                            <description>Compare Window A Internal Reference Voltage Comparison Condition Select</description>
                            <lsb>1</lsb>
                            <msb>1</msb>
                            <access>read-write</access>
                            <enumeratedValues>
                                <enumeratedValue>
                                    <name>0</name>
                                    <description>When window function is disabled (ADCMPCR.WCMPE = 0) : ADCMPDR0 value &gt; A/D-converted value When window function is enabled (ADCMPCR.WCMPE = 1): A/D-converted value &lt; ADCMPDR0 value, or A/D-converted value &gt; ADCMPDR1 value </description>
                                    <value>#0</value>
                                </enumeratedValue>
                                <enumeratedValue>
                                    <name>1</name>
                                    <description>When window function is disabled (ADCMPCR.WCMPE = 0): ADCMPDR0 value &lt; A/D-converted value When window function is enabled (ADCMPCR.WCMPE = 1): ADCMPDR0 value &lt; A/D-converted value &lt; ADCMPDR1 value </description>
                                    <value>#1</value>
                                </enumeratedValue>
                            </enumeratedValues>
                        </field>
                    </fields>
                </register>
                <register>
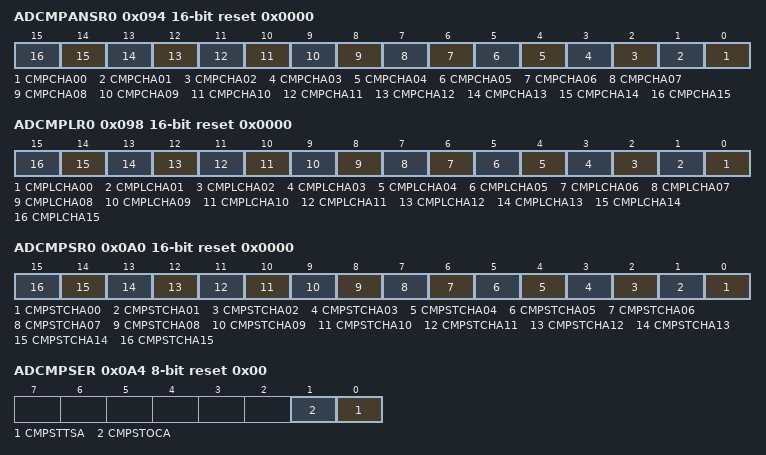
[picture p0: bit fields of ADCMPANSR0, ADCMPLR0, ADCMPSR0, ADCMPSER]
                    <name>ADCMPANSR0</name>
                    <description>A/D Compare Function Window A Channel Select Register 0</description>
                    <addressOffset>0x094</addressOffset>
                    <size>16</size>
                    <access>read-write</access>
                    <resetValue>0x0000</resetValue>
                    <resetMask>0xffff</resetMask>
                    <fields>
                        <field>
                            <name>CMPCHA00</name>
                            <description>Compare Window A Channel Select</description>
                            <lsb>0</lsb>
                            <msb>0</msb>
                            <access>read-write</access>
                            <enumeratedValues>
                                <enumeratedValue>
                                    <name>0</name>
                                    <description>Disable compare function for associated input channel</description>
                                    <value>#0</value>
                                </enumeratedValue>
                                <enumeratedValue>
                                    <name>1</name>
                                    <description>Enable compare function for associated input channel</description>
                                    <value>#1</value>
                                </enumeratedValue>
                            </enumeratedValues>
                        </field>
                        <field>
                            <name>CMPCHA01</name>
                            <description>Compare Window A Channel Select</description>
                            <lsb>1</lsb>
                            <msb>1</msb>
                            <access>read-write</access>
                            <enumeratedValues>
                                <enumeratedValue>
                                    <name>0</name>
                                    <description>Disable compare function for associated input channel</description>
                                    <value>#0</value>
                                </enumeratedValue>
                                <enumeratedValue>
                                    <name>1</name>
                                    <description>Enable compare function for associated input channel</description>
                                    <value>#1</value>
                                </enumeratedValue>
                            </enumeratedValues>
                        </field>
                        <field>
                            <name>CMPCHA02</name>
                            <description>Compare Window A Channel Select</description>
                            <lsb>2</lsb>
                            <msb>2</msb>
                            <access>read-write</access>
                            <enumeratedValues>
                                <enumeratedValue>
                                    <name>0</name>
                                    <description>Disable compare function for associated input channel</description>
                                    <value>#0</value>
                                </enumeratedValue>
                                <enumeratedValue>
                                    <name>1</name>
                                    <description>Enable compare function for associated input channel</description>
                                    <value>#1</value>
                                </enumeratedValue>
                            </enumeratedValues>
                        </field>
                        <field>
                            <name>CMPCHA03</name>
                            <description>Compare Window A Channel Select</description>
                            <lsb>3</lsb>
                            <msb>3</msb>
                            <access>read-write</access>
                            <enumeratedValues>
                                <enumeratedValue>
                                    <name>0</name>
                                    <description>Disable compare function for associated input channel</description>
                                    <value>#0</value>
                                </enumeratedValue>
                                <enumeratedValue>
                                    <name>1</name>
                                    <description>Enable compare function for associated input channel</description>
                                    <value>#1</value>
                                </enumeratedValue>
                            </enumeratedValues>
                        </field>
                        <field>
                            <name>CMPCHA04</name>
                            <description>Compare Window A Channel Select</description>
                            <lsb>4</lsb>
                            <msb>4</msb>
                            <access>read-write</access>
                            <enumeratedValues>
                                <enumeratedValue>
                                    <name>0</name>
                                    <description>Disable compare function for associated input channel</description>
                                    <value>#0</value>
                                </enumeratedValue>
                                <enumeratedValue>
                                    <name>1</name>
                                    <description>Enable compare function for associated input channel</description>
                                    <value>#1</value>
                                </enumeratedValue>
                            </enumeratedValues>
                        </field>
                        <field>
                            <name>CMPCHA05</name>
                            <description>Compare Window A Channel Select</description>
                            <lsb>5</lsb>
                            <msb>5</msb>
                            <access>read-write</access>
                            <enumeratedValues>
                                <enumeratedValue>
                                    <name>0</name>
                                    <description>Disable compare function for associated input channel</description>
                                    <value>#0</value>
                                </enumeratedValue>
                                <enumeratedValue>
                                    <name>1</name>
                                    <description>Enable compare function for associated input channel</description>
                                    <value>#1</value>
                                </enumeratedValue>
                            </enumeratedValues>
                        </field>
                        <field>
                            <name>CMPCHA06</name>
                            <description>Compare Window A Channel Select</description>
                            <lsb>6</lsb>
                            <msb>6</msb>
                            <access>read-write</access>
                            <enumeratedValues>
                                <enumeratedValue>
                                    <name>0</name>
                                    <description>Disable compare function for associated input channel</description>
                                    <value>#0</value>
                                </enumeratedValue>
                                <enumeratedValue>
                                    <name>1</name>
                                    <description>Enable compare function for associated input channel</description>
                                    <value>#1</value>
                                </enumeratedValue>
                            </enumeratedValues>
                        </field>
                        <field>
                            <name>CMPCHA07</name>
                            <description>Compare Window A Channel Select</description>
                            <lsb>7</lsb>
                            <msb>7</msb>
                            <access>read-write</access>
                            <enumeratedValues>
                                <enumeratedValue>
                                    <name>0</name>
                                    <description>Disable compare function for associated input channel</description>
                                    <value>#0</value>
                                </enumeratedValue>
                                <enumeratedValue>
                                    <name>1</name>
                                    <description>Enable compare function for associated input channel</description>
                                    <value>#1</value>
                                </enumeratedValue>
                            </enumeratedValues>
                        </field>
                        <field>
                            <name>CMPCHA08</name>
                            <description>Compare Window A Channel Select</description>
                            <lsb>8</lsb>
                            <msb>8</msb>
                            <access>read-write</access>
                            <enumeratedValues>
                                <enumeratedValue>
                                    <name>0</name>
                                    <description>Disable compare function for associated input channel</description>
                                    <value>#0</value>
                                </enumeratedValue>
                                <enumeratedValue>
                                    <name>1</name>
                                    <description>Enable compare function for associated input channel</description>
                                    <value>#1</value>
                                </enumeratedValue>
                            </enumeratedValues>
                        </field>
                        <field>
                            <name>CMPCHA09</name>
                            <description>Compare Window A Channel Select</description>
                            <lsb>9</lsb>
                            <msb>9</msb>
                            <access>read-write</access>
                            <enumeratedValues>
                                <enumeratedValue>
                                    <name>0</name>
                                    <description>Disable compare function for associated input channel</description>
                                    <value>#0</value>
                                </enumeratedValue>
                                <enumeratedValue>
                                    <name>1</name>
                                    <description>Enable compare function for associated input channel</description>
                                    <value>#1</value>
                                </enumeratedValue>
                            </enumeratedValues>
                        </field>
                        <field>
                            <name>CMPCHA10</name>
                            <description>Compare Window A Channel Select</description>
                            <lsb>10</lsb>
                            <msb>10</msb>
                            <access>read-write</access>
                            <enumeratedValues>
                                <enumeratedValue>
                                    <name>0</name>
                                    <description>Disable compare function for associated input channel</description>
                                    <value>#0</value>
                                </enumeratedValue>
                                <enumeratedValue>
                                    <name>1</name>
                                    <description>Enable compare function for associated input channel</description>
                                    <value>#1</value>
                                </enumeratedValue>
                            </enumeratedValues>
                        </field>
                        <field>
                            <name>CMPCHA11</name>
                            <description>Compare Window A Channel Select</description>
                            <lsb>11</lsb>
                            <msb>11</msb>
                            <access>read-write</access>
                            <enumeratedValues>
                                <enumeratedValue>
                                    <name>0</name>
                                    <description>Disable compare function for associated input channel</description>
                                    <value>#0</value>
                                </enumeratedValue>
                                <enumeratedValue>
                                    <name>1</name>
                                    <description>Enable compare function for associated input channel</description>
                                    <value>#1</value>
                                </enumeratedValue>
                            </enumeratedValues>
                        </field>
                        <field>
                            <name>CMPCHA12</name>
                            <description>Compare Window A Channel Select</description>
                            <lsb>12</lsb>
                            <msb>12</msb>
                            <access>read-write</access>
                            <enumeratedValues>
                                <enumeratedValue>
                                    <name>0</name>
                                    <description>Disable compare function for associated input channel</description>
                                    <value>#0</value>
                                </enumeratedValue>
                                <enumeratedValue>
                                    <name>1</name>
                                    <description>Enable compare function for associated input channel</description>
                                    <value>#1</value>
                                </enumeratedValue>
                            </enumeratedValues>
                        </field>
                        <field>
                            <name>CMPCHA13</name>
                            <description>Compare Window A Channel Select</description>
                            <lsb>13</lsb>
                            <msb>13</msb>
                            <access>read-write</access>
                            <enumeratedValues>
                                <enumeratedValue>
                                    <name>0</name>
                                    <description>Disable compare function for associated input channel</description>
                                    <value>#0</value>
                                </enumeratedValue>
                                <enumeratedValue>
                                    <name>1</name>
                                    <description>Enable compare function for associated input channel</description>
                                    <value>#1</value>
                                </enumeratedValue>
                            </enumeratedValues>
                        </field>
                        <field>
                            <name>CMPCHA14</name>
                            <description>Compare Window A Channel Select</description>
                            <lsb>14</lsb>
                            <msb>14</msb>
                            <access>read-write</access>
                            <enumeratedValues>
                                <enumeratedValue>
                                    <name>0</name>
                                    <description>Disable compare function for associated input channel</description>
                                    <value>#0</value>
                                </enumeratedValue>
                                <enumeratedValue>
                                    <name>1</name>
                                    <description>Enable compare function for associated input channel</description>
                                    <value>#1</value>
                                </enumeratedValue>
                            </enumeratedValues>
                        </field>
                        <field>
                            <name>CMPCHA15</name>
                            <description>Compare Window A Channel Select</description>
                            <lsb>15</lsb>
                            <msb>15</msb>
                            <access>read-write</access>
                            <enumeratedValues>
                                <enumeratedValue>
                                    <name>0</name>
                                    <description>Disable compare function for associated input channel</description>
                                    <value>#0</value>
                                </enumeratedValue>
                                <enumeratedValue>
                                    <name>1</name>
                                    <description>Enable compare function for associated input channel</description>
                                    <value>#1</value>
                                </enumeratedValue>
                            </enumeratedValues>
                        </field>
                    </fields>
                </register>
                <register>
                    <name>ADCMPLR0</name>
                    <description>A/D Compare Function Window A Comparison Condition Setting Register 0</description>
                    <addressOffset>0x098</addressOffset>
                    <size>16</size>
                    <access>read-write</access>
                    <resetValue>0x0000</resetValue>
                    <resetMask>0xffff</resetMask>
                    <fields>
                        <field>
                            <name>CMPLCHA00</name>
                            <description>Compare Window A Comparison Condition Select</description>
                            <lsb>0</lsb>
                            <msb>0</msb>
                            <access>read-write</access>
                            <enumeratedValues>
                                <enumeratedValue>
                                    <name>0</name>
                                    <description>When window function is disabled (ADCMPCR.WCMPE = 0): ADCMPDR0 value &gt; A/D-converted value When window function is enabled (ADCMPCR.WCMPE = 1): A/D-converted value &lt; ADCMPDR0 value, or ADCMPDR1 value &lt; A/D-converted value </description>
                                    <value>#0</value>
                                </enumeratedValue>
                                <enumeratedValue>
                                    <name>1</name>
                                    <description>When window function is disabled (ADCMPCR.WCMPE = 0): ADCMPDR0 value &lt; A/D-converted value When window function is enabled (ADCMPCR.WCMPE = 1): ADCMPDR0 value &lt; A/D-converted value &lt; ADCMPDR1 value </description>
                                    <value>#1</value>
                                </enumeratedValue>
                            </enumeratedValues>
                        </field>
                        <field>
                            <name>CMPLCHA01</name>
                            <description>Compare Window A Comparison Condition Select</description>
                            <lsb>1</lsb>
                            <msb>1</msb>
                            <access>read-write</access>
                            <enumeratedValues>
                                <enumeratedValue>
                                    <name>0</name>
                                    <description>When window function is disabled (ADCMPCR.WCMPE = 0): ADCMPDR0 value &gt; A/D-converted value When window function is enabled (ADCMPCR.WCMPE = 1): A/D-converted value &lt; ADCMPDR0 value, or ADCMPDR1 value &lt; A/D-converted value </description>
                                    <value>#0</value>
                                </enumeratedValue>
                                <enumeratedValue>
                                    <name>1</name>
                                    <description>When window function is disabled (ADCMPCR.WCMPE = 0): ADCMPDR0 value &lt; A/D-converted value When window function is enabled (ADCMPCR.WCMPE = 1): ADCMPDR0 value &lt; A/D-converted value &lt; ADCMPDR1 value </description>
                                    <value>#1</value>
                                </enumeratedValue>
                            </enumeratedValues>
                        </field>
                        <field>
                            <name>CMPLCHA02</name>
                            <description>Compare Window A Comparison Condition Select</description>
                            <lsb>2</lsb>
                            <msb>2</msb>
                            <access>read-write</access>
                            <enumeratedValues>
                                <enumeratedValue>
                                    <name>0</name>
                                    <description>When window function is disabled (ADCMPCR.WCMPE = 0): ADCMPDR0 value &gt; A/D-converted value When window function is enabled (ADCMPCR.WCMPE = 1): A/D-converted value &lt; ADCMPDR0 value, or ADCMPDR1 value &lt; A/D-converted value </description>
                                    <value>#0</value>
                                </enumeratedValue>
                                <enumeratedValue>
                                    <name>1</name>
                                    <description>When window function is disabled (ADCMPCR.WCMPE = 0): ADCMPDR0 value &lt; A/D-converted value When window function is enabled (ADCMPCR.WCMPE = 1): ADCMPDR0 value &lt; A/D-converted value &lt; ADCMPDR1 value </description>
                                    <value>#1</value>
                                </enumeratedValue>
                            </enumeratedValues>
                        </field>
                        <field>
                            <name>CMPLCHA03</name>
                            <description>Compare Window A Comparison Condition Select</description>
                            <lsb>3</lsb>
                            <msb>3</msb>
                            <access>read-write</access>
                            <enumeratedValues>
                                <enumeratedValue>
                                    <name>0</name>
                                    <description>When window function is disabled (ADCMPCR.WCMPE = 0): ADCMPDR0 value &gt; A/D-converted value When window function is enabled (ADCMPCR.WCMPE = 1): A/D-converted value &lt; ADCMPDR0 value, or ADCMPDR1 value &lt; A/D-converted value </description>
                                    <value>#0</value>
                                </enumeratedValue>
                                <enumeratedValue>
                                    <name>1</name>
                                    <description>When window function is disabled (ADCMPCR.WCMPE = 0): ADCMPDR0 value &lt; A/D-converted value When window function is enabled (ADCMPCR.WCMPE = 1): ADCMPDR0 value &lt; A/D-converted value &lt; ADCMPDR1 value </description>
                                    <value>#1</value>
                                </enumeratedValue>
                            </enumeratedValues>
                        </field>
                        <field>
                            <name>CMPLCHA04</name>
                            <description>Compare Window A Comparison Condition Select</description>
                            <lsb>4</lsb>
                            <msb>4</msb>
                            <access>read-write</access>
                            <enumeratedValues>
                                <enumeratedValue>
                                    <name>0</name>
                                    <description>When window function is disabled (ADCMPCR.WCMPE = 0): ADCMPDR0 value &gt; A/D-converted value When window function is enabled (ADCMPCR.WCMPE = 1): A/D-converted value &lt; ADCMPDR0 value, or ADCMPDR1 value &lt; A/D-converted value </description>
                                    <value>#0</value>
                                </enumeratedValue>
                                <enumeratedValue>
                                    <name>1</name>
                                    <description>When window function is disabled (ADCMPCR.WCMPE = 0): ADCMPDR0 value &lt; A/D-converted value When window function is enabled (ADCMPCR.WCMPE = 1): ADCMPDR0 value &lt; A/D-converted value &lt; ADCMPDR1 value </description>
                                    <value>#1</value>
                                </enumeratedValue>
                            </enumeratedValues>
                        </field>
                        <field>
                            <name>CMPLCHA05</name>
                            <description>Compare Window A Comparison Condition Select</description>
                            <lsb>5</lsb>
                            <msb>5</msb>
                            <access>read-write</access>
                            <enumeratedValues>
                                <enumeratedValue>
                                    <name>0</name>
                                    <description>When window function is disabled (ADCMPCR.WCMPE = 0): ADCMPDR0 value &gt; A/D-converted value When window function is enabled (ADCMPCR.WCMPE = 1): A/D-converted value &lt; ADCMPDR0 value, or ADCMPDR1 value &lt; A/D-converted value </description>
                                    <value>#0</value>
                                </enumeratedValue>
                                <enumeratedValue>
                                    <name>1</name>
                                    <description>When window function is disabled (ADCMPCR.WCMPE = 0): ADCMPDR0 value &lt; A/D-converted value When window function is enabled (ADCMPCR.WCMPE = 1): ADCMPDR0 value &lt; A/D-converted value &lt; ADCMPDR1 value </description>
                                    <value>#1</value>
                                </enumeratedValue>
                            </enumeratedValues>
                        </field>
                        <field>
                            <name>CMPLCHA06</name>
                            <description>Compare Window A Comparison Condition Select</description>
                            <lsb>6</lsb>
                            <msb>6</msb>
                            <access>read-write</access>
                            <enumeratedValues>
                                <enumeratedValue>
                                    <name>0</name>
                                    <description>When window function is disabled (ADCMPCR.WCMPE = 0): ADCMPDR0 value &gt; A/D-converted value When window function is enabled (ADCMPCR.WCMPE = 1): A/D-converted value &lt; ADCMPDR0 value, or ADCMPDR1 value &lt; A/D-converted value </description>
                                    <value>#0</value>
                                </enumeratedValue>
                                <enumeratedValue>
                                    <name>1</name>
                                    <description>When window function is disabled (ADCMPCR.WCMPE = 0): ADCMPDR0 value &lt; A/D-converted value When window function is enabled (ADCMPCR.WCMPE = 1): ADCMPDR0 value &lt; A/D-converted value &lt; ADCMPDR1 value </description>
                                    <value>#1</value>
                                </enumeratedValue>
                            </enumeratedValues>
                        </field>
                        <field>
                            <name>CMPLCHA07</name>
                            <description>Compare Window A Comparison Condition Select</description>
                            <lsb>7</lsb>
                            <msb>7</msb>
                            <access>read-write</access>
                            <enumeratedValues>
                                <enumeratedValue>
                                    <name>0</name>
                                    <description>When window function is disabled (ADCMPCR.WCMPE = 0): ADCMPDR0 value &gt; A/D-converted value When window function is enabled (ADCMPCR.WCMPE = 1): A/D-converted value &lt; ADCMPDR0 value, or ADCMPDR1 value &lt; A/D-converted value </description>
                                    <value>#0</value>
                                </enumeratedValue>
                                <enumeratedValue>
                                    <name>1</name>
                                    <description>When window function is disabled (ADCMPCR.WCMPE = 0): ADCMPDR0 value &lt; A/D-converted value When window function is enabled (ADCMPCR.WCMPE = 1): ADCMPDR0 value &lt; A/D-converted value &lt; ADCMPDR1 value </description>
                                    <value>#1</value>
                                </enumeratedValue>
                            </enumeratedValues>
                        </field>
                        <field>
                            <name>CMPLCHA08</name>
                            <description>Compare Window A Comparison Condition Select</description>
                            <lsb>8</lsb>
                            <msb>8</msb>
                            <access>read-write</access>
                            <enumeratedValues>
                                <enumeratedValue>
                                    <name>0</name>
                                    <description>When window function is disabled (ADCMPCR.WCMPE = 0): ADCMPDR0 value &gt; A/D-converted value When window function is enabled (ADCMPCR.WCMPE = 1): A/D-converted value &lt; ADCMPDR0 value, or ADCMPDR1 value &lt; A/D-converted value </description>
                                    <value>#0</value>
                                </enumeratedValue>
                                <enumeratedValue>
                                    <name>1</name>
                                    <description>When window function is disabled (ADCMPCR.WCMPE = 0): ADCMPDR0 value &lt; A/D-converted value When window function is enabled (ADCMPCR.WCMPE = 1): ADCMPDR0 value &lt; A/D-converted value &lt; ADCMPDR1 value </description>
                                    <value>#1</value>
                                </enumeratedValue>
                            </enumeratedValues>
                        </field>
                        <field>
                            <name>CMPLCHA09</name>
                            <description>Compare Window A Comparison Condition Select</description>
                            <lsb>9</lsb>
                            <msb>9</msb>
                            <access>read-write</access>
                            <enumeratedValues>
                                <enumeratedValue>
                                    <name>0</name>
                                    <description>When window function is disabled (ADCMPCR.WCMPE = 0): ADCMPDR0 value &gt; A/D-converted value When window function is enabled (ADCMPCR.WCMPE = 1): A/D-converted value &lt; ADCMPDR0 value, or ADCMPDR1 value &lt; A/D-converted value </description>
                                    <value>#0</value>
                                </enumeratedValue>
                                <enumeratedValue>
                                    <name>1</name>
                                    <description>When window function is disabled (ADCMPCR.WCMPE = 0): ADCMPDR0 value &lt; A/D-converted value When window function is enabled (ADCMPCR.WCMPE = 1): ADCMPDR0 value &lt; A/D-converted value &lt; ADCMPDR1 value </description>
                                    <value>#1</value>
                                </enumeratedValue>
                            </enumeratedValues>
                        </field>
                        <field>
                            <name>CMPLCHA10</name>
                            <description>Compare Window A Comparison Condition Select</description>
                            <lsb>10</lsb>
                            <msb>10</msb>
                            <access>read-write</access>
                            <enumeratedValues>
                                <enumeratedValue>
                                    <name>0</name>
                                    <description>When window function is disabled (ADCMPCR.WCMPE = 0): ADCMPDR0 value &gt; A/D-converted value When window function is enabled (ADCMPCR.WCMPE = 1): A/D-converted value &lt; ADCMPDR0 value, or ADCMPDR1 value &lt; A/D-converted value </description>
                                    <value>#0</value>
                                </enumeratedValue>
                                <enumeratedValue>
                                    <name>1</name>
                                    <description>When window function is disabled (ADCMPCR.WCMPE = 0): ADCMPDR0 value &lt; A/D-converted value When window function is enabled (ADCMPCR.WCMPE = 1): ADCMPDR0 value &lt; A/D-converted value &lt; ADCMPDR1 value </description>
                                    <value>#1</value>
                                </enumeratedValue>
                            </enumeratedValues>
                        </field>
                        <field>
                            <name>CMPLCHA11</name>
                            <description>Compare Window A Comparison Condition Select</description>
                            <lsb>11</lsb>
                            <msb>11</msb>
                            <access>read-write</access>
                            <enumeratedValues>
                                <enumeratedValue>
                                    <name>0</name>
                                    <description>When window function is disabled (ADCMPCR.WCMPE = 0): ADCMPDR0 value &gt; A/D-converted value When window function is enabled (ADCMPCR.WCMPE = 1): A/D-converted value &lt; ADCMPDR0 value, or ADCMPDR1 value &lt; A/D-converted value </description>
                                    <value>#0</value>
                                </enumeratedValue>
                                <enumeratedValue>
                                    <name>1</name>
                                    <description>When window function is disabled (ADCMPCR.WCMPE = 0): ADCMPDR0 value &lt; A/D-converted value When window function is enabled (ADCMPCR.WCMPE = 1): ADCMPDR0 value &lt; A/D-converted value &lt; ADCMPDR1 value </description>
                                    <value>#1</value>
                                </enumeratedValue>
                            </enumeratedValues>
                        </field>
                        <field>
                            <name>CMPLCHA12</name>
                            <description>Compare Window A Comparison Condition Select</description>
                            <lsb>12</lsb>
                            <msb>12</msb>
                            <access>read-write</access>
                            <enumeratedValues>
                                <enumeratedValue>
                                    <name>0</name>
                                    <description>When window function is disabled (ADCMPCR.WCMPE = 0): ADCMPDR0 value &gt; A/D-converted value When window function is enabled (ADCMPCR.WCMPE = 1): A/D-converted value &lt; ADCMPDR0 value, or ADCMPDR1 value &lt; A/D-converted value </description>
                                    <value>#0</value>
                                </enumeratedValue>
                                <enumeratedValue>
                                    <name>1</name>
                                    <description>When window function is disabled (ADCMPCR.WCMPE = 0): ADCMPDR0 value &lt; A/D-converted value When window function is enabled (ADCMPCR.WCMPE = 1): ADCMPDR0 value &lt; A/D-converted value &lt; ADCMPDR1 value </description>
                                    <value>#1</value>
                                </enumeratedValue>
                            </enumeratedValues>
                        </field>
                        <field>
                            <name>CMPLCHA13</name>
                            <description>Compare Window A Comparison Condition Select</description>
                            <lsb>13</lsb>
                            <msb>13</msb>
                            <access>read-write</access>
                            <enumeratedValues>
                                <enumeratedValue>
                                    <name>0</name>
                                    <description>When window function is disabled (ADCMPCR.WCMPE = 0): ADCMPDR0 value &gt; A/D-converted value When window function is enabled (ADCMPCR.WCMPE = 1): A/D-converted value &lt; ADCMPDR0 value, or ADCMPDR1 value &lt; A/D-converted value </description>
                                    <value>#0</value>
                                </enumeratedValue>
                                <enumeratedValue>
                                    <name>1</name>
                                    <description>When window function is disabled (ADCMPCR.WCMPE = 0): ADCMPDR0 value &lt; A/D-converted value When window function is enabled (ADCMPCR.WCMPE = 1): ADCMPDR0 value &lt; A/D-converted value &lt; ADCMPDR1 value </description>
                                    <value>#1</value>
                                </enumeratedValue>
                            </enumeratedValues>
                        </field>
                        <field>
                            <name>CMPLCHA14</name>
                            <description>Compare Window A Comparison Condition Select</description>
                            <lsb>14</lsb>
                            <msb>14</msb>
                            <access>read-write</access>
                            <enumeratedValues>
                                <enumeratedValue>
                                    <name>0</name>
                                    <description>When window function is disabled (ADCMPCR.WCMPE = 0): ADCMPDR0 value &gt; A/D-converted value When window function is enabled (ADCMPCR.WCMPE = 1): A/D-converted value &lt; ADCMPDR0 value, or ADCMPDR1 value &lt; A/D-converted value </description>
                                    <value>#0</value>
                                </enumeratedValue>
                                <enumeratedValue>
                                    <name>1</name>
                                    <description>When window function is disabled (ADCMPCR.WCMPE = 0): ADCMPDR0 value &lt; A/D-converted value When window function is enabled (ADCMPCR.WCMPE = 1): ADCMPDR0 value &lt; A/D-converted value &lt; ADCMPDR1 value </description>
                                    <value>#1</value>
                                </enumeratedValue>
                            </enumeratedValues>
                        </field>
                        <field>
                            <name>CMPLCHA15</name>
                            <description>Compare Window A Comparison Condition Select</description>
                            <lsb>15</lsb>
                            <msb>15</msb>
                            <access>read-write</access>
                            <enumeratedValues>
                                <enumeratedValue>
                                    <name>0</name>
                                    <description>When window function is disabled (ADCMPCR.WCMPE = 0): ADCMPDR0 value &gt; A/D-converted value When window function is enabled (ADCMPCR.WCMPE = 1): A/D-converted value &lt; ADCMPDR0 value, or ADCMPDR1 value &lt; A/D-converted value </description>
                                    <value>#0</value>
                                </enumeratedValue>
                                <enumeratedValue>
                                    <name>1</name>
                                    <description>When window function is disabled (ADCMPCR.WCMPE = 0): ADCMPDR0 value &lt; A/D-converted value When window function is enabled (ADCMPCR.WCMPE = 1): ADCMPDR0 value &lt; A/D-converted value &lt; ADCMPDR1 value </description>
                                    <value>#1</value>
                                </enumeratedValue>
                            </enumeratedValues>
                        </field>
                    </fields>
                </register>
                <register>
                    <dim>2</dim>
                    <dimIncrement>0x2</dimIncrement>
                    <dimIndex>0-1</dimIndex>
                    <name>ADCMPDR%s</name>
                    <description>A/D Compare Function Window A Lower-Side/Upper-Side Level Setting Register</description>
                    <addressOffset>0x09C</addressOffset>
                    <size>16</size>
                    <access>read-write</access>
                    <resetValue>0x0000</resetValue>
                    <resetMask>0xffff</resetMask>
                </register>
                <register>
                    <name>ADCMPSR0</name>
                    <description>A/D Compare Function Window A Channel Status Register 0</description>
                    <addressOffset>0x0A0</addressOffset>
                    <size>16</size>
                    <access>read-write</access>
                    <resetValue>0x0000</resetValue>
                    <resetMask>0xffff</resetMask>
                    <fields>
                        <field>
                            <name>CMPSTCHA00</name>
                            <description>Compare Window A Flag</description>
                            <lsb>0</lsb>
                            <msb>0</msb>
                            <access>read-write</access>
                            <enumeratedValues>
                                <enumeratedValue>
                                    <name>0</name>
                                    <description>Comparison conditions are not met.</description>
                                    <value>#0</value>
                                </enumeratedValue>
                                <enumeratedValue>
                                    <name>1</name>
                                    <description>Comparison conditions are met.</description>
                                    <value>#1</value>
                                </enumeratedValue>
                            </enumeratedValues>
                        </field>
                        <field>
                            <name>CMPSTCHA01</name>
                            <description>Compare Window A Flag</description>
                            <lsb>1</lsb>
                            <msb>1</msb>
                            <access>read-write</access>
                            <enumeratedValues>
                                <enumeratedValue>
                                    <name>0</name>
                                    <description>Comparison conditions are not met.</description>
                                    <value>#0</value>
                                </enumeratedValue>
                                <enumeratedValue>
                                    <name>1</name>
                                    <description>Comparison conditions are met.</description>
                                    <value>#1</value>
                                </enumeratedValue>
                            </enumeratedValues>
                        </field>
                        <field>
                            <name>CMPSTCHA02</name>
                            <description>Compare Window A Flag</description>
                            <lsb>2</lsb>
                            <msb>2</msb>
                            <access>read-write</access>
                            <enumeratedValues>
                                <enumeratedValue>
                                    <name>0</name>
                                    <description>Comparison conditions are not met.</description>
                                    <value>#0</value>
                                </enumeratedValue>
                                <enumeratedValue>
                                    <name>1</name>
                                    <description>Comparison conditions are met.</description>
                                    <value>#1</value>
                                </enumeratedValue>
                            </enumeratedValues>
                        </field>
                        <field>
                            <name>CMPSTCHA03</name>
                            <description>Compare Window A Flag</description>
                            <lsb>3</lsb>
                            <msb>3</msb>
                            <access>read-write</access>
                            <enumeratedValues>
                                <enumeratedValue>
                                    <name>0</name>
                                    <description>Comparison conditions are not met.</description>
                                    <value>#0</value>
                                </enumeratedValue>
                                <enumeratedValue>
                                    <name>1</name>
                                    <description>Comparison conditions are met.</description>
                                    <value>#1</value>
                                </enumeratedValue>
                            </enumeratedValues>
                        </field>
                        <field>
                            <name>CMPSTCHA04</name>
                            <description>Compare Window A Flag</description>
                            <lsb>4</lsb>
                            <msb>4</msb>
                            <access>read-write</access>
                            <enumeratedValues>
                                <enumeratedValue>
                                    <name>0</name>
                                    <description>Comparison conditions are not met.</description>
                                    <value>#0</value>
                                </enumeratedValue>
                                <enumeratedValue>
                                    <name>1</name>
                                    <description>Comparison conditions are met.</description>
                                    <value>#1</value>
                                </enumeratedValue>
                            </enumeratedValues>
                        </field>
                        <field>
                            <name>CMPSTCHA05</name>
                            <description>Compare Window A Flag</description>
                            <lsb>5</lsb>
                            <msb>5</msb>
                            <access>read-write</access>
                            <enumeratedValues>
                                <enumeratedValue>
                                    <name>0</name>
                                    <description>Comparison conditions are not met.</description>
                                    <value>#0</value>
                                </enumeratedValue>
                                <enumeratedValue>
                                    <name>1</name>
                                    <description>Comparison conditions are met.</description>
                                    <value>#1</value>
                                </enumeratedValue>
                            </enumeratedValues>
                        </field>
                        <field>
                            <name>CMPSTCHA06</name>
                            <description>Compare Window A Flag</description>
                            <lsb>6</lsb>
                            <msb>6</msb>
                            <access>read-write</access>
                            <enumeratedValues>
                                <enumeratedValue>
                                    <name>0</name>
                                    <description>Comparison conditions are not met.</description>
                                    <value>#0</value>
                                </enumeratedValue>
                                <enumeratedValue>
                                    <name>1</name>
                                    <description>Comparison conditions are met.</description>
                                    <value>#1</value>
                                </enumeratedValue>
                            </enumeratedValues>
                        </field>
                        <field>
                            <name>CMPSTCHA07</name>
                            <description>Compare Window A Flag</description>
                            <lsb>7</lsb>
                            <msb>7</msb>
                            <access>read-write</access>
                            <enumeratedValues>
                                <enumeratedValue>
                                    <name>0</name>
                                    <description>Comparison conditions are not met.</description>
                                    <value>#0</value>
                                </enumeratedValue>
                                <enumeratedValue>
                                    <name>1</name>
                                    <description>Comparison conditions are met.</description>
                                    <value>#1</value>
                                </enumeratedValue>
                            </enumeratedValues>
                        </field>
                        <field>
                            <name>CMPSTCHA08</name>
                            <description>Compare Window A Flag</description>
                            <lsb>8</lsb>
                            <msb>8</msb>
                            <access>read-write</access>
                            <enumeratedValues>
                                <enumeratedValue>
                                    <name>0</name>
                                    <description>Comparison conditions are not met.</description>
                                    <value>#0</value>
                                </enumeratedValue>
                                <enumeratedValue>
                                    <name>1</name>
                                    <description>Comparison conditions are met.</description>
                                    <value>#1</value>
                                </enumeratedValue>
                            </enumeratedValues>
                        </field>
                        <field>
                            <name>CMPSTCHA09</name>
                            <description>Compare Window A Flag</description>
                            <lsb>9</lsb>
                            <msb>9</msb>
                            <access>read-write</access>
                            <enumeratedValues>
                                <enumeratedValue>
                                    <name>0</name>
                                    <description>Comparison conditions are not met.</description>
                                    <value>#0</value>
                                </enumeratedValue>
                                <enumeratedValue>
                                    <name>1</name>
                                    <description>Comparison conditions are met.</description>
                                    <value>#1</value>
                                </enumeratedValue>
                            </enumeratedValues>
                        </field>
                        <field>
                            <name>CMPSTCHA10</name>
                            <description>Compare Window A Flag</description>
                            <lsb>10</lsb>
                            <msb>10</msb>
                            <access>read-write</access>
                            <enumeratedValues>
                                <enumeratedValue>
                                    <name>0</name>
                                    <description>Comparison conditions are not met.</description>
                                    <value>#0</value>
                                </enumeratedValue>
                                <enumeratedValue>
                                    <name>1</name>
                                    <description>Comparison conditions are met.</description>
                                    <value>#1</value>
                                </enumeratedValue>
                            </enumeratedValues>
                        </field>
                        <field>
                            <name>CMPSTCHA11</name>
                            <description>Compare Window A Flag</description>
                            <lsb>11</lsb>
                            <msb>11</msb>
                            <access>read-write</access>
                            <enumeratedValues>
                                <enumeratedValue>
                                    <name>0</name>
                                    <description>Comparison conditions are not met.</description>
                                    <value>#0</value>
                                </enumeratedValue>
                                <enumeratedValue>
                                    <name>1</name>
                                    <description>Comparison conditions are met.</description>
                                    <value>#1</value>
                                </enumeratedValue>
                            </enumeratedValues>
                        </field>
                        <field>
                            <name>CMPSTCHA12</name>
                            <description>Compare Window A Flag</description>
                            <lsb>12</lsb>
                            <msb>12</msb>
                            <access>read-write</access>
                            <enumeratedValues>
                                <enumeratedValue>
                                    <name>0</name>
                                    <description>Comparison conditions are not met.</description>
                                    <value>#0</value>
                                </enumeratedValue>
                                <enumeratedValue>
                                    <name>1</name>
                                    <description>Comparison conditions are met.</description>
                                    <value>#1</value>
                                </enumeratedValue>
                            </enumeratedValues>
                        </field>
                        <field>
                            <name>CMPSTCHA13</name>
                            <description>Compare Window A Flag</description>
                            <lsb>13</lsb>
                            <msb>13</msb>
                            <access>read-write</access>
                            <enumeratedValues>
                                <enumeratedValue>
                                    <name>0</name>
                                    <description>Comparison conditions are not met.</description>
                                    <value>#0</value>
                                </enumeratedValue>
                                <enumeratedValue>
                                    <name>1</name>
                                    <description>Comparison conditions are met.</description>
                                    <value>#1</value>
                                </enumeratedValue>
                            </enumeratedValues>
                        </field>
                        <field>
                            <name>CMPSTCHA14</name>
                            <description>Compare Window A Flag</description>
                            <lsb>14</lsb>
                            <msb>14</msb>
                            <access>read-write</access>
                            <enumeratedValues>
                                <enumeratedValue>
                                    <name>0</name>
                                    <description>Comparison conditions are not met.</description>
                                    <value>#0</value>
                                </enumeratedValue>
                                <enumeratedValue>
                                    <name>1</name>
                                    <description>Comparison conditions are met.</description>
                                    <value>#1</value>
                                </enumeratedValue>
                            </enumeratedValues>
                        </field>
                        <field>
                            <name>CMPSTCHA15</name>
                            <description>Compare Window A Flag</description>
                            <lsb>15</lsb>
                            <msb>15</msb>
                            <access>read-write</access>
                            <enumeratedValues>
                                <enumeratedValue>
                                    <name>0</name>
                                    <description>Comparison conditions are not met.</description>
                                    <value>#0</value>
                                </enumeratedValue>
                                <enumeratedValue>
                                    <name>1</name>
                                    <description>Comparison conditions are met.</description>
                                    <value>#1</value>
                                </enumeratedValue>
                            </enumeratedValues>
                        </field>
                    </fields>
                </register>
                <register>
                    <name>ADCMPSER</name>
                    <description>A/D Compare Function Window A Extended Input Channel Status Register</description>
                    <addressOffset>0x0A4</addressOffset>
                    <size>8</size>
                    <access>read-write</access>
                    <resetValue>0x00</resetValue>
                    <resetMask>0xff</resetMask>
                    <fields>
                        <field>
                            <name>CMPSTTSA</name>
                            <description>Compare Window A Temperature Sensor Output Compare Flag</description>
                            <lsb>0</lsb>
                            <msb>0</msb>
                            <access>read-write</access>
                            <enumeratedValues>
                                <enumeratedValue>
                                    <name>0</name>
                                    <description>Comparison conditions are not met.</description>
                                    <value>#0</value>
                                </enumeratedValue>
                                <enumeratedValue>
                                    <name>1</name>
                                    <description>Comparison conditions are met.</description>
                                    <value>#1</value>
                                </enumeratedValue>
                            </enumeratedValues>
                        </field>
                        <field>
                            <name>CMPSTOCA</name>
                            <description>Compare Window A Internal Reference Voltage Compare Flag</description>
                            <lsb>1</lsb>
                            <msb>1</msb>
                            <access>read-write</access>
                            <enumeratedValues>
                                <enumeratedValue>
                                    <name>0</name>
                                    <description>Comparison conditions are not met.</description>
                                    <value>#0</value>
                                </enumeratedValue>
                                <enumeratedValue>
                                    <name>1</name>
                                    <description>Comparison conditions are met.</description>
                                    <value>#1</value>
                                </enumeratedValue>
                            </enumeratedValues>
                        </field>
                    </fields>
                </register>
                <register>
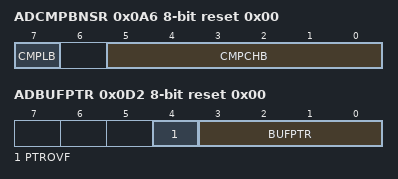
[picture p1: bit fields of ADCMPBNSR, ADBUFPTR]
                    <name>ADCMPBNSR</name>
                    <description>A/D Compare Function Window B Channel Select Register</description>
                    <addressOffset>0x0A6</addressOffset>
                    <size>8</size>
                    <access>read-write</access>
                    <resetValue>0x00</resetValue>
                    <resetMask>0xff</resetMask>
                    <fields>
                        <field>
                            <name>CMPCHB</name>
                            <description>Compare Window B Channel Select</description>
                            <lsb>0</lsb>
                            <msb>5</msb>
                            <access>read-write</access>
                        </field>
                        <field>
                            <name>CMPLB</name>
                            <description>Compare Window B Comparison Condition Setting</description>
                            <lsb>7</lsb>
                            <msb>7</msb>
                            <access>read-write</access>
                            <enumeratedValues>
                                <enumeratedValue>
                                    <name>0</name>
                                    <description>When window function is disabled (ADCMPCR.WCMPE = 0): ADWINLLB value &gt; A/D-converted value When window function is enabled (ADCMPCR.WCMPE = 1): A/D-converted value &lt; ADWINLLB value, or ADWINULB value &lt; A/D-converted value </description>
                                    <value>#0</value>
                                </enumeratedValue>
                                <enumeratedValue>
                                    <name>1</name>
                                    <description>When window function is disabled (ADCMPCR.WCMPE = 0): ADWINLLB value &lt; A/D-converted value When window function is enabled (ADCMPCR.WCMPE = 1): ADWINLLB value &lt; A/D-converted value &lt; ADWINULB value </description>
                                    <value>#1</value>
                                </enumeratedValue>
                            </enumeratedValues>
                        </field>
                    </fields>
                </register>
                <register>
                    <name>ADWINLLB</name>
                    <description>A/D Compare Function Window B Lower-Side/Upper-Side Level Setting Register</description>
                    <addressOffset>0x0A8</addressOffset>
                    <size>16</size>
                    <access>read-write</access>
                    <resetValue>0x0000</resetValue>
                    <resetMask>0xffff</resetMask>
                </register>
                <register>
                    <name>ADWINULB</name>
                    <description>A/D Compare Function Window B Lower-Side/Upper-Side Level Setting Register</description>
                    <addressOffset>0x0AA</addressOffset>
                    <size>16</size>
                    <access>read-write</access>
                    <resetValue>0x0000</resetValue>
                    <resetMask>0xffff</resetMask>
                </register>
                <register>
                    <name>ADCMPBSR</name>
                    <description>A/D Compare Function Window B Status Register</description>
                    <addressOffset>0x0AC</addressOffset>
                    <size>8</size>
                    <access>read-write</access>
                    <resetValue>0x00</resetValue>
                    <resetMask>0xff</resetMask>
                    <fields>
                        <field>
                            <name>CMPSTB</name>
                            <description>Compare Window B Flag</description>
                            <lsb>0</lsb>
                            <msb>0</msb>
                            <access>read-write</access>
                            <enumeratedValues>
                                <enumeratedValue>
                                    <name>0</name>
                                    <description>Comparison conditions are not met.</description>
                                    <value>#0</value>
                                </enumeratedValue>
                                <enumeratedValue>
                                    <name>1</name>
                                    <description>Comparison conditions are met.</description>
                                    <value>#1</value>
                                </enumeratedValue>
                            </enumeratedValues>
                        </field>
                    </fields>
                </register>
                <register>
                    <dim>16</dim>
                    <dimIncrement>0x2</dimIncrement>
                    <dimIndex>0-15</dimIndex>
                    <name>ADBUF%s</name>
                    <description>A/D Data Buffer Registers %s</description>
                    <addressOffset>0x0B0</addressOffset>
                    <size>16</size>
                    <access>read-only</access>
                    <resetValue>0x0000</resetValue>
                    <resetMask>0xffff</resetMask>
                    <fields>
                        <field>
                            <name>ADBUF</name>
                            <description>Converted Value 15 to 0</description>
                            <lsb>0</lsb>
                            <msb>15</msb>
                            <access>read-only</access>
                        </field>
                    </fields>
                </register>
                <register>
                    <name>ADBUFEN</name>
                    <description>A/D Data Buffer Enable Register</description>
                    <addressOffset>0x0D0</addressOffset>
                    <size>8</size>
                    <access>read-write</access>
                    <resetValue>0x00</resetValue>
                    <resetMask>0xff</resetMask>
                    <fields>
                        <field>
                            <name>BUFEN</name>
                            <description>Data Buffer Enable</description>
                            <lsb>0</lsb>
                            <msb>0</msb>
                            <access>read-write</access>
                            <enumeratedValues>
                                <enumeratedValue>
                                    <name>0</name>
                                    <description>The data buffer is not used.</description>
                                    <value>#0</value>
                                </enumeratedValue>
                                <enumeratedValue>
                                    <name>1</name>
                                    <description>The data buffer is used.</description>
                                    <value>#1</value>
                                </enumeratedValue>
                            </enumeratedValues>
                        </field>
                    </fields>
                </register>
                <register>
                    <name>ADBUFPTR</name>
                    <description>A/D Data Buffer Pointer Register</description>
                    <addressOffset>0x0D2</addressOffset>
                    <size>8</size>
                    <access>read-write</access>
                    <resetValue>0x00</resetValue>
                    <resetMask>0xff</resetMask>
                    <fields>
                        <field>
                            <name>BUFPTR</name>
                            <description>Data Buffer Pointer</description>
                            <lsb>0</lsb>
                            <msb>3</msb>
                            <access>read-write</access>
                        </field>
                        <field>
                            <name>PTROVF</name>
                            <description>Pointer Overflow Flag</description>
                            <lsb>4</lsb>
                            <msb>4</msb>
                            <access>read-write</access>
                            <enumeratedValues>
                                <enumeratedValue>
                                    <name>0</name>
                                    <description>The data buffer pointer has not overflowed.</description>
                                    <value>#0</value>
                                </enumeratedValue>
                                <enumeratedValue>
                                    <name>1</name>
                                    <description>The data buffer pointer has overflowed.</description>
                                    <value>#1</value>
                                </enumeratedValue>
                            </enumeratedValues>
                        </field>
                    </fields>
                </register>
                <register>
                    <name>ADSSTRL</name>
                    <description>A/D Sampling State Register</description>
                    <addressOffset>0x0DD</addressOffset>
                    <size>8</size>
                    <access>read-write</access>
                    <resetValue>0x0b</resetValue>
                    <resetMask>0xff</resetMask>
                    <fields>
                        <field>
                            <name>SST</name>
                            <description>Sampling Time Setting</description>
                            <lsb>0</lsb>
                            <msb>7</msb>
                            <access>read-write</access>
                        </field>
                    </fields>
                </register>
                <register>
                    <name>ADSSTRT</name>
                    <description>A/D Sampling State Register</description>
                    <addressOffset>0x0DE</addressOffset>
                    <size>8</size>
                    <access>read-write</access>
                    <resetValue>0x0b</resetValue>
                    <resetMask>0xff</resetMask>
                    <fields>
                        <field>
                            <name>SST</name>
                            <description>Sampling Time Setting</description>
                            <lsb>0</lsb>
                            <msb>7</msb>
                            <access>read-write</access>
                        </field>
                    </fields>
                </register>
                <register>
                    <name>ADSSTRO</name>
                    <description>A/D Sampling State Register</description>
                    <addressOffset>0x0DF</addressOffset>
                    <size>8</size>
                    <access>read-write</access>
                    <resetValue>0x0b</resetValue>
                    <resetMask>0xff</resetMask>
                    <fields>
                        <field>
                            <name>SST</name>
                            <description>Sampling Time Setting</description>
                            <lsb>0</lsb>
                            <msb>7</msb>
                            <access>read-write</access>
                        </field>
                    </fields>
                </register>
                <register>
                    <dim>9</dim>
                    <dimIncrement>0x1</dimIncrement>
                    <dimIndex>0-8</dimIndex>
                    <name>ADSSTR%s</name>
                    <description>A/D Sampling State Register</description>
                    <addressOffset>0x0E0</addressOffset>
                    <size>8</size>
                    <access>read-write</access>
                    <resetValue>0x0b</resetValue>
                    <resetMask>0xff</resetMask>
                    <fields>
                        <field>
                            <name>SST</name>
                            <description>Sampling Time Setting</description>
                            <lsb>0</lsb>
                            <msb>7</msb>
                            <access>read-write</access>
                        </field>
                    </fields>
                </register>
                <register>
                    <name>ADSSTRV</name>
                    <description>A/D Sampling State Register</description>
                    <addressOffset>0x0E3</addressOffset>
                    <size>8</size>
                    <access>read-write</access>
                    <resetValue>0x0b</resetValue>
                    <resetMask>0xff</resetMask>
                    <fields>
                        <field>
                            <name>SST</name>
                            <description>Sampling Time Setting</description>
                            <lsb>0</lsb>
                            <msb>7</msb>
                            <access>read-write</access>
                        </field>
                    </fields>
                </register>
                <register>
                    <dim>4</dim>
                    <dimIncrement>0x1</dimIncrement>
                    <dimIndex>16-19</dimIndex>
                    <name>ADSSTR%s</name>
                    <description>A/D Sampling State Register</description>
                    <addressOffset>0x0EC</addressOffset>
                    <size>8</size>
                    <access>read-write</access>
                    <resetValue>0x0b</resetValue>
                    <resetMask>0xff</resetMask>
                    <fields>
                        <field>
                            <name>SST</name>
                            <description>Sampling Time Setting</description>
                            <lsb>0</lsb>
                            <msb>7</msb>
                            <access>read-write</access>
                        </field>
                    </fields>
                </register>
            </registers>
        </peripheral>
        <peripheral>
            <name>ADC121</name>
            <description>12-bit A/D Converter 1</description>
            <baseAddress>0x40332200</baseAddress>
            <addressBlock>
                <offset>0x00</offset>
                <size>2</size>
                <usage>registers</usage>
            </addressBlock>
            <addressBlock>
                <offset>0x04</offset>
                <size>9</size>
                <usage>registers</usage>
            </addressBlock>
            <addressBlock>
                <offset>0x0E</offset>
                <size>32</size>
                <usage>registers</usage>
            </addressBlock>
            <addressBlock>
                <offset>0x66</offset>
                <size>2</size>
                <usage>registers</usage>
            </addressBlock>
            <addressBlock>
                <offset>0x7A</offset>
                <size>1</size>
                <usage>registers</usage>
            </addressBlock>
            <addressBlock>
                <offset>0x7C</offset>
                <size>1</size>
                <usage>registers</usage>
            </addressBlock>
            <addressBlock>
                <offset>0x80</offset>
                <size>2</size>
                <usage>registers</usage>
            </addressBlock>
            <addressBlock>
                <offset>0x84</offset>
                <size>4</size>
                <usage>registers</usage>
            </addressBlock>
            <addressBlock>
                <offset>0x8C</offset>
                <size>1</size>
                <usage>registers</usage>
            </addressBlock>
            <addressBlock>
                <offset>0x90</offset>
                <size>6</size>
                <usage>registers</usage>
            </addressBlock>
            <addressBlock>
                <offset>0x98</offset>
                <size>2</size>
                <usage>registers</usage>
            </addressBlock>
            <addressBlock>
                <offset>0x9C</offset>
                <size>6</size>
                <usage>registers</usage>
            </addressBlock>
            <addressBlock>
                <offset>0xA4</offset>
                <size>1</size>
                <usage>registers</usage>
            </addressBlock>
            <addressBlock>
                <offset>0xA6</offset>
                <size>1</size>
                <usage>registers</usage>
            </addressBlock>
            <addressBlock>
                <offset>0xA8</offset>
                <size>5</size>
                <usage>registers</usage>
            </addressBlock>
            <addressBlock>
                <offset>0xB0</offset>
                <size>33</size>
                <usage>registers</usage>
            </addressBlock>
            <addressBlock>
                <offset>0xD2</offset>
                <size>1</size>
                <usage>registers</usage>
            </addressBlock>
            <addressBlock>
                <offset>0xDD</offset>
                <size>10</size>
                <usage>registers</usage>
            </addressBlock>
            <registers>
                <register>
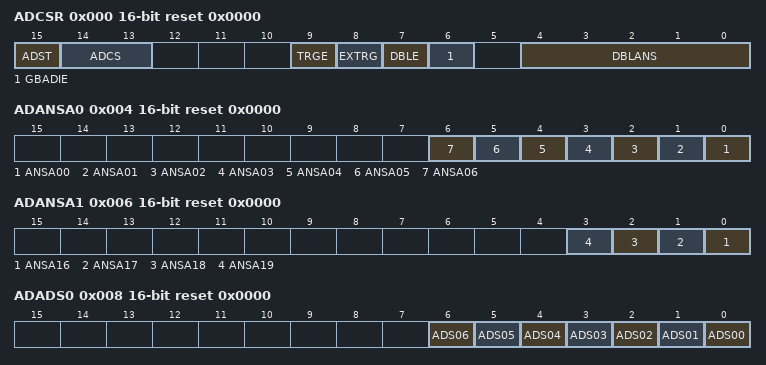
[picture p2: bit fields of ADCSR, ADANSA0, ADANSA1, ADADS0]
                    <name>ADCSR</name>
                    <description>A/D Control Register</description>
                    <addressOffset>0x000</addressOffset>
                    <size>16</size>
                    <access>read-write</access>
                    <resetValue>0x0000</resetValue>
                    <resetMask>0xffff</resetMask>
                    <fields>
                        <field>
                            <name>DBLANS</name>
                            <description>Double Trigger Channel Select</description>
                            <lsb>0</lsb>
                            <msb>4</msb>
                            <access>read-write</access>
                        </field>
                        <field>
                            <name>GBADIE</name>
                            <description>Group B Scan End Interrupt and ELC Event Enable</description>
                            <lsb>6</lsb>
                            <msb>6</msb>
                            <access>read-write</access>
                            <enumeratedValues>
                                <enumeratedValue>
                                    <name>0</name>
                                    <description>Disable ADC12i_GBADI (i = 0, 1) interrupt generation on group B scan completion.</description>
                                    <value>#0</value>
                                </enumeratedValue>
                                <enumeratedValue>
                                    <name>1</name>
                                    <description>Enable ADC12i_GBADI (i = 0, 1) interrupt generation on group B scan completion.</description>
                                    <value>#1</value>
                                </enumeratedValue>
                            </enumeratedValues>
                        </field>
                        <field>
                            <name>DBLE</name>
                            <description>Double Trigger Mode Select</description>
                            <lsb>7</lsb>
                            <msb>7</msb>
                            <access>read-write</access>
                            <enumeratedValues>
                                <enumeratedValue>
                                    <name>0</name>
                                    <description>Deselect double-trigger mode.</description>
                                    <value>#0</value>
                                </enumeratedValue>
                                <enumeratedValue>
                                    <name>1</name>
                                    <description>Select double-trigger mode.</description>
                                    <value>#1</value>
                                </enumeratedValue>
                            </enumeratedValues>
                        </field>
                        <field>
                            <name>EXTRG</name>
                            <description>Trigger Select</description>
                            <lsb>8</lsb>
                            <msb>8</msb>
                            <access>read-write</access>
                            <enumeratedValues>
                                <enumeratedValue>
                                    <name>0</name>
                                    <description>Start A/D conversion by the synchronous trigger (GPT, ELC).</description>
                                    <value>#0</value>
                                </enumeratedValue>
                                <enumeratedValue>
                                    <name>1</name>
                                    <description>Start A/D conversion by the asynchronous trigger (ADTRGn).</description>
                                    <value>#1</value>
                                </enumeratedValue>
                            </enumeratedValues>
                        </field>
                        <field>
                            <name>TRGE</name>
                            <description>Trigger Start Enable</description>
                            <lsb>9</lsb>
                            <msb>9</msb>
                            <access>read-write</access>
                            <enumeratedValues>
                                <enumeratedValue>
                                    <name>0</name>
                                    <description>Disable A/D conversion to be started by the synchronous or asynchronous trigger</description>
                                    <value>#0</value>
                                </enumeratedValue>
                                <enumeratedValue>
                                    <name>1</name>
                                    <description>Enable A/D conversion to be started by the synchronous or asynchronous trigger</description>
                                    <value>#1</value>
                                </enumeratedValue>
                            </enumeratedValues>
                        </field>
                        <field>
                            <name>ADCS</name>
                            <description>Scan Mode Select</description>
                            <lsb>13</lsb>
                            <msb>14</msb>
                            <access>read-write</access>
                            <enumeratedValues>
                                <enumeratedValue>
                                    <name>00</name>
                                    <description>Single scan mode</description>
                                    <value>#00</value>
                                </enumeratedValue>
                                <enumeratedValue>
                                    <name>01</name>
                                    <description>Group scan mode</description>
                                    <value>#01</value>
                                </enumeratedValue>
                                <enumeratedValue>
                                    <name>10</name>
                                    <description>Continuous scan mode</description>
                                    <value>#10</value>
                                </enumeratedValue>
                                <enumeratedValue>
                                    <name>11</name>
                                    <description>Setting prohibited</description>
                                    <value>#11</value>
                                </enumeratedValue>
                            </enumeratedValues>
                        </field>
                        <field>
                            <name>ADST</name>
                            <description>A/D Conversion Start</description>
                            <lsb>15</lsb>
                            <msb>15</msb>
                            <access>read-write</access>
                            <enumeratedValues>
                                <enumeratedValue>
                                    <name>0</name>
                                    <description>Stop A/D conversion process.</description>
                                    <value>#0</value>
                                </enumeratedValue>
                                <enumeratedValue>
                                    <name>1</name>
                                    <description>Start A/D conversion process.</description>
                                    <value>#1</value>
                                </enumeratedValue>
                            </enumeratedValues>
                        </field>
                    </fields>
                </register>
                <register>
                    <name>ADANSA0</name>
                    <description>A/D Channel Select Register A0</description>
                    <addressOffset>0x004</addressOffset>
                    <size>16</size>
                    <access>read-write</access>
                    <resetValue>0x0000</resetValue>
                    <resetMask>0xffff</resetMask>
                    <fields>
                        <field>
                            <name>ANSA00</name>
                            <description>A/D Conversion Channels Select</description>
                            <lsb>0</lsb>
                            <msb>0</msb>
                            <access>read-write</access>
                            <enumeratedValues>
                                <enumeratedValue>
                                    <name>0</name>
                                    <description>Do not select associated input channel.</description>
                                    <value>#0</value>
                                </enumeratedValue>
                                <enumeratedValue>
                                    <name>1</name>
                                    <description>Select associated input channel. </description>
                                    <value>#1</value>
                                </enumeratedValue>
                            </enumeratedValues>
                        </field>
                        <field>
                            <name>ANSA01</name>
                            <description>A/D Conversion Channels Select</description>
                            <lsb>1</lsb>
                            <msb>1</msb>
                            <access>read-write</access>
                            <enumeratedValues>
                                <enumeratedValue>
                                    <name>0</name>
                                    <description>Do not select associated input channel.</description>
                                    <value>#0</value>
                                </enumeratedValue>
                                <enumeratedValue>
                                    <name>1</name>
                                    <description>Select associated input channel. </description>
                                    <value>#1</value>
                                </enumeratedValue>
                            </enumeratedValues>
                        </field>
                        <field>
                            <name>ANSA02</name>
                            <description>A/D Conversion Channels Select</description>
                            <lsb>2</lsb>
                            <msb>2</msb>
                            <access>read-write</access>
                            <enumeratedValues>
                                <enumeratedValue>
                                    <name>0</name>
                                    <description>Do not select associated input channel.</description>
                                    <value>#0</value>
                                </enumeratedValue>
                                <enumeratedValue>
                                    <name>1</name>
                                    <description>Select associated input channel. </description>
                                    <value>#1</value>
                                </enumeratedValue>
                            </enumeratedValues>
                        </field>
                        <field>
                            <name>ANSA03</name>
                            <description>A/D Conversion Channels Select</description>
                            <lsb>3</lsb>
                            <msb>3</msb>
                            <access>read-write</access>
                            <enumeratedValues>
                                <enumeratedValue>
                                    <name>0</name>
                                    <description>Do not select associated input channel.</description>
                                    <value>#0</value>
                                </enumeratedValue>
                                <enumeratedValue>
                                    <name>1</name>
                                    <description>Select associated input channel. </description>
                                    <value>#1</value>
                                </enumeratedValue>
                            </enumeratedValues>
                        </field>
                        <field>
                            <name>ANSA04</name>
                            <description>A/D Conversion Channels Select</description>
                            <lsb>4</lsb>
                            <msb>4</msb>
                            <access>read-write</access>
                            <enumeratedValues>
                                <enumeratedValue>
                                    <name>0</name>
                                    <description>Do not select associated input channel.</description>
                                    <value>#0</value>
                                </enumeratedValue>
                                <enumeratedValue>
                                    <name>1</name>
                                    <description>Select associated input channel. </description>
                                    <value>#1</value>
                                </enumeratedValue>
                            </enumeratedValues>
                        </field>
                        <field>
                            <name>ANSA05</name>
                            <description>A/D Conversion Channels Select</description>
                            <lsb>5</lsb>
                            <msb>5</msb>
                            <access>read-write</access>
                            <enumeratedValues>
                                <enumeratedValue>
                                    <name>0</name>
                                    <description>Do not select associated input channel.</description>
                                    <value>#0</value>
                                </enumeratedValue>
                                <enumeratedValue>
                                    <name>1</name>
                                    <description>Select associated input channel. </description>
                                    <value>#1</value>
                                </enumeratedValue>
                            </enumeratedValues>
                        </field>
                        <field>
                            <name>ANSA06</name>
                            <description>A/D Conversion Channels Select</description>
                            <lsb>6</lsb>
                            <msb>6</msb>
                            <access>read-write</access>
                            <enumeratedValues>
                                <enumeratedValue>
                                    <name>0</name>
                                    <description>Do not select associated input channel.</description>
                                    <value>#0</value>
                                </enumeratedValue>
                                <enumeratedValue>
                                    <name>1</name>
                                    <description>Select associated input channel. </description>
                                    <value>#1</value>
                                </enumeratedValue>
                            </enumeratedValues>
                        </field>
                    </fields>
                </register>
                <register>
                    <name>ADANSA1</name>
                    <description>A/D Channel Select Register A1</description>
                    <addressOffset>0x006</addressOffset>
                    <size>16</size>
                    <access>read-write</access>
                    <resetValue>0x0000</resetValue>
                    <resetMask>0xffff</resetMask>
                    <fields>
                        <field>
                            <name>ANSA16</name>
                            <description>A/D Conversion Channels Select</description>
                            <lsb>0</lsb>
                            <msb>0</msb>
                            <access>read-write</access>
                            <enumeratedValues>
                                <enumeratedValue>
                                    <name>0</name>
                                    <description>Do not select associated input channel.</description>
                                    <value>#0</value>
                                </enumeratedValue>
                                <enumeratedValue>
                                    <name>1</name>
                                    <description>Select associated input channel. </description>
                                    <value>#1</value>
                                </enumeratedValue>
                            </enumeratedValues>
                        </field>
                        <field>
                            <name>ANSA17</name>
                            <description>A/D Conversion Channels Select</description>
                            <lsb>1</lsb>
                            <msb>1</msb>
                            <access>read-write</access>
                            <enumeratedValues>
                                <enumeratedValue>
                                    <name>0</name>
                                    <description>Do not select associated input channel.</description>
                                    <value>#0</value>
                                </enumeratedValue>
                                <enumeratedValue>
                                    <name>1</name>
                                    <description>Select associated input channel. </description>
                                    <value>#1</value>
                                </enumeratedValue>
                            </enumeratedValues>
                        </field>
                        <field>
                            <name>ANSA18</name>
                            <description>A/D Conversion Channels Select</description>
                            <lsb>2</lsb>
                            <msb>2</msb>
                            <access>read-write</access>
                            <enumeratedValues>
                                <enumeratedValue>
                                    <name>0</name>
                                    <description>Do not select associated input channel.</description>
                                    <value>#0</value>
                                </enumeratedValue>
                                <enumeratedValue>
                                    <name>1</name>
                                    <description>Select associated input channel. </description>
                                    <value>#1</value>
                                </enumeratedValue>
                            </enumeratedValues>
                        </field>
                        <field>
                            <name>ANSA19</name>
                            <description>A/D Conversion Channels Select</description>
                            <lsb>3</lsb>
                            <msb>3</msb>
                            <access>read-write</access>
                            <enumeratedValues>
                                <enumeratedValue>
                                    <name>0</name>
                                    <description>Do not select associated input channel.</description>
                                    <value>#0</value>
                                </enumeratedValue>
                                <enumeratedValue>
                                    <name>1</name>
                                    <description>Select associated input channel. </description>
                                    <value>#1</value>
                                </enumeratedValue>
                            </enumeratedValues>
                        </field>
                    </fields>
                </register>
                <register>
                    <name>ADADS0</name>
                    <description>A/D-Converted Value Addition/Average Channel Select Register 0</description>
                    <addressOffset>0x008</addressOffset>
                    <size>16</size>
                    <access>read-write</access>
                    <resetValue>0x0000</resetValue>
                    <resetMask>0xffff</resetMask>
                    <fields>
                        <field>
                            <name>ADS00</name>
                            <description>A/D-Converted Value Addition/Average Channel Select</description>
                            <lsb>0</lsb>
                            <msb>0</msb>
                            <access>read-write</access>
                            <enumeratedValues>
                                <enumeratedValue>
                                    <name>0</name>
                                    <description>Do not select associated input channel.</description>
                                    <value>#0</value>
                                </enumeratedValue>
                                <enumeratedValue>
                                    <name>1</name>
                                    <description>Select associated input channel. </description>
                                    <value>#1</value>
                                </enumeratedValue>
                            </enumeratedValues>
                        </field>
                        <field>
                            <name>ADS01</name>
                            <description>A/D-Converted Value Addition/Average Channel Select</description>
                            <lsb>1</lsb>
                            <msb>1</msb>
                            <access>read-write</access>
                            <enumeratedValues>
                                <enumeratedValue>
                                    <name>0</name>
                                    <description>Do not select associated input channel.</description>
                                    <value>#0</value>
                                </enumeratedValue>
                                <enumeratedValue>
                                    <name>1</name>
                                    <description>Select associated input channel. </description>
                                    <value>#1</value>
                                </enumeratedValue>
                            </enumeratedValues>
                        </field>
                        <field>
                            <name>ADS02</name>
                            <description>A/D-Converted Value Addition/Average Channel Select</description>
                            <lsb>2</lsb>
                            <msb>2</msb>
                            <access>read-write</access>
                            <enumeratedValues>
                                <enumeratedValue>
                                    <name>0</name>
                                    <description>Do not select associated input channel.</description>
                                    <value>#0</value>
                                </enumeratedValue>
                                <enumeratedValue>
                                    <name>1</name>
                                    <description>Select associated input channel. </description>
                                    <value>#1</value>
                                </enumeratedValue>
                            </enumeratedValues>
                        </field>
                        <field>
                            <name>ADS03</name>
                            <description>A/D-Converted Value Addition/Average Channel Select</description>
                            <lsb>3</lsb>
                            <msb>3</msb>
                            <access>read-write</access>
                            <enumeratedValues>
                                <enumeratedValue>
                                    <name>0</name>
                                    <description>Do not select associated input channel.</description>
                                    <value>#0</value>
                                </enumeratedValue>
                                <enumeratedValue>
                                    <name>1</name>
                                    <description>Select associated input channel. </description>
                                    <value>#1</value>
                                </enumeratedValue>
                            </enumeratedValues>
                        </field>
                        <field>
                            <name>ADS04</name>
                            <description>A/D-Converted Value Addition/Average Channel Select</description>
                            <lsb>4</lsb>
                            <msb>4</msb>
                            <access>read-write</access>
                            <enumeratedValues>
                                <enumeratedValue>
                                    <name>0</name>
                                    <description>Do not select associated input channel.</description>
                                    <value>#0</value>
                                </enumeratedValue>
                                <enumeratedValue>
                                    <name>1</name>
                                    <description>Select associated input channel. </description>
                                    <value>#1</value>
                                </enumeratedValue>
                            </enumeratedValues>
                        </field>
                        <field>
                            <name>ADS05</name>
                            <description>A/D-Converted Value Addition/Average Channel Select</description>
                            <lsb>5</lsb>
                            <msb>5</msb>
                            <access>read-write</access>
                            <enumeratedValues>
                                <enumeratedValue>
                                    <name>0</name>
                                    <description>Do not select associated input channel.</description>
                                    <value>#0</value>
                                </enumeratedValue>
                                <enumeratedValue>
                                    <name>1</name>
                                    <description>Select associated input channel. </description>
                                    <value>#1</value>
                                </enumeratedValue>
                            </enumeratedValues>
                        </field>
                        <field>
                            <name>ADS06</name>
                            <description>A/D-Converted Value Addition/Average Channel Select</description>
                            <lsb>6</lsb>
                            <msb>6</msb>
                            <access>read-write</access>
                            <enumeratedValues>
                                <enumeratedValue>
                                    <name>0</name>
                                    <description>Do not select associated input channel.</description>
                                    <value>#0</value>
                                </enumeratedValue>
                                <enumeratedValue>
                                    <name>1</name>
                                    <description>Select associated input channel. </description>
                                    <value>#1</value>
                                </enumeratedValue>
                            </enumeratedValues>
                        </field>
                    </fields>
                </register>
                <register>
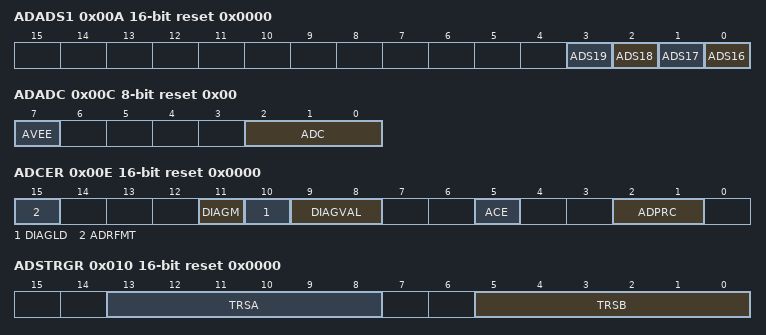
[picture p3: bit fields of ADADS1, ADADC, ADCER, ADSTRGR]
                    <name>ADADS1</name>
                    <description>A/D-Converted Value Addition/Average Channel Select Register 1</description>
                    <addressOffset>0x00A</addressOffset>
                    <size>16</size>
                    <access>read-write</access>
                    <resetValue>0x0000</resetValue>
                    <resetMask>0xffff</resetMask>
                    <fields>
                        <field>
                            <name>ADS16</name>
                            <description>A/D Conversion Channels Select/Average Channel Select</description>
                            <lsb>0</lsb>
                            <msb>0</msb>
                            <access>read-write</access>
                            <enumeratedValues>
                                <enumeratedValue>
                                    <name>0</name>
                                    <description>Do not select associated input channel.</description>
                                    <value>#0</value>
                                </enumeratedValue>
                                <enumeratedValue>
                                    <name>1</name>
                                    <description>Select associated input channel. </description>
                                    <value>#1</value>
                                </enumeratedValue>
                            </enumeratedValues>
                        </field>
                        <field>
                            <name>ADS17</name>
                            <description>A/D Conversion Channels Select/Average Channel Select</description>
                            <lsb>1</lsb>
                            <msb>1</msb>
                            <access>read-write</access>
                            <enumeratedValues>
                                <enumeratedValue>
                                    <name>0</name>
                                    <description>Do not select associated input channel.</description>
                                    <value>#0</value>
                                </enumeratedValue>
                                <enumeratedValue>
                                    <name>1</name>
                                    <description>Select associated input channel. </description>
                                    <value>#1</value>
                                </enumeratedValue>
                            </enumeratedValues>
                        </field>
                        <field>
                            <name>ADS18</name>
                            <description>A/D Conversion Channels Select/Average Channel Select</description>
                            <lsb>2</lsb>
                            <msb>2</msb>
                            <access>read-write</access>
                            <enumeratedValues>
                                <enumeratedValue>
                                    <name>0</name>
                                    <description>Do not select associated input channel.</description>
                                    <value>#0</value>
                                </enumeratedValue>
                                <enumeratedValue>
                                    <name>1</name>
                                    <description>Select associated input channel. </description>
                                    <value>#1</value>
                                </enumeratedValue>
                            </enumeratedValues>
                        </field>
                        <field>
                            <name>ADS19</name>
                            <description>A/D Conversion Channels Select/Average Channel Select</description>
                            <lsb>3</lsb>
                            <msb>3</msb>
                            <access>read-write</access>
                            <enumeratedValues>
                                <enumeratedValue>
                                    <name>0</name>
                                    <description>Do not select associated input channel.</description>
                                    <value>#0</value>
                                </enumeratedValue>
                                <enumeratedValue>
                                    <name>1</name>
                                    <description>Select associated input channel. </description>
                                    <value>#1</value>
                                </enumeratedValue>
                            </enumeratedValues>
                        </field>
                    </fields>
                </register>
                <register>
                    <name>ADADC</name>
                    <description>A/D-Converted Value Addition/Average Count Select Register</description>
                    <addressOffset>0x00C</addressOffset>
                    <size>8</size>
                    <access>read-write</access>
                    <resetValue>0x00</resetValue>
                    <resetMask>0xff</resetMask>
                    <fields>
                        <field>
                            <name>ADC</name>
                            <description>Addition/Average Count Select</description>
                            <lsb>0</lsb>
                            <msb>2</msb>
                            <access>read-write</access>
                            <enumeratedValues>
                                <enumeratedValue>
                                    <name>000</name>
                                    <description>1-time conversion (no addition, same as normal conversion)</description>
                                    <value>#000</value>
                                </enumeratedValue>
                                <enumeratedValue>
                                    <name>001</name>
                                    <description>2-time conversion (1 addition)</description>
                                    <value>#001</value>
                                </enumeratedValue>
                                <enumeratedValue>
                                    <name>010</name>
                                    <description>3-time conversion (2 additions)</description>
                                    <value>#010</value>
                                </enumeratedValue>
                                <enumeratedValue>
                                    <name>011</name>
                                    <description>4-time conversion (3 additions)</description>
                                    <value>#011</value>
                                </enumeratedValue>
                                <enumeratedValue>
                                    <name>101</name>
                                    <description>16-time conversion (15 additions)</description>
                                    <value>#101</value>
                                </enumeratedValue>
                                <enumeratedValue>
                                    <name>Others</name>
                                    <description>Setting prohibited</description>
                                    <isDefault>true</isDefault>
                                </enumeratedValue>
                            </enumeratedValues>
                        </field>
                        <field>
                            <name>AVEE</name>
                            <description>Average Mode Select</description>
                            <lsb>7</lsb>
                            <msb>7</msb>
                            <access>read-write</access>
                            <enumeratedValues>
                                <enumeratedValue>
                                    <name>0</name>
                                    <description>Enable addition mode</description>
                                    <value>#0</value>
                                </enumeratedValue>
                                <enumeratedValue>
                                    <name>1</name>
                                    <description>Enable average mode</description>
                                    <value>#1</value>
                                </enumeratedValue>
                            </enumeratedValues>
                        </field>
                    </fields>
                </register>
                <register>
                    <name>ADCER</name>
                    <description>A/D Control Extended Register</description>
                    <addressOffset>0x00E</addressOffset>
                    <size>16</size>
                    <access>read-write</access>
                    <resetValue>0x0000</resetValue>
                    <resetMask>0xffff</resetMask>
                    <fields>
                        <field>
                            <name>ADPRC</name>
                            <lsb>1</lsb>
                            <msb>2</msb>
                            <access>read-write</access>
                            <enumeratedValues>
                                <enumeratedValue>
                                    <name>00</name>
                                    <description>12-bit accuracy</description>
                                    <value>#00</value>
                                </enumeratedValue>
                                <enumeratedValue>
                                    <name>01</name>
                                    <description>10-bit accuracy</description>
                                    <value>#01</value>
                                </enumeratedValue>
                                <enumeratedValue>
                                    <name>10</name>
                                    <description>8-bit accuracy</description>
                                    <value>#10</value>
                                </enumeratedValue>
                                <enumeratedValue>
                                    <name>11</name>
                                    <description>Setting prohibited</description>
                                    <value>#11</value>
                                </enumeratedValue>
                            </enumeratedValues>
                        </field>
                        <field>
                            <name>ACE</name>
                            <description>A/D Data Register Automatic Clearing Enable</description>
                            <lsb>5</lsb>
                            <msb>5</msb>
                            <access>read-write</access>
                            <enumeratedValues>
                                <enumeratedValue>
                                    <name>0</name>
                                    <description>Disable automatic clearing</description>
                                    <value>#0</value>
                                </enumeratedValue>
                                <enumeratedValue>
                                    <name>1</name>
                                    <description>Enable automatic clearing</description>
                                    <value>#1</value>
                                </enumeratedValue>
                            </enumeratedValues>
                        </field>
                        <field>
                            <name>DIAGVAL</name>
                            <description>Self-Diagnosis Conversion Voltage Select</description>
                            <lsb>8</lsb>
                            <msb>9</msb>
                            <access>read-write</access>
                            <enumeratedValues>
                                <enumeratedValue>
                                    <name>00</name>
                                    <description>Setting prohibited when self-diagnosis is enabled</description>
                                    <value>#00</value>
                                </enumeratedValue>
                                <enumeratedValue>
                                    <name>01</name>
                                    <description>0 volts</description>
                                    <value>#01</value>
                                </enumeratedValue>
                                <enumeratedValue>
                                    <name>10</name>
                                    <description>Reference voltage × 1/2</description>
                                    <value>#10</value>
                                </enumeratedValue>
                                <enumeratedValue>
                                    <name>11</name>
                                    <description>Reference voltage</description>
                                    <value>#11</value>
                                </enumeratedValue>
                            </enumeratedValues>
                        </field>
                        <field>
                            <name>DIAGLD</name>
                            <description>Self-Diagnosis Mode Select</description>
                            <lsb>10</lsb>
                            <msb>10</msb>
                            <access>read-write</access>
                            <enumeratedValues>
                                <enumeratedValue>
                                    <name>0</name>
                                    <description>Select rotation mode for self-diagnosis voltage</description>
                                    <value>#0</value>
                                </enumeratedValue>
                                <enumeratedValue>
                                    <name>1</name>
                                    <description>Select mixed mode for self-diagnosis voltage</description>
                                    <value>#1</value>
                                </enumeratedValue>
                            </enumeratedValues>
                        </field>
                        <field>
                            <name>DIAGM</name>
                            <description>Self-Diagnosis Enable</description>
                            <lsb>11</lsb>
                            <msb>11</msb>
                            <access>read-write</access>
                            <enumeratedValues>
                                <enumeratedValue>
                                    <name>0</name>
                                    <description>Disable ADC12 self-diagnosis</description>
                                    <value>#0</value>
                                </enumeratedValue>
                                <enumeratedValue>
                                    <name>1</name>
                                    <description>Enable ADC12 self-diagnosis</description>
                                    <value>#1</value>
                                </enumeratedValue>
                            </enumeratedValues>
                        </field>
                        <field>
                            <name>ADRFMT</name>
                            <description>A/D Data Register Format Select</description>
                            <lsb>15</lsb>
                            <msb>15</msb>
                            <access>read-write</access>
                            <enumeratedValues>
                                <enumeratedValue>
                                    <name>0</name>
                                    <description>Select right-justified for the A/D data register format</description>
                                    <value>#0</value>
                                </enumeratedValue>
                                <enumeratedValue>
                                    <name>1</name>
                                    <description>Select left-justified for the A/D data register format</description>
                                    <value>#1</value>
                                </enumeratedValue>
                            </enumeratedValues>
                        </field>
                    </fields>
                </register>
                <register>
                    <name>ADSTRGR</name>
                    <description>A/D Conversion Start Trigger Select Register</description>
                    <addressOffset>0x010</addressOffset>
                    <size>16</size>
                    <access>read-write</access>
                    <resetValue>0x0000</resetValue>
                    <resetMask>0xffff</resetMask>
                    <fields>
                        <field>
                            <name>TRSB</name>
                            <description>A/D Conversion Start Trigger Select for Group B</description>
                            <lsb>0</lsb>
                            <msb>5</msb>
                            <access>read-write</access>
                        </field>
                        <field>
                            <name>TRSA</name>
                            <description>A/D Conversion Start Trigger Select</description>
                            <lsb>8</lsb>
                            <msb>13</msb>
                            <access>read-write</access>
                        </field>
                    </fields>
                </register>
                <register>
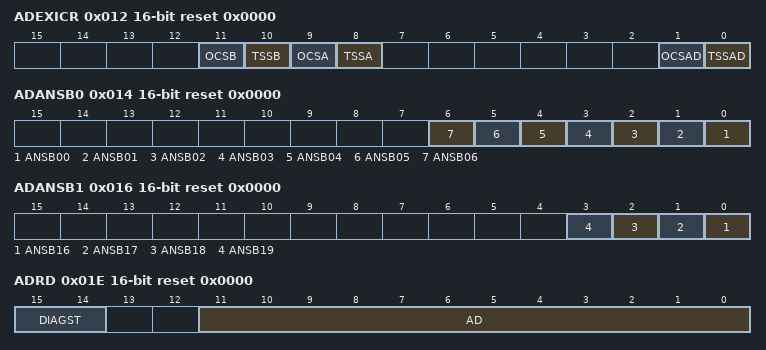
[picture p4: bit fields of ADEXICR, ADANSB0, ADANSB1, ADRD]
                    <name>ADEXICR</name>
                    <description>A/D Conversion Extended Input Control Registers</description>
                    <addressOffset>0x012</addressOffset>
                    <size>16</size>
                    <access>read-write</access>
                    <resetValue>0x0000</resetValue>
                    <resetMask>0xffff</resetMask>
                    <fields>
                        <field>
                            <name>TSSAD</name>
                            <description>Temperature Sensor Output A/D-Converted Value Addition/Average Mode Select</description>
                            <lsb>0</lsb>
                            <msb>0</msb>
                            <access>read-write</access>
                            <enumeratedValues>
                                <enumeratedValue>
                                    <name>0</name>
                                    <description>Do not select addition/average mode for temperature sensor output.</description>
                                    <value>#0</value>
                                </enumeratedValue>
                                <enumeratedValue>
                                    <name>1</name>
                                    <description>Select addition/average mode for temperature sensor output.</description>
                                    <value>#1</value>
                                </enumeratedValue>
                            </enumeratedValues>
                        </field>
                        <field>
                            <name>OCSAD</name>
                            <description>Internal Reference Voltage A/D-Converted Value Addition/Average Mode Select</description>
                            <lsb>1</lsb>
                            <msb>1</msb>
                            <access>read-write</access>
                            <enumeratedValues>
                                <enumeratedValue>
                                    <name>0</name>
                                    <description>Do not select addition/average mode for internal reference voltage.</description>
                                    <value>#0</value>
                                </enumeratedValue>
                                <enumeratedValue>
                                    <name>1</name>
                                    <description>Select addition/average mode for internal reference voltage.</description>
                                    <value>#1</value>
                                </enumeratedValue>
                            </enumeratedValues>
                        </field>
                        <field>
                            <name>TSSA</name>
                            <description>Temperature Sensor Output A/D Conversion Select</description>
                            <lsb>8</lsb>
                            <msb>8</msb>
                            <access>read-write</access>
                            <enumeratedValues>
                                <enumeratedValue>
                                    <name>0</name>
                                    <description>Disable A/D conversion of temperature sensor output</description>
                                    <value>#0</value>
                                </enumeratedValue>
                                <enumeratedValue>
                                    <name>1</name>
                                    <description>Enable A/D conversion of temperature sensor output</description>
                                    <value>#1</value>
                                </enumeratedValue>
                            </enumeratedValues>
                        </field>
                        <field>
                            <name>OCSA</name>
                            <description>Internal Reference Voltage A/D Conversion Select</description>
                            <lsb>9</lsb>
                            <msb>9</msb>
                            <access>read-write</access>
                            <enumeratedValues>
                                <enumeratedValue>
                                    <name>0</name>
                                    <description>Disable A/D conversion of internal reference voltage</description>
                                    <value>#0</value>
                                </enumeratedValue>
                                <enumeratedValue>
                                    <name>1</name>
                                    <description>Enable A/D conversion of internal reference voltage</description>
                                    <value>#1</value>
                                </enumeratedValue>
                            </enumeratedValues>
                        </field>
                        <field>
                            <name>TSSB</name>
                            <description>Temperature Sensor Output A/D Conversion Select for Group B</description>
                            <lsb>10</lsb>
                            <msb>10</msb>
                            <access>read-write</access>
                            <enumeratedValues>
                                <enumeratedValue>
                                    <name>0</name>
                                    <description>Disable A/D conversion of temperature sensor output</description>
                                    <value>#0</value>
                                </enumeratedValue>
                                <enumeratedValue>
                                    <name>1</name>
                                    <description>Enable A/D conversion of temperature sensor output</description>
                                    <value>#1</value>
                                </enumeratedValue>
                            </enumeratedValues>
                        </field>
                        <field>
                            <name>OCSB</name>
                            <description>Internal Reference Voltage A/D Conversion Select for Group B</description>
                            <lsb>11</lsb>
                            <msb>11</msb>
                            <access>read-write</access>
                            <enumeratedValues>
                                <enumeratedValue>
                                    <name>0</name>
                                    <description>Disable A/D conversion of internal reference voltage</description>
                                    <value>#0</value>
                                </enumeratedValue>
                                <enumeratedValue>
                                    <name>1</name>
                                    <description>Enable A/D conversion of internal reference voltage</description>
                                    <value>#1</value>
                                </enumeratedValue>
                            </enumeratedValues>
                        </field>
                    </fields>
                </register>
                <register>
                    <name>ADANSB0</name>
                    <description>A/D Channel Select Register B0</description>
                    <addressOffset>0x014</addressOffset>
                    <size>16</size>
                    <access>read-write</access>
                    <resetValue>0x0000</resetValue>
                    <resetMask>0xffff</resetMask>
                    <fields>
                        <field>
                            <name>ANSB00</name>
                            <description>A/D Conversion Channels Select</description>
                            <lsb>0</lsb>
                            <msb>0</msb>
                            <access>read-write</access>
                            <enumeratedValues>
                                <enumeratedValue>
                                    <name>0</name>
                                    <description>Do not select associated input channel.</description>
                                    <value>#0</value>
                                </enumeratedValue>
                                <enumeratedValue>
                                    <name>1</name>
                                    <description>Select associated input channel. </description>
                                    <value>#1</value>
                                </enumeratedValue>
                            </enumeratedValues>
                        </field>
                        <field>
                            <name>ANSB01</name>
                            <description>A/D Conversion Channels Select</description>
                            <lsb>1</lsb>
                            <msb>1</msb>
                            <access>read-write</access>
                            <enumeratedValues>
                                <enumeratedValue>
                                    <name>0</name>
                                    <description>Do not select associated input channel.</description>
                                    <value>#0</value>
                                </enumeratedValue>
                                <enumeratedValue>
                                    <name>1</name>
                                    <description>Select associated input channel. </description>
                                    <value>#1</value>
                                </enumeratedValue>
                            </enumeratedValues>
                        </field>
                        <field>
                            <name>ANSB02</name>
                            <description>A/D Conversion Channels Select</description>
                            <lsb>2</lsb>
                            <msb>2</msb>
                            <access>read-write</access>
                            <enumeratedValues>
                                <enumeratedValue>
                                    <name>0</name>
                                    <description>Do not select associated input channel.</description>
                                    <value>#0</value>
                                </enumeratedValue>
                                <enumeratedValue>
                                    <name>1</name>
                                    <description>Select associated input channel. </description>
                                    <value>#1</value>
                                </enumeratedValue>
                            </enumeratedValues>
                        </field>
                        <field>
                            <name>ANSB03</name>
                            <description>A/D Conversion Channels Select</description>
                            <lsb>3</lsb>
                            <msb>3</msb>
                            <access>read-write</access>
                            <enumeratedValues>
                                <enumeratedValue>
                                    <name>0</name>
                                    <description>Do not select associated input channel.</description>
                                    <value>#0</value>
                                </enumeratedValue>
                                <enumeratedValue>
                                    <name>1</name>
                                    <description>Select associated input channel. </description>
                                    <value>#1</value>
                                </enumeratedValue>
                            </enumeratedValues>
                        </field>
                        <field>
                            <name>ANSB04</name>
                            <description>A/D Conversion Channels Select</description>
                            <lsb>4</lsb>
                            <msb>4</msb>
                            <access>read-write</access>
                            <enumeratedValues>
                                <enumeratedValue>
                                    <name>0</name>
                                    <description>Do not select associated input channel.</description>
                                    <value>#0</value>
                                </enumeratedValue>
                                <enumeratedValue>
                                    <name>1</name>
                                    <description>Select associated input channel. </description>
                                    <value>#1</value>
                                </enumeratedValue>
                            </enumeratedValues>
                        </field>
                        <field>
                            <name>ANSB05</name>
                            <description>A/D Conversion Channels Select</description>
                            <lsb>5</lsb>
                            <msb>5</msb>
                            <access>read-write</access>
                            <enumeratedValues>
                                <enumeratedValue>
                                    <name>0</name>
                                    <description>Do not select associated input channel.</description>
                                    <value>#0</value>
                                </enumeratedValue>
                                <enumeratedValue>
                                    <name>1</name>
                                    <description>Select associated input channel. </description>
                                    <value>#1</value>
                                </enumeratedValue>
                            </enumeratedValues>
                        </field>
                        <field>
                            <name>ANSB06</name>
                            <description>A/D Conversion Channels Select</description>
                            <lsb>6</lsb>
                            <msb>6</msb>
                            <access>read-write</access>
                            <enumeratedValues>
                                <enumeratedValue>
                                    <name>0</name>
                                    <description>Do not select associated input channel.</description>
                                    <value>#0</value>
                                </enumeratedValue>
                                <enumeratedValue>
                                    <name>1</name>
                                    <description>Select associated input channel. </description>
                                    <value>#1</value>
                                </enumeratedValue>
                            </enumeratedValues>
                        </field>
                    </fields>
                </register>
                <register>
                    <name>ADANSB1</name>
                    <description>A/D Channel Select Register B1</description>
                    <addressOffset>0x016</addressOffset>
                    <size>16</size>
                    <access>read-write</access>
                    <resetValue>0x0000</resetValue>
                    <resetMask>0xffff</resetMask>
                    <fields>
                        <field>
                            <name>ANSB16</name>
                            <description>A/D Conversion Channels Select</description>
                            <lsb>0</lsb>
                            <msb>0</msb>
                            <access>read-write</access>
                            <enumeratedValues>
                                <enumeratedValue>
                                    <name>0</name>
                                    <description>Do not select associated input channel.</description>
                                    <value>#0</value>
                                </enumeratedValue>
                                <enumeratedValue>
                                    <name>1</name>
                                    <description>Select associated input channel. </description>
                                    <value>#1</value>
                                </enumeratedValue>
                            </enumeratedValues>
                        </field>
                        <field>
                            <name>ANSB17</name>
                            <description>A/D Conversion Channels Select</description>
                            <lsb>1</lsb>
                            <msb>1</msb>
                            <access>read-write</access>
                            <enumeratedValues>
                                <enumeratedValue>
                                    <name>0</name>
                                    <description>Do not select associated input channel.</description>
                                    <value>#0</value>
                                </enumeratedValue>
                                <enumeratedValue>
                                    <name>1</name>
                                    <description>Select associated input channel. </description>
                                    <value>#1</value>
                                </enumeratedValue>
                            </enumeratedValues>
                        </field>
                        <field>
                            <name>ANSB18</name>
                            <description>A/D Conversion Channels Select</description>
                            <lsb>2</lsb>
                            <msb>2</msb>
                            <access>read-write</access>
                            <enumeratedValues>
                                <enumeratedValue>
                                    <name>0</name>
                                    <description>Do not select associated input channel.</description>
                                    <value>#0</value>
                                </enumeratedValue>
                                <enumeratedValue>
                                    <name>1</name>
                                    <description>Select associated input channel. </description>
                                    <value>#1</value>
                                </enumeratedValue>
                            </enumeratedValues>
                        </field>
                        <field>
                            <name>ANSB19</name>
                            <description>A/D Conversion Channels Select</description>
                            <lsb>3</lsb>
                            <msb>3</msb>
                            <access>read-write</access>
                            <enumeratedValues>
                                <enumeratedValue>
                                    <name>0</name>
                                    <description>Do not select associated input channel.</description>
                                    <value>#0</value>
                                </enumeratedValue>
                                <enumeratedValue>
                                    <name>1</name>
                                    <description>Select associated input channel. </description>
                                    <value>#1</value>
                                </enumeratedValue>
                            </enumeratedValues>
                        </field>
                    </fields>
                </register>
                <register>
                    <name>ADDBLDR</name>
                    <description>A/D Data Duplexing Register</description>
                    <addressOffset>0x018</addressOffset>
                    <size>16</size>
                    <access>read-only</access>
                    <resetValue>0x0000</resetValue>
                    <resetMask>0xffff</resetMask>
                    <fields>
                        <field>
                            <name>ADDBLDR</name>
                            <description>Converted Value 15 to 0</description>
                            <lsb>0</lsb>
                            <msb>15</msb>
                            <access>read-only</access>
                        </field>
                    </fields>
                </register>
                <register>
                    <name>ADTSDR</name>
                    <description>A/D Temperature Sensor Data Register</description>
                    <addressOffset>0x01A</addressOffset>
                    <size>16</size>
                    <access>read-only</access>
                    <resetValue>0x0000</resetValue>
                    <resetMask>0xffff</resetMask>
                    <fields>
                        <field>
                            <name>ADTSDR</name>
                            <description>Converted Value 15 to 0</description>
                            <lsb>0</lsb>
                            <msb>15</msb>
                            <access>read-only</access>
                        </field>
                    </fields>
                </register>
                <register>
                    <name>ADOCDR</name>
                    <description>A/D Internal Reference Voltage Data Register</description>
                    <addressOffset>0x01C</addressOffset>
                    <size>16</size>
                    <access>read-only</access>
                    <resetValue>0x0000</resetValue>
                    <resetMask>0xffff</resetMask>
                    <fields>
                        <field>
                            <name>ADOCDR</name>
                            <description>Converted Value 15 to 0</description>
                            <lsb>0</lsb>
                            <msb>15</msb>
                            <access>read-only</access>
                        </field>
                    </fields>
                </register>
                <register>
                    <name>ADRD</name>
                    <description>A/D Self-Diagnosis Data Register</description>
                    <addressOffset>0x01E</addressOffset>
                    <size>16</size>
                    <access>read-only</access>
                    <resetValue>0x0000</resetValue>
                    <resetMask>0xffff</resetMask>
                    <fields>
                        <field>
                            <name>AD</name>
                            <description>Converted Value 11 to 0</description>
                            <lsb>0</lsb>
                            <msb>11</msb>
                            <access>read-only</access>
                        </field>
                        <field>
                            <name>DIAGST</name>
                            <description>Self-Diagnosis Status</description>
                            <lsb>14</lsb>
                            <msb>15</msb>
                            <access>read-only</access>
                            <enumeratedValues>
                                <enumeratedValue>
                                    <name>00</name>
                                    <description>Self-diagnosis not executed after power-on.</description>
                                    <value>#00</value>
                                </enumeratedValue>
                                <enumeratedValue>
                                    <name>01</name>
                                    <description>Self-diagnosis was executed using the 0 V voltage.</description>
                                    <value>#01</value>
                                </enumeratedValue>
                                <enumeratedValue>
                                    <name>10</name>
                                    <description>Self-diagnosis was executed using the reference voltage × 1/2.</description>
                                    <value>#10</value>
                                </enumeratedValue>
                                <enumeratedValue>
                                    <name>11</name>
                                    <description>Self-diagnosis was executed using the reference voltage .</description>
                                    <value>#11</value>
                                </enumeratedValue>
                            </enumeratedValues>
                        </field>
                    </fields>
                </register>
                <register>
                    <dim>7</dim>
                    <dimIncrement>0x2</dimIncrement>
                    <dimIndex>0-6</dimIndex>
                    <name>ADDR%s</name>
                    <description>A/D Data Registers %s</description>
                    <addressOffset>0x020</addressOffset>
                    <size>16</size>
                    <access>read-only</access>
                    <resetValue>0x0000</resetValue>
                    <resetMask>0xffff</resetMask>
                    <fields>
                        <field>
                            <name>ADDR</name>
                            <description>Converted Value 15 to 0</description>
                            <lsb>0</lsb>
                            <msb>15</msb>
                            <access>read-only</access>
                        </field>
                    </fields>
                </register>
                <register>
                    <dim>7</dim>
                    <dimIncrement>0x2</dimIncrement>
                    <dimIndex>16-22</dimIndex>
                    <name>ADDR%s</name>
                    <description>A/D Data Registers %s</description>
                    <addressOffset>0x020</addressOffset>
                    <size>16</size>
                    <access>read-only</access>
                    <resetValue>0x0000</resetValue>
                    <resetMask>0xffff</resetMask>
                    <fields>
                        <field>
                            <name>ADDR</name>
                            <description>Converted Value 15 to 0</description>
                            <lsb>0</lsb>
                            <msb>15</msb>
                            <access>read-only</access>
                        </field>
                    </fields>
                </register>
                <register>
                    <name>ADVMDR</name>
                    <description>A/D VBATT Monitor Data Register</description>
                    <addressOffset>0x026</addressOffset>
                    <size>16</size>
                    <access>read-only</access>
                    <resetValue>0x0000</resetValue>
                    <resetMask>0xffff</resetMask>
                    <fields>
                        <field>
                            <name>ADDR</name>
                            <description>Converted Value 15 to 0</description>
                            <lsb>0</lsb>
                            <msb>15</msb>
                            <access>read-only</access>
                        </field>
                    </fields>
                </register>
                <register>
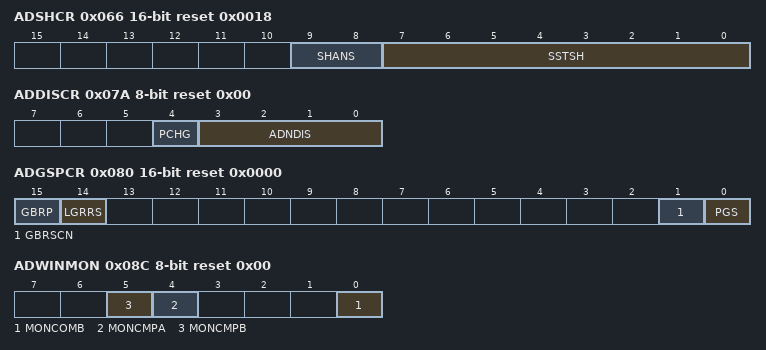
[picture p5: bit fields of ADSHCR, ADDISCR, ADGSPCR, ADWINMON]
                    <name>ADSHCR</name>
                    <description>A/D Sample and Hold Circuit Control Register</description>
                    <addressOffset>0x066</addressOffset>
                    <size>16</size>
                    <access>read-write</access>
                    <resetValue>0x0018</resetValue>
                    <resetMask>0xffff</resetMask>
                    <fields>
                        <field>
                            <name>SSTSH</name>
                            <description>Channel-Dedicated Sample-and-Hold Circuit Sampling Time Setting</description>
                            <lsb>0</lsb>
                            <msb>7</msb>
                            <access>read-write</access>
                        </field>
                        <field>
                            <name>SHANS</name>
                            <description>Channel-Dedicated Sample-and-Hold Circuit Bypass Select</description>
                            <lsb>8</lsb>
                            <msb>9</msb>
                            <access>read-write</access>
                            <enumeratedValues>
                                <enumeratedValue>
                                    <name>0</name>
                                    <description>Bypass the circuits</description>
                                    <value>#0</value>
                                </enumeratedValue>
                                <enumeratedValue>
                                    <name>1</name>
                                    <description>Use the circuits</description>
                                    <value>#1</value>
                                </enumeratedValue>
                            </enumeratedValues>
                        </field>
                    </fields>
                </register>
                <register>
                    <name>ADDISCR</name>
                    <description>A/D Disconnection Detection Control Register</description>
                    <addressOffset>0x07A</addressOffset>
                    <size>8</size>
                    <access>read-write</access>
                    <resetValue>0x00</resetValue>
                    <resetMask>0xff</resetMask>
                    <fields>
                        <field>
                            <name>ADNDIS</name>
                            <description>Disconnection Detection Assist Setting</description>
                            <lsb>0</lsb>
                            <msb>3</msb>
                            <access>read-write</access>
                            <enumeratedValues>
                                <enumeratedValue>
                                    <name>0x0</name>
                                    <description>The disconnection detection assist function is disabled</description>
                                    <value>0x0</value>
                                </enumeratedValue>
                                <enumeratedValue>
                                    <name>0x1</name>
                                    <description>Setting prohibited</description>
                                    <value>0x1</value>
                                </enumeratedValue>
                                <enumeratedValue>
                                    <name>Others</name>
                                    <description>The number of states for the discharge or precharge period.</description>
                                    <isDefault>true</isDefault>
                                </enumeratedValue>
                            </enumeratedValues>
                        </field>
                        <field>
                            <name>PCHG</name>
                            <description>Precharge/discharge select</description>
                            <lsb>4</lsb>
                            <msb>4</msb>
                            <access>read-write</access>
                            <enumeratedValues>
                                <enumeratedValue>
                                    <name>0</name>
                                    <description>Discharge</description>
                                    <value>#0</value>
                                </enumeratedValue>
                                <enumeratedValue>
                                    <name>1</name>
                                    <description>Precharge</description>
                                    <value>#1</value>
                                </enumeratedValue>
                            </enumeratedValues>
                        </field>
                    </fields>
                </register>
                <register>
                    <name>ADSHMSR</name>
                    <description>A/D Sample and Hold Operation Mode Selection Register</description>
                    <addressOffset>0x07C</addressOffset>
                    <size>8</size>
                    <access>read-write</access>
                    <resetValue>0x00</resetValue>
                    <resetMask>0xff</resetMask>
                    <fields>
                        <field>
                            <name>SHMD</name>
                            <description>Sampling Operation Selection</description>
                            <lsb>0</lsb>
                            <msb>0</msb>
                            <access>read-write</access>
                            <enumeratedValues>
                                <enumeratedValue>
                                    <name>0</name>
                                    <description>Sampling Operation Selection</description>
                                    <value>#0</value>
                                </enumeratedValue>
                                <enumeratedValue>
                                    <name>1</name>
                                    <description>Enable continuous sampling function</description>
                                    <value>#1</value>
                                </enumeratedValue>
                            </enumeratedValues>
                        </field>
                    </fields>
                </register>
                <register>
                    <name>ADGSPCR</name>
                    <description>A/D Group Scan Priority Control Register</description>
                    <addressOffset>0x080</addressOffset>
                    <size>16</size>
                    <access>read-write</access>
                    <resetValue>0x0000</resetValue>
                    <resetMask>0xffff</resetMask>
                    <fields>
                        <field>
                            <name>PGS</name>
                            <description>Group Priority Operation Setting</description>
                            <lsb>0</lsb>
                            <msb>0</msb>
                            <access>read-write</access>
                            <enumeratedValues>
                                <enumeratedValue>
                                    <name>0</name>
                                    <description>Operate without group priority control.</description>
                                    <value>#0</value>
                                </enumeratedValue>
                                <enumeratedValue>
                                    <name>1</name>
                                    <description>Operate with group priority control.</description>
                                    <value>#1</value>
                                </enumeratedValue>
                            </enumeratedValues>
                        </field>
                        <field>
                            <name>GBRSCN</name>
                            <description>Lower-Priority Group Restart Setting</description>
                            <lsb>1</lsb>
                            <msb>1</msb>
                            <access>read-write</access>
                            <enumeratedValues>
                                <enumeratedValue>
                                    <name>0</name>
                                    <description>Disable rescanning of the group that was stopped in group priority operation</description>
                                    <value>#0</value>
                                </enumeratedValue>
                                <enumeratedValue>
                                    <name>1</name>
                                    <description>Enable rescanning of the group that was stopped in group priority operation.</description>
                                    <value>#1</value>
                                </enumeratedValue>
                            </enumeratedValues>
                        </field>
                        <field>
                            <name>LGRRS</name>
                            <description>Enabled only when PGS = 1 and GBRSCN = 1.</description>
                            <lsb>14</lsb>
                            <msb>14</msb>
                            <access>read-write</access>
                            <enumeratedValues>
                                <enumeratedValue>
                                    <name>0</name>
                                    <description>Start rescanning from the first channel for scanning</description>
                                    <value>#0</value>
                                </enumeratedValue>
                                <enumeratedValue>
                                    <name>1</name>
                                    <description>Start rescanning from the channel for which A/D conversion is not completed.</description>
                                    <value>#1</value>
                                </enumeratedValue>
                            </enumeratedValues>
                        </field>
                        <field>
                            <name>GBRP</name>
                            <description>Single Scan Continuous Start</description>
                            <lsb>15</lsb>
                            <msb>15</msb>
                            <access>read-write</access>
                            <enumeratedValues>
                                <enumeratedValue>
                                    <name>0</name>
                                    <description>Single scan is not continuously activated.</description>
                                    <value>#0</value>
                                </enumeratedValue>
                                <enumeratedValue>
                                    <name>1</name>
                                    <description>Single scan for the group with the lower-priority is continuously activated.</description>
                                    <value>#1</value>
                                </enumeratedValue>
                            </enumeratedValues>
                        </field>
                    </fields>
                </register>
                <register>
                    <name>ADDBLDRA</name>
                    <description>A/D Data Duplexing Register A</description>
                    <addressOffset>0x084</addressOffset>
                    <size>16</size>
                    <access>read-only</access>
                    <resetValue>0x0000</resetValue>
                    <resetMask>0xffff</resetMask>
                    <fields>
                        <field>
                            <name>ADDBLDR</name>
                            <description>Converted Value 15 to 0</description>
                            <lsb>0</lsb>
                            <msb>15</msb>
                            <access>read-only</access>
                        </field>
                    </fields>
                </register>
                <register>
                    <name>ADDBLDRB</name>
                    <description>A/D Data Duplexing Register B</description>
                    <addressOffset>0x086</addressOffset>
                    <size>16</size>
                    <access>read-only</access>
                    <resetValue>0x0000</resetValue>
                    <resetMask>0xffff</resetMask>
                    <fields>
                        <field>
                            <name>ADDBLDR</name>
                            <description>Converted Value 15 to 0</description>
                            <lsb>0</lsb>
                            <msb>15</msb>
                            <access>read-only</access>
                        </field>
                    </fields>
                </register>
                <register>
                    <name>ADWINMON</name>
                    <description>A/D Compare Function Window A/B Status Monitor Register</description>
                    <addressOffset>0x08C</addressOffset>
                    <size>8</size>
                    <access>read-only</access>
                    <resetValue>0x00</resetValue>
                    <resetMask>0xff</resetMask>
                    <fields>
                        <field>
                            <name>MONCOMB</name>
                            <description>Combination Result Monitor</description>
                            <lsb>0</lsb>
                            <msb>0</msb>
                            <access>read-only</access>
                            <enumeratedValues>
                                <enumeratedValue>
                                    <name>0</name>
                                    <description>Window A/B composite conditions are not met.</description>
                                    <value>#0</value>
                                </enumeratedValue>
                                <enumeratedValue>
                                    <name>1</name>
                                    <description>Window A/B composite conditions are met.</description>
                                    <value>#1</value>
                                </enumeratedValue>
                            </enumeratedValues>
                        </field>
                        <field>
                            <name>MONCMPA</name>
                            <description>Comparison Result Monitor A</description>
                            <lsb>4</lsb>
                            <msb>4</msb>
                            <access>read-only</access>
                            <enumeratedValues>
                                <enumeratedValue>
                                    <name>0</name>
                                    <description>Window A comparison conditions are not met.</description>
                                    <value>#0</value>
                                </enumeratedValue>
                                <enumeratedValue>
                                    <name>1</name>
                                    <description>Window A comparison conditions are met.</description>
                                    <value>#1</value>
                                </enumeratedValue>
                            </enumeratedValues>
                        </field>
                        <field>
                            <name>MONCMPB</name>
                            <description>Comparison Result Monitor B</description>
                            <lsb>5</lsb>
                            <msb>5</msb>
                            <access>read-only</access>
                            <enumeratedValues>
                                <enumeratedValue>
                                    <name>0</name>
                                    <description>Window B comparison conditions are not met.</description>
                                    <value>#0</value>
                                </enumeratedValue>
                                <enumeratedValue>
                                    <name>1</name>
                                    <description>Window B comparison conditions are met.</description>
                                    <value>#1</value>
                                </enumeratedValue>
                            </enumeratedValues>
                        </field>
                    </fields>
                </register>
                <register>
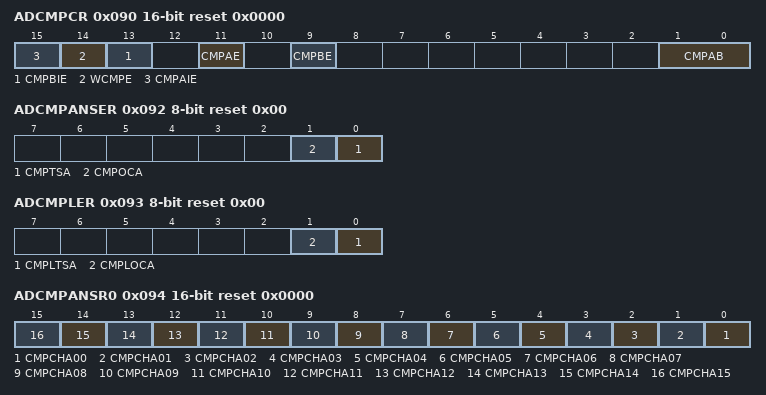
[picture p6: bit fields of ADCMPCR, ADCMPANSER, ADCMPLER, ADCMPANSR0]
                    <name>ADCMPCR</name>
                    <description>A/D Compare Function Control Register</description>
                    <addressOffset>0x090</addressOffset>
                    <size>16</size>
                    <access>read-write</access>
                    <resetValue>0x0000</resetValue>
                    <resetMask>0xffff</resetMask>
                    <fields>
                        <field>
                            <name>CMPAB</name>
                            <description>Window A/B Composite Conditions Setting</description>
                            <lsb>0</lsb>
                            <msb>1</msb>
                            <access>read-write</access>
                            <enumeratedValues>
                                <enumeratedValue>
                                    <name>00</name>
                                    <description>Output ADC12i_WCMPM (i = 0, 1) when window A OR window B comparison conditions are met. Otherwise, output ADC12i_WCMPUM (i = 0, 1).</description>
                                    <value>#00</value>
                                </enumeratedValue>
                                <enumeratedValue>
                                    <name>01</name>
                                    <description>Output ADC12i_WCMPM (i = 0, 1) when window A EXOR window B comparison conditions are met. Otherwise, output ADC12i_WCMPUM (i = 0, 1).</description>
                                    <value>#01</value>
                                </enumeratedValue>
                                <enumeratedValue>
                                    <name>10</name>
                                    <description>Output ADC12i_WCMPM (i = 0, 1) when window A AND window B comparison conditions are met. Otherwise, output ADC12i_WCMPUM (i = 0, 1).</description>
                                    <value>#10</value>
                                </enumeratedValue>
                                <enumeratedValue>
                                    <name>11</name>
                                    <description>Setting prohibited.</description>
                                    <value>#11</value>
                                </enumeratedValue>
                            </enumeratedValues>
                        </field>
                        <field>
                            <name>CMPBE</name>
                            <description>Compare Window B Operation Enable</description>
                            <lsb>9</lsb>
                            <msb>9</msb>
                            <access>read-write</access>
                            <enumeratedValues>
                                <enumeratedValue>
                                    <name>0</name>
                                    <description>Disable compare window B operation. Disable ADC12i_WCMPM (i = 0, 1) and ADC12i_WCMPUM (i = 0, 1) outputs. </description>
                                    <value>#0</value>
                                </enumeratedValue>
                                <enumeratedValue>
                                    <name>1</name>
                                    <description>Enable compare window B operation.</description>
                                    <value>#1</value>
                                </enumeratedValue>
                            </enumeratedValues>
                        </field>
                        <field>
                            <name>CMPAE</name>
                            <description>Compare Window A Operation Enable</description>
                            <lsb>11</lsb>
                            <msb>11</msb>
                            <access>read-write</access>
                            <enumeratedValues>
                                <enumeratedValue>
                                    <name>0</name>
                                    <description>Disable compare window A operation. Disable ADC12i_WCMPM (i = 0, 1) and ADC12i_WCMPUM (i = 0, 1) outputs. </description>
                                    <value>#0</value>
                                </enumeratedValue>
                                <enumeratedValue>
                                    <name>1</name>
                                    <description>Enable compare window A operation.</description>
                                    <value>#1</value>
                                </enumeratedValue>
                            </enumeratedValues>
                        </field>
                        <field>
                            <name>CMPBIE</name>
                            <description>Compare B Interrupt Enable</description>
                            <lsb>13</lsb>
                            <msb>13</msb>
                            <access>read-write</access>
                            <enumeratedValues>
                                <enumeratedValue>
                                    <name>0</name>
                                    <description>Disable ADC12i_CMPBI (i = 0, 1) interrupt when comparison conditions (window B) are met.</description>
                                    <value>#0</value>
                                </enumeratedValue>
                                <enumeratedValue>
                                    <name>1</name>
                                    <description>Enable ADC12i_CMPBI (i = 0, 1) interrupt when comparison conditions (window B) are met.</description>
                                    <value>#1</value>
                                </enumeratedValue>
                            </enumeratedValues>
                        </field>
                        <field>
                            <name>WCMPE</name>
                            <description>Window Function Setting</description>
                            <lsb>14</lsb>
                            <msb>14</msb>
                            <access>read-write</access>
                            <enumeratedValues>
                                <enumeratedValue>
                                    <name>0</name>
                                    <description>Disable window function Window A and window B operate as a comparator to compare the single value on the lower side with the A/D conversion result. </description>
                                    <value>#0</value>
                                </enumeratedValue>
                                <enumeratedValue>
                                    <name>1</name>
                                    <description>Enable window function Window A and window B operate as a comparator to compare the two values on the upper and lower sides with the A/D conversion result. </description>
                                    <value>#1</value>
                                </enumeratedValue>
                            </enumeratedValues>
                        </field>
                        <field>
                            <name>CMPAIE</name>
                            <description>Compare A Interrupt Enable</description>
                            <lsb>15</lsb>
                            <msb>15</msb>
                            <access>read-write</access>
                            <enumeratedValues>
                                <enumeratedValue>
                                    <name>0</name>
                                    <description>Disable ADC12i_CMPAI (i = 0, 1) interrupt when comparison conditions (window A) are met.</description>
                                    <value>#0</value>
                                </enumeratedValue>
                                <enumeratedValue>
                                    <name>1</name>
                                    <description>Enable ADC12i_CMPAI (i = 0, 1) interrupt when comparison conditions (window A) are met.</description>
                                    <value>#1</value>
                                </enumeratedValue>
                            </enumeratedValues>
                        </field>
                    </fields>
                </register>
                <register>
                    <name>ADCMPANSER</name>
                    <description>A/D Compare Function Window A Extended Input Select Register</description>
                    <addressOffset>0x092</addressOffset>
                    <size>8</size>
                    <access>read-write</access>
                    <resetValue>0x00</resetValue>
                    <resetMask>0xff</resetMask>
                    <fields>
                        <field>
                            <name>CMPTSA</name>
                            <description>Temperature Sensor Output Compare Select</description>
                            <lsb>0</lsb>
                            <msb>0</msb>
                            <access>read-write</access>
                            <enumeratedValues>
                                <enumeratedValue>
                                    <name>0</name>
                                    <description>Exclude the temperature sensor output from the compare Window A target range.</description>
                                    <value>#0</value>
                                </enumeratedValue>
                                <enumeratedValue>
                                    <name>1</name>
                                    <description>Include the temperature sensor output in the compare Window A target range.</description>
                                    <value>#1</value>
                                </enumeratedValue>
                            </enumeratedValues>
                        </field>
                        <field>
                            <name>CMPOCA</name>
                            <description>Internal Reference Voltage Compare Select</description>
                            <lsb>1</lsb>
                            <msb>1</msb>
                            <access>read-write</access>
                            <enumeratedValues>
                                <enumeratedValue>
                                    <name>0</name>
                                    <description>Exclude the internal reference voltage from the compare Window A target range.</description>
                                    <value>#0</value>
                                </enumeratedValue>
                                <enumeratedValue>
                                    <name>1</name>
                                    <description>Include the internal reference voltage in the compare Window A target range. </description>
                                    <value>#1</value>
                                </enumeratedValue>
                            </enumeratedValues>
                        </field>
                    </fields>
                </register>
                <register>
                    <name>ADCMPLER</name>
                    <description>A/D Compare Function Window A Extended Input Comparison Condition Setting Register</description>
                    <addressOffset>0x093</addressOffset>
                    <size>8</size>
                    <access>read-write</access>
                    <resetValue>0x00</resetValue>
                    <resetMask>0xff</resetMask>
                    <fields>
                        <field>
                            <name>CMPLTSA</name>
                            <description>Compare Window A Temperature Sensor Output Comparison Condition Select</description>
                            <lsb>0</lsb>
                            <msb>0</msb>
                            <access>read-write</access>
                            <enumeratedValues>
                                <enumeratedValue>
                                    <name>0</name>
                                    <description>When window function is disabled (ADCMPCR.WCMPE = 0) : ADCMPDR0 value &gt; A/D-converted valueCompare Window A Temperature Sensor Output Comparison Condition Select When window function is enabled (ADCMPCR.WCMPE = 1) : Compare Window A Temperature Sensor Output Comparison ConditionA/D-converted value &lt; ADCMPDR0 value, or A/D-converted value &gt; ADCMPDR1 value </description>
                                    <value>#0</value>
                                </enumeratedValue>
                                <enumeratedValue>
                                    <name>1</name>
                                    <description>When window function is disabled (ADCMPCR.WCMPE = 0) : ADCMPDR0 value &lt; A/D-converted value When window function is enabled (ADCMPCR.WCMPE = 1) : ADCMPDR0 value &lt; A/D-converted value &lt; ADCMPDR1 value </description>
                                    <value>#1</value>
                                </enumeratedValue>
                            </enumeratedValues>
                        </field>
                        <field>
                            <name>CMPLOCA</name>
                            <description>Compare Window A Internal Reference Voltage Comparison Condition Select</description>
                            <lsb>1</lsb>
                            <msb>1</msb>
                            <access>read-write</access>
                            <enumeratedValues>
                                <enumeratedValue>
                                    <name>0</name>
                                    <description>When window function is disabled (ADCMPCR.WCMPE = 0) : ADCMPDR0 value &gt; A/D-converted value When window function is enabled (ADCMPCR.WCMPE = 1): A/D-converted value &lt; ADCMPDR0 value, or A/D-converted value &gt; ADCMPDR1 value </description>
                                    <value>#0</value>
                                </enumeratedValue>
                                <enumeratedValue>
                                    <name>1</name>
                                    <description>When window function is disabled (ADCMPCR.WCMPE = 0): ADCMPDR0 value &lt; A/D-converted value When window function is enabled (ADCMPCR.WCMPE = 1): ADCMPDR0 value &lt; A/D-converted value &lt; ADCMPDR1 value </description>
                                    <value>#1</value>
                                </enumeratedValue>
                            </enumeratedValues>
                        </field>
                    </fields>
                </register>
                <register>
                    <name>ADCMPANSR0</name>
                    <description>A/D Compare Function Window A Channel Select Register 0</description>
                    <addressOffset>0x094</addressOffset>
                    <size>16</size>
                    <access>read-write</access>
                    <resetValue>0x0000</resetValue>
                    <resetMask>0xffff</resetMask>
                    <fields>
                        <field>
                            <name>CMPCHA00</name>
                            <description>Compare Window A Channel Select</description>
                            <lsb>0</lsb>
                            <msb>0</msb>
                            <access>read-write</access>
                            <enumeratedValues>
                                <enumeratedValue>
                                    <name>0</name>
                                    <description>Disable compare function for associated input channel</description>
                                    <value>#0</value>
                                </enumeratedValue>
                                <enumeratedValue>
                                    <name>1</name>
                                    <description>Enable compare function for associated input channel</description>
                                    <value>#1</value>
                                </enumeratedValue>
                            </enumeratedValues>
                        </field>
                        <field>
                            <name>CMPCHA01</name>
                            <description>Compare Window A Channel Select</description>
                            <lsb>1</lsb>
                            <msb>1</msb>
                            <access>read-write</access>
                            <enumeratedValues>
                                <enumeratedValue>
                                    <name>0</name>
                                    <description>Disable compare function for associated input channel</description>
                                    <value>#0</value>
                                </enumeratedValue>
                                <enumeratedValue>
                                    <name>1</name>
                                    <description>Enable compare function for associated input channel</description>
                                    <value>#1</value>
                                </enumeratedValue>
                            </enumeratedValues>
                        </field>
                        <field>
                            <name>CMPCHA02</name>
                            <description>Compare Window A Channel Select</description>
                            <lsb>2</lsb>
                            <msb>2</msb>
                            <access>read-write</access>
                            <enumeratedValues>
                                <enumeratedValue>
                                    <name>0</name>
                                    <description>Disable compare function for associated input channel</description>
                                    <value>#0</value>
                                </enumeratedValue>
                                <enumeratedValue>
                                    <name>1</name>
                                    <description>Enable compare function for associated input channel</description>
                                    <value>#1</value>
                                </enumeratedValue>
                            </enumeratedValues>
                        </field>
                        <field>
                            <name>CMPCHA03</name>
                            <description>Compare Window A Channel Select</description>
                            <lsb>3</lsb>
                            <msb>3</msb>
                            <access>read-write</access>
                            <enumeratedValues>
                                <enumeratedValue>
                                    <name>0</name>
                                    <description>Disable compare function for associated input channel</description>
                                    <value>#0</value>
                                </enumeratedValue>
                                <enumeratedValue>
                                    <name>1</name>
                                    <description>Enable compare function for associated input channel</description>
                                    <value>#1</value>
                                </enumeratedValue>
                            </enumeratedValues>
                        </field>
                        <field>
                            <name>CMPCHA04</name>
                            <description>Compare Window A Channel Select</description>
                            <lsb>4</lsb>
                            <msb>4</msb>
                            <access>read-write</access>
                            <enumeratedValues>
                                <enumeratedValue>
                                    <name>0</name>
                                    <description>Disable compare function for associated input channel</description>
                                    <value>#0</value>
                                </enumeratedValue>
                                <enumeratedValue>
                                    <name>1</name>
                                    <description>Enable compare function for associated input channel</description>
                                    <value>#1</value>
                                </enumeratedValue>
                            </enumeratedValues>
                        </field>
                        <field>
                            <name>CMPCHA05</name>
                            <description>Compare Window A Channel Select</description>
                            <lsb>5</lsb>
                            <msb>5</msb>
                            <access>read-write</access>
                            <enumeratedValues>
                                <enumeratedValue>
                                    <name>0</name>
                                    <description>Disable compare function for associated input channel</description>
                                    <value>#0</value>
                                </enumeratedValue>
                                <enumeratedValue>
                                    <name>1</name>
                                    <description>Enable compare function for associated input channel</description>
                                    <value>#1</value>
                                </enumeratedValue>
                            </enumeratedValues>
                        </field>
                        <field>
                            <name>CMPCHA06</name>
                            <description>Compare Window A Channel Select</description>
                            <lsb>6</lsb>
                            <msb>6</msb>
                            <access>read-write</access>
                            <enumeratedValues>
                                <enumeratedValue>
                                    <name>0</name>
                                    <description>Disable compare function for associated input channel</description>
                                    <value>#0</value>
                                </enumeratedValue>
                                <enumeratedValue>
                                    <name>1</name>
                                    <description>Enable compare function for associated input channel</description>
                                    <value>#1</value>
                                </enumeratedValue>
                            </enumeratedValues>
                        </field>
                        <field>
                            <name>CMPCHA07</name>
                            <description>Compare Window A Channel Select</description>
                            <lsb>7</lsb>
                            <msb>7</msb>
                            <access>read-write</access>
                            <enumeratedValues>
                                <enumeratedValue>
                                    <name>0</name>
                                    <description>Disable compare function for associated input channel</description>
                                    <value>#0</value>
                                </enumeratedValue>
                                <enumeratedValue>
                                    <name>1</name>
                                    <description>Enable compare function for associated input channel</description>
                                    <value>#1</value>
                                </enumeratedValue>
                            </enumeratedValues>
                        </field>
                        <field>
                            <name>CMPCHA08</name>
                            <description>Compare Window A Channel Select</description>
                            <lsb>8</lsb>
                            <msb>8</msb>
                            <access>read-write</access>
                            <enumeratedValues>
                                <enumeratedValue>
                                    <name>0</name>
                                    <description>Disable compare function for associated input channel</description>
                                    <value>#0</value>
                                </enumeratedValue>
                                <enumeratedValue>
                                    <name>1</name>
                                    <description>Enable compare function for associated input channel</description>
                                    <value>#1</value>
                                </enumeratedValue>
                            </enumeratedValues>
                        </field>
                        <field>
                            <name>CMPCHA09</name>
                            <description>Compare Window A Channel Select</description>
                            <lsb>9</lsb>
                            <msb>9</msb>
                            <access>read-write</access>
                            <enumeratedValues>
                                <enumeratedValue>
                                    <name>0</name>
                                    <description>Disable compare function for associated input channel</description>
                                    <value>#0</value>
                                </enumeratedValue>
                                <enumeratedValue>
                                    <name>1</name>
                                    <description>Enable compare function for associated input channel</description>
                                    <value>#1</value>
                                </enumeratedValue>
                            </enumeratedValues>
                        </field>
                        <field>
                            <name>CMPCHA10</name>
                            <description>Compare Window A Channel Select</description>
                            <lsb>10</lsb>
                            <msb>10</msb>
                            <access>read-write</access>
                            <enumeratedValues>
                                <enumeratedValue>
                                    <name>0</name>
                                    <description>Disable compare function for associated input channel</description>
                                    <value>#0</value>
                                </enumeratedValue>
                                <enumeratedValue>
                                    <name>1</name>
                                    <description>Enable compare function for associated input channel</description>
                                    <value>#1</value>
                                </enumeratedValue>
                            </enumeratedValues>
                        </field>
                        <field>
                            <name>CMPCHA11</name>
                            <description>Compare Window A Channel Select</description>
                            <lsb>11</lsb>
                            <msb>11</msb>
                            <access>read-write</access>
                            <enumeratedValues>
                                <enumeratedValue>
                                    <name>0</name>
                                    <description>Disable compare function for associated input channel</description>
                                    <value>#0</value>
                                </enumeratedValue>
                                <enumeratedValue>
                                    <name>1</name>
                                    <description>Enable compare function for associated input channel</description>
                                    <value>#1</value>
                                </enumeratedValue>
                            </enumeratedValues>
                        </field>
                        <field>
                            <name>CMPCHA12</name>
                            <description>Compare Window A Channel Select</description>
                            <lsb>12</lsb>
                            <msb>12</msb>
                            <access>read-write</access>
                            <enumeratedValues>
                                <enumeratedValue>
                                    <name>0</name>
                                    <description>Disable compare function for associated input channel</description>
                                    <value>#0</value>
                                </enumeratedValue>
                                <enumeratedValue>
                                    <name>1</name>
                                    <description>Enable compare function for associated input channel</description>
                                    <value>#1</value>
                                </enumeratedValue>
                            </enumeratedValues>
                        </field>
                        <field>
                            <name>CMPCHA13</name>
                            <description>Compare Window A Channel Select</description>
                            <lsb>13</lsb>
                            <msb>13</msb>
                            <access>read-write</access>
                            <enumeratedValues>
                                <enumeratedValue>
                                    <name>0</name>
                                    <description>Disable compare function for associated input channel</description>
                                    <value>#0</value>
                                </enumeratedValue>
                                <enumeratedValue>
                                    <name>1</name>
                                    <description>Enable compare function for associated input channel</description>
                                    <value>#1</value>
                                </enumeratedValue>
                            </enumeratedValues>
                        </field>
                        <field>
                            <name>CMPCHA14</name>
                            <description>Compare Window A Channel Select</description>
                            <lsb>14</lsb>
                            <msb>14</msb>
                            <access>read-write</access>
                            <enumeratedValues>
                                <enumeratedValue>
                                    <name>0</name>
                                    <description>Disable compare function for associated input channel</description>
                                    <value>#0</value>
                                </enumeratedValue>
                                <enumeratedValue>
                                    <name>1</name>
                                    <description>Enable compare function for associated input channel</description>
                                    <value>#1</value>
                                </enumeratedValue>
                            </enumeratedValues>
                        </field>
                        <field>
                            <name>CMPCHA15</name>
                            <description>Compare Window A Channel Select</description>
                            <lsb>15</lsb>
                            <msb>15</msb>
                            <access>read-write</access>
                            <enumeratedValues>
                                <enumeratedValue>
                                    <name>0</name>
                                    <description>Disable compare function for associated input channel</description>
                                    <value>#0</value>
                                </enumeratedValue>
                                <enumeratedValue>
                                    <name>1</name>
                                    <description>Enable compare function for associated input channel</description>
                                    <value>#1</value>
                                </enumeratedValue>
                            </enumeratedValues>
                        </field>
                    </fields>
                </register>
                <register>
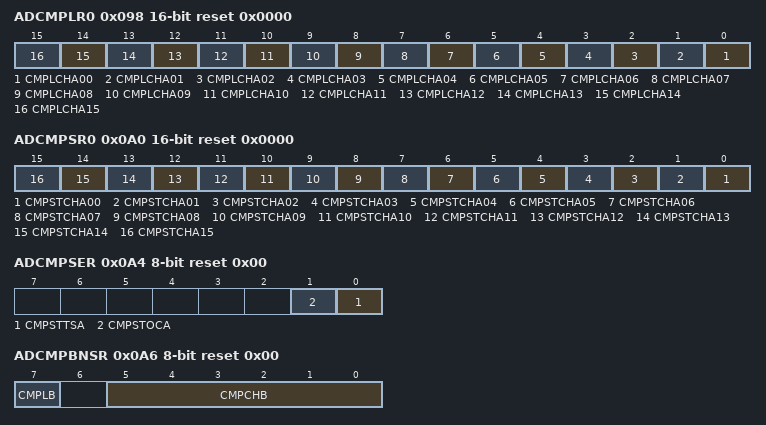
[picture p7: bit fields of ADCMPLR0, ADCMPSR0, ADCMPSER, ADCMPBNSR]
                    <name>ADCMPLR0</name>
                    <description>A/D Compare Function Window A Comparison Condition Setting Register 0</description>
                    <addressOffset>0x098</addressOffset>
                    <size>16</size>
                    <access>read-write</access>
                    <resetValue>0x0000</resetValue>
                    <resetMask>0xffff</resetMask>
                    <fields>
                        <field>
                            <name>CMPLCHA00</name>
                            <description>Compare Window A Comparison Condition Select</description>
                            <lsb>0</lsb>
                            <msb>0</msb>
                            <access>read-write</access>
                            <enumeratedValues>
                                <enumeratedValue>
                                    <name>0</name>
                                    <description>When window function is disabled (ADCMPCR.WCMPE = 0): ADCMPDR0 value &gt; A/D-converted value When window function is enabled (ADCMPCR.WCMPE = 1): A/D-converted value &lt; ADCMPDR0 value, or ADCMPDR1 value &lt; A/D-converted value </description>
                                    <value>#0</value>
                                </enumeratedValue>
                                <enumeratedValue>
                                    <name>1</name>
                                    <description>When window function is disabled (ADCMPCR.WCMPE = 0): ADCMPDR0 value &lt; A/D-converted value When window function is enabled (ADCMPCR.WCMPE = 1): ADCMPDR0 value &lt; A/D-converted value &lt; ADCMPDR1 value </description>
                                    <value>#1</value>
                                </enumeratedValue>
                            </enumeratedValues>
                        </field>
                        <field>
                            <name>CMPLCHA01</name>
                            <description>Compare Window A Comparison Condition Select</description>
                            <lsb>1</lsb>
                            <msb>1</msb>
                            <access>read-write</access>
                            <enumeratedValues>
                                <enumeratedValue>
                                    <name>0</name>
                                    <description>When window function is disabled (ADCMPCR.WCMPE = 0): ADCMPDR0 value &gt; A/D-converted value When window function is enabled (ADCMPCR.WCMPE = 1): A/D-converted value &lt; ADCMPDR0 value, or ADCMPDR1 value &lt; A/D-converted value </description>
                                    <value>#0</value>
                                </enumeratedValue>
                                <enumeratedValue>
                                    <name>1</name>
                                    <description>When window function is disabled (ADCMPCR.WCMPE = 0): ADCMPDR0 value &lt; A/D-converted value When window function is enabled (ADCMPCR.WCMPE = 1): ADCMPDR0 value &lt; A/D-converted value &lt; ADCMPDR1 value </description>
                                    <value>#1</value>
                                </enumeratedValue>
                            </enumeratedValues>
                        </field>
                        <field>
                            <name>CMPLCHA02</name>
                            <description>Compare Window A Comparison Condition Select</description>
                            <lsb>2</lsb>
                            <msb>2</msb>
                            <access>read-write</access>
                            <enumeratedValues>
                                <enumeratedValue>
                                    <name>0</name>
                                    <description>When window function is disabled (ADCMPCR.WCMPE = 0): ADCMPDR0 value &gt; A/D-converted value When window function is enabled (ADCMPCR.WCMPE = 1): A/D-converted value &lt; ADCMPDR0 value, or ADCMPDR1 value &lt; A/D-converted value </description>
                                    <value>#0</value>
                                </enumeratedValue>
                                <enumeratedValue>
                                    <name>1</name>
                                    <description>When window function is disabled (ADCMPCR.WCMPE = 0): ADCMPDR0 value &lt; A/D-converted value When window function is enabled (ADCMPCR.WCMPE = 1): ADCMPDR0 value &lt; A/D-converted value &lt; ADCMPDR1 value </description>
                                    <value>#1</value>
                                </enumeratedValue>
                            </enumeratedValues>
                        </field>
                        <field>
                            <name>CMPLCHA03</name>
                            <description>Compare Window A Comparison Condition Select</description>
                            <lsb>3</lsb>
                            <msb>3</msb>
                            <access>read-write</access>
                            <enumeratedValues>
                                <enumeratedValue>
                                    <name>0</name>
                                    <description>When window function is disabled (ADCMPCR.WCMPE = 0): ADCMPDR0 value &gt; A/D-converted value When window function is enabled (ADCMPCR.WCMPE = 1): A/D-converted value &lt; ADCMPDR0 value, or ADCMPDR1 value &lt; A/D-converted value </description>
                                    <value>#0</value>
                                </enumeratedValue>
                                <enumeratedValue>
                                    <name>1</name>
                                    <description>When window function is disabled (ADCMPCR.WCMPE = 0): ADCMPDR0 value &lt; A/D-converted value When window function is enabled (ADCMPCR.WCMPE = 1): ADCMPDR0 value &lt; A/D-converted value &lt; ADCMPDR1 value </description>
                                    <value>#1</value>
                                </enumeratedValue>
                            </enumeratedValues>
                        </field>
                        <field>
                            <name>CMPLCHA04</name>
                            <description>Compare Window A Comparison Condition Select</description>
                            <lsb>4</lsb>
                            <msb>4</msb>
                            <access>read-write</access>
                            <enumeratedValues>
                                <enumeratedValue>
                                    <name>0</name>
                                    <description>When window function is disabled (ADCMPCR.WCMPE = 0): ADCMPDR0 value &gt; A/D-converted value When window function is enabled (ADCMPCR.WCMPE = 1): A/D-converted value &lt; ADCMPDR0 value, or ADCMPDR1 value &lt; A/D-converted value </description>
                                    <value>#0</value>
                                </enumeratedValue>
                                <enumeratedValue>
                                    <name>1</name>
                                    <description>When window function is disabled (ADCMPCR.WCMPE = 0): ADCMPDR0 value &lt; A/D-converted value When window function is enabled (ADCMPCR.WCMPE = 1): ADCMPDR0 value &lt; A/D-converted value &lt; ADCMPDR1 value </description>
                                    <value>#1</value>
                                </enumeratedValue>
                            </enumeratedValues>
                        </field>
                        <field>
                            <name>CMPLCHA05</name>
                            <description>Compare Window A Comparison Condition Select</description>
                            <lsb>5</lsb>
                            <msb>5</msb>
                            <access>read-write</access>
                            <enumeratedValues>
                                <enumeratedValue>
                                    <name>0</name>
                                    <description>When window function is disabled (ADCMPCR.WCMPE = 0): ADCMPDR0 value &gt; A/D-converted value When window function is enabled (ADCMPCR.WCMPE = 1): A/D-converted value &lt; ADCMPDR0 value, or ADCMPDR1 value &lt; A/D-converted value </description>
                                    <value>#0</value>
                                </enumeratedValue>
                                <enumeratedValue>
                                    <name>1</name>
                                    <description>When window function is disabled (ADCMPCR.WCMPE = 0): ADCMPDR0 value &lt; A/D-converted value When window function is enabled (ADCMPCR.WCMPE = 1): ADCMPDR0 value &lt; A/D-converted value &lt; ADCMPDR1 value </description>
                                    <value>#1</value>
                                </enumeratedValue>
                            </enumeratedValues>
                        </field>
                        <field>
                            <name>CMPLCHA06</name>
                            <description>Compare Window A Comparison Condition Select</description>
                            <lsb>6</lsb>
                            <msb>6</msb>
                            <access>read-write</access>
                            <enumeratedValues>
                                <enumeratedValue>
                                    <name>0</name>
                                    <description>When window function is disabled (ADCMPCR.WCMPE = 0): ADCMPDR0 value &gt; A/D-converted value When window function is enabled (ADCMPCR.WCMPE = 1): A/D-converted value &lt; ADCMPDR0 value, or ADCMPDR1 value &lt; A/D-converted value </description>
                                    <value>#0</value>
                                </enumeratedValue>
                                <enumeratedValue>
                                    <name>1</name>
                                    <description>When window function is disabled (ADCMPCR.WCMPE = 0): ADCMPDR0 value &lt; A/D-converted value When window function is enabled (ADCMPCR.WCMPE = 1): ADCMPDR0 value &lt; A/D-converted value &lt; ADCMPDR1 value </description>
                                    <value>#1</value>
                                </enumeratedValue>
                            </enumeratedValues>
                        </field>
                        <field>
                            <name>CMPLCHA07</name>
                            <description>Compare Window A Comparison Condition Select</description>
                            <lsb>7</lsb>
                            <msb>7</msb>
                            <access>read-write</access>
                            <enumeratedValues>
                                <enumeratedValue>
                                    <name>0</name>
                                    <description>When window function is disabled (ADCMPCR.WCMPE = 0): ADCMPDR0 value &gt; A/D-converted value When window function is enabled (ADCMPCR.WCMPE = 1): A/D-converted value &lt; ADCMPDR0 value, or ADCMPDR1 value &lt; A/D-converted value </description>
                                    <value>#0</value>
                                </enumeratedValue>
                                <enumeratedValue>
                                    <name>1</name>
                                    <description>When window function is disabled (ADCMPCR.WCMPE = 0): ADCMPDR0 value &lt; A/D-converted value When window function is enabled (ADCMPCR.WCMPE = 1): ADCMPDR0 value &lt; A/D-converted value &lt; ADCMPDR1 value </description>
                                    <value>#1</value>
                                </enumeratedValue>
                            </enumeratedValues>
                        </field>
                        <field>
                            <name>CMPLCHA08</name>
                            <description>Compare Window A Comparison Condition Select</description>
                            <lsb>8</lsb>
                            <msb>8</msb>
                            <access>read-write</access>
                            <enumeratedValues>
                                <enumeratedValue>
                                    <name>0</name>
                                    <description>When window function is disabled (ADCMPCR.WCMPE = 0): ADCMPDR0 value &gt; A/D-converted value When window function is enabled (ADCMPCR.WCMPE = 1): A/D-converted value &lt; ADCMPDR0 value, or ADCMPDR1 value &lt; A/D-converted value </description>
                                    <value>#0</value>
                                </enumeratedValue>
                                <enumeratedValue>
                                    <name>1</name>
                                    <description>When window function is disabled (ADCMPCR.WCMPE = 0): ADCMPDR0 value &lt; A/D-converted value When window function is enabled (ADCMPCR.WCMPE = 1): ADCMPDR0 value &lt; A/D-converted value &lt; ADCMPDR1 value </description>
                                    <value>#1</value>
                                </enumeratedValue>
                            </enumeratedValues>
                        </field>
                        <field>
                            <name>CMPLCHA09</name>
                            <description>Compare Window A Comparison Condition Select</description>
                            <lsb>9</lsb>
                            <msb>9</msb>
                            <access>read-write</access>
                            <enumeratedValues>
                                <enumeratedValue>
                                    <name>0</name>
                                    <description>When window function is disabled (ADCMPCR.WCMPE = 0): ADCMPDR0 value &gt; A/D-converted value When window function is enabled (ADCMPCR.WCMPE = 1): A/D-converted value &lt; ADCMPDR0 value, or ADCMPDR1 value &lt; A/D-converted value </description>
                                    <value>#0</value>
                                </enumeratedValue>
                                <enumeratedValue>
                                    <name>1</name>
                                    <description>When window function is disabled (ADCMPCR.WCMPE = 0): ADCMPDR0 value &lt; A/D-converted value When window function is enabled (ADCMPCR.WCMPE = 1): ADCMPDR0 value &lt; A/D-converted value &lt; ADCMPDR1 value </description>
                                    <value>#1</value>
                                </enumeratedValue>
                            </enumeratedValues>
                        </field>
                        <field>
                            <name>CMPLCHA10</name>
                            <description>Compare Window A Comparison Condition Select</description>
                            <lsb>10</lsb>
                            <msb>10</msb>
                            <access>read-write</access>
                            <enumeratedValues>
                                <enumeratedValue>
                                    <name>0</name>
                                    <description>When window function is disabled (ADCMPCR.WCMPE = 0): ADCMPDR0 value &gt; A/D-converted value When window function is enabled (ADCMPCR.WCMPE = 1): A/D-converted value &lt; ADCMPDR0 value, or ADCMPDR1 value &lt; A/D-converted value </description>
                                    <value>#0</value>
                                </enumeratedValue>
                                <enumeratedValue>
                                    <name>1</name>
                                    <description>When window function is disabled (ADCMPCR.WCMPE = 0): ADCMPDR0 value &lt; A/D-converted value When window function is enabled (ADCMPCR.WCMPE = 1): ADCMPDR0 value &lt; A/D-converted value &lt; ADCMPDR1 value </description>
                                    <value>#1</value>
                                </enumeratedValue>
                            </enumeratedValues>
                        </field>
                        <field>
                            <name>CMPLCHA11</name>
                            <description>Compare Window A Comparison Condition Select</description>
                            <lsb>11</lsb>
                            <msb>11</msb>
                            <access>read-write</access>
                            <enumeratedValues>
                                <enumeratedValue>
                                    <name>0</name>
                                    <description>When window function is disabled (ADCMPCR.WCMPE = 0): ADCMPDR0 value &gt; A/D-converted value When window function is enabled (ADCMPCR.WCMPE = 1): A/D-converted value &lt; ADCMPDR0 value, or ADCMPDR1 value &lt; A/D-converted value </description>
                                    <value>#0</value>
                                </enumeratedValue>
                                <enumeratedValue>
                                    <name>1</name>
                                    <description>When window function is disabled (ADCMPCR.WCMPE = 0): ADCMPDR0 value &lt; A/D-converted value When window function is enabled (ADCMPCR.WCMPE = 1): ADCMPDR0 value &lt; A/D-converted value &lt; ADCMPDR1 value </description>
                                    <value>#1</value>
                                </enumeratedValue>
                            </enumeratedValues>
                        </field>
                        <field>
                            <name>CMPLCHA12</name>
                            <description>Compare Window A Comparison Condition Select</description>
                            <lsb>12</lsb>
                            <msb>12</msb>
                            <access>read-write</access>
                            <enumeratedValues>
                                <enumeratedValue>
                                    <name>0</name>
                                    <description>When window function is disabled (ADCMPCR.WCMPE = 0): ADCMPDR0 value &gt; A/D-converted value When window function is enabled (ADCMPCR.WCMPE = 1): A/D-converted value &lt; ADCMPDR0 value, or ADCMPDR1 value &lt; A/D-converted value </description>
                                    <value>#0</value>
                                </enumeratedValue>
                                <enumeratedValue>
                                    <name>1</name>
                                    <description>When window function is disabled (ADCMPCR.WCMPE = 0): ADCMPDR0 value &lt; A/D-converted value When window function is enabled (ADCMPCR.WCMPE = 1): ADCMPDR0 value &lt; A/D-converted value &lt; ADCMPDR1 value </description>
                                    <value>#1</value>
                                </enumeratedValue>
                            </enumeratedValues>
                        </field>
                        <field>
                            <name>CMPLCHA13</name>
                            <description>Compare Window A Comparison Condition Select</description>
                            <lsb>13</lsb>
                            <msb>13</msb>
                            <access>read-write</access>
                            <enumeratedValues>
                                <enumeratedValue>
                                    <name>0</name>
                                    <description>When window function is disabled (ADCMPCR.WCMPE = 0): ADCMPDR0 value &gt; A/D-converted value When window function is enabled (ADCMPCR.WCMPE = 1): A/D-converted value &lt; ADCMPDR0 value, or ADCMPDR1 value &lt; A/D-converted value </description>
                                    <value>#0</value>
                                </enumeratedValue>
                                <enumeratedValue>
                                    <name>1</name>
                                    <description>When window function is disabled (ADCMPCR.WCMPE = 0): ADCMPDR0 value &lt; A/D-converted value When window function is enabled (ADCMPCR.WCMPE = 1): ADCMPDR0 value &lt; A/D-converted value &lt; ADCMPDR1 value </description>
                                    <value>#1</value>
                                </enumeratedValue>
                            </enumeratedValues>
                        </field>
                        <field>
                            <name>CMPLCHA14</name>
                            <description>Compare Window A Comparison Condition Select</description>
                            <lsb>14</lsb>
                            <msb>14</msb>
                            <access>read-write</access>
                            <enumeratedValues>
                                <enumeratedValue>
                                    <name>0</name>
                                    <description>When window function is disabled (ADCMPCR.WCMPE = 0): ADCMPDR0 value &gt; A/D-converted value When window function is enabled (ADCMPCR.WCMPE = 1): A/D-converted value &lt; ADCMPDR0 value, or ADCMPDR1 value &lt; A/D-converted value </description>
                                    <value>#0</value>
                                </enumeratedValue>
                                <enumeratedValue>
                                    <name>1</name>
                                    <description>When window function is disabled (ADCMPCR.WCMPE = 0): ADCMPDR0 value &lt; A/D-converted value When window function is enabled (ADCMPCR.WCMPE = 1): ADCMPDR0 value &lt; A/D-converted value &lt; ADCMPDR1 value </description>
                                    <value>#1</value>
                                </enumeratedValue>
                            </enumeratedValues>
                        </field>
                        <field>
                            <name>CMPLCHA15</name>
                            <description>Compare Window A Comparison Condition Select</description>
                            <lsb>15</lsb>
                            <msb>15</msb>
                            <access>read-write</access>
                            <enumeratedValues>
                                <enumeratedValue>
                                    <name>0</name>
                                    <description>When window function is disabled (ADCMPCR.WCMPE = 0): ADCMPDR0 value &gt; A/D-converted value When window function is enabled (ADCMPCR.WCMPE = 1): A/D-converted value &lt; ADCMPDR0 value, or ADCMPDR1 value &lt; A/D-converted value </description>
                                    <value>#0</value>
                                </enumeratedValue>
                                <enumeratedValue>
                                    <name>1</name>
                                    <description>When window function is disabled (ADCMPCR.WCMPE = 0): ADCMPDR0 value &lt; A/D-converted value When window function is enabled (ADCMPCR.WCMPE = 1): ADCMPDR0 value &lt; A/D-converted value &lt; ADCMPDR1 value </description>
                                    <value>#1</value>
                                </enumeratedValue>
                            </enumeratedValues>
                        </field>
                    </fields>
                </register>
                <register>
                    <dim>2</dim>
                    <dimIncrement>0x2</dimIncrement>
                    <dimIndex>0-1</dimIndex>
                    <name>ADCMPDR%s</name>
                    <description>A/D Compare Function Window A Lower-Side/Upper-Side Level Setting Register</description>
                    <addressOffset>0x09C</addressOffset>
                    <size>16</size>
                    <access>read-write</access>
                    <resetValue>0x0000</resetValue>
                    <resetMask>0xffff</resetMask>
                </register>
                <register>
                    <name>ADCMPSR0</name>
                    <description>A/D Compare Function Window A Channel Status Register 0</description>
                    <addressOffset>0x0A0</addressOffset>
                    <size>16</size>
                    <access>read-write</access>
                    <resetValue>0x0000</resetValue>
                    <resetMask>0xffff</resetMask>
                    <fields>
                        <field>
                            <name>CMPSTCHA00</name>
                            <description>Compare Window A Flag</description>
                            <lsb>0</lsb>
                            <msb>0</msb>
                            <access>read-write</access>
                            <enumeratedValues>
                                <enumeratedValue>
                                    <name>0</name>
                                    <description>Comparison conditions are not met.</description>
                                    <value>#0</value>
                                </enumeratedValue>
                                <enumeratedValue>
                                    <name>1</name>
                                    <description>Comparison conditions are met.</description>
                                    <value>#1</value>
                                </enumeratedValue>
                            </enumeratedValues>
                        </field>
                        <field>
                            <name>CMPSTCHA01</name>
                            <description>Compare Window A Flag</description>
                            <lsb>1</lsb>
                            <msb>1</msb>
                            <access>read-write</access>
                            <enumeratedValues>
                                <enumeratedValue>
                                    <name>0</name>
                                    <description>Comparison conditions are not met.</description>
                                    <value>#0</value>
                                </enumeratedValue>
                                <enumeratedValue>
                                    <name>1</name>
                                    <description>Comparison conditions are met.</description>
                                    <value>#1</value>
                                </enumeratedValue>
                            </enumeratedValues>
                        </field>
                        <field>
                            <name>CMPSTCHA02</name>
                            <description>Compare Window A Flag</description>
                            <lsb>2</lsb>
                            <msb>2</msb>
                            <access>read-write</access>
                            <enumeratedValues>
                                <enumeratedValue>
                                    <name>0</name>
                                    <description>Comparison conditions are not met.</description>
                                    <value>#0</value>
                                </enumeratedValue>
                                <enumeratedValue>
                                    <name>1</name>
                                    <description>Comparison conditions are met.</description>
                                    <value>#1</value>
                                </enumeratedValue>
                            </enumeratedValues>
                        </field>
                        <field>
                            <name>CMPSTCHA03</name>
                            <description>Compare Window A Flag</description>
                            <lsb>3</lsb>
                            <msb>3</msb>
                            <access>read-write</access>
                            <enumeratedValues>
                                <enumeratedValue>
                                    <name>0</name>
                                    <description>Comparison conditions are not met.</description>
                                    <value>#0</value>
                                </enumeratedValue>
                                <enumeratedValue>
                                    <name>1</name>
                                    <description>Comparison conditions are met.</description>
                                    <value>#1</value>
                                </enumeratedValue>
                            </enumeratedValues>
                        </field>
                        <field>
                            <name>CMPSTCHA04</name>
                            <description>Compare Window A Flag</description>
                            <lsb>4</lsb>
                            <msb>4</msb>
                            <access>read-write</access>
                            <enumeratedValues>
                                <enumeratedValue>
                                    <name>0</name>
                                    <description>Comparison conditions are not met.</description>
                                    <value>#0</value>
                                </enumeratedValue>
                                <enumeratedValue>
                                    <name>1</name>
                                    <description>Comparison conditions are met.</description>
                                    <value>#1</value>
                                </enumeratedValue>
                            </enumeratedValues>
                        </field>
                        <field>
                            <name>CMPSTCHA05</name>
                            <description>Compare Window A Flag</description>
                            <lsb>5</lsb>
                            <msb>5</msb>
                            <access>read-write</access>
                            <enumeratedValues>
                                <enumeratedValue>
                                    <name>0</name>
                                    <description>Comparison conditions are not met.</description>
                                    <value>#0</value>
                                </enumeratedValue>
                                <enumeratedValue>
                                    <name>1</name>
                                    <description>Comparison conditions are met.</description>
                                    <value>#1</value>
                                </enumeratedValue>
                            </enumeratedValues>
                        </field>
                        <field>
                            <name>CMPSTCHA06</name>
                            <description>Compare Window A Flag</description>
                            <lsb>6</lsb>
                            <msb>6</msb>
                            <access>read-write</access>
                            <enumeratedValues>
                                <enumeratedValue>
                                    <name>0</name>
                                    <description>Comparison conditions are not met.</description>
                                    <value>#0</value>
                                </enumeratedValue>
                                <enumeratedValue>
                                    <name>1</name>
                                    <description>Comparison conditions are met.</description>
                                    <value>#1</value>
                                </enumeratedValue>
                            </enumeratedValues>
                        </field>
                        <field>
                            <name>CMPSTCHA07</name>
                            <description>Compare Window A Flag</description>
                            <lsb>7</lsb>
                            <msb>7</msb>
                            <access>read-write</access>
                            <enumeratedValues>
                                <enumeratedValue>
                                    <name>0</name>
                                    <description>Comparison conditions are not met.</description>
                                    <value>#0</value>
                                </enumeratedValue>
                                <enumeratedValue>
                                    <name>1</name>
                                    <description>Comparison conditions are met.</description>
                                    <value>#1</value>
                                </enumeratedValue>
                            </enumeratedValues>
                        </field>
                        <field>
                            <name>CMPSTCHA08</name>
                            <description>Compare Window A Flag</description>
                            <lsb>8</lsb>
                            <msb>8</msb>
                            <access>read-write</access>
                            <enumeratedValues>
                                <enumeratedValue>
                                    <name>0</name>
                                    <description>Comparison conditions are not met.</description>
                                    <value>#0</value>
                                </enumeratedValue>
                                <enumeratedValue>
                                    <name>1</name>
                                    <description>Comparison conditions are met.</description>
                                    <value>#1</value>
                                </enumeratedValue>
                            </enumeratedValues>
                        </field>
                        <field>
                            <name>CMPSTCHA09</name>
                            <description>Compare Window A Flag</description>
                            <lsb>9</lsb>
                            <msb>9</msb>
                            <access>read-write</access>
                            <enumeratedValues>
                                <enumeratedValue>
                                    <name>0</name>
                                    <description>Comparison conditions are not met.</description>
                                    <value>#0</value>
                                </enumeratedValue>
                                <enumeratedValue>
                                    <name>1</name>
                                    <description>Comparison conditions are met.</description>
                                    <value>#1</value>
                                </enumeratedValue>
                            </enumeratedValues>
                        </field>
                        <field>
                            <name>CMPSTCHA10</name>
                            <description>Compare Window A Flag</description>
                            <lsb>10</lsb>
                            <msb>10</msb>
                            <access>read-write</access>
                            <enumeratedValues>
                                <enumeratedValue>
                                    <name>0</name>
                                    <description>Comparison conditions are not met.</description>
                                    <value>#0</value>
                                </enumeratedValue>
                                <enumeratedValue>
                                    <name>1</name>
                                    <description>Comparison conditions are met.</description>
                                    <value>#1</value>
                                </enumeratedValue>
                            </enumeratedValues>
                        </field>
                        <field>
                            <name>CMPSTCHA11</name>
                            <description>Compare Window A Flag</description>
                            <lsb>11</lsb>
                            <msb>11</msb>
                            <access>read-write</access>
                            <enumeratedValues>
                                <enumeratedValue>
                                    <name>0</name>
                                    <description>Comparison conditions are not met.</description>
                                    <value>#0</value>
                                </enumeratedValue>
                                <enumeratedValue>
                                    <name>1</name>
                                    <description>Comparison conditions are met.</description>
                                    <value>#1</value>
                                </enumeratedValue>
                            </enumeratedValues>
                        </field>
                        <field>
                            <name>CMPSTCHA12</name>
                            <description>Compare Window A Flag</description>
                            <lsb>12</lsb>
                            <msb>12</msb>
                            <access>read-write</access>
                            <enumeratedValues>
                                <enumeratedValue>
                                    <name>0</name>
                                    <description>Comparison conditions are not met.</description>
                                    <value>#0</value>
                                </enumeratedValue>
                                <enumeratedValue>
                                    <name>1</name>
                                    <description>Comparison conditions are met.</description>
                                    <value>#1</value>
                                </enumeratedValue>
                            </enumeratedValues>
                        </field>
                        <field>
                            <name>CMPSTCHA13</name>
                            <description>Compare Window A Flag</description>
                            <lsb>13</lsb>
                            <msb>13</msb>
                            <access>read-write</access>
                            <enumeratedValues>
                                <enumeratedValue>
                                    <name>0</name>
                                    <description>Comparison conditions are not met.</description>
                                    <value>#0</value>
                                </enumeratedValue>
                                <enumeratedValue>
                                    <name>1</name>
                                    <description>Comparison conditions are met.</description>
                                    <value>#1</value>
                                </enumeratedValue>
                            </enumeratedValues>
                        </field>
                        <field>
                            <name>CMPSTCHA14</name>
                            <description>Compare Window A Flag</description>
                            <lsb>14</lsb>
                            <msb>14</msb>
                            <access>read-write</access>
                            <enumeratedValues>
                                <enumeratedValue>
                                    <name>0</name>
                                    <description>Comparison conditions are not met.</description>
                                    <value>#0</value>
                                </enumeratedValue>
                                <enumeratedValue>
                                    <name>1</name>
                                    <description>Comparison conditions are met.</description>
                                    <value>#1</value>
                                </enumeratedValue>
                            </enumeratedValues>
                        </field>
                        <field>
                            <name>CMPSTCHA15</name>
                            <description>Compare Window A Flag</description>
                            <lsb>15</lsb>
                            <msb>15</msb>
                            <access>read-write</access>
                            <enumeratedValues>
                                <enumeratedValue>
                                    <name>0</name>
                                    <description>Comparison conditions are not met.</description>
                                    <value>#0</value>
                                </enumeratedValue>
                                <enumeratedValue>
                                    <name>1</name>
                                    <description>Comparison conditions are met.</description>
                                    <value>#1</value>
                                </enumeratedValue>
                            </enumeratedValues>
                        </field>
                    </fields>
                </register>
                <register>
                    <name>ADCMPSER</name>
                    <description>A/D Compare Function Window A Extended Input Channel Status Register</description>
                    <addressOffset>0x0A4</addressOffset>
                    <size>8</size>
                    <access>read-write</access>
                    <resetValue>0x00</resetValue>
                    <resetMask>0xff</resetMask>
                    <fields>
                        <field>
                            <name>CMPSTTSA</name>
                            <description>Compare Window A Temperature Sensor Output Compare Flag</description>
                            <lsb>0</lsb>
                            <msb>0</msb>
                            <access>read-write</access>
                            <enumeratedValues>
                                <enumeratedValue>
                                    <name>0</name>
                                    <description>Comparison conditions are not met.</description>
                                    <value>#0</value>
                                </enumeratedValue>
                                <enumeratedValue>
                                    <name>1</name>
                                    <description>Comparison conditions are met.</description>
                                    <value>#1</value>
                                </enumeratedValue>
                            </enumeratedValues>
                        </field>
                        <field>
                            <name>CMPSTOCA</name>
                            <description>Compare Window A Internal Reference Voltage Compare Flag</description>
                            <lsb>1</lsb>
                            <msb>1</msb>
                            <access>read-write</access>
                            <enumeratedValues>
                                <enumeratedValue>
                                    <name>0</name>
                                    <description>Comparison conditions are not met.</description>
                                    <value>#0</value>
                                </enumeratedValue>
                                <enumeratedValue>
                                    <name>1</name>
                                    <description>Comparison conditions are met.</description>
                                    <value>#1</value>
                                </enumeratedValue>
                            </enumeratedValues>
                        </field>
                    </fields>
                </register>
                <register>
                    <name>ADCMPBNSR</name>
                    <description>A/D Compare Function Window B Channel Select Register</description>
                    <addressOffset>0x0A6</addressOffset>
                    <size>8</size>
                    <access>read-write</access>
                    <resetValue>0x00</resetValue>
                    <resetMask>0xff</resetMask>
                    <fields>
                        <field>
                            <name>CMPCHB</name>
                            <description>Compare Window B Channel Select</description>
                            <lsb>0</lsb>
                            <msb>5</msb>
                            <access>read-write</access>
                        </field>
                        <field>
                            <name>CMPLB</name>
                            <description>Compare Window B Comparison Condition Setting</description>
                            <lsb>7</lsb>
                            <msb>7</msb>
                            <access>read-write</access>
                            <enumeratedValues>
                                <enumeratedValue>
                                    <name>0</name>
                                    <description>When window function is disabled (ADCMPCR.WCMPE = 0): ADWINLLB value &gt; A/D-converted value When window function is enabled (ADCMPCR.WCMPE = 1): A/D-converted value &lt; ADWINLLB value, or ADWINULB value &lt; A/D-converted value </description>
                                    <value>#0</value>
                                </enumeratedValue>
                                <enumeratedValue>
                                    <name>1</name>
                                    <description>When window function is disabled (ADCMPCR.WCMPE = 0): ADWINLLB value &lt; A/D-converted value When window function is enabled (ADCMPCR.WCMPE = 1): ADWINLLB value &lt; A/D-converted value &lt; ADWINULB value </description>
                                    <value>#1</value>
                                </enumeratedValue>
                            </enumeratedValues>
                        </field>
                    </fields>
                </register>
                <register>
                    <name>ADWINLLB</name>
                    <description>A/D Compare Function Window B Lower-Side/Upper-Side Level Setting Register</description>
                    <addressOffset>0x0A8</addressOffset>
                    <size>16</size>
                    <access>read-write</access>
                    <resetValue>0x0000</resetValue>
                    <resetMask>0xffff</resetMask>
                </register>
                <register>
                    <name>ADWINULB</name>
                    <description>A/D Compare Function Window B Lower-Side/Upper-Side Level Setting Register</description>
                    <addressOffset>0x0AA</addressOffset>
                    <size>16</size>
                    <access>read-write</access>
                    <resetValue>0x0000</resetValue>
                    <resetMask>0xffff</resetMask>
                </register>
                <register>
                    <name>ADCMPBSR</name>
                    <description>A/D Compare Function Window B Status Register</description>
                    <addressOffset>0x0AC</addressOffset>
                    <size>8</size>
                    <access>read-write</access>
                    <resetValue>0x00</resetValue>
                    <resetMask>0xff</resetMask>
                    <fields>
                        <field>
                            <name>CMPSTB</name>
                            <description>Compare Window B Flag</description>
                            <lsb>0</lsb>
                            <msb>0</msb>
                            <access>read-write</access>
                            <enumeratedValues>
                                <enumeratedValue>
                                    <name>0</name>
                                    <description>Comparison conditions are not met.</description>
                                    <value>#0</value>
                                </enumeratedValue>
                                <enumeratedValue>
                                    <name>1</name>
                                    <description>Comparison conditions are met.</description>
                                    <value>#1</value>
                                </enumeratedValue>
                            </enumeratedValues>
                        </field>
                    </fields>
                </register>
                <register>
                    <dim>16</dim>
                    <dimIncrement>0x2</dimIncrement>
                    <dimIndex>0-15</dimIndex>
                    <name>ADBUF%s</name>
                    <description>A/D Data Buffer Registers %s</description>
                    <addressOffset>0x0B0</addressOffset>
                    <size>16</size>
                    <access>read-only</access>
                    <resetValue>0x0000</resetValue>
                    <resetMask>0xffff</resetMask>
                    <fields>
                        <field>
                            <name>ADBUF</name>
                            <description>Converted Value 15 to 0</description>
                            <lsb>0</lsb>
                            <msb>15</msb>
                            <access>read-only</access>
                        </field>
                    </fields>
                </register>
                <register>
                    <name>ADBUFEN</name>
                    <description>A/D Data Buffer Enable Register</description>
                    <addressOffset>0x0D0</addressOffset>
                    <size>8</size>
                    <access>read-write</access>
                    <resetValue>0x00</resetValue>
                    <resetMask>0xff</resetMask>
                    <fields>
                        <field>
                            <name>BUFEN</name>
                            <description>Data Buffer Enable</description>
                            <lsb>0</lsb>
                            <msb>0</msb>
                            <access>read-write</access>
                            <enumeratedValues>
                                <enumeratedValue>
                                    <name>0</name>
                                    <description>The data buffer is not used.</description>
                                    <value>#0</value>
                                </enumeratedValue>
                                <enumeratedValue>
                                    <name>1</name>
                                    <description>The data buffer is used.</description>
                                    <value>#1</value>
                                </enumeratedValue>
                            </enumeratedValues>
                        </field>
                    </fields>
                </register>
                <register>
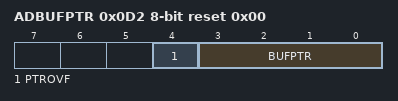
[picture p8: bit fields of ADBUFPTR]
                    <name>ADBUFPTR</name>
                    <description>A/D Data Buffer Pointer Register</description>
                    <addressOffset>0x0D2</addressOffset>
                    <size>8</size>
                    <access>read-write</access>
                    <resetValue>0x00</resetValue>
                    <resetMask>0xff</resetMask>
                    <fields>
                        <field>
                            <name>BUFPTR</name>
                            <description>Data Buffer Pointer</description>
                            <lsb>0</lsb>
                            <msb>3</msb>
                            <access>read-write</access>
                        </field>
                        <field>
                            <name>PTROVF</name>
                            <description>Pointer Overflow Flag</description>
                            <lsb>4</lsb>
                            <msb>4</msb>
                            <access>read-write</access>
                            <enumeratedValues>
                                <enumeratedValue>
                                    <name>0</name>
                                    <description>The data buffer pointer has not overflowed.</description>
                                    <value>#0</value>
                                </enumeratedValue>
                                <enumeratedValue>
                                    <name>1</name>
                                    <description>The data buffer pointer has overflowed.</description>
                                    <value>#1</value>
                                </enumeratedValue>
                            </enumeratedValues>
                        </field>
                    </fields>
                </register>
                <register>
                    <name>ADSSTRL</name>
                    <description>A/D Sampling State Register</description>
                    <addressOffset>0x0DD</addressOffset>
                    <size>8</size>
                    <access>read-write</access>
                    <resetValue>0x0b</resetValue>
                    <resetMask>0xff</resetMask>
                    <fields>
                        <field>
                            <name>SST</name>
                            <description>Sampling Time Setting</description>
                            <lsb>0</lsb>
                            <msb>7</msb>
                            <access>read-write</access>
                        </field>
                    </fields>
                </register>
                <register>
                    <name>ADSSTRT</name>
                    <description>A/D Sampling State Register</description>
                    <addressOffset>0x0DE</addressOffset>
                    <size>8</size>
                    <access>read-write</access>
                    <resetValue>0x0b</resetValue>
                    <resetMask>0xff</resetMask>
                    <fields>
                        <field>
                            <name>SST</name>
                            <description>Sampling Time Setting</description>
                            <lsb>0</lsb>
                            <msb>7</msb>
                            <access>read-write</access>
                        </field>
                    </fields>
                </register>
                <register>
                    <name>ADSSTRO</name>
                    <description>A/D Sampling State Register</description>
                    <addressOffset>0x0DF</addressOffset>
                    <size>8</size>
                    <access>read-write</access>
                    <resetValue>0x0b</resetValue>
                    <resetMask>0xff</resetMask>
                    <fields>
                        <field>
                            <name>SST</name>
                            <description>Sampling Time Setting</description>
                            <lsb>0</lsb>
                            <msb>7</msb>
                            <access>read-write</access>
                        </field>
                    </fields>
                </register>
                <register>
                    <dim>7</dim>
                    <dimIncrement>0x1</dimIncrement>
                    <dimIndex>0-6</dimIndex>
                    <name>ADSSTR%s</name>
                    <description>A/D Sampling State Register</description>
                    <addressOffset>0x0E0</addressOffset>
                    <size>8</size>
                    <access>read-write</access>
                    <resetValue>0x0b</resetValue>
                    <resetMask>0xff</resetMask>
                    <fields>
                        <field>
                            <name>SST</name>
                            <description>Sampling Time Setting</description>
                            <lsb>0</lsb>
                            <msb>7</msb>
                            <access>read-write</access>
                        </field>
                    </fields>
                </register>
                <register>
                    <name>ADSSTRV</name>
                    <description>A/D Sampling State Register</description>
                    <addressOffset>0x0E3</addressOffset>
                    <size>8</size>
                    <access>read-write</access>
                    <resetValue>0x0b</resetValue>
                    <resetMask>0xff</resetMask>
                    <fields>
                        <field>
                            <name>SST</name>
                            <description>Sampling Time Setting</description>
                            <lsb>0</lsb>
                            <msb>7</msb>
                            <access>read-write</access>
                        </field>
                    </fields>
                </register>
            </registers>
        </peripheral>
        <peripheral>
            <name>DAC12</name>
            <description>12-bit D/A converter</description>
            <baseAddress>0x40333000</baseAddress>
            <addressBlock>
                <offset>0x00</offset>
                <size>2</size>
                <usage>registers</usage>
            </addressBlock>
            <addressBlock>
                <offset>0x04</offset>
                <size>3</size>
                <usage>registers</usage>
            </addressBlock>
            <addressBlock>
                <offset>0x08</offset>
                <size>1</size>
                <usage>registers</usage>
            </addressBlock>
            <addressBlock>
                <offset>0x1C</offset>
                <size>1</size>
                <usage>registers</usage>
            </addressBlock>
            <addressBlock>
                <offset>0x10C0</offset>
                <size>1</size>
                <usage>registers</usage>
            </addressBlock>
            <registers>
                <register>
                    <dim>1</dim>
                    <dimIncrement>0x02</dimIncrement>
                    <dimIndex>0</dimIndex>
                    <name>DADR%s</name>
                    <description>D/A Data Register %s</description>
                    <addressOffset>0x00</addressOffset>
                    <size>16</size>
                    <access>read-write</access>
                    <resetValue>0x0000</resetValue>
                    <resetMask>0xffff</resetMask>
                </register>
                <register>
                    <name>DACR</name>
                    <description>D/A Control Register</description>
                    <addressOffset>0x04</addressOffset>
                    <size>8</size>
                    <access>read-write</access>
                    <resetValue>0x1f</resetValue>
                    <resetMask>0xff</resetMask>
                    <fields>
                        <field>
                            <name>DAOE0</name>
                            <description>D/A Output Enable 0</description>
                            <lsb>6</lsb>
                            <msb>6</msb>
                            <access>read-write</access>
                            <enumeratedValues>
                                <enumeratedValue>
                                    <name>0</name>
                                    <description>Disable analog output of channel 0 (DA0)</description>
                                    <value>#0</value>
                                </enumeratedValue>
                                <enumeratedValue>
                                    <name>1</name>
                                    <description>Enable D/A conversion of channel 0 (DA0)</description>
                                    <value>#1</value>
                                </enumeratedValue>
                            </enumeratedValues>
                        </field>
                    </fields>
                </register>
                <register>
                    <name>DADPR</name>
                    <description>DADRn Format Select Register</description>
                    <addressOffset>0x05</addressOffset>
                    <size>8</size>
                    <access>read-write</access>
                    <resetValue>0x00</resetValue>
                    <resetMask>0xff</resetMask>
                    <fields>
                        <field>
                            <name>DPSEL</name>
                            <description>DADRn Format Select</description>
                            <lsb>7</lsb>
                            <msb>7</msb>
                            <access>read-write</access>
                            <enumeratedValues>
                                <enumeratedValue>
                                    <name>0</name>
                                    <description>Right-justified format</description>
                                    <value>#0</value>
                                </enumeratedValue>
                                <enumeratedValue>
                                    <name>1</name>
                                    <description>Left-justified format</description>
                                    <value>#1</value>
                                </enumeratedValue>
                            </enumeratedValues>
                        </field>
                    </fields>
                </register>
                <register>
                    <name>DAADSCR</name>
                    <description>D/A A/D Synchronous Start Control Register</description>
                    <addressOffset>0x06</addressOffset>
                    <size>8</size>
                    <access>read-write</access>
                    <resetValue>0x00</resetValue>
                    <resetMask>0xff</resetMask>
                    <fields>
                        <field>
                            <name>DAADST</name>
                            <description>D/A A/D Synchronous Conversion</description>
                            <lsb>7</lsb>
                            <msb>7</msb>
                            <access>read-write</access>
                            <enumeratedValues>
                                <enumeratedValue>
                                    <name>0</name>
                                    <description>Do not synchronize DAC12 with ADC12 (unit 1) operation (disable interference reduction between D/A and A/D conversion).</description>
                                    <value>#0</value>
                                </enumeratedValue>
                                <enumeratedValue>
                                    <name>1</name>
                                    <description>Synchronize DAC12 with ADC12 (unit 1) operation (enable interference reduction between D/A and A/D conversion).</description>
                                    <value>#1</value>
                                </enumeratedValue>
                            </enumeratedValues>
                        </field>
                    </fields>
                </register>
                <register>
                    <name>DAAMPCR</name>
                    <description>D/A Output Amplifier Control Register</description>
                    <addressOffset>0x08</addressOffset>
                    <size>8</size>
                    <access>read-write</access>
                    <resetValue>0x00</resetValue>
                    <resetMask>0xff</resetMask>
                    <fields>
                        <field>
                            <name>DAAMP0</name>
                            <description>Amplifier Control 0</description>
                            <lsb>6</lsb>
                            <msb>6</msb>
                            <access>read-write</access>
                            <enumeratedValues>
                                <enumeratedValue>
                                    <name>0</name>
                                    <description>Do not use channel 0 output amplifier</description>
                                    <value>#0</value>
                                </enumeratedValue>
                                <enumeratedValue>
                                    <name>1</name>
                                    <description>Use channel 0 output amplifier</description>
                                    <value>#1</value>
                                </enumeratedValue>
                            </enumeratedValues>
                        </field>
                    </fields>
                </register>
                <register>
                    <name>DAASWCR</name>
                    <description>D/A Amplifier Stabilization Wait Control Register</description>
                    <addressOffset>0x1C</addressOffset>
                    <size>8</size>
                    <access>read-write</access>
                    <resetValue>0x00</resetValue>
                    <resetMask>0xff</resetMask>
                    <fields>
                        <field>
                            <name>DAASW0</name>
                            <description>D/A Amplifier Stabilization Wait 0 and D/A internal output control</description>
                            <lsb>6</lsb>
                            <msb>6</msb>
                            <access>read-write</access>
                            <enumeratedValues>
                                <enumeratedValue>
                                    <name>0</name>
                                    <description>For output to external pin: Amplifier stabilization wait off (output) for channel 0 For output to internal module: Disable output for channel 0 </description>
                                    <value>#0</value>
                                </enumeratedValue>
                                <enumeratedValue>
                                    <name>1</name>
                                    <description>For output to external pin: Amplifier stabilization wait on (high-Z) for channel 0 For output to internal module: Enable output for channel 0 </description>
                                    <value>#1</value>
                                </enumeratedValue>
                            </enumeratedValues>
                        </field>
                    </fields>
                </register>
                <register>
                    <name>DAADUSR</name>
                    <description>D/A A/D Synchronous Unit Select Register</description>
                    <addressOffset>0x10C0</addressOffset>
                    <size>8</size>
                    <access>read-write</access>
                    <resetValue>0x00</resetValue>
                    <resetMask>0xff</resetMask>
                    <fields>
                        <field>
                            <name>AMADSEL1</name>
                            <description>A/D Unit 1 Select</description>
                            <lsb>1</lsb>
                            <msb>1</msb>
                            <access>read-write</access>
                            <enumeratedValues>
                                <enumeratedValue>
                                    <name>0</name>
                                    <description>Do not select unit 1</description>
                                    <value>#0</value>
                                </enumeratedValue>
                                <enumeratedValue>
                                    <name>1</name>
                                    <description>Select unit 1</description>
                                    <value>#1</value>
                                </enumeratedValue>
                            </enumeratedValues>
                        </field>
                    </fields>
                </register>
            </registers>
        </peripheral>
        <peripheral>
            <name>GLCDC</name>
            <description>Graphics LCD Controller</description>
            <baseAddress>0x40342000</baseAddress>
            <addressBlock>
                <offset>0x00</offset>
                <size>4124</size>
                <usage>registers</usage>
            </addressBlock>
            <addressBlock>
                <offset>0x1100</offset>
                <size>636</size>
                <usage>registers</usage>
            </addressBlock>
            <addressBlock>
                <offset>0x1380</offset>
                <size>4</size>
                <usage>registers</usage>
            </addressBlock>
            <addressBlock>
                <offset>0x1388</offset>
                <size>52</size>
                <usage>registers</usage>
            </addressBlock>
            <addressBlock>
                <offset>0x13C0</offset>
                <size>24</size>
                <usage>registers</usage>
            </addressBlock>
            <addressBlock>
                <offset>0x13E4</offset>
                <size>4</size>
                <usage>registers</usage>
            </addressBlock>
            <addressBlock>
                <offset>0x1404</offset>
                <size>40</size>
                <usage>registers</usage>
            </addressBlock>
            <addressBlock>
                <offset>0x1440</offset>
                <size>20</size>
                <usage>registers</usage>
            </addressBlock>
            <registers>
                <register>
                    <dim>256</dim>
                    <dimIncrement>0x4</dimIncrement>
                    <dimIndex>0-255</dimIndex>
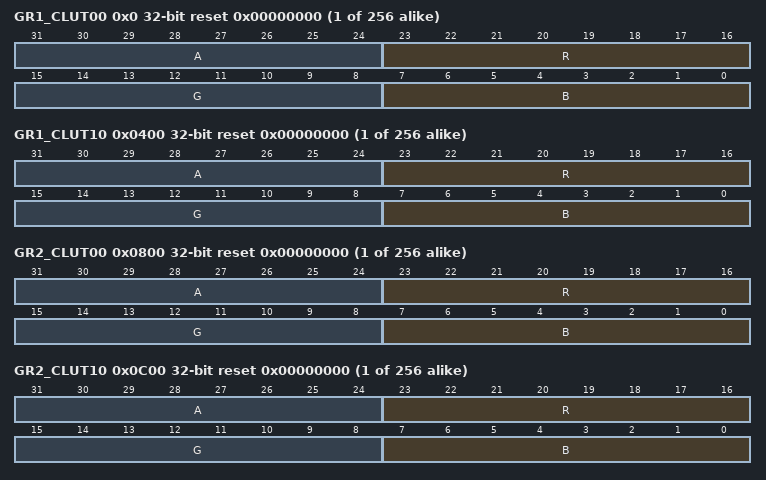
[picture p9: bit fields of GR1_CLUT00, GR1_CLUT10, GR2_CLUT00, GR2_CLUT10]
                    <name>GR1_CLUT0%s</name>
                    <description>Color Palette</description>
                    <addressOffset>0x0</addressOffset>
                    <size>32</size>
                    <access>read-write</access>
                    <resetValue>0x00000000</resetValue>
                    <resetMask>0xffffffff</resetMask>
                    <fields>
                        <field>
                            <name>B</name>
                            <description>B value of color palette n plane for graphics m plane. Unsigned 8-bit integer.</description>
                            <lsb>0</lsb>
                            <msb>7</msb>
                            <access>read-write</access>
                        </field>
                        <field>
                            <name>G</name>
                            <description>G value of color palette n plane for graphics m plane. Unsigned 8-bit integer.</description>
                            <lsb>8</lsb>
                            <msb>15</msb>
                            <access>read-write</access>
                        </field>
                        <field>
                            <name>R</name>
                            <description>R value of color palette n plane for graphics m plane. Unsigned 8-bit integer.</description>
                            <lsb>16</lsb>
                            <msb>23</msb>
                            <access>read-write</access>
                        </field>
                        <field>
                            <name>A</name>
                            <description>Alpha blending value of color palette n plane for graphics m plane. Unsigned 8-bit integer.</description>
                            <lsb>24</lsb>
                            <msb>31</msb>
                            <access>read-write</access>
                        </field>
                    </fields>
                </register>
                <register>
                    <dim>256</dim>
                    <dimIncrement>0x4</dimIncrement>
                    <dimIndex>0-255</dimIndex>
                    <name>GR1_CLUT1%s</name>
                    <description>Color Palette</description>
                    <addressOffset>0x0400</addressOffset>
                    <size>32</size>
                    <access>read-write</access>
                    <resetValue>0x00000000</resetValue>
                    <resetMask>0xffffffff</resetMask>
                    <fields>
                        <field>
                            <name>B</name>
                            <description>B value of color palette n plane for graphics m plane. Unsigned 8-bit integer.</description>
                            <lsb>0</lsb>
                            <msb>7</msb>
                            <access>read-write</access>
                        </field>
                        <field>
                            <name>G</name>
                            <description>G value of color palette n plane for graphics m plane. Unsigned 8-bit integer.</description>
                            <lsb>8</lsb>
                            <msb>15</msb>
                            <access>read-write</access>
                        </field>
                        <field>
                            <name>R</name>
                            <description>R value of color palette n plane for graphics m plane. Unsigned 8-bit integer.</description>
                            <lsb>16</lsb>
                            <msb>23</msb>
                            <access>read-write</access>
                        </field>
                        <field>
                            <name>A</name>
                            <description>Alpha blending value of color palette n plane for graphics m plane. Unsigned 8-bit integer.</description>
                            <lsb>24</lsb>
                            <msb>31</msb>
                            <access>read-write</access>
                        </field>
                    </fields>
                </register>
                <register>
                    <dim>256</dim>
                    <dimIncrement>0x4</dimIncrement>
                    <dimIndex>0-255</dimIndex>
                    <name>GR2_CLUT0%s</name>
                    <description>Color Palette</description>
                    <addressOffset>0x0800</addressOffset>
                    <size>32</size>
                    <access>read-write</access>
                    <resetValue>0x00000000</resetValue>
                    <resetMask>0xffffffff</resetMask>
                    <fields>
                        <field>
                            <name>B</name>
                            <description>B value of color palette n plane for graphics m plane. Unsigned 8-bit integer.</description>
                            <lsb>0</lsb>
                            <msb>7</msb>
                            <access>read-write</access>
                        </field>
                        <field>
                            <name>G</name>
                            <description>G value of color palette n plane for graphics m plane. Unsigned 8-bit integer.</description>
                            <lsb>8</lsb>
                            <msb>15</msb>
                            <access>read-write</access>
                        </field>
                        <field>
                            <name>R</name>
                            <description>R value of color palette n plane for graphics m plane. Unsigned 8-bit integer.</description>
                            <lsb>16</lsb>
                            <msb>23</msb>
                            <access>read-write</access>
                        </field>
                        <field>
                            <name>A</name>
                            <description>Alpha blending value of color palette n plane for graphics m plane. Unsigned 8-bit integer.</description>
                            <lsb>24</lsb>
                            <msb>31</msb>
                            <access>read-write</access>
                        </field>
                    </fields>
                </register>
                <register>
                    <dim>256</dim>
                    <dimIncrement>0x4</dimIncrement>
                    <dimIndex>0-255</dimIndex>
                    <name>GR2_CLUT1%s</name>
                    <description>Color Palette</description>
                    <addressOffset>0x0C00</addressOffset>
                    <size>32</size>
                    <access>read-write</access>
                    <resetValue>0x00000000</resetValue>
                    <resetMask>0xffffffff</resetMask>
                    <fields>
                        <field>
                            <name>B</name>
                            <description>B value of color palette n plane for graphics m plane. Unsigned 8-bit integer.</description>
                            <lsb>0</lsb>
                            <msb>7</msb>
                            <access>read-write</access>
                        </field>
                        <field>
                            <name>G</name>
                            <description>G value of color palette n plane for graphics m plane. Unsigned 8-bit integer.</description>
                            <lsb>8</lsb>
                            <msb>15</msb>
                            <access>read-write</access>
                        </field>
                        <field>
                            <name>R</name>
                            <description>R value of color palette n plane for graphics m plane. Unsigned 8-bit integer.</description>
                            <lsb>16</lsb>
                            <msb>23</msb>
                            <access>read-write</access>
                        </field>
                        <field>
                            <name>A</name>
                            <description>Alpha blending value of color palette n plane for graphics m plane. Unsigned 8-bit integer.</description>
                            <lsb>24</lsb>
                            <msb>31</msb>
                            <access>read-write</access>
                        </field>
                    </fields>
                </register>
                <register>
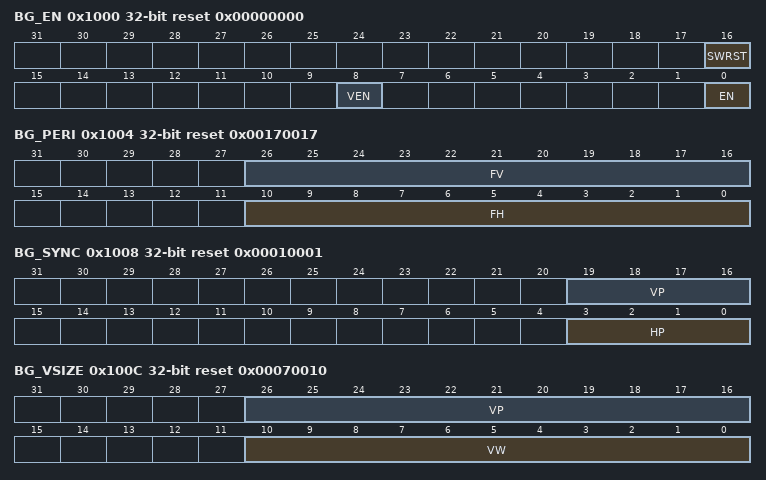
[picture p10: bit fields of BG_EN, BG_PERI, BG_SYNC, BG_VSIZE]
                    <name>BG_EN</name>
                    <description>Background Plane Setting Operation Control Register</description>
                    <addressOffset>0x1000</addressOffset>
                    <size>32</size>
                    <access>read-write</access>
                    <resetValue>0x00000000</resetValue>
                    <resetMask>0xffffffff</resetMask>
                    <fields>
                        <field>
                            <name>EN</name>
                            <description>Background Plane Operation Enable</description>
                            <lsb>0</lsb>
                            <msb>0</msb>
                            <access>read-write</access>
                            <enumeratedValues>
                                <enumeratedValue>
                                    <name>0</name>
                                    <description>Disable background plane operation</description>
                                    <value>#0</value>
                                </enumeratedValue>
                                <enumeratedValue>
                                    <name>1</name>
                                    <description>Enable background plane operation</description>
                                    <value>#1</value>
                                </enumeratedValue>
                            </enumeratedValues>
                        </field>
                        <field>
                            <name>VEN</name>
                            <description>Control of GLCDC Internal Register Value Reflection to Internal Operations</description>
                            <lsb>8</lsb>
                            <msb>8</msb>
                            <access>read-write</access>
                            <enumeratedValues>
                                <enumeratedValue>
                                    <name>0</name>
                                    <description>Disable GLCDC register values from being reflected in internal operations at start of screen generation</description>
                                    <value>#0</value>
                                </enumeratedValue>
                                <enumeratedValue>
                                    <name>1</name>
                                    <description>Enable GLCDC register values to be reflected in internal operations at start of screen generation</description>
                                    <value>#1</value>
                                </enumeratedValue>
                            </enumeratedValues>
                        </field>
                        <field>
                            <name>SWRST</name>
                            <description>Software Reset Control</description>
                            <lsb>16</lsb>
                            <msb>16</msb>
                            <access>read-write</access>
                            <enumeratedValues>
                                <enumeratedValue>
                                    <name>0</name>
                                    <description>Place entire module in software reset state</description>
                                    <value>#0</value>
                                </enumeratedValue>
                                <enumeratedValue>
                                    <name>1</name>
                                    <description>Release entire module from software reset state</description>
                                    <value>#1</value>
                                </enumeratedValue>
                            </enumeratedValues>
                        </field>
                    </fields>
                </register>
                <register>
                    <name>BG_PERI</name>
                    <description>Background Plane Setting Free-Running Period Register</description>
                    <addressOffset>0x1004</addressOffset>
                    <size>32</size>
                    <access>read-write</access>
                    <resetValue>0x00170017</resetValue>
                    <resetMask>0xffffffff</resetMask>
                    <fields>
                        <field>
                            <name>FH</name>
                            <description>Background Plane Horizontal Synchronization Signal Period</description>
                            <lsb>0</lsb>
                            <msb>10</msb>
                            <access>read-write</access>
                            <enumeratedValues>
                                <enumeratedValue>
                                    <name>0x017</name>
                                    <description>24 cycles (pixels)</description>
                                    <value>0x017</value>
                                </enumeratedValue>
                                <enumeratedValue>
                                    <name>0x3FF</name>
                                    <description>1024 cycles (pixels)</description>
                                    <value>0x3ff</value>
                                </enumeratedValue>
                            </enumeratedValues>
                        </field>
                        <field>
                            <name>FV</name>
                            <description>Background Plane Vertical Synchronization Signal Period</description>
                            <lsb>16</lsb>
                            <msb>26</msb>
                            <access>read-write</access>
                            <enumeratedValues>
                                <enumeratedValue>
                                    <name>0x013</name>
                                    <description>20 lines</description>
                                    <value>0x013</value>
                                </enumeratedValue>
                                <enumeratedValue>
                                    <name>0x3FF</name>
                                    <description>1024 lines</description>
                                    <value>0x3ff</value>
                                </enumeratedValue>
                            </enumeratedValues>
                        </field>
                    </fields>
                </register>
                <register>
                    <name>BG_SYNC</name>
                    <description>Background Plane Setting Synchronization Position Register</description>
                    <addressOffset>0x1008</addressOffset>
                    <size>32</size>
                    <access>read-write</access>
                    <resetValue>0x00010001</resetValue>
                    <resetMask>0xffffffff</resetMask>
                    <fields>
                        <field>
                            <name>HP</name>
                            <description>Background Plane Horizontal Synchronization Signal Assertion Position</description>
                            <lsb>0</lsb>
                            <msb>3</msb>
                            <access>read-write</access>
                            <enumeratedValues>
                                <enumeratedValue>
                                    <name>0x0</name>
                                    <description>Setting prohibited</description>
                                    <value>0x0</value>
                                </enumeratedValue>
                                <enumeratedValue>
                                    <name>Others</name>
                                    <description>HPth cycle (pixel)</description>
                                    <isDefault>true</isDefault>
                                </enumeratedValue>
                            </enumeratedValues>
                        </field>
                        <field>
                            <name>VP</name>
                            <description>Background Plane Vertical Synchronization Assertion Position</description>
                            <lsb>16</lsb>
                            <msb>19</msb>
                            <access>read-write</access>
                            <enumeratedValues>
                                <enumeratedValue>
                                    <name>0x0</name>
                                    <description>Setting prohibited</description>
                                    <value>0x0</value>
                                </enumeratedValue>
                                <enumeratedValue>
                                    <name>Others</name>
                                    <description>VPth line</description>
                                    <isDefault>true</isDefault>
                                </enumeratedValue>
                            </enumeratedValues>
                        </field>
                    </fields>
                </register>
                <register>
                    <name>BG_VSIZE</name>
                    <description>Background Plane Setting Full Image Vertical Size Register</description>
                    <addressOffset>0x100C</addressOffset>
                    <size>32</size>
                    <access>read-write</access>
                    <resetValue>0x00070010</resetValue>
                    <resetMask>0xffffffff</resetMask>
                    <fields>
                        <field>
                            <name>VW</name>
                            <description>Background Plane Vertical Valid Pixel Width</description>
                            <lsb>0</lsb>
                            <msb>10</msb>
                            <access>read-write</access>
                        </field>
                        <field>
                            <name>VP</name>
                            <description>Background Plane Vertical Valid Pixel Start Position</description>
                            <lsb>16</lsb>
                            <msb>26</msb>
                            <access>read-write</access>
                        </field>
                    </fields>
                </register>
                <register>
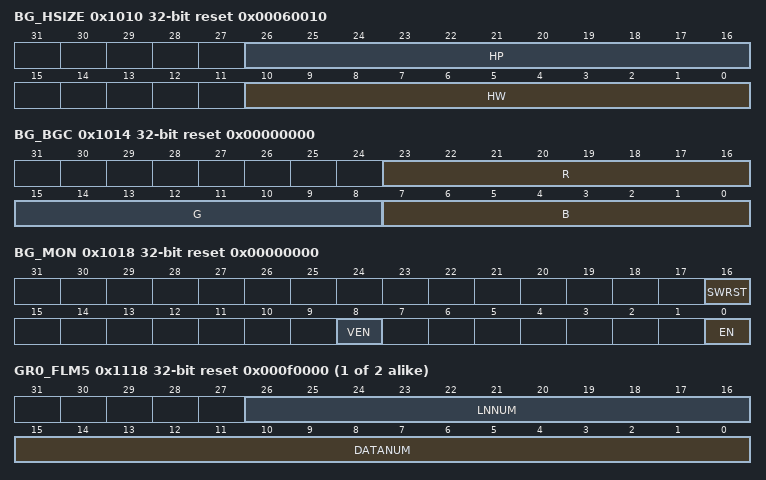
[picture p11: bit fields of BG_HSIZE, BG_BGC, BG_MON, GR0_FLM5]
                    <name>BG_HSIZE</name>
                    <description>Background Plane Setting Full Image Horizontal Size Register</description>
                    <addressOffset>0x1010</addressOffset>
                    <size>32</size>
                    <access>read-write</access>
                    <resetValue>0x00060010</resetValue>
                    <resetMask>0xffffffff</resetMask>
                    <fields>
                        <field>
                            <name>HW</name>
                            <description>Background Plane Horizontal Valid Pixel Width</description>
                            <lsb>0</lsb>
                            <msb>10</msb>
                            <access>read-write</access>
                        </field>
                        <field>
                            <name>HP</name>
                            <description>Background Plane Horizontal Valid Pixel Start Position</description>
                            <lsb>16</lsb>
                            <msb>26</msb>
                            <access>read-write</access>
                        </field>
                    </fields>
                </register>
                <register>
                    <name>BG_BGC</name>
                    <description>Background Plane Setting Background Color Register</description>
                    <addressOffset>0x1014</addressOffset>
                    <size>32</size>
                    <access>read-write</access>
                    <resetValue>0x00000000</resetValue>
                    <resetMask>0xffffffff</resetMask>
                    <fields>
                        <field>
                            <name>B</name>
                            <description>Background Plane Valid Pixel Area B Value</description>
                            <lsb>0</lsb>
                            <msb>7</msb>
                            <access>read-write</access>
                        </field>
                        <field>
                            <name>G</name>
                            <description>Background Plane Valid Pixel Area G Value</description>
                            <lsb>8</lsb>
                            <msb>15</msb>
                            <access>read-write</access>
                        </field>
                        <field>
                            <name>R</name>
                            <description>Background Plane Valid Pixel Area R Value</description>
                            <lsb>16</lsb>
                            <msb>23</msb>
                            <access>read-write</access>
                        </field>
                    </fields>
                </register>
                <register>
                    <name>BG_MON</name>
                    <description>Background Plane Setting Status Monitor Register</description>
                    <addressOffset>0x1018</addressOffset>
                    <size>32</size>
                    <access>read-only</access>
                    <resetValue>0x00000000</resetValue>
                    <resetMask>0xffffffff</resetMask>
                    <fields>
                        <field>
                            <name>EN</name>
                            <description>Background Plane Operation Monitor</description>
                            <lsb>0</lsb>
                            <msb>0</msb>
                            <access>read-only</access>
                            <enumeratedValues>
                                <enumeratedValue>
                                    <name>0</name>
                                    <description>Operation is stopped</description>
                                    <value>#0</value>
                                </enumeratedValue>
                                <enumeratedValue>
                                    <name>1</name>
                                    <description>Operation is in progress</description>
                                    <value>#1</value>
                                </enumeratedValue>
                            </enumeratedValues>
                        </field>
                        <field>
                            <name>VEN</name>
                            <description>Entire Module Internal Operation Reflection Control Signal Monitor</description>
                            <lsb>8</lsb>
                            <msb>8</msb>
                            <access>read-only</access>
                            <enumeratedValues>
                                <enumeratedValue>
                                    <name>0</name>
                                    <description>Signal for controlling reflection of the register values to internal operations on assertion of vertical synchronization signal is negated</description>
                                    <value>#0</value>
                                </enumeratedValue>
                                <enumeratedValue>
                                    <name>1</name>
                                    <description>Signal for controlling reflection of the register values to internal operations on assertion of vertical synchronization signal is asserted</description>
                                    <value>#1</value>
                                </enumeratedValue>
                            </enumeratedValues>
                        </field>
                        <field>
                            <name>SWRST</name>
                            <description>Entire Module SW Reset State Monitor</description>
                            <lsb>16</lsb>
                            <msb>16</msb>
                            <access>read-only</access>
                            <enumeratedValues>
                                <enumeratedValue>
                                    <name>0</name>
                                    <description>Entire module is in software reset state</description>
                                    <value>#0</value>
                                </enumeratedValue>
                                <enumeratedValue>
                                    <name>1</name>
                                    <description>Entire module is released from software reset state</description>
                                    <value>#1</value>
                                </enumeratedValue>
                            </enumeratedValues>
                        </field>
                    </fields>
                </register>
                <register>
                    <dim>2</dim>
                    <dimIncrement>0x100</dimIncrement>
                    <dimIndex>1-2</dimIndex>
                    <name>GR%s_VEN</name>
                    <description>Graphics %s Register Update Control Register</description>
                    <addressOffset>0x1100</addressOffset>
                    <size>32</size>
                    <access>read-write</access>
                    <resetValue>0x00000000</resetValue>
                    <resetMask>0xffffffff</resetMask>
                    <fields>
                        <field>
                            <name>PVEN</name>
                            <description>This bit is cleared to 0 by an internal source.</description>
                            <lsb>0</lsb>
                            <msb>0</msb>
                            <access>read-write</access>
                            <enumeratedValues>
                                <enumeratedValue>
                                    <name>0</name>
                                    <description>Disable reflection of register values to internal operations on assertion of vertical synchronization signal (VS)</description>
                                    <value>#0</value>
                                </enumeratedValue>
                                <enumeratedValue>
                                    <name>1</name>
                                    <description>Enable reflection of register values to internal operations on assertion of the vertical synchronization signal (VS)</description>
                                    <value>#1</value>
                                </enumeratedValue>
                            </enumeratedValues>
                        </field>
                    </fields>
                </register>
                <register>
                    <dim>2</dim>
                    <dimIncrement>0x100</dimIncrement>
                    <dimIndex>1-2</dimIndex>
                    <name>GR%s_FLMRD</name>
                    <description>Graphics %s Frame Buffer Read Control Register</description>
                    <addressOffset>0x1104</addressOffset>
                    <size>32</size>
                    <access>read-write</access>
                    <resetValue>0x00000000</resetValue>
                    <resetMask>0xffffffff</resetMask>
                    <fields>
                        <field>
                            <name>RENB</name>
                            <description>Graphics Data Read Enable</description>
                            <lsb>0</lsb>
                            <msb>0</msb>
                            <access>read-write</access>
                            <enumeratedValues>
                                <enumeratedValue>
                                    <name>0</name>
                                    <description>Disable reading</description>
                                    <value>#0</value>
                                </enumeratedValue>
                                <enumeratedValue>
                                    <name>1</name>
                                    <description>Enable reading</description>
                                    <value>#1</value>
                                </enumeratedValue>
                            </enumeratedValues>
                        </field>
                    </fields>
                </register>
                <register>
                    <dim>2</dim>
                    <dimIncrement>0x100</dimIncrement>
                    <dimIndex>1-2</dimIndex>
                    <name>GR%s_FLM1</name>
                    <description>Graphics %s Frame Buffer Control Register 1</description>
                    <addressOffset>0x1108</addressOffset>
                    <size>32</size>
                    <access>read-write</access>
                    <resetValue>0x00000003</resetValue>
                    <resetMask>0xffffffff</resetMask>
                    <fields>
                        <field>
                            <name>BSTMD</name>
                            <description>Burst Transfer Control for Graphics Data Access</description>
                            <lsb>0</lsb>
                            <msb>1</msb>
                            <access>read-write</access>
                            <enumeratedValues>
                                <enumeratedValue>
                                    <name>11</name>
                                    <description>16-beat increment burst transfer (64-byte boundary)</description>
                                    <value>#11</value>
                                </enumeratedValue>
                                <enumeratedValue>
                                    <name>Others</name>
                                    <description>Setting prohibited</description>
                                    <isDefault>true</isDefault>
                                </enumeratedValue>
                            </enumeratedValues>
                        </field>
                    </fields>
                </register>
                <register>
                    <dim>2</dim>
                    <dimIncrement>0x100</dimIncrement>
                    <dimIndex>1-2</dimIndex>
                    <name>GR%s_FLM2</name>
                    <description>Graphics %s Frame Buffer Control Register 2</description>
                    <addressOffset>0x110C</addressOffset>
                    <size>32</size>
                    <access>read-write</access>
                    <resetValue>0x00000000</resetValue>
                    <resetMask>0xffffffff</resetMask>
                    <fields>
                        <field>
                            <name>BASE</name>
                            <description>Base Address for Accessing Graphics Data</description>
                            <lsb>0</lsb>
                            <msb>31</msb>
                            <access>read-write</access>
                        </field>
                    </fields>
                </register>
                <register>
                    <dim>2</dim>
                    <dimIncrement>0x100</dimIncrement>
                    <dimIndex>1-2</dimIndex>
                    <name>GR%s_FLM3</name>
                    <description>Graphics %s Frame Buffer Control Register 3</description>
                    <addressOffset>0x1110</addressOffset>
                    <size>32</size>
                    <access>read-write</access>
                    <resetValue>0x00000000</resetValue>
                    <resetMask>0xffffffff</resetMask>
                    <fields>
                        <field>
                            <name>LNOFF</name>
                            <description>Macro Line Offset Address for Accessing Graphics Data</description>
                            <lsb>16</lsb>
                            <msb>31</msb>
                            <access>read-write</access>
                        </field>
                    </fields>
                </register>
                <register>
                    <dim>2</dim>
                    <dimIncrement>0x100</dimIncrement>
                    <dimIndex>1-2</dimIndex>
                    <name>GR%s_FLM5</name>
                    <description>Graphics %s Frame Buffer Control Register 5</description>
                    <addressOffset>0x1118</addressOffset>
                    <size>32</size>
                    <access>read-write</access>
                    <resetValue>0x000f0000</resetValue>
                    <resetMask>0xffffffff</resetMask>
                    <fields>
                        <field>
                            <name>DATANUM</name>
                            <description>Number of Data Transfer Times Per Line for Accessing Graphics Data</description>
                            <lsb>0</lsb>
                            <msb>15</msb>
                            <access>read-write</access>
                        </field>
                        <field>
                            <name>LNNUM</name>
                            <description>Number of Lines Per Frame for Accessing Graphics Data</description>
                            <lsb>16</lsb>
                            <msb>26</msb>
                            <access>read-write</access>
                        </field>
                    </fields>
                </register>
                <register>
                    <dim>2</dim>
                    <dimIncrement>0x100</dimIncrement>
                    <dimIndex>1-2</dimIndex>
                    <name>GR%s_FLM6</name>
                    <description>Graphics %s Frame Buffer Control Register 6</description>
                    <addressOffset>0x111C</addressOffset>
                    <size>32</size>
                    <access>read-write</access>
                    <resetValue>0x00000000</resetValue>
                    <resetMask>0xffffffff</resetMask>
                    <fields>
                        <field>
                            <name>FORMAT</name>
                            <description>Data Format for Accessing Graphics Data</description>
                            <lsb>28</lsb>
                            <msb>30</msb>
                            <access>read-write</access>
                            <enumeratedValues>
                                <enumeratedValue>
                                    <name>000</name>
                                    <description>RGB565 (16 bits/pixel)</description>
                                    <value>#000</value>
                                </enumeratedValue>
                                <enumeratedValue>
                                    <name>001</name>
                                    <description>RGB888 (32 bits/pixel, 8 bits on the MSB side are invalid)</description>
                                    <value>#001</value>
                                </enumeratedValue>
                                <enumeratedValue>
                                    <name>010</name>
                                    <description>ARGB1555 (16 bits/pixel, 1 bit of A is LUT data)</description>
                                    <value>#010</value>
                                </enumeratedValue>
                                <enumeratedValue>
                                    <name>011</name>
                                    <description>ARGB4444 (16 bits/pixel)</description>
                                    <value>#011</value>
                                </enumeratedValue>
                                <enumeratedValue>
                                    <name>100</name>
                                    <description>ARGB8888 (32 bits/pixel)</description>
                                    <value>#100</value>
                                </enumeratedValue>
                                <enumeratedValue>
                                    <name>101</name>
                                    <description>CLUT8 (8 bits/pixel)</description>
                                    <value>#101</value>
                                </enumeratedValue>
                                <enumeratedValue>
                                    <name>110</name>
                                    <description>CLUT4 (4 bits/pixel)</description>
                                    <value>#110</value>
                                </enumeratedValue>
                                <enumeratedValue>
                                    <name>111</name>
                                    <description>CLUT1 (1 bit/pixel)</description>
                                    <value>#111</value>
                                </enumeratedValue>
                            </enumeratedValues>
                        </field>
                    </fields>
                </register>
                <register>
                    <dim>2</dim>
                    <dimIncrement>0x100</dimIncrement>
                    <dimIndex>1-2</dimIndex>
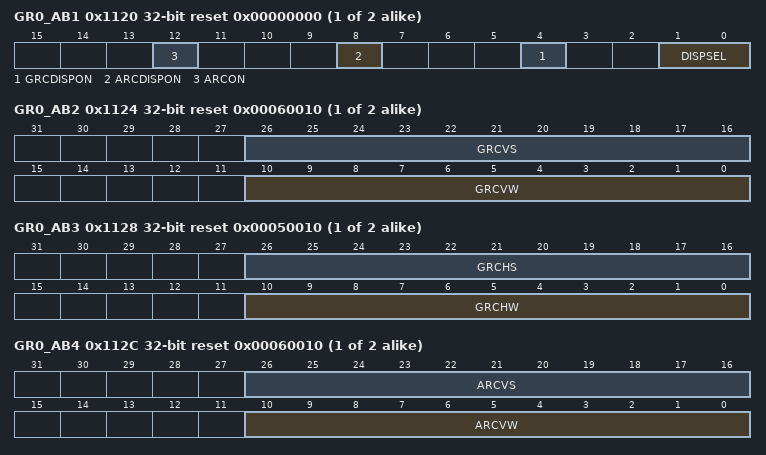
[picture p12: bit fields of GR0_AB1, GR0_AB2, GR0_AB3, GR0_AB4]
                    <name>GR%s_AB1</name>
                    <description>Graphics %s Alpha Blending Control Register 1</description>
                    <addressOffset>0x1120</addressOffset>
                    <size>32</size>
                    <access>read-write</access>
                    <resetValue>0x00000000</resetValue>
                    <resetMask>0xffffffff</resetMask>
                    <fields>
                        <field>
                            <name>DISPSEL</name>
                            <description>Graphics Display Plane Control</description>
                            <lsb>0</lsb>
                            <msb>1</msb>
                            <access>read-write</access>
                            <enumeratedValues>
                                <enumeratedValue>
                                    <name>00</name>
                                    <description>Background color display (value set in the GRn_BASE register)</description>
                                    <value>#00</value>
                                </enumeratedValue>
                                <enumeratedValue>
                                    <name>01</name>
                                    <description>Lower-layer graphics display</description>
                                    <value>#01</value>
                                </enumeratedValue>
                                <enumeratedValue>
                                    <name>10</name>
                                    <description>Current graphics display</description>
                                    <value>#10</value>
                                </enumeratedValue>
                                <enumeratedValue>
                                    <name>11</name>
                                    <description>Blended display of lower-layer graphics (input image from the previous stage) and current graphics (data read from the GLCDC0 and GLCDC1 bus)</description>
                                    <value>#11</value>
                                </enumeratedValue>
                            </enumeratedValues>
                        </field>
                        <field>
                            <name>GRCDISPON</name>
                            <description>Graphics Image Area Border Display Control</description>
                            <lsb>4</lsb>
                            <msb>4</msb>
                            <access>read-write</access>
                            <enumeratedValues>
                                <enumeratedValue>
                                    <name>0</name>
                                    <description>Turn display off</description>
                                    <value>#0</value>
                                </enumeratedValue>
                                <enumeratedValue>
                                    <name>1</name>
                                    <description>Turn display on</description>
                                    <value>#1</value>
                                </enumeratedValue>
                            </enumeratedValues>
                        </field>
                        <field>
                            <name>ARCDISPON</name>
                            <description>Image Area Border Display Control for Rectangular Area Alpha Blending</description>
                            <lsb>8</lsb>
                            <msb>8</msb>
                            <access>read-write</access>
                            <enumeratedValues>
                                <enumeratedValue>
                                    <name>0</name>
                                    <description>Turn display off</description>
                                    <value>#0</value>
                                </enumeratedValue>
                                <enumeratedValue>
                                    <name>1</name>
                                    <description>Turn display on</description>
                                    <value>#1</value>
                                </enumeratedValue>
                            </enumeratedValues>
                        </field>
                        <field>
                            <name>ARCON</name>
                            <description>Rectangular Area Alpha Blending Control</description>
                            <lsb>12</lsb>
                            <msb>12</msb>
                            <access>read-write</access>
                            <enumeratedValues>
                                <enumeratedValue>
                                    <name>0</name>
                                    <description>Turn blending off</description>
                                    <value>#0</value>
                                </enumeratedValue>
                                <enumeratedValue>
                                    <name>1</name>
                                    <description>Turn blending on</description>
                                    <value>#1</value>
                                </enumeratedValue>
                            </enumeratedValues>
                        </field>
                    </fields>
                </register>
                <register>
                    <dim>2</dim>
                    <dimIncrement>0x100</dimIncrement>
                    <dimIndex>1-2</dimIndex>
                    <name>GR%s_AB2</name>
                    <description>Graphics %s Alpha Blending Control Register 2</description>
                    <addressOffset>0x1124</addressOffset>
                    <size>32</size>
                    <access>read-write</access>
                    <resetValue>0x00060010</resetValue>
                    <resetMask>0xffffffff</resetMask>
                    <fields>
                        <field>
                            <name>GRCVW</name>
                            <description>Vertical Width of Graphics Image Area</description>
                            <lsb>0</lsb>
                            <msb>10</msb>
                            <access>read-write</access>
                        </field>
                        <field>
                            <name>GRCVS</name>
                            <description>Vertical Start Position of Graphics Image Area</description>
                            <lsb>16</lsb>
                            <msb>26</msb>
                            <access>read-write</access>
                        </field>
                    </fields>
                </register>
                <register>
                    <dim>2</dim>
                    <dimIncrement>0x100</dimIncrement>
                    <dimIndex>1-2</dimIndex>
                    <name>GR%s_AB3</name>
                    <description>Graphics %s Alpha Blending Control Register 3</description>
                    <addressOffset>0x1128</addressOffset>
                    <size>32</size>
                    <access>read-write</access>
                    <resetValue>0x00050010</resetValue>
                    <resetMask>0xffffffff</resetMask>
                    <fields>
                        <field>
                            <name>GRCHW</name>
                            <description>Horizontal Width of Graphics Image Area</description>
                            <lsb>0</lsb>
                            <msb>10</msb>
                            <access>read-write</access>
                        </field>
                        <field>
                            <name>GRCHS</name>
                            <description>Horizontal Start Position of Graphics Image Area</description>
                            <lsb>16</lsb>
                            <msb>26</msb>
                            <access>read-write</access>
                        </field>
                    </fields>
                </register>
                <register>
                    <dim>2</dim>
                    <dimIncrement>0x100</dimIncrement>
                    <dimIndex>1-2</dimIndex>
                    <name>GR%s_AB4</name>
                    <description>Graphics %s Alpha Blending Control Register 4</description>
                    <addressOffset>0x112C</addressOffset>
                    <size>32</size>
                    <access>read-write</access>
                    <resetValue>0x00060010</resetValue>
                    <resetMask>0xffffffff</resetMask>
                    <fields>
                        <field>
                            <name>ARCVW</name>
                            <description>Vertical Width of Rectangular Area Alpha Blending Image Area</description>
                            <lsb>0</lsb>
                            <msb>10</msb>
                            <access>read-write</access>
                        </field>
                        <field>
                            <name>ARCVS</name>
                            <description>Vertical Start Position of Rectangular Area Alpha Blending Image Area</description>
                            <lsb>16</lsb>
                            <msb>26</msb>
                            <access>read-write</access>
                        </field>
                    </fields>
                </register>
                <register>
                    <dim>2</dim>
                    <dimIncrement>0x100</dimIncrement>
                    <dimIndex>1-2</dimIndex>
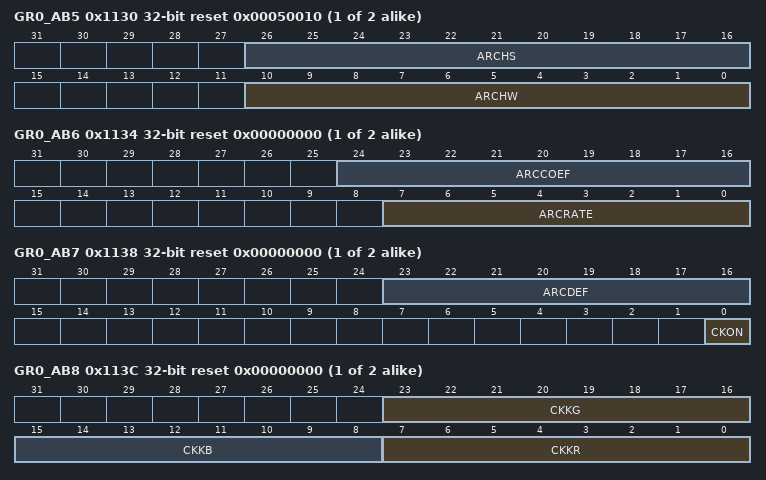
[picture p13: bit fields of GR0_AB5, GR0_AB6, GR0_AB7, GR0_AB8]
                    <name>GR%s_AB5</name>
                    <description>Graphics %s Alpha Blending Control Register 5</description>
                    <addressOffset>0x1130</addressOffset>
                    <size>32</size>
                    <access>read-write</access>
                    <resetValue>0x00050010</resetValue>
                    <resetMask>0xffffffff</resetMask>
                    <fields>
                        <field>
                            <name>ARCHW</name>
                            <description>Horizontal Width of Rectangular Area Alpha Blending Image Area</description>
                            <lsb>0</lsb>
                            <msb>10</msb>
                            <access>read-write</access>
                        </field>
                        <field>
                            <name>ARCHS</name>
                            <description>Horizontal Start Position of Rectangular Area Alpha Blending Image Area</description>
                            <lsb>16</lsb>
                            <msb>26</msb>
                            <access>read-write</access>
                        </field>
                    </fields>
                </register>
                <register>
                    <dim>2</dim>
                    <dimIncrement>0x100</dimIncrement>
                    <dimIndex>1-2</dimIndex>
                    <name>GR%s_AB6</name>
                    <description>Graphics %s Alpha Blending Control Register 6</description>
                    <addressOffset>0x1134</addressOffset>
                    <size>32</size>
                    <access>read-write</access>
                    <resetValue>0x00000000</resetValue>
                    <resetMask>0xffffffff</resetMask>
                    <fields>
                        <field>
                            <name>ARCRATE</name>
                            <description>Frame Rate for Alpha Blending in Rectangular Area</description>
                            <lsb>0</lsb>
                            <msb>7</msb>
                            <access>read-write</access>
                        </field>
                        <field>
                            <name>ARCCOEF</name>
                            <description>Alpha Coefficient for Alpha Blending in Rectangular Area</description>
                            <lsb>16</lsb>
                            <msb>24</msb>
                            <access>read-write</access>
                        </field>
                    </fields>
                </register>
                <register>
                    <dim>2</dim>
                    <dimIncrement>0x100</dimIncrement>
                    <dimIndex>1-2</dimIndex>
                    <name>GR%s_AB7</name>
                    <description>Graphics %s Alpha Blending Control Register 7</description>
                    <addressOffset>0x1138</addressOffset>
                    <size>32</size>
                    <access>read-write</access>
                    <resetValue>0x00000000</resetValue>
                    <resetMask>0xffffffff</resetMask>
                    <fields>
                        <field>
                            <name>CKON</name>
                            <description>RGB-Index Chroma-Key Processing Control</description>
                            <lsb>0</lsb>
                            <msb>0</msb>
                            <access>read-write</access>
                            <enumeratedValues>
                                <enumeratedValue>
                                    <name>0</name>
                                    <description>Disable chroma-key processing</description>
                                    <value>#0</value>
                                </enumeratedValue>
                                <enumeratedValue>
                                    <name>1</name>
                                    <description>Enable chroma-key processing</description>
                                    <value>#1</value>
                                </enumeratedValue>
                            </enumeratedValues>
                        </field>
                        <field>
                            <name>ARCDEF</name>
                            <description>Initial Alpha Value for Alpha Blending in Rectangular Area</description>
                            <lsb>16</lsb>
                            <msb>23</msb>
                            <access>read-write</access>
                        </field>
                    </fields>
                </register>
                <register>
                    <dim>2</dim>
                    <dimIncrement>0x100</dimIncrement>
                    <dimIndex>1-2</dimIndex>
                    <name>GR%s_AB8</name>
                    <description>Graphics %s Alpha Blending Control Register 8</description>
                    <addressOffset>0x113C</addressOffset>
                    <size>32</size>
                    <access>read-write</access>
                    <resetValue>0x00000000</resetValue>
                    <resetMask>0xffffffff</resetMask>
                    <fields>
                        <field>
                            <name>CKKR</name>
                            <description>R Signal for RGB-Index Chroma-Key Processing</description>
                            <lsb>0</lsb>
                            <msb>7</msb>
                            <access>read-write</access>
                        </field>
                        <field>
                            <name>CKKB</name>
                            <description>B Signal for RGB-Index Chroma-Key Processing</description>
                            <lsb>8</lsb>
                            <msb>15</msb>
                            <access>read-write</access>
                        </field>
                        <field>
                            <name>CKKG</name>
                            <description>G Signal for RGB-Index Chroma-Key Processing</description>
                            <lsb>16</lsb>
                            <msb>23</msb>
                            <access>read-write</access>
                        </field>
                    </fields>
                </register>
                <register>
                    <dim>2</dim>
                    <dimIncrement>0x100</dimIncrement>
                    <dimIndex>1-2</dimIndex>
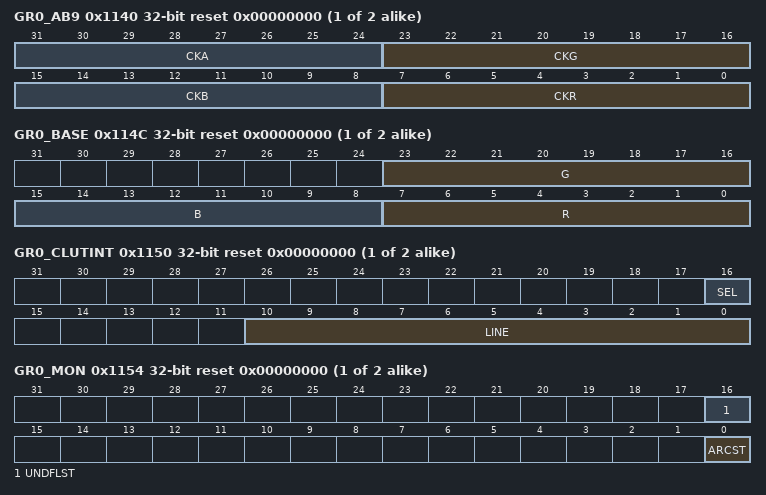
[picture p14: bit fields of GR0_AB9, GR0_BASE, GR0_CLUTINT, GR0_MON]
                    <name>GR%s_AB9</name>
                    <description>Graphics %s Alpha Blending Control Register 9</description>
                    <addressOffset>0x1140</addressOffset>
                    <size>32</size>
                    <access>read-write</access>
                    <resetValue>0x00000000</resetValue>
                    <resetMask>0xffffffff</resetMask>
                    <fields>
                        <field>
                            <name>CKR</name>
                            <description>R Value after RGB-Index Chroma-Key Processing Replacement</description>
                            <lsb>0</lsb>
                            <msb>7</msb>
                            <access>read-write</access>
                        </field>
                        <field>
                            <name>CKB</name>
                            <description>B Value after RGB-Index Chroma-Key Processing Replacement</description>
                            <lsb>8</lsb>
                            <msb>15</msb>
                            <access>read-write</access>
                        </field>
                        <field>
                            <name>CKG</name>
                            <description>G Value after RGB-Index Chroma-Key Processing Replacement</description>
                            <lsb>16</lsb>
                            <msb>23</msb>
                            <access>read-write</access>
                        </field>
                        <field>
                            <name>CKA</name>
                            <description>A Value after RGB-Index Chroma-Key Processing Replacement</description>
                            <lsb>24</lsb>
                            <msb>31</msb>
                            <access>read-write</access>
                        </field>
                    </fields>
                </register>
                <register>
                    <dim>2</dim>
                    <dimIncrement>0x100</dimIncrement>
                    <dimIndex>1-2</dimIndex>
                    <name>GR%s_BASE</name>
                    <description>Graphics %s Background Color Control Register</description>
                    <addressOffset>0x114C</addressOffset>
                    <size>32</size>
                    <access>read-write</access>
                    <resetValue>0x00000000</resetValue>
                    <resetMask>0xffffffff</resetMask>
                    <fields>
                        <field>
                            <name>R</name>
                            <description>Background Color R Value</description>
                            <lsb>0</lsb>
                            <msb>7</msb>
                            <access>read-write</access>
                        </field>
                        <field>
                            <name>B</name>
                            <description>Background Color B Value</description>
                            <lsb>8</lsb>
                            <msb>15</msb>
                            <access>read-write</access>
                        </field>
                        <field>
                            <name>G</name>
                            <description>Background Color G Value</description>
                            <lsb>16</lsb>
                            <msb>23</msb>
                            <access>read-write</access>
                        </field>
                    </fields>
                </register>
                <register>
                    <dim>2</dim>
                    <dimIncrement>0x100</dimIncrement>
                    <dimIndex>1-2</dimIndex>
                    <name>GR%s_CLUTINT</name>
                    <description>Graphics %s CLUT Table Interrupt Control Register</description>
                    <addressOffset>0x1150</addressOffset>
                    <size>32</size>
                    <access>read-write</access>
                    <resetValue>0x00000000</resetValue>
                    <resetMask>0xffffffff</resetMask>
                    <fields>
                        <field>
                            <name>LINE</name>
                            <description>Number of Detection Lines</description>
                            <lsb>0</lsb>
                            <msb>10</msb>
                            <access>read-write</access>
                        </field>
                        <field>
                            <name>SEL</name>
                            <description>CLUT Table Control</description>
                            <lsb>16</lsb>
                            <msb>16</msb>
                            <access>read-write</access>
                            <enumeratedValues>
                                <enumeratedValue>
                                    <name>0</name>
                                    <description>Select CLUT table 0</description>
                                    <value>#0</value>
                                </enumeratedValue>
                                <enumeratedValue>
                                    <name>1</name>
                                    <description>Select CLUT table 1</description>
                                    <value>#1</value>
                                </enumeratedValue>
                            </enumeratedValues>
                        </field>
                    </fields>
                </register>
                <register>
                    <dim>2</dim>
                    <dimIncrement>0x100</dimIncrement>
                    <dimIndex>1-2</dimIndex>
                    <name>GR%s_MON</name>
                    <description>Graphics %s Status Monitor Register</description>
                    <addressOffset>0x1154</addressOffset>
                    <size>32</size>
                    <access>read-only</access>
                    <resetValue>0x00000000</resetValue>
                    <resetMask>0xffffffff</resetMask>
                    <fields>
                        <field>
                            <name>ARCST</name>
                            <description>Status Monitor for Alpha Blending in Rectangular Area</description>
                            <lsb>0</lsb>
                            <msb>0</msb>
                            <access>read-only</access>
                            <enumeratedValues>
                                <enumeratedValue>
                                    <name>0</name>
                                    <description>Fade-in/fade-out not in progress</description>
                                    <value>#0</value>
                                </enumeratedValue>
                                <enumeratedValue>
                                    <name>1</name>
                                    <description>Fade-in/fade-out in progress</description>
                                    <value>#1</value>
                                </enumeratedValue>
                            </enumeratedValues>
                        </field>
                        <field>
                            <name>UNDFLST</name>
                            <description>Underflow Status Monitor</description>
                            <lsb>16</lsb>
                            <msb>16</msb>
                            <access>read-only</access>
                            <enumeratedValues>
                                <enumeratedValue>
                                    <name>0</name>
                                    <description>No underflow occurred in internal operations</description>
                                    <value>#0</value>
                                </enumeratedValue>
                                <enumeratedValue>
                                    <name>1</name>
                                    <description>Underflow occurred in internal operations</description>
                                    <value>#1</value>
                                </enumeratedValue>
                            </enumeratedValues>
                        </field>
                    </fields>
                </register>
                <register>
                    <name>GAMG_LATCH</name>
                    <description>Gamma G Register Update Control Register</description>
                    <addressOffset>0x1300</addressOffset>
                    <size>32</size>
                    <access>read-write</access>
                    <resetValue>0x00000000</resetValue>
                    <resetMask>0xffffffff</resetMask>
                    <fields>
                        <field>
                            <name>VEN</name>
                            <description>Control of Gamma Correction × Module Register Value Reflection to Internal Operations</description>
                            <lsb>0</lsb>
                            <msb>0</msb>
                            <access>read-write</access>
                            <enumeratedValues>
                                <enumeratedValue>
                                    <name>0</name>
                                    <description>Disable reflection of register values to internal operations on assertion of vertical synchronization signal (VS)</description>
                                    <value>#0</value>
                                </enumeratedValue>
                                <enumeratedValue>
                                    <name>1</name>
                                    <description>Enable reflection of register values to internal operations on assertion of the vertical synchronization signal (VS)</description>
                                    <value>#1</value>
                                </enumeratedValue>
                            </enumeratedValues>
                        </field>
                    </fields>
                </register>
                <register>
                    <name>GAM_SW</name>
                    <description>Gamma Correction Block Function Switch Register</description>
                    <addressOffset>0x1304</addressOffset>
                    <size>32</size>
                    <access>read-write</access>
                    <resetValue>0x00000000</resetValue>
                    <resetMask>0xffffffff</resetMask>
                    <fields>
                        <field>
                            <name>GAMON</name>
                            <description>Gamma Correction On/Off Control</description>
                            <lsb>0</lsb>
                            <msb>0</msb>
                            <access>read-write</access>
                            <enumeratedValues>
                                <enumeratedValue>
                                    <name>0</name>
                                    <description>Turn off gamma correction</description>
                                    <value>#0</value>
                                </enumeratedValue>
                                <enumeratedValue>
                                    <name>1</name>
                                    <description>Turn on gamma correction</description>
                                    <value>#1</value>
                                </enumeratedValue>
                            </enumeratedValues>
                        </field>
                    </fields>
                </register>
                <register>
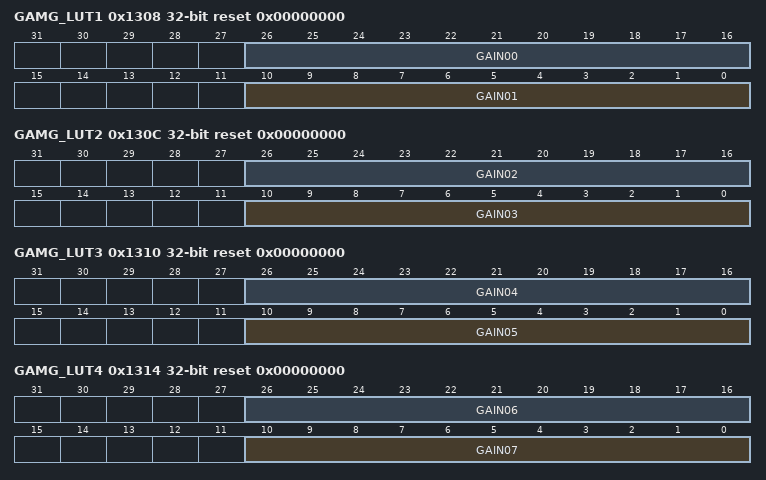
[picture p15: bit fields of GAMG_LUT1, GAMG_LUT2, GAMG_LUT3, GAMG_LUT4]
                    <name>GAMG_LUT1</name>
                    <description>Gamma G Correction Block Table Setting Register 1</description>
                    <addressOffset>0x1308</addressOffset>
                    <size>32</size>
                    <access>read-write</access>
                    <resetValue>0x00000000</resetValue>
                    <resetMask>0xffffffff</resetMask>
                    <fields>
                        <field>
                            <name>GAIN01</name>
                            <description>Gain Value of Area 1</description>
                            <lsb>0</lsb>
                            <msb>10</msb>
                            <access>read-write</access>
                        </field>
                        <field>
                            <name>GAIN00</name>
                            <description>Gain Value of Area 0</description>
                            <lsb>16</lsb>
                            <msb>26</msb>
                            <access>read-write</access>
                        </field>
                    </fields>
                </register>
                <register>
                    <name>GAMG_LUT2</name>
                    <description>Gamma G Correction Block Table Setting Register 2</description>
                    <addressOffset>0x130C</addressOffset>
                    <size>32</size>
                    <access>read-write</access>
                    <resetValue>0x00000000</resetValue>
                    <resetMask>0xffffffff</resetMask>
                    <fields>
                        <field>
                            <name>GAIN03</name>
                            <description>Gain Value of Area 3</description>
                            <lsb>0</lsb>
                            <msb>10</msb>
                            <access>read-write</access>
                        </field>
                        <field>
                            <name>GAIN02</name>
                            <description>Gain Value of Area 2</description>
                            <lsb>16</lsb>
                            <msb>26</msb>
                            <access>read-write</access>
                        </field>
                    </fields>
                </register>
                <register>
                    <name>GAMG_LUT3</name>
                    <description>Gamma G Correction Block Table Setting Register 3</description>
                    <addressOffset>0x1310</addressOffset>
                    <size>32</size>
                    <access>read-write</access>
                    <resetValue>0x00000000</resetValue>
                    <resetMask>0xffffffff</resetMask>
                    <fields>
                        <field>
                            <name>GAIN05</name>
                            <description>Gain Value of Area 5</description>
                            <lsb>0</lsb>
                            <msb>10</msb>
                            <access>read-write</access>
                        </field>
                        <field>
                            <name>GAIN04</name>
                            <description>Gain Value of Area 4</description>
                            <lsb>16</lsb>
                            <msb>26</msb>
                            <access>read-write</access>
                        </field>
                    </fields>
                </register>
                <register>
                    <name>GAMG_LUT4</name>
                    <description>Gamma G Correction Block Table Setting Register 4</description>
                    <addressOffset>0x1314</addressOffset>
                    <size>32</size>
                    <access>read-write</access>
                    <resetValue>0x00000000</resetValue>
                    <resetMask>0xffffffff</resetMask>
                    <fields>
                        <field>
                            <name>GAIN07</name>
                            <description>Gain Value of Area 7</description>
                            <lsb>0</lsb>
                            <msb>10</msb>
                            <access>read-write</access>
                        </field>
                        <field>
                            <name>GAIN06</name>
                            <description>Gain Value of Area 6</description>
                            <lsb>16</lsb>
                            <msb>26</msb>
                            <access>read-write</access>
                        </field>
                    </fields>
                </register>
                <register>
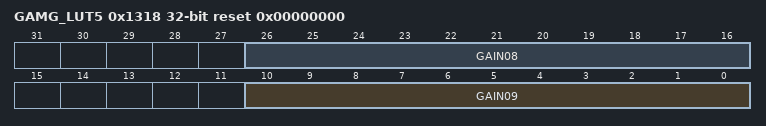
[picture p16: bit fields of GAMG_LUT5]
                    <name>GAMG_LUT5</name>
                    <description>Gamma G Correction Block Table Setting Register 5</description>
                    <addressOffset>0x1318</addressOffset>
                    <size>32</size>
                    <access>read-write</access>
                    <resetValue>0x00000000</resetValue>
                    <resetMask>0xffffffff</resetMask>
                    <fields>
                        <field>
                            <name>GAIN09</name>
                            <description>Gain Value of Area 9</description>
                            <lsb>0</lsb>
                            <msb>10</msb>
                            <access>read-write</access>
                        </field>
                        <field>
                            <name>GAIN08</name>
                            <description>Gain Value of Area 8</description>
                            <lsb>16</lsb>
                            <msb>26</msb>
                            <access>read-write</access>
                        </field>
                    </fields>
                </register>
                <register>
                    <name>GAMG_LUT6</name>
                    <description>Gamma G Correction Block Table Setting Register 6</description>
                    <addressOffset>0x131C</addressOffset>
                    <size>32</size>
                    <access>read-write</access>
                    <resetValue>0x00000000</resetValue>
                    <resetMask>0xffffffff</resetMask>
                    <fields>
                        <field>
                            <name>GAIN11</name>
                            <description>Gain Value of Area 11</description>
                            <lsb>0</lsb>
                            <msb>10</msb>
                            <access>read-write</access>
                        </field>
                        <field>
                            <name>GAIN10</name>
                            <description>Gain Value of Area 10</description>
                            <lsb>16</lsb>
                            <msb>26</msb>
                            <access>read-write</access>
                        </field>
                    </fields>
                </register>
                <register>
                    <name>GAMG_LUT7</name>
                    <description>Gamma G Correction Block Table Setting Register 7</description>
                    <addressOffset>0x1320</addressOffset>
                    <size>32</size>
                    <access>read-write</access>
                    <resetValue>0x00000000</resetValue>
                    <resetMask>0xffffffff</resetMask>
                    <fields>
                        <field>
                            <name>GAIN13</name>
                            <description>Gain Value of Area 13</description>
                            <lsb>0</lsb>
                            <msb>10</msb>
                            <access>read-write</access>
                        </field>
                        <field>
                            <name>GAIN12</name>
                            <description>Gain Value of Area 12</description>
                            <lsb>16</lsb>
                            <msb>26</msb>
                            <access>read-write</access>
                        </field>
                    </fields>
                </register>
                <register>
                    <name>GAMG_LUT8</name>
                    <description>Gamma G Correction Block Table Setting Register 8</description>
                    <addressOffset>0x1324</addressOffset>
                    <size>32</size>
                    <access>read-write</access>
                    <resetValue>0x00000000</resetValue>
                    <resetMask>0xffffffff</resetMask>
                    <fields>
                        <field>
                            <name>GAIN15</name>
                            <description>Gain Value of Area 15</description>
                            <lsb>0</lsb>
                            <msb>10</msb>
                            <access>read-write</access>
                        </field>
                        <field>
                            <name>GAIN14</name>
                            <description>Gain Value of Area 14</description>
                            <lsb>16</lsb>
                            <msb>26</msb>
                            <access>read-write</access>
                        </field>
                    </fields>
                </register>
                <register>
                    <name>GAMG_AREA1</name>
                    <description>Gamma G Correction Block Area Setting Register 1</description>
                    <addressOffset>0x1328</addressOffset>
                    <size>32</size>
                    <access>read-write</access>
                    <resetValue>0x00000000</resetValue>
                    <resetMask>0xffffffff</resetMask>
                    <fields>
                        <field>
                            <name>TH03</name>
                            <description>Start Threshold of Area 3</description>
                            <lsb>0</lsb>
                            <msb>9</msb>
                            <access>read-write</access>
                        </field>
                        <field>
                            <name>TH02</name>
                            <description>Start Threshold of Area 2</description>
                            <lsb>10</lsb>
                            <msb>19</msb>
                            <access>read-write</access>
                        </field>
                        <field>
                            <name>TH01</name>
                            <description>Start Threshold of Area 1</description>
                            <lsb>20</lsb>
                            <msb>29</msb>
                            <access>read-write</access>
                        </field>
                    </fields>
                </register>
                <register>
                    <name>GAMG_AREA2</name>
                    <description>Gamma G Correction Block Area Setting Register 2</description>
                    <addressOffset>0x132C</addressOffset>
                    <size>32</size>
                    <access>read-write</access>
                    <resetValue>0x00000000</resetValue>
                    <resetMask>0xffffffff</resetMask>
                    <fields>
                        <field>
                            <name>TH06</name>
                            <description>Start Threshold of Area 6</description>
                            <lsb>0</lsb>
                            <msb>9</msb>
                            <access>read-write</access>
                        </field>
                        <field>
                            <name>TH05</name>
                            <description>Start Threshold of Area 5</description>
                            <lsb>10</lsb>
                            <msb>19</msb>
                            <access>read-write</access>
                        </field>
                        <field>
                            <name>TH04</name>
                            <description>Start Threshold of Area 4</description>
                            <lsb>20</lsb>
                            <msb>29</msb>
                            <access>read-write</access>
                        </field>
                    </fields>
                </register>
                <register>
                    <name>GAMG_AREA3</name>
                    <description>Gamma G Correction Block Area Setting Register 3</description>
                    <addressOffset>0x1330</addressOffset>
                    <size>32</size>
                    <access>read-write</access>
                    <resetValue>0x00000000</resetValue>
                    <resetMask>0xffffffff</resetMask>
                    <fields>
                        <field>
                            <name>TH09</name>
                            <description>Start Threshold of Area 9</description>
                            <lsb>0</lsb>
                            <msb>9</msb>
                            <access>read-write</access>
                        </field>
                        <field>
                            <name>TH08</name>
                            <description>Start Threshold of Area 8</description>
                            <lsb>10</lsb>
                            <msb>19</msb>
                            <access>read-write</access>
                        </field>
                        <field>
                            <name>TH07</name>
                            <description>Start Threshold of Area 7</description>
                            <lsb>20</lsb>
                            <msb>29</msb>
                            <access>read-write</access>
                        </field>
                    </fields>
                </register>
                <register>
                    <name>GAMG_AREA4</name>
                    <description>Gamma G Correction Block Area Setting Register 4</description>
                    <addressOffset>0x1334</addressOffset>
                    <size>32</size>
                    <access>read-write</access>
                    <resetValue>0x00000000</resetValue>
                    <resetMask>0xffffffff</resetMask>
                    <fields>
                        <field>
                            <name>TH12</name>
                            <description>Start Threshold of Area 12</description>
                            <lsb>0</lsb>
                            <msb>9</msb>
                            <access>read-write</access>
                        </field>
                        <field>
                            <name>TH11</name>
                            <description>Start Threshold of Area 11</description>
                            <lsb>10</lsb>
                            <msb>19</msb>
                            <access>read-write</access>
                        </field>
                        <field>
                            <name>TH10</name>
                            <description>Start Threshold of Area 10</description>
                            <lsb>20</lsb>
                            <msb>29</msb>
                            <access>read-write</access>
                        </field>
                    </fields>
                </register>
                <register>
                    <name>GAMG_AREA5</name>
                    <description>Gamma G Correction Block Area Setting Register 5</description>
                    <addressOffset>0x1338</addressOffset>
                    <size>32</size>
                    <access>read-write</access>
                    <resetValue>0x00000000</resetValue>
                    <resetMask>0xffffffff</resetMask>
                    <fields>
                        <field>
                            <name>TH15</name>
                            <description>Start Threshold of Area 15</description>
                            <lsb>0</lsb>
                            <msb>9</msb>
                            <access>read-write</access>
                        </field>
                        <field>
                            <name>TH14</name>
                            <description>Start Threshold of Area 14</description>
                            <lsb>10</lsb>
                            <msb>19</msb>
                            <access>read-write</access>
                        </field>
                        <field>
                            <name>TH13</name>
                            <description>Start Threshold of Area 13</description>
                            <lsb>20</lsb>
                            <msb>29</msb>
                            <access>read-write</access>
                        </field>
                    </fields>
                </register>
                <register>
                    <name>GAMB_LATCH</name>
                    <description>Gamma B Register Update Control Register</description>
                    <addressOffset>0x1340</addressOffset>
                    <size>32</size>
                    <access>read-write</access>
                    <resetValue>0x00000000</resetValue>
                    <resetMask>0xffffffff</resetMask>
                    <fields>
                        <field>
                            <name>VEN</name>
                            <description>Control of Gamma Correction × Module Register Value Reflection to Internal Operations</description>
                            <lsb>0</lsb>
                            <msb>0</msb>
                            <access>read-write</access>
                            <enumeratedValues>
                                <enumeratedValue>
                                    <name>0</name>
                                    <description>Disable reflection of register values to internal operations on assertion of vertical synchronization signal (VS)</description>
                                    <value>#0</value>
                                </enumeratedValue>
                                <enumeratedValue>
                                    <name>1</name>
                                    <description>Enable reflection of register values to internal operations on assertion of the vertical synchronization signal (VS)</description>
                                    <value>#1</value>
                                </enumeratedValue>
                            </enumeratedValues>
                        </field>
                    </fields>
                </register>
                <register>
                    <name>GAMB_LUT1</name>
                    <description>Gamma B Correction Block Table Setting Register 1</description>
                    <addressOffset>0x1348</addressOffset>
                    <size>32</size>
                    <access>read-write</access>
                    <resetValue>0x00000000</resetValue>
                    <resetMask>0xffffffff</resetMask>
                    <fields>
                        <field>
                            <name>GAIN01</name>
                            <description>Gain Value of Area 1</description>
                            <lsb>0</lsb>
                            <msb>10</msb>
                            <access>read-write</access>
                        </field>
                        <field>
                            <name>GAIN00</name>
                            <description>Gain Value of Area 0</description>
                            <lsb>16</lsb>
                            <msb>26</msb>
                            <access>read-write</access>
                        </field>
                    </fields>
                </register>
                <register>
                    <name>GAMB_LUT2</name>
                    <description>Gamma B Correction Block Table Setting Register 2</description>
                    <addressOffset>0x134C</addressOffset>
                    <size>32</size>
                    <access>read-write</access>
                    <resetValue>0x00000000</resetValue>
                    <resetMask>0xffffffff</resetMask>
                    <fields>
                        <field>
                            <name>GAIN03</name>
                            <description>Gain Value of Area 3</description>
                            <lsb>0</lsb>
                            <msb>10</msb>
                            <access>read-write</access>
                        </field>
                        <field>
                            <name>GAIN02</name>
                            <description>Gain Value of Area 2</description>
                            <lsb>16</lsb>
                            <msb>26</msb>
                            <access>read-write</access>
                        </field>
                    </fields>
                </register>
                <register>
                    <name>GAMB_LUT3</name>
                    <description>Gamma B Correction Block Table Setting Register 3</description>
                    <addressOffset>0x1350</addressOffset>
                    <size>32</size>
                    <access>read-write</access>
                    <resetValue>0x00000000</resetValue>
                    <resetMask>0xffffffff</resetMask>
                    <fields>
                        <field>
                            <name>GAIN05</name>
                            <description>Gain Value of Area 5</description>
                            <lsb>0</lsb>
                            <msb>10</msb>
                            <access>read-write</access>
                        </field>
                        <field>
                            <name>GAIN04</name>
                            <description>Gain Value of Area 4</description>
                            <lsb>16</lsb>
                            <msb>26</msb>
                            <access>read-write</access>
                        </field>
                    </fields>
                </register>
                <register>
                    <name>GAMB_LUT4</name>
                    <description>Gamma B Correction Block Table Setting Register 4</description>
                    <addressOffset>0x1354</addressOffset>
                    <size>32</size>
                    <access>read-write</access>
                    <resetValue>0x00000000</resetValue>
                    <resetMask>0xffffffff</resetMask>
                    <fields>
                        <field>
                            <name>GAIN07</name>
                            <description>Gain Value of Area 7</description>
                            <lsb>0</lsb>
                            <msb>10</msb>
                            <access>read-write</access>
                        </field>
                        <field>
                            <name>GAIN06</name>
                            <description>Gain Value of Area 6</description>
                            <lsb>16</lsb>
                            <msb>26</msb>
                            <access>read-write</access>
                        </field>
                    </fields>
                </register>
                <register>
                    <name>GAMB_LUT5</name>
                    <description>Gamma B Correction Block Table Setting Register 5</description>
                    <addressOffset>0x1358</addressOffset>
                    <size>32</size>
                    <access>read-write</access>
                    <resetValue>0x00000000</resetValue>
                    <resetMask>0xffffffff</resetMask>
                    <fields>
                        <field>
                            <name>GAIN09</name>
                            <description>Gain Value of Area 9</description>
                            <lsb>0</lsb>
                            <msb>10</msb>
                            <access>read-write</access>
                        </field>
                        <field>
                            <name>GAIN08</name>
                            <description>Gain Value of Area 8</description>
                            <lsb>16</lsb>
                            <msb>26</msb>
                            <access>read-write</access>
                        </field>
                    </fields>
                </register>
                <register>
                    <name>GAMB_LUT6</name>
                    <description>Gamma B Correction Block Table Setting Register 6</description>
                    <addressOffset>0x135C</addressOffset>
                    <size>32</size>
                    <access>read-write</access>
                    <resetValue>0x00000000</resetValue>
                    <resetMask>0xffffffff</resetMask>
                    <fields>
                        <field>
                            <name>GAIN11</name>
                            <description>Gain Value of Area 11</description>
                            <lsb>0</lsb>
                            <msb>10</msb>
                            <access>read-write</access>
                        </field>
                        <field>
                            <name>GAIN10</name>
                            <description>Gain Value of Area 10</description>
                            <lsb>16</lsb>
                            <msb>26</msb>
                            <access>read-write</access>
                        </field>
                    </fields>
                </register>
                <register>
                    <name>GAMB_LUT7</name>
                    <description>Gamma B Correction Block Table Setting Register 7</description>
                    <addressOffset>0x1360</addressOffset>
                    <size>32</size>
                    <access>read-write</access>
                    <resetValue>0x00000000</resetValue>
                    <resetMask>0xffffffff</resetMask>
                    <fields>
                        <field>
                            <name>GAIN13</name>
                            <description>Gain Value of Area 13</description>
                            <lsb>0</lsb>
                            <msb>10</msb>
                            <access>read-write</access>
                        </field>
                        <field>
                            <name>GAIN12</name>
                            <description>Gain Value of Area 12</description>
                            <lsb>16</lsb>
                            <msb>26</msb>
                            <access>read-write</access>
                        </field>
                    </fields>
                </register>
                <register>
                    <name>GAMB_LUT8</name>
                    <description>Gamma B Correction Block Table Setting Register 8</description>
                    <addressOffset>0x1364</addressOffset>
                    <size>32</size>
                    <access>read-write</access>
                    <resetValue>0x00000000</resetValue>
                    <resetMask>0xffffffff</resetMask>
                    <fields>
                        <field>
                            <name>GAIN15</name>
                            <description>Gain Value of Area 15</description>
                            <lsb>0</lsb>
                            <msb>10</msb>
                            <access>read-write</access>
                        </field>
                        <field>
                            <name>GAIN14</name>
                            <description>Gain Value of Area 14</description>
                            <lsb>16</lsb>
                            <msb>26</msb>
                            <access>read-write</access>
                        </field>
                    </fields>
                </register>
                <register>
                    <name>GAMB_AREA1</name>
                    <description>Gamma B Correction Block Area Setting Register 1</description>
                    <addressOffset>0x1368</addressOffset>
                    <size>32</size>
                    <access>read-write</access>
                    <resetValue>0x00000000</resetValue>
                    <resetMask>0xffffffff</resetMask>
                    <fields>
                        <field>
                            <name>TH03</name>
                            <description>Start Threshold of Area 3</description>
                            <lsb>0</lsb>
                            <msb>9</msb>
                            <access>read-write</access>
                        </field>
                        <field>
                            <name>TH02</name>
                            <description>Start Threshold of Area 2</description>
                            <lsb>10</lsb>
                            <msb>19</msb>
                            <access>read-write</access>
                        </field>
                        <field>
                            <name>TH01</name>
                            <description>Start Threshold of Area 1</description>
                            <lsb>20</lsb>
                            <msb>29</msb>
                            <access>read-write</access>
                        </field>
                    </fields>
                </register>
                <register>
                    <name>GAMB_AREA2</name>
                    <description>Gamma B Correction Block Area Setting Register 2</description>
                    <addressOffset>0x136C</addressOffset>
                    <size>32</size>
                    <access>read-write</access>
                    <resetValue>0x00000000</resetValue>
                    <resetMask>0xffffffff</resetMask>
                    <fields>
                        <field>
                            <name>TH06</name>
                            <description>Start Threshold of Area 6</description>
                            <lsb>0</lsb>
                            <msb>9</msb>
                            <access>read-write</access>
                        </field>
                        <field>
                            <name>TH05</name>
                            <description>Start Threshold of Area 5</description>
                            <lsb>10</lsb>
                            <msb>19</msb>
                            <access>read-write</access>
                        </field>
                        <field>
                            <name>TH04</name>
                            <description>Start Threshold of Area 4</description>
                            <lsb>20</lsb>
                            <msb>29</msb>
                            <access>read-write</access>
                        </field>
                    </fields>
                </register>
                <register>
                    <name>GAMB_AREA3</name>
                    <description>Gamma B Correction Block Area Setting Register 3</description>
                    <addressOffset>0x1370</addressOffset>
                    <size>32</size>
                    <access>read-write</access>
                    <resetValue>0x00000000</resetValue>
                    <resetMask>0xffffffff</resetMask>
                    <fields>
                        <field>
                            <name>TH09</name>
                            <description>Start Threshold of Area 9</description>
                            <lsb>0</lsb>
                            <msb>9</msb>
                            <access>read-write</access>
                        </field>
                        <field>
                            <name>TH08</name>
                            <description>Start Threshold of Area 8</description>
                            <lsb>10</lsb>
                            <msb>19</msb>
                            <access>read-write</access>
                        </field>
                        <field>
                            <name>TH07</name>
                            <description>Start Threshold of Area 7</description>
                            <lsb>20</lsb>
                            <msb>29</msb>
                            <access>read-write</access>
                        </field>
                    </fields>
                </register>
                <register>
                    <name>GAMB_AREA4</name>
                    <description>Gamma B Correction Block Area Setting Register 4</description>
                    <addressOffset>0x1374</addressOffset>
                    <size>32</size>
                    <access>read-write</access>
                    <resetValue>0x00000000</resetValue>
                    <resetMask>0xffffffff</resetMask>
                    <fields>
                        <field>
                            <name>TH12</name>
                            <description>Start Threshold of Area 12</description>
                            <lsb>0</lsb>
                            <msb>9</msb>
                            <access>read-write</access>
                        </field>
                        <field>
                            <name>TH11</name>
                            <description>Start Threshold of Area 11</description>
                            <lsb>10</lsb>
                            <msb>19</msb>
                            <access>read-write</access>
                        </field>
                        <field>
                            <name>TH10</name>
                            <description>Start Threshold of Area 10</description>
                            <lsb>20</lsb>
                            <msb>29</msb>
                            <access>read-write</access>
                        </field>
                    </fields>
                </register>
                <register>
                    <name>GAMB_AREA5</name>
                    <description>Gamma B Correction Block Area Setting Register 5</description>
                    <addressOffset>0x1378</addressOffset>
                    <size>32</size>
                    <access>read-write</access>
                    <resetValue>0x00000000</resetValue>
                    <resetMask>0xffffffff</resetMask>
                    <fields>
                        <field>
                            <name>TH15</name>
                            <description>Start Threshold of Area 15</description>
                            <lsb>0</lsb>
                            <msb>9</msb>
                            <access>read-write</access>
                        </field>
                        <field>
                            <name>TH14</name>
                            <description>Start Threshold of Area 14</description>
                            <lsb>10</lsb>
                            <msb>19</msb>
                            <access>read-write</access>
                        </field>
                        <field>
                            <name>TH13</name>
                            <description>Start Threshold of Area 13</description>
                            <lsb>20</lsb>
                            <msb>29</msb>
                            <access>read-write</access>
                        </field>
                    </fields>
                </register>
                <register>
                    <name>GAMR_LATCH</name>
                    <description>Gamma R Register Update Control Register</description>
                    <addressOffset>0x1380</addressOffset>
                    <size>32</size>
                    <access>read-write</access>
                    <resetValue>0x00000000</resetValue>
                    <resetMask>0xffffffff</resetMask>
                    <fields>
                        <field>
                            <name>VEN</name>
                            <description>Control of Gamma Correction × Module Register Value Reflection to Internal Operations</description>
                            <lsb>0</lsb>
                            <msb>0</msb>
                            <access>read-write</access>
                            <enumeratedValues>
                                <enumeratedValue>
                                    <name>0</name>
                                    <description>Disable reflection of register values to internal operations on assertion of vertical synchronization signal (VS)</description>
                                    <value>#0</value>
                                </enumeratedValue>
                                <enumeratedValue>
                                    <name>1</name>
                                    <description>Enable reflection of register values to internal operations on assertion of the vertical synchronization signal (VS)</description>
                                    <value>#1</value>
                                </enumeratedValue>
                            </enumeratedValues>
                        </field>
                    </fields>
                </register>
                <register>
                    <name>GAMR_LUT1</name>
                    <description>Gamma R Correction Block Table Setting Register 1</description>
                    <addressOffset>0x1388</addressOffset>
                    <size>32</size>
                    <access>read-write</access>
                    <resetValue>0x00000000</resetValue>
                    <resetMask>0xffffffff</resetMask>
                    <fields>
                        <field>
                            <name>GAIN01</name>
                            <description>Gain Value of Area 1</description>
                            <lsb>0</lsb>
                            <msb>10</msb>
                            <access>read-write</access>
                        </field>
                        <field>
                            <name>GAIN00</name>
                            <description>Gain Value of Area 0</description>
                            <lsb>16</lsb>
                            <msb>26</msb>
                            <access>read-write</access>
                        </field>
                    </fields>
                </register>
                <register>
                    <name>GAMR_LUT2</name>
                    <description>Gamma R Correction Block Table Setting Register 2</description>
                    <addressOffset>0x138C</addressOffset>
                    <size>32</size>
                    <access>read-write</access>
                    <resetValue>0x00000000</resetValue>
                    <resetMask>0xffffffff</resetMask>
                    <fields>
                        <field>
                            <name>GAIN03</name>
                            <description>Gain Value of Area 3</description>
                            <lsb>0</lsb>
                            <msb>10</msb>
                            <access>read-write</access>
                        </field>
                        <field>
                            <name>GAIN02</name>
                            <description>Gain Value of Area 2</description>
                            <lsb>16</lsb>
                            <msb>26</msb>
                            <access>read-write</access>
                        </field>
                    </fields>
                </register>
                <register>
                    <name>GAMR_LUT3</name>
                    <description>Gamma R Correction Block Table Setting Register 3</description>
                    <addressOffset>0x1390</addressOffset>
                    <size>32</size>
                    <access>read-write</access>
                    <resetValue>0x00000000</resetValue>
                    <resetMask>0xffffffff</resetMask>
                    <fields>
                        <field>
                            <name>GAIN05</name>
                            <description>Gain Value of Area 5</description>
                            <lsb>0</lsb>
                            <msb>10</msb>
                            <access>read-write</access>
                        </field>
                        <field>
                            <name>GAIN04</name>
                            <description>Gain Value of Area 4</description>
                            <lsb>16</lsb>
                            <msb>26</msb>
                            <access>read-write</access>
                        </field>
                    </fields>
                </register>
                <register>
                    <name>GAMR_LUT4</name>
                    <description>Gamma R Correction Block Table Setting Register 4</description>
                    <addressOffset>0x1394</addressOffset>
                    <size>32</size>
                    <access>read-write</access>
                    <resetValue>0x00000000</resetValue>
                    <resetMask>0xffffffff</resetMask>
                    <fields>
                        <field>
                            <name>GAIN07</name>
                            <description>Gain Value of Area 7</description>
                            <lsb>0</lsb>
                            <msb>10</msb>
                            <access>read-write</access>
                        </field>
                        <field>
                            <name>GAIN06</name>
                            <description>Gain Value of Area 6</description>
                            <lsb>16</lsb>
                            <msb>26</msb>
                            <access>read-write</access>
                        </field>
                    </fields>
                </register>
                <register>
                    <name>GAMR_LUT5</name>
                    <description>Gamma R Correction Block Table Setting Register 5</description>
                    <addressOffset>0x1398</addressOffset>
                    <size>32</size>
                    <access>read-write</access>
                    <resetValue>0x00000000</resetValue>
                    <resetMask>0xffffffff</resetMask>
                    <fields>
                        <field>
                            <name>GAIN09</name>
                            <description>Gain Value of Area 9</description>
                            <lsb>0</lsb>
                            <msb>10</msb>
                            <access>read-write</access>
                        </field>
                        <field>
                            <name>GAIN08</name>
                            <description>Gain Value of Area 8</description>
                            <lsb>16</lsb>
                            <msb>26</msb>
                            <access>read-write</access>
                        </field>
                    </fields>
                </register>
                <register>
                    <name>GAMR_LUT6</name>
                    <description>Gamma R Correction Block Table Setting Register 6</description>
                    <addressOffset>0x139C</addressOffset>
                    <size>32</size>
                    <access>read-write</access>
                    <resetValue>0x00000000</resetValue>
                    <resetMask>0xffffffff</resetMask>
                    <fields>
                        <field>
                            <name>GAIN11</name>
                            <description>Gain Value of Area 11</description>
                            <lsb>0</lsb>
                            <msb>10</msb>
                            <access>read-write</access>
                        </field>
                        <field>
                            <name>GAIN10</name>
                            <description>Gain Value of Area 10</description>
                            <lsb>16</lsb>
                            <msb>26</msb>
                            <access>read-write</access>
                        </field>
                    </fields>
                </register>
                <register>
                    <name>GAMR_LUT7</name>
                    <description>Gamma R Correction Block Table Setting Register 7</description>
                    <addressOffset>0x13A0</addressOffset>
                    <size>32</size>
                    <access>read-write</access>
                    <resetValue>0x00000000</resetValue>
                    <resetMask>0xffffffff</resetMask>
                    <fields>
                        <field>
                            <name>GAIN13</name>
                            <description>Gain Value of Area 13</description>
                            <lsb>0</lsb>
                            <msb>10</msb>
                            <access>read-write</access>
                        </field>
                        <field>
                            <name>GAIN12</name>
                            <description>Gain Value of Area 12</description>
                            <lsb>16</lsb>
                            <msb>26</msb>
                            <access>read-write</access>
                        </field>
                    </fields>
                </register>
                <register>
                    <name>GAMR_LUT8</name>
                    <description>Gamma R Correction Block Table Setting Register 8</description>
                    <addressOffset>0x13A4</addressOffset>
                    <size>32</size>
                    <access>read-write</access>
                    <resetValue>0x00000000</resetValue>
                    <resetMask>0xffffffff</resetMask>
                    <fields>
                        <field>
                            <name>GAIN15</name>
                            <description>Gain Value of Area 15</description>
                            <lsb>0</lsb>
                            <msb>10</msb>
                            <access>read-write</access>
                        </field>
                        <field>
                            <name>GAIN14</name>
                            <description>Gain Value of Area 14</description>
                            <lsb>16</lsb>
                            <msb>26</msb>
                            <access>read-write</access>
                        </field>
                    </fields>
                </register>
                <register>
                    <name>GAMR_AREA1</name>
                    <description>Gamma R Correction Block Area Setting Register 1</description>
                    <addressOffset>0x13A8</addressOffset>
                    <size>32</size>
                    <access>read-write</access>
                    <resetValue>0x00000000</resetValue>
                    <resetMask>0xffffffff</resetMask>
                    <fields>
                        <field>
                            <name>TH03</name>
                            <description>Start Threshold of Area 3</description>
                            <lsb>0</lsb>
                            <msb>9</msb>
                            <access>read-write</access>
                        </field>
                        <field>
                            <name>TH02</name>
                            <description>Start Threshold of Area 2</description>
                            <lsb>10</lsb>
                            <msb>19</msb>
                            <access>read-write</access>
                        </field>
                        <field>
                            <name>TH01</name>
                            <description>Start Threshold of Area 1</description>
                            <lsb>20</lsb>
                            <msb>29</msb>
                            <access>read-write</access>
                        </field>
                    </fields>
                </register>
                <register>
                    <name>GAMR_AREA2</name>
                    <description>Gamma R Correction Block Area Setting Register 2</description>
                    <addressOffset>0x13AC</addressOffset>
                    <size>32</size>
                    <access>read-write</access>
                    <resetValue>0x00000000</resetValue>
                    <resetMask>0xffffffff</resetMask>
                    <fields>
                        <field>
                            <name>TH06</name>
                            <description>Start Threshold of Area 6</description>
                            <lsb>0</lsb>
                            <msb>9</msb>
                            <access>read-write</access>
                        </field>
                        <field>
                            <name>TH05</name>
                            <description>Start Threshold of Area 5</description>
                            <lsb>10</lsb>
                            <msb>19</msb>
                            <access>read-write</access>
                        </field>
                        <field>
                            <name>TH04</name>
                            <description>Start Threshold of Area 4</description>
                            <lsb>20</lsb>
                            <msb>29</msb>
                            <access>read-write</access>
                        </field>
                    </fields>
                </register>
                <register>
                    <name>GAMR_AREA3</name>
                    <description>Gamma R Correction Block Area Setting Register 3</description>
                    <addressOffset>0x13B0</addressOffset>
                    <size>32</size>
                    <access>read-write</access>
                    <resetValue>0x00000000</resetValue>
                    <resetMask>0xffffffff</resetMask>
                    <fields>
                        <field>
                            <name>TH09</name>
                            <description>Start Threshold of Area 9</description>
                            <lsb>0</lsb>
                            <msb>9</msb>
                            <access>read-write</access>
                        </field>
                        <field>
                            <name>TH08</name>
                            <description>Start Threshold of Area 8</description>
                            <lsb>10</lsb>
                            <msb>19</msb>
                            <access>read-write</access>
                        </field>
                        <field>
                            <name>TH07</name>
                            <description>Start Threshold of Area 7</description>
                            <lsb>20</lsb>
                            <msb>29</msb>
                            <access>read-write</access>
                        </field>
                    </fields>
                </register>
                <register>
                    <name>GAMR_AREA4</name>
                    <description>Gamma R Correction Block Area Setting Register 4</description>
                    <addressOffset>0x13B4</addressOffset>
                    <size>32</size>
                    <access>read-write</access>
                    <resetValue>0x00000000</resetValue>
                    <resetMask>0xffffffff</resetMask>
                    <fields>
                        <field>
                            <name>TH12</name>
                            <description>Start Threshold of Area 12</description>
                            <lsb>0</lsb>
                            <msb>9</msb>
                            <access>read-write</access>
                        </field>
                        <field>
                            <name>TH11</name>
                            <description>Start Threshold of Area 11</description>
                            <lsb>10</lsb>
                            <msb>19</msb>
                            <access>read-write</access>
                        </field>
                        <field>
                            <name>TH10</name>
                            <description>Start Threshold of Area 10</description>
                            <lsb>20</lsb>
                            <msb>29</msb>
                            <access>read-write</access>
                        </field>
                    </fields>
                </register>
                <register>
                    <name>GAMR_AREA5</name>
                    <description>Gamma R Correction Block Area Setting Register 5</description>
                    <addressOffset>0x13B8</addressOffset>
                    <size>32</size>
                    <access>read-write</access>
                    <resetValue>0x00000000</resetValue>
                    <resetMask>0xffffffff</resetMask>
                    <fields>
                        <field>
                            <name>TH15</name>
                            <description>Start Threshold of Area 15</description>
                            <lsb>0</lsb>
                            <msb>9</msb>
                            <access>read-write</access>
                        </field>
                        <field>
                            <name>TH14</name>
                            <description>Start Threshold of Area 14</description>
                            <lsb>10</lsb>
                            <msb>19</msb>
                            <access>read-write</access>
                        </field>
                        <field>
                            <name>TH13</name>
                            <description>Start Threshold of Area 13</description>
                            <lsb>20</lsb>
                            <msb>29</msb>
                            <access>read-write</access>
                        </field>
                    </fields>
                </register>
                <register>
                    <name>OUT_VLATCH</name>
                    <description>Output Control Block Register Update Control Register</description>
                    <addressOffset>0x13C0</addressOffset>
                    <size>32</size>
                    <access>read-write</access>
                    <resetValue>0x00000000</resetValue>
                    <resetMask>0xffffffff</resetMask>
                    <fields>
                        <field>
                            <name>VEN</name>
                            <description>Control of Output Control Module Register Value Reflection to Internal Operations</description>
                            <lsb>0</lsb>
                            <msb>0</msb>
                            <access>read-write</access>
                            <enumeratedValues>
                                <enumeratedValue>
                                    <name>0</name>
                                    <description>Disable reflection of register values to internal operations on assertion of vertical synchronization signal (VS)</description>
                                    <value>#0</value>
                                </enumeratedValue>
                                <enumeratedValue>
                                    <name>1</name>
                                    <description>Enable reflection of register values to internal operations on assertion of vertical synchronization signal (VS).</description>
                                    <value>#1</value>
                                </enumeratedValue>
                            </enumeratedValues>
                        </field>
                    </fields>
                </register>
                <register>
                    <name>OUT_SET</name>
                    <description>Output Control Block Output Interface Register</description>
                    <addressOffset>0x13C4</addressOffset>
                    <size>32</size>
                    <access>read-write</access>
                    <resetValue>0x00000000</resetValue>
                    <resetMask>0xffffffff</resetMask>
                    <fields>
                        <field>
                            <name>PHASE</name>
                            <description>Data Output Delay Control in Serial RGB Format</description>
                            <lsb>0</lsb>
                            <msb>1</msb>
                            <access>read-write</access>
                            <enumeratedValues>
                                <enumeratedValue>
                                    <name>00</name>
                                    <description>0 cycle</description>
                                    <value>#00</value>
                                </enumeratedValue>
                                <enumeratedValue>
                                    <name>01</name>
                                    <description>1 cycle</description>
                                    <value>#01</value>
                                </enumeratedValue>
                                <enumeratedValue>
                                    <name>10</name>
                                    <description>2 cycles</description>
                                    <value>#10</value>
                                </enumeratedValue>
                                <enumeratedValue>
                                    <name>11</name>
                                    <description>3 cycles</description>
                                    <value>#11</value>
                                </enumeratedValue>
                            </enumeratedValues>
                        </field>
                        <field>
                            <name>DIRSEL</name>
                            <description>Scan Direction Select of Serial RGB Format</description>
                            <lsb>4</lsb>
                            <msb>4</msb>
                            <access>read-write</access>
                            <enumeratedValues>
                                <enumeratedValue>
                                    <name>0</name>
                                    <description>Forward scan</description>
                                    <value>#0</value>
                                </enumeratedValue>
                                <enumeratedValue>
                                    <name>1</name>
                                    <description>Reverse scan</description>
                                    <value>#1</value>
                                </enumeratedValue>
                            </enumeratedValues>
                        </field>
                        <field>
                            <name>FRQSEL</name>
                            <description>Clock Frequency Division Control</description>
                            <lsb>8</lsb>
                            <msb>9</msb>
                            <access>read-write</access>
                            <enumeratedValues>
                                <enumeratedValue>
                                    <name>00</name>
                                    <description>No frequency division, parallel RGB</description>
                                    <value>#00</value>
                                </enumeratedValue>
                                <enumeratedValue>
                                    <name>01</name>
                                    <description>Setting prohibited</description>
                                    <value>#01</value>
                                </enumeratedValue>
                                <enumeratedValue>
                                    <name>10</name>
                                    <description>Quarter frequency (serial RGB)</description>
                                    <value>#10</value>
                                </enumeratedValue>
                                <enumeratedValue>
                                    <name>11</name>
                                    <description>Setting prohibited</description>
                                    <value>#11</value>
                                </enumeratedValue>
                            </enumeratedValues>
                        </field>
                        <field>
                            <name>FORMAT</name>
                            <description>Output Format Select</description>
                            <lsb>12</lsb>
                            <msb>13</msb>
                            <access>read-write</access>
                            <enumeratedValues>
                                <enumeratedValue>
                                    <name>00</name>
                                    <description>RGB888 — select RGB888 as dither output format</description>
                                    <value>#00</value>
                                </enumeratedValue>
                                <enumeratedValue>
                                    <name>01</name>
                                    <description>RGB666 — select RGB666 as dither output format</description>
                                    <value>#01</value>
                                </enumeratedValue>
                                <enumeratedValue>
                                    <name>10</name>
                                    <description>RGB565 — select RGB565 as dither output format</description>
                                    <value>#10</value>
                                </enumeratedValue>
                                <enumeratedValue>
                                    <name>11</name>
                                    <description>Serial RGB — select RGB888 as dither output format. Select dither output format in OUT_PDTHA.FORM[1:0] </description>
                                    <value>#11</value>
                                </enumeratedValue>
                            </enumeratedValues>
                        </field>
                        <field>
                            <name>SWAPON</name>
                            <description>Pixel Order Control</description>
                            <lsb>24</lsb>
                            <msb>24</msb>
                            <access>read-write</access>
                            <enumeratedValues>
                                <enumeratedValue>
                                    <name>0</name>
                                    <description>RGB order</description>
                                    <value>#0</value>
                                </enumeratedValue>
                                <enumeratedValue>
                                    <name>1</name>
                                    <description>BGR order</description>
                                    <value>#1</value>
                                </enumeratedValue>
                            </enumeratedValues>
                        </field>
                        <field>
                            <name>ENDIANON</name>
                            <description>Bit Endian Control</description>
                            <lsb>28</lsb>
                            <msb>28</msb>
                            <access>read-write</access>
                            <enumeratedValues>
                                <enumeratedValue>
                                    <name>0</name>
                                    <description>Descending order (little endian)</description>
                                    <value>#0</value>
                                </enumeratedValue>
                                <enumeratedValue>
                                    <name>1</name>
                                    <description>Ascending order (big endian)</description>
                                    <value>#1</value>
                                </enumeratedValue>
                            </enumeratedValues>
                        </field>
                    </fields>
                </register>
                <register>
                    <name>OUT_BRIGHT1</name>
                    <description>Output Control Block Brightness Correction Register 1</description>
                    <addressOffset>0x13C8</addressOffset>
                    <size>32</size>
                    <access>read-write</access>
                    <resetValue>0x00000000</resetValue>
                    <resetMask>0xffffffff</resetMask>
                    <fields>
                        <field>
                            <name>BRTG</name>
                            <description>Brightness Adjustment of G Signal</description>
                            <lsb>0</lsb>
                            <msb>9</msb>
                            <access>read-write</access>
                        </field>
                    </fields>
                </register>
                <register>
                    <name>OUT_BRIGHT2</name>
                    <description>Output Control Block Brightness Correction Register 2</description>
                    <addressOffset>0x13CC</addressOffset>
                    <size>32</size>
                    <access>read-write</access>
                    <resetValue>0x00000000</resetValue>
                    <resetMask>0xffffffff</resetMask>
                    <fields>
                        <field>
                            <name>BRTR</name>
                            <description>Brightness Adjustment of R Signal</description>
                            <lsb>0</lsb>
                            <msb>9</msb>
                            <access>read-write</access>
                        </field>
                        <field>
                            <name>BRTB</name>
                            <description>Brightness Adjustment of B Signal</description>
                            <lsb>16</lsb>
                            <msb>25</msb>
                            <access>read-write</access>
                        </field>
                    </fields>
                </register>
                <register>
                    <name>OUT_CONTRAST</name>
                    <description>Output Control Block Contrast Correction Register</description>
                    <addressOffset>0x13D0</addressOffset>
                    <size>32</size>
                    <access>read-write</access>
                    <resetValue>0x00000000</resetValue>
                    <resetMask>0xffffffff</resetMask>
                    <fields>
                        <field>
                            <name>CONTR</name>
                            <description>Contrast Adjustment of R Signal</description>
                            <lsb>0</lsb>
                            <msb>7</msb>
                            <access>read-write</access>
                        </field>
                        <field>
                            <name>CONTB</name>
                            <description>Contrast Adjustment of B Signal</description>
                            <lsb>8</lsb>
                            <msb>15</msb>
                            <access>read-write</access>
                        </field>
                        <field>
                            <name>CONTG</name>
                            <description>Contrast Adjustment of G Signal</description>
                            <lsb>16</lsb>
                            <msb>23</msb>
                            <access>read-write</access>
                        </field>
                    </fields>
                </register>
                <register>
                    <name>OUT_PDTHA</name>
                    <description>Output Control Block Panel Dither Correction Register</description>
                    <addressOffset>0x13D4</addressOffset>
                    <size>32</size>
                    <access>read-write</access>
                    <resetValue>0x00000000</resetValue>
                    <resetMask>0xffffffff</resetMask>
                    <fields>
                        <field>
                            <name>PD</name>
                            <description>Pattern Value (D) of 2×2 Pattern Dither</description>
                            <lsb>0</lsb>
                            <msb>1</msb>
                            <access>read-write</access>
                        </field>
                        <field>
                            <name>PC</name>
                            <description>Pattern Value (C) of 2×2 Pattern Dither</description>
                            <lsb>4</lsb>
                            <msb>5</msb>
                            <access>read-write</access>
                        </field>
                        <field>
                            <name>PB</name>
                            <description>Pattern Value (B) of 2×2 Pattern Dither</description>
                            <lsb>8</lsb>
                            <msb>9</msb>
                            <access>read-write</access>
                        </field>
                        <field>
                            <name>PA</name>
                            <description>Pattern Value (A) of 2×2 Pattern Dither</description>
                            <lsb>12</lsb>
                            <msb>13</msb>
                            <access>read-write</access>
                        </field>
                        <field>
                            <name>FORM</name>
                            <description>Output Format Select</description>
                            <lsb>16</lsb>
                            <msb>17</msb>
                            <access>read-write</access>
                            <enumeratedValues>
                                <enumeratedValue>
                                    <name>00</name>
                                    <description>RGB888; select RGB888 or serial RGB as output interface format</description>
                                    <value>#00</value>
                                </enumeratedValue>
                                <enumeratedValue>
                                    <name>01</name>
                                    <description>RGB666; select RGB666 as output interface format</description>
                                    <value>#01</value>
                                </enumeratedValue>
                                <enumeratedValue>
                                    <name>10</name>
                                    <description>RGB565; select RGB565 as output interface format</description>
                                    <value>#10</value>
                                </enumeratedValue>
                                <enumeratedValue>
                                    <name>11</name>
                                    <description>Setting prohibited Select output interface format in OUT_SET.FORMAT[1:0]. </description>
                                    <value>#11</value>
                                </enumeratedValue>
                            </enumeratedValues>
                        </field>
                        <field>
                            <name>SEL</name>
                            <description>Operation Mode</description>
                            <lsb>20</lsb>
                            <msb>21</msb>
                            <access>read-write</access>
                            <enumeratedValues>
                                <enumeratedValue>
                                    <name>00</name>
                                    <description>Truncate</description>
                                    <value>#00</value>
                                </enumeratedValue>
                                <enumeratedValue>
                                    <name>01</name>
                                    <description>Round-off</description>
                                    <value>#01</value>
                                </enumeratedValue>
                                <enumeratedValue>
                                    <name>10</name>
                                    <description>2×2 pattern dither</description>
                                    <value>#10</value>
                                </enumeratedValue>
                                <enumeratedValue>
                                    <name>11</name>
                                    <description>Setting prohibited </description>
                                    <value>#11</value>
                                </enumeratedValue>
                            </enumeratedValues>
                        </field>
                    </fields>
                </register>
                <register>
                    <name>OUT_CLKPHASE</name>
                    <description>Output Control Block Output Phase Control Register</description>
                    <addressOffset>0x13E4</addressOffset>
                    <size>32</size>
                    <access>read-write</access>
                    <resetValue>0x00000000</resetValue>
                    <resetMask>0xffffffff</resetMask>
                    <fields>
                        <field>
                            <name>TCON3EDGE</name>
                            <description>LCD_TCON3 Output Phase Control</description>
                            <lsb>3</lsb>
                            <msb>3</msb>
                            <access>read-write</access>
                            <enumeratedValues>
                                <enumeratedValue>
                                    <name>0</name>
                                    <description>Synchronize output with rising edge of LCD_CLK</description>
                                    <value>#0</value>
                                </enumeratedValue>
                                <enumeratedValue>
                                    <name>1</name>
                                    <description>Synchronize output with falling edge of LCD_CLK</description>
                                    <value>#1</value>
                                </enumeratedValue>
                            </enumeratedValues>
                        </field>
                        <field>
                            <name>TCON2EDGE</name>
                            <description>LCD_TCON2 Output Phase Control</description>
                            <lsb>4</lsb>
                            <msb>4</msb>
                            <access>read-write</access>
                            <enumeratedValues>
                                <enumeratedValue>
                                    <name>0</name>
                                    <description>Synchronize output with rising edge of LCD_CLK</description>
                                    <value>#0</value>
                                </enumeratedValue>
                                <enumeratedValue>
                                    <name>1</name>
                                    <description>Synchronize output with falling edge of LCD_CLK</description>
                                    <value>#1</value>
                                </enumeratedValue>
                            </enumeratedValues>
                        </field>
                        <field>
                            <name>TCON1EDGE</name>
                            <description>LCD_TCON1 Output Phase Control</description>
                            <lsb>5</lsb>
                            <msb>5</msb>
                            <access>read-write</access>
                            <enumeratedValues>
                                <enumeratedValue>
                                    <name>0</name>
                                    <description>Synchronize output with rising edge of LCD_CLK</description>
                                    <value>#0</value>
                                </enumeratedValue>
                                <enumeratedValue>
                                    <name>1</name>
                                    <description>Synchronize output with falling edge of LCD_CLK</description>
                                    <value>#1</value>
                                </enumeratedValue>
                            </enumeratedValues>
                        </field>
                        <field>
                            <name>TCON0EDGE</name>
                            <description>LCD_TCON0 Output Phase Control</description>
                            <lsb>6</lsb>
                            <msb>6</msb>
                            <access>read-write</access>
                            <enumeratedValues>
                                <enumeratedValue>
                                    <name>0</name>
                                    <description>Synchronize output with rising edge of LCD_CLK</description>
                                    <value>#0</value>
                                </enumeratedValue>
                                <enumeratedValue>
                                    <name>1</name>
                                    <description>Synchronize output with falling edge of LCD_CLK</description>
                                    <value>#1</value>
                                </enumeratedValue>
                            </enumeratedValues>
                        </field>
                        <field>
                            <name>LCDEDGE</name>
                            <description>LCD_DATA Output Phase Control</description>
                            <lsb>8</lsb>
                            <msb>8</msb>
                            <access>read-write</access>
                            <enumeratedValues>
                                <enumeratedValue>
                                    <name>0</name>
                                    <description>Synchronize output with rising edge of LCD_CLK</description>
                                    <value>#0</value>
                                </enumeratedValue>
                                <enumeratedValue>
                                    <name>1</name>
                                    <description>Synchronize output with falling edge of LCD_CLK</description>
                                    <value>#1</value>
                                </enumeratedValue>
                            </enumeratedValues>
                        </field>
                        <field>
                            <name>FRONTGAM</name>
                            <description>Correction Control</description>
                            <lsb>12</lsb>
                            <msb>12</msb>
                            <access>read-write</access>
                            <enumeratedValues>
                                <enumeratedValue>
                                    <name>0</name>
                                    <description>Process brightness/contrast correction followed by gamma correction</description>
                                    <value>#0</value>
                                </enumeratedValue>
                                <enumeratedValue>
                                    <name>1</name>
                                    <description>Process gamma correction followed by brightness/contrast correction</description>
                                    <value>#1</value>
                                </enumeratedValue>
                            </enumeratedValues>
                        </field>
                    </fields>
                </register>
                <register>
                    <name>TCON_TIM</name>
                    <description>TCON Reference Timing Setting Register</description>
                    <addressOffset>0x1404</addressOffset>
                    <size>32</size>
                    <access>read-write</access>
                    <resetValue>0x00000000</resetValue>
                    <resetMask>0xffffffff</resetMask>
                    <fields>
                        <field>
                            <name>OFFSET</name>
                            <description>Horizontal Synchronization Signal Generation Reference Timing</description>
                            <lsb>0</lsb>
                            <msb>10</msb>
                            <access>read-write</access>
                        </field>
                        <field>
                            <name>HALF</name>
                            <description>Vertical Synchronization Signal Generation Change Timing</description>
                            <lsb>16</lsb>
                            <msb>26</msb>
                            <access>read-write</access>
                        </field>
                    </fields>
                </register>
                <register>
                    <name>TCON_STVA1</name>
                    <description>TCON Vertical Timing Setting Register x1</description>
                    <addressOffset>0x1408</addressOffset>
                    <size>32</size>
                    <access>read-write</access>
                    <resetValue>0x00000000</resetValue>
                    <resetMask>0xffffffff</resetMask>
                    <fields>
                        <field>
                            <name>VW</name>
                            <description>Vertical Synchronization Signal STVx1 Second Change Timing</description>
                            <lsb>0</lsb>
                            <msb>10</msb>
                            <access>read-write</access>
                        </field>
                        <field>
                            <name>VS</name>
                            <description>Vertical Synchronization Signal STVx1 First Change Timing</description>
                            <lsb>16</lsb>
                            <msb>26</msb>
                            <access>read-write</access>
                        </field>
                    </fields>
                </register>
                <register>
                    <name>TCON_STVA2</name>
                    <description>TCON Vertical Timing Setting Register x2</description>
                    <addressOffset>0x140C</addressOffset>
                    <size>32</size>
                    <access>read-write</access>
                    <resetValue>0x00000000</resetValue>
                    <resetMask>0xffffffff</resetMask>
                    <fields>
                        <field>
                            <name>SEL</name>
                            <description>Output Signal Select Control for LCD_TCON0/LCD_TCON1 Pin</description>
                            <lsb>0</lsb>
                            <msb>2</msb>
                            <access>read-write</access>
                            <enumeratedValues>
                                <enumeratedValue>
                                    <name>000</name>
                                    <description>STVA</description>
                                    <value>#000</value>
                                </enumeratedValue>
                                <enumeratedValue>
                                    <name>001</name>
                                    <description>STVB</description>
                                    <value>#001</value>
                                </enumeratedValue>
                                <enumeratedValue>
                                    <name>010</name>
                                    <description>STHA</description>
                                    <value>#010</value>
                                </enumeratedValue>
                                <enumeratedValue>
                                    <name>011</name>
                                    <description>STHB</description>
                                    <value>#011</value>
                                </enumeratedValue>
                                <enumeratedValue>
                                    <name>100</name>
                                    <description>Setting prohibited</description>
                                    <value>#100</value>
                                </enumeratedValue>
                                <enumeratedValue>
                                    <name>101</name>
                                    <description>Setting prohibited</description>
                                    <value>#101</value>
                                </enumeratedValue>
                                <enumeratedValue>
                                    <name>110</name>
                                    <description>Setting prohibited</description>
                                    <value>#110</value>
                                </enumeratedValue>
                                <enumeratedValue>
                                    <name>111</name>
                                    <description>DE</description>
                                    <value>#111</value>
                                </enumeratedValue>
                            </enumeratedValues>
                        </field>
                        <field>
                            <name>INV</name>
                            <description>Vertical Synchronization Signal STVx Polarity Inversion Control</description>
                            <lsb>4</lsb>
                            <msb>4</msb>
                            <access>read-write</access>
                            <enumeratedValues>
                                <enumeratedValue>
                                    <name>0</name>
                                    <description>Do not invert</description>
                                    <value>#0</value>
                                </enumeratedValue>
                                <enumeratedValue>
                                    <name>1</name>
                                    <description>Invert</description>
                                    <value>#1</value>
                                </enumeratedValue>
                            </enumeratedValues>
                        </field>
                    </fields>
                </register>
                <register>
                    <name>TCON_STVB1</name>
                    <description>TCON Vertical Timing Setting Register x1</description>
                    <addressOffset>0x1410</addressOffset>
                    <size>32</size>
                    <access>read-write</access>
                    <resetValue>0x00000000</resetValue>
                    <resetMask>0xffffffff</resetMask>
                    <fields>
                        <field>
                            <name>VW</name>
                            <description>Vertical Synchronization Signal STVx1 Second Change Timing</description>
                            <lsb>0</lsb>
                            <msb>10</msb>
                            <access>read-write</access>
                        </field>
                        <field>
                            <name>VS</name>
                            <description>Vertical Synchronization Signal STVx1 First Change Timing</description>
                            <lsb>16</lsb>
                            <msb>26</msb>
                            <access>read-write</access>
                        </field>
                    </fields>
                </register>
                <register>
                    <name>TCON_STVB2</name>
                    <description>TCON Vertical Timing Setting Register x2</description>
                    <addressOffset>0x1414</addressOffset>
                    <size>32</size>
                    <access>read-write</access>
                    <resetValue>0x00000000</resetValue>
                    <resetMask>0xffffffff</resetMask>
                    <fields>
                        <field>
                            <name>SEL</name>
                            <description>Output Signal Select Control for LCD_TCON0/LCD_TCON1 Pin</description>
                            <lsb>0</lsb>
                            <msb>2</msb>
                            <access>read-write</access>
                            <enumeratedValues>
                                <enumeratedValue>
                                    <name>000</name>
                                    <description>STVA</description>
                                    <value>#000</value>
                                </enumeratedValue>
                                <enumeratedValue>
                                    <name>001</name>
                                    <description>STVB</description>
                                    <value>#001</value>
                                </enumeratedValue>
                                <enumeratedValue>
                                    <name>010</name>
                                    <description>STHA</description>
                                    <value>#010</value>
                                </enumeratedValue>
                                <enumeratedValue>
                                    <name>011</name>
                                    <description>STHB</description>
                                    <value>#011</value>
                                </enumeratedValue>
                                <enumeratedValue>
                                    <name>100</name>
                                    <description>Setting prohibited</description>
                                    <value>#100</value>
                                </enumeratedValue>
                                <enumeratedValue>
                                    <name>101</name>
                                    <description>Setting prohibited</description>
                                    <value>#101</value>
                                </enumeratedValue>
                                <enumeratedValue>
                                    <name>110</name>
                                    <description>Setting prohibited</description>
                                    <value>#110</value>
                                </enumeratedValue>
                                <enumeratedValue>
                                    <name>111</name>
                                    <description>DE</description>
                                    <value>#111</value>
                                </enumeratedValue>
                            </enumeratedValues>
                        </field>
                        <field>
                            <name>INV</name>
                            <description>Vertical Synchronization Signal STVx Polarity Inversion Control</description>
                            <lsb>4</lsb>
                            <msb>4</msb>
                            <access>read-write</access>
                            <enumeratedValues>
                                <enumeratedValue>
                                    <name>0</name>
                                    <description>Do not invert</description>
                                    <value>#0</value>
                                </enumeratedValue>
                                <enumeratedValue>
                                    <name>1</name>
                                    <description>Invert</description>
                                    <value>#1</value>
                                </enumeratedValue>
                            </enumeratedValues>
                        </field>
                    </fields>
                </register>
                <register>
                    <name>TCON_STHA1</name>
                    <description>TCON Horizontal Timing Setting Register x1</description>
                    <addressOffset>0x1418</addressOffset>
                    <size>32</size>
                    <access>read-write</access>
                    <resetValue>0x00000000</resetValue>
                    <resetMask>0xffffffff</resetMask>
                    <fields>
                        <field>
                            <name>HW</name>
                            <description>Horizontal Synchronization Signal STHx1 Second Change Timing</description>
                            <lsb>0</lsb>
                            <msb>10</msb>
                            <access>read-write</access>
                        </field>
                        <field>
                            <name>HS</name>
                            <description>Horizontal Synchronization Signal STHx1 First Change Timing</description>
                            <lsb>16</lsb>
                            <msb>26</msb>
                            <access>read-write</access>
                        </field>
                    </fields>
                </register>
                <register>
                    <name>TCON_STHA2</name>
                    <description>TCON Horizontal Timing Setting Register x2</description>
                    <addressOffset>0x141C</addressOffset>
                    <size>32</size>
                    <access>read-write</access>
                    <resetValue>0x00000000</resetValue>
                    <resetMask>0xffffffff</resetMask>
                    <fields>
                        <field>
                            <name>SEL</name>
                            <description>Output Signal Select Control for LCD_TCON2/LCD_TCON3 Pin</description>
                            <lsb>0</lsb>
                            <msb>2</msb>
                            <access>read-write</access>
                            <enumeratedValues>
                                <enumeratedValue>
                                    <name>000</name>
                                    <description>STVA</description>
                                    <value>#000</value>
                                </enumeratedValue>
                                <enumeratedValue>
                                    <name>001</name>
                                    <description>STVB</description>
                                    <value>#001</value>
                                </enumeratedValue>
                                <enumeratedValue>
                                    <name>010</name>
                                    <description>STHA</description>
                                    <value>#010</value>
                                </enumeratedValue>
                                <enumeratedValue>
                                    <name>011</name>
                                    <description>STHB</description>
                                    <value>#011</value>
                                </enumeratedValue>
                                <enumeratedValue>
                                    <name>100</name>
                                    <description>Setting prohibited</description>
                                    <value>#100</value>
                                </enumeratedValue>
                                <enumeratedValue>
                                    <name>101</name>
                                    <description>Setting prohibited</description>
                                    <value>#101</value>
                                </enumeratedValue>
                                <enumeratedValue>
                                    <name>110</name>
                                    <description>Setting prohibited</description>
                                    <value>#110</value>
                                </enumeratedValue>
                                <enumeratedValue>
                                    <name>111</name>
                                    <description>DE</description>
                                    <value>#111</value>
                                </enumeratedValue>
                            </enumeratedValues>
                        </field>
                        <field>
                            <name>INV</name>
                            <description>Horizontal Synchronization Signal STHx Polarity Inversion Control</description>
                            <lsb>4</lsb>
                            <msb>4</msb>
                            <access>read-write</access>
                            <enumeratedValues>
                                <enumeratedValue>
                                    <name>0</name>
                                    <description>Do not invert</description>
                                    <value>#0</value>
                                </enumeratedValue>
                                <enumeratedValue>
                                    <name>1</name>
                                    <description>Invert</description>
                                    <value>#1</value>
                                </enumeratedValue>
                            </enumeratedValues>
                        </field>
                        <field>
                            <name>HSSEL</name>
                            <description>Horizontal Synchronization Signal STHx Reference Timing Control</description>
                            <lsb>8</lsb>
                            <msb>8</msb>
                            <access>read-write</access>
                            <enumeratedValues>
                                <enumeratedValue>
                                    <name>0</name>
                                    <description>Select input horizontal synchronization signal (HSIN) as reference for signal generation</description>
                                    <value>#0</value>
                                </enumeratedValue>
                                <enumeratedValue>
                                    <name>1</name>
                                    <description>Select offset specified in TCON_TIM.OFFSET[10:0] (horizontal synchronization generation reference timing) as reference for signal generation</description>
                                    <value>#1</value>
                                </enumeratedValue>
                            </enumeratedValues>
                        </field>
                    </fields>
                </register>
                <register>
                    <name>TCON_STHB1</name>
                    <description>TCON Horizontal Timing Setting Register x1</description>
                    <addressOffset>0x1420</addressOffset>
                    <size>32</size>
                    <access>read-write</access>
                    <resetValue>0x00000000</resetValue>
                    <resetMask>0xffffffff</resetMask>
                    <fields>
                        <field>
                            <name>HW</name>
                            <description>Horizontal Synchronization Signal STHx1 Second Change Timing</description>
                            <lsb>0</lsb>
                            <msb>10</msb>
                            <access>read-write</access>
                        </field>
                        <field>
                            <name>HS</name>
                            <description>Horizontal Synchronization Signal STHx1 First Change Timing</description>
                            <lsb>16</lsb>
                            <msb>26</msb>
                            <access>read-write</access>
                        </field>
                    </fields>
                </register>
                <register>
                    <name>TCON_STHB2</name>
                    <description>TCON Horizontal Timing Setting Register x2</description>
                    <addressOffset>0x1424</addressOffset>
                    <size>32</size>
                    <access>read-write</access>
                    <resetValue>0x00000000</resetValue>
                    <resetMask>0xffffffff</resetMask>
                    <fields>
                        <field>
                            <name>SEL</name>
                            <description>Output Signal Select Control for LCD_TCON2/LCD_TCON3 Pin</description>
                            <lsb>0</lsb>
                            <msb>2</msb>
                            <access>read-write</access>
                            <enumeratedValues>
                                <enumeratedValue>
                                    <name>000</name>
                                    <description>STVA</description>
                                    <value>#000</value>
                                </enumeratedValue>
                                <enumeratedValue>
                                    <name>001</name>
                                    <description>STVB</description>
                                    <value>#001</value>
                                </enumeratedValue>
                                <enumeratedValue>
                                    <name>010</name>
                                    <description>STHA</description>
                                    <value>#010</value>
                                </enumeratedValue>
                                <enumeratedValue>
                                    <name>011</name>
                                    <description>STHB</description>
                                    <value>#011</value>
                                </enumeratedValue>
                                <enumeratedValue>
                                    <name>100</name>
                                    <description>Setting prohibited</description>
                                    <value>#100</value>
                                </enumeratedValue>
                                <enumeratedValue>
                                    <name>101</name>
                                    <description>Setting prohibited</description>
                                    <value>#101</value>
                                </enumeratedValue>
                                <enumeratedValue>
                                    <name>110</name>
                                    <description>Setting prohibited</description>
                                    <value>#110</value>
                                </enumeratedValue>
                                <enumeratedValue>
                                    <name>111</name>
                                    <description>DE</description>
                                    <value>#111</value>
                                </enumeratedValue>
                            </enumeratedValues>
                        </field>
                        <field>
                            <name>INV</name>
                            <description>Horizontal Synchronization Signal STHx Polarity Inversion Control</description>
                            <lsb>4</lsb>
                            <msb>4</msb>
                            <access>read-write</access>
                            <enumeratedValues>
                                <enumeratedValue>
                                    <name>0</name>
                                    <description>Do not invert</description>
                                    <value>#0</value>
                                </enumeratedValue>
                                <enumeratedValue>
                                    <name>1</name>
                                    <description>Invert</description>
                                    <value>#1</value>
                                </enumeratedValue>
                            </enumeratedValues>
                        </field>
                        <field>
                            <name>HSSEL</name>
                            <description>Horizontal Synchronization Signal STHx Reference Timing Control</description>
                            <lsb>8</lsb>
                            <msb>8</msb>
                            <access>read-write</access>
                            <enumeratedValues>
                                <enumeratedValue>
                                    <name>0</name>
                                    <description>Select input horizontal synchronization signal (HSIN) as reference for signal generation</description>
                                    <value>#0</value>
                                </enumeratedValue>
                                <enumeratedValue>
                                    <name>1</name>
                                    <description>Select offset specified in TCON_TIM.OFFSET[10:0] (horizontal synchronization generation reference timing) as reference for signal generation</description>
                                    <value>#1</value>
                                </enumeratedValue>
                            </enumeratedValues>
                        </field>
                    </fields>
                </register>
                <register>
                    <name>TCON_DE</name>
                    <description>TCON Data Enable Polarity Setting Register</description>
                    <addressOffset>0x1428</addressOffset>
                    <size>32</size>
                    <access>read-write</access>
                    <resetValue>0x00000000</resetValue>
                    <resetMask>0xffffffff</resetMask>
                    <fields>
                        <field>
                            <name>INV</name>
                            <description>Data Enable Signal DE Polarity Inversion Control</description>
                            <lsb>0</lsb>
                            <msb>0</msb>
                            <access>read-write</access>
                            <enumeratedValues>
                                <enumeratedValue>
                                    <name>0</name>
                                    <description>Do not invert</description>
                                    <value>#0</value>
                                </enumeratedValue>
                                <enumeratedValue>
                                    <name>1</name>
                                    <description>Invert</description>
                                    <value>#1</value>
                                </enumeratedValue>
                            </enumeratedValues>
                        </field>
                    </fields>
                </register>
                <register>
                    <name>SYSCNT_DTCTEN</name>
                    <description>System Control Block State Detection Control Register</description>
                    <addressOffset>0x1440</addressOffset>
                    <size>32</size>
                    <access>read-write</access>
                    <resetValue>0x00000000</resetValue>
                    <resetMask>0xffffffff</resetMask>
                    <fields>
                        <field>
                            <name>VPOSDTC</name>
                            <description>Specified Line Detection Control</description>
                            <lsb>0</lsb>
                            <msb>0</msb>
                            <access>read-write</access>
                            <enumeratedValues>
                                <enumeratedValue>
                                    <name>0</name>
                                    <description>Disable detection of specified line</description>
                                    <value>#0</value>
                                </enumeratedValue>
                                <enumeratedValue>
                                    <name>1</name>
                                    <description>Enable detection of specified line</description>
                                    <value>#1</value>
                                </enumeratedValue>
                            </enumeratedValues>
                        </field>
                        <field>
                            <name>L1UNDFDTC</name>
                            <description>Graphics 1 Underflow Detection Control</description>
                            <lsb>1</lsb>
                            <msb>1</msb>
                            <access>read-write</access>
                            <enumeratedValues>
                                <enumeratedValue>
                                    <name>0</name>
                                    <description>Disable detection of graphics 1 underflow</description>
                                    <value>#0</value>
                                </enumeratedValue>
                                <enumeratedValue>
                                    <name>1</name>
                                    <description>Enable detection of graphics 1 underflow</description>
                                    <value>#1</value>
                                </enumeratedValue>
                            </enumeratedValues>
                        </field>
                        <field>
                            <name>L2UNDFDTC</name>
                            <description>Graphics 2 Underflow Detection Control</description>
                            <lsb>2</lsb>
                            <msb>2</msb>
                            <access>read-write</access>
                            <enumeratedValues>
                                <enumeratedValue>
                                    <name>0</name>
                                    <description>Disable detection of graphics 2 underflow</description>
                                    <value>#0</value>
                                </enumeratedValue>
                                <enumeratedValue>
                                    <name>1</name>
                                    <description>Enable detection of graphics 2 underflow</description>
                                    <value>#1</value>
                                </enumeratedValue>
                            </enumeratedValues>
                        </field>
                    </fields>
                </register>
                <register>
                    <name>SYSCNT_INTEN</name>
                    <description>System Control Block Interrupt Request Enable Control Register</description>
                    <addressOffset>0x1444</addressOffset>
                    <size>32</size>
                    <access>read-write</access>
                    <resetValue>0x00000000</resetValue>
                    <resetMask>0xffffffff</resetMask>
                    <fields>
                        <field>
                            <name>VPOSINTEN</name>
                            <description>Interrupt Request Signal GLCDC_VPOS Enable Control</description>
                            <lsb>0</lsb>
                            <msb>0</msb>
                            <access>read-write</access>
                            <enumeratedValues>
                                <enumeratedValue>
                                    <name>0</name>
                                    <description>Disable GLCDC_VPOS output</description>
                                    <value>#0</value>
                                </enumeratedValue>
                                <enumeratedValue>
                                    <name>1</name>
                                    <description>Enable GLCDC_VPOS output</description>
                                    <value>#1</value>
                                </enumeratedValue>
                            </enumeratedValues>
                        </field>
                        <field>
                            <name>L1UNDFINTEN</name>
                            <description>Interrupt Request Signal GLCDC_L1UNDF Enable Control</description>
                            <lsb>1</lsb>
                            <msb>1</msb>
                            <access>read-write</access>
                            <enumeratedValues>
                                <enumeratedValue>
                                    <name>0</name>
                                    <description>Disable GLCDC_L1UNDF output</description>
                                    <value>#0</value>
                                </enumeratedValue>
                                <enumeratedValue>
                                    <name>1</name>
                                    <description>Enable GLCDC_L1UNDF output</description>
                                    <value>#1</value>
                                </enumeratedValue>
                            </enumeratedValues>
                        </field>
                        <field>
                            <name>L2UNDFINTEN</name>
                            <description>Interrupt Request Signal GLCDC_L2UNDF Enable Control</description>
                            <lsb>2</lsb>
                            <msb>2</msb>
                            <access>read-write</access>
                            <enumeratedValues>
                                <enumeratedValue>
                                    <name>0</name>
                                    <description>Disable GLCDC_L2UNDF output</description>
                                    <value>#0</value>
                                </enumeratedValue>
                                <enumeratedValue>
                                    <name>1</name>
                                    <description>Enable GLCDC_L2UNDF output</description>
                                    <value>#1</value>
                                </enumeratedValue>
                            </enumeratedValues>
                        </field>
                    </fields>
                </register>
                <register>
                    <name>SYSCNT_STCLR</name>
                    <description>System Control Block Status Clear Register</description>
                    <addressOffset>0x1448</addressOffset>
                    <size>32</size>
                    <access>read-write</access>
                    <resetValue>0x00000000</resetValue>
                    <resetMask>0xffffffff</resetMask>
                    <fields>
                        <field>
                            <name>VPOSCLR</name>
                            <description>Graphics 2 Specified Line Detection Flag Clear</description>
                            <lsb>0</lsb>
                            <msb>0</msb>
                            <access>read-write</access>
                            <enumeratedValues>
                                <enumeratedValue>
                                    <name>0</name>
                                    <description>No operation</description>
                                    <value>#0</value>
                                </enumeratedValue>
                                <enumeratedValue>
                                    <name>1</name>
                                    <description>Clear the graphics 2 specified line detection flag</description>
                                    <value>#1</value>
                                </enumeratedValue>
                            </enumeratedValues>
                        </field>
                        <field>
                            <name>L1UNDFCLR</name>
                            <description>Graphics 1 Underflow Detection Flag Clear</description>
                            <lsb>1</lsb>
                            <msb>1</msb>
                            <access>read-write</access>
                            <enumeratedValues>
                                <enumeratedValue>
                                    <name>0</name>
                                    <description>No operation</description>
                                    <value>#0</value>
                                </enumeratedValue>
                                <enumeratedValue>
                                    <name>1</name>
                                    <description>Clear the graphics 1 underflow detection flag</description>
                                    <value>#1</value>
                                </enumeratedValue>
                            </enumeratedValues>
                        </field>
                        <field>
                            <name>L2UNDFCLR</name>
                            <description>Graphics 2 Underflow Detection Flag Clear</description>
                            <lsb>2</lsb>
                            <msb>2</msb>
                            <access>read-write</access>
                            <enumeratedValues>
                                <enumeratedValue>
                                    <name>0</name>
                                    <description>No operation</description>
                                    <value>#0</value>
                                </enumeratedValue>
                                <enumeratedValue>
                                    <name>1</name>
                                    <description>Clears the graphics 2 underflow detection flag</description>
                                    <value>#1</value>
                                </enumeratedValue>
                            </enumeratedValues>
                        </field>
                    </fields>
                </register>
                <register>
                    <name>SYSCNT_STMON</name>
                    <description>System Control Block Status Monitor Register</description>
                    <addressOffset>0x144C</addressOffset>
                    <size>32</size>
                    <access>read-only</access>
                    <resetValue>0x00000000</resetValue>
                    <resetMask>0xffffffff</resetMask>
                    <fields>
                        <field>
                            <name>VPOS</name>
                            <description>Graphics 2 Specified Line Detection Flag</description>
                            <lsb>0</lsb>
                            <msb>0</msb>
                            <access>read-only</access>
                            <enumeratedValues>
                                <enumeratedValue>
                                    <name>0</name>
                                    <description>Specified line notification not detected in graphics 2</description>
                                    <value>#0</value>
                                </enumeratedValue>
                                <enumeratedValue>
                                    <name>1</name>
                                    <description>Specified line notification detected in graphics 2</description>
                                    <value>#1</value>
                                </enumeratedValue>
                            </enumeratedValues>
                        </field>
                        <field>
                            <name>L1UNDF</name>
                            <description>Graphics 1 Underflow Detection Flag</description>
                            <lsb>1</lsb>
                            <msb>1</msb>
                            <access>read-only</access>
                            <enumeratedValues>
                                <enumeratedValue>
                                    <name>0</name>
                                    <description>No underflow detected in graphics 1</description>
                                    <value>#0</value>
                                </enumeratedValue>
                                <enumeratedValue>
                                    <name>1</name>
                                    <description>Underflow detected in graphics 1</description>
                                    <value>#1</value>
                                </enumeratedValue>
                            </enumeratedValues>
                        </field>
                        <field>
                            <name>L2UNDF</name>
                            <description>Graphics 2 Underflow Detection Flag</description>
                            <lsb>2</lsb>
                            <msb>2</msb>
                            <access>read-only</access>
                            <enumeratedValues>
                                <enumeratedValue>
                                    <name>0</name>
                                    <description>No underflow detected in graphics 2</description>
                                    <value>#0</value>
                                </enumeratedValue>
                                <enumeratedValue>
                                    <name>1</name>
                                    <description>Underflow detected in graphics 2</description>
                                    <value>#1</value>
                                </enumeratedValue>
                            </enumeratedValues>
                        </field>
                    </fields>
                </register>
                <register>
                    <name>SYSCNT_PANEL_CLK</name>
                    <description>System Control Block Version and Panel Clock Control Register</description>
                    <addressOffset>0x1450</addressOffset>
                    <size>32</size>
                    <access>read-write</access>
                    <resetValue>0x01100000</resetValue>
                    <resetMask>0xffffffff</resetMask>
                    <fields>
                        <field>
                            <name>DCDR</name>
                            <description>Clock Division Ratio Setting Control</description>
                            <lsb>0</lsb>
                            <msb>5</msb>
                            <access>read-write</access>
                        </field>
                        <field>
                            <name>CLKEN</name>
                            <description>Panel Clock Output Enable Control</description>
                            <lsb>6</lsb>
                            <msb>6</msb>
                            <access>read-write</access>
                            <enumeratedValues>
                                <enumeratedValue>
                                    <name>0</name>
                                    <description>Disable panel clock output</description>
                                    <value>#0</value>
                                </enumeratedValue>
                                <enumeratedValue>
                                    <name>1</name>
                                    <description>Enable panel clock output Before changing the PIXSEL, CLKSEL, or DCDR bit, this bit must be set to 0. </description>
                                    <value>#1</value>
                                </enumeratedValue>
                            </enumeratedValues>
                        </field>
                        <field>
                            <name>CLKSEL</name>
                            <description>Panel Clock Supply Source Control</description>
                            <lsb>8</lsb>
                            <msb>8</msb>
                            <access>read-write</access>
                            <enumeratedValues>
                                <enumeratedValue>
                                    <name>0</name>
                                    <description>Select external clock (LCD_EXTCLK)</description>
                                    <value>#0</value>
                                </enumeratedValue>
                                <enumeratedValue>
                                    <name>1</name>
                                    <description>Select LCDCLK</description>
                                    <value>#1</value>
                                </enumeratedValue>
                            </enumeratedValues>
                        </field>
                        <field>
                            <name>PIXSEL</name>
                            <description>Pixel Clock Select Control</description>
                            <lsb>12</lsb>
                            <msb>12</msb>
                            <access>read-write</access>
                            <enumeratedValues>
                                <enumeratedValue>
                                    <name>0</name>
                                    <description>Select no frequency division, parallel RGB</description>
                                    <value>#0</value>
                                </enumeratedValue>
                                <enumeratedValue>
                                    <name>1</name>
                                    <description>Select quarter frequency, serial RGB This setting must have the same value as OUT_SET.FRQSEL[1]. </description>
                                    <value>#1</value>
                                </enumeratedValue>
                            </enumeratedValues>
                        </field>
                        <field>
                            <name>VER</name>
                            <description>Version Information</description>
                            <lsb>16</lsb>
                            <msb>31</msb>
                            <access>read-only</access>
                        </field>
                    </fields>
                </register>
            </registers>
        </peripheral>
        <peripheral>
            <name>DRW</name>
            <description>2D Drawing Engine</description>
            <baseAddress>0x40344000</baseAddress>
            <addressBlock>
                <offset>0x00</offset>
                <size>8</size>
                <usage>registers</usage>
            </addressBlock>
            <addressBlock>
                <offset>0x10</offset>
                <size>80</size>
                <usage>registers</usage>
            </addressBlock>
            <addressBlock>
                <offset>0x64</offset>
                <size>8</size>
                <usage>registers</usage>
            </addressBlock>
            <addressBlock>
                <offset>0x74</offset>
                <size>16</size>
                <usage>registers</usage>
            </addressBlock>
            <addressBlock>
                <offset>0x90</offset>
                <size>32</size>
                <usage>registers</usage>
            </addressBlock>
            <addressBlock>
                <offset>0xB4</offset>
                <size>28</size>
                <usage>registers</usage>
            </addressBlock>
            <addressBlock>
                <offset>0xD4</offset>
                <size>4</size>
                <usage>registers</usage>
            </addressBlock>
            <addressBlock>
                <offset>0xDC</offset>
                <size>16</size>
                <usage>registers</usage>
            </addressBlock>
            <registers>
                <register>
                    <name>CONTROL</name>
                    <description>Geometry Control Register</description>
                    <addressOffset>0x00</addressOffset>
                    <size>32</size>
                    <access>write-only</access>
                    <resetValue>0x00000000</resetValue>
                    <resetMask>0xffffffff</resetMask>
                    <fields>
                        <field>
                            <name>LIM1ENABLE</name>
                            <description>Enable Limiter 1</description>
                            <lsb>0</lsb>
                            <msb>0</msb>
                            <access>write-only</access>
                            <enumeratedValues>
                                <enumeratedValue>
                                    <name>0</name>
                                    <description>Disable</description>
                                    <value>#0</value>
                                </enumeratedValue>
                                <enumeratedValue>
                                    <name>1</name>
                                    <description>Enable</description>
                                    <value>#1</value>
                                </enumeratedValue>
                            </enumeratedValues>
                        </field>
                        <field>
                            <name>LIM2ENABLE</name>
                            <description>Enable Limiter 2</description>
                            <lsb>1</lsb>
                            <msb>1</msb>
                            <access>write-only</access>
                            <enumeratedValues>
                                <enumeratedValue>
                                    <name>0</name>
                                    <description>Disable</description>
                                    <value>#0</value>
                                </enumeratedValue>
                                <enumeratedValue>
                                    <name>1</name>
                                    <description>Enable</description>
                                    <value>#1</value>
                                </enumeratedValue>
                            </enumeratedValues>
                        </field>
                        <field>
                            <name>LIM3ENABLE</name>
                            <description>Enable Limiter 3</description>
                            <lsb>2</lsb>
                            <msb>2</msb>
                            <access>write-only</access>
                            <enumeratedValues>
                                <enumeratedValue>
                                    <name>0</name>
                                    <description>Disable</description>
                                    <value>#0</value>
                                </enumeratedValue>
                                <enumeratedValue>
                                    <name>1</name>
                                    <description>Enable</description>
                                    <value>#1</value>
                                </enumeratedValue>
                            </enumeratedValues>
                        </field>
                        <field>
                            <name>LIM4ENABLE</name>
                            <description>Enable Limiter 4</description>
                            <lsb>3</lsb>
                            <msb>3</msb>
                            <access>write-only</access>
                            <enumeratedValues>
                                <enumeratedValue>
                                    <name>0</name>
                                    <description>Disable</description>
                                    <value>#0</value>
                                </enumeratedValue>
                                <enumeratedValue>
                                    <name>1</name>
                                    <description>Enable</description>
                                    <value>#1</value>
                                </enumeratedValue>
                            </enumeratedValues>
                        </field>
                        <field>
                            <name>LIM5ENABLE</name>
                            <description>Enable Limiter 5</description>
                            <lsb>4</lsb>
                            <msb>4</msb>
                            <access>write-only</access>
                            <enumeratedValues>
                                <enumeratedValue>
                                    <name>0</name>
                                    <description>Disable</description>
                                    <value>#0</value>
                                </enumeratedValue>
                                <enumeratedValue>
                                    <name>1</name>
                                    <description>Enable</description>
                                    <value>#1</value>
                                </enumeratedValue>
                            </enumeratedValues>
                        </field>
                        <field>
                            <name>LIM6ENABLE</name>
                            <description>Enable Limiter 6</description>
                            <lsb>5</lsb>
                            <msb>5</msb>
                            <access>write-only</access>
                            <enumeratedValues>
                                <enumeratedValue>
                                    <name>0</name>
                                    <description>Disable</description>
                                    <value>#0</value>
                                </enumeratedValue>
                                <enumeratedValue>
                                    <name>1</name>
                                    <description>Enable</description>
                                    <value>#1</value>
                                </enumeratedValue>
                            </enumeratedValues>
                        </field>
                        <field>
                            <name>QUAD1ENABLE</name>
                            <description>Enable Quadratic Coupling of Limiters 1 and 2</description>
                            <lsb>6</lsb>
                            <msb>6</msb>
                            <access>write-only</access>
                            <enumeratedValues>
                                <enumeratedValue>
                                    <name>0</name>
                                    <description>Disable</description>
                                    <value>#0</value>
                                </enumeratedValue>
                                <enumeratedValue>
                                    <name>1</name>
                                    <description>Enable</description>
                                    <value>#1</value>
                                </enumeratedValue>
                            </enumeratedValues>
                        </field>
                        <field>
                            <name>QUAD2ENABLE</name>
                            <description>Enable Quadratic Coupling of Limiters 3 and 4</description>
                            <lsb>7</lsb>
                            <msb>7</msb>
                            <access>write-only</access>
                            <enumeratedValues>
                                <enumeratedValue>
                                    <name>0</name>
                                    <description>Disable</description>
                                    <value>#0</value>
                                </enumeratedValue>
                                <enumeratedValue>
                                    <name>1</name>
                                    <description>Enable</description>
                                    <value>#1</value>
                                </enumeratedValue>
                            </enumeratedValues>
                        </field>
                        <field>
                            <name>QUAD3ENABLE</name>
                            <description>Enable Quadratic Coupling of Limiters 5 and 6</description>
                            <lsb>8</lsb>
                            <msb>8</msb>
                            <access>write-only</access>
                            <enumeratedValues>
                                <enumeratedValue>
                                    <name>0</name>
                                    <description>Disable</description>
                                    <value>#0</value>
                                </enumeratedValue>
                                <enumeratedValue>
                                    <name>1</name>
                                    <description>Enable</description>
                                    <value>#1</value>
                                </enumeratedValue>
                            </enumeratedValues>
                        </field>
                        <field>
                            <name>LIM1THRESHOLD</name>
                            <description>Enable Limiter 1 Threshold Mode</description>
                            <lsb>9</lsb>
                            <msb>9</msb>
                            <access>write-only</access>
                            <enumeratedValues>
                                <enumeratedValue>
                                    <name>0</name>
                                    <description>Disable</description>
                                    <value>#0</value>
                                </enumeratedValue>
                                <enumeratedValue>
                                    <name>1</name>
                                    <description>Enable</description>
                                    <value>#1</value>
                                </enumeratedValue>
                            </enumeratedValues>
                        </field>
                        <field>
                            <name>LIM2THRESHOLD</name>
                            <description>Enable Limiter 2 Threshold Mode</description>
                            <lsb>10</lsb>
                            <msb>10</msb>
                            <access>write-only</access>
                            <enumeratedValues>
                                <enumeratedValue>
                                    <name>0</name>
                                    <description>Disable</description>
                                    <value>#0</value>
                                </enumeratedValue>
                                <enumeratedValue>
                                    <name>1</name>
                                    <description>Enable</description>
                                    <value>#1</value>
                                </enumeratedValue>
                            </enumeratedValues>
                        </field>
                        <field>
                            <name>LIM3THRESHOLD</name>
                            <description>Enable Limiter 3 Threshold Mode</description>
                            <lsb>11</lsb>
                            <msb>11</msb>
                            <access>write-only</access>
                            <enumeratedValues>
                                <enumeratedValue>
                                    <name>0</name>
                                    <description>Disable</description>
                                    <value>#0</value>
                                </enumeratedValue>
                                <enumeratedValue>
                                    <name>1</name>
                                    <description>Enable</description>
                                    <value>#1</value>
                                </enumeratedValue>
                            </enumeratedValues>
                        </field>
                        <field>
                            <name>LIM4THRESHOLD</name>
                            <description>Enable Limiter 4 Threshold Mode</description>
                            <lsb>12</lsb>
                            <msb>12</msb>
                            <access>write-only</access>
                            <enumeratedValues>
                                <enumeratedValue>
                                    <name>0</name>
                                    <description>Disable</description>
                                    <value>#0</value>
                                </enumeratedValue>
                                <enumeratedValue>
                                    <name>1</name>
                                    <description>Enable</description>
                                    <value>#1</value>
                                </enumeratedValue>
                            </enumeratedValues>
                        </field>
                        <field>
                            <name>LIM5THRESHOLD</name>
                            <description>Enable Limiter 5 Threshold Mode</description>
                            <lsb>13</lsb>
                            <msb>13</msb>
                            <access>write-only</access>
                            <enumeratedValues>
                                <enumeratedValue>
                                    <name>0</name>
                                    <description>Disable</description>
                                    <value>#0</value>
                                </enumeratedValue>
                                <enumeratedValue>
                                    <name>1</name>
                                    <description>Enable</description>
                                    <value>#1</value>
                                </enumeratedValue>
                            </enumeratedValues>
                        </field>
                        <field>
                            <name>LIM6THRESHOLD</name>
                            <description>Enable Limiter 6 Threshold Mode</description>
                            <lsb>14</lsb>
                            <msb>14</msb>
                            <access>write-only</access>
                            <enumeratedValues>
                                <enumeratedValue>
                                    <name>0</name>
                                    <description>Disable</description>
                                    <value>#0</value>
                                </enumeratedValue>
                                <enumeratedValue>
                                    <name>1</name>
                                    <description>Enable</description>
                                    <value>#1</value>
                                </enumeratedValue>
                            </enumeratedValues>
                        </field>
                        <field>
                            <name>BAND1ENABLE</name>
                            <description>Enable Band Post Process for Limiter 1</description>
                            <lsb>15</lsb>
                            <msb>15</msb>
                            <access>write-only</access>
                            <enumeratedValues>
                                <enumeratedValue>
                                    <name>0</name>
                                    <description>Disable</description>
                                    <value>#0</value>
                                </enumeratedValue>
                                <enumeratedValue>
                                    <name>1</name>
                                    <description>Enable.</description>
                                    <value>#1</value>
                                </enumeratedValue>
                            </enumeratedValues>
                        </field>
                        <field>
                            <name>BAND2ENABLE</name>
                            <description>Enable Band Post Process for Limiter 2</description>
                            <lsb>16</lsb>
                            <msb>16</msb>
                            <access>write-only</access>
                            <enumeratedValues>
                                <enumeratedValue>
                                    <name>0</name>
                                    <description>Disable</description>
                                    <value>#0</value>
                                </enumeratedValue>
                                <enumeratedValue>
                                    <name>1</name>
                                    <description>Enable.</description>
                                    <value>#1</value>
                                </enumeratedValue>
                            </enumeratedValues>
                        </field>
                        <field>
                            <name>UNION12</name>
                            <description>Combine Limiters 1 and 2 as Union</description>
                            <lsb>17</lsb>
                            <msb>17</msb>
                            <access>write-only</access>
                            <enumeratedValues>
                                <enumeratedValue>
                                    <name>0</name>
                                    <description>Select minimum/intersect between limiters 1 and 2</description>
                                    <value>#0</value>
                                </enumeratedValue>
                                <enumeratedValue>
                                    <name>1</name>
                                    <description>Select maximum/union between limiters 1 and 2. The output is called A.</description>
                                    <value>#1</value>
                                </enumeratedValue>
                            </enumeratedValues>
                        </field>
                        <field>
                            <name>UNION34</name>
                            <description>Combine Limiters 3 and 4 as Union</description>
                            <lsb>18</lsb>
                            <msb>18</msb>
                            <access>write-only</access>
                            <enumeratedValues>
                                <enumeratedValue>
                                    <name>0</name>
                                    <description>Select minimum/intersect between limiters 3 and 4</description>
                                    <value>#0</value>
                                </enumeratedValue>
                                <enumeratedValue>
                                    <name>1</name>
                                    <description>Select maximum/union between limiters 3 and 4. The output is called B.</description>
                                    <value>#1</value>
                                </enumeratedValue>
                            </enumeratedValues>
                        </field>
                        <field>
                            <name>UNION56</name>
                            <description>Combine Limiters 5 and 6 as Union</description>
                            <lsb>19</lsb>
                            <msb>19</msb>
                            <access>write-only</access>
                            <enumeratedValues>
                                <enumeratedValue>
                                    <name>0</name>
                                    <description>Select minimum/intersect between limiters 5 and 6</description>
                                    <value>#0</value>
                                </enumeratedValue>
                                <enumeratedValue>
                                    <name>1</name>
                                    <description>Select maximum/union between limiters 5 and 6. The output is called D.</description>
                                    <value>#1</value>
                                </enumeratedValue>
                            </enumeratedValues>
                        </field>
                        <field>
                            <name>UNIONAB</name>
                            <description>Combine Outputs A and B as Union</description>
                            <lsb>20</lsb>
                            <msb>20</msb>
                            <access>write-only</access>
                            <enumeratedValues>
                                <enumeratedValue>
                                    <name>0</name>
                                    <description>Select minimum/intersect between limiters A and B.</description>
                                    <value>#0</value>
                                </enumeratedValue>
                                <enumeratedValue>
                                    <name>1</name>
                                    <description>Select maximum/union between limiters A and B. The output is called C.</description>
                                    <value>#1</value>
                                </enumeratedValue>
                            </enumeratedValues>
                        </field>
                        <field>
                            <name>UNIONCD</name>
                            <description>Combine Outputs C and D as Union</description>
                            <lsb>21</lsb>
                            <msb>21</msb>
                            <access>write-only</access>
                            <enumeratedValues>
                                <enumeratedValue>
                                    <name>0</name>
                                    <description>Select minimum/intersect between limiters C and D</description>
                                    <value>#0</value>
                                </enumeratedValue>
                                <enumeratedValue>
                                    <name>1</name>
                                    <description>Select maximum/union between limiters C and D. The output is final.</description>
                                    <value>#1</value>
                                </enumeratedValue>
                            </enumeratedValues>
                        </field>
                        <field>
                            <name>SPANABORT</name>
                            <description>Spanabort</description>
                            <lsb>22</lsb>
                            <msb>22</msb>
                            <access>write-only</access>
                            <enumeratedValues>
                                <enumeratedValue>
                                    <name>0</name>
                                    <description>Disable</description>
                                    <value>#0</value>
                                </enumeratedValue>
                                <enumeratedValue>
                                    <name>1</name>
                                    <description>Enable.</description>
                                    <value>#1</value>
                                </enumeratedValue>
                            </enumeratedValues>
                        </field>
                        <field>
                            <name>SPANSTORE</name>
                            <description>Spanstore</description>
                            <lsb>23</lsb>
                            <msb>23</msb>
                            <access>write-only</access>
                            <enumeratedValues>
                                <enumeratedValue>
                                    <name>0</name>
                                    <description>Disable</description>
                                    <value>#0</value>
                                </enumeratedValue>
                                <enumeratedValue>
                                    <name>1</name>
                                    <description>Enable. Next line span start is always equal to or left of the current line span start. See .</description>
                                    <value>#1</value>
                                </enumeratedValue>
                            </enumeratedValues>
                        </field>
                    </fields>
                </register>
                <register>
                    <name>STATUS</name>
                    <description>Status Control Register</description>
                    <alternateRegister>CONTROL</alternateRegister>
                    <addressOffset>0x00</addressOffset>
                    <size>32</size>
                    <access>read-only</access>
                    <resetValue>0x00000000</resetValue>
                    <resetMask>0xffffffff</resetMask>
                    <fields>
                        <field>
                            <name>BUSYENUM</name>
                            <description>Enumeration Unit Status</description>
                            <lsb>0</lsb>
                            <msb>0</msb>
                            <access>read-only</access>
                            <enumeratedValues>
                                <enumeratedValue>
                                    <name>0</name>
                                    <description>Enumeration unit idle</description>
                                    <value>#0</value>
                                </enumeratedValue>
                                <enumeratedValue>
                                    <name>1</name>
                                    <description>Enumeration unit is busy, new primitive cannot be started.</description>
                                    <value>#1</value>
                                </enumeratedValue>
                            </enumeratedValues>
                        </field>
                        <field>
                            <name>BUSYWRITE</name>
                            <description>Framebuffer Writeback Status</description>
                            <lsb>1</lsb>
                            <msb>1</msb>
                            <access>read-only</access>
                            <enumeratedValues>
                                <enumeratedValue>
                                    <name>0</name>
                                    <description>Framebuffer writeback finished</description>
                                    <value>#0</value>
                                </enumeratedValue>
                                <enumeratedValue>
                                    <name>1</name>
                                    <description>Framebuffer writeback busy, framebuffer type cannot be changed.</description>
                                    <value>#1</value>
                                </enumeratedValue>
                            </enumeratedValues>
                        </field>
                        <field>
                            <name>CACHEDIRTY</name>
                            <description>Framebuffer Cache Status</description>
                            <lsb>2</lsb>
                            <msb>2</msb>
                            <access>read-only</access>
                            <enumeratedValues>
                                <enumeratedValue>
                                    <name>0</name>
                                    <description>Framebuffer cache is not dirty</description>
                                    <value>#0</value>
                                </enumeratedValue>
                                <enumeratedValue>
                                    <name>1</name>
                                    <description>Framebuffer cache is dirty, and frame should not be flipped.</description>
                                    <value>#1</value>
                                </enumeratedValue>
                            </enumeratedValues>
                        </field>
                        <field>
                            <name>DLISTACTIVE</name>
                            <description>Display List Reader Status</description>
                            <lsb>3</lsb>
                            <msb>3</msb>
                            <access>read-only</access>
                            <enumeratedValues>
                                <enumeratedValue>
                                    <name>0</name>
                                    <description>Display list reader is idle</description>
                                    <value>#0</value>
                                </enumeratedValue>
                                <enumeratedValue>
                                    <name>1</name>
                                    <description>Display list reader is busy, and no direct write access to registers allowed.</description>
                                    <value>#1</value>
                                </enumeratedValue>
                            </enumeratedValues>
                        </field>
                        <field>
                            <name>ENUMIRQ</name>
                            <description>Enumeration Interrupt Triggered</description>
                            <lsb>4</lsb>
                            <msb>4</msb>
                            <access>read-only</access>
                            <enumeratedValues>
                                <enumeratedValue>
                                    <name>0</name>
                                    <description>Enumeration not finished or interrupt disabled</description>
                                    <value>#0</value>
                                </enumeratedValue>
                                <enumeratedValue>
                                    <name>1</name>
                                    <description>Enumeration finished interrupt triggered.</description>
                                    <value>#1</value>
                                </enumeratedValue>
                            </enumeratedValues>
                        </field>
                        <field>
                            <name>DLISTIRQ</name>
                            <description>Display List Interrupt Triggered</description>
                            <lsb>5</lsb>
                            <msb>5</msb>
                            <access>read-only</access>
                            <enumeratedValues>
                                <enumeratedValue>
                                    <name>0</name>
                                    <description>Display list not finished or interrupt disabled</description>
                                    <value>#0</value>
                                </enumeratedValue>
                                <enumeratedValue>
                                    <name>1</name>
                                    <description>Display list finished interrupt triggered.</description>
                                    <value>#1</value>
                                </enumeratedValue>
                            </enumeratedValues>
                        </field>
                        <field>
                            <name>BUSIRQ</name>
                            <description>Bus Error Interrupt Triggered</description>
                            <lsb>6</lsb>
                            <msb>6</msb>
                            <access>read-only</access>
                            <enumeratedValues>
                                <enumeratedValue>
                                    <name>0</name>
                                    <description>No bus error occurred or interrupt disabled</description>
                                    <value>#0</value>
                                </enumeratedValue>
                                <enumeratedValue>
                                    <name>1</name>
                                    <description>Bus error interrupt triggered.</description>
                                    <value>#1</value>
                                </enumeratedValue>
                            </enumeratedValues>
                        </field>
                        <field>
                            <name>BUSERRMFB</name>
                            <description>Framebuffer Bus Error Interrupt Triggered</description>
                            <lsb>8</lsb>
                            <msb>8</msb>
                            <access>read-only</access>
                            <enumeratedValues>
                                <enumeratedValue>
                                    <name>0</name>
                                    <description>No framebuffer bus error occurred or interrupt disabled</description>
                                    <value>#0</value>
                                </enumeratedValue>
                                <enumeratedValue>
                                    <name>1</name>
                                    <description>Framebuffer bus error interrupt triggered.</description>
                                    <value>#1</value>
                                </enumeratedValue>
                            </enumeratedValues>
                        </field>
                        <field>
                            <name>BUSERRMTXMRL</name>
                            <description>Texture Bus Error Interrupt Triggered</description>
                            <lsb>9</lsb>
                            <msb>9</msb>
                            <access>read-only</access>
                            <enumeratedValues>
                                <enumeratedValue>
                                    <name>0</name>
                                    <description>No texture bus error occurred or interrupt disabled</description>
                                    <value>#0</value>
                                </enumeratedValue>
                                <enumeratedValue>
                                    <name>1</name>
                                    <description>Texture bus error interrupt triggered.</description>
                                    <value>#1</value>
                                </enumeratedValue>
                            </enumeratedValues>
                        </field>
                        <field>
                            <name>BUSERRMDL</name>
                            <description>Display List Bus Error Interrupt Triggered</description>
                            <lsb>10</lsb>
                            <msb>10</msb>
                            <access>read-only</access>
                            <enumeratedValues>
                                <enumeratedValue>
                                    <name>0</name>
                                    <description>No display list bus error occurred or interrupt disabled</description>
                                    <value>#0</value>
                                </enumeratedValue>
                                <enumeratedValue>
                                    <name>1</name>
                                    <description>Display list bus error interrupt triggered.</description>
                                    <value>#1</value>
                                </enumeratedValue>
                            </enumeratedValues>
                        </field>
                    </fields>
                </register>
                <register>
                    <name>CONTROL2</name>
                    <description>Surface Control Register</description>
                    <addressOffset>0x04</addressOffset>
                    <size>32</size>
                    <access>write-only</access>
                    <resetValue>0x00000000</resetValue>
                    <resetMask>0xffffffff</resetMask>
                    <fields>
                        <field>
                            <name>PATTERNENABLE</name>
                            <description>Pattern Color Enable for Pixel Source</description>
                            <lsb>0</lsb>
                            <msb>0</msb>
                            <access>write-only</access>
                            <enumeratedValues>
                                <enumeratedValue>
                                    <name>0</name>
                                    <description>Disable pattern</description>
                                    <value>#0</value>
                                </enumeratedValue>
                                <enumeratedValue>
                                    <name>1</name>
                                    <description>Enable pattern.</description>
                                    <value>#1</value>
                                </enumeratedValue>
                            </enumeratedValues>
                        </field>
                        <field>
                            <name>TEXTUREENABLE</name>
                            <description>Texture Enable for Pixel Source</description>
                            <lsb>1</lsb>
                            <msb>1</msb>
                            <access>write-only</access>
                            <enumeratedValues>
                                <enumeratedValue>
                                    <name>0</name>
                                    <description>Disable texture</description>
                                    <value>#0</value>
                                </enumeratedValue>
                                <enumeratedValue>
                                    <name>1</name>
                                    <description>Enable texture.</description>
                                    <value>#1</value>
                                </enumeratedValue>
                            </enumeratedValues>
                        </field>
                        <field>
                            <name>PATTERNSOURCEL5</name>
                            <description>Limiter 5 Enable for Pattern Index</description>
                            <lsb>2</lsb>
                            <msb>2</msb>
                            <access>write-only</access>
                        </field>
                        <field>
                            <name>USEACB</name>
                            <description>Alpha Blend Mode</description>
                            <lsb>3</lsb>
                            <msb>3</msb>
                            <access>write-only</access>
                            <enumeratedValues>
                                <enumeratedValue>
                                    <name>0</name>
                                    <description>Use WRITEALPHA[1:0] mode</description>
                                    <value>#0</value>
                                </enumeratedValue>
                                <enumeratedValue>
                                    <name>1</name>
                                    <description>Use full alpha channel blending mode.</description>
                                    <value>#1</value>
                                </enumeratedValue>
                            </enumeratedValues>
                        </field>
                        <field>
                            <name>READFORMAT_H</name>
                            <description>Texture Format Descriptor</description>
                            <lsb>4</lsb>
                            <msb>5</msb>
                            <access>write-only</access>
                        </field>
                        <field>
                            <name>BSFA</name>
                            <description>Blend Source Factor for Alpha Channel</description>
                            <lsb>6</lsb>
                            <msb>6</msb>
                            <access>write-only</access>
                            <enumeratedValues>
                                <enumeratedValue>
                                    <name>0</name>
                                    <description>Use 1.0 as blend source factor for alpha channel</description>
                                    <value>#0</value>
                                </enumeratedValue>
                                <enumeratedValue>
                                    <name>1</name>
                                    <description>Use alpha as blend source factor for alpha channel.</description>
                                    <value>#1</value>
                                </enumeratedValue>
                            </enumeratedValues>
                        </field>
                        <field>
                            <name>BDFA</name>
                            <description>Blend Destination Factor for Alpha Channel</description>
                            <lsb>7</lsb>
                            <msb>7</msb>
                            <access>write-only</access>
                            <enumeratedValues>
                                <enumeratedValue>
                                    <name>0</name>
                                    <description>Use 1.0 as blend destination factor for alpha channel</description>
                                    <value>#0</value>
                                </enumeratedValue>
                                <enumeratedValue>
                                    <name>1</name>
                                    <description>Use alpha as blend destination factor for alpha channel.</description>
                                    <value>#1</value>
                                </enumeratedValue>
                            </enumeratedValues>
                        </field>
                        <field>
                            <name>WRITEFORMAT2</name>
                            <description>Writeback Framebuffer Format</description>
                            <lsb>8</lsb>
                            <msb>8</msb>
                            <access>write-only</access>
                        </field>
                        <field>
                            <name>BSF</name>
                            <description>Blend Source Factor</description>
                            <lsb>9</lsb>
                            <msb>9</msb>
                            <access>write-only</access>
                            <enumeratedValues>
                                <enumeratedValue>
                                    <name>0</name>
                                    <description>Use 1.0 as blend source factor</description>
                                    <value>#0</value>
                                </enumeratedValue>
                                <enumeratedValue>
                                    <name>1</name>
                                    <description>Use alpha as blend source factor.</description>
                                    <value>#1</value>
                                </enumeratedValue>
                            </enumeratedValues>
                        </field>
                        <field>
                            <name>BDF</name>
                            <description>Blend Destination Factor</description>
                            <lsb>10</lsb>
                            <msb>10</msb>
                            <access>write-only</access>
                            <enumeratedValues>
                                <enumeratedValue>
                                    <name>0</name>
                                    <description>Use 1.0 as blend destination factor</description>
                                    <value>#0</value>
                                </enumeratedValue>
                                <enumeratedValue>
                                    <name>1</name>
                                    <description>Use alpha as blend destination factor.</description>
                                    <value>#1</value>
                                </enumeratedValue>
                            </enumeratedValues>
                        </field>
                        <field>
                            <name>BSI</name>
                            <description>Blend Source Factor Inverted</description>
                            <lsb>11</lsb>
                            <msb>11</msb>
                            <access>write-only</access>
                            <enumeratedValues>
                                <enumeratedValue>
                                    <name>0</name>
                                    <description>Use blend factor as specified through BSF</description>
                                    <value>#0</value>
                                </enumeratedValue>
                                <enumeratedValue>
                                    <name>1</name>
                                    <description>Invert blend source factor (1-x).</description>
                                    <value>#1</value>
                                </enumeratedValue>
                            </enumeratedValues>
                        </field>
                        <field>
                            <name>BDI</name>
                            <description>Blend Destination Factor Inverted</description>
                            <lsb>12</lsb>
                            <msb>12</msb>
                            <access>write-only</access>
                            <enumeratedValues>
                                <enumeratedValue>
                                    <name>0</name>
                                    <description>Use blend factor as specified through BDF</description>
                                    <value>#0</value>
                                </enumeratedValue>
                                <enumeratedValue>
                                    <name>1</name>
                                    <description>Invert blend destination factor (1-x).</description>
                                    <value>#1</value>
                                </enumeratedValue>
                            </enumeratedValues>
                        </field>
                        <field>
                            <name>BC2</name>
                            <description>Blend color 2</description>
                            <lsb>13</lsb>
                            <msb>13</msb>
                            <access>write-only</access>
                            <enumeratedValues>
                                <enumeratedValue>
                                    <name>0</name>
                                    <description>Use pixel from framebuffer as destination (DST)</description>
                                    <value>#0</value>
                                </enumeratedValue>
                                <enumeratedValue>
                                    <name>1</name>
                                    <description>Use color 2 as destination (DST).</description>
                                    <value>#1</value>
                                </enumeratedValue>
                            </enumeratedValues>
                        </field>
                        <field>
                            <name>TEXTURECLAMPX</name>
                            <description>Calculating U Limiter Outside Used Texture</description>
                            <lsb>14</lsb>
                            <msb>14</msb>
                            <access>write-only</access>
                            <enumeratedValues>
                                <enumeratedValue>
                                    <name>0</name>
                                    <description>Texture wrap mode: Integer part of the calculated value from the U limiter is AND gated with TEXUMASK, resulting in a repetition of texture in the x/u direction</description>
                                    <value>#0</value>
                                </enumeratedValue>
                                <enumeratedValue>
                                    <name>1</name>
                                    <description>Texture clamp mode: Texture color at the border of the texture is taken, resulting in a repetition of texture border color in the x/u direction.</description>
                                    <value>#1</value>
                                </enumeratedValue>
                            </enumeratedValues>
                        </field>
                        <field>
                            <name>TEXTURECLAMPY</name>
                            <description>Calculating V Limiter Outside Used Texture</description>
                            <lsb>15</lsb>
                            <msb>15</msb>
                            <access>write-only</access>
                            <enumeratedValues>
                                <enumeratedValue>
                                    <name>0</name>
                                    <description>Texture wrap mode: Integer part of the calculated value from the V limiter is AND gated with TEXVMASK, resulting in a repetition of texture in the y/v direction.</description>
                                    <value>#0</value>
                                </enumeratedValue>
                                <enumeratedValue>
                                    <name>1</name>
                                    <description>Texture clamp mode: Texture color at the border of the texture is taken, resulting in a repetition of texture border color in the y/v direction.</description>
                                    <value>#1</value>
                                </enumeratedValue>
                            </enumeratedValues>
                        </field>
                        <field>
                            <name>TEXTUREFILTERX</name>
                            <description>Linear Filtering on Texture U Axis</description>
                            <lsb>16</lsb>
                            <msb>16</msb>
                            <access>write-only</access>
                            <enumeratedValues>
                                <enumeratedValue>
                                    <name>0</name>
                                    <description>No filtering on texture U axis</description>
                                    <value>#0</value>
                                </enumeratedValue>
                                <enumeratedValue>
                                    <name>1</name>
                                    <description>Linear filtering on texture U axis.</description>
                                    <value>#1</value>
                                </enumeratedValue>
                            </enumeratedValues>
                        </field>
                        <field>
                            <name>TEXTUREFILTERY</name>
                            <description>Linear Filtering on Texture V Axis</description>
                            <lsb>17</lsb>
                            <msb>17</msb>
                            <access>write-only</access>
                            <enumeratedValues>
                                <enumeratedValue>
                                    <name>0</name>
                                    <description>No filtering on texture V axis</description>
                                    <value>#0</value>
                                </enumeratedValue>
                                <enumeratedValue>
                                    <name>1</name>
                                    <description>Linear filtering on texture V axis.</description>
                                    <value>#1</value>
                                </enumeratedValue>
                            </enumeratedValues>
                        </field>
                        <field>
                            <name>READFORMAT_L</name>
                            <description>Texture Format Descriptor</description>
                            <lsb>18</lsb>
                            <msb>19</msb>
                            <access>write-only</access>
                        </field>
                        <field>
                            <name>WRITEFORMAT</name>
                            <description>Writeback Framebuffer Format</description>
                            <lsb>20</lsb>
                            <msb>21</msb>
                            <access>write-only</access>
                        </field>
                        <field>
                            <name>WRITEALPHA</name>
                            <description>Writeback Alpha Source for Framebuffer</description>
                            <lsb>22</lsb>
                            <msb>23</msb>
                            <access>write-only</access>
                            <enumeratedValues>
                                <enumeratedValue>
                                    <name>00</name>
                                    <description>(USEACB = 0) Use alpha from color 2 (USEACB = 0) (USEACB = 1) BC2A = 1: Use alpha in color 2 as destination (DST_A) </description>
                                    <value>#00</value>
                                </enumeratedValue>
                                <enumeratedValue>
                                    <name>01</name>
                                    <description>(USEACB = 0) Use source alpha (pixel coverage) (USEACB = 1) BC2A = 0: Use alpha from framebuffer as destination (DST_A) </description>
                                    <value>#01</value>
                                </enumeratedValue>
                                <enumeratedValue>
                                    <name>10</name>
                                    <description>(USEACB = 0) Use 0.0 as alpha (USEACB = 1) BC2A = 0: Use alpha from framebuffer as destination (DST_A) </description>
                                    <value>#10</value>
                                </enumeratedValue>
                                <enumeratedValue>
                                    <name>10</name>
                                    <description>(USEACB = 0) Use alpha from framebuffer (USEACB = 1) BC2A = 0: Use alpha from framebuffer as destination (DST_A) </description>
                                    <value>#10</value>
                                </enumeratedValue>
                            </enumeratedValues>
                        </field>
                        <field>
                            <name>RLEENABLE</name>
                            <description>RLE Enable</description>
                            <lsb>24</lsb>
                            <msb>24</msb>
                            <access>write-only</access>
                            <enumeratedValues>
                                <enumeratedValue>
                                    <name>0</name>
                                    <description>Disable RLE</description>
                                    <value>#0</value>
                                </enumeratedValue>
                                <enumeratedValue>
                                    <name>1</name>
                                    <description>Enable RLE.</description>
                                    <value>#1</value>
                                </enumeratedValue>
                            </enumeratedValues>
                        </field>
                        <field>
                            <name>CLUTENABLE</name>
                            <description>CLUT Enable</description>
                            <lsb>25</lsb>
                            <msb>25</msb>
                            <access>write-only</access>
                            <enumeratedValues>
                                <enumeratedValue>
                                    <name>0</name>
                                    <description>Disable CLUT</description>
                                    <value>#0</value>
                                </enumeratedValue>
                                <enumeratedValue>
                                    <name>1</name>
                                    <description>Enable CLUT</description>
                                    <value>#1</value>
                                </enumeratedValue>
                            </enumeratedValues>
                        </field>
                        <field>
                            <name>COLKEYENABLE</name>
                            <description>Color Keying Enable</description>
                            <lsb>26</lsb>
                            <msb>26</msb>
                            <access>write-only</access>
                            <enumeratedValues>
                                <enumeratedValue>
                                    <name>0</name>
                                    <description>Disable color keying</description>
                                    <value>#0</value>
                                </enumeratedValue>
                                <enumeratedValue>
                                    <name>1</name>
                                    <description>Enable color keying.</description>
                                    <value>#1</value>
                                </enumeratedValue>
                            </enumeratedValues>
                        </field>
                        <field>
                            <name>CLUTFORMAT</name>
                            <description>CLUT Format</description>
                            <lsb>27</lsb>
                            <msb>27</msb>
                            <access>write-only</access>
                            <enumeratedValues>
                                <enumeratedValue>
                                    <name>0</name>
                                    <description>Format CLUT as ARGB (8888)</description>
                                    <value>#0</value>
                                </enumeratedValue>
                                <enumeratedValue>
                                    <name>1</name>
                                    <description>Format CLUT as RGB (565).</description>
                                    <value>#1</value>
                                </enumeratedValue>
                            </enumeratedValues>
                        </field>
                        <field>
                            <name>BSIA</name>
                            <description>Blend Source Factor Inverted in Alpha Channel</description>
                            <lsb>28</lsb>
                            <msb>28</msb>
                            <access>write-only</access>
                            <enumeratedValues>
                                <enumeratedValue>
                                    <name>0</name>
                                    <description>Use blend factor as specified through BSFA</description>
                                    <value>#0</value>
                                </enumeratedValue>
                                <enumeratedValue>
                                    <name>1</name>
                                    <description>Invert blend source factor (1-x).</description>
                                    <value>#1</value>
                                </enumeratedValue>
                            </enumeratedValues>
                        </field>
                        <field>
                            <name>BDIA</name>
                            <description>Blend Destination Factor Inverted in Alpha Channel</description>
                            <lsb>29</lsb>
                            <msb>29</msb>
                            <access>write-only</access>
                            <enumeratedValues>
                                <enumeratedValue>
                                    <name>0</name>
                                    <description>Use blend factor as specified through BDFA</description>
                                    <value>#0</value>
                                </enumeratedValue>
                                <enumeratedValue>
                                    <name>1</name>
                                    <description>Invert destination blend factor (1-x).</description>
                                    <value>#1</value>
                                </enumeratedValue>
                            </enumeratedValues>
                        </field>
                        <field>
                            <name>RLEPIXELWIDTH</name>
                            <description>Texel Width for RLE Unit</description>
                            <lsb>30</lsb>
                            <msb>31</msb>
                            <access>write-only</access>
                            <enumeratedValues>
                                <enumeratedValue>
                                    <name>00</name>
                                    <description>1 byte per texel</description>
                                    <value>#00</value>
                                </enumeratedValue>
                                <enumeratedValue>
                                    <name>01</name>
                                    <description>2 bytes per texel</description>
                                    <value>#01</value>
                                </enumeratedValue>
                                <enumeratedValue>
                                    <name>10</name>
                                    <description>3 bytes per texel</description>
                                    <value>#10</value>
                                </enumeratedValue>
                                <enumeratedValue>
                                    <name>11</name>
                                    <description>4 bytes per texel</description>
                                    <value>#11</value>
                                </enumeratedValue>
                            </enumeratedValues>
                        </field>
                    </fields>
                </register>
                <register>
                    <name>HWREVISION</name>
                    <description>Hardware Version and Feature Set ID Register</description>
                    <alternateRegister>CONTROL2</alternateRegister>
                    <addressOffset>0x04</addressOffset>
                    <size>32</size>
                    <access>read-only</access>
                    <resetValue>0x0fbe0107</resetValue>
                    <resetMask>0xffffffff</resetMask>
                    <fields>
                        <field>
                            <name>REV</name>
                            <description>Revision Number of DRW is stored.</description>
                            <lsb>0</lsb>
                            <msb>11</msb>
                            <access>read-only</access>
                        </field>
                        <field>
                            <name>DLR</name>
                            <description>Display List Reader Available</description>
                            <lsb>17</lsb>
                            <msb>17</msb>
                            <access>read-only</access>
                            <enumeratedValues>
                                <enumeratedValue>
                                    <name>0</name>
                                    <description>No display list reader</description>
                                    <value>#0</value>
                                </enumeratedValue>
                                <enumeratedValue>
                                    <name>1</name>
                                    <description>Display list reader is available</description>
                                    <value>#1</value>
                                </enumeratedValue>
                            </enumeratedValues>
                        </field>
                        <field>
                            <name>FBCACHE</name>
                            <description>Framebuffer Cache Available</description>
                            <lsb>18</lsb>
                            <msb>18</msb>
                            <access>read-only</access>
                            <enumeratedValues>
                                <enumeratedValue>
                                    <name>0</name>
                                    <description>No framebuffer cache</description>
                                    <value>#0</value>
                                </enumeratedValue>
                                <enumeratedValue>
                                    <name>1</name>
                                    <description>Framebuffer cache is available</description>
                                    <value>#1</value>
                                </enumeratedValue>
                            </enumeratedValues>
                        </field>
                        <field>
                            <name>TXCACHE</name>
                            <description>Texture Cache Available</description>
                            <lsb>19</lsb>
                            <msb>19</msb>
                            <access>read-only</access>
                            <enumeratedValues>
                                <enumeratedValue>
                                    <name>0</name>
                                    <description>No texture cache</description>
                                    <value>#0</value>
                                </enumeratedValue>
                                <enumeratedValue>
                                    <name>1</name>
                                    <description>Texture cache is available</description>
                                    <value>#1</value>
                                </enumeratedValue>
                            </enumeratedValues>
                        </field>
                        <field>
                            <name>PERFCOUNT</name>
                            <description>Two Performance Counter Available</description>
                            <lsb>20</lsb>
                            <msb>20</msb>
                            <access>read-only</access>
                            <enumeratedValues>
                                <enumeratedValue>
                                    <name>0</name>
                                    <description>No performance counter</description>
                                    <value>#0</value>
                                </enumeratedValue>
                                <enumeratedValue>
                                    <name>1</name>
                                    <description>Tow performance counters available</description>
                                    <value>#1</value>
                                </enumeratedValue>
                            </enumeratedValues>
                        </field>
                        <field>
                            <name>TEXCLUT</name>
                            <description>Texture CLUT Available</description>
                            <lsb>21</lsb>
                            <msb>21</msb>
                            <access>read-only</access>
                            <enumeratedValues>
                                <enumeratedValue>
                                    <name>0</name>
                                    <description>No texture CLUT</description>
                                    <value>#0</value>
                                </enumeratedValue>
                                <enumeratedValue>
                                    <name>1</name>
                                    <description>Texture CLUT is available</description>
                                    <value>#1</value>
                                </enumeratedValue>
                            </enumeratedValues>
                        </field>
                        <field>
                            <name>RLEUNIT</name>
                            <description>RLE Unit Available</description>
                            <lsb>23</lsb>
                            <msb>23</msb>
                            <access>read-only</access>
                            <enumeratedValues>
                                <enumeratedValue>
                                    <name>0</name>
                                    <description>No RLE unit</description>
                                    <value>#0</value>
                                </enumeratedValue>
                                <enumeratedValue>
                                    <name>1</name>
                                    <description>RLE unit is available</description>
                                    <value>#1</value>
                                </enumeratedValue>
                            </enumeratedValues>
                        </field>
                        <field>
                            <name>TEXCLUT256</name>
                            <description>Texture CLUT size</description>
                            <lsb>24</lsb>
                            <msb>24</msb>
                            <access>read-only</access>
                            <enumeratedValues>
                                <enumeratedValue>
                                    <name>0</name>
                                    <description>Texture CLUT size is 16 entries</description>
                                    <value>#0</value>
                                </enumeratedValue>
                                <enumeratedValue>
                                    <name>1</name>
                                    <description>Texture CLUT size is 256 entries</description>
                                    <value>#1</value>
                                </enumeratedValue>
                            </enumeratedValues>
                        </field>
                        <field>
                            <name>COLORKEY</name>
                            <description>Color Key Available</description>
                            <lsb>25</lsb>
                            <msb>25</msb>
                            <access>read-only</access>
                            <enumeratedValues>
                                <enumeratedValue>
                                    <name>0</name>
                                    <description>No color key</description>
                                    <value>#0</value>
                                </enumeratedValue>
                                <enumeratedValue>
                                    <name>1</name>
                                    <description>Color key is available</description>
                                    <value>#1</value>
                                </enumeratedValue>
                            </enumeratedValues>
                        </field>
                        <field>
                            <name>ACBLEND</name>
                            <description>Alpha Channel Blending Available</description>
                            <lsb>27</lsb>
                            <msb>27</msb>
                            <access>read-only</access>
                            <enumeratedValues>
                                <enumeratedValue>
                                    <name>0</name>
                                    <description>Full alpha channel blending is not available</description>
                                    <value>#0</value>
                                </enumeratedValue>
                                <enumeratedValue>
                                    <name>1</name>
                                    <description>Full alpha channel blending is available</description>
                                    <value>#1</value>
                                </enumeratedValue>
                            </enumeratedValues>
                        </field>
                    </fields>
                </register>
                <register>
                    <dim>6</dim>
                    <dimIncrement>0x4</dimIncrement>
                    <dimIndex>1-6</dimIndex>
                    <name>L%sSTART</name>
                    <description>Limiter %s Start Value Register (n = 1 to 6)</description>
                    <addressOffset>0x10</addressOffset>
                    <size>32</size>
                    <access>write-only</access>
                    <resetValue>0x00000000</resetValue>
                    <resetMask>0xffffffff</resetMask>
                    <fields>
                        <field>
                            <name>LSTART</name>
                            <description>Start Value of the nth Limiter</description>
                            <lsb>0</lsb>
                            <msb>31</msb>
                            <access>write-only</access>
                        </field>
                    </fields>
                </register>
                <register>
                    <dim>6</dim>
                    <dimIncrement>0x4</dimIncrement>
                    <dimIndex>1-6</dimIndex>
                    <name>L%sXADD</name>
                    <description>Limiter %s X-Axis Increment Register(n = 1 to 6)</description>
                    <addressOffset>0x28</addressOffset>
                    <size>32</size>
                    <access>write-only</access>
                    <resetValue>0x00000000</resetValue>
                    <resetMask>0xffffffff</resetMask>
                    <fields>
                        <field>
                            <name>LXADD</name>
                            <description>X-Axis Increment</description>
                            <lsb>0</lsb>
                            <msb>31</msb>
                            <access>write-only</access>
                        </field>
                    </fields>
                </register>
                <register>
                    <dim>6</dim>
                    <dimIncrement>0x4</dimIncrement>
                    <dimIndex>1-6</dimIndex>
                    <name>L%sYADD</name>
                    <description>Limiter %s Y-Axis Increment Register(n = 1 to 6)</description>
                    <addressOffset>0x40</addressOffset>
                    <size>32</size>
                    <access>write-only</access>
                    <resetValue>0x00000000</resetValue>
                    <resetMask>0xffffffff</resetMask>
                    <fields>
                        <field>
                            <name>LYADD</name>
                            <description>Y-Axis Increment</description>
                            <lsb>0</lsb>
                            <msb>31</msb>
                            <access>write-only</access>
                        </field>
                    </fields>
                </register>
                <register>
                    <dim>2</dim>
                    <dimIncrement>0x4</dimIncrement>
                    <dimIndex>1-2</dimIndex>
                    <name>L%sBAND</name>
                    <description>Limiter m Band Width Parameter Register(n = 1, 2)</description>
                    <addressOffset>0x58</addressOffset>
                    <size>32</size>
                    <access>write-only</access>
                    <resetValue>0x00000000</resetValue>
                    <resetMask>0xffffffff</resetMask>
                    <fields>
                        <field>
                            <name>LBAND</name>
                            <description>Limiter m Band Width Parameter</description>
                            <lsb>0</lsb>
                            <msb>31</msb>
                            <access>write-only</access>
                        </field>
                    </fields>
                </register>
                <register>
                    <name>COLOR1</name>
                    <description>Base Color Register</description>
                    <addressOffset>0x64</addressOffset>
                    <size>32</size>
                    <access>write-only</access>
                    <resetValue>0x00000000</resetValue>
                    <resetMask>0xffffffff</resetMask>
                    <fields>
                        <field>
                            <name>COLOR1B</name>
                            <description>Blue Channel of Color 1</description>
                            <lsb>0</lsb>
                            <msb>7</msb>
                            <access>write-only</access>
                        </field>
                        <field>
                            <name>COLOR1G</name>
                            <description>Green Channel of Color 1</description>
                            <lsb>8</lsb>
                            <msb>15</msb>
                            <access>write-only</access>
                        </field>
                        <field>
                            <name>COLOR1R</name>
                            <description>Red Channel of Color 1</description>
                            <lsb>16</lsb>
                            <msb>23</msb>
                            <access>write-only</access>
                        </field>
                        <field>
                            <name>COLOR1A</name>
                            <description>Alpha Channel of Color 1</description>
                            <lsb>24</lsb>
                            <msb>31</msb>
                            <access>write-only</access>
                        </field>
                    </fields>
                </register>
                <register>
                    <name>COLOR2</name>
                    <description>Secondary Color Register</description>
                    <addressOffset>0x68</addressOffset>
                    <size>32</size>
                    <access>write-only</access>
                    <resetValue>0x00000000</resetValue>
                    <resetMask>0xffffffff</resetMask>
                    <fields>
                        <field>
                            <name>COLOR2B</name>
                            <description>Blue Channel of Color 2</description>
                            <lsb>0</lsb>
                            <msb>7</msb>
                            <access>write-only</access>
                        </field>
                        <field>
                            <name>COLOR2G</name>
                            <description>Green Channel of Color 2</description>
                            <lsb>8</lsb>
                            <msb>15</msb>
                            <access>write-only</access>
                        </field>
                        <field>
                            <name>COLOR2R</name>
                            <description>Red Channel of Color 2</description>
                            <lsb>16</lsb>
                            <msb>23</msb>
                            <access>write-only</access>
                        </field>
                        <field>
                            <name>COLOR2A</name>
                            <description>Alpha Channel of Color 2</description>
                            <lsb>24</lsb>
                            <msb>31</msb>
                            <access>write-only</access>
                        </field>
                    </fields>
                </register>
                <register>
                    <name>PATTERN</name>
                    <description>Pattern Register</description>
                    <addressOffset>0x74</addressOffset>
                    <size>32</size>
                    <access>write-only</access>
                    <resetValue>0x00000000</resetValue>
                    <resetMask>0xffffffff</resetMask>
                    <fields>
                        <field>
                            <name>PATTERN</name>
                            <description>Bitmap of the Pattern</description>
                            <lsb>0</lsb>
                            <msb>7</msb>
                            <access>write-only</access>
                        </field>
                    </fields>
                </register>
                <register>
                    <name>SIZE</name>
                    <description>Bounding Box Dimension Register</description>
                    <addressOffset>0x78</addressOffset>
                    <size>32</size>
                    <access>write-only</access>
                    <resetValue>0x00000000</resetValue>
                    <resetMask>0xffffffff</resetMask>
                    <fields>
                        <field>
                            <name>SIZEX</name>
                            <description>Bounding Box Width</description>
                            <lsb>0</lsb>
                            <msb>15</msb>
                            <access>write-only</access>
                        </field>
                        <field>
                            <name>SIZEY</name>
                            <description>Bounding Box Height</description>
                            <lsb>16</lsb>
                            <msb>31</msb>
                            <access>write-only</access>
                        </field>
                    </fields>
                </register>
                <register>
                    <name>PITCH</name>
                    <description>Framebuffer Pitch And Spanstore Delay Register</description>
                    <addressOffset>0x7C</addressOffset>
                    <size>32</size>
                    <access>write-only</access>
                    <resetValue>0x00000000</resetValue>
                    <resetMask>0xffffffff</resetMask>
                    <fields>
                        <field>
                            <name>PITCH</name>
                            <description>Pitch of the Framebuffer</description>
                            <lsb>0</lsb>
                            <msb>15</msb>
                            <access>write-only</access>
                        </field>
                        <field>
                            <name>SSD</name>
                            <description>Spanstore Delay</description>
                            <lsb>16</lsb>
                            <msb>31</msb>
                            <access>write-only</access>
                        </field>
                    </fields>
                </register>
                <register>
                    <name>ORIGIN</name>
                    <description>Framebuffer Base Address Register</description>
                    <addressOffset>0x80</addressOffset>
                    <size>32</size>
                    <access>write-only</access>
                    <resetValue>0x00000000</resetValue>
                    <resetMask>0xffffffff</resetMask>
                    <fields>
                        <field>
                            <name>ORIGIN</name>
                            <description>Address of the First Pixel in Framebuffer</description>
                            <lsb>0</lsb>
                            <msb>31</msb>
                            <access>write-only</access>
                        </field>
                    </fields>
                </register>
                <register>
                    <name>LUSTART</name>
                    <description>U Limiter Start Value Register</description>
                    <addressOffset>0x90</addressOffset>
                    <size>32</size>
                    <access>write-only</access>
                    <resetValue>0x00000000</resetValue>
                    <resetMask>0xffffffff</resetMask>
                    <fields>
                        <field>
                            <name>LUSTART</name>
                            <description>U Limiter Start Value</description>
                            <lsb>0</lsb>
                            <msb>31</msb>
                            <access>write-only</access>
                        </field>
                    </fields>
                </register>
                <register>
                    <name>LUXADD</name>
                    <description>U Limiter X-Axis Increment Register</description>
                    <addressOffset>0x94</addressOffset>
                    <size>32</size>
                    <access>write-only</access>
                    <resetValue>0x00000000</resetValue>
                    <resetMask>0xffffffff</resetMask>
                    <fields>
                        <field>
                            <name>LUXADD</name>
                            <description>U Limiter X-Axis Increment</description>
                            <lsb>0</lsb>
                            <msb>31</msb>
                            <access>write-only</access>
                        </field>
                    </fields>
                </register>
                <register>
                    <name>LUYADD</name>
                    <description>U Limiter Y-Axis Increment Register</description>
                    <addressOffset>0x98</addressOffset>
                    <size>32</size>
                    <access>write-only</access>
                    <resetValue>0x00000000</resetValue>
                    <resetMask>0xffffffff</resetMask>
                    <fields>
                        <field>
                            <name>LUYADD</name>
                            <description>U Limiter Y-Axis Increment</description>
                            <lsb>0</lsb>
                            <msb>31</msb>
                            <access>write-only</access>
                        </field>
                    </fields>
                </register>
                <register>
                    <name>LVSTARTI</name>
                    <description>V Limiter Start Value Integer Part Register</description>
                    <addressOffset>0x9C</addressOffset>
                    <size>32</size>
                    <access>write-only</access>
                    <resetValue>0x00000000</resetValue>
                    <resetMask>0xffffffff</resetMask>
                    <fields>
                        <field>
                            <name>LVSTARTI</name>
                            <description>V Limiter Start Value Integer Part</description>
                            <lsb>0</lsb>
                            <msb>0</msb>
                            <access>write-only</access>
                        </field>
                    </fields>
                </register>
                <register>
                    <name>LVSTARTF</name>
                    <description>V Limiter Start Value Fractional Part Register</description>
                    <addressOffset>0xA0</addressOffset>
                    <size>32</size>
                    <access>write-only</access>
                    <resetValue>0x00000000</resetValue>
                    <resetMask>0xffffffff</resetMask>
                    <fields>
                        <field>
                            <name>LVSTARTF</name>
                            <description>V Limiter Start Value Fractional Part</description>
                            <lsb>0</lsb>
                            <msb>15</msb>
                            <access>write-only</access>
                        </field>
                    </fields>
                </register>
                <register>
                    <name>LVXADDI</name>
                    <description>V Limiter X-Axis Increment Integer Part Register</description>
                    <addressOffset>0xA4</addressOffset>
                    <size>32</size>
                    <access>write-only</access>
                    <resetValue>0x00000000</resetValue>
                    <resetMask>0xffffffff</resetMask>
                    <fields>
                        <field>
                            <name>LVXADDI</name>
                            <description>V Limiter X-Axis Increment Integer Part</description>
                            <lsb>0</lsb>
                            <msb>31</msb>
                            <access>write-only</access>
                        </field>
                    </fields>
                </register>
                <register>
                    <name>LVYADDI</name>
                    <description>V Limiter Y-Axis Increment Integer Part Register</description>
                    <addressOffset>0xA8</addressOffset>
                    <size>32</size>
                    <access>write-only</access>
                    <resetValue>0x00000000</resetValue>
                    <resetMask>0xffffffff</resetMask>
                    <fields>
                        <field>
                            <name>LVYADDI</name>
                            <description>V Limiter Y-Axis Increment Integer Part</description>
                            <lsb>0</lsb>
                            <msb>31</msb>
                            <access>write-only</access>
                        </field>
                    </fields>
                </register>
                <register>
                    <name>LVYXADDF</name>
                    <description>V Limiter Increment Fractional Parts Register</description>
                    <addressOffset>0xAC</addressOffset>
                    <size>32</size>
                    <access>write-only</access>
                    <resetValue>0x00000000</resetValue>
                    <resetMask>0xffffffff</resetMask>
                    <fields>
                        <field>
                            <name>LVXADDF</name>
                            <description>V Limiter X-Axis Increment Fractional Part</description>
                            <lsb>0</lsb>
                            <msb>15</msb>
                            <access>write-only</access>
                        </field>
                        <field>
                            <name>LVYADDF</name>
                            <description>V Limiter Y-Axis Increment Fractional Part</description>
                            <lsb>16</lsb>
                            <msb>31</msb>
                            <access>write-only</access>
                        </field>
                    </fields>
                </register>
                <register>
                    <name>TEXPITCH</name>
                    <description>Texels Per Texture Line Register</description>
                    <addressOffset>0xB4</addressOffset>
                    <size>32</size>
                    <access>write-only</access>
                    <resetValue>0x00000000</resetValue>
                    <resetMask>0xffffffff</resetMask>
                    <fields>
                        <field>
                            <name>TEXPITCH</name>
                            <description>Texels Per Texture Line</description>
                            <lsb>0</lsb>
                            <msb>31</msb>
                            <access>write-only</access>
                        </field>
                    </fields>
                </register>
                <register>
                    <name>TEXMASK</name>
                    <description>Texture Size or Texture Address Mask Register</description>
                    <addressOffset>0xB8</addressOffset>
                    <size>32</size>
                    <access>write-only</access>
                    <resetValue>0x00000000</resetValue>
                    <resetMask>0xffffffff</resetMask>
                    <fields>
                        <field>
                            <name>TEXUMASK</name>
                            <description>U Mask in Texture Mode</description>
                            <lsb>0</lsb>
                            <msb>10</msb>
                            <access>write-only</access>
                        </field>
                        <field>
                            <name>TEXVMASK</name>
                            <description>V Mask in Texture Mode</description>
                            <lsb>11</lsb>
                            <msb>31</msb>
                            <access>write-only</access>
                        </field>
                    </fields>
                </register>
                <register>
                    <name>TEXORIGIN</name>
                    <description>Texture Base Address Register</description>
                    <addressOffset>0xBC</addressOffset>
                    <size>32</size>
                    <access>write-only</access>
                    <resetValue>0x00000000</resetValue>
                    <resetMask>0xffffffff</resetMask>
                    <fields>
                        <field>
                            <name>TEXORIGIN</name>
                            <description>Texture Base Address</description>
                            <lsb>0</lsb>
                            <msb>31</msb>
                            <access>write-only</access>
                        </field>
                    </fields>
                </register>
                <register>
                    <name>IRQCTL</name>
                    <description>Interrupt Control Register</description>
                    <addressOffset>0xC0</addressOffset>
                    <size>32</size>
                    <access>write-only</access>
                    <resetValue>0x00000000</resetValue>
                    <resetMask>0xffffffff</resetMask>
                    <fields>
                        <field>
                            <name>ENUMIRQEN</name>
                            <description>ENUMIRQ Interrupt Mask Enable</description>
                            <lsb>0</lsb>
                            <msb>0</msb>
                            <access>write-only</access>
                            <enumeratedValues>
                                <enumeratedValue>
                                    <name>0</name>
                                    <description>Disable (mask) ENUMIRQ enumeration interrupt</description>
                                    <value>#0</value>
                                </enumeratedValue>
                                <enumeratedValue>
                                    <name>1</name>
                                    <description>Enable (unmask) ENUMIRQ enumeration interrupt.</description>
                                    <value>#1</value>
                                </enumeratedValue>
                            </enumeratedValues>
                        </field>
                        <field>
                            <name>DLISTIRQEN</name>
                            <description>DLISTIRQ Interrupt Mask Enable</description>
                            <lsb>1</lsb>
                            <msb>1</msb>
                            <access>write-only</access>
                            <enumeratedValues>
                                <enumeratedValue>
                                    <name>0</name>
                                    <description>Disable (mask) DLISTIRQ display list interrupt</description>
                                    <value>#0</value>
                                </enumeratedValue>
                                <enumeratedValue>
                                    <name>1</name>
                                    <description>Enable (unmask) DLISTIRQ display list interrupt.</description>
                                    <value>#1</value>
                                </enumeratedValue>
                            </enumeratedValues>
                        </field>
                        <field>
                            <name>ENUMIRQCLR</name>
                            <description>Clear ENUMIRQ</description>
                            <lsb>2</lsb>
                            <msb>2</msb>
                            <access>write-only</access>
                            <enumeratedValues>
                                <enumeratedValue>
                                    <name>0</name>
                                    <description>Do not clear ENUMIRQ enumeration interrupt</description>
                                    <value>#0</value>
                                </enumeratedValue>
                                <enumeratedValue>
                                    <name>1</name>
                                    <description>Clear ENUMIRQ enumeration interrupt.</description>
                                    <value>#1</value>
                                </enumeratedValue>
                            </enumeratedValues>
                        </field>
                        <field>
                            <name>DLISTIRQCLR</name>
                            <description>Clear DLISTIRQ</description>
                            <lsb>3</lsb>
                            <msb>3</msb>
                            <access>write-only</access>
                            <enumeratedValues>
                                <enumeratedValue>
                                    <name>0</name>
                                    <description>Do not clear DLISTIRQ display list interrupt</description>
                                    <value>#0</value>
                                </enumeratedValue>
                                <enumeratedValue>
                                    <name>1</name>
                                    <description>Clear DLISTIRQ display list interrupt.</description>
                                    <value>#1</value>
                                </enumeratedValue>
                            </enumeratedValues>
                        </field>
                        <field>
                            <name>BUSIRQEN</name>
                            <description>BUSIRQ Interrupt Mask Enable</description>
                            <lsb>4</lsb>
                            <msb>4</msb>
                            <access>write-only</access>
                            <enumeratedValues>
                                <enumeratedValue>
                                    <name>0</name>
                                    <description>Disable (mask) BUSIRQ bus error interrupt</description>
                                    <value>#0</value>
                                </enumeratedValue>
                                <enumeratedValue>
                                    <name>1</name>
                                    <description>Enable (unmask) BUSIRQ bus error interrupt.</description>
                                    <value>#1</value>
                                </enumeratedValue>
                            </enumeratedValues>
                        </field>
                        <field>
                            <name>BUSIRQCLR</name>
                            <description>Clear BUSIRQ</description>
                            <lsb>5</lsb>
                            <msb>5</msb>
                            <access>write-only</access>
                            <enumeratedValues>
                                <enumeratedValue>
                                    <name>0</name>
                                    <description>Do not clear BUSIRQ bus error interrupt</description>
                                    <value>#0</value>
                                </enumeratedValue>
                                <enumeratedValue>
                                    <name>1</name>
                                    <description>Clear BUSIRQ bus error interrupt.</description>
                                    <value>#1</value>
                                </enumeratedValue>
                            </enumeratedValues>
                        </field>
                    </fields>
                </register>
                <register>
                    <name>CACHECTL</name>
                    <description>Cache Control Register</description>
                    <addressOffset>0xC4</addressOffset>
                    <size>32</size>
                    <access>write-only</access>
                    <resetValue>0x00000000</resetValue>
                    <resetMask>0xffffffff</resetMask>
                    <fields>
                        <field>
                            <name>CENABLEFX</name>
                            <description>Framebuffer Cache Enable</description>
                            <lsb>0</lsb>
                            <msb>0</msb>
                            <access>write-only</access>
                            <enumeratedValues>
                                <enumeratedValue>
                                    <name>0</name>
                                    <description>Disable the framebuffer cache</description>
                                    <value>#0</value>
                                </enumeratedValue>
                                <enumeratedValue>
                                    <name>1</name>
                                    <description>Enable the framebuffer cache.</description>
                                    <value>#1</value>
                                </enumeratedValue>
                            </enumeratedValues>
                        </field>
                        <field>
                            <name>CFLUSHFX</name>
                            <description>Flush Framebuffer Cache</description>
                            <lsb>1</lsb>
                            <msb>1</msb>
                            <access>write-only</access>
                            <enumeratedValues>
                                <enumeratedValue>
                                    <name>0</name>
                                    <description>Do not flush the framebuffer cache</description>
                                    <value>#0</value>
                                </enumeratedValue>
                                <enumeratedValue>
                                    <name>1</name>
                                    <description>Flush the framebuffer cache.</description>
                                    <value>#1</value>
                                </enumeratedValue>
                            </enumeratedValues>
                        </field>
                        <field>
                            <name>CENABLETX</name>
                            <description>Texture Cache Enable</description>
                            <lsb>2</lsb>
                            <msb>2</msb>
                            <access>write-only</access>
                            <enumeratedValues>
                                <enumeratedValue>
                                    <name>0</name>
                                    <description>Disable the texture cache</description>
                                    <value>#0</value>
                                </enumeratedValue>
                                <enumeratedValue>
                                    <name>1</name>
                                    <description>Enable the texture cache.</description>
                                    <value>#1</value>
                                </enumeratedValue>
                            </enumeratedValues>
                        </field>
                        <field>
                            <name>CFLUSHTX</name>
                            <description>Flush Texture Cache</description>
                            <lsb>3</lsb>
                            <msb>3</msb>
                            <access>write-only</access>
                            <enumeratedValues>
                                <enumeratedValue>
                                    <name>0</name>
                                    <description>Do not flush the texture cache</description>
                                    <value>#0</value>
                                </enumeratedValue>
                                <enumeratedValue>
                                    <name>1</name>
                                    <description>Flush the texture cache.</description>
                                    <value>#1</value>
                                </enumeratedValue>
                            </enumeratedValues>
                        </field>
                    </fields>
                </register>
                <register>
                    <name>DLISTSTART</name>
                    <description>Display List Start Address Register</description>
                    <addressOffset>0xC8</addressOffset>
                    <size>32</size>
                    <access>write-only</access>
                    <resetValue>0x00000000</resetValue>
                    <resetMask>0xffffffff</resetMask>
                    <fields>
                        <field>
                            <name>DLISTSTART</name>
                            <description>Display List Start Address</description>
                            <lsb>0</lsb>
                            <msb>31</msb>
                            <access>write-only</access>
                        </field>
                    </fields>
                </register>
                <register>
                    <name>PERFCOUNT1</name>
                    <description>Performance Counter 1</description>
                    <addressOffset>0xCC</addressOffset>
                    <size>32</size>
                    <access>read-write</access>
                    <resetValue>0x00000000</resetValue>
                    <resetMask>0xffffffff</resetMask>
                    <fields>
                        <field>
                            <name>PERFCOUNT</name>
                            <description>Performance Counter k Value</description>
                            <lsb>0</lsb>
                            <msb>31</msb>
                            <access>read-write</access>
                        </field>
                    </fields>
                </register>
                <register>
                    <name>PERFCOUNT2</name>
                    <description>Performance Counter 2</description>
                    <alternateRegister>PERFCOUNT1</alternateRegister>
                    <addressOffset>0xCC</addressOffset>
                    <size>32</size>
                    <access>read-write</access>
                    <resetValue>0x00000000</resetValue>
                    <resetMask>0xffffffff</resetMask>
                    <fields>
                        <field>
                            <name>PERFCOUNT</name>
                            <description>Performance Counter k Value</description>
                            <lsb>0</lsb>
                            <msb>31</msb>
                            <access>read-write</access>
                        </field>
                    </fields>
                </register>
                <register>
                    <name>PERFTRIGGER</name>
                    <description>Performance Counters Control Register</description>
                    <addressOffset>0xD4</addressOffset>
                    <size>32</size>
                    <access>write-only</access>
                    <resetValue>0x00000000</resetValue>
                    <resetMask>0xffffffff</resetMask>
                    <fields>
                        <field>
                            <name>PERFTRIGGER1</name>
                            <description>Trigger of Performance Counter 1</description>
                            <lsb>0</lsb>
                            <msb>15</msb>
                            <access>write-only</access>
                        </field>
                        <field>
                            <name>PERFTRIGGER2</name>
                            <description>Trigger of Performance Counter 2</description>
                            <lsb>16</lsb>
                            <msb>31</msb>
                            <access>write-only</access>
                        </field>
                    </fields>
                </register>
                <register>
                    <name>TEXCLADDR</name>
                    <description>CLUT Start Address Register</description>
                    <addressOffset>0xDC</addressOffset>
                    <size>32</size>
                    <access>write-only</access>
                    <resetValue>0x00000000</resetValue>
                    <resetMask>0xffffffff</resetMask>
                    <fields>
                        <field>
                            <name>CLADDR</name>
                            <description>Texture CLUT Start Address</description>
                            <lsb>0</lsb>
                            <msb>7</msb>
                            <access>write-only</access>
                        </field>
                    </fields>
                </register>
                <register>
                    <name>TEXCLDATA</name>
                    <description>CLUT Data Register</description>
                    <addressOffset>0xE0</addressOffset>
                    <size>32</size>
                    <access>write-only</access>
                    <resetValue>0x00000000</resetValue>
                    <resetMask>0xffffffff</resetMask>
                    <fields>
                        <field>
                            <name>CLDATA</name>
                            <description>Texture CLUT Data</description>
                            <lsb>0</lsb>
                            <msb>31</msb>
                            <access>write-only</access>
                        </field>
                    </fields>
                </register>
                <register>
                    <name>TEXCLOFFSET</name>
                    <description>CLUT Offset Register</description>
                    <addressOffset>0xE4</addressOffset>
                    <size>32</size>
                    <access>write-only</access>
                    <resetValue>0x00000000</resetValue>
                    <resetMask>0xffffffff</resetMask>
                    <fields>
                        <field>
                            <name>CLOFFSET</name>
                            <description>Texture CLUT Offset</description>
                            <lsb>0</lsb>
                            <msb>7</msb>
                            <access>write-only</access>
                        </field>
                    </fields>
                </register>
                <register>
                    <name>COLKEY</name>
                    <description>Color Key Register</description>
                    <addressOffset>0xE8</addressOffset>
                    <size>32</size>
                    <access>write-only</access>
                    <resetValue>0x00000000</resetValue>
                    <resetMask>0xffffffff</resetMask>
                    <fields>
                        <field>
                            <name>COLKEYB</name>
                            <description>Blue Channel of Color Key</description>
                            <lsb>0</lsb>
                            <msb>7</msb>
                            <access>write-only</access>
                        </field>
                        <field>
                            <name>COLKEYG</name>
                            <description>Green Channel of Color Key</description>
                            <lsb>8</lsb>
                            <msb>15</msb>
                            <access>write-only</access>
                        </field>
                        <field>
                            <name>COLKEYR</name>
                            <description>Red Channel of Color Key</description>
                            <lsb>16</lsb>
                            <msb>23</msb>
                            <access>write-only</access>
                        </field>
                    </fields>
                </register>
            </registers>
        </peripheral>
        <peripheral>
            <name>SCI0_B</name>
            <description>Serial Communication Interface 0</description>
            <baseAddress>0x40358000</baseAddress>
            <addressBlock>
                <offset>0x00</offset>
                <size>4</size>
                <usage>registers</usage>
            </addressBlock>
            <addressBlock>
                <offset>0x04</offset>
                <size>4</size>
                <usage>registers</usage>
            </addressBlock>
            <addressBlock>
                <offset>0x08</offset>
                <size>21</size>
                <usage>registers</usage>
            </addressBlock>
            <addressBlock>
                <offset>0x20</offset>
                <size>8</size>
                <usage>registers</usage>
            </addressBlock>
            <addressBlock>
                <offset>0x2C</offset>
                <size>20</size>
                <usage>registers</usage>
            </addressBlock>
            <addressBlock>
                <offset>0x48</offset>
                <size>28</size>
                <usage>registers</usage>
            </addressBlock>
            <addressBlock>
                <offset>0x68</offset>
                <size>20</size>
                <usage>registers</usage>
            </addressBlock>
            <registers>
                <register>
                    <name>RDR</name>
                    <description>Receive Data Register</description>
                    <addressOffset>0x00</addressOffset>
                    <size>32</size>
                    <access>read-only</access>
                    <resetValue>0x00000000</resetValue>
                    <resetMask>0xffffffff</resetMask>
                    <fields>
                        <field>
                            <name>RDAT</name>
                            <description>Serial receive data</description>
                            <lsb>0</lsb>
                            <msb>8</msb>
                            <access>read-only</access>
                        </field>
                        <field>
                            <name>MPB</name>
                            <description>Multi-processor flag</description>
                            <lsb>9</lsb>
                            <msb>9</msb>
                            <access>read-only</access>
                            <enumeratedValues>
                                <enumeratedValue>
                                    <name>0</name>
                                    <description>Data transmission cycles</description>
                                    <value>#0</value>
                                </enumeratedValue>
                                <enumeratedValue>
                                    <name>1</name>
                                    <description>ID transmission cycles</description>
                                    <value>#1</value>
                                </enumeratedValue>
                            </enumeratedValues>
                        </field>
                        <field>
                            <name>DR</name>
                            <description>Receive data ready flag</description>
                            <lsb>10</lsb>
                            <msb>10</msb>
                            <access>read-only</access>
                        </field>
                        <field>
                            <name>FPER</name>
                            <description>FIFO parity error flag</description>
                            <lsb>11</lsb>
                            <msb>11</msb>
                            <access>read-only</access>
                            <enumeratedValues>
                                <enumeratedValue>
                                    <name>0</name>
                                    <description>There is no parity error in the data read from the receive-FIFO</description>
                                    <value>#0</value>
                                </enumeratedValue>
                                <enumeratedValue>
                                    <name>1</name>
                                    <description>There is parity error in the data read from the receive-FIFO</description>
                                    <value>#1</value>
                                </enumeratedValue>
                            </enumeratedValues>
                        </field>
                        <field>
                            <name>FFER</name>
                            <description>FIFO framing error flag</description>
                            <lsb>12</lsb>
                            <msb>12</msb>
                            <access>read-only</access>
                            <enumeratedValues>
                                <enumeratedValue>
                                    <name>0</name>
                                    <description>There is no framing error in the data read from the receive-FIFO</description>
                                    <value>#0</value>
                                </enumeratedValue>
                                <enumeratedValue>
                                    <name>1</name>
                                    <description>There is framing error in the data read from the receive-FIFO</description>
                                    <value>#1</value>
                                </enumeratedValue>
                            </enumeratedValues>
                        </field>
                        <field>
                            <name>ORER</name>
                            <description>Overrun Error flag</description>
                            <lsb>24</lsb>
                            <msb>24</msb>
                            <access>read-only</access>
                        </field>
                        <field>
                            <name>PER</name>
                            <description>Parity error flag</description>
                            <lsb>27</lsb>
                            <msb>27</msb>
                            <access>read-only</access>
                        </field>
                        <field>
                            <name>FER</name>
                            <description>Framing error flag</description>
                            <lsb>28</lsb>
                            <msb>28</msb>
                            <access>read-only</access>
                        </field>
                    </fields>
                </register>
                <register>
                    <name>RDR_BY</name>
                    <description>Receive Data Register</description>
                    <alternateRegister>RDR</alternateRegister>
                    <addressOffset>0x00</addressOffset>
                    <size>8</size>
                    <access>read-only</access>
                    <resetValue>0x00</resetValue>
                    <resetMask>0xff</resetMask>
                    <fields>
                        <field>
                            <name>ORER</name>
                            <description>Overrun Error flag</description>
                            <lsb>0</lsb>
                            <msb>0</msb>
                            <access>read-only</access>
                        </field>
                        <field>
                            <name>PER</name>
                            <description>Parity error flag</description>
                            <lsb>3</lsb>
                            <msb>3</msb>
                            <access>read-only</access>
                        </field>
                        <field>
                            <name>FER</name>
                            <description>Framing error flag</description>
                            <lsb>4</lsb>
                            <msb>4</msb>
                            <access>read-only</access>
                        </field>
                    </fields>
                </register>
                <register>
                    <name>TDR</name>
                    <description>Transmit Data Register</description>
                    <addressOffset>0x04</addressOffset>
                    <size>32</size>
                    <access>read-write</access>
                    <resetValue>0xffffffff</resetValue>
                    <resetMask>0xffffffff</resetMask>
                    <fields>
                        <field>
                            <name>TDAT</name>
                            <description>Serial transmit data</description>
                            <lsb>0</lsb>
                            <msb>8</msb>
                            <access>read-write</access>
                        </field>
                        <field>
                            <name>MPBT</name>
                            <description>Multi-processor transfer bit flag</description>
                            <lsb>9</lsb>
                            <msb>9</msb>
                            <access>read-write</access>
                            <enumeratedValues>
                                <enumeratedValue>
                                    <name>0</name>
                                    <description>Data transmission cycles</description>
                                    <value>#0</value>
                                </enumeratedValue>
                                <enumeratedValue>
                                    <name>1</name>
                                    <description>ID transmission cycles</description>
                                    <value>#1</value>
                                </enumeratedValue>
                            </enumeratedValues>
                        </field>
                        <field>
                            <name>TSYNC</name>
                            <description>Transmit SYNC data</description>
                            <lsb>12</lsb>
                            <msb>12</msb>
                            <access>read-write</access>
                            <enumeratedValues>
                                <enumeratedValue>
                                    <name>0</name>
                                    <description>The Start Bit is transmitted as DATA SYNC.</description>
                                    <value>#0</value>
                                </enumeratedValue>
                                <enumeratedValue>
                                    <name>1</name>
                                    <description>The Start Bit is transmitted as COMMAND SYNC.</description>
                                    <value>#1</value>
                                </enumeratedValue>
                            </enumeratedValues>
                        </field>
                    </fields>
                </register>
                <register>
                    <name>TDRLL</name>
                    <description>Transmit Data Register</description>
                    <alternateRegister>TDR</alternateRegister>
                    <addressOffset>0x04</addressOffset>
                    <size>16</size>
                    <access>read-write</access>
                    <resetValue>0xffff</resetValue>
                    <resetMask>0xffff</resetMask>
                </register>
                <register>
                    <name>TDRLH</name>
                    <description>Transmit Data Register</description>
                    <alternateRegister>TDR</alternateRegister>
                    <addressOffset>0x05</addressOffset>
                    <size>16</size>
                    <access>read-write</access>
                    <resetValue>0xffff</resetValue>
                    <resetMask>0xffff</resetMask>
                    <fields>
                        <field>
                            <name>TDAT</name>
                            <description>Serial transmit data</description>
                            <lsb>0</lsb>
                            <msb>0</msb>
                            <access>read-write</access>
                        </field>
                        <field>
                            <name>MPBT</name>
                            <description>Multi-processor transfer bit flag</description>
                            <lsb>1</lsb>
                            <msb>1</msb>
                            <access>read-write</access>
                            <enumeratedValues>
                                <enumeratedValue>
                                    <name>0</name>
                                    <description>Data transmission cycles</description>
                                    <value>#0</value>
                                </enumeratedValue>
                                <enumeratedValue>
                                    <name>1</name>
                                    <description>ID transmission cycles</description>
                                    <value>#1</value>
                                </enumeratedValue>
                            </enumeratedValues>
                        </field>
                        <field>
                            <name>TSYNC</name>
                            <description>Transmit SYNC data</description>
                            <lsb>4</lsb>
                            <msb>4</msb>
                            <access>read-write</access>
                            <enumeratedValues>
                                <enumeratedValue>
                                    <name>0</name>
                                    <description>The Start Bit is transmitted as DATA SYNC.</description>
                                    <value>#0</value>
                                </enumeratedValue>
                                <enumeratedValue>
                                    <name>1</name>
                                    <description>The Start Bit is transmitted as COMMAND SYNC.</description>
                                    <value>#1</value>
                                </enumeratedValue>
                            </enumeratedValues>
                        </field>
                    </fields>
                </register>
                <register>
                    <name>CCR0</name>
                    <description>Common Control Register 0</description>
                    <addressOffset>0x08</addressOffset>
                    <size>32</size>
                    <access>read-write</access>
                    <resetValue>0x00000000</resetValue>
                    <resetMask>0xffffffff</resetMask>
                    <fields>
                        <field>
                            <name>RE</name>
                            <description>Receive Enable</description>
                            <lsb>0</lsb>
                            <msb>0</msb>
                            <access>read-write</access>
                            <enumeratedValues>
                                <enumeratedValue>
                                    <name>0</name>
                                    <description>Serial reception is disabled</description>
                                    <value>#0</value>
                                </enumeratedValue>
                                <enumeratedValue>
                                    <name>1</name>
                                    <description>Serial reception is enabled</description>
                                    <value>#1</value>
                                </enumeratedValue>
                            </enumeratedValues>
                        </field>
                        <field>
                            <name>TE</name>
                            <description>Transmit Enable</description>
                            <lsb>4</lsb>
                            <msb>4</msb>
                            <access>read-write</access>
                            <enumeratedValues>
                                <enumeratedValue>
                                    <name>0</name>
                                    <description>Serial transmission is disabled</description>
                                    <value>#0</value>
                                </enumeratedValue>
                                <enumeratedValue>
                                    <name>1</name>
                                    <description>Serial transmission is enabled</description>
                                    <value>#1</value>
                                </enumeratedValue>
                            </enumeratedValues>
                        </field>
                        <field>
                            <name>MPIE</name>
                            <description>Multi-Processor Interrupt Enable</description>
                            <lsb>8</lsb>
                            <msb>8</msb>
                            <access>read-write</access>
                            <enumeratedValues>
                                <enumeratedValue>
                                    <name>0</name>
                                    <description>Non-multi-processor reception</description>
                                    <value>#0</value>
                                </enumeratedValue>
                                <enumeratedValue>
                                    <name>1</name>
                                    <description>Multi-processor reception When the data with the multi-processor bit set to 0 is received, the data is not read, and setting the status flags to 1 is disabled. When the data with the multi-processor bit set to 1 is received, the MPIE bit is automatically cleared to 0, and non-multi-processor reception is resumed. If you want to continue receiving operation using the multiprocessor function, set this bit to 1 sufficiently earlier than receiving the STOP bit of the next received frame (consider the synchronization delay time). </description>
                                    <value>#1</value>
                                </enumeratedValue>
                            </enumeratedValues>
                        </field>
                        <field>
                            <name>DCME</name>
                            <description>Data Compare Match Enable</description>
                            <lsb>9</lsb>
                            <msb>9</msb>
                            <access>read-write</access>
                            <enumeratedValues>
                                <enumeratedValue>
                                    <name>0</name>
                                    <description>Address match function is disabled</description>
                                    <value>#0</value>
                                </enumeratedValue>
                                <enumeratedValue>
                                    <name>1</name>
                                    <description>Address match function is enabled</description>
                                    <value>#1</value>
                                </enumeratedValue>
                            </enumeratedValues>
                        </field>
                        <field>
                            <name>IDSEL</name>
                            <description>ID Frame Select</description>
                            <lsb>10</lsb>
                            <msb>10</msb>
                            <access>read-write</access>
                            <enumeratedValues>
                                <enumeratedValue>
                                    <name>0</name>
                                    <description>Compare data irrespective of the value of the MPB bit</description>
                                    <value>#0</value>
                                </enumeratedValue>
                                <enumeratedValue>
                                    <name>1</name>
                                    <description>Compare data only when the MPB bit is 1 (ID frame)</description>
                                    <value>#1</value>
                                </enumeratedValue>
                            </enumeratedValues>
                        </field>
                        <field>
                            <name>RIE</name>
                            <description>Receive Interrupt Enable</description>
                            <lsb>16</lsb>
                            <msb>16</msb>
                            <access>read-write</access>
                            <enumeratedValues>
                                <enumeratedValue>
                                    <name>0</name>
                                    <description>SCIn_RXI and SCIn_ERI interrupt requests are disabled</description>
                                    <value>#0</value>
                                </enumeratedValue>
                                <enumeratedValue>
                                    <name>1</name>
                                    <description>SCIn_RXI and SCIn_ERI interrupt requests are enabled</description>
                                    <value>#1</value>
                                </enumeratedValue>
                            </enumeratedValues>
                        </field>
                        <field>
                            <name>TIE</name>
                            <description>Transmit Interrupt Enable</description>
                            <lsb>20</lsb>
                            <msb>20</msb>
                            <access>read-write</access>
                            <enumeratedValues>
                                <enumeratedValue>
                                    <name>0</name>
                                    <description>SCIn_TXI interrupt request is disabled</description>
                                    <value>#0</value>
                                </enumeratedValue>
                                <enumeratedValue>
                                    <name>1</name>
                                    <description>SCIn_TXI interrupt request is enabled</description>
                                    <value>#1</value>
                                </enumeratedValue>
                            </enumeratedValues>
                        </field>
                        <field>
                            <name>TEIE</name>
                            <description>Transmit End Interrupt Enable</description>
                            <lsb>21</lsb>
                            <msb>21</msb>
                            <access>read-write</access>
                            <enumeratedValues>
                                <enumeratedValue>
                                    <name>0</name>
                                    <description>SCIn_TEI interrupt request is disabled</description>
                                    <value>#0</value>
                                </enumeratedValue>
                                <enumeratedValue>
                                    <name>1</name>
                                    <description>SCIn_TEI interrupt request is enabled</description>
                                    <value>#1</value>
                                </enumeratedValue>
                            </enumeratedValues>
                        </field>
                        <field>
                            <name>SSE</name>
                            <description>SSn Pin Function Enable</description>
                            <lsb>24</lsb>
                            <msb>24</msb>
                            <access>read-write</access>
                            <enumeratedValues>
                                <enumeratedValue>
                                    <name>0</name>
                                    <description>SSn pin function is disabled</description>
                                    <value>#0</value>
                                </enumeratedValue>
                                <enumeratedValue>
                                    <name>1</name>
                                    <description>SSn pin function is enabled</description>
                                    <value>#1</value>
                                </enumeratedValue>
                            </enumeratedValues>
                        </field>
                    </fields>
                </register>
                <register>
                    <name>CCR1</name>
                    <description>Common Control Register 1</description>
                    <addressOffset>0x0C</addressOffset>
                    <size>32</size>
                    <access>read-write</access>
                    <resetValue>0x00000010</resetValue>
                    <resetMask>0xffffffff</resetMask>
                    <fields>
                        <field>
                            <name>CTSE</name>
                            <description>CTS Enable</description>
                            <lsb>0</lsb>
                            <msb>0</msb>
                            <access>read-write</access>
                            <enumeratedValues>
                                <enumeratedValue>
                                    <name>0</name>
                                    <description>CTS function is disabled (RTS output function is enabled)</description>
                                    <value>#0</value>
                                </enumeratedValue>
                                <enumeratedValue>
                                    <name>1</name>
                                    <description>CTS function is enabled</description>
                                    <value>#1</value>
                                </enumeratedValue>
                            </enumeratedValues>
                        </field>
                        <field>
                            <name>CTSPEN</name>
                            <description>CTS External Pin Enable</description>
                            <lsb>1</lsb>
                            <msb>1</msb>
                            <access>read-write</access>
                            <enumeratedValues>
                                <enumeratedValue>
                                    <name>0</name>
                                    <description>Alternate setting to use CTS and RTS functions as either 1 pin</description>
                                    <value>#0</value>
                                </enumeratedValue>
                                <enumeratedValue>
                                    <name>1</name>
                                    <description>Dedicated setting for separately using CTS and RTS functions with 2 pins</description>
                                    <value>#1</value>
                                </enumeratedValue>
                            </enumeratedValues>
                        </field>
                        <field>
                            <name>SPB2DT</name>
                            <description>Serial Port Break Data Select</description>
                            <lsb>4</lsb>
                            <msb>4</msb>
                            <access>read-write</access>
                            <enumeratedValues>
                                <enumeratedValue>
                                    <name>0</name>
                                    <description>When TINV is 0, low level is output in TXDn pin. When TINV is 1, high level is output in TXDn pin. </description>
                                    <value>#0</value>
                                </enumeratedValue>
                                <enumeratedValue>
                                    <name>1</name>
                                    <description>When TINV is 0, high level is output in TXDn pin. When TINV is 1, low level is output in TXDn pin. </description>
                                    <value>#1</value>
                                </enumeratedValue>
                            </enumeratedValues>
                        </field>
                        <field>
                            <name>SPB2IO</name>
                            <description>Serial Port Break I/O</description>
                            <lsb>5</lsb>
                            <msb>5</msb>
                            <access>read-write</access>
                            <enumeratedValues>
                                <enumeratedValue>
                                    <name>0</name>
                                    <description>The value of SPB2DT bit is not output in TXDn pin</description>
                                    <value>#0</value>
                                </enumeratedValue>
                                <enumeratedValue>
                                    <name>1</name>
                                    <description>The value of SPB2DT bit is output in TXDn pin</description>
                                    <value>#1</value>
                                </enumeratedValue>
                            </enumeratedValues>
                        </field>
                        <field>
                            <name>PE</name>
                            <description>Parity Enable</description>
                            <lsb>8</lsb>
                            <msb>8</msb>
                            <access>read-write</access>
                            <enumeratedValues>
                                <enumeratedValue>
                                    <name>0</name>
                                    <description>When transmitting: Do not add parity bit When receiving: Do not check parity bit </description>
                                    <value>#0</value>
                                </enumeratedValue>
                                <enumeratedValue>
                                    <name>1</name>
                                    <description>When transmitting: Add parity bit When receiving: Check parity bit </description>
                                    <value>#1</value>
                                </enumeratedValue>
                            </enumeratedValues>
                        </field>
                        <field>
                            <name>PM</name>
                            <description>Parity Mode</description>
                            <lsb>9</lsb>
                            <msb>9</msb>
                            <access>read-write</access>
                            <enumeratedValues>
                                <enumeratedValue>
                                    <name>0</name>
                                    <description>Selects even parity</description>
                                    <value>#0</value>
                                </enumeratedValue>
                                <enumeratedValue>
                                    <name>1</name>
                                    <description>Selects odd parity</description>
                                    <value>#1</value>
                                </enumeratedValue>
                            </enumeratedValues>
                        </field>
                        <field>
                            <name>TINV</name>
                            <description>TXD Invert</description>
                            <lsb>12</lsb>
                            <msb>12</msb>
                            <access>read-write</access>
                            <enumeratedValues>
                                <enumeratedValue>
                                    <name>0</name>
                                    <description>Transmit data is not inverted and output to TXDn</description>
                                    <value>#0</value>
                                </enumeratedValue>
                                <enumeratedValue>
                                    <name>1</name>
                                    <description>Transmit data is inverted and output to TXDn</description>
                                    <value>#1</value>
                                </enumeratedValue>
                            </enumeratedValues>
                        </field>
                        <field>
                            <name>RINV</name>
                            <description>RXD Invert</description>
                            <lsb>13</lsb>
                            <msb>13</msb>
                            <access>read-write</access>
                            <enumeratedValues>
                                <enumeratedValue>
                                    <name>0</name>
                                    <description>Received data from RXDn is not inverted and input</description>
                                    <value>#0</value>
                                </enumeratedValue>
                                <enumeratedValue>
                                    <name>1</name>
                                    <description>Received data from RXDn is inverted and input</description>
                                    <value>#1</value>
                                </enumeratedValue>
                            </enumeratedValues>
                        </field>
                        <field>
                            <name>SPLP</name>
                            <description>Loopback Control</description>
                            <lsb>16</lsb>
                            <msb>16</msb>
                            <access>read-write</access>
                            <enumeratedValues>
                                <enumeratedValue>
                                    <name>0</name>
                                    <description>Normal mode</description>
                                    <value>#0</value>
                                </enumeratedValue>
                                <enumeratedValue>
                                    <name>1</name>
                                    <description>Loopback mode</description>
                                    <value>#1</value>
                                </enumeratedValue>
                            </enumeratedValues>
                        </field>
                        <field>
                            <name>SHARPS</name>
                            <description>Half-Duplex Communication Select</description>
                            <lsb>20</lsb>
                            <msb>20</msb>
                            <access>read-write</access>
                            <enumeratedValues>
                                <enumeratedValue>
                                    <name>0</name>
                                    <description>TXDn pin, RXDn pin independent</description>
                                    <value>#0</value>
                                </enumeratedValue>
                                <enumeratedValue>
                                    <name>1</name>
                                    <description>TXDn/RXDn pin combination use (half-duplex communication using TXDn pin) </description>
                                    <value>#1</value>
                                </enumeratedValue>
                            </enumeratedValues>
                        </field>
                        <field>
                            <name>NFCS</name>
                            <description>Noise Filter Clock Select</description>
                            <lsb>24</lsb>
                            <msb>26</msb>
                            <access>read-write</access>
                            <enumeratedValues>
                                <enumeratedValue>
                                    <name>000</name>
                                    <description>The base clock signal divided by 1</description>
                                    <value>#000</value>
                                </enumeratedValue>
                                <enumeratedValue>
                                    <name>001</name>
                                    <description>The on-chip baud rate generator source clock divided by 1</description>
                                    <value>#001</value>
                                </enumeratedValue>
                                <enumeratedValue>
                                    <name>010</name>
                                    <description>The on-chip baud rate generator source clock divided by 2</description>
                                    <value>#010</value>
                                </enumeratedValue>
                                <enumeratedValue>
                                    <name>011</name>
                                    <description>The on-chip baud rate generator source clock divided by 4</description>
                                    <value>#011</value>
                                </enumeratedValue>
                                <enumeratedValue>
                                    <name>100</name>
                                    <description>The on-chip baud rate generator source clock divided by 8</description>
                                    <value>#100</value>
                                </enumeratedValue>
                                <enumeratedValue>
                                    <name>others</name>
                                    <description>Setting prohibited</description>
                                    <isDefault>true</isDefault>
                                </enumeratedValue>
                            </enumeratedValues>
                        </field>
                        <field>
                            <name>NFEN</name>
                            <description>Digital Noise Filter Function Enable</description>
                            <lsb>28</lsb>
                            <msb>28</msb>
                            <access>read-write</access>
                            <enumeratedValues>
                                <enumeratedValue>
                                    <name>0</name>
                                    <description>In Asynchronous, Manchester, Simple LIN modes: Disable noise cancellation function for RXDn input signal In Simple IIC mode: Disable noise cancellation function for SCLn and SDAn input signals </description>
                                    <value>#0</value>
                                </enumeratedValue>
                                <enumeratedValue>
                                    <name>1</name>
                                    <description>In Asynchronous, Manchester, Simple LIN modes: Enable noise cancellation function for RXDn input signal In Simple IIC mode: Enable noise cancellation function for SCLn and SDAn input signals </description>
                                    <value>#1</value>
                                </enumeratedValue>
                            </enumeratedValues>
                        </field>
                        <field>
                            <name>NFM</name>
                            <description>Noise Filter Mode</description>
                            <lsb>29</lsb>
                            <msb>29</msb>
                            <access>read-write</access>
                            <enumeratedValues>
                                <enumeratedValue>
                                    <name>0</name>
                                    <description>3-point matching mode</description>
                                    <value>#0</value>
                                </enumeratedValue>
                                <enumeratedValue>
                                    <name>1</name>
                                    <description>Majority vote mode</description>
                                    <value>#1</value>
                                </enumeratedValue>
                            </enumeratedValues>
                        </field>
                    </fields>
                </register>
                <register>
                    <name>CCR2</name>
                    <description>Common Control Register 2</description>
                    <addressOffset>0x10</addressOffset>
                    <size>32</size>
                    <access>read-write</access>
                    <resetValue>0xff00ff04</resetValue>
                    <resetMask>0xffffffff</resetMask>
                    <fields>
                        <field>
                            <name>BCP</name>
                            <description>Base Clock Pulse</description>
                            <lsb>0</lsb>
                            <msb>2</msb>
                            <access>read-write</access>
                            <enumeratedValues>
                                <enumeratedValue>
                                    <name>000</name>
                                    <description>93 clock cycles (S = 93)</description>
                                    <value>#000</value>
                                </enumeratedValue>
                                <enumeratedValue>
                                    <name>001</name>
                                    <description>128 clock cycles (S = 128)</description>
                                    <value>#001</value>
                                </enumeratedValue>
                                <enumeratedValue>
                                    <name>010</name>
                                    <description>186 clock cycles (S = 186)</description>
                                    <value>#010</value>
                                </enumeratedValue>
                                <enumeratedValue>
                                    <name>011</name>
                                    <description>512 clock cycles (S = 512)</description>
                                    <value>#011</value>
                                </enumeratedValue>
                                <enumeratedValue>
                                    <name>100</name>
                                    <description>32 clock cycles (S = 32) (Initial value)</description>
                                    <value>#100</value>
                                </enumeratedValue>
                                <enumeratedValue>
                                    <name>101</name>
                                    <description>64 clock cycles (S = 64)</description>
                                    <value>#101</value>
                                </enumeratedValue>
                                <enumeratedValue>
                                    <name>110</name>
                                    <description>372 clock cycles (S = 372)</description>
                                    <value>#110</value>
                                </enumeratedValue>
                                <enumeratedValue>
                                    <name>111</name>
                                    <description>256 clock cycles (S = 256)</description>
                                    <value>#111</value>
                                </enumeratedValue>
                            </enumeratedValues>
                        </field>
                        <field>
                            <name>BGDM</name>
                            <description>Baud Rate Generator Double-Speed Mode Select</description>
                            <lsb>4</lsb>
                            <msb>4</msb>
                            <access>read-write</access>
                            <enumeratedValues>
                                <enumeratedValue>
                                    <name>0</name>
                                    <description>Baud rate generator outputs the clock with single frequency</description>
                                    <value>#0</value>
                                </enumeratedValue>
                                <enumeratedValue>
                                    <name>1</name>
                                    <description>Baud rate generator outputs the clock with doubled frequency</description>
                                    <value>#1</value>
                                </enumeratedValue>
                            </enumeratedValues>
                        </field>
                        <field>
                            <name>ABCS</name>
                            <description>Asynchronous Mode Base Clock Select</description>
                            <lsb>5</lsb>
                            <msb>5</msb>
                            <access>read-write</access>
                            <enumeratedValues>
                                <enumeratedValue>
                                    <name>0</name>
                                    <description>Selects 16 base clock cycles for 1-bit period</description>
                                    <value>#0</value>
                                </enumeratedValue>
                                <enumeratedValue>
                                    <name>1</name>
                                    <description>Selects 8 base clock cycles for 1-bit period</description>
                                    <value>#1</value>
                                </enumeratedValue>
                            </enumeratedValues>
                        </field>
                        <field>
                            <name>ABCSE</name>
                            <description>Asynchronous Mode Extended Base Clock Select</description>
                            <lsb>6</lsb>
                            <msb>6</msb>
                            <access>read-write</access>
                            <enumeratedValues>
                                <enumeratedValue>
                                    <name>0</name>
                                    <description>Clock cycles for 1-bit period is determined by combination between CCR2.BGDM and CCR2.ABCS.</description>
                                    <value>#0</value>
                                </enumeratedValue>
                                <enumeratedValue>
                                    <name>1</name>
                                    <description>Baud rate is 6 base clock cycles for 1-bit period and the clock of a double frequency is output from the baud rate generator.</description>
                                    <value>#1</value>
                                </enumeratedValue>
                            </enumeratedValues>
                        </field>
                        <field>
                            <name>ABCSE2</name>
                            <description>Asynchronous Mode Extended Base Clock Select 2</description>
                            <lsb>7</lsb>
                            <msb>7</msb>
                            <access>read-write</access>
                            <enumeratedValues>
                                <enumeratedValue>
                                    <name>0</name>
                                    <description>Clock cycles for 1-bit period is decided with combination between CCR2.BGDM and CCR2.ABCS.</description>
                                    <value>#0</value>
                                </enumeratedValue>
                                <enumeratedValue>
                                    <name>1</name>
                                    <description>Baud rate is 4 base clock cycles for 1-bit period and the clock of a double frequency is output from the baud rate generator.</description>
                                    <value>#1</value>
                                </enumeratedValue>
                            </enumeratedValues>
                        </field>
                        <field>
                            <name>BRR</name>
                            <description>Bit Rate Setting</description>
                            <lsb>8</lsb>
                            <msb>15</msb>
                            <access>read-write</access>
                        </field>
                        <field>
                            <name>BRME</name>
                            <description>Bit Rate Modulation Enable</description>
                            <lsb>16</lsb>
                            <msb>16</msb>
                            <access>read-write</access>
                            <enumeratedValues>
                                <enumeratedValue>
                                    <name>0</name>
                                    <description>Bit rate modulation function is disabled</description>
                                    <value>#0</value>
                                </enumeratedValue>
                                <enumeratedValue>
                                    <name>1</name>
                                    <description>Bit rate modulation function is enabled</description>
                                    <value>#1</value>
                                </enumeratedValue>
                            </enumeratedValues>
                        </field>
                        <field>
                            <name>CKS</name>
                            <description>Clock Select</description>
                            <lsb>20</lsb>
                            <msb>21</msb>
                            <access>read-write</access>
                            <enumeratedValues>
                                <enumeratedValue>
                                    <name>00</name>
                                    <description>TCLK clock (n = 0)</description>
                                    <value>#00</value>
                                </enumeratedValue>
                                <enumeratedValue>
                                    <name>01</name>
                                    <description>TCLK/4 clock (n = 1)</description>
                                    <value>#01</value>
                                </enumeratedValue>
                                <enumeratedValue>
                                    <name>10</name>
                                    <description>TCLK/16 clock (n = 2)</description>
                                    <value>#10</value>
                                </enumeratedValue>
                                <enumeratedValue>
                                    <name>11</name>
                                    <description>TCLK/64 clock (n = 3)</description>
                                    <value>#11</value>
                                </enumeratedValue>
                            </enumeratedValues>
                        </field>
                        <field>
                            <name>MDDR</name>
                            <description>Modulation Duty Setting</description>
                            <lsb>24</lsb>
                            <msb>31</msb>
                            <access>read-write</access>
                        </field>
                    </fields>
                </register>
                <register>
                    <name>CCR3</name>
                    <description>Common Control Register 3</description>
                    <addressOffset>0x14</addressOffset>
                    <size>32</size>
                    <access>read-write</access>
                    <resetValue>0x00001203</resetValue>
                    <resetMask>0xffffffff</resetMask>
                    <fields>
                        <field>
                            <name>CPHA</name>
                            <description>Clock Phase Select</description>
                            <lsb>0</lsb>
                            <msb>0</msb>
                            <access>read-write</access>
                            <enumeratedValues>
                                <enumeratedValue>
                                    <name>0</name>
                                    <description>Data is sampled at an odd edge and changes at an even edge (clock is delayed)</description>
                                    <value>#0</value>
                                </enumeratedValue>
                                <enumeratedValue>
                                    <name>1</name>
                                    <description>Data changes at an odd edge and is sampled at an even edge (clock is not delayed)</description>
                                    <value>#1</value>
                                </enumeratedValue>
                            </enumeratedValues>
                        </field>
                        <field>
                            <name>CPOL</name>
                            <description>Clock Polarity Select</description>
                            <lsb>1</lsb>
                            <msb>1</msb>
                            <access>read-write</access>
                            <enumeratedValues>
                                <enumeratedValue>
                                    <name>0</name>
                                    <description>SCKn in idle state is 0</description>
                                    <value>#0</value>
                                </enumeratedValue>
                                <enumeratedValue>
                                    <name>1</name>
                                    <description>SCKn in idle state is 1</description>
                                    <value>#1</value>
                                </enumeratedValue>
                            </enumeratedValues>
                        </field>
                        <field>
                            <name>BPEN</name>
                            <description>Synchronizer Bypass Enable</description>
                            <lsb>7</lsb>
                            <msb>7</msb>
                            <access>read-write</access>
                            <enumeratedValues>
                                <enumeratedValue>
                                    <name>0</name>
                                    <description>Synchronizer circuit is not bypassed</description>
                                    <value>#0</value>
                                </enumeratedValue>
                                <enumeratedValue>
                                    <name>1</name>
                                    <description>Synchronizer circuit is bypassed</description>
                                    <value>#1</value>
                                </enumeratedValue>
                            </enumeratedValues>
                        </field>
                        <field>
                            <name>CHR</name>
                            <description>Character Length</description>
                            <lsb>8</lsb>
                            <msb>9</msb>
                            <access>read-write</access>
                            <enumeratedValues>
                                <enumeratedValue>
                                    <name>00</name>
                                    <description>Transmit/receive in 9-bit data length</description>
                                    <value>#00</value>
                                </enumeratedValue>
                                <enumeratedValue>
                                    <name>01</name>
                                    <description>Transmit/receive in 9-bit data length</description>
                                    <value>#01</value>
                                </enumeratedValue>
                                <enumeratedValue>
                                    <name>10</name>
                                    <description>Transmit/receive in 8-bit data length (initial value)</description>
                                    <value>#10</value>
                                </enumeratedValue>
                                <enumeratedValue>
                                    <name>11</name>
                                    <description>Transmit/receive in 7-bit data length</description>
                                    <value>#11</value>
                                </enumeratedValue>
                            </enumeratedValues>
                        </field>
                        <field>
                            <name>LSBF</name>
                            <description>LSB First select</description>
                            <lsb>12</lsb>
                            <msb>12</msb>
                            <access>read-write</access>
                            <enumeratedValues>
                                <enumeratedValue>
                                    <name>0</name>
                                    <description>MSB-first</description>
                                    <value>#0</value>
                                </enumeratedValue>
                                <enumeratedValue>
                                    <name>1</name>
                                    <description>LSB-first</description>
                                    <value>#1</value>
                                </enumeratedValue>
                            </enumeratedValues>
                        </field>
                        <field>
                            <name>SINV</name>
                            <description>Transmitted/Received Data Invert</description>
                            <lsb>13</lsb>
                            <msb>13</msb>
                            <access>read-write</access>
                            <enumeratedValues>
                                <enumeratedValue>
                                    <name>0</name>
                                    <description>TDR contents are transmitted to TSR as is. RSR contents are stored to RDR as is. </description>
                                    <value>#0</value>
                                </enumeratedValue>
                                <enumeratedValue>
                                    <name>1</name>
                                    <description>TDR contents are inverted before being transmitted to TSR. RSR contents are inverted and stored to RDR. </description>
                                    <value>#1</value>
                                </enumeratedValue>
                            </enumeratedValues>
                        </field>
                        <field>
                            <name>STP</name>
                            <description>Stop Bit Length</description>
                            <lsb>14</lsb>
                            <msb>14</msb>
                            <access>read-write</access>
                            <enumeratedValues>
                                <enumeratedValue>
                                    <name>0</name>
                                    <description>1 stop bit/break delimiter length is 1-bit</description>
                                    <value>#0</value>
                                </enumeratedValue>
                                <enumeratedValue>
                                    <name>1</name>
                                    <description>2 stop bits/break delimiter length is 2-bit</description>
                                    <value>#1</value>
                                </enumeratedValue>
                            </enumeratedValues>
                        </field>
                        <field>
                            <name>RXDESEL</name>
                            <description>Asynchronous Start Bit Edge Detection Select</description>
                            <lsb>15</lsb>
                            <msb>15</msb>
                            <access>read-write</access>
                            <enumeratedValues>
                                <enumeratedValue>
                                    <name>0</name>
                                    <description>The low level on the RXDn pin is detected as the start bit</description>
                                    <value>#0</value>
                                </enumeratedValue>
                                <enumeratedValue>
                                    <name>1</name>
                                    <description>A falling edge on the RXDn pin is detected as the start bit</description>
                                    <value>#1</value>
                                </enumeratedValue>
                            </enumeratedValues>
                        </field>
                        <field>
                            <name>MOD</name>
                            <description>Communication Mode Select</description>
                            <lsb>16</lsb>
                            <msb>18</msb>
                            <access>read-write</access>
                            <enumeratedValues>
                                <enumeratedValue>
                                    <name>000</name>
                                    <description>Asynchronous mode (multi-processor mode)</description>
                                    <value>#000</value>
                                </enumeratedValue>
                                <enumeratedValue>
                                    <name>001</name>
                                    <description>Smart card interface mode</description>
                                    <value>#001</value>
                                </enumeratedValue>
                                <enumeratedValue>
                                    <name>010</name>
                                    <description>Clock synchronous mode</description>
                                    <value>#010</value>
                                </enumeratedValue>
                                <enumeratedValue>
                                    <name>011</name>
                                    <description>Simple SPI mode</description>
                                    <value>#011</value>
                                </enumeratedValue>
                                <enumeratedValue>
                                    <name>100</name>
                                    <description>Simple IIC mode</description>
                                    <value>#100</value>
                                </enumeratedValue>
                                <enumeratedValue>
                                    <name>101</name>
                                    <description>Manchester mode</description>
                                    <value>#101</value>
                                </enumeratedValue>
                                <enumeratedValue>
                                    <name>110</name>
                                    <description>Simple LIN mode</description>
                                    <value>#110</value>
                                </enumeratedValue>
                                <enumeratedValue>
                                    <name>111</name>
                                    <description>Setting prohibited</description>
                                    <value>#111</value>
                                </enumeratedValue>
                            </enumeratedValues>
                        </field>
                        <field>
                            <name>MP</name>
                            <description>Multi-Processor Mode</description>
                            <lsb>19</lsb>
                            <msb>19</msb>
                            <access>read-write</access>
                            <enumeratedValues>
                                <enumeratedValue>
                                    <name>0</name>
                                    <description>Multi-processor communications function is disabled</description>
                                    <value>#0</value>
                                </enumeratedValue>
                                <enumeratedValue>
                                    <name>1</name>
                                    <description>Multi-processor communications function is enabled</description>
                                    <value>#1</value>
                                </enumeratedValue>
                            </enumeratedValues>
                        </field>
                        <field>
                            <name>FM</name>
                            <description>FIFO Mode Select</description>
                            <lsb>20</lsb>
                            <msb>20</msb>
                            <access>read-write</access>
                            <enumeratedValues>
                                <enumeratedValue>
                                    <name>0</name>
                                    <description>TDR register and RDR register are non-FIFO buffer configuration</description>
                                    <value>#0</value>
                                </enumeratedValue>
                                <enumeratedValue>
                                    <name>1</name>
                                    <description>TDR register and RDR register are FIFO buffer configuration</description>
                                    <value>#1</value>
                                </enumeratedValue>
                            </enumeratedValues>
                        </field>
                        <field>
                            <name>DEN</name>
                            <description>Driver Enable</description>
                            <lsb>21</lsb>
                            <msb>21</msb>
                            <access>read-write</access>
                            <enumeratedValues>
                                <enumeratedValue>
                                    <name>0</name>
                                    <description>RS-485 driver control function disabled</description>
                                    <value>#0</value>
                                </enumeratedValue>
                                <enumeratedValue>
                                    <name>1</name>
                                    <description>RS-485 driver control function enabled</description>
                                    <value>#1</value>
                                </enumeratedValue>
                            </enumeratedValues>
                        </field>
                        <field>
                            <name>CKE</name>
                            <description>Clock Enable</description>
                            <lsb>24</lsb>
                            <msb>25</msb>
                            <access>read-write</access>
                        </field>
                        <field>
                            <name>ACS0</name>
                            <description>Asynchronous Mode Clock Source Select</description>
                            <lsb>26</lsb>
                            <msb>26</msb>
                            <access>read-write</access>
                            <enumeratedValues>
                                <enumeratedValue>
                                    <name>0</name>
                                    <description>External clock input</description>
                                    <value>#0</value>
                                </enumeratedValue>
                                <enumeratedValue>
                                    <name>1</name>
                                    <description>Logical AND of compare matches output from the internal GPT</description>
                                    <value>#1</value>
                                </enumeratedValue>
                            </enumeratedValues>
                        </field>
                        <field>
                            <name>GM</name>
                            <description>GSM Mode</description>
                            <lsb>28</lsb>
                            <msb>28</msb>
                            <access>read-write</access>
                            <enumeratedValues>
                                <enumeratedValue>
                                    <name>0</name>
                                    <description>Non-GSM mode operation</description>
                                    <value>#0</value>
                                </enumeratedValue>
                                <enumeratedValue>
                                    <name>1</name>
                                    <description>GSM mode operation</description>
                                    <value>#1</value>
                                </enumeratedValue>
                            </enumeratedValues>
                        </field>
                        <field>
                            <name>BLK</name>
                            <description>Block Transfer Mode</description>
                            <lsb>29</lsb>
                            <msb>29</msb>
                            <access>read-write</access>
                            <enumeratedValues>
                                <enumeratedValue>
                                    <name>0</name>
                                    <description>Non-block transfer mode operation</description>
                                    <value>#0</value>
                                </enumeratedValue>
                                <enumeratedValue>
                                    <name>1</name>
                                    <description>Block transfer mode operation</description>
                                    <value>#1</value>
                                </enumeratedValue>
                            </enumeratedValues>
                        </field>
                    </fields>
                </register>
                <register>
                    <name>CCR4</name>
                    <description>Common Control Register 4</description>
                    <addressOffset>0x18</addressOffset>
                    <size>32</size>
                    <access>read-write</access>
                    <resetValue>0x00000000</resetValue>
                    <resetMask>0xffffffff</resetMask>
                    <fields>
                        <field>
                            <name>CMPD</name>
                            <description>Compare Match Data</description>
                            <lsb>0</lsb>
                            <msb>8</msb>
                            <access>read-write</access>
                        </field>
                        <field>
                            <name>ASEN</name>
                            <description>Adjust Receive Sampling Timing Enable</description>
                            <lsb>16</lsb>
                            <msb>16</msb>
                            <access>read-write</access>
                            <enumeratedValues>
                                <enumeratedValue>
                                    <name>0</name>
                                    <description>Adjust sampling timing disabled</description>
                                    <value>#0</value>
                                </enumeratedValue>
                                <enumeratedValue>
                                    <name>1</name>
                                    <description>Adjust sampling timing enabled</description>
                                    <value>#1</value>
                                </enumeratedValue>
                            </enumeratedValues>
                        </field>
                        <field>
                            <name>ATEN</name>
                            <description>Adjust Transmit Timing Enable</description>
                            <lsb>17</lsb>
                            <msb>17</msb>
                            <access>read-write</access>
                            <enumeratedValues>
                                <enumeratedValue>
                                    <name>0</name>
                                    <description>Adjust transmit timing disabled</description>
                                    <value>#0</value>
                                </enumeratedValue>
                                <enumeratedValue>
                                    <name>1</name>
                                    <description>Adjust transmit timing enabled</description>
                                    <value>#1</value>
                                </enumeratedValue>
                            </enumeratedValues>
                        </field>
                        <field>
                            <name>SCKSEL</name>
                            <description>Master receive clock selection</description>
                            <lsb>19</lsb>
                            <msb>19</msb>
                            <access>read-write</access>
                            <enumeratedValues>
                                <enumeratedValue>
                                    <name>0</name>
                                    <description>Master receive clock is disabled</description>
                                    <value>#0</value>
                                </enumeratedValue>
                                <enumeratedValue>
                                    <name>1</name>
                                    <description>Master receive clock is enabled</description>
                                    <value>#1</value>
                                </enumeratedValue>
                            </enumeratedValues>
                        </field>
                        <field>
                            <name>AST</name>
                            <description>Adjustment Value for Receive Sampling Timing</description>
                            <lsb>24</lsb>
                            <msb>26</msb>
                            <access>read-write</access>
                            <enumeratedValues>
                                <enumeratedValue>
                                    <name>000</name>
                                    <description>1-TCLK delay</description>
                                    <value>#000</value>
                                </enumeratedValue>
                                <enumeratedValue>
                                    <name>001</name>
                                    <description>2-TCLK delay</description>
                                    <value>#001</value>
                                </enumeratedValue>
                                <enumeratedValue>
                                    <name>010</name>
                                    <description>3-TCLK delay</description>
                                    <value>#010</value>
                                </enumeratedValue>
                                <enumeratedValue>
                                    <name>011</name>
                                    <description>4-TCLK delay</description>
                                    <value>#011</value>
                                </enumeratedValue>
                                <enumeratedValue>
                                    <name>Others</name>
                                    <description>Setting prohibited</description>
                                    <isDefault>true</isDefault>
                                </enumeratedValue>
                            </enumeratedValues>
                        </field>
                        <field>
                            <name>AJD</name>
                            <description>Adjustment Direction for Receive Sampling Timing</description>
                            <lsb>27</lsb>
                            <msb>27</msb>
                            <access>read-write</access>
                            <enumeratedValues>
                                <enumeratedValue>
                                    <name>0</name>
                                    <description>The sampling timing is adjusted backward to the middle of bit.</description>
                                    <value>#0</value>
                                </enumeratedValue>
                                <enumeratedValue>
                                    <name>1</name>
                                    <description>The sampling timing is adjusted forward to the middle of bit.</description>
                                    <value>#1</value>
                                </enumeratedValue>
                            </enumeratedValues>
                        </field>
                        <field>
                            <name>ATT</name>
                            <description>Adjustment Value for Transmit Timing</description>
                            <lsb>28</lsb>
                            <msb>30</msb>
                            <access>read-write</access>
                        </field>
                        <field>
                            <name>AET</name>
                            <description>Adjustment Edge for Transmit Timing</description>
                            <lsb>31</lsb>
                            <msb>31</msb>
                            <access>read-write</access>
                            <enumeratedValues>
                                <enumeratedValue>
                                    <name>0</name>
                                    <description>When CCR1.TINV is 0, adjust the rising edge timing. When CCR1.TINV is 1, adjust the falling edge timing. </description>
                                    <value>#0</value>
                                </enumeratedValue>
                                <enumeratedValue>
                                    <name>1</name>
                                    <description>When CCR1.TINV is 0, adjust the falling edge timing. When CCR1.TINV is 1, adjust the rising edge timing. </description>
                                    <value>#1</value>
                                </enumeratedValue>
                            </enumeratedValues>
                        </field>
                    </fields>
                </register>
                <register>
                    <name>CESR</name>
                    <description>Communication Enable Status Register</description>
                    <addressOffset>0x1C</addressOffset>
                    <size>8</size>
                    <access>read-only</access>
                    <resetValue>0x00</resetValue>
                    <resetMask>0xff</resetMask>
                    <fields>
                        <field>
                            <name>RIST</name>
                            <description>RE Internal Status</description>
                            <lsb>0</lsb>
                            <msb>0</msb>
                            <access>read-only</access>
                            <enumeratedValues>
                                <enumeratedValue>
                                    <name>0</name>
                                    <description>RE signal internal state value 0</description>
                                    <value>#0</value>
                                </enumeratedValue>
                                <enumeratedValue>
                                    <name>1</name>
                                    <description>RE signal internal state value 1</description>
                                    <value>#1</value>
                                </enumeratedValue>
                            </enumeratedValues>
                        </field>
                        <field>
                            <name>TIST</name>
                            <description>TE Internal Status</description>
                            <lsb>4</lsb>
                            <msb>4</msb>
                            <access>read-only</access>
                            <enumeratedValues>
                                <enumeratedValue>
                                    <name>0</name>
                                    <description>TE signal internal state value 0</description>
                                    <value>#0</value>
                                </enumeratedValue>
                                <enumeratedValue>
                                    <name>1</name>
                                    <description>TE signal internal state value 1</description>
                                    <value>#1</value>
                                </enumeratedValue>
                            </enumeratedValues>
                        </field>
                    </fields>
                </register>
                <register>
                    <name>ICR</name>
                    <description>Simple IIC Control Register</description>
                    <addressOffset>0x20</addressOffset>
                    <size>32</size>
                    <access>read-write</access>
                    <resetValue>0x00000000</resetValue>
                    <resetMask>0xffffffff</resetMask>
                    <fields>
                        <field>
                            <name>IICDL</name>
                            <description>SDA Delay Output Select</description>
                            <lsb>0</lsb>
                            <msb>4</msb>
                            <access>read-write</access>
                        </field>
                        <field>
                            <name>IICINTM</name>
                            <description>IIC Interrupt Mode Select</description>
                            <lsb>8</lsb>
                            <msb>8</msb>
                            <access>read-write</access>
                            <enumeratedValues>
                                <enumeratedValue>
                                    <name>0</name>
                                    <description>Use ACK/NACK interrupts</description>
                                    <value>#0</value>
                                </enumeratedValue>
                                <enumeratedValue>
                                    <name>1</name>
                                    <description>Use reception and transmission interrupts</description>
                                    <value>#1</value>
                                </enumeratedValue>
                            </enumeratedValues>
                        </field>
                        <field>
                            <name>IICCSC</name>
                            <description>Clock Synchronization</description>
                            <lsb>9</lsb>
                            <msb>9</msb>
                            <access>read-write</access>
                            <enumeratedValues>
                                <enumeratedValue>
                                    <name>0</name>
                                    <description>No synchronization with the clock signal</description>
                                    <value>#0</value>
                                </enumeratedValue>
                                <enumeratedValue>
                                    <name>1</name>
                                    <description>Synchronization with the clock signal</description>
                                    <value>#1</value>
                                </enumeratedValue>
                            </enumeratedValues>
                        </field>
                        <field>
                            <name>IICACKT</name>
                            <description>ACK Transmission Data</description>
                            <lsb>13</lsb>
                            <msb>13</msb>
                            <access>read-write</access>
                            <enumeratedValues>
                                <enumeratedValue>
                                    <name>0</name>
                                    <description>ACK transmission</description>
                                    <value>#0</value>
                                </enumeratedValue>
                                <enumeratedValue>
                                    <name>1</name>
                                    <description>NACK transmission and reception of ACK/NACK</description>
                                    <value>#1</value>
                                </enumeratedValue>
                            </enumeratedValues>
                        </field>
                        <field>
                            <name>IICSTAREQ</name>
                            <description>Start Condition Generation</description>
                            <lsb>16</lsb>
                            <msb>16</msb>
                            <access>read-write</access>
                            <enumeratedValues>
                                <enumeratedValue>
                                    <name>0</name>
                                    <description>A start condition is not generated</description>
                                    <value>#0</value>
                                </enumeratedValue>
                                <enumeratedValue>
                                    <name>1</name>
                                    <description>A start condition is generated </description>
                                    <value>#1</value>
                                </enumeratedValue>
                            </enumeratedValues>
                        </field>
                        <field>
                            <name>IICRSTAREQ</name>
                            <description>Restart Condition Generation</description>
                            <lsb>17</lsb>
                            <msb>17</msb>
                            <access>read-write</access>
                            <enumeratedValues>
                                <enumeratedValue>
                                    <name>0</name>
                                    <description>A restart condition is not generated</description>
                                    <value>#0</value>
                                </enumeratedValue>
                                <enumeratedValue>
                                    <name>1</name>
                                    <description>A restart condition is generated </description>
                                    <value>#1</value>
                                </enumeratedValue>
                            </enumeratedValues>
                        </field>
                        <field>
                            <name>IICSTPREQ</name>
                            <description>Stop Condition Generation</description>
                            <lsb>18</lsb>
                            <msb>18</msb>
                            <access>read-write</access>
                            <enumeratedValues>
                                <enumeratedValue>
                                    <name>0</name>
                                    <description>A stop condition is not generated.</description>
                                    <value>#0</value>
                                </enumeratedValue>
                                <enumeratedValue>
                                    <name>1</name>
                                    <description>A stop condition is generated </description>
                                    <value>#1</value>
                                </enumeratedValue>
                            </enumeratedValues>
                        </field>
                        <field>
                            <name>IICSDAS</name>
                            <description>SDA Output Select</description>
                            <lsb>20</lsb>
                            <msb>21</msb>
                            <access>read-write</access>
                            <enumeratedValues>
                                <enumeratedValue>
                                    <name>00</name>
                                    <description>Serial data output</description>
                                    <value>#00</value>
                                </enumeratedValue>
                                <enumeratedValue>
                                    <name>01</name>
                                    <description>Generate a start, restart, or stop condition</description>
                                    <value>#01</value>
                                </enumeratedValue>
                                <enumeratedValue>
                                    <name>10</name>
                                    <description>Output the low level on the SDAn pin</description>
                                    <value>#10</value>
                                </enumeratedValue>
                                <enumeratedValue>
                                    <name>11</name>
                                    <description>Place the SDAn pin in the high-impedance state</description>
                                    <value>#11</value>
                                </enumeratedValue>
                            </enumeratedValues>
                        </field>
                        <field>
                            <name>IICSCLS</name>
                            <description>SCL Output Select</description>
                            <lsb>22</lsb>
                            <msb>23</msb>
                            <access>read-write</access>
                            <enumeratedValues>
                                <enumeratedValue>
                                    <name>00</name>
                                    <description>Serial clock output</description>
                                    <value>#00</value>
                                </enumeratedValue>
                                <enumeratedValue>
                                    <name>01</name>
                                    <description>Generate a start, restart, or stop condition</description>
                                    <value>#01</value>
                                </enumeratedValue>
                                <enumeratedValue>
                                    <name>10</name>
                                    <description>Output the low level on the SCLn pin</description>
                                    <value>#10</value>
                                </enumeratedValue>
                                <enumeratedValue>
                                    <name>11</name>
                                    <description>Place the SCLn pin in the high-impedance state</description>
                                    <value>#11</value>
                                </enumeratedValue>
                            </enumeratedValues>
                        </field>
                    </fields>
                </register>
                <register>
                    <name>FCR</name>
                    <description>FIFO Control Register</description>
                    <addressOffset>0x24</addressOffset>
                    <size>32</size>
                    <access>read-write</access>
                    <resetValue>0x1f1f0000</resetValue>
                    <resetMask>0xffffffff</resetMask>
                    <fields>
                        <field>
                            <name>DRES</name>
                            <description>Receive Data Ready Error Select Bit</description>
                            <lsb>0</lsb>
                            <msb>0</msb>
                            <access>read-write</access>
                            <enumeratedValues>
                                <enumeratedValue>
                                    <name>0</name>
                                    <description>Reception data full interrupt (SCIn_RXI)</description>
                                    <value>#0</value>
                                </enumeratedValue>
                                <enumeratedValue>
                                    <name>1</name>
                                    <description>Receive error interrupt (SCIn_ERI)</description>
                                    <value>#1</value>
                                </enumeratedValue>
                            </enumeratedValues>
                        </field>
                        <field>
                            <name>TTRG</name>
                            <description>Transmit FIFO Data Trigger Number</description>
                            <lsb>8</lsb>
                            <msb>12</msb>
                            <access>read-write</access>
                        </field>
                        <field>
                            <name>TFRST</name>
                            <description>Transmit FIFO Data Register Reset</description>
                            <lsb>15</lsb>
                            <msb>15</msb>
                            <access>write-only</access>
                            <enumeratedValues>
                                <enumeratedValue>
                                    <name>0</name>
                                    <description>When set, this bit is invalid and does not affect operation</description>
                                    <value>#0</value>
                                </enumeratedValue>
                                <enumeratedValue>
                                    <name>1</name>
                                    <description>The number of data stored in Transmit-FIFO (TDR register) is 0</description>
                                    <value>#1</value>
                                </enumeratedValue>
                            </enumeratedValues>
                        </field>
                        <field>
                            <name>RTRG</name>
                            <description>Receive FIFO Data Trigger Number</description>
                            <lsb>16</lsb>
                            <msb>20</msb>
                            <access>read-write</access>
                        </field>
                        <field>
                            <name>RFRST</name>
                            <description>Receive FIFO Data Register Reset</description>
                            <lsb>23</lsb>
                            <msb>23</msb>
                            <access>write-only</access>
                            <enumeratedValues>
                                <enumeratedValue>
                                    <name>0</name>
                                    <description>When set, this bit is invalid and does not affect operation</description>
                                    <value>#0</value>
                                </enumeratedValue>
                                <enumeratedValue>
                                    <name>1</name>
                                    <description>The number of data stored in Receive-FIFO(RDR register) is 0</description>
                                    <value>#1</value>
                                </enumeratedValue>
                            </enumeratedValues>
                        </field>
                        <field>
                            <name>RSTRG</name>
                            <description>RTS Output Active Trigger Number Select</description>
                            <lsb>24</lsb>
                            <msb>28</msb>
                            <access>read-write</access>
                        </field>
                    </fields>
                </register>
                <register>
                    <name>MCR</name>
                    <description>Manchester Control Register</description>
                    <addressOffset>0x2C</addressOffset>
                    <size>32</size>
                    <access>read-write</access>
                    <resetValue>0x00000000</resetValue>
                    <resetMask>0xffffffff</resetMask>
                    <fields>
                        <field>
                            <name>RMPOL</name>
                            <description>Polarity of Received Manchester Code</description>
                            <lsb>0</lsb>
                            <msb>0</msb>
                            <access>read-write</access>
                            <enumeratedValues>
                                <enumeratedValue>
                                    <name>0</name>
                                    <description>Logic 0 is coded as a zero-to-one transition in Manchester code Logic 1 is coded as a one-to-zero transition in Manchester code </description>
                                    <value>#0</value>
                                </enumeratedValue>
                                <enumeratedValue>
                                    <name>1</name>
                                    <description>Logic 0 is coded as a one-to-zero transition in Manchester code Logic 1 is coded as a zero-to-one transition in Manchester code </description>
                                    <value>#1</value>
                                </enumeratedValue>
                            </enumeratedValues>
                        </field>
                        <field>
                            <name>TMPOL</name>
                            <description>Polarity of Transmit Manchester Code</description>
                            <lsb>1</lsb>
                            <msb>1</msb>
                            <access>read-write</access>
                            <enumeratedValues>
                                <enumeratedValue>
                                    <name>0</name>
                                    <description>Logic 0 is coded as a zero-to-one transition in Manchester code Logic 1 is coded as a one-to-zero transition in Manchester code </description>
                                    <value>#0</value>
                                </enumeratedValue>
                                <enumeratedValue>
                                    <name>1</name>
                                    <description>Logic 0 is coded as a one-to-zero transition in Manchester code Logic 1 is coded as a zero-to-one transition in Manchester code </description>
                                    <value>#1</value>
                                </enumeratedValue>
                            </enumeratedValues>
                        </field>
                        <field>
                            <name>ERTEN</name>
                            <description>Manchester Edge Retiming Enable</description>
                            <lsb>2</lsb>
                            <msb>2</msb>
                            <access>read-write</access>
                            <enumeratedValues>
                                <enumeratedValue>
                                    <name>0</name>
                                    <description>Disables the receive retiming function</description>
                                    <value>#0</value>
                                </enumeratedValue>
                                <enumeratedValue>
                                    <name>1</name>
                                    <description>Enables the receive retiming function</description>
                                    <value>#1</value>
                                </enumeratedValue>
                            </enumeratedValues>
                        </field>
                        <field>
                            <name>SYNVAL</name>
                            <description>SYNC value Setting</description>
                            <lsb>4</lsb>
                            <msb>4</msb>
                            <access>read-write</access>
                        </field>
                        <field>
                            <name>SYNSEL</name>
                            <description>SYNC Select</description>
                            <lsb>5</lsb>
                            <msb>5</msb>
                            <access>read-write</access>
                            <enumeratedValues>
                                <enumeratedValue>
                                    <name>0</name>
                                    <description>The start bit pattern is set with the SYNVAL bit</description>
                                    <value>#0</value>
                                </enumeratedValue>
                                <enumeratedValue>
                                    <name>1</name>
                                    <description>The start bit pattern is set with the TSYNC bit</description>
                                    <value>#1</value>
                                </enumeratedValue>
                            </enumeratedValues>
                        </field>
                        <field>
                            <name>SBSEL</name>
                            <description>Start Bit Select</description>
                            <lsb>6</lsb>
                            <msb>6</msb>
                            <access>read-write</access>
                            <enumeratedValues>
                                <enumeratedValue>
                                    <name>0</name>
                                    <description>The start bit area consists of one bit</description>
                                    <value>#0</value>
                                </enumeratedValue>
                                <enumeratedValue>
                                    <name>1</name>
                                    <description>The start bit area consists of three bits (COMMAND SYNC or DATA SYNC) </description>
                                    <value>#1</value>
                                </enumeratedValue>
                            </enumeratedValues>
                        </field>
                        <field>
                            <name>TPLEN</name>
                            <description>Transmit Preface Length</description>
                            <lsb>8</lsb>
                            <msb>11</msb>
                            <access>read-write</access>
                            <enumeratedValues>
                                <enumeratedValue>
                                    <name>0x0</name>
                                    <description>Disables the transmit preface generation</description>
                                    <value>0x0</value>
                                </enumeratedValue>
                                <enumeratedValue>
                                    <name>Others</name>
                                    <description>Transmit preface length (bit length)</description>
                                    <isDefault>true</isDefault>
                                </enumeratedValue>
                            </enumeratedValues>
                        </field>
                        <field>
                            <name>TPPAT</name>
                            <description>Transmit Preface Pattern</description>
                            <lsb>12</lsb>
                            <msb>13</msb>
                            <access>read-write</access>
                            <enumeratedValues>
                                <enumeratedValue>
                                    <name>00</name>
                                    <description>ALL ZERO</description>
                                    <value>#00</value>
                                </enumeratedValue>
                                <enumeratedValue>
                                    <name>01</name>
                                    <description>ZERO ONE</description>
                                    <value>#01</value>
                                </enumeratedValue>
                                <enumeratedValue>
                                    <name>10</name>
                                    <description>ONE ZERO</description>
                                    <value>#10</value>
                                </enumeratedValue>
                                <enumeratedValue>
                                    <name>11</name>
                                    <description>ALL ONE</description>
                                    <value>#11</value>
                                </enumeratedValue>
                            </enumeratedValues>
                        </field>
                        <field>
                            <name>RPLEN</name>
                            <description>Receive Preface Length</description>
                            <lsb>16</lsb>
                            <msb>19</msb>
                            <access>read-write</access>
                            <enumeratedValues>
                                <enumeratedValue>
                                    <name>0x0</name>
                                    <description>Disables the receive preface generation</description>
                                    <value>0x0</value>
                                </enumeratedValue>
                                <enumeratedValue>
                                    <name>Others</name>
                                    <description>Receive preface length (bit length)</description>
                                    <isDefault>true</isDefault>
                                </enumeratedValue>
                            </enumeratedValues>
                        </field>
                        <field>
                            <name>RPPAT</name>
                            <description>Receive Preface Pattern</description>
                            <lsb>20</lsb>
                            <msb>21</msb>
                            <access>read-write</access>
                            <enumeratedValues>
                                <enumeratedValue>
                                    <name>00</name>
                                    <description>ALL ZERO</description>
                                    <value>#00</value>
                                </enumeratedValue>
                                <enumeratedValue>
                                    <name>01</name>
                                    <description>ZERO ONE</description>
                                    <value>#01</value>
                                </enumeratedValue>
                                <enumeratedValue>
                                    <name>10</name>
                                    <description>ONE ZERO</description>
                                    <value>#10</value>
                                </enumeratedValue>
                                <enumeratedValue>
                                    <name>11</name>
                                    <description>ALL ONE</description>
                                    <value>#11</value>
                                </enumeratedValue>
                            </enumeratedValues>
                        </field>
                        <field>
                            <name>PFEREN</name>
                            <description>Preface Error Enable</description>
                            <lsb>24</lsb>
                            <msb>24</msb>
                            <access>read-write</access>
                            <enumeratedValues>
                                <enumeratedValue>
                                    <name>0</name>
                                    <description>Does not handle a preface error as an interrupt source</description>
                                    <value>#0</value>
                                </enumeratedValue>
                                <enumeratedValue>
                                    <name>1</name>
                                    <description>Handles a preface error as an interrupt source</description>
                                    <value>#1</value>
                                </enumeratedValue>
                            </enumeratedValues>
                        </field>
                        <field>
                            <name>SYEREN</name>
                            <description>Receive SYNC Error Enable</description>
                            <lsb>25</lsb>
                            <msb>25</msb>
                            <access>read-write</access>
                            <enumeratedValues>
                                <enumeratedValue>
                                    <name>0</name>
                                    <description>Does not handle a receive SYNC error as an interrupt source</description>
                                    <value>#0</value>
                                </enumeratedValue>
                                <enumeratedValue>
                                    <name>1</name>
                                    <description>Handles a receive SYNC error as an interrupt source</description>
                                    <value>#1</value>
                                </enumeratedValue>
                            </enumeratedValues>
                        </field>
                        <field>
                            <name>SBEREN</name>
                            <description>Start Bit Error Enable</description>
                            <lsb>26</lsb>
                            <msb>26</msb>
                            <access>read-write</access>
                            <enumeratedValues>
                                <enumeratedValue>
                                    <name>0</name>
                                    <description>Does not handle a start bit error as an interrupt source</description>
                                    <value>#0</value>
                                </enumeratedValue>
                                <enumeratedValue>
                                    <name>1</name>
                                    <description>Handles a start bit error as an interrupt source</description>
                                    <value>#1</value>
                                </enumeratedValue>
                            </enumeratedValues>
                        </field>
                    </fields>
                </register>
                <register>
                    <name>DCR</name>
                    <description>Driver Control Register</description>
                    <addressOffset>0x30</addressOffset>
                    <size>32</size>
                    <access>read-write</access>
                    <resetValue>0x00000000</resetValue>
                    <resetMask>0xffffffff</resetMask>
                    <fields>
                        <field>
                            <name>DEPOL</name>
                            <description>Driver Effective Polarity Select</description>
                            <lsb>0</lsb>
                            <msb>0</msb>
                            <access>read-write</access>
                            <enumeratedValues>
                                <enumeratedValue>
                                    <name>0</name>
                                    <description>The DEn signal is active-high</description>
                                    <value>#0</value>
                                </enumeratedValue>
                                <enumeratedValue>
                                    <name>1</name>
                                    <description>The DEn signal is active-low</description>
                                    <value>#1</value>
                                </enumeratedValue>
                            </enumeratedValues>
                        </field>
                        <field>
                            <name>DEAST</name>
                            <description>Driver Assertion Time</description>
                            <lsb>8</lsb>
                            <msb>12</msb>
                            <access>read-write</access>
                        </field>
                        <field>
                            <name>DENGT</name>
                            <description>Driver Negate Time</description>
                            <lsb>16</lsb>
                            <msb>20</msb>
                            <access>read-write</access>
                        </field>
                    </fields>
                </register>
                <register>
                    <name>XCR0</name>
                    <description>Simple LIN Control Register 0</description>
                    <addressOffset>0x34</addressOffset>
                    <size>32</size>
                    <access>read-write</access>
                    <resetValue>0x00000000</resetValue>
                    <resetMask>0xffffffff</resetMask>
                    <fields>
                        <field>
                            <name>TCSS</name>
                            <description>Timer Count Clock Source Selection</description>
                            <lsb>0</lsb>
                            <msb>1</msb>
                            <access>read-write</access>
                            <enumeratedValues>
                                <enumeratedValue>
                                    <name>01</name>
                                    <description>TCLK/4</description>
                                    <value>#01</value>
                                </enumeratedValue>
                                <enumeratedValue>
                                    <name>10</name>
                                    <description>TCLK/16</description>
                                    <value>#10</value>
                                </enumeratedValue>
                                <enumeratedValue>
                                    <name>11</name>
                                    <description>TCLK/64</description>
                                    <value>#11</value>
                                </enumeratedValue>
                            </enumeratedValues>
                        </field>
                        <field>
                            <name>BFE</name>
                            <description>Break Field Enable</description>
                            <lsb>8</lsb>
                            <msb>8</msb>
                            <access>read-write</access>
                            <enumeratedValues>
                                <enumeratedValue>
                                    <name>0</name>
                                    <description>No Break Field</description>
                                    <value>#0</value>
                                </enumeratedValue>
                                <enumeratedValue>
                                    <name>1</name>
                                    <description>With Break Field</description>
                                    <value>#1</value>
                                </enumeratedValue>
                            </enumeratedValues>
                        </field>
                        <field>
                            <name>CF0RE</name>
                            <description>Control Field 0 Enable</description>
                            <lsb>9</lsb>
                            <msb>9</msb>
                            <access>read-write</access>
                            <enumeratedValues>
                                <enumeratedValue>
                                    <name>0</name>
                                    <description>No Control Field 0</description>
                                    <value>#0</value>
                                </enumeratedValue>
                                <enumeratedValue>
                                    <name>1</name>
                                    <description>With Control Field 0</description>
                                    <value>#1</value>
                                </enumeratedValue>
                            </enumeratedValues>
                        </field>
                        <field>
                            <name>CF1DS</name>
                            <description>Control Field1 Compare Data Select</description>
                            <lsb>10</lsb>
                            <msb>11</msb>
                            <access>read-write</access>
                            <enumeratedValues>
                                <enumeratedValue>
                                    <name>00</name>
                                    <description>Select XCR1.PCF1D[7:0] as the compare data</description>
                                    <value>#00</value>
                                </enumeratedValue>
                                <enumeratedValue>
                                    <name>01</name>
                                    <description>Select XCR1.SCF1D[7:0] as the compare data</description>
                                    <value>#01</value>
                                </enumeratedValue>
                                <enumeratedValue>
                                    <name>10</name>
                                    <description>Select both XCR1.PCF1D[7:0] and XCR1.SCF1D[7:0] as the compare data</description>
                                    <value>#10</value>
                                </enumeratedValue>
                                <enumeratedValue>
                                    <name>11</name>
                                    <description>Setting prohibited</description>
                                    <value>#11</value>
                                </enumeratedValue>
                            </enumeratedValues>
                        </field>
                        <field>
                            <name>PIBE</name>
                            <description>Priority Interrupt Bit Enable</description>
                            <lsb>12</lsb>
                            <msb>12</msb>
                            <access>read-write</access>
                            <enumeratedValues>
                                <enumeratedValue>
                                    <name>0</name>
                                    <description>Priority interrupt bit disabled</description>
                                    <value>#0</value>
                                </enumeratedValue>
                                <enumeratedValue>
                                    <name>1</name>
                                    <description>Priority interrupt bit enabled</description>
                                    <value>#1</value>
                                </enumeratedValue>
                            </enumeratedValues>
                        </field>
                        <field>
                            <name>PIBS</name>
                            <description>Priority Interrupt Bit Select</description>
                            <lsb>13</lsb>
                            <msb>15</msb>
                            <access>read-write</access>
                            <enumeratedValues>
                                <enumeratedValue>
                                    <name>000</name>
                                    <description>Bit 0 of Control Field 1</description>
                                    <value>#000</value>
                                </enumeratedValue>
                                <enumeratedValue>
                                    <name>001</name>
                                    <description>Bit 1 of Control Field 1</description>
                                    <value>#001</value>
                                </enumeratedValue>
                                <enumeratedValue>
                                    <name>010</name>
                                    <description>Bit 2 of Control Field 1</description>
                                    <value>#010</value>
                                </enumeratedValue>
                                <enumeratedValue>
                                    <name>011</name>
                                    <description>Bit 3 of Control Field 1</description>
                                    <value>#011</value>
                                </enumeratedValue>
                                <enumeratedValue>
                                    <name>100</name>
                                    <description>Bit 4 of Control Field 1</description>
                                    <value>#100</value>
                                </enumeratedValue>
                                <enumeratedValue>
                                    <name>101</name>
                                    <description>Bit 5 of Control Field 1</description>
                                    <value>#101</value>
                                </enumeratedValue>
                                <enumeratedValue>
                                    <name>110</name>
                                    <description>Bit 6 of Control Field 1</description>
                                    <value>#110</value>
                                </enumeratedValue>
                                <enumeratedValue>
                                    <name>111</name>
                                    <description>Bit 7 of Control Field 1</description>
                                    <value>#111</value>
                                </enumeratedValue>
                            </enumeratedValues>
                        </field>
                        <field>
                            <name>BFOIE</name>
                            <description>Break Field Output Completion Interrupt Enable</description>
                            <lsb>16</lsb>
                            <msb>16</msb>
                            <access>read-write</access>
                            <enumeratedValues>
                                <enumeratedValue>
                                    <name>0</name>
                                    <description>Break Field output completion is not included in SCIn_TXI interrupt factor</description>
                                    <value>#0</value>
                                </enumeratedValue>
                                <enumeratedValue>
                                    <name>1</name>
                                    <description>Break Field output completion is included in SCIn_TXI interrupt factor</description>
                                    <value>#1</value>
                                </enumeratedValue>
                            </enumeratedValues>
                        </field>
                        <field>
                            <name>BCDIE</name>
                            <description>Bus Conflict Detection Interrupt Enable</description>
                            <lsb>17</lsb>
                            <msb>17</msb>
                            <access>read-write</access>
                            <enumeratedValues>
                                <enumeratedValue>
                                    <name>0</name>
                                    <description>Bus conflict detection is not included in SCIn_ERI interrupt factor</description>
                                    <value>#0</value>
                                </enumeratedValue>
                                <enumeratedValue>
                                    <name>1</name>
                                    <description>Bus conflict detection is included in SCIn_ERI interrupt factor</description>
                                    <value>#1</value>
                                </enumeratedValue>
                            </enumeratedValues>
                        </field>
                        <field>
                            <name>BFDIE</name>
                            <description>Break Field Detection Interrupt Enable</description>
                            <lsb>20</lsb>
                            <msb>20</msb>
                            <access>read-write</access>
                            <enumeratedValues>
                                <enumeratedValue>
                                    <name>0</name>
                                    <description>Break Field detection interrupt disabled</description>
                                    <value>#0</value>
                                </enumeratedValue>
                                <enumeratedValue>
                                    <name>1</name>
                                    <description>Break Field detection interrupt enabled</description>
                                    <value>#1</value>
                                </enumeratedValue>
                            </enumeratedValues>
                        </field>
                        <field>
                            <name>COFIE</name>
                            <description>Counter Overflow Interrupt Enable</description>
                            <lsb>21</lsb>
                            <msb>21</msb>
                            <access>read-write</access>
                            <enumeratedValues>
                                <enumeratedValue>
                                    <name>0</name>
                                    <description>Counter overflow is not included in SCIn_ERI interrupt factor</description>
                                    <value>#0</value>
                                </enumeratedValue>
                                <enumeratedValue>
                                    <name>1</name>
                                    <description>Counter overflow is included in SCIn_ERI interrupt factor</description>
                                    <value>#1</value>
                                </enumeratedValue>
                            </enumeratedValues>
                        </field>
                        <field>
                            <name>AEDIE</name>
                            <description>Active Edge Detection Interrupt Enable</description>
                            <lsb>22</lsb>
                            <msb>22</msb>
                            <access>read-write</access>
                            <enumeratedValues>
                                <enumeratedValue>
                                    <name>0</name>
                                    <description>Active edge detection interrupt disabled</description>
                                    <value>#0</value>
                                </enumeratedValue>
                                <enumeratedValue>
                                    <name>1</name>
                                    <description>Active edge detection interrupt enabled</description>
                                    <value>#1</value>
                                </enumeratedValue>
                            </enumeratedValues>
                        </field>
                        <field>
                            <name>BCCS</name>
                            <description>Bus Conflict Detection Clock Selection</description>
                            <lsb>24</lsb>
                            <msb>25</msb>
                            <access>read-write</access>
                            <enumeratedValues>
                                <enumeratedValue>
                                    <name>00</name>
                                    <description>Base clock</description>
                                    <value>#00</value>
                                </enumeratedValue>
                                <enumeratedValue>
                                    <name>01</name>
                                    <description>Base clock/2</description>
                                    <value>#01</value>
                                </enumeratedValue>
                                <enumeratedValue>
                                    <name>10</name>
                                    <description>Base clock/4</description>
                                    <value>#10</value>
                                </enumeratedValue>
                                <enumeratedValue>
                                    <name>11</name>
                                    <description>Setting prohibited</description>
                                    <value>#11</value>
                                </enumeratedValue>
                            </enumeratedValues>
                        </field>
                    </fields>
                </register>
                <register>
                    <name>XCR1</name>
                    <description>Simple LIN Control Register 1</description>
                    <addressOffset>0x38</addressOffset>
                    <size>32</size>
                    <access>read-write</access>
                    <resetValue>0x00000000</resetValue>
                    <resetMask>0xffffffff</resetMask>
                    <fields>
                        <field>
                            <name>TCST</name>
                            <description>Break Field Output Timer Count Start Trigger</description>
                            <lsb>0</lsb>
                            <msb>0</msb>
                            <access>read-write</access>
                            <enumeratedValues>
                                <enumeratedValue>
                                    <name>0</name>
                                    <description>Break Field output timer count stopped</description>
                                    <value>#0</value>
                                </enumeratedValue>
                                <enumeratedValue>
                                    <name>1</name>
                                    <description>Break Field output timer count start</description>
                                    <value>#1</value>
                                </enumeratedValue>
                            </enumeratedValues>
                        </field>
                        <field>
                            <name>SDST</name>
                            <description>Start Frame Detection Enable</description>
                            <lsb>4</lsb>
                            <msb>4</msb>
                            <access>read-write</access>
                            <enumeratedValues>
                                <enumeratedValue>
                                    <name>0</name>
                                    <description>Start Frame/Break Field detection disabled</description>
                                    <value>#0</value>
                                </enumeratedValue>
                                <enumeratedValue>
                                    <name>1</name>
                                    <description>Start Frame/Break Field detection enabled</description>
                                    <value>#1</value>
                                </enumeratedValue>
                            </enumeratedValues>
                        </field>
                        <field>
                            <name>BMEN</name>
                            <description>Bit Rate Measurement Enable</description>
                            <lsb>5</lsb>
                            <msb>5</msb>
                            <access>read-write</access>
                            <enumeratedValues>
                                <enumeratedValue>
                                    <name>0</name>
                                    <description>Bit rate measurement disabled</description>
                                    <value>#0</value>
                                </enumeratedValue>
                                <enumeratedValue>
                                    <name>1</name>
                                    <description>Bit rate measurement enabled</description>
                                    <value>#1</value>
                                </enumeratedValue>
                            </enumeratedValues>
                        </field>
                        <field>
                            <name>PCF1D</name>
                            <description>Priority Compare Data for Control Field 1</description>
                            <lsb>8</lsb>
                            <msb>15</msb>
                            <access>read-write</access>
                        </field>
                        <field>
                            <name>SCF1D</name>
                            <description>Secondary Compare Data for Control Field 1</description>
                            <lsb>16</lsb>
                            <msb>23</msb>
                            <access>read-write</access>
                        </field>
                        <field>
                            <name>CF1CE</name>
                            <description>Control Field 1 Compare Bit Enable</description>
                            <lsb>24</lsb>
                            <msb>31</msb>
                            <access>read-write</access>
                            <enumeratedValues>
                                <enumeratedValue>
                                    <name>0</name>
                                    <description>Control Field 1 bit N compare disabled</description>
                                    <value>#0</value>
                                </enumeratedValue>
                                <enumeratedValue>
                                    <name>1</name>
                                    <description>Control Field 1 bit N compare enabled</description>
                                    <value>#1</value>
                                </enumeratedValue>
                            </enumeratedValues>
                        </field>
                    </fields>
                </register>
                <register>
                    <name>XCR2</name>
                    <description>Simple LIN Control Register 2</description>
                    <addressOffset>0x3C</addressOffset>
                    <size>32</size>
                    <access>read-write</access>
                    <resetValue>0xfffe0000</resetValue>
                    <resetMask>0xffffffff</resetMask>
                    <fields>
                        <field>
                            <name>CF0D</name>
                            <description>Control Field 0 Compare Data</description>
                            <lsb>0</lsb>
                            <msb>7</msb>
                            <access>read-write</access>
                        </field>
                        <field>
                            <name>CF0CE</name>
                            <description>Control Field 0 Compare Bit Enable</description>
                            <lsb>8</lsb>
                            <msb>15</msb>
                            <access>read-write</access>
                            <enumeratedValues>
                                <enumeratedValue>
                                    <name>0</name>
                                    <description>Control Field 0 bit N compare disabled</description>
                                    <value>#0</value>
                                </enumeratedValue>
                                <enumeratedValue>
                                    <name>1</name>
                                    <description>Control Field 0 bit N compare enabled</description>
                                    <value>#1</value>
                                </enumeratedValue>
                            </enumeratedValues>
                        </field>
                        <field>
                            <name>BFLW</name>
                            <description>Break Field Length Setting</description>
                            <lsb>16</lsb>
                            <msb>31</msb>
                            <access>read-write</access>
                        </field>
                    </fields>
                </register>
                <register>
                    <name>CSR</name>
                    <description>Common Status Register</description>
                    <addressOffset>0x48</addressOffset>
                    <size>32</size>
                    <access>read-only</access>
                    <resetValue>0x60008000</resetValue>
                    <resetMask>0xffffffff</resetMask>
                    <fields>
                        <field>
                            <name>ERS</name>
                            <description>Error Signal Status Flag</description>
                            <lsb>4</lsb>
                            <msb>4</msb>
                            <access>read-only</access>
                            <enumeratedValues>
                                <enumeratedValue>
                                    <name>0</name>
                                    <description>Error signal low not responded</description>
                                    <value>#0</value>
                                </enumeratedValue>
                                <enumeratedValue>
                                    <name>1</name>
                                    <description>Error signal low responded</description>
                                    <value>#1</value>
                                </enumeratedValue>
                            </enumeratedValues>
                        </field>
                        <field>
                            <name>RXDMON</name>
                            <description>Serial Input Data Monitor Bit</description>
                            <lsb>15</lsb>
                            <msb>15</msb>
                            <access>read-only</access>
                            <enumeratedValues>
                                <enumeratedValue>
                                    <name>0</name>
                                    <description>When RINV is 0, RXDn pin is the low level. When RINV is 1, RXDn pin is the high level. </description>
                                    <value>#0</value>
                                </enumeratedValue>
                                <enumeratedValue>
                                    <name>1</name>
                                    <description>When RINV is 0, RXDn pin is the high level. When RINV is 1, RXDn pin is the low level. </description>
                                    <value>#1</value>
                                </enumeratedValue>
                            </enumeratedValues>
                        </field>
                        <field>
                            <name>DCMF</name>
                            <description>Data Compare Match Flag</description>
                            <lsb>16</lsb>
                            <msb>16</msb>
                            <access>read-only</access>
                            <enumeratedValues>
                                <enumeratedValue>
                                    <name>0</name>
                                    <description>No matched</description>
                                    <value>#0</value>
                                </enumeratedValue>
                                <enumeratedValue>
                                    <name>1</name>
                                    <description>Matched</description>
                                    <value>#1</value>
                                </enumeratedValue>
                            </enumeratedValues>
                        </field>
                        <field>
                            <name>DPER</name>
                            <description>Data Compare Match Parity Error Flag</description>
                            <lsb>17</lsb>
                            <msb>17</msb>
                            <access>read-only</access>
                            <enumeratedValues>
                                <enumeratedValue>
                                    <name>0</name>
                                    <description>No parity error occurred at address match detection</description>
                                    <value>#0</value>
                                </enumeratedValue>
                                <enumeratedValue>
                                    <name>1</name>
                                    <description>A parity error has occurred at address match detection</description>
                                    <value>#1</value>
                                </enumeratedValue>
                            </enumeratedValues>
                        </field>
                        <field>
                            <name>DFER</name>
                            <description>Data Compare Match Framing Error Flag</description>
                            <lsb>18</lsb>
                            <msb>18</msb>
                            <access>read-only</access>
                            <enumeratedValues>
                                <enumeratedValue>
                                    <name>0</name>
                                    <description>No framing error occurred at address match detection</description>
                                    <value>#0</value>
                                </enumeratedValue>
                                <enumeratedValue>
                                    <name>1</name>
                                    <description>A framing error has occurred at address match detection</description>
                                    <value>#1</value>
                                </enumeratedValue>
                            </enumeratedValues>
                        </field>
                        <field>
                            <name>ORER</name>
                            <description>Overrun Error Flag</description>
                            <lsb>24</lsb>
                            <msb>24</msb>
                            <access>read-only</access>
                            <enumeratedValues>
                                <enumeratedValue>
                                    <name>0</name>
                                    <description>No overrun error occurred</description>
                                    <value>#0</value>
                                </enumeratedValue>
                                <enumeratedValue>
                                    <name>1</name>
                                    <description>An overrun error has occurred</description>
                                    <value>#1</value>
                                </enumeratedValue>
                            </enumeratedValues>
                        </field>
                        <field>
                            <name>MFF</name>
                            <description>Mode Fault Error Flag</description>
                            <lsb>26</lsb>
                            <msb>26</msb>
                            <access>read-only</access>
                            <enumeratedValues>
                                <enumeratedValue>
                                    <name>0</name>
                                    <description>No mode fault error</description>
                                    <value>#0</value>
                                </enumeratedValue>
                                <enumeratedValue>
                                    <name>1</name>
                                    <description>Mode fault error</description>
                                    <value>#1</value>
                                </enumeratedValue>
                            </enumeratedValues>
                        </field>
                        <field>
                            <name>PER</name>
                            <description>Parity Error Flag</description>
                            <lsb>27</lsb>
                            <msb>27</msb>
                            <access>read-only</access>
                            <enumeratedValues>
                                <enumeratedValue>
                                    <name>0</name>
                                    <description>Non-FIFO selected (CCR3.FM = 0): No parity error occurred FIFO selected (CCR3.FM = 1): No parity error in all received data in receive-FIFO </description>
                                    <value>#0</value>
                                </enumeratedValue>
                                <enumeratedValue>
                                    <name>1</name>
                                    <description>Non-FIFO selected (CCR3.FM = 0): A parity error has occurred FIFO selected (CCR3.FM = 1): One or more parity errors occurred in received data in receive-FIFO </description>
                                    <value>#1</value>
                                </enumeratedValue>
                            </enumeratedValues>
                        </field>
                        <field>
                            <name>FER</name>
                            <description>Framing Error Flag</description>
                            <lsb>28</lsb>
                            <msb>28</msb>
                            <access>read-only</access>
                            <enumeratedValues>
                                <enumeratedValue>
                                    <name>0</name>
                                    <description>Non-FIFO selected (CCR3.FM = 0): No framing error occurred FIFO selected (CCR3.FM = 1): No framing error in all received data in receive-FIFO </description>
                                    <value>#0</value>
                                </enumeratedValue>
                                <enumeratedValue>
                                    <name>1</name>
                                    <description>Non-FIFO selected (CCR3.FM = 0): A framing error has occurred FIFO selected (CCR3.FM = 1): One or more framing errors occurred in received data in receive-FIFO </description>
                                    <value>#1</value>
                                </enumeratedValue>
                            </enumeratedValues>
                        </field>
                        <field>
                            <name>TDRE</name>
                            <description>Transmit Data Empty Flag</description>
                            <lsb>29</lsb>
                            <msb>29</msb>
                            <access>read-only</access>
                            <enumeratedValues>
                                <enumeratedValue>
                                    <name>0</name>
                                    <description>Non-FIFO selected (CCR3.FM = 0): Transmit data is in TDR register FIFO selected (CCR3.FM = 1): The quantity of transmit data written in transmit-FIFO exceeds the specified transmit triggering number. </description>
                                    <value>#0</value>
                                </enumeratedValue>
                                <enumeratedValue>
                                    <name>1</name>
                                    <description>Non-FIFO selected (CCR3.FM = 0): No transmit data is in TDR register FIFO selected (CCR3.FM = 1): The quantity of transmit data written in transmit-FIFO is equal to or less than the specified transmit triggering number. </description>
                                    <value>#1</value>
                                </enumeratedValue>
                            </enumeratedValues>
                        </field>
                        <field>
                            <name>TEND</name>
                            <description>Transmit End Flag</description>
                            <lsb>30</lsb>
                            <msb>30</msb>
                            <access>read-only</access>
                            <enumeratedValues>
                                <enumeratedValue>
                                    <name>0</name>
                                    <description>A character is being transmitted or standing by for transmission.</description>
                                    <value>#0</value>
                                </enumeratedValue>
                                <enumeratedValue>
                                    <name>1</name>
                                    <description>Character transfer has been completed, or sending Break Field.</description>
                                    <value>#1</value>
                                </enumeratedValue>
                            </enumeratedValues>
                        </field>
                        <field>
                            <name>RDRF</name>
                            <description>Receive Data Full Flag</description>
                            <lsb>31</lsb>
                            <msb>31</msb>
                            <access>read-only</access>
                            <enumeratedValues>
                                <enumeratedValue>
                                    <name>0</name>
                                    <description>Non-FIFO selected (CCR3.FM = 0): No received data is in RDR register FIFO selected (CCR3.FM = 1): The quantity of receive data written in receive-FIFO falls below the specified receive triggering number. </description>
                                    <value>#0</value>
                                </enumeratedValue>
                                <enumeratedValue>
                                    <name>1</name>
                                    <description>Non-FIFO selected (CCR3.FM = 0): Received data is in RDR register FIFO selected (CCR3.FM = 1): The quantity of receive data written in receive-FIFO is equal to or greater than the specified receive triggering number. </description>
                                    <value>#1</value>
                                </enumeratedValue>
                            </enumeratedValues>
                        </field>
                    </fields>
                </register>
                <register>
                    <name>ISR</name>
                    <description>Simple IIC Status Register</description>
                    <addressOffset>0x4C</addressOffset>
                    <size>32</size>
                    <access>read-only</access>
                    <resetValue>0x00000000</resetValue>
                    <resetMask>0xffffffff</resetMask>
                    <fields>
                        <field>
                            <name>IICACKR</name>
                            <description>ACK Reception Data Flag</description>
                            <lsb>0</lsb>
                            <msb>0</msb>
                            <access>read-only</access>
                            <enumeratedValues>
                                <enumeratedValue>
                                    <name>0</name>
                                    <description>ACK received</description>
                                    <value>#0</value>
                                </enumeratedValue>
                                <enumeratedValue>
                                    <name>1</name>
                                    <description>NACK received</description>
                                    <value>#1</value>
                                </enumeratedValue>
                            </enumeratedValues>
                        </field>
                        <field>
                            <name>IICSTIF</name>
                            <description>Issuing of Start, Restart, or Stop Condition Completed Flag</description>
                            <lsb>3</lsb>
                            <msb>3</msb>
                            <access>read-only</access>
                            <enumeratedValues>
                                <enumeratedValue>
                                    <name>0</name>
                                    <description>There are no requests for generating conditions or a condition is being generated.</description>
                                    <value>#0</value>
                                </enumeratedValue>
                                <enumeratedValue>
                                    <name>1</name>
                                    <description>A start, restart, or stop condition is completely generated.</description>
                                    <value>#1</value>
                                </enumeratedValue>
                            </enumeratedValues>
                        </field>
                    </fields>
                </register>
                <register>
                    <name>FRSR</name>
                    <description>FIFO Receive Status Register</description>
                    <addressOffset>0x50</addressOffset>
                    <size>32</size>
                    <access>read-only</access>
                    <resetValue>0x00000000</resetValue>
                    <resetMask>0xfffffffd</resetMask>
                    <fields>
                        <field>
                            <name>DR</name>
                            <description>Receive Data Ready Flag</description>
                            <lsb>0</lsb>
                            <msb>0</msb>
                            <access>read-only</access>
                            <enumeratedValues>
                                <enumeratedValue>
                                    <name>0</name>
                                    <description>Receiving is in progress, or no received data remains in the receive-FIFO after a successful reception (receive-FIFO is empty)</description>
                                    <value>#0</value>
                                </enumeratedValue>
                                <enumeratedValue>
                                    <name>1</name>
                                    <description>The following receive data is not received for a fixed period after storing data under the threshold in the receive-FIFO</description>
                                    <value>#1</value>
                                </enumeratedValue>
                            </enumeratedValues>
                        </field>
                        <field>
                            <name>R</name>
                            <description>Receive-FIFO Data Count</description>
                            <lsb>8</lsb>
                            <msb>13</msb>
                            <access>read-only</access>
                        </field>
                        <field>
                            <name>PNUM</name>
                            <description>Parity Error Count</description>
                            <lsb>16</lsb>
                            <msb>21</msb>
                            <access>read-only</access>
                        </field>
                        <field>
                            <name>FNUM</name>
                            <description>Framing Error Count</description>
                            <lsb>24</lsb>
                            <msb>29</msb>
                            <access>read-only</access>
                        </field>
                    </fields>
                </register>
                <register>
                    <name>FTSR</name>
                    <description>FIFO Transmit Status Register</description>
                    <addressOffset>0x54</addressOffset>
                    <size>32</size>
                    <access>read-only</access>
                    <resetValue>0x00000000</resetValue>
                    <resetMask>0xffffffff</resetMask>
                    <fields>
                        <field>
                            <name>T</name>
                            <description>Transmit-FIFO Data Count</description>
                            <lsb>0</lsb>
                            <msb>5</msb>
                            <access>read-only</access>
                        </field>
                    </fields>
                </register>
                <register>
                    <name>MSR</name>
                    <description>Manchester Status Register</description>
                    <addressOffset>0x58</addressOffset>
                    <size>32</size>
                    <access>read-only</access>
                    <resetValue>0x00000000</resetValue>
                    <resetMask>0xffffffff</resetMask>
                    <fields>
                        <field>
                            <name>PFER</name>
                            <description>Preface Error Flag</description>
                            <lsb>0</lsb>
                            <msb>0</msb>
                            <access>read-only</access>
                            <enumeratedValues>
                                <enumeratedValue>
                                    <name>0</name>
                                    <description>No preface error detected</description>
                                    <value>#0</value>
                                </enumeratedValue>
                                <enumeratedValue>
                                    <name>1</name>
                                    <description>Preface error detected</description>
                                    <value>#1</value>
                                </enumeratedValue>
                            </enumeratedValues>
                        </field>
                        <field>
                            <name>SYER</name>
                            <description>SYNC Error Flag</description>
                            <lsb>1</lsb>
                            <msb>1</msb>
                            <access>read-only</access>
                            <enumeratedValues>
                                <enumeratedValue>
                                    <name>0</name>
                                    <description>No receive SYNC error detected</description>
                                    <value>#0</value>
                                </enumeratedValue>
                                <enumeratedValue>
                                    <name>1</name>
                                    <description>Receive SYNC error detected</description>
                                    <value>#1</value>
                                </enumeratedValue>
                            </enumeratedValues>
                        </field>
                        <field>
                            <name>SBER</name>
                            <description>Start Bit Error Flag</description>
                            <lsb>2</lsb>
                            <msb>2</msb>
                            <access>read-only</access>
                            <enumeratedValues>
                                <enumeratedValue>
                                    <name>0</name>
                                    <description>No start bit error detected</description>
                                    <value>#0</value>
                                </enumeratedValue>
                                <enumeratedValue>
                                    <name>1</name>
                                    <description>Start bit error detected</description>
                                    <value>#1</value>
                                </enumeratedValue>
                            </enumeratedValues>
                        </field>
                        <field>
                            <name>MER</name>
                            <description>Manchester Error Flag</description>
                            <lsb>4</lsb>
                            <msb>4</msb>
                            <access>read-only</access>
                            <enumeratedValues>
                                <enumeratedValue>
                                    <name>0</name>
                                    <description>No Manchester error occurred</description>
                                    <value>#0</value>
                                </enumeratedValue>
                                <enumeratedValue>
                                    <name>1</name>
                                    <description>Manchester error has occurred</description>
                                    <value>#1</value>
                                </enumeratedValue>
                            </enumeratedValues>
                        </field>
                        <field>
                            <name>RSYNC</name>
                            <description>Receive SYNC Data Bit</description>
                            <lsb>6</lsb>
                            <msb>6</msb>
                            <access>read-only</access>
                            <enumeratedValues>
                                <enumeratedValue>
                                    <name>0</name>
                                    <description>The received start bit is DATA SYNC</description>
                                    <value>#0</value>
                                </enumeratedValue>
                                <enumeratedValue>
                                    <name>1</name>
                                    <description>The received start bit is COMMAND SYNC</description>
                                    <value>#1</value>
                                </enumeratedValue>
                            </enumeratedValues>
                        </field>
                    </fields>
                </register>
                <register>
                    <name>XSR0</name>
                    <description>Simple LIN Status Register 0</description>
                    <addressOffset>0x5C</addressOffset>
                    <size>32</size>
                    <access>read-only</access>
                    <resetValue>0x00000000</resetValue>
                    <resetMask>0xffffffff</resetMask>
                    <fields>
                        <field>
                            <name>SFSF</name>
                            <description>Start Frame Status Flag</description>
                            <lsb>0</lsb>
                            <msb>0</msb>
                            <access>read-only</access>
                            <enumeratedValues>
                                <enumeratedValue>
                                    <name>0</name>
                                    <description>Start Frame detection disabled or Start Frame detection complete</description>
                                    <value>#0</value>
                                </enumeratedValue>
                                <enumeratedValue>
                                    <name>1</name>
                                    <description>Before Start Frame detection or during detection</description>
                                    <value>#1</value>
                                </enumeratedValue>
                            </enumeratedValues>
                        </field>
                        <field>
                            <name>RXDSF</name>
                            <description>RXDn Input Status Flag</description>
                            <lsb>1</lsb>
                            <msb>1</msb>
                            <access>read-only</access>
                            <enumeratedValues>
                                <enumeratedValue>
                                    <name>0</name>
                                    <description>RXDn input to SCI is enabled</description>
                                    <value>#0</value>
                                </enumeratedValue>
                                <enumeratedValue>
                                    <name>1</name>
                                    <description>RXDn input to SCI is disabled</description>
                                    <value>#1</value>
                                </enumeratedValue>
                            </enumeratedValues>
                        </field>
                        <field>
                            <name>BFOF</name>
                            <description>Break Field Output Completion Flag</description>
                            <lsb>8</lsb>
                            <msb>8</msb>
                            <access>read-only</access>
                            <enumeratedValues>
                                <enumeratedValue>
                                    <name>0</name>
                                    <description>Break Field is being output or is not being output</description>
                                    <value>#0</value>
                                </enumeratedValue>
                                <enumeratedValue>
                                    <name>1</name>
                                    <description>Completed BF output</description>
                                    <value>#1</value>
                                </enumeratedValue>
                            </enumeratedValues>
                        </field>
                        <field>
                            <name>BCDF</name>
                            <description>Bus Conflict Detection Flag</description>
                            <lsb>9</lsb>
                            <msb>9</msb>
                            <access>read-only</access>
                            <enumeratedValues>
                                <enumeratedValue>
                                    <name>0</name>
                                    <description>No bus collision detected</description>
                                    <value>#0</value>
                                </enumeratedValue>
                                <enumeratedValue>
                                    <name>1</name>
                                    <description>Detected a bus collision</description>
                                    <value>#1</value>
                                </enumeratedValue>
                            </enumeratedValues>
                        </field>
                        <field>
                            <name>BFDF</name>
                            <description>Break Field Detection Flag</description>
                            <lsb>10</lsb>
                            <msb>10</msb>
                            <access>read-only</access>
                            <enumeratedValues>
                                <enumeratedValue>
                                    <name>0</name>
                                    <description>Break Field is not detected</description>
                                    <value>#0</value>
                                </enumeratedValue>
                                <enumeratedValue>
                                    <name>1</name>
                                    <description>Break Field is detected</description>
                                    <value>#1</value>
                                </enumeratedValue>
                            </enumeratedValues>
                        </field>
                        <field>
                            <name>CF0MF</name>
                            <description>Control Field 0 Compare Match Flag</description>
                            <lsb>11</lsb>
                            <msb>11</msb>
                            <access>read-only</access>
                            <enumeratedValues>
                                <enumeratedValue>
                                    <name>0</name>
                                    <description>Control Field 0 received data does not match the setting data</description>
                                    <value>#0</value>
                                </enumeratedValue>
                                <enumeratedValue>
                                    <name>1</name>
                                    <description>Control Field 0 received data matches the setting data</description>
                                    <value>#1</value>
                                </enumeratedValue>
                            </enumeratedValues>
                        </field>
                        <field>
                            <name>CF1MF</name>
                            <description>Control Field 1 Compare Match Flag</description>
                            <lsb>12</lsb>
                            <msb>12</msb>
                            <access>read-only</access>
                            <enumeratedValues>
                                <enumeratedValue>
                                    <name>0</name>
                                    <description>Control Field 1 received data does not match the setting data</description>
                                    <value>#0</value>
                                </enumeratedValue>
                                <enumeratedValue>
                                    <name>1</name>
                                    <description>Control Field 1 received data matches the setting data</description>
                                    <value>#1</value>
                                </enumeratedValue>
                            </enumeratedValues>
                        </field>
                        <field>
                            <name>PIBDF</name>
                            <description>Priority Interrupt Bit Detection Flag</description>
                            <lsb>13</lsb>
                            <msb>13</msb>
                            <access>read-only</access>
                            <enumeratedValues>
                                <enumeratedValue>
                                    <name>0</name>
                                    <description>Priority interrupt bit is not detected</description>
                                    <value>#0</value>
                                </enumeratedValue>
                                <enumeratedValue>
                                    <name>1</name>
                                    <description>Priority interrupt bit is detected</description>
                                    <value>#1</value>
                                </enumeratedValue>
                            </enumeratedValues>
                        </field>
                        <field>
                            <name>COF</name>
                            <description>Counter Overflow Flag</description>
                            <lsb>14</lsb>
                            <msb>14</msb>
                            <access>read-only</access>
                            <enumeratedValues>
                                <enumeratedValue>
                                    <name>0</name>
                                    <description>Break Field detection counter has not overflowed</description>
                                    <value>#0</value>
                                </enumeratedValue>
                                <enumeratedValue>
                                    <name>1</name>
                                    <description>Break Field detection counter overflowed</description>
                                    <value>#1</value>
                                </enumeratedValue>
                            </enumeratedValues>
                        </field>
                        <field>
                            <name>AEDF</name>
                            <description>Active Edge Detection Flag</description>
                            <lsb>15</lsb>
                            <msb>15</msb>
                            <access>read-only</access>
                            <enumeratedValues>
                                <enumeratedValue>
                                    <name>0</name>
                                    <description>No valid edge detected</description>
                                    <value>#0</value>
                                </enumeratedValue>
                                <enumeratedValue>
                                    <name>1</name>
                                    <description>Detected a valid edge</description>
                                    <value>#1</value>
                                </enumeratedValue>
                            </enumeratedValues>
                        </field>
                        <field>
                            <name>CF0RD</name>
                            <description>Control Field 0 received data</description>
                            <lsb>16</lsb>
                            <msb>23</msb>
                            <access>read-only</access>
                        </field>
                        <field>
                            <name>CF1RD</name>
                            <description>Control Field 1 received data</description>
                            <lsb>24</lsb>
                            <msb>31</msb>
                            <access>read-only</access>
                        </field>
                    </fields>
                </register>
                <register>
                    <name>XSR1</name>
                    <description>Simple LIN Status Register 1</description>
                    <addressOffset>0x60</addressOffset>
                    <size>32</size>
                    <access>read-only</access>
                    <resetValue>0x00000000</resetValue>
                    <resetMask>0xffffffff</resetMask>
                    <fields>
                        <field>
                            <name>TCNT</name>
                            <description>Timer Count Capture Value</description>
                            <lsb>0</lsb>
                            <msb>15</msb>
                            <access>read-only</access>
                        </field>
                    </fields>
                </register>
                <register>
                    <name>CFCLR</name>
                    <description>Common Flag Clear Register</description>
                    <addressOffset>0x68</addressOffset>
                    <size>32</size>
                    <access>write-only</access>
                    <resetValue>0x00000000</resetValue>
                    <resetMask>0xffffffff</resetMask>
                    <fields>
                        <field>
                            <name>ERSC</name>
                            <description>ERS Clear Bit</description>
                            <lsb>4</lsb>
                            <msb>4</msb>
                            <access>write-only</access>
                        </field>
                        <field>
                            <name>DCMFC</name>
                            <description>DCMF Clear Bit</description>
                            <lsb>16</lsb>
                            <msb>16</msb>
                            <access>write-only</access>
                        </field>
                        <field>
                            <name>DPERC</name>
                            <description>DPER Clear Bit</description>
                            <lsb>17</lsb>
                            <msb>17</msb>
                            <access>write-only</access>
                        </field>
                        <field>
                            <name>DFERC</name>
                            <description>DFER Clear Bit</description>
                            <lsb>18</lsb>
                            <msb>18</msb>
                            <access>write-only</access>
                        </field>
                        <field>
                            <name>ORERC</name>
                            <description>ORER Clear Bit</description>
                            <lsb>24</lsb>
                            <msb>24</msb>
                            <access>write-only</access>
                        </field>
                        <field>
                            <name>MFFC</name>
                            <description>MFF Clear Bit</description>
                            <lsb>26</lsb>
                            <msb>26</msb>
                            <access>write-only</access>
                        </field>
                        <field>
                            <name>PERC</name>
                            <description>PER Clear Bit</description>
                            <lsb>27</lsb>
                            <msb>27</msb>
                            <access>write-only</access>
                        </field>
                        <field>
                            <name>FERC</name>
                            <description>FER Clear Bit</description>
                            <lsb>28</lsb>
                            <msb>28</msb>
                            <access>write-only</access>
                        </field>
                        <field>
                            <name>TDREC</name>
                            <description>TDRE Clear Bit</description>
                            <lsb>29</lsb>
                            <msb>29</msb>
                            <access>write-only</access>
                        </field>
                        <field>
                            <name>RDRFC</name>
                            <description>RDRF Clear Bit</description>
                            <lsb>31</lsb>
                            <msb>31</msb>
                            <access>write-only</access>
                        </field>
                    </fields>
                </register>
                <register>
                    <name>ICFCLR</name>
                    <description>Simple IIC Flag Clear Register</description>
                    <addressOffset>0x6C</addressOffset>
                    <size>32</size>
                    <access>write-only</access>
                    <resetValue>0x00000000</resetValue>
                    <resetMask>0xffffffff</resetMask>
                    <fields>
                        <field>
                            <name>IICSTIFC</name>
                            <description>IICSTIF Clear Bit</description>
                            <lsb>3</lsb>
                            <msb>3</msb>
                            <access>write-only</access>
                        </field>
                    </fields>
                </register>
                <register>
                    <name>FFCLR</name>
                    <description>FIFO Flag Clear Register</description>
                    <addressOffset>0x70</addressOffset>
                    <size>32</size>
                    <access>write-only</access>
                    <resetValue>0x00000000</resetValue>
                    <resetMask>0xffffffff</resetMask>
                    <fields>
                        <field>
                            <name>DRC</name>
                            <description>DR Clear Bit</description>
                            <lsb>0</lsb>
                            <msb>0</msb>
                            <access>write-only</access>
                        </field>
                    </fields>
                </register>
                <register>
                    <name>MFCLR</name>
                    <description>Manchester Flag Clear Register</description>
                    <addressOffset>0x74</addressOffset>
                    <size>32</size>
                    <access>write-only</access>
                    <resetValue>0x00000000</resetValue>
                    <resetMask>0xffffffff</resetMask>
                    <fields>
                        <field>
                            <name>PFERC</name>
                            <description>PFER Clear Bit</description>
                            <lsb>0</lsb>
                            <msb>0</msb>
                            <access>write-only</access>
                        </field>
                        <field>
                            <name>SYERC</name>
                            <description>SYER Clear Bit</description>
                            <lsb>1</lsb>
                            <msb>1</msb>
                            <access>write-only</access>
                        </field>
                        <field>
                            <name>SBERC</name>
                            <description>SBER Clear Bit</description>
                            <lsb>2</lsb>
                            <msb>2</msb>
                            <access>write-only</access>
                        </field>
                        <field>
                            <name>MERC</name>
                            <description>MER Clear Bit</description>
                            <lsb>4</lsb>
                            <msb>4</msb>
                            <access>write-only</access>
                        </field>
                    </fields>
                </register>
                <register>
                    <name>XFCLR</name>
                    <description>Simple LIN Flag Clear Register</description>
                    <addressOffset>0x78</addressOffset>
                    <size>32</size>
                    <access>write-only</access>
                    <resetValue>0x00000000</resetValue>
                    <resetMask>0xffffffff</resetMask>
                    <fields>
                        <field>
                            <name>BFOC</name>
                            <description>BFOF Clear Bit</description>
                            <lsb>8</lsb>
                            <msb>8</msb>
                            <access>write-only</access>
                        </field>
                        <field>
                            <name>BCDC</name>
                            <description>BCDF Clear Bit</description>
                            <lsb>9</lsb>
                            <msb>9</msb>
                            <access>write-only</access>
                        </field>
                        <field>
                            <name>BFDC</name>
                            <description>BFDF Clear Bit</description>
                            <lsb>10</lsb>
                            <msb>10</msb>
                            <access>write-only</access>
                        </field>
                        <field>
                            <name>CF0MC</name>
                            <description>CF0MF Clear Bit</description>
                            <lsb>11</lsb>
                            <msb>11</msb>
                            <access>write-only</access>
                        </field>
                        <field>
                            <name>CF1MC</name>
                            <description>CF1MF Clear Bit</description>
                            <lsb>12</lsb>
                            <msb>12</msb>
                            <access>write-only</access>
                        </field>
                        <field>
                            <name>PIBDC</name>
                            <description>PIBDF Clear Bit</description>
                            <lsb>13</lsb>
                            <msb>13</msb>
                            <access>write-only</access>
                        </field>
                        <field>
                            <name>COFC</name>
                            <description>COFF Clear Bit</description>
                            <lsb>14</lsb>
                            <msb>14</msb>
                            <access>write-only</access>
                        </field>
                        <field>
                            <name>AEDC</name>
                            <description>AEDF Clear Bit</description>
                            <lsb>15</lsb>
                            <msb>15</msb>
                            <access>write-only</access>
                        </field>
                    </fields>
                </register>
            </registers>
        </peripheral>
        <peripheral derivedFrom="SCI0_B">
            <name>SCI1_B</name>
            <description>Serial Communication Interface 1</description>
            <baseAddress>0x40358100</baseAddress>
        </peripheral>
        <peripheral derivedFrom="SCI0_B">
            <name>SCI2_B</name>
            <description>Serial Communication Interface 2</description>
            <baseAddress>0x40358200</baseAddress>
        </peripheral>
        <peripheral derivedFrom="SCI0_B">
            <name>SCI3_B</name>
            <description>Serial Communication Interface 3</description>
            <baseAddress>0x40358300</baseAddress>
        </peripheral>
        <peripheral derivedFrom="SCI0_B">
            <name>SCI4_B</name>
            <description>Serial Communication Interface 4</description>
            <baseAddress>0x40358400</baseAddress>
        </peripheral>
        <peripheral derivedFrom="SCI0_B">
            <name>SCI9_B</name>
            <description>Serial Communication Interface 9</description>
            <baseAddress>0x40358900</baseAddress>
        </peripheral>
        <peripheral>
            <name>SPI0_B</name>
            <description>Serial Peripheral Interface 0</description>
            <baseAddress>0x4035C000</baseAddress>
            <addressBlock>
                <offset>0x00</offset>
                <size>52</size>
                <usage>registers</usage>
            </addressBlock>
            <addressBlock>
                <offset>0x40</offset>
                <size>8</size>
                <usage>registers</usage>
            </addressBlock>
            <addressBlock>
                <offset>0x50</offset>
                <size>4</size>
                <usage>registers</usage>
            </addressBlock>
            <addressBlock>
                <offset>0x58</offset>
                <size>12</size>
                <usage>registers</usage>
            </addressBlock>
            <addressBlock>
                <offset>0x68</offset>
                <size>8</size>
                <usage>registers</usage>
            </addressBlock>
            <registers>
                <register>
                    <name>SPDR</name>
                    <description>SPI Data Register</description>
                    <addressOffset>0x00</addressOffset>
                    <size>32</size>
                    <access>read-write</access>
                    <resetValue>0x00000000</resetValue>
                    <resetMask>0xffffffff</resetMask>
                    <fields>
                        <field>
                            <name>SPD</name>
                            <description>These bits are the interface with the buffers that hold data for transmission and reception by the SPI.</description>
                            <lsb>0</lsb>
                            <msb>31</msb>
                            <access>read-write</access>
                        </field>
                    </fields>
                </register>
                <register>
                    <name>SPDECR</name>
                    <description>SPI Delay Control Register</description>
                    <addressOffset>0x04</addressOffset>
                    <size>32</size>
                    <access>read-write</access>
                    <resetValue>0x00000000</resetValue>
                    <resetMask>0xffffffff</resetMask>
                    <fields>
                        <field>
                            <name>SCKDL</name>
                            <description>RSPCK Delay</description>
                            <lsb>0</lsb>
                            <msb>2</msb>
                            <access>read-write</access>
                            <enumeratedValues>
                                <enumeratedValue>
                                    <name>000</name>
                                    <description>1RSPCK</description>
                                    <value>#000</value>
                                </enumeratedValue>
                                <enumeratedValue>
                                    <name>001</name>
                                    <description>2RSPCK</description>
                                    <value>#001</value>
                                </enumeratedValue>
                                <enumeratedValue>
                                    <name>010</name>
                                    <description>3RSPCK</description>
                                    <value>#010</value>
                                </enumeratedValue>
                                <enumeratedValue>
                                    <name>011</name>
                                    <description>4RSPCK</description>
                                    <value>#011</value>
                                </enumeratedValue>
                                <enumeratedValue>
                                    <name>100</name>
                                    <description>5RSPCK</description>
                                    <value>#100</value>
                                </enumeratedValue>
                                <enumeratedValue>
                                    <name>101</name>
                                    <description>6RSPCK</description>
                                    <value>#101</value>
                                </enumeratedValue>
                                <enumeratedValue>
                                    <name>110</name>
                                    <description>7RSPCK</description>
                                    <value>#110</value>
                                </enumeratedValue>
                                <enumeratedValue>
                                    <name>111</name>
                                    <description>8RSPCK</description>
                                    <value>#111</value>
                                </enumeratedValue>
                            </enumeratedValues>
                        </field>
                        <field>
                            <name>SLNDL</name>
                            <description>SSL Negation Delay</description>
                            <lsb>8</lsb>
                            <msb>10</msb>
                            <access>read-write</access>
                            <enumeratedValues>
                                <enumeratedValue>
                                    <name>000</name>
                                    <description>1RSPCK</description>
                                    <value>#000</value>
                                </enumeratedValue>
                                <enumeratedValue>
                                    <name>001</name>
                                    <description>2RSPCK</description>
                                    <value>#001</value>
                                </enumeratedValue>
                                <enumeratedValue>
                                    <name>010</name>
                                    <description>3RSPCK</description>
                                    <value>#010</value>
                                </enumeratedValue>
                                <enumeratedValue>
                                    <name>011</name>
                                    <description>4RSPCK</description>
                                    <value>#011</value>
                                </enumeratedValue>
                                <enumeratedValue>
                                    <name>100</name>
                                    <description>5RSPCK</description>
                                    <value>#100</value>
                                </enumeratedValue>
                                <enumeratedValue>
                                    <name>101</name>
                                    <description>6RSPCK</description>
                                    <value>#101</value>
                                </enumeratedValue>
                                <enumeratedValue>
                                    <name>110</name>
                                    <description>7RSPCK</description>
                                    <value>#110</value>
                                </enumeratedValue>
                                <enumeratedValue>
                                    <name>111</name>
                                    <description>8RSPCK</description>
                                    <value>#111</value>
                                </enumeratedValue>
                            </enumeratedValues>
                        </field>
                        <field>
                            <name>SPNDL</name>
                            <description>SPI Next-Access Delay</description>
                            <lsb>16</lsb>
                            <msb>18</msb>
                            <access>read-write</access>
                            <enumeratedValues>
                                <enumeratedValue>
                                    <name>000</name>
                                    <description>1RSPCK + 5TCLK</description>
                                    <value>#000</value>
                                </enumeratedValue>
                                <enumeratedValue>
                                    <name>001</name>
                                    <description>2RSPCK + 5TCLK</description>
                                    <value>#001</value>
                                </enumeratedValue>
                                <enumeratedValue>
                                    <name>010</name>
                                    <description>3RSPCK + 5TCLK</description>
                                    <value>#010</value>
                                </enumeratedValue>
                                <enumeratedValue>
                                    <name>011</name>
                                    <description>4RSPCK + 5TCLK</description>
                                    <value>#011</value>
                                </enumeratedValue>
                                <enumeratedValue>
                                    <name>100</name>
                                    <description>5RSPCK + 5TCLK</description>
                                    <value>#100</value>
                                </enumeratedValue>
                                <enumeratedValue>
                                    <name>101</name>
                                    <description>6RSPCK + 5TCLK</description>
                                    <value>#101</value>
                                </enumeratedValue>
                                <enumeratedValue>
                                    <name>110</name>
                                    <description>7RSPCK + 5TCLK</description>
                                    <value>#110</value>
                                </enumeratedValue>
                                <enumeratedValue>
                                    <name>111</name>
                                    <description>8RSPCK + 5TCLK</description>
                                    <value>#111</value>
                                </enumeratedValue>
                            </enumeratedValues>
                        </field>
                    </fields>
                </register>
                <register>
                    <name>SPCR</name>
                    <description>SPI Control Register</description>
                    <addressOffset>0x08</addressOffset>
                    <size>32</size>
                    <access>read-write</access>
                    <resetValue>0x00000000</resetValue>
                    <resetMask>0xffffffff</resetMask>
                    <fields>
                        <field>
                            <name>SPE</name>
                            <description>SPI Function Enable</description>
                            <lsb>0</lsb>
                            <msb>0</msb>
                            <access>read-write</access>
                            <enumeratedValues>
                                <enumeratedValue>
                                    <name>0</name>
                                    <description>SPI function is disabled.</description>
                                    <value>#0</value>
                                </enumeratedValue>
                                <enumeratedValue>
                                    <name>1</name>
                                    <description>SPI function is enabled.</description>
                                    <value>#1</value>
                                </enumeratedValue>
                            </enumeratedValues>
                        </field>
                        <field>
                            <name>SPPE</name>
                            <description>Parity Enable</description>
                            <lsb>8</lsb>
                            <msb>8</msb>
                            <access>read-write</access>
                            <enumeratedValues>
                                <enumeratedValue>
                                    <name>0</name>
                                    <description>A parity bit is not added to transmit data. Received-data parity check is not performed. </description>
                                    <value>#0</value>
                                </enumeratedValue>
                                <enumeratedValue>
                                    <name>1</name>
                                    <description>A parity bit is added to transmit data. Received-data parity check is performed. </description>
                                    <value>#1</value>
                                </enumeratedValue>
                            </enumeratedValues>
                        </field>
                        <field>
                            <name>SPOE</name>
                            <description>Parity Mode</description>
                            <lsb>9</lsb>
                            <msb>9</msb>
                            <access>read-write</access>
                            <enumeratedValues>
                                <enumeratedValue>
                                    <name>0</name>
                                    <description>Even parity is used for transmission and reception.</description>
                                    <value>#0</value>
                                </enumeratedValue>
                                <enumeratedValue>
                                    <name>1</name>
                                    <description>Odd parity is used for transmission and reception.</description>
                                    <value>#1</value>
                                </enumeratedValue>
                            </enumeratedValues>
                        </field>
                        <field>
                            <name>PTE</name>
                            <description>Parity Self-Diagnosis Enable</description>
                            <lsb>11</lsb>
                            <msb>11</msb>
                            <access>read-write</access>
                            <enumeratedValues>
                                <enumeratedValue>
                                    <name>0</name>
                                    <description>Parity circuit self-diagnosis function is disabled.</description>
                                    <value>#0</value>
                                </enumeratedValue>
                                <enumeratedValue>
                                    <name>1</name>
                                    <description>Parity circuit self-diagnosis function is enabled.</description>
                                    <value>#1</value>
                                </enumeratedValue>
                            </enumeratedValues>
                        </field>
                        <field>
                            <name>SCKASE</name>
                            <description>RSPCK Auto-Stop Function Enable</description>
                            <lsb>12</lsb>
                            <msb>12</msb>
                            <access>read-write</access>
                            <enumeratedValues>
                                <enumeratedValue>
                                    <name>0</name>
                                    <description>RSPCK auto-stop function is disabled.</description>
                                    <value>#0</value>
                                </enumeratedValue>
                                <enumeratedValue>
                                    <name>1</name>
                                    <description>RSPCK auto-stop function is enabled.</description>
                                    <value>#1</value>
                                </enumeratedValue>
                            </enumeratedValues>
                        </field>
                        <field>
                            <name>BFDS</name>
                            <description>Between Burst Transfer Frames Delay Select</description>
                            <lsb>13</lsb>
                            <msb>13</msb>
                            <access>read-write</access>
                            <enumeratedValues>
                                <enumeratedValue>
                                    <name>0</name>
                                    <description>Delay (RSPCK delay, SSL negation delay and next-access delay) between frames is inserted in burst transfer</description>
                                    <value>#0</value>
                                </enumeratedValue>
                                <enumeratedValue>
                                    <name>1</name>
                                    <description>Delay between frames is not inserted in burst transfer.</description>
                                    <value>#1</value>
                                </enumeratedValue>
                            </enumeratedValues>
                        </field>
                        <field>
                            <name>MODFEN</name>
                            <description>Mode Fault Error Detection Enable</description>
                            <lsb>14</lsb>
                            <msb>14</msb>
                            <access>read-write</access>
                            <enumeratedValues>
                                <enumeratedValue>
                                    <name>0</name>
                                    <description>Mode fault error detection is disabled.</description>
                                    <value>#0</value>
                                </enumeratedValue>
                                <enumeratedValue>
                                    <name>1</name>
                                    <description>Mode fault error detection is enabled.</description>
                                    <value>#1</value>
                                </enumeratedValue>
                            </enumeratedValues>
                        </field>
                        <field>
                            <name>SPEIE</name>
                            <description>SPI Error Interrupt Enable</description>
                            <lsb>16</lsb>
                            <msb>16</msb>
                            <access>read-write</access>
                            <enumeratedValues>
                                <enumeratedValue>
                                    <name>0</name>
                                    <description>SPI error interrupt request is disabled.</description>
                                    <value>#0</value>
                                </enumeratedValue>
                                <enumeratedValue>
                                    <name>1</name>
                                    <description>SPI error interrupt request is enabled.</description>
                                    <value>#1</value>
                                </enumeratedValue>
                            </enumeratedValues>
                        </field>
                        <field>
                            <name>SPRIE</name>
                            <description>SPI Receive Buffer Full Interrupt Enable</description>
                            <lsb>17</lsb>
                            <msb>17</msb>
                            <access>read-write</access>
                            <enumeratedValues>
                                <enumeratedValue>
                                    <name>0</name>
                                    <description>SPI receive buffer full interrupt request is disabled.</description>
                                    <value>#0</value>
                                </enumeratedValue>
                                <enumeratedValue>
                                    <name>1</name>
                                    <description>SPI receive buffer full interrupt request is enabled.</description>
                                    <value>#1</value>
                                </enumeratedValue>
                            </enumeratedValues>
                        </field>
                        <field>
                            <name>SPIIE</name>
                            <description>SPI Idle Interrupt Enable</description>
                            <lsb>18</lsb>
                            <msb>18</msb>
                            <access>read-write</access>
                            <enumeratedValues>
                                <enumeratedValue>
                                    <name>0</name>
                                    <description>Idle interrupt request is disabled.</description>
                                    <value>#0</value>
                                </enumeratedValue>
                                <enumeratedValue>
                                    <name>1</name>
                                    <description>Idle interrupt request is enabled.</description>
                                    <value>#1</value>
                                </enumeratedValue>
                            </enumeratedValues>
                        </field>
                        <field>
                            <name>SPDRES</name>
                            <description>SPI receive data ready error select</description>
                            <lsb>19</lsb>
                            <msb>19</msb>
                            <access>read-write</access>
                            <enumeratedValues>
                                <enumeratedValue>
                                    <name>0</name>
                                    <description>Receive data full interrupt</description>
                                    <value>#0</value>
                                </enumeratedValue>
                                <enumeratedValue>
                                    <name>1</name>
                                    <description>Error interrupt</description>
                                    <value>#1</value>
                                </enumeratedValue>
                            </enumeratedValues>
                        </field>
                        <field>
                            <name>SPTIE</name>
                            <description>SPI Transmit Buffer Empty Interrupt Enable</description>
                            <lsb>20</lsb>
                            <msb>20</msb>
                            <access>read-write</access>
                            <enumeratedValues>
                                <enumeratedValue>
                                    <name>0</name>
                                    <description>SPI transmit buffer empty interrupt request is disabled.</description>
                                    <value>#0</value>
                                </enumeratedValue>
                                <enumeratedValue>
                                    <name>1</name>
                                    <description>SPI transmit buffer empty interrupt request is enabled.</description>
                                    <value>#1</value>
                                </enumeratedValue>
                            </enumeratedValues>
                        </field>
                        <field>
                            <name>CENDIE</name>
                            <description>SPI Communication End Interrupt Enable</description>
                            <lsb>21</lsb>
                            <msb>21</msb>
                            <access>read-write</access>
                            <enumeratedValues>
                                <enumeratedValue>
                                    <name>0</name>
                                    <description>Communication end interrupt request is disabled.</description>
                                    <value>#0</value>
                                </enumeratedValue>
                                <enumeratedValue>
                                    <name>1</name>
                                    <description>Communication end interrupt request is enabled.</description>
                                    <value>#1</value>
                                </enumeratedValue>
                            </enumeratedValues>
                        </field>
                        <field>
                            <name>SPMS</name>
                            <description>SPI Mode Select</description>
                            <lsb>24</lsb>
                            <msb>24</msb>
                            <access>read-write</access>
                            <enumeratedValues>
                                <enumeratedValue>
                                    <name>0</name>
                                    <description>SPI operation (4-wire)</description>
                                    <value>#0</value>
                                </enumeratedValue>
                                <enumeratedValue>
                                    <name>1</name>
                                    <description>Clock synchronous operation (3-wire)</description>
                                    <value>#1</value>
                                </enumeratedValue>
                            </enumeratedValues>
                        </field>
                        <field>
                            <name>SPFRF</name>
                            <description>SPI Frame Format Select</description>
                            <lsb>25</lsb>
                            <msb>25</msb>
                            <access>read-write</access>
                            <enumeratedValues>
                                <enumeratedValue>
                                    <name>0</name>
                                    <description>Motorola-SPI</description>
                                    <value>#0</value>
                                </enumeratedValue>
                                <enumeratedValue>
                                    <name>1</name>
                                    <description>TI-SSP</description>
                                    <value>#1</value>
                                </enumeratedValue>
                            </enumeratedValues>
                        </field>
                        <field>
                            <name>TXMD</name>
                            <description>Communication Mode Select</description>
                            <lsb>28</lsb>
                            <msb>29</msb>
                            <access>read-write</access>
                            <enumeratedValues>
                                <enumeratedValue>
                                    <name>00</name>
                                    <description>Transmit-Receive</description>
                                    <value>#00</value>
                                </enumeratedValue>
                                <enumeratedValue>
                                    <name>01</name>
                                    <description>Transmit only</description>
                                    <value>#01</value>
                                </enumeratedValue>
                                <enumeratedValue>
                                    <name>Others</name>
                                    <description>Receive only</description>
                                    <isDefault>true</isDefault>
                                </enumeratedValue>
                            </enumeratedValues>
                        </field>
                        <field>
                            <name>MSTR</name>
                            <description>SPI Master/Slave Mode Select</description>
                            <lsb>30</lsb>
                            <msb>30</msb>
                            <access>read-write</access>
                            <enumeratedValues>
                                <enumeratedValue>
                                    <name>0</name>
                                    <description>Slave mode</description>
                                    <value>#0</value>
                                </enumeratedValue>
                                <enumeratedValue>
                                    <name>1</name>
                                    <description>Master mode</description>
                                    <value>#1</value>
                                </enumeratedValue>
                            </enumeratedValues>
                        </field>
                        <field>
                            <name>BPEN</name>
                            <description>Synchronization Circuit Bypass Enable</description>
                            <lsb>31</lsb>
                            <msb>31</msb>
                            <access>read-write</access>
                            <enumeratedValues>
                                <enumeratedValue>
                                    <name>0</name>
                                    <description>Non-Bypass</description>
                                    <value>#0</value>
                                </enumeratedValue>
                                <enumeratedValue>
                                    <name>1</name>
                                    <description>Bypass</description>
                                    <value>#1</value>
                                </enumeratedValue>
                            </enumeratedValues>
                        </field>
                    </fields>
                </register>
                <register>
                    <name>SPCR2</name>
                    <description>SPI Control Register 2</description>
                    <addressOffset>0x0C</addressOffset>
                    <size>32</size>
                    <access>read-write</access>
                    <resetValue>0x00000000</resetValue>
                    <resetMask>0xffffffff</resetMask>
                    <fields>
                        <field>
                            <name>RMFM</name>
                            <description>Frame processing count setting in Master Receive only</description>
                            <lsb>0</lsb>
                            <msb>4</msb>
                            <access>read-write</access>
                        </field>
                        <field>
                            <name>RMEDTG</name>
                            <description>End Trigger in Master Receive only</description>
                            <lsb>6</lsb>
                            <msb>6</msb>
                            <access>write-only</access>
                            <enumeratedValues>
                                <enumeratedValue>
                                    <name>1</name>
                                    <description>Receive End (Writable only when Master Receive only) Reading value is always 0 </description>
                                    <value>#1</value>
                                </enumeratedValue>
                            </enumeratedValues>
                        </field>
                        <field>
                            <name>RMSTTG</name>
                            <description>Start Trigger in Master Receive only</description>
                            <lsb>7</lsb>
                            <msb>7</msb>
                            <access>write-only</access>
                            <enumeratedValues>
                                <enumeratedValue>
                                    <name>1</name>
                                    <description>Receive Start (Writable only when Master Receive only)  Reading value is always 0</description>
                                    <value>#1</value>
                                </enumeratedValue>
                            </enumeratedValues>
                        </field>
                        <field>
                            <name>SPDRC</name>
                            <description>SPI received data ready detect adjustment</description>
                            <lsb>8</lsb>
                            <msb>15</msb>
                            <access>read-write</access>
                        </field>
                        <field>
                            <name>SPLP</name>
                            <description>SPI Loopback</description>
                            <lsb>16</lsb>
                            <msb>16</msb>
                            <access>read-write</access>
                            <enumeratedValues>
                                <enumeratedValue>
                                    <name>0</name>
                                    <description>Normal mode</description>
                                    <value>#0</value>
                                </enumeratedValue>
                                <enumeratedValue>
                                    <name>1</name>
                                    <description>Loopback mode (inverted transmit data = receive data)</description>
                                    <value>#1</value>
                                </enumeratedValue>
                            </enumeratedValues>
                        </field>
                        <field>
                            <name>SPLP2</name>
                            <description>SPI Loopback 2</description>
                            <lsb>17</lsb>
                            <msb>17</msb>
                            <access>read-write</access>
                            <enumeratedValues>
                                <enumeratedValue>
                                    <name>0</name>
                                    <description>Normal mode</description>
                                    <value>#0</value>
                                </enumeratedValue>
                                <enumeratedValue>
                                    <name>1</name>
                                    <description>Loopback mode (transmit data = receive data)</description>
                                    <value>#1</value>
                                </enumeratedValue>
                            </enumeratedValues>
                        </field>
                        <field>
                            <name>MOIFV</name>
                            <description>MOSI Idle Fixed Value</description>
                            <lsb>20</lsb>
                            <msb>20</msb>
                            <access>read-write</access>
                            <enumeratedValues>
                                <enumeratedValue>
                                    <name>0</name>
                                    <description>The fixed value of MOSI idle = 0.</description>
                                    <value>#0</value>
                                </enumeratedValue>
                                <enumeratedValue>
                                    <name>1</name>
                                    <description>The fixed value of MOSI idle = 1.</description>
                                    <value>#1</value>
                                </enumeratedValue>
                            </enumeratedValues>
                        </field>
                        <field>
                            <name>MOIFE</name>
                            <description>MOSI Idle Fixed Value Enable</description>
                            <lsb>21</lsb>
                            <msb>21</msb>
                            <access>read-write</access>
                            <enumeratedValues>
                                <enumeratedValue>
                                    <name>0</name>
                                    <description>The MOSI output value is the last data of previous transfer.</description>
                                    <value>#0</value>
                                </enumeratedValue>
                                <enumeratedValue>
                                    <name>1</name>
                                    <description>The MOSI output value is the set MOIFV bit value.</description>
                                    <value>#1</value>
                                </enumeratedValue>
                            </enumeratedValues>
                        </field>
                    </fields>
                </register>
                <register>
                    <name>SPCR3</name>
                    <description>SPI Control Register 3</description>
                    <addressOffset>0x10</addressOffset>
                    <size>32</size>
                    <access>read-write</access>
                    <resetValue>0x0000ff00</resetValue>
                    <resetMask>0xffffffff</resetMask>
                    <fields>
                        <field>
                            <name>SSL0P</name>
                            <description>SSL0 Signal Polarity</description>
                            <lsb>0</lsb>
                            <msb>0</msb>
                            <access>read-write</access>
                            <enumeratedValues>
                                <enumeratedValue>
                                    <name>0</name>
                                    <description>The SSL0 signal is active low.</description>
                                    <value>#0</value>
                                </enumeratedValue>
                                <enumeratedValue>
                                    <name>1</name>
                                    <description>The SSL0 signal is active high.</description>
                                    <value>#1</value>
                                </enumeratedValue>
                            </enumeratedValues>
                        </field>
                        <field>
                            <name>SSL1P</name>
                            <description>SSL1 Signal Polarity</description>
                            <lsb>1</lsb>
                            <msb>1</msb>
                            <access>read-write</access>
                            <enumeratedValues>
                                <enumeratedValue>
                                    <name>0</name>
                                    <description>The SSL1 signal is active low.</description>
                                    <value>#0</value>
                                </enumeratedValue>
                                <enumeratedValue>
                                    <name>1</name>
                                    <description>The SSL1 signal is active high.</description>
                                    <value>#1</value>
                                </enumeratedValue>
                            </enumeratedValues>
                        </field>
                        <field>
                            <name>SSL2P</name>
                            <description>SSL2 Signal Polarity</description>
                            <lsb>2</lsb>
                            <msb>2</msb>
                            <access>read-write</access>
                            <enumeratedValues>
                                <enumeratedValue>
                                    <name>0</name>
                                    <description>The SSL2 signal is active low.</description>
                                    <value>#0</value>
                                </enumeratedValue>
                                <enumeratedValue>
                                    <name>1</name>
                                    <description>The SSL2 signal is active high.</description>
                                    <value>#1</value>
                                </enumeratedValue>
                            </enumeratedValues>
                        </field>
                        <field>
                            <name>SSL3P</name>
                            <description>SSL3 Signal Polarity</description>
                            <lsb>3</lsb>
                            <msb>3</msb>
                            <access>read-write</access>
                            <enumeratedValues>
                                <enumeratedValue>
                                    <name>0</name>
                                    <description>The SSL3 signal is active low.</description>
                                    <value>#0</value>
                                </enumeratedValue>
                                <enumeratedValue>
                                    <name>1</name>
                                    <description>The SSL3 signal is active high.</description>
                                    <value>#1</value>
                                </enumeratedValue>
                            </enumeratedValues>
                        </field>
                        <field>
                            <name>SPBR</name>
                            <description>SPI Bit Rate</description>
                            <lsb>8</lsb>
                            <msb>15</msb>
                            <access>read-write</access>
                        </field>
                        <field>
                            <name>SPSLN</name>
                            <description>SPI Sequence Length</description>
                            <lsb>24</lsb>
                            <msb>26</msb>
                            <access>read-write</access>
                            <enumeratedValues>
                                <enumeratedValue>
                                    <name>000</name>
                                    <description>Sequence Length is 1 (Referenced SPCMDn, n = 0→0→…)</description>
                                    <value>#000</value>
                                </enumeratedValue>
                                <enumeratedValue>
                                    <name>001</name>
                                    <description>Sequence Length is 2 (Referenced SPCMDn, n = 0→1→0→…)</description>
                                    <value>#001</value>
                                </enumeratedValue>
                                <enumeratedValue>
                                    <name>010</name>
                                    <description>Sequence Length is 3 (Referenced SPCMDn, n = 0→1→2→0→…)</description>
                                    <value>#010</value>
                                </enumeratedValue>
                                <enumeratedValue>
                                    <name>011</name>
                                    <description>Sequence Length is 4 (Referenced SPCMDn, n = 0→1→2→3→0→…)</description>
                                    <value>#011</value>
                                </enumeratedValue>
                                <enumeratedValue>
                                    <name>100</name>
                                    <description>Sequence Length is 5 (Referenced SPCMDn, n = 0→1→2→3→4→0→…)</description>
                                    <value>#100</value>
                                </enumeratedValue>
                                <enumeratedValue>
                                    <name>101</name>
                                    <description>Sequence Length is 6 (Referenced SPCMDn, n = 0→1→2→3→4→5→0→…)</description>
                                    <value>#101</value>
                                </enumeratedValue>
                                <enumeratedValue>
                                    <name>110</name>
                                    <description>Sequence Length is 7 (Referenced SPCMDn, n = 0→1→2→3→4→5→6→0→…)</description>
                                    <value>#110</value>
                                </enumeratedValue>
                                <enumeratedValue>
                                    <name>111</name>
                                    <description>Sequence Length is 8 (Referenced SPCMDn, n = 0→1→2→3→4→5→6→7→0→…)</description>
                                    <value>#111</value>
                                </enumeratedValue>
                            </enumeratedValues>
                        </field>
                    </fields>
                </register>
                <register>
                    <dim>8</dim>
                    <dimIncrement>0x04</dimIncrement>
                    <dimIndex>0-7</dimIndex>
                    <name>SPCMD%s</name>
                    <description>SPI Command Register</description>
                    <addressOffset>0x14</addressOffset>
                    <size>32</size>
                    <access>read-write</access>
                    <resetValue>0x00070000</resetValue>
                    <resetMask>0xffffffff</resetMask>
                    <fields>
                        <field>
                            <name>CPHA</name>
                            <description>RSPCK Phase</description>
                            <lsb>0</lsb>
                            <msb>0</msb>
                            <access>read-write</access>
                            <enumeratedValues>
                                <enumeratedValue>
                                    <name>0</name>
                                    <description>Data is sampled at an odd edge and changes at an even edge.</description>
                                    <value>#0</value>
                                </enumeratedValue>
                                <enumeratedValue>
                                    <name>1</name>
                                    <description>Data changes at an odd edge and is sampled at an even edge.</description>
                                    <value>#1</value>
                                </enumeratedValue>
                            </enumeratedValues>
                        </field>
                        <field>
                            <name>CPOL</name>
                            <description>RSPCK Polarity</description>
                            <lsb>1</lsb>
                            <msb>1</msb>
                            <access>read-write</access>
                            <enumeratedValues>
                                <enumeratedValue>
                                    <name>0</name>
                                    <description>RSPCK in idle state is 0.</description>
                                    <value>#0</value>
                                </enumeratedValue>
                                <enumeratedValue>
                                    <name>1</name>
                                    <description>RSPCK in idle state is 1.</description>
                                    <value>#1</value>
                                </enumeratedValue>
                            </enumeratedValues>
                        </field>
                        <field>
                            <name>BRDV</name>
                            <description>Bit Rate Division</description>
                            <lsb>2</lsb>
                            <msb>3</msb>
                            <access>read-write</access>
                            <enumeratedValues>
                                <enumeratedValue>
                                    <name>00</name>
                                    <description>Base bit rate</description>
                                    <value>#00</value>
                                </enumeratedValue>
                                <enumeratedValue>
                                    <name>01</name>
                                    <description>Base bit rate divided by 2</description>
                                    <value>#01</value>
                                </enumeratedValue>
                                <enumeratedValue>
                                    <name>10</name>
                                    <description>Base bit rate divided by 4</description>
                                    <value>#10</value>
                                </enumeratedValue>
                                <enumeratedValue>
                                    <name>11</name>
                                    <description>Base bit rate divided by 8</description>
                                    <value>#11</value>
                                </enumeratedValue>
                            </enumeratedValues>
                        </field>
                        <field>
                            <name>SSLKP</name>
                            <description>SSL Signal Level Hold</description>
                            <lsb>7</lsb>
                            <msb>7</msb>
                            <access>read-write</access>
                            <enumeratedValues>
                                <enumeratedValue>
                                    <name>0</name>
                                    <description>All SSL signals are negated at the end of transfer.</description>
                                    <value>#0</value>
                                </enumeratedValue>
                                <enumeratedValue>
                                    <name>1</name>
                                    <description>SSL signal level is held after the transfer ends until the next access starts.</description>
                                    <value>#1</value>
                                </enumeratedValue>
                            </enumeratedValues>
                        </field>
                        <field>
                            <name>LSBF</name>
                            <description>SPI LSB First</description>
                            <lsb>12</lsb>
                            <msb>12</msb>
                            <access>read-write</access>
                            <enumeratedValues>
                                <enumeratedValue>
                                    <name>0</name>
                                    <description>MSB first</description>
                                    <value>#0</value>
                                </enumeratedValue>
                                <enumeratedValue>
                                    <name>1</name>
                                    <description>LSB first</description>
                                    <value>#1</value>
                                </enumeratedValue>
                            </enumeratedValues>
                        </field>
                        <field>
                            <name>SPNDEN</name>
                            <description>SPI Next-Access Delay Enable</description>
                            <lsb>13</lsb>
                            <msb>13</msb>
                            <access>read-write</access>
                            <enumeratedValues>
                                <enumeratedValue>
                                    <name>0</name>
                                    <description>Next-access delay is 1RSPCK + 5TCLK</description>
                                    <value>#0</value>
                                </enumeratedValue>
                                <enumeratedValue>
                                    <name>1</name>
                                    <description>Next-access delay is the set value of the SPI next-access delay (SPDECR.SPNDL).</description>
                                    <value>#1</value>
                                </enumeratedValue>
                            </enumeratedValues>
                        </field>
                        <field>
                            <name>SLNDEN</name>
                            <description>SSL Negation Delay Setting Enable</description>
                            <lsb>14</lsb>
                            <msb>14</msb>
                            <access>read-write</access>
                            <enumeratedValues>
                                <enumeratedValue>
                                    <name>0</name>
                                    <description>[Master] SSL negation delay is 1RSPCK. [Slave in the TI-SSP] SSL negation delay is 1TCLK </description>
                                    <value>#0</value>
                                </enumeratedValue>
                                <enumeratedValue>
                                    <name>1</name>
                                    <description>SSL negation delay is the set value of the slave select negation delay (SPDECR.SLNDL).</description>
                                    <value>#1</value>
                                </enumeratedValue>
                            </enumeratedValues>
                        </field>
                        <field>
                            <name>SCKDEN</name>
                            <description>RSPCK Delay Setting Enable</description>
                            <lsb>15</lsb>
                            <msb>15</msb>
                            <access>read-write</access>
                            <enumeratedValues>
                                <enumeratedValue>
                                    <name>0</name>
                                    <description>RSPCK delay is 1 RSPCK.</description>
                                    <value>#0</value>
                                </enumeratedValue>
                                <enumeratedValue>
                                    <name>1</name>
                                    <description>RSPCK delay is the set value of the RSPCK delay (SPDECR.SCKDL).</description>
                                    <value>#1</value>
                                </enumeratedValue>
                            </enumeratedValues>
                        </field>
                        <field>
                            <name>SPB</name>
                            <description>SPI Data Length</description>
                            <lsb>16</lsb>
                            <msb>20</msb>
                            <access>read-write</access>
                        </field>
                        <field>
                            <name>SSLA</name>
                            <description>SSL Signal Assertion</description>
                            <lsb>24</lsb>
                            <msb>26</msb>
                            <access>read-write</access>
                            <enumeratedValues>
                                <enumeratedValue>
                                    <name>000</name>
                                    <description>SSL0</description>
                                    <value>#000</value>
                                </enumeratedValue>
                                <enumeratedValue>
                                    <name>001</name>
                                    <description>SSL1</description>
                                    <value>#001</value>
                                </enumeratedValue>
                                <enumeratedValue>
                                    <name>010</name>
                                    <description>SSL2</description>
                                    <value>#010</value>
                                </enumeratedValue>
                                <enumeratedValue>
                                    <name>011</name>
                                    <description>SSL3</description>
                                    <value>#011</value>
                                </enumeratedValue>
                                <enumeratedValue>
                                    <name>Others</name>
                                    <description>Setting prohibited</description>
                                    <isDefault>true</isDefault>
                                </enumeratedValue>
                            </enumeratedValues>
                        </field>
                    </fields>
                </register>
                <register>
                    <name>SPDCR</name>
                    <description>SPI Data Control Register</description>
                    <addressOffset>0x40</addressOffset>
                    <size>32</size>
                    <access>read-write</access>
                    <resetValue>0x00000000</resetValue>
                    <resetMask>0xffffffff</resetMask>
                    <fields>
                        <field>
                            <name>BYSW</name>
                            <description>Byte Swap Operating Mode Select</description>
                            <lsb>0</lsb>
                            <msb>0</msb>
                            <access>read-write</access>
                            <enumeratedValues>
                                <enumeratedValue>
                                    <name>0</name>
                                    <description>Byte Swap OFF</description>
                                    <value>#0</value>
                                </enumeratedValue>
                                <enumeratedValue>
                                    <name>1</name>
                                    <description>Byte Swap ON</description>
                                    <value>#1</value>
                                </enumeratedValue>
                            </enumeratedValues>
                        </field>
                        <field>
                            <name>SPRDTD</name>
                            <description>SPI Receive Data or Transmit Data Select</description>
                            <lsb>3</lsb>
                            <msb>3</msb>
                            <access>read-write</access>
                            <enumeratedValues>
                                <enumeratedValue>
                                    <name>0</name>
                                    <description>The SPDR reads the receive buffer.</description>
                                    <value>#0</value>
                                </enumeratedValue>
                                <enumeratedValue>
                                    <name>1</name>
                                    <description>The SPDR reads the transmit buffer</description>
                                    <value>#1</value>
                                </enumeratedValue>
                            </enumeratedValues>
                        </field>
                        <field>
                            <name>SINV</name>
                            <description>Serial data invert bit</description>
                            <lsb>4</lsb>
                            <msb>4</msb>
                            <access>read-write</access>
                            <enumeratedValues>
                                <enumeratedValue>
                                    <name>0</name>
                                    <description>Not invert serial data</description>
                                    <value>#0</value>
                                </enumeratedValue>
                                <enumeratedValue>
                                    <name>1</name>
                                    <description>Invert serial data.</description>
                                    <value>#1</value>
                                </enumeratedValue>
                            </enumeratedValues>
                        </field>
                        <field>
                            <name>SPFC</name>
                            <description>Frame Count</description>
                            <lsb>8</lsb>
                            <msb>9</msb>
                            <access>read-write</access>
                            <enumeratedValues>
                                <enumeratedValue>
                                    <name>00</name>
                                    <description>1 frame</description>
                                    <value>#00</value>
                                </enumeratedValue>
                                <enumeratedValue>
                                    <name>01</name>
                                    <description>2 frames</description>
                                    <value>#01</value>
                                </enumeratedValue>
                                <enumeratedValue>
                                    <name>10</name>
                                    <description>3 frames</description>
                                    <value>#10</value>
                                </enumeratedValue>
                                <enumeratedValue>
                                    <name>11</name>
                                    <description>4 frames</description>
                                    <value>#11</value>
                                </enumeratedValue>
                            </enumeratedValues>
                        </field>
                    </fields>
                </register>
                <register>
                    <name>SPDCR2</name>
                    <description>SPI Data Control Register 2</description>
                    <addressOffset>0x44</addressOffset>
                    <size>32</size>
                    <access>read-write</access>
                    <resetValue>0x00000000</resetValue>
                    <resetMask>0xffffffff</resetMask>
                    <fields>
                        <field>
                            <name>RTRG</name>
                            <description>Receive FIFO threshold setting</description>
                            <lsb>0</lsb>
                            <msb>1</msb>
                            <access>read-write</access>
                            <enumeratedValues>
                                <enumeratedValue>
                                    <name>00</name>
                                    <description>threshold 0</description>
                                    <value>#00</value>
                                </enumeratedValue>
                                <enumeratedValue>
                                    <name>01</name>
                                    <description>threshold 1</description>
                                    <value>#01</value>
                                </enumeratedValue>
                                <enumeratedValue>
                                    <name>10</name>
                                    <description>threshold 2</description>
                                    <value>#10</value>
                                </enumeratedValue>
                                <enumeratedValue>
                                    <name>11</name>
                                    <description>threshold 3</description>
                                    <value>#11</value>
                                </enumeratedValue>
                            </enumeratedValues>
                        </field>
                        <field>
                            <name>TTRG</name>
                            <description>Transmission FIFO threshold setting</description>
                            <lsb>8</lsb>
                            <msb>9</msb>
                            <access>read-write</access>
                            <enumeratedValues>
                                <enumeratedValue>
                                    <name>00</name>
                                    <description>threshold 0</description>
                                    <value>#00</value>
                                </enumeratedValue>
                                <enumeratedValue>
                                    <name>01</name>
                                    <description>threshold 1</description>
                                    <value>#01</value>
                                </enumeratedValue>
                                <enumeratedValue>
                                    <name>10</name>
                                    <description>threshold 2</description>
                                    <value>#10</value>
                                </enumeratedValue>
                                <enumeratedValue>
                                    <name>11</name>
                                    <description>threshold 3</description>
                                    <value>#11</value>
                                </enumeratedValue>
                            </enumeratedValues>
                        </field>
                    </fields>
                </register>
                <register>
                    <name>SPSR</name>
                    <description>SPI Status Register</description>
                    <addressOffset>0x50</addressOffset>
                    <size>32</size>
                    <access>read-only</access>
                    <resetValue>0x20000000</resetValue>
                    <resetMask>0xffffffff</resetMask>
                    <fields>
                        <field>
                            <name>SPCP</name>
                            <description>SPI Command Pointer</description>
                            <lsb>8</lsb>
                            <msb>10</msb>
                            <access>read-only</access>
                            <enumeratedValues>
                                <enumeratedValue>
                                    <name>000</name>
                                    <description>SPCMD0</description>
                                    <value>#000</value>
                                </enumeratedValue>
                                <enumeratedValue>
                                    <name>001</name>
                                    <description>SPCMD1</description>
                                    <value>#001</value>
                                </enumeratedValue>
                                <enumeratedValue>
                                    <name>010</name>
                                    <description>SPCMD2</description>
                                    <value>#010</value>
                                </enumeratedValue>
                                <enumeratedValue>
                                    <name>011</name>
                                    <description>SPCMD3</description>
                                    <value>#011</value>
                                </enumeratedValue>
                                <enumeratedValue>
                                    <name>100</name>
                                    <description>SPCMD4</description>
                                    <value>#100</value>
                                </enumeratedValue>
                                <enumeratedValue>
                                    <name>101</name>
                                    <description>SPCMD5</description>
                                    <value>#101</value>
                                </enumeratedValue>
                                <enumeratedValue>
                                    <name>110</name>
                                    <description>SPCMD6</description>
                                    <value>#110</value>
                                </enumeratedValue>
                                <enumeratedValue>
                                    <name>111</name>
                                    <description>SPCMD7</description>
                                    <value>#111</value>
                                </enumeratedValue>
                            </enumeratedValues>
                        </field>
                        <field>
                            <name>SPECM</name>
                            <description>SPI Error Command</description>
                            <lsb>12</lsb>
                            <msb>14</msb>
                            <access>read-only</access>
                            <enumeratedValues>
                                <enumeratedValue>
                                    <name>000</name>
                                    <description>SPCMD0</description>
                                    <value>#000</value>
                                </enumeratedValue>
                                <enumeratedValue>
                                    <name>001</name>
                                    <description>SPCMD1</description>
                                    <value>#001</value>
                                </enumeratedValue>
                                <enumeratedValue>
                                    <name>010</name>
                                    <description>SPCMD2</description>
                                    <value>#010</value>
                                </enumeratedValue>
                                <enumeratedValue>
                                    <name>011</name>
                                    <description>SPCMD3</description>
                                    <value>#011</value>
                                </enumeratedValue>
                                <enumeratedValue>
                                    <name>100</name>
                                    <description>SPCMD4</description>
                                    <value>#100</value>
                                </enumeratedValue>
                                <enumeratedValue>
                                    <name>101</name>
                                    <description>SPCMD5</description>
                                    <value>#101</value>
                                </enumeratedValue>
                                <enumeratedValue>
                                    <name>110</name>
                                    <description>SPCMD6</description>
                                    <value>#110</value>
                                </enumeratedValue>
                                <enumeratedValue>
                                    <name>111</name>
                                    <description>SPCMD7</description>
                                    <value>#111</value>
                                </enumeratedValue>
                            </enumeratedValues>
                        </field>
                        <field>
                            <name>SPDRF</name>
                            <description>SPI Receive Data Ready Flag</description>
                            <lsb>23</lsb>
                            <msb>23</msb>
                            <access>read-only</access>
                            <enumeratedValues>
                                <enumeratedValue>
                                    <name>0</name>
                                    <description>Receive data ready not detected</description>
                                    <value>#0</value>
                                </enumeratedValue>
                                <enumeratedValue>
                                    <name>1</name>
                                    <description>Receive data ready detected</description>
                                    <value>#1</value>
                                </enumeratedValue>
                            </enumeratedValues>
                        </field>
                        <field>
                            <name>OVRF</name>
                            <description>Overrun Error Flag</description>
                            <lsb>24</lsb>
                            <msb>24</msb>
                            <access>read-only</access>
                            <enumeratedValues>
                                <enumeratedValue>
                                    <name>0</name>
                                    <description>No overrun error is present.</description>
                                    <value>#0</value>
                                </enumeratedValue>
                                <enumeratedValue>
                                    <name>1</name>
                                    <description>An overrun error is present.</description>
                                    <value>#1</value>
                                </enumeratedValue>
                            </enumeratedValues>
                        </field>
                        <field>
                            <name>IDLNF</name>
                            <description>SPI Idle Flag</description>
                            <lsb>25</lsb>
                            <msb>25</msb>
                            <access>read-only</access>
                            <enumeratedValues>
                                <enumeratedValue>
                                    <name>0</name>
                                    <description>The SPI is in the idle state.</description>
                                    <value>#0</value>
                                </enumeratedValue>
                                <enumeratedValue>
                                    <name>1</name>
                                    <description>The SPI is in the transfer state.</description>
                                    <value>#1</value>
                                </enumeratedValue>
                            </enumeratedValues>
                        </field>
                        <field>
                            <name>MODF</name>
                            <description>Mode Fault Error Flag</description>
                            <lsb>26</lsb>
                            <msb>26</msb>
                            <access>read-only</access>
                            <enumeratedValues>
                                <enumeratedValue>
                                    <name>0</name>
                                    <description>Neither mode fault error nor underrun error is present.</description>
                                    <value>#0</value>
                                </enumeratedValue>
                                <enumeratedValue>
                                    <name>1</name>
                                    <description>A mode fault error or underrun error is present.</description>
                                    <value>#1</value>
                                </enumeratedValue>
                            </enumeratedValues>
                        </field>
                        <field>
                            <name>PERF</name>
                            <description>Parity Error Flag</description>
                            <lsb>27</lsb>
                            <msb>27</msb>
                            <access>read-only</access>
                            <enumeratedValues>
                                <enumeratedValue>
                                    <name>0</name>
                                    <description>No parity error is present.</description>
                                    <value>#0</value>
                                </enumeratedValue>
                                <enumeratedValue>
                                    <name>1</name>
                                    <description>A parity error is present.</description>
                                    <value>#1</value>
                                </enumeratedValue>
                            </enumeratedValues>
                        </field>
                        <field>
                            <name>UDRF</name>
                            <description>Underrun Error Flag</description>
                            <lsb>28</lsb>
                            <msb>28</msb>
                            <access>read-only</access>
                            <enumeratedValues>
                                <enumeratedValue>
                                    <name>0</name>
                                    <description>When MODF=0, neither mode fault error nor underrun error is present. When MODF=1, a mode fault error is present. </description>
                                    <value>#0</value>
                                </enumeratedValue>
                                <enumeratedValue>
                                    <name>1</name>
                                    <description>When MODF=0, neither mode fault error nor underrun error is present. When MODF=1, an underrun error is present. </description>
                                    <value>#1</value>
                                </enumeratedValue>
                            </enumeratedValues>
                        </field>
                        <field>
                            <name>SPTEF</name>
                            <description>SPI Transmit Buffer Empty Flag</description>
                            <lsb>29</lsb>
                            <msb>29</msb>
                            <access>read-only</access>
                            <enumeratedValues>
                                <enumeratedValue>
                                    <name>0</name>
                                    <description>The number of empty stages in the transmit FIFO ≤ the value set in SPDCR2.TTRG</description>
                                    <value>#0</value>
                                </enumeratedValue>
                                <enumeratedValue>
                                    <name>1</name>
                                    <description>The number of empty stages in the transmit FIFO &gt; the value set in SPDCR2.TTRG</description>
                                    <value>#1</value>
                                </enumeratedValue>
                            </enumeratedValues>
                        </field>
                        <field>
                            <name>CENDF</name>
                            <description>Communication End Flag</description>
                            <lsb>30</lsb>
                            <msb>30</msb>
                            <access>read-only</access>
                            <enumeratedValues>
                                <enumeratedValue>
                                    <name>0</name>
                                    <description>The SPI is not communicating or communicating.</description>
                                    <value>#0</value>
                                </enumeratedValue>
                                <enumeratedValue>
                                    <name>1</name>
                                    <description>The SPI communication completed.</description>
                                    <value>#1</value>
                                </enumeratedValue>
                            </enumeratedValues>
                        </field>
                        <field>
                            <name>SPRF</name>
                            <description>SPI Receive Buffer Full Flag</description>
                            <lsb>31</lsb>
                            <msb>31</msb>
                            <access>read-only</access>
                            <enumeratedValues>
                                <enumeratedValue>
                                    <name>0</name>
                                    <description>The number of data stored in the receive FIFO ≤ number of frames set by the SPDCR2.RTRG bit.</description>
                                    <value>#0</value>
                                </enumeratedValue>
                                <enumeratedValue>
                                    <name>1</name>
                                    <description>The number of data stored in the receive FIFO &gt; number of frames set by the SPDCR2.RTRG bit.</description>
                                    <value>#1</value>
                                </enumeratedValue>
                            </enumeratedValues>
                        </field>
                    </fields>
                </register>
                <register>
                    <name>SPTFSR</name>
                    <description>SPI Transfer FIFO Status Register</description>
                    <addressOffset>0x58</addressOffset>
                    <size>32</size>
                    <access>read-only</access>
                    <resetValue>0x00000000</resetValue>
                    <resetMask>0xffffffff</resetMask>
                    <fields>
                        <field>
                            <name>TFDN</name>
                            <description>Transmit FIFO data empty stage number</description>
                            <lsb>0</lsb>
                            <msb>2</msb>
                            <access>read-only</access>
                        </field>
                    </fields>
                </register>
                <register>
                    <name>SPRFSR</name>
                    <description>SPI Receive FIFO Status Register</description>
                    <addressOffset>0x5C</addressOffset>
                    <size>32</size>
                    <access>read-only</access>
                    <resetValue>0x00000004</resetValue>
                    <resetMask>0xffffffff</resetMask>
                    <fields>
                        <field>
                            <name>RFDN</name>
                            <description>Receive FIFO data store stage number</description>
                            <lsb>0</lsb>
                            <msb>2</msb>
                            <access>read-only</access>
                        </field>
                    </fields>
                </register>
                <register>
                    <name>SPPSR</name>
                    <description>SPI Polling Register</description>
                    <addressOffset>0x60</addressOffset>
                    <size>32</size>
                    <access>read-only</access>
                    <resetValue>0x00000000</resetValue>
                    <resetMask>0xffffffff</resetMask>
                    <fields>
                        <field>
                            <name>SPEPS</name>
                            <description>SPI Polling Status</description>
                            <lsb>0</lsb>
                            <msb>0</msb>
                            <access>read-only</access>
                            <enumeratedValues>
                                <enumeratedValue>
                                    <name>0</name>
                                    <description>SPCR.SPE is 0</description>
                                    <value>#0</value>
                                </enumeratedValue>
                                <enumeratedValue>
                                    <name>1</name>
                                    <description>SPCR.SPE is 1</description>
                                    <value>#1</value>
                                </enumeratedValue>
                            </enumeratedValues>
                        </field>
                    </fields>
                </register>
                <register>
                    <name>SPSRC</name>
                    <description>SPI Status Clear Register</description>
                    <addressOffset>0x68</addressOffset>
                    <size>32</size>
                    <access>write-only</access>
                    <resetValue>0x00000000</resetValue>
                    <resetMask>0xffffffff</resetMask>
                    <fields>
                        <field>
                            <name>SPDRFC</name>
                            <description>SPI Receive Data Ready Flag Clear</description>
                            <lsb>23</lsb>
                            <msb>23</msb>
                            <access>write-only</access>
                        </field>
                        <field>
                            <name>OVRFC</name>
                            <description>Overrun Error Flag Clear</description>
                            <lsb>24</lsb>
                            <msb>24</msb>
                            <access>write-only</access>
                        </field>
                        <field>
                            <name>MODFC</name>
                            <description>Mode Fault Error Flag Clear</description>
                            <lsb>26</lsb>
                            <msb>26</msb>
                            <access>write-only</access>
                        </field>
                        <field>
                            <name>PERFC</name>
                            <description>Parity Error Flag Clear</description>
                            <lsb>27</lsb>
                            <msb>27</msb>
                            <access>write-only</access>
                        </field>
                        <field>
                            <name>UDRFC</name>
                            <description>Underrun Error Flag Clear</description>
                            <lsb>28</lsb>
                            <msb>28</msb>
                            <access>write-only</access>
                        </field>
                        <field>
                            <name>SPTEFC</name>
                            <description>SPI Transmit Buffer Empty Flag Clear</description>
                            <lsb>29</lsb>
                            <msb>29</msb>
                            <access>write-only</access>
                        </field>
                        <field>
                            <name>CENDFC</name>
                            <description>Communication End Flag Clear</description>
                            <lsb>30</lsb>
                            <msb>30</msb>
                            <access>write-only</access>
                        </field>
                        <field>
                            <name>SPRFC</name>
                            <description>SPI Receive Buffer Full Flag Clear</description>
                            <lsb>31</lsb>
                            <msb>31</msb>
                            <access>write-only</access>
                        </field>
                    </fields>
                </register>
                <register>
                    <name>SPFCR</name>
                    <description>SPI FIFO Clear Register</description>
                    <addressOffset>0x6C</addressOffset>
                    <size>32</size>
                    <access>write-only</access>
                    <resetValue>0x00000000</resetValue>
                    <resetMask>0xffffffff</resetMask>
                    <fields>
                        <field>
                            <name>SPFRST</name>
                            <description>SPI FIFO clear</description>
                            <lsb>0</lsb>
                            <msb>0</msb>
                            <access>write-only</access>
                        </field>
                    </fields>
                </register>
            </registers>
        </peripheral>
        <peripheral derivedFrom="SPI0_B">
            <name>SPI1_B</name>
            <description>Serial Peripheral Interface 1</description>
            <baseAddress>0x4035C100</baseAddress>
        </peripheral>
        <peripheral>
            <name>ECCMB0</name>
            <description>Error Correction Circuit for MBRAMn</description>
            <baseAddress>0x4036F200</baseAddress>
            <addressBlock>
                <offset>0x00</offset>
                <size>6</size>
                <usage>registers</usage>
            </addressBlock>
            <addressBlock>
                <offset>0x0C</offset>
                <size>8</size>
                <usage>registers</usage>
            </addressBlock>
            <registers>
                <register>
                    <name>EC710CTL</name>
                    <description>ECC Control Register</description>
                    <addressOffset>0x00</addressOffset>
                    <size>32</size>
                    <access>read-write</access>
                    <resetValue>0x00000010</resetValue>
                    <resetMask>0xffffffff</resetMask>
                    <fields>
                        <field>
                            <name>ECEMF</name>
                            <description>ECC Error Message Flag</description>
                            <lsb>0</lsb>
                            <msb>0</msb>
                            <access>read-only</access>
                            <enumeratedValues>
                                <enumeratedValue>
                                    <name>0</name>
                                    <description>There is no bit error in present RAM output data</description>
                                    <value>#0</value>
                                </enumeratedValue>
                                <enumeratedValue>
                                    <name>1</name>
                                    <description>There is bit error in present RAM output data</description>
                                    <value>#1</value>
                                </enumeratedValue>
                            </enumeratedValues>
                        </field>
                        <field>
                            <name>ECER1F</name>
                            <description>ECC Error Detection and Correction Flag</description>
                            <lsb>1</lsb>
                            <msb>1</msb>
                            <access>read-only</access>
                            <enumeratedValues>
                                <enumeratedValue>
                                    <name>0</name>
                                    <description>After clearing this bit, 1-bit error correction has not occurred</description>
                                    <value>#0</value>
                                </enumeratedValue>
                                <enumeratedValue>
                                    <name>1</name>
                                    <description>1-bit error has occurred</description>
                                    <value>#1</value>
                                </enumeratedValue>
                            </enumeratedValues>
                        </field>
                        <field>
                            <name>ECER2F</name>
                            <description>2-bit ECC Error Detection Flag</description>
                            <lsb>2</lsb>
                            <msb>2</msb>
                            <access>read-only</access>
                            <enumeratedValues>
                                <enumeratedValue>
                                    <name>0</name>
                                    <description>After clearing this bit, 2-bit error has not occurred</description>
                                    <value>#0</value>
                                </enumeratedValue>
                                <enumeratedValue>
                                    <name>1</name>
                                    <description>2-bit error has occurred</description>
                                    <value>#1</value>
                                </enumeratedValue>
                            </enumeratedValues>
                        </field>
                        <field>
                            <name>EC1EDIC</name>
                            <description>ECC 1-bit Error Detection Interrupt Control</description>
                            <lsb>3</lsb>
                            <msb>3</msb>
                            <access>read-write</access>
                            <enumeratedValues>
                                <enumeratedValue>
                                    <name>0</name>
                                    <description>Disable 1-bit error detection interrupt request</description>
                                    <value>#0</value>
                                </enumeratedValue>
                                <enumeratedValue>
                                    <name>1</name>
                                    <description>Enable 1-bit error detection interrupt request</description>
                                    <value>#1</value>
                                </enumeratedValue>
                            </enumeratedValues>
                        </field>
                        <field>
                            <name>EC2EDIC</name>
                            <description>ECC 2-bit Error Detection Interrupt Control</description>
                            <lsb>4</lsb>
                            <msb>4</msb>
                            <access>read-write</access>
                            <enumeratedValues>
                                <enumeratedValue>
                                    <name>0</name>
                                    <description>Disable 2-bit error detection interrupt request</description>
                                    <value>#0</value>
                                </enumeratedValue>
                                <enumeratedValue>
                                    <name>1</name>
                                    <description>Enable 2-bit error detection interrupt request</description>
                                    <value>#1</value>
                                </enumeratedValue>
                            </enumeratedValues>
                        </field>
                        <field>
                            <name>EC1ECP</name>
                            <description>ECC 1-bit Error Correction Permission</description>
                            <lsb>5</lsb>
                            <msb>5</msb>
                            <access>read-write</access>
                            <enumeratedValues>
                                <enumeratedValue>
                                    <name>0</name>
                                    <description>At 1-bit error detection, the error correction is executed</description>
                                    <value>#0</value>
                                </enumeratedValue>
                                <enumeratedValue>
                                    <name>1</name>
                                    <description>At 1-bit error detection, the error correction is not executed</description>
                                    <value>#1</value>
                                </enumeratedValue>
                            </enumeratedValues>
                        </field>
                        <field>
                            <name>ECERVF</name>
                            <description>ECC Error Judgment Enable Flag</description>
                            <lsb>6</lsb>
                            <msb>6</msb>
                            <access>read-write</access>
                            <enumeratedValues>
                                <enumeratedValue>
                                    <name>0</name>
                                    <description>Error judgment disable</description>
                                    <value>#0</value>
                                </enumeratedValue>
                                <enumeratedValue>
                                    <name>1</name>
                                    <description>Error judgment enable</description>
                                    <value>#1</value>
                                </enumeratedValue>
                            </enumeratedValues>
                        </field>
                        <field>
                            <name>ECER1C</name>
                            <description>Accumulating ECC Error Detection and Correction Flag Clear</description>
                            <lsb>9</lsb>
                            <msb>9</msb>
                            <access>read-write</access>
                            <enumeratedValues>
                                <enumeratedValue>
                                    <name>0</name>
                                    <description>No effect</description>
                                    <value>#0</value>
                                </enumeratedValue>
                                <enumeratedValue>
                                    <name>1</name>
                                    <description>Clear accumulating ECC error detection and correction flag</description>
                                    <value>#1</value>
                                </enumeratedValue>
                            </enumeratedValues>
                        </field>
                        <field>
                            <name>ECER2C</name>
                            <description>2-bit ECC Error Detection Flag Clear</description>
                            <lsb>10</lsb>
                            <msb>10</msb>
                            <access>read-write</access>
                            <enumeratedValues>
                                <enumeratedValue>
                                    <name>0</name>
                                    <description>No effect</description>
                                    <value>#0</value>
                                </enumeratedValue>
                                <enumeratedValue>
                                    <name>1</name>
                                    <description>Clear 2-bit ECC error detection flag</description>
                                    <value>#1</value>
                                </enumeratedValue>
                            </enumeratedValues>
                        </field>
                        <field>
                            <name>ECOVFF</name>
                            <description>ECC Overflow Detection Flag</description>
                            <lsb>11</lsb>
                            <msb>11</msb>
                            <access>read-only</access>
                            <enumeratedValues>
                                <enumeratedValue>
                                    <name>0</name>
                                    <description>No effect</description>
                                    <value>#0</value>
                                </enumeratedValue>
                                <enumeratedValue>
                                    <name>1</name>
                                    <description>ECC overflow detection flag</description>
                                    <value>#1</value>
                                </enumeratedValue>
                            </enumeratedValues>
                        </field>
                        <field>
                            <name>EMCA</name>
                            <description>Access Control to ECC Mode Select bit</description>
                            <lsb>14</lsb>
                            <msb>15</msb>
                            <access>read-write</access>
                        </field>
                        <field>
                            <name>ECSEDF0</name>
                            <description>ECC Single bit Error Address Detection Flag</description>
                            <lsb>16</lsb>
                            <msb>16</msb>
                            <access>read-only</access>
                            <enumeratedValues>
                                <enumeratedValue>
                                    <name>0</name>
                                    <description>There is no bit error in EC710EAD0 after reset or clearing ECER1F bit</description>
                                    <value>#0</value>
                                </enumeratedValue>
                                <enumeratedValue>
                                    <name>1</name>
                                    <description>Address captured in EC710EAD0 shows that 1-bit error occurred and captured</description>
                                    <value>#1</value>
                                </enumeratedValue>
                            </enumeratedValues>
                        </field>
                        <field>
                            <name>ECDEDF0</name>
                            <description>ECC Dual Bit Error Address Detection Flag</description>
                            <lsb>17</lsb>
                            <msb>17</msb>
                            <access>read-only</access>
                            <enumeratedValues>
                                <enumeratedValue>
                                    <name>0</name>
                                    <description>There is no bit error in EC710EAD0 after reset or clearing ECER2F bit</description>
                                    <value>#0</value>
                                </enumeratedValue>
                                <enumeratedValue>
                                    <name>1</name>
                                    <description>Address captured in EC710EAD0 shows that 2-bit error occurred and captured</description>
                                    <value>#1</value>
                                </enumeratedValue>
                            </enumeratedValues>
                        </field>
                    </fields>
                </register>
                <register>
                    <name>EC710TMC</name>
                    <description>ECC Test Mode Control Register</description>
                    <addressOffset>0x04</addressOffset>
                    <size>16</size>
                    <access>read-write</access>
                    <resetValue>0x0000</resetValue>
                    <resetMask>0xffff</resetMask>
                    <fields>
                        <field>
                            <name>ECDCS</name>
                            <description>ECC Decode Input Select</description>
                            <lsb>1</lsb>
                            <msb>1</msb>
                            <access>read-write</access>
                            <enumeratedValues>
                                <enumeratedValue>
                                    <name>0</name>
                                    <description>Input lower 32 bits of RAM output data to data area of decode circuit</description>
                                    <value>#0</value>
                                </enumeratedValue>
                                <enumeratedValue>
                                    <name>1</name>
                                    <description>Input ECEDB31-0 in EC710TED register to data area of decode circuit</description>
                                    <value>#1</value>
                                </enumeratedValue>
                            </enumeratedValues>
                        </field>
                        <field>
                            <name>ECTMCE</name>
                            <description>ECC Test Mode Control Enable</description>
                            <lsb>7</lsb>
                            <msb>7</msb>
                            <access>read-write</access>
                            <enumeratedValues>
                                <enumeratedValue>
                                    <name>0</name>
                                    <description>The access to test mode register and bit is disabled</description>
                                    <value>#0</value>
                                </enumeratedValue>
                                <enumeratedValue>
                                    <name>1</name>
                                    <description>The access to test mode register and bit is enabled</description>
                                    <value>#1</value>
                                </enumeratedValue>
                            </enumeratedValues>
                        </field>
                        <field>
                            <name>ETMA</name>
                            <description>ECC Test Mode Bit Access Control</description>
                            <lsb>14</lsb>
                            <msb>15</msb>
                            <access>read-write</access>
                        </field>
                    </fields>
                </register>
                <register>
                    <name>EC710TED</name>
                    <description>ECC Test Substitute Data Register</description>
                    <addressOffset>0x0C</addressOffset>
                    <size>32</size>
                    <access>read-write</access>
                    <resetValue>0x00000000</resetValue>
                    <resetMask>0xffffffff</resetMask>
                    <fields>
                        <field>
                            <name>ECEDB</name>
                            <description>ECC Test Substitute Data</description>
                            <lsb>0</lsb>
                            <msb>31</msb>
                            <access>read-write</access>
                        </field>
                    </fields>
                </register>
                <register>
                    <name>EC710EAD0</name>
                    <description>ECC Error Address Register</description>
                    <addressOffset>0x10</addressOffset>
                    <size>32</size>
                    <access>read-only</access>
                    <resetValue>0x00000000</resetValue>
                    <resetMask>0xffffffff</resetMask>
                    <fields>
                        <field>
                            <name>ECEAD</name>
                            <description>ECC Error Address</description>
                            <lsb>0</lsb>
                            <msb>9</msb>
                            <access>read-only</access>
                        </field>
                    </fields>
                </register>
            </registers>
        </peripheral>
        <peripheral derivedFrom="ECCMB0">
            <name>ECCMB1</name>
            <description>Error Correction Circuit for MBRAMn</description>
            <baseAddress>0x4036F300</baseAddress>
        </peripheral>
        <peripheral>
            <name>CANFD0</name>
            <description>CANFD Module 0</description>
            <baseAddress>0x40380000</baseAddress>
            <addressBlock>
                <offset>0x00</offset>
                <size>16</size>
                <usage>registers</usage>
            </addressBlock>
            <addressBlock>
                <offset>0x14</offset>
                <size>34</size>
                <usage>registers</usage>
            </addressBlock>
            <addressBlock>
                <offset>0x38</offset>
                <size>2</size>
                <usage>registers</usage>
            </addressBlock>
            <addressBlock>
                <offset>0x3C</offset>
                <size>120</size>
                <usage>registers</usage>
            </addressBlock>
            <addressBlock>
                <offset>0xB8</offset>
                <size>4</size>
                <usage>registers</usage>
            </addressBlock>
            <addressBlock>
                <offset>0xC0</offset>
                <size>16</size>
                <usage>registers</usage>
            </addressBlock>
            <addressBlock>
                <offset>0xD8</offset>
                <size>4</size>
                <usage>registers</usage>
            </addressBlock>
            <addressBlock>
                <offset>0x100</offset>
                <size>20</size>
                <usage>registers</usage>
            </addressBlock>
            <addressBlock>
                <offset>0x120</offset>
                <size>268</size>
                <usage>registers</usage>
            </addressBlock>
            <addressBlock>
                <offset>0x280</offset>
                <size>256</size>
                <usage>registers</usage>
            </addressBlock>
            <addressBlock>
                <offset>0x520</offset>
                <size>604</size>
                <usage>registers</usage>
            </addressBlock>
            <addressBlock>
                <offset>0x920</offset>
                <size>680</size>
                <usage>registers</usage>
            </addressBlock>
            <addressBlock>
                <offset>0xD20</offset>
                <size>680</size>
                <usage>registers</usage>
            </addressBlock>
            <addressBlock>
                <offset>0x1124</offset>
                <size>676</size>
                <usage>registers</usage>
            </addressBlock>
            <addressBlock>
                <offset>0x1524</offset>
                <size>676</size>
                <usage>registers</usage>
            </addressBlock>
            <registers>
                <register>
                    <name>CFDC0NCFG</name>
                    <description>Nominal Bitrate Configuration Register</description>
                    <addressOffset>0x0000</addressOffset>
                    <size>32</size>
                    <access>read-write</access>
                    <resetValue>0x00000000</resetValue>
                    <resetMask>0xffffffff</resetMask>
                    <fields>
                        <field>
                            <name>NBRP</name>
                            <description>Channel Nominal Baud Rate Prescaler</description>
                            <lsb>0</lsb>
                            <msb>9</msb>
                            <access>read-write</access>
                        </field>
                        <field>
                            <name>NSJW</name>
                            <description>Resynchronization Jump Width</description>
                            <lsb>10</lsb>
                            <msb>16</msb>
                            <access>read-write</access>
                        </field>
                        <field>
                            <name>NTSEG1</name>
                            <description>Timing Segment 1</description>
                            <lsb>17</lsb>
                            <msb>24</msb>
                            <access>read-write</access>
                        </field>
                        <field>
                            <name>NTSEG2</name>
                            <description>Timing Segment 2</description>
                            <lsb>25</lsb>
                            <msb>31</msb>
                            <access>read-write</access>
                        </field>
                    </fields>
                </register>
                <register>
                    <name>CFDC0CTR</name>
                    <description>Control Register</description>
                    <addressOffset>0x0004</addressOffset>
                    <size>32</size>
                    <access>read-write</access>
                    <resetValue>0x00000005</resetValue>
                    <resetMask>0xffffffff</resetMask>
                    <fields>
                        <field>
                            <name>CHMDC</name>
                            <description>Channel Mode Control</description>
                            <lsb>0</lsb>
                            <msb>1</msb>
                            <access>read-write</access>
                            <enumeratedValues>
                                <enumeratedValue>
                                    <name>00</name>
                                    <description>Channel operation mode request</description>
                                    <value>#00</value>
                                </enumeratedValue>
                                <enumeratedValue>
                                    <name>01</name>
                                    <description>Channel reset request</description>
                                    <value>#01</value>
                                </enumeratedValue>
                                <enumeratedValue>
                                    <name>10</name>
                                    <description>Channel halt request</description>
                                    <value>#10</value>
                                </enumeratedValue>
                                <enumeratedValue>
                                    <name>11</name>
                                    <description>Keep current value</description>
                                    <value>#11</value>
                                </enumeratedValue>
                            </enumeratedValues>
                        </field>
                        <field>
                            <name>CSLPR</name>
                            <description>Channel Sleep Request</description>
                            <lsb>2</lsb>
                            <msb>2</msb>
                            <access>read-write</access>
                            <enumeratedValues>
                                <enumeratedValue>
                                    <name>0</name>
                                    <description>Channel sleep request disabled</description>
                                    <value>#0</value>
                                </enumeratedValue>
                                <enumeratedValue>
                                    <name>1</name>
                                    <description>Channel sleep request enabled</description>
                                    <value>#1</value>
                                </enumeratedValue>
                            </enumeratedValues>
                        </field>
                        <field>
                            <name>RTBO</name>
                            <description>Return from Bus-Off</description>
                            <lsb>3</lsb>
                            <msb>3</msb>
                            <access>read-write</access>
                            <enumeratedValues>
                                <enumeratedValue>
                                    <name>0</name>
                                    <description>Channel is not forced to return from bus-off</description>
                                    <value>#0</value>
                                </enumeratedValue>
                                <enumeratedValue>
                                    <name>1</name>
                                    <description>Channel is forced to return from bus-off</description>
                                    <value>#1</value>
                                </enumeratedValue>
                            </enumeratedValues>
                        </field>
                        <field>
                            <name>BEIE</name>
                            <description>Bus Error Interrupt Enable</description>
                            <lsb>8</lsb>
                            <msb>8</msb>
                            <access>read-write</access>
                            <enumeratedValues>
                                <enumeratedValue>
                                    <name>0</name>
                                    <description>Bus error interrupt disabled</description>
                                    <value>#0</value>
                                </enumeratedValue>
                                <enumeratedValue>
                                    <name>1</name>
                                    <description>Bus error interrupt enabled</description>
                                    <value>#1</value>
                                </enumeratedValue>
                            </enumeratedValues>
                        </field>
                        <field>
                            <name>EWIE</name>
                            <description>Error Warning Interrupt Enable</description>
                            <lsb>9</lsb>
                            <msb>9</msb>
                            <access>read-write</access>
                            <enumeratedValues>
                                <enumeratedValue>
                                    <name>0</name>
                                    <description>Error warning interrupt disabled</description>
                                    <value>#0</value>
                                </enumeratedValue>
                                <enumeratedValue>
                                    <name>1</name>
                                    <description>Error warning interrupt enabled</description>
                                    <value>#1</value>
                                </enumeratedValue>
                            </enumeratedValues>
                        </field>
                        <field>
                            <name>EPIE</name>
                            <description>Error Passive Interrupt Enable</description>
                            <lsb>10</lsb>
                            <msb>10</msb>
                            <access>read-write</access>
                            <enumeratedValues>
                                <enumeratedValue>
                                    <name>0</name>
                                    <description>Error passive interrupt disabled</description>
                                    <value>#0</value>
                                </enumeratedValue>
                                <enumeratedValue>
                                    <name>1</name>
                                    <description>Error passive interrupt enabled</description>
                                    <value>#1</value>
                                </enumeratedValue>
                            </enumeratedValues>
                        </field>
                        <field>
                            <name>BOEIE</name>
                            <description>Bus-Off Entry Interrupt Enable</description>
                            <lsb>11</lsb>
                            <msb>11</msb>
                            <access>read-write</access>
                            <enumeratedValues>
                                <enumeratedValue>
                                    <name>0</name>
                                    <description>Bus-off entry interrupt disabled</description>
                                    <value>#0</value>
                                </enumeratedValue>
                                <enumeratedValue>
                                    <name>1</name>
                                    <description>Bus-off entry interrupt enabled</description>
                                    <value>#1</value>
                                </enumeratedValue>
                            </enumeratedValues>
                        </field>
                        <field>
                            <name>BORIE</name>
                            <description>Bus-Off Recovery Interrupt Enable</description>
                            <lsb>12</lsb>
                            <msb>12</msb>
                            <access>read-write</access>
                            <enumeratedValues>
                                <enumeratedValue>
                                    <name>0</name>
                                    <description>Bus-off recovery interrupt disabled</description>
                                    <value>#0</value>
                                </enumeratedValue>
                                <enumeratedValue>
                                    <name>1</name>
                                    <description>Bus-off recovery interrupt enabled</description>
                                    <value>#1</value>
                                </enumeratedValue>
                            </enumeratedValues>
                        </field>
                        <field>
                            <name>OLIE</name>
                            <description>Overload Interrupt Enable</description>
                            <lsb>13</lsb>
                            <msb>13</msb>
                            <access>read-write</access>
                            <enumeratedValues>
                                <enumeratedValue>
                                    <name>0</name>
                                    <description>Overload interrupt disabled</description>
                                    <value>#0</value>
                                </enumeratedValue>
                                <enumeratedValue>
                                    <name>1</name>
                                    <description>Overload interrupt enabled</description>
                                    <value>#1</value>
                                </enumeratedValue>
                            </enumeratedValues>
                        </field>
                        <field>
                            <name>BLIE</name>
                            <description>Bus Lock Interrupt Enable</description>
                            <lsb>14</lsb>
                            <msb>14</msb>
                            <access>read-write</access>
                            <enumeratedValues>
                                <enumeratedValue>
                                    <name>0</name>
                                    <description>Bus lock interrupt disabled</description>
                                    <value>#0</value>
                                </enumeratedValue>
                                <enumeratedValue>
                                    <name>1</name>
                                    <description>Bus lock interrupt enabled</description>
                                    <value>#1</value>
                                </enumeratedValue>
                            </enumeratedValues>
                        </field>
                        <field>
                            <name>ALIE</name>
                            <description>Arbitration Lost Interrupt Enable</description>
                            <lsb>15</lsb>
                            <msb>15</msb>
                            <access>read-write</access>
                            <enumeratedValues>
                                <enumeratedValue>
                                    <name>0</name>
                                    <description>Arbitration lost interrupt disabled</description>
                                    <value>#0</value>
                                </enumeratedValue>
                                <enumeratedValue>
                                    <name>1</name>
                                    <description>Arbitration lost interrupt enabled</description>
                                    <value>#1</value>
                                </enumeratedValue>
                            </enumeratedValues>
                        </field>
                        <field>
                            <name>TAIE</name>
                            <description>Transmission Abort Interrupt Enable</description>
                            <lsb>16</lsb>
                            <msb>16</msb>
                            <access>read-write</access>
                            <enumeratedValues>
                                <enumeratedValue>
                                    <name>0</name>
                                    <description>TX abort interrupt disabled</description>
                                    <value>#0</value>
                                </enumeratedValue>
                                <enumeratedValue>
                                    <name>1</name>
                                    <description>TX abort interrupt enabled</description>
                                    <value>#1</value>
                                </enumeratedValue>
                            </enumeratedValues>
                        </field>
                        <field>
                            <name>EOCOIE</name>
                            <description>Error Occurrence Counter Overflow Interrupt Enable</description>
                            <lsb>17</lsb>
                            <msb>17</msb>
                            <access>read-write</access>
                            <enumeratedValues>
                                <enumeratedValue>
                                    <name>0</name>
                                    <description>Error occurrence counter overflow interrupt disabled</description>
                                    <value>#0</value>
                                </enumeratedValue>
                                <enumeratedValue>
                                    <name>1</name>
                                    <description>Error occurrence counter overflow interrupt enabled</description>
                                    <value>#1</value>
                                </enumeratedValue>
                            </enumeratedValues>
                        </field>
                        <field>
                            <name>SOCOIE</name>
                            <description>Successful Occurrence Counter Overflow Interrupt Enable</description>
                            <lsb>18</lsb>
                            <msb>18</msb>
                            <access>read-write</access>
                            <enumeratedValues>
                                <enumeratedValue>
                                    <name>0</name>
                                    <description>Successful occurrence counter overflow interrupt disabled</description>
                                    <value>#0</value>
                                </enumeratedValue>
                                <enumeratedValue>
                                    <name>1</name>
                                    <description>Successful occurrence counter overflow interrupt enabled</description>
                                    <value>#1</value>
                                </enumeratedValue>
                            </enumeratedValues>
                        </field>
                        <field>
                            <name>TDCVFIE</name>
                            <description>Transceiver Delay Compensation Violation Interrupt Enable</description>
                            <lsb>19</lsb>
                            <msb>19</msb>
                            <access>read-write</access>
                            <enumeratedValues>
                                <enumeratedValue>
                                    <name>0</name>
                                    <description>Transceiver delay compensation violation interrupt disabled</description>
                                    <value>#0</value>
                                </enumeratedValue>
                                <enumeratedValue>
                                    <name>1</name>
                                    <description>Transceiver delay compensation violation interrupt enabled</description>
                                    <value>#1</value>
                                </enumeratedValue>
                            </enumeratedValues>
                        </field>
                        <field>
                            <name>BOM</name>
                            <description>Channel Bus-Off Mode</description>
                            <lsb>21</lsb>
                            <msb>22</msb>
                            <access>read-write</access>
                            <enumeratedValues>
                                <enumeratedValue>
                                    <name>00</name>
                                    <description>Normal mode (comply with ISO 11898-1)</description>
                                    <value>#00</value>
                                </enumeratedValue>
                                <enumeratedValue>
                                    <name>01</name>
                                    <description>Entry to Halt mode automatically at bus-off start</description>
                                    <value>#01</value>
                                </enumeratedValue>
                                <enumeratedValue>
                                    <name>10</name>
                                    <description>Entry to Halt mode automatically at bus-off end</description>
                                    <value>#10</value>
                                </enumeratedValue>
                                <enumeratedValue>
                                    <name>11</name>
                                    <description>Entry to Halt mode (during bus-off recovery period) by software</description>
                                    <value>#11</value>
                                </enumeratedValue>
                            </enumeratedValues>
                        </field>
                        <field>
                            <name>ERRD</name>
                            <description>Channel Error Display</description>
                            <lsb>23</lsb>
                            <msb>23</msb>
                            <access>read-write</access>
                            <enumeratedValues>
                                <enumeratedValue>
                                    <name>0</name>
                                    <description>Only the first set of error codes displayed</description>
                                    <value>#0</value>
                                </enumeratedValue>
                                <enumeratedValue>
                                    <name>1</name>
                                    <description>Accumulated error codes displayed</description>
                                    <value>#1</value>
                                </enumeratedValue>
                            </enumeratedValues>
                        </field>
                        <field>
                            <name>CTME</name>
                            <description>Channel Test Mode Enable</description>
                            <lsb>24</lsb>
                            <msb>24</msb>
                            <access>read-write</access>
                            <enumeratedValues>
                                <enumeratedValue>
                                    <name>0</name>
                                    <description>Channel test mode disabled</description>
                                    <value>#0</value>
                                </enumeratedValue>
                                <enumeratedValue>
                                    <name>1</name>
                                    <description>Channel test mode enabled</description>
                                    <value>#1</value>
                                </enumeratedValue>
                            </enumeratedValues>
                        </field>
                        <field>
                            <name>CTMS</name>
                            <description>Channel Test Mode Select</description>
                            <lsb>25</lsb>
                            <msb>26</msb>
                            <access>read-write</access>
                            <enumeratedValues>
                                <enumeratedValue>
                                    <name>00</name>
                                    <description>Basic test mode</description>
                                    <value>#00</value>
                                </enumeratedValue>
                                <enumeratedValue>
                                    <name>01</name>
                                    <description>Listen-only mode</description>
                                    <value>#01</value>
                                </enumeratedValue>
                                <enumeratedValue>
                                    <name>10</name>
                                    <description>Self-test mode 0 (External loopback mode)</description>
                                    <value>#10</value>
                                </enumeratedValue>
                                <enumeratedValue>
                                    <name>11</name>
                                    <description>Self-test mode 1 (Internal loopback mode)</description>
                                    <value>#11</value>
                                </enumeratedValue>
                            </enumeratedValues>
                        </field>
                        <field>
                            <name>BFT</name>
                            <description>Bit Flip Test</description>
                            <lsb>30</lsb>
                            <msb>30</msb>
                            <access>read-write</access>
                            <enumeratedValues>
                                <enumeratedValue>
                                    <name>0</name>
                                    <description>First data bit of reception stream not inverted</description>
                                    <value>#0</value>
                                </enumeratedValue>
                                <enumeratedValue>
                                    <name>1</name>
                                    <description>First data bit of reception stream inverted</description>
                                    <value>#1</value>
                                </enumeratedValue>
                            </enumeratedValues>
                        </field>
                        <field>
                            <name>ROM</name>
                            <description>Restricted Operation Mode</description>
                            <lsb>31</lsb>
                            <msb>31</msb>
                            <access>read-write</access>
                            <enumeratedValues>
                                <enumeratedValue>
                                    <name>0</name>
                                    <description>Restricted operation mode disabled</description>
                                    <value>#0</value>
                                </enumeratedValue>
                                <enumeratedValue>
                                    <name>1</name>
                                    <description>Restricted operation mode enabled</description>
                                    <value>#1</value>
                                </enumeratedValue>
                            </enumeratedValues>
                        </field>
                    </fields>
                </register>
                <register>
                    <name>CFDC0STS</name>
                    <description>Status Register</description>
                    <addressOffset>0x0008</addressOffset>
                    <size>32</size>
                    <access>read-write</access>
                    <resetValue>0x00000005</resetValue>
                    <resetMask>0xffffffff</resetMask>
                    <fields>
                        <field>
                            <name>CRSTSTS</name>
                            <description>Channel Reset Status</description>
                            <lsb>0</lsb>
                            <msb>0</msb>
                            <access>read-only</access>
                            <enumeratedValues>
                                <enumeratedValue>
                                    <name>0</name>
                                    <description>Channel not in Reset mode</description>
                                    <value>#0</value>
                                </enumeratedValue>
                                <enumeratedValue>
                                    <name>1</name>
                                    <description>Channel in Reset mode</description>
                                    <value>#1</value>
                                </enumeratedValue>
                            </enumeratedValues>
                        </field>
                        <field>
                            <name>CHLTSTS</name>
                            <description>Channel Halt Status</description>
                            <lsb>1</lsb>
                            <msb>1</msb>
                            <access>read-only</access>
                            <enumeratedValues>
                                <enumeratedValue>
                                    <name>0</name>
                                    <description>Channel not in Halt mode</description>
                                    <value>#0</value>
                                </enumeratedValue>
                                <enumeratedValue>
                                    <name>1</name>
                                    <description>Channel in Halt mode</description>
                                    <value>#1</value>
                                </enumeratedValue>
                            </enumeratedValues>
                        </field>
                        <field>
                            <name>CSLPSTS</name>
                            <description>Channel Sleep Status</description>
                            <lsb>2</lsb>
                            <msb>2</msb>
                            <access>read-only</access>
                            <enumeratedValues>
                                <enumeratedValue>
                                    <name>0</name>
                                    <description>Channel not in Sleep mode</description>
                                    <value>#0</value>
                                </enumeratedValue>
                                <enumeratedValue>
                                    <name>1</name>
                                    <description>Channel in Sleep mode</description>
                                    <value>#1</value>
                                </enumeratedValue>
                            </enumeratedValues>
                        </field>
                        <field>
                            <name>EPSTS</name>
                            <description>Channel Error Passive Status</description>
                            <lsb>3</lsb>
                            <msb>3</msb>
                            <access>read-only</access>
                            <enumeratedValues>
                                <enumeratedValue>
                                    <name>0</name>
                                    <description>Channel not in error passive state</description>
                                    <value>#0</value>
                                </enumeratedValue>
                                <enumeratedValue>
                                    <name>1</name>
                                    <description>Channel in error passive state</description>
                                    <value>#1</value>
                                </enumeratedValue>
                            </enumeratedValues>
                        </field>
                        <field>
                            <name>BOSTS</name>
                            <description>Channel Bus-Off Status</description>
                            <lsb>4</lsb>
                            <msb>4</msb>
                            <access>read-only</access>
                            <enumeratedValues>
                                <enumeratedValue>
                                    <name>0</name>
                                    <description>Channel not in bus-off state</description>
                                    <value>#0</value>
                                </enumeratedValue>
                                <enumeratedValue>
                                    <name>1</name>
                                    <description>Channel in bus-off state</description>
                                    <value>#1</value>
                                </enumeratedValue>
                            </enumeratedValues>
                        </field>
                        <field>
                            <name>TRMSTS</name>
                            <description>Channel Transmit Status</description>
                            <lsb>5</lsb>
                            <msb>5</msb>
                            <access>read-only</access>
                            <enumeratedValues>
                                <enumeratedValue>
                                    <name>0</name>
                                    <description>Channel is not transmitting</description>
                                    <value>#0</value>
                                </enumeratedValue>
                                <enumeratedValue>
                                    <name>1</name>
                                    <description>Channel is transmitting</description>
                                    <value>#1</value>
                                </enumeratedValue>
                            </enumeratedValues>
                        </field>
                        <field>
                            <name>RECSTS</name>
                            <description>Channel Receive Status</description>
                            <lsb>6</lsb>
                            <msb>6</msb>
                            <access>read-only</access>
                            <enumeratedValues>
                                <enumeratedValue>
                                    <name>0</name>
                                    <description>Channel is not receiving</description>
                                    <value>#0</value>
                                </enumeratedValue>
                                <enumeratedValue>
                                    <name>1</name>
                                    <description>Channel is receiving</description>
                                    <value>#1</value>
                                </enumeratedValue>
                            </enumeratedValues>
                        </field>
                        <field>
                            <name>COMSTS</name>
                            <description>Channel Communication Status</description>
                            <lsb>7</lsb>
                            <msb>7</msb>
                            <access>read-only</access>
                            <enumeratedValues>
                                <enumeratedValue>
                                    <name>0</name>
                                    <description>Channel is not ready for communication</description>
                                    <value>#0</value>
                                </enumeratedValue>
                                <enumeratedValue>
                                    <name>1</name>
                                    <description>Channel is ready for communication</description>
                                    <value>#1</value>
                                </enumeratedValue>
                            </enumeratedValues>
                        </field>
                        <field>
                            <name>ESIF</name>
                            <description>Error State Indication Flag</description>
                            <lsb>8</lsb>
                            <msb>8</msb>
                            <access>read-write</access>
                            <enumeratedValues>
                                <enumeratedValue>
                                    <name>0</name>
                                    <description>No CANFD message has been received when the ESI flag was set</description>
                                    <value>#0</value>
                                </enumeratedValue>
                                <enumeratedValue>
                                    <name>1</name>
                                    <description>At least one CANFD message was received when the ESI flag was set</description>
                                    <value>#1</value>
                                </enumeratedValue>
                            </enumeratedValues>
                        </field>
                        <field>
                            <name>REC</name>
                            <description>Reception Error Count</description>
                            <lsb>16</lsb>
                            <msb>23</msb>
                            <access>read-only</access>
                        </field>
                        <field>
                            <name>TEC</name>
                            <description>Transmission Error Count</description>
                            <lsb>24</lsb>
                            <msb>31</msb>
                            <access>read-only</access>
                        </field>
                    </fields>
                </register>
                <register>
                    <name>CFDC0ERFL</name>
                    <description> Error Flag Register</description>
                    <addressOffset>0x000C</addressOffset>
                    <size>32</size>
                    <access>read-write</access>
                    <resetValue>0x00000000</resetValue>
                    <resetMask>0xffffffff</resetMask>
                    <fields>
                        <field>
                            <name>BEF</name>
                            <description>Bus Error Flag</description>
                            <lsb>0</lsb>
                            <msb>0</msb>
                            <access>read-write</access>
                            <enumeratedValues>
                                <enumeratedValue>
                                    <name>0</name>
                                    <description>Channel bus error not detected</description>
                                    <value>#0</value>
                                </enumeratedValue>
                                <enumeratedValue>
                                    <name>1</name>
                                    <description>Channel bus error detected</description>
                                    <value>#1</value>
                                </enumeratedValue>
                            </enumeratedValues>
                        </field>
                        <field>
                            <name>EWF</name>
                            <description>Error Warning Flag</description>
                            <lsb>1</lsb>
                            <msb>1</msb>
                            <access>read-write</access>
                            <enumeratedValues>
                                <enumeratedValue>
                                    <name>0</name>
                                    <description>Channel error warning not detected</description>
                                    <value>#0</value>
                                </enumeratedValue>
                                <enumeratedValue>
                                    <name>1</name>
                                    <description>Channel error warning detected</description>
                                    <value>#1</value>
                                </enumeratedValue>
                            </enumeratedValues>
                        </field>
                        <field>
                            <name>EPF</name>
                            <description>Error Passive Flag</description>
                            <lsb>2</lsb>
                            <msb>2</msb>
                            <access>read-write</access>
                            <enumeratedValues>
                                <enumeratedValue>
                                    <name>0</name>
                                    <description>Channel error passive not detected</description>
                                    <value>#0</value>
                                </enumeratedValue>
                                <enumeratedValue>
                                    <name>1</name>
                                    <description>Channel error passive detected</description>
                                    <value>#1</value>
                                </enumeratedValue>
                            </enumeratedValues>
                        </field>
                        <field>
                            <name>BOEF</name>
                            <description>Bus-Off Entry Flag</description>
                            <lsb>3</lsb>
                            <msb>3</msb>
                            <access>read-write</access>
                            <enumeratedValues>
                                <enumeratedValue>
                                    <name>0</name>
                                    <description>Channel bus-off entry not detected</description>
                                    <value>#0</value>
                                </enumeratedValue>
                                <enumeratedValue>
                                    <name>1</name>
                                    <description>Channel bus-off entry detected</description>
                                    <value>#1</value>
                                </enumeratedValue>
                            </enumeratedValues>
                        </field>
                        <field>
                            <name>BORF</name>
                            <description>Bus-Off Recovery Flag</description>
                            <lsb>4</lsb>
                            <msb>4</msb>
                            <access>read-write</access>
                            <enumeratedValues>
                                <enumeratedValue>
                                    <name>0</name>
                                    <description>Channel bus-off recovery not detected</description>
                                    <value>#0</value>
                                </enumeratedValue>
                                <enumeratedValue>
                                    <name>1</name>
                                    <description>Channel bus-off recovery detected</description>
                                    <value>#1</value>
                                </enumeratedValue>
                            </enumeratedValues>
                        </field>
                        <field>
                            <name>OVLF</name>
                            <description>Overload Flag</description>
                            <lsb>5</lsb>
                            <msb>5</msb>
                            <access>read-write</access>
                            <enumeratedValues>
                                <enumeratedValue>
                                    <name>0</name>
                                    <description>Channel overload not detected</description>
                                    <value>#0</value>
                                </enumeratedValue>
                                <enumeratedValue>
                                    <name>1</name>
                                    <description>Channel overload detected</description>
                                    <value>#1</value>
                                </enumeratedValue>
                            </enumeratedValues>
                        </field>
                        <field>
                            <name>BLF</name>
                            <description>Bus Lock Flag</description>
                            <lsb>6</lsb>
                            <msb>6</msb>
                            <access>read-write</access>
                            <enumeratedValues>
                                <enumeratedValue>
                                    <name>0</name>
                                    <description>Channel bus lock not detected</description>
                                    <value>#0</value>
                                </enumeratedValue>
                                <enumeratedValue>
                                    <name>1</name>
                                    <description>Channel bus lock detected</description>
                                    <value>#1</value>
                                </enumeratedValue>
                            </enumeratedValues>
                        </field>
                        <field>
                            <name>ALF</name>
                            <description>Arbitration Lost Flag</description>
                            <lsb>7</lsb>
                            <msb>7</msb>
                            <access>read-write</access>
                            <enumeratedValues>
                                <enumeratedValue>
                                    <name>0</name>
                                    <description>Channel arbitration lost not detected</description>
                                    <value>#0</value>
                                </enumeratedValue>
                                <enumeratedValue>
                                    <name>1</name>
                                    <description>Channel arbitration lost detected</description>
                                    <value>#1</value>
                                </enumeratedValue>
                            </enumeratedValues>
                        </field>
                        <field>
                            <name>SERR</name>
                            <description>Stuff Error</description>
                            <lsb>8</lsb>
                            <msb>8</msb>
                            <access>read-write</access>
                            <enumeratedValues>
                                <enumeratedValue>
                                    <name>0</name>
                                    <description>Channel stuff error not detected</description>
                                    <value>#0</value>
                                </enumeratedValue>
                                <enumeratedValue>
                                    <name>1</name>
                                    <description>Channel stuff error detected</description>
                                    <value>#1</value>
                                </enumeratedValue>
                            </enumeratedValues>
                        </field>
                        <field>
                            <name>FERR</name>
                            <description>Form Error</description>
                            <lsb>9</lsb>
                            <msb>9</msb>
                            <access>read-write</access>
                            <enumeratedValues>
                                <enumeratedValue>
                                    <name>0</name>
                                    <description>Channel form error not detected</description>
                                    <value>#0</value>
                                </enumeratedValue>
                                <enumeratedValue>
                                    <name>1</name>
                                    <description>Channel form error detected</description>
                                    <value>#1</value>
                                </enumeratedValue>
                            </enumeratedValues>
                        </field>
                        <field>
                            <name>AERR</name>
                            <description>Acknowledge Error</description>
                            <lsb>10</lsb>
                            <msb>10</msb>
                            <access>read-write</access>
                            <enumeratedValues>
                                <enumeratedValue>
                                    <name>0</name>
                                    <description>Channel acknowledge error not detected</description>
                                    <value>#0</value>
                                </enumeratedValue>
                                <enumeratedValue>
                                    <name>1</name>
                                    <description>Channel acknowledge error detected</description>
                                    <value>#1</value>
                                </enumeratedValue>
                            </enumeratedValues>
                        </field>
                        <field>
                            <name>CERR</name>
                            <description>CRC Error</description>
                            <lsb>11</lsb>
                            <msb>11</msb>
                            <access>read-write</access>
                            <enumeratedValues>
                                <enumeratedValue>
                                    <name>0</name>
                                    <description>Channel CRC error not detected</description>
                                    <value>#0</value>
                                </enumeratedValue>
                                <enumeratedValue>
                                    <name>1</name>
                                    <description>Channel CRC error detected</description>
                                    <value>#1</value>
                                </enumeratedValue>
                            </enumeratedValues>
                        </field>
                        <field>
                            <name>B1ERR</name>
                            <description>Bit 1 Error</description>
                            <lsb>12</lsb>
                            <msb>12</msb>
                            <access>read-write</access>
                            <enumeratedValues>
                                <enumeratedValue>
                                    <name>0</name>
                                    <description>Channel bit 1 error not detected</description>
                                    <value>#0</value>
                                </enumeratedValue>
                                <enumeratedValue>
                                    <name>1</name>
                                    <description>Channel bit 1 error detected</description>
                                    <value>#1</value>
                                </enumeratedValue>
                            </enumeratedValues>
                        </field>
                        <field>
                            <name>B0ERR</name>
                            <description>Bit 0 Error</description>
                            <lsb>13</lsb>
                            <msb>13</msb>
                            <access>read-write</access>
                            <enumeratedValues>
                                <enumeratedValue>
                                    <name>0</name>
                                    <description>Channel bit 0 error not detected</description>
                                    <value>#0</value>
                                </enumeratedValue>
                                <enumeratedValue>
                                    <name>1</name>
                                    <description>Channel bit 0 error detected</description>
                                    <value>#1</value>
                                </enumeratedValue>
                            </enumeratedValues>
                        </field>
                        <field>
                            <name>ADERR</name>
                            <description>Acknowledge Delimiter Error</description>
                            <lsb>14</lsb>
                            <msb>14</msb>
                            <access>read-write</access>
                            <enumeratedValues>
                                <enumeratedValue>
                                    <name>0</name>
                                    <description>Channel acknowledge delimiter error not detected</description>
                                    <value>#0</value>
                                </enumeratedValue>
                                <enumeratedValue>
                                    <name>1</name>
                                    <description>Channel acknowledge delimiter error detected</description>
                                    <value>#1</value>
                                </enumeratedValue>
                            </enumeratedValues>
                        </field>
                        <field>
                            <name>CRCREG</name>
                            <description>CRC Register value</description>
                            <lsb>16</lsb>
                            <msb>30</msb>
                            <access>read-only</access>
                        </field>
                    </fields>
                </register>
                <register>
                    <name>CFDGCFG</name>
                    <description>Global Configuration Register</description>
                    <addressOffset>0x0014</addressOffset>
                    <size>32</size>
                    <access>read-write</access>
                    <resetValue>0x00000000</resetValue>
                    <resetMask>0xffffffff</resetMask>
                    <fields>
                        <field>
                            <name>TPRI</name>
                            <description>Transmission Priority</description>
                            <lsb>0</lsb>
                            <msb>0</msb>
                            <access>read-write</access>
                            <enumeratedValues>
                                <enumeratedValue>
                                    <name>0</name>
                                    <description>ID priority</description>
                                    <value>#0</value>
                                </enumeratedValue>
                                <enumeratedValue>
                                    <name>1</name>
                                    <description>Message buffer number priority</description>
                                    <value>#1</value>
                                </enumeratedValue>
                            </enumeratedValues>
                        </field>
                        <field>
                            <name>DCE</name>
                            <description>DLC Check Enable</description>
                            <lsb>1</lsb>
                            <msb>1</msb>
                            <access>read-write</access>
                            <enumeratedValues>
                                <enumeratedValue>
                                    <name>0</name>
                                    <description>DLC check disabled</description>
                                    <value>#0</value>
                                </enumeratedValue>
                                <enumeratedValue>
                                    <name>1</name>
                                    <description>DLC check enabled</description>
                                    <value>#1</value>
                                </enumeratedValue>
                            </enumeratedValues>
                        </field>
                        <field>
                            <name>DRE</name>
                            <description>DLC Replacement Enable</description>
                            <lsb>2</lsb>
                            <msb>2</msb>
                            <access>read-write</access>
                            <enumeratedValues>
                                <enumeratedValue>
                                    <name>0</name>
                                    <description>DLC replacement disabled</description>
                                    <value>#0</value>
                                </enumeratedValue>
                                <enumeratedValue>
                                    <name>1</name>
                                    <description>DLC replacement enabled</description>
                                    <value>#1</value>
                                </enumeratedValue>
                            </enumeratedValues>
                        </field>
                        <field>
                            <name>MME</name>
                            <description>Mirror Mode Enable</description>
                            <lsb>3</lsb>
                            <msb>3</msb>
                            <access>read-write</access>
                            <enumeratedValues>
                                <enumeratedValue>
                                    <name>0</name>
                                    <description>Mirror mode disabled</description>
                                    <value>#0</value>
                                </enumeratedValue>
                                <enumeratedValue>
                                    <name>1</name>
                                    <description>Mirror mode enabled</description>
                                    <value>#1</value>
                                </enumeratedValue>
                            </enumeratedValues>
                        </field>
                        <field>
                            <name>DCS</name>
                            <description>Data Link Controller Clock Select</description>
                            <lsb>4</lsb>
                            <msb>4</msb>
                            <access>read-write</access>
                            <enumeratedValues>
                                <enumeratedValue>
                                    <name>0</name>
                                    <description>CANFD core clock (CANFDCLK)</description>
                                    <value>#0</value>
                                </enumeratedValue>
                                <enumeratedValue>
                                    <name>1</name>
                                    <description>External oscillator clock (CANMCLK)</description>
                                    <value>#1</value>
                                </enumeratedValue>
                            </enumeratedValues>
                        </field>
                        <field>
                            <name>CMPOC</name>
                            <description>CANFD Message Payload Overflow Configuration</description>
                            <lsb>5</lsb>
                            <msb>5</msb>
                            <access>read-write</access>
                            <enumeratedValues>
                                <enumeratedValue>
                                    <name>0</name>
                                    <description>Message is rejected</description>
                                    <value>#0</value>
                                </enumeratedValue>
                                <enumeratedValue>
                                    <name>1</name>
                                    <description>Message payload is cut to fit to configured message size</description>
                                    <value>#1</value>
                                </enumeratedValue>
                            </enumeratedValues>
                        </field>
                        <field>
                            <name>TSP</name>
                            <description>Timestamp Prescaler</description>
                            <lsb>8</lsb>
                            <msb>11</msb>
                            <access>read-write</access>
                        </field>
                        <field>
                            <name>TSSS</name>
                            <description>Timestamp Source Select</description>
                            <lsb>12</lsb>
                            <msb>12</msb>
                            <access>read-write</access>
                            <enumeratedValues>
                                <enumeratedValue>
                                    <name>0</name>
                                    <description>Source clock for timestamp counter is peripheral clock</description>
                                    <value>#0</value>
                                </enumeratedValue>
                                <enumeratedValue>
                                    <name>1</name>
                                    <description>Source clock for timestamp counter is bit time clock</description>
                                    <value>#1</value>
                                </enumeratedValue>
                            </enumeratedValues>
                        </field>
                        <field>
                            <name>ITRCP</name>
                            <description>Interval Timer Reference Clock Prescaler</description>
                            <lsb>16</lsb>
                            <msb>31</msb>
                            <access>read-write</access>
                        </field>
                    </fields>
                </register>
                <register>
                    <name>CFDGCTR</name>
                    <description>Global Control Register</description>
                    <addressOffset>0x0018</addressOffset>
                    <size>32</size>
                    <access>read-write</access>
                    <resetValue>0x00000005</resetValue>
                    <resetMask>0xffffffff</resetMask>
                    <fields>
                        <field>
                            <name>GMDC</name>
                            <description>Global Mode Control</description>
                            <lsb>0</lsb>
                            <msb>1</msb>
                            <access>read-write</access>
                            <enumeratedValues>
                                <enumeratedValue>
                                    <name>00</name>
                                    <description>Global operation mode request</description>
                                    <value>#00</value>
                                </enumeratedValue>
                                <enumeratedValue>
                                    <name>01</name>
                                    <description>Global reset mode request</description>
                                    <value>#01</value>
                                </enumeratedValue>
                                <enumeratedValue>
                                    <name>10</name>
                                    <description>Global halt mode request</description>
                                    <value>#10</value>
                                </enumeratedValue>
                                <enumeratedValue>
                                    <name>11</name>
                                    <description>Keep current value</description>
                                    <value>#11</value>
                                </enumeratedValue>
                            </enumeratedValues>
                        </field>
                        <field>
                            <name>GSLPR</name>
                            <description>Global Sleep Request</description>
                            <lsb>2</lsb>
                            <msb>2</msb>
                            <access>read-write</access>
                            <enumeratedValues>
                                <enumeratedValue>
                                    <name>0</name>
                                    <description>Global sleep request disabled</description>
                                    <value>#0</value>
                                </enumeratedValue>
                                <enumeratedValue>
                                    <name>1</name>
                                    <description>Global sleep request enabled</description>
                                    <value>#1</value>
                                </enumeratedValue>
                            </enumeratedValues>
                        </field>
                        <field>
                            <name>DEIE</name>
                            <description>DLC Check Interrupt Enable</description>
                            <lsb>8</lsb>
                            <msb>8</msb>
                            <access>read-write</access>
                            <enumeratedValues>
                                <enumeratedValue>
                                    <name>0</name>
                                    <description>DLC check interrupt disabled</description>
                                    <value>#0</value>
                                </enumeratedValue>
                                <enumeratedValue>
                                    <name>1</name>
                                    <description>DLC check interrupt enabled</description>
                                    <value>#1</value>
                                </enumeratedValue>
                            </enumeratedValues>
                        </field>
                        <field>
                            <name>MEIE</name>
                            <description>Message Lost Error Interrupt Enable</description>
                            <lsb>9</lsb>
                            <msb>9</msb>
                            <access>read-write</access>
                            <enumeratedValues>
                                <enumeratedValue>
                                    <name>0</name>
                                    <description>Message lost error interrupt disabled</description>
                                    <value>#0</value>
                                </enumeratedValue>
                                <enumeratedValue>
                                    <name>1</name>
                                    <description>Message lost error interrupt enabled</description>
                                    <value>#1</value>
                                </enumeratedValue>
                            </enumeratedValues>
                        </field>
                        <field>
                            <name>THLEIE</name>
                            <description>TX History List Entry Lost Interrupt Enable</description>
                            <lsb>10</lsb>
                            <msb>10</msb>
                            <access>read-write</access>
                            <enumeratedValues>
                                <enumeratedValue>
                                    <name>0</name>
                                    <description>TX history list entry lost interrupt disabled</description>
                                    <value>#0</value>
                                </enumeratedValue>
                                <enumeratedValue>
                                    <name>1</name>
                                    <description>TX history list entry lost interrupt enabled</description>
                                    <value>#1</value>
                                </enumeratedValue>
                            </enumeratedValues>
                        </field>
                        <field>
                            <name>CMPOFIE</name>
                            <description>CANFD Message Payload Overflow Flag Interrupt Enable</description>
                            <lsb>11</lsb>
                            <msb>11</msb>
                            <access>read-write</access>
                            <enumeratedValues>
                                <enumeratedValue>
                                    <name>0</name>
                                    <description>CANFD message payload overflow flag interrupt disabled</description>
                                    <value>#0</value>
                                </enumeratedValue>
                                <enumeratedValue>
                                    <name>1</name>
                                    <description>CANFD message payload overflow flag interrupt enabled</description>
                                    <value>#1</value>
                                </enumeratedValue>
                            </enumeratedValues>
                        </field>
                        <field>
                            <name>TSRST</name>
                            <description>Timestamp Reset</description>
                            <lsb>16</lsb>
                            <msb>16</msb>
                            <access>read-write</access>
                            <enumeratedValues>
                                <enumeratedValue>
                                    <name>0</name>
                                    <description>Timestamp not reset</description>
                                    <value>#0</value>
                                </enumeratedValue>
                                <enumeratedValue>
                                    <name>1</name>
                                    <description>Timestamp reset</description>
                                    <value>#1</value>
                                </enumeratedValue>
                            </enumeratedValues>
                        </field>
                    </fields>
                </register>
                <register>
                    <name>CFDGSTS</name>
                    <description>Global Status Register</description>
                    <addressOffset>0x001C</addressOffset>
                    <size>32</size>
                    <access>read-only</access>
                    <resetValue>0x0000000d</resetValue>
                    <resetMask>0xffffffff</resetMask>
                    <fields>
                        <field>
                            <name>GRSTSTS</name>
                            <description>Global Reset Status</description>
                            <lsb>0</lsb>
                            <msb>0</msb>
                            <access>read-only</access>
                            <enumeratedValues>
                                <enumeratedValue>
                                    <name>0</name>
                                    <description>Not in Reset mode</description>
                                    <value>#0</value>
                                </enumeratedValue>
                                <enumeratedValue>
                                    <name>1</name>
                                    <description>In Reset mode</description>
                                    <value>#1</value>
                                </enumeratedValue>
                            </enumeratedValues>
                        </field>
                        <field>
                            <name>GHLTSTS</name>
                            <description>Global Halt Status</description>
                            <lsb>1</lsb>
                            <msb>1</msb>
                            <access>read-only</access>
                            <enumeratedValues>
                                <enumeratedValue>
                                    <name>0</name>
                                    <description>Not in Halt mode</description>
                                    <value>#0</value>
                                </enumeratedValue>
                                <enumeratedValue>
                                    <name>1</name>
                                    <description>In Halt mode</description>
                                    <value>#1</value>
                                </enumeratedValue>
                            </enumeratedValues>
                        </field>
                        <field>
                            <name>GSLPSTS</name>
                            <description>Global Sleep Status</description>
                            <lsb>2</lsb>
                            <msb>2</msb>
                            <access>read-only</access>
                            <enumeratedValues>
                                <enumeratedValue>
                                    <name>0</name>
                                    <description>Not in Sleep mode</description>
                                    <value>#0</value>
                                </enumeratedValue>
                                <enumeratedValue>
                                    <name>1</name>
                                    <description>In Sleep mode</description>
                                    <value>#1</value>
                                </enumeratedValue>
                            </enumeratedValues>
                        </field>
                        <field>
                            <name>GRAMINIT</name>
                            <description>Global RAM Initialization</description>
                            <lsb>3</lsb>
                            <msb>3</msb>
                            <access>read-only</access>
                            <enumeratedValues>
                                <enumeratedValue>
                                    <name>0</name>
                                    <description>RAM initialization is complete</description>
                                    <value>#0</value>
                                </enumeratedValue>
                                <enumeratedValue>
                                    <name>1</name>
                                    <description>RAM initialization is ongoing</description>
                                    <value>#1</value>
                                </enumeratedValue>
                            </enumeratedValues>
                        </field>
                    </fields>
                </register>
                <register>
                    <name>CFDGERFL</name>
                    <description>Global Error Flag Register</description>
                    <addressOffset>0x0020</addressOffset>
                    <size>32</size>
                    <access>read-write</access>
                    <resetValue>0x00000000</resetValue>
                    <resetMask>0xffffffff</resetMask>
                    <fields>
                        <field>
                            <name>DEF</name>
                            <description>DLC Error Flag</description>
                            <lsb>0</lsb>
                            <msb>0</msb>
                            <access>read-write</access>
                            <enumeratedValues>
                                <enumeratedValue>
                                    <name>0</name>
                                    <description>DLC error not detected</description>
                                    <value>#0</value>
                                </enumeratedValue>
                                <enumeratedValue>
                                    <name>1</name>
                                    <description>DLC error detected</description>
                                    <value>#1</value>
                                </enumeratedValue>
                            </enumeratedValues>
                        </field>
                        <field>
                            <name>MES</name>
                            <description>Message Lost Error Status</description>
                            <lsb>1</lsb>
                            <msb>1</msb>
                            <access>read-only</access>
                            <enumeratedValues>
                                <enumeratedValue>
                                    <name>0</name>
                                    <description>Message lost error not detected</description>
                                    <value>#0</value>
                                </enumeratedValue>
                                <enumeratedValue>
                                    <name>1</name>
                                    <description>Message lost error detected</description>
                                    <value>#1</value>
                                </enumeratedValue>
                            </enumeratedValues>
                        </field>
                        <field>
                            <name>THLES</name>
                            <description>TX History List Entry Lost Error Status</description>
                            <lsb>2</lsb>
                            <msb>2</msb>
                            <access>read-only</access>
                            <enumeratedValues>
                                <enumeratedValue>
                                    <name>0</name>
                                    <description>TX history list entry lost error not detected</description>
                                    <value>#0</value>
                                </enumeratedValue>
                                <enumeratedValue>
                                    <name>1</name>
                                    <description>TX history list entry lost error detected</description>
                                    <value>#1</value>
                                </enumeratedValue>
                            </enumeratedValues>
                        </field>
                        <field>
                            <name>CMPOF</name>
                            <description>CANFD Message Payload Overflow Flag</description>
                            <lsb>3</lsb>
                            <msb>3</msb>
                            <access>read-write</access>
                            <enumeratedValues>
                                <enumeratedValue>
                                    <name>0</name>
                                    <description>CANFD message payload overflow not detected</description>
                                    <value>#0</value>
                                </enumeratedValue>
                                <enumeratedValue>
                                    <name>1</name>
                                    <description>CANFD message payload overflow detected</description>
                                    <value>#1</value>
                                </enumeratedValue>
                            </enumeratedValues>
                        </field>
                        <field>
                            <name>EEF0</name>
                            <description>ECC Error Flag</description>
                            <lsb>16</lsb>
                            <msb>16</msb>
                            <access>read-write</access>
                            <enumeratedValues>
                                <enumeratedValue>
                                    <name>0</name>
                                    <description>ECC error not detected during TX-SCAN</description>
                                    <value>#0</value>
                                </enumeratedValue>
                                <enumeratedValue>
                                    <name>1</name>
                                    <description>ECC error detected during TX-SCAN</description>
                                    <value>#1</value>
                                </enumeratedValue>
                            </enumeratedValues>
                        </field>
                    </fields>
                </register>
                <register>
                    <name>CFDGTSC</name>
                    <description>Global Timestamp Counter Register</description>
                    <addressOffset>0x0024</addressOffset>
                    <size>32</size>
                    <access>read-only</access>
                    <resetValue>0x00000000</resetValue>
                    <resetMask>0xffffffff</resetMask>
                    <fields>
                        <field>
                            <name>TS</name>
                            <description>Timestamp value</description>
                            <lsb>0</lsb>
                            <msb>15</msb>
                            <access>read-only</access>
                        </field>
                    </fields>
                </register>
                <register>
                    <name>CFDGAFLECTR</name>
                    <description>Global Acceptance Filter List Entry Control Register</description>
                    <addressOffset>0x0028</addressOffset>
                    <size>32</size>
                    <access>read-write</access>
                    <resetValue>0x00000000</resetValue>
                    <resetMask>0xffffffff</resetMask>
                    <fields>
                        <field>
                            <name>AFLDAE</name>
                            <description>Acceptance Filter List Data Access Enable</description>
                            <lsb>8</lsb>
                            <msb>8</msb>
                            <access>read-write</access>
                            <enumeratedValues>
                                <enumeratedValue>
                                    <name>0</name>
                                    <description>Acceptance Filter List data access disabled</description>
                                    <value>#0</value>
                                </enumeratedValue>
                                <enumeratedValue>
                                    <name>1</name>
                                    <description>Acceptance Filter List data access enabled</description>
                                    <value>#1</value>
                                </enumeratedValue>
                            </enumeratedValues>
                        </field>
                    </fields>
                </register>
                <register>
                    <name>CFDGAFLCFG</name>
                    <description>Global Acceptance Filter List Configuration Register</description>
                    <addressOffset>0x002C</addressOffset>
                    <size>32</size>
                    <access>read-write</access>
                    <resetValue>0x00000000</resetValue>
                    <resetMask>0xffffffff</resetMask>
                    <fields>
                        <field>
                            <name>RNC0</name>
                            <description>Rule Number</description>
                            <lsb>16</lsb>
                            <msb>20</msb>
                            <access>read-write</access>
                        </field>
                    </fields>
                </register>
                <register>
                    <name>CFDRMNB</name>
                    <description>RX Message Buffer Number Register</description>
                    <addressOffset>0x0030</addressOffset>
                    <size>32</size>
                    <access>read-write</access>
                    <resetValue>0x00000000</resetValue>
                    <resetMask>0xffffffff</resetMask>
                    <fields>
                        <field>
                            <name>NRXMB</name>
                            <description>Number of RX Message Buffers</description>
                            <lsb>0</lsb>
                            <msb>4</msb>
                            <access>read-write</access>
                        </field>
                        <field>
                            <name>RMPLS</name>
                            <description>Reception Message Buffer Payload Data Size</description>
                            <lsb>8</lsb>
                            <msb>10</msb>
                            <access>read-write</access>
                            <enumeratedValues>
                                <enumeratedValue>
                                    <name>000</name>
                                    <description>8 bytes</description>
                                    <value>#000</value>
                                </enumeratedValue>
                                <enumeratedValue>
                                    <name>001</name>
                                    <description>12 bytes</description>
                                    <value>#001</value>
                                </enumeratedValue>
                                <enumeratedValue>
                                    <name>010</name>
                                    <description>16 bytes</description>
                                    <value>#010</value>
                                </enumeratedValue>
                                <enumeratedValue>
                                    <name>011</name>
                                    <description>20 bytes</description>
                                    <value>#011</value>
                                </enumeratedValue>
                                <enumeratedValue>
                                    <name>100</name>
                                    <description>24 bytes</description>
                                    <value>#100</value>
                                </enumeratedValue>
                                <enumeratedValue>
                                    <name>101</name>
                                    <description>32 bytes</description>
                                    <value>#101</value>
                                </enumeratedValue>
                                <enumeratedValue>
                                    <name>110</name>
                                    <description>48 bytes</description>
                                    <value>#110</value>
                                </enumeratedValue>
                                <enumeratedValue>
                                    <name>111</name>
                                    <description>64 bytes</description>
                                    <value>#111</value>
                                </enumeratedValue>
                            </enumeratedValues>
                        </field>
                    </fields>
                </register>
                <register>
                    <name>CFDRMND</name>
                    <description>RX Message Buffer New Data Register</description>
                    <addressOffset>0x0034</addressOffset>
                    <size>16</size>
                    <access>read-write</access>
                    <resetValue>0x0000</resetValue>
                    <resetMask>0xffff</resetMask>
                    <fields>
                        <field>
                            <name>RMNS</name>
                            <description>RX Message Buffer New Data Status</description>
                            <lsb>0</lsb>
                            <msb>15</msb>
                            <access>read-write</access>
                            <enumeratedValues>
                                <enumeratedValue>
                                    <name>0</name>
                                    <description>New data not stored in corresponding RX message buffer</description>
                                    <value>#0</value>
                                </enumeratedValue>
                                <enumeratedValue>
                                    <name>1</name>
                                    <description>New data stored in corresponding RX message buffer</description>
                                    <value>#1</value>
                                </enumeratedValue>
                            </enumeratedValues>
                        </field>
                    </fields>
                </register>
                <register>
                    <name>CFDRMIEC</name>
                    <description>RX Message Buffer Interrupt Enable Configuration Register</description>
                    <addressOffset>0x0038</addressOffset>
                    <size>16</size>
                    <access>read-write</access>
                    <resetValue>0x0000</resetValue>
                    <resetMask>0xffff</resetMask>
                    <fields>
                        <field>
                            <name>RMIE</name>
                            <description>RX Message Buffer Interrupt Enable</description>
                            <lsb>0</lsb>
                            <msb>15</msb>
                            <access>read-write</access>
                            <enumeratedValues>
                                <enumeratedValue>
                                    <name>0</name>
                                    <description>RX Message Buffer Interrupt disabled for corresponding RX message buffer</description>
                                    <value>#0</value>
                                </enumeratedValue>
                                <enumeratedValue>
                                    <name>1</name>
                                    <description>RX Message Buffer Interrupt enabled for corresponding RX message buffer</description>
                                    <value>#1</value>
                                </enumeratedValue>
                            </enumeratedValues>
                        </field>
                    </fields>
                </register>
                <register>
                    <dim>2</dim>
                    <dimIncrement>0x04</dimIncrement>
                    <dimIndex>0-1</dimIndex>
                    <name>CFDRFCC%s</name>
                    <description>RX FIFO Configuration/Control Registers %s</description>
                    <addressOffset>0x003C</addressOffset>
                    <size>32</size>
                    <access>read-write</access>
                    <resetValue>0x00000000</resetValue>
                    <resetMask>0xffffffff</resetMask>
                    <fields>
                        <field>
                            <name>RFE</name>
                            <description>RX FIFO Enable</description>
                            <lsb>0</lsb>
                            <msb>0</msb>
                            <access>read-write</access>
                            <enumeratedValues>
                                <enumeratedValue>
                                    <name>0</name>
                                    <description>FIFO disabled</description>
                                    <value>#0</value>
                                </enumeratedValue>
                                <enumeratedValue>
                                    <name>1</name>
                                    <description>FIFO enabled</description>
                                    <value>#1</value>
                                </enumeratedValue>
                            </enumeratedValues>
                        </field>
                        <field>
                            <name>RFIE</name>
                            <description>RX FIFO Interrupt Enable</description>
                            <lsb>1</lsb>
                            <msb>1</msb>
                            <access>read-write</access>
                            <enumeratedValues>
                                <enumeratedValue>
                                    <name>0</name>
                                    <description>FIFO interrupt generation disabled</description>
                                    <value>#0</value>
                                </enumeratedValue>
                                <enumeratedValue>
                                    <name>1</name>
                                    <description>FIFO interrupt generation enabled</description>
                                    <value>#1</value>
                                </enumeratedValue>
                            </enumeratedValues>
                        </field>
                        <field>
                            <name>RFPLS</name>
                            <description>Rx FIFO Payload Data Size Configuration</description>
                            <lsb>4</lsb>
                            <msb>6</msb>
                            <access>read-write</access>
                            <enumeratedValues>
                                <enumeratedValue>
                                    <name>000</name>
                                    <description>8 bytes</description>
                                    <value>#000</value>
                                </enumeratedValue>
                                <enumeratedValue>
                                    <name>001</name>
                                    <description>12 bytes</description>
                                    <value>#001</value>
                                </enumeratedValue>
                                <enumeratedValue>
                                    <name>010</name>
                                    <description>16 bytes</description>
                                    <value>#010</value>
                                </enumeratedValue>
                                <enumeratedValue>
                                    <name>011</name>
                                    <description>20 bytes</description>
                                    <value>#011</value>
                                </enumeratedValue>
                                <enumeratedValue>
                                    <name>100</name>
                                    <description>24 bytes</description>
                                    <value>#100</value>
                                </enumeratedValue>
                                <enumeratedValue>
                                    <name>101</name>
                                    <description>32 bytes</description>
                                    <value>#101</value>
                                </enumeratedValue>
                                <enumeratedValue>
                                    <name>110</name>
                                    <description>48 bytes</description>
                                    <value>#110</value>
                                </enumeratedValue>
                                <enumeratedValue>
                                    <name>111</name>
                                    <description>64 bytes</description>
                                    <value>#111</value>
                                </enumeratedValue>
                            </enumeratedValues>
                        </field>
                        <field>
                            <name>RFDC</name>
                            <description>RX FIFO Depth Configuration</description>
                            <lsb>8</lsb>
                            <msb>10</msb>
                            <access>read-write</access>
                            <enumeratedValues>
                                <enumeratedValue>
                                    <name>000</name>
                                    <description>FIFO Depth = 0 message</description>
                                    <value>#000</value>
                                </enumeratedValue>
                                <enumeratedValue>
                                    <name>001</name>
                                    <description>FIFO Depth = 4 messages</description>
                                    <value>#001</value>
                                </enumeratedValue>
                                <enumeratedValue>
                                    <name>010</name>
                                    <description>FIFO Depth = 8 messages</description>
                                    <value>#010</value>
                                </enumeratedValue>
                                <enumeratedValue>
                                    <name>011</name>
                                    <description>FIFO Depth = 16 messages</description>
                                    <value>#011</value>
                                </enumeratedValue>
                                <enumeratedValue>
                                    <name>100</name>
                                    <description>FIFO Depth = 32 essages</description>
                                    <value>#100</value>
                                </enumeratedValue>
                                <enumeratedValue>
                                    <name>101</name>
                                    <description>FIFO Depth = 48 messages</description>
                                    <value>#101</value>
                                </enumeratedValue>
                                <enumeratedValue>
                                    <name>110</name>
                                    <description>Reserved</description>
                                    <value>#110</value>
                                </enumeratedValue>
                                <enumeratedValue>
                                    <name>111</name>
                                    <description>Reserved</description>
                                    <value>#111</value>
                                </enumeratedValue>
                            </enumeratedValues>
                        </field>
                        <field>
                            <name>RFIM</name>
                            <description>RX FIFO Interrupt Mode</description>
                            <lsb>12</lsb>
                            <msb>12</msb>
                            <access>read-write</access>
                            <enumeratedValues>
                                <enumeratedValue>
                                    <name>0</name>
                                    <description>Interrupt generated when RX FIFO counter reaches RFIGCV value from values smaller than RFIGCV</description>
                                    <value>#0</value>
                                </enumeratedValue>
                                <enumeratedValue>
                                    <name>1</name>
                                    <description>Interrupt generated at the end of every received message storage</description>
                                    <value>#1</value>
                                </enumeratedValue>
                            </enumeratedValues>
                        </field>
                        <field>
                            <name>RFIGCV</name>
                            <description>RX FIFO Interrupt Generation Counter Value</description>
                            <lsb>13</lsb>
                            <msb>15</msb>
                            <access>read-write</access>
                            <enumeratedValues>
                                <enumeratedValue>
                                    <name>000</name>
                                    <description>Interrupt generated when FIFO is 1/8th full</description>
                                    <value>#000</value>
                                </enumeratedValue>
                                <enumeratedValue>
                                    <name>001</name>
                                    <description>Interrupt generated when FIFO is 1/4th full</description>
                                    <value>#001</value>
                                </enumeratedValue>
                                <enumeratedValue>
                                    <name>010</name>
                                    <description>Interrupt generated when FIFO is 3/8th full</description>
                                    <value>#010</value>
                                </enumeratedValue>
                                <enumeratedValue>
                                    <name>011</name>
                                    <description>Interrupt generated when FIFO is 1/2 full</description>
                                    <value>#011</value>
                                </enumeratedValue>
                                <enumeratedValue>
                                    <name>100</name>
                                    <description>Interrupt generated when FIFO is 5/8th full</description>
                                    <value>#100</value>
                                </enumeratedValue>
                                <enumeratedValue>
                                    <name>101</name>
                                    <description>Interrupt generated when FIFO is 3/4th full</description>
                                    <value>#101</value>
                                </enumeratedValue>
                                <enumeratedValue>
                                    <name>110</name>
                                    <description>Interrupt generated when FIFO is 7/8th full</description>
                                    <value>#110</value>
                                </enumeratedValue>
                                <enumeratedValue>
                                    <name>111</name>
                                    <description>Interrupt generated when FIFO is full</description>
                                    <value>#111</value>
                                </enumeratedValue>
                            </enumeratedValues>
                        </field>
                    </fields>
                </register>
                <register>
                    <dim>2</dim>
                    <dimIncrement>0x04</dimIncrement>
                    <dimIndex>0-1</dimIndex>
                    <name>CFDRFSTS%s</name>
                    <description>RX FIFO Status Registers %s</description>
                    <addressOffset>0x0044</addressOffset>
                    <size>32</size>
                    <access>read-write</access>
                    <resetValue>0x00000001</resetValue>
                    <resetMask>0xffffffff</resetMask>
                    <fields>
                        <field>
                            <name>RFEMP</name>
                            <description>RX FIFO Empty</description>
                            <lsb>0</lsb>
                            <msb>0</msb>
                            <access>read-only</access>
                            <enumeratedValues>
                                <enumeratedValue>
                                    <name>0</name>
                                    <description>FIFO not empty</description>
                                    <value>#0</value>
                                </enumeratedValue>
                                <enumeratedValue>
                                    <name>1</name>
                                    <description>FIFO empty</description>
                                    <value>#1</value>
                                </enumeratedValue>
                            </enumeratedValues>
                        </field>
                        <field>
                            <name>RFFLL</name>
                            <description>RX FIFO Full</description>
                            <lsb>1</lsb>
                            <msb>1</msb>
                            <access>read-only</access>
                            <enumeratedValues>
                                <enumeratedValue>
                                    <name>0</name>
                                    <description>FIFO not full</description>
                                    <value>#0</value>
                                </enumeratedValue>
                                <enumeratedValue>
                                    <name>1</name>
                                    <description>FIFO full</description>
                                    <value>#1</value>
                                </enumeratedValue>
                            </enumeratedValues>
                        </field>
                        <field>
                            <name>RFMLT</name>
                            <description>RX FIFO Message Lost</description>
                            <lsb>2</lsb>
                            <msb>2</msb>
                            <access>read-write</access>
                            <enumeratedValues>
                                <enumeratedValue>
                                    <name>0</name>
                                    <description>No message lost in FIFO</description>
                                    <value>#0</value>
                                </enumeratedValue>
                                <enumeratedValue>
                                    <name>1</name>
                                    <description>FIFO message lost</description>
                                    <value>#1</value>
                                </enumeratedValue>
                            </enumeratedValues>
                        </field>
                        <field>
                            <name>RFIF</name>
                            <description>RX FIFO Interrupt Flag</description>
                            <lsb>3</lsb>
                            <msb>3</msb>
                            <access>read-write</access>
                            <enumeratedValues>
                                <enumeratedValue>
                                    <name>0</name>
                                    <description>FIFO interrupt condition not satisfied</description>
                                    <value>#0</value>
                                </enumeratedValue>
                                <enumeratedValue>
                                    <name>1</name>
                                    <description>FIFO interrupt condition satisfied</description>
                                    <value>#1</value>
                                </enumeratedValue>
                            </enumeratedValues>
                        </field>
                        <field>
                            <name>RFMC</name>
                            <description>RX FIFO Message Count</description>
                            <lsb>8</lsb>
                            <msb>13</msb>
                            <access>read-only</access>
                        </field>
                    </fields>
                </register>
                <register>
                    <dim>2</dim>
                    <dimIncrement>0x04</dimIncrement>
                    <dimIndex>0-1</dimIndex>
                    <name>CFDRFPCTR%s</name>
                    <description>RX FIFO Pointer Control Registers %s</description>
                    <addressOffset>0x004C</addressOffset>
                    <size>32</size>
                    <access>write-only</access>
                    <resetValue>0x00000000</resetValue>
                    <resetMask>0xffffffff</resetMask>
                    <fields>
                        <field>
                            <name>RFPC</name>
                            <description>RX FIFO Pointer Control</description>
                            <lsb>0</lsb>
                            <msb>7</msb>
                            <access>write-only</access>
                        </field>
                    </fields>
                </register>
                <register>
                    <name>CFDCFCC</name>
                    <description>Common FIFO Configuration/Control Register</description>
                    <addressOffset>0x0054</addressOffset>
                    <size>32</size>
                    <access>read-write</access>
                    <resetValue>0x00000000</resetValue>
                    <resetMask>0xffffffff</resetMask>
                    <fields>
                        <field>
                            <name>CFE</name>
                            <description>Common FIFO Enable</description>
                            <lsb>0</lsb>
                            <msb>0</msb>
                            <access>read-write</access>
                            <enumeratedValues>
                                <enumeratedValue>
                                    <name>0</name>
                                    <description>FIFO disabled</description>
                                    <value>#0</value>
                                </enumeratedValue>
                                <enumeratedValue>
                                    <name>1</name>
                                    <description>FIFO enabled</description>
                                    <value>#1</value>
                                </enumeratedValue>
                            </enumeratedValues>
                        </field>
                        <field>
                            <name>CFRXIE</name>
                            <description>Common FIFO RX Interrupt Enable</description>
                            <lsb>1</lsb>
                            <msb>1</msb>
                            <access>read-write</access>
                            <enumeratedValues>
                                <enumeratedValue>
                                    <name>0</name>
                                    <description>FIFO interrupt generation disabled for Frame RX</description>
                                    <value>#0</value>
                                </enumeratedValue>
                                <enumeratedValue>
                                    <name>1</name>
                                    <description>FIFO interrupt generation enabled for Frame RX</description>
                                    <value>#1</value>
                                </enumeratedValue>
                            </enumeratedValues>
                        </field>
                        <field>
                            <name>CFTXIE</name>
                            <description>Common FIFO TX Interrupt Enable</description>
                            <lsb>2</lsb>
                            <msb>2</msb>
                            <access>read-write</access>
                            <enumeratedValues>
                                <enumeratedValue>
                                    <name>0</name>
                                    <description>FIFO interrupt generation disabled for Frame TX</description>
                                    <value>#0</value>
                                </enumeratedValue>
                                <enumeratedValue>
                                    <name>1</name>
                                    <description>FIFO interrupt generation enabled for Frame TX</description>
                                    <value>#1</value>
                                </enumeratedValue>
                            </enumeratedValues>
                        </field>
                        <field>
                            <name>CFPLS</name>
                            <description>Common FIFO Payload Data Size Configuration</description>
                            <lsb>4</lsb>
                            <msb>6</msb>
                            <access>read-write</access>
                            <enumeratedValues>
                                <enumeratedValue>
                                    <name>000</name>
                                    <description>8 bytes</description>
                                    <value>#000</value>
                                </enumeratedValue>
                                <enumeratedValue>
                                    <name>001</name>
                                    <description>12 bytes</description>
                                    <value>#001</value>
                                </enumeratedValue>
                                <enumeratedValue>
                                    <name>010</name>
                                    <description>16 bytes</description>
                                    <value>#010</value>
                                </enumeratedValue>
                                <enumeratedValue>
                                    <name>011</name>
                                    <description>20 bytes</description>
                                    <value>#011</value>
                                </enumeratedValue>
                                <enumeratedValue>
                                    <name>100</name>
                                    <description>24 bytes</description>
                                    <value>#100</value>
                                </enumeratedValue>
                                <enumeratedValue>
                                    <name>101</name>
                                    <description>32 bytes</description>
                                    <value>#101</value>
                                </enumeratedValue>
                                <enumeratedValue>
                                    <name>110</name>
                                    <description>48 bytes</description>
                                    <value>#110</value>
                                </enumeratedValue>
                                <enumeratedValue>
                                    <name>111</name>
                                    <description>64 bytes</description>
                                    <value>#111</value>
                                </enumeratedValue>
                            </enumeratedValues>
                        </field>
                        <field>
                            <name>CFM</name>
                            <description>Common FIFO Mode</description>
                            <lsb>8</lsb>
                            <msb>8</msb>
                            <access>read-write</access>
                            <enumeratedValues>
                                <enumeratedValue>
                                    <name>0</name>
                                    <description>RX FIFO mode</description>
                                    <value>#0</value>
                                </enumeratedValue>
                                <enumeratedValue>
                                    <name>1</name>
                                    <description>TX FIFO mode</description>
                                    <value>#1</value>
                                </enumeratedValue>
                            </enumeratedValues>
                        </field>
                        <field>
                            <name>CFITSS</name>
                            <description>Common FIFO Interval Timer Source Select</description>
                            <lsb>10</lsb>
                            <msb>10</msb>
                            <access>read-write</access>
                            <enumeratedValues>
                                <enumeratedValue>
                                    <name>0</name>
                                    <description>Reference clock (× 1 / × 10 period)</description>
                                    <value>#0</value>
                                </enumeratedValue>
                                <enumeratedValue>
                                    <name>1</name>
                                    <description>Bit time clock of related channel (FIFO is linked to fixed channel)</description>
                                    <value>#1</value>
                                </enumeratedValue>
                            </enumeratedValues>
                        </field>
                        <field>
                            <name>CFITR</name>
                            <description>Common FIFO Interval Timer Resolution</description>
                            <lsb>11</lsb>
                            <msb>11</msb>
                            <access>read-write</access>
                            <enumeratedValues>
                                <enumeratedValue>
                                    <name>0</name>
                                    <description>Reference clock period × 1</description>
                                    <value>#0</value>
                                </enumeratedValue>
                                <enumeratedValue>
                                    <name>1</name>
                                    <description>Reference clock period × 10</description>
                                    <value>#1</value>
                                </enumeratedValue>
                            </enumeratedValues>
                        </field>
                        <field>
                            <name>CFIM</name>
                            <description>Common FIFO Interrupt Mode</description>
                            <lsb>12</lsb>
                            <msb>12</msb>
                            <access>read-write</access>
                            <enumeratedValues>
                                <enumeratedValue>
                                    <name>0</name>
                                    <description>RX FIFO mode: RX interrupt generated when Common FIFO counter reaches CFIGCV value from a lower value TX FIFO mode: TX interrupt generated when Common FIFO transmits the last message successfully </description>
                                    <value>#0</value>
                                </enumeratedValue>
                                <enumeratedValue>
                                    <name>1</name>
                                    <description>RX FIFO mode: RX interrupt generated at the end of every received message storage TX FIFO mode: interrupt generated for every successfully transmitted message </description>
                                    <value>#1</value>
                                </enumeratedValue>
                            </enumeratedValues>
                        </field>
                        <field>
                            <name>CFIGCV</name>
                            <description>Common FIFO Interrupt Generation Counter Value</description>
                            <lsb>13</lsb>
                            <msb>15</msb>
                            <access>read-write</access>
                            <enumeratedValues>
                                <enumeratedValue>
                                    <name>000</name>
                                    <description>Interrupt generated when FIFO is 1/8th full</description>
                                    <value>#000</value>
                                </enumeratedValue>
                                <enumeratedValue>
                                    <name>001</name>
                                    <description>Interrupt generated when FIFO is 1/4th full</description>
                                    <value>#001</value>
                                </enumeratedValue>
                                <enumeratedValue>
                                    <name>010</name>
                                    <description>Interrupt generated when FIFO is 3/8th full</description>
                                    <value>#010</value>
                                </enumeratedValue>
                                <enumeratedValue>
                                    <name>011</name>
                                    <description>Interrupt generated when FIFO is 1/2 full</description>
                                    <value>#011</value>
                                </enumeratedValue>
                                <enumeratedValue>
                                    <name>100</name>
                                    <description>Interrupt generated when FIFO is 5/8th full</description>
                                    <value>#100</value>
                                </enumeratedValue>
                                <enumeratedValue>
                                    <name>101</name>
                                    <description>Interrupt generated when FIFO is 3/4th full</description>
                                    <value>#101</value>
                                </enumeratedValue>
                                <enumeratedValue>
                                    <name>110</name>
                                    <description>Interrupt generated when FIFO is 7/8th full</description>
                                    <value>#110</value>
                                </enumeratedValue>
                                <enumeratedValue>
                                    <name>111</name>
                                    <description>Interrupt generated when FIFO is full</description>
                                    <value>#111</value>
                                </enumeratedValue>
                            </enumeratedValues>
                        </field>
                        <field>
                            <name>CFTML</name>
                            <description>Common FIFO TX Message Buffer Link</description>
                            <lsb>16</lsb>
                            <msb>17</msb>
                            <access>read-write</access>
                        </field>
                        <field>
                            <name>CFDC</name>
                            <description>Common FIFO Depth Configuration</description>
                            <lsb>21</lsb>
                            <msb>23</msb>
                            <access>read-write</access>
                            <enumeratedValues>
                                <enumeratedValue>
                                    <name>000</name>
                                    <description>FIFO Depth = 0 message</description>
                                    <value>#000</value>
                                </enumeratedValue>
                                <enumeratedValue>
                                    <name>001</name>
                                    <description>FIFO Depth = 4 messages</description>
                                    <value>#001</value>
                                </enumeratedValue>
                                <enumeratedValue>
                                    <name>010</name>
                                    <description>FIFO Depth = 8 messages</description>
                                    <value>#010</value>
                                </enumeratedValue>
                                <enumeratedValue>
                                    <name>011</name>
                                    <description>FIFO Depth = 16 messages</description>
                                    <value>#011</value>
                                </enumeratedValue>
                                <enumeratedValue>
                                    <name>100</name>
                                    <description>FIFO Depth = 32 messages</description>
                                    <value>#100</value>
                                </enumeratedValue>
                                <enumeratedValue>
                                    <name>101</name>
                                    <description>FIFO Depth = 48 messages</description>
                                    <value>#101</value>
                                </enumeratedValue>
                                <enumeratedValue>
                                    <name>110</name>
                                    <description>FIFO Depth = Reserved</description>
                                    <value>#110</value>
                                </enumeratedValue>
                                <enumeratedValue>
                                    <name>111</name>
                                    <description>FIFO Depth = Reserved</description>
                                    <value>#111</value>
                                </enumeratedValue>
                            </enumeratedValues>
                        </field>
                        <field>
                            <name>CFITT</name>
                            <description>Common FIFO Interval Transmission Time</description>
                            <lsb>24</lsb>
                            <msb>31</msb>
                            <access>read-write</access>
                        </field>
                    </fields>
                </register>
                <register>
                    <name>CFDCFSTS</name>
                    <description>Common FIFO Status Register</description>
                    <addressOffset>0x0058</addressOffset>
                    <size>32</size>
                    <access>read-write</access>
                    <resetValue>0x00000001</resetValue>
                    <resetMask>0xffffffff</resetMask>
                    <fields>
                        <field>
                            <name>CFEMP</name>
                            <description>Common FIFO Empty</description>
                            <lsb>0</lsb>
                            <msb>0</msb>
                            <access>read-only</access>
                            <enumeratedValues>
                                <enumeratedValue>
                                    <name>0</name>
                                    <description>FIFO not empty</description>
                                    <value>#0</value>
                                </enumeratedValue>
                                <enumeratedValue>
                                    <name>1</name>
                                    <description>FIFO empty</description>
                                    <value>#1</value>
                                </enumeratedValue>
                            </enumeratedValues>
                        </field>
                        <field>
                            <name>CFFLL</name>
                            <description>Common FIFO Full</description>
                            <lsb>1</lsb>
                            <msb>1</msb>
                            <access>read-only</access>
                            <enumeratedValues>
                                <enumeratedValue>
                                    <name>0</name>
                                    <description>FIFO not full</description>
                                    <value>#0</value>
                                </enumeratedValue>
                                <enumeratedValue>
                                    <name>1</name>
                                    <description>FIFO full</description>
                                    <value>#1</value>
                                </enumeratedValue>
                            </enumeratedValues>
                        </field>
                        <field>
                            <name>CFMLT</name>
                            <description>Common FIFO Message Lost</description>
                            <lsb>2</lsb>
                            <msb>2</msb>
                            <access>read-write</access>
                            <enumeratedValues>
                                <enumeratedValue>
                                    <name>0</name>
                                    <description>Number of message lost in FIFO</description>
                                    <value>#0</value>
                                </enumeratedValue>
                                <enumeratedValue>
                                    <name>1</name>
                                    <description>FIFO message lost</description>
                                    <value>#1</value>
                                </enumeratedValue>
                            </enumeratedValues>
                        </field>
                        <field>
                            <name>CFRXIF</name>
                            <description>Common RX FIFO Interrupt Flag</description>
                            <lsb>3</lsb>
                            <msb>3</msb>
                            <access>read-write</access>
                            <enumeratedValues>
                                <enumeratedValue>
                                    <name>0</name>
                                    <description>FIFO interrupt condition not satisfied after frame reception</description>
                                    <value>#0</value>
                                </enumeratedValue>
                                <enumeratedValue>
                                    <name>1</name>
                                    <description>FIFO interrupt condition satisfied after frame reception</description>
                                    <value>#1</value>
                                </enumeratedValue>
                            </enumeratedValues>
                        </field>
                        <field>
                            <name>CFTXIF</name>
                            <description>Common TX FIFO Interrupt Flag</description>
                            <lsb>4</lsb>
                            <msb>4</msb>
                            <access>read-write</access>
                            <enumeratedValues>
                                <enumeratedValue>
                                    <name>0</name>
                                    <description>FIFO interrupt condition not satisfied after frame transmission</description>
                                    <value>#0</value>
                                </enumeratedValue>
                                <enumeratedValue>
                                    <name>1</name>
                                    <description>FIFO Interrupt condition satisfied after frame transmission</description>
                                    <value>#1</value>
                                </enumeratedValue>
                            </enumeratedValues>
                        </field>
                        <field>
                            <name>CFMC</name>
                            <description>Common FIFO Message Count</description>
                            <lsb>8</lsb>
                            <msb>13</msb>
                            <access>read-only</access>
                        </field>
                    </fields>
                </register>
                <register>
                    <name>CFDCFPCTR</name>
                    <description>Common FIFO Pointer Control Register</description>
                    <addressOffset>0x005C</addressOffset>
                    <size>32</size>
                    <access>write-only</access>
                    <resetValue>0x00000000</resetValue>
                    <resetMask>0xffffffff</resetMask>
                    <fields>
                        <field>
                            <name>CFPC</name>
                            <description>Common FIFO Pointer Control</description>
                            <lsb>0</lsb>
                            <msb>7</msb>
                            <access>write-only</access>
                        </field>
                    </fields>
                </register>
                <register>
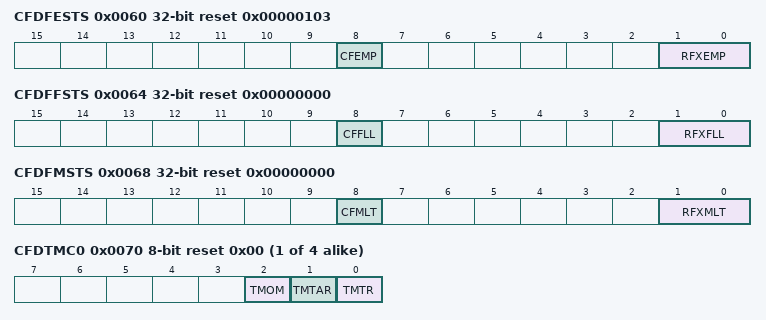
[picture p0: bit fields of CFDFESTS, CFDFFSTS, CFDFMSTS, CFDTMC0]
                    <name>CFDFESTS</name>
                    <description>FIFO Empty Status Register</description>
                    <addressOffset>0x0060</addressOffset>
                    <size>32</size>
                    <access>read-only</access>
                    <resetValue>0x00000103</resetValue>
                    <resetMask>0xffffffff</resetMask>
                    <fields>
                        <field>
                            <name>RFXEMP</name>
                            <description>RX FIFO Empty Status</description>
                            <lsb>0</lsb>
                            <msb>1</msb>
                            <access>read-only</access>
                            <enumeratedValues>
                                <enumeratedValue>
                                    <name>0</name>
                                    <description>Corresponding FIFO not empty</description>
                                    <value>#0</value>
                                </enumeratedValue>
                                <enumeratedValue>
                                    <name>1</name>
                                    <description>Corresponding FIFO empty</description>
                                    <value>#1</value>
                                </enumeratedValue>
                            </enumeratedValues>
                        </field>
                        <field>
                            <name>CFEMP</name>
                            <description>Common FIFO Empty Status</description>
                            <lsb>8</lsb>
                            <msb>8</msb>
                            <access>read-only</access>
                            <enumeratedValues>
                                <enumeratedValue>
                                    <name>0</name>
                                    <description>Corresponding FIFO not empty</description>
                                    <value>#0</value>
                                </enumeratedValue>
                                <enumeratedValue>
                                    <name>1</name>
                                    <description>Corresponding FIFO empty</description>
                                    <value>#1</value>
                                </enumeratedValue>
                            </enumeratedValues>
                        </field>
                    </fields>
                </register>
                <register>
                    <name>CFDFFSTS</name>
                    <description>FIFO Full Status Register</description>
                    <addressOffset>0x0064</addressOffset>
                    <size>32</size>
                    <access>read-only</access>
                    <resetValue>0x00000000</resetValue>
                    <resetMask>0xffffffff</resetMask>
                    <fields>
                        <field>
                            <name>RFXFLL</name>
                            <description>RX FIF0 Full Status</description>
                            <lsb>0</lsb>
                            <msb>1</msb>
                            <access>read-only</access>
                            <enumeratedValues>
                                <enumeratedValue>
                                    <name>0</name>
                                    <description>Corresponding FIFO not full</description>
                                    <value>#0</value>
                                </enumeratedValue>
                                <enumeratedValue>
                                    <name>1</name>
                                    <description>Corresponding FIFO full</description>
                                    <value>#1</value>
                                </enumeratedValue>
                            </enumeratedValues>
                        </field>
                        <field>
                            <name>CFFLL</name>
                            <description>Common FIF0 Full Status</description>
                            <lsb>8</lsb>
                            <msb>8</msb>
                            <access>read-only</access>
                            <enumeratedValues>
                                <enumeratedValue>
                                    <name>0</name>
                                    <description>Corresponding FIFO not full</description>
                                    <value>#0</value>
                                </enumeratedValue>
                                <enumeratedValue>
                                    <name>1</name>
                                    <description>Corresponding FIFO full</description>
                                    <value>#1</value>
                                </enumeratedValue>
                            </enumeratedValues>
                        </field>
                    </fields>
                </register>
                <register>
                    <name>CFDFMSTS</name>
                    <description>FIFO Message Lost Status Register</description>
                    <addressOffset>0x0068</addressOffset>
                    <size>32</size>
                    <access>read-only</access>
                    <resetValue>0x00000000</resetValue>
                    <resetMask>0xffffffff</resetMask>
                    <fields>
                        <field>
                            <name>RFXMLT</name>
                            <description>RX FIFO Message Lost Status</description>
                            <lsb>0</lsb>
                            <msb>1</msb>
                            <access>read-only</access>
                            <enumeratedValues>
                                <enumeratedValue>
                                    <name>0</name>
                                    <description>Corresponding FIFO Message Lost flag not set</description>
                                    <value>#0</value>
                                </enumeratedValue>
                                <enumeratedValue>
                                    <name>1</name>
                                    <description>Corresponding FIFO Message Lost flag set</description>
                                    <value>#1</value>
                                </enumeratedValue>
                            </enumeratedValues>
                        </field>
                        <field>
                            <name>CFMLT</name>
                            <description>Common FIFO Message Lost Status</description>
                            <lsb>8</lsb>
                            <msb>8</msb>
                            <access>read-only</access>
                            <enumeratedValues>
                                <enumeratedValue>
                                    <name>0</name>
                                    <description>Corresponding FIFO Message Lost flag not set</description>
                                    <value>#0</value>
                                </enumeratedValue>
                                <enumeratedValue>
                                    <name>1</name>
                                    <description>Corresponding FIFO Message Lost flag set</description>
                                    <value>#1</value>
                                </enumeratedValue>
                            </enumeratedValues>
                        </field>
                    </fields>
                </register>
                <register>
                    <name>CFDRFISTS</name>
                    <description>RX FIFO Interrupt Flag Status Register</description>
                    <addressOffset>0x006C</addressOffset>
                    <size>32</size>
                    <access>read-only</access>
                    <resetValue>0x00000000</resetValue>
                    <resetMask>0xffffffff</resetMask>
                    <fields>
                        <field>
                            <name>RFXIF</name>
                            <description>RX FIFO[x] Interrupt Flag Status</description>
                            <lsb>0</lsb>
                            <msb>1</msb>
                            <access>read-only</access>
                            <enumeratedValues>
                                <enumeratedValue>
                                    <name>0</name>
                                    <description>Corresponding RX FIFO Interrupt flag not set</description>
                                    <value>#0</value>
                                </enumeratedValue>
                                <enumeratedValue>
                                    <name>1</name>
                                    <description>Corresponding RX FIFO Interrupt flag set</description>
                                    <value>#1</value>
                                </enumeratedValue>
                            </enumeratedValues>
                        </field>
                    </fields>
                </register>
                <register>
                    <dim>4</dim>
                    <dimIncrement>0x01</dimIncrement>
                    <dimIndex>0-3</dimIndex>
                    <name>CFDTMC%s</name>
                    <description>TX Message Buffer Control Registers %s</description>
                    <addressOffset>0x0070</addressOffset>
                    <size>8</size>
                    <access>read-write</access>
                    <resetValue>0x00</resetValue>
                    <resetMask>0xff</resetMask>
                    <fields>
                        <field>
                            <name>TMTR</name>
                            <description>TX Message Buffer Transmission Request</description>
                            <lsb>0</lsb>
                            <msb>0</msb>
                            <access>read-write</access>
                            <enumeratedValues>
                                <enumeratedValue>
                                    <name>0</name>
                                    <description>TX Message buffer transmission not requested</description>
                                    <value>#0</value>
                                </enumeratedValue>
                                <enumeratedValue>
                                    <name>1</name>
                                    <description>TX message buffer transmission requested</description>
                                    <value>#1</value>
                                </enumeratedValue>
                            </enumeratedValues>
                        </field>
                        <field>
                            <name>TMTAR</name>
                            <description>TX Message Buffer Transmission Abort Request</description>
                            <lsb>1</lsb>
                            <msb>1</msb>
                            <access>read-write</access>
                            <enumeratedValues>
                                <enumeratedValue>
                                    <name>0</name>
                                    <description>TX message buffer transmission request abort not requested</description>
                                    <value>#0</value>
                                </enumeratedValue>
                                <enumeratedValue>
                                    <name>1</name>
                                    <description>TX message buffer transmission request abort requested</description>
                                    <value>#1</value>
                                </enumeratedValue>
                            </enumeratedValues>
                        </field>
                        <field>
                            <name>TMOM</name>
                            <description>TX Message Buffer One-shot Mode</description>
                            <lsb>2</lsb>
                            <msb>2</msb>
                            <access>read-write</access>
                            <enumeratedValues>
                                <enumeratedValue>
                                    <name>0</name>
                                    <description>TX message buffer not configured in one-shot mode</description>
                                    <value>#0</value>
                                </enumeratedValue>
                                <enumeratedValue>
                                    <name>1</name>
                                    <description>TX message buffer configured in one-shot mode</description>
                                    <value>#1</value>
                                </enumeratedValue>
                            </enumeratedValues>
                        </field>
                    </fields>
                </register>
                <register>
                    <dim>4</dim>
                    <dimIncrement>0x01</dimIncrement>
                    <dimIndex>0-3</dimIndex>
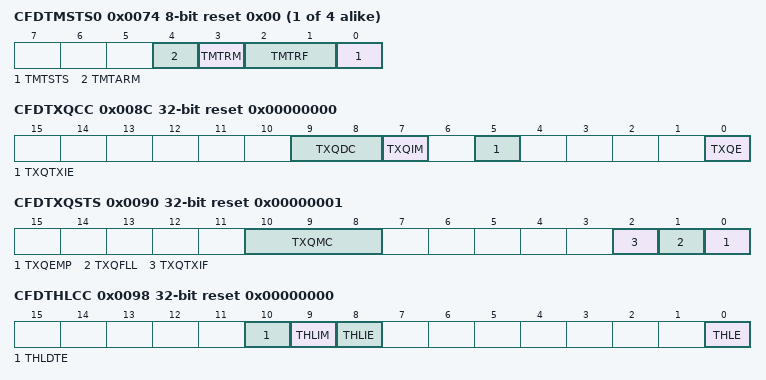
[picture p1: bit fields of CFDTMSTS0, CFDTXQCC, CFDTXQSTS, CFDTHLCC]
                    <name>CFDTMSTS%s</name>
                    <description>TX Message Buffer Status Registers %s</description>
                    <addressOffset>0x0074</addressOffset>
                    <size>8</size>
                    <access>read-write</access>
                    <resetValue>0x00</resetValue>
                    <resetMask>0xff</resetMask>
                    <fields>
                        <field>
                            <name>TMTSTS</name>
                            <description>TX Message Buffer Transmission Status</description>
                            <lsb>0</lsb>
                            <msb>0</msb>
                            <access>read-only</access>
                            <enumeratedValues>
                                <enumeratedValue>
                                    <name>0</name>
                                    <description>No on-going transmission</description>
                                    <value>#0</value>
                                </enumeratedValue>
                                <enumeratedValue>
                                    <name>1</name>
                                    <description>On-going transmission</description>
                                    <value>#1</value>
                                </enumeratedValue>
                            </enumeratedValues>
                        </field>
                        <field>
                            <name>TMTRF</name>
                            <description>TX Message Buffer Transmission Result Flag</description>
                            <lsb>1</lsb>
                            <msb>2</msb>
                            <access>read-write</access>
                            <enumeratedValues>
                                <enumeratedValue>
                                    <name>00</name>
                                    <description>No result</description>
                                    <value>#00</value>
                                </enumeratedValue>
                                <enumeratedValue>
                                    <name>01</name>
                                    <description>Transmission aborted from the TX message buffer</description>
                                    <value>#01</value>
                                </enumeratedValue>
                                <enumeratedValue>
                                    <name>10</name>
                                    <description>Transmission successful from the TX message buffer and transmission abort was not requested</description>
                                    <value>#10</value>
                                </enumeratedValue>
                                <enumeratedValue>
                                    <name>11</name>
                                    <description>Transmission successful from the TX message buffer and transmission abort was requested</description>
                                    <value>#11</value>
                                </enumeratedValue>
                            </enumeratedValues>
                        </field>
                        <field>
                            <name>TMTRM</name>
                            <description>TX Message Buffer Transmission Request Mirrored</description>
                            <lsb>3</lsb>
                            <msb>3</msb>
                            <access>read-only</access>
                            <enumeratedValues>
                                <enumeratedValue>
                                    <name>0</name>
                                    <description>TX message buffer transmission not requested</description>
                                    <value>#0</value>
                                </enumeratedValue>
                                <enumeratedValue>
                                    <name>1</name>
                                    <description>TX message buffer transmission requested</description>
                                    <value>#1</value>
                                </enumeratedValue>
                            </enumeratedValues>
                        </field>
                        <field>
                            <name>TMTARM</name>
                            <description>TX Message Buffer Transmission Abort Request Mirrored</description>
                            <lsb>4</lsb>
                            <msb>4</msb>
                            <access>read-only</access>
                            <enumeratedValues>
                                <enumeratedValue>
                                    <name>0</name>
                                    <description>TX message buffer transmission request abort not requested</description>
                                    <value>#0</value>
                                </enumeratedValue>
                                <enumeratedValue>
                                    <name>1</name>
                                    <description>TX message buffer transmission request abort requested</description>
                                    <value>#1</value>
                                </enumeratedValue>
                            </enumeratedValues>
                        </field>
                    </fields>
                </register>
                <register>
                    <name>CFDTMTRSTS</name>
                    <description>TX Message Buffer Transmission Request Status Register</description>
                    <addressOffset>0x0078</addressOffset>
                    <size>32</size>
                    <access>read-only</access>
                    <resetValue>0x00000000</resetValue>
                    <resetMask>0xffffffff</resetMask>
                    <fields>
                        <field>
                            <name>CFDTMTRSTS</name>
                            <description>TX Message Buffer Transmission Request Status</description>
                            <lsb>0</lsb>
                            <msb>3</msb>
                            <access>read-only</access>
                            <enumeratedValues>
                                <enumeratedValue>
                                    <name>0</name>
                                    <description>Transmission not requested for corresponding TX message buffer</description>
                                    <value>#0</value>
                                </enumeratedValue>
                                <enumeratedValue>
                                    <name>1</name>
                                    <description>Transmission requested for corresponding TX message buffer</description>
                                    <value>#1</value>
                                </enumeratedValue>
                            </enumeratedValues>
                        </field>
                    </fields>
                </register>
                <register>
                    <name>CFDTMTARSTS</name>
                    <description>TX Message Buffer Transmission Abort Request Status Register</description>
                    <addressOffset>0x007C</addressOffset>
                    <size>32</size>
                    <access>read-only</access>
                    <resetValue>0x00000000</resetValue>
                    <resetMask>0xffffffff</resetMask>
                    <fields>
                        <field>
                            <name>CFDTMTARSTS</name>
                            <description>TX Message Buffer Transmission Abort Request Status</description>
                            <lsb>0</lsb>
                            <msb>3</msb>
                            <access>read-only</access>
                            <enumeratedValues>
                                <enumeratedValue>
                                    <name>0</name>
                                    <description>Transmission abort not requested for corresponding TX message buffer</description>
                                    <value>#0</value>
                                </enumeratedValue>
                                <enumeratedValue>
                                    <name>1</name>
                                    <description>Transmission abort requested for corresponding TX message buffer</description>
                                    <value>#1</value>
                                </enumeratedValue>
                            </enumeratedValues>
                        </field>
                    </fields>
                </register>
                <register>
                    <name>CFDTMTCSTS</name>
                    <description>TX Message Buffer Transmission Completion Status Register</description>
                    <addressOffset>0x0080</addressOffset>
                    <size>32</size>
                    <access>read-only</access>
                    <resetValue>0x00000000</resetValue>
                    <resetMask>0xffffffff</resetMask>
                    <fields>
                        <field>
                            <name>CFDTMTCSTS</name>
                            <description>TX Message Buffer Transmission Completion Status</description>
                            <lsb>0</lsb>
                            <msb>3</msb>
                            <access>read-only</access>
                            <enumeratedValues>
                                <enumeratedValue>
                                    <name>0</name>
                                    <description>Transmission not complete for corresponding TX message buffer</description>
                                    <value>#0</value>
                                </enumeratedValue>
                                <enumeratedValue>
                                    <name>1</name>
                                    <description>Transmission completed for corresponding TX message buffer</description>
                                    <value>#1</value>
                                </enumeratedValue>
                            </enumeratedValues>
                        </field>
                    </fields>
                </register>
                <register>
                    <name>CFDTMTASTS</name>
                    <description>TX Message Buffer Transmission Abort Status Register</description>
                    <addressOffset>0x0084</addressOffset>
                    <size>32</size>
                    <access>read-only</access>
                    <resetValue>0x00000000</resetValue>
                    <resetMask>0xffffffff</resetMask>
                    <fields>
                        <field>
                            <name>CFDTMTASTS</name>
                            <description>TX Message Buffer Transmission Abort Status</description>
                            <lsb>0</lsb>
                            <msb>3</msb>
                            <access>read-only</access>
                            <enumeratedValues>
                                <enumeratedValue>
                                    <name>0</name>
                                    <description>Transmission not aborted for corresponding TX message buffer</description>
                                    <value>#0</value>
                                </enumeratedValue>
                                <enumeratedValue>
                                    <name>1</name>
                                    <description>Transmission aborted for corresponding TX message buffer</description>
                                    <value>#1</value>
                                </enumeratedValue>
                            </enumeratedValues>
                        </field>
                    </fields>
                </register>
                <register>
                    <name>CFDTMIEC</name>
                    <description>TX Message Buffer Interrupt Enable Configuration Register</description>
                    <addressOffset>0x0088</addressOffset>
                    <size>32</size>
                    <access>read-write</access>
                    <resetValue>0x00000000</resetValue>
                    <resetMask>0xffffffff</resetMask>
                    <fields>
                        <field>
                            <name>TMIEg</name>
                            <description>TX Message Buffer Interrupt Enable</description>
                            <lsb>0</lsb>
                            <msb>3</msb>
                            <access>read-write</access>
                            <enumeratedValues>
                                <enumeratedValue>
                                    <name>0</name>
                                    <description>TX message buffer interrupt disabled for corresponding TX message buffer</description>
                                    <value>#0</value>
                                </enumeratedValue>
                                <enumeratedValue>
                                    <name>1</name>
                                    <description>TX message buffer interrupt enabled for corresponding TX message buffer</description>
                                    <value>#1</value>
                                </enumeratedValue>
                            </enumeratedValues>
                        </field>
                    </fields>
                </register>
                <register>
                    <name>CFDTXQCC</name>
                    <description>TX Queue Configuration/Control Register</description>
                    <addressOffset>0x008C</addressOffset>
                    <size>32</size>
                    <access>read-write</access>
                    <resetValue>0x00000000</resetValue>
                    <resetMask>0xffffffff</resetMask>
                    <fields>
                        <field>
                            <name>TXQE</name>
                            <description>TX Queue Enable</description>
                            <lsb>0</lsb>
                            <msb>0</msb>
                            <access>read-write</access>
                            <enumeratedValues>
                                <enumeratedValue>
                                    <name>0</name>
                                    <description>TX Queue disabled</description>
                                    <value>#0</value>
                                </enumeratedValue>
                                <enumeratedValue>
                                    <name>1</name>
                                    <description>TX Queue enabled</description>
                                    <value>#1</value>
                                </enumeratedValue>
                            </enumeratedValues>
                        </field>
                        <field>
                            <name>TXQTXIE</name>
                            <description>TX Queue TX Interrupt Enable</description>
                            <lsb>5</lsb>
                            <msb>5</msb>
                            <access>read-write</access>
                            <enumeratedValues>
                                <enumeratedValue>
                                    <name>0</name>
                                    <description>TX Queue TX interrupt disabled</description>
                                    <value>#0</value>
                                </enumeratedValue>
                                <enumeratedValue>
                                    <name>1</name>
                                    <description>TX Queue TX interrupt enabled</description>
                                    <value>#1</value>
                                </enumeratedValue>
                            </enumeratedValues>
                        </field>
                        <field>
                            <name>TXQIM</name>
                            <description>TX Queue Interrupt Mode</description>
                            <lsb>7</lsb>
                            <msb>7</msb>
                            <access>read-write</access>
                            <enumeratedValues>
                                <enumeratedValue>
                                    <name>0</name>
                                    <description>When the last message is successfully transmitted</description>
                                    <value>#0</value>
                                </enumeratedValue>
                                <enumeratedValue>
                                    <name>1</name>
                                    <description>At every successful transmission</description>
                                    <value>#1</value>
                                </enumeratedValue>
                            </enumeratedValues>
                        </field>
                        <field>
                            <name>TXQDC</name>
                            <description>TX Queue Depth Configuration</description>
                            <lsb>8</lsb>
                            <msb>9</msb>
                            <access>read-write</access>
                            <enumeratedValues>
                                <enumeratedValue>
                                    <name>0x00</name>
                                    <description>0 messages</description>
                                    <value>0x00</value>
                                </enumeratedValue>
                                <enumeratedValue>
                                    <name>0x01</name>
                                    <description>Reserved</description>
                                    <value>0x01</value>
                                </enumeratedValue>
                                <enumeratedValue>
                                    <name>0x10</name>
                                    <description>3 messages</description>
                                    <value>0x10</value>
                                </enumeratedValue>
                                <enumeratedValue>
                                    <name>0x11</name>
                                    <description>4 messages</description>
                                    <value>0x11</value>
                                </enumeratedValue>
                            </enumeratedValues>
                        </field>
                    </fields>
                </register>
                <register>
                    <name>CFDTXQSTS</name>
                    <description>TX Queue Status Register</description>
                    <addressOffset>0x0090</addressOffset>
                    <size>32</size>
                    <access>read-write</access>
                    <resetValue>0x00000001</resetValue>
                    <resetMask>0xffffffff</resetMask>
                    <fields>
                        <field>
                            <name>TXQEMP</name>
                            <description>TX Queue Empty</description>
                            <lsb>0</lsb>
                            <msb>0</msb>
                            <access>read-only</access>
                            <enumeratedValues>
                                <enumeratedValue>
                                    <name>0</name>
                                    <description>TX Queue not empty</description>
                                    <value>#0</value>
                                </enumeratedValue>
                                <enumeratedValue>
                                    <name>1</name>
                                    <description>TX Queue empty</description>
                                    <value>#1</value>
                                </enumeratedValue>
                            </enumeratedValues>
                        </field>
                        <field>
                            <name>TXQFLL</name>
                            <description>TX Queue Full</description>
                            <lsb>1</lsb>
                            <msb>1</msb>
                            <access>read-only</access>
                            <enumeratedValues>
                                <enumeratedValue>
                                    <name>0</name>
                                    <description>TX Queue not full</description>
                                    <value>#0</value>
                                </enumeratedValue>
                                <enumeratedValue>
                                    <name>1</name>
                                    <description>TX Queue full</description>
                                    <value>#1</value>
                                </enumeratedValue>
                            </enumeratedValues>
                        </field>
                        <field>
                            <name>TXQTXIF</name>
                            <description>TX Queue TX Interrupt Flag</description>
                            <lsb>2</lsb>
                            <msb>2</msb>
                            <access>read-write</access>
                            <enumeratedValues>
                                <enumeratedValue>
                                    <name>0</name>
                                    <description>TX Queue interrupt condition not satisfied after a frame TX</description>
                                    <value>#0</value>
                                </enumeratedValue>
                                <enumeratedValue>
                                    <name>1</name>
                                    <description>TX Queue interrupt condition satisfied after a frame TX</description>
                                    <value>#1</value>
                                </enumeratedValue>
                            </enumeratedValues>
                        </field>
                        <field>
                            <name>TXQMC</name>
                            <description>TX Queue Message Count</description>
                            <lsb>8</lsb>
                            <msb>10</msb>
                            <access>read-only</access>
                        </field>
                    </fields>
                </register>
                <register>
                    <name>CFDTXQPCTR</name>
                    <description>TX Queue Pointer Control Register</description>
                    <addressOffset>0x0094</addressOffset>
                    <size>32</size>
                    <access>write-only</access>
                    <resetValue>0x00000000</resetValue>
                    <resetMask>0xffffffff</resetMask>
                    <fields>
                        <field>
                            <name>TXQPC</name>
                            <description>TX Queue Pointer Control</description>
                            <lsb>0</lsb>
                            <msb>7</msb>
                            <access>write-only</access>
                        </field>
                    </fields>
                </register>
                <register>
                    <name>CFDTHLCC</name>
                    <description>TX History List Configuration/Control Register</description>
                    <addressOffset>0x0098</addressOffset>
                    <size>32</size>
                    <access>read-write</access>
                    <resetValue>0x00000000</resetValue>
                    <resetMask>0xffffffff</resetMask>
                    <fields>
                        <field>
                            <name>THLE</name>
                            <description>TX History List Enable</description>
                            <lsb>0</lsb>
                            <msb>0</msb>
                            <access>read-write</access>
                            <enumeratedValues>
                                <enumeratedValue>
                                    <name>0</name>
                                    <description>TX History List disabled</description>
                                    <value>#0</value>
                                </enumeratedValue>
                                <enumeratedValue>
                                    <name>1</name>
                                    <description>TX History List enabled</description>
                                    <value>#1</value>
                                </enumeratedValue>
                            </enumeratedValues>
                        </field>
                        <field>
                            <name>THLIE</name>
                            <description>TX History List Interrupt Enable</description>
                            <lsb>8</lsb>
                            <msb>8</msb>
                            <access>read-write</access>
                            <enumeratedValues>
                                <enumeratedValue>
                                    <name>0</name>
                                    <description>TX History List Interrupt disabled</description>
                                    <value>#0</value>
                                </enumeratedValue>
                                <enumeratedValue>
                                    <name>1</name>
                                    <description>TX History List Interrupt enabled</description>
                                    <value>#1</value>
                                </enumeratedValue>
                            </enumeratedValues>
                        </field>
                        <field>
                            <name>THLIM</name>
                            <description>TX History List Interrupt Mode</description>
                            <lsb>9</lsb>
                            <msb>9</msb>
                            <access>read-write</access>
                            <enumeratedValues>
                                <enumeratedValue>
                                    <name>0</name>
                                    <description>Interrupt generated if TX History List level reaches ¾ of the TX History List depth</description>
                                    <value>#0</value>
                                </enumeratedValue>
                                <enumeratedValue>
                                    <name>1</name>
                                    <description>Interrupt generated for every successfully stored entry</description>
                                    <value>#1</value>
                                </enumeratedValue>
                            </enumeratedValues>
                        </field>
                        <field>
                            <name>THLDTE</name>
                            <description>TX History List Dedicated TX Enable</description>
                            <lsb>10</lsb>
                            <msb>10</msb>
                            <access>read-write</access>
                            <enumeratedValues>
                                <enumeratedValue>
                                    <name>0</name>
                                    <description>TX FIFO + TX Queue</description>
                                    <value>#0</value>
                                </enumeratedValue>
                                <enumeratedValue>
                                    <name>1</name>
                                    <description>Flat TX MB + TX FIFO + TX Queue</description>
                                    <value>#1</value>
                                </enumeratedValue>
                            </enumeratedValues>
                        </field>
                    </fields>
                </register>
                <register>
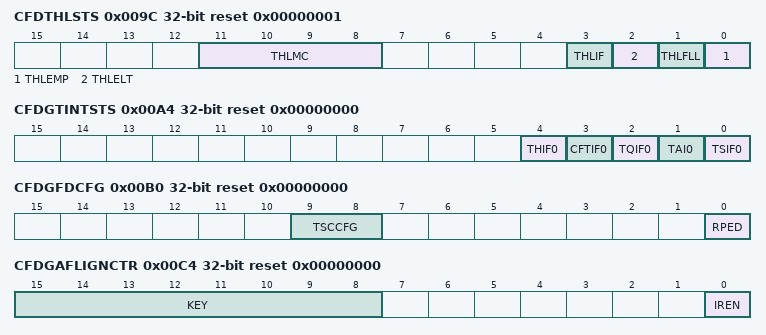
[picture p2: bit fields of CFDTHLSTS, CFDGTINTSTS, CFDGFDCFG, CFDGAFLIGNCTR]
                    <name>CFDTHLSTS</name>
                    <description>TX History List Status Register</description>
                    <addressOffset>0x009C</addressOffset>
                    <size>32</size>
                    <access>read-write</access>
                    <resetValue>0x00000001</resetValue>
                    <resetMask>0xffffffff</resetMask>
                    <fields>
                        <field>
                            <name>THLEMP</name>
                            <description>TX History List Empty</description>
                            <lsb>0</lsb>
                            <msb>0</msb>
                            <access>read-only</access>
                            <enumeratedValues>
                                <enumeratedValue>
                                    <name>0</name>
                                    <description>TX History List not empty</description>
                                    <value>#0</value>
                                </enumeratedValue>
                                <enumeratedValue>
                                    <name>1</name>
                                    <description>TX History List empty</description>
                                    <value>#1</value>
                                </enumeratedValue>
                            </enumeratedValues>
                        </field>
                        <field>
                            <name>THLFLL</name>
                            <description>TX History List Full</description>
                            <lsb>1</lsb>
                            <msb>1</msb>
                            <access>read-only</access>
                            <enumeratedValues>
                                <enumeratedValue>
                                    <name>0</name>
                                    <description>TX History List not full</description>
                                    <value>#0</value>
                                </enumeratedValue>
                                <enumeratedValue>
                                    <name>1</name>
                                    <description>TX History List full</description>
                                    <value>#1</value>
                                </enumeratedValue>
                            </enumeratedValues>
                        </field>
                        <field>
                            <name>THLELT</name>
                            <description>TX History List Entry Lost</description>
                            <lsb>2</lsb>
                            <msb>2</msb>
                            <access>read-write</access>
                            <enumeratedValues>
                                <enumeratedValue>
                                    <name>0</name>
                                    <description>No entry lost in TX History List</description>
                                    <value>#0</value>
                                </enumeratedValue>
                                <enumeratedValue>
                                    <name>1</name>
                                    <description>TX History List entry Lost</description>
                                    <value>#1</value>
                                </enumeratedValue>
                            </enumeratedValues>
                        </field>
                        <field>
                            <name>THLIF</name>
                            <description>TX History List Interrupt Flag</description>
                            <lsb>3</lsb>
                            <msb>3</msb>
                            <access>read-write</access>
                            <enumeratedValues>
                                <enumeratedValue>
                                    <name>0</name>
                                    <description>TX History List interrupt condition not satisfied</description>
                                    <value>#0</value>
                                </enumeratedValue>
                                <enumeratedValue>
                                    <name>1</name>
                                    <description>TX History List interrupt condition satisfied</description>
                                    <value>#1</value>
                                </enumeratedValue>
                            </enumeratedValues>
                        </field>
                        <field>
                            <name>THLMC</name>
                            <description>TX History List Message Count</description>
                            <lsb>8</lsb>
                            <msb>11</msb>
                            <access>read-only</access>
                        </field>
                    </fields>
                </register>
                <register>
                    <name>CFDTHLPCTR</name>
                    <description>TX History List Pointer Control Register</description>
                    <addressOffset>0x00A0</addressOffset>
                    <size>32</size>
                    <access>write-only</access>
                    <resetValue>0x00000000</resetValue>
                    <resetMask>0xffffffff</resetMask>
                    <fields>
                        <field>
                            <name>THLPC</name>
                            <description>TX History List Pointer Control</description>
                            <lsb>0</lsb>
                            <msb>7</msb>
                            <access>write-only</access>
                        </field>
                    </fields>
                </register>
                <register>
                    <name>CFDGTINTSTS</name>
                    <description>Global TX Interrupt Status Register</description>
                    <addressOffset>0x00A4</addressOffset>
                    <size>32</size>
                    <access>read-only</access>
                    <resetValue>0x00000000</resetValue>
                    <resetMask>0xffffffff</resetMask>
                    <fields>
                        <field>
                            <name>TSIF0</name>
                            <description>TX Successful Interrupt Flag</description>
                            <lsb>0</lsb>
                            <msb>0</msb>
                            <access>read-only</access>
                            <enumeratedValues>
                                <enumeratedValue>
                                    <name>0</name>
                                    <description>Channel n TX Successful Interrupt flag not set</description>
                                    <value>#0</value>
                                </enumeratedValue>
                                <enumeratedValue>
                                    <name>1</name>
                                    <description>Channel n TX Successful Interrupt flag set</description>
                                    <value>#1</value>
                                </enumeratedValue>
                            </enumeratedValues>
                        </field>
                        <field>
                            <name>TAI0</name>
                            <description>TX Abort Interrupt Flag</description>
                            <lsb>1</lsb>
                            <msb>1</msb>
                            <access>read-only</access>
                            <enumeratedValues>
                                <enumeratedValue>
                                    <name>0</name>
                                    <description>Channel n TX Abort Interrupt flag not set</description>
                                    <value>#0</value>
                                </enumeratedValue>
                                <enumeratedValue>
                                    <name>1</name>
                                    <description>Channel n TX Abort Interrupt flag set</description>
                                    <value>#1</value>
                                </enumeratedValue>
                            </enumeratedValues>
                        </field>
                        <field>
                            <name>TQIF0</name>
                            <description>TX Queue Interrupt Flag</description>
                            <lsb>2</lsb>
                            <msb>2</msb>
                            <access>read-only</access>
                            <enumeratedValues>
                                <enumeratedValue>
                                    <name>0</name>
                                    <description>Channel n TX Queue Interrupt flag not set</description>
                                    <value>#0</value>
                                </enumeratedValue>
                                <enumeratedValue>
                                    <name>1</name>
                                    <description>Channel n TX Queue Interrupt flag set</description>
                                    <value>#1</value>
                                </enumeratedValue>
                            </enumeratedValues>
                        </field>
                        <field>
                            <name>CFTIF0</name>
                            <description>COM FIFO TX Mode Interrupt Flag</description>
                            <lsb>3</lsb>
                            <msb>3</msb>
                            <access>read-only</access>
                            <enumeratedValues>
                                <enumeratedValue>
                                    <name>0</name>
                                    <description>Channel n COM FIFO TX Mode Interrupt flag not set</description>
                                    <value>#0</value>
                                </enumeratedValue>
                                <enumeratedValue>
                                    <name>1</name>
                                    <description>Channel n COM FIFO TX Mode Interrupt flag set</description>
                                    <value>#1</value>
                                </enumeratedValue>
                            </enumeratedValues>
                        </field>
                        <field>
                            <name>THIF0</name>
                            <description>TX History List Interrupt</description>
                            <lsb>4</lsb>
                            <msb>4</msb>
                            <access>read-only</access>
                            <enumeratedValues>
                                <enumeratedValue>
                                    <name>0</name>
                                    <description>Channel n TX History List Interrupt flag not set</description>
                                    <value>#0</value>
                                </enumeratedValue>
                                <enumeratedValue>
                                    <name>1</name>
                                    <description>Channel n TX History List Interrupt flag set</description>
                                    <value>#1</value>
                                </enumeratedValue>
                            </enumeratedValues>
                        </field>
                    </fields>
                </register>
                <register>
                    <name>CFDGTSTCFG</name>
                    <description>Global Test Configuration Register</description>
                    <addressOffset>0x00A8</addressOffset>
                    <size>32</size>
                    <access>read-write</access>
                    <resetValue>0x00000000</resetValue>
                    <resetMask>0xffffffff</resetMask>
                    <fields>
                        <field>
                            <name>RTMPS</name>
                            <description>RAM Test Mode Page Select</description>
                            <lsb>16</lsb>
                            <msb>19</msb>
                            <access>read-write</access>
                        </field>
                    </fields>
                </register>
                <register>
                    <name>CFDGTSTCTR</name>
                    <description>Global Test Control Register</description>
                    <addressOffset>0x00AC</addressOffset>
                    <size>32</size>
                    <access>read-write</access>
                    <resetValue>0x00000000</resetValue>
                    <resetMask>0xffffffff</resetMask>
                    <fields>
                        <field>
                            <name>RTME</name>
                            <description>RAM Test Mode Enable</description>
                            <lsb>2</lsb>
                            <msb>2</msb>
                            <access>read-write</access>
                            <enumeratedValues>
                                <enumeratedValue>
                                    <name>0</name>
                                    <description>RAM test mode disabled</description>
                                    <value>#0</value>
                                </enumeratedValue>
                                <enumeratedValue>
                                    <name>1</name>
                                    <description>RAM test mode enabled</description>
                                    <value>#1</value>
                                </enumeratedValue>
                            </enumeratedValues>
                        </field>
                    </fields>
                </register>
                <register>
                    <name>CFDGFDCFG</name>
                    <description>Global FD Configuration Register</description>
                    <addressOffset>0x00B0</addressOffset>
                    <size>32</size>
                    <access>read-write</access>
                    <resetValue>0x00000000</resetValue>
                    <resetMask>0xffffffff</resetMask>
                    <fields>
                        <field>
                            <name>RPED</name>
                            <description>RES Bit Protocol Exception Disable</description>
                            <lsb>0</lsb>
                            <msb>0</msb>
                            <access>read-write</access>
                            <enumeratedValues>
                                <enumeratedValue>
                                    <name>0</name>
                                    <description>Protocol exception event detection enabled</description>
                                    <value>#0</value>
                                </enumeratedValue>
                                <enumeratedValue>
                                    <name>1</name>
                                    <description>Protocol exception event detection disabled</description>
                                    <value>#1</value>
                                </enumeratedValue>
                            </enumeratedValues>
                        </field>
                        <field>
                            <name>TSCCFG</name>
                            <description>Timestamp Capture Configuration</description>
                            <lsb>8</lsb>
                            <msb>9</msb>
                            <access>read-write</access>
                            <enumeratedValues>
                                <enumeratedValue>
                                    <name>00</name>
                                    <description>Timestamp capture at the sample point of SOF (start of frame)</description>
                                    <value>#00</value>
                                </enumeratedValue>
                                <enumeratedValue>
                                    <name>01</name>
                                    <description>Timestamp capture at frame valid indication</description>
                                    <value>#01</value>
                                </enumeratedValue>
                                <enumeratedValue>
                                    <name>10</name>
                                    <description>Timestamp capture at the sample point of RES bit</description>
                                    <value>#10</value>
                                </enumeratedValue>
                                <enumeratedValue>
                                    <name>11</name>
                                    <description>Reserved</description>
                                    <value>#11</value>
                                </enumeratedValue>
                            </enumeratedValues>
                        </field>
                    </fields>
                </register>
                <register>
                    <name>CFDGLOCKK</name>
                    <description>Global Lock Key Register</description>
                    <addressOffset>0x00B8</addressOffset>
                    <size>32</size>
                    <access>write-only</access>
                    <resetValue>0x00000000</resetValue>
                    <resetMask>0xffffffff</resetMask>
                    <fields>
                        <field>
                            <name>LOCK</name>
                            <description>Lock Key</description>
                            <lsb>0</lsb>
                            <msb>15</msb>
                            <access>write-only</access>
                        </field>
                    </fields>
                </register>
                <register>
                    <name>CFDGAFLIGNENT</name>
                    <description>Global AFL Ignore Entry Register</description>
                    <addressOffset>0x00C0</addressOffset>
                    <size>32</size>
                    <access>read-write</access>
                    <resetValue>0x00000000</resetValue>
                    <resetMask>0xffffffff</resetMask>
                    <fields>
                        <field>
                            <name>IRN</name>
                            <description>Ignore Rule Number</description>
                            <lsb>0</lsb>
                            <msb>3</msb>
                            <access>read-write</access>
                        </field>
                    </fields>
                </register>
                <register>
                    <name>CFDGAFLIGNCTR</name>
                    <description>Global AFL Ignore Control Register</description>
                    <addressOffset>0x00C4</addressOffset>
                    <size>32</size>
                    <access>read-write</access>
                    <resetValue>0x00000000</resetValue>
                    <resetMask>0xffffffff</resetMask>
                    <fields>
                        <field>
                            <name>IREN</name>
                            <description>Ignore Rule Enable</description>
                            <lsb>0</lsb>
                            <msb>0</msb>
                            <access>read-write</access>
                            <enumeratedValues>
                                <enumeratedValue>
                                    <name>0</name>
                                    <description>AFL entry number is not ignored</description>
                                    <value>#0</value>
                                </enumeratedValue>
                                <enumeratedValue>
                                    <name>1</name>
                                    <description>AFL entry number is ignored</description>
                                    <value>#1</value>
                                </enumeratedValue>
                            </enumeratedValues>
                        </field>
                        <field>
                            <name>KEY</name>
                            <description>Key Code</description>
                            <lsb>8</lsb>
                            <msb>15</msb>
                            <access>write-only</access>
                        </field>
                    </fields>
                </register>
                <register>
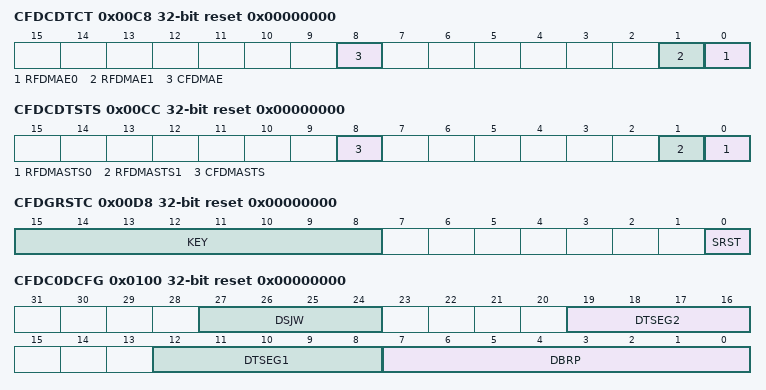
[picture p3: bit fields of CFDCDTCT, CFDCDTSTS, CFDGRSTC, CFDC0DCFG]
                    <name>CFDCDTCT</name>
                    <description>DMA Transfer Control Register</description>
                    <addressOffset>0x00C8</addressOffset>
                    <size>32</size>
                    <access>read-write</access>
                    <resetValue>0x00000000</resetValue>
                    <resetMask>0xffffffff</resetMask>
                    <fields>
                        <field>
                            <name>RFDMAE0</name>
                            <description>DMA Transfer Enable for RXFIFO 0</description>
                            <lsb>0</lsb>
                            <msb>0</msb>
                            <access>read-write</access>
                            <enumeratedValues>
                                <enumeratedValue>
                                    <name>0</name>
                                    <description>DMA transfer request disabled</description>
                                    <value>#0</value>
                                </enumeratedValue>
                                <enumeratedValue>
                                    <name>1</name>
                                    <description>DMA transfer request enabled</description>
                                    <value>#1</value>
                                </enumeratedValue>
                            </enumeratedValues>
                        </field>
                        <field>
                            <name>RFDMAE1</name>
                            <description>DMA Transfer Enable for RXFIFO 1</description>
                            <lsb>1</lsb>
                            <msb>1</msb>
                            <access>read-write</access>
                            <enumeratedValues>
                                <enumeratedValue>
                                    <name>0</name>
                                    <description>DMA transfer request disabled</description>
                                    <value>#0</value>
                                </enumeratedValue>
                                <enumeratedValue>
                                    <name>1</name>
                                    <description>DMA transfer request enabled</description>
                                    <value>#1</value>
                                </enumeratedValue>
                            </enumeratedValues>
                        </field>
                        <field>
                            <name>CFDMAE</name>
                            <description>DMA Transfer Enable for Common FIFO 0</description>
                            <lsb>8</lsb>
                            <msb>8</msb>
                            <access>read-write</access>
                            <enumeratedValues>
                                <enumeratedValue>
                                    <name>0</name>
                                    <description>DMA transfer request disabled</description>
                                    <value>#0</value>
                                </enumeratedValue>
                                <enumeratedValue>
                                    <name>1</name>
                                    <description>DMA transfer request enabled</description>
                                    <value>#1</value>
                                </enumeratedValue>
                            </enumeratedValues>
                        </field>
                    </fields>
                </register>
                <register>
                    <name>CFDCDTSTS</name>
                    <description>DMA Transfer Status Register</description>
                    <addressOffset>0x00CC</addressOffset>
                    <size>32</size>
                    <access>read-only</access>
                    <resetValue>0x00000000</resetValue>
                    <resetMask>0xffffffff</resetMask>
                    <fields>
                        <field>
                            <name>RFDMASTS0</name>
                            <description>DMA Transfer Status for RX FIFO 0</description>
                            <lsb>0</lsb>
                            <msb>0</msb>
                            <access>read-only</access>
                            <enumeratedValues>
                                <enumeratedValue>
                                    <name>0</name>
                                    <description>DMA transfer stopped</description>
                                    <value>#0</value>
                                </enumeratedValue>
                                <enumeratedValue>
                                    <name>1</name>
                                    <description>DMA transfer on going</description>
                                    <value>#1</value>
                                </enumeratedValue>
                            </enumeratedValues>
                        </field>
                        <field>
                            <name>RFDMASTS1</name>
                            <description>DMA Transfer Status for RX FIFO 1</description>
                            <lsb>1</lsb>
                            <msb>1</msb>
                            <access>read-only</access>
                            <enumeratedValues>
                                <enumeratedValue>
                                    <name>0</name>
                                    <description>DMA transfer stopped</description>
                                    <value>#0</value>
                                </enumeratedValue>
                                <enumeratedValue>
                                    <name>1</name>
                                    <description>DMA transfer on going</description>
                                    <value>#1</value>
                                </enumeratedValue>
                            </enumeratedValues>
                        </field>
                        <field>
                            <name>CFDMASTS</name>
                            <description>DMA Transfer Status only for Common FIFO</description>
                            <lsb>8</lsb>
                            <msb>8</msb>
                            <access>read-only</access>
                            <enumeratedValues>
                                <enumeratedValue>
                                    <name>0</name>
                                    <description>DMA transfer stopped</description>
                                    <value>#0</value>
                                </enumeratedValue>
                                <enumeratedValue>
                                    <name>1</name>
                                    <description>DMA transfer on going</description>
                                    <value>#1</value>
                                </enumeratedValue>
                            </enumeratedValues>
                        </field>
                    </fields>
                </register>
                <register>
                    <name>CFDGRSTC</name>
                    <description>Global SW reset Register</description>
                    <addressOffset>0x00D8</addressOffset>
                    <size>32</size>
                    <access>read-write</access>
                    <resetValue>0x00000000</resetValue>
                    <resetMask>0xffffffff</resetMask>
                    <fields>
                        <field>
                            <name>SRST</name>
                            <description>SW Reset</description>
                            <lsb>0</lsb>
                            <msb>0</msb>
                            <access>read-write</access>
                            <enumeratedValues>
                                <enumeratedValue>
                                    <name>0</name>
                                    <description>Normal state</description>
                                    <value>#0</value>
                                </enumeratedValue>
                                <enumeratedValue>
                                    <name>1</name>
                                    <description>SW reset state</description>
                                    <value>#1</value>
                                </enumeratedValue>
                            </enumeratedValues>
                        </field>
                        <field>
                            <name>KEY</name>
                            <description>Key Code</description>
                            <lsb>8</lsb>
                            <msb>15</msb>
                            <access>write-only</access>
                        </field>
                    </fields>
                </register>
                <register>
                    <name>CFDC0DCFG</name>
                    <description> Data Bitrate Configuration Register</description>
                    <addressOffset>0x0100</addressOffset>
                    <size>32</size>
                    <access>read-write</access>
                    <resetValue>0x00000000</resetValue>
                    <resetMask>0xffffffff</resetMask>
                    <fields>
                        <field>
                            <name>DBRP</name>
                            <description>Channel Data Baud Rate Prescaler</description>
                            <lsb>0</lsb>
                            <msb>7</msb>
                            <access>read-write</access>
                        </field>
                        <field>
                            <name>DTSEG1</name>
                            <description>Timing Segment 1</description>
                            <lsb>8</lsb>
                            <msb>12</msb>
                            <access>read-write</access>
                        </field>
                        <field>
                            <name>DTSEG2</name>
                            <description>Timing Segment 2</description>
                            <lsb>16</lsb>
                            <msb>19</msb>
                            <access>read-write</access>
                        </field>
                        <field>
                            <name>DSJW</name>
                            <description>Resynchronization Jump Width</description>
                            <lsb>24</lsb>
                            <msb>27</msb>
                            <access>read-write</access>
                        </field>
                    </fields>
                </register>
                <register>
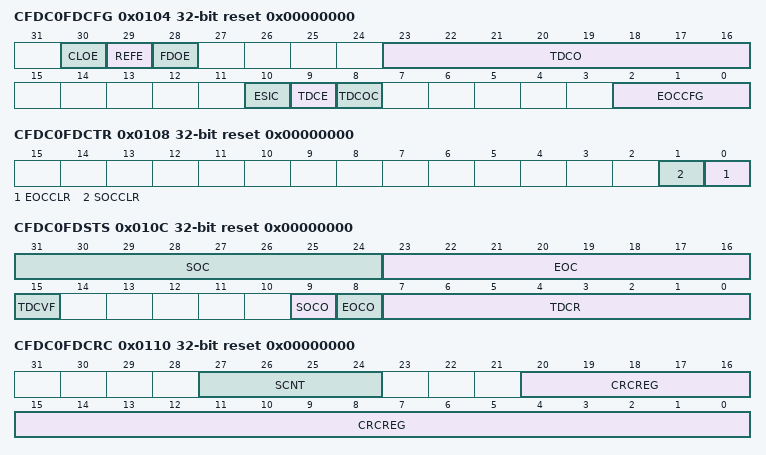
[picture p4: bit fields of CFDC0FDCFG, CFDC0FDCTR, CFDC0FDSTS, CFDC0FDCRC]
                    <name>CFDC0FDCFG</name>
                    <description>CANFD Configuration Register</description>
                    <addressOffset>0x0104</addressOffset>
                    <size>32</size>
                    <access>read-write</access>
                    <resetValue>0x00000000</resetValue>
                    <resetMask>0xbfffffff</resetMask>
                    <fields>
                        <field>
                            <name>EOCCFG</name>
                            <description>Error Occurrence Counter Configuration</description>
                            <lsb>0</lsb>
                            <msb>2</msb>
                            <access>read-write</access>
                            <enumeratedValues>
                                <enumeratedValue>
                                    <name>000</name>
                                    <description>All transmitter or receiver CAN frames</description>
                                    <value>#000</value>
                                </enumeratedValue>
                                <enumeratedValue>
                                    <name>001</name>
                                    <description>All transmitter CAN frames</description>
                                    <value>#001</value>
                                </enumeratedValue>
                                <enumeratedValue>
                                    <name>010</name>
                                    <description>All receiver CAN frames</description>
                                    <value>#010</value>
                                </enumeratedValue>
                                <enumeratedValue>
                                    <name>011</name>
                                    <description>Reserved</description>
                                    <value>#011</value>
                                </enumeratedValue>
                                <enumeratedValue>
                                    <name>100</name>
                                    <description>Only transmitter or receiver CANFD data-phase (fast bits)</description>
                                    <value>#100</value>
                                </enumeratedValue>
                                <enumeratedValue>
                                    <name>101</name>
                                    <description>Only transmitter CANFD data-phase (fast bits)</description>
                                    <value>#101</value>
                                </enumeratedValue>
                                <enumeratedValue>
                                    <name>110</name>
                                    <description>Only receiver CANFD data-phase (fast bits)</description>
                                    <value>#110</value>
                                </enumeratedValue>
                                <enumeratedValue>
                                    <name>111</name>
                                    <description>Reserved</description>
                                    <value>#111</value>
                                </enumeratedValue>
                            </enumeratedValues>
                        </field>
                        <field>
                            <name>TDCOC</name>
                            <description>Transceiver Delay Compensation Offset Configuration</description>
                            <lsb>8</lsb>
                            <msb>8</msb>
                            <access>read-write</access>
                            <enumeratedValues>
                                <enumeratedValue>
                                    <name>0</name>
                                    <description>Measured + offset</description>
                                    <value>#0</value>
                                </enumeratedValue>
                                <enumeratedValue>
                                    <name>1</name>
                                    <description>Offset-only</description>
                                    <value>#1</value>
                                </enumeratedValue>
                            </enumeratedValues>
                        </field>
                        <field>
                            <name>TDCE</name>
                            <description>Transceiver Delay Compensation Enable</description>
                            <lsb>9</lsb>
                            <msb>9</msb>
                            <access>read-write</access>
                            <enumeratedValues>
                                <enumeratedValue>
                                    <name>0</name>
                                    <description>Transceiver delay compensation disabled</description>
                                    <value>#0</value>
                                </enumeratedValue>
                                <enumeratedValue>
                                    <name>1</name>
                                    <description>Transceiver delay compensation enabled</description>
                                    <value>#1</value>
                                </enumeratedValue>
                            </enumeratedValues>
                        </field>
                        <field>
                            <name>ESIC</name>
                            <description>Error State Indication Configuration</description>
                            <lsb>10</lsb>
                            <msb>10</msb>
                            <access>read-write</access>
                            <enumeratedValues>
                                <enumeratedValue>
                                    <name>0</name>
                                    <description>The ESI bit in the frame represents the error state of the node itself</description>
                                    <value>#0</value>
                                </enumeratedValue>
                                <enumeratedValue>
                                    <name>1</name>
                                    <description>The ESI bit in the frame represents the error state of the message buffer if the node itself is not in error passive. If the node is in error passive, then the ESI bit is driven by the node itself.</description>
                                    <value>#1</value>
                                </enumeratedValue>
                            </enumeratedValues>
                        </field>
                        <field>
                            <name>TDCO</name>
                            <description>Transceiver Delay Compensation Offset</description>
                            <lsb>16</lsb>
                            <msb>23</msb>
                            <access>read-write</access>
                        </field>
                        <field>
                            <name>FDOE</name>
                            <description>FD-Only Enable</description>
                            <lsb>28</lsb>
                            <msb>28</msb>
                            <access>read-write</access>
                            <enumeratedValues>
                                <enumeratedValue>
                                    <name>0</name>
                                    <description>FD-only mode disabled</description>
                                    <value>#0</value>
                                </enumeratedValue>
                                <enumeratedValue>
                                    <name>1</name>
                                    <description>FD-only mode enabled</description>
                                    <value>#1</value>
                                </enumeratedValue>
                            </enumeratedValues>
                        </field>
                        <field>
                            <name>REFE</name>
                            <description>RX Edge Filter Enable</description>
                            <lsb>29</lsb>
                            <msb>29</msb>
                            <access>read-write</access>
                            <enumeratedValues>
                                <enumeratedValue>
                                    <name>0</name>
                                    <description>RX edge filter disabled</description>
                                    <value>#0</value>
                                </enumeratedValue>
                                <enumeratedValue>
                                    <name>1</name>
                                    <description>RX edge filter enabled</description>
                                    <value>#1</value>
                                </enumeratedValue>
                            </enumeratedValues>
                        </field>
                        <field>
                            <name>CLOE</name>
                            <description>Classical CAN Enable</description>
                            <lsb>30</lsb>
                            <msb>30</msb>
                            <access>read-write</access>
                            <enumeratedValues>
                                <enumeratedValue>
                                    <name>0</name>
                                    <description>Classical CAN mode disabled</description>
                                    <value>#0</value>
                                </enumeratedValue>
                                <enumeratedValue>
                                    <name>1</name>
                                    <description>Classical CAN mode enabled</description>
                                    <value>#1</value>
                                </enumeratedValue>
                            </enumeratedValues>
                        </field>
                    </fields>
                </register>
                <register>
                    <name>CFDC0FDCTR</name>
                    <description>CANFD Control Register</description>
                    <addressOffset>0x0108</addressOffset>
                    <size>32</size>
                    <access>read-write</access>
                    <resetValue>0x00000000</resetValue>
                    <resetMask>0xffffffff</resetMask>
                    <fields>
                        <field>
                            <name>EOCCLR</name>
                            <description>Error Occurrence Counter Clear</description>
                            <lsb>0</lsb>
                            <msb>0</msb>
                            <access>read-write</access>
                            <enumeratedValues>
                                <enumeratedValue>
                                    <name>0</name>
                                    <description>No error occurrence counter clear</description>
                                    <value>#0</value>
                                </enumeratedValue>
                                <enumeratedValue>
                                    <name>1</name>
                                    <description>Clear error occurrence counter</description>
                                    <value>#1</value>
                                </enumeratedValue>
                            </enumeratedValues>
                        </field>
                        <field>
                            <name>SOCCLR</name>
                            <description>Successful Occurrence Counter Clear</description>
                            <lsb>1</lsb>
                            <msb>1</msb>
                            <access>read-write</access>
                            <enumeratedValues>
                                <enumeratedValue>
                                    <name>0</name>
                                    <description>No successful occurrence counter clear</description>
                                    <value>#0</value>
                                </enumeratedValue>
                                <enumeratedValue>
                                    <name>1</name>
                                    <description>Clear successful occurrence counter</description>
                                    <value>#1</value>
                                </enumeratedValue>
                            </enumeratedValues>
                        </field>
                    </fields>
                </register>
                <register>
                    <name>CFDC0FDSTS</name>
                    <description>CANFD Status Register</description>
                    <addressOffset>0x010C</addressOffset>
                    <size>32</size>
                    <access>read-write</access>
                    <resetValue>0x00000000</resetValue>
                    <resetMask>0xffffffff</resetMask>
                    <fields>
                        <field>
                            <name>TDCR</name>
                            <description>Transceiver Delay Compensation Result</description>
                            <lsb>0</lsb>
                            <msb>7</msb>
                            <access>read-only</access>
                        </field>
                        <field>
                            <name>EOCO</name>
                            <description>Error Occurrence Counter Overflow</description>
                            <lsb>8</lsb>
                            <msb>8</msb>
                            <access>read-write</access>
                            <enumeratedValues>
                                <enumeratedValue>
                                    <name>0</name>
                                    <description>Error occurrence counter has not overflowed</description>
                                    <value>#0</value>
                                </enumeratedValue>
                                <enumeratedValue>
                                    <name>1</name>
                                    <description>Error occurrence counter has overflowed</description>
                                    <value>#1</value>
                                </enumeratedValue>
                            </enumeratedValues>
                        </field>
                        <field>
                            <name>SOCO</name>
                            <description>Successful Occurrence Counter Overflow</description>
                            <lsb>9</lsb>
                            <msb>9</msb>
                            <access>read-write</access>
                            <enumeratedValues>
                                <enumeratedValue>
                                    <name>0</name>
                                    <description>Successful occurrence counter has not overflowed</description>
                                    <value>#0</value>
                                </enumeratedValue>
                                <enumeratedValue>
                                    <name>1</name>
                                    <description>Successful occurrence counter has overflowed</description>
                                    <value>#1</value>
                                </enumeratedValue>
                            </enumeratedValues>
                        </field>
                        <field>
                            <name>TDCVF</name>
                            <description>Transceiver Delay Compensation Violation Flag</description>
                            <lsb>15</lsb>
                            <msb>15</msb>
                            <access>read-write</access>
                            <enumeratedValues>
                                <enumeratedValue>
                                    <name>0</name>
                                    <description>Transceiver delay compensation violation has not occurred</description>
                                    <value>#0</value>
                                </enumeratedValue>
                                <enumeratedValue>
                                    <name>1</name>
                                    <description>Transceiver delay compensation violation has occurred</description>
                                    <value>#1</value>
                                </enumeratedValue>
                            </enumeratedValues>
                        </field>
                        <field>
                            <name>EOC</name>
                            <description>Error Occurrence Counter</description>
                            <lsb>16</lsb>
                            <msb>23</msb>
                            <access>read-only</access>
                        </field>
                        <field>
                            <name>SOC</name>
                            <description>Successful occurrence counter</description>
                            <lsb>24</lsb>
                            <msb>31</msb>
                            <access>read-only</access>
                        </field>
                    </fields>
                </register>
                <register>
                    <name>CFDC0FDCRC</name>
                    <description>CANFD CRC Register</description>
                    <addressOffset>0x0110</addressOffset>
                    <size>32</size>
                    <access>read-only</access>
                    <resetValue>0x00000000</resetValue>
                    <resetMask>0xffffffff</resetMask>
                    <fields>
                        <field>
                            <name>CRCREG</name>
                            <description>CRC Register value</description>
                            <lsb>0</lsb>
                            <msb>20</msb>
                            <access>read-only</access>
                        </field>
                        <field>
                            <name>SCNT</name>
                            <description>Stuff bit count</description>
                            <lsb>24</lsb>
                            <msb>27</msb>
                            <access>read-only</access>
                        </field>
                    </fields>
                </register>
                <register>
                    <dim>16</dim>
                    <dimIncrement>0x0010</dimIncrement>
                    <dimIndex>1-16</dimIndex>
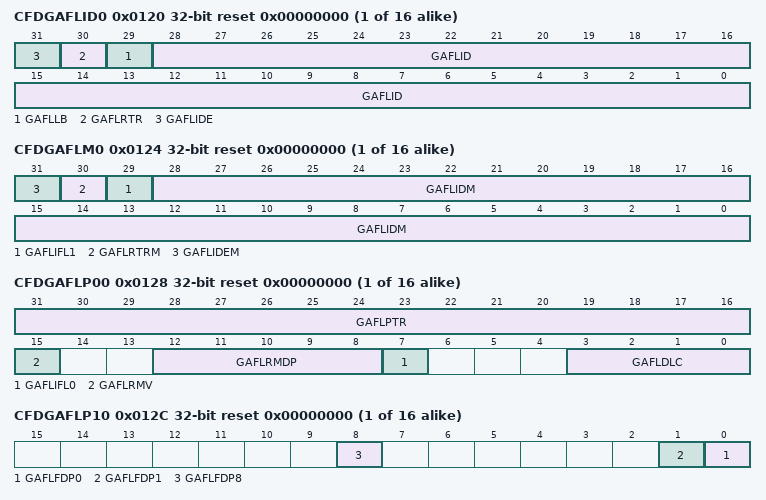
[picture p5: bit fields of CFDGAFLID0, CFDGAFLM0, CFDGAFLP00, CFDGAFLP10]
                    <name>CFDGAFLID%s</name>
                    <description>Global Acceptance Filter List ID Registers</description>
                    <addressOffset>0x0120</addressOffset>
                    <size>32</size>
                    <access>read-write</access>
                    <resetValue>0x00000000</resetValue>
                    <resetMask>0xffffffff</resetMask>
                    <fields>
                        <field>
                            <name>GAFLID</name>
                            <description>Global Acceptance Filter List Entry ID Field</description>
                            <lsb>0</lsb>
                            <msb>28</msb>
                            <access>read-write</access>
                        </field>
                        <field>
                            <name>GAFLLB</name>
                            <description>Global Acceptance Filter List Entry Loopback Configuration</description>
                            <lsb>29</lsb>
                            <msb>29</msb>
                            <access>read-write</access>
                            <enumeratedValues>
                                <enumeratedValue>
                                    <name>0</name>
                                    <description>Global Acceptance Filter List entry ID for acceptance filtering with attribute RX</description>
                                    <value>#0</value>
                                </enumeratedValue>
                                <enumeratedValue>
                                    <name>1</name>
                                    <description>Global Acceptance Filter List entry ID for acceptance filtering with attribute TX</description>
                                    <value>#1</value>
                                </enumeratedValue>
                            </enumeratedValues>
                        </field>
                        <field>
                            <name>GAFLRTR</name>
                            <description>Global Acceptance Filter List Entry RTR Field</description>
                            <lsb>30</lsb>
                            <msb>30</msb>
                            <access>read-write</access>
                            <enumeratedValues>
                                <enumeratedValue>
                                    <name>0</name>
                                    <description>Data frame</description>
                                    <value>#0</value>
                                </enumeratedValue>
                                <enumeratedValue>
                                    <name>1</name>
                                    <description>Remote frame</description>
                                    <value>#1</value>
                                </enumeratedValue>
                            </enumeratedValues>
                        </field>
                        <field>
                            <name>GAFLIDE</name>
                            <description>Global Acceptance Filter List Entry IDE Field</description>
                            <lsb>31</lsb>
                            <msb>31</msb>
                            <access>read-write</access>
                            <enumeratedValues>
                                <enumeratedValue>
                                    <name>0</name>
                                    <description>Standard identifier of rule entry ID is valid for acceptance filtering</description>
                                    <value>#0</value>
                                </enumeratedValue>
                                <enumeratedValue>
                                    <name>1</name>
                                    <description>Extended identifier of rule entry ID is valid for acceptance filtering</description>
                                    <value>#1</value>
                                </enumeratedValue>
                            </enumeratedValues>
                        </field>
                    </fields>
                </register>
                <register>
                    <dim>16</dim>
                    <dimIncrement>0x0010</dimIncrement>
                    <dimIndex>1-16</dimIndex>
                    <name>CFDGAFLM%s</name>
                    <description>Global Acceptance Filter List Mask Registers</description>
                    <addressOffset>0x0124</addressOffset>
                    <size>32</size>
                    <access>read-write</access>
                    <resetValue>0x00000000</resetValue>
                    <resetMask>0xffffffff</resetMask>
                    <fields>
                        <field>
                            <name>GAFLIDM</name>
                            <description>Global Acceptance Filter List ID Mask Field</description>
                            <lsb>0</lsb>
                            <msb>28</msb>
                            <access>read-write</access>
                        </field>
                        <field>
                            <name>GAFLIFL1</name>
                            <description>Global Acceptance Filter List Information Label 1</description>
                            <lsb>29</lsb>
                            <msb>29</msb>
                            <access>read-write</access>
                        </field>
                        <field>
                            <name>GAFLRTRM</name>
                            <description>Global Acceptance Filter List Entry RTR Mask</description>
                            <lsb>30</lsb>
                            <msb>30</msb>
                            <access>read-write</access>
                            <enumeratedValues>
                                <enumeratedValue>
                                    <name>0</name>
                                    <description>RTR bit is not used for ID matching</description>
                                    <value>#0</value>
                                </enumeratedValue>
                                <enumeratedValue>
                                    <name>1</name>
                                    <description>RTR bit is used for ID matching</description>
                                    <value>#1</value>
                                </enumeratedValue>
                            </enumeratedValues>
                        </field>
                        <field>
                            <name>GAFLIDEM</name>
                            <description>Global Acceptance Filter List IDE Mask</description>
                            <lsb>31</lsb>
                            <msb>31</msb>
                            <access>read-write</access>
                            <enumeratedValues>
                                <enumeratedValue>
                                    <name>0</name>
                                    <description>IDE bit is not used for ID matching</description>
                                    <value>#0</value>
                                </enumeratedValue>
                                <enumeratedValue>
                                    <name>1</name>
                                    <description>IDE bit is used for ID matching</description>
                                    <value>#1</value>
                                </enumeratedValue>
                            </enumeratedValues>
                        </field>
                    </fields>
                </register>
                <register>
                    <dim>16</dim>
                    <dimIncrement>0x0010</dimIncrement>
                    <dimIndex>1-16</dimIndex>
                    <name>CFDGAFLP0%s</name>
                    <description>Global Acceptance Filter List Pointer 0 Registers</description>
                    <addressOffset>0x0128</addressOffset>
                    <size>32</size>
                    <access>read-write</access>
                    <resetValue>0x00000000</resetValue>
                    <resetMask>0xffffffff</resetMask>
                    <fields>
                        <field>
                            <name>GAFLDLC</name>
                            <description>Global Acceptance Filter List DLC Field</description>
                            <lsb>0</lsb>
                            <msb>3</msb>
                            <access>read-write</access>
                        </field>
                        <field>
                            <name>GAFLIFL0</name>
                            <description>Global Acceptance Filter List Information Label 0</description>
                            <lsb>7</lsb>
                            <msb>7</msb>
                            <access>read-write</access>
                        </field>
                        <field>
                            <name>GAFLRMDP</name>
                            <description>Global Acceptance Filter List RX Message Buffer Direction Pointer</description>
                            <lsb>8</lsb>
                            <msb>12</msb>
                            <access>read-write</access>
                        </field>
                        <field>
                            <name>GAFLRMV</name>
                            <description>Global Acceptance Filter List RX Message Buffer Valid</description>
                            <lsb>15</lsb>
                            <msb>15</msb>
                            <access>read-write</access>
                            <enumeratedValues>
                                <enumeratedValue>
                                    <name>0</name>
                                    <description>Single message buffer direction pointer is invalid</description>
                                    <value>#0</value>
                                </enumeratedValue>
                                <enumeratedValue>
                                    <name>1</name>
                                    <description>Single message buffer direction pointer is valid</description>
                                    <value>#1</value>
                                </enumeratedValue>
                            </enumeratedValues>
                        </field>
                        <field>
                            <name>GAFLPTR</name>
                            <description>Global Acceptance Filter List Pointer</description>
                            <lsb>16</lsb>
                            <msb>31</msb>
                            <access>read-write</access>
                        </field>
                    </fields>
                </register>
                <register>
                    <dim>16</dim>
                    <dimIncrement>0x0010</dimIncrement>
                    <dimIndex>1-16</dimIndex>
                    <name>CFDGAFLP1%s</name>
                    <description>Global Acceptance Filter List Pointer 1 Registers</description>
                    <addressOffset>0x012C</addressOffset>
                    <size>32</size>
                    <access>read-write</access>
                    <resetValue>0x00000000</resetValue>
                    <resetMask>0xffffffff</resetMask>
                    <fields>
                        <field>
                            <name>GAFLFDP0</name>
                            <description>Global Acceptance Filter List FIFO Direction Pointer</description>
                            <lsb>0</lsb>
                            <msb>0</msb>
                            <access>read-write</access>
                            <enumeratedValues>
                                <enumeratedValue>
                                    <name>0</name>
                                    <description>Disable RX FIFO 0 as target for reception</description>
                                    <value>#0</value>
                                </enumeratedValue>
                                <enumeratedValue>
                                    <name>1</name>
                                    <description>Enable RX FIFO 0 as target for reception</description>
                                    <value>#1</value>
                                </enumeratedValue>
                            </enumeratedValues>
                        </field>
                        <field>
                            <name>GAFLFDP1</name>
                            <description>Global Acceptance Filter List FIFO Direction Pointer</description>
                            <lsb>1</lsb>
                            <msb>1</msb>
                            <access>read-write</access>
                            <enumeratedValues>
                                <enumeratedValue>
                                    <name>0</name>
                                    <description>Disable RX FIFO 1 as target for reception</description>
                                    <value>#0</value>
                                </enumeratedValue>
                                <enumeratedValue>
                                    <name>1</name>
                                    <description>Enable RX FIFO 1 as target for reception</description>
                                    <value>#1</value>
                                </enumeratedValue>
                            </enumeratedValues>
                        </field>
                        <field>
                            <name>GAFLFDP8</name>
                            <description>Global Acceptance Filter List FIFO Direction Pointer</description>
                            <lsb>8</lsb>
                            <msb>8</msb>
                            <access>read-write</access>
                            <enumeratedValues>
                                <enumeratedValue>
                                    <name>0</name>
                                    <description>Disable Common FIFO as target for reception</description>
                                    <value>#0</value>
                                </enumeratedValue>
                                <enumeratedValue>
                                    <name>1</name>
                                    <description>Enable Common FIFO as target for reception</description>
                                    <value>#1</value>
                                </enumeratedValue>
                            </enumeratedValues>
                        </field>
                    </fields>
                </register>
                <register>
                    <dim>64</dim>
                    <dimIncrement>0x0004</dimIncrement>
                    <dimIndex>0-63</dimIndex>
                    <name>CFDRPGACC%s</name>
                    <description>RAM Test Page Access Registers %s</description>
                    <addressOffset>0x0280</addressOffset>
                    <size>32</size>
                    <access>read-write</access>
                    <resetValue>0x00000000</resetValue>
                    <resetMask>0xffffffff</resetMask>
                    <fields>
                        <field>
                            <name>RDTA</name>
                            <description>RAM Data Test Access</description>
                            <lsb>0</lsb>
                            <msb>31</msb>
                            <access>read-write</access>
                        </field>
                    </fields>
                </register>
                <register>
                    <dim>2</dim>
                    <dimIncrement>0x004C</dimIncrement>
                    <dimIndex>0-1</dimIndex>
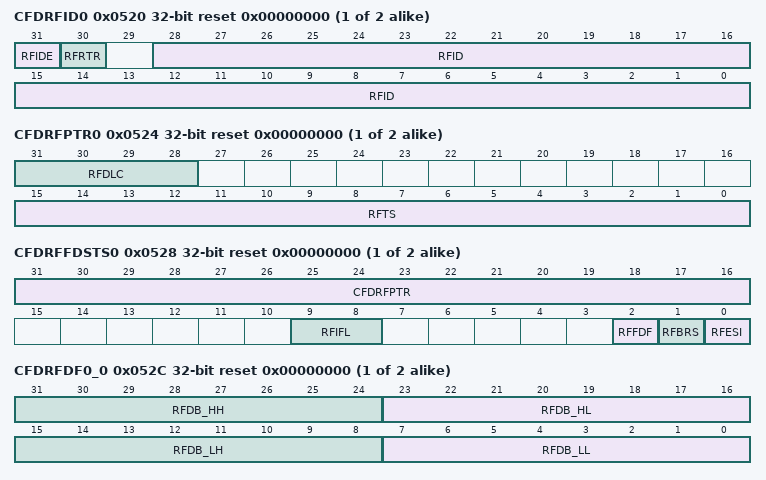
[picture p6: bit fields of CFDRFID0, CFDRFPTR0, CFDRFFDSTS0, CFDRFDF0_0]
                    <name>CFDRFID%s</name>
                    <description>RX FIFO Access ID Register %s</description>
                    <addressOffset>0x0520</addressOffset>
                    <size>32</size>
                    <access>read-only</access>
                    <resetValue>0x00000000</resetValue>
                    <resetMask>0xffffffff</resetMask>
                    <fields>
                        <field>
                            <name>RFID</name>
                            <description>RX FIFO Buffer ID Field</description>
                            <lsb>0</lsb>
                            <msb>28</msb>
                            <access>read-only</access>
                        </field>
                        <field>
                            <name>RFRTR</name>
                            <description>RX FIFO Buffer RTR bit</description>
                            <lsb>30</lsb>
                            <msb>30</msb>
                            <access>read-only</access>
                            <enumeratedValues>
                                <enumeratedValue>
                                    <name>0</name>
                                    <description>Data frame</description>
                                    <value>#0</value>
                                </enumeratedValue>
                                <enumeratedValue>
                                    <name>1</name>
                                    <description>Remote frame</description>
                                    <value>#1</value>
                                </enumeratedValue>
                            </enumeratedValues>
                        </field>
                        <field>
                            <name>RFIDE</name>
                            <description>RX FIFO Buffer IDE bit</description>
                            <lsb>31</lsb>
                            <msb>31</msb>
                            <access>read-only</access>
                            <enumeratedValues>
                                <enumeratedValue>
                                    <name>0</name>
                                    <description>STD-ID has been received</description>
                                    <value>#0</value>
                                </enumeratedValue>
                                <enumeratedValue>
                                    <name>1</name>
                                    <description>EXT-ID has been received</description>
                                    <value>#1</value>
                                </enumeratedValue>
                            </enumeratedValues>
                        </field>
                    </fields>
                </register>
                <register>
                    <dim>2</dim>
                    <dimIncrement>0x004C</dimIncrement>
                    <dimIndex>0-1</dimIndex>
                    <name>CFDRFPTR%s</name>
                    <description>RX FIFO Access Pointer Register %s</description>
                    <addressOffset>0x0524</addressOffset>
                    <size>32</size>
                    <access>read-only</access>
                    <resetValue>0x00000000</resetValue>
                    <resetMask>0xffffffff</resetMask>
                    <fields>
                        <field>
                            <name>RFTS</name>
                            <description>RX FIFO Timestamp Value</description>
                            <lsb>0</lsb>
                            <msb>15</msb>
                            <access>read-only</access>
                        </field>
                        <field>
                            <name>RFDLC</name>
                            <description>RX FIFO Buffer DLC Field</description>
                            <lsb>28</lsb>
                            <msb>31</msb>
                            <access>read-only</access>
                        </field>
                    </fields>
                </register>
                <register>
                    <dim>2</dim>
                    <dimIncrement>0x004C</dimIncrement>
                    <dimIndex>0-1</dimIndex>
                    <name>CFDRFFDSTS%s</name>
                    <description>RX FIFO Access CANFD Status Register %s</description>
                    <addressOffset>0x0528</addressOffset>
                    <size>32</size>
                    <access>read-only</access>
                    <resetValue>0x00000000</resetValue>
                    <resetMask>0xffffffff</resetMask>
                    <fields>
                        <field>
                            <name>RFESI</name>
                            <description>Error State Indicator bit</description>
                            <lsb>0</lsb>
                            <msb>0</msb>
                            <access>read-only</access>
                            <enumeratedValues>
                                <enumeratedValue>
                                    <name>0</name>
                                    <description>CANFD frame received from error active node</description>
                                    <value>#0</value>
                                </enumeratedValue>
                                <enumeratedValue>
                                    <name>1</name>
                                    <description>CANFD frame received from error passive node</description>
                                    <value>#1</value>
                                </enumeratedValue>
                            </enumeratedValues>
                        </field>
                        <field>
                            <name>RFBRS</name>
                            <description>Bit Rate Switch bit</description>
                            <lsb>1</lsb>
                            <msb>1</msb>
                            <access>read-only</access>
                            <enumeratedValues>
                                <enumeratedValue>
                                    <name>0</name>
                                    <description>CANFD frame received with no bit rate switch</description>
                                    <value>#0</value>
                                </enumeratedValue>
                                <enumeratedValue>
                                    <name>1</name>
                                    <description>CANFD frame received with bit rate switch</description>
                                    <value>#1</value>
                                </enumeratedValue>
                            </enumeratedValues>
                        </field>
                        <field>
                            <name>RFFDF</name>
                            <description>CAN FD Format bit</description>
                            <lsb>2</lsb>
                            <msb>2</msb>
                            <access>read-only</access>
                            <enumeratedValues>
                                <enumeratedValue>
                                    <name>0</name>
                                    <description>Non CANFD frame received</description>
                                    <value>#0</value>
                                </enumeratedValue>
                                <enumeratedValue>
                                    <name>1</name>
                                    <description>CANFD frame received</description>
                                    <value>#1</value>
                                </enumeratedValue>
                            </enumeratedValues>
                        </field>
                        <field>
                            <name>RFIFL</name>
                            <description>RX FIFO Buffer Information Label Field</description>
                            <lsb>8</lsb>
                            <msb>9</msb>
                            <access>read-only</access>
                        </field>
                        <field>
                            <name>CFDRFPTR</name>
                            <description>RX FIFO Buffer Pointer Field</description>
                            <lsb>16</lsb>
                            <msb>31</msb>
                            <access>read-only</access>
                        </field>
                    </fields>
                </register>
                <register>
                    <dim>2</dim>
                    <dimIncrement>0x04C</dimIncrement>
                    <dimIndex>0-1</dimIndex>
                    <name>CFDRFDF%s_0</name>
                    <description>RX FIFO Access Data Field 0 Register %s</description>
                    <addressOffset>0x052C</addressOffset>
                    <size>32</size>
                    <access>read-only</access>
                    <resetValue>0x00000000</resetValue>
                    <resetMask>0xffffffff</resetMask>
                    <fields>
                        <field>
                            <name>RFDB_LL</name>
                            <description>RX FIFO Buffer Data Byte (p × 4)</description>
                            <lsb>0</lsb>
                            <msb>7</msb>
                            <access>read-only</access>
                        </field>
                        <field>
                            <name>RFDB_LH</name>
                            <description>RX FIFO Buffer Data Byte ((p × 4) + 1)</description>
                            <lsb>8</lsb>
                            <msb>15</msb>
                            <access>read-only</access>
                        </field>
                        <field>
                            <name>RFDB_HL</name>
                            <description>RX FIFO Buffer Data Byte ((p × 4) + 2)</description>
                            <lsb>16</lsb>
                            <msb>23</msb>
                            <access>read-only</access>
                        </field>
                        <field>
                            <name>RFDB_HH</name>
                            <description>RX FIFO Buffer Data Byte ((p × 4) + 3)</description>
                            <lsb>24</lsb>
                            <msb>31</msb>
                            <access>read-only</access>
                        </field>
                    </fields>
                </register>
                <register>
                    <dim>2</dim>
                    <dimIncrement>0x04C</dimIncrement>
                    <dimIndex>0-1</dimIndex>
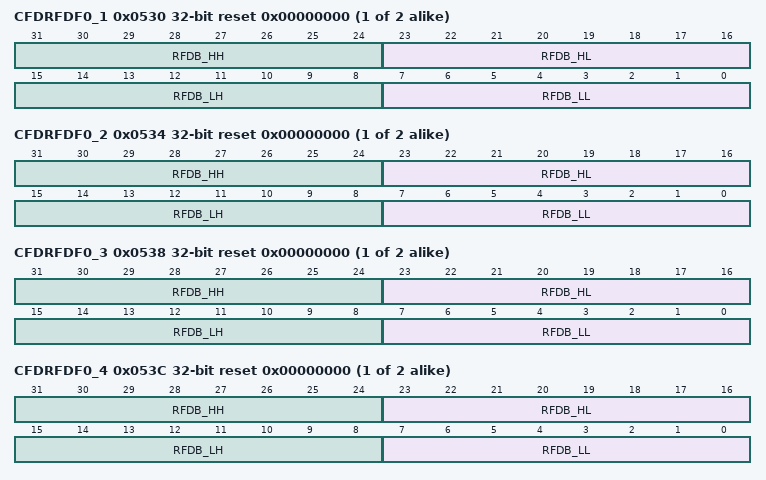
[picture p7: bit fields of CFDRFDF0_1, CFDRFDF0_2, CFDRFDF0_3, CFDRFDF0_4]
                    <name>CFDRFDF%s_1</name>
                    <description>RX FIFO Access Data Field 1 Register %s</description>
                    <addressOffset>0x0530</addressOffset>
                    <size>32</size>
                    <access>read-only</access>
                    <resetValue>0x00000000</resetValue>
                    <resetMask>0xffffffff</resetMask>
                    <fields>
                        <field>
                            <name>RFDB_LL</name>
                            <description>RX FIFO Buffer Data Byte (p × 4)</description>
                            <lsb>0</lsb>
                            <msb>7</msb>
                            <access>read-only</access>
                        </field>
                        <field>
                            <name>RFDB_LH</name>
                            <description>RX FIFO Buffer Data Byte ((p × 4) + 1)</description>
                            <lsb>8</lsb>
                            <msb>15</msb>
                            <access>read-only</access>
                        </field>
                        <field>
                            <name>RFDB_HL</name>
                            <description>RX FIFO Buffer Data Byte ((p × 4) + 2)</description>
                            <lsb>16</lsb>
                            <msb>23</msb>
                            <access>read-only</access>
                        </field>
                        <field>
                            <name>RFDB_HH</name>
                            <description>RX FIFO Buffer Data Byte ((p × 4) + 3)</description>
                            <lsb>24</lsb>
                            <msb>31</msb>
                            <access>read-only</access>
                        </field>
                    </fields>
                </register>
                <register>
                    <dim>2</dim>
                    <dimIncrement>0x04C</dimIncrement>
                    <dimIndex>0-1</dimIndex>
                    <name>CFDRFDF%s_2</name>
                    <description>RX FIFO Access Data Field 2 Register %s</description>
                    <addressOffset>0x0534</addressOffset>
                    <size>32</size>
                    <access>read-only</access>
                    <resetValue>0x00000000</resetValue>
                    <resetMask>0xffffffff</resetMask>
                    <fields>
                        <field>
                            <name>RFDB_LL</name>
                            <description>RX FIFO Buffer Data Byte (p × 4)</description>
                            <lsb>0</lsb>
                            <msb>7</msb>
                            <access>read-only</access>
                        </field>
                        <field>
                            <name>RFDB_LH</name>
                            <description>RX FIFO Buffer Data Byte ((p × 4) + 1)</description>
                            <lsb>8</lsb>
                            <msb>15</msb>
                            <access>read-only</access>
                        </field>
                        <field>
                            <name>RFDB_HL</name>
                            <description>RX FIFO Buffer Data Byte ((p × 4) + 2)</description>
                            <lsb>16</lsb>
                            <msb>23</msb>
                            <access>read-only</access>
                        </field>
                        <field>
                            <name>RFDB_HH</name>
                            <description>RX FIFO Buffer Data Byte ((p × 4) + 3)</description>
                            <lsb>24</lsb>
                            <msb>31</msb>
                            <access>read-only</access>
                        </field>
                    </fields>
                </register>
                <register>
                    <dim>2</dim>
                    <dimIncrement>0x04C</dimIncrement>
                    <dimIndex>0-1</dimIndex>
                    <name>CFDRFDF%s_3</name>
                    <description>RX FIFO Access Data Field 3 Register %s</description>
                    <addressOffset>0x0538</addressOffset>
                    <size>32</size>
                    <access>read-only</access>
                    <resetValue>0x00000000</resetValue>
                    <resetMask>0xffffffff</resetMask>
                    <fields>
                        <field>
                            <name>RFDB_LL</name>
                            <description>RX FIFO Buffer Data Byte (p × 4)</description>
                            <lsb>0</lsb>
                            <msb>7</msb>
                            <access>read-only</access>
                        </field>
                        <field>
                            <name>RFDB_LH</name>
                            <description>RX FIFO Buffer Data Byte ((p × 4) + 1)</description>
                            <lsb>8</lsb>
                            <msb>15</msb>
                            <access>read-only</access>
                        </field>
                        <field>
                            <name>RFDB_HL</name>
                            <description>RX FIFO Buffer Data Byte ((p × 4) + 2)</description>
                            <lsb>16</lsb>
                            <msb>23</msb>
                            <access>read-only</access>
                        </field>
                        <field>
                            <name>RFDB_HH</name>
                            <description>RX FIFO Buffer Data Byte ((p × 4) + 3)</description>
                            <lsb>24</lsb>
                            <msb>31</msb>
                            <access>read-only</access>
                        </field>
                    </fields>
                </register>
                <register>
                    <dim>2</dim>
                    <dimIncrement>0x04C</dimIncrement>
                    <dimIndex>0-1</dimIndex>
                    <name>CFDRFDF%s_4</name>
                    <description>RX FIFO Access Data Field 4 Register %s</description>
                    <addressOffset>0x053C</addressOffset>
                    <size>32</size>
                    <access>read-only</access>
                    <resetValue>0x00000000</resetValue>
                    <resetMask>0xffffffff</resetMask>
                    <fields>
                        <field>
                            <name>RFDB_LL</name>
                            <description>RX FIFO Buffer Data Byte (p × 4)</description>
                            <lsb>0</lsb>
                            <msb>7</msb>
                            <access>read-only</access>
                        </field>
                        <field>
                            <name>RFDB_LH</name>
                            <description>RX FIFO Buffer Data Byte ((p × 4) + 1)</description>
                            <lsb>8</lsb>
                            <msb>15</msb>
                            <access>read-only</access>
                        </field>
                        <field>
                            <name>RFDB_HL</name>
                            <description>RX FIFO Buffer Data Byte ((p × 4) + 2)</description>
                            <lsb>16</lsb>
                            <msb>23</msb>
                            <access>read-only</access>
                        </field>
                        <field>
                            <name>RFDB_HH</name>
                            <description>RX FIFO Buffer Data Byte ((p × 4) + 3)</description>
                            <lsb>24</lsb>
                            <msb>31</msb>
                            <access>read-only</access>
                        </field>
                    </fields>
                </register>
                <register>
                    <dim>2</dim>
                    <dimIncrement>0x04C</dimIncrement>
                    <dimIndex>0-1</dimIndex>
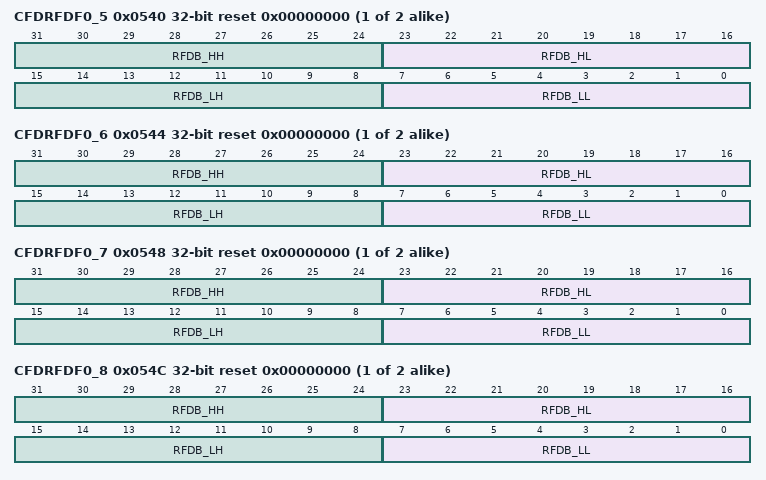
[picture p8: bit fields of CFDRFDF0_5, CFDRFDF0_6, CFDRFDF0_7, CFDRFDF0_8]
                    <name>CFDRFDF%s_5</name>
                    <description>RX FIFO Access Data Field 5 Register %s</description>
                    <addressOffset>0x0540</addressOffset>
                    <size>32</size>
                    <access>read-only</access>
                    <resetValue>0x00000000</resetValue>
                    <resetMask>0xffffffff</resetMask>
                    <fields>
                        <field>
                            <name>RFDB_LL</name>
                            <description>RX FIFO Buffer Data Byte (p × 4)</description>
                            <lsb>0</lsb>
                            <msb>7</msb>
                            <access>read-only</access>
                        </field>
                        <field>
                            <name>RFDB_LH</name>
                            <description>RX FIFO Buffer Data Byte ((p × 4) + 1)</description>
                            <lsb>8</lsb>
                            <msb>15</msb>
                            <access>read-only</access>
                        </field>
                        <field>
                            <name>RFDB_HL</name>
                            <description>RX FIFO Buffer Data Byte ((p × 4) + 2)</description>
                            <lsb>16</lsb>
                            <msb>23</msb>
                            <access>read-only</access>
                        </field>
                        <field>
                            <name>RFDB_HH</name>
                            <description>RX FIFO Buffer Data Byte ((p × 4) + 3)</description>
                            <lsb>24</lsb>
                            <msb>31</msb>
                            <access>read-only</access>
                        </field>
                    </fields>
                </register>
                <register>
                    <dim>2</dim>
                    <dimIncrement>0x04C</dimIncrement>
                    <dimIndex>0-1</dimIndex>
                    <name>CFDRFDF%s_6</name>
                    <description>RX FIFO Access Data Field 6 Register %s</description>
                    <addressOffset>0x0544</addressOffset>
                    <size>32</size>
                    <access>read-only</access>
                    <resetValue>0x00000000</resetValue>
                    <resetMask>0xffffffff</resetMask>
                    <fields>
                        <field>
                            <name>RFDB_LL</name>
                            <description>RX FIFO Buffer Data Byte (p × 4)</description>
                            <lsb>0</lsb>
                            <msb>7</msb>
                            <access>read-only</access>
                        </field>
                        <field>
                            <name>RFDB_LH</name>
                            <description>RX FIFO Buffer Data Byte ((p × 4) + 1)</description>
                            <lsb>8</lsb>
                            <msb>15</msb>
                            <access>read-only</access>
                        </field>
                        <field>
                            <name>RFDB_HL</name>
                            <description>RX FIFO Buffer Data Byte ((p × 4) + 2)</description>
                            <lsb>16</lsb>
                            <msb>23</msb>
                            <access>read-only</access>
                        </field>
                        <field>
                            <name>RFDB_HH</name>
                            <description>RX FIFO Buffer Data Byte ((p × 4) + 3)</description>
                            <lsb>24</lsb>
                            <msb>31</msb>
                            <access>read-only</access>
                        </field>
                    </fields>
                </register>
                <register>
                    <dim>2</dim>
                    <dimIncrement>0x04C</dimIncrement>
                    <dimIndex>0-1</dimIndex>
                    <name>CFDRFDF%s_7</name>
                    <description>RX FIFO Access Data Field 7 Register %s</description>
                    <addressOffset>0x0548</addressOffset>
                    <size>32</size>
                    <access>read-only</access>
                    <resetValue>0x00000000</resetValue>
                    <resetMask>0xffffffff</resetMask>
                    <fields>
                        <field>
                            <name>RFDB_LL</name>
                            <description>RX FIFO Buffer Data Byte (p × 4)</description>
                            <lsb>0</lsb>
                            <msb>7</msb>
                            <access>read-only</access>
                        </field>
                        <field>
                            <name>RFDB_LH</name>
                            <description>RX FIFO Buffer Data Byte ((p × 4) + 1)</description>
                            <lsb>8</lsb>
                            <msb>15</msb>
                            <access>read-only</access>
                        </field>
                        <field>
                            <name>RFDB_HL</name>
                            <description>RX FIFO Buffer Data Byte ((p × 4) + 2)</description>
                            <lsb>16</lsb>
                            <msb>23</msb>
                            <access>read-only</access>
                        </field>
                        <field>
                            <name>RFDB_HH</name>
                            <description>RX FIFO Buffer Data Byte ((p × 4) + 3)</description>
                            <lsb>24</lsb>
                            <msb>31</msb>
                            <access>read-only</access>
                        </field>
                    </fields>
                </register>
                <register>
                    <dim>2</dim>
                    <dimIncrement>0x04C</dimIncrement>
                    <dimIndex>0-1</dimIndex>
                    <name>CFDRFDF%s_8</name>
                    <description>RX FIFO Access Data Field 8 Register %s</description>
                    <addressOffset>0x054C</addressOffset>
                    <size>32</size>
                    <access>read-only</access>
                    <resetValue>0x00000000</resetValue>
                    <resetMask>0xffffffff</resetMask>
                    <fields>
                        <field>
                            <name>RFDB_LL</name>
                            <description>RX FIFO Buffer Data Byte (p × 4)</description>
                            <lsb>0</lsb>
                            <msb>7</msb>
                            <access>read-only</access>
                        </field>
                        <field>
                            <name>RFDB_LH</name>
                            <description>RX FIFO Buffer Data Byte ((p × 4) + 1)</description>
                            <lsb>8</lsb>
                            <msb>15</msb>
                            <access>read-only</access>
                        </field>
                        <field>
                            <name>RFDB_HL</name>
                            <description>RX FIFO Buffer Data Byte ((p × 4) + 2)</description>
                            <lsb>16</lsb>
                            <msb>23</msb>
                            <access>read-only</access>
                        </field>
                        <field>
                            <name>RFDB_HH</name>
                            <description>RX FIFO Buffer Data Byte ((p × 4) + 3)</description>
                            <lsb>24</lsb>
                            <msb>31</msb>
                            <access>read-only</access>
                        </field>
                    </fields>
                </register>
                <register>
                    <dim>2</dim>
                    <dimIncrement>0x04C</dimIncrement>
                    <dimIndex>0-1</dimIndex>
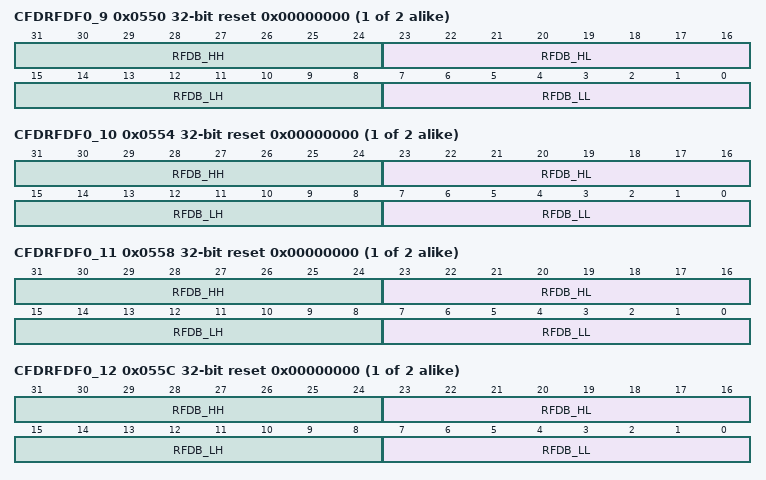
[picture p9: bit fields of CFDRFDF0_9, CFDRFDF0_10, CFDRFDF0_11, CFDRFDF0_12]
                    <name>CFDRFDF%s_9</name>
                    <description>RX FIFO Access Data Field 9 Register %s</description>
                    <addressOffset>0x0550</addressOffset>
                    <size>32</size>
                    <access>read-only</access>
                    <resetValue>0x00000000</resetValue>
                    <resetMask>0xffffffff</resetMask>
                    <fields>
                        <field>
                            <name>RFDB_LL</name>
                            <description>RX FIFO Buffer Data Byte (p × 4)</description>
                            <lsb>0</lsb>
                            <msb>7</msb>
                            <access>read-only</access>
                        </field>
                        <field>
                            <name>RFDB_LH</name>
                            <description>RX FIFO Buffer Data Byte ((p × 4) + 1)</description>
                            <lsb>8</lsb>
                            <msb>15</msb>
                            <access>read-only</access>
                        </field>
                        <field>
                            <name>RFDB_HL</name>
                            <description>RX FIFO Buffer Data Byte ((p × 4) + 2)</description>
                            <lsb>16</lsb>
                            <msb>23</msb>
                            <access>read-only</access>
                        </field>
                        <field>
                            <name>RFDB_HH</name>
                            <description>RX FIFO Buffer Data Byte ((p × 4) + 3)</description>
                            <lsb>24</lsb>
                            <msb>31</msb>
                            <access>read-only</access>
                        </field>
                    </fields>
                </register>
                <register>
                    <dim>2</dim>
                    <dimIncrement>0x04C</dimIncrement>
                    <dimIndex>0-1</dimIndex>
                    <name>CFDRFDF%s_10</name>
                    <description>RX FIFO Access Data Field 10 Register %s</description>
                    <addressOffset>0x0554</addressOffset>
                    <size>32</size>
                    <access>read-only</access>
                    <resetValue>0x00000000</resetValue>
                    <resetMask>0xffffffff</resetMask>
                    <fields>
                        <field>
                            <name>RFDB_LL</name>
                            <description>RX FIFO Buffer Data Byte (p × 4)</description>
                            <lsb>0</lsb>
                            <msb>7</msb>
                            <access>read-only</access>
                        </field>
                        <field>
                            <name>RFDB_LH</name>
                            <description>RX FIFO Buffer Data Byte ((p × 4) + 1)</description>
                            <lsb>8</lsb>
                            <msb>15</msb>
                            <access>read-only</access>
                        </field>
                        <field>
                            <name>RFDB_HL</name>
                            <description>RX FIFO Buffer Data Byte ((p × 4) + 2)</description>
                            <lsb>16</lsb>
                            <msb>23</msb>
                            <access>read-only</access>
                        </field>
                        <field>
                            <name>RFDB_HH</name>
                            <description>RX FIFO Buffer Data Byte ((p × 4) + 3)</description>
                            <lsb>24</lsb>
                            <msb>31</msb>
                            <access>read-only</access>
                        </field>
                    </fields>
                </register>
                <register>
                    <dim>2</dim>
                    <dimIncrement>0x04C</dimIncrement>
                    <dimIndex>0-1</dimIndex>
                    <name>CFDRFDF%s_11</name>
                    <description>RX FIFO Access Data Field 11 Register %s</description>
                    <addressOffset>0x0558</addressOffset>
                    <size>32</size>
                    <access>read-only</access>
                    <resetValue>0x00000000</resetValue>
                    <resetMask>0xffffffff</resetMask>
                    <fields>
                        <field>
                            <name>RFDB_LL</name>
                            <description>RX FIFO Buffer Data Byte (p × 4)</description>
                            <lsb>0</lsb>
                            <msb>7</msb>
                            <access>read-only</access>
                        </field>
                        <field>
                            <name>RFDB_LH</name>
                            <description>RX FIFO Buffer Data Byte ((p × 4) + 1)</description>
                            <lsb>8</lsb>
                            <msb>15</msb>
                            <access>read-only</access>
                        </field>
                        <field>
                            <name>RFDB_HL</name>
                            <description>RX FIFO Buffer Data Byte ((p × 4) + 2)</description>
                            <lsb>16</lsb>
                            <msb>23</msb>
                            <access>read-only</access>
                        </field>
                        <field>
                            <name>RFDB_HH</name>
                            <description>RX FIFO Buffer Data Byte ((p × 4) + 3)</description>
                            <lsb>24</lsb>
                            <msb>31</msb>
                            <access>read-only</access>
                        </field>
                    </fields>
                </register>
                <register>
                    <dim>2</dim>
                    <dimIncrement>0x04C</dimIncrement>
                    <dimIndex>0-1</dimIndex>
                    <name>CFDRFDF%s_12</name>
                    <description>RX FIFO Access Data Field 12 Register %s</description>
                    <addressOffset>0x055C</addressOffset>
                    <size>32</size>
                    <access>read-only</access>
                    <resetValue>0x00000000</resetValue>
                    <resetMask>0xffffffff</resetMask>
                    <fields>
                        <field>
                            <name>RFDB_LL</name>
                            <description>RX FIFO Buffer Data Byte (p × 4)</description>
                            <lsb>0</lsb>
                            <msb>7</msb>
                            <access>read-only</access>
                        </field>
                        <field>
                            <name>RFDB_LH</name>
                            <description>RX FIFO Buffer Data Byte ((p × 4) + 1)</description>
                            <lsb>8</lsb>
                            <msb>15</msb>
                            <access>read-only</access>
                        </field>
                        <field>
                            <name>RFDB_HL</name>
                            <description>RX FIFO Buffer Data Byte ((p × 4) + 2)</description>
                            <lsb>16</lsb>
                            <msb>23</msb>
                            <access>read-only</access>
                        </field>
                        <field>
                            <name>RFDB_HH</name>
                            <description>RX FIFO Buffer Data Byte ((p × 4) + 3)</description>
                            <lsb>24</lsb>
                            <msb>31</msb>
                            <access>read-only</access>
                        </field>
                    </fields>
                </register>
                <register>
                    <dim>2</dim>
                    <dimIncrement>0x04C</dimIncrement>
                    <dimIndex>0-1</dimIndex>
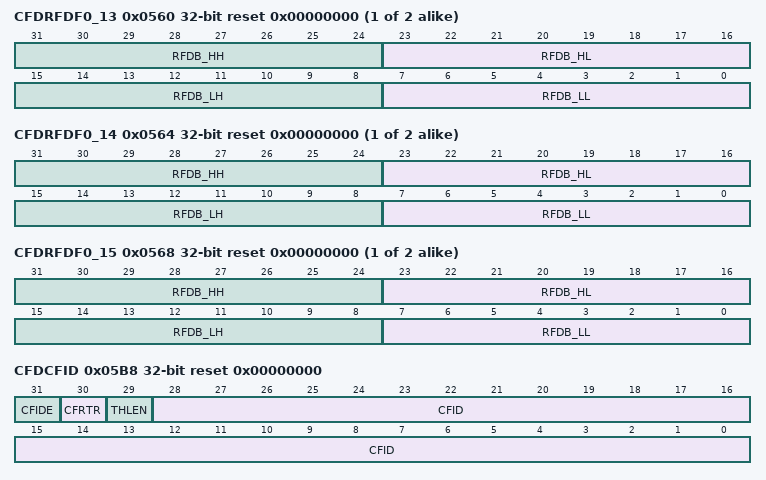
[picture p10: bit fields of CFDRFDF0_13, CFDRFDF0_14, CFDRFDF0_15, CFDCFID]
                    <name>CFDRFDF%s_13</name>
                    <description>RX FIFO Access Data Field 13 Register %s</description>
                    <addressOffset>0x0560</addressOffset>
                    <size>32</size>
                    <access>read-only</access>
                    <resetValue>0x00000000</resetValue>
                    <resetMask>0xffffffff</resetMask>
                    <fields>
                        <field>
                            <name>RFDB_LL</name>
                            <description>RX FIFO Buffer Data Byte (p × 4)</description>
                            <lsb>0</lsb>
                            <msb>7</msb>
                            <access>read-only</access>
                        </field>
                        <field>
                            <name>RFDB_LH</name>
                            <description>RX FIFO Buffer Data Byte ((p × 4) + 1)</description>
                            <lsb>8</lsb>
                            <msb>15</msb>
                            <access>read-only</access>
                        </field>
                        <field>
                            <name>RFDB_HL</name>
                            <description>RX FIFO Buffer Data Byte ((p × 4) + 2)</description>
                            <lsb>16</lsb>
                            <msb>23</msb>
                            <access>read-only</access>
                        </field>
                        <field>
                            <name>RFDB_HH</name>
                            <description>RX FIFO Buffer Data Byte ((p × 4) + 3)</description>
                            <lsb>24</lsb>
                            <msb>31</msb>
                            <access>read-only</access>
                        </field>
                    </fields>
                </register>
                <register>
                    <dim>2</dim>
                    <dimIncrement>0x04C</dimIncrement>
                    <dimIndex>0-1</dimIndex>
                    <name>CFDRFDF%s_14</name>
                    <description>RX FIFO Access Data Field 14 Register %s</description>
                    <addressOffset>0x0564</addressOffset>
                    <size>32</size>
                    <access>read-only</access>
                    <resetValue>0x00000000</resetValue>
                    <resetMask>0xffffffff</resetMask>
                    <fields>
                        <field>
                            <name>RFDB_LL</name>
                            <description>RX FIFO Buffer Data Byte (p × 4)</description>
                            <lsb>0</lsb>
                            <msb>7</msb>
                            <access>read-only</access>
                        </field>
                        <field>
                            <name>RFDB_LH</name>
                            <description>RX FIFO Buffer Data Byte ((p × 4) + 1)</description>
                            <lsb>8</lsb>
                            <msb>15</msb>
                            <access>read-only</access>
                        </field>
                        <field>
                            <name>RFDB_HL</name>
                            <description>RX FIFO Buffer Data Byte ((p × 4) + 2)</description>
                            <lsb>16</lsb>
                            <msb>23</msb>
                            <access>read-only</access>
                        </field>
                        <field>
                            <name>RFDB_HH</name>
                            <description>RX FIFO Buffer Data Byte ((p × 4) + 3)</description>
                            <lsb>24</lsb>
                            <msb>31</msb>
                            <access>read-only</access>
                        </field>
                    </fields>
                </register>
                <register>
                    <dim>2</dim>
                    <dimIncrement>0x04C</dimIncrement>
                    <dimIndex>0-1</dimIndex>
                    <name>CFDRFDF%s_15</name>
                    <description>RX FIFO Access Data Field 15 Register %s</description>
                    <addressOffset>0x0568</addressOffset>
                    <size>32</size>
                    <access>read-only</access>
                    <resetValue>0x00000000</resetValue>
                    <resetMask>0xffffffff</resetMask>
                    <fields>
                        <field>
                            <name>RFDB_LL</name>
                            <description>RX FIFO Buffer Data Byte (p × 4)</description>
                            <lsb>0</lsb>
                            <msb>7</msb>
                            <access>read-only</access>
                        </field>
                        <field>
                            <name>RFDB_LH</name>
                            <description>RX FIFO Buffer Data Byte ((p × 4) + 1)</description>
                            <lsb>8</lsb>
                            <msb>15</msb>
                            <access>read-only</access>
                        </field>
                        <field>
                            <name>RFDB_HL</name>
                            <description>RX FIFO Buffer Data Byte ((p × 4) + 2)</description>
                            <lsb>16</lsb>
                            <msb>23</msb>
                            <access>read-only</access>
                        </field>
                        <field>
                            <name>RFDB_HH</name>
                            <description>RX FIFO Buffer Data Byte ((p × 4) + 3)</description>
                            <lsb>24</lsb>
                            <msb>31</msb>
                            <access>read-only</access>
                        </field>
                    </fields>
                </register>
                <register>
                    <name>CFDCFID</name>
                    <description>Common FIFO Access ID Register</description>
                    <addressOffset>0x05B8</addressOffset>
                    <size>32</size>
                    <access>read-write</access>
                    <resetValue>0x00000000</resetValue>
                    <resetMask>0xffffffff</resetMask>
                    <fields>
                        <field>
                            <name>CFID</name>
                            <description>Common FIFO Buffer ID Field</description>
                            <lsb>0</lsb>
                            <msb>28</msb>
                            <access>read-write</access>
                        </field>
                        <field>
                            <name>THLEN</name>
                            <description>THL Entry enable</description>
                            <lsb>29</lsb>
                            <msb>29</msb>
                            <access>read-write</access>
                            <enumeratedValues>
                                <enumeratedValue>
                                    <name>0</name>
                                    <description>Entry will not be stored in THL after successful TX.</description>
                                    <value>#0</value>
                                </enumeratedValue>
                                <enumeratedValue>
                                    <name>1</name>
                                    <description>Entry will be stored in THL after successful TX.</description>
                                    <value>#1</value>
                                </enumeratedValue>
                            </enumeratedValues>
                        </field>
                        <field>
                            <name>CFRTR</name>
                            <description>Common FIFO Buffer RTR Bit</description>
                            <lsb>30</lsb>
                            <msb>30</msb>
                            <access>read-write</access>
                            <enumeratedValues>
                                <enumeratedValue>
                                    <name>0</name>
                                    <description>Data Frame</description>
                                    <value>#0</value>
                                </enumeratedValue>
                                <enumeratedValue>
                                    <name>1</name>
                                    <description>Remote Frame</description>
                                    <value>#1</value>
                                </enumeratedValue>
                            </enumeratedValues>
                        </field>
                        <field>
                            <name>CFIDE</name>
                            <description>Common FIFO Buffer IDE Bit</description>
                            <lsb>31</lsb>
                            <msb>31</msb>
                            <access>read-write</access>
                            <enumeratedValues>
                                <enumeratedValue>
                                    <name>0</name>
                                    <description>STD-ID will be transmitted or has been received</description>
                                    <value>#0</value>
                                </enumeratedValue>
                                <enumeratedValue>
                                    <name>1</name>
                                    <description>EXT-ID will be transmitted or has been received</description>
                                    <value>#1</value>
                                </enumeratedValue>
                            </enumeratedValues>
                        </field>
                    </fields>
                </register>
                <register>
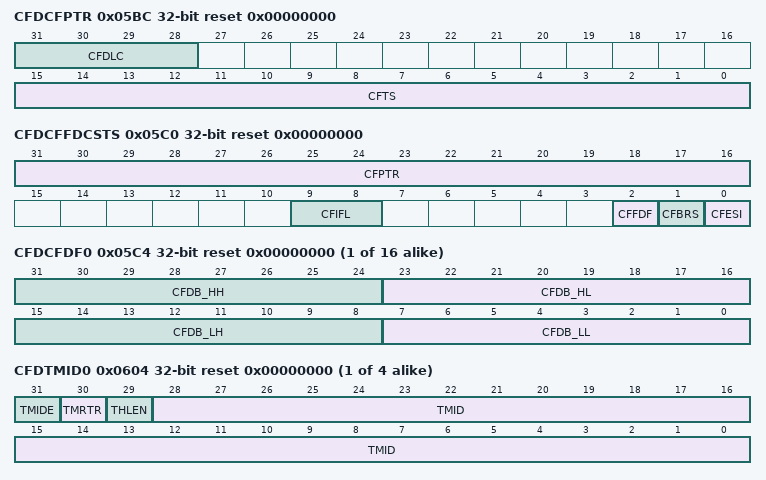
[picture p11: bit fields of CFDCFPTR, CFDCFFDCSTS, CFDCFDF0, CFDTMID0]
                    <name>CFDCFPTR</name>
                    <description>Common FIFO Access Pointer Register</description>
                    <addressOffset>0x05BC</addressOffset>
                    <size>32</size>
                    <access>read-write</access>
                    <resetValue>0x00000000</resetValue>
                    <resetMask>0xffffffff</resetMask>
                    <fields>
                        <field>
                            <name>CFTS</name>
                            <description>Common FIFO Timestamp Value</description>
                            <lsb>0</lsb>
                            <msb>15</msb>
                            <access>read-write</access>
                        </field>
                        <field>
                            <name>CFDLC</name>
                            <description>Common FIFO Buffer DLC Field</description>
                            <lsb>28</lsb>
                            <msb>31</msb>
                            <access>read-write</access>
                        </field>
                    </fields>
                </register>
                <register>
                    <name>CFDCFFDCSTS</name>
                    <description>Common FIFO Access CANFD Control/Status Register</description>
                    <addressOffset>0x05C0</addressOffset>
                    <size>32</size>
                    <access>read-write</access>
                    <resetValue>0x00000000</resetValue>
                    <resetMask>0xffffffff</resetMask>
                    <fields>
                        <field>
                            <name>CFESI</name>
                            <description>Error State Indicator bit</description>
                            <lsb>0</lsb>
                            <msb>0</msb>
                            <access>read-write</access>
                            <enumeratedValues>
                                <enumeratedValue>
                                    <name>0</name>
                                    <description>CANFD frame received or to transmit by error active node</description>
                                    <value>#0</value>
                                </enumeratedValue>
                                <enumeratedValue>
                                    <name>1</name>
                                    <description>CANFD frame received or to transmit by error passive node</description>
                                    <value>#1</value>
                                </enumeratedValue>
                            </enumeratedValues>
                        </field>
                        <field>
                            <name>CFBRS</name>
                            <description>Bit Rate Switch bit</description>
                            <lsb>1</lsb>
                            <msb>1</msb>
                            <access>read-write</access>
                            <enumeratedValues>
                                <enumeratedValue>
                                    <name>0</name>
                                    <description>CANFD frame received or to transmit with no bit rate switch</description>
                                    <value>#0</value>
                                </enumeratedValue>
                                <enumeratedValue>
                                    <name>1</name>
                                    <description>CANFD frame received or to transmit with bit rate switch</description>
                                    <value>#1</value>
                                </enumeratedValue>
                            </enumeratedValues>
                        </field>
                        <field>
                            <name>CFFDF</name>
                            <description>CAN FD Format bit</description>
                            <lsb>2</lsb>
                            <msb>2</msb>
                            <access>read-write</access>
                            <enumeratedValues>
                                <enumeratedValue>
                                    <name>0</name>
                                    <description>Non CANFD frame received or to transmit</description>
                                    <value>#0</value>
                                </enumeratedValue>
                                <enumeratedValue>
                                    <name>1</name>
                                    <description>CANFD frame received or to transmit</description>
                                    <value>#1</value>
                                </enumeratedValue>
                            </enumeratedValues>
                        </field>
                        <field>
                            <name>CFIFL</name>
                            <description>COMMON FIFO Buffer Information Label Field</description>
                            <lsb>8</lsb>
                            <msb>9</msb>
                            <access>read-write</access>
                        </field>
                        <field>
                            <name>CFPTR</name>
                            <description>Common FIFO Buffer Pointer Field</description>
                            <lsb>16</lsb>
                            <msb>31</msb>
                            <access>read-write</access>
                        </field>
                    </fields>
                </register>
                <register>
                    <dim>16</dim>
                    <dimIncrement>0x004</dimIncrement>
                    <dimIndex>0-15</dimIndex>
                    <name>CFDCFDF%s</name>
                    <description>Common FIFO Access Data Field %s Registers</description>
                    <addressOffset>0x05C4</addressOffset>
                    <size>32</size>
                    <access>read-write</access>
                    <resetValue>0x00000000</resetValue>
                    <resetMask>0xffffffff</resetMask>
                    <fields>
                        <field>
                            <name>CFDB_LL</name>
                            <description>Common FIFO Buffer Data Bytes (p × 4)</description>
                            <lsb>0</lsb>
                            <msb>7</msb>
                            <access>read-write</access>
                        </field>
                        <field>
                            <name>CFDB_LH</name>
                            <description>Common FIFO Buffer Data Bytes ((p × 4) + 1)</description>
                            <lsb>8</lsb>
                            <msb>15</msb>
                            <access>read-write</access>
                        </field>
                        <field>
                            <name>CFDB_HL</name>
                            <description>Common FIFO Buffer Data Bytes ((p × 4) + 2)</description>
                            <lsb>16</lsb>
                            <msb>23</msb>
                            <access>read-write</access>
                        </field>
                        <field>
                            <name>CFDB_HH</name>
                            <description>Common FIFO Buffer Data Bytes ((p × 4) + 3)</description>
                            <lsb>24</lsb>
                            <msb>31</msb>
                            <access>read-write</access>
                        </field>
                    </fields>
                </register>
                <register>
                    <dim>4</dim>
                    <dimIncrement>0x004C</dimIncrement>
                    <dimIndex>0-3</dimIndex>
                    <name>CFDTMID%s</name>
                    <description>TX Message Buffer ID Registers</description>
                    <addressOffset>0x0604</addressOffset>
                    <size>32</size>
                    <access>read-write</access>
                    <resetValue>0x00000000</resetValue>
                    <resetMask>0xffffffff</resetMask>
                    <fields>
                        <field>
                            <name>TMID</name>
                            <description>TX Message Buffer ID Field</description>
                            <lsb>0</lsb>
                            <msb>28</msb>
                            <access>read-write</access>
                        </field>
                        <field>
                            <name>THLEN</name>
                            <description>Tx History List Entry</description>
                            <lsb>29</lsb>
                            <msb>29</msb>
                            <access>read-write</access>
                            <enumeratedValues>
                                <enumeratedValue>
                                    <name>0</name>
                                    <description>Entry not stored in THL after successful TX</description>
                                    <value>#0</value>
                                </enumeratedValue>
                                <enumeratedValue>
                                    <name>1</name>
                                    <description>Entry stored in THL after successful TX</description>
                                    <value>#1</value>
                                </enumeratedValue>
                            </enumeratedValues>
                        </field>
                        <field>
                            <name>TMRTR</name>
                            <description>TX Message Buffer RTR bit</description>
                            <lsb>30</lsb>
                            <msb>30</msb>
                            <access>read-write</access>
                            <enumeratedValues>
                                <enumeratedValue>
                                    <name>0</name>
                                    <description>Data frame</description>
                                    <value>#0</value>
                                </enumeratedValue>
                                <enumeratedValue>
                                    <name>1</name>
                                    <description>Remote frame</description>
                                    <value>#1</value>
                                </enumeratedValue>
                            </enumeratedValues>
                        </field>
                        <field>
                            <name>TMIDE</name>
                            <description>TX Message Buffer IDE bit</description>
                            <lsb>31</lsb>
                            <msb>31</msb>
                            <access>read-write</access>
                            <enumeratedValues>
                                <enumeratedValue>
                                    <name>0</name>
                                    <description>STD-ID is transmitted</description>
                                    <value>#0</value>
                                </enumeratedValue>
                                <enumeratedValue>
                                    <name>1</name>
                                    <description>EXT-ID is transmitted</description>
                                    <value>#1</value>
                                </enumeratedValue>
                            </enumeratedValues>
                        </field>
                    </fields>
                </register>
                <register>
                    <dim>4</dim>
                    <dimIncrement>0x004C</dimIncrement>
                    <dimIndex>0-3</dimIndex>
                    <name>CFDTMPTR%s</name>
                    <description>TX Message Buffer Pointer Register </description>
                    <addressOffset>0x0608</addressOffset>
                    <size>32</size>
                    <access>read-write</access>
                    <resetValue>0x00000000</resetValue>
                    <resetMask>0xffffffff</resetMask>
                    <fields>
                        <field>
                            <name>TMDLC</name>
                            <description>TX Message Buffer DLC Field</description>
                            <lsb>28</lsb>
                            <msb>31</msb>
                            <access>read-write</access>
                        </field>
                    </fields>
                </register>
                <register>
                    <dim>4</dim>
                    <dimIncrement>0x004C</dimIncrement>
                    <dimIndex>0-3</dimIndex>
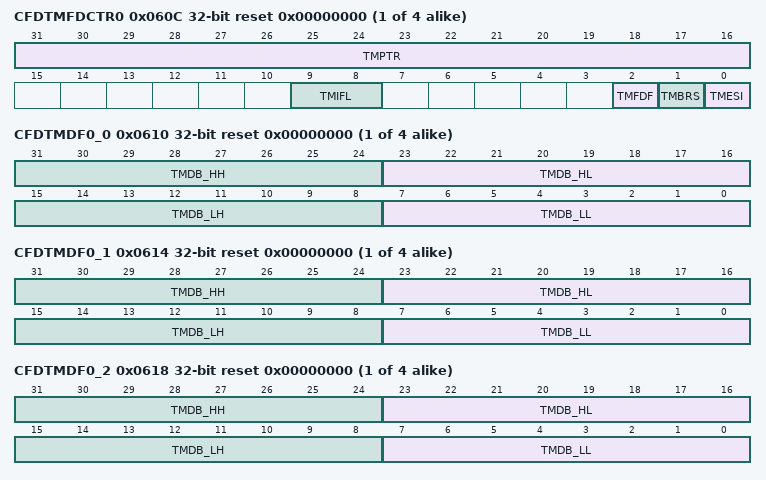
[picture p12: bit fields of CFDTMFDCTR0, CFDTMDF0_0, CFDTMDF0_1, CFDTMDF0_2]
                    <name>CFDTMFDCTR%s</name>
                    <description>TX Message Buffer CANFD Control Register </description>
                    <addressOffset>0x060C</addressOffset>
                    <size>32</size>
                    <access>read-write</access>
                    <resetValue>0x00000000</resetValue>
                    <resetMask>0xffffffff</resetMask>
                    <fields>
                        <field>
                            <name>TMESI</name>
                            <description>Error State Indicator bit</description>
                            <lsb>0</lsb>
                            <msb>0</msb>
                            <access>read-write</access>
                            <enumeratedValues>
                                <enumeratedValue>
                                    <name>0</name>
                                    <description>CANFD frame to transmit by error active node</description>
                                    <value>#0</value>
                                </enumeratedValue>
                                <enumeratedValue>
                                    <name>1</name>
                                    <description>CANFD frame to transmit by error passive node</description>
                                    <value>#1</value>
                                </enumeratedValue>
                            </enumeratedValues>
                        </field>
                        <field>
                            <name>TMBRS</name>
                            <description>Bit Rate Switch bit</description>
                            <lsb>1</lsb>
                            <msb>1</msb>
                            <access>read-write</access>
                            <enumeratedValues>
                                <enumeratedValue>
                                    <name>0</name>
                                    <description>CANFD frame to transmit with no bit rate switch</description>
                                    <value>#0</value>
                                </enumeratedValue>
                                <enumeratedValue>
                                    <name>1</name>
                                    <description>CANFD frame to transmit with bit rate switch</description>
                                    <value>#1</value>
                                </enumeratedValue>
                            </enumeratedValues>
                        </field>
                        <field>
                            <name>TMFDF</name>
                            <description>CAN FD Format bit</description>
                            <lsb>2</lsb>
                            <msb>2</msb>
                            <access>read-write</access>
                            <enumeratedValues>
                                <enumeratedValue>
                                    <name>0</name>
                                    <description>Non CANFD frame to transmit</description>
                                    <value>#0</value>
                                </enumeratedValue>
                                <enumeratedValue>
                                    <name>1</name>
                                    <description>CANFD frame to transmit</description>
                                    <value>#1</value>
                                </enumeratedValue>
                            </enumeratedValues>
                        </field>
                        <field>
                            <name>TMIFL</name>
                            <description>TX Message Buffer Information Label Field</description>
                            <lsb>8</lsb>
                            <msb>9</msb>
                            <access>read-write</access>
                        </field>
                        <field>
                            <name>TMPTR</name>
                            <description>TX Message Buffer Pointer Field</description>
                            <lsb>16</lsb>
                            <msb>31</msb>
                            <access>read-write</access>
                        </field>
                    </fields>
                </register>
                <register>
                    <dim>4</dim>
                    <dimIncrement>0x04c</dimIncrement>
                    <dimIndex>0-3</dimIndex>
                    <name>CFDTMDF%s_0</name>
                    <description>TX Message Buffer Data Field Register</description>
                    <addressOffset>0x0610</addressOffset>
                    <size>32</size>
                    <access>read-write</access>
                    <resetValue>0x00000000</resetValue>
                    <resetMask>0xffffffff</resetMask>
                    <fields>
                        <field>
                            <name>TMDB_LL</name>
                            <description>TX Message Buffer Data Byte ((p × 4)</description>
                            <lsb>0</lsb>
                            <msb>7</msb>
                            <access>read-write</access>
                        </field>
                        <field>
                            <name>TMDB_LH</name>
                            <description>TX Message Buffer Data Byte ((p × 4) + 1)</description>
                            <lsb>8</lsb>
                            <msb>15</msb>
                            <access>read-write</access>
                        </field>
                        <field>
                            <name>TMDB_HL</name>
                            <description>TX Message Buffer Data Byte ((p × 4) + 2)</description>
                            <lsb>16</lsb>
                            <msb>23</msb>
                            <access>read-write</access>
                        </field>
                        <field>
                            <name>TMDB_HH</name>
                            <description>TX Message Buffer Data Byte ((p × 4) + 3)</description>
                            <lsb>24</lsb>
                            <msb>31</msb>
                            <access>read-write</access>
                        </field>
                    </fields>
                </register>
                <register>
                    <dim>4</dim>
                    <dimIncrement>0x04c</dimIncrement>
                    <dimIndex>0-3</dimIndex>
                    <name>CFDTMDF%s_1</name>
                    <description>TX Message Buffer Data Field Register</description>
                    <addressOffset>0x0614</addressOffset>
                    <size>32</size>
                    <access>read-write</access>
                    <resetValue>0x00000000</resetValue>
                    <resetMask>0xffffffff</resetMask>
                    <fields>
                        <field>
                            <name>TMDB_LL</name>
                            <description>TX Message Buffer Data Byte ((p × 4)</description>
                            <lsb>0</lsb>
                            <msb>7</msb>
                            <access>read-write</access>
                        </field>
                        <field>
                            <name>TMDB_LH</name>
                            <description>TX Message Buffer Data Byte ((p × 4) + 1)</description>
                            <lsb>8</lsb>
                            <msb>15</msb>
                            <access>read-write</access>
                        </field>
                        <field>
                            <name>TMDB_HL</name>
                            <description>TX Message Buffer Data Byte ((p × 4) + 2)</description>
                            <lsb>16</lsb>
                            <msb>23</msb>
                            <access>read-write</access>
                        </field>
                        <field>
                            <name>TMDB_HH</name>
                            <description>TX Message Buffer Data Byte ((p × 4) + 3)</description>
                            <lsb>24</lsb>
                            <msb>31</msb>
                            <access>read-write</access>
                        </field>
                    </fields>
                </register>
                <register>
                    <dim>4</dim>
                    <dimIncrement>0x04c</dimIncrement>
                    <dimIndex>0-3</dimIndex>
                    <name>CFDTMDF%s_2</name>
                    <description>TX Message Buffer Data Field Register</description>
                    <addressOffset>0x0618</addressOffset>
                    <size>32</size>
                    <access>read-write</access>
                    <resetValue>0x00000000</resetValue>
                    <resetMask>0xffffffff</resetMask>
                    <fields>
                        <field>
                            <name>TMDB_LL</name>
                            <description>TX Message Buffer Data Byte ((p × 4)</description>
                            <lsb>0</lsb>
                            <msb>7</msb>
                            <access>read-write</access>
                        </field>
                        <field>
                            <name>TMDB_LH</name>
                            <description>TX Message Buffer Data Byte ((p × 4) + 1)</description>
                            <lsb>8</lsb>
                            <msb>15</msb>
                            <access>read-write</access>
                        </field>
                        <field>
                            <name>TMDB_HL</name>
                            <description>TX Message Buffer Data Byte ((p × 4) + 2)</description>
                            <lsb>16</lsb>
                            <msb>23</msb>
                            <access>read-write</access>
                        </field>
                        <field>
                            <name>TMDB_HH</name>
                            <description>TX Message Buffer Data Byte ((p × 4) + 3)</description>
                            <lsb>24</lsb>
                            <msb>31</msb>
                            <access>read-write</access>
                        </field>
                    </fields>
                </register>
                <register>
                    <dim>4</dim>
                    <dimIncrement>0x04c</dimIncrement>
                    <dimIndex>0-3</dimIndex>
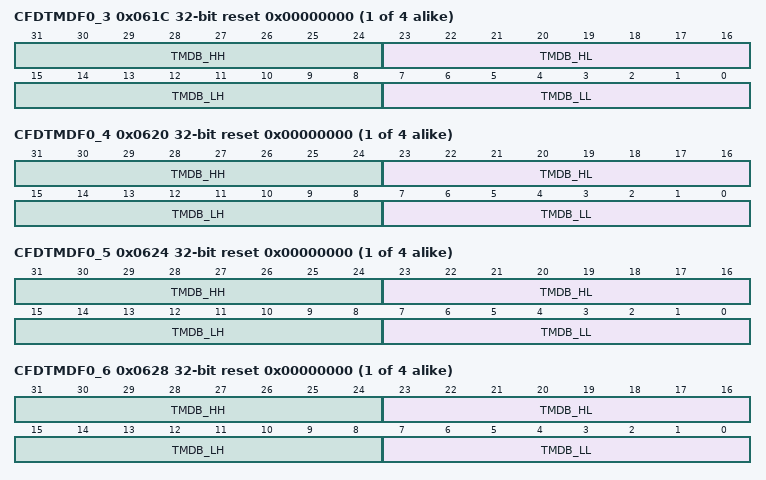
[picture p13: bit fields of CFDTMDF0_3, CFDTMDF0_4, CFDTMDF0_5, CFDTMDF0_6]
                    <name>CFDTMDF%s_3</name>
                    <description>TX Message Buffer Data Field Register</description>
                    <addressOffset>0x061C</addressOffset>
                    <size>32</size>
                    <access>read-write</access>
                    <resetValue>0x00000000</resetValue>
                    <resetMask>0xffffffff</resetMask>
                    <fields>
                        <field>
                            <name>TMDB_LL</name>
                            <description>TX Message Buffer Data Byte ((p × 4)</description>
                            <lsb>0</lsb>
                            <msb>7</msb>
                            <access>read-write</access>
                        </field>
                        <field>
                            <name>TMDB_LH</name>
                            <description>TX Message Buffer Data Byte ((p × 4) + 1)</description>
                            <lsb>8</lsb>
                            <msb>15</msb>
                            <access>read-write</access>
                        </field>
                        <field>
                            <name>TMDB_HL</name>
                            <description>TX Message Buffer Data Byte ((p × 4) + 2)</description>
                            <lsb>16</lsb>
                            <msb>23</msb>
                            <access>read-write</access>
                        </field>
                        <field>
                            <name>TMDB_HH</name>
                            <description>TX Message Buffer Data Byte ((p × 4) + 3)</description>
                            <lsb>24</lsb>
                            <msb>31</msb>
                            <access>read-write</access>
                        </field>
                    </fields>
                </register>
                <register>
                    <dim>4</dim>
                    <dimIncrement>0x04c</dimIncrement>
                    <dimIndex>0-3</dimIndex>
                    <name>CFDTMDF%s_4</name>
                    <description>TX Message Buffer Data Field Register</description>
                    <addressOffset>0x0620</addressOffset>
                    <size>32</size>
                    <access>read-write</access>
                    <resetValue>0x00000000</resetValue>
                    <resetMask>0xffffffff</resetMask>
                    <fields>
                        <field>
                            <name>TMDB_LL</name>
                            <description>TX Message Buffer Data Byte ((p × 4)</description>
                            <lsb>0</lsb>
                            <msb>7</msb>
                            <access>read-write</access>
                        </field>
                        <field>
                            <name>TMDB_LH</name>
                            <description>TX Message Buffer Data Byte ((p × 4) + 1)</description>
                            <lsb>8</lsb>
                            <msb>15</msb>
                            <access>read-write</access>
                        </field>
                        <field>
                            <name>TMDB_HL</name>
                            <description>TX Message Buffer Data Byte ((p × 4) + 2)</description>
                            <lsb>16</lsb>
                            <msb>23</msb>
                            <access>read-write</access>
                        </field>
                        <field>
                            <name>TMDB_HH</name>
                            <description>TX Message Buffer Data Byte ((p × 4) + 3)</description>
                            <lsb>24</lsb>
                            <msb>31</msb>
                            <access>read-write</access>
                        </field>
                    </fields>
                </register>
                <register>
                    <dim>4</dim>
                    <dimIncrement>0x04c</dimIncrement>
                    <dimIndex>0-3</dimIndex>
                    <name>CFDTMDF%s_5</name>
                    <description>TX Message Buffer Data Field Register</description>
                    <addressOffset>0x0624</addressOffset>
                    <size>32</size>
                    <access>read-write</access>
                    <resetValue>0x00000000</resetValue>
                    <resetMask>0xffffffff</resetMask>
                    <fields>
                        <field>
                            <name>TMDB_LL</name>
                            <description>TX Message Buffer Data Byte ((p × 4)</description>
                            <lsb>0</lsb>
                            <msb>7</msb>
                            <access>read-write</access>
                        </field>
                        <field>
                            <name>TMDB_LH</name>
                            <description>TX Message Buffer Data Byte ((p × 4) + 1)</description>
                            <lsb>8</lsb>
                            <msb>15</msb>
                            <access>read-write</access>
                        </field>
                        <field>
                            <name>TMDB_HL</name>
                            <description>TX Message Buffer Data Byte ((p × 4) + 2)</description>
                            <lsb>16</lsb>
                            <msb>23</msb>
                            <access>read-write</access>
                        </field>
                        <field>
                            <name>TMDB_HH</name>
                            <description>TX Message Buffer Data Byte ((p × 4) + 3)</description>
                            <lsb>24</lsb>
                            <msb>31</msb>
                            <access>read-write</access>
                        </field>
                    </fields>
                </register>
                <register>
                    <dim>4</dim>
                    <dimIncrement>0x04c</dimIncrement>
                    <dimIndex>0-3</dimIndex>
                    <name>CFDTMDF%s_6</name>
                    <description>TX Message Buffer Data Field Register </description>
                    <addressOffset>0x0628</addressOffset>
                    <size>32</size>
                    <access>read-write</access>
                    <resetValue>0x00000000</resetValue>
                    <resetMask>0xffffffff</resetMask>
                    <fields>
                        <field>
                            <name>TMDB_LL</name>
                            <description>TX Message Buffer Data Byte ((p × 4)</description>
                            <lsb>0</lsb>
                            <msb>7</msb>
                            <access>read-write</access>
                        </field>
                        <field>
                            <name>TMDB_LH</name>
                            <description>TX Message Buffer Data Byte ((p × 4) + 1)</description>
                            <lsb>8</lsb>
                            <msb>15</msb>
                            <access>read-write</access>
                        </field>
                        <field>
                            <name>TMDB_HL</name>
                            <description>TX Message Buffer Data Byte ((p × 4) + 2)</description>
                            <lsb>16</lsb>
                            <msb>23</msb>
                            <access>read-write</access>
                        </field>
                        <field>
                            <name>TMDB_HH</name>
                            <description>TX Message Buffer Data Byte ((p × 4) + 3)</description>
                            <lsb>24</lsb>
                            <msb>31</msb>
                            <access>read-write</access>
                        </field>
                    </fields>
                </register>
                <register>
                    <dim>4</dim>
                    <dimIncrement>0x04c</dimIncrement>
                    <dimIndex>0-3</dimIndex>
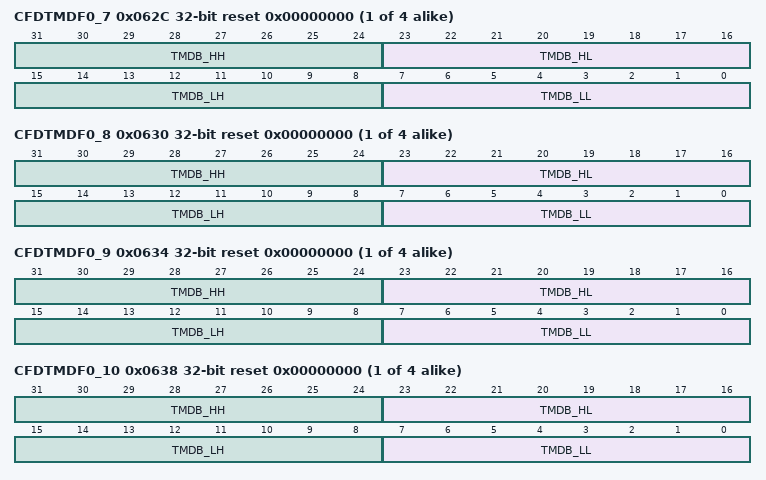
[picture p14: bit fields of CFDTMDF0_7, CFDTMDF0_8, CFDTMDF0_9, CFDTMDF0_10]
                    <name>CFDTMDF%s_7</name>
                    <description>TX Message Buffer Data Field Register</description>
                    <addressOffset>0x062C</addressOffset>
                    <size>32</size>
                    <access>read-write</access>
                    <resetValue>0x00000000</resetValue>
                    <resetMask>0xffffffff</resetMask>
                    <fields>
                        <field>
                            <name>TMDB_LL</name>
                            <description>TX Message Buffer Data Byte ((p × 4)</description>
                            <lsb>0</lsb>
                            <msb>7</msb>
                            <access>read-write</access>
                        </field>
                        <field>
                            <name>TMDB_LH</name>
                            <description>TX Message Buffer Data Byte ((p × 4) + 1)</description>
                            <lsb>8</lsb>
                            <msb>15</msb>
                            <access>read-write</access>
                        </field>
                        <field>
                            <name>TMDB_HL</name>
                            <description>TX Message Buffer Data Byte ((p × 4) + 2)</description>
                            <lsb>16</lsb>
                            <msb>23</msb>
                            <access>read-write</access>
                        </field>
                        <field>
                            <name>TMDB_HH</name>
                            <description>TX Message Buffer Data Byte ((p × 4) + 3)</description>
                            <lsb>24</lsb>
                            <msb>31</msb>
                            <access>read-write</access>
                        </field>
                    </fields>
                </register>
                <register>
                    <dim>4</dim>
                    <dimIncrement>0x04c</dimIncrement>
                    <dimIndex>0-3</dimIndex>
                    <name>CFDTMDF%s_8</name>
                    <description>TX Message Buffer Data Field Register</description>
                    <addressOffset>0x0630</addressOffset>
                    <size>32</size>
                    <access>read-write</access>
                    <resetValue>0x00000000</resetValue>
                    <resetMask>0xffffffff</resetMask>
                    <fields>
                        <field>
                            <name>TMDB_LL</name>
                            <description>TX Message Buffer Data Byte ((p × 4)</description>
                            <lsb>0</lsb>
                            <msb>7</msb>
                            <access>read-write</access>
                        </field>
                        <field>
                            <name>TMDB_LH</name>
                            <description>TX Message Buffer Data Byte ((p × 4) + 1)</description>
                            <lsb>8</lsb>
                            <msb>15</msb>
                            <access>read-write</access>
                        </field>
                        <field>
                            <name>TMDB_HL</name>
                            <description>TX Message Buffer Data Byte ((p × 4) + 2)</description>
                            <lsb>16</lsb>
                            <msb>23</msb>
                            <access>read-write</access>
                        </field>
                        <field>
                            <name>TMDB_HH</name>
                            <description>TX Message Buffer Data Byte ((p × 4) + 3)</description>
                            <lsb>24</lsb>
                            <msb>31</msb>
                            <access>read-write</access>
                        </field>
                    </fields>
                </register>
                <register>
                    <dim>4</dim>
                    <dimIncrement>0x04c</dimIncrement>
                    <dimIndex>0-3</dimIndex>
                    <name>CFDTMDF%s_9</name>
                    <description>TX Message Buffer Data Field Register</description>
                    <addressOffset>0x0634</addressOffset>
                    <size>32</size>
                    <access>read-write</access>
                    <resetValue>0x00000000</resetValue>
                    <resetMask>0xffffffff</resetMask>
                    <fields>
                        <field>
                            <name>TMDB_LL</name>
                            <description>TX Message Buffer Data Byte ((p × 4)</description>
                            <lsb>0</lsb>
                            <msb>7</msb>
                            <access>read-write</access>
                        </field>
                        <field>
                            <name>TMDB_LH</name>
                            <description>TX Message Buffer Data Byte ((p × 4) + 1)</description>
                            <lsb>8</lsb>
                            <msb>15</msb>
                            <access>read-write</access>
                        </field>
                        <field>
                            <name>TMDB_HL</name>
                            <description>TX Message Buffer Data Byte ((p × 4) + 2)</description>
                            <lsb>16</lsb>
                            <msb>23</msb>
                            <access>read-write</access>
                        </field>
                        <field>
                            <name>TMDB_HH</name>
                            <description>TX Message Buffer Data Byte ((p × 4) + 3)</description>
                            <lsb>24</lsb>
                            <msb>31</msb>
                            <access>read-write</access>
                        </field>
                    </fields>
                </register>
                <register>
                    <dim>4</dim>
                    <dimIncrement>0x04c</dimIncrement>
                    <dimIndex>0-3</dimIndex>
                    <name>CFDTMDF%s_10</name>
                    <description>TX Message Buffer Data Field Register </description>
                    <addressOffset>0x0638</addressOffset>
                    <size>32</size>
                    <access>read-write</access>
                    <resetValue>0x00000000</resetValue>
                    <resetMask>0xffffffff</resetMask>
                    <fields>
                        <field>
                            <name>TMDB_LL</name>
                            <description>TX Message Buffer Data Byte ((p × 4)</description>
                            <lsb>0</lsb>
                            <msb>7</msb>
                            <access>read-write</access>
                        </field>
                        <field>
                            <name>TMDB_LH</name>
                            <description>TX Message Buffer Data Byte ((p × 4) + 1)</description>
                            <lsb>8</lsb>
                            <msb>15</msb>
                            <access>read-write</access>
                        </field>
                        <field>
                            <name>TMDB_HL</name>
                            <description>TX Message Buffer Data Byte ((p × 4) + 2)</description>
                            <lsb>16</lsb>
                            <msb>23</msb>
                            <access>read-write</access>
                        </field>
                        <field>
                            <name>TMDB_HH</name>
                            <description>TX Message Buffer Data Byte ((p × 4) + 3)</description>
                            <lsb>24</lsb>
                            <msb>31</msb>
                            <access>read-write</access>
                        </field>
                    </fields>
                </register>
                <register>
                    <dim>4</dim>
                    <dimIncrement>0x04c</dimIncrement>
                    <dimIndex>0-3</dimIndex>
                    <name>CFDTMDF%s_11</name>
                    <description>TX Message Buffer Data Field Register</description>
                    <addressOffset>0x063C</addressOffset>
                    <size>32</size>
                    <access>read-write</access>
                    <resetValue>0x00000000</resetValue>
                    <resetMask>0xffffffff</resetMask>
                    <fields>
                        <field>
                            <name>TMDB_LL</name>
                            <description>TX Message Buffer Data Byte ((p × 4)</description>
                            <lsb>0</lsb>
                            <msb>7</msb>
                            <access>read-write</access>
                        </field>
                        <field>
                            <name>TMDB_LH</name>
                            <description>TX Message Buffer Data Byte ((p × 4) + 1)</description>
                            <lsb>8</lsb>
                            <msb>15</msb>
                            <access>read-write</access>
                        </field>
                        <field>
                            <name>TMDB_HL</name>
                            <description>TX Message Buffer Data Byte ((p × 4) + 2)</description>
                            <lsb>16</lsb>
                            <msb>23</msb>
                            <access>read-write</access>
                        </field>
                        <field>
                            <name>TMDB_HH</name>
                            <description>TX Message Buffer Data Byte ((p × 4) + 3)</description>
                            <lsb>24</lsb>
                            <msb>31</msb>
                            <access>read-write</access>
                        </field>
                    </fields>
                </register>
                <register>
                    <dim>4</dim>
                    <dimIncrement>0x04c</dimIncrement>
                    <dimIndex>0-3</dimIndex>
                    <name>CFDTMDF%s_12</name>
                    <description>TX Message Buffer Data Field Register</description>
                    <addressOffset>0x0640</addressOffset>
                    <size>32</size>
                    <access>read-write</access>
                    <resetValue>0x00000000</resetValue>
                    <resetMask>0xffffffff</resetMask>
                    <fields>
                        <field>
                            <name>TMDB_LL</name>
                            <description>TX Message Buffer Data Byte ((p × 4)</description>
                            <lsb>0</lsb>
                            <msb>7</msb>
                            <access>read-write</access>
                        </field>
                        <field>
                            <name>TMDB_LH</name>
                            <description>TX Message Buffer Data Byte ((p × 4) + 1)</description>
                            <lsb>8</lsb>
                            <msb>15</msb>
                            <access>read-write</access>
                        </field>
                        <field>
                            <name>TMDB_HL</name>
                            <description>TX Message Buffer Data Byte ((p × 4) + 2)</description>
                            <lsb>16</lsb>
                            <msb>23</msb>
                            <access>read-write</access>
                        </field>
                        <field>
                            <name>TMDB_HH</name>
                            <description>TX Message Buffer Data Byte ((p × 4) + 3)</description>
                            <lsb>24</lsb>
                            <msb>31</msb>
                            <access>read-write</access>
                        </field>
                    </fields>
                </register>
                <register>
                    <dim>4</dim>
                    <dimIncrement>0x04c</dimIncrement>
                    <dimIndex>0-3</dimIndex>
                    <name>CFDTMDF%s_13</name>
                    <description>TX Message Buffer Data Field Register</description>
                    <addressOffset>0x0644</addressOffset>
                    <size>32</size>
                    <access>read-write</access>
                    <resetValue>0x00000000</resetValue>
                    <resetMask>0xffffffff</resetMask>
                    <fields>
                        <field>
                            <name>TMDB_LL</name>
                            <description>TX Message Buffer Data Byte ((p × 4)</description>
                            <lsb>0</lsb>
                            <msb>7</msb>
                            <access>read-write</access>
                        </field>
                        <field>
                            <name>TMDB_LH</name>
                            <description>TX Message Buffer Data Byte ((p × 4) + 1)</description>
                            <lsb>8</lsb>
                            <msb>15</msb>
                            <access>read-write</access>
                        </field>
                        <field>
                            <name>TMDB_HL</name>
                            <description>TX Message Buffer Data Byte ((p × 4) + 2)</description>
                            <lsb>16</lsb>
                            <msb>23</msb>
                            <access>read-write</access>
                        </field>
                        <field>
                            <name>TMDB_HH</name>
                            <description>TX Message Buffer Data Byte ((p × 4) + 3)</description>
                            <lsb>24</lsb>
                            <msb>31</msb>
                            <access>read-write</access>
                        </field>
                    </fields>
                </register>
                <register>
                    <dim>4</dim>
                    <dimIncrement>0x04c</dimIncrement>
                    <dimIndex>0-3</dimIndex>
                    <name>CFDTMDF%s_14</name>
                    <description>TX Message Buffer Data Field Register</description>
                    <addressOffset>0x0648</addressOffset>
                    <size>32</size>
                    <access>read-write</access>
                    <resetValue>0x00000000</resetValue>
                    <resetMask>0xffffffff</resetMask>
                    <fields>
                        <field>
                            <name>TMDB_LL</name>
                            <description>TX Message Buffer Data Byte ((p × 4)</description>
                            <lsb>0</lsb>
                            <msb>7</msb>
                            <access>read-write</access>
                        </field>
                        <field>
                            <name>TMDB_LH</name>
                            <description>TX Message Buffer Data Byte ((p × 4) + 1)</description>
                            <lsb>8</lsb>
                            <msb>15</msb>
                            <access>read-write</access>
                        </field>
                        <field>
                            <name>TMDB_HL</name>
                            <description>TX Message Buffer Data Byte ((p × 4) + 2)</description>
                            <lsb>16</lsb>
                            <msb>23</msb>
                            <access>read-write</access>
                        </field>
                        <field>
                            <name>TMDB_HH</name>
                            <description>TX Message Buffer Data Byte ((p × 4) + 3)</description>
                            <lsb>24</lsb>
                            <msb>31</msb>
                            <access>read-write</access>
                        </field>
                    </fields>
                </register>
                <register>
                    <dim>4</dim>
                    <dimIncrement>0x04c</dimIncrement>
                    <dimIndex>0-3</dimIndex>
                    <name>CFDTMDF%s_15</name>
                    <description>TX Message Buffer Data Field Register</description>
                    <addressOffset>0x064C</addressOffset>
                    <size>32</size>
                    <access>read-write</access>
                    <resetValue>0x00000000</resetValue>
                    <resetMask>0xffffffff</resetMask>
                    <fields>
                        <field>
                            <name>TMDB_LL</name>
                            <description>TX Message Buffer Data Byte ((p × 4)</description>
                            <lsb>0</lsb>
                            <msb>7</msb>
                            <access>read-write</access>
                        </field>
                        <field>
                            <name>TMDB_LH</name>
                            <description>TX Message Buffer Data Byte ((p × 4) + 1)</description>
                            <lsb>8</lsb>
                            <msb>15</msb>
                            <access>read-write</access>
                        </field>
                        <field>
                            <name>TMDB_HL</name>
                            <description>TX Message Buffer Data Byte ((p × 4) + 2)</description>
                            <lsb>16</lsb>
                            <msb>23</msb>
                            <access>read-write</access>
                        </field>
                        <field>
                            <name>TMDB_HH</name>
                            <description>TX Message Buffer Data Byte ((p × 4) + 3)</description>
                            <lsb>24</lsb>
                            <msb>31</msb>
                            <access>read-write</access>
                        </field>
                    </fields>
                </register>
                <register>
                    <name>CFDTHLACC0</name>
                    <description>TX History List Access Register 0</description>
                    <addressOffset>0x0740</addressOffset>
                    <size>32</size>
                    <access>read-only</access>
                    <resetValue>0x00000000</resetValue>
                    <resetMask>0xffffffff</resetMask>
                    <fields>
                        <field>
                            <name>BT</name>
                            <description>Buffer Type</description>
                            <lsb>0</lsb>
                            <msb>2</msb>
                            <access>read-only</access>
                            <enumeratedValues>
                                <enumeratedValue>
                                    <name>001</name>
                                    <description>Flat TX message buffer</description>
                                    <value>#001</value>
                                </enumeratedValue>
                                <enumeratedValue>
                                    <name>010</name>
                                    <description>TX FIFO message buffer number</description>
                                    <value>#010</value>
                                </enumeratedValue>
                                <enumeratedValue>
                                    <name>100</name>
                                    <description>TX Queue message buffer number</description>
                                    <value>#100</value>
                                </enumeratedValue>
                            </enumeratedValues>
                        </field>
                        <field>
                            <name>BN</name>
                            <description>Buffer Number</description>
                            <lsb>3</lsb>
                            <msb>4</msb>
                            <access>read-only</access>
                        </field>
                        <field>
                            <name>TMTS</name>
                            <description>Transmit Timestamp</description>
                            <lsb>16</lsb>
                            <msb>31</msb>
                            <access>read-only</access>
                        </field>
                    </fields>
                </register>
                <register>
                    <name>CFDTHLACC1</name>
                    <description>TX History List Access Register 1</description>
                    <addressOffset>0x0744</addressOffset>
                    <size>32</size>
                    <access>read-only</access>
                    <resetValue>0x00000000</resetValue>
                    <resetMask>0xffffffff</resetMask>
                    <fields>
                        <field>
                            <name>TID</name>
                            <description>Transmit ID</description>
                            <lsb>0</lsb>
                            <msb>15</msb>
                            <access>read-only</access>
                        </field>
                        <field>
                            <name>TIFL</name>
                            <description>Transmit Information Label</description>
                            <lsb>16</lsb>
                            <msb>17</msb>
                            <access>read-only</access>
                        </field>
                    </fields>
                </register>
                <register>
                    <dim>8</dim>
                    <dimIncrement>0x004C</dimIncrement>
                    <dimIndex>0-7</dimIndex>
                    <name>CFDRMID%s</name>
                    <description>RX Message Buffer ID Registers</description>
                    <addressOffset>0x0920</addressOffset>
                    <size>32</size>
                    <access>read-only</access>
                    <resetValue>0x00000000</resetValue>
                    <resetMask>0xffffffff</resetMask>
                    <fields>
                        <field>
                            <name>RMID</name>
                            <description>RX Message Buffer ID Field</description>
                            <lsb>0</lsb>
                            <msb>28</msb>
                            <access>read-only</access>
                        </field>
                        <field>
                            <name>RMRTR</name>
                            <description>RX Message Buffer RTR Bit</description>
                            <lsb>30</lsb>
                            <msb>30</msb>
                            <access>read-only</access>
                            <enumeratedValues>
                                <enumeratedValue>
                                    <name>0</name>
                                    <description>Data frame</description>
                                    <value>#0</value>
                                </enumeratedValue>
                                <enumeratedValue>
                                    <name>1</name>
                                    <description>Remote frame</description>
                                    <value>#1</value>
                                </enumeratedValue>
                            </enumeratedValues>
                        </field>
                        <field>
                            <name>RMIDE</name>
                            <description>RX Message Buffer IDE Bit</description>
                            <lsb>31</lsb>
                            <msb>31</msb>
                            <access>read-only</access>
                            <enumeratedValues>
                                <enumeratedValue>
                                    <name>0</name>
                                    <description>STD-ID is stored</description>
                                    <value>#0</value>
                                </enumeratedValue>
                                <enumeratedValue>
                                    <name>1</name>
                                    <description>EXT-ID is stored</description>
                                    <value>#1</value>
                                </enumeratedValue>
                            </enumeratedValues>
                        </field>
                    </fields>
                </register>
                <register>
                    <dim>8</dim>
                    <dimIncrement>0x004C</dimIncrement>
                    <dimIndex>0-7</dimIndex>
                    <name>CFDRMPTR%s</name>
                    <description>RX Message Buffer Pointer Registers</description>
                    <addressOffset>0x0924</addressOffset>
                    <size>32</size>
                    <access>read-only</access>
                    <resetValue>0x00000000</resetValue>
                    <resetMask>0xffffffff</resetMask>
                    <fields>
                        <field>
                            <name>RMTS</name>
                            <description>RX Message Buffer Timestamp Field</description>
                            <lsb>0</lsb>
                            <msb>15</msb>
                            <access>read-only</access>
                        </field>
                        <field>
                            <name>RMDLC</name>
                            <description>RX Message Buffer DLC Field</description>
                            <lsb>28</lsb>
                            <msb>31</msb>
                            <access>read-only</access>
                        </field>
                    </fields>
                </register>
                <register>
                    <dim>8</dim>
                    <dimIncrement>0x004C</dimIncrement>
                    <dimIndex>0-7</dimIndex>
                    <name>CFDRMFDSTS%s</name>
                    <description>RX Message Buffer CANFD Status Registers</description>
                    <addressOffset>0x0928</addressOffset>
                    <size>32</size>
                    <access>read-only</access>
                    <resetValue>0x00000000</resetValue>
                    <resetMask>0xffffffff</resetMask>
                    <fields>
                        <field>
                            <name>RMESI</name>
                            <description>Error State Indicator bit</description>
                            <lsb>0</lsb>
                            <msb>0</msb>
                            <access>read-only</access>
                            <enumeratedValues>
                                <enumeratedValue>
                                    <name>0</name>
                                    <description>CANFD frame received from error active node</description>
                                    <value>#0</value>
                                </enumeratedValue>
                                <enumeratedValue>
                                    <name>1</name>
                                    <description>CANFD frame received from error passive node</description>
                                    <value>#1</value>
                                </enumeratedValue>
                            </enumeratedValues>
                        </field>
                        <field>
                            <name>RMBRS</name>
                            <description>Bit Rate Switch bit</description>
                            <lsb>1</lsb>
                            <msb>1</msb>
                            <access>read-only</access>
                            <enumeratedValues>
                                <enumeratedValue>
                                    <name>0</name>
                                    <description>CANFD frame received with no bit rate switch</description>
                                    <value>#0</value>
                                </enumeratedValue>
                                <enumeratedValue>
                                    <name>1</name>
                                    <description>CANFD frame received with bit rate switch</description>
                                    <value>#1</value>
                                </enumeratedValue>
                            </enumeratedValues>
                        </field>
                        <field>
                            <name>RMFDF</name>
                            <description>CAN FD Format bit</description>
                            <lsb>2</lsb>
                            <msb>2</msb>
                            <access>read-only</access>
                            <enumeratedValues>
                                <enumeratedValue>
                                    <name>0</name>
                                    <description>Non CANFD frame received</description>
                                    <value>#0</value>
                                </enumeratedValue>
                                <enumeratedValue>
                                    <name>1</name>
                                    <description>CANFD frame received</description>
                                    <value>#1</value>
                                </enumeratedValue>
                            </enumeratedValues>
                        </field>
                        <field>
                            <name>RMIFL</name>
                            <description>RX Message Buffer Information Label Field</description>
                            <lsb>8</lsb>
                            <msb>9</msb>
                            <access>read-only</access>
                        </field>
                        <field>
                            <name>RMPTR</name>
                            <description>RX Message Buffer Pointer Field</description>
                            <lsb>16</lsb>
                            <msb>31</msb>
                            <access>read-only</access>
                        </field>
                    </fields>
                </register>
                <register>
                    <dim>8</dim>
                    <dimIncrement>0x004C</dimIncrement>
                    <dimIndex>0-7</dimIndex>
                    <name>CFDRMDF%s_0</name>
                    <description>RX Message Buffer Data Field 0 Registers</description>
                    <addressOffset>0x092C</addressOffset>
                    <size>32</size>
                    <access>read-only</access>
                    <resetValue>0x00000000</resetValue>
                    <resetMask>0xffffffff</resetMask>
                    <fields>
                        <field>
                            <name>RMDB_LL</name>
                            <description>RX Message Buffer Data Byte (p × 4)</description>
                            <lsb>0</lsb>
                            <msb>7</msb>
                            <access>read-only</access>
                        </field>
                        <field>
                            <name>RMDB_LH</name>
                            <description>RX Message Buffer Data Byte ((p × 4) + 1)</description>
                            <lsb>8</lsb>
                            <msb>15</msb>
                            <access>read-only</access>
                        </field>
                        <field>
                            <name>RMDB_HL</name>
                            <description>RX Message Buffer Data Byte ((p × 4) + 2)</description>
                            <lsb>16</lsb>
                            <msb>23</msb>
                            <access>read-only</access>
                        </field>
                        <field>
                            <name>RMDB_HH</name>
                            <description>RX Message Buffer Data Byte ((p × 4) + 3)</description>
                            <lsb>24</lsb>
                            <msb>31</msb>
                            <access>read-only</access>
                        </field>
                    </fields>
                </register>
                <register>
                    <dim>8</dim>
                    <dimIncrement>0x004C</dimIncrement>
                    <dimIndex>0-7</dimIndex>
                    <name>CFDRMDF%s_1</name>
                    <description>RX Message Buffer Data Field 1 Registers</description>
                    <addressOffset>0x0930</addressOffset>
                    <size>32</size>
                    <access>read-only</access>
                    <resetValue>0x00000000</resetValue>
                    <resetMask>0xffffffff</resetMask>
                    <fields>
                        <field>
                            <name>RMDB_LL</name>
                            <description>RX Message Buffer Data Byte (p × 4)</description>
                            <lsb>0</lsb>
                            <msb>7</msb>
                            <access>read-only</access>
                        </field>
                        <field>
                            <name>RMDB_LH</name>
                            <description>RX Message Buffer Data Byte ((p × 4) + 1)</description>
                            <lsb>8</lsb>
                            <msb>15</msb>
                            <access>read-only</access>
                        </field>
                        <field>
                            <name>RMDB_HL</name>
                            <description>RX Message Buffer Data Byte ((p × 4) + 2)</description>
                            <lsb>16</lsb>
                            <msb>23</msb>
                            <access>read-only</access>
                        </field>
                        <field>
                            <name>RMDB_HH</name>
                            <description>RX Message Buffer Data Byte ((p × 4) + 3)</description>
                            <lsb>24</lsb>
                            <msb>31</msb>
                            <access>read-only</access>
                        </field>
                    </fields>
                </register>
                <register>
                    <dim>8</dim>
                    <dimIncrement>0x004C</dimIncrement>
                    <dimIndex>0-7</dimIndex>
                    <name>CFDRMDF%s_2</name>
                    <description>RX Message Buffer Data Field 2 Registers</description>
                    <addressOffset>0x0934</addressOffset>
                    <size>32</size>
                    <access>read-only</access>
                    <resetValue>0x00000000</resetValue>
                    <resetMask>0xffffffff</resetMask>
                    <fields>
                        <field>
                            <name>RMDB_LL</name>
                            <description>RX Message Buffer Data Byte (p × 4)</description>
                            <lsb>0</lsb>
                            <msb>7</msb>
                            <access>read-only</access>
                        </field>
                        <field>
                            <name>RMDB_LH</name>
                            <description>RX Message Buffer Data Byte ((p × 4) + 1)</description>
                            <lsb>8</lsb>
                            <msb>15</msb>
                            <access>read-only</access>
                        </field>
                        <field>
                            <name>RMDB_HL</name>
                            <description>RX Message Buffer Data Byte ((p × 4) + 2)</description>
                            <lsb>16</lsb>
                            <msb>23</msb>
                            <access>read-only</access>
                        </field>
                        <field>
                            <name>RMDB_HH</name>
                            <description>RX Message Buffer Data Byte ((p × 4) + 3)</description>
                            <lsb>24</lsb>
                            <msb>31</msb>
                            <access>read-only</access>
                        </field>
                    </fields>
                </register>
                <register>
                    <dim>8</dim>
                    <dimIncrement>0x004C</dimIncrement>
                    <dimIndex>0-7</dimIndex>
                    <name>CFDRMDF%s_3</name>
                    <description>RX Message Buffer Data Field 3 Registers</description>
                    <addressOffset>0x0938</addressOffset>
                    <size>32</size>
                    <access>read-only</access>
                    <resetValue>0x00000000</resetValue>
                    <resetMask>0xffffffff</resetMask>
                    <fields>
                        <field>
                            <name>RMDB_LL</name>
                            <description>RX Message Buffer Data Byte (p × 4)</description>
                            <lsb>0</lsb>
                            <msb>7</msb>
                            <access>read-only</access>
                        </field>
                        <field>
                            <name>RMDB_LH</name>
                            <description>RX Message Buffer Data Byte ((p × 4) + 1)</description>
                            <lsb>8</lsb>
                            <msb>15</msb>
                            <access>read-only</access>
                        </field>
                        <field>
                            <name>RMDB_HL</name>
                            <description>RX Message Buffer Data Byte ((p × 4) + 2)</description>
                            <lsb>16</lsb>
                            <msb>23</msb>
                            <access>read-only</access>
                        </field>
                        <field>
                            <name>RMDB_HH</name>
                            <description>RX Message Buffer Data Byte ((p × 4) + 3)</description>
                            <lsb>24</lsb>
                            <msb>31</msb>
                            <access>read-only</access>
                        </field>
                    </fields>
                </register>
                <register>
                    <dim>8</dim>
                    <dimIncrement>0x004C</dimIncrement>
                    <dimIndex>0-7</dimIndex>
                    <name>CFDRMDF%s_4</name>
                    <description>RX Message Buffer Data Field 4 Registers</description>
                    <addressOffset>0x093C</addressOffset>
                    <size>32</size>
                    <access>read-only</access>
                    <resetValue>0x00000000</resetValue>
                    <resetMask>0xffffffff</resetMask>
                    <fields>
                        <field>
                            <name>RMDB_LL</name>
                            <description>RX Message Buffer Data Byte (p × 4)</description>
                            <lsb>0</lsb>
                            <msb>7</msb>
                            <access>read-only</access>
                        </field>
                        <field>
                            <name>RMDB_LH</name>
                            <description>RX Message Buffer Data Byte ((p × 4) + 1)</description>
                            <lsb>8</lsb>
                            <msb>15</msb>
                            <access>read-only</access>
                        </field>
                        <field>
                            <name>RMDB_HL</name>
                            <description>RX Message Buffer Data Byte ((p × 4) + 2)</description>
                            <lsb>16</lsb>
                            <msb>23</msb>
                            <access>read-only</access>
                        </field>
                        <field>
                            <name>RMDB_HH</name>
                            <description>RX Message Buffer Data Byte ((p × 4) + 3)</description>
                            <lsb>24</lsb>
                            <msb>31</msb>
                            <access>read-only</access>
                        </field>
                    </fields>
                </register>
                <register>
                    <dim>8</dim>
                    <dimIncrement>0x004C</dimIncrement>
                    <dimIndex>0-7</dimIndex>
                    <name>CFDRMDF%s_5</name>
                    <description>RX Message Buffer Data Field 5 Registers</description>
                    <addressOffset>0x0940</addressOffset>
                    <size>32</size>
                    <access>read-only</access>
                    <resetValue>0x00000000</resetValue>
                    <resetMask>0xffffffff</resetMask>
                    <fields>
                        <field>
                            <name>RMDB_LL</name>
                            <description>RX Message Buffer Data Byte (p × 4)</description>
                            <lsb>0</lsb>
                            <msb>7</msb>
                            <access>read-only</access>
                        </field>
                        <field>
                            <name>RMDB_LH</name>
                            <description>RX Message Buffer Data Byte ((p × 4) + 1)</description>
                            <lsb>8</lsb>
                            <msb>15</msb>
                            <access>read-only</access>
                        </field>
                        <field>
                            <name>RMDB_HL</name>
                            <description>RX Message Buffer Data Byte ((p × 4) + 2)</description>
                            <lsb>16</lsb>
                            <msb>23</msb>
                            <access>read-only</access>
                        </field>
                        <field>
                            <name>RMDB_HH</name>
                            <description>RX Message Buffer Data Byte ((p × 4) + 3)</description>
                            <lsb>24</lsb>
                            <msb>31</msb>
                            <access>read-only</access>
                        </field>
                    </fields>
                </register>
                <register>
                    <dim>8</dim>
                    <dimIncrement>0x004C</dimIncrement>
                    <dimIndex>0-7</dimIndex>
                    <name>CFDRMDF%s_6</name>
                    <description>RX Message Buffer Data Field 6 Registers</description>
                    <addressOffset>0x0944</addressOffset>
                    <size>32</size>
                    <access>read-only</access>
                    <resetValue>0x00000000</resetValue>
                    <resetMask>0xffffffff</resetMask>
                    <fields>
                        <field>
                            <name>RMDB_LL</name>
                            <description>RX Message Buffer Data Byte (p × 4)</description>
                            <lsb>0</lsb>
                            <msb>7</msb>
                            <access>read-only</access>
                        </field>
                        <field>
                            <name>RMDB_LH</name>
                            <description>RX Message Buffer Data Byte ((p × 4) + 1)</description>
                            <lsb>8</lsb>
                            <msb>15</msb>
                            <access>read-only</access>
                        </field>
                        <field>
                            <name>RMDB_HL</name>
                            <description>RX Message Buffer Data Byte ((p × 4) + 2)</description>
                            <lsb>16</lsb>
                            <msb>23</msb>
                            <access>read-only</access>
                        </field>
                        <field>
                            <name>RMDB_HH</name>
                            <description>RX Message Buffer Data Byte ((p × 4) + 3)</description>
                            <lsb>24</lsb>
                            <msb>31</msb>
                            <access>read-only</access>
                        </field>
                    </fields>
                </register>
                <register>
                    <dim>8</dim>
                    <dimIncrement>0x004C</dimIncrement>
                    <dimIndex>0-7</dimIndex>
                    <name>CFDRMDF%s_7</name>
                    <description>RX Message Buffer Data Field 7 Registers</description>
                    <addressOffset>0x0948</addressOffset>
                    <size>32</size>
                    <access>read-only</access>
                    <resetValue>0x00000000</resetValue>
                    <resetMask>0xffffffff</resetMask>
                    <fields>
                        <field>
                            <name>RMDB_LL</name>
                            <description>RX Message Buffer Data Byte (p × 4)</description>
                            <lsb>0</lsb>
                            <msb>7</msb>
                            <access>read-only</access>
                        </field>
                        <field>
                            <name>RMDB_LH</name>
                            <description>RX Message Buffer Data Byte ((p × 4) + 1)</description>
                            <lsb>8</lsb>
                            <msb>15</msb>
                            <access>read-only</access>
                        </field>
                        <field>
                            <name>RMDB_HL</name>
                            <description>RX Message Buffer Data Byte ((p × 4) + 2)</description>
                            <lsb>16</lsb>
                            <msb>23</msb>
                            <access>read-only</access>
                        </field>
                        <field>
                            <name>RMDB_HH</name>
                            <description>RX Message Buffer Data Byte ((p × 4) + 3)</description>
                            <lsb>24</lsb>
                            <msb>31</msb>
                            <access>read-only</access>
                        </field>
                    </fields>
                </register>
                <register>
                    <dim>8</dim>
                    <dimIncrement>0x004C</dimIncrement>
                    <dimIndex>0-7</dimIndex>
                    <name>CFDRMDF%s_8</name>
                    <description>RX Message Buffer Data Field 8 Registers</description>
                    <addressOffset>0x094C</addressOffset>
                    <size>32</size>
                    <access>read-only</access>
                    <resetValue>0x00000000</resetValue>
                    <resetMask>0xffffffff</resetMask>
                    <fields>
                        <field>
                            <name>RMDB_LL</name>
                            <description>RX Message Buffer Data Byte (p × 4)</description>
                            <lsb>0</lsb>
                            <msb>7</msb>
                            <access>read-only</access>
                        </field>
                        <field>
                            <name>RMDB_LH</name>
                            <description>RX Message Buffer Data Byte ((p × 4) + 1)</description>
                            <lsb>8</lsb>
                            <msb>15</msb>
                            <access>read-only</access>
                        </field>
                        <field>
                            <name>RMDB_HL</name>
                            <description>RX Message Buffer Data Byte ((p × 4) + 2)</description>
                            <lsb>16</lsb>
                            <msb>23</msb>
                            <access>read-only</access>
                        </field>
                        <field>
                            <name>RMDB_HH</name>
                            <description>RX Message Buffer Data Byte ((p × 4) + 3)</description>
                            <lsb>24</lsb>
                            <msb>31</msb>
                            <access>read-only</access>
                        </field>
                    </fields>
                </register>
                <register>
                    <dim>8</dim>
                    <dimIncrement>0x004C</dimIncrement>
                    <dimIndex>0-7</dimIndex>
                    <name>CFDRMDF%s_9</name>
                    <description>RX Message Buffer Data Field 9 Registers</description>
                    <addressOffset>0x0950</addressOffset>
                    <size>32</size>
                    <access>read-only</access>
                    <resetValue>0x00000000</resetValue>
                    <resetMask>0xffffffff</resetMask>
                    <fields>
                        <field>
                            <name>RMDB_LL</name>
                            <description>RX Message Buffer Data Byte (p × 4)</description>
                            <lsb>0</lsb>
                            <msb>7</msb>
                            <access>read-only</access>
                        </field>
                        <field>
                            <name>RMDB_LH</name>
                            <description>RX Message Buffer Data Byte ((p × 4) + 1)</description>
                            <lsb>8</lsb>
                            <msb>15</msb>
                            <access>read-only</access>
                        </field>
                        <field>
                            <name>RMDB_HL</name>
                            <description>RX Message Buffer Data Byte ((p × 4) + 2)</description>
                            <lsb>16</lsb>
                            <msb>23</msb>
                            <access>read-only</access>
                        </field>
                        <field>
                            <name>RMDB_HH</name>
                            <description>RX Message Buffer Data Byte ((p × 4) + 3)</description>
                            <lsb>24</lsb>
                            <msb>31</msb>
                            <access>read-only</access>
                        </field>
                    </fields>
                </register>
                <register>
                    <dim>8</dim>
                    <dimIncrement>0x004C</dimIncrement>
                    <dimIndex>0-7</dimIndex>
                    <name>CFDRMDF%s_10</name>
                    <description>RX Message Buffer Data Field 10 Registers</description>
                    <addressOffset>0x0954</addressOffset>
                    <size>32</size>
                    <access>read-only</access>
                    <resetValue>0x00000000</resetValue>
                    <resetMask>0xffffffff</resetMask>
                    <fields>
                        <field>
                            <name>RMDB_LL</name>
                            <description>RX Message Buffer Data Byte (p × 4)</description>
                            <lsb>0</lsb>
                            <msb>7</msb>
                            <access>read-only</access>
                        </field>
                        <field>
                            <name>RMDB_LH</name>
                            <description>RX Message Buffer Data Byte ((p × 4) + 1)</description>
                            <lsb>8</lsb>
                            <msb>15</msb>
                            <access>read-only</access>
                        </field>
                        <field>
                            <name>RMDB_HL</name>
                            <description>RX Message Buffer Data Byte ((p × 4) + 2)</description>
                            <lsb>16</lsb>
                            <msb>23</msb>
                            <access>read-only</access>
                        </field>
                        <field>
                            <name>RMDB_HH</name>
                            <description>RX Message Buffer Data Byte ((p × 4) + 3)</description>
                            <lsb>24</lsb>
                            <msb>31</msb>
                            <access>read-only</access>
                        </field>
                    </fields>
                </register>
                <register>
                    <dim>8</dim>
                    <dimIncrement>0x004C</dimIncrement>
                    <dimIndex>0-7</dimIndex>
                    <name>CFDRMDF%s_11</name>
                    <description>RX Message Buffer Data Field 11 Registers</description>
                    <addressOffset>0x0958</addressOffset>
                    <size>32</size>
                    <access>read-only</access>
                    <resetValue>0x00000000</resetValue>
                    <resetMask>0xffffffff</resetMask>
                    <fields>
                        <field>
                            <name>RMDB_LL</name>
                            <description>RX Message Buffer Data Byte (p × 4)</description>
                            <lsb>0</lsb>
                            <msb>7</msb>
                            <access>read-only</access>
                        </field>
                        <field>
                            <name>RMDB_LH</name>
                            <description>RX Message Buffer Data Byte ((p × 4) + 1)</description>
                            <lsb>8</lsb>
                            <msb>15</msb>
                            <access>read-only</access>
                        </field>
                        <field>
                            <name>RMDB_HL</name>
                            <description>RX Message Buffer Data Byte ((p × 4) + 2)</description>
                            <lsb>16</lsb>
                            <msb>23</msb>
                            <access>read-only</access>
                        </field>
                        <field>
                            <name>RMDB_HH</name>
                            <description>RX Message Buffer Data Byte ((p × 4) + 3)</description>
                            <lsb>24</lsb>
                            <msb>31</msb>
                            <access>read-only</access>
                        </field>
                    </fields>
                </register>
                <register>
                    <dim>8</dim>
                    <dimIncrement>0x004C</dimIncrement>
                    <dimIndex>0-7</dimIndex>
                    <name>CFDRMDF%s_12</name>
                    <description>RX Message Buffer Data Field 12 Registers</description>
                    <addressOffset>0x095C</addressOffset>
                    <size>32</size>
                    <access>read-only</access>
                    <resetValue>0x00000000</resetValue>
                    <resetMask>0xffffffff</resetMask>
                    <fields>
                        <field>
                            <name>RMDB_LL</name>
                            <description>RX Message Buffer Data Byte (p × 4)</description>
                            <lsb>0</lsb>
                            <msb>7</msb>
                            <access>read-only</access>
                        </field>
                        <field>
                            <name>RMDB_LH</name>
                            <description>RX Message Buffer Data Byte ((p × 4) + 1)</description>
                            <lsb>8</lsb>
                            <msb>15</msb>
                            <access>read-only</access>
                        </field>
                        <field>
                            <name>RMDB_HL</name>
                            <description>RX Message Buffer Data Byte ((p × 4) + 2)</description>
                            <lsb>16</lsb>
                            <msb>23</msb>
                            <access>read-only</access>
                        </field>
                        <field>
                            <name>RMDB_HH</name>
                            <description>RX Message Buffer Data Byte ((p × 4) + 3)</description>
                            <lsb>24</lsb>
                            <msb>31</msb>
                            <access>read-only</access>
                        </field>
                    </fields>
                </register>
                <register>
                    <dim>8</dim>
                    <dimIncrement>0x004C</dimIncrement>
                    <dimIndex>0-7</dimIndex>
                    <name>CFDRMDF%s_13</name>
                    <description>RX Message Buffer Data Field 13 Registers</description>
                    <addressOffset>0x0960</addressOffset>
                    <size>32</size>
                    <access>read-only</access>
                    <resetValue>0x00000000</resetValue>
                    <resetMask>0xffffffff</resetMask>
                    <fields>
                        <field>
                            <name>RMDB_LL</name>
                            <description>RX Message Buffer Data Byte (p × 4)</description>
                            <lsb>0</lsb>
                            <msb>7</msb>
                            <access>read-only</access>
                        </field>
                        <field>
                            <name>RMDB_LH</name>
                            <description>RX Message Buffer Data Byte ((p × 4) + 1)</description>
                            <lsb>8</lsb>
                            <msb>15</msb>
                            <access>read-only</access>
                        </field>
                        <field>
                            <name>RMDB_HL</name>
                            <description>RX Message Buffer Data Byte ((p × 4) + 2)</description>
                            <lsb>16</lsb>
                            <msb>23</msb>
                            <access>read-only</access>
                        </field>
                        <field>
                            <name>RMDB_HH</name>
                            <description>RX Message Buffer Data Byte ((p × 4) + 3)</description>
                            <lsb>24</lsb>
                            <msb>31</msb>
                            <access>read-only</access>
                        </field>
                    </fields>
                </register>
                <register>
                    <dim>8</dim>
                    <dimIncrement>0x004C</dimIncrement>
                    <dimIndex>0-7</dimIndex>
                    <name>CFDRMDF%s_14</name>
                    <description>RX Message Buffer Data Field 14 Registers</description>
                    <addressOffset>0x0964</addressOffset>
                    <size>32</size>
                    <access>read-only</access>
                    <resetValue>0x00000000</resetValue>
                    <resetMask>0xffffffff</resetMask>
                    <fields>
                        <field>
                            <name>RMDB_LL</name>
                            <description>RX Message Buffer Data Byte (p × 4)</description>
                            <lsb>0</lsb>
                            <msb>7</msb>
                            <access>read-only</access>
                        </field>
                        <field>
                            <name>RMDB_LH</name>
                            <description>RX Message Buffer Data Byte ((p × 4) + 1)</description>
                            <lsb>8</lsb>
                            <msb>15</msb>
                            <access>read-only</access>
                        </field>
                        <field>
                            <name>RMDB_HL</name>
                            <description>RX Message Buffer Data Byte ((p × 4) + 2)</description>
                            <lsb>16</lsb>
                            <msb>23</msb>
                            <access>read-only</access>
                        </field>
                        <field>
                            <name>RMDB_HH</name>
                            <description>RX Message Buffer Data Byte ((p × 4) + 3)</description>
                            <lsb>24</lsb>
                            <msb>31</msb>
                            <access>read-only</access>
                        </field>
                    </fields>
                </register>
                <register>
                    <dim>8</dim>
                    <dimIncrement>0x004C</dimIncrement>
                    <dimIndex>0-7</dimIndex>
                    <name>CFDRMDF%s_15</name>
                    <description>RX Message Buffer Data Field 15 Registers</description>
                    <addressOffset>0x0968</addressOffset>
                    <size>32</size>
                    <access>read-only</access>
                    <resetValue>0x00000000</resetValue>
                    <resetMask>0xffffffff</resetMask>
                    <fields>
                        <field>
                            <name>RMDB_LL</name>
                            <description>RX Message Buffer Data Byte (p × 4)</description>
                            <lsb>0</lsb>
                            <msb>7</msb>
                            <access>read-only</access>
                        </field>
                        <field>
                            <name>RMDB_LH</name>
                            <description>RX Message Buffer Data Byte ((p × 4) + 1)</description>
                            <lsb>8</lsb>
                            <msb>15</msb>
                            <access>read-only</access>
                        </field>
                        <field>
                            <name>RMDB_HL</name>
                            <description>RX Message Buffer Data Byte ((p × 4) + 2)</description>
                            <lsb>16</lsb>
                            <msb>23</msb>
                            <access>read-only</access>
                        </field>
                        <field>
                            <name>RMDB_HH</name>
                            <description>RX Message Buffer Data Byte ((p × 4) + 3)</description>
                            <lsb>24</lsb>
                            <msb>31</msb>
                            <access>read-only</access>
                        </field>
                    </fields>
                </register>
                <register>
                    <dim>8</dim>
                    <dimIncrement>0x004C</dimIncrement>
                    <dimIndex>8-15</dimIndex>
                    <name>CFDRMID%s</name>
                    <description>RX Message Buffer ID Registers</description>
                    <addressOffset>0x0D20</addressOffset>
                    <size>32</size>
                    <access>read-only</access>
                    <resetValue>0x00000000</resetValue>
                    <resetMask>0xffffffff</resetMask>
                    <fields>
                        <field>
                            <name>RMID</name>
                            <description>RX Message Buffer ID Field</description>
                            <lsb>0</lsb>
                            <msb>28</msb>
                            <access>read-only</access>
                        </field>
                        <field>
                            <name>RMRTR</name>
                            <description>RX Message Buffer RTR Bit</description>
                            <lsb>30</lsb>
                            <msb>30</msb>
                            <access>read-only</access>
                            <enumeratedValues>
                                <enumeratedValue>
                                    <name>0</name>
                                    <description>Data frame</description>
                                    <value>#0</value>
                                </enumeratedValue>
                                <enumeratedValue>
                                    <name>1</name>
                                    <description>Remote frame</description>
                                    <value>#1</value>
                                </enumeratedValue>
                            </enumeratedValues>
                        </field>
                        <field>
                            <name>RMIDE</name>
                            <description>RX Message Buffer IDE Bit</description>
                            <lsb>31</lsb>
                            <msb>31</msb>
                            <access>read-only</access>
                            <enumeratedValues>
                                <enumeratedValue>
                                    <name>0</name>
                                    <description>STD-ID is stored</description>
                                    <value>#0</value>
                                </enumeratedValue>
                                <enumeratedValue>
                                    <name>1</name>
                                    <description>EXT-ID is stored</description>
                                    <value>#1</value>
                                </enumeratedValue>
                            </enumeratedValues>
                        </field>
                    </fields>
                </register>
                <register>
                    <dim>8</dim>
                    <dimIncrement>0x004C</dimIncrement>
                    <dimIndex>8-15</dimIndex>
                    <name>CFDRMPTR%s</name>
                    <description>RX Message Buffer Pointer Registers</description>
                    <addressOffset>0x0D24</addressOffset>
                    <size>32</size>
                    <access>read-only</access>
                    <resetValue>0x00000000</resetValue>
                    <resetMask>0xffffffff</resetMask>
                    <fields>
                        <field>
                            <name>RMTS</name>
                            <description>RX Message Buffer Timestamp Field</description>
                            <lsb>0</lsb>
                            <msb>15</msb>
                            <access>read-only</access>
                        </field>
                        <field>
                            <name>RMDLC</name>
                            <description>RX Message Buffer DLC Field</description>
                            <lsb>28</lsb>
                            <msb>31</msb>
                            <access>read-only</access>
                        </field>
                    </fields>
                </register>
                <register>
                    <dim>8</dim>
                    <dimIncrement>0x004C</dimIncrement>
                    <dimIndex>8-15</dimIndex>
                    <name>CFDRMFDSTS%s</name>
                    <description>RX Message Buffer CANFD Status Registers</description>
                    <addressOffset>0x0D28</addressOffset>
                    <size>32</size>
                    <access>read-only</access>
                    <resetValue>0x00000000</resetValue>
                    <resetMask>0xffffffff</resetMask>
                    <fields>
                        <field>
                            <name>RMESI</name>
                            <description>Error State Indicator bit</description>
                            <lsb>0</lsb>
                            <msb>0</msb>
                            <access>read-only</access>
                            <enumeratedValues>
                                <enumeratedValue>
                                    <name>0</name>
                                    <description>CANFD frame received from error active node</description>
                                    <value>#0</value>
                                </enumeratedValue>
                                <enumeratedValue>
                                    <name>1</name>
                                    <description>CANFD frame received from error passive node</description>
                                    <value>#1</value>
                                </enumeratedValue>
                            </enumeratedValues>
                        </field>
                        <field>
                            <name>RMBRS</name>
                            <description>Bit Rate Switch bit</description>
                            <lsb>1</lsb>
                            <msb>1</msb>
                            <access>read-only</access>
                            <enumeratedValues>
                                <enumeratedValue>
                                    <name>0</name>
                                    <description>CANFD frame received with no bit rate switch</description>
                                    <value>#0</value>
                                </enumeratedValue>
                                <enumeratedValue>
                                    <name>1</name>
                                    <description>CANFD frame received with bit rate switch</description>
                                    <value>#1</value>
                                </enumeratedValue>
                            </enumeratedValues>
                        </field>
                        <field>
                            <name>RMFDF</name>
                            <description>CAN FD Format bit</description>
                            <lsb>2</lsb>
                            <msb>2</msb>
                            <access>read-only</access>
                            <enumeratedValues>
                                <enumeratedValue>
                                    <name>0</name>
                                    <description>Non CANFD frame received</description>
                                    <value>#0</value>
                                </enumeratedValue>
                                <enumeratedValue>
                                    <name>1</name>
                                    <description>CANFD frame received</description>
                                    <value>#1</value>
                                </enumeratedValue>
                            </enumeratedValues>
                        </field>
                        <field>
                            <name>RMIFL</name>
                            <description>RX Message Buffer Information Label Field</description>
                            <lsb>8</lsb>
                            <msb>9</msb>
                            <access>read-only</access>
                        </field>
                        <field>
                            <name>RMPTR</name>
                            <description>RX Message Buffer Pointer Field</description>
                            <lsb>16</lsb>
                            <msb>31</msb>
                            <access>read-only</access>
                        </field>
                    </fields>
                </register>
                <register>
                    <dim>8</dim>
                    <dimIncrement>0x004C</dimIncrement>
                    <dimIndex>8-15</dimIndex>
                    <name>CFDRMDF%s_0</name>
                    <description>RX Message Buffer Data Field 0 Registers</description>
                    <addressOffset>0x0D2C</addressOffset>
                    <size>32</size>
                    <access>read-only</access>
                    <resetValue>0x00000000</resetValue>
                    <resetMask>0xffffffff</resetMask>
                    <fields>
                        <field>
                            <name>RMDB_LL</name>
                            <description>RX Message Buffer Data Byte (p × 4)</description>
                            <lsb>0</lsb>
                            <msb>7</msb>
                            <access>read-only</access>
                        </field>
                        <field>
                            <name>RMDB_LH</name>
                            <description>RX Message Buffer Data Byte ((p × 4) + 1)</description>
                            <lsb>8</lsb>
                            <msb>15</msb>
                            <access>read-only</access>
                        </field>
                        <field>
                            <name>RMDB_HL</name>
                            <description>RX Message Buffer Data Byte ((p × 4) + 2)</description>
                            <lsb>16</lsb>
                            <msb>23</msb>
                            <access>read-only</access>
                        </field>
                        <field>
                            <name>RMDB_HH</name>
                            <description>RX Message Buffer Data Byte ((p × 4) + 3)</description>
                            <lsb>24</lsb>
                            <msb>31</msb>
                            <access>read-only</access>
                        </field>
                    </fields>
                </register>
                <register>
                    <dim>8</dim>
                    <dimIncrement>0x004C</dimIncrement>
                    <dimIndex>8-15</dimIndex>
                    <name>CFDRMDF%s_1</name>
                    <description>RX Message Buffer Data Field 1 Registers</description>
                    <addressOffset>0x0D30</addressOffset>
                    <size>32</size>
                    <access>read-only</access>
                    <resetValue>0x00000000</resetValue>
                    <resetMask>0xffffffff</resetMask>
                    <fields>
                        <field>
                            <name>RMDB_LL</name>
                            <description>RX Message Buffer Data Byte (p × 4)</description>
                            <lsb>0</lsb>
                            <msb>7</msb>
                            <access>read-only</access>
                        </field>
                        <field>
                            <name>RMDB_LH</name>
                            <description>RX Message Buffer Data Byte ((p × 4) + 1)</description>
                            <lsb>8</lsb>
                            <msb>15</msb>
                            <access>read-only</access>
                        </field>
                        <field>
                            <name>RMDB_HL</name>
                            <description>RX Message Buffer Data Byte ((p × 4) + 2)</description>
                            <lsb>16</lsb>
                            <msb>23</msb>
                            <access>read-only</access>
                        </field>
                        <field>
                            <name>RMDB_HH</name>
                            <description>RX Message Buffer Data Byte ((p × 4) + 3)</description>
                            <lsb>24</lsb>
                            <msb>31</msb>
                            <access>read-only</access>
                        </field>
                    </fields>
                </register>
                <register>
                    <dim>8</dim>
                    <dimIncrement>0x004C</dimIncrement>
                    <dimIndex>8-15</dimIndex>
                    <name>CFDRMDF%s_2</name>
                    <description>RX Message Buffer Data Field 2 Registers</description>
                    <addressOffset>0x0D34</addressOffset>
                    <size>32</size>
                    <access>read-only</access>
                    <resetValue>0x00000000</resetValue>
                    <resetMask>0xffffffff</resetMask>
                    <fields>
                        <field>
                            <name>RMDB_LL</name>
                            <description>RX Message Buffer Data Byte (p × 4)</description>
                            <lsb>0</lsb>
                            <msb>7</msb>
                            <access>read-only</access>
                        </field>
                        <field>
                            <name>RMDB_LH</name>
                            <description>RX Message Buffer Data Byte ((p × 4) + 1)</description>
                            <lsb>8</lsb>
                            <msb>15</msb>
                            <access>read-only</access>
                        </field>
                        <field>
                            <name>RMDB_HL</name>
                            <description>RX Message Buffer Data Byte ((p × 4) + 2)</description>
                            <lsb>16</lsb>
                            <msb>23</msb>
                            <access>read-only</access>
                        </field>
                        <field>
                            <name>RMDB_HH</name>
                            <description>RX Message Buffer Data Byte ((p × 4) + 3)</description>
                            <lsb>24</lsb>
                            <msb>31</msb>
                            <access>read-only</access>
                        </field>
                    </fields>
                </register>
                <register>
                    <dim>8</dim>
                    <dimIncrement>0x004C</dimIncrement>
                    <dimIndex>8-15</dimIndex>
                    <name>CFDRMDF%s_3</name>
                    <description>RX Message Buffer Data Field 3 Registers</description>
                    <addressOffset>0x0D38</addressOffset>
                    <size>32</size>
                    <access>read-only</access>
                    <resetValue>0x00000000</resetValue>
                    <resetMask>0xffffffff</resetMask>
                    <fields>
                        <field>
                            <name>RMDB_LL</name>
                            <description>RX Message Buffer Data Byte (p × 4)</description>
                            <lsb>0</lsb>
                            <msb>7</msb>
                            <access>read-only</access>
                        </field>
                        <field>
                            <name>RMDB_LH</name>
                            <description>RX Message Buffer Data Byte ((p × 4) + 1)</description>
                            <lsb>8</lsb>
                            <msb>15</msb>
                            <access>read-only</access>
                        </field>
                        <field>
                            <name>RMDB_HL</name>
                            <description>RX Message Buffer Data Byte ((p × 4) + 2)</description>
                            <lsb>16</lsb>
                            <msb>23</msb>
                            <access>read-only</access>
                        </field>
                        <field>
                            <name>RMDB_HH</name>
                            <description>RX Message Buffer Data Byte ((p × 4) + 3)</description>
                            <lsb>24</lsb>
                            <msb>31</msb>
                            <access>read-only</access>
                        </field>
                    </fields>
                </register>
                <register>
                    <dim>8</dim>
                    <dimIncrement>0x004C</dimIncrement>
                    <dimIndex>8-15</dimIndex>
                    <name>CFDRMDF%s_4</name>
                    <description>RX Message Buffer Data Field 4 Registers</description>
                    <addressOffset>0x0D3C</addressOffset>
                    <size>32</size>
                    <access>read-only</access>
                    <resetValue>0x00000000</resetValue>
                    <resetMask>0xffffffff</resetMask>
                    <fields>
                        <field>
                            <name>RMDB_LL</name>
                            <description>RX Message Buffer Data Byte (p × 4)</description>
                            <lsb>0</lsb>
                            <msb>7</msb>
                            <access>read-only</access>
                        </field>
                        <field>
                            <name>RMDB_LH</name>
                            <description>RX Message Buffer Data Byte ((p × 4) + 1)</description>
                            <lsb>8</lsb>
                            <msb>15</msb>
                            <access>read-only</access>
                        </field>
                        <field>
                            <name>RMDB_HL</name>
                            <description>RX Message Buffer Data Byte ((p × 4) + 2)</description>
                            <lsb>16</lsb>
                            <msb>23</msb>
                            <access>read-only</access>
                        </field>
                        <field>
                            <name>RMDB_HH</name>
                            <description>RX Message Buffer Data Byte ((p × 4) + 3)</description>
                            <lsb>24</lsb>
                            <msb>31</msb>
                            <access>read-only</access>
                        </field>
                    </fields>
                </register>
                <register>
                    <dim>8</dim>
                    <dimIncrement>0x004C</dimIncrement>
                    <dimIndex>8-15</dimIndex>
                    <name>CFDRMDF%s_5</name>
                    <description>RX Message Buffer Data Field 5 Registers</description>
                    <addressOffset>0x0D40</addressOffset>
                    <size>32</size>
                    <access>read-only</access>
                    <resetValue>0x00000000</resetValue>
                    <resetMask>0xffffffff</resetMask>
                    <fields>
                        <field>
                            <name>RMDB_LL</name>
                            <description>RX Message Buffer Data Byte (p × 4)</description>
                            <lsb>0</lsb>
                            <msb>7</msb>
                            <access>read-only</access>
                        </field>
                        <field>
                            <name>RMDB_LH</name>
                            <description>RX Message Buffer Data Byte ((p × 4) + 1)</description>
                            <lsb>8</lsb>
                            <msb>15</msb>
                            <access>read-only</access>
                        </field>
                        <field>
                            <name>RMDB_HL</name>
                            <description>RX Message Buffer Data Byte ((p × 4) + 2)</description>
                            <lsb>16</lsb>
                            <msb>23</msb>
                            <access>read-only</access>
                        </field>
                        <field>
                            <name>RMDB_HH</name>
                            <description>RX Message Buffer Data Byte ((p × 4) + 3)</description>
                            <lsb>24</lsb>
                            <msb>31</msb>
                            <access>read-only</access>
                        </field>
                    </fields>
                </register>
                <register>
                    <dim>8</dim>
                    <dimIncrement>0x004C</dimIncrement>
                    <dimIndex>8-15</dimIndex>
                    <name>CFDRMDF%s_6</name>
                    <description>RX Message Buffer Data Field 6 Registers</description>
                    <addressOffset>0x0D44</addressOffset>
                    <size>32</size>
                    <access>read-only</access>
                    <resetValue>0x00000000</resetValue>
                    <resetMask>0xffffffff</resetMask>
                    <fields>
                        <field>
                            <name>RMDB_LL</name>
                            <description>RX Message Buffer Data Byte (p × 4)</description>
                            <lsb>0</lsb>
                            <msb>7</msb>
                            <access>read-only</access>
                        </field>
                        <field>
                            <name>RMDB_LH</name>
                            <description>RX Message Buffer Data Byte ((p × 4) + 1)</description>
                            <lsb>8</lsb>
                            <msb>15</msb>
                            <access>read-only</access>
                        </field>
                        <field>
                            <name>RMDB_HL</name>
                            <description>RX Message Buffer Data Byte ((p × 4) + 2)</description>
                            <lsb>16</lsb>
                            <msb>23</msb>
                            <access>read-only</access>
                        </field>
                        <field>
                            <name>RMDB_HH</name>
                            <description>RX Message Buffer Data Byte ((p × 4) + 3)</description>
                            <lsb>24</lsb>
                            <msb>31</msb>
                            <access>read-only</access>
                        </field>
                    </fields>
                </register>
                <register>
                    <dim>8</dim>
                    <dimIncrement>0x004C</dimIncrement>
                    <dimIndex>8-15</dimIndex>
                    <name>CFDRMDF%s_7</name>
                    <description>RX Message Buffer Data Field 7 Registers</description>
                    <addressOffset>0x0D48</addressOffset>
                    <size>32</size>
                    <access>read-only</access>
                    <resetValue>0x00000000</resetValue>
                    <resetMask>0xffffffff</resetMask>
                    <fields>
                        <field>
                            <name>RMDB_LL</name>
                            <description>RX Message Buffer Data Byte (p × 4)</description>
                            <lsb>0</lsb>
                            <msb>7</msb>
                            <access>read-only</access>
                        </field>
                        <field>
                            <name>RMDB_LH</name>
                            <description>RX Message Buffer Data Byte ((p × 4) + 1)</description>
                            <lsb>8</lsb>
                            <msb>15</msb>
                            <access>read-only</access>
                        </field>
                        <field>
                            <name>RMDB_HL</name>
                            <description>RX Message Buffer Data Byte ((p × 4) + 2)</description>
                            <lsb>16</lsb>
                            <msb>23</msb>
                            <access>read-only</access>
                        </field>
                        <field>
                            <name>RMDB_HH</name>
                            <description>RX Message Buffer Data Byte ((p × 4) + 3)</description>
                            <lsb>24</lsb>
                            <msb>31</msb>
                            <access>read-only</access>
                        </field>
                    </fields>
                </register>
                <register>
                    <dim>8</dim>
                    <dimIncrement>0x004C</dimIncrement>
                    <dimIndex>8-15</dimIndex>
                    <name>CFDRMDF%s_8</name>
                    <description>RX Message Buffer Data Field 8 Registers</description>
                    <addressOffset>0x0D4C</addressOffset>
                    <size>32</size>
                    <access>read-only</access>
                    <resetValue>0x00000000</resetValue>
                    <resetMask>0xffffffff</resetMask>
                    <fields>
                        <field>
                            <name>RMDB_LL</name>
                            <description>RX Message Buffer Data Byte (p × 4)</description>
                            <lsb>0</lsb>
                            <msb>7</msb>
                            <access>read-only</access>
                        </field>
                        <field>
                            <name>RMDB_LH</name>
                            <description>RX Message Buffer Data Byte ((p × 4) + 1)</description>
                            <lsb>8</lsb>
                            <msb>15</msb>
                            <access>read-only</access>
                        </field>
                        <field>
                            <name>RMDB_HL</name>
                            <description>RX Message Buffer Data Byte ((p × 4) + 2)</description>
                            <lsb>16</lsb>
                            <msb>23</msb>
                            <access>read-only</access>
                        </field>
                        <field>
                            <name>RMDB_HH</name>
                            <description>RX Message Buffer Data Byte ((p × 4) + 3)</description>
                            <lsb>24</lsb>
                            <msb>31</msb>
                            <access>read-only</access>
                        </field>
                    </fields>
                </register>
                <register>
                    <dim>8</dim>
                    <dimIncrement>0x004C</dimIncrement>
                    <dimIndex>8-15</dimIndex>
                    <name>CFDRMDF%s_9</name>
                    <description>RX Message Buffer Data Field 9 Registers</description>
                    <addressOffset>0x0D50</addressOffset>
                    <size>32</size>
                    <access>read-only</access>
                    <resetValue>0x00000000</resetValue>
                    <resetMask>0xffffffff</resetMask>
                    <fields>
                        <field>
                            <name>RMDB_LL</name>
                            <description>RX Message Buffer Data Byte (p × 4)</description>
                            <lsb>0</lsb>
                            <msb>7</msb>
                            <access>read-only</access>
                        </field>
                        <field>
                            <name>RMDB_LH</name>
                            <description>RX Message Buffer Data Byte ((p × 4) + 1)</description>
                            <lsb>8</lsb>
                            <msb>15</msb>
                            <access>read-only</access>
                        </field>
                        <field>
                            <name>RMDB_HL</name>
                            <description>RX Message Buffer Data Byte ((p × 4) + 2)</description>
                            <lsb>16</lsb>
                            <msb>23</msb>
                            <access>read-only</access>
                        </field>
                        <field>
                            <name>RMDB_HH</name>
                            <description>RX Message Buffer Data Byte ((p × 4) + 3)</description>
                            <lsb>24</lsb>
                            <msb>31</msb>
                            <access>read-only</access>
                        </field>
                    </fields>
                </register>
                <register>
                    <dim>8</dim>
                    <dimIncrement>0x004C</dimIncrement>
                    <dimIndex>8-15</dimIndex>
                    <name>CFDRMDF%s_10</name>
                    <description>RX Message Buffer Data Field 10 Registers</description>
                    <addressOffset>0x0D54</addressOffset>
                    <size>32</size>
                    <access>read-only</access>
                    <resetValue>0x00000000</resetValue>
                    <resetMask>0xffffffff</resetMask>
                    <fields>
                        <field>
                            <name>RMDB_LL</name>
                            <description>RX Message Buffer Data Byte (p × 4)</description>
                            <lsb>0</lsb>
                            <msb>7</msb>
                            <access>read-only</access>
                        </field>
                        <field>
                            <name>RMDB_LH</name>
                            <description>RX Message Buffer Data Byte ((p × 4) + 1)</description>
                            <lsb>8</lsb>
                            <msb>15</msb>
                            <access>read-only</access>
                        </field>
                        <field>
                            <name>RMDB_HL</name>
                            <description>RX Message Buffer Data Byte ((p × 4) + 2)</description>
                            <lsb>16</lsb>
                            <msb>23</msb>
                            <access>read-only</access>
                        </field>
                        <field>
                            <name>RMDB_HH</name>
                            <description>RX Message Buffer Data Byte ((p × 4) + 3)</description>
                            <lsb>24</lsb>
                            <msb>31</msb>
                            <access>read-only</access>
                        </field>
                    </fields>
                </register>
                <register>
                    <dim>8</dim>
                    <dimIncrement>0x004C</dimIncrement>
                    <dimIndex>8-15</dimIndex>
                    <name>CFDRMDF%s_11</name>
                    <description>RX Message Buffer Data Field 11 Registers</description>
                    <addressOffset>0x0D58</addressOffset>
                    <size>32</size>
                    <access>read-only</access>
                    <resetValue>0x00000000</resetValue>
                    <resetMask>0xffffffff</resetMask>
                    <fields>
                        <field>
                            <name>RMDB_LL</name>
                            <description>RX Message Buffer Data Byte (p × 4)</description>
                            <lsb>0</lsb>
                            <msb>7</msb>
                            <access>read-only</access>
                        </field>
                        <field>
                            <name>RMDB_LH</name>
                            <description>RX Message Buffer Data Byte ((p × 4) + 1)</description>
                            <lsb>8</lsb>
                            <msb>15</msb>
                            <access>read-only</access>
                        </field>
                        <field>
                            <name>RMDB_HL</name>
                            <description>RX Message Buffer Data Byte ((p × 4) + 2)</description>
                            <lsb>16</lsb>
                            <msb>23</msb>
                            <access>read-only</access>
                        </field>
                        <field>
                            <name>RMDB_HH</name>
                            <description>RX Message Buffer Data Byte ((p × 4) + 3)</description>
                            <lsb>24</lsb>
                            <msb>31</msb>
                            <access>read-only</access>
                        </field>
                    </fields>
                </register>
                <register>
                    <dim>8</dim>
                    <dimIncrement>0x004C</dimIncrement>
                    <dimIndex>8-15</dimIndex>
                    <name>CFDRMDF%s_12</name>
                    <description>RX Message Buffer Data Field 12 Registers</description>
                    <addressOffset>0x0D5C</addressOffset>
                    <size>32</size>
                    <access>read-only</access>
                    <resetValue>0x00000000</resetValue>
                    <resetMask>0xffffffff</resetMask>
                    <fields>
                        <field>
                            <name>RMDB_LL</name>
                            <description>RX Message Buffer Data Byte (p × 4)</description>
                            <lsb>0</lsb>
                            <msb>7</msb>
                            <access>read-only</access>
                        </field>
                        <field>
                            <name>RMDB_LH</name>
                            <description>RX Message Buffer Data Byte ((p × 4) + 1)</description>
                            <lsb>8</lsb>
                            <msb>15</msb>
                            <access>read-only</access>
                        </field>
                        <field>
                            <name>RMDB_HL</name>
                            <description>RX Message Buffer Data Byte ((p × 4) + 2)</description>
                            <lsb>16</lsb>
                            <msb>23</msb>
                            <access>read-only</access>
                        </field>
                        <field>
                            <name>RMDB_HH</name>
                            <description>RX Message Buffer Data Byte ((p × 4) + 3)</description>
                            <lsb>24</lsb>
                            <msb>31</msb>
                            <access>read-only</access>
                        </field>
                    </fields>
                </register>
                <register>
                    <dim>8</dim>
                    <dimIncrement>0x004C</dimIncrement>
                    <dimIndex>8-15</dimIndex>
                    <name>CFDRMDF%s_13</name>
                    <description>RX Message Buffer Data Field 13 Registers</description>
                    <addressOffset>0x0D60</addressOffset>
                    <size>32</size>
                    <access>read-only</access>
                    <resetValue>0x00000000</resetValue>
                    <resetMask>0xffffffff</resetMask>
                    <fields>
                        <field>
                            <name>RMDB_LL</name>
                            <description>RX Message Buffer Data Byte (p × 4)</description>
                            <lsb>0</lsb>
                            <msb>7</msb>
                            <access>read-only</access>
                        </field>
                        <field>
                            <name>RMDB_LH</name>
                            <description>RX Message Buffer Data Byte ((p × 4) + 1)</description>
                            <lsb>8</lsb>
                            <msb>15</msb>
                            <access>read-only</access>
                        </field>
                        <field>
                            <name>RMDB_HL</name>
                            <description>RX Message Buffer Data Byte ((p × 4) + 2)</description>
                            <lsb>16</lsb>
                            <msb>23</msb>
                            <access>read-only</access>
                        </field>
                        <field>
                            <name>RMDB_HH</name>
                            <description>RX Message Buffer Data Byte ((p × 4) + 3)</description>
                            <lsb>24</lsb>
                            <msb>31</msb>
                            <access>read-only</access>
                        </field>
                    </fields>
                </register>
                <register>
                    <dim>8</dim>
                    <dimIncrement>0x004C</dimIncrement>
                    <dimIndex>8-15</dimIndex>
                    <name>CFDRMDF%s_14</name>
                    <description>RX Message Buffer Data Field 14 Registers</description>
                    <addressOffset>0x0D64</addressOffset>
                    <size>32</size>
                    <access>read-only</access>
                    <resetValue>0x00000000</resetValue>
                    <resetMask>0xffffffff</resetMask>
                    <fields>
                        <field>
                            <name>RMDB_LL</name>
                            <description>RX Message Buffer Data Byte (p × 4)</description>
                            <lsb>0</lsb>
                            <msb>7</msb>
                            <access>read-only</access>
                        </field>
                        <field>
                            <name>RMDB_LH</name>
                            <description>RX Message Buffer Data Byte ((p × 4) + 1)</description>
                            <lsb>8</lsb>
                            <msb>15</msb>
                            <access>read-only</access>
                        </field>
                        <field>
                            <name>RMDB_HL</name>
                            <description>RX Message Buffer Data Byte ((p × 4) + 2)</description>
                            <lsb>16</lsb>
                            <msb>23</msb>
                            <access>read-only</access>
                        </field>
                        <field>
                            <name>RMDB_HH</name>
                            <description>RX Message Buffer Data Byte ((p × 4) + 3)</description>
                            <lsb>24</lsb>
                            <msb>31</msb>
                            <access>read-only</access>
                        </field>
                    </fields>
                </register>
                <register>
                    <dim>8</dim>
                    <dimIncrement>0x004C</dimIncrement>
                    <dimIndex>8-15</dimIndex>
                    <name>CFDRMDF%s_15</name>
                    <description>RX Message Buffer Data Field 15 Registers</description>
                    <addressOffset>0x0D68</addressOffset>
                    <size>32</size>
                    <access>read-only</access>
                    <resetValue>0x00000000</resetValue>
                    <resetMask>0xffffffff</resetMask>
                    <fields>
                        <field>
                            <name>RMDB_LL</name>
                            <description>RX Message Buffer Data Byte (p × 4)</description>
                            <lsb>0</lsb>
                            <msb>7</msb>
                            <access>read-only</access>
                        </field>
                        <field>
                            <name>RMDB_LH</name>
                            <description>RX Message Buffer Data Byte ((p × 4) + 1)</description>
                            <lsb>8</lsb>
                            <msb>15</msb>
                            <access>read-only</access>
                        </field>
                        <field>
                            <name>RMDB_HL</name>
                            <description>RX Message Buffer Data Byte ((p × 4) + 2)</description>
                            <lsb>16</lsb>
                            <msb>23</msb>
                            <access>read-only</access>
                        </field>
                        <field>
                            <name>RMDB_HH</name>
                            <description>RX Message Buffer Data Byte ((p × 4) + 3)</description>
                            <lsb>24</lsb>
                            <msb>31</msb>
                            <access>read-only</access>
                        </field>
                    </fields>
                </register>
                <register>
                    <dim>8</dim>
                    <dimIncrement>0x004C</dimIncrement>
                    <dimIndex>16-23</dimIndex>
                    <name>CFDRMPTR%s</name>
                    <description>RX Message Buffer Pointer Registers</description>
                    <addressOffset>0x01124</addressOffset>
                    <size>32</size>
                    <access>read-only</access>
                    <resetValue>0x00000000</resetValue>
                    <resetMask>0xffffffff</resetMask>
                    <fields>
                        <field>
                            <name>RMTS</name>
                            <description>RX Message Buffer Timestamp Field</description>
                            <lsb>0</lsb>
                            <msb>15</msb>
                            <access>read-only</access>
                        </field>
                        <field>
                            <name>RMDLC</name>
                            <description>RX Message Buffer DLC Field</description>
                            <lsb>28</lsb>
                            <msb>31</msb>
                            <access>read-only</access>
                        </field>
                    </fields>
                </register>
                <register>
                    <dim>8</dim>
                    <dimIncrement>0x004C</dimIncrement>
                    <dimIndex>16-23</dimIndex>
                    <name>CFDRMFDSTS%s</name>
                    <description>RX Message Buffer CANFD Status Registers</description>
                    <addressOffset>0x01128</addressOffset>
                    <size>32</size>
                    <access>read-only</access>
                    <resetValue>0x00000000</resetValue>
                    <resetMask>0xffffffff</resetMask>
                    <fields>
                        <field>
                            <name>RMESI</name>
                            <description>Error State Indicator bit</description>
                            <lsb>0</lsb>
                            <msb>0</msb>
                            <access>read-only</access>
                            <enumeratedValues>
                                <enumeratedValue>
                                    <name>0</name>
                                    <description>CANFD frame received from error active node</description>
                                    <value>#0</value>
                                </enumeratedValue>
                                <enumeratedValue>
                                    <name>1</name>
                                    <description>CANFD frame received from error passive node</description>
                                    <value>#1</value>
                                </enumeratedValue>
                            </enumeratedValues>
                        </field>
                        <field>
                            <name>RMBRS</name>
                            <description>Bit Rate Switch bit</description>
                            <lsb>1</lsb>
                            <msb>1</msb>
                            <access>read-only</access>
                            <enumeratedValues>
                                <enumeratedValue>
                                    <name>0</name>
                                    <description>CANFD frame received with no bit rate switch</description>
                                    <value>#0</value>
                                </enumeratedValue>
                                <enumeratedValue>
                                    <name>1</name>
                                    <description>CANFD frame received with bit rate switch</description>
                                    <value>#1</value>
                                </enumeratedValue>
                            </enumeratedValues>
                        </field>
                        <field>
                            <name>RMFDF</name>
                            <description>CAN FD Format bit</description>
                            <lsb>2</lsb>
                            <msb>2</msb>
                            <access>read-only</access>
                            <enumeratedValues>
                                <enumeratedValue>
                                    <name>0</name>
                                    <description>Non CANFD frame received</description>
                                    <value>#0</value>
                                </enumeratedValue>
                                <enumeratedValue>
                                    <name>1</name>
                                    <description>CANFD frame received</description>
                                    <value>#1</value>
                                </enumeratedValue>
                            </enumeratedValues>
                        </field>
                        <field>
                            <name>RMIFL</name>
                            <description>RX Message Buffer Information Label Field</description>
                            <lsb>8</lsb>
                            <msb>9</msb>
                            <access>read-only</access>
                        </field>
                        <field>
                            <name>RMPTR</name>
                            <description>RX Message Buffer Pointer Field</description>
                            <lsb>16</lsb>
                            <msb>31</msb>
                            <access>read-only</access>
                        </field>
                    </fields>
                </register>
                <register>
                    <dim>8</dim>
                    <dimIncrement>0x004C</dimIncrement>
                    <dimIndex>16-23</dimIndex>
                    <name>CFDRMDF%s_0</name>
                    <description>RX Message Buffer Data Field 0 Registers</description>
                    <addressOffset>0x112C</addressOffset>
                    <size>32</size>
                    <access>read-only</access>
                    <resetValue>0x00000000</resetValue>
                    <resetMask>0xffffffff</resetMask>
                    <fields>
                        <field>
                            <name>RMDB_LL</name>
                            <description>RX Message Buffer Data Byte (p × 4)</description>
                            <lsb>0</lsb>
                            <msb>7</msb>
                            <access>read-only</access>
                        </field>
                        <field>
                            <name>RMDB_LH</name>
                            <description>RX Message Buffer Data Byte ((p × 4) + 1)</description>
                            <lsb>8</lsb>
                            <msb>15</msb>
                            <access>read-only</access>
                        </field>
                        <field>
                            <name>RMDB_HL</name>
                            <description>RX Message Buffer Data Byte ((p × 4) + 2)</description>
                            <lsb>16</lsb>
                            <msb>23</msb>
                            <access>read-only</access>
                        </field>
                        <field>
                            <name>RMDB_HH</name>
                            <description>RX Message Buffer Data Byte ((p × 4) + 3)</description>
                            <lsb>24</lsb>
                            <msb>31</msb>
                            <access>read-only</access>
                        </field>
                    </fields>
                </register>
                <register>
                    <dim>8</dim>
                    <dimIncrement>0x004C</dimIncrement>
                    <dimIndex>16-23</dimIndex>
                    <name>CFDRMDF%s_1</name>
                    <description>RX Message Buffer Data Field 1 Registers</description>
                    <addressOffset>0x1130</addressOffset>
                    <size>32</size>
                    <access>read-only</access>
                    <resetValue>0x00000000</resetValue>
                    <resetMask>0xffffffff</resetMask>
                    <fields>
                        <field>
                            <name>RMDB_LL</name>
                            <description>RX Message Buffer Data Byte (p × 4)</description>
                            <lsb>0</lsb>
                            <msb>7</msb>
                            <access>read-only</access>
                        </field>
                        <field>
                            <name>RMDB_LH</name>
                            <description>RX Message Buffer Data Byte ((p × 4) + 1)</description>
                            <lsb>8</lsb>
                            <msb>15</msb>
                            <access>read-only</access>
                        </field>
                        <field>
                            <name>RMDB_HL</name>
                            <description>RX Message Buffer Data Byte ((p × 4) + 2)</description>
                            <lsb>16</lsb>
                            <msb>23</msb>
                            <access>read-only</access>
                        </field>
                        <field>
                            <name>RMDB_HH</name>
                            <description>RX Message Buffer Data Byte ((p × 4) + 3)</description>
                            <lsb>24</lsb>
                            <msb>31</msb>
                            <access>read-only</access>
                        </field>
                    </fields>
                </register>
                <register>
                    <dim>8</dim>
                    <dimIncrement>0x004C</dimIncrement>
                    <dimIndex>16-23</dimIndex>
                    <name>CFDRMDF%s_2</name>
                    <description>RX Message Buffer Data Field 2 Registers</description>
                    <addressOffset>0x1134</addressOffset>
                    <size>32</size>
                    <access>read-only</access>
                    <resetValue>0x00000000</resetValue>
                    <resetMask>0xffffffff</resetMask>
                    <fields>
                        <field>
                            <name>RMDB_LL</name>
                            <description>RX Message Buffer Data Byte (p × 4)</description>
                            <lsb>0</lsb>
                            <msb>7</msb>
                            <access>read-only</access>
                        </field>
                        <field>
                            <name>RMDB_LH</name>
                            <description>RX Message Buffer Data Byte ((p × 4) + 1)</description>
                            <lsb>8</lsb>
                            <msb>15</msb>
                            <access>read-only</access>
                        </field>
                        <field>
                            <name>RMDB_HL</name>
                            <description>RX Message Buffer Data Byte ((p × 4) + 2)</description>
                            <lsb>16</lsb>
                            <msb>23</msb>
                            <access>read-only</access>
                        </field>
                        <field>
                            <name>RMDB_HH</name>
                            <description>RX Message Buffer Data Byte ((p × 4) + 3)</description>
                            <lsb>24</lsb>
                            <msb>31</msb>
                            <access>read-only</access>
                        </field>
                    </fields>
                </register>
                <register>
                    <dim>8</dim>
                    <dimIncrement>0x004C</dimIncrement>
                    <dimIndex>16-23</dimIndex>
                    <name>CFDRMDF%s_3</name>
                    <description>RX Message Buffer Data Field 3 Registers</description>
                    <addressOffset>0x1138</addressOffset>
                    <size>32</size>
                    <access>read-only</access>
                    <resetValue>0x00000000</resetValue>
                    <resetMask>0xffffffff</resetMask>
                    <fields>
                        <field>
                            <name>RMDB_LL</name>
                            <description>RX Message Buffer Data Byte (p × 4)</description>
                            <lsb>0</lsb>
                            <msb>7</msb>
                            <access>read-only</access>
                        </field>
                        <field>
                            <name>RMDB_LH</name>
                            <description>RX Message Buffer Data Byte ((p × 4) + 1)</description>
                            <lsb>8</lsb>
                            <msb>15</msb>
                            <access>read-only</access>
                        </field>
                        <field>
                            <name>RMDB_HL</name>
                            <description>RX Message Buffer Data Byte ((p × 4) + 2)</description>
                            <lsb>16</lsb>
                            <msb>23</msb>
                            <access>read-only</access>
                        </field>
                        <field>
                            <name>RMDB_HH</name>
                            <description>RX Message Buffer Data Byte ((p × 4) + 3)</description>
                            <lsb>24</lsb>
                            <msb>31</msb>
                            <access>read-only</access>
                        </field>
                    </fields>
                </register>
                <register>
                    <dim>8</dim>
                    <dimIncrement>0x004C</dimIncrement>
                    <dimIndex>16-23</dimIndex>
                    <name>CFDRMDF%s_4</name>
                    <description>RX Message Buffer Data Field 4 Registers</description>
                    <addressOffset>0x113C</addressOffset>
                    <size>32</size>
                    <access>read-only</access>
                    <resetValue>0x00000000</resetValue>
                    <resetMask>0xffffffff</resetMask>
                    <fields>
                        <field>
                            <name>RMDB_LL</name>
                            <description>RX Message Buffer Data Byte (p × 4)</description>
                            <lsb>0</lsb>
                            <msb>7</msb>
                            <access>read-only</access>
                        </field>
                        <field>
                            <name>RMDB_LH</name>
                            <description>RX Message Buffer Data Byte ((p × 4) + 1)</description>
                            <lsb>8</lsb>
                            <msb>15</msb>
                            <access>read-only</access>
                        </field>
                        <field>
                            <name>RMDB_HL</name>
                            <description>RX Message Buffer Data Byte ((p × 4) + 2)</description>
                            <lsb>16</lsb>
                            <msb>23</msb>
                            <access>read-only</access>
                        </field>
                        <field>
                            <name>RMDB_HH</name>
                            <description>RX Message Buffer Data Byte ((p × 4) + 3)</description>
                            <lsb>24</lsb>
                            <msb>31</msb>
                            <access>read-only</access>
                        </field>
                    </fields>
                </register>
                <register>
                    <dim>8</dim>
                    <dimIncrement>0x004C</dimIncrement>
                    <dimIndex>16-23</dimIndex>
                    <name>CFDRMDF%s_5</name>
                    <description>RX Message Buffer Data Field 5 Registers</description>
                    <addressOffset>0x1140</addressOffset>
                    <size>32</size>
                    <access>read-only</access>
                    <resetValue>0x00000000</resetValue>
                    <resetMask>0xffffffff</resetMask>
                    <fields>
                        <field>
                            <name>RMDB_LL</name>
                            <description>RX Message Buffer Data Byte (p × 4)</description>
                            <lsb>0</lsb>
                            <msb>7</msb>
                            <access>read-only</access>
                        </field>
                        <field>
                            <name>RMDB_LH</name>
                            <description>RX Message Buffer Data Byte ((p × 4) + 1)</description>
                            <lsb>8</lsb>
                            <msb>15</msb>
                            <access>read-only</access>
                        </field>
                        <field>
                            <name>RMDB_HL</name>
                            <description>RX Message Buffer Data Byte ((p × 4) + 2)</description>
                            <lsb>16</lsb>
                            <msb>23</msb>
                            <access>read-only</access>
                        </field>
                        <field>
                            <name>RMDB_HH</name>
                            <description>RX Message Buffer Data Byte ((p × 4) + 3)</description>
                            <lsb>24</lsb>
                            <msb>31</msb>
                            <access>read-only</access>
                        </field>
                    </fields>
                </register>
                <register>
                    <dim>8</dim>
                    <dimIncrement>0x004C</dimIncrement>
                    <dimIndex>16-23</dimIndex>
                    <name>CFDRMDF%s_6</name>
                    <description>RX Message Buffer Data Field 6 Registers</description>
                    <addressOffset>0x1144</addressOffset>
                    <size>32</size>
                    <access>read-only</access>
                    <resetValue>0x00000000</resetValue>
                    <resetMask>0xffffffff</resetMask>
                    <fields>
                        <field>
                            <name>RMDB_LL</name>
                            <description>RX Message Buffer Data Byte (p × 4)</description>
                            <lsb>0</lsb>
                            <msb>7</msb>
                            <access>read-only</access>
                        </field>
                        <field>
                            <name>RMDB_LH</name>
                            <description>RX Message Buffer Data Byte ((p × 4) + 1)</description>
                            <lsb>8</lsb>
                            <msb>15</msb>
                            <access>read-only</access>
                        </field>
                        <field>
                            <name>RMDB_HL</name>
                            <description>RX Message Buffer Data Byte ((p × 4) + 2)</description>
                            <lsb>16</lsb>
                            <msb>23</msb>
                            <access>read-only</access>
                        </field>
                        <field>
                            <name>RMDB_HH</name>
                            <description>RX Message Buffer Data Byte ((p × 4) + 3)</description>
                            <lsb>24</lsb>
                            <msb>31</msb>
                            <access>read-only</access>
                        </field>
                    </fields>
                </register>
                <register>
                    <dim>8</dim>
                    <dimIncrement>0x004C</dimIncrement>
                    <dimIndex>16-23</dimIndex>
                    <name>CFDRMDF%s_7</name>
                    <description>RX Message Buffer Data Field 7 Registers</description>
                    <addressOffset>0x1148</addressOffset>
                    <size>32</size>
                    <access>read-only</access>
                    <resetValue>0x00000000</resetValue>
                    <resetMask>0xffffffff</resetMask>
                    <fields>
                        <field>
                            <name>RMDB_LL</name>
                            <description>RX Message Buffer Data Byte (p × 4)</description>
                            <lsb>0</lsb>
                            <msb>7</msb>
                            <access>read-only</access>
                        </field>
                        <field>
                            <name>RMDB_LH</name>
                            <description>RX Message Buffer Data Byte ((p × 4) + 1)</description>
                            <lsb>8</lsb>
                            <msb>15</msb>
                            <access>read-only</access>
                        </field>
                        <field>
                            <name>RMDB_HL</name>
                            <description>RX Message Buffer Data Byte ((p × 4) + 2)</description>
                            <lsb>16</lsb>
                            <msb>23</msb>
                            <access>read-only</access>
                        </field>
                        <field>
                            <name>RMDB_HH</name>
                            <description>RX Message Buffer Data Byte ((p × 4) + 3)</description>
                            <lsb>24</lsb>
                            <msb>31</msb>
                            <access>read-only</access>
                        </field>
                    </fields>
                </register>
                <register>
                    <dim>8</dim>
                    <dimIncrement>0x004C</dimIncrement>
                    <dimIndex>16-23</dimIndex>
                    <name>CFDRMDF%s_8</name>
                    <description>RX Message Buffer Data Field 8 Registers</description>
                    <addressOffset>0x114C</addressOffset>
                    <size>32</size>
                    <access>read-only</access>
                    <resetValue>0x00000000</resetValue>
                    <resetMask>0xffffffff</resetMask>
                    <fields>
                        <field>
                            <name>RMDB_LL</name>
                            <description>RX Message Buffer Data Byte (p × 4)</description>
                            <lsb>0</lsb>
                            <msb>7</msb>
                            <access>read-only</access>
                        </field>
                        <field>
                            <name>RMDB_LH</name>
                            <description>RX Message Buffer Data Byte ((p × 4) + 1)</description>
                            <lsb>8</lsb>
                            <msb>15</msb>
                            <access>read-only</access>
                        </field>
                        <field>
                            <name>RMDB_HL</name>
                            <description>RX Message Buffer Data Byte ((p × 4) + 2)</description>
                            <lsb>16</lsb>
                            <msb>23</msb>
                            <access>read-only</access>
                        </field>
                        <field>
                            <name>RMDB_HH</name>
                            <description>RX Message Buffer Data Byte ((p × 4) + 3)</description>
                            <lsb>24</lsb>
                            <msb>31</msb>
                            <access>read-only</access>
                        </field>
                    </fields>
                </register>
                <register>
                    <dim>8</dim>
                    <dimIncrement>0x004C</dimIncrement>
                    <dimIndex>16-23</dimIndex>
                    <name>CFDRMDF%s_9</name>
                    <description>RX Message Buffer Data Field 9 Registers</description>
                    <addressOffset>0x1150</addressOffset>
                    <size>32</size>
                    <access>read-only</access>
                    <resetValue>0x00000000</resetValue>
                    <resetMask>0xffffffff</resetMask>
                    <fields>
                        <field>
                            <name>RMDB_LL</name>
                            <description>RX Message Buffer Data Byte (p × 4)</description>
                            <lsb>0</lsb>
                            <msb>7</msb>
                            <access>read-only</access>
                        </field>
                        <field>
                            <name>RMDB_LH</name>
                            <description>RX Message Buffer Data Byte ((p × 4) + 1)</description>
                            <lsb>8</lsb>
                            <msb>15</msb>
                            <access>read-only</access>
                        </field>
                        <field>
                            <name>RMDB_HL</name>
                            <description>RX Message Buffer Data Byte ((p × 4) + 2)</description>
                            <lsb>16</lsb>
                            <msb>23</msb>
                            <access>read-only</access>
                        </field>
                        <field>
                            <name>RMDB_HH</name>
                            <description>RX Message Buffer Data Byte ((p × 4) + 3)</description>
                            <lsb>24</lsb>
                            <msb>31</msb>
                            <access>read-only</access>
                        </field>
                    </fields>
                </register>
                <register>
                    <dim>8</dim>
                    <dimIncrement>0x004C</dimIncrement>
                    <dimIndex>16-23</dimIndex>
                    <name>CFDRMDF%s_10</name>
                    <description>RX Message Buffer Data Field 10 Registers</description>
                    <addressOffset>0x1154</addressOffset>
                    <size>32</size>
                    <access>read-only</access>
                    <resetValue>0x00000000</resetValue>
                    <resetMask>0xffffffff</resetMask>
                    <fields>
                        <field>
                            <name>RMDB_LL</name>
                            <description>RX Message Buffer Data Byte (p × 4)</description>
                            <lsb>0</lsb>
                            <msb>7</msb>
                            <access>read-only</access>
                        </field>
                        <field>
                            <name>RMDB_LH</name>
                            <description>RX Message Buffer Data Byte ((p × 4) + 1)</description>
                            <lsb>8</lsb>
                            <msb>15</msb>
                            <access>read-only</access>
                        </field>
                        <field>
                            <name>RMDB_HL</name>
                            <description>RX Message Buffer Data Byte ((p × 4) + 2)</description>
                            <lsb>16</lsb>
                            <msb>23</msb>
                            <access>read-only</access>
                        </field>
                        <field>
                            <name>RMDB_HH</name>
                            <description>RX Message Buffer Data Byte ((p × 4) + 3)</description>
                            <lsb>24</lsb>
                            <msb>31</msb>
                            <access>read-only</access>
                        </field>
                    </fields>
                </register>
                <register>
                    <dim>8</dim>
                    <dimIncrement>0x004C</dimIncrement>
                    <dimIndex>16-23</dimIndex>
                    <name>CFDRMDF%s_11</name>
                    <description>RX Message Buffer Data Field 11 Registers</description>
                    <addressOffset>0x1158</addressOffset>
                    <size>32</size>
                    <access>read-only</access>
                    <resetValue>0x00000000</resetValue>
                    <resetMask>0xffffffff</resetMask>
                    <fields>
                        <field>
                            <name>RMDB_LL</name>
                            <description>RX Message Buffer Data Byte (p × 4)</description>
                            <lsb>0</lsb>
                            <msb>7</msb>
                            <access>read-only</access>
                        </field>
                        <field>
                            <name>RMDB_LH</name>
                            <description>RX Message Buffer Data Byte ((p × 4) + 1)</description>
                            <lsb>8</lsb>
                            <msb>15</msb>
                            <access>read-only</access>
                        </field>
                        <field>
                            <name>RMDB_HL</name>
                            <description>RX Message Buffer Data Byte ((p × 4) + 2)</description>
                            <lsb>16</lsb>
                            <msb>23</msb>
                            <access>read-only</access>
                        </field>
                        <field>
                            <name>RMDB_HH</name>
                            <description>RX Message Buffer Data Byte ((p × 4) + 3)</description>
                            <lsb>24</lsb>
                            <msb>31</msb>
                            <access>read-only</access>
                        </field>
                    </fields>
                </register>
                <register>
                    <dim>8</dim>
                    <dimIncrement>0x004C</dimIncrement>
                    <dimIndex>16-23</dimIndex>
                    <name>CFDRMDF%s_12</name>
                    <description>RX Message Buffer Data Field 12 Registers</description>
                    <addressOffset>0x115C</addressOffset>
                    <size>32</size>
                    <access>read-only</access>
                    <resetValue>0x00000000</resetValue>
                    <resetMask>0xffffffff</resetMask>
                    <fields>
                        <field>
                            <name>RMDB_LL</name>
                            <description>RX Message Buffer Data Byte (p × 4)</description>
                            <lsb>0</lsb>
                            <msb>7</msb>
                            <access>read-only</access>
                        </field>
                        <field>
                            <name>RMDB_LH</name>
                            <description>RX Message Buffer Data Byte ((p × 4) + 1)</description>
                            <lsb>8</lsb>
                            <msb>15</msb>
                            <access>read-only</access>
                        </field>
                        <field>
                            <name>RMDB_HL</name>
                            <description>RX Message Buffer Data Byte ((p × 4) + 2)</description>
                            <lsb>16</lsb>
                            <msb>23</msb>
                            <access>read-only</access>
                        </field>
                        <field>
                            <name>RMDB_HH</name>
                            <description>RX Message Buffer Data Byte ((p × 4) + 3)</description>
                            <lsb>24</lsb>
                            <msb>31</msb>
                            <access>read-only</access>
                        </field>
                    </fields>
                </register>
                <register>
                    <dim>8</dim>
                    <dimIncrement>0x004C</dimIncrement>
                    <dimIndex>16-23</dimIndex>
                    <name>CFDRMDF%s_13</name>
                    <description>RX Message Buffer Data Field 13 Registers</description>
                    <addressOffset>0x1160</addressOffset>
                    <size>32</size>
                    <access>read-only</access>
                    <resetValue>0x00000000</resetValue>
                    <resetMask>0xffffffff</resetMask>
                    <fields>
                        <field>
                            <name>RMDB_LL</name>
                            <description>RX Message Buffer Data Byte (p × 4)</description>
                            <lsb>0</lsb>
                            <msb>7</msb>
                            <access>read-only</access>
                        </field>
                        <field>
                            <name>RMDB_LH</name>
                            <description>RX Message Buffer Data Byte ((p × 4) + 1)</description>
                            <lsb>8</lsb>
                            <msb>15</msb>
                            <access>read-only</access>
                        </field>
                        <field>
                            <name>RMDB_HL</name>
                            <description>RX Message Buffer Data Byte ((p × 4) + 2)</description>
                            <lsb>16</lsb>
                            <msb>23</msb>
                            <access>read-only</access>
                        </field>
                        <field>
                            <name>RMDB_HH</name>
                            <description>RX Message Buffer Data Byte ((p × 4) + 3)</description>
                            <lsb>24</lsb>
                            <msb>31</msb>
                            <access>read-only</access>
                        </field>
                    </fields>
                </register>
                <register>
                    <dim>8</dim>
                    <dimIncrement>0x004C</dimIncrement>
                    <dimIndex>16-23</dimIndex>
                    <name>CFDRMDF%s_14</name>
                    <description>RX Message Buffer Data Field 14 Registers</description>
                    <addressOffset>0x1164</addressOffset>
                    <size>32</size>
                    <access>read-only</access>
                    <resetValue>0x00000000</resetValue>
                    <resetMask>0xffffffff</resetMask>
                    <fields>
                        <field>
                            <name>RMDB_LL</name>
                            <description>RX Message Buffer Data Byte (p × 4)</description>
                            <lsb>0</lsb>
                            <msb>7</msb>
                            <access>read-only</access>
                        </field>
                        <field>
                            <name>RMDB_LH</name>
                            <description>RX Message Buffer Data Byte ((p × 4) + 1)</description>
                            <lsb>8</lsb>
                            <msb>15</msb>
                            <access>read-only</access>
                        </field>
                        <field>
                            <name>RMDB_HL</name>
                            <description>RX Message Buffer Data Byte ((p × 4) + 2)</description>
                            <lsb>16</lsb>
                            <msb>23</msb>
                            <access>read-only</access>
                        </field>
                        <field>
                            <name>RMDB_HH</name>
                            <description>RX Message Buffer Data Byte ((p × 4) + 3)</description>
                            <lsb>24</lsb>
                            <msb>31</msb>
                            <access>read-only</access>
                        </field>
                    </fields>
                </register>
                <register>
                    <dim>8</dim>
                    <dimIncrement>0x004C</dimIncrement>
                    <dimIndex>16-23</dimIndex>
                    <name>CFDRMDF%s_15</name>
                    <description>RX Message Buffer Data Field 15 Registers</description>
                    <addressOffset>0x1168</addressOffset>
                    <size>32</size>
                    <access>read-only</access>
                    <resetValue>0x00000000</resetValue>
                    <resetMask>0xffffffff</resetMask>
                    <fields>
                        <field>
                            <name>RMDB_LL</name>
                            <description>RX Message Buffer Data Byte (p × 4)</description>
                            <lsb>0</lsb>
                            <msb>7</msb>
                            <access>read-only</access>
                        </field>
                        <field>
                            <name>RMDB_LH</name>
                            <description>RX Message Buffer Data Byte ((p × 4) + 1)</description>
                            <lsb>8</lsb>
                            <msb>15</msb>
                            <access>read-only</access>
                        </field>
                        <field>
                            <name>RMDB_HL</name>
                            <description>RX Message Buffer Data Byte ((p × 4) + 2)</description>
                            <lsb>16</lsb>
                            <msb>23</msb>
                            <access>read-only</access>
                        </field>
                        <field>
                            <name>RMDB_HH</name>
                            <description>RX Message Buffer Data Byte ((p × 4) + 3)</description>
                            <lsb>24</lsb>
                            <msb>31</msb>
                            <access>read-only</access>
                        </field>
                    </fields>
                </register>
                <register>
                    <dim>8</dim>
                    <dimIncrement>0x004C</dimIncrement>
                    <dimIndex>24-31</dimIndex>
                    <name>CFDRMPTR%s</name>
                    <description>RX Message Buffer Pointer Registers</description>
                    <addressOffset>0x01524</addressOffset>
                    <size>32</size>
                    <access>read-only</access>
                    <resetValue>0x00000000</resetValue>
                    <resetMask>0xffffffff</resetMask>
                    <fields>
                        <field>
                            <name>RMTS</name>
                            <description>RX Message Buffer Timestamp Field</description>
                            <lsb>0</lsb>
                            <msb>15</msb>
                            <access>read-only</access>
                        </field>
                        <field>
                            <name>RMDLC</name>
                            <description>RX Message Buffer DLC Field</description>
                            <lsb>28</lsb>
                            <msb>31</msb>
                            <access>read-only</access>
                        </field>
                    </fields>
                </register>
                <register>
                    <dim>8</dim>
                    <dimIncrement>0x004C</dimIncrement>
                    <dimIndex>24-31</dimIndex>
                    <name>CFDRMFDSTS%s</name>
                    <description>RX Message Buffer CANFD Status Registers</description>
                    <addressOffset>0x01528</addressOffset>
                    <size>32</size>
                    <access>read-only</access>
                    <resetValue>0x00000000</resetValue>
                    <resetMask>0xffffffff</resetMask>
                    <fields>
                        <field>
                            <name>RMESI</name>
                            <description>Error State Indicator bit</description>
                            <lsb>0</lsb>
                            <msb>0</msb>
                            <access>read-only</access>
                            <enumeratedValues>
                                <enumeratedValue>
                                    <name>0</name>
                                    <description>CANFD frame received from error active node</description>
                                    <value>#0</value>
                                </enumeratedValue>
                                <enumeratedValue>
                                    <name>1</name>
                                    <description>CANFD frame received from error passive node</description>
                                    <value>#1</value>
                                </enumeratedValue>
                            </enumeratedValues>
                        </field>
                        <field>
                            <name>RMBRS</name>
                            <description>Bit Rate Switch bit</description>
                            <lsb>1</lsb>
                            <msb>1</msb>
                            <access>read-only</access>
                            <enumeratedValues>
                                <enumeratedValue>
                                    <name>0</name>
                                    <description>CANFD frame received with no bit rate switch</description>
                                    <value>#0</value>
                                </enumeratedValue>
                                <enumeratedValue>
                                    <name>1</name>
                                    <description>CANFD frame received with bit rate switch</description>
                                    <value>#1</value>
                                </enumeratedValue>
                            </enumeratedValues>
                        </field>
                        <field>
                            <name>RMFDF</name>
                            <description>CAN FD Format bit</description>
                            <lsb>2</lsb>
                            <msb>2</msb>
                            <access>read-only</access>
                            <enumeratedValues>
                                <enumeratedValue>
                                    <name>0</name>
                                    <description>Non CANFD frame received</description>
                                    <value>#0</value>
                                </enumeratedValue>
                                <enumeratedValue>
                                    <name>1</name>
                                    <description>CANFD frame received</description>
                                    <value>#1</value>
                                </enumeratedValue>
                            </enumeratedValues>
                        </field>
                        <field>
                            <name>RMIFL</name>
                            <description>RX Message Buffer Information Label Field</description>
                            <lsb>8</lsb>
                            <msb>9</msb>
                            <access>read-only</access>
                        </field>
                        <field>
                            <name>RMPTR</name>
                            <description>RX Message Buffer Pointer Field</description>
                            <lsb>16</lsb>
                            <msb>31</msb>
                            <access>read-only</access>
                        </field>
                    </fields>
                </register>
                <register>
                    <dim>8</dim>
                    <dimIncrement>0x004C</dimIncrement>
                    <dimIndex>24-31</dimIndex>
                    <name>CFDRMDF%s_0</name>
                    <description>RX Message Buffer Data Field 0 Registers</description>
                    <addressOffset>0x152C</addressOffset>
                    <size>32</size>
                    <access>read-only</access>
                    <resetValue>0x00000000</resetValue>
                    <resetMask>0xffffffff</resetMask>
                    <fields>
                        <field>
                            <name>RMDB_LL</name>
                            <description>RX Message Buffer Data Byte (p × 4)</description>
                            <lsb>0</lsb>
                            <msb>7</msb>
                            <access>read-only</access>
                        </field>
                        <field>
                            <name>RMDB_LH</name>
                            <description>RX Message Buffer Data Byte ((p × 4) + 1)</description>
                            <lsb>8</lsb>
                            <msb>15</msb>
                            <access>read-only</access>
                        </field>
                        <field>
                            <name>RMDB_HL</name>
                            <description>RX Message Buffer Data Byte ((p × 4) + 2)</description>
                            <lsb>16</lsb>
                            <msb>23</msb>
                            <access>read-only</access>
                        </field>
                        <field>
                            <name>RMDB_HH</name>
                            <description>RX Message Buffer Data Byte ((p × 4) + 3)</description>
                            <lsb>24</lsb>
                            <msb>31</msb>
                            <access>read-only</access>
                        </field>
                    </fields>
                </register>
                <register>
                    <dim>8</dim>
                    <dimIncrement>0x004C</dimIncrement>
                    <dimIndex>24-31</dimIndex>
                    <name>CFDRMDF%s_1</name>
                    <description>RX Message Buffer Data Field 1 Registers</description>
                    <addressOffset>0x1530</addressOffset>
                    <size>32</size>
                    <access>read-only</access>
                    <resetValue>0x00000000</resetValue>
                    <resetMask>0xffffffff</resetMask>
                    <fields>
                        <field>
                            <name>RMDB_LL</name>
                            <description>RX Message Buffer Data Byte (p × 4)</description>
                            <lsb>0</lsb>
                            <msb>7</msb>
                            <access>read-only</access>
                        </field>
                        <field>
                            <name>RMDB_LH</name>
                            <description>RX Message Buffer Data Byte ((p × 4) + 1)</description>
                            <lsb>8</lsb>
                            <msb>15</msb>
                            <access>read-only</access>
                        </field>
                        <field>
                            <name>RMDB_HL</name>
                            <description>RX Message Buffer Data Byte ((p × 4) + 2)</description>
                            <lsb>16</lsb>
                            <msb>23</msb>
                            <access>read-only</access>
                        </field>
                        <field>
                            <name>RMDB_HH</name>
                            <description>RX Message Buffer Data Byte ((p × 4) + 3)</description>
                            <lsb>24</lsb>
                            <msb>31</msb>
                            <access>read-only</access>
                        </field>
                    </fields>
                </register>
                <register>
                    <dim>8</dim>
                    <dimIncrement>0x004C</dimIncrement>
                    <dimIndex>24-31</dimIndex>
                    <name>CFDRMDF%s_2</name>
                    <description>RX Message Buffer Data Field 2 Registers</description>
                    <addressOffset>0x1534</addressOffset>
                    <size>32</size>
                    <access>read-only</access>
                    <resetValue>0x00000000</resetValue>
                    <resetMask>0xffffffff</resetMask>
                    <fields>
                        <field>
                            <name>RMDB_LL</name>
                            <description>RX Message Buffer Data Byte (p × 4)</description>
                            <lsb>0</lsb>
                            <msb>7</msb>
                            <access>read-only</access>
                        </field>
                        <field>
                            <name>RMDB_LH</name>
                            <description>RX Message Buffer Data Byte ((p × 4) + 1)</description>
                            <lsb>8</lsb>
                            <msb>15</msb>
                            <access>read-only</access>
                        </field>
                        <field>
                            <name>RMDB_HL</name>
                            <description>RX Message Buffer Data Byte ((p × 4) + 2)</description>
                            <lsb>16</lsb>
                            <msb>23</msb>
                            <access>read-only</access>
                        </field>
                        <field>
                            <name>RMDB_HH</name>
                            <description>RX Message Buffer Data Byte ((p × 4) + 3)</description>
                            <lsb>24</lsb>
                            <msb>31</msb>
                            <access>read-only</access>
                        </field>
                    </fields>
                </register>
                <register>
                    <dim>8</dim>
                    <dimIncrement>0x004C</dimIncrement>
                    <dimIndex>24-31</dimIndex>
                    <name>CFDRMDF%s_3</name>
                    <description>RX Message Buffer Data Field 3 Registers</description>
                    <addressOffset>0x1538</addressOffset>
                    <size>32</size>
                    <access>read-only</access>
                    <resetValue>0x00000000</resetValue>
                    <resetMask>0xffffffff</resetMask>
                    <fields>
                        <field>
                            <name>RMDB_LL</name>
                            <description>RX Message Buffer Data Byte (p × 4)</description>
                            <lsb>0</lsb>
                            <msb>7</msb>
                            <access>read-only</access>
                        </field>
                        <field>
                            <name>RMDB_LH</name>
                            <description>RX Message Buffer Data Byte ((p × 4) + 1)</description>
                            <lsb>8</lsb>
                            <msb>15</msb>
                            <access>read-only</access>
                        </field>
                        <field>
                            <name>RMDB_HL</name>
                            <description>RX Message Buffer Data Byte ((p × 4) + 2)</description>
                            <lsb>16</lsb>
                            <msb>23</msb>
                            <access>read-only</access>
                        </field>
                        <field>
                            <name>RMDB_HH</name>
                            <description>RX Message Buffer Data Byte ((p × 4) + 3)</description>
                            <lsb>24</lsb>
                            <msb>31</msb>
                            <access>read-only</access>
                        </field>
                    </fields>
                </register>
                <register>
                    <dim>8</dim>
                    <dimIncrement>0x004C</dimIncrement>
                    <dimIndex>24-31</dimIndex>
                    <name>CFDRMDF%s_4</name>
                    <description>RX Message Buffer Data Field 4 Registers</description>
                    <addressOffset>0x153C</addressOffset>
                    <size>32</size>
                    <access>read-only</access>
                    <resetValue>0x00000000</resetValue>
                    <resetMask>0xffffffff</resetMask>
                    <fields>
                        <field>
                            <name>RMDB_LL</name>
                            <description>RX Message Buffer Data Byte (p × 4)</description>
                            <lsb>0</lsb>
                            <msb>7</msb>
                            <access>read-only</access>
                        </field>
                        <field>
                            <name>RMDB_LH</name>
                            <description>RX Message Buffer Data Byte ((p × 4) + 1)</description>
                            <lsb>8</lsb>
                            <msb>15</msb>
                            <access>read-only</access>
                        </field>
                        <field>
                            <name>RMDB_HL</name>
                            <description>RX Message Buffer Data Byte ((p × 4) + 2)</description>
                            <lsb>16</lsb>
                            <msb>23</msb>
                            <access>read-only</access>
                        </field>
                        <field>
                            <name>RMDB_HH</name>
                            <description>RX Message Buffer Data Byte ((p × 4) + 3)</description>
                            <lsb>24</lsb>
                            <msb>31</msb>
                            <access>read-only</access>
                        </field>
                    </fields>
                </register>
                <register>
                    <dim>8</dim>
                    <dimIncrement>0x004C</dimIncrement>
                    <dimIndex>24-31</dimIndex>
                    <name>CFDRMDF%s_5</name>
                    <description>RX Message Buffer Data Field 5 Registers</description>
                    <addressOffset>0x1540</addressOffset>
                    <size>32</size>
                    <access>read-only</access>
                    <resetValue>0x00000000</resetValue>
                    <resetMask>0xffffffff</resetMask>
                    <fields>
                        <field>
                            <name>RMDB_LL</name>
                            <description>RX Message Buffer Data Byte (p × 4)</description>
                            <lsb>0</lsb>
                            <msb>7</msb>
                            <access>read-only</access>
                        </field>
                        <field>
                            <name>RMDB_LH</name>
                            <description>RX Message Buffer Data Byte ((p × 4) + 1)</description>
                            <lsb>8</lsb>
                            <msb>15</msb>
                            <access>read-only</access>
                        </field>
                        <field>
                            <name>RMDB_HL</name>
                            <description>RX Message Buffer Data Byte ((p × 4) + 2)</description>
                            <lsb>16</lsb>
                            <msb>23</msb>
                            <access>read-only</access>
                        </field>
                        <field>
                            <name>RMDB_HH</name>
                            <description>RX Message Buffer Data Byte ((p × 4) + 3)</description>
                            <lsb>24</lsb>
                            <msb>31</msb>
                            <access>read-only</access>
                        </field>
                    </fields>
                </register>
                <register>
                    <dim>8</dim>
                    <dimIncrement>0x004C</dimIncrement>
                    <dimIndex>24-31</dimIndex>
                    <name>CFDRMDF%s_6</name>
                    <description>RX Message Buffer Data Field 6 Registers</description>
                    <addressOffset>0x1544</addressOffset>
                    <size>32</size>
                    <access>read-only</access>
                    <resetValue>0x00000000</resetValue>
                    <resetMask>0xffffffff</resetMask>
                    <fields>
                        <field>
                            <name>RMDB_LL</name>
                            <description>RX Message Buffer Data Byte (p × 4)</description>
                            <lsb>0</lsb>
                            <msb>7</msb>
                            <access>read-only</access>
                        </field>
                        <field>
                            <name>RMDB_LH</name>
                            <description>RX Message Buffer Data Byte ((p × 4) + 1)</description>
                            <lsb>8</lsb>
                            <msb>15</msb>
                            <access>read-only</access>
                        </field>
                        <field>
                            <name>RMDB_HL</name>
                            <description>RX Message Buffer Data Byte ((p × 4) + 2)</description>
                            <lsb>16</lsb>
                            <msb>23</msb>
                            <access>read-only</access>
                        </field>
                        <field>
                            <name>RMDB_HH</name>
                            <description>RX Message Buffer Data Byte ((p × 4) + 3)</description>
                            <lsb>24</lsb>
                            <msb>31</msb>
                            <access>read-only</access>
                        </field>
                    </fields>
                </register>
                <register>
                    <dim>8</dim>
                    <dimIncrement>0x004C</dimIncrement>
                    <dimIndex>24-31</dimIndex>
                    <name>CFDRMDF%s_7</name>
                    <description>RX Message Buffer Data Field 7 Registers</description>
                    <addressOffset>0x1548</addressOffset>
                    <size>32</size>
                    <access>read-only</access>
                    <resetValue>0x00000000</resetValue>
                    <resetMask>0xffffffff</resetMask>
                    <fields>
                        <field>
                            <name>RMDB_LL</name>
                            <description>RX Message Buffer Data Byte (p × 4)</description>
                            <lsb>0</lsb>
                            <msb>7</msb>
                            <access>read-only</access>
                        </field>
                        <field>
                            <name>RMDB_LH</name>
                            <description>RX Message Buffer Data Byte ((p × 4) + 1)</description>
                            <lsb>8</lsb>
                            <msb>15</msb>
                            <access>read-only</access>
                        </field>
                        <field>
                            <name>RMDB_HL</name>
                            <description>RX Message Buffer Data Byte ((p × 4) + 2)</description>
                            <lsb>16</lsb>
                            <msb>23</msb>
                            <access>read-only</access>
                        </field>
                        <field>
                            <name>RMDB_HH</name>
                            <description>RX Message Buffer Data Byte ((p × 4) + 3)</description>
                            <lsb>24</lsb>
                            <msb>31</msb>
                            <access>read-only</access>
                        </field>
                    </fields>
                </register>
                <register>
                    <dim>8</dim>
                    <dimIncrement>0x004C</dimIncrement>
                    <dimIndex>24-31</dimIndex>
                    <name>CFDRMDF%s_8</name>
                    <description>RX Message Buffer Data Field 8 Registers</description>
                    <addressOffset>0x154C</addressOffset>
                    <size>32</size>
                    <access>read-only</access>
                    <resetValue>0x00000000</resetValue>
                    <resetMask>0xffffffff</resetMask>
                    <fields>
                        <field>
                            <name>RMDB_LL</name>
                            <description>RX Message Buffer Data Byte (p × 4)</description>
                            <lsb>0</lsb>
                            <msb>7</msb>
                            <access>read-only</access>
                        </field>
                        <field>
                            <name>RMDB_LH</name>
                            <description>RX Message Buffer Data Byte ((p × 4) + 1)</description>
                            <lsb>8</lsb>
                            <msb>15</msb>
                            <access>read-only</access>
                        </field>
                        <field>
                            <name>RMDB_HL</name>
                            <description>RX Message Buffer Data Byte ((p × 4) + 2)</description>
                            <lsb>16</lsb>
                            <msb>23</msb>
                            <access>read-only</access>
                        </field>
                        <field>
                            <name>RMDB_HH</name>
                            <description>RX Message Buffer Data Byte ((p × 4) + 3)</description>
                            <lsb>24</lsb>
                            <msb>31</msb>
                            <access>read-only</access>
                        </field>
                    </fields>
                </register>
                <register>
                    <dim>8</dim>
                    <dimIncrement>0x004C</dimIncrement>
                    <dimIndex>24-31</dimIndex>
                    <name>CFDRMDF%s_9</name>
                    <description>RX Message Buffer Data Field 9 Registers</description>
                    <addressOffset>0x1550</addressOffset>
                    <size>32</size>
                    <access>read-only</access>
                    <resetValue>0x00000000</resetValue>
                    <resetMask>0xffffffff</resetMask>
                    <fields>
                        <field>
                            <name>RMDB_LL</name>
                            <description>RX Message Buffer Data Byte (p × 4)</description>
                            <lsb>0</lsb>
                            <msb>7</msb>
                            <access>read-only</access>
                        </field>
                        <field>
                            <name>RMDB_LH</name>
                            <description>RX Message Buffer Data Byte ((p × 4) + 1)</description>
                            <lsb>8</lsb>
                            <msb>15</msb>
                            <access>read-only</access>
                        </field>
                        <field>
                            <name>RMDB_HL</name>
                            <description>RX Message Buffer Data Byte ((p × 4) + 2)</description>
                            <lsb>16</lsb>
                            <msb>23</msb>
                            <access>read-only</access>
                        </field>
                        <field>
                            <name>RMDB_HH</name>
                            <description>RX Message Buffer Data Byte ((p × 4) + 3)</description>
                            <lsb>24</lsb>
                            <msb>31</msb>
                            <access>read-only</access>
                        </field>
                    </fields>
                </register>
                <register>
                    <dim>8</dim>
                    <dimIncrement>0x004C</dimIncrement>
                    <dimIndex>24-31</dimIndex>
                    <name>CFDRMDF%s_10</name>
                    <description>RX Message Buffer Data Field 10 Registers</description>
                    <addressOffset>0x1554</addressOffset>
                    <size>32</size>
                    <access>read-only</access>
                    <resetValue>0x00000000</resetValue>
                    <resetMask>0xffffffff</resetMask>
                    <fields>
                        <field>
                            <name>RMDB_LL</name>
                            <description>RX Message Buffer Data Byte (p × 4)</description>
                            <lsb>0</lsb>
                            <msb>7</msb>
                            <access>read-only</access>
                        </field>
                        <field>
                            <name>RMDB_LH</name>
                            <description>RX Message Buffer Data Byte ((p × 4) + 1)</description>
                            <lsb>8</lsb>
                            <msb>15</msb>
                            <access>read-only</access>
                        </field>
                        <field>
                            <name>RMDB_HL</name>
                            <description>RX Message Buffer Data Byte ((p × 4) + 2)</description>
                            <lsb>16</lsb>
                            <msb>23</msb>
                            <access>read-only</access>
                        </field>
                        <field>
                            <name>RMDB_HH</name>
                            <description>RX Message Buffer Data Byte ((p × 4) + 3)</description>
                            <lsb>24</lsb>
                            <msb>31</msb>
                            <access>read-only</access>
                        </field>
                    </fields>
                </register>
                <register>
                    <dim>8</dim>
                    <dimIncrement>0x004C</dimIncrement>
                    <dimIndex>24-31</dimIndex>
                    <name>CFDRMDF%s_11</name>
                    <description>RX Message Buffer Data Field 11 Registers</description>
                    <addressOffset>0x1558</addressOffset>
                    <size>32</size>
                    <access>read-only</access>
                    <resetValue>0x00000000</resetValue>
                    <resetMask>0xffffffff</resetMask>
                    <fields>
                        <field>
                            <name>RMDB_LL</name>
                            <description>RX Message Buffer Data Byte (p × 4)</description>
                            <lsb>0</lsb>
                            <msb>7</msb>
                            <access>read-only</access>
                        </field>
                        <field>
                            <name>RMDB_LH</name>
                            <description>RX Message Buffer Data Byte ((p × 4) + 1)</description>
                            <lsb>8</lsb>
                            <msb>15</msb>
                            <access>read-only</access>
                        </field>
                        <field>
                            <name>RMDB_HL</name>
                            <description>RX Message Buffer Data Byte ((p × 4) + 2)</description>
                            <lsb>16</lsb>
                            <msb>23</msb>
                            <access>read-only</access>
                        </field>
                        <field>
                            <name>RMDB_HH</name>
                            <description>RX Message Buffer Data Byte ((p × 4) + 3)</description>
                            <lsb>24</lsb>
                            <msb>31</msb>
                            <access>read-only</access>
                        </field>
                    </fields>
                </register>
                <register>
                    <dim>8</dim>
                    <dimIncrement>0x004C</dimIncrement>
                    <dimIndex>24-31</dimIndex>
                    <name>CFDRMDF%s_12</name>
                    <description>RX Message Buffer Data Field 12 Registers</description>
                    <addressOffset>0x155C</addressOffset>
                    <size>32</size>
                    <access>read-only</access>
                    <resetValue>0x00000000</resetValue>
                    <resetMask>0xffffffff</resetMask>
                    <fields>
                        <field>
                            <name>RMDB_LL</name>
                            <description>RX Message Buffer Data Byte (p × 4)</description>
                            <lsb>0</lsb>
                            <msb>7</msb>
                            <access>read-only</access>
                        </field>
                        <field>
                            <name>RMDB_LH</name>
                            <description>RX Message Buffer Data Byte ((p × 4) + 1)</description>
                            <lsb>8</lsb>
                            <msb>15</msb>
                            <access>read-only</access>
                        </field>
                        <field>
                            <name>RMDB_HL</name>
                            <description>RX Message Buffer Data Byte ((p × 4) + 2)</description>
                            <lsb>16</lsb>
                            <msb>23</msb>
                            <access>read-only</access>
                        </field>
                        <field>
                            <name>RMDB_HH</name>
                            <description>RX Message Buffer Data Byte ((p × 4) + 3)</description>
                            <lsb>24</lsb>
                            <msb>31</msb>
                            <access>read-only</access>
                        </field>
                    </fields>
                </register>
                <register>
                    <dim>8</dim>
                    <dimIncrement>0x004C</dimIncrement>
                    <dimIndex>24-31</dimIndex>
                    <name>CFDRMDF%s_13</name>
                    <description>RX Message Buffer Data Field 13 Registers</description>
                    <addressOffset>0x1560</addressOffset>
                    <size>32</size>
                    <access>read-only</access>
                    <resetValue>0x00000000</resetValue>
                    <resetMask>0xffffffff</resetMask>
                    <fields>
                        <field>
                            <name>RMDB_LL</name>
                            <description>RX Message Buffer Data Byte (p × 4)</description>
                            <lsb>0</lsb>
                            <msb>7</msb>
                            <access>read-only</access>
                        </field>
                        <field>
                            <name>RMDB_LH</name>
                            <description>RX Message Buffer Data Byte ((p × 4) + 1)</description>
                            <lsb>8</lsb>
                            <msb>15</msb>
                            <access>read-only</access>
                        </field>
                        <field>
                            <name>RMDB_HL</name>
                            <description>RX Message Buffer Data Byte ((p × 4) + 2)</description>
                            <lsb>16</lsb>
                            <msb>23</msb>
                            <access>read-only</access>
                        </field>
                        <field>
                            <name>RMDB_HH</name>
                            <description>RX Message Buffer Data Byte ((p × 4) + 3)</description>
                            <lsb>24</lsb>
                            <msb>31</msb>
                            <access>read-only</access>
                        </field>
                    </fields>
                </register>
                <register>
                    <dim>8</dim>
                    <dimIncrement>0x004C</dimIncrement>
                    <dimIndex>24-31</dimIndex>
                    <name>CFDRMDF%s_14</name>
                    <description>RX Message Buffer Data Field 14 Registers</description>
                    <addressOffset>0x1564</addressOffset>
                    <size>32</size>
                    <access>read-only</access>
                    <resetValue>0x00000000</resetValue>
                    <resetMask>0xffffffff</resetMask>
                    <fields>
                        <field>
                            <name>RMDB_LL</name>
                            <description>RX Message Buffer Data Byte (p × 4)</description>
                            <lsb>0</lsb>
                            <msb>7</msb>
                            <access>read-only</access>
                        </field>
                        <field>
                            <name>RMDB_LH</name>
                            <description>RX Message Buffer Data Byte ((p × 4) + 1)</description>
                            <lsb>8</lsb>
                            <msb>15</msb>
                            <access>read-only</access>
                        </field>
                        <field>
                            <name>RMDB_HL</name>
                            <description>RX Message Buffer Data Byte ((p × 4) + 2)</description>
                            <lsb>16</lsb>
                            <msb>23</msb>
                            <access>read-only</access>
                        </field>
                        <field>
                            <name>RMDB_HH</name>
                            <description>RX Message Buffer Data Byte ((p × 4) + 3)</description>
                            <lsb>24</lsb>
                            <msb>31</msb>
                            <access>read-only</access>
                        </field>
                    </fields>
                </register>
                <register>
                    <dim>8</dim>
                    <dimIncrement>0x004C</dimIncrement>
                    <dimIndex>24-31</dimIndex>
                    <name>CFDRMDF%s_15</name>
                    <description>RX Message Buffer Data Field 15 Registers</description>
                    <addressOffset>0x1568</addressOffset>
                    <size>32</size>
                    <access>read-only</access>
                    <resetValue>0x00000000</resetValue>
                    <resetMask>0xffffffff</resetMask>
                    <fields>
                        <field>
                            <name>RMDB_LL</name>
                            <description>RX Message Buffer Data Byte (p × 4)</description>
                            <lsb>0</lsb>
                            <msb>7</msb>
                            <access>read-only</access>
                        </field>
                        <field>
                            <name>RMDB_LH</name>
                            <description>RX Message Buffer Data Byte ((p × 4) + 1)</description>
                            <lsb>8</lsb>
                            <msb>15</msb>
                            <access>read-only</access>
                        </field>
                        <field>
                            <name>RMDB_HL</name>
                            <description>RX Message Buffer Data Byte ((p × 4) + 2)</description>
                            <lsb>16</lsb>
                            <msb>23</msb>
                            <access>read-only</access>
                        </field>
                        <field>
                            <name>RMDB_HH</name>
                            <description>RX Message Buffer Data Byte ((p × 4) + 3)</description>
                            <lsb>24</lsb>
                            <msb>31</msb>
                            <access>read-only</access>
                        </field>
                    </fields>
                </register>
            </registers>
        </peripheral>
        <peripheral derivedFrom="CANFD0">
            <name>CANFD1</name>
            <description>CANFD Module 1</description>
            <baseAddress>0x40382000</baseAddress>
        </peripheral>
        <peripheral>
            <name>PORT0</name>
            <description>Pmn Pin Function Port 0 Control Registers Pmn Pin Function Control Register</description>
            <baseAddress>0x40400000</baseAddress>
            <addressBlock>
                <offset>0x00</offset>
                <size>8</size>
                <usage>registers</usage>
            </addressBlock>
            <addressBlock>
                <offset>0x08</offset>
                <size>4</size>
                <usage>registers</usage>
            </addressBlock>
            <registers>
                <register>
                    <name>PCNTR1</name>
                    <description>Port Control Register 1</description>
                    <addressOffset>0x000</addressOffset>
                    <size>32</size>
                    <access>read-write</access>
                    <resetValue>0x00000000</resetValue>
                    <resetMask>0xffffffff</resetMask>
                    <fields>
                        <field>
                            <name>PDR00</name>
                            <description>Pmn Direction</description>
                            <lsb>0</lsb>
                            <msb>0</msb>
                            <access>read-write</access>
                            <enumeratedValues>
                                <enumeratedValue>
                                    <name>0</name>
                                    <description>Input (functions as an input pin)</description>
                                    <value>#0</value>
                                </enumeratedValue>
                                <enumeratedValue>
                                    <name>1</name>
                                    <description>Output (functions as an output pin)</description>
                                    <value>#1</value>
                                </enumeratedValue>
                            </enumeratedValues>
                        </field>
                        <field>
                            <name>PDR01</name>
                            <description>Pmn Direction</description>
                            <lsb>1</lsb>
                            <msb>1</msb>
                            <access>read-write</access>
                            <enumeratedValues>
                                <enumeratedValue>
                                    <name>0</name>
                                    <description>Input (functions as an input pin)</description>
                                    <value>#0</value>
                                </enumeratedValue>
                                <enumeratedValue>
                                    <name>1</name>
                                    <description>Output (functions as an output pin)</description>
                                    <value>#1</value>
                                </enumeratedValue>
                            </enumeratedValues>
                        </field>
                        <field>
                            <name>PDR02</name>
                            <description>Pmn Direction</description>
                            <lsb>2</lsb>
                            <msb>2</msb>
                            <access>read-write</access>
                            <enumeratedValues>
                                <enumeratedValue>
                                    <name>0</name>
                                    <description>Input (functions as an input pin)</description>
                                    <value>#0</value>
                                </enumeratedValue>
                                <enumeratedValue>
                                    <name>1</name>
                                    <description>Output (functions as an output pin)</description>
                                    <value>#1</value>
                                </enumeratedValue>
                            </enumeratedValues>
                        </field>
                        <field>
                            <name>PDR03</name>
                            <description>Pmn Direction</description>
                            <lsb>3</lsb>
                            <msb>3</msb>
                            <access>read-write</access>
                            <enumeratedValues>
                                <enumeratedValue>
                                    <name>0</name>
                                    <description>Input (functions as an input pin)</description>
                                    <value>#0</value>
                                </enumeratedValue>
                                <enumeratedValue>
                                    <name>1</name>
                                    <description>Output (functions as an output pin)</description>
                                    <value>#1</value>
                                </enumeratedValue>
                            </enumeratedValues>
                        </field>
                        <field>
                            <name>PDR04</name>
                            <description>Pmn Direction</description>
                            <lsb>4</lsb>
                            <msb>4</msb>
                            <access>read-write</access>
                            <enumeratedValues>
                                <enumeratedValue>
                                    <name>0</name>
                                    <description>Input (functions as an input pin)</description>
                                    <value>#0</value>
                                </enumeratedValue>
                                <enumeratedValue>
                                    <name>1</name>
                                    <description>Output (functions as an output pin)</description>
                                    <value>#1</value>
                                </enumeratedValue>
                            </enumeratedValues>
                        </field>
                        <field>
                            <name>PDR05</name>
                            <description>Pmn Direction</description>
                            <lsb>5</lsb>
                            <msb>5</msb>
                            <access>read-write</access>
                            <enumeratedValues>
                                <enumeratedValue>
                                    <name>0</name>
                                    <description>Input (functions as an input pin)</description>
                                    <value>#0</value>
                                </enumeratedValue>
                                <enumeratedValue>
                                    <name>1</name>
                                    <description>Output (functions as an output pin)</description>
                                    <value>#1</value>
                                </enumeratedValue>
                            </enumeratedValues>
                        </field>
                        <field>
                            <name>PDR06</name>
                            <description>Pmn Direction</description>
                            <lsb>6</lsb>
                            <msb>6</msb>
                            <access>read-write</access>
                            <enumeratedValues>
                                <enumeratedValue>
                                    <name>0</name>
                                    <description>Input (functions as an input pin)</description>
                                    <value>#0</value>
                                </enumeratedValue>
                                <enumeratedValue>
                                    <name>1</name>
                                    <description>Output (functions as an output pin)</description>
                                    <value>#1</value>
                                </enumeratedValue>
                            </enumeratedValues>
                        </field>
                        <field>
                            <name>PDR07</name>
                            <description>Pmn Direction</description>
                            <lsb>7</lsb>
                            <msb>7</msb>
                            <access>read-write</access>
                            <enumeratedValues>
                                <enumeratedValue>
                                    <name>0</name>
                                    <description>Input (functions as an input pin)</description>
                                    <value>#0</value>
                                </enumeratedValue>
                                <enumeratedValue>
                                    <name>1</name>
                                    <description>Output (functions as an output pin)</description>
                                    <value>#1</value>
                                </enumeratedValue>
                            </enumeratedValues>
                        </field>
                        <field>
                            <name>PDR08</name>
                            <description>Pmn Direction</description>
                            <lsb>8</lsb>
                            <msb>8</msb>
                            <access>read-write</access>
                            <enumeratedValues>
                                <enumeratedValue>
                                    <name>0</name>
                                    <description>Input (functions as an input pin)</description>
                                    <value>#0</value>
                                </enumeratedValue>
                                <enumeratedValue>
                                    <name>1</name>
                                    <description>Output (functions as an output pin)</description>
                                    <value>#1</value>
                                </enumeratedValue>
                            </enumeratedValues>
                        </field>
                        <field>
                            <name>PDR09</name>
                            <description>Pmn Direction</description>
                            <lsb>9</lsb>
                            <msb>9</msb>
                            <access>read-write</access>
                            <enumeratedValues>
                                <enumeratedValue>
                                    <name>0</name>
                                    <description>Input (functions as an input pin)</description>
                                    <value>#0</value>
                                </enumeratedValue>
                                <enumeratedValue>
                                    <name>1</name>
                                    <description>Output (functions as an output pin)</description>
                                    <value>#1</value>
                                </enumeratedValue>
                            </enumeratedValues>
                        </field>
                        <field>
                            <name>PDR10</name>
                            <description>Pmn Direction</description>
                            <lsb>10</lsb>
                            <msb>10</msb>
                            <access>read-write</access>
                            <enumeratedValues>
                                <enumeratedValue>
                                    <name>0</name>
                                    <description>Input (functions as an input pin)</description>
                                    <value>#0</value>
                                </enumeratedValue>
                                <enumeratedValue>
                                    <name>1</name>
                                    <description>Output (functions as an output pin)</description>
                                    <value>#1</value>
                                </enumeratedValue>
                            </enumeratedValues>
                        </field>
                        <field>
                            <name>PDR11</name>
                            <description>Pmn Direction</description>
                            <lsb>11</lsb>
                            <msb>11</msb>
                            <access>read-write</access>
                            <enumeratedValues>
                                <enumeratedValue>
                                    <name>0</name>
                                    <description>Input (functions as an input pin)</description>
                                    <value>#0</value>
                                </enumeratedValue>
                                <enumeratedValue>
                                    <name>1</name>
                                    <description>Output (functions as an output pin)</description>
                                    <value>#1</value>
                                </enumeratedValue>
                            </enumeratedValues>
                        </field>
                        <field>
                            <name>PDR12</name>
                            <description>Pmn Direction</description>
                            <lsb>12</lsb>
                            <msb>12</msb>
                            <access>read-write</access>
                            <enumeratedValues>
                                <enumeratedValue>
                                    <name>0</name>
                                    <description>Input (functions as an input pin)</description>
                                    <value>#0</value>
                                </enumeratedValue>
                                <enumeratedValue>
                                    <name>1</name>
                                    <description>Output (functions as an output pin)</description>
                                    <value>#1</value>
                                </enumeratedValue>
                            </enumeratedValues>
                        </field>
                        <field>
                            <name>PDR13</name>
                            <description>Pmn Direction</description>
                            <lsb>13</lsb>
                            <msb>13</msb>
                            <access>read-write</access>
                            <enumeratedValues>
                                <enumeratedValue>
                                    <name>0</name>
                                    <description>Input (functions as an input pin)</description>
                                    <value>#0</value>
                                </enumeratedValue>
                                <enumeratedValue>
                                    <name>1</name>
                                    <description>Output (functions as an output pin)</description>
                                    <value>#1</value>
                                </enumeratedValue>
                            </enumeratedValues>
                        </field>
                        <field>
                            <name>PDR14</name>
                            <description>Pmn Direction</description>
                            <lsb>14</lsb>
                            <msb>14</msb>
                            <access>read-write</access>
                            <enumeratedValues>
                                <enumeratedValue>
                                    <name>0</name>
                                    <description>Input (functions as an input pin)</description>
                                    <value>#0</value>
                                </enumeratedValue>
                                <enumeratedValue>
                                    <name>1</name>
                                    <description>Output (functions as an output pin)</description>
                                    <value>#1</value>
                                </enumeratedValue>
                            </enumeratedValues>
                        </field>
                        <field>
                            <name>PDR15</name>
                            <description>Pmn Direction</description>
                            <lsb>15</lsb>
                            <msb>15</msb>
                            <access>read-write</access>
                            <enumeratedValues>
                                <enumeratedValue>
                                    <name>0</name>
                                    <description>Input (functions as an input pin)</description>
                                    <value>#0</value>
                                </enumeratedValue>
                                <enumeratedValue>
                                    <name>1</name>
                                    <description>Output (functions as an output pin)</description>
                                    <value>#1</value>
                                </enumeratedValue>
                            </enumeratedValues>
                        </field>
                        <field>
                            <name>PODR00</name>
                            <description>Pmn Output Data</description>
                            <lsb>16</lsb>
                            <msb>16</msb>
                            <access>read-write</access>
                            <enumeratedValues>
                                <enumeratedValue>
                                    <name>0</name>
                                    <description>Low output</description>
                                    <value>#0</value>
                                </enumeratedValue>
                                <enumeratedValue>
                                    <name>1</name>
                                    <description>High output</description>
                                    <value>#1</value>
                                </enumeratedValue>
                            </enumeratedValues>
                        </field>
                        <field>
                            <name>PODR01</name>
                            <description>Pmn Output Data</description>
                            <lsb>17</lsb>
                            <msb>17</msb>
                            <access>read-write</access>
                            <enumeratedValues>
                                <enumeratedValue>
                                    <name>0</name>
                                    <description>Low output</description>
                                    <value>#0</value>
                                </enumeratedValue>
                                <enumeratedValue>
                                    <name>1</name>
                                    <description>High output</description>
                                    <value>#1</value>
                                </enumeratedValue>
                            </enumeratedValues>
                        </field>
                        <field>
                            <name>PODR02</name>
                            <description>Pmn Output Data</description>
                            <lsb>18</lsb>
                            <msb>18</msb>
                            <access>read-write</access>
                            <enumeratedValues>
                                <enumeratedValue>
                                    <name>0</name>
                                    <description>Low output</description>
                                    <value>#0</value>
                                </enumeratedValue>
                                <enumeratedValue>
                                    <name>1</name>
                                    <description>High output</description>
                                    <value>#1</value>
                                </enumeratedValue>
                            </enumeratedValues>
                        </field>
                        <field>
                            <name>PODR03</name>
                            <description>Pmn Output Data</description>
                            <lsb>19</lsb>
                            <msb>19</msb>
                            <access>read-write</access>
                            <enumeratedValues>
                                <enumeratedValue>
                                    <name>0</name>
                                    <description>Low output</description>
                                    <value>#0</value>
                                </enumeratedValue>
                                <enumeratedValue>
                                    <name>1</name>
                                    <description>High output</description>
                                    <value>#1</value>
                                </enumeratedValue>
                            </enumeratedValues>
                        </field>
                        <field>
                            <name>PODR04</name>
                            <description>Pmn Output Data</description>
                            <lsb>20</lsb>
                            <msb>20</msb>
                            <access>read-write</access>
                            <enumeratedValues>
                                <enumeratedValue>
                                    <name>0</name>
                                    <description>Low output</description>
                                    <value>#0</value>
                                </enumeratedValue>
                                <enumeratedValue>
                                    <name>1</name>
                                    <description>High output</description>
                                    <value>#1</value>
                                </enumeratedValue>
                            </enumeratedValues>
                        </field>
                        <field>
                            <name>PODR05</name>
                            <description>Pmn Output Data</description>
                            <lsb>21</lsb>
                            <msb>21</msb>
                            <access>read-write</access>
                            <enumeratedValues>
                                <enumeratedValue>
                                    <name>0</name>
                                    <description>Low output</description>
                                    <value>#0</value>
                                </enumeratedValue>
                                <enumeratedValue>
                                    <name>1</name>
                                    <description>High output</description>
                                    <value>#1</value>
                                </enumeratedValue>
                            </enumeratedValues>
                        </field>
                        <field>
                            <name>PODR06</name>
                            <description>Pmn Output Data</description>
                            <lsb>22</lsb>
                            <msb>22</msb>
                            <access>read-write</access>
                            <enumeratedValues>
                                <enumeratedValue>
                                    <name>0</name>
                                    <description>Low output</description>
                                    <value>#0</value>
                                </enumeratedValue>
                                <enumeratedValue>
                                    <name>1</name>
                                    <description>High output</description>
                                    <value>#1</value>
                                </enumeratedValue>
                            </enumeratedValues>
                        </field>
                        <field>
                            <name>PODR07</name>
                            <description>Pmn Output Data</description>
                            <lsb>23</lsb>
                            <msb>23</msb>
                            <access>read-write</access>
                            <enumeratedValues>
                                <enumeratedValue>
                                    <name>0</name>
                                    <description>Low output</description>
                                    <value>#0</value>
                                </enumeratedValue>
                                <enumeratedValue>
                                    <name>1</name>
                                    <description>High output</description>
                                    <value>#1</value>
                                </enumeratedValue>
                            </enumeratedValues>
                        </field>
                        <field>
                            <name>PODR08</name>
                            <description>Pmn Output Data</description>
                            <lsb>24</lsb>
                            <msb>24</msb>
                            <access>read-write</access>
                            <enumeratedValues>
                                <enumeratedValue>
                                    <name>0</name>
                                    <description>Low output</description>
                                    <value>#0</value>
                                </enumeratedValue>
                                <enumeratedValue>
                                    <name>1</name>
                                    <description>High output</description>
                                    <value>#1</value>
                                </enumeratedValue>
                            </enumeratedValues>
                        </field>
                        <field>
                            <name>PODR09</name>
                            <description>Pmn Output Data</description>
                            <lsb>25</lsb>
                            <msb>25</msb>
                            <access>read-write</access>
                            <enumeratedValues>
                                <enumeratedValue>
                                    <name>0</name>
                                    <description>Low output</description>
                                    <value>#0</value>
                                </enumeratedValue>
                                <enumeratedValue>
                                    <name>1</name>
                                    <description>High output</description>
                                    <value>#1</value>
                                </enumeratedValue>
                            </enumeratedValues>
                        </field>
                        <field>
                            <name>PODR10</name>
                            <description>Pmn Output Data</description>
                            <lsb>26</lsb>
                            <msb>26</msb>
                            <access>read-write</access>
                            <enumeratedValues>
                                <enumeratedValue>
                                    <name>0</name>
                                    <description>Low output</description>
                                    <value>#0</value>
                                </enumeratedValue>
                                <enumeratedValue>
                                    <name>1</name>
                                    <description>High output</description>
                                    <value>#1</value>
                                </enumeratedValue>
                            </enumeratedValues>
                        </field>
                        <field>
                            <name>PODR11</name>
                            <description>Pmn Output Data</description>
                            <lsb>27</lsb>
                            <msb>27</msb>
                            <access>read-write</access>
                            <enumeratedValues>
                                <enumeratedValue>
                                    <name>0</name>
                                    <description>Low output</description>
                                    <value>#0</value>
                                </enumeratedValue>
                                <enumeratedValue>
                                    <name>1</name>
                                    <description>High output</description>
                                    <value>#1</value>
                                </enumeratedValue>
                            </enumeratedValues>
                        </field>
                        <field>
                            <name>PODR12</name>
                            <description>Pmn Output Data</description>
                            <lsb>28</lsb>
                            <msb>28</msb>
                            <access>read-write</access>
                            <enumeratedValues>
                                <enumeratedValue>
                                    <name>0</name>
                                    <description>Low output</description>
                                    <value>#0</value>
                                </enumeratedValue>
                                <enumeratedValue>
                                    <name>1</name>
                                    <description>High output</description>
                                    <value>#1</value>
                                </enumeratedValue>
                            </enumeratedValues>
                        </field>
                        <field>
                            <name>PODR13</name>
                            <description>Pmn Output Data</description>
                            <lsb>29</lsb>
                            <msb>29</msb>
                            <access>read-write</access>
                            <enumeratedValues>
                                <enumeratedValue>
                                    <name>0</name>
                                    <description>Low output</description>
                                    <value>#0</value>
                                </enumeratedValue>
                                <enumeratedValue>
                                    <name>1</name>
                                    <description>High output</description>
                                    <value>#1</value>
                                </enumeratedValue>
                            </enumeratedValues>
                        </field>
                        <field>
                            <name>PODR14</name>
                            <description>Pmn Output Data</description>
                            <lsb>30</lsb>
                            <msb>30</msb>
                            <access>read-write</access>
                            <enumeratedValues>
                                <enumeratedValue>
                                    <name>0</name>
                                    <description>Low output</description>
                                    <value>#0</value>
                                </enumeratedValue>
                                <enumeratedValue>
                                    <name>1</name>
                                    <description>High output</description>
                                    <value>#1</value>
                                </enumeratedValue>
                            </enumeratedValues>
                        </field>
                        <field>
                            <name>PODR15</name>
                            <description>Pmn Output Data</description>
                            <lsb>31</lsb>
                            <msb>31</msb>
                            <access>read-write</access>
                            <enumeratedValues>
                                <enumeratedValue>
                                    <name>0</name>
                                    <description>Low output</description>
                                    <value>#0</value>
                                </enumeratedValue>
                                <enumeratedValue>
                                    <name>1</name>
                                    <description>High output</description>
                                    <value>#1</value>
                                </enumeratedValue>
                            </enumeratedValues>
                        </field>
                    </fields>
                </register>
                <register>
                    <name>PDR</name>
                    <description>Port Control Register 1</description>
                    <alternateRegister>PCNTR1</alternateRegister>
                    <addressOffset>0x000</addressOffset>
                    <size>16</size>
                    <access>read-write</access>
                    <resetValue>0x0000</resetValue>
                    <resetMask>0xffff</resetMask>
                    <fields>
                        <field>
                            <name>PODR00</name>
                            <description>Pmn Output Data</description>
                            <lsb>0</lsb>
                            <msb>0</msb>
                            <access>read-write</access>
                            <enumeratedValues>
                                <enumeratedValue>
                                    <name>0</name>
                                    <description>Low output</description>
                                    <value>#0</value>
                                </enumeratedValue>
                                <enumeratedValue>
                                    <name>1</name>
                                    <description>High output</description>
                                    <value>#1</value>
                                </enumeratedValue>
                            </enumeratedValues>
                        </field>
                        <field>
                            <name>PODR01</name>
                            <description>Pmn Output Data</description>
                            <lsb>1</lsb>
                            <msb>1</msb>
                            <access>read-write</access>
                            <enumeratedValues>
                                <enumeratedValue>
                                    <name>0</name>
                                    <description>Low output</description>
                                    <value>#0</value>
                                </enumeratedValue>
                                <enumeratedValue>
                                    <name>1</name>
                                    <description>High output</description>
                                    <value>#1</value>
                                </enumeratedValue>
                            </enumeratedValues>
                        </field>
                        <field>
                            <name>PODR02</name>
                            <description>Pmn Output Data</description>
                            <lsb>2</lsb>
                            <msb>2</msb>
                            <access>read-write</access>
                            <enumeratedValues>
                                <enumeratedValue>
                                    <name>0</name>
                                    <description>Low output</description>
                                    <value>#0</value>
                                </enumeratedValue>
                                <enumeratedValue>
                                    <name>1</name>
                                    <description>High output</description>
                                    <value>#1</value>
                                </enumeratedValue>
                            </enumeratedValues>
                        </field>
                        <field>
                            <name>PODR03</name>
                            <description>Pmn Output Data</description>
                            <lsb>3</lsb>
                            <msb>3</msb>
                            <access>read-write</access>
                            <enumeratedValues>
                                <enumeratedValue>
                                    <name>0</name>
                                    <description>Low output</description>
                                    <value>#0</value>
                                </enumeratedValue>
                                <enumeratedValue>
                                    <name>1</name>
                                    <description>High output</description>
                                    <value>#1</value>
                                </enumeratedValue>
                            </enumeratedValues>
                        </field>
                        <field>
                            <name>PODR04</name>
                            <description>Pmn Output Data</description>
                            <lsb>4</lsb>
                            <msb>4</msb>
                            <access>read-write</access>
                            <enumeratedValues>
                                <enumeratedValue>
                                    <name>0</name>
                                    <description>Low output</description>
                                    <value>#0</value>
                                </enumeratedValue>
                                <enumeratedValue>
                                    <name>1</name>
                                    <description>High output</description>
                                    <value>#1</value>
                                </enumeratedValue>
                            </enumeratedValues>
                        </field>
                        <field>
                            <name>PODR05</name>
                            <description>Pmn Output Data</description>
                            <lsb>5</lsb>
                            <msb>5</msb>
                            <access>read-write</access>
                            <enumeratedValues>
                                <enumeratedValue>
                                    <name>0</name>
                                    <description>Low output</description>
                                    <value>#0</value>
                                </enumeratedValue>
                                <enumeratedValue>
                                    <name>1</name>
                                    <description>High output</description>
                                    <value>#1</value>
                                </enumeratedValue>
                            </enumeratedValues>
                        </field>
                        <field>
                            <name>PODR06</name>
                            <description>Pmn Output Data</description>
                            <lsb>6</lsb>
                            <msb>6</msb>
                            <access>read-write</access>
                            <enumeratedValues>
                                <enumeratedValue>
                                    <name>0</name>
                                    <description>Low output</description>
                                    <value>#0</value>
                                </enumeratedValue>
                                <enumeratedValue>
                                    <name>1</name>
                                    <description>High output</description>
                                    <value>#1</value>
                                </enumeratedValue>
                            </enumeratedValues>
                        </field>
                        <field>
                            <name>PODR07</name>
                            <description>Pmn Output Data</description>
                            <lsb>7</lsb>
                            <msb>7</msb>
                            <access>read-write</access>
                            <enumeratedValues>
                                <enumeratedValue>
                                    <name>0</name>
                                    <description>Low output</description>
                                    <value>#0</value>
                                </enumeratedValue>
                                <enumeratedValue>
                                    <name>1</name>
                                    <description>High output</description>
                                    <value>#1</value>
                                </enumeratedValue>
                            </enumeratedValues>
                        </field>
                        <field>
                            <name>PODR08</name>
                            <description>Pmn Output Data</description>
                            <lsb>8</lsb>
                            <msb>8</msb>
                            <access>read-write</access>
                            <enumeratedValues>
                                <enumeratedValue>
                                    <name>0</name>
                                    <description>Low output</description>
                                    <value>#0</value>
                                </enumeratedValue>
                                <enumeratedValue>
                                    <name>1</name>
                                    <description>High output</description>
                                    <value>#1</value>
                                </enumeratedValue>
                            </enumeratedValues>
                        </field>
                        <field>
                            <name>PODR09</name>
                            <description>Pmn Output Data</description>
                            <lsb>9</lsb>
                            <msb>9</msb>
                            <access>read-write</access>
                            <enumeratedValues>
                                <enumeratedValue>
                                    <name>0</name>
                                    <description>Low output</description>
                                    <value>#0</value>
                                </enumeratedValue>
                                <enumeratedValue>
                                    <name>1</name>
                                    <description>High output</description>
                                    <value>#1</value>
                                </enumeratedValue>
                            </enumeratedValues>
                        </field>
                        <field>
                            <name>PODR10</name>
                            <description>Pmn Output Data</description>
                            <lsb>10</lsb>
                            <msb>10</msb>
                            <access>read-write</access>
                            <enumeratedValues>
                                <enumeratedValue>
                                    <name>0</name>
                                    <description>Low output</description>
                                    <value>#0</value>
                                </enumeratedValue>
                                <enumeratedValue>
                                    <name>1</name>
                                    <description>High output</description>
                                    <value>#1</value>
                                </enumeratedValue>
                            </enumeratedValues>
                        </field>
                        <field>
                            <name>PODR11</name>
                            <description>Pmn Output Data</description>
                            <lsb>11</lsb>
                            <msb>11</msb>
                            <access>read-write</access>
                            <enumeratedValues>
                                <enumeratedValue>
                                    <name>0</name>
                                    <description>Low output</description>
                                    <value>#0</value>
                                </enumeratedValue>
                                <enumeratedValue>
                                    <name>1</name>
                                    <description>High output</description>
                                    <value>#1</value>
                                </enumeratedValue>
                            </enumeratedValues>
                        </field>
                        <field>
                            <name>PODR12</name>
                            <description>Pmn Output Data</description>
                            <lsb>12</lsb>
                            <msb>12</msb>
                            <access>read-write</access>
                            <enumeratedValues>
                                <enumeratedValue>
                                    <name>0</name>
                                    <description>Low output</description>
                                    <value>#0</value>
                                </enumeratedValue>
                                <enumeratedValue>
                                    <name>1</name>
                                    <description>High output</description>
                                    <value>#1</value>
                                </enumeratedValue>
                            </enumeratedValues>
                        </field>
                        <field>
                            <name>PODR13</name>
                            <description>Pmn Output Data</description>
                            <lsb>13</lsb>
                            <msb>13</msb>
                            <access>read-write</access>
                            <enumeratedValues>
                                <enumeratedValue>
                                    <name>0</name>
                                    <description>Low output</description>
                                    <value>#0</value>
                                </enumeratedValue>
                                <enumeratedValue>
                                    <name>1</name>
                                    <description>High output</description>
                                    <value>#1</value>
                                </enumeratedValue>
                            </enumeratedValues>
                        </field>
                        <field>
                            <name>PODR14</name>
                            <description>Pmn Output Data</description>
                            <lsb>14</lsb>
                            <msb>14</msb>
                            <access>read-write</access>
                            <enumeratedValues>
                                <enumeratedValue>
                                    <name>0</name>
                                    <description>Low output</description>
                                    <value>#0</value>
                                </enumeratedValue>
                                <enumeratedValue>
                                    <name>1</name>
                                    <description>High output</description>
                                    <value>#1</value>
                                </enumeratedValue>
                            </enumeratedValues>
                        </field>
                        <field>
                            <name>PODR15</name>
                            <description>Pmn Output Data</description>
                            <lsb>15</lsb>
                            <msb>15</msb>
                            <access>read-write</access>
                            <enumeratedValues>
                                <enumeratedValue>
                                    <name>0</name>
                                    <description>Low output</description>
                                    <value>#0</value>
                                </enumeratedValue>
                                <enumeratedValue>
                                    <name>1</name>
                                    <description>High output</description>
                                    <value>#1</value>
                                </enumeratedValue>
                            </enumeratedValues>
                        </field>
                    </fields>
                </register>
                <register>
                    <name>PODR</name>
                    <description>Port Control Register 1</description>
                    <alternateRegister>PCNTR1</alternateRegister>
                    <addressOffset>0x002</addressOffset>
                    <size>16</size>
                    <access>read-write</access>
                    <resetValue>0x0000</resetValue>
                    <resetMask>0xffff</resetMask>
                    <fields>
                        <field>
                            <name>PDR00</name>
                            <description>Pmn Direction</description>
                            <lsb>0</lsb>
                            <msb>0</msb>
                            <access>read-write</access>
                            <enumeratedValues>
                                <enumeratedValue>
                                    <name>0</name>
                                    <description>Input (functions as an input pin)</description>
                                    <value>#0</value>
                                </enumeratedValue>
                                <enumeratedValue>
                                    <name>1</name>
                                    <description>Output (functions as an output pin)</description>
                                    <value>#1</value>
                                </enumeratedValue>
                            </enumeratedValues>
                        </field>
                        <field>
                            <name>PDR01</name>
                            <description>Pmn Direction</description>
                            <lsb>1</lsb>
                            <msb>1</msb>
                            <access>read-write</access>
                            <enumeratedValues>
                                <enumeratedValue>
                                    <name>0</name>
                                    <description>Input (functions as an input pin)</description>
                                    <value>#0</value>
                                </enumeratedValue>
                                <enumeratedValue>
                                    <name>1</name>
                                    <description>Output (functions as an output pin)</description>
                                    <value>#1</value>
                                </enumeratedValue>
                            </enumeratedValues>
                        </field>
                        <field>
                            <name>PDR02</name>
                            <description>Pmn Direction</description>
                            <lsb>2</lsb>
                            <msb>2</msb>
                            <access>read-write</access>
                            <enumeratedValues>
                                <enumeratedValue>
                                    <name>0</name>
                                    <description>Input (functions as an input pin)</description>
                                    <value>#0</value>
                                </enumeratedValue>
                                <enumeratedValue>
                                    <name>1</name>
                                    <description>Output (functions as an output pin)</description>
                                    <value>#1</value>
                                </enumeratedValue>
                            </enumeratedValues>
                        </field>
                        <field>
                            <name>PDR03</name>
                            <description>Pmn Direction</description>
                            <lsb>3</lsb>
                            <msb>3</msb>
                            <access>read-write</access>
                            <enumeratedValues>
                                <enumeratedValue>
                                    <name>0</name>
                                    <description>Input (functions as an input pin)</description>
                                    <value>#0</value>
                                </enumeratedValue>
                                <enumeratedValue>
                                    <name>1</name>
                                    <description>Output (functions as an output pin)</description>
                                    <value>#1</value>
                                </enumeratedValue>
                            </enumeratedValues>
                        </field>
                        <field>
                            <name>PDR04</name>
                            <description>Pmn Direction</description>
                            <lsb>4</lsb>
                            <msb>4</msb>
                            <access>read-write</access>
                            <enumeratedValues>
                                <enumeratedValue>
                                    <name>0</name>
                                    <description>Input (functions as an input pin)</description>
                                    <value>#0</value>
                                </enumeratedValue>
                                <enumeratedValue>
                                    <name>1</name>
                                    <description>Output (functions as an output pin)</description>
                                    <value>#1</value>
                                </enumeratedValue>
                            </enumeratedValues>
                        </field>
                        <field>
                            <name>PDR05</name>
                            <description>Pmn Direction</description>
                            <lsb>5</lsb>
                            <msb>5</msb>
                            <access>read-write</access>
                            <enumeratedValues>
                                <enumeratedValue>
                                    <name>0</name>
                                    <description>Input (functions as an input pin)</description>
                                    <value>#0</value>
                                </enumeratedValue>
                                <enumeratedValue>
                                    <name>1</name>
                                    <description>Output (functions as an output pin)</description>
                                    <value>#1</value>
                                </enumeratedValue>
                            </enumeratedValues>
                        </field>
                        <field>
                            <name>PDR06</name>
                            <description>Pmn Direction</description>
                            <lsb>6</lsb>
                            <msb>6</msb>
                            <access>read-write</access>
                            <enumeratedValues>
                                <enumeratedValue>
                                    <name>0</name>
                                    <description>Input (functions as an input pin)</description>
                                    <value>#0</value>
                                </enumeratedValue>
                                <enumeratedValue>
                                    <name>1</name>
                                    <description>Output (functions as an output pin)</description>
                                    <value>#1</value>
                                </enumeratedValue>
                            </enumeratedValues>
                        </field>
                        <field>
                            <name>PDR07</name>
                            <description>Pmn Direction</description>
                            <lsb>7</lsb>
                            <msb>7</msb>
                            <access>read-write</access>
                            <enumeratedValues>
                                <enumeratedValue>
                                    <name>0</name>
                                    <description>Input (functions as an input pin)</description>
                                    <value>#0</value>
                                </enumeratedValue>
                                <enumeratedValue>
                                    <name>1</name>
                                    <description>Output (functions as an output pin)</description>
                                    <value>#1</value>
                                </enumeratedValue>
                            </enumeratedValues>
                        </field>
                        <field>
                            <name>PDR08</name>
                            <description>Pmn Direction</description>
                            <lsb>8</lsb>
                            <msb>8</msb>
                            <access>read-write</access>
                            <enumeratedValues>
                                <enumeratedValue>
                                    <name>0</name>
                                    <description>Input (functions as an input pin)</description>
                                    <value>#0</value>
                                </enumeratedValue>
                                <enumeratedValue>
                                    <name>1</name>
                                    <description>Output (functions as an output pin)</description>
                                    <value>#1</value>
                                </enumeratedValue>
                            </enumeratedValues>
                        </field>
                        <field>
                            <name>PDR09</name>
                            <description>Pmn Direction</description>
                            <lsb>9</lsb>
                            <msb>9</msb>
                            <access>read-write</access>
                            <enumeratedValues>
                                <enumeratedValue>
                                    <name>0</name>
                                    <description>Input (functions as an input pin)</description>
                                    <value>#0</value>
                                </enumeratedValue>
                                <enumeratedValue>
                                    <name>1</name>
                                    <description>Output (functions as an output pin)</description>
                                    <value>#1</value>
                                </enumeratedValue>
                            </enumeratedValues>
                        </field>
                        <field>
                            <name>PDR10</name>
                            <description>Pmn Direction</description>
                            <lsb>10</lsb>
                            <msb>10</msb>
                            <access>read-write</access>
                            <enumeratedValues>
                                <enumeratedValue>
                                    <name>0</name>
                                    <description>Input (functions as an input pin)</description>
                                    <value>#0</value>
                                </enumeratedValue>
                                <enumeratedValue>
                                    <name>1</name>
                                    <description>Output (functions as an output pin)</description>
                                    <value>#1</value>
                                </enumeratedValue>
                            </enumeratedValues>
                        </field>
                        <field>
                            <name>PDR11</name>
                            <description>Pmn Direction</description>
                            <lsb>11</lsb>
                            <msb>11</msb>
                            <access>read-write</access>
                            <enumeratedValues>
                                <enumeratedValue>
                                    <name>0</name>
                                    <description>Input (functions as an input pin)</description>
                                    <value>#0</value>
                                </enumeratedValue>
                                <enumeratedValue>
                                    <name>1</name>
                                    <description>Output (functions as an output pin)</description>
                                    <value>#1</value>
                                </enumeratedValue>
                            </enumeratedValues>
                        </field>
                        <field>
                            <name>PDR12</name>
                            <description>Pmn Direction</description>
                            <lsb>12</lsb>
                            <msb>12</msb>
                            <access>read-write</access>
                            <enumeratedValues>
                                <enumeratedValue>
                                    <name>0</name>
                                    <description>Input (functions as an input pin)</description>
                                    <value>#0</value>
                                </enumeratedValue>
                                <enumeratedValue>
                                    <name>1</name>
                                    <description>Output (functions as an output pin)</description>
                                    <value>#1</value>
                                </enumeratedValue>
                            </enumeratedValues>
                        </field>
                        <field>
                            <name>PDR13</name>
                            <description>Pmn Direction</description>
                            <lsb>13</lsb>
                            <msb>13</msb>
                            <access>read-write</access>
                            <enumeratedValues>
                                <enumeratedValue>
                                    <name>0</name>
                                    <description>Input (functions as an input pin)</description>
                                    <value>#0</value>
                                </enumeratedValue>
                                <enumeratedValue>
                                    <name>1</name>
                                    <description>Output (functions as an output pin)</description>
                                    <value>#1</value>
                                </enumeratedValue>
                            </enumeratedValues>
                        </field>
                        <field>
                            <name>PDR14</name>
                            <description>Pmn Direction</description>
                            <lsb>14</lsb>
                            <msb>14</msb>
                            <access>read-write</access>
                            <enumeratedValues>
                                <enumeratedValue>
                                    <name>0</name>
                                    <description>Input (functions as an input pin)</description>
                                    <value>#0</value>
                                </enumeratedValue>
                                <enumeratedValue>
                                    <name>1</name>
                                    <description>Output (functions as an output pin)</description>
                                    <value>#1</value>
                                </enumeratedValue>
                            </enumeratedValues>
                        </field>
                        <field>
                            <name>PDR15</name>
                            <description>Pmn Direction</description>
                            <lsb>15</lsb>
                            <msb>15</msb>
                            <access>read-write</access>
                            <enumeratedValues>
                                <enumeratedValue>
                                    <name>0</name>
                                    <description>Input (functions as an input pin)</description>
                                    <value>#0</value>
                                </enumeratedValue>
                                <enumeratedValue>
                                    <name>1</name>
                                    <description>Output (functions as an output pin)</description>
                                    <value>#1</value>
                                </enumeratedValue>
                            </enumeratedValues>
                        </field>
                    </fields>
                </register>
                <register>
                    <name>PCNTR2</name>
                    <description>Port Control Register 2</description>
                    <addressOffset>0x004</addressOffset>
                    <size>32</size>
                    <access>read-only</access>
                    <resetValue>0x00000000</resetValue>
                    <resetMask>0xffff0000</resetMask>
                    <fields>
                        <field>
                            <name>PIDR00</name>
                            <description>Pmn State</description>
                            <lsb>0</lsb>
                            <msb>0</msb>
                            <access>read-only</access>
                            <enumeratedValues>
                                <enumeratedValue>
                                    <name>0</name>
                                    <description>Low level</description>
                                    <value>#0</value>
                                </enumeratedValue>
                                <enumeratedValue>
                                    <name>1</name>
                                    <description>High level</description>
                                    <value>#1</value>
                                </enumeratedValue>
                            </enumeratedValues>
                        </field>
                        <field>
                            <name>PIDR01</name>
                            <description>Pmn State</description>
                            <lsb>1</lsb>
                            <msb>1</msb>
                            <access>read-only</access>
                            <enumeratedValues>
                                <enumeratedValue>
                                    <name>0</name>
                                    <description>Low level</description>
                                    <value>#0</value>
                                </enumeratedValue>
                                <enumeratedValue>
                                    <name>1</name>
                                    <description>High level</description>
                                    <value>#1</value>
                                </enumeratedValue>
                            </enumeratedValues>
                        </field>
                        <field>
                            <name>PIDR02</name>
                            <description>Pmn State</description>
                            <lsb>2</lsb>
                            <msb>2</msb>
                            <access>read-only</access>
                            <enumeratedValues>
                                <enumeratedValue>
                                    <name>0</name>
                                    <description>Low level</description>
                                    <value>#0</value>
                                </enumeratedValue>
                                <enumeratedValue>
                                    <name>1</name>
                                    <description>High level</description>
                                    <value>#1</value>
                                </enumeratedValue>
                            </enumeratedValues>
                        </field>
                        <field>
                            <name>PIDR03</name>
                            <description>Pmn State</description>
                            <lsb>3</lsb>
                            <msb>3</msb>
                            <access>read-only</access>
                            <enumeratedValues>
                                <enumeratedValue>
                                    <name>0</name>
                                    <description>Low level</description>
                                    <value>#0</value>
                                </enumeratedValue>
                                <enumeratedValue>
                                    <name>1</name>
                                    <description>High level</description>
                                    <value>#1</value>
                                </enumeratedValue>
                            </enumeratedValues>
                        </field>
                        <field>
                            <name>PIDR04</name>
                            <description>Pmn State</description>
                            <lsb>4</lsb>
                            <msb>4</msb>
                            <access>read-only</access>
                            <enumeratedValues>
                                <enumeratedValue>
                                    <name>0</name>
                                    <description>Low level</description>
                                    <value>#0</value>
                                </enumeratedValue>
                                <enumeratedValue>
                                    <name>1</name>
                                    <description>High level</description>
                                    <value>#1</value>
                                </enumeratedValue>
                            </enumeratedValues>
                        </field>
                        <field>
                            <name>PIDR05</name>
                            <description>Pmn State</description>
                            <lsb>5</lsb>
                            <msb>5</msb>
                            <access>read-only</access>
                            <enumeratedValues>
                                <enumeratedValue>
                                    <name>0</name>
                                    <description>Low level</description>
                                    <value>#0</value>
                                </enumeratedValue>
                                <enumeratedValue>
                                    <name>1</name>
                                    <description>High level</description>
                                    <value>#1</value>
                                </enumeratedValue>
                            </enumeratedValues>
                        </field>
                        <field>
                            <name>PIDR06</name>
                            <description>Pmn State</description>
                            <lsb>6</lsb>
                            <msb>6</msb>
                            <access>read-only</access>
                            <enumeratedValues>
                                <enumeratedValue>
                                    <name>0</name>
                                    <description>Low level</description>
                                    <value>#0</value>
                                </enumeratedValue>
                                <enumeratedValue>
                                    <name>1</name>
                                    <description>High level</description>
                                    <value>#1</value>
                                </enumeratedValue>
                            </enumeratedValues>
                        </field>
                        <field>
                            <name>PIDR07</name>
                            <description>Pmn State</description>
                            <lsb>7</lsb>
                            <msb>7</msb>
                            <access>read-only</access>
                            <enumeratedValues>
                                <enumeratedValue>
                                    <name>0</name>
                                    <description>Low level</description>
                                    <value>#0</value>
                                </enumeratedValue>
                                <enumeratedValue>
                                    <name>1</name>
                                    <description>High level</description>
                                    <value>#1</value>
                                </enumeratedValue>
                            </enumeratedValues>
                        </field>
                        <field>
                            <name>PIDR08</name>
                            <description>Pmn State</description>
                            <lsb>8</lsb>
                            <msb>8</msb>
                            <access>read-only</access>
                            <enumeratedValues>
                                <enumeratedValue>
                                    <name>0</name>
                                    <description>Low level</description>
                                    <value>#0</value>
                                </enumeratedValue>
                                <enumeratedValue>
                                    <name>1</name>
                                    <description>High level</description>
                                    <value>#1</value>
                                </enumeratedValue>
                            </enumeratedValues>
                        </field>
                        <field>
                            <name>PIDR09</name>
                            <description>Pmn State</description>
                            <lsb>9</lsb>
                            <msb>9</msb>
                            <access>read-only</access>
                            <enumeratedValues>
                                <enumeratedValue>
                                    <name>0</name>
                                    <description>Low level</description>
                                    <value>#0</value>
                                </enumeratedValue>
                                <enumeratedValue>
                                    <name>1</name>
                                    <description>High level</description>
                                    <value>#1</value>
                                </enumeratedValue>
                            </enumeratedValues>
                        </field>
                        <field>
                            <name>PIDR10</name>
                            <description>Pmn State</description>
                            <lsb>10</lsb>
                            <msb>10</msb>
                            <access>read-only</access>
                            <enumeratedValues>
                                <enumeratedValue>
                                    <name>0</name>
                                    <description>Low level</description>
                                    <value>#0</value>
                                </enumeratedValue>
                                <enumeratedValue>
                                    <name>1</name>
                                    <description>High level</description>
                                    <value>#1</value>
                                </enumeratedValue>
                            </enumeratedValues>
                        </field>
                        <field>
                            <name>PIDR11</name>
                            <description>Pmn State</description>
                            <lsb>11</lsb>
                            <msb>11</msb>
                            <access>read-only</access>
                            <enumeratedValues>
                                <enumeratedValue>
                                    <name>0</name>
                                    <description>Low level</description>
                                    <value>#0</value>
                                </enumeratedValue>
                                <enumeratedValue>
                                    <name>1</name>
                                    <description>High level</description>
                                    <value>#1</value>
                                </enumeratedValue>
                            </enumeratedValues>
                        </field>
                        <field>
                            <name>PIDR12</name>
                            <description>Pmn State</description>
                            <lsb>12</lsb>
                            <msb>12</msb>
                            <access>read-only</access>
                            <enumeratedValues>
                                <enumeratedValue>
                                    <name>0</name>
                                    <description>Low level</description>
                                    <value>#0</value>
                                </enumeratedValue>
                                <enumeratedValue>
                                    <name>1</name>
                                    <description>High level</description>
                                    <value>#1</value>
                                </enumeratedValue>
                            </enumeratedValues>
                        </field>
                        <field>
                            <name>PIDR13</name>
                            <description>Pmn State</description>
                            <lsb>13</lsb>
                            <msb>13</msb>
                            <access>read-only</access>
                            <enumeratedValues>
                                <enumeratedValue>
                                    <name>0</name>
                                    <description>Low level</description>
                                    <value>#0</value>
                                </enumeratedValue>
                                <enumeratedValue>
                                    <name>1</name>
                                    <description>High level</description>
                                    <value>#1</value>
                                </enumeratedValue>
                            </enumeratedValues>
                        </field>
                        <field>
                            <name>PIDR14</name>
                            <description>Pmn State</description>
                            <lsb>14</lsb>
                            <msb>14</msb>
                            <access>read-only</access>
                            <enumeratedValues>
                                <enumeratedValue>
                                    <name>0</name>
                                    <description>Low level</description>
                                    <value>#0</value>
                                </enumeratedValue>
                                <enumeratedValue>
                                    <name>1</name>
                                    <description>High level</description>
                                    <value>#1</value>
                                </enumeratedValue>
                            </enumeratedValues>
                        </field>
                        <field>
                            <name>PIDR15</name>
                            <description>Pmn State</description>
                            <lsb>15</lsb>
                            <msb>15</msb>
                            <access>read-only</access>
                            <enumeratedValues>
                                <enumeratedValue>
                                    <name>0</name>
                                    <description>Low level</description>
                                    <value>#0</value>
                                </enumeratedValue>
                                <enumeratedValue>
                                    <name>1</name>
                                    <description>High level</description>
                                    <value>#1</value>
                                </enumeratedValue>
                            </enumeratedValues>
                        </field>
                    </fields>
                </register>
                <register>
                    <name>PIDR</name>
                    <description>Port Control Register 2</description>
                    <alternateRegister>PCNTR2</alternateRegister>
                    <addressOffset>0x004</addressOffset>
                    <size>16</size>
                    <access>read-only</access>
                    <resetValue>0x0000</resetValue>
                    <resetMask>0xffff</resetMask>
                </register>
                <register>
                    <name>PCNTR3</name>
                    <description>Port Control Register 3</description>
                    <addressOffset>0x008</addressOffset>
                    <size>32</size>
                    <access>write-only</access>
                    <resetValue>0x00000000</resetValue>
                    <resetMask>0xffffffff</resetMask>
                    <fields>
                        <field>
                            <name>POSR00</name>
                            <description>Pmn Output Set</description>
                            <lsb>0</lsb>
                            <msb>0</msb>
                            <access>write-only</access>
                            <enumeratedValues>
                                <enumeratedValue>
                                    <name>0</name>
                                    <description>No effect on output</description>
                                    <value>#0</value>
                                </enumeratedValue>
                                <enumeratedValue>
                                    <name>1</name>
                                    <description>High output</description>
                                    <value>#1</value>
                                </enumeratedValue>
                            </enumeratedValues>
                        </field>
                        <field>
                            <name>POSR01</name>
                            <description>Pmn Output Set</description>
                            <lsb>1</lsb>
                            <msb>1</msb>
                            <access>write-only</access>
                            <enumeratedValues>
                                <enumeratedValue>
                                    <name>0</name>
                                    <description>No effect on output</description>
                                    <value>#0</value>
                                </enumeratedValue>
                                <enumeratedValue>
                                    <name>1</name>
                                    <description>High output</description>
                                    <value>#1</value>
                                </enumeratedValue>
                            </enumeratedValues>
                        </field>
                        <field>
                            <name>POSR02</name>
                            <description>Pmn Output Set</description>
                            <lsb>2</lsb>
                            <msb>2</msb>
                            <access>write-only</access>
                            <enumeratedValues>
                                <enumeratedValue>
                                    <name>0</name>
                                    <description>No effect on output</description>
                                    <value>#0</value>
                                </enumeratedValue>
                                <enumeratedValue>
                                    <name>1</name>
                                    <description>High output</description>
                                    <value>#1</value>
                                </enumeratedValue>
                            </enumeratedValues>
                        </field>
                        <field>
                            <name>POSR03</name>
                            <description>Pmn Output Set</description>
                            <lsb>3</lsb>
                            <msb>3</msb>
                            <access>write-only</access>
                            <enumeratedValues>
                                <enumeratedValue>
                                    <name>0</name>
                                    <description>No effect on output</description>
                                    <value>#0</value>
                                </enumeratedValue>
                                <enumeratedValue>
                                    <name>1</name>
                                    <description>High output</description>
                                    <value>#1</value>
                                </enumeratedValue>
                            </enumeratedValues>
                        </field>
                        <field>
                            <name>POSR04</name>
                            <description>Pmn Output Set</description>
                            <lsb>4</lsb>
                            <msb>4</msb>
                            <access>write-only</access>
                            <enumeratedValues>
                                <enumeratedValue>
                                    <name>0</name>
                                    <description>No effect on output</description>
                                    <value>#0</value>
                                </enumeratedValue>
                                <enumeratedValue>
                                    <name>1</name>
                                    <description>High output</description>
                                    <value>#1</value>
                                </enumeratedValue>
                            </enumeratedValues>
                        </field>
                        <field>
                            <name>POSR05</name>
                            <description>Pmn Output Set</description>
                            <lsb>5</lsb>
                            <msb>5</msb>
                            <access>write-only</access>
                            <enumeratedValues>
                                <enumeratedValue>
                                    <name>0</name>
                                    <description>No effect on output</description>
                                    <value>#0</value>
                                </enumeratedValue>
                                <enumeratedValue>
                                    <name>1</name>
                                    <description>High output</description>
                                    <value>#1</value>
                                </enumeratedValue>
                            </enumeratedValues>
                        </field>
                        <field>
                            <name>POSR06</name>
                            <description>Pmn Output Set</description>
                            <lsb>6</lsb>
                            <msb>6</msb>
                            <access>write-only</access>
                            <enumeratedValues>
                                <enumeratedValue>
                                    <name>0</name>
                                    <description>No effect on output</description>
                                    <value>#0</value>
                                </enumeratedValue>
                                <enumeratedValue>
                                    <name>1</name>
                                    <description>High output</description>
                                    <value>#1</value>
                                </enumeratedValue>
                            </enumeratedValues>
                        </field>
                        <field>
                            <name>POSR07</name>
                            <description>Pmn Output Set</description>
                            <lsb>7</lsb>
                            <msb>7</msb>
                            <access>write-only</access>
                            <enumeratedValues>
                                <enumeratedValue>
                                    <name>0</name>
                                    <description>No effect on output</description>
                                    <value>#0</value>
                                </enumeratedValue>
                                <enumeratedValue>
                                    <name>1</name>
                                    <description>High output</description>
                                    <value>#1</value>
                                </enumeratedValue>
                            </enumeratedValues>
                        </field>
                        <field>
                            <name>POSR08</name>
                            <description>Pmn Output Set</description>
                            <lsb>8</lsb>
                            <msb>8</msb>
                            <access>write-only</access>
                            <enumeratedValues>
                                <enumeratedValue>
                                    <name>0</name>
                                    <description>No effect on output</description>
                                    <value>#0</value>
                                </enumeratedValue>
                                <enumeratedValue>
                                    <name>1</name>
                                    <description>High output</description>
                                    <value>#1</value>
                                </enumeratedValue>
                            </enumeratedValues>
                        </field>
                        <field>
                            <name>POSR09</name>
                            <description>Pmn Output Set</description>
                            <lsb>9</lsb>
                            <msb>9</msb>
                            <access>write-only</access>
                            <enumeratedValues>
                                <enumeratedValue>
                                    <name>0</name>
                                    <description>No effect on output</description>
                                    <value>#0</value>
                                </enumeratedValue>
                                <enumeratedValue>
                                    <name>1</name>
                                    <description>High output</description>
                                    <value>#1</value>
                                </enumeratedValue>
                            </enumeratedValues>
                        </field>
                        <field>
                            <name>POSR10</name>
                            <description>Pmn Output Set</description>
                            <lsb>10</lsb>
                            <msb>10</msb>
                            <access>write-only</access>
                            <enumeratedValues>
                                <enumeratedValue>
                                    <name>0</name>
                                    <description>No effect on output</description>
                                    <value>#0</value>
                                </enumeratedValue>
                                <enumeratedValue>
                                    <name>1</name>
                                    <description>High output</description>
                                    <value>#1</value>
                                </enumeratedValue>
                            </enumeratedValues>
                        </field>
                        <field>
                            <name>POSR11</name>
                            <description>Pmn Output Set</description>
                            <lsb>11</lsb>
                            <msb>11</msb>
                            <access>write-only</access>
                            <enumeratedValues>
                                <enumeratedValue>
                                    <name>0</name>
                                    <description>No effect on output</description>
                                    <value>#0</value>
                                </enumeratedValue>
                                <enumeratedValue>
                                    <name>1</name>
                                    <description>High output</description>
                                    <value>#1</value>
                                </enumeratedValue>
                            </enumeratedValues>
                        </field>
                        <field>
                            <name>POSR12</name>
                            <description>Pmn Output Set</description>
                            <lsb>12</lsb>
                            <msb>12</msb>
                            <access>write-only</access>
                            <enumeratedValues>
                                <enumeratedValue>
                                    <name>0</name>
                                    <description>No effect on output</description>
                                    <value>#0</value>
                                </enumeratedValue>
                                <enumeratedValue>
                                    <name>1</name>
                                    <description>High output</description>
                                    <value>#1</value>
                                </enumeratedValue>
                            </enumeratedValues>
                        </field>
                        <field>
                            <name>POSR13</name>
                            <description>Pmn Output Set</description>
                            <lsb>13</lsb>
                            <msb>13</msb>
                            <access>write-only</access>
                            <enumeratedValues>
                                <enumeratedValue>
                                    <name>0</name>
                                    <description>No effect on output</description>
                                    <value>#0</value>
                                </enumeratedValue>
                                <enumeratedValue>
                                    <name>1</name>
                                    <description>High output</description>
                                    <value>#1</value>
                                </enumeratedValue>
                            </enumeratedValues>
                        </field>
                        <field>
                            <name>POSR14</name>
                            <description>Pmn Output Set</description>
                            <lsb>14</lsb>
                            <msb>14</msb>
                            <access>write-only</access>
                            <enumeratedValues>
                                <enumeratedValue>
                                    <name>0</name>
                                    <description>No effect on output</description>
                                    <value>#0</value>
                                </enumeratedValue>
                                <enumeratedValue>
                                    <name>1</name>
                                    <description>High output</description>
                                    <value>#1</value>
                                </enumeratedValue>
                            </enumeratedValues>
                        </field>
                        <field>
                            <name>POSR15</name>
                            <description>Pmn Output Set</description>
                            <lsb>15</lsb>
                            <msb>15</msb>
                            <access>write-only</access>
                            <enumeratedValues>
                                <enumeratedValue>
                                    <name>0</name>
                                    <description>No effect on output</description>
                                    <value>#0</value>
                                </enumeratedValue>
                                <enumeratedValue>
                                    <name>1</name>
                                    <description>High output</description>
                                    <value>#1</value>
                                </enumeratedValue>
                            </enumeratedValues>
                        </field>
                        <field>
                            <name>PORR00</name>
                            <description>Pmn Output Reset</description>
                            <lsb>16</lsb>
                            <msb>16</msb>
                            <access>write-only</access>
                            <enumeratedValues>
                                <enumeratedValue>
                                    <name>0</name>
                                    <description>No effect on output</description>
                                    <value>#0</value>
                                </enumeratedValue>
                                <enumeratedValue>
                                    <name>1</name>
                                    <description>Low output</description>
                                    <value>#1</value>
                                </enumeratedValue>
                            </enumeratedValues>
                        </field>
                        <field>
                            <name>PORR01</name>
                            <description>Pmn Output Reset</description>
                            <lsb>17</lsb>
                            <msb>17</msb>
                            <access>write-only</access>
                            <enumeratedValues>
                                <enumeratedValue>
                                    <name>0</name>
                                    <description>No effect on output</description>
                                    <value>#0</value>
                                </enumeratedValue>
                                <enumeratedValue>
                                    <name>1</name>
                                    <description>Low output</description>
                                    <value>#1</value>
                                </enumeratedValue>
                            </enumeratedValues>
                        </field>
                        <field>
                            <name>PORR02</name>
                            <description>Pmn Output Reset</description>
                            <lsb>18</lsb>
                            <msb>18</msb>
                            <access>write-only</access>
                            <enumeratedValues>
                                <enumeratedValue>
                                    <name>0</name>
                                    <description>No effect on output</description>
                                    <value>#0</value>
                                </enumeratedValue>
                                <enumeratedValue>
                                    <name>1</name>
                                    <description>Low output</description>
                                    <value>#1</value>
                                </enumeratedValue>
                            </enumeratedValues>
                        </field>
                        <field>
                            <name>PORR03</name>
                            <description>Pmn Output Reset</description>
                            <lsb>19</lsb>
                            <msb>19</msb>
                            <access>write-only</access>
                            <enumeratedValues>
                                <enumeratedValue>
                                    <name>0</name>
                                    <description>No effect on output</description>
                                    <value>#0</value>
                                </enumeratedValue>
                                <enumeratedValue>
                                    <name>1</name>
                                    <description>Low output</description>
                                    <value>#1</value>
                                </enumeratedValue>
                            </enumeratedValues>
                        </field>
                        <field>
                            <name>PORR04</name>
                            <description>Pmn Output Reset</description>
                            <lsb>20</lsb>
                            <msb>20</msb>
                            <access>write-only</access>
                            <enumeratedValues>
                                <enumeratedValue>
                                    <name>0</name>
                                    <description>No effect on output</description>
                                    <value>#0</value>
                                </enumeratedValue>
                                <enumeratedValue>
                                    <name>1</name>
                                    <description>Low output</description>
                                    <value>#1</value>
                                </enumeratedValue>
                            </enumeratedValues>
                        </field>
                        <field>
                            <name>PORR05</name>
                            <description>Pmn Output Reset</description>
                            <lsb>21</lsb>
                            <msb>21</msb>
                            <access>write-only</access>
                            <enumeratedValues>
                                <enumeratedValue>
                                    <name>0</name>
                                    <description>No effect on output</description>
                                    <value>#0</value>
                                </enumeratedValue>
                                <enumeratedValue>
                                    <name>1</name>
                                    <description>Low output</description>
                                    <value>#1</value>
                                </enumeratedValue>
                            </enumeratedValues>
                        </field>
                        <field>
                            <name>PORR06</name>
                            <description>Pmn Output Reset</description>
                            <lsb>22</lsb>
                            <msb>22</msb>
                            <access>write-only</access>
                            <enumeratedValues>
                                <enumeratedValue>
                                    <name>0</name>
                                    <description>No effect on output</description>
                                    <value>#0</value>
                                </enumeratedValue>
                                <enumeratedValue>
                                    <name>1</name>
                                    <description>Low output</description>
                                    <value>#1</value>
                                </enumeratedValue>
                            </enumeratedValues>
                        </field>
                        <field>
                            <name>PORR07</name>
                            <description>Pmn Output Reset</description>
                            <lsb>23</lsb>
                            <msb>23</msb>
                            <access>write-only</access>
                            <enumeratedValues>
                                <enumeratedValue>
                                    <name>0</name>
                                    <description>No effect on output</description>
                                    <value>#0</value>
                                </enumeratedValue>
                                <enumeratedValue>
                                    <name>1</name>
                                    <description>Low output</description>
                                    <value>#1</value>
                                </enumeratedValue>
                            </enumeratedValues>
                        </field>
                        <field>
                            <name>PORR08</name>
                            <description>Pmn Output Reset</description>
                            <lsb>24</lsb>
                            <msb>24</msb>
                            <access>write-only</access>
                            <enumeratedValues>
                                <enumeratedValue>
                                    <name>0</name>
                                    <description>No effect on output</description>
                                    <value>#0</value>
                                </enumeratedValue>
                                <enumeratedValue>
                                    <name>1</name>
                                    <description>Low output</description>
                                    <value>#1</value>
                                </enumeratedValue>
                            </enumeratedValues>
                        </field>
                        <field>
                            <name>PORR09</name>
                            <description>Pmn Output Reset</description>
                            <lsb>25</lsb>
                            <msb>25</msb>
                            <access>write-only</access>
                            <enumeratedValues>
                                <enumeratedValue>
                                    <name>0</name>
                                    <description>No effect on output</description>
                                    <value>#0</value>
                                </enumeratedValue>
                                <enumeratedValue>
                                    <name>1</name>
                                    <description>Low output</description>
                                    <value>#1</value>
                                </enumeratedValue>
                            </enumeratedValues>
                        </field>
                        <field>
                            <name>PORR10</name>
                            <description>Pmn Output Reset</description>
                            <lsb>26</lsb>
                            <msb>26</msb>
                            <access>write-only</access>
                            <enumeratedValues>
                                <enumeratedValue>
                                    <name>0</name>
                                    <description>No effect on output</description>
                                    <value>#0</value>
                                </enumeratedValue>
                                <enumeratedValue>
                                    <name>1</name>
                                    <description>Low output</description>
                                    <value>#1</value>
                                </enumeratedValue>
                            </enumeratedValues>
                        </field>
                        <field>
                            <name>PORR11</name>
                            <description>Pmn Output Reset</description>
                            <lsb>27</lsb>
                            <msb>27</msb>
                            <access>write-only</access>
                            <enumeratedValues>
                                <enumeratedValue>
                                    <name>0</name>
                                    <description>No effect on output</description>
                                    <value>#0</value>
                                </enumeratedValue>
                                <enumeratedValue>
                                    <name>1</name>
                                    <description>Low output</description>
                                    <value>#1</value>
                                </enumeratedValue>
                            </enumeratedValues>
                        </field>
                        <field>
                            <name>PORR12</name>
                            <description>Pmn Output Reset</description>
                            <lsb>28</lsb>
                            <msb>28</msb>
                            <access>write-only</access>
                            <enumeratedValues>
                                <enumeratedValue>
                                    <name>0</name>
                                    <description>No effect on output</description>
                                    <value>#0</value>
                                </enumeratedValue>
                                <enumeratedValue>
                                    <name>1</name>
                                    <description>Low output</description>
                                    <value>#1</value>
                                </enumeratedValue>
                            </enumeratedValues>
                        </field>
                        <field>
                            <name>PORR13</name>
                            <description>Pmn Output Reset</description>
                            <lsb>29</lsb>
                            <msb>29</msb>
                            <access>write-only</access>
                            <enumeratedValues>
                                <enumeratedValue>
                                    <name>0</name>
                                    <description>No effect on output</description>
                                    <value>#0</value>
                                </enumeratedValue>
                                <enumeratedValue>
                                    <name>1</name>
                                    <description>Low output</description>
                                    <value>#1</value>
                                </enumeratedValue>
                            </enumeratedValues>
                        </field>
                        <field>
                            <name>PORR14</name>
                            <description>Pmn Output Reset</description>
                            <lsb>30</lsb>
                            <msb>30</msb>
                            <access>write-only</access>
                            <enumeratedValues>
                                <enumeratedValue>
                                    <name>0</name>
                                    <description>No effect on output</description>
                                    <value>#0</value>
                                </enumeratedValue>
                                <enumeratedValue>
                                    <name>1</name>
                                    <description>Low output</description>
                                    <value>#1</value>
                                </enumeratedValue>
                            </enumeratedValues>
                        </field>
                        <field>
                            <name>PORR15</name>
                            <description>Pmn Output Reset</description>
                            <lsb>31</lsb>
                            <msb>31</msb>
                            <access>write-only</access>
                            <enumeratedValues>
                                <enumeratedValue>
                                    <name>0</name>
                                    <description>No effect on output</description>
                                    <value>#0</value>
                                </enumeratedValue>
                                <enumeratedValue>
                                    <name>1</name>
                                    <description>Low output</description>
                                    <value>#1</value>
                                </enumeratedValue>
                            </enumeratedValues>
                        </field>
                    </fields>
                </register>
                <register>
                    <name>POSR</name>
                    <description>Port Control Register 3</description>
                    <alternateRegister>PCNTR3</alternateRegister>
                    <addressOffset>0x008</addressOffset>
                    <size>16</size>
                    <access>write-only</access>
                    <resetValue>0x0000</resetValue>
                    <resetMask>0xffff</resetMask>
                    <fields>
                        <field>
                            <name>PORR00</name>
                            <description>Pmn Output Reset</description>
                            <lsb>0</lsb>
                            <msb>0</msb>
                            <access>write-only</access>
                            <enumeratedValues>
                                <enumeratedValue>
                                    <name>0</name>
                                    <description>No effect on output</description>
                                    <value>#0</value>
                                </enumeratedValue>
                                <enumeratedValue>
                                    <name>1</name>
                                    <description>Low output</description>
                                    <value>#1</value>
                                </enumeratedValue>
                            </enumeratedValues>
                        </field>
                        <field>
                            <name>PORR01</name>
                            <description>Pmn Output Reset</description>
                            <lsb>1</lsb>
                            <msb>1</msb>
                            <access>write-only</access>
                            <enumeratedValues>
                                <enumeratedValue>
                                    <name>0</name>
                                    <description>No effect on output</description>
                                    <value>#0</value>
                                </enumeratedValue>
                                <enumeratedValue>
                                    <name>1</name>
                                    <description>Low output</description>
                                    <value>#1</value>
                                </enumeratedValue>
                            </enumeratedValues>
                        </field>
                        <field>
                            <name>PORR02</name>
                            <description>Pmn Output Reset</description>
                            <lsb>2</lsb>
                            <msb>2</msb>
                            <access>write-only</access>
                            <enumeratedValues>
                                <enumeratedValue>
                                    <name>0</name>
                                    <description>No effect on output</description>
                                    <value>#0</value>
                                </enumeratedValue>
                                <enumeratedValue>
                                    <name>1</name>
                                    <description>Low output</description>
                                    <value>#1</value>
                                </enumeratedValue>
                            </enumeratedValues>
                        </field>
                        <field>
                            <name>PORR03</name>
                            <description>Pmn Output Reset</description>
                            <lsb>3</lsb>
                            <msb>3</msb>
                            <access>write-only</access>
                            <enumeratedValues>
                                <enumeratedValue>
                                    <name>0</name>
                                    <description>No effect on output</description>
                                    <value>#0</value>
                                </enumeratedValue>
                                <enumeratedValue>
                                    <name>1</name>
                                    <description>Low output</description>
                                    <value>#1</value>
                                </enumeratedValue>
                            </enumeratedValues>
                        </field>
                        <field>
                            <name>PORR04</name>
                            <description>Pmn Output Reset</description>
                            <lsb>4</lsb>
                            <msb>4</msb>
                            <access>write-only</access>
                            <enumeratedValues>
                                <enumeratedValue>
                                    <name>0</name>
                                    <description>No effect on output</description>
                                    <value>#0</value>
                                </enumeratedValue>
                                <enumeratedValue>
                                    <name>1</name>
                                    <description>Low output</description>
                                    <value>#1</value>
                                </enumeratedValue>
                            </enumeratedValues>
                        </field>
                        <field>
                            <name>PORR05</name>
                            <description>Pmn Output Reset</description>
                            <lsb>5</lsb>
                            <msb>5</msb>
                            <access>write-only</access>
                            <enumeratedValues>
                                <enumeratedValue>
                                    <name>0</name>
                                    <description>No effect on output</description>
                                    <value>#0</value>
                                </enumeratedValue>
                                <enumeratedValue>
                                    <name>1</name>
                                    <description>Low output</description>
                                    <value>#1</value>
                                </enumeratedValue>
                            </enumeratedValues>
                        </field>
                        <field>
                            <name>PORR06</name>
                            <description>Pmn Output Reset</description>
                            <lsb>6</lsb>
                            <msb>6</msb>
                            <access>write-only</access>
                            <enumeratedValues>
                                <enumeratedValue>
                                    <name>0</name>
                                    <description>No effect on output</description>
                                    <value>#0</value>
                                </enumeratedValue>
                                <enumeratedValue>
                                    <name>1</name>
                                    <description>Low output</description>
                                    <value>#1</value>
                                </enumeratedValue>
                            </enumeratedValues>
                        </field>
                        <field>
                            <name>PORR07</name>
                            <description>Pmn Output Reset</description>
                            <lsb>7</lsb>
                            <msb>7</msb>
                            <access>write-only</access>
                            <enumeratedValues>
                                <enumeratedValue>
                                    <name>0</name>
                                    <description>No effect on output</description>
                                    <value>#0</value>
                                </enumeratedValue>
                                <enumeratedValue>
                                    <name>1</name>
                                    <description>Low output</description>
                                    <value>#1</value>
                                </enumeratedValue>
                            </enumeratedValues>
                        </field>
                        <field>
                            <name>PORR08</name>
                            <description>Pmn Output Reset</description>
                            <lsb>8</lsb>
                            <msb>8</msb>
                            <access>write-only</access>
                            <enumeratedValues>
                                <enumeratedValue>
                                    <name>0</name>
                                    <description>No effect on output</description>
                                    <value>#0</value>
                                </enumeratedValue>
                                <enumeratedValue>
                                    <name>1</name>
                                    <description>Low output</description>
                                    <value>#1</value>
                                </enumeratedValue>
                            </enumeratedValues>
                        </field>
                        <field>
                            <name>PORR09</name>
                            <description>Pmn Output Reset</description>
                            <lsb>9</lsb>
                            <msb>9</msb>
                            <access>write-only</access>
                            <enumeratedValues>
                                <enumeratedValue>
                                    <name>0</name>
                                    <description>No effect on output</description>
                                    <value>#0</value>
                                </enumeratedValue>
                                <enumeratedValue>
                                    <name>1</name>
                                    <description>Low output</description>
                                    <value>#1</value>
                                </enumeratedValue>
                            </enumeratedValues>
                        </field>
                        <field>
                            <name>PORR10</name>
                            <description>Pmn Output Reset</description>
                            <lsb>10</lsb>
                            <msb>10</msb>
                            <access>write-only</access>
                            <enumeratedValues>
                                <enumeratedValue>
                                    <name>0</name>
                                    <description>No effect on output</description>
                                    <value>#0</value>
                                </enumeratedValue>
                                <enumeratedValue>
                                    <name>1</name>
                                    <description>Low output</description>
                                    <value>#1</value>
                                </enumeratedValue>
                            </enumeratedValues>
                        </field>
                        <field>
                            <name>PORR11</name>
                            <description>Pmn Output Reset</description>
                            <lsb>11</lsb>
                            <msb>11</msb>
                            <access>write-only</access>
                            <enumeratedValues>
                                <enumeratedValue>
                                    <name>0</name>
                                    <description>No effect on output</description>
                                    <value>#0</value>
                                </enumeratedValue>
                                <enumeratedValue>
                                    <name>1</name>
                                    <description>Low output</description>
                                    <value>#1</value>
                                </enumeratedValue>
                            </enumeratedValues>
                        </field>
                        <field>
                            <name>PORR12</name>
                            <description>Pmn Output Reset</description>
                            <lsb>12</lsb>
                            <msb>12</msb>
                            <access>write-only</access>
                            <enumeratedValues>
                                <enumeratedValue>
                                    <name>0</name>
                                    <description>No effect on output</description>
                                    <value>#0</value>
                                </enumeratedValue>
                                <enumeratedValue>
                                    <name>1</name>
                                    <description>Low output</description>
                                    <value>#1</value>
                                </enumeratedValue>
                            </enumeratedValues>
                        </field>
                        <field>
                            <name>PORR13</name>
                            <description>Pmn Output Reset</description>
                            <lsb>13</lsb>
                            <msb>13</msb>
                            <access>write-only</access>
                            <enumeratedValues>
                                <enumeratedValue>
                                    <name>0</name>
                                    <description>No effect on output</description>
                                    <value>#0</value>
                                </enumeratedValue>
                                <enumeratedValue>
                                    <name>1</name>
                                    <description>Low output</description>
                                    <value>#1</value>
                                </enumeratedValue>
                            </enumeratedValues>
                        </field>
                        <field>
                            <name>PORR14</name>
                            <description>Pmn Output Reset</description>
                            <lsb>14</lsb>
                            <msb>14</msb>
                            <access>write-only</access>
                            <enumeratedValues>
                                <enumeratedValue>
                                    <name>0</name>
                                    <description>No effect on output</description>
                                    <value>#0</value>
                                </enumeratedValue>
                                <enumeratedValue>
                                    <name>1</name>
                                    <description>Low output</description>
                                    <value>#1</value>
                                </enumeratedValue>
                            </enumeratedValues>
                        </field>
                        <field>
                            <name>PORR15</name>
                            <description>Pmn Output Reset</description>
                            <lsb>15</lsb>
                            <msb>15</msb>
                            <access>write-only</access>
                            <enumeratedValues>
                                <enumeratedValue>
                                    <name>0</name>
                                    <description>No effect on output</description>
                                    <value>#0</value>
                                </enumeratedValue>
                                <enumeratedValue>
                                    <name>1</name>
                                    <description>Low output</description>
                                    <value>#1</value>
                                </enumeratedValue>
                            </enumeratedValues>
                        </field>
                    </fields>
                </register>
                <register>
                    <name>PORR</name>
                    <description>Port Control Register 3</description>
                    <alternateRegister>PCNTR3</alternateRegister>
                    <addressOffset>0x00A</addressOffset>
                    <size>16</size>
                    <access>write-only</access>
                    <resetValue>0x0000</resetValue>
                    <resetMask>0xffff</resetMask>
                    <fields>
                        <field>
                            <name>POSR00</name>
                            <description>Pmn Output Set</description>
                            <lsb>0</lsb>
                            <msb>0</msb>
                            <access>write-only</access>
                            <enumeratedValues>
                                <enumeratedValue>
                                    <name>0</name>
                                    <description>No effect on output</description>
                                    <value>#0</value>
                                </enumeratedValue>
                                <enumeratedValue>
                                    <name>1</name>
                                    <description>High output</description>
                                    <value>#1</value>
                                </enumeratedValue>
                            </enumeratedValues>
                        </field>
                        <field>
                            <name>POSR01</name>
                            <description>Pmn Output Set</description>
                            <lsb>1</lsb>
                            <msb>1</msb>
                            <access>write-only</access>
                            <enumeratedValues>
                                <enumeratedValue>
                                    <name>0</name>
                                    <description>No effect on output</description>
                                    <value>#0</value>
                                </enumeratedValue>
                                <enumeratedValue>
                                    <name>1</name>
                                    <description>High output</description>
                                    <value>#1</value>
                                </enumeratedValue>
                            </enumeratedValues>
                        </field>
                        <field>
                            <name>POSR02</name>
                            <description>Pmn Output Set</description>
                            <lsb>2</lsb>
                            <msb>2</msb>
                            <access>write-only</access>
                            <enumeratedValues>
                                <enumeratedValue>
                                    <name>0</name>
                                    <description>No effect on output</description>
                                    <value>#0</value>
                                </enumeratedValue>
                                <enumeratedValue>
                                    <name>1</name>
                                    <description>High output</description>
                                    <value>#1</value>
                                </enumeratedValue>
                            </enumeratedValues>
                        </field>
                        <field>
                            <name>POSR03</name>
                            <description>Pmn Output Set</description>
                            <lsb>3</lsb>
                            <msb>3</msb>
                            <access>write-only</access>
                            <enumeratedValues>
                                <enumeratedValue>
                                    <name>0</name>
                                    <description>No effect on output</description>
                                    <value>#0</value>
                                </enumeratedValue>
                                <enumeratedValue>
                                    <name>1</name>
                                    <description>High output</description>
                                    <value>#1</value>
                                </enumeratedValue>
                            </enumeratedValues>
                        </field>
                        <field>
                            <name>POSR04</name>
                            <description>Pmn Output Set</description>
                            <lsb>4</lsb>
                            <msb>4</msb>
                            <access>write-only</access>
                            <enumeratedValues>
                                <enumeratedValue>
                                    <name>0</name>
                                    <description>No effect on output</description>
                                    <value>#0</value>
                                </enumeratedValue>
                                <enumeratedValue>
                                    <name>1</name>
                                    <description>High output</description>
                                    <value>#1</value>
                                </enumeratedValue>
                            </enumeratedValues>
                        </field>
                        <field>
                            <name>POSR05</name>
                            <description>Pmn Output Set</description>
                            <lsb>5</lsb>
                            <msb>5</msb>
                            <access>write-only</access>
                            <enumeratedValues>
                                <enumeratedValue>
                                    <name>0</name>
                                    <description>No effect on output</description>
                                    <value>#0</value>
                                </enumeratedValue>
                                <enumeratedValue>
                                    <name>1</name>
                                    <description>High output</description>
                                    <value>#1</value>
                                </enumeratedValue>
                            </enumeratedValues>
                        </field>
                        <field>
                            <name>POSR06</name>
                            <description>Pmn Output Set</description>
                            <lsb>6</lsb>
                            <msb>6</msb>
                            <access>write-only</access>
                            <enumeratedValues>
                                <enumeratedValue>
                                    <name>0</name>
                                    <description>No effect on output</description>
                                    <value>#0</value>
                                </enumeratedValue>
                                <enumeratedValue>
                                    <name>1</name>
                                    <description>High output</description>
                                    <value>#1</value>
                                </enumeratedValue>
                            </enumeratedValues>
                        </field>
                        <field>
                            <name>POSR07</name>
                            <description>Pmn Output Set</description>
                            <lsb>7</lsb>
                            <msb>7</msb>
                            <access>write-only</access>
                            <enumeratedValues>
                                <enumeratedValue>
                                    <name>0</name>
                                    <description>No effect on output</description>
                                    <value>#0</value>
                                </enumeratedValue>
                                <enumeratedValue>
                                    <name>1</name>
                                    <description>High output</description>
                                    <value>#1</value>
                                </enumeratedValue>
                            </enumeratedValues>
                        </field>
                        <field>
                            <name>POSR08</name>
                            <description>Pmn Output Set</description>
                            <lsb>8</lsb>
                            <msb>8</msb>
                            <access>write-only</access>
                            <enumeratedValues>
                                <enumeratedValue>
                                    <name>0</name>
                                    <description>No effect on output</description>
                                    <value>#0</value>
                                </enumeratedValue>
                                <enumeratedValue>
                                    <name>1</name>
                                    <description>High output</description>
                                    <value>#1</value>
                                </enumeratedValue>
                            </enumeratedValues>
                        </field>
                        <field>
                            <name>POSR09</name>
                            <description>Pmn Output Set</description>
                            <lsb>9</lsb>
                            <msb>9</msb>
                            <access>write-only</access>
                            <enumeratedValues>
                                <enumeratedValue>
                                    <name>0</name>
                                    <description>No effect on output</description>
                                    <value>#0</value>
                                </enumeratedValue>
                                <enumeratedValue>
                                    <name>1</name>
                                    <description>High output</description>
                                    <value>#1</value>
                                </enumeratedValue>
                            </enumeratedValues>
                        </field>
                        <field>
                            <name>POSR10</name>
                            <description>Pmn Output Set</description>
                            <lsb>10</lsb>
                            <msb>10</msb>
                            <access>write-only</access>
                            <enumeratedValues>
                                <enumeratedValue>
                                    <name>0</name>
                                    <description>No effect on output</description>
                                    <value>#0</value>
                                </enumeratedValue>
                                <enumeratedValue>
                                    <name>1</name>
                                    <description>High output</description>
                                    <value>#1</value>
                                </enumeratedValue>
                            </enumeratedValues>
                        </field>
                        <field>
                            <name>POSR11</name>
                            <description>Pmn Output Set</description>
                            <lsb>11</lsb>
                            <msb>11</msb>
                            <access>write-only</access>
                            <enumeratedValues>
                                <enumeratedValue>
                                    <name>0</name>
                                    <description>No effect on output</description>
                                    <value>#0</value>
                                </enumeratedValue>
                                <enumeratedValue>
                                    <name>1</name>
                                    <description>High output</description>
                                    <value>#1</value>
                                </enumeratedValue>
                            </enumeratedValues>
                        </field>
                        <field>
                            <name>POSR12</name>
                            <description>Pmn Output Set</description>
                            <lsb>12</lsb>
                            <msb>12</msb>
                            <access>write-only</access>
                            <enumeratedValues>
                                <enumeratedValue>
                                    <name>0</name>
                                    <description>No effect on output</description>
                                    <value>#0</value>
                                </enumeratedValue>
                                <enumeratedValue>
                                    <name>1</name>
                                    <description>High output</description>
                                    <value>#1</value>
                                </enumeratedValue>
                            </enumeratedValues>
                        </field>
                        <field>
                            <name>POSR13</name>
                            <description>Pmn Output Set</description>
                            <lsb>13</lsb>
                            <msb>13</msb>
                            <access>write-only</access>
                            <enumeratedValues>
                                <enumeratedValue>
                                    <name>0</name>
                                    <description>No effect on output</description>
                                    <value>#0</value>
                                </enumeratedValue>
                                <enumeratedValue>
                                    <name>1</name>
                                    <description>High output</description>
                                    <value>#1</value>
                                </enumeratedValue>
                            </enumeratedValues>
                        </field>
                        <field>
                            <name>POSR14</name>
                            <description>Pmn Output Set</description>
                            <lsb>14</lsb>
                            <msb>14</msb>
                            <access>write-only</access>
                            <enumeratedValues>
                                <enumeratedValue>
                                    <name>0</name>
                                    <description>No effect on output</description>
                                    <value>#0</value>
                                </enumeratedValue>
                                <enumeratedValue>
                                    <name>1</name>
                                    <description>High output</description>
                                    <value>#1</value>
                                </enumeratedValue>
                            </enumeratedValues>
                        </field>
                        <field>
                            <name>POSR15</name>
                            <description>Pmn Output Set</description>
                            <lsb>15</lsb>
                            <msb>15</msb>
                            <access>write-only</access>
                            <enumeratedValues>
                                <enumeratedValue>
                                    <name>0</name>
                                    <description>No effect on output</description>
                                    <value>#0</value>
                                </enumeratedValue>
                                <enumeratedValue>
                                    <name>1</name>
                                    <description>High output</description>
                                    <value>#1</value>
                                </enumeratedValue>
                            </enumeratedValues>
                        </field>
                    </fields>
                </register>
            </registers>
        </peripheral>
        <peripheral>
            <name>PORT1</name>
            <description>Pmn Pin Function Port 1 Control Registers Pmn Pin Function Control Register</description>
            <baseAddress>0x40400020</baseAddress>
            <addressBlock>
                <offset>0x00</offset>
                <size>16</size>
                <usage>registers</usage>
            </addressBlock>
            <registers>
                <register>
                    <name>PCNTR1</name>
                    <description>Port Control Register 1</description>
                    <addressOffset>0x000</addressOffset>
                    <size>32</size>
                    <access>read-write</access>
                    <resetValue>0x00000000</resetValue>
                    <resetMask>0xffffffff</resetMask>
                    <fields>
                        <field>
                            <name>PDR00</name>
                            <description>Pmn Direction</description>
                            <lsb>0</lsb>
                            <msb>0</msb>
                            <access>read-write</access>
                            <enumeratedValues>
                                <enumeratedValue>
                                    <name>0</name>
                                    <description>Input (functions as an input pin)</description>
                                    <value>#0</value>
                                </enumeratedValue>
                                <enumeratedValue>
                                    <name>1</name>
                                    <description>Output (functions as an output pin)</description>
                                    <value>#1</value>
                                </enumeratedValue>
                            </enumeratedValues>
                        </field>
                        <field>
                            <name>PDR01</name>
                            <description>Pmn Direction</description>
                            <lsb>1</lsb>
                            <msb>1</msb>
                            <access>read-write</access>
                            <enumeratedValues>
                                <enumeratedValue>
                                    <name>0</name>
                                    <description>Input (functions as an input pin)</description>
                                    <value>#0</value>
                                </enumeratedValue>
                                <enumeratedValue>
                                    <name>1</name>
                                    <description>Output (functions as an output pin)</description>
                                    <value>#1</value>
                                </enumeratedValue>
                            </enumeratedValues>
                        </field>
                        <field>
                            <name>PDR02</name>
                            <description>Pmn Direction</description>
                            <lsb>2</lsb>
                            <msb>2</msb>
                            <access>read-write</access>
                            <enumeratedValues>
                                <enumeratedValue>
                                    <name>0</name>
                                    <description>Input (functions as an input pin)</description>
                                    <value>#0</value>
                                </enumeratedValue>
                                <enumeratedValue>
                                    <name>1</name>
                                    <description>Output (functions as an output pin)</description>
                                    <value>#1</value>
                                </enumeratedValue>
                            </enumeratedValues>
                        </field>
                        <field>
                            <name>PDR03</name>
                            <description>Pmn Direction</description>
                            <lsb>3</lsb>
                            <msb>3</msb>
                            <access>read-write</access>
                            <enumeratedValues>
                                <enumeratedValue>
                                    <name>0</name>
                                    <description>Input (functions as an input pin)</description>
                                    <value>#0</value>
                                </enumeratedValue>
                                <enumeratedValue>
                                    <name>1</name>
                                    <description>Output (functions as an output pin)</description>
                                    <value>#1</value>
                                </enumeratedValue>
                            </enumeratedValues>
                        </field>
                        <field>
                            <name>PDR04</name>
                            <description>Pmn Direction</description>
                            <lsb>4</lsb>
                            <msb>4</msb>
                            <access>read-write</access>
                            <enumeratedValues>
                                <enumeratedValue>
                                    <name>0</name>
                                    <description>Input (functions as an input pin)</description>
                                    <value>#0</value>
                                </enumeratedValue>
                                <enumeratedValue>
                                    <name>1</name>
                                    <description>Output (functions as an output pin)</description>
                                    <value>#1</value>
                                </enumeratedValue>
                            </enumeratedValues>
                        </field>
                        <field>
                            <name>PDR05</name>
                            <description>Pmn Direction</description>
                            <lsb>5</lsb>
                            <msb>5</msb>
                            <access>read-write</access>
                            <enumeratedValues>
                                <enumeratedValue>
                                    <name>0</name>
                                    <description>Input (functions as an input pin)</description>
                                    <value>#0</value>
                                </enumeratedValue>
                                <enumeratedValue>
                                    <name>1</name>
                                    <description>Output (functions as an output pin)</description>
                                    <value>#1</value>
                                </enumeratedValue>
                            </enumeratedValues>
                        </field>
                        <field>
                            <name>PDR06</name>
                            <description>Pmn Direction</description>
                            <lsb>6</lsb>
                            <msb>6</msb>
                            <access>read-write</access>
                            <enumeratedValues>
                                <enumeratedValue>
                                    <name>0</name>
                                    <description>Input (functions as an input pin)</description>
                                    <value>#0</value>
                                </enumeratedValue>
                                <enumeratedValue>
                                    <name>1</name>
                                    <description>Output (functions as an output pin)</description>
                                    <value>#1</value>
                                </enumeratedValue>
                            </enumeratedValues>
                        </field>
                        <field>
                            <name>PDR07</name>
                            <description>Pmn Direction</description>
                            <lsb>7</lsb>
                            <msb>7</msb>
                            <access>read-write</access>
                            <enumeratedValues>
                                <enumeratedValue>
                                    <name>0</name>
                                    <description>Input (functions as an input pin)</description>
                                    <value>#0</value>
                                </enumeratedValue>
                                <enumeratedValue>
                                    <name>1</name>
                                    <description>Output (functions as an output pin)</description>
                                    <value>#1</value>
                                </enumeratedValue>
                            </enumeratedValues>
                        </field>
                        <field>
                            <name>PDR08</name>
                            <description>Pmn Direction</description>
                            <lsb>8</lsb>
                            <msb>8</msb>
                            <access>read-write</access>
                            <enumeratedValues>
                                <enumeratedValue>
                                    <name>0</name>
                                    <description>Input (functions as an input pin)</description>
                                    <value>#0</value>
                                </enumeratedValue>
                                <enumeratedValue>
                                    <name>1</name>
                                    <description>Output (functions as an output pin)</description>
                                    <value>#1</value>
                                </enumeratedValue>
                            </enumeratedValues>
                        </field>
                        <field>
                            <name>PDR09</name>
                            <description>Pmn Direction</description>
                            <lsb>9</lsb>
                            <msb>9</msb>
                            <access>read-write</access>
                            <enumeratedValues>
                                <enumeratedValue>
                                    <name>0</name>
                                    <description>Input (functions as an input pin)</description>
                                    <value>#0</value>
                                </enumeratedValue>
                                <enumeratedValue>
                                    <name>1</name>
                                    <description>Output (functions as an output pin)</description>
                                    <value>#1</value>
                                </enumeratedValue>
                            </enumeratedValues>
                        </field>
                        <field>
                            <name>PDR10</name>
                            <description>Pmn Direction</description>
                            <lsb>10</lsb>
                            <msb>10</msb>
                            <access>read-write</access>
                            <enumeratedValues>
                                <enumeratedValue>
                                    <name>0</name>
                                    <description>Input (functions as an input pin)</description>
                                    <value>#0</value>
                                </enumeratedValue>
                                <enumeratedValue>
                                    <name>1</name>
                                    <description>Output (functions as an output pin)</description>
                                    <value>#1</value>
                                </enumeratedValue>
                            </enumeratedValues>
                        </field>
                        <field>
                            <name>PDR11</name>
                            <description>Pmn Direction</description>
                            <lsb>11</lsb>
                            <msb>11</msb>
                            <access>read-write</access>
                            <enumeratedValues>
                                <enumeratedValue>
                                    <name>0</name>
                                    <description>Input (functions as an input pin)</description>
                                    <value>#0</value>
                                </enumeratedValue>
                                <enumeratedValue>
                                    <name>1</name>
                                    <description>Output (functions as an output pin)</description>
                                    <value>#1</value>
                                </enumeratedValue>
                            </enumeratedValues>
                        </field>
                        <field>
                            <name>PDR12</name>
                            <description>Pmn Direction</description>
                            <lsb>12</lsb>
                            <msb>12</msb>
                            <access>read-write</access>
                            <enumeratedValues>
                                <enumeratedValue>
                                    <name>0</name>
                                    <description>Input (functions as an input pin)</description>
                                    <value>#0</value>
                                </enumeratedValue>
                                <enumeratedValue>
                                    <name>1</name>
                                    <description>Output (functions as an output pin)</description>
                                    <value>#1</value>
                                </enumeratedValue>
                            </enumeratedValues>
                        </field>
                        <field>
                            <name>PDR13</name>
                            <description>Pmn Direction</description>
                            <lsb>13</lsb>
                            <msb>13</msb>
                            <access>read-write</access>
                            <enumeratedValues>
                                <enumeratedValue>
                                    <name>0</name>
                                    <description>Input (functions as an input pin)</description>
                                    <value>#0</value>
                                </enumeratedValue>
                                <enumeratedValue>
                                    <name>1</name>
                                    <description>Output (functions as an output pin)</description>
                                    <value>#1</value>
                                </enumeratedValue>
                            </enumeratedValues>
                        </field>
                        <field>
                            <name>PDR14</name>
                            <description>Pmn Direction</description>
                            <lsb>14</lsb>
                            <msb>14</msb>
                            <access>read-write</access>
                            <enumeratedValues>
                                <enumeratedValue>
                                    <name>0</name>
                                    <description>Input (functions as an input pin)</description>
                                    <value>#0</value>
                                </enumeratedValue>
                                <enumeratedValue>
                                    <name>1</name>
                                    <description>Output (functions as an output pin)</description>
                                    <value>#1</value>
                                </enumeratedValue>
                            </enumeratedValues>
                        </field>
                        <field>
                            <name>PDR15</name>
                            <description>Pmn Direction</description>
                            <lsb>15</lsb>
                            <msb>15</msb>
                            <access>read-write</access>
                            <enumeratedValues>
                                <enumeratedValue>
                                    <name>0</name>
                                    <description>Input (functions as an input pin)</description>
                                    <value>#0</value>
                                </enumeratedValue>
                                <enumeratedValue>
                                    <name>1</name>
                                    <description>Output (functions as an output pin)</description>
                                    <value>#1</value>
                                </enumeratedValue>
                            </enumeratedValues>
                        </field>
                        <field>
                            <name>PODR00</name>
                            <description>Pmn Output Data</description>
                            <lsb>16</lsb>
                            <msb>16</msb>
                            <access>read-write</access>
                            <enumeratedValues>
                                <enumeratedValue>
                                    <name>0</name>
                                    <description>Low output</description>
                                    <value>#0</value>
                                </enumeratedValue>
                                <enumeratedValue>
                                    <name>1</name>
                                    <description>High output</description>
                                    <value>#1</value>
                                </enumeratedValue>
                            </enumeratedValues>
                        </field>
                        <field>
                            <name>PODR01</name>
                            <description>Pmn Output Data</description>
                            <lsb>17</lsb>
                            <msb>17</msb>
                            <access>read-write</access>
                            <enumeratedValues>
                                <enumeratedValue>
                                    <name>0</name>
                                    <description>Low output</description>
                                    <value>#0</value>
                                </enumeratedValue>
                                <enumeratedValue>
                                    <name>1</name>
                                    <description>High output</description>
                                    <value>#1</value>
                                </enumeratedValue>
                            </enumeratedValues>
                        </field>
                        <field>
                            <name>PODR02</name>
                            <description>Pmn Output Data</description>
                            <lsb>18</lsb>
                            <msb>18</msb>
                            <access>read-write</access>
                            <enumeratedValues>
                                <enumeratedValue>
                                    <name>0</name>
                                    <description>Low output</description>
                                    <value>#0</value>
                                </enumeratedValue>
                                <enumeratedValue>
                                    <name>1</name>
                                    <description>High output</description>
                                    <value>#1</value>
                                </enumeratedValue>
                            </enumeratedValues>
                        </field>
                        <field>
                            <name>PODR03</name>
                            <description>Pmn Output Data</description>
                            <lsb>19</lsb>
                            <msb>19</msb>
                            <access>read-write</access>
                            <enumeratedValues>
                                <enumeratedValue>
                                    <name>0</name>
                                    <description>Low output</description>
                                    <value>#0</value>
                                </enumeratedValue>
                                <enumeratedValue>
                                    <name>1</name>
                                    <description>High output</description>
                                    <value>#1</value>
                                </enumeratedValue>
                            </enumeratedValues>
                        </field>
                        <field>
                            <name>PODR04</name>
                            <description>Pmn Output Data</description>
                            <lsb>20</lsb>
                            <msb>20</msb>
                            <access>read-write</access>
                            <enumeratedValues>
                                <enumeratedValue>
                                    <name>0</name>
                                    <description>Low output</description>
                                    <value>#0</value>
                                </enumeratedValue>
                                <enumeratedValue>
                                    <name>1</name>
                                    <description>High output</description>
                                    <value>#1</value>
                                </enumeratedValue>
                            </enumeratedValues>
                        </field>
                        <field>
                            <name>PODR05</name>
                            <description>Pmn Output Data</description>
                            <lsb>21</lsb>
                            <msb>21</msb>
                            <access>read-write</access>
                            <enumeratedValues>
                                <enumeratedValue>
                                    <name>0</name>
                                    <description>Low output</description>
                                    <value>#0</value>
                                </enumeratedValue>
                                <enumeratedValue>
                                    <name>1</name>
                                    <description>High output</description>
                                    <value>#1</value>
                                </enumeratedValue>
                            </enumeratedValues>
                        </field>
                        <field>
                            <name>PODR06</name>
                            <description>Pmn Output Data</description>
                            <lsb>22</lsb>
                            <msb>22</msb>
                            <access>read-write</access>
                            <enumeratedValues>
                                <enumeratedValue>
                                    <name>0</name>
                                    <description>Low output</description>
                                    <value>#0</value>
                                </enumeratedValue>
                                <enumeratedValue>
                                    <name>1</name>
                                    <description>High output</description>
                                    <value>#1</value>
                                </enumeratedValue>
                            </enumeratedValues>
                        </field>
                        <field>
                            <name>PODR07</name>
                            <description>Pmn Output Data</description>
                            <lsb>23</lsb>
                            <msb>23</msb>
                            <access>read-write</access>
                            <enumeratedValues>
                                <enumeratedValue>
                                    <name>0</name>
                                    <description>Low output</description>
                                    <value>#0</value>
                                </enumeratedValue>
                                <enumeratedValue>
                                    <name>1</name>
                                    <description>High output</description>
                                    <value>#1</value>
                                </enumeratedValue>
                            </enumeratedValues>
                        </field>
                        <field>
                            <name>PODR08</name>
                            <description>Pmn Output Data</description>
                            <lsb>24</lsb>
                            <msb>24</msb>
                            <access>read-write</access>
                            <enumeratedValues>
                                <enumeratedValue>
                                    <name>0</name>
                                    <description>Low output</description>
                                    <value>#0</value>
                                </enumeratedValue>
                                <enumeratedValue>
                                    <name>1</name>
                                    <description>High output</description>
                                    <value>#1</value>
                                </enumeratedValue>
                            </enumeratedValues>
                        </field>
                        <field>
                            <name>PODR09</name>
                            <description>Pmn Output Data</description>
                            <lsb>25</lsb>
                            <msb>25</msb>
                            <access>read-write</access>
                            <enumeratedValues>
                                <enumeratedValue>
                                    <name>0</name>
                                    <description>Low output</description>
                                    <value>#0</value>
                                </enumeratedValue>
                                <enumeratedValue>
                                    <name>1</name>
                                    <description>High output</description>
                                    <value>#1</value>
                                </enumeratedValue>
                            </enumeratedValues>
                        </field>
                        <field>
                            <name>PODR10</name>
                            <description>Pmn Output Data</description>
                            <lsb>26</lsb>
                            <msb>26</msb>
                            <access>read-write</access>
                            <enumeratedValues>
                                <enumeratedValue>
                                    <name>0</name>
                                    <description>Low output</description>
                                    <value>#0</value>
                                </enumeratedValue>
                                <enumeratedValue>
                                    <name>1</name>
                                    <description>High output</description>
                                    <value>#1</value>
                                </enumeratedValue>
                            </enumeratedValues>
                        </field>
                        <field>
                            <name>PODR11</name>
                            <description>Pmn Output Data</description>
                            <lsb>27</lsb>
                            <msb>27</msb>
                            <access>read-write</access>
                            <enumeratedValues>
                                <enumeratedValue>
                                    <name>0</name>
                                    <description>Low output</description>
                                    <value>#0</value>
                                </enumeratedValue>
                                <enumeratedValue>
                                    <name>1</name>
                                    <description>High output</description>
                                    <value>#1</value>
                                </enumeratedValue>
                            </enumeratedValues>
                        </field>
                        <field>
                            <name>PODR12</name>
                            <description>Pmn Output Data</description>
                            <lsb>28</lsb>
                            <msb>28</msb>
                            <access>read-write</access>
                            <enumeratedValues>
                                <enumeratedValue>
                                    <name>0</name>
                                    <description>Low output</description>
                                    <value>#0</value>
                                </enumeratedValue>
                                <enumeratedValue>
                                    <name>1</name>
                                    <description>High output</description>
                                    <value>#1</value>
                                </enumeratedValue>
                            </enumeratedValues>
                        </field>
                        <field>
                            <name>PODR13</name>
                            <description>Pmn Output Data</description>
                            <lsb>29</lsb>
                            <msb>29</msb>
                            <access>read-write</access>
                            <enumeratedValues>
                                <enumeratedValue>
                                    <name>0</name>
                                    <description>Low output</description>
                                    <value>#0</value>
                                </enumeratedValue>
                                <enumeratedValue>
                                    <name>1</name>
                                    <description>High output</description>
                                    <value>#1</value>
                                </enumeratedValue>
                            </enumeratedValues>
                        </field>
                        <field>
                            <name>PODR14</name>
                            <description>Pmn Output Data</description>
                            <lsb>30</lsb>
                            <msb>30</msb>
                            <access>read-write</access>
                            <enumeratedValues>
                                <enumeratedValue>
                                    <name>0</name>
                                    <description>Low output</description>
                                    <value>#0</value>
                                </enumeratedValue>
                                <enumeratedValue>
                                    <name>1</name>
                                    <description>High output</description>
                                    <value>#1</value>
                                </enumeratedValue>
                            </enumeratedValues>
                        </field>
                        <field>
                            <name>PODR15</name>
                            <description>Pmn Output Data</description>
                            <lsb>31</lsb>
                            <msb>31</msb>
                            <access>read-write</access>
                            <enumeratedValues>
                                <enumeratedValue>
                                    <name>0</name>
                                    <description>Low output</description>
                                    <value>#0</value>
                                </enumeratedValue>
                                <enumeratedValue>
                                    <name>1</name>
                                    <description>High output</description>
                                    <value>#1</value>
                                </enumeratedValue>
                            </enumeratedValues>
                        </field>
                    </fields>
                </register>
                <register>
                    <name>PDR</name>
                    <description>Port Control Register 1</description>
                    <alternateRegister>PCNTR1</alternateRegister>
                    <addressOffset>0x000</addressOffset>
                    <size>16</size>
                    <access>read-write</access>
                    <resetValue>0x0000</resetValue>
                    <resetMask>0xffff</resetMask>
                    <fields>
                        <field>
                            <name>PODR00</name>
                            <description>Pmn Output Data</description>
                            <lsb>0</lsb>
                            <msb>0</msb>
                            <access>read-write</access>
                            <enumeratedValues>
                                <enumeratedValue>
                                    <name>0</name>
                                    <description>Low output</description>
                                    <value>#0</value>
                                </enumeratedValue>
                                <enumeratedValue>
                                    <name>1</name>
                                    <description>High output</description>
                                    <value>#1</value>
                                </enumeratedValue>
                            </enumeratedValues>
                        </field>
                        <field>
                            <name>PODR01</name>
                            <description>Pmn Output Data</description>
                            <lsb>1</lsb>
                            <msb>1</msb>
                            <access>read-write</access>
                            <enumeratedValues>
                                <enumeratedValue>
                                    <name>0</name>
                                    <description>Low output</description>
                                    <value>#0</value>
                                </enumeratedValue>
                                <enumeratedValue>
                                    <name>1</name>
                                    <description>High output</description>
                                    <value>#1</value>
                                </enumeratedValue>
                            </enumeratedValues>
                        </field>
                        <field>
                            <name>PODR02</name>
                            <description>Pmn Output Data</description>
                            <lsb>2</lsb>
                            <msb>2</msb>
                            <access>read-write</access>
                            <enumeratedValues>
                                <enumeratedValue>
                                    <name>0</name>
                                    <description>Low output</description>
                                    <value>#0</value>
                                </enumeratedValue>
                                <enumeratedValue>
                                    <name>1</name>
                                    <description>High output</description>
                                    <value>#1</value>
                                </enumeratedValue>
                            </enumeratedValues>
                        </field>
                        <field>
                            <name>PODR03</name>
                            <description>Pmn Output Data</description>
                            <lsb>3</lsb>
                            <msb>3</msb>
                            <access>read-write</access>
                            <enumeratedValues>
                                <enumeratedValue>
                                    <name>0</name>
                                    <description>Low output</description>
                                    <value>#0</value>
                                </enumeratedValue>
                                <enumeratedValue>
                                    <name>1</name>
                                    <description>High output</description>
                                    <value>#1</value>
                                </enumeratedValue>
                            </enumeratedValues>
                        </field>
                        <field>
                            <name>PODR04</name>
                            <description>Pmn Output Data</description>
                            <lsb>4</lsb>
                            <msb>4</msb>
                            <access>read-write</access>
                            <enumeratedValues>
                                <enumeratedValue>
                                    <name>0</name>
                                    <description>Low output</description>
                                    <value>#0</value>
                                </enumeratedValue>
                                <enumeratedValue>
                                    <name>1</name>
                                    <description>High output</description>
                                    <value>#1</value>
                                </enumeratedValue>
                            </enumeratedValues>
                        </field>
                        <field>
                            <name>PODR05</name>
                            <description>Pmn Output Data</description>
                            <lsb>5</lsb>
                            <msb>5</msb>
                            <access>read-write</access>
                            <enumeratedValues>
                                <enumeratedValue>
                                    <name>0</name>
                                    <description>Low output</description>
                                    <value>#0</value>
                                </enumeratedValue>
                                <enumeratedValue>
                                    <name>1</name>
                                    <description>High output</description>
                                    <value>#1</value>
                                </enumeratedValue>
                            </enumeratedValues>
                        </field>
                        <field>
                            <name>PODR06</name>
                            <description>Pmn Output Data</description>
                            <lsb>6</lsb>
                            <msb>6</msb>
                            <access>read-write</access>
                            <enumeratedValues>
                                <enumeratedValue>
                                    <name>0</name>
                                    <description>Low output</description>
                                    <value>#0</value>
                                </enumeratedValue>
                                <enumeratedValue>
                                    <name>1</name>
                                    <description>High output</description>
                                    <value>#1</value>
                                </enumeratedValue>
                            </enumeratedValues>
                        </field>
                        <field>
                            <name>PODR07</name>
                            <description>Pmn Output Data</description>
                            <lsb>7</lsb>
                            <msb>7</msb>
                            <access>read-write</access>
                            <enumeratedValues>
                                <enumeratedValue>
                                    <name>0</name>
                                    <description>Low output</description>
                                    <value>#0</value>
                                </enumeratedValue>
                                <enumeratedValue>
                                    <name>1</name>
                                    <description>High output</description>
                                    <value>#1</value>
                                </enumeratedValue>
                            </enumeratedValues>
                        </field>
                        <field>
                            <name>PODR08</name>
                            <description>Pmn Output Data</description>
                            <lsb>8</lsb>
                            <msb>8</msb>
                            <access>read-write</access>
                            <enumeratedValues>
                                <enumeratedValue>
                                    <name>0</name>
                                    <description>Low output</description>
                                    <value>#0</value>
                                </enumeratedValue>
                                <enumeratedValue>
                                    <name>1</name>
                                    <description>High output</description>
                                    <value>#1</value>
                                </enumeratedValue>
                            </enumeratedValues>
                        </field>
                        <field>
                            <name>PODR09</name>
                            <description>Pmn Output Data</description>
                            <lsb>9</lsb>
                            <msb>9</msb>
                            <access>read-write</access>
                            <enumeratedValues>
                                <enumeratedValue>
                                    <name>0</name>
                                    <description>Low output</description>
                                    <value>#0</value>
                                </enumeratedValue>
                                <enumeratedValue>
                                    <name>1</name>
                                    <description>High output</description>
                                    <value>#1</value>
                                </enumeratedValue>
                            </enumeratedValues>
                        </field>
                        <field>
                            <name>PODR10</name>
                            <description>Pmn Output Data</description>
                            <lsb>10</lsb>
                            <msb>10</msb>
                            <access>read-write</access>
                            <enumeratedValues>
                                <enumeratedValue>
                                    <name>0</name>
                                    <description>Low output</description>
                                    <value>#0</value>
                                </enumeratedValue>
                                <enumeratedValue>
                                    <name>1</name>
                                    <description>High output</description>
                                    <value>#1</value>
                                </enumeratedValue>
                            </enumeratedValues>
                        </field>
                        <field>
                            <name>PODR11</name>
                            <description>Pmn Output Data</description>
                            <lsb>11</lsb>
                            <msb>11</msb>
                            <access>read-write</access>
                            <enumeratedValues>
                                <enumeratedValue>
                                    <name>0</name>
                                    <description>Low output</description>
                                    <value>#0</value>
                                </enumeratedValue>
                                <enumeratedValue>
                                    <name>1</name>
                                    <description>High output</description>
                                    <value>#1</value>
                                </enumeratedValue>
                            </enumeratedValues>
                        </field>
                        <field>
                            <name>PODR12</name>
                            <description>Pmn Output Data</description>
                            <lsb>12</lsb>
                            <msb>12</msb>
                            <access>read-write</access>
                            <enumeratedValues>
                                <enumeratedValue>
                                    <name>0</name>
                                    <description>Low output</description>
                                    <value>#0</value>
                                </enumeratedValue>
                                <enumeratedValue>
                                    <name>1</name>
                                    <description>High output</description>
                                    <value>#1</value>
                                </enumeratedValue>
                            </enumeratedValues>
                        </field>
                        <field>
                            <name>PODR13</name>
                            <description>Pmn Output Data</description>
                            <lsb>13</lsb>
                            <msb>13</msb>
                            <access>read-write</access>
                            <enumeratedValues>
                                <enumeratedValue>
                                    <name>0</name>
                                    <description>Low output</description>
                                    <value>#0</value>
                                </enumeratedValue>
                                <enumeratedValue>
                                    <name>1</name>
                                    <description>High output</description>
                                    <value>#1</value>
                                </enumeratedValue>
                            </enumeratedValues>
                        </field>
                        <field>
                            <name>PODR14</name>
                            <description>Pmn Output Data</description>
                            <lsb>14</lsb>
                            <msb>14</msb>
                            <access>read-write</access>
                            <enumeratedValues>
                                <enumeratedValue>
                                    <name>0</name>
                                    <description>Low output</description>
                                    <value>#0</value>
                                </enumeratedValue>
                                <enumeratedValue>
                                    <name>1</name>
                                    <description>High output</description>
                                    <value>#1</value>
                                </enumeratedValue>
                            </enumeratedValues>
                        </field>
                        <field>
                            <name>PODR15</name>
                            <description>Pmn Output Data</description>
                            <lsb>15</lsb>
                            <msb>15</msb>
                            <access>read-write</access>
                            <enumeratedValues>
                                <enumeratedValue>
                                    <name>0</name>
                                    <description>Low output</description>
                                    <value>#0</value>
                                </enumeratedValue>
                                <enumeratedValue>
                                    <name>1</name>
                                    <description>High output</description>
                                    <value>#1</value>
                                </enumeratedValue>
                            </enumeratedValues>
                        </field>
                    </fields>
                </register>
                <register>
                    <name>PODR</name>
                    <description>Port Control Register 1</description>
                    <alternateRegister>PCNTR1</alternateRegister>
                    <addressOffset>0x002</addressOffset>
                    <size>16</size>
                    <access>read-write</access>
                    <resetValue>0x0000</resetValue>
                    <resetMask>0xffff</resetMask>
                    <fields>
                        <field>
                            <name>PDR00</name>
                            <description>Pmn Direction</description>
                            <lsb>0</lsb>
                            <msb>0</msb>
                            <access>read-write</access>
                            <enumeratedValues>
                                <enumeratedValue>
                                    <name>0</name>
                                    <description>Input (functions as an input pin)</description>
                                    <value>#0</value>
                                </enumeratedValue>
                                <enumeratedValue>
                                    <name>1</name>
                                    <description>Output (functions as an output pin)</description>
                                    <value>#1</value>
                                </enumeratedValue>
                            </enumeratedValues>
                        </field>
                        <field>
                            <name>PDR01</name>
                            <description>Pmn Direction</description>
                            <lsb>1</lsb>
                            <msb>1</msb>
                            <access>read-write</access>
                            <enumeratedValues>
                                <enumeratedValue>
                                    <name>0</name>
                                    <description>Input (functions as an input pin)</description>
                                    <value>#0</value>
                                </enumeratedValue>
                                <enumeratedValue>
                                    <name>1</name>
                                    <description>Output (functions as an output pin)</description>
                                    <value>#1</value>
                                </enumeratedValue>
                            </enumeratedValues>
                        </field>
                        <field>
                            <name>PDR02</name>
                            <description>Pmn Direction</description>
                            <lsb>2</lsb>
                            <msb>2</msb>
                            <access>read-write</access>
                            <enumeratedValues>
                                <enumeratedValue>
                                    <name>0</name>
                                    <description>Input (functions as an input pin)</description>
                                    <value>#0</value>
                                </enumeratedValue>
                                <enumeratedValue>
                                    <name>1</name>
                                    <description>Output (functions as an output pin)</description>
                                    <value>#1</value>
                                </enumeratedValue>
                            </enumeratedValues>
                        </field>
                        <field>
                            <name>PDR03</name>
                            <description>Pmn Direction</description>
                            <lsb>3</lsb>
                            <msb>3</msb>
                            <access>read-write</access>
                            <enumeratedValues>
                                <enumeratedValue>
                                    <name>0</name>
                                    <description>Input (functions as an input pin)</description>
                                    <value>#0</value>
                                </enumeratedValue>
                                <enumeratedValue>
                                    <name>1</name>
                                    <description>Output (functions as an output pin)</description>
                                    <value>#1</value>
                                </enumeratedValue>
                            </enumeratedValues>
                        </field>
                        <field>
                            <name>PDR04</name>
                            <description>Pmn Direction</description>
                            <lsb>4</lsb>
                            <msb>4</msb>
                            <access>read-write</access>
                            <enumeratedValues>
                                <enumeratedValue>
                                    <name>0</name>
                                    <description>Input (functions as an input pin)</description>
                                    <value>#0</value>
                                </enumeratedValue>
                                <enumeratedValue>
                                    <name>1</name>
                                    <description>Output (functions as an output pin)</description>
                                    <value>#1</value>
                                </enumeratedValue>
                            </enumeratedValues>
                        </field>
                        <field>
                            <name>PDR05</name>
                            <description>Pmn Direction</description>
                            <lsb>5</lsb>
                            <msb>5</msb>
                            <access>read-write</access>
                            <enumeratedValues>
                                <enumeratedValue>
                                    <name>0</name>
                                    <description>Input (functions as an input pin)</description>
                                    <value>#0</value>
                                </enumeratedValue>
                                <enumeratedValue>
                                    <name>1</name>
                                    <description>Output (functions as an output pin)</description>
                                    <value>#1</value>
                                </enumeratedValue>
                            </enumeratedValues>
                        </field>
                        <field>
                            <name>PDR06</name>
                            <description>Pmn Direction</description>
                            <lsb>6</lsb>
                            <msb>6</msb>
                            <access>read-write</access>
                            <enumeratedValues>
                                <enumeratedValue>
                                    <name>0</name>
                                    <description>Input (functions as an input pin)</description>
                                    <value>#0</value>
                                </enumeratedValue>
                                <enumeratedValue>
                                    <name>1</name>
                                    <description>Output (functions as an output pin)</description>
                                    <value>#1</value>
                                </enumeratedValue>
                            </enumeratedValues>
                        </field>
                        <field>
                            <name>PDR07</name>
                            <description>Pmn Direction</description>
                            <lsb>7</lsb>
                            <msb>7</msb>
                            <access>read-write</access>
                            <enumeratedValues>
                                <enumeratedValue>
                                    <name>0</name>
                                    <description>Input (functions as an input pin)</description>
                                    <value>#0</value>
                                </enumeratedValue>
                                <enumeratedValue>
                                    <name>1</name>
                                    <description>Output (functions as an output pin)</description>
                                    <value>#1</value>
                                </enumeratedValue>
                            </enumeratedValues>
                        </field>
                        <field>
                            <name>PDR08</name>
                            <description>Pmn Direction</description>
                            <lsb>8</lsb>
                            <msb>8</msb>
                            <access>read-write</access>
                            <enumeratedValues>
                                <enumeratedValue>
                                    <name>0</name>
                                    <description>Input (functions as an input pin)</description>
                                    <value>#0</value>
                                </enumeratedValue>
                                <enumeratedValue>
                                    <name>1</name>
                                    <description>Output (functions as an output pin)</description>
                                    <value>#1</value>
                                </enumeratedValue>
                            </enumeratedValues>
                        </field>
                        <field>
                            <name>PDR09</name>
                            <description>Pmn Direction</description>
                            <lsb>9</lsb>
                            <msb>9</msb>
                            <access>read-write</access>
                            <enumeratedValues>
                                <enumeratedValue>
                                    <name>0</name>
                                    <description>Input (functions as an input pin)</description>
                                    <value>#0</value>
                                </enumeratedValue>
                                <enumeratedValue>
                                    <name>1</name>
                                    <description>Output (functions as an output pin)</description>
                                    <value>#1</value>
                                </enumeratedValue>
                            </enumeratedValues>
                        </field>
                        <field>
                            <name>PDR10</name>
                            <description>Pmn Direction</description>
                            <lsb>10</lsb>
                            <msb>10</msb>
                            <access>read-write</access>
                            <enumeratedValues>
                                <enumeratedValue>
                                    <name>0</name>
                                    <description>Input (functions as an input pin)</description>
                                    <value>#0</value>
                                </enumeratedValue>
                                <enumeratedValue>
                                    <name>1</name>
                                    <description>Output (functions as an output pin)</description>
                                    <value>#1</value>
                                </enumeratedValue>
                            </enumeratedValues>
                        </field>
                        <field>
                            <name>PDR11</name>
                            <description>Pmn Direction</description>
                            <lsb>11</lsb>
                            <msb>11</msb>
                            <access>read-write</access>
                            <enumeratedValues>
                                <enumeratedValue>
                                    <name>0</name>
                                    <description>Input (functions as an input pin)</description>
                                    <value>#0</value>
                                </enumeratedValue>
                                <enumeratedValue>
                                    <name>1</name>
                                    <description>Output (functions as an output pin)</description>
                                    <value>#1</value>
                                </enumeratedValue>
                            </enumeratedValues>
                        </field>
                        <field>
                            <name>PDR12</name>
                            <description>Pmn Direction</description>
                            <lsb>12</lsb>
                            <msb>12</msb>
                            <access>read-write</access>
                            <enumeratedValues>
                                <enumeratedValue>
                                    <name>0</name>
                                    <description>Input (functions as an input pin)</description>
                                    <value>#0</value>
                                </enumeratedValue>
                                <enumeratedValue>
                                    <name>1</name>
                                    <description>Output (functions as an output pin)</description>
                                    <value>#1</value>
                                </enumeratedValue>
                            </enumeratedValues>
                        </field>
                        <field>
                            <name>PDR13</name>
                            <description>Pmn Direction</description>
                            <lsb>13</lsb>
                            <msb>13</msb>
                            <access>read-write</access>
                            <enumeratedValues>
                                <enumeratedValue>
                                    <name>0</name>
                                    <description>Input (functions as an input pin)</description>
                                    <value>#0</value>
                                </enumeratedValue>
                                <enumeratedValue>
                                    <name>1</name>
                                    <description>Output (functions as an output pin)</description>
                                    <value>#1</value>
                                </enumeratedValue>
                            </enumeratedValues>
                        </field>
                        <field>
                            <name>PDR14</name>
                            <description>Pmn Direction</description>
                            <lsb>14</lsb>
                            <msb>14</msb>
                            <access>read-write</access>
                            <enumeratedValues>
                                <enumeratedValue>
                                    <name>0</name>
                                    <description>Input (functions as an input pin)</description>
                                    <value>#0</value>
                                </enumeratedValue>
                                <enumeratedValue>
                                    <name>1</name>
                                    <description>Output (functions as an output pin)</description>
                                    <value>#1</value>
                                </enumeratedValue>
                            </enumeratedValues>
                        </field>
                        <field>
                            <name>PDR15</name>
                            <description>Pmn Direction</description>
                            <lsb>15</lsb>
                            <msb>15</msb>
                            <access>read-write</access>
                            <enumeratedValues>
                                <enumeratedValue>
                                    <name>0</name>
                                    <description>Input (functions as an input pin)</description>
                                    <value>#0</value>
                                </enumeratedValue>
                                <enumeratedValue>
                                    <name>1</name>
                                    <description>Output (functions as an output pin)</description>
                                    <value>#1</value>
                                </enumeratedValue>
                            </enumeratedValues>
                        </field>
                    </fields>
                </register>
                <register>
                    <name>PCNTR2</name>
                    <description>Port Control Register 2</description>
                    <addressOffset>0x004</addressOffset>
                    <size>32</size>
                    <access>read-only</access>
                    <resetValue>0x00000000</resetValue>
                    <resetMask>0xffff0000</resetMask>
                    <fields>
                        <field>
                            <name>PIDR00</name>
                            <description>Pmn State</description>
                            <lsb>0</lsb>
                            <msb>0</msb>
                            <access>read-only</access>
                            <enumeratedValues>
                                <enumeratedValue>
                                    <name>0</name>
                                    <description>Low level</description>
                                    <value>#0</value>
                                </enumeratedValue>
                                <enumeratedValue>
                                    <name>1</name>
                                    <description>High level</description>
                                    <value>#1</value>
                                </enumeratedValue>
                            </enumeratedValues>
                        </field>
                        <field>
                            <name>PIDR01</name>
                            <description>Pmn State</description>
                            <lsb>1</lsb>
                            <msb>1</msb>
                            <access>read-only</access>
                            <enumeratedValues>
                                <enumeratedValue>
                                    <name>0</name>
                                    <description>Low level</description>
                                    <value>#0</value>
                                </enumeratedValue>
                                <enumeratedValue>
                                    <name>1</name>
                                    <description>High level</description>
                                    <value>#1</value>
                                </enumeratedValue>
                            </enumeratedValues>
                        </field>
                        <field>
                            <name>PIDR02</name>
                            <description>Pmn State</description>
                            <lsb>2</lsb>
                            <msb>2</msb>
                            <access>read-only</access>
                            <enumeratedValues>
                                <enumeratedValue>
                                    <name>0</name>
                                    <description>Low level</description>
                                    <value>#0</value>
                                </enumeratedValue>
                                <enumeratedValue>
                                    <name>1</name>
                                    <description>High level</description>
                                    <value>#1</value>
                                </enumeratedValue>
                            </enumeratedValues>
                        </field>
                        <field>
                            <name>PIDR03</name>
                            <description>Pmn State</description>
                            <lsb>3</lsb>
                            <msb>3</msb>
                            <access>read-only</access>
                            <enumeratedValues>
                                <enumeratedValue>
                                    <name>0</name>
                                    <description>Low level</description>
                                    <value>#0</value>
                                </enumeratedValue>
                                <enumeratedValue>
                                    <name>1</name>
                                    <description>High level</description>
                                    <value>#1</value>
                                </enumeratedValue>
                            </enumeratedValues>
                        </field>
                        <field>
                            <name>PIDR04</name>
                            <description>Pmn State</description>
                            <lsb>4</lsb>
                            <msb>4</msb>
                            <access>read-only</access>
                            <enumeratedValues>
                                <enumeratedValue>
                                    <name>0</name>
                                    <description>Low level</description>
                                    <value>#0</value>
                                </enumeratedValue>
                                <enumeratedValue>
                                    <name>1</name>
                                    <description>High level</description>
                                    <value>#1</value>
                                </enumeratedValue>
                            </enumeratedValues>
                        </field>
                        <field>
                            <name>PIDR05</name>
                            <description>Pmn State</description>
                            <lsb>5</lsb>
                            <msb>5</msb>
                            <access>read-only</access>
                            <enumeratedValues>
                                <enumeratedValue>
                                    <name>0</name>
                                    <description>Low level</description>
                                    <value>#0</value>
                                </enumeratedValue>
                                <enumeratedValue>
                                    <name>1</name>
                                    <description>High level</description>
                                    <value>#1</value>
                                </enumeratedValue>
                            </enumeratedValues>
                        </field>
                        <field>
                            <name>PIDR06</name>
                            <description>Pmn State</description>
                            <lsb>6</lsb>
                            <msb>6</msb>
                            <access>read-only</access>
                            <enumeratedValues>
                                <enumeratedValue>
                                    <name>0</name>
                                    <description>Low level</description>
                                    <value>#0</value>
                                </enumeratedValue>
                                <enumeratedValue>
                                    <name>1</name>
                                    <description>High level</description>
                                    <value>#1</value>
                                </enumeratedValue>
                            </enumeratedValues>
                        </field>
                        <field>
                            <name>PIDR07</name>
                            <description>Pmn State</description>
                            <lsb>7</lsb>
                            <msb>7</msb>
                            <access>read-only</access>
                            <enumeratedValues>
                                <enumeratedValue>
                                    <name>0</name>
                                    <description>Low level</description>
                                    <value>#0</value>
                                </enumeratedValue>
                                <enumeratedValue>
                                    <name>1</name>
                                    <description>High level</description>
                                    <value>#1</value>
                                </enumeratedValue>
                            </enumeratedValues>
                        </field>
                        <field>
                            <name>PIDR08</name>
                            <description>Pmn State</description>
                            <lsb>8</lsb>
                            <msb>8</msb>
                            <access>read-only</access>
                            <enumeratedValues>
                                <enumeratedValue>
                                    <name>0</name>
                                    <description>Low level</description>
                                    <value>#0</value>
                                </enumeratedValue>
                                <enumeratedValue>
                                    <name>1</name>
                                    <description>High level</description>
                                    <value>#1</value>
                                </enumeratedValue>
                            </enumeratedValues>
                        </field>
                        <field>
                            <name>PIDR09</name>
                            <description>Pmn State</description>
                            <lsb>9</lsb>
                            <msb>9</msb>
                            <access>read-only</access>
                            <enumeratedValues>
                                <enumeratedValue>
                                    <name>0</name>
                                    <description>Low level</description>
                                    <value>#0</value>
                                </enumeratedValue>
                                <enumeratedValue>
                                    <name>1</name>
                                    <description>High level</description>
                                    <value>#1</value>
                                </enumeratedValue>
                            </enumeratedValues>
                        </field>
                        <field>
                            <name>PIDR10</name>
                            <description>Pmn State</description>
                            <lsb>10</lsb>
                            <msb>10</msb>
                            <access>read-only</access>
                            <enumeratedValues>
                                <enumeratedValue>
                                    <name>0</name>
                                    <description>Low level</description>
                                    <value>#0</value>
                                </enumeratedValue>
                                <enumeratedValue>
                                    <name>1</name>
                                    <description>High level</description>
                                    <value>#1</value>
                                </enumeratedValue>
                            </enumeratedValues>
                        </field>
                        <field>
                            <name>PIDR11</name>
                            <description>Pmn State</description>
                            <lsb>11</lsb>
                            <msb>11</msb>
                            <access>read-only</access>
                            <enumeratedValues>
                                <enumeratedValue>
                                    <name>0</name>
                                    <description>Low level</description>
                                    <value>#0</value>
                                </enumeratedValue>
                                <enumeratedValue>
                                    <name>1</name>
                                    <description>High level</description>
                                    <value>#1</value>
                                </enumeratedValue>
                            </enumeratedValues>
                        </field>
                        <field>
                            <name>PIDR12</name>
                            <description>Pmn State</description>
                            <lsb>12</lsb>
                            <msb>12</msb>
                            <access>read-only</access>
                            <enumeratedValues>
                                <enumeratedValue>
                                    <name>0</name>
                                    <description>Low level</description>
                                    <value>#0</value>
                                </enumeratedValue>
                                <enumeratedValue>
                                    <name>1</name>
                                    <description>High level</description>
                                    <value>#1</value>
                                </enumeratedValue>
                            </enumeratedValues>
                        </field>
                        <field>
                            <name>PIDR13</name>
                            <description>Pmn State</description>
                            <lsb>13</lsb>
                            <msb>13</msb>
                            <access>read-only</access>
                            <enumeratedValues>
                                <enumeratedValue>
                                    <name>0</name>
                                    <description>Low level</description>
                                    <value>#0</value>
                                </enumeratedValue>
                                <enumeratedValue>
                                    <name>1</name>
                                    <description>High level</description>
                                    <value>#1</value>
                                </enumeratedValue>
                            </enumeratedValues>
                        </field>
                        <field>
                            <name>PIDR14</name>
                            <description>Pmn State</description>
                            <lsb>14</lsb>
                            <msb>14</msb>
                            <access>read-only</access>
                            <enumeratedValues>
                                <enumeratedValue>
                                    <name>0</name>
                                    <description>Low level</description>
                                    <value>#0</value>
                                </enumeratedValue>
                                <enumeratedValue>
                                    <name>1</name>
                                    <description>High level</description>
                                    <value>#1</value>
                                </enumeratedValue>
                            </enumeratedValues>
                        </field>
                        <field>
                            <name>PIDR15</name>
                            <description>Pmn State</description>
                            <lsb>15</lsb>
                            <msb>15</msb>
                            <access>read-only</access>
                            <enumeratedValues>
                                <enumeratedValue>
                                    <name>0</name>
                                    <description>Low level</description>
                                    <value>#0</value>
                                </enumeratedValue>
                                <enumeratedValue>
                                    <name>1</name>
                                    <description>High level</description>
                                    <value>#1</value>
                                </enumeratedValue>
                            </enumeratedValues>
                        </field>
                        <field>
                            <name>EIDR00</name>
                            <description>Port Event Input Data</description>
                            <lsb>16</lsb>
                            <msb>16</msb>
                            <access>read-only</access>
                            <enumeratedValues>
                                <enumeratedValue>
                                    <name>0</name>
                                    <description>Low input</description>
                                    <value>#0</value>
                                </enumeratedValue>
                                <enumeratedValue>
                                    <name>1</name>
                                    <description>High input</description>
                                    <value>#1</value>
                                </enumeratedValue>
                            </enumeratedValues>
                        </field>
                        <field>
                            <name>EIDR01</name>
                            <description>Port Event Input Data</description>
                            <lsb>17</lsb>
                            <msb>17</msb>
                            <access>read-only</access>
                            <enumeratedValues>
                                <enumeratedValue>
                                    <name>0</name>
                                    <description>Low input</description>
                                    <value>#0</value>
                                </enumeratedValue>
                                <enumeratedValue>
                                    <name>1</name>
                                    <description>High input</description>
                                    <value>#1</value>
                                </enumeratedValue>
                            </enumeratedValues>
                        </field>
                        <field>
                            <name>EIDR02</name>
                            <description>Port Event Input Data</description>
                            <lsb>18</lsb>
                            <msb>18</msb>
                            <access>read-only</access>
                            <enumeratedValues>
                                <enumeratedValue>
                                    <name>0</name>
                                    <description>Low input</description>
                                    <value>#0</value>
                                </enumeratedValue>
                                <enumeratedValue>
                                    <name>1</name>
                                    <description>High input</description>
                                    <value>#1</value>
                                </enumeratedValue>
                            </enumeratedValues>
                        </field>
                        <field>
                            <name>EIDR03</name>
                            <description>Port Event Input Data</description>
                            <lsb>19</lsb>
                            <msb>19</msb>
                            <access>read-only</access>
                            <enumeratedValues>
                                <enumeratedValue>
                                    <name>0</name>
                                    <description>Low input</description>
                                    <value>#0</value>
                                </enumeratedValue>
                                <enumeratedValue>
                                    <name>1</name>
                                    <description>High input</description>
                                    <value>#1</value>
                                </enumeratedValue>
                            </enumeratedValues>
                        </field>
                        <field>
                            <name>EIDR04</name>
                            <description>Port Event Input Data</description>
                            <lsb>20</lsb>
                            <msb>20</msb>
                            <access>read-only</access>
                            <enumeratedValues>
                                <enumeratedValue>
                                    <name>0</name>
                                    <description>Low input</description>
                                    <value>#0</value>
                                </enumeratedValue>
                                <enumeratedValue>
                                    <name>1</name>
                                    <description>High input</description>
                                    <value>#1</value>
                                </enumeratedValue>
                            </enumeratedValues>
                        </field>
                        <field>
                            <name>EIDR05</name>
                            <description>Port Event Input Data</description>
                            <lsb>21</lsb>
                            <msb>21</msb>
                            <access>read-only</access>
                            <enumeratedValues>
                                <enumeratedValue>
                                    <name>0</name>
                                    <description>Low input</description>
                                    <value>#0</value>
                                </enumeratedValue>
                                <enumeratedValue>
                                    <name>1</name>
                                    <description>High input</description>
                                    <value>#1</value>
                                </enumeratedValue>
                            </enumeratedValues>
                        </field>
                        <field>
                            <name>EIDR06</name>
                            <description>Port Event Input Data</description>
                            <lsb>22</lsb>
                            <msb>22</msb>
                            <access>read-only</access>
                            <enumeratedValues>
                                <enumeratedValue>
                                    <name>0</name>
                                    <description>Low input</description>
                                    <value>#0</value>
                                </enumeratedValue>
                                <enumeratedValue>
                                    <name>1</name>
                                    <description>High input</description>
                                    <value>#1</value>
                                </enumeratedValue>
                            </enumeratedValues>
                        </field>
                        <field>
                            <name>EIDR07</name>
                            <description>Port Event Input Data</description>
                            <lsb>23</lsb>
                            <msb>23</msb>
                            <access>read-only</access>
                            <enumeratedValues>
                                <enumeratedValue>
                                    <name>0</name>
                                    <description>Low input</description>
                                    <value>#0</value>
                                </enumeratedValue>
                                <enumeratedValue>
                                    <name>1</name>
                                    <description>High input</description>
                                    <value>#1</value>
                                </enumeratedValue>
                            </enumeratedValues>
                        </field>
                        <field>
                            <name>EIDR08</name>
                            <description>Port Event Input Data</description>
                            <lsb>24</lsb>
                            <msb>24</msb>
                            <access>read-only</access>
                            <enumeratedValues>
                                <enumeratedValue>
                                    <name>0</name>
                                    <description>Low input</description>
                                    <value>#0</value>
                                </enumeratedValue>
                                <enumeratedValue>
                                    <name>1</name>
                                    <description>High input</description>
                                    <value>#1</value>
                                </enumeratedValue>
                            </enumeratedValues>
                        </field>
                        <field>
                            <name>EIDR09</name>
                            <description>Port Event Input Data</description>
                            <lsb>25</lsb>
                            <msb>25</msb>
                            <access>read-only</access>
                            <enumeratedValues>
                                <enumeratedValue>
                                    <name>0</name>
                                    <description>Low input</description>
                                    <value>#0</value>
                                </enumeratedValue>
                                <enumeratedValue>
                                    <name>1</name>
                                    <description>High input</description>
                                    <value>#1</value>
                                </enumeratedValue>
                            </enumeratedValues>
                        </field>
                        <field>
                            <name>EIDR10</name>
                            <description>Port Event Input Data</description>
                            <lsb>26</lsb>
                            <msb>26</msb>
                            <access>read-only</access>
                            <enumeratedValues>
                                <enumeratedValue>
                                    <name>0</name>
                                    <description>Low input</description>
                                    <value>#0</value>
                                </enumeratedValue>
                                <enumeratedValue>
                                    <name>1</name>
                                    <description>High input</description>
                                    <value>#1</value>
                                </enumeratedValue>
                            </enumeratedValues>
                        </field>
                        <field>
                            <name>EIDR11</name>
                            <description>Port Event Input Data</description>
                            <lsb>27</lsb>
                            <msb>27</msb>
                            <access>read-only</access>
                            <enumeratedValues>
                                <enumeratedValue>
                                    <name>0</name>
                                    <description>Low input</description>
                                    <value>#0</value>
                                </enumeratedValue>
                                <enumeratedValue>
                                    <name>1</name>
                                    <description>High input</description>
                                    <value>#1</value>
                                </enumeratedValue>
                            </enumeratedValues>
                        </field>
                        <field>
                            <name>EIDR12</name>
                            <description>Port Event Input Data</description>
                            <lsb>28</lsb>
                            <msb>28</msb>
                            <access>read-only</access>
                            <enumeratedValues>
                                <enumeratedValue>
                                    <name>0</name>
                                    <description>Low input</description>
                                    <value>#0</value>
                                </enumeratedValue>
                                <enumeratedValue>
                                    <name>1</name>
                                    <description>High input</description>
                                    <value>#1</value>
                                </enumeratedValue>
                            </enumeratedValues>
                        </field>
                        <field>
                            <name>EIDR13</name>
                            <description>Port Event Input Data</description>
                            <lsb>29</lsb>
                            <msb>29</msb>
                            <access>read-only</access>
                            <enumeratedValues>
                                <enumeratedValue>
                                    <name>0</name>
                                    <description>Low input</description>
                                    <value>#0</value>
                                </enumeratedValue>
                                <enumeratedValue>
                                    <name>1</name>
                                    <description>High input</description>
                                    <value>#1</value>
                                </enumeratedValue>
                            </enumeratedValues>
                        </field>
                        <field>
                            <name>EIDR14</name>
                            <description>Port Event Input Data</description>
                            <lsb>30</lsb>
                            <msb>30</msb>
                            <access>read-only</access>
                            <enumeratedValues>
                                <enumeratedValue>
                                    <name>0</name>
                                    <description>Low input</description>
                                    <value>#0</value>
                                </enumeratedValue>
                                <enumeratedValue>
                                    <name>1</name>
                                    <description>High input</description>
                                    <value>#1</value>
                                </enumeratedValue>
                            </enumeratedValues>
                        </field>
                        <field>
                            <name>EIDR15</name>
                            <description>Port Event Input Data</description>
                            <lsb>31</lsb>
                            <msb>31</msb>
                            <access>read-only</access>
                            <enumeratedValues>
                                <enumeratedValue>
                                    <name>0</name>
                                    <description>Low input</description>
                                    <value>#0</value>
                                </enumeratedValue>
                                <enumeratedValue>
                                    <name>1</name>
                                    <description>High input</description>
                                    <value>#1</value>
                                </enumeratedValue>
                            </enumeratedValues>
                        </field>
                    </fields>
                </register>
                <register>
                    <name>PIDR</name>
                    <description>Port Control Register 2</description>
                    <alternateRegister>PCNTR2</alternateRegister>
                    <addressOffset>0x004</addressOffset>
                    <size>16</size>
                    <access>read-only</access>
                    <resetValue>0x0000</resetValue>
                    <resetMask>0xffff</resetMask>
                    <fields>
                        <field>
                            <name>EIDR00</name>
                            <description>Port Event Input Data</description>
                            <lsb>0</lsb>
                            <msb>0</msb>
                            <access>read-only</access>
                            <enumeratedValues>
                                <enumeratedValue>
                                    <name>0</name>
                                    <description>Low input</description>
                                    <value>#0</value>
                                </enumeratedValue>
                                <enumeratedValue>
                                    <name>1</name>
                                    <description>High input</description>
                                    <value>#1</value>
                                </enumeratedValue>
                            </enumeratedValues>
                        </field>
                        <field>
                            <name>EIDR01</name>
                            <description>Port Event Input Data</description>
                            <lsb>1</lsb>
                            <msb>1</msb>
                            <access>read-only</access>
                            <enumeratedValues>
                                <enumeratedValue>
                                    <name>0</name>
                                    <description>Low input</description>
                                    <value>#0</value>
                                </enumeratedValue>
                                <enumeratedValue>
                                    <name>1</name>
                                    <description>High input</description>
                                    <value>#1</value>
                                </enumeratedValue>
                            </enumeratedValues>
                        </field>
                        <field>
                            <name>EIDR02</name>
                            <description>Port Event Input Data</description>
                            <lsb>2</lsb>
                            <msb>2</msb>
                            <access>read-only</access>
                            <enumeratedValues>
                                <enumeratedValue>
                                    <name>0</name>
                                    <description>Low input</description>
                                    <value>#0</value>
                                </enumeratedValue>
                                <enumeratedValue>
                                    <name>1</name>
                                    <description>High input</description>
                                    <value>#1</value>
                                </enumeratedValue>
                            </enumeratedValues>
                        </field>
                        <field>
                            <name>EIDR03</name>
                            <description>Port Event Input Data</description>
                            <lsb>3</lsb>
                            <msb>3</msb>
                            <access>read-only</access>
                            <enumeratedValues>
                                <enumeratedValue>
                                    <name>0</name>
                                    <description>Low input</description>
                                    <value>#0</value>
                                </enumeratedValue>
                                <enumeratedValue>
                                    <name>1</name>
                                    <description>High input</description>
                                    <value>#1</value>
                                </enumeratedValue>
                            </enumeratedValues>
                        </field>
                        <field>
                            <name>EIDR04</name>
                            <description>Port Event Input Data</description>
                            <lsb>4</lsb>
                            <msb>4</msb>
                            <access>read-only</access>
                            <enumeratedValues>
                                <enumeratedValue>
                                    <name>0</name>
                                    <description>Low input</description>
                                    <value>#0</value>
                                </enumeratedValue>
                                <enumeratedValue>
                                    <name>1</name>
                                    <description>High input</description>
                                    <value>#1</value>
                                </enumeratedValue>
                            </enumeratedValues>
                        </field>
                        <field>
                            <name>EIDR05</name>
                            <description>Port Event Input Data</description>
                            <lsb>5</lsb>
                            <msb>5</msb>
                            <access>read-only</access>
                            <enumeratedValues>
                                <enumeratedValue>
                                    <name>0</name>
                                    <description>Low input</description>
                                    <value>#0</value>
                                </enumeratedValue>
                                <enumeratedValue>
                                    <name>1</name>
                                    <description>High input</description>
                                    <value>#1</value>
                                </enumeratedValue>
                            </enumeratedValues>
                        </field>
                        <field>
                            <name>EIDR06</name>
                            <description>Port Event Input Data</description>
                            <lsb>6</lsb>
                            <msb>6</msb>
                            <access>read-only</access>
                            <enumeratedValues>
                                <enumeratedValue>
                                    <name>0</name>
                                    <description>Low input</description>
                                    <value>#0</value>
                                </enumeratedValue>
                                <enumeratedValue>
                                    <name>1</name>
                                    <description>High input</description>
                                    <value>#1</value>
                                </enumeratedValue>
                            </enumeratedValues>
                        </field>
                        <field>
                            <name>EIDR07</name>
                            <description>Port Event Input Data</description>
                            <lsb>7</lsb>
                            <msb>7</msb>
                            <access>read-only</access>
                            <enumeratedValues>
                                <enumeratedValue>
                                    <name>0</name>
                                    <description>Low input</description>
                                    <value>#0</value>
                                </enumeratedValue>
                                <enumeratedValue>
                                    <name>1</name>
                                    <description>High input</description>
                                    <value>#1</value>
                                </enumeratedValue>
                            </enumeratedValues>
                        </field>
                        <field>
                            <name>EIDR08</name>
                            <description>Port Event Input Data</description>
                            <lsb>8</lsb>
                            <msb>8</msb>
                            <access>read-only</access>
                            <enumeratedValues>
                                <enumeratedValue>
                                    <name>0</name>
                                    <description>Low input</description>
                                    <value>#0</value>
                                </enumeratedValue>
                                <enumeratedValue>
                                    <name>1</name>
                                    <description>High input</description>
                                    <value>#1</value>
                                </enumeratedValue>
                            </enumeratedValues>
                        </field>
                        <field>
                            <name>EIDR09</name>
                            <description>Port Event Input Data</description>
                            <lsb>9</lsb>
                            <msb>9</msb>
                            <access>read-only</access>
                            <enumeratedValues>
                                <enumeratedValue>
                                    <name>0</name>
                                    <description>Low input</description>
                                    <value>#0</value>
                                </enumeratedValue>
                                <enumeratedValue>
                                    <name>1</name>
                                    <description>High input</description>
                                    <value>#1</value>
                                </enumeratedValue>
                            </enumeratedValues>
                        </field>
                        <field>
                            <name>EIDR10</name>
                            <description>Port Event Input Data</description>
                            <lsb>10</lsb>
                            <msb>10</msb>
                            <access>read-only</access>
                            <enumeratedValues>
                                <enumeratedValue>
                                    <name>0</name>
                                    <description>Low input</description>
                                    <value>#0</value>
                                </enumeratedValue>
                                <enumeratedValue>
                                    <name>1</name>
                                    <description>High input</description>
                                    <value>#1</value>
                                </enumeratedValue>
                            </enumeratedValues>
                        </field>
                        <field>
                            <name>EIDR11</name>
                            <description>Port Event Input Data</description>
                            <lsb>11</lsb>
                            <msb>11</msb>
                            <access>read-only</access>
                            <enumeratedValues>
                                <enumeratedValue>
                                    <name>0</name>
                                    <description>Low input</description>
                                    <value>#0</value>
                                </enumeratedValue>
                                <enumeratedValue>
                                    <name>1</name>
                                    <description>High input</description>
                                    <value>#1</value>
                                </enumeratedValue>
                            </enumeratedValues>
                        </field>
                        <field>
                            <name>EIDR12</name>
                            <description>Port Event Input Data</description>
                            <lsb>12</lsb>
                            <msb>12</msb>
                            <access>read-only</access>
                            <enumeratedValues>
                                <enumeratedValue>
                                    <name>0</name>
                                    <description>Low input</description>
                                    <value>#0</value>
                                </enumeratedValue>
                                <enumeratedValue>
                                    <name>1</name>
                                    <description>High input</description>
                                    <value>#1</value>
                                </enumeratedValue>
                            </enumeratedValues>
                        </field>
                        <field>
                            <name>EIDR13</name>
                            <description>Port Event Input Data</description>
                            <lsb>13</lsb>
                            <msb>13</msb>
                            <access>read-only</access>
                            <enumeratedValues>
                                <enumeratedValue>
                                    <name>0</name>
                                    <description>Low input</description>
                                    <value>#0</value>
                                </enumeratedValue>
                                <enumeratedValue>
                                    <name>1</name>
                                    <description>High input</description>
                                    <value>#1</value>
                                </enumeratedValue>
                            </enumeratedValues>
                        </field>
                        <field>
                            <name>EIDR14</name>
                            <description>Port Event Input Data</description>
                            <lsb>14</lsb>
                            <msb>14</msb>
                            <access>read-only</access>
                            <enumeratedValues>
                                <enumeratedValue>
                                    <name>0</name>
                                    <description>Low input</description>
                                    <value>#0</value>
                                </enumeratedValue>
                                <enumeratedValue>
                                    <name>1</name>
                                    <description>High input</description>
                                    <value>#1</value>
                                </enumeratedValue>
                            </enumeratedValues>
                        </field>
                        <field>
                            <name>EIDR15</name>
                            <description>Port Event Input Data</description>
                            <lsb>15</lsb>
                            <msb>15</msb>
                            <access>read-only</access>
                            <enumeratedValues>
                                <enumeratedValue>
                                    <name>0</name>
                                    <description>Low input</description>
                                    <value>#0</value>
                                </enumeratedValue>
                                <enumeratedValue>
                                    <name>1</name>
                                    <description>High input</description>
                                    <value>#1</value>
                                </enumeratedValue>
                            </enumeratedValues>
                        </field>
                    </fields>
                </register>
                <register>
                    <name>EIDR</name>
                    <description>Port Control Register 2</description>
                    <alternateRegister>PCNTR2</alternateRegister>
                    <addressOffset>0x006</addressOffset>
                    <size>16</size>
                    <access>read-only</access>
                    <resetValue>0x0000</resetValue>
                    <resetMask>0x0000</resetMask>
                    <fields>
                        <field>
                            <name>PIDR00</name>
                            <description>Pmn State</description>
                            <lsb>0</lsb>
                            <msb>0</msb>
                            <access>read-only</access>
                            <enumeratedValues>
                                <enumeratedValue>
                                    <name>0</name>
                                    <description>Low level</description>
                                    <value>#0</value>
                                </enumeratedValue>
                                <enumeratedValue>
                                    <name>1</name>
                                    <description>High level</description>
                                    <value>#1</value>
                                </enumeratedValue>
                            </enumeratedValues>
                        </field>
                        <field>
                            <name>PIDR01</name>
                            <description>Pmn State</description>
                            <lsb>1</lsb>
                            <msb>1</msb>
                            <access>read-only</access>
                            <enumeratedValues>
                                <enumeratedValue>
                                    <name>0</name>
                                    <description>Low level</description>
                                    <value>#0</value>
                                </enumeratedValue>
                                <enumeratedValue>
                                    <name>1</name>
                                    <description>High level</description>
                                    <value>#1</value>
                                </enumeratedValue>
                            </enumeratedValues>
                        </field>
                        <field>
                            <name>PIDR02</name>
                            <description>Pmn State</description>
                            <lsb>2</lsb>
                            <msb>2</msb>
                            <access>read-only</access>
                            <enumeratedValues>
                                <enumeratedValue>
                                    <name>0</name>
                                    <description>Low level</description>
                                    <value>#0</value>
                                </enumeratedValue>
                                <enumeratedValue>
                                    <name>1</name>
                                    <description>High level</description>
                                    <value>#1</value>
                                </enumeratedValue>
                            </enumeratedValues>
                        </field>
                        <field>
                            <name>PIDR03</name>
                            <description>Pmn State</description>
                            <lsb>3</lsb>
                            <msb>3</msb>
                            <access>read-only</access>
                            <enumeratedValues>
                                <enumeratedValue>
                                    <name>0</name>
                                    <description>Low level</description>
                                    <value>#0</value>
                                </enumeratedValue>
                                <enumeratedValue>
                                    <name>1</name>
                                    <description>High level</description>
                                    <value>#1</value>
                                </enumeratedValue>
                            </enumeratedValues>
                        </field>
                        <field>
                            <name>PIDR04</name>
                            <description>Pmn State</description>
                            <lsb>4</lsb>
                            <msb>4</msb>
                            <access>read-only</access>
                            <enumeratedValues>
                                <enumeratedValue>
                                    <name>0</name>
                                    <description>Low level</description>
                                    <value>#0</value>
                                </enumeratedValue>
                                <enumeratedValue>
                                    <name>1</name>
                                    <description>High level</description>
                                    <value>#1</value>
                                </enumeratedValue>
                            </enumeratedValues>
                        </field>
                        <field>
                            <name>PIDR05</name>
                            <description>Pmn State</description>
                            <lsb>5</lsb>
                            <msb>5</msb>
                            <access>read-only</access>
                            <enumeratedValues>
                                <enumeratedValue>
                                    <name>0</name>
                                    <description>Low level</description>
                                    <value>#0</value>
                                </enumeratedValue>
                                <enumeratedValue>
                                    <name>1</name>
                                    <description>High level</description>
                                    <value>#1</value>
                                </enumeratedValue>
                            </enumeratedValues>
                        </field>
                        <field>
                            <name>PIDR06</name>
                            <description>Pmn State</description>
                            <lsb>6</lsb>
                            <msb>6</msb>
                            <access>read-only</access>
                            <enumeratedValues>
                                <enumeratedValue>
                                    <name>0</name>
                                    <description>Low level</description>
                                    <value>#0</value>
                                </enumeratedValue>
                                <enumeratedValue>
                                    <name>1</name>
                                    <description>High level</description>
                                    <value>#1</value>
                                </enumeratedValue>
                            </enumeratedValues>
                        </field>
                        <field>
                            <name>PIDR07</name>
                            <description>Pmn State</description>
                            <lsb>7</lsb>
                            <msb>7</msb>
                            <access>read-only</access>
                            <enumeratedValues>
                                <enumeratedValue>
                                    <name>0</name>
                                    <description>Low level</description>
                                    <value>#0</value>
                                </enumeratedValue>
                                <enumeratedValue>
                                    <name>1</name>
                                    <description>High level</description>
                                    <value>#1</value>
                                </enumeratedValue>
                            </enumeratedValues>
                        </field>
                        <field>
                            <name>PIDR08</name>
                            <description>Pmn State</description>
                            <lsb>8</lsb>
                            <msb>8</msb>
                            <access>read-only</access>
                            <enumeratedValues>
                                <enumeratedValue>
                                    <name>0</name>
                                    <description>Low level</description>
                                    <value>#0</value>
                                </enumeratedValue>
                                <enumeratedValue>
                                    <name>1</name>
                                    <description>High level</description>
                                    <value>#1</value>
                                </enumeratedValue>
                            </enumeratedValues>
                        </field>
                        <field>
                            <name>PIDR09</name>
                            <description>Pmn State</description>
                            <lsb>9</lsb>
                            <msb>9</msb>
                            <access>read-only</access>
                            <enumeratedValues>
                                <enumeratedValue>
                                    <name>0</name>
                                    <description>Low level</description>
                                    <value>#0</value>
                                </enumeratedValue>
                                <enumeratedValue>
                                    <name>1</name>
                                    <description>High level</description>
                                    <value>#1</value>
                                </enumeratedValue>
                            </enumeratedValues>
                        </field>
                        <field>
                            <name>PIDR10</name>
                            <description>Pmn State</description>
                            <lsb>10</lsb>
                            <msb>10</msb>
                            <access>read-only</access>
                            <enumeratedValues>
                                <enumeratedValue>
                                    <name>0</name>
                                    <description>Low level</description>
                                    <value>#0</value>
                                </enumeratedValue>
                                <enumeratedValue>
                                    <name>1</name>
                                    <description>High level</description>
                                    <value>#1</value>
                                </enumeratedValue>
                            </enumeratedValues>
                        </field>
                        <field>
                            <name>PIDR11</name>
                            <description>Pmn State</description>
                            <lsb>11</lsb>
                            <msb>11</msb>
                            <access>read-only</access>
                            <enumeratedValues>
                                <enumeratedValue>
                                    <name>0</name>
                                    <description>Low level</description>
                                    <value>#0</value>
                                </enumeratedValue>
                                <enumeratedValue>
                                    <name>1</name>
                                    <description>High level</description>
                                    <value>#1</value>
                                </enumeratedValue>
                            </enumeratedValues>
                        </field>
                        <field>
                            <name>PIDR12</name>
                            <description>Pmn State</description>
                            <lsb>12</lsb>
                            <msb>12</msb>
                            <access>read-only</access>
                            <enumeratedValues>
                                <enumeratedValue>
                                    <name>0</name>
                                    <description>Low level</description>
                                    <value>#0</value>
                                </enumeratedValue>
                                <enumeratedValue>
                                    <name>1</name>
                                    <description>High level</description>
                                    <value>#1</value>
                                </enumeratedValue>
                            </enumeratedValues>
                        </field>
                        <field>
                            <name>PIDR13</name>
                            <description>Pmn State</description>
                            <lsb>13</lsb>
                            <msb>13</msb>
                            <access>read-only</access>
                            <enumeratedValues>
                                <enumeratedValue>
                                    <name>0</name>
                                    <description>Low level</description>
                                    <value>#0</value>
                                </enumeratedValue>
                                <enumeratedValue>
                                    <name>1</name>
                                    <description>High level</description>
                                    <value>#1</value>
                                </enumeratedValue>
                            </enumeratedValues>
                        </field>
                        <field>
                            <name>PIDR14</name>
                            <description>Pmn State</description>
                            <lsb>14</lsb>
                            <msb>14</msb>
                            <access>read-only</access>
                            <enumeratedValues>
                                <enumeratedValue>
                                    <name>0</name>
                                    <description>Low level</description>
                                    <value>#0</value>
                                </enumeratedValue>
                                <enumeratedValue>
                                    <name>1</name>
                                    <description>High level</description>
                                    <value>#1</value>
                                </enumeratedValue>
                            </enumeratedValues>
                        </field>
                        <field>
                            <name>PIDR15</name>
                            <description>Pmn State</description>
                            <lsb>15</lsb>
                            <msb>15</msb>
                            <access>read-only</access>
                            <enumeratedValues>
                                <enumeratedValue>
                                    <name>0</name>
                                    <description>Low level</description>
                                    <value>#0</value>
                                </enumeratedValue>
                                <enumeratedValue>
                                    <name>1</name>
                                    <description>High level</description>
                                    <value>#1</value>
                                </enumeratedValue>
                            </enumeratedValues>
                        </field>
                    </fields>
                </register>
                <register>
                    <name>PCNTR3</name>
                    <description>Port Control Register 3</description>
                    <addressOffset>0x008</addressOffset>
                    <size>32</size>
                    <access>write-only</access>
                    <resetValue>0x00000000</resetValue>
                    <resetMask>0xffffffff</resetMask>
                    <fields>
                        <field>
                            <name>POSR00</name>
                            <description>Pmn Output Set</description>
                            <lsb>0</lsb>
                            <msb>0</msb>
                            <access>write-only</access>
                            <enumeratedValues>
                                <enumeratedValue>
                                    <name>0</name>
                                    <description>No effect on output</description>
                                    <value>#0</value>
                                </enumeratedValue>
                                <enumeratedValue>
                                    <name>1</name>
                                    <description>High output</description>
                                    <value>#1</value>
                                </enumeratedValue>
                            </enumeratedValues>
                        </field>
                        <field>
                            <name>POSR01</name>
                            <description>Pmn Output Set</description>
                            <lsb>1</lsb>
                            <msb>1</msb>
                            <access>write-only</access>
                            <enumeratedValues>
                                <enumeratedValue>
                                    <name>0</name>
                                    <description>No effect on output</description>
                                    <value>#0</value>
                                </enumeratedValue>
                                <enumeratedValue>
                                    <name>1</name>
                                    <description>High output</description>
                                    <value>#1</value>
                                </enumeratedValue>
                            </enumeratedValues>
                        </field>
                        <field>
                            <name>POSR02</name>
                            <description>Pmn Output Set</description>
                            <lsb>2</lsb>
                            <msb>2</msb>
                            <access>write-only</access>
                            <enumeratedValues>
                                <enumeratedValue>
                                    <name>0</name>
                                    <description>No effect on output</description>
                                    <value>#0</value>
                                </enumeratedValue>
                                <enumeratedValue>
                                    <name>1</name>
                                    <description>High output</description>
                                    <value>#1</value>
                                </enumeratedValue>
                            </enumeratedValues>
                        </field>
                        <field>
                            <name>POSR03</name>
                            <description>Pmn Output Set</description>
                            <lsb>3</lsb>
                            <msb>3</msb>
                            <access>write-only</access>
                            <enumeratedValues>
                                <enumeratedValue>
                                    <name>0</name>
                                    <description>No effect on output</description>
                                    <value>#0</value>
                                </enumeratedValue>
                                <enumeratedValue>
                                    <name>1</name>
                                    <description>High output</description>
                                    <value>#1</value>
                                </enumeratedValue>
                            </enumeratedValues>
                        </field>
                        <field>
                            <name>POSR04</name>
                            <description>Pmn Output Set</description>
                            <lsb>4</lsb>
                            <msb>4</msb>
                            <access>write-only</access>
                            <enumeratedValues>
                                <enumeratedValue>
                                    <name>0</name>
                                    <description>No effect on output</description>
                                    <value>#0</value>
                                </enumeratedValue>
                                <enumeratedValue>
                                    <name>1</name>
                                    <description>High output</description>
                                    <value>#1</value>
                                </enumeratedValue>
                            </enumeratedValues>
                        </field>
                        <field>
                            <name>POSR05</name>
                            <description>Pmn Output Set</description>
                            <lsb>5</lsb>
                            <msb>5</msb>
                            <access>write-only</access>
                            <enumeratedValues>
                                <enumeratedValue>
                                    <name>0</name>
                                    <description>No effect on output</description>
                                    <value>#0</value>
                                </enumeratedValue>
                                <enumeratedValue>
                                    <name>1</name>
                                    <description>High output</description>
                                    <value>#1</value>
                                </enumeratedValue>
                            </enumeratedValues>
                        </field>
                        <field>
                            <name>POSR06</name>
                            <description>Pmn Output Set</description>
                            <lsb>6</lsb>
                            <msb>6</msb>
                            <access>write-only</access>
                            <enumeratedValues>
                                <enumeratedValue>
                                    <name>0</name>
                                    <description>No effect on output</description>
                                    <value>#0</value>
                                </enumeratedValue>
                                <enumeratedValue>
                                    <name>1</name>
                                    <description>High output</description>
                                    <value>#1</value>
                                </enumeratedValue>
                            </enumeratedValues>
                        </field>
                        <field>
                            <name>POSR07</name>
                            <description>Pmn Output Set</description>
                            <lsb>7</lsb>
                            <msb>7</msb>
                            <access>write-only</access>
                            <enumeratedValues>
                                <enumeratedValue>
                                    <name>0</name>
                                    <description>No effect on output</description>
                                    <value>#0</value>
                                </enumeratedValue>
                                <enumeratedValue>
                                    <name>1</name>
                                    <description>High output</description>
                                    <value>#1</value>
                                </enumeratedValue>
                            </enumeratedValues>
                        </field>
                        <field>
                            <name>POSR08</name>
                            <description>Pmn Output Set</description>
                            <lsb>8</lsb>
                            <msb>8</msb>
                            <access>write-only</access>
                            <enumeratedValues>
                                <enumeratedValue>
                                    <name>0</name>
                                    <description>No effect on output</description>
                                    <value>#0</value>
                                </enumeratedValue>
                                <enumeratedValue>
                                    <name>1</name>
                                    <description>High output</description>
                                    <value>#1</value>
                                </enumeratedValue>
                            </enumeratedValues>
                        </field>
                        <field>
                            <name>POSR09</name>
                            <description>Pmn Output Set</description>
                            <lsb>9</lsb>
                            <msb>9</msb>
                            <access>write-only</access>
                            <enumeratedValues>
                                <enumeratedValue>
                                    <name>0</name>
                                    <description>No effect on output</description>
                                    <value>#0</value>
                                </enumeratedValue>
                                <enumeratedValue>
                                    <name>1</name>
                                    <description>High output</description>
                                    <value>#1</value>
                                </enumeratedValue>
                            </enumeratedValues>
                        </field>
                        <field>
                            <name>POSR10</name>
                            <description>Pmn Output Set</description>
                            <lsb>10</lsb>
                            <msb>10</msb>
                            <access>write-only</access>
                            <enumeratedValues>
                                <enumeratedValue>
                                    <name>0</name>
                                    <description>No effect on output</description>
                                    <value>#0</value>
                                </enumeratedValue>
                                <enumeratedValue>
                                    <name>1</name>
                                    <description>High output</description>
                                    <value>#1</value>
                                </enumeratedValue>
                            </enumeratedValues>
                        </field>
                        <field>
                            <name>POSR11</name>
                            <description>Pmn Output Set</description>
                            <lsb>11</lsb>
                            <msb>11</msb>
                            <access>write-only</access>
                            <enumeratedValues>
                                <enumeratedValue>
                                    <name>0</name>
                                    <description>No effect on output</description>
                                    <value>#0</value>
                                </enumeratedValue>
                                <enumeratedValue>
                                    <name>1</name>
                                    <description>High output</description>
                                    <value>#1</value>
                                </enumeratedValue>
                            </enumeratedValues>
                        </field>
                        <field>
                            <name>POSR12</name>
                            <description>Pmn Output Set</description>
                            <lsb>12</lsb>
                            <msb>12</msb>
                            <access>write-only</access>
                            <enumeratedValues>
                                <enumeratedValue>
                                    <name>0</name>
                                    <description>No effect on output</description>
                                    <value>#0</value>
                                </enumeratedValue>
                                <enumeratedValue>
                                    <name>1</name>
                                    <description>High output</description>
                                    <value>#1</value>
                                </enumeratedValue>
                            </enumeratedValues>
                        </field>
                        <field>
                            <name>POSR13</name>
                            <description>Pmn Output Set</description>
                            <lsb>13</lsb>
                            <msb>13</msb>
                            <access>write-only</access>
                            <enumeratedValues>
                                <enumeratedValue>
                                    <name>0</name>
                                    <description>No effect on output</description>
                                    <value>#0</value>
                                </enumeratedValue>
                                <enumeratedValue>
                                    <name>1</name>
                                    <description>High output</description>
                                    <value>#1</value>
                                </enumeratedValue>
                            </enumeratedValues>
                        </field>
                        <field>
                            <name>POSR14</name>
                            <description>Pmn Output Set</description>
                            <lsb>14</lsb>
                            <msb>14</msb>
                            <access>write-only</access>
                            <enumeratedValues>
                                <enumeratedValue>
                                    <name>0</name>
                                    <description>No effect on output</description>
                                    <value>#0</value>
                                </enumeratedValue>
                                <enumeratedValue>
                                    <name>1</name>
                                    <description>High output</description>
                                    <value>#1</value>
                                </enumeratedValue>
                            </enumeratedValues>
                        </field>
                        <field>
                            <name>POSR15</name>
                            <description>Pmn Output Set</description>
                            <lsb>15</lsb>
                            <msb>15</msb>
                            <access>write-only</access>
                            <enumeratedValues>
                                <enumeratedValue>
                                    <name>0</name>
                                    <description>No effect on output</description>
                                    <value>#0</value>
                                </enumeratedValue>
                                <enumeratedValue>
                                    <name>1</name>
                                    <description>High output</description>
                                    <value>#1</value>
                                </enumeratedValue>
                            </enumeratedValues>
                        </field>
                        <field>
                            <name>PORR00</name>
                            <description>Pmn Output Reset</description>
                            <lsb>16</lsb>
                            <msb>16</msb>
                            <access>write-only</access>
                            <enumeratedValues>
                                <enumeratedValue>
                                    <name>0</name>
                                    <description>No effect on output</description>
                                    <value>#0</value>
                                </enumeratedValue>
                                <enumeratedValue>
                                    <name>1</name>
                                    <description>Low output</description>
                                    <value>#1</value>
                                </enumeratedValue>
                            </enumeratedValues>
                        </field>
                        <field>
                            <name>PORR01</name>
                            <description>Pmn Output Reset</description>
                            <lsb>17</lsb>
                            <msb>17</msb>
                            <access>write-only</access>
                            <enumeratedValues>
                                <enumeratedValue>
                                    <name>0</name>
                                    <description>No effect on output</description>
                                    <value>#0</value>
                                </enumeratedValue>
                                <enumeratedValue>
                                    <name>1</name>
                                    <description>Low output</description>
                                    <value>#1</value>
                                </enumeratedValue>
                            </enumeratedValues>
                        </field>
                        <field>
                            <name>PORR02</name>
                            <description>Pmn Output Reset</description>
                            <lsb>18</lsb>
                            <msb>18</msb>
                            <access>write-only</access>
                            <enumeratedValues>
                                <enumeratedValue>
                                    <name>0</name>
                                    <description>No effect on output</description>
                                    <value>#0</value>
                                </enumeratedValue>
                                <enumeratedValue>
                                    <name>1</name>
                                    <description>Low output</description>
                                    <value>#1</value>
                                </enumeratedValue>
                            </enumeratedValues>
                        </field>
                        <field>
                            <name>PORR03</name>
                            <description>Pmn Output Reset</description>
                            <lsb>19</lsb>
                            <msb>19</msb>
                            <access>write-only</access>
                            <enumeratedValues>
                                <enumeratedValue>
                                    <name>0</name>
                                    <description>No effect on output</description>
                                    <value>#0</value>
                                </enumeratedValue>
                                <enumeratedValue>
                                    <name>1</name>
                                    <description>Low output</description>
                                    <value>#1</value>
                                </enumeratedValue>
                            </enumeratedValues>
                        </field>
                        <field>
                            <name>PORR04</name>
                            <description>Pmn Output Reset</description>
                            <lsb>20</lsb>
                            <msb>20</msb>
                            <access>write-only</access>
                            <enumeratedValues>
                                <enumeratedValue>
                                    <name>0</name>
                                    <description>No effect on output</description>
                                    <value>#0</value>
                                </enumeratedValue>
                                <enumeratedValue>
                                    <name>1</name>
                                    <description>Low output</description>
                                    <value>#1</value>
                                </enumeratedValue>
                            </enumeratedValues>
                        </field>
                        <field>
                            <name>PORR05</name>
                            <description>Pmn Output Reset</description>
                            <lsb>21</lsb>
                            <msb>21</msb>
                            <access>write-only</access>
                            <enumeratedValues>
                                <enumeratedValue>
                                    <name>0</name>
                                    <description>No effect on output</description>
                                    <value>#0</value>
                                </enumeratedValue>
                                <enumeratedValue>
                                    <name>1</name>
                                    <description>Low output</description>
                                    <value>#1</value>
                                </enumeratedValue>
                            </enumeratedValues>
                        </field>
                        <field>
                            <name>PORR06</name>
                            <description>Pmn Output Reset</description>
                            <lsb>22</lsb>
                            <msb>22</msb>
                            <access>write-only</access>
                            <enumeratedValues>
                                <enumeratedValue>
                                    <name>0</name>
                                    <description>No effect on output</description>
                                    <value>#0</value>
                                </enumeratedValue>
                                <enumeratedValue>
                                    <name>1</name>
                                    <description>Low output</description>
                                    <value>#1</value>
                                </enumeratedValue>
                            </enumeratedValues>
                        </field>
                        <field>
                            <name>PORR07</name>
                            <description>Pmn Output Reset</description>
                            <lsb>23</lsb>
                            <msb>23</msb>
                            <access>write-only</access>
                            <enumeratedValues>
                                <enumeratedValue>
                                    <name>0</name>
                                    <description>No effect on output</description>
                                    <value>#0</value>
                                </enumeratedValue>
                                <enumeratedValue>
                                    <name>1</name>
                                    <description>Low output</description>
                                    <value>#1</value>
                                </enumeratedValue>
                            </enumeratedValues>
                        </field>
                        <field>
                            <name>PORR08</name>
                            <description>Pmn Output Reset</description>
                            <lsb>24</lsb>
                            <msb>24</msb>
                            <access>write-only</access>
                            <enumeratedValues>
                                <enumeratedValue>
                                    <name>0</name>
                                    <description>No effect on output</description>
                                    <value>#0</value>
                                </enumeratedValue>
                                <enumeratedValue>
                                    <name>1</name>
                                    <description>Low output</description>
                                    <value>#1</value>
                                </enumeratedValue>
                            </enumeratedValues>
                        </field>
                        <field>
                            <name>PORR09</name>
                            <description>Pmn Output Reset</description>
                            <lsb>25</lsb>
                            <msb>25</msb>
                            <access>write-only</access>
                            <enumeratedValues>
                                <enumeratedValue>
                                    <name>0</name>
                                    <description>No effect on output</description>
                                    <value>#0</value>
                                </enumeratedValue>
                                <enumeratedValue>
                                    <name>1</name>
                                    <description>Low output</description>
                                    <value>#1</value>
                                </enumeratedValue>
                            </enumeratedValues>
                        </field>
                        <field>
                            <name>PORR10</name>
                            <description>Pmn Output Reset</description>
                            <lsb>26</lsb>
                            <msb>26</msb>
                            <access>write-only</access>
                            <enumeratedValues>
                                <enumeratedValue>
                                    <name>0</name>
                                    <description>No effect on output</description>
                                    <value>#0</value>
                                </enumeratedValue>
                                <enumeratedValue>
                                    <name>1</name>
                                    <description>Low output</description>
                                    <value>#1</value>
                                </enumeratedValue>
                            </enumeratedValues>
                        </field>
                        <field>
                            <name>PORR11</name>
                            <description>Pmn Output Reset</description>
                            <lsb>27</lsb>
                            <msb>27</msb>
                            <access>write-only</access>
                            <enumeratedValues>
                                <enumeratedValue>
                                    <name>0</name>
                                    <description>No effect on output</description>
                                    <value>#0</value>
                                </enumeratedValue>
                                <enumeratedValue>
                                    <name>1</name>
                                    <description>Low output</description>
                                    <value>#1</value>
                                </enumeratedValue>
                            </enumeratedValues>
                        </field>
                        <field>
                            <name>PORR12</name>
                            <description>Pmn Output Reset</description>
                            <lsb>28</lsb>
                            <msb>28</msb>
                            <access>write-only</access>
                            <enumeratedValues>
                                <enumeratedValue>
                                    <name>0</name>
                                    <description>No effect on output</description>
                                    <value>#0</value>
                                </enumeratedValue>
                                <enumeratedValue>
                                    <name>1</name>
                                    <description>Low output</description>
                                    <value>#1</value>
                                </enumeratedValue>
                            </enumeratedValues>
                        </field>
                        <field>
                            <name>PORR13</name>
                            <description>Pmn Output Reset</description>
                            <lsb>29</lsb>
                            <msb>29</msb>
                            <access>write-only</access>
                            <enumeratedValues>
                                <enumeratedValue>
                                    <name>0</name>
                                    <description>No effect on output</description>
                                    <value>#0</value>
                                </enumeratedValue>
                                <enumeratedValue>
                                    <name>1</name>
                                    <description>Low output</description>
                                    <value>#1</value>
                                </enumeratedValue>
                            </enumeratedValues>
                        </field>
                        <field>
                            <name>PORR14</name>
                            <description>Pmn Output Reset</description>
                            <lsb>30</lsb>
                            <msb>30</msb>
                            <access>write-only</access>
                            <enumeratedValues>
                                <enumeratedValue>
                                    <name>0</name>
                                    <description>No effect on output</description>
                                    <value>#0</value>
                                </enumeratedValue>
                                <enumeratedValue>
                                    <name>1</name>
                                    <description>Low output</description>
                                    <value>#1</value>
                                </enumeratedValue>
                            </enumeratedValues>
                        </field>
                        <field>
                            <name>PORR15</name>
                            <description>Pmn Output Reset</description>
                            <lsb>31</lsb>
                            <msb>31</msb>
                            <access>write-only</access>
                            <enumeratedValues>
                                <enumeratedValue>
                                    <name>0</name>
                                    <description>No effect on output</description>
                                    <value>#0</value>
                                </enumeratedValue>
                                <enumeratedValue>
                                    <name>1</name>
                                    <description>Low output</description>
                                    <value>#1</value>
                                </enumeratedValue>
                            </enumeratedValues>
                        </field>
                    </fields>
                </register>
                <register>
                    <name>POSR</name>
                    <description>Port Control Register 3</description>
                    <alternateRegister>PCNTR3</alternateRegister>
                    <addressOffset>0x008</addressOffset>
                    <size>16</size>
                    <access>write-only</access>
                    <resetValue>0x0000</resetValue>
                    <resetMask>0xffff</resetMask>
                    <fields>
                        <field>
                            <name>PORR00</name>
                            <description>Pmn Output Reset</description>
                            <lsb>0</lsb>
                            <msb>0</msb>
                            <access>write-only</access>
                            <enumeratedValues>
                                <enumeratedValue>
                                    <name>0</name>
                                    <description>No effect on output</description>
                                    <value>#0</value>
                                </enumeratedValue>
                                <enumeratedValue>
                                    <name>1</name>
                                    <description>Low output</description>
                                    <value>#1</value>
                                </enumeratedValue>
                            </enumeratedValues>
                        </field>
                        <field>
                            <name>PORR01</name>
                            <description>Pmn Output Reset</description>
                            <lsb>1</lsb>
                            <msb>1</msb>
                            <access>write-only</access>
                            <enumeratedValues>
                                <enumeratedValue>
                                    <name>0</name>
                                    <description>No effect on output</description>
                                    <value>#0</value>
                                </enumeratedValue>
                                <enumeratedValue>
                                    <name>1</name>
                                    <description>Low output</description>
                                    <value>#1</value>
                                </enumeratedValue>
                            </enumeratedValues>
                        </field>
                        <field>
                            <name>PORR02</name>
                            <description>Pmn Output Reset</description>
                            <lsb>2</lsb>
                            <msb>2</msb>
                            <access>write-only</access>
                            <enumeratedValues>
                                <enumeratedValue>
                                    <name>0</name>
                                    <description>No effect on output</description>
                                    <value>#0</value>
                                </enumeratedValue>
                                <enumeratedValue>
                                    <name>1</name>
                                    <description>Low output</description>
                                    <value>#1</value>
                                </enumeratedValue>
                            </enumeratedValues>
                        </field>
                        <field>
                            <name>PORR03</name>
                            <description>Pmn Output Reset</description>
                            <lsb>3</lsb>
                            <msb>3</msb>
                            <access>write-only</access>
                            <enumeratedValues>
                                <enumeratedValue>
                                    <name>0</name>
                                    <description>No effect on output</description>
                                    <value>#0</value>
                                </enumeratedValue>
                                <enumeratedValue>
                                    <name>1</name>
                                    <description>Low output</description>
                                    <value>#1</value>
                                </enumeratedValue>
                            </enumeratedValues>
                        </field>
                        <field>
                            <name>PORR04</name>
                            <description>Pmn Output Reset</description>
                            <lsb>4</lsb>
                            <msb>4</msb>
                            <access>write-only</access>
                            <enumeratedValues>
                                <enumeratedValue>
                                    <name>0</name>
                                    <description>No effect on output</description>
                                    <value>#0</value>
                                </enumeratedValue>
                                <enumeratedValue>
                                    <name>1</name>
                                    <description>Low output</description>
                                    <value>#1</value>
                                </enumeratedValue>
                            </enumeratedValues>
                        </field>
                        <field>
                            <name>PORR05</name>
                            <description>Pmn Output Reset</description>
                            <lsb>5</lsb>
                            <msb>5</msb>
                            <access>write-only</access>
                            <enumeratedValues>
                                <enumeratedValue>
                                    <name>0</name>
                                    <description>No effect on output</description>
                                    <value>#0</value>
                                </enumeratedValue>
                                <enumeratedValue>
                                    <name>1</name>
                                    <description>Low output</description>
                                    <value>#1</value>
                                </enumeratedValue>
                            </enumeratedValues>
                        </field>
                        <field>
                            <name>PORR06</name>
                            <description>Pmn Output Reset</description>
                            <lsb>6</lsb>
                            <msb>6</msb>
                            <access>write-only</access>
                            <enumeratedValues>
                                <enumeratedValue>
                                    <name>0</name>
                                    <description>No effect on output</description>
                                    <value>#0</value>
                                </enumeratedValue>
                                <enumeratedValue>
                                    <name>1</name>
                                    <description>Low output</description>
                                    <value>#1</value>
                                </enumeratedValue>
                            </enumeratedValues>
                        </field>
                        <field>
                            <name>PORR07</name>
                            <description>Pmn Output Reset</description>
                            <lsb>7</lsb>
                            <msb>7</msb>
                            <access>write-only</access>
                            <enumeratedValues>
                                <enumeratedValue>
                                    <name>0</name>
                                    <description>No effect on output</description>
                                    <value>#0</value>
                                </enumeratedValue>
                                <enumeratedValue>
                                    <name>1</name>
                                    <description>Low output</description>
                                    <value>#1</value>
                                </enumeratedValue>
                            </enumeratedValues>
                        </field>
                        <field>
                            <name>PORR08</name>
                            <description>Pmn Output Reset</description>
                            <lsb>8</lsb>
                            <msb>8</msb>
                            <access>write-only</access>
                            <enumeratedValues>
                                <enumeratedValue>
                                    <name>0</name>
                                    <description>No effect on output</description>
                                    <value>#0</value>
                                </enumeratedValue>
                                <enumeratedValue>
                                    <name>1</name>
                                    <description>Low output</description>
                                    <value>#1</value>
                                </enumeratedValue>
                            </enumeratedValues>
                        </field>
                        <field>
                            <name>PORR09</name>
                            <description>Pmn Output Reset</description>
                            <lsb>9</lsb>
                            <msb>9</msb>
                            <access>write-only</access>
                            <enumeratedValues>
                                <enumeratedValue>
                                    <name>0</name>
                                    <description>No effect on output</description>
                                    <value>#0</value>
                                </enumeratedValue>
                                <enumeratedValue>
                                    <name>1</name>
                                    <description>Low output</description>
                                    <value>#1</value>
                                </enumeratedValue>
                            </enumeratedValues>
                        </field>
                        <field>
                            <name>PORR10</name>
                            <description>Pmn Output Reset</description>
                            <lsb>10</lsb>
                            <msb>10</msb>
                            <access>write-only</access>
                            <enumeratedValues>
                                <enumeratedValue>
                                    <name>0</name>
                                    <description>No effect on output</description>
                                    <value>#0</value>
                                </enumeratedValue>
                                <enumeratedValue>
                                    <name>1</name>
                                    <description>Low output</description>
                                    <value>#1</value>
                                </enumeratedValue>
                            </enumeratedValues>
                        </field>
                        <field>
                            <name>PORR11</name>
                            <description>Pmn Output Reset</description>
                            <lsb>11</lsb>
                            <msb>11</msb>
                            <access>write-only</access>
                            <enumeratedValues>
                                <enumeratedValue>
                                    <name>0</name>
                                    <description>No effect on output</description>
                                    <value>#0</value>
                                </enumeratedValue>
                                <enumeratedValue>
                                    <name>1</name>
                                    <description>Low output</description>
                                    <value>#1</value>
                                </enumeratedValue>
                            </enumeratedValues>
                        </field>
                        <field>
                            <name>PORR12</name>
                            <description>Pmn Output Reset</description>
                            <lsb>12</lsb>
                            <msb>12</msb>
                            <access>write-only</access>
                            <enumeratedValues>
                                <enumeratedValue>
                                    <name>0</name>
                                    <description>No effect on output</description>
                                    <value>#0</value>
                                </enumeratedValue>
                                <enumeratedValue>
                                    <name>1</name>
                                    <description>Low output</description>
                                    <value>#1</value>
                                </enumeratedValue>
                            </enumeratedValues>
                        </field>
                        <field>
                            <name>PORR13</name>
                            <description>Pmn Output Reset</description>
                            <lsb>13</lsb>
                            <msb>13</msb>
                            <access>write-only</access>
                            <enumeratedValues>
                                <enumeratedValue>
                                    <name>0</name>
                                    <description>No effect on output</description>
                                    <value>#0</value>
                                </enumeratedValue>
                                <enumeratedValue>
                                    <name>1</name>
                                    <description>Low output</description>
                                    <value>#1</value>
                                </enumeratedValue>
                            </enumeratedValues>
                        </field>
                        <field>
                            <name>PORR14</name>
                            <description>Pmn Output Reset</description>
                            <lsb>14</lsb>
                            <msb>14</msb>
                            <access>write-only</access>
                            <enumeratedValues>
                                <enumeratedValue>
                                    <name>0</name>
                                    <description>No effect on output</description>
                                    <value>#0</value>
                                </enumeratedValue>
                                <enumeratedValue>
                                    <name>1</name>
                                    <description>Low output</description>
                                    <value>#1</value>
                                </enumeratedValue>
                            </enumeratedValues>
                        </field>
                        <field>
                            <name>PORR15</name>
                            <description>Pmn Output Reset</description>
                            <lsb>15</lsb>
                            <msb>15</msb>
                            <access>write-only</access>
                            <enumeratedValues>
                                <enumeratedValue>
                                    <name>0</name>
                                    <description>No effect on output</description>
                                    <value>#0</value>
                                </enumeratedValue>
                                <enumeratedValue>
                                    <name>1</name>
                                    <description>Low output</description>
                                    <value>#1</value>
                                </enumeratedValue>
                            </enumeratedValues>
                        </field>
                    </fields>
                </register>
                <register>
                    <name>PORR</name>
                    <description>Port Control Register 3</description>
                    <alternateRegister>PCNTR3</alternateRegister>
                    <addressOffset>0x00A</addressOffset>
                    <size>16</size>
                    <access>write-only</access>
                    <resetValue>0x0000</resetValue>
                    <resetMask>0xffff</resetMask>
                    <fields>
                        <field>
                            <name>POSR00</name>
                            <description>Pmn Output Set</description>
                            <lsb>0</lsb>
                            <msb>0</msb>
                            <access>write-only</access>
                            <enumeratedValues>
                                <enumeratedValue>
                                    <name>0</name>
                                    <description>No effect on output</description>
                                    <value>#0</value>
                                </enumeratedValue>
                                <enumeratedValue>
                                    <name>1</name>
                                    <description>High output</description>
                                    <value>#1</value>
                                </enumeratedValue>
                            </enumeratedValues>
                        </field>
                        <field>
                            <name>POSR01</name>
                            <description>Pmn Output Set</description>
                            <lsb>1</lsb>
                            <msb>1</msb>
                            <access>write-only</access>
                            <enumeratedValues>
                                <enumeratedValue>
                                    <name>0</name>
                                    <description>No effect on output</description>
                                    <value>#0</value>
                                </enumeratedValue>
                                <enumeratedValue>
                                    <name>1</name>
                                    <description>High output</description>
                                    <value>#1</value>
                                </enumeratedValue>
                            </enumeratedValues>
                        </field>
                        <field>
                            <name>POSR02</name>
                            <description>Pmn Output Set</description>
                            <lsb>2</lsb>
                            <msb>2</msb>
                            <access>write-only</access>
                            <enumeratedValues>
                                <enumeratedValue>
                                    <name>0</name>
                                    <description>No effect on output</description>
                                    <value>#0</value>
                                </enumeratedValue>
                                <enumeratedValue>
                                    <name>1</name>
                                    <description>High output</description>
                                    <value>#1</value>
                                </enumeratedValue>
                            </enumeratedValues>
                        </field>
                        <field>
                            <name>POSR03</name>
                            <description>Pmn Output Set</description>
                            <lsb>3</lsb>
                            <msb>3</msb>
                            <access>write-only</access>
                            <enumeratedValues>
                                <enumeratedValue>
                                    <name>0</name>
                                    <description>No effect on output</description>
                                    <value>#0</value>
                                </enumeratedValue>
                                <enumeratedValue>
                                    <name>1</name>
                                    <description>High output</description>
                                    <value>#1</value>
                                </enumeratedValue>
                            </enumeratedValues>
                        </field>
                        <field>
                            <name>POSR04</name>
                            <description>Pmn Output Set</description>
                            <lsb>4</lsb>
                            <msb>4</msb>
                            <access>write-only</access>
                            <enumeratedValues>
                                <enumeratedValue>
                                    <name>0</name>
                                    <description>No effect on output</description>
                                    <value>#0</value>
                                </enumeratedValue>
                                <enumeratedValue>
                                    <name>1</name>
                                    <description>High output</description>
                                    <value>#1</value>
                                </enumeratedValue>
                            </enumeratedValues>
                        </field>
                        <field>
                            <name>POSR05</name>
                            <description>Pmn Output Set</description>
                            <lsb>5</lsb>
                            <msb>5</msb>
                            <access>write-only</access>
                            <enumeratedValues>
                                <enumeratedValue>
                                    <name>0</name>
                                    <description>No effect on output</description>
                                    <value>#0</value>
                                </enumeratedValue>
                                <enumeratedValue>
                                    <name>1</name>
                                    <description>High output</description>
                                    <value>#1</value>
                                </enumeratedValue>
                            </enumeratedValues>
                        </field>
                        <field>
                            <name>POSR06</name>
                            <description>Pmn Output Set</description>
                            <lsb>6</lsb>
                            <msb>6</msb>
                            <access>write-only</access>
                            <enumeratedValues>
                                <enumeratedValue>
                                    <name>0</name>
                                    <description>No effect on output</description>
                                    <value>#0</value>
                                </enumeratedValue>
                                <enumeratedValue>
                                    <name>1</name>
                                    <description>High output</description>
                                    <value>#1</value>
                                </enumeratedValue>
                            </enumeratedValues>
                        </field>
                        <field>
                            <name>POSR07</name>
                            <description>Pmn Output Set</description>
                            <lsb>7</lsb>
                            <msb>7</msb>
                            <access>write-only</access>
                            <enumeratedValues>
                                <enumeratedValue>
                                    <name>0</name>
                                    <description>No effect on output</description>
                                    <value>#0</value>
                                </enumeratedValue>
                                <enumeratedValue>
                                    <name>1</name>
                                    <description>High output</description>
                                    <value>#1</value>
                                </enumeratedValue>
                            </enumeratedValues>
                        </field>
                        <field>
                            <name>POSR08</name>
                            <description>Pmn Output Set</description>
                            <lsb>8</lsb>
                            <msb>8</msb>
                            <access>write-only</access>
                            <enumeratedValues>
                                <enumeratedValue>
                                    <name>0</name>
                                    <description>No effect on output</description>
                                    <value>#0</value>
                                </enumeratedValue>
                                <enumeratedValue>
                                    <name>1</name>
                                    <description>High output</description>
                                    <value>#1</value>
                                </enumeratedValue>
                            </enumeratedValues>
                        </field>
                        <field>
                            <name>POSR09</name>
                            <description>Pmn Output Set</description>
                            <lsb>9</lsb>
                            <msb>9</msb>
                            <access>write-only</access>
                            <enumeratedValues>
                                <enumeratedValue>
                                    <name>0</name>
                                    <description>No effect on output</description>
                                    <value>#0</value>
                                </enumeratedValue>
                                <enumeratedValue>
                                    <name>1</name>
                                    <description>High output</description>
                                    <value>#1</value>
                                </enumeratedValue>
                            </enumeratedValues>
                        </field>
                        <field>
                            <name>POSR10</name>
                            <description>Pmn Output Set</description>
                            <lsb>10</lsb>
                            <msb>10</msb>
                            <access>write-only</access>
                            <enumeratedValues>
                                <enumeratedValue>
                                    <name>0</name>
                                    <description>No effect on output</description>
                                    <value>#0</value>
                                </enumeratedValue>
                                <enumeratedValue>
                                    <name>1</name>
                                    <description>High output</description>
                                    <value>#1</value>
                                </enumeratedValue>
                            </enumeratedValues>
                        </field>
                        <field>
                            <name>POSR11</name>
                            <description>Pmn Output Set</description>
                            <lsb>11</lsb>
                            <msb>11</msb>
                            <access>write-only</access>
                            <enumeratedValues>
                                <enumeratedValue>
                                    <name>0</name>
                                    <description>No effect on output</description>
                                    <value>#0</value>
                                </enumeratedValue>
                                <enumeratedValue>
                                    <name>1</name>
                                    <description>High output</description>
                                    <value>#1</value>
                                </enumeratedValue>
                            </enumeratedValues>
                        </field>
                        <field>
                            <name>POSR12</name>
                            <description>Pmn Output Set</description>
                            <lsb>12</lsb>
                            <msb>12</msb>
                            <access>write-only</access>
                            <enumeratedValues>
                                <enumeratedValue>
                                    <name>0</name>
                                    <description>No effect on output</description>
                                    <value>#0</value>
                                </enumeratedValue>
                                <enumeratedValue>
                                    <name>1</name>
                                    <description>High output</description>
                                    <value>#1</value>
                                </enumeratedValue>
                            </enumeratedValues>
                        </field>
                        <field>
                            <name>POSR13</name>
                            <description>Pmn Output Set</description>
                            <lsb>13</lsb>
                            <msb>13</msb>
                            <access>write-only</access>
                            <enumeratedValues>
                                <enumeratedValue>
                                    <name>0</name>
                                    <description>No effect on output</description>
                                    <value>#0</value>
                                </enumeratedValue>
                                <enumeratedValue>
                                    <name>1</name>
                                    <description>High output</description>
                                    <value>#1</value>
                                </enumeratedValue>
                            </enumeratedValues>
                        </field>
                        <field>
                            <name>POSR14</name>
                            <description>Pmn Output Set</description>
                            <lsb>14</lsb>
                            <msb>14</msb>
                            <access>write-only</access>
                            <enumeratedValues>
                                <enumeratedValue>
                                    <name>0</name>
                                    <description>No effect on output</description>
                                    <value>#0</value>
                                </enumeratedValue>
                                <enumeratedValue>
                                    <name>1</name>
                                    <description>High output</description>
                                    <value>#1</value>
                                </enumeratedValue>
                            </enumeratedValues>
                        </field>
                        <field>
                            <name>POSR15</name>
                            <description>Pmn Output Set</description>
                            <lsb>15</lsb>
                            <msb>15</msb>
                            <access>write-only</access>
                            <enumeratedValues>
                                <enumeratedValue>
                                    <name>0</name>
                                    <description>No effect on output</description>
                                    <value>#0</value>
                                </enumeratedValue>
                                <enumeratedValue>
                                    <name>1</name>
                                    <description>High output</description>
                                    <value>#1</value>
                                </enumeratedValue>
                            </enumeratedValues>
                        </field>
                    </fields>
                </register>
                <register>
                    <name>PCNTR4</name>
                    <description>Port Control Register 4</description>
                    <addressOffset>0x00C</addressOffset>
                    <size>32</size>
                    <access>read-write</access>
                    <resetValue>0x00000000</resetValue>
                    <resetMask>0xffffffff</resetMask>
                    <fields>
                        <field>
                            <name>EOSR00</name>
                            <description>Pmn Event Output Set</description>
                            <lsb>0</lsb>
                            <msb>0</msb>
                            <access>read-write</access>
                            <enumeratedValues>
                                <enumeratedValue>
                                    <name>0</name>
                                    <description>No effect on output</description>
                                    <value>#0</value>
                                </enumeratedValue>
                                <enumeratedValue>
                                    <name>1</name>
                                    <description>High output</description>
                                    <value>#1</value>
                                </enumeratedValue>
                            </enumeratedValues>
                        </field>
                        <field>
                            <name>EOSR01</name>
                            <description>Pmn Event Output Set</description>
                            <lsb>1</lsb>
                            <msb>1</msb>
                            <access>read-write</access>
                            <enumeratedValues>
                                <enumeratedValue>
                                    <name>0</name>
                                    <description>No effect on output</description>
                                    <value>#0</value>
                                </enumeratedValue>
                                <enumeratedValue>
                                    <name>1</name>
                                    <description>High output</description>
                                    <value>#1</value>
                                </enumeratedValue>
                            </enumeratedValues>
                        </field>
                        <field>
                            <name>EOSR02</name>
                            <description>Pmn Event Output Set</description>
                            <lsb>2</lsb>
                            <msb>2</msb>
                            <access>read-write</access>
                            <enumeratedValues>
                                <enumeratedValue>
                                    <name>0</name>
                                    <description>No effect on output</description>
                                    <value>#0</value>
                                </enumeratedValue>
                                <enumeratedValue>
                                    <name>1</name>
                                    <description>High output</description>
                                    <value>#1</value>
                                </enumeratedValue>
                            </enumeratedValues>
                        </field>
                        <field>
                            <name>EOSR03</name>
                            <description>Pmn Event Output Set</description>
                            <lsb>3</lsb>
                            <msb>3</msb>
                            <access>read-write</access>
                            <enumeratedValues>
                                <enumeratedValue>
                                    <name>0</name>
                                    <description>No effect on output</description>
                                    <value>#0</value>
                                </enumeratedValue>
                                <enumeratedValue>
                                    <name>1</name>
                                    <description>High output</description>
                                    <value>#1</value>
                                </enumeratedValue>
                            </enumeratedValues>
                        </field>
                        <field>
                            <name>EOSR04</name>
                            <description>Pmn Event Output Set</description>
                            <lsb>4</lsb>
                            <msb>4</msb>
                            <access>read-write</access>
                            <enumeratedValues>
                                <enumeratedValue>
                                    <name>0</name>
                                    <description>No effect on output</description>
                                    <value>#0</value>
                                </enumeratedValue>
                                <enumeratedValue>
                                    <name>1</name>
                                    <description>High output</description>
                                    <value>#1</value>
                                </enumeratedValue>
                            </enumeratedValues>
                        </field>
                        <field>
                            <name>EOSR05</name>
                            <description>Pmn Event Output Set</description>
                            <lsb>5</lsb>
                            <msb>5</msb>
                            <access>read-write</access>
                            <enumeratedValues>
                                <enumeratedValue>
                                    <name>0</name>
                                    <description>No effect on output</description>
                                    <value>#0</value>
                                </enumeratedValue>
                                <enumeratedValue>
                                    <name>1</name>
                                    <description>High output</description>
                                    <value>#1</value>
                                </enumeratedValue>
                            </enumeratedValues>
                        </field>
                        <field>
                            <name>EOSR06</name>
                            <description>Pmn Event Output Set</description>
                            <lsb>6</lsb>
                            <msb>6</msb>
                            <access>read-write</access>
                            <enumeratedValues>
                                <enumeratedValue>
                                    <name>0</name>
                                    <description>No effect on output</description>
                                    <value>#0</value>
                                </enumeratedValue>
                                <enumeratedValue>
                                    <name>1</name>
                                    <description>High output</description>
                                    <value>#1</value>
                                </enumeratedValue>
                            </enumeratedValues>
                        </field>
                        <field>
                            <name>EOSR07</name>
                            <description>Pmn Event Output Set</description>
                            <lsb>7</lsb>
                            <msb>7</msb>
                            <access>read-write</access>
                            <enumeratedValues>
                                <enumeratedValue>
                                    <name>0</name>
                                    <description>No effect on output</description>
                                    <value>#0</value>
                                </enumeratedValue>
                                <enumeratedValue>
                                    <name>1</name>
                                    <description>High output</description>
                                    <value>#1</value>
                                </enumeratedValue>
                            </enumeratedValues>
                        </field>
                        <field>
                            <name>EOSR08</name>
                            <description>Pmn Event Output Set</description>
                            <lsb>8</lsb>
                            <msb>8</msb>
                            <access>read-write</access>
                            <enumeratedValues>
                                <enumeratedValue>
                                    <name>0</name>
                                    <description>No effect on output</description>
                                    <value>#0</value>
                                </enumeratedValue>
                                <enumeratedValue>
                                    <name>1</name>
                                    <description>High output</description>
                                    <value>#1</value>
                                </enumeratedValue>
                            </enumeratedValues>
                        </field>
                        <field>
                            <name>EOSR09</name>
                            <description>Pmn Event Output Set</description>
                            <lsb>9</lsb>
                            <msb>9</msb>
                            <access>read-write</access>
                            <enumeratedValues>
                                <enumeratedValue>
                                    <name>0</name>
                                    <description>No effect on output</description>
                                    <value>#0</value>
                                </enumeratedValue>
                                <enumeratedValue>
                                    <name>1</name>
                                    <description>High output</description>
                                    <value>#1</value>
                                </enumeratedValue>
                            </enumeratedValues>
                        </field>
                        <field>
                            <name>EOSR10</name>
                            <description>Pmn Event Output Set</description>
                            <lsb>10</lsb>
                            <msb>10</msb>
                            <access>read-write</access>
                            <enumeratedValues>
                                <enumeratedValue>
                                    <name>0</name>
                                    <description>No effect on output</description>
                                    <value>#0</value>
                                </enumeratedValue>
                                <enumeratedValue>
                                    <name>1</name>
                                    <description>High output</description>
                                    <value>#1</value>
                                </enumeratedValue>
                            </enumeratedValues>
                        </field>
                        <field>
                            <name>EOSR11</name>
                            <description>Pmn Event Output Set</description>
                            <lsb>11</lsb>
                            <msb>11</msb>
                            <access>read-write</access>
                            <enumeratedValues>
                                <enumeratedValue>
                                    <name>0</name>
                                    <description>No effect on output</description>
                                    <value>#0</value>
                                </enumeratedValue>
                                <enumeratedValue>
                                    <name>1</name>
                                    <description>High output</description>
                                    <value>#1</value>
                                </enumeratedValue>
                            </enumeratedValues>
                        </field>
                        <field>
                            <name>EOSR12</name>
                            <description>Pmn Event Output Set</description>
                            <lsb>12</lsb>
                            <msb>12</msb>
                            <access>read-write</access>
                            <enumeratedValues>
                                <enumeratedValue>
                                    <name>0</name>
                                    <description>No effect on output</description>
                                    <value>#0</value>
                                </enumeratedValue>
                                <enumeratedValue>
                                    <name>1</name>
                                    <description>High output</description>
                                    <value>#1</value>
                                </enumeratedValue>
                            </enumeratedValues>
                        </field>
                        <field>
                            <name>EOSR13</name>
                            <description>Pmn Event Output Set</description>
                            <lsb>13</lsb>
                            <msb>13</msb>
                            <access>read-write</access>
                            <enumeratedValues>
                                <enumeratedValue>
                                    <name>0</name>
                                    <description>No effect on output</description>
                                    <value>#0</value>
                                </enumeratedValue>
                                <enumeratedValue>
                                    <name>1</name>
                                    <description>High output</description>
                                    <value>#1</value>
                                </enumeratedValue>
                            </enumeratedValues>
                        </field>
                        <field>
                            <name>EOSR14</name>
                            <description>Pmn Event Output Set</description>
                            <lsb>14</lsb>
                            <msb>14</msb>
                            <access>read-write</access>
                            <enumeratedValues>
                                <enumeratedValue>
                                    <name>0</name>
                                    <description>No effect on output</description>
                                    <value>#0</value>
                                </enumeratedValue>
                                <enumeratedValue>
                                    <name>1</name>
                                    <description>High output</description>
                                    <value>#1</value>
                                </enumeratedValue>
                            </enumeratedValues>
                        </field>
                        <field>
                            <name>EOSR15</name>
                            <description>Pmn Event Output Set</description>
                            <lsb>15</lsb>
                            <msb>15</msb>
                            <access>read-write</access>
                            <enumeratedValues>
                                <enumeratedValue>
                                    <name>0</name>
                                    <description>No effect on output</description>
                                    <value>#0</value>
                                </enumeratedValue>
                                <enumeratedValue>
                                    <name>1</name>
                                    <description>High output</description>
                                    <value>#1</value>
                                </enumeratedValue>
                            </enumeratedValues>
                        </field>
                        <field>
                            <name>EORR00</name>
                            <description>Pmn Event Output Reset</description>
                            <lsb>16</lsb>
                            <msb>16</msb>
                            <access>read-write</access>
                            <enumeratedValues>
                                <enumeratedValue>
                                    <name>0</name>
                                    <description>No effect on output</description>
                                    <value>#0</value>
                                </enumeratedValue>
                                <enumeratedValue>
                                    <name>1</name>
                                    <description>Low output</description>
                                    <value>#1</value>
                                </enumeratedValue>
                            </enumeratedValues>
                        </field>
                        <field>
                            <name>EORR01</name>
                            <description>Pmn Event Output Reset</description>
                            <lsb>17</lsb>
                            <msb>17</msb>
                            <access>read-write</access>
                            <enumeratedValues>
                                <enumeratedValue>
                                    <name>0</name>
                                    <description>No effect on output</description>
                                    <value>#0</value>
                                </enumeratedValue>
                                <enumeratedValue>
                                    <name>1</name>
                                    <description>Low output</description>
                                    <value>#1</value>
                                </enumeratedValue>
                            </enumeratedValues>
                        </field>
                        <field>
                            <name>EORR02</name>
                            <description>Pmn Event Output Reset</description>
                            <lsb>18</lsb>
                            <msb>18</msb>
                            <access>read-write</access>
                            <enumeratedValues>
                                <enumeratedValue>
                                    <name>0</name>
                                    <description>No effect on output</description>
                                    <value>#0</value>
                                </enumeratedValue>
                                <enumeratedValue>
                                    <name>1</name>
                                    <description>Low output</description>
                                    <value>#1</value>
                                </enumeratedValue>
                            </enumeratedValues>
                        </field>
                        <field>
                            <name>EORR03</name>
                            <description>Pmn Event Output Reset</description>
                            <lsb>19</lsb>
                            <msb>19</msb>
                            <access>read-write</access>
                            <enumeratedValues>
                                <enumeratedValue>
                                    <name>0</name>
                                    <description>No effect on output</description>
                                    <value>#0</value>
                                </enumeratedValue>
                                <enumeratedValue>
                                    <name>1</name>
                                    <description>Low output</description>
                                    <value>#1</value>
                                </enumeratedValue>
                            </enumeratedValues>
                        </field>
                        <field>
                            <name>EORR04</name>
                            <description>Pmn Event Output Reset</description>
                            <lsb>20</lsb>
                            <msb>20</msb>
                            <access>read-write</access>
                            <enumeratedValues>
                                <enumeratedValue>
                                    <name>0</name>
                                    <description>No effect on output</description>
                                    <value>#0</value>
                                </enumeratedValue>
                                <enumeratedValue>
                                    <name>1</name>
                                    <description>Low output</description>
                                    <value>#1</value>
                                </enumeratedValue>
                            </enumeratedValues>
                        </field>
                        <field>
                            <name>EORR05</name>
                            <description>Pmn Event Output Reset</description>
                            <lsb>21</lsb>
                            <msb>21</msb>
                            <access>read-write</access>
                            <enumeratedValues>
                                <enumeratedValue>
                                    <name>0</name>
                                    <description>No effect on output</description>
                                    <value>#0</value>
                                </enumeratedValue>
                                <enumeratedValue>
                                    <name>1</name>
                                    <description>Low output</description>
                                    <value>#1</value>
                                </enumeratedValue>
                            </enumeratedValues>
                        </field>
                        <field>
                            <name>EORR06</name>
                            <description>Pmn Event Output Reset</description>
                            <lsb>22</lsb>
                            <msb>22</msb>
                            <access>read-write</access>
                            <enumeratedValues>
                                <enumeratedValue>
                                    <name>0</name>
                                    <description>No effect on output</description>
                                    <value>#0</value>
                                </enumeratedValue>
                                <enumeratedValue>
                                    <name>1</name>
                                    <description>Low output</description>
                                    <value>#1</value>
                                </enumeratedValue>
                            </enumeratedValues>
                        </field>
                        <field>
                            <name>EORR07</name>
                            <description>Pmn Event Output Reset</description>
                            <lsb>23</lsb>
                            <msb>23</msb>
                            <access>read-write</access>
                            <enumeratedValues>
                                <enumeratedValue>
                                    <name>0</name>
                                    <description>No effect on output</description>
                                    <value>#0</value>
                                </enumeratedValue>
                                <enumeratedValue>
                                    <name>1</name>
                                    <description>Low output</description>
                                    <value>#1</value>
                                </enumeratedValue>
                            </enumeratedValues>
                        </field>
                        <field>
                            <name>EORR08</name>
                            <description>Pmn Event Output Reset</description>
                            <lsb>24</lsb>
                            <msb>24</msb>
                            <access>read-write</access>
                            <enumeratedValues>
                                <enumeratedValue>
                                    <name>0</name>
                                    <description>No effect on output</description>
                                    <value>#0</value>
                                </enumeratedValue>
                                <enumeratedValue>
                                    <name>1</name>
                                    <description>Low output</description>
                                    <value>#1</value>
                                </enumeratedValue>
                            </enumeratedValues>
                        </field>
                        <field>
                            <name>EORR09</name>
                            <description>Pmn Event Output Reset</description>
                            <lsb>25</lsb>
                            <msb>25</msb>
                            <access>read-write</access>
                            <enumeratedValues>
                                <enumeratedValue>
                                    <name>0</name>
                                    <description>No effect on output</description>
                                    <value>#0</value>
                                </enumeratedValue>
                                <enumeratedValue>
                                    <name>1</name>
                                    <description>Low output</description>
                                    <value>#1</value>
                                </enumeratedValue>
                            </enumeratedValues>
                        </field>
                        <field>
                            <name>EORR10</name>
                            <description>Pmn Event Output Reset</description>
                            <lsb>26</lsb>
                            <msb>26</msb>
                            <access>read-write</access>
                            <enumeratedValues>
                                <enumeratedValue>
                                    <name>0</name>
                                    <description>No effect on output</description>
                                    <value>#0</value>
                                </enumeratedValue>
                                <enumeratedValue>
                                    <name>1</name>
                                    <description>Low output</description>
                                    <value>#1</value>
                                </enumeratedValue>
                            </enumeratedValues>
                        </field>
                        <field>
                            <name>EORR11</name>
                            <description>Pmn Event Output Reset</description>
                            <lsb>27</lsb>
                            <msb>27</msb>
                            <access>read-write</access>
                            <enumeratedValues>
                                <enumeratedValue>
                                    <name>0</name>
                                    <description>No effect on output</description>
                                    <value>#0</value>
                                </enumeratedValue>
                                <enumeratedValue>
                                    <name>1</name>
                                    <description>Low output</description>
                                    <value>#1</value>
                                </enumeratedValue>
                            </enumeratedValues>
                        </field>
                        <field>
                            <name>EORR12</name>
                            <description>Pmn Event Output Reset</description>
                            <lsb>28</lsb>
                            <msb>28</msb>
                            <access>read-write</access>
                            <enumeratedValues>
                                <enumeratedValue>
                                    <name>0</name>
                                    <description>No effect on output</description>
                                    <value>#0</value>
                                </enumeratedValue>
                                <enumeratedValue>
                                    <name>1</name>
                                    <description>Low output</description>
                                    <value>#1</value>
                                </enumeratedValue>
                            </enumeratedValues>
                        </field>
                        <field>
                            <name>EORR13</name>
                            <description>Pmn Event Output Reset</description>
                            <lsb>29</lsb>
                            <msb>29</msb>
                            <access>read-write</access>
                            <enumeratedValues>
                                <enumeratedValue>
                                    <name>0</name>
                                    <description>No effect on output</description>
                                    <value>#0</value>
                                </enumeratedValue>
                                <enumeratedValue>
                                    <name>1</name>
                                    <description>Low output</description>
                                    <value>#1</value>
                                </enumeratedValue>
                            </enumeratedValues>
                        </field>
                        <field>
                            <name>EORR14</name>
                            <description>Pmn Event Output Reset</description>
                            <lsb>30</lsb>
                            <msb>30</msb>
                            <access>read-write</access>
                            <enumeratedValues>
                                <enumeratedValue>
                                    <name>0</name>
                                    <description>No effect on output</description>
                                    <value>#0</value>
                                </enumeratedValue>
                                <enumeratedValue>
                                    <name>1</name>
                                    <description>Low output</description>
                                    <value>#1</value>
                                </enumeratedValue>
                            </enumeratedValues>
                        </field>
                        <field>
                            <name>EORR15</name>
                            <description>Pmn Event Output Reset</description>
                            <lsb>31</lsb>
                            <msb>31</msb>
                            <access>read-write</access>
                            <enumeratedValues>
                                <enumeratedValue>
                                    <name>0</name>
                                    <description>No effect on output</description>
                                    <value>#0</value>
                                </enumeratedValue>
                                <enumeratedValue>
                                    <name>1</name>
                                    <description>Low output</description>
                                    <value>#1</value>
                                </enumeratedValue>
                            </enumeratedValues>
                        </field>
                    </fields>
                </register>
                <register>
                    <name>EOSR</name>
                    <description>Port Control Register 4</description>
                    <alternateRegister>PCNTR4</alternateRegister>
                    <addressOffset>0x00C</addressOffset>
                    <size>16</size>
                    <access>read-write</access>
                    <resetValue>0x0000</resetValue>
                    <resetMask>0xffff</resetMask>
                    <fields>
                        <field>
                            <name>EORR00</name>
                            <description>Pmn Event Output Reset</description>
                            <lsb>0</lsb>
                            <msb>0</msb>
                            <access>read-write</access>
                            <enumeratedValues>
                                <enumeratedValue>
                                    <name>0</name>
                                    <description>No effect on output</description>
                                    <value>#0</value>
                                </enumeratedValue>
                                <enumeratedValue>
                                    <name>1</name>
                                    <description>Low output</description>
                                    <value>#1</value>
                                </enumeratedValue>
                            </enumeratedValues>
                        </field>
                        <field>
                            <name>EORR01</name>
                            <description>Pmn Event Output Reset</description>
                            <lsb>1</lsb>
                            <msb>1</msb>
                            <access>read-write</access>
                            <enumeratedValues>
                                <enumeratedValue>
                                    <name>0</name>
                                    <description>No effect on output</description>
                                    <value>#0</value>
                                </enumeratedValue>
                                <enumeratedValue>
                                    <name>1</name>
                                    <description>Low output</description>
                                    <value>#1</value>
                                </enumeratedValue>
                            </enumeratedValues>
                        </field>
                        <field>
                            <name>EORR02</name>
                            <description>Pmn Event Output Reset</description>
                            <lsb>2</lsb>
                            <msb>2</msb>
                            <access>read-write</access>
                            <enumeratedValues>
                                <enumeratedValue>
                                    <name>0</name>
                                    <description>No effect on output</description>
                                    <value>#0</value>
                                </enumeratedValue>
                                <enumeratedValue>
                                    <name>1</name>
                                    <description>Low output</description>
                                    <value>#1</value>
                                </enumeratedValue>
                            </enumeratedValues>
                        </field>
                        <field>
                            <name>EORR03</name>
                            <description>Pmn Event Output Reset</description>
                            <lsb>3</lsb>
                            <msb>3</msb>
                            <access>read-write</access>
                            <enumeratedValues>
                                <enumeratedValue>
                                    <name>0</name>
                                    <description>No effect on output</description>
                                    <value>#0</value>
                                </enumeratedValue>
                                <enumeratedValue>
                                    <name>1</name>
                                    <description>Low output</description>
                                    <value>#1</value>
                                </enumeratedValue>
                            </enumeratedValues>
                        </field>
                        <field>
                            <name>EORR04</name>
                            <description>Pmn Event Output Reset</description>
                            <lsb>4</lsb>
                            <msb>4</msb>
                            <access>read-write</access>
                            <enumeratedValues>
                                <enumeratedValue>
                                    <name>0</name>
                                    <description>No effect on output</description>
                                    <value>#0</value>
                                </enumeratedValue>
                                <enumeratedValue>
                                    <name>1</name>
                                    <description>Low output</description>
                                    <value>#1</value>
                                </enumeratedValue>
                            </enumeratedValues>
                        </field>
                        <field>
                            <name>EORR05</name>
                            <description>Pmn Event Output Reset</description>
                            <lsb>5</lsb>
                            <msb>5</msb>
                            <access>read-write</access>
                            <enumeratedValues>
                                <enumeratedValue>
                                    <name>0</name>
                                    <description>No effect on output</description>
                                    <value>#0</value>
                                </enumeratedValue>
                                <enumeratedValue>
                                    <name>1</name>
                                    <description>Low output</description>
                                    <value>#1</value>
                                </enumeratedValue>
                            </enumeratedValues>
                        </field>
                        <field>
                            <name>EORR06</name>
                            <description>Pmn Event Output Reset</description>
                            <lsb>6</lsb>
                            <msb>6</msb>
                            <access>read-write</access>
                            <enumeratedValues>
                                <enumeratedValue>
                                    <name>0</name>
                                    <description>No effect on output</description>
                                    <value>#0</value>
                                </enumeratedValue>
                                <enumeratedValue>
                                    <name>1</name>
                                    <description>Low output</description>
                                    <value>#1</value>
                                </enumeratedValue>
                            </enumeratedValues>
                        </field>
                        <field>
                            <name>EORR07</name>
                            <description>Pmn Event Output Reset</description>
                            <lsb>7</lsb>
                            <msb>7</msb>
                            <access>read-write</access>
                            <enumeratedValues>
                                <enumeratedValue>
                                    <name>0</name>
                                    <description>No effect on output</description>
                                    <value>#0</value>
                                </enumeratedValue>
                                <enumeratedValue>
                                    <name>1</name>
                                    <description>Low output</description>
                                    <value>#1</value>
                                </enumeratedValue>
                            </enumeratedValues>
                        </field>
                        <field>
                            <name>EORR08</name>
                            <description>Pmn Event Output Reset</description>
                            <lsb>8</lsb>
                            <msb>8</msb>
                            <access>read-write</access>
                            <enumeratedValues>
                                <enumeratedValue>
                                    <name>0</name>
                                    <description>No effect on output</description>
                                    <value>#0</value>
                                </enumeratedValue>
                                <enumeratedValue>
                                    <name>1</name>
                                    <description>Low output</description>
                                    <value>#1</value>
                                </enumeratedValue>
                            </enumeratedValues>
                        </field>
                        <field>
                            <name>EORR09</name>
                            <description>Pmn Event Output Reset</description>
                            <lsb>9</lsb>
                            <msb>9</msb>
                            <access>read-write</access>
                            <enumeratedValues>
                                <enumeratedValue>
                                    <name>0</name>
                                    <description>No effect on output</description>
                                    <value>#0</value>
                                </enumeratedValue>
                                <enumeratedValue>
                                    <name>1</name>
                                    <description>Low output</description>
                                    <value>#1</value>
                                </enumeratedValue>
                            </enumeratedValues>
                        </field>
                        <field>
                            <name>EORR10</name>
                            <description>Pmn Event Output Reset</description>
                            <lsb>10</lsb>
                            <msb>10</msb>
                            <access>read-write</access>
                            <enumeratedValues>
                                <enumeratedValue>
                                    <name>0</name>
                                    <description>No effect on output</description>
                                    <value>#0</value>
                                </enumeratedValue>
                                <enumeratedValue>
                                    <name>1</name>
                                    <description>Low output</description>
                                    <value>#1</value>
                                </enumeratedValue>
                            </enumeratedValues>
                        </field>
                        <field>
                            <name>EORR11</name>
                            <description>Pmn Event Output Reset</description>
                            <lsb>11</lsb>
                            <msb>11</msb>
                            <access>read-write</access>
                            <enumeratedValues>
                                <enumeratedValue>
                                    <name>0</name>
                                    <description>No effect on output</description>
                                    <value>#0</value>
                                </enumeratedValue>
                                <enumeratedValue>
                                    <name>1</name>
                                    <description>Low output</description>
                                    <value>#1</value>
                                </enumeratedValue>
                            </enumeratedValues>
                        </field>
                        <field>
                            <name>EORR12</name>
                            <description>Pmn Event Output Reset</description>
                            <lsb>12</lsb>
                            <msb>12</msb>
                            <access>read-write</access>
                            <enumeratedValues>
                                <enumeratedValue>
                                    <name>0</name>
                                    <description>No effect on output</description>
                                    <value>#0</value>
                                </enumeratedValue>
                                <enumeratedValue>
                                    <name>1</name>
                                    <description>Low output</description>
                                    <value>#1</value>
                                </enumeratedValue>
                            </enumeratedValues>
                        </field>
                        <field>
                            <name>EORR13</name>
                            <description>Pmn Event Output Reset</description>
                            <lsb>13</lsb>
                            <msb>13</msb>
                            <access>read-write</access>
                            <enumeratedValues>
                                <enumeratedValue>
                                    <name>0</name>
                                    <description>No effect on output</description>
                                    <value>#0</value>
                                </enumeratedValue>
                                <enumeratedValue>
                                    <name>1</name>
                                    <description>Low output</description>
                                    <value>#1</value>
                                </enumeratedValue>
                            </enumeratedValues>
                        </field>
                        <field>
                            <name>EORR14</name>
                            <description>Pmn Event Output Reset</description>
                            <lsb>14</lsb>
                            <msb>14</msb>
                            <access>read-write</access>
                            <enumeratedValues>
                                <enumeratedValue>
                                    <name>0</name>
                                    <description>No effect on output</description>
                                    <value>#0</value>
                                </enumeratedValue>
                                <enumeratedValue>
                                    <name>1</name>
                                    <description>Low output</description>
                                    <value>#1</value>
                                </enumeratedValue>
                            </enumeratedValues>
                        </field>
                        <field>
                            <name>EORR15</name>
                            <description>Pmn Event Output Reset</description>
                            <lsb>15</lsb>
                            <msb>15</msb>
                            <access>read-write</access>
                            <enumeratedValues>
                                <enumeratedValue>
                                    <name>0</name>
                                    <description>No effect on output</description>
                                    <value>#0</value>
                                </enumeratedValue>
                                <enumeratedValue>
                                    <name>1</name>
                                    <description>Low output</description>
                                    <value>#1</value>
                                </enumeratedValue>
                            </enumeratedValues>
                        </field>
                    </fields>
                </register>
                <register>
                    <name>EORR</name>
                    <description>Port Control Register 4</description>
                    <alternateRegister>PCNTR4</alternateRegister>
                    <addressOffset>0x00E</addressOffset>
                    <size>16</size>
                    <access>read-write</access>
                    <resetValue>0x0000</resetValue>
                    <resetMask>0xffff</resetMask>
                    <fields>
                        <field>
                            <name>EOSR00</name>
                            <description>Pmn Event Output Set</description>
                            <lsb>0</lsb>
                            <msb>0</msb>
                            <access>read-write</access>
                            <enumeratedValues>
                                <enumeratedValue>
                                    <name>0</name>
                                    <description>No effect on output</description>
                                    <value>#0</value>
                                </enumeratedValue>
                                <enumeratedValue>
                                    <name>1</name>
                                    <description>High output</description>
                                    <value>#1</value>
                                </enumeratedValue>
                            </enumeratedValues>
                        </field>
                        <field>
                            <name>EOSR01</name>
                            <description>Pmn Event Output Set</description>
                            <lsb>1</lsb>
                            <msb>1</msb>
                            <access>read-write</access>
                            <enumeratedValues>
                                <enumeratedValue>
                                    <name>0</name>
                                    <description>No effect on output</description>
                                    <value>#0</value>
                                </enumeratedValue>
                                <enumeratedValue>
                                    <name>1</name>
                                    <description>High output</description>
                                    <value>#1</value>
                                </enumeratedValue>
                            </enumeratedValues>
                        </field>
                        <field>
                            <name>EOSR02</name>
                            <description>Pmn Event Output Set</description>
                            <lsb>2</lsb>
                            <msb>2</msb>
                            <access>read-write</access>
                            <enumeratedValues>
                                <enumeratedValue>
                                    <name>0</name>
                                    <description>No effect on output</description>
                                    <value>#0</value>
                                </enumeratedValue>
                                <enumeratedValue>
                                    <name>1</name>
                                    <description>High output</description>
                                    <value>#1</value>
                                </enumeratedValue>
                            </enumeratedValues>
                        </field>
                        <field>
                            <name>EOSR03</name>
                            <description>Pmn Event Output Set</description>
                            <lsb>3</lsb>
                            <msb>3</msb>
                            <access>read-write</access>
                            <enumeratedValues>
                                <enumeratedValue>
                                    <name>0</name>
                                    <description>No effect on output</description>
                                    <value>#0</value>
                                </enumeratedValue>
                                <enumeratedValue>
                                    <name>1</name>
                                    <description>High output</description>
                                    <value>#1</value>
                                </enumeratedValue>
                            </enumeratedValues>
                        </field>
                        <field>
                            <name>EOSR04</name>
                            <description>Pmn Event Output Set</description>
                            <lsb>4</lsb>
                            <msb>4</msb>
                            <access>read-write</access>
                            <enumeratedValues>
                                <enumeratedValue>
                                    <name>0</name>
                                    <description>No effect on output</description>
                                    <value>#0</value>
                                </enumeratedValue>
                                <enumeratedValue>
                                    <name>1</name>
                                    <description>High output</description>
                                    <value>#1</value>
                                </enumeratedValue>
                            </enumeratedValues>
                        </field>
                        <field>
                            <name>EOSR05</name>
                            <description>Pmn Event Output Set</description>
                            <lsb>5</lsb>
                            <msb>5</msb>
                            <access>read-write</access>
                            <enumeratedValues>
                                <enumeratedValue>
                                    <name>0</name>
                                    <description>No effect on output</description>
                                    <value>#0</value>
                                </enumeratedValue>
                                <enumeratedValue>
                                    <name>1</name>
                                    <description>High output</description>
                                    <value>#1</value>
                                </enumeratedValue>
                            </enumeratedValues>
                        </field>
                        <field>
                            <name>EOSR06</name>
                            <description>Pmn Event Output Set</description>
                            <lsb>6</lsb>
                            <msb>6</msb>
                            <access>read-write</access>
                            <enumeratedValues>
                                <enumeratedValue>
                                    <name>0</name>
                                    <description>No effect on output</description>
                                    <value>#0</value>
                                </enumeratedValue>
                                <enumeratedValue>
                                    <name>1</name>
                                    <description>High output</description>
                                    <value>#1</value>
                                </enumeratedValue>
                            </enumeratedValues>
                        </field>
                        <field>
                            <name>EOSR07</name>
                            <description>Pmn Event Output Set</description>
                            <lsb>7</lsb>
                            <msb>7</msb>
                            <access>read-write</access>
                            <enumeratedValues>
                                <enumeratedValue>
                                    <name>0</name>
                                    <description>No effect on output</description>
                                    <value>#0</value>
                                </enumeratedValue>
                                <enumeratedValue>
                                    <name>1</name>
                                    <description>High output</description>
                                    <value>#1</value>
                                </enumeratedValue>
                            </enumeratedValues>
                        </field>
                        <field>
                            <name>EOSR08</name>
                            <description>Pmn Event Output Set</description>
                            <lsb>8</lsb>
                            <msb>8</msb>
                            <access>read-write</access>
                            <enumeratedValues>
                                <enumeratedValue>
                                    <name>0</name>
                                    <description>No effect on output</description>
                                    <value>#0</value>
                                </enumeratedValue>
                                <enumeratedValue>
                                    <name>1</name>
                                    <description>High output</description>
                                    <value>#1</value>
                                </enumeratedValue>
                            </enumeratedValues>
                        </field>
                        <field>
                            <name>EOSR09</name>
                            <description>Pmn Event Output Set</description>
                            <lsb>9</lsb>
                            <msb>9</msb>
                            <access>read-write</access>
                            <enumeratedValues>
                                <enumeratedValue>
                                    <name>0</name>
                                    <description>No effect on output</description>
                                    <value>#0</value>
                                </enumeratedValue>
                                <enumeratedValue>
                                    <name>1</name>
                                    <description>High output</description>
                                    <value>#1</value>
                                </enumeratedValue>
                            </enumeratedValues>
                        </field>
                        <field>
                            <name>EOSR10</name>
                            <description>Pmn Event Output Set</description>
                            <lsb>10</lsb>
                            <msb>10</msb>
                            <access>read-write</access>
                            <enumeratedValues>
                                <enumeratedValue>
                                    <name>0</name>
                                    <description>No effect on output</description>
                                    <value>#0</value>
                                </enumeratedValue>
                                <enumeratedValue>
                                    <name>1</name>
                                    <description>High output</description>
                                    <value>#1</value>
                                </enumeratedValue>
                            </enumeratedValues>
                        </field>
                        <field>
                            <name>EOSR11</name>
                            <description>Pmn Event Output Set</description>
                            <lsb>11</lsb>
                            <msb>11</msb>
                            <access>read-write</access>
                            <enumeratedValues>
                                <enumeratedValue>
                                    <name>0</name>
                                    <description>No effect on output</description>
                                    <value>#0</value>
                                </enumeratedValue>
                                <enumeratedValue>
                                    <name>1</name>
                                    <description>High output</description>
                                    <value>#1</value>
                                </enumeratedValue>
                            </enumeratedValues>
                        </field>
                        <field>
                            <name>EOSR12</name>
                            <description>Pmn Event Output Set</description>
                            <lsb>12</lsb>
                            <msb>12</msb>
                            <access>read-write</access>
                            <enumeratedValues>
                                <enumeratedValue>
                                    <name>0</name>
                                    <description>No effect on output</description>
                                    <value>#0</value>
                                </enumeratedValue>
                                <enumeratedValue>
                                    <name>1</name>
                                    <description>High output</description>
                                    <value>#1</value>
                                </enumeratedValue>
                            </enumeratedValues>
                        </field>
                        <field>
                            <name>EOSR13</name>
                            <description>Pmn Event Output Set</description>
                            <lsb>13</lsb>
                            <msb>13</msb>
                            <access>read-write</access>
                            <enumeratedValues>
                                <enumeratedValue>
                                    <name>0</name>
                                    <description>No effect on output</description>
                                    <value>#0</value>
                                </enumeratedValue>
                                <enumeratedValue>
                                    <name>1</name>
                                    <description>High output</description>
                                    <value>#1</value>
                                </enumeratedValue>
                            </enumeratedValues>
                        </field>
                        <field>
                            <name>EOSR14</name>
                            <description>Pmn Event Output Set</description>
                            <lsb>14</lsb>
                            <msb>14</msb>
                            <access>read-write</access>
                            <enumeratedValues>
                                <enumeratedValue>
                                    <name>0</name>
                                    <description>No effect on output</description>
                                    <value>#0</value>
                                </enumeratedValue>
                                <enumeratedValue>
                                    <name>1</name>
                                    <description>High output</description>
                                    <value>#1</value>
                                </enumeratedValue>
                            </enumeratedValues>
                        </field>
                        <field>
                            <name>EOSR15</name>
                            <description>Pmn Event Output Set</description>
                            <lsb>15</lsb>
                            <msb>15</msb>
                            <access>read-write</access>
                            <enumeratedValues>
                                <enumeratedValue>
                                    <name>0</name>
                                    <description>No effect on output</description>
                                    <value>#0</value>
                                </enumeratedValue>
                                <enumeratedValue>
                                    <name>1</name>
                                    <description>High output</description>
                                    <value>#1</value>
                                </enumeratedValue>
                            </enumeratedValues>
                        </field>
                    </fields>
                </register>
            </registers>
        </peripheral>
        <peripheral derivedFrom="PORT1">
            <name>PORT2</name>
            <description>Pmn Pin Function Port 2 Control Registers Pmn Pin Function Control Register</description>
            <baseAddress>0x40400040</baseAddress>
        </peripheral>
        <peripheral derivedFrom="PORT1">
            <name>PORT3</name>
            <description>Pmn Pin Function Port 3 Control Registers Pmn Pin Function Control Register</description>
            <baseAddress>0x40400060</baseAddress>
        </peripheral>
        <peripheral derivedFrom="PORT1">
            <name>PORT4</name>
            <description>Pmn Pin Function Port 4 Control Registers Pmn Pin Function Control Register</description>
            <baseAddress>0x40400080</baseAddress>
        </peripheral>
        <peripheral derivedFrom="PORT0">
            <name>PORT5</name>
            <description>Pmn Pin Function Port 5 Control Registers Pmn Pin Function Control Register</description>
            <baseAddress>0x404000A0</baseAddress>
        </peripheral>
        <peripheral derivedFrom="PORT0">
            <name>PORT6</name>
            <description>Pmn Pin Function Port 6 Control Registers Pmn Pin Function Control Register</description>
            <baseAddress>0x404000C0</baseAddress>
        </peripheral>
        <peripheral derivedFrom="PORT0">
            <name>PORT7</name>
            <description>Pmn Pin Function Port 7 Control Registers Pmn Pin Function Control Register</description>
            <baseAddress>0x404000E0</baseAddress>
        </peripheral>
        <peripheral derivedFrom="PORT0">
            <name>PORT8</name>
            <description>Pmn Pin Function Port 8 Control Registers Pmn Pin Function Control Register</description>
            <baseAddress>0x40400100</baseAddress>
        </peripheral>
        <peripheral derivedFrom="PORT0">
            <name>PORT9</name>
            <description>Pmn Pin Function Port 9 Control Registers Pmn Pin Function Control Register</description>
            <baseAddress>0x40400120</baseAddress>
        </peripheral>
        <peripheral>
            <name>PORTA</name>
            <description>Pmn Pin Function Port A Control Registers Pmn Pin Function Control Register</description>
            <baseAddress>0x40400140</baseAddress>
            <addressBlock>
                <offset>0x00</offset>
                <size>8</size>
                <usage>registers</usage>
            </addressBlock>
            <addressBlock>
                <offset>0x08</offset>
                <size>4</size>
                <usage>registers</usage>
            </addressBlock>
            <registers>
                <register>
                    <name>PCNTR1</name>
                    <description>Port Control Register 1</description>
                    <addressOffset>0x000</addressOffset>
                    <size>32</size>
                    <access>read-write</access>
                    <resetValue>0x00000000</resetValue>
                    <resetMask>0xffffffff</resetMask>
                    <fields>
                        <field>
                            <name>PDR00</name>
                            <description>Pmn Direction</description>
                            <lsb>0</lsb>
                            <msb>0</msb>
                            <access>read-write</access>
                            <enumeratedValues>
                                <enumeratedValue>
                                    <name>0</name>
                                    <description>Input (functions as an input pin)</description>
                                    <value>#0</value>
                                </enumeratedValue>
                                <enumeratedValue>
                                    <name>1</name>
                                    <description>Output (functions as an output pin)</description>
                                    <value>#1</value>
                                </enumeratedValue>
                            </enumeratedValues>
                        </field>
                        <field>
                            <name>PDR01</name>
                            <description>Pmn Direction</description>
                            <lsb>1</lsb>
                            <msb>1</msb>
                            <access>read-write</access>
                            <enumeratedValues>
                                <enumeratedValue>
                                    <name>0</name>
                                    <description>Input (functions as an input pin)</description>
                                    <value>#0</value>
                                </enumeratedValue>
                                <enumeratedValue>
                                    <name>1</name>
                                    <description>Output (functions as an output pin)</description>
                                    <value>#1</value>
                                </enumeratedValue>
                            </enumeratedValues>
                        </field>
                        <field>
                            <name>PDR02</name>
                            <description>Pmn Direction</description>
                            <lsb>2</lsb>
                            <msb>2</msb>
                            <access>read-write</access>
                            <enumeratedValues>
                                <enumeratedValue>
                                    <name>0</name>
                                    <description>Input (functions as an input pin)</description>
                                    <value>#0</value>
                                </enumeratedValue>
                                <enumeratedValue>
                                    <name>1</name>
                                    <description>Output (functions as an output pin)</description>
                                    <value>#1</value>
                                </enumeratedValue>
                            </enumeratedValues>
                        </field>
                        <field>
                            <name>PDR03</name>
                            <description>Pmn Direction</description>
                            <lsb>3</lsb>
                            <msb>3</msb>
                            <access>read-write</access>
                            <enumeratedValues>
                                <enumeratedValue>
                                    <name>0</name>
                                    <description>Input (functions as an input pin)</description>
                                    <value>#0</value>
                                </enumeratedValue>
                                <enumeratedValue>
                                    <name>1</name>
                                    <description>Output (functions as an output pin)</description>
                                    <value>#1</value>
                                </enumeratedValue>
                            </enumeratedValues>
                        </field>
                        <field>
                            <name>PDR04</name>
                            <description>Pmn Direction</description>
                            <lsb>4</lsb>
                            <msb>4</msb>
                            <access>read-write</access>
                            <enumeratedValues>
                                <enumeratedValue>
                                    <name>0</name>
                                    <description>Input (functions as an input pin)</description>
                                    <value>#0</value>
                                </enumeratedValue>
                                <enumeratedValue>
                                    <name>1</name>
                                    <description>Output (functions as an output pin)</description>
                                    <value>#1</value>
                                </enumeratedValue>
                            </enumeratedValues>
                        </field>
                        <field>
                            <name>PDR05</name>
                            <description>Pmn Direction</description>
                            <lsb>5</lsb>
                            <msb>5</msb>
                            <access>read-write</access>
                            <enumeratedValues>
                                <enumeratedValue>
                                    <name>0</name>
                                    <description>Input (functions as an input pin)</description>
                                    <value>#0</value>
                                </enumeratedValue>
                                <enumeratedValue>
                                    <name>1</name>
                                    <description>Output (functions as an output pin)</description>
                                    <value>#1</value>
                                </enumeratedValue>
                            </enumeratedValues>
                        </field>
                        <field>
                            <name>PDR06</name>
                            <description>Pmn Direction</description>
                            <lsb>6</lsb>
                            <msb>6</msb>
                            <access>read-write</access>
                            <enumeratedValues>
                                <enumeratedValue>
                                    <name>0</name>
                                    <description>Input (functions as an input pin)</description>
                                    <value>#0</value>
                                </enumeratedValue>
                                <enumeratedValue>
                                    <name>1</name>
                                    <description>Output (functions as an output pin)</description>
                                    <value>#1</value>
                                </enumeratedValue>
                            </enumeratedValues>
                        </field>
                        <field>
                            <name>PDR07</name>
                            <description>Pmn Direction</description>
                            <lsb>7</lsb>
                            <msb>7</msb>
                            <access>read-write</access>
                            <enumeratedValues>
                                <enumeratedValue>
                                    <name>0</name>
                                    <description>Input (functions as an input pin)</description>
                                    <value>#0</value>
                                </enumeratedValue>
                                <enumeratedValue>
                                    <name>1</name>
                                    <description>Output (functions as an output pin)</description>
                                    <value>#1</value>
                                </enumeratedValue>
                            </enumeratedValues>
                        </field>
                        <field>
                            <name>PDR08</name>
                            <description>Pmn Direction</description>
                            <lsb>8</lsb>
                            <msb>8</msb>
                            <access>read-write</access>
                            <enumeratedValues>
                                <enumeratedValue>
                                    <name>0</name>
                                    <description>Input (functions as an input pin)</description>
                                    <value>#0</value>
                                </enumeratedValue>
                                <enumeratedValue>
                                    <name>1</name>
                                    <description>Output (functions as an output pin)</description>
                                    <value>#1</value>
                                </enumeratedValue>
                            </enumeratedValues>
                        </field>
                        <field>
                            <name>PDR09</name>
                            <description>Pmn Direction</description>
                            <lsb>9</lsb>
                            <msb>9</msb>
                            <access>read-write</access>
                            <enumeratedValues>
                                <enumeratedValue>
                                    <name>0</name>
                                    <description>Input (functions as an input pin)</description>
                                    <value>#0</value>
                                </enumeratedValue>
                                <enumeratedValue>
                                    <name>1</name>
                                    <description>Output (functions as an output pin)</description>
                                    <value>#1</value>
                                </enumeratedValue>
                            </enumeratedValues>
                        </field>
                        <field>
                            <name>PDR10</name>
                            <description>Pmn Direction</description>
                            <lsb>10</lsb>
                            <msb>10</msb>
                            <access>read-write</access>
                            <enumeratedValues>
                                <enumeratedValue>
                                    <name>0</name>
                                    <description>Input (functions as an input pin)</description>
                                    <value>#0</value>
                                </enumeratedValue>
                                <enumeratedValue>
                                    <name>1</name>
                                    <description>Output (functions as an output pin)</description>
                                    <value>#1</value>
                                </enumeratedValue>
                            </enumeratedValues>
                        </field>
                        <field>
                            <name>PDR11</name>
                            <description>Pmn Direction</description>
                            <lsb>11</lsb>
                            <msb>11</msb>
                            <access>read-write</access>
                            <enumeratedValues>
                                <enumeratedValue>
                                    <name>0</name>
                                    <description>Input (functions as an input pin)</description>
                                    <value>#0</value>
                                </enumeratedValue>
                                <enumeratedValue>
                                    <name>1</name>
                                    <description>Output (functions as an output pin)</description>
                                    <value>#1</value>
                                </enumeratedValue>
                            </enumeratedValues>
                        </field>
                        <field>
                            <name>PDR12</name>
                            <description>Pmn Direction</description>
                            <lsb>12</lsb>
                            <msb>12</msb>
                            <access>read-write</access>
                            <enumeratedValues>
                                <enumeratedValue>
                                    <name>0</name>
                                    <description>Input (functions as an input pin)</description>
                                    <value>#0</value>
                                </enumeratedValue>
                                <enumeratedValue>
                                    <name>1</name>
                                    <description>Output (functions as an output pin)</description>
                                    <value>#1</value>
                                </enumeratedValue>
                            </enumeratedValues>
                        </field>
                        <field>
                            <name>PDR13</name>
                            <description>Pmn Direction</description>
                            <lsb>13</lsb>
                            <msb>13</msb>
                            <access>read-write</access>
                            <enumeratedValues>
                                <enumeratedValue>
                                    <name>0</name>
                                    <description>Input (functions as an input pin)</description>
                                    <value>#0</value>
                                </enumeratedValue>
                                <enumeratedValue>
                                    <name>1</name>
                                    <description>Output (functions as an output pin)</description>
                                    <value>#1</value>
                                </enumeratedValue>
                            </enumeratedValues>
                        </field>
                        <field>
                            <name>PDR14</name>
                            <description>Pmn Direction</description>
                            <lsb>14</lsb>
                            <msb>14</msb>
                            <access>read-write</access>
                            <enumeratedValues>
                                <enumeratedValue>
                                    <name>0</name>
                                    <description>Input (functions as an input pin)</description>
                                    <value>#0</value>
                                </enumeratedValue>
                                <enumeratedValue>
                                    <name>1</name>
                                    <description>Output (functions as an output pin)</description>
                                    <value>#1</value>
                                </enumeratedValue>
                            </enumeratedValues>
                        </field>
                        <field>
                            <name>PDR15</name>
                            <description>Pmn Direction</description>
                            <lsb>15</lsb>
                            <msb>15</msb>
                            <access>read-write</access>
                            <enumeratedValues>
                                <enumeratedValue>
                                    <name>0</name>
                                    <description>Input (functions as an input pin)</description>
                                    <value>#0</value>
                                </enumeratedValue>
                                <enumeratedValue>
                                    <name>1</name>
                                    <description>Output (functions as an output pin)</description>
                                    <value>#1</value>
                                </enumeratedValue>
                            </enumeratedValues>
                        </field>
                        <field>
                            <name>PODR00</name>
                            <description>Pmn Output Data</description>
                            <lsb>16</lsb>
                            <msb>16</msb>
                            <access>read-write</access>
                            <enumeratedValues>
                                <enumeratedValue>
                                    <name>0</name>
                                    <description>Low output</description>
                                    <value>#0</value>
                                </enumeratedValue>
                                <enumeratedValue>
                                    <name>1</name>
                                    <description>High output</description>
                                    <value>#1</value>
                                </enumeratedValue>
                            </enumeratedValues>
                        </field>
                        <field>
                            <name>PODR01</name>
                            <description>Pmn Output Data</description>
                            <lsb>17</lsb>
                            <msb>17</msb>
                            <access>read-write</access>
                            <enumeratedValues>
                                <enumeratedValue>
                                    <name>0</name>
                                    <description>Low output</description>
                                    <value>#0</value>
                                </enumeratedValue>
                                <enumeratedValue>
                                    <name>1</name>
                                    <description>High output</description>
                                    <value>#1</value>
                                </enumeratedValue>
                            </enumeratedValues>
                        </field>
                        <field>
                            <name>PODR02</name>
                            <description>Pmn Output Data</description>
                            <lsb>18</lsb>
                            <msb>18</msb>
                            <access>read-write</access>
                            <enumeratedValues>
                                <enumeratedValue>
                                    <name>0</name>
                                    <description>Low output</description>
                                    <value>#0</value>
                                </enumeratedValue>
                                <enumeratedValue>
                                    <name>1</name>
                                    <description>High output</description>
                                    <value>#1</value>
                                </enumeratedValue>
                            </enumeratedValues>
                        </field>
                        <field>
                            <name>PODR03</name>
                            <description>Pmn Output Data</description>
                            <lsb>19</lsb>
                            <msb>19</msb>
                            <access>read-write</access>
                            <enumeratedValues>
                                <enumeratedValue>
                                    <name>0</name>
                                    <description>Low output</description>
                                    <value>#0</value>
                                </enumeratedValue>
                                <enumeratedValue>
                                    <name>1</name>
                                    <description>High output</description>
                                    <value>#1</value>
                                </enumeratedValue>
                            </enumeratedValues>
                        </field>
                        <field>
                            <name>PODR04</name>
                            <description>Pmn Output Data</description>
                            <lsb>20</lsb>
                            <msb>20</msb>
                            <access>read-write</access>
                            <enumeratedValues>
                                <enumeratedValue>
                                    <name>0</name>
                                    <description>Low output</description>
                                    <value>#0</value>
                                </enumeratedValue>
                                <enumeratedValue>
                                    <name>1</name>
                                    <description>High output</description>
                                    <value>#1</value>
                                </enumeratedValue>
                            </enumeratedValues>
                        </field>
                        <field>
                            <name>PODR05</name>
                            <description>Pmn Output Data</description>
                            <lsb>21</lsb>
                            <msb>21</msb>
                            <access>read-write</access>
                            <enumeratedValues>
                                <enumeratedValue>
                                    <name>0</name>
                                    <description>Low output</description>
                                    <value>#0</value>
                                </enumeratedValue>
                                <enumeratedValue>
                                    <name>1</name>
                                    <description>High output</description>
                                    <value>#1</value>
                                </enumeratedValue>
                            </enumeratedValues>
                        </field>
                        <field>
                            <name>PODR06</name>
                            <description>Pmn Output Data</description>
                            <lsb>22</lsb>
                            <msb>22</msb>
                            <access>read-write</access>
                            <enumeratedValues>
                                <enumeratedValue>
                                    <name>0</name>
                                    <description>Low output</description>
                                    <value>#0</value>
                                </enumeratedValue>
                                <enumeratedValue>
                                    <name>1</name>
                                    <description>High output</description>
                                    <value>#1</value>
                                </enumeratedValue>
                            </enumeratedValues>
                        </field>
                        <field>
                            <name>PODR07</name>
                            <description>Pmn Output Data</description>
                            <lsb>23</lsb>
                            <msb>23</msb>
                            <access>read-write</access>
                            <enumeratedValues>
                                <enumeratedValue>
                                    <name>0</name>
                                    <description>Low output</description>
                                    <value>#0</value>
                                </enumeratedValue>
                                <enumeratedValue>
                                    <name>1</name>
                                    <description>High output</description>
                                    <value>#1</value>
                                </enumeratedValue>
                            </enumeratedValues>
                        </field>
                        <field>
                            <name>PODR08</name>
                            <description>Pmn Output Data</description>
                            <lsb>24</lsb>
                            <msb>24</msb>
                            <access>read-write</access>
                            <enumeratedValues>
                                <enumeratedValue>
                                    <name>0</name>
                                    <description>Low output</description>
                                    <value>#0</value>
                                </enumeratedValue>
                                <enumeratedValue>
                                    <name>1</name>
                                    <description>High output</description>
                                    <value>#1</value>
                                </enumeratedValue>
                            </enumeratedValues>
                        </field>
                        <field>
                            <name>PODR09</name>
                            <description>Pmn Output Data</description>
                            <lsb>25</lsb>
                            <msb>25</msb>
                            <access>read-write</access>
                            <enumeratedValues>
                                <enumeratedValue>
                                    <name>0</name>
                                    <description>Low output</description>
                                    <value>#0</value>
                                </enumeratedValue>
                                <enumeratedValue>
                                    <name>1</name>
                                    <description>High output</description>
                                    <value>#1</value>
                                </enumeratedValue>
                            </enumeratedValues>
                        </field>
                        <field>
                            <name>PODR10</name>
                            <description>Pmn Output Data</description>
                            <lsb>26</lsb>
                            <msb>26</msb>
                            <access>read-write</access>
                            <enumeratedValues>
                                <enumeratedValue>
                                    <name>0</name>
                                    <description>Low output</description>
                                    <value>#0</value>
                                </enumeratedValue>
                                <enumeratedValue>
                                    <name>1</name>
                                    <description>High output</description>
                                    <value>#1</value>
                                </enumeratedValue>
                            </enumeratedValues>
                        </field>
                        <field>
                            <name>PODR11</name>
                            <description>Pmn Output Data</description>
                            <lsb>27</lsb>
                            <msb>27</msb>
                            <access>read-write</access>
                            <enumeratedValues>
                                <enumeratedValue>
                                    <name>0</name>
                                    <description>Low output</description>
                                    <value>#0</value>
                                </enumeratedValue>
                                <enumeratedValue>
                                    <name>1</name>
                                    <description>High output</description>
                                    <value>#1</value>
                                </enumeratedValue>
                            </enumeratedValues>
                        </field>
                        <field>
                            <name>PODR12</name>
                            <description>Pmn Output Data</description>
                            <lsb>28</lsb>
                            <msb>28</msb>
                            <access>read-write</access>
                            <enumeratedValues>
                                <enumeratedValue>
                                    <name>0</name>
                                    <description>Low output</description>
                                    <value>#0</value>
                                </enumeratedValue>
                                <enumeratedValue>
                                    <name>1</name>
                                    <description>High output</description>
                                    <value>#1</value>
                                </enumeratedValue>
                            </enumeratedValues>
                        </field>
                        <field>
                            <name>PODR13</name>
                            <description>Pmn Output Data</description>
                            <lsb>29</lsb>
                            <msb>29</msb>
                            <access>read-write</access>
                            <enumeratedValues>
                                <enumeratedValue>
                                    <name>0</name>
                                    <description>Low output</description>
                                    <value>#0</value>
                                </enumeratedValue>
                                <enumeratedValue>
                                    <name>1</name>
                                    <description>High output</description>
                                    <value>#1</value>
                                </enumeratedValue>
                            </enumeratedValues>
                        </field>
                        <field>
                            <name>PODR14</name>
                            <description>Pmn Output Data</description>
                            <lsb>30</lsb>
                            <msb>30</msb>
                            <access>read-write</access>
                            <enumeratedValues>
                                <enumeratedValue>
                                    <name>0</name>
                                    <description>Low output</description>
                                    <value>#0</value>
                                </enumeratedValue>
                                <enumeratedValue>
                                    <name>1</name>
                                    <description>High output</description>
                                    <value>#1</value>
                                </enumeratedValue>
                            </enumeratedValues>
                        </field>
                        <field>
                            <name>PODR15</name>
                            <description>Pmn Output Data</description>
                            <lsb>31</lsb>
                            <msb>31</msb>
                            <access>read-write</access>
                            <enumeratedValues>
                                <enumeratedValue>
                                    <name>0</name>
                                    <description>Low output</description>
                                    <value>#0</value>
                                </enumeratedValue>
                                <enumeratedValue>
                                    <name>1</name>
                                    <description>High output</description>
                                    <value>#1</value>
                                </enumeratedValue>
                            </enumeratedValues>
                        </field>
                    </fields>
                </register>
                <register>
                    <name>PDR</name>
                    <description>Port Control Register 1</description>
                    <alternateRegister>PCNTR1</alternateRegister>
                    <addressOffset>0x000</addressOffset>
                    <size>16</size>
                    <access>read-write</access>
                    <resetValue>0x0000</resetValue>
                    <resetMask>0xffff</resetMask>
                    <fields>
                        <field>
                            <name>PODR00</name>
                            <description>Pmn Output Data</description>
                            <lsb>0</lsb>
                            <msb>0</msb>
                            <access>read-write</access>
                            <enumeratedValues>
                                <enumeratedValue>
                                    <name>0</name>
                                    <description>Low output</description>
                                    <value>#0</value>
                                </enumeratedValue>
                                <enumeratedValue>
                                    <name>1</name>
                                    <description>High output</description>
                                    <value>#1</value>
                                </enumeratedValue>
                            </enumeratedValues>
                        </field>
                        <field>
                            <name>PODR01</name>
                            <description>Pmn Output Data</description>
                            <lsb>1</lsb>
                            <msb>1</msb>
                            <access>read-write</access>
                            <enumeratedValues>
                                <enumeratedValue>
                                    <name>0</name>
                                    <description>Low output</description>
                                    <value>#0</value>
                                </enumeratedValue>
                                <enumeratedValue>
                                    <name>1</name>
                                    <description>High output</description>
                                    <value>#1</value>
                                </enumeratedValue>
                            </enumeratedValues>
                        </field>
                        <field>
                            <name>PODR02</name>
                            <description>Pmn Output Data</description>
                            <lsb>2</lsb>
                            <msb>2</msb>
                            <access>read-write</access>
                            <enumeratedValues>
                                <enumeratedValue>
                                    <name>0</name>
                                    <description>Low output</description>
                                    <value>#0</value>
                                </enumeratedValue>
                                <enumeratedValue>
                                    <name>1</name>
                                    <description>High output</description>
                                    <value>#1</value>
                                </enumeratedValue>
                            </enumeratedValues>
                        </field>
                        <field>
                            <name>PODR03</name>
                            <description>Pmn Output Data</description>
                            <lsb>3</lsb>
                            <msb>3</msb>
                            <access>read-write</access>
                            <enumeratedValues>
                                <enumeratedValue>
                                    <name>0</name>
                                    <description>Low output</description>
                                    <value>#0</value>
                                </enumeratedValue>
                                <enumeratedValue>
                                    <name>1</name>
                                    <description>High output</description>
                                    <value>#1</value>
                                </enumeratedValue>
                            </enumeratedValues>
                        </field>
                        <field>
                            <name>PODR04</name>
                            <description>Pmn Output Data</description>
                            <lsb>4</lsb>
                            <msb>4</msb>
                            <access>read-write</access>
                            <enumeratedValues>
                                <enumeratedValue>
                                    <name>0</name>
                                    <description>Low output</description>
                                    <value>#0</value>
                                </enumeratedValue>
                                <enumeratedValue>
                                    <name>1</name>
                                    <description>High output</description>
                                    <value>#1</value>
                                </enumeratedValue>
                            </enumeratedValues>
                        </field>
                        <field>
                            <name>PODR05</name>
                            <description>Pmn Output Data</description>
                            <lsb>5</lsb>
                            <msb>5</msb>
                            <access>read-write</access>
                            <enumeratedValues>
                                <enumeratedValue>
                                    <name>0</name>
                                    <description>Low output</description>
                                    <value>#0</value>
                                </enumeratedValue>
                                <enumeratedValue>
                                    <name>1</name>
                                    <description>High output</description>
                                    <value>#1</value>
                                </enumeratedValue>
                            </enumeratedValues>
                        </field>
                        <field>
                            <name>PODR06</name>
                            <description>Pmn Output Data</description>
                            <lsb>6</lsb>
                            <msb>6</msb>
                            <access>read-write</access>
                            <enumeratedValues>
                                <enumeratedValue>
                                    <name>0</name>
                                    <description>Low output</description>
                                    <value>#0</value>
                                </enumeratedValue>
                                <enumeratedValue>
                                    <name>1</name>
                                    <description>High output</description>
                                    <value>#1</value>
                                </enumeratedValue>
                            </enumeratedValues>
                        </field>
                        <field>
                            <name>PODR07</name>
                            <description>Pmn Output Data</description>
                            <lsb>7</lsb>
                            <msb>7</msb>
                            <access>read-write</access>
                            <enumeratedValues>
                                <enumeratedValue>
                                    <name>0</name>
                                    <description>Low output</description>
                                    <value>#0</value>
                                </enumeratedValue>
                                <enumeratedValue>
                                    <name>1</name>
                                    <description>High output</description>
                                    <value>#1</value>
                                </enumeratedValue>
                            </enumeratedValues>
                        </field>
                        <field>
                            <name>PODR08</name>
                            <description>Pmn Output Data</description>
                            <lsb>8</lsb>
                            <msb>8</msb>
                            <access>read-write</access>
                            <enumeratedValues>
                                <enumeratedValue>
                                    <name>0</name>
                                    <description>Low output</description>
                                    <value>#0</value>
                                </enumeratedValue>
                                <enumeratedValue>
                                    <name>1</name>
                                    <description>High output</description>
                                    <value>#1</value>
                                </enumeratedValue>
                            </enumeratedValues>
                        </field>
                        <field>
                            <name>PODR09</name>
                            <description>Pmn Output Data</description>
                            <lsb>9</lsb>
                            <msb>9</msb>
                            <access>read-write</access>
                            <enumeratedValues>
                                <enumeratedValue>
                                    <name>0</name>
                                    <description>Low output</description>
                                    <value>#0</value>
                                </enumeratedValue>
                                <enumeratedValue>
                                    <name>1</name>
                                    <description>High output</description>
                                    <value>#1</value>
                                </enumeratedValue>
                            </enumeratedValues>
                        </field>
                        <field>
                            <name>PODR10</name>
                            <description>Pmn Output Data</description>
                            <lsb>10</lsb>
                            <msb>10</msb>
                            <access>read-write</access>
                            <enumeratedValues>
                                <enumeratedValue>
                                    <name>0</name>
                                    <description>Low output</description>
                                    <value>#0</value>
                                </enumeratedValue>
                                <enumeratedValue>
                                    <name>1</name>
                                    <description>High output</description>
                                    <value>#1</value>
                                </enumeratedValue>
                            </enumeratedValues>
                        </field>
                        <field>
                            <name>PODR11</name>
                            <description>Pmn Output Data</description>
                            <lsb>11</lsb>
                            <msb>11</msb>
                            <access>read-write</access>
                            <enumeratedValues>
                                <enumeratedValue>
                                    <name>0</name>
                                    <description>Low output</description>
                                    <value>#0</value>
                                </enumeratedValue>
                                <enumeratedValue>
                                    <name>1</name>
                                    <description>High output</description>
                                    <value>#1</value>
                                </enumeratedValue>
                            </enumeratedValues>
                        </field>
                        <field>
                            <name>PODR12</name>
                            <description>Pmn Output Data</description>
                            <lsb>12</lsb>
                            <msb>12</msb>
                            <access>read-write</access>
                            <enumeratedValues>
                                <enumeratedValue>
                                    <name>0</name>
                                    <description>Low output</description>
                                    <value>#0</value>
                                </enumeratedValue>
                                <enumeratedValue>
                                    <name>1</name>
                                    <description>High output</description>
                                    <value>#1</value>
                                </enumeratedValue>
                            </enumeratedValues>
                        </field>
                        <field>
                            <name>PODR13</name>
                            <description>Pmn Output Data</description>
                            <lsb>13</lsb>
                            <msb>13</msb>
                            <access>read-write</access>
                            <enumeratedValues>
                                <enumeratedValue>
                                    <name>0</name>
                                    <description>Low output</description>
                                    <value>#0</value>
                                </enumeratedValue>
                                <enumeratedValue>
                                    <name>1</name>
                                    <description>High output</description>
                                    <value>#1</value>
                                </enumeratedValue>
                            </enumeratedValues>
                        </field>
                        <field>
                            <name>PODR14</name>
                            <description>Pmn Output Data</description>
                            <lsb>14</lsb>
                            <msb>14</msb>
                            <access>read-write</access>
                            <enumeratedValues>
                                <enumeratedValue>
                                    <name>0</name>
                                    <description>Low output</description>
                                    <value>#0</value>
                                </enumeratedValue>
                                <enumeratedValue>
                                    <name>1</name>
                                    <description>High output</description>
                                    <value>#1</value>
                                </enumeratedValue>
                            </enumeratedValues>
                        </field>
                        <field>
                            <name>PODR15</name>
                            <description>Pmn Output Data</description>
                            <lsb>15</lsb>
                            <msb>15</msb>
                            <access>read-write</access>
                            <enumeratedValues>
                                <enumeratedValue>
                                    <name>0</name>
                                    <description>Low output</description>
                                    <value>#0</value>
                                </enumeratedValue>
                                <enumeratedValue>
                                    <name>1</name>
                                    <description>High output</description>
                                    <value>#1</value>
                                </enumeratedValue>
                            </enumeratedValues>
                        </field>
                    </fields>
                </register>
                <register>
                    <name>PODR</name>
                    <description>Port Control Register 1</description>
                    <alternateRegister>PCNTR1</alternateRegister>
                    <addressOffset>0x002</addressOffset>
                    <size>16</size>
                    <access>read-write</access>
                    <resetValue>0x0000</resetValue>
                    <resetMask>0xffff</resetMask>
                    <fields>
                        <field>
                            <name>PDR00</name>
                            <description>Pmn Direction</description>
                            <lsb>0</lsb>
                            <msb>0</msb>
                            <access>read-write</access>
                            <enumeratedValues>
                                <enumeratedValue>
                                    <name>0</name>
                                    <description>Input (functions as an input pin)</description>
                                    <value>#0</value>
                                </enumeratedValue>
                                <enumeratedValue>
                                    <name>1</name>
                                    <description>Output (functions as an output pin)</description>
                                    <value>#1</value>
                                </enumeratedValue>
                            </enumeratedValues>
                        </field>
                        <field>
                            <name>PDR01</name>
                            <description>Pmn Direction</description>
                            <lsb>1</lsb>
                            <msb>1</msb>
                            <access>read-write</access>
                            <enumeratedValues>
                                <enumeratedValue>
                                    <name>0</name>
                                    <description>Input (functions as an input pin)</description>
                                    <value>#0</value>
                                </enumeratedValue>
                                <enumeratedValue>
                                    <name>1</name>
                                    <description>Output (functions as an output pin)</description>
                                    <value>#1</value>
                                </enumeratedValue>
                            </enumeratedValues>
                        </field>
                        <field>
                            <name>PDR02</name>
                            <description>Pmn Direction</description>
                            <lsb>2</lsb>
                            <msb>2</msb>
                            <access>read-write</access>
                            <enumeratedValues>
                                <enumeratedValue>
                                    <name>0</name>
                                    <description>Input (functions as an input pin)</description>
                                    <value>#0</value>
                                </enumeratedValue>
                                <enumeratedValue>
                                    <name>1</name>
                                    <description>Output (functions as an output pin)</description>
                                    <value>#1</value>
                                </enumeratedValue>
                            </enumeratedValues>
                        </field>
                        <field>
                            <name>PDR03</name>
                            <description>Pmn Direction</description>
                            <lsb>3</lsb>
                            <msb>3</msb>
                            <access>read-write</access>
                            <enumeratedValues>
                                <enumeratedValue>
                                    <name>0</name>
                                    <description>Input (functions as an input pin)</description>
                                    <value>#0</value>
                                </enumeratedValue>
                                <enumeratedValue>
                                    <name>1</name>
                                    <description>Output (functions as an output pin)</description>
                                    <value>#1</value>
                                </enumeratedValue>
                            </enumeratedValues>
                        </field>
                        <field>
                            <name>PDR04</name>
                            <description>Pmn Direction</description>
                            <lsb>4</lsb>
                            <msb>4</msb>
                            <access>read-write</access>
                            <enumeratedValues>
                                <enumeratedValue>
                                    <name>0</name>
                                    <description>Input (functions as an input pin)</description>
                                    <value>#0</value>
                                </enumeratedValue>
                                <enumeratedValue>
                                    <name>1</name>
                                    <description>Output (functions as an output pin)</description>
                                    <value>#1</value>
                                </enumeratedValue>
                            </enumeratedValues>
                        </field>
                        <field>
                            <name>PDR05</name>
                            <description>Pmn Direction</description>
                            <lsb>5</lsb>
                            <msb>5</msb>
                            <access>read-write</access>
                            <enumeratedValues>
                                <enumeratedValue>
                                    <name>0</name>
                                    <description>Input (functions as an input pin)</description>
                                    <value>#0</value>
                                </enumeratedValue>
                                <enumeratedValue>
                                    <name>1</name>
                                    <description>Output (functions as an output pin)</description>
                                    <value>#1</value>
                                </enumeratedValue>
                            </enumeratedValues>
                        </field>
                        <field>
                            <name>PDR06</name>
                            <description>Pmn Direction</description>
                            <lsb>6</lsb>
                            <msb>6</msb>
                            <access>read-write</access>
                            <enumeratedValues>
                                <enumeratedValue>
                                    <name>0</name>
                                    <description>Input (functions as an input pin)</description>
                                    <value>#0</value>
                                </enumeratedValue>
                                <enumeratedValue>
                                    <name>1</name>
                                    <description>Output (functions as an output pin)</description>
                                    <value>#1</value>
                                </enumeratedValue>
                            </enumeratedValues>
                        </field>
                        <field>
                            <name>PDR07</name>
                            <description>Pmn Direction</description>
                            <lsb>7</lsb>
                            <msb>7</msb>
                            <access>read-write</access>
                            <enumeratedValues>
                                <enumeratedValue>
                                    <name>0</name>
                                    <description>Input (functions as an input pin)</description>
                                    <value>#0</value>
                                </enumeratedValue>
                                <enumeratedValue>
                                    <name>1</name>
                                    <description>Output (functions as an output pin)</description>
                                    <value>#1</value>
                                </enumeratedValue>
                            </enumeratedValues>
                        </field>
                        <field>
                            <name>PDR08</name>
                            <description>Pmn Direction</description>
                            <lsb>8</lsb>
                            <msb>8</msb>
                            <access>read-write</access>
                            <enumeratedValues>
                                <enumeratedValue>
                                    <name>0</name>
                                    <description>Input (functions as an input pin)</description>
                                    <value>#0</value>
                                </enumeratedValue>
                                <enumeratedValue>
                                    <name>1</name>
                                    <description>Output (functions as an output pin)</description>
                                    <value>#1</value>
                                </enumeratedValue>
                            </enumeratedValues>
                        </field>
                        <field>
                            <name>PDR09</name>
                            <description>Pmn Direction</description>
                            <lsb>9</lsb>
                            <msb>9</msb>
                            <access>read-write</access>
                            <enumeratedValues>
                                <enumeratedValue>
                                    <name>0</name>
                                    <description>Input (functions as an input pin)</description>
                                    <value>#0</value>
                                </enumeratedValue>
                                <enumeratedValue>
                                    <name>1</name>
                                    <description>Output (functions as an output pin)</description>
                                    <value>#1</value>
                                </enumeratedValue>
                            </enumeratedValues>
                        </field>
                        <field>
                            <name>PDR10</name>
                            <description>Pmn Direction</description>
                            <lsb>10</lsb>
                            <msb>10</msb>
                            <access>read-write</access>
                            <enumeratedValues>
                                <enumeratedValue>
                                    <name>0</name>
                                    <description>Input (functions as an input pin)</description>
                                    <value>#0</value>
                                </enumeratedValue>
                                <enumeratedValue>
                                    <name>1</name>
                                    <description>Output (functions as an output pin)</description>
                                    <value>#1</value>
                                </enumeratedValue>
                            </enumeratedValues>
                        </field>
                        <field>
                            <name>PDR11</name>
                            <description>Pmn Direction</description>
                            <lsb>11</lsb>
                            <msb>11</msb>
                            <access>read-write</access>
                            <enumeratedValues>
                                <enumeratedValue>
                                    <name>0</name>
                                    <description>Input (functions as an input pin)</description>
                                    <value>#0</value>
                                </enumeratedValue>
                                <enumeratedValue>
                                    <name>1</name>
                                    <description>Output (functions as an output pin)</description>
                                    <value>#1</value>
                                </enumeratedValue>
                            </enumeratedValues>
                        </field>
                        <field>
                            <name>PDR12</name>
                            <description>Pmn Direction</description>
                            <lsb>12</lsb>
                            <msb>12</msb>
                            <access>read-write</access>
                            <enumeratedValues>
                                <enumeratedValue>
                                    <name>0</name>
                                    <description>Input (functions as an input pin)</description>
                                    <value>#0</value>
                                </enumeratedValue>
                                <enumeratedValue>
                                    <name>1</name>
                                    <description>Output (functions as an output pin)</description>
                                    <value>#1</value>
                                </enumeratedValue>
                            </enumeratedValues>
                        </field>
                        <field>
                            <name>PDR13</name>
                            <description>Pmn Direction</description>
                            <lsb>13</lsb>
                            <msb>13</msb>
                            <access>read-write</access>
                            <enumeratedValues>
                                <enumeratedValue>
                                    <name>0</name>
                                    <description>Input (functions as an input pin)</description>
                                    <value>#0</value>
                                </enumeratedValue>
                                <enumeratedValue>
                                    <name>1</name>
                                    <description>Output (functions as an output pin)</description>
                                    <value>#1</value>
                                </enumeratedValue>
                            </enumeratedValues>
                        </field>
                        <field>
                            <name>PDR14</name>
                            <description>Pmn Direction</description>
                            <lsb>14</lsb>
                            <msb>14</msb>
                            <access>read-write</access>
                            <enumeratedValues>
                                <enumeratedValue>
                                    <name>0</name>
                                    <description>Input (functions as an input pin)</description>
                                    <value>#0</value>
                                </enumeratedValue>
                                <enumeratedValue>
                                    <name>1</name>
                                    <description>Output (functions as an output pin)</description>
                                    <value>#1</value>
                                </enumeratedValue>
                            </enumeratedValues>
                        </field>
                        <field>
                            <name>PDR15</name>
                            <description>Pmn Direction</description>
                            <lsb>15</lsb>
                            <msb>15</msb>
                            <access>read-write</access>
                            <enumeratedValues>
                                <enumeratedValue>
                                    <name>0</name>
                                    <description>Input (functions as an input pin)</description>
                                    <value>#0</value>
                                </enumeratedValue>
                                <enumeratedValue>
                                    <name>1</name>
                                    <description>Output (functions as an output pin)</description>
                                    <value>#1</value>
                                </enumeratedValue>
                            </enumeratedValues>
                        </field>
                    </fields>
                </register>
                <register>
                    <name>PCNTR2</name>
                    <description>Port Control Register 2</description>
                    <addressOffset>0x004</addressOffset>
                    <size>32</size>
                    <access>read-only</access>
                    <resetValue>0x00000000</resetValue>
                    <resetMask>0xffff0000</resetMask>
                    <fields>
                        <field>
                            <name>PIDR00</name>
                            <description>Pmn State</description>
                            <lsb>0</lsb>
                            <msb>0</msb>
                            <access>read-only</access>
                            <enumeratedValues>
                                <enumeratedValue>
                                    <name>0</name>
                                    <description>Low level</description>
                                    <value>#0</value>
                                </enumeratedValue>
                                <enumeratedValue>
                                    <name>1</name>
                                    <description>High level</description>
                                    <value>#1</value>
                                </enumeratedValue>
                            </enumeratedValues>
                        </field>
                        <field>
                            <name>PIDR01</name>
                            <description>Pmn State</description>
                            <lsb>1</lsb>
                            <msb>1</msb>
                            <access>read-only</access>
                            <enumeratedValues>
                                <enumeratedValue>
                                    <name>0</name>
                                    <description>Low level</description>
                                    <value>#0</value>
                                </enumeratedValue>
                                <enumeratedValue>
                                    <name>1</name>
                                    <description>High level</description>
                                    <value>#1</value>
                                </enumeratedValue>
                            </enumeratedValues>
                        </field>
                        <field>
                            <name>PIDR02</name>
                            <description>Pmn State</description>
                            <lsb>2</lsb>
                            <msb>2</msb>
                            <access>read-only</access>
                            <enumeratedValues>
                                <enumeratedValue>
                                    <name>0</name>
                                    <description>Low level</description>
                                    <value>#0</value>
                                </enumeratedValue>
                                <enumeratedValue>
                                    <name>1</name>
                                    <description>High level</description>
                                    <value>#1</value>
                                </enumeratedValue>
                            </enumeratedValues>
                        </field>
                        <field>
                            <name>PIDR03</name>
                            <description>Pmn State</description>
                            <lsb>3</lsb>
                            <msb>3</msb>
                            <access>read-only</access>
                            <enumeratedValues>
                                <enumeratedValue>
                                    <name>0</name>
                                    <description>Low level</description>
                                    <value>#0</value>
                                </enumeratedValue>
                                <enumeratedValue>
                                    <name>1</name>
                                    <description>High level</description>
                                    <value>#1</value>
                                </enumeratedValue>
                            </enumeratedValues>
                        </field>
                        <field>
                            <name>PIDR04</name>
                            <description>Pmn State</description>
                            <lsb>4</lsb>
                            <msb>4</msb>
                            <access>read-only</access>
                            <enumeratedValues>
                                <enumeratedValue>
                                    <name>0</name>
                                    <description>Low level</description>
                                    <value>#0</value>
                                </enumeratedValue>
                                <enumeratedValue>
                                    <name>1</name>
                                    <description>High level</description>
                                    <value>#1</value>
                                </enumeratedValue>
                            </enumeratedValues>
                        </field>
                        <field>
                            <name>PIDR05</name>
                            <description>Pmn State</description>
                            <lsb>5</lsb>
                            <msb>5</msb>
                            <access>read-only</access>
                            <enumeratedValues>
                                <enumeratedValue>
                                    <name>0</name>
                                    <description>Low level</description>
                                    <value>#0</value>
                                </enumeratedValue>
                                <enumeratedValue>
                                    <name>1</name>
                                    <description>High level</description>
                                    <value>#1</value>
                                </enumeratedValue>
                            </enumeratedValues>
                        </field>
                        <field>
                            <name>PIDR06</name>
                            <description>Pmn State</description>
                            <lsb>6</lsb>
                            <msb>6</msb>
                            <access>read-only</access>
                            <enumeratedValues>
                                <enumeratedValue>
                                    <name>0</name>
                                    <description>Low level</description>
                                    <value>#0</value>
                                </enumeratedValue>
                                <enumeratedValue>
                                    <name>1</name>
                                    <description>High level</description>
                                    <value>#1</value>
                                </enumeratedValue>
                            </enumeratedValues>
                        </field>
                        <field>
                            <name>PIDR07</name>
                            <description>Pmn State</description>
                            <lsb>7</lsb>
                            <msb>7</msb>
                            <access>read-only</access>
                            <enumeratedValues>
                                <enumeratedValue>
                                    <name>0</name>
                                    <description>Low level</description>
                                    <value>#0</value>
                                </enumeratedValue>
                                <enumeratedValue>
                                    <name>1</name>
                                    <description>High level</description>
                                    <value>#1</value>
                                </enumeratedValue>
                            </enumeratedValues>
                        </field>
                        <field>
                            <name>PIDR08</name>
                            <description>Pmn State</description>
                            <lsb>8</lsb>
                            <msb>8</msb>
                            <access>read-only</access>
                            <enumeratedValues>
                                <enumeratedValue>
                                    <name>0</name>
                                    <description>Low level</description>
                                    <value>#0</value>
                                </enumeratedValue>
                                <enumeratedValue>
                                    <name>1</name>
                                    <description>High level</description>
                                    <value>#1</value>
                                </enumeratedValue>
                            </enumeratedValues>
                        </field>
                        <field>
                            <name>PIDR09</name>
                            <description>Pmn State</description>
                            <lsb>9</lsb>
                            <msb>9</msb>
                            <access>read-only</access>
                            <enumeratedValues>
                                <enumeratedValue>
                                    <name>0</name>
                                    <description>Low level</description>
                                    <value>#0</value>
                                </enumeratedValue>
                                <enumeratedValue>
                                    <name>1</name>
                                    <description>High level</description>
                                    <value>#1</value>
                                </enumeratedValue>
                            </enumeratedValues>
                        </field>
                        <field>
                            <name>PIDR10</name>
                            <description>Pmn State</description>
                            <lsb>10</lsb>
                            <msb>10</msb>
                            <access>read-only</access>
                            <enumeratedValues>
                                <enumeratedValue>
                                    <name>0</name>
                                    <description>Low level</description>
                                    <value>#0</value>
                                </enumeratedValue>
                                <enumeratedValue>
                                    <name>1</name>
                                    <description>High level</description>
                                    <value>#1</value>
                                </enumeratedValue>
                            </enumeratedValues>
                        </field>
                        <field>
                            <name>PIDR11</name>
                            <description>Pmn State</description>
                            <lsb>11</lsb>
                            <msb>11</msb>
                            <access>read-only</access>
                            <enumeratedValues>
                                <enumeratedValue>
                                    <name>0</name>
                                    <description>Low level</description>
                                    <value>#0</value>
                                </enumeratedValue>
                                <enumeratedValue>
                                    <name>1</name>
                                    <description>High level</description>
                                    <value>#1</value>
                                </enumeratedValue>
                            </enumeratedValues>
                        </field>
                        <field>
                            <name>PIDR12</name>
                            <description>Pmn State</description>
                            <lsb>12</lsb>
                            <msb>12</msb>
                            <access>read-only</access>
                            <enumeratedValues>
                                <enumeratedValue>
                                    <name>0</name>
                                    <description>Low level</description>
                                    <value>#0</value>
                                </enumeratedValue>
                                <enumeratedValue>
                                    <name>1</name>
                                    <description>High level</description>
                                    <value>#1</value>
                                </enumeratedValue>
                            </enumeratedValues>
                        </field>
                        <field>
                            <name>PIDR13</name>
                            <description>Pmn State</description>
                            <lsb>13</lsb>
                            <msb>13</msb>
                            <access>read-only</access>
                            <enumeratedValues>
                                <enumeratedValue>
                                    <name>0</name>
                                    <description>Low level</description>
                                    <value>#0</value>
                                </enumeratedValue>
                                <enumeratedValue>
                                    <name>1</name>
                                    <description>High level</description>
                                    <value>#1</value>
                                </enumeratedValue>
                            </enumeratedValues>
                        </field>
                        <field>
                            <name>PIDR14</name>
                            <description>Pmn State</description>
                            <lsb>14</lsb>
                            <msb>14</msb>
                            <access>read-only</access>
                            <enumeratedValues>
                                <enumeratedValue>
                                    <name>0</name>
                                    <description>Low level</description>
                                    <value>#0</value>
                                </enumeratedValue>
                                <enumeratedValue>
                                    <name>1</name>
                                    <description>High level</description>
                                    <value>#1</value>
                                </enumeratedValue>
                            </enumeratedValues>
                        </field>
                        <field>
                            <name>PIDR15</name>
                            <description>Pmn State</description>
                            <lsb>15</lsb>
                            <msb>15</msb>
                            <access>read-only</access>
                            <enumeratedValues>
                                <enumeratedValue>
                                    <name>0</name>
                                    <description>Low level</description>
                                    <value>#0</value>
                                </enumeratedValue>
                                <enumeratedValue>
                                    <name>1</name>
                                    <description>High level</description>
                                    <value>#1</value>
                                </enumeratedValue>
                            </enumeratedValues>
                        </field>
                    </fields>
                </register>
                <register>
                    <name>PIDR</name>
                    <description>Port Control Register 2</description>
                    <alternateRegister>PCNTR2</alternateRegister>
                    <addressOffset>0x004</addressOffset>
                    <size>16</size>
                    <access>read-only</access>
                    <resetValue>0x0000</resetValue>
                    <resetMask>0xffff</resetMask>
                </register>
                <register>
                    <name>PCNTR3</name>
                    <description>Port Control Register 3</description>
                    <addressOffset>0x008</addressOffset>
                    <size>32</size>
                    <access>write-only</access>
                    <resetValue>0x00000000</resetValue>
                    <resetMask>0xffffffff</resetMask>
                    <fields>
                        <field>
                            <name>POSR00</name>
                            <description>Pmn Output Set</description>
                            <lsb>0</lsb>
                            <msb>0</msb>
                            <access>write-only</access>
                            <enumeratedValues>
                                <enumeratedValue>
                                    <name>0</name>
                                    <description>No effect on output</description>
                                    <value>#0</value>
                                </enumeratedValue>
                                <enumeratedValue>
                                    <name>1</name>
                                    <description>High output</description>
                                    <value>#1</value>
                                </enumeratedValue>
                            </enumeratedValues>
                        </field>
                        <field>
                            <name>POSR01</name>
                            <description>Pmn Output Set</description>
                            <lsb>1</lsb>
                            <msb>1</msb>
                            <access>write-only</access>
                            <enumeratedValues>
                                <enumeratedValue>
                                    <name>0</name>
                                    <description>No effect on output</description>
                                    <value>#0</value>
                                </enumeratedValue>
                                <enumeratedValue>
                                    <name>1</name>
                                    <description>High output</description>
                                    <value>#1</value>
                                </enumeratedValue>
                            </enumeratedValues>
                        </field>
                        <field>
                            <name>POSR02</name>
                            <description>Pmn Output Set</description>
                            <lsb>2</lsb>
                            <msb>2</msb>
                            <access>write-only</access>
                            <enumeratedValues>
                                <enumeratedValue>
                                    <name>0</name>
                                    <description>No effect on output</description>
                                    <value>#0</value>
                                </enumeratedValue>
                                <enumeratedValue>
                                    <name>1</name>
                                    <description>High output</description>
                                    <value>#1</value>
                                </enumeratedValue>
                            </enumeratedValues>
                        </field>
                        <field>
                            <name>POSR03</name>
                            <description>Pmn Output Set</description>
                            <lsb>3</lsb>
                            <msb>3</msb>
                            <access>write-only</access>
                            <enumeratedValues>
                                <enumeratedValue>
                                    <name>0</name>
                                    <description>No effect on output</description>
                                    <value>#0</value>
                                </enumeratedValue>
                                <enumeratedValue>
                                    <name>1</name>
                                    <description>High output</description>
                                    <value>#1</value>
                                </enumeratedValue>
                            </enumeratedValues>
                        </field>
                        <field>
                            <name>POSR04</name>
                            <description>Pmn Output Set</description>
                            <lsb>4</lsb>
                            <msb>4</msb>
                            <access>write-only</access>
                            <enumeratedValues>
                                <enumeratedValue>
                                    <name>0</name>
                                    <description>No effect on output</description>
                                    <value>#0</value>
                                </enumeratedValue>
                                <enumeratedValue>
                                    <name>1</name>
                                    <description>High output</description>
                                    <value>#1</value>
                                </enumeratedValue>
                            </enumeratedValues>
                        </field>
                        <field>
                            <name>POSR05</name>
                            <description>Pmn Output Set</description>
                            <lsb>5</lsb>
                            <msb>5</msb>
                            <access>write-only</access>
                            <enumeratedValues>
                                <enumeratedValue>
                                    <name>0</name>
                                    <description>No effect on output</description>
                                    <value>#0</value>
                                </enumeratedValue>
                                <enumeratedValue>
                                    <name>1</name>
                                    <description>High output</description>
                                    <value>#1</value>
                                </enumeratedValue>
                            </enumeratedValues>
                        </field>
                        <field>
                            <name>POSR06</name>
                            <description>Pmn Output Set</description>
                            <lsb>6</lsb>
                            <msb>6</msb>
                            <access>write-only</access>
                            <enumeratedValues>
                                <enumeratedValue>
                                    <name>0</name>
                                    <description>No effect on output</description>
                                    <value>#0</value>
                                </enumeratedValue>
                                <enumeratedValue>
                                    <name>1</name>
                                    <description>High output</description>
                                    <value>#1</value>
                                </enumeratedValue>
                            </enumeratedValues>
                        </field>
                        <field>
                            <name>POSR07</name>
                            <description>Pmn Output Set</description>
                            <lsb>7</lsb>
                            <msb>7</msb>
                            <access>write-only</access>
                            <enumeratedValues>
                                <enumeratedValue>
                                    <name>0</name>
                                    <description>No effect on output</description>
                                    <value>#0</value>
                                </enumeratedValue>
                                <enumeratedValue>
                                    <name>1</name>
                                    <description>High output</description>
                                    <value>#1</value>
                                </enumeratedValue>
                            </enumeratedValues>
                        </field>
                        <field>
                            <name>POSR08</name>
                            <description>Pmn Output Set</description>
                            <lsb>8</lsb>
                            <msb>8</msb>
                            <access>write-only</access>
                            <enumeratedValues>
                                <enumeratedValue>
                                    <name>0</name>
                                    <description>No effect on output</description>
                                    <value>#0</value>
                                </enumeratedValue>
                                <enumeratedValue>
                                    <name>1</name>
                                    <description>High output</description>
                                    <value>#1</value>
                                </enumeratedValue>
                            </enumeratedValues>
                        </field>
                        <field>
                            <name>POSR09</name>
                            <description>Pmn Output Set</description>
                            <lsb>9</lsb>
                            <msb>9</msb>
                            <access>write-only</access>
                            <enumeratedValues>
                                <enumeratedValue>
                                    <name>0</name>
                                    <description>No effect on output</description>
                                    <value>#0</value>
                                </enumeratedValue>
                                <enumeratedValue>
                                    <name>1</name>
                                    <description>High output</description>
                                    <value>#1</value>
                                </enumeratedValue>
                            </enumeratedValues>
                        </field>
                        <field>
                            <name>POSR10</name>
                            <description>Pmn Output Set</description>
                            <lsb>10</lsb>
                            <msb>10</msb>
                            <access>write-only</access>
                            <enumeratedValues>
                                <enumeratedValue>
                                    <name>0</name>
                                    <description>No effect on output</description>
                                    <value>#0</value>
                                </enumeratedValue>
                                <enumeratedValue>
                                    <name>1</name>
                                    <description>High output</description>
                                    <value>#1</value>
                                </enumeratedValue>
                            </enumeratedValues>
                        </field>
                        <field>
                            <name>POSR11</name>
                            <description>Pmn Output Set</description>
                            <lsb>11</lsb>
                            <msb>11</msb>
                            <access>write-only</access>
                            <enumeratedValues>
                                <enumeratedValue>
                                    <name>0</name>
                                    <description>No effect on output</description>
                                    <value>#0</value>
                                </enumeratedValue>
                                <enumeratedValue>
                                    <name>1</name>
                                    <description>High output</description>
                                    <value>#1</value>
                                </enumeratedValue>
                            </enumeratedValues>
                        </field>
                        <field>
                            <name>POSR12</name>
                            <description>Pmn Output Set</description>
                            <lsb>12</lsb>
                            <msb>12</msb>
                            <access>write-only</access>
                            <enumeratedValues>
                                <enumeratedValue>
                                    <name>0</name>
                                    <description>No effect on output</description>
                                    <value>#0</value>
                                </enumeratedValue>
                                <enumeratedValue>
                                    <name>1</name>
                                    <description>High output</description>
                                    <value>#1</value>
                                </enumeratedValue>
                            </enumeratedValues>
                        </field>
                        <field>
                            <name>POSR13</name>
                            <description>Pmn Output Set</description>
                            <lsb>13</lsb>
                            <msb>13</msb>
                            <access>write-only</access>
                            <enumeratedValues>
                                <enumeratedValue>
                                    <name>0</name>
                                    <description>No effect on output</description>
                                    <value>#0</value>
                                </enumeratedValue>
                                <enumeratedValue>
                                    <name>1</name>
                                    <description>High output</description>
                                    <value>#1</value>
                                </enumeratedValue>
                            </enumeratedValues>
                        </field>
                        <field>
                            <name>POSR14</name>
                            <description>Pmn Output Set</description>
                            <lsb>14</lsb>
                            <msb>14</msb>
                            <access>write-only</access>
                            <enumeratedValues>
                                <enumeratedValue>
                                    <name>0</name>
                                    <description>No effect on output</description>
                                    <value>#0</value>
                                </enumeratedValue>
                                <enumeratedValue>
                                    <name>1</name>
                                    <description>High output</description>
                                    <value>#1</value>
                                </enumeratedValue>
                            </enumeratedValues>
                        </field>
                        <field>
                            <name>POSR15</name>
                            <description>Pmn Output Set</description>
                            <lsb>15</lsb>
                            <msb>15</msb>
                            <access>write-only</access>
                            <enumeratedValues>
                                <enumeratedValue>
                                    <name>0</name>
                                    <description>No effect on output</description>
                                    <value>#0</value>
                                </enumeratedValue>
                                <enumeratedValue>
                                    <name>1</name>
                                    <description>High output</description>
                                    <value>#1</value>
                                </enumeratedValue>
                            </enumeratedValues>
                        </field>
                        <field>
                            <name>PORR00</name>
                            <description>Pmn Output Reset</description>
                            <lsb>16</lsb>
                            <msb>16</msb>
                            <access>write-only</access>
                            <enumeratedValues>
                                <enumeratedValue>
                                    <name>0</name>
                                    <description>No effect on output</description>
                                    <value>#0</value>
                                </enumeratedValue>
                                <enumeratedValue>
                                    <name>1</name>
                                    <description>Low output</description>
                                    <value>#1</value>
                                </enumeratedValue>
                            </enumeratedValues>
                        </field>
                        <field>
                            <name>PORR01</name>
                            <description>Pmn Output Reset</description>
                            <lsb>17</lsb>
                            <msb>17</msb>
                            <access>write-only</access>
                            <enumeratedValues>
                                <enumeratedValue>
                                    <name>0</name>
                                    <description>No effect on output</description>
                                    <value>#0</value>
                                </enumeratedValue>
                                <enumeratedValue>
                                    <name>1</name>
                                    <description>Low output</description>
                                    <value>#1</value>
                                </enumeratedValue>
                            </enumeratedValues>
                        </field>
                        <field>
                            <name>PORR02</name>
                            <description>Pmn Output Reset</description>
                            <lsb>18</lsb>
                            <msb>18</msb>
                            <access>write-only</access>
                            <enumeratedValues>
                                <enumeratedValue>
                                    <name>0</name>
                                    <description>No effect on output</description>
                                    <value>#0</value>
                                </enumeratedValue>
                                <enumeratedValue>
                                    <name>1</name>
                                    <description>Low output</description>
                                    <value>#1</value>
                                </enumeratedValue>
                            </enumeratedValues>
                        </field>
                        <field>
                            <name>PORR03</name>
                            <description>Pmn Output Reset</description>
                            <lsb>19</lsb>
                            <msb>19</msb>
                            <access>write-only</access>
                            <enumeratedValues>
                                <enumeratedValue>
                                    <name>0</name>
                                    <description>No effect on output</description>
                                    <value>#0</value>
                                </enumeratedValue>
                                <enumeratedValue>
                                    <name>1</name>
                                    <description>Low output</description>
                                    <value>#1</value>
                                </enumeratedValue>
                            </enumeratedValues>
                        </field>
                        <field>
                            <name>PORR04</name>
                            <description>Pmn Output Reset</description>
                            <lsb>20</lsb>
                            <msb>20</msb>
                            <access>write-only</access>
                            <enumeratedValues>
                                <enumeratedValue>
                                    <name>0</name>
                                    <description>No effect on output</description>
                                    <value>#0</value>
                                </enumeratedValue>
                                <enumeratedValue>
                                    <name>1</name>
                                    <description>Low output</description>
                                    <value>#1</value>
                                </enumeratedValue>
                            </enumeratedValues>
                        </field>
                        <field>
                            <name>PORR05</name>
                            <description>Pmn Output Reset</description>
                            <lsb>21</lsb>
                            <msb>21</msb>
                            <access>write-only</access>
                            <enumeratedValues>
                                <enumeratedValue>
                                    <name>0</name>
                                    <description>No effect on output</description>
                                    <value>#0</value>
                                </enumeratedValue>
                                <enumeratedValue>
                                    <name>1</name>
                                    <description>Low output</description>
                                    <value>#1</value>
                                </enumeratedValue>
                            </enumeratedValues>
                        </field>
                        <field>
                            <name>PORR06</name>
                            <description>Pmn Output Reset</description>
                            <lsb>22</lsb>
                            <msb>22</msb>
                            <access>write-only</access>
                            <enumeratedValues>
                                <enumeratedValue>
                                    <name>0</name>
                                    <description>No effect on output</description>
                                    <value>#0</value>
                                </enumeratedValue>
                                <enumeratedValue>
                                    <name>1</name>
                                    <description>Low output</description>
                                    <value>#1</value>
                                </enumeratedValue>
                            </enumeratedValues>
                        </field>
                        <field>
                            <name>PORR07</name>
                            <description>Pmn Output Reset</description>
                            <lsb>23</lsb>
                            <msb>23</msb>
                            <access>write-only</access>
                            <enumeratedValues>
                                <enumeratedValue>
                                    <name>0</name>
                                    <description>No effect on output</description>
                                    <value>#0</value>
                                </enumeratedValue>
                                <enumeratedValue>
                                    <name>1</name>
                                    <description>Low output</description>
                                    <value>#1</value>
                                </enumeratedValue>
                            </enumeratedValues>
                        </field>
                        <field>
                            <name>PORR08</name>
                            <description>Pmn Output Reset</description>
                            <lsb>24</lsb>
                            <msb>24</msb>
                            <access>write-only</access>
                            <enumeratedValues>
                                <enumeratedValue>
                                    <name>0</name>
                                    <description>No effect on output</description>
                                    <value>#0</value>
                                </enumeratedValue>
                                <enumeratedValue>
                                    <name>1</name>
                                    <description>Low output</description>
                                    <value>#1</value>
                                </enumeratedValue>
                            </enumeratedValues>
                        </field>
                        <field>
                            <name>PORR09</name>
                            <description>Pmn Output Reset</description>
                            <lsb>25</lsb>
                            <msb>25</msb>
                            <access>write-only</access>
                            <enumeratedValues>
                                <enumeratedValue>
                                    <name>0</name>
                                    <description>No effect on output</description>
                                    <value>#0</value>
                                </enumeratedValue>
                                <enumeratedValue>
                                    <name>1</name>
                                    <description>Low output</description>
                                    <value>#1</value>
                                </enumeratedValue>
                            </enumeratedValues>
                        </field>
                        <field>
                            <name>PORR10</name>
                            <description>Pmn Output Reset</description>
                            <lsb>26</lsb>
                            <msb>26</msb>
                            <access>write-only</access>
                            <enumeratedValues>
                                <enumeratedValue>
                                    <name>0</name>
                                    <description>No effect on output</description>
                                    <value>#0</value>
                                </enumeratedValue>
                                <enumeratedValue>
                                    <name>1</name>
                                    <description>Low output</description>
                                    <value>#1</value>
                                </enumeratedValue>
                            </enumeratedValues>
                        </field>
                        <field>
                            <name>PORR11</name>
                            <description>Pmn Output Reset</description>
                            <lsb>27</lsb>
                            <msb>27</msb>
                            <access>write-only</access>
                            <enumeratedValues>
                                <enumeratedValue>
                                    <name>0</name>
                                    <description>No effect on output</description>
                                    <value>#0</value>
                                </enumeratedValue>
                                <enumeratedValue>
                                    <name>1</name>
                                    <description>Low output</description>
                                    <value>#1</value>
                                </enumeratedValue>
                            </enumeratedValues>
                        </field>
                        <field>
                            <name>PORR12</name>
                            <description>Pmn Output Reset</description>
                            <lsb>28</lsb>
                            <msb>28</msb>
                            <access>write-only</access>
                            <enumeratedValues>
                                <enumeratedValue>
                                    <name>0</name>
                                    <description>No effect on output</description>
                                    <value>#0</value>
                                </enumeratedValue>
                                <enumeratedValue>
                                    <name>1</name>
                                    <description>Low output</description>
                                    <value>#1</value>
                                </enumeratedValue>
                            </enumeratedValues>
                        </field>
                        <field>
                            <name>PORR13</name>
                            <description>Pmn Output Reset</description>
                            <lsb>29</lsb>
                            <msb>29</msb>
                            <access>write-only</access>
                            <enumeratedValues>
                                <enumeratedValue>
                                    <name>0</name>
                                    <description>No effect on output</description>
                                    <value>#0</value>
                                </enumeratedValue>
                                <enumeratedValue>
                                    <name>1</name>
                                    <description>Low output</description>
                                    <value>#1</value>
                                </enumeratedValue>
                            </enumeratedValues>
                        </field>
                        <field>
                            <name>PORR14</name>
                            <description>Pmn Output Reset</description>
                            <lsb>30</lsb>
                            <msb>30</msb>
                            <access>write-only</access>
                            <enumeratedValues>
                                <enumeratedValue>
                                    <name>0</name>
                                    <description>No effect on output</description>
                                    <value>#0</value>
                                </enumeratedValue>
                                <enumeratedValue>
                                    <name>1</name>
                                    <description>Low output</description>
                                    <value>#1</value>
                                </enumeratedValue>
                            </enumeratedValues>
                        </field>
                        <field>
                            <name>PORR15</name>
                            <description>Pmn Output Reset</description>
                            <lsb>31</lsb>
                            <msb>31</msb>
                            <access>write-only</access>
                            <enumeratedValues>
                                <enumeratedValue>
                                    <name>0</name>
                                    <description>No effect on output</description>
                                    <value>#0</value>
                                </enumeratedValue>
                                <enumeratedValue>
                                    <name>1</name>
                                    <description>Low output</description>
                                    <value>#1</value>
                                </enumeratedValue>
                            </enumeratedValues>
                        </field>
                    </fields>
                </register>
                <register>
                    <name>POSR</name>
                    <description>Port Control Register 3</description>
                    <alternateRegister>PCNTR3</alternateRegister>
                    <addressOffset>0x008</addressOffset>
                    <size>16</size>
                    <access>write-only</access>
                    <resetValue>0x0000</resetValue>
                    <resetMask>0xffff</resetMask>
                    <fields>
                        <field>
                            <name>PORR00</name>
                            <description>Pmn Output Reset</description>
                            <lsb>0</lsb>
                            <msb>0</msb>
                            <access>write-only</access>
                            <enumeratedValues>
                                <enumeratedValue>
                                    <name>0</name>
                                    <description>No effect on output</description>
                                    <value>#0</value>
                                </enumeratedValue>
                                <enumeratedValue>
                                    <name>1</name>
                                    <description>Low output</description>
                                    <value>#1</value>
                                </enumeratedValue>
                            </enumeratedValues>
                        </field>
                        <field>
                            <name>PORR01</name>
                            <description>Pmn Output Reset</description>
                            <lsb>1</lsb>
                            <msb>1</msb>
                            <access>write-only</access>
                            <enumeratedValues>
                                <enumeratedValue>
                                    <name>0</name>
                                    <description>No effect on output</description>
                                    <value>#0</value>
                                </enumeratedValue>
                                <enumeratedValue>
                                    <name>1</name>
                                    <description>Low output</description>
                                    <value>#1</value>
                                </enumeratedValue>
                            </enumeratedValues>
                        </field>
                        <field>
                            <name>PORR02</name>
                            <description>Pmn Output Reset</description>
                            <lsb>2</lsb>
                            <msb>2</msb>
                            <access>write-only</access>
                            <enumeratedValues>
                                <enumeratedValue>
                                    <name>0</name>
                                    <description>No effect on output</description>
                                    <value>#0</value>
                                </enumeratedValue>
                                <enumeratedValue>
                                    <name>1</name>
                                    <description>Low output</description>
                                    <value>#1</value>
                                </enumeratedValue>
                            </enumeratedValues>
                        </field>
                        <field>
                            <name>PORR03</name>
                            <description>Pmn Output Reset</description>
                            <lsb>3</lsb>
                            <msb>3</msb>
                            <access>write-only</access>
                            <enumeratedValues>
                                <enumeratedValue>
                                    <name>0</name>
                                    <description>No effect on output</description>
                                    <value>#0</value>
                                </enumeratedValue>
                                <enumeratedValue>
                                    <name>1</name>
                                    <description>Low output</description>
                                    <value>#1</value>
                                </enumeratedValue>
                            </enumeratedValues>
                        </field>
                        <field>
                            <name>PORR04</name>
                            <description>Pmn Output Reset</description>
                            <lsb>4</lsb>
                            <msb>4</msb>
                            <access>write-only</access>
                            <enumeratedValues>
                                <enumeratedValue>
                                    <name>0</name>
                                    <description>No effect on output</description>
                                    <value>#0</value>
                                </enumeratedValue>
                                <enumeratedValue>
                                    <name>1</name>
                                    <description>Low output</description>
                                    <value>#1</value>
                                </enumeratedValue>
                            </enumeratedValues>
                        </field>
                        <field>
                            <name>PORR05</name>
                            <description>Pmn Output Reset</description>
                            <lsb>5</lsb>
                            <msb>5</msb>
                            <access>write-only</access>
                            <enumeratedValues>
                                <enumeratedValue>
                                    <name>0</name>
                                    <description>No effect on output</description>
                                    <value>#0</value>
                                </enumeratedValue>
                                <enumeratedValue>
                                    <name>1</name>
                                    <description>Low output</description>
                                    <value>#1</value>
                                </enumeratedValue>
                            </enumeratedValues>
                        </field>
                        <field>
                            <name>PORR06</name>
                            <description>Pmn Output Reset</description>
                            <lsb>6</lsb>
                            <msb>6</msb>
                            <access>write-only</access>
                            <enumeratedValues>
                                <enumeratedValue>
                                    <name>0</name>
                                    <description>No effect on output</description>
                                    <value>#0</value>
                                </enumeratedValue>
                                <enumeratedValue>
                                    <name>1</name>
                                    <description>Low output</description>
                                    <value>#1</value>
                                </enumeratedValue>
                            </enumeratedValues>
                        </field>
                        <field>
                            <name>PORR07</name>
                            <description>Pmn Output Reset</description>
                            <lsb>7</lsb>
                            <msb>7</msb>
                            <access>write-only</access>
                            <enumeratedValues>
                                <enumeratedValue>
                                    <name>0</name>
                                    <description>No effect on output</description>
                                    <value>#0</value>
                                </enumeratedValue>
                                <enumeratedValue>
                                    <name>1</name>
                                    <description>Low output</description>
                                    <value>#1</value>
                                </enumeratedValue>
                            </enumeratedValues>
                        </field>
                        <field>
                            <name>PORR08</name>
                            <description>Pmn Output Reset</description>
                            <lsb>8</lsb>
                            <msb>8</msb>
                            <access>write-only</access>
                            <enumeratedValues>
                                <enumeratedValue>
                                    <name>0</name>
                                    <description>No effect on output</description>
                                    <value>#0</value>
                                </enumeratedValue>
                                <enumeratedValue>
                                    <name>1</name>
                                    <description>Low output</description>
                                    <value>#1</value>
                                </enumeratedValue>
                            </enumeratedValues>
                        </field>
                        <field>
                            <name>PORR09</name>
                            <description>Pmn Output Reset</description>
                            <lsb>9</lsb>
                            <msb>9</msb>
                            <access>write-only</access>
                            <enumeratedValues>
                                <enumeratedValue>
                                    <name>0</name>
                                    <description>No effect on output</description>
                                    <value>#0</value>
                                </enumeratedValue>
                                <enumeratedValue>
                                    <name>1</name>
                                    <description>Low output</description>
                                    <value>#1</value>
                                </enumeratedValue>
                            </enumeratedValues>
                        </field>
                        <field>
                            <name>PORR10</name>
                            <description>Pmn Output Reset</description>
                            <lsb>10</lsb>
                            <msb>10</msb>
                            <access>write-only</access>
                            <enumeratedValues>
                                <enumeratedValue>
                                    <name>0</name>
                                    <description>No effect on output</description>
                                    <value>#0</value>
                                </enumeratedValue>
                                <enumeratedValue>
                                    <name>1</name>
                                    <description>Low output</description>
                                    <value>#1</value>
                                </enumeratedValue>
                            </enumeratedValues>
                        </field>
                        <field>
                            <name>PORR11</name>
                            <description>Pmn Output Reset</description>
                            <lsb>11</lsb>
                            <msb>11</msb>
                            <access>write-only</access>
                            <enumeratedValues>
                                <enumeratedValue>
                                    <name>0</name>
                                    <description>No effect on output</description>
                                    <value>#0</value>
                                </enumeratedValue>
                                <enumeratedValue>
                                    <name>1</name>
                                    <description>Low output</description>
                                    <value>#1</value>
                                </enumeratedValue>
                            </enumeratedValues>
                        </field>
                        <field>
                            <name>PORR12</name>
                            <description>Pmn Output Reset</description>
                            <lsb>12</lsb>
                            <msb>12</msb>
                            <access>write-only</access>
                            <enumeratedValues>
                                <enumeratedValue>
                                    <name>0</name>
                                    <description>No effect on output</description>
                                    <value>#0</value>
                                </enumeratedValue>
                                <enumeratedValue>
                                    <name>1</name>
                                    <description>Low output</description>
                                    <value>#1</value>
                                </enumeratedValue>
                            </enumeratedValues>
                        </field>
                        <field>
                            <name>PORR13</name>
                            <description>Pmn Output Reset</description>
                            <lsb>13</lsb>
                            <msb>13</msb>
                            <access>write-only</access>
                            <enumeratedValues>
                                <enumeratedValue>
                                    <name>0</name>
                                    <description>No effect on output</description>
                                    <value>#0</value>
                                </enumeratedValue>
                                <enumeratedValue>
                                    <name>1</name>
                                    <description>Low output</description>
                                    <value>#1</value>
                                </enumeratedValue>
                            </enumeratedValues>
                        </field>
                        <field>
                            <name>PORR14</name>
                            <description>Pmn Output Reset</description>
                            <lsb>14</lsb>
                            <msb>14</msb>
                            <access>write-only</access>
                            <enumeratedValues>
                                <enumeratedValue>
                                    <name>0</name>
                                    <description>No effect on output</description>
                                    <value>#0</value>
                                </enumeratedValue>
                                <enumeratedValue>
                                    <name>1</name>
                                    <description>Low output</description>
                                    <value>#1</value>
                                </enumeratedValue>
                            </enumeratedValues>
                        </field>
                        <field>
                            <name>PORR15</name>
                            <description>Pmn Output Reset</description>
                            <lsb>15</lsb>
                            <msb>15</msb>
                            <access>write-only</access>
                            <enumeratedValues>
                                <enumeratedValue>
                                    <name>0</name>
                                    <description>No effect on output</description>
                                    <value>#0</value>
                                </enumeratedValue>
                                <enumeratedValue>
                                    <name>1</name>
                                    <description>Low output</description>
                                    <value>#1</value>
                                </enumeratedValue>
                            </enumeratedValues>
                        </field>
                    </fields>
                </register>
                <register>
                    <name>PORR</name>
                    <description>Port Control Register 3</description>
                    <alternateRegister>PCNTR3</alternateRegister>
                    <addressOffset>0x00A</addressOffset>
                    <size>16</size>
                    <access>write-only</access>
                    <resetValue>0x0000</resetValue>
                    <resetMask>0xffff</resetMask>
                    <fields>
                        <field>
                            <name>POSR00</name>
                            <description>Pmn Output Set</description>
                            <lsb>0</lsb>
                            <msb>0</msb>
                            <access>write-only</access>
                            <enumeratedValues>
                                <enumeratedValue>
                                    <name>0</name>
                                    <description>No effect on output</description>
                                    <value>#0</value>
                                </enumeratedValue>
                                <enumeratedValue>
                                    <name>1</name>
                                    <description>High output</description>
                                    <value>#1</value>
                                </enumeratedValue>
                            </enumeratedValues>
                        </field>
                        <field>
                            <name>POSR01</name>
                            <description>Pmn Output Set</description>
                            <lsb>1</lsb>
                            <msb>1</msb>
                            <access>write-only</access>
                            <enumeratedValues>
                                <enumeratedValue>
                                    <name>0</name>
                                    <description>No effect on output</description>
                                    <value>#0</value>
                                </enumeratedValue>
                                <enumeratedValue>
                                    <name>1</name>
                                    <description>High output</description>
                                    <value>#1</value>
                                </enumeratedValue>
                            </enumeratedValues>
                        </field>
                        <field>
                            <name>POSR02</name>
                            <description>Pmn Output Set</description>
                            <lsb>2</lsb>
                            <msb>2</msb>
                            <access>write-only</access>
                            <enumeratedValues>
                                <enumeratedValue>
                                    <name>0</name>
                                    <description>No effect on output</description>
                                    <value>#0</value>
                                </enumeratedValue>
                                <enumeratedValue>
                                    <name>1</name>
                                    <description>High output</description>
                                    <value>#1</value>
                                </enumeratedValue>
                            </enumeratedValues>
                        </field>
                        <field>
                            <name>POSR03</name>
                            <description>Pmn Output Set</description>
                            <lsb>3</lsb>
                            <msb>3</msb>
                            <access>write-only</access>
                            <enumeratedValues>
                                <enumeratedValue>
                                    <name>0</name>
                                    <description>No effect on output</description>
                                    <value>#0</value>
                                </enumeratedValue>
                                <enumeratedValue>
                                    <name>1</name>
                                    <description>High output</description>
                                    <value>#1</value>
                                </enumeratedValue>
                            </enumeratedValues>
                        </field>
                        <field>
                            <name>POSR04</name>
                            <description>Pmn Output Set</description>
                            <lsb>4</lsb>
                            <msb>4</msb>
                            <access>write-only</access>
                            <enumeratedValues>
                                <enumeratedValue>
                                    <name>0</name>
                                    <description>No effect on output</description>
                                    <value>#0</value>
                                </enumeratedValue>
                                <enumeratedValue>
                                    <name>1</name>
                                    <description>High output</description>
                                    <value>#1</value>
                                </enumeratedValue>
                            </enumeratedValues>
                        </field>
                        <field>
                            <name>POSR05</name>
                            <description>Pmn Output Set</description>
                            <lsb>5</lsb>
                            <msb>5</msb>
                            <access>write-only</access>
                            <enumeratedValues>
                                <enumeratedValue>
                                    <name>0</name>
                                    <description>No effect on output</description>
                                    <value>#0</value>
                                </enumeratedValue>
                                <enumeratedValue>
                                    <name>1</name>
                                    <description>High output</description>
                                    <value>#1</value>
                                </enumeratedValue>
                            </enumeratedValues>
                        </field>
                        <field>
                            <name>POSR06</name>
                            <description>Pmn Output Set</description>
                            <lsb>6</lsb>
                            <msb>6</msb>
                            <access>write-only</access>
                            <enumeratedValues>
                                <enumeratedValue>
                                    <name>0</name>
                                    <description>No effect on output</description>
                                    <value>#0</value>
                                </enumeratedValue>
                                <enumeratedValue>
                                    <name>1</name>
                                    <description>High output</description>
                                    <value>#1</value>
                                </enumeratedValue>
                            </enumeratedValues>
                        </field>
                        <field>
                            <name>POSR07</name>
                            <description>Pmn Output Set</description>
                            <lsb>7</lsb>
                            <msb>7</msb>
                            <access>write-only</access>
                            <enumeratedValues>
                                <enumeratedValue>
                                    <name>0</name>
                                    <description>No effect on output</description>
                                    <value>#0</value>
                                </enumeratedValue>
                                <enumeratedValue>
                                    <name>1</name>
                                    <description>High output</description>
                                    <value>#1</value>
                                </enumeratedValue>
                            </enumeratedValues>
                        </field>
                        <field>
                            <name>POSR08</name>
                            <description>Pmn Output Set</description>
                            <lsb>8</lsb>
                            <msb>8</msb>
                            <access>write-only</access>
                            <enumeratedValues>
                                <enumeratedValue>
                                    <name>0</name>
                                    <description>No effect on output</description>
                                    <value>#0</value>
                                </enumeratedValue>
                                <enumeratedValue>
                                    <name>1</name>
                                    <description>High output</description>
                                    <value>#1</value>
                                </enumeratedValue>
                            </enumeratedValues>
                        </field>
                        <field>
                            <name>POSR09</name>
                            <description>Pmn Output Set</description>
                            <lsb>9</lsb>
                            <msb>9</msb>
                            <access>write-only</access>
                            <enumeratedValues>
                                <enumeratedValue>
                                    <name>0</name>
                                    <description>No effect on output</description>
                                    <value>#0</value>
                                </enumeratedValue>
                                <enumeratedValue>
                                    <name>1</name>
                                    <description>High output</description>
                                    <value>#1</value>
                                </enumeratedValue>
                            </enumeratedValues>
                        </field>
                        <field>
                            <name>POSR10</name>
                            <description>Pmn Output Set</description>
                            <lsb>10</lsb>
                            <msb>10</msb>
                            <access>write-only</access>
                            <enumeratedValues>
                                <enumeratedValue>
                                    <name>0</name>
                                    <description>No effect on output</description>
                                    <value>#0</value>
                                </enumeratedValue>
                                <enumeratedValue>
                                    <name>1</name>
                                    <description>High output</description>
                                    <value>#1</value>
                                </enumeratedValue>
                            </enumeratedValues>
                        </field>
                        <field>
                            <name>POSR11</name>
                            <description>Pmn Output Set</description>
                            <lsb>11</lsb>
                            <msb>11</msb>
                            <access>write-only</access>
                            <enumeratedValues>
                                <enumeratedValue>
                                    <name>0</name>
                                    <description>No effect on output</description>
                                    <value>#0</value>
                                </enumeratedValue>
                                <enumeratedValue>
                                    <name>1</name>
                                    <description>High output</description>
                                    <value>#1</value>
                                </enumeratedValue>
                            </enumeratedValues>
                        </field>
                        <field>
                            <name>POSR12</name>
                            <description>Pmn Output Set</description>
                            <lsb>12</lsb>
                            <msb>12</msb>
                            <access>write-only</access>
                            <enumeratedValues>
                                <enumeratedValue>
                                    <name>0</name>
                                    <description>No effect on output</description>
                                    <value>#0</value>
                                </enumeratedValue>
                                <enumeratedValue>
                                    <name>1</name>
                                    <description>High output</description>
                                    <value>#1</value>
                                </enumeratedValue>
                            </enumeratedValues>
                        </field>
                        <field>
                            <name>POSR13</name>
                            <description>Pmn Output Set</description>
                            <lsb>13</lsb>
                            <msb>13</msb>
                            <access>write-only</access>
                            <enumeratedValues>
                                <enumeratedValue>
                                    <name>0</name>
                                    <description>No effect on output</description>
                                    <value>#0</value>
                                </enumeratedValue>
                                <enumeratedValue>
                                    <name>1</name>
                                    <description>High output</description>
                                    <value>#1</value>
                                </enumeratedValue>
                            </enumeratedValues>
                        </field>
                        <field>
                            <name>POSR14</name>
                            <description>Pmn Output Set</description>
                            <lsb>14</lsb>
                            <msb>14</msb>
                            <access>write-only</access>
                            <enumeratedValues>
                                <enumeratedValue>
                                    <name>0</name>
                                    <description>No effect on output</description>
                                    <value>#0</value>
                                </enumeratedValue>
                                <enumeratedValue>
                                    <name>1</name>
                                    <description>High output</description>
                                    <value>#1</value>
                                </enumeratedValue>
                            </enumeratedValues>
                        </field>
                        <field>
                            <name>POSR15</name>
                            <description>Pmn Output Set</description>
                            <lsb>15</lsb>
                            <msb>15</msb>
                            <access>write-only</access>
                            <enumeratedValues>
                                <enumeratedValue>
                                    <name>0</name>
                                    <description>No effect on output</description>
                                    <value>#0</value>
                                </enumeratedValue>
                                <enumeratedValue>
                                    <name>1</name>
                                    <description>High output</description>
                                    <value>#1</value>
                                </enumeratedValue>
                            </enumeratedValues>
                        </field>
                    </fields>
                </register>
            </registers>
        </peripheral>
        <peripheral>
            <name>PORTB</name>
            <description>Pmn Pin Function Port B Control Registers Pmn Pin Function Control Register</description>
            <baseAddress>0x40400160</baseAddress>
            <addressBlock>
                <offset>0x00</offset>
                <size>8</size>
                <usage>registers</usage>
            </addressBlock>
            <addressBlock>
                <offset>0x08</offset>
                <size>4</size>
                <usage>registers</usage>
            </addressBlock>
            <registers>
                <register>
                    <name>PCNTR1</name>
                    <description>Port Control Register 1</description>
                    <addressOffset>0x000</addressOffset>
                    <size>32</size>
                    <access>read-write</access>
                    <resetValue>0x00000000</resetValue>
                    <resetMask>0xffffffff</resetMask>
                    <fields>
                        <field>
                            <name>PDR00</name>
                            <description>Pmn Direction</description>
                            <lsb>0</lsb>
                            <msb>0</msb>
                            <access>read-write</access>
                            <enumeratedValues>
                                <enumeratedValue>
                                    <name>0</name>
                                    <description>Input (functions as an input pin)</description>
                                    <value>#0</value>
                                </enumeratedValue>
                                <enumeratedValue>
                                    <name>1</name>
                                    <description>Output (functions as an output pin)</description>
                                    <value>#1</value>
                                </enumeratedValue>
                            </enumeratedValues>
                        </field>
                        <field>
                            <name>PDR01</name>
                            <description>Pmn Direction</description>
                            <lsb>1</lsb>
                            <msb>1</msb>
                            <access>read-write</access>
                            <enumeratedValues>
                                <enumeratedValue>
                                    <name>0</name>
                                    <description>Input (functions as an input pin)</description>
                                    <value>#0</value>
                                </enumeratedValue>
                                <enumeratedValue>
                                    <name>1</name>
                                    <description>Output (functions as an output pin)</description>
                                    <value>#1</value>
                                </enumeratedValue>
                            </enumeratedValues>
                        </field>
                        <field>
                            <name>PDR02</name>
                            <description>Pmn Direction</description>
                            <lsb>2</lsb>
                            <msb>2</msb>
                            <access>read-write</access>
                            <enumeratedValues>
                                <enumeratedValue>
                                    <name>0</name>
                                    <description>Input (functions as an input pin)</description>
                                    <value>#0</value>
                                </enumeratedValue>
                                <enumeratedValue>
                                    <name>1</name>
                                    <description>Output (functions as an output pin)</description>
                                    <value>#1</value>
                                </enumeratedValue>
                            </enumeratedValues>
                        </field>
                        <field>
                            <name>PDR03</name>
                            <description>Pmn Direction</description>
                            <lsb>3</lsb>
                            <msb>3</msb>
                            <access>read-write</access>
                            <enumeratedValues>
                                <enumeratedValue>
                                    <name>0</name>
                                    <description>Input (functions as an input pin)</description>
                                    <value>#0</value>
                                </enumeratedValue>
                                <enumeratedValue>
                                    <name>1</name>
                                    <description>Output (functions as an output pin)</description>
                                    <value>#1</value>
                                </enumeratedValue>
                            </enumeratedValues>
                        </field>
                        <field>
                            <name>PDR04</name>
                            <description>Pmn Direction</description>
                            <lsb>4</lsb>
                            <msb>4</msb>
                            <access>read-write</access>
                            <enumeratedValues>
                                <enumeratedValue>
                                    <name>0</name>
                                    <description>Input (functions as an input pin)</description>
                                    <value>#0</value>
                                </enumeratedValue>
                                <enumeratedValue>
                                    <name>1</name>
                                    <description>Output (functions as an output pin)</description>
                                    <value>#1</value>
                                </enumeratedValue>
                            </enumeratedValues>
                        </field>
                        <field>
                            <name>PDR05</name>
                            <description>Pmn Direction</description>
                            <lsb>5</lsb>
                            <msb>5</msb>
                            <access>read-write</access>
                            <enumeratedValues>
                                <enumeratedValue>
                                    <name>0</name>
                                    <description>Input (functions as an input pin)</description>
                                    <value>#0</value>
                                </enumeratedValue>
                                <enumeratedValue>
                                    <name>1</name>
                                    <description>Output (functions as an output pin)</description>
                                    <value>#1</value>
                                </enumeratedValue>
                            </enumeratedValues>
                        </field>
                        <field>
                            <name>PDR06</name>
                            <description>Pmn Direction</description>
                            <lsb>6</lsb>
                            <msb>6</msb>
                            <access>read-write</access>
                            <enumeratedValues>
                                <enumeratedValue>
                                    <name>0</name>
                                    <description>Input (functions as an input pin)</description>
                                    <value>#0</value>
                                </enumeratedValue>
                                <enumeratedValue>
                                    <name>1</name>
                                    <description>Output (functions as an output pin)</description>
                                    <value>#1</value>
                                </enumeratedValue>
                            </enumeratedValues>
                        </field>
                        <field>
                            <name>PDR07</name>
                            <description>Pmn Direction</description>
                            <lsb>7</lsb>
                            <msb>7</msb>
                            <access>read-write</access>
                            <enumeratedValues>
                                <enumeratedValue>
                                    <name>0</name>
                                    <description>Input (functions as an input pin)</description>
                                    <value>#0</value>
                                </enumeratedValue>
                                <enumeratedValue>
                                    <name>1</name>
                                    <description>Output (functions as an output pin)</description>
                                    <value>#1</value>
                                </enumeratedValue>
                            </enumeratedValues>
                        </field>
                        <field>
                            <name>PDR08</name>
                            <description>Pmn Direction</description>
                            <lsb>8</lsb>
                            <msb>8</msb>
                            <access>read-write</access>
                            <enumeratedValues>
                                <enumeratedValue>
                                    <name>0</name>
                                    <description>Input (functions as an input pin)</description>
                                    <value>#0</value>
                                </enumeratedValue>
                                <enumeratedValue>
                                    <name>1</name>
                                    <description>Output (functions as an output pin)</description>
                                    <value>#1</value>
                                </enumeratedValue>
                            </enumeratedValues>
                        </field>
                        <field>
                            <name>PDR09</name>
                            <description>Pmn Direction</description>
                            <lsb>9</lsb>
                            <msb>9</msb>
                            <access>read-write</access>
                            <enumeratedValues>
                                <enumeratedValue>
                                    <name>0</name>
                                    <description>Input (functions as an input pin)</description>
                                    <value>#0</value>
                                </enumeratedValue>
                                <enumeratedValue>
                                    <name>1</name>
                                    <description>Output (functions as an output pin)</description>
                                    <value>#1</value>
                                </enumeratedValue>
                            </enumeratedValues>
                        </field>
                        <field>
                            <name>PDR10</name>
                            <description>Pmn Direction</description>
                            <lsb>10</lsb>
                            <msb>10</msb>
                            <access>read-write</access>
                            <enumeratedValues>
                                <enumeratedValue>
                                    <name>0</name>
                                    <description>Input (functions as an input pin)</description>
                                    <value>#0</value>
                                </enumeratedValue>
                                <enumeratedValue>
                                    <name>1</name>
                                    <description>Output (functions as an output pin)</description>
                                    <value>#1</value>
                                </enumeratedValue>
                            </enumeratedValues>
                        </field>
                        <field>
                            <name>PDR11</name>
                            <description>Pmn Direction</description>
                            <lsb>11</lsb>
                            <msb>11</msb>
                            <access>read-write</access>
                            <enumeratedValues>
                                <enumeratedValue>
                                    <name>0</name>
                                    <description>Input (functions as an input pin)</description>
                                    <value>#0</value>
                                </enumeratedValue>
                                <enumeratedValue>
                                    <name>1</name>
                                    <description>Output (functions as an output pin)</description>
                                    <value>#1</value>
                                </enumeratedValue>
                            </enumeratedValues>
                        </field>
                        <field>
                            <name>PDR12</name>
                            <description>Pmn Direction</description>
                            <lsb>12</lsb>
                            <msb>12</msb>
                            <access>read-write</access>
                            <enumeratedValues>
                                <enumeratedValue>
                                    <name>0</name>
                                    <description>Input (functions as an input pin)</description>
                                    <value>#0</value>
                                </enumeratedValue>
                                <enumeratedValue>
                                    <name>1</name>
                                    <description>Output (functions as an output pin)</description>
                                    <value>#1</value>
                                </enumeratedValue>
                            </enumeratedValues>
                        </field>
                        <field>
                            <name>PDR13</name>
                            <description>Pmn Direction</description>
                            <lsb>13</lsb>
                            <msb>13</msb>
                            <access>read-write</access>
                            <enumeratedValues>
                                <enumeratedValue>
                                    <name>0</name>
                                    <description>Input (functions as an input pin)</description>
                                    <value>#0</value>
                                </enumeratedValue>
                                <enumeratedValue>
                                    <name>1</name>
                                    <description>Output (functions as an output pin)</description>
                                    <value>#1</value>
                                </enumeratedValue>
                            </enumeratedValues>
                        </field>
                        <field>
                            <name>PDR14</name>
                            <description>Pmn Direction</description>
                            <lsb>14</lsb>
                            <msb>14</msb>
                            <access>read-write</access>
                            <enumeratedValues>
                                <enumeratedValue>
                                    <name>0</name>
                                    <description>Input (functions as an input pin)</description>
                                    <value>#0</value>
                                </enumeratedValue>
                                <enumeratedValue>
                                    <name>1</name>
                                    <description>Output (functions as an output pin)</description>
                                    <value>#1</value>
                                </enumeratedValue>
                            </enumeratedValues>
                        </field>
                        <field>
                            <name>PDR15</name>
                            <description>Pmn Direction</description>
                            <lsb>15</lsb>
                            <msb>15</msb>
                            <access>read-write</access>
                            <enumeratedValues>
                                <enumeratedValue>
                                    <name>0</name>
                                    <description>Input (functions as an input pin)</description>
                                    <value>#0</value>
                                </enumeratedValue>
                                <enumeratedValue>
                                    <name>1</name>
                                    <description>Output (functions as an output pin)</description>
                                    <value>#1</value>
                                </enumeratedValue>
                            </enumeratedValues>
                        </field>
                        <field>
                            <name>PODR00</name>
                            <description>Pmn Output Data</description>
                            <lsb>16</lsb>
                            <msb>16</msb>
                            <access>read-write</access>
                            <enumeratedValues>
                                <enumeratedValue>
                                    <name>0</name>
                                    <description>Low output</description>
                                    <value>#0</value>
                                </enumeratedValue>
                                <enumeratedValue>
                                    <name>1</name>
                                    <description>High output</description>
                                    <value>#1</value>
                                </enumeratedValue>
                            </enumeratedValues>
                        </field>
                        <field>
                            <name>PODR01</name>
                            <description>Pmn Output Data</description>
                            <lsb>17</lsb>
                            <msb>17</msb>
                            <access>read-write</access>
                            <enumeratedValues>
                                <enumeratedValue>
                                    <name>0</name>
                                    <description>Low output</description>
                                    <value>#0</value>
                                </enumeratedValue>
                                <enumeratedValue>
                                    <name>1</name>
                                    <description>High output</description>
                                    <value>#1</value>
                                </enumeratedValue>
                            </enumeratedValues>
                        </field>
                        <field>
                            <name>PODR02</name>
                            <description>Pmn Output Data</description>
                            <lsb>18</lsb>
                            <msb>18</msb>
                            <access>read-write</access>
                            <enumeratedValues>
                                <enumeratedValue>
                                    <name>0</name>
                                    <description>Low output</description>
                                    <value>#0</value>
                                </enumeratedValue>
                                <enumeratedValue>
                                    <name>1</name>
                                    <description>High output</description>
                                    <value>#1</value>
                                </enumeratedValue>
                            </enumeratedValues>
                        </field>
                        <field>
                            <name>PODR03</name>
                            <description>Pmn Output Data</description>
                            <lsb>19</lsb>
                            <msb>19</msb>
                            <access>read-write</access>
                            <enumeratedValues>
                                <enumeratedValue>
                                    <name>0</name>
                                    <description>Low output</description>
                                    <value>#0</value>
                                </enumeratedValue>
                                <enumeratedValue>
                                    <name>1</name>
                                    <description>High output</description>
                                    <value>#1</value>
                                </enumeratedValue>
                            </enumeratedValues>
                        </field>
                        <field>
                            <name>PODR04</name>
                            <description>Pmn Output Data</description>
                            <lsb>20</lsb>
                            <msb>20</msb>
                            <access>read-write</access>
                            <enumeratedValues>
                                <enumeratedValue>
                                    <name>0</name>
                                    <description>Low output</description>
                                    <value>#0</value>
                                </enumeratedValue>
                                <enumeratedValue>
                                    <name>1</name>
                                    <description>High output</description>
                                    <value>#1</value>
                                </enumeratedValue>
                            </enumeratedValues>
                        </field>
                        <field>
                            <name>PODR05</name>
                            <description>Pmn Output Data</description>
                            <lsb>21</lsb>
                            <msb>21</msb>
                            <access>read-write</access>
                            <enumeratedValues>
                                <enumeratedValue>
                                    <name>0</name>
                                    <description>Low output</description>
                                    <value>#0</value>
                                </enumeratedValue>
                                <enumeratedValue>
                                    <name>1</name>
                                    <description>High output</description>
                                    <value>#1</value>
                                </enumeratedValue>
                            </enumeratedValues>
                        </field>
                        <field>
                            <name>PODR06</name>
                            <description>Pmn Output Data</description>
                            <lsb>22</lsb>
                            <msb>22</msb>
                            <access>read-write</access>
                            <enumeratedValues>
                                <enumeratedValue>
                                    <name>0</name>
                                    <description>Low output</description>
                                    <value>#0</value>
                                </enumeratedValue>
                                <enumeratedValue>
                                    <name>1</name>
                                    <description>High output</description>
                                    <value>#1</value>
                                </enumeratedValue>
                            </enumeratedValues>
                        </field>
                        <field>
                            <name>PODR07</name>
                            <description>Pmn Output Data</description>
                            <lsb>23</lsb>
                            <msb>23</msb>
                            <access>read-write</access>
                            <enumeratedValues>
                                <enumeratedValue>
                                    <name>0</name>
                                    <description>Low output</description>
                                    <value>#0</value>
                                </enumeratedValue>
                                <enumeratedValue>
                                    <name>1</name>
                                    <description>High output</description>
                                    <value>#1</value>
                                </enumeratedValue>
                            </enumeratedValues>
                        </field>
                        <field>
                            <name>PODR08</name>
                            <description>Pmn Output Data</description>
                            <lsb>24</lsb>
                            <msb>24</msb>
                            <access>read-write</access>
                            <enumeratedValues>
                                <enumeratedValue>
                                    <name>0</name>
                                    <description>Low output</description>
                                    <value>#0</value>
                                </enumeratedValue>
                                <enumeratedValue>
                                    <name>1</name>
                                    <description>High output</description>
                                    <value>#1</value>
                                </enumeratedValue>
                            </enumeratedValues>
                        </field>
                        <field>
                            <name>PODR09</name>
                            <description>Pmn Output Data</description>
                            <lsb>25</lsb>
                            <msb>25</msb>
                            <access>read-write</access>
                            <enumeratedValues>
                                <enumeratedValue>
                                    <name>0</name>
                                    <description>Low output</description>
                                    <value>#0</value>
                                </enumeratedValue>
                                <enumeratedValue>
                                    <name>1</name>
                                    <description>High output</description>
                                    <value>#1</value>
                                </enumeratedValue>
                            </enumeratedValues>
                        </field>
                        <field>
                            <name>PODR10</name>
                            <description>Pmn Output Data</description>
                            <lsb>26</lsb>
                            <msb>26</msb>
                            <access>read-write</access>
                            <enumeratedValues>
                                <enumeratedValue>
                                    <name>0</name>
                                    <description>Low output</description>
                                    <value>#0</value>
                                </enumeratedValue>
                                <enumeratedValue>
                                    <name>1</name>
                                    <description>High output</description>
                                    <value>#1</value>
                                </enumeratedValue>
                            </enumeratedValues>
                        </field>
                        <field>
                            <name>PODR11</name>
                            <description>Pmn Output Data</description>
                            <lsb>27</lsb>
                            <msb>27</msb>
                            <access>read-write</access>
                            <enumeratedValues>
                                <enumeratedValue>
                                    <name>0</name>
                                    <description>Low output</description>
                                    <value>#0</value>
                                </enumeratedValue>
                                <enumeratedValue>
                                    <name>1</name>
                                    <description>High output</description>
                                    <value>#1</value>
                                </enumeratedValue>
                            </enumeratedValues>
                        </field>
                        <field>
                            <name>PODR12</name>
                            <description>Pmn Output Data</description>
                            <lsb>28</lsb>
                            <msb>28</msb>
                            <access>read-write</access>
                            <enumeratedValues>
                                <enumeratedValue>
                                    <name>0</name>
                                    <description>Low output</description>
                                    <value>#0</value>
                                </enumeratedValue>
                                <enumeratedValue>
                                    <name>1</name>
                                    <description>High output</description>
                                    <value>#1</value>
                                </enumeratedValue>
                            </enumeratedValues>
                        </field>
                        <field>
                            <name>PODR13</name>
                            <description>Pmn Output Data</description>
                            <lsb>29</lsb>
                            <msb>29</msb>
                            <access>read-write</access>
                            <enumeratedValues>
                                <enumeratedValue>
                                    <name>0</name>
                                    <description>Low output</description>
                                    <value>#0</value>
                                </enumeratedValue>
                                <enumeratedValue>
                                    <name>1</name>
                                    <description>High output</description>
                                    <value>#1</value>
                                </enumeratedValue>
                            </enumeratedValues>
                        </field>
                        <field>
                            <name>PODR14</name>
                            <description>Pmn Output Data</description>
                            <lsb>30</lsb>
                            <msb>30</msb>
                            <access>read-write</access>
                            <enumeratedValues>
                                <enumeratedValue>
                                    <name>0</name>
                                    <description>Low output</description>
                                    <value>#0</value>
                                </enumeratedValue>
                                <enumeratedValue>
                                    <name>1</name>
                                    <description>High output</description>
                                    <value>#1</value>
                                </enumeratedValue>
                            </enumeratedValues>
                        </field>
                        <field>
                            <name>PODR15</name>
                            <description>Pmn Output Data</description>
                            <lsb>31</lsb>
                            <msb>31</msb>
                            <access>read-write</access>
                            <enumeratedValues>
                                <enumeratedValue>
                                    <name>0</name>
                                    <description>Low output</description>
                                    <value>#0</value>
                                </enumeratedValue>
                                <enumeratedValue>
                                    <name>1</name>
                                    <description>High output</description>
                                    <value>#1</value>
                                </enumeratedValue>
                            </enumeratedValues>
                        </field>
                    </fields>
                </register>
                <register>
                    <name>PDR</name>
                    <description>Port Control Register 1</description>
                    <alternateRegister>PCNTR1</alternateRegister>
                    <addressOffset>0x000</addressOffset>
                    <size>16</size>
                    <access>read-write</access>
                    <resetValue>0x0000</resetValue>
                    <resetMask>0xffff</resetMask>
                    <fields>
                        <field>
                            <name>PODR00</name>
                            <description>Pmn Output Data</description>
                            <lsb>0</lsb>
                            <msb>0</msb>
                            <access>read-write</access>
                            <enumeratedValues>
                                <enumeratedValue>
                                    <name>0</name>
                                    <description>Low output</description>
                                    <value>#0</value>
                                </enumeratedValue>
                                <enumeratedValue>
                                    <name>1</name>
                                    <description>High output</description>
                                    <value>#1</value>
                                </enumeratedValue>
                            </enumeratedValues>
                        </field>
                        <field>
                            <name>PODR01</name>
                            <description>Pmn Output Data</description>
                            <lsb>1</lsb>
                            <msb>1</msb>
                            <access>read-write</access>
                            <enumeratedValues>
                                <enumeratedValue>
                                    <name>0</name>
                                    <description>Low output</description>
                                    <value>#0</value>
                                </enumeratedValue>
                                <enumeratedValue>
                                    <name>1</name>
                                    <description>High output</description>
                                    <value>#1</value>
                                </enumeratedValue>
                            </enumeratedValues>
                        </field>
                        <field>
                            <name>PODR02</name>
                            <description>Pmn Output Data</description>
                            <lsb>2</lsb>
                            <msb>2</msb>
                            <access>read-write</access>
                            <enumeratedValues>
                                <enumeratedValue>
                                    <name>0</name>
                                    <description>Low output</description>
                                    <value>#0</value>
                                </enumeratedValue>
                                <enumeratedValue>
                                    <name>1</name>
                                    <description>High output</description>
                                    <value>#1</value>
                                </enumeratedValue>
                            </enumeratedValues>
                        </field>
                        <field>
                            <name>PODR03</name>
                            <description>Pmn Output Data</description>
                            <lsb>3</lsb>
                            <msb>3</msb>
                            <access>read-write</access>
                            <enumeratedValues>
                                <enumeratedValue>
                                    <name>0</name>
                                    <description>Low output</description>
                                    <value>#0</value>
                                </enumeratedValue>
                                <enumeratedValue>
                                    <name>1</name>
                                    <description>High output</description>
                                    <value>#1</value>
                                </enumeratedValue>
                            </enumeratedValues>
                        </field>
                        <field>
                            <name>PODR04</name>
                            <description>Pmn Output Data</description>
                            <lsb>4</lsb>
                            <msb>4</msb>
                            <access>read-write</access>
                            <enumeratedValues>
                                <enumeratedValue>
                                    <name>0</name>
                                    <description>Low output</description>
                                    <value>#0</value>
                                </enumeratedValue>
                                <enumeratedValue>
                                    <name>1</name>
                                    <description>High output</description>
                                    <value>#1</value>
                                </enumeratedValue>
                            </enumeratedValues>
                        </field>
                        <field>
                            <name>PODR05</name>
                            <description>Pmn Output Data</description>
                            <lsb>5</lsb>
                            <msb>5</msb>
                            <access>read-write</access>
                            <enumeratedValues>
                                <enumeratedValue>
                                    <name>0</name>
                                    <description>Low output</description>
                                    <value>#0</value>
                                </enumeratedValue>
                                <enumeratedValue>
                                    <name>1</name>
                                    <description>High output</description>
                                    <value>#1</value>
                                </enumeratedValue>
                            </enumeratedValues>
                        </field>
                        <field>
                            <name>PODR06</name>
                            <description>Pmn Output Data</description>
                            <lsb>6</lsb>
                            <msb>6</msb>
                            <access>read-write</access>
                            <enumeratedValues>
                                <enumeratedValue>
                                    <name>0</name>
                                    <description>Low output</description>
                                    <value>#0</value>
                                </enumeratedValue>
                                <enumeratedValue>
                                    <name>1</name>
                                    <description>High output</description>
                                    <value>#1</value>
                                </enumeratedValue>
                            </enumeratedValues>
                        </field>
                        <field>
                            <name>PODR07</name>
                            <description>Pmn Output Data</description>
                            <lsb>7</lsb>
                            <msb>7</msb>
                            <access>read-write</access>
                            <enumeratedValues>
                                <enumeratedValue>
                                    <name>0</name>
                                    <description>Low output</description>
                                    <value>#0</value>
                                </enumeratedValue>
                                <enumeratedValue>
                                    <name>1</name>
                                    <description>High output</description>
                                    <value>#1</value>
                                </enumeratedValue>
                            </enumeratedValues>
                        </field>
                        <field>
                            <name>PODR08</name>
                            <description>Pmn Output Data</description>
                            <lsb>8</lsb>
                            <msb>8</msb>
                            <access>read-write</access>
                            <enumeratedValues>
                                <enumeratedValue>
                                    <name>0</name>
                                    <description>Low output</description>
                                    <value>#0</value>
                                </enumeratedValue>
                                <enumeratedValue>
                                    <name>1</name>
                                    <description>High output</description>
                                    <value>#1</value>
                                </enumeratedValue>
                            </enumeratedValues>
                        </field>
                        <field>
                            <name>PODR09</name>
                            <description>Pmn Output Data</description>
                            <lsb>9</lsb>
                            <msb>9</msb>
                            <access>read-write</access>
                            <enumeratedValues>
                                <enumeratedValue>
                                    <name>0</name>
                                    <description>Low output</description>
                                    <value>#0</value>
                                </enumeratedValue>
                                <enumeratedValue>
                                    <name>1</name>
                                    <description>High output</description>
                                    <value>#1</value>
                                </enumeratedValue>
                            </enumeratedValues>
                        </field>
                        <field>
                            <name>PODR10</name>
                            <description>Pmn Output Data</description>
                            <lsb>10</lsb>
                            <msb>10</msb>
                            <access>read-write</access>
                            <enumeratedValues>
                                <enumeratedValue>
                                    <name>0</name>
                                    <description>Low output</description>
                                    <value>#0</value>
                                </enumeratedValue>
                                <enumeratedValue>
                                    <name>1</name>
                                    <description>High output</description>
                                    <value>#1</value>
                                </enumeratedValue>
                            </enumeratedValues>
                        </field>
                        <field>
                            <name>PODR11</name>
                            <description>Pmn Output Data</description>
                            <lsb>11</lsb>
                            <msb>11</msb>
                            <access>read-write</access>
                            <enumeratedValues>
                                <enumeratedValue>
                                    <name>0</name>
                                    <description>Low output</description>
                                    <value>#0</value>
                                </enumeratedValue>
                                <enumeratedValue>
                                    <name>1</name>
                                    <description>High output</description>
                                    <value>#1</value>
                                </enumeratedValue>
                            </enumeratedValues>
                        </field>
                        <field>
                            <name>PODR12</name>
                            <description>Pmn Output Data</description>
                            <lsb>12</lsb>
                            <msb>12</msb>
                            <access>read-write</access>
                            <enumeratedValues>
                                <enumeratedValue>
                                    <name>0</name>
                                    <description>Low output</description>
                                    <value>#0</value>
                                </enumeratedValue>
                                <enumeratedValue>
                                    <name>1</name>
                                    <description>High output</description>
                                    <value>#1</value>
                                </enumeratedValue>
                            </enumeratedValues>
                        </field>
                        <field>
                            <name>PODR13</name>
                            <description>Pmn Output Data</description>
                            <lsb>13</lsb>
                            <msb>13</msb>
                            <access>read-write</access>
                            <enumeratedValues>
                                <enumeratedValue>
                                    <name>0</name>
                                    <description>Low output</description>
                                    <value>#0</value>
                                </enumeratedValue>
                                <enumeratedValue>
                                    <name>1</name>
                                    <description>High output</description>
                                    <value>#1</value>
                                </enumeratedValue>
                            </enumeratedValues>
                        </field>
                        <field>
                            <name>PODR14</name>
                            <description>Pmn Output Data</description>
                            <lsb>14</lsb>
                            <msb>14</msb>
                            <access>read-write</access>
                            <enumeratedValues>
                                <enumeratedValue>
                                    <name>0</name>
                                    <description>Low output</description>
                                    <value>#0</value>
                                </enumeratedValue>
                                <enumeratedValue>
                                    <name>1</name>
                                    <description>High output</description>
                                    <value>#1</value>
                                </enumeratedValue>
                            </enumeratedValues>
                        </field>
                        <field>
                            <name>PODR15</name>
                            <description>Pmn Output Data</description>
                            <lsb>15</lsb>
                            <msb>15</msb>
                            <access>read-write</access>
                            <enumeratedValues>
                                <enumeratedValue>
                                    <name>0</name>
                                    <description>Low output</description>
                                    <value>#0</value>
                                </enumeratedValue>
                                <enumeratedValue>
                                    <name>1</name>
                                    <description>High output</description>
                                    <value>#1</value>
                                </enumeratedValue>
                            </enumeratedValues>
                        </field>
                    </fields>
                </register>
                <register>
                    <name>PODR</name>
                    <description>Port Control Register 1</description>
                    <alternateRegister>PCNTR1</alternateRegister>
                    <addressOffset>0x002</addressOffset>
                    <size>16</size>
                    <access>read-write</access>
                    <resetValue>0x0000</resetValue>
                    <resetMask>0xffff</resetMask>
                    <fields>
                        <field>
                            <name>PDR00</name>
                            <description>Pmn Direction</description>
                            <lsb>0</lsb>
                            <msb>0</msb>
                            <access>read-write</access>
                            <enumeratedValues>
                                <enumeratedValue>
                                    <name>0</name>
                                    <description>Input (functions as an input pin)</description>
                                    <value>#0</value>
                                </enumeratedValue>
                                <enumeratedValue>
                                    <name>1</name>
                                    <description>Output (functions as an output pin)</description>
                                    <value>#1</value>
                                </enumeratedValue>
                            </enumeratedValues>
                        </field>
                        <field>
                            <name>PDR01</name>
                            <description>Pmn Direction</description>
                            <lsb>1</lsb>
                            <msb>1</msb>
                            <access>read-write</access>
                            <enumeratedValues>
                                <enumeratedValue>
                                    <name>0</name>
                                    <description>Input (functions as an input pin)</description>
                                    <value>#0</value>
                                </enumeratedValue>
                                <enumeratedValue>
                                    <name>1</name>
                                    <description>Output (functions as an output pin)</description>
                                    <value>#1</value>
                                </enumeratedValue>
                            </enumeratedValues>
                        </field>
                        <field>
                            <name>PDR02</name>
                            <description>Pmn Direction</description>
                            <lsb>2</lsb>
                            <msb>2</msb>
                            <access>read-write</access>
                            <enumeratedValues>
                                <enumeratedValue>
                                    <name>0</name>
                                    <description>Input (functions as an input pin)</description>
                                    <value>#0</value>
                                </enumeratedValue>
                                <enumeratedValue>
                                    <name>1</name>
                                    <description>Output (functions as an output pin)</description>
                                    <value>#1</value>
                                </enumeratedValue>
                            </enumeratedValues>
                        </field>
                        <field>
                            <name>PDR03</name>
                            <description>Pmn Direction</description>
                            <lsb>3</lsb>
                            <msb>3</msb>
                            <access>read-write</access>
                            <enumeratedValues>
                                <enumeratedValue>
                                    <name>0</name>
                                    <description>Input (functions as an input pin)</description>
                                    <value>#0</value>
                                </enumeratedValue>
                                <enumeratedValue>
                                    <name>1</name>
                                    <description>Output (functions as an output pin)</description>
                                    <value>#1</value>
                                </enumeratedValue>
                            </enumeratedValues>
                        </field>
                        <field>
                            <name>PDR04</name>
                            <description>Pmn Direction</description>
                            <lsb>4</lsb>
                            <msb>4</msb>
                            <access>read-write</access>
                            <enumeratedValues>
                                <enumeratedValue>
                                    <name>0</name>
                                    <description>Input (functions as an input pin)</description>
                                    <value>#0</value>
                                </enumeratedValue>
                                <enumeratedValue>
                                    <name>1</name>
                                    <description>Output (functions as an output pin)</description>
                                    <value>#1</value>
                                </enumeratedValue>
                            </enumeratedValues>
                        </field>
                        <field>
                            <name>PDR05</name>
                            <description>Pmn Direction</description>
                            <lsb>5</lsb>
                            <msb>5</msb>
                            <access>read-write</access>
                            <enumeratedValues>
                                <enumeratedValue>
                                    <name>0</name>
                                    <description>Input (functions as an input pin)</description>
                                    <value>#0</value>
                                </enumeratedValue>
                                <enumeratedValue>
                                    <name>1</name>
                                    <description>Output (functions as an output pin)</description>
                                    <value>#1</value>
                                </enumeratedValue>
                            </enumeratedValues>
                        </field>
                        <field>
                            <name>PDR06</name>
                            <description>Pmn Direction</description>
                            <lsb>6</lsb>
                            <msb>6</msb>
                            <access>read-write</access>
                            <enumeratedValues>
                                <enumeratedValue>
                                    <name>0</name>
                                    <description>Input (functions as an input pin)</description>
                                    <value>#0</value>
                                </enumeratedValue>
                                <enumeratedValue>
                                    <name>1</name>
                                    <description>Output (functions as an output pin)</description>
                                    <value>#1</value>
                                </enumeratedValue>
                            </enumeratedValues>
                        </field>
                        <field>
                            <name>PDR07</name>
                            <description>Pmn Direction</description>
                            <lsb>7</lsb>
                            <msb>7</msb>
                            <access>read-write</access>
                            <enumeratedValues>
                                <enumeratedValue>
                                    <name>0</name>
                                    <description>Input (functions as an input pin)</description>
                                    <value>#0</value>
                                </enumeratedValue>
                                <enumeratedValue>
                                    <name>1</name>
                                    <description>Output (functions as an output pin)</description>
                                    <value>#1</value>
                                </enumeratedValue>
                            </enumeratedValues>
                        </field>
                        <field>
                            <name>PDR08</name>
                            <description>Pmn Direction</description>
                            <lsb>8</lsb>
                            <msb>8</msb>
                            <access>read-write</access>
                            <enumeratedValues>
                                <enumeratedValue>
                                    <name>0</name>
                                    <description>Input (functions as an input pin)</description>
                                    <value>#0</value>
                                </enumeratedValue>
                                <enumeratedValue>
                                    <name>1</name>
                                    <description>Output (functions as an output pin)</description>
                                    <value>#1</value>
                                </enumeratedValue>
                            </enumeratedValues>
                        </field>
                        <field>
                            <name>PDR09</name>
                            <description>Pmn Direction</description>
                            <lsb>9</lsb>
                            <msb>9</msb>
                            <access>read-write</access>
                            <enumeratedValues>
                                <enumeratedValue>
                                    <name>0</name>
                                    <description>Input (functions as an input pin)</description>
                                    <value>#0</value>
                                </enumeratedValue>
                                <enumeratedValue>
                                    <name>1</name>
                                    <description>Output (functions as an output pin)</description>
                                    <value>#1</value>
                                </enumeratedValue>
                            </enumeratedValues>
                        </field>
                        <field>
                            <name>PDR10</name>
                            <description>Pmn Direction</description>
                            <lsb>10</lsb>
                            <msb>10</msb>
                            <access>read-write</access>
                            <enumeratedValues>
                                <enumeratedValue>
                                    <name>0</name>
                                    <description>Input (functions as an input pin)</description>
                                    <value>#0</value>
                                </enumeratedValue>
                                <enumeratedValue>
                                    <name>1</name>
                                    <description>Output (functions as an output pin)</description>
                                    <value>#1</value>
                                </enumeratedValue>
                            </enumeratedValues>
                        </field>
                        <field>
                            <name>PDR11</name>
                            <description>Pmn Direction</description>
                            <lsb>11</lsb>
                            <msb>11</msb>
                            <access>read-write</access>
                            <enumeratedValues>
                                <enumeratedValue>
                                    <name>0</name>
                                    <description>Input (functions as an input pin)</description>
                                    <value>#0</value>
                                </enumeratedValue>
                                <enumeratedValue>
                                    <name>1</name>
                                    <description>Output (functions as an output pin)</description>
                                    <value>#1</value>
                                </enumeratedValue>
                            </enumeratedValues>
                        </field>
                        <field>
                            <name>PDR12</name>
                            <description>Pmn Direction</description>
                            <lsb>12</lsb>
                            <msb>12</msb>
                            <access>read-write</access>
                            <enumeratedValues>
                                <enumeratedValue>
                                    <name>0</name>
                                    <description>Input (functions as an input pin)</description>
                                    <value>#0</value>
                                </enumeratedValue>
                                <enumeratedValue>
                                    <name>1</name>
                                    <description>Output (functions as an output pin)</description>
                                    <value>#1</value>
                                </enumeratedValue>
                            </enumeratedValues>
                        </field>
                        <field>
                            <name>PDR13</name>
                            <description>Pmn Direction</description>
                            <lsb>13</lsb>
                            <msb>13</msb>
                            <access>read-write</access>
                            <enumeratedValues>
                                <enumeratedValue>
                                    <name>0</name>
                                    <description>Input (functions as an input pin)</description>
                                    <value>#0</value>
                                </enumeratedValue>
                                <enumeratedValue>
                                    <name>1</name>
                                    <description>Output (functions as an output pin)</description>
                                    <value>#1</value>
                                </enumeratedValue>
                            </enumeratedValues>
                        </field>
                        <field>
                            <name>PDR14</name>
                            <description>Pmn Direction</description>
                            <lsb>14</lsb>
                            <msb>14</msb>
                            <access>read-write</access>
                            <enumeratedValues>
                                <enumeratedValue>
                                    <name>0</name>
                                    <description>Input (functions as an input pin)</description>
                                    <value>#0</value>
                                </enumeratedValue>
                                <enumeratedValue>
                                    <name>1</name>
                                    <description>Output (functions as an output pin)</description>
                                    <value>#1</value>
                                </enumeratedValue>
                            </enumeratedValues>
                        </field>
                        <field>
                            <name>PDR15</name>
                            <description>Pmn Direction</description>
                            <lsb>15</lsb>
                            <msb>15</msb>
                            <access>read-write</access>
                            <enumeratedValues>
                                <enumeratedValue>
                                    <name>0</name>
                                    <description>Input (functions as an input pin)</description>
                                    <value>#0</value>
                                </enumeratedValue>
                                <enumeratedValue>
                                    <name>1</name>
                                    <description>Output (functions as an output pin)</description>
                                    <value>#1</value>
                                </enumeratedValue>
                            </enumeratedValues>
                        </field>
                    </fields>
                </register>
                <register>
                    <name>PCNTR2</name>
                    <description>Port Control Register 2</description>
                    <addressOffset>0x004</addressOffset>
                    <size>32</size>
                    <access>read-only</access>
                    <resetValue>0x00000000</resetValue>
                    <resetMask>0xffff0000</resetMask>
                    <fields>
                        <field>
                            <name>PIDR00</name>
                            <description>Pmn State</description>
                            <lsb>0</lsb>
                            <msb>0</msb>
                            <access>read-only</access>
                            <enumeratedValues>
                                <enumeratedValue>
                                    <name>0</name>
                                    <description>Low level</description>
                                    <value>#0</value>
                                </enumeratedValue>
                                <enumeratedValue>
                                    <name>1</name>
                                    <description>High level</description>
                                    <value>#1</value>
                                </enumeratedValue>
                            </enumeratedValues>
                        </field>
                        <field>
                            <name>PIDR01</name>
                            <description>Pmn State</description>
                            <lsb>1</lsb>
                            <msb>1</msb>
                            <access>read-only</access>
                            <enumeratedValues>
                                <enumeratedValue>
                                    <name>0</name>
                                    <description>Low level</description>
                                    <value>#0</value>
                                </enumeratedValue>
                                <enumeratedValue>
                                    <name>1</name>
                                    <description>High level</description>
                                    <value>#1</value>
                                </enumeratedValue>
                            </enumeratedValues>
                        </field>
                        <field>
                            <name>PIDR02</name>
                            <description>Pmn State</description>
                            <lsb>2</lsb>
                            <msb>2</msb>
                            <access>read-only</access>
                            <enumeratedValues>
                                <enumeratedValue>
                                    <name>0</name>
                                    <description>Low level</description>
                                    <value>#0</value>
                                </enumeratedValue>
                                <enumeratedValue>
                                    <name>1</name>
                                    <description>High level</description>
                                    <value>#1</value>
                                </enumeratedValue>
                            </enumeratedValues>
                        </field>
                        <field>
                            <name>PIDR03</name>
                            <description>Pmn State</description>
                            <lsb>3</lsb>
                            <msb>3</msb>
                            <access>read-only</access>
                            <enumeratedValues>
                                <enumeratedValue>
                                    <name>0</name>
                                    <description>Low level</description>
                                    <value>#0</value>
                                </enumeratedValue>
                                <enumeratedValue>
                                    <name>1</name>
                                    <description>High level</description>
                                    <value>#1</value>
                                </enumeratedValue>
                            </enumeratedValues>
                        </field>
                        <field>
                            <name>PIDR04</name>
                            <description>Pmn State</description>
                            <lsb>4</lsb>
                            <msb>4</msb>
                            <access>read-only</access>
                            <enumeratedValues>
                                <enumeratedValue>
                                    <name>0</name>
                                    <description>Low level</description>
                                    <value>#0</value>
                                </enumeratedValue>
                                <enumeratedValue>
                                    <name>1</name>
                                    <description>High level</description>
                                    <value>#1</value>
                                </enumeratedValue>
                            </enumeratedValues>
                        </field>
                        <field>
                            <name>PIDR05</name>
                            <description>Pmn State</description>
                            <lsb>5</lsb>
                            <msb>5</msb>
                            <access>read-only</access>
                            <enumeratedValues>
                                <enumeratedValue>
                                    <name>0</name>
                                    <description>Low level</description>
                                    <value>#0</value>
                                </enumeratedValue>
                                <enumeratedValue>
                                    <name>1</name>
                                    <description>High level</description>
                                    <value>#1</value>
                                </enumeratedValue>
                            </enumeratedValues>
                        </field>
                        <field>
                            <name>PIDR06</name>
                            <description>Pmn State</description>
                            <lsb>6</lsb>
                            <msb>6</msb>
                            <access>read-only</access>
                            <enumeratedValues>
                                <enumeratedValue>
                                    <name>0</name>
                                    <description>Low level</description>
                                    <value>#0</value>
                                </enumeratedValue>
                                <enumeratedValue>
                                    <name>1</name>
                                    <description>High level</description>
                                    <value>#1</value>
                                </enumeratedValue>
                            </enumeratedValues>
                        </field>
                        <field>
                            <name>PIDR07</name>
                            <description>Pmn State</description>
                            <lsb>7</lsb>
                            <msb>7</msb>
                            <access>read-only</access>
                            <enumeratedValues>
                                <enumeratedValue>
                                    <name>0</name>
                                    <description>Low level</description>
                                    <value>#0</value>
                                </enumeratedValue>
                                <enumeratedValue>
                                    <name>1</name>
                                    <description>High level</description>
                                    <value>#1</value>
                                </enumeratedValue>
                            </enumeratedValues>
                        </field>
                        <field>
                            <name>PIDR08</name>
                            <description>Pmn State</description>
                            <lsb>8</lsb>
                            <msb>8</msb>
                            <access>read-only</access>
                            <enumeratedValues>
                                <enumeratedValue>
                                    <name>0</name>
                                    <description>Low level</description>
                                    <value>#0</value>
                                </enumeratedValue>
                                <enumeratedValue>
                                    <name>1</name>
                                    <description>High level</description>
                                    <value>#1</value>
                                </enumeratedValue>
                            </enumeratedValues>
                        </field>
                        <field>
                            <name>PIDR09</name>
                            <description>Pmn State</description>
                                    <description>Enabled</description>
                                    <value>#1</value>
                                </enumeratedValue>
                            </enumeratedValues>
                        </field>
                        <field>
                            <name>BUSEN</name>
                            <lsb>12</lsb>
                            <msb>12</msb>
                            <access>read-write</access>
                            <enumeratedValues>
                                <enumeratedValue>
                                    <name>0</name>
                                    <description>Disabled</description>
                                    <value>#0</value>
                                </enumeratedValue>
                                <enumeratedValue>
                                    <name>1</name>
                                    <description>Enabled</description>
                                    <value>#1</value>
                                </enumeratedValue>
                            </enumeratedValues>
                        </field>
                        <field>
                            <name>CMEN</name>
                            <lsb>13</lsb>
                            <msb>13</msb>
                            <access>read-write</access>
                            <enumeratedValues>
                                <enumeratedValue>
                                    <name>0</name>
                                    <description>Disabled</description>
                                    <value>#0</value>
                                </enumeratedValue>
                                <enumeratedValue>
                                    <name>1</name>
                                    <description>Enabled</description>
                                    <value>#1</value>
                                </enumeratedValue>
                            </enumeratedValues>
                        </field>
                        <field>
                            <name>LUEN</name>
                            <lsb>15</lsb>
                            <msb>15</msb>
                            <access>read-write</access>
                            <enumeratedValues>
                                <enumeratedValue>
                                    <name>0</name>
                                    <description>Disabled</description>
                                    <value>#0</value>
                                </enumeratedValue>
                                <enumeratedValue>
                                    <name>1</name>
                                    <description>Enabled</description>
                                    <value>#1</value>
                                </enumeratedValue>
                            </enumeratedValues>
                        </field>
                    </fields>
                </register>
                <register>
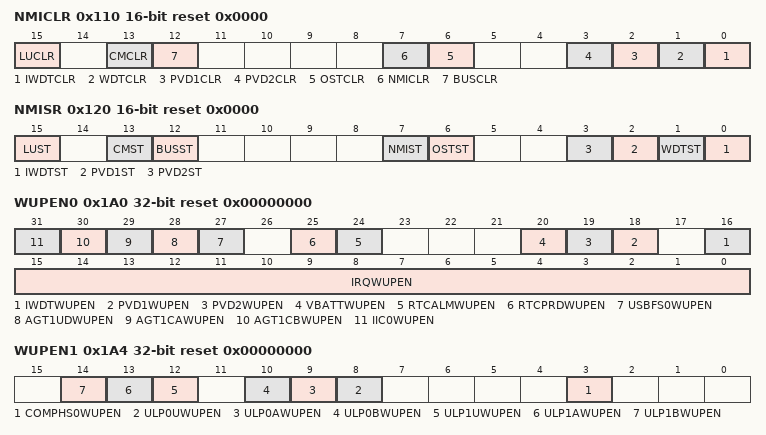
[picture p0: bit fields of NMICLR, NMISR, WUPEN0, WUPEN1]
                    <name>NMICLR</name>
                    <description>Non-Maskable Interrupt Status Clear Register</description>
                    <addressOffset>0x110</addressOffset>
                    <size>16</size>
                    <access>read-write</access>
                    <resetValue>0x0000</resetValue>
                    <resetMask>0xffff</resetMask>
                    <fields>
                        <field>
                            <name>IWDTCLR</name>
                            <description>IWDT Underflow/Refresh Error Interrupt Status Flag Clear</description>
                            <lsb>0</lsb>
                            <msb>0</msb>
                            <access>read-write</access>
                            <enumeratedValues>
                                <enumeratedValue>
                                    <name>0</name>
                                    <description>No effect</description>
                                    <value>#0</value>
                                </enumeratedValue>
                                <enumeratedValue>
                                    <name>1</name>
                                    <description>Clear the NMISR.IWDTST flag</description>
                                    <value>#1</value>
                                </enumeratedValue>
                            </enumeratedValues>
                        </field>
                        <field>
                            <name>WDTCLR</name>
                            <description>WDT Underflow/Refresh Error Interrupt Status Flag Clear</description>
                            <lsb>1</lsb>
                            <msb>1</msb>
                            <access>read-write</access>
                            <enumeratedValues>
                                <enumeratedValue>
                                    <name>0</name>
                                    <description>No effect</description>
                                    <value>#0</value>
                                </enumeratedValue>
                                <enumeratedValue>
                                    <name>1</name>
                                    <description>Clear the NMISR.WDTST flag</description>
                                    <value>#1</value>
                                </enumeratedValue>
                            </enumeratedValues>
                        </field>
                        <field>
                            <name>PVD1CLR</name>
                            <description>Voltage Monitor 1 Interrupt Status Flag Clear</description>
                            <lsb>2</lsb>
                            <msb>2</msb>
                            <access>read-write</access>
                            <enumeratedValues>
                                <enumeratedValue>
                                    <name>0</name>
                                    <description>No effect</description>
                                    <value>#0</value>
                                </enumeratedValue>
                                <enumeratedValue>
                                    <name>1</name>
                                    <description>Clear the NMISR.PVD1ST flag</description>
                                    <value>#1</value>
                                </enumeratedValue>
                            </enumeratedValues>
                        </field>
                        <field>
                            <name>PVD2CLR</name>
                            <description>Voltage Monitor 2 Interrupt Status Flag Clear</description>
                            <lsb>3</lsb>
                            <msb>3</msb>
                            <access>read-write</access>
                            <enumeratedValues>
                                <enumeratedValue>
                                    <name>0</name>
                                    <description>No effect</description>
                                    <value>#0</value>
                                </enumeratedValue>
                                <enumeratedValue>
                                    <name>1</name>
                                    <description>Clear the NMISR.PVD2ST flag.</description>
                                    <value>#1</value>
                                </enumeratedValue>
                            </enumeratedValues>
                        </field>
                        <field>
                            <name>OSTCLR</name>
                            <description>Oscillation Stop Detection Interrupt Status Flag Clear</description>
                            <lsb>6</lsb>
                            <msb>6</msb>
                            <access>read-write</access>
                            <enumeratedValues>
                                <enumeratedValue>
                                    <name>0</name>
                                    <description>No effect</description>
                                    <value>#0</value>
                                </enumeratedValue>
                                <enumeratedValue>
                                    <name>1</name>
                                    <description>Clear the NMISR.OSTST flag</description>
                                    <value>#1</value>
                                </enumeratedValue>
                            </enumeratedValues>
                        </field>
                        <field>
                            <name>NMICLR</name>
                            <description>NMI Pin Interrupt Status Flag Clear</description>
                            <lsb>7</lsb>
                            <msb>7</msb>
                            <access>read-write</access>
                            <enumeratedValues>
                                <enumeratedValue>
                                    <name>0</name>
                                    <description>No effect</description>
                                    <value>#0</value>
                                </enumeratedValue>
                                <enumeratedValue>
                                    <name>1</name>
                                    <description>Clear the NMISR.NMIST flag</description>
                                    <value>#1</value>
                                </enumeratedValue>
                            </enumeratedValues>
                        </field>
                        <field>
                            <name>BUSCLR</name>
                            <lsb>12</lsb>
                            <msb>12</msb>
                            <access>read-write</access>
                            <enumeratedValues>
                                <enumeratedValue>
                                    <name>0</name>
                                    <description>No effect</description>
                                    <value>#0</value>
                                </enumeratedValue>
                                <enumeratedValue>
                                    <name>1</name>
                                    <description>Clear the NMISR.BUSST flag</description>
                                    <value>#1</value>
                                </enumeratedValue>
                            </enumeratedValues>
                        </field>
                        <field>
                            <name>CMCLR</name>
                            <lsb>13</lsb>
                            <msb>13</msb>
                            <access>read-write</access>
                            <enumeratedValues>
                                <enumeratedValue>
                                    <name>0</name>
                                    <description>No effect</description>
                                    <value>#0</value>
                                </enumeratedValue>
                                <enumeratedValue>
                                    <name>1</name>
                                    <description>Clear the NMISR.CMST flag</description>
                                    <value>#1</value>
                                </enumeratedValue>
                            </enumeratedValues>
                        </field>
                        <field>
                            <name>LUCLR</name>
                            <lsb>15</lsb>
                            <msb>15</msb>
                            <access>read-write</access>
                            <enumeratedValues>
                                <enumeratedValue>
                                    <name>0</name>
                                    <description>No effect</description>
                                    <value>#0</value>
                                </enumeratedValue>
                                <enumeratedValue>
                                    <name>1</name>
                                    <description>Clear the NMISR.LUST flag</description>
                                    <value>#1</value>
                                </enumeratedValue>
                            </enumeratedValues>
                        </field>
                    </fields>
                </register>
                <register>
                    <name>NMISR</name>
                    <description>Non-Maskable Interrupt Status Register</description>
                    <addressOffset>0x120</addressOffset>
                    <size>16</size>
                    <access>read-only</access>
                    <resetValue>0x0000</resetValue>
                    <resetMask>0xffff</resetMask>
                    <fields>
                        <field>
                            <name>IWDTST</name>
                            <description>IWDT Underflow/Refresh Error Interrupt Status Flag</description>
                            <lsb>0</lsb>
                            <msb>0</msb>
                            <access>read-only</access>
                            <enumeratedValues>
                                <enumeratedValue>
                                    <name>0</name>
                                    <description>Interrupt not requested</description>
                                    <value>#0</value>
                                </enumeratedValue>
                                <enumeratedValue>
                                    <name>1</name>
                                    <description>Interrupt requested</description>
                                    <value>#1</value>
                                </enumeratedValue>
                            </enumeratedValues>
                        </field>
                        <field>
                            <name>WDTST</name>
                            <description>WDT Underflow/Refresh Error Interrupt Status Flag</description>
                            <lsb>1</lsb>
                            <msb>1</msb>
                            <access>read-only</access>
                            <enumeratedValues>
                                <enumeratedValue>
                                    <name>0</name>
                                    <description>Interrupt not requested</description>
                                    <value>#0</value>
                                </enumeratedValue>
                                <enumeratedValue>
                                    <name>1</name>
                                    <description>Interrupt requested</description>
                                    <value>#1</value>
                                </enumeratedValue>
                            </enumeratedValues>
                        </field>
                        <field>
                            <name>PVD1ST</name>
                            <description>Voltage Monitor 1 Interrupt Status Flag</description>
                            <lsb>2</lsb>
                            <msb>2</msb>
                            <access>read-only</access>
                            <enumeratedValues>
                                <enumeratedValue>
                                    <name>0</name>
                                    <description>Interrupt not requested</description>
                                    <value>#0</value>
                                </enumeratedValue>
                                <enumeratedValue>
                                    <name>1</name>
                                    <description>Interrupt requested</description>
                                    <value>#1</value>
                                </enumeratedValue>
                            </enumeratedValues>
                        </field>
                        <field>
                            <name>PVD2ST</name>
                            <description>Voltage Monitor 2 Interrupt Status Flag</description>
                            <lsb>3</lsb>
                            <msb>3</msb>
                            <access>read-only</access>
                            <enumeratedValues>
                                <enumeratedValue>
                                    <name>0</name>
                                    <description>Interrupt not requested</description>
                                    <value>#0</value>
                                </enumeratedValue>
                                <enumeratedValue>
                                    <name>1</name>
                                    <description>Interrupt requested</description>
                                    <value>#1</value>
                                </enumeratedValue>
                            </enumeratedValues>
                        </field>
                        <field>
                            <name>OSTST</name>
                            <description>Main Clock Oscillation Stop Detection Interrupt Status Flag</description>
                            <lsb>6</lsb>
                            <msb>6</msb>
                            <access>read-only</access>
                            <enumeratedValues>
                                <enumeratedValue>
                                    <name>0</name>
                                    <description>Interrupt not requested for main clock oscillation stop</description>
                                    <value>#0</value>
                                </enumeratedValue>
                                <enumeratedValue>
                                    <name>1</name>
                                    <description>Interrupt requested for main clock oscillation stop</description>
                                    <value>#1</value>
                                </enumeratedValue>
                            </enumeratedValues>
                        </field>
                        <field>
                            <name>NMIST</name>
                            <description>NMI Pin Interrupt Status Flag</description>
                            <lsb>7</lsb>
                            <msb>7</msb>
                            <access>read-only</access>
                            <enumeratedValues>
                                <enumeratedValue>
                                    <name>0</name>
                                    <description>Interrupt not requested</description>
                                    <value>#0</value>
                                </enumeratedValue>
                                <enumeratedValue>
                                    <name>1</name>
                                    <description>Interrupt requested</description>
                                    <value>#1</value>
                                </enumeratedValue>
                            </enumeratedValues>
                        </field>
                        <field>
                            <name>BUSST</name>
                            <description>Bus Error Interrupt Status Flag</description>
                            <lsb>12</lsb>
                            <msb>12</msb>
                            <access>read-only</access>
                            <enumeratedValues>
                                <enumeratedValue>
                                    <name>0</name>
                                    <description>Interrupt not requested</description>
                                    <value>#0</value>
                                </enumeratedValue>
                                <enumeratedValue>
                                    <name>1</name>
                                    <description>Interrupt requested</description>
                                    <value>#1</value>
                                </enumeratedValue>
                            </enumeratedValues>
                        </field>
                        <field>
                            <name>CMST</name>
                            <lsb>13</lsb>
                            <msb>13</msb>
                            <access>read-only</access>
                            <enumeratedValues>
                                <enumeratedValue>
                                    <name>0</name>
                                    <description>Interrupt not requested</description>
                                    <value>#0</value>
                                </enumeratedValue>
                                <enumeratedValue>
                                    <name>1</name>
                                    <description>Interrupt requested</description>
                                    <value>#1</value>
                                </enumeratedValue>
                            </enumeratedValues>
                        </field>
                        <field>
                            <name>LUST</name>
                            <lsb>15</lsb>
                            <msb>15</msb>
                            <access>read-only</access>
                            <enumeratedValues>
                                <enumeratedValue>
                                    <name>0</name>
                                    <description>Interrupt not requested</description>
                                    <value>#0</value>
                                </enumeratedValue>
                                <enumeratedValue>
                                    <name>1</name>
                                    <description>Interrupt requested</description>
                                    <value>#1</value>
                                </enumeratedValue>
                            </enumeratedValues>
                        </field>
                    </fields>
                </register>
                <register>
                    <name>WUPEN0</name>
                    <description>Wake Up Interrupt Enable Register 0</description>
                    <addressOffset>0x1A0</addressOffset>
                    <size>32</size>
                    <access>read-write</access>
                    <resetValue>0x00000000</resetValue>
                    <resetMask>0xffffffff</resetMask>
                    <fields>
                        <field>
                            <name>IRQWUPEN</name>
                            <lsb>0</lsb>
                            <msb>15</msb>
                            <access>read-write</access>
                            <enumeratedValues>
                                <enumeratedValue>
                                    <name>0</name>
                                    <description>Deep Sleep/Software Standby Mode returns by IRQn interrupt is disabled .</description>
                                    <value>#0</value>
                                </enumeratedValue>
                                <enumeratedValue>
                                    <name>1</name>
                                    <description>Deep Sleep/Software Standby Mode returns by IRQn interrupt is enabled</description>
                                    <value>#1</value>
                                </enumeratedValue>
                            </enumeratedValues>
                        </field>
                        <field>
                            <name>IWDTWUPEN</name>
                            <description>IWDT Interrupt Deep Sleep/Software Standby Mode Returns Enable</description>
                            <lsb>16</lsb>
                            <msb>16</msb>
                            <access>read-write</access>
                            <enumeratedValues>
                                <enumeratedValue>
                                    <name>0</name>
                                    <description>Deep Sleep/Software Standby Mode returns by IWDT interrupt is disabled</description>
                                    <value>#0</value>
                                </enumeratedValue>
                                <enumeratedValue>
                                    <name>1</name>
                                    <description>Deep Sleep/Software Standby Mode returns by IWDT interrupt is enabled</description>
                                    <value>#1</value>
                                </enumeratedValue>
                            </enumeratedValues>
                        </field>
                        <field>
                            <name>PVD1WUPEN</name>
                            <description>PVD1 Interrupt Deep Sleep/Software Standby Mode Returns Enable</description>
                            <lsb>18</lsb>
                            <msb>18</msb>
                            <access>read-write</access>
                            <enumeratedValues>
                                <enumeratedValue>
                                    <name>0</name>
                                    <description>Deep Sleep/Software Standby Mode returns by PVD1 interrupt is disabled</description>
                                    <value>#0</value>
                                </enumeratedValue>
                                <enumeratedValue>
                                    <name>1</name>
                                    <description>Deep Sleep/Software Standby Mode returns by PVD1 interrupt is enabled</description>
                                    <value>#1</value>
                                </enumeratedValue>
                            </enumeratedValues>
                        </field>
                        <field>
                            <name>PVD2WUPEN</name>
                            <description>PVD2 Interrupt Deep Sleep/Software Standby Mode Returns Enable</description>
                            <lsb>19</lsb>
                            <msb>19</msb>
                            <access>read-write</access>
                            <enumeratedValues>
                                <enumeratedValue>
                                    <name>0</name>
                                    <description>Deep Sleep/Software Standby Mode returns by PVD2 interrupt is disabled</description>
                                    <value>#0</value>
                                </enumeratedValue>
                                <enumeratedValue>
                                    <name>1</name>
                                    <description>Deep Sleep/Software Standby Mode returns by PVD2 interrupt is enabled</description>
                                    <value>#1</value>
                                </enumeratedValue>
                            </enumeratedValues>
                        </field>
                        <field>
                            <name>VBATTWUPEN</name>
                            <description>VBATT Monitor Interrupt Deep Sleep/Software Standby Mode Returns Enable</description>
                            <lsb>20</lsb>
                            <msb>20</msb>
                            <access>read-write</access>
                            <enumeratedValues>
                                <enumeratedValue>
                                    <name>0</name>
                                    <description>Deep Sleep/Software Standby Mode returns by VBATT monitor interrupt is disabled</description>
                                    <value>#0</value>
                                </enumeratedValue>
                                <enumeratedValue>
                                    <name>1</name>
                                    <description>Deep Sleep/Software Standby Mode returns by VBATT monitor interrupt is enabled</description>
                                    <value>#1</value>
                                </enumeratedValue>
                            </enumeratedValues>
                        </field>
                        <field>
                            <name>RTCALMWUPEN</name>
                            <description>RTC Alarm Interrupt Deep Sleep/Software Standby Mode Returns Enable</description>
                            <lsb>24</lsb>
                            <msb>24</msb>
                            <access>read-write</access>
                            <enumeratedValues>
                                <enumeratedValue>
                                    <name>0</name>
                                    <description>Deep Sleep/Software Standby Mode returns by RTC alarm interrupt is disabled</description>
                                    <value>#0</value>
                                </enumeratedValue>
                                <enumeratedValue>
                                    <name>1</name>
                                    <description>Deep Sleep/Software Standby Mode returns by RTC alarm interrupt is enabled</description>
                                    <value>#1</value>
                                </enumeratedValue>
                            </enumeratedValues>
                        </field>
                        <field>
                            <name>RTCPRDWUPEN</name>
                            <description>RTC Period Interrupt Deep Sleep/Software Standby Mode Returns Enable</description>
                            <lsb>25</lsb>
                            <msb>25</msb>
                            <access>read-write</access>
                            <enumeratedValues>
                                <enumeratedValue>
                                    <name>0</name>
                                    <description>Deep Sleep/Software Standby Mode returns by RTC period interrupt is disabled</description>
                                    <value>#0</value>
                                </enumeratedValue>
                                <enumeratedValue>
                                    <name>1</name>
                                    <description>Deep Sleep/Software Standby Mode returns by RTC period interrupt is enabled</description>
                                    <value>#1</value>
                                </enumeratedValue>
                            </enumeratedValues>
                        </field>
                        <field>
                            <name>USBFS0WUPEN</name>
                            <description>USBFS Interrupt Deep Sleep/Software Standby Mode Returns Enable</description>
                            <lsb>27</lsb>
                            <msb>27</msb>
                            <access>read-write</access>
                            <enumeratedValues>
                                <enumeratedValue>
                                    <name>0</name>
                                    <description>Deep Sleep/Software Standby Mode returns by USBFS interrupt is disabled</description>
                                    <value>#0</value>
                                </enumeratedValue>
                                <enumeratedValue>
                                    <name>1</name>
                                    <description>Deep Sleep/Software Standby Mode returns by USBFS interrupt is enabled</description>
                                    <value>#1</value>
                                </enumeratedValue>
                            </enumeratedValues>
                        </field>
                        <field>
                            <name>AGT1UDWUPEN</name>
                            <description>AGT1 Underflow Interrupt Deep Sleep/Software Standby Mode Returns Enable</description>
                            <lsb>28</lsb>
                            <msb>28</msb>
                            <access>read-write</access>
                            <enumeratedValues>
                                <enumeratedValue>
                                    <name>0</name>
                                    <description>Deep Sleep/Software Standby Mode returns by AGT1 underflow interrupt is disabled</description>
                                    <value>#0</value>
                                </enumeratedValue>
                                <enumeratedValue>
                                    <name>1</name>
                                    <description>Deep Sleep/Software Standby Mode returns by AGT1 underflow interrupt is enabled</description>
                                    <value>#1</value>
                                </enumeratedValue>
                            </enumeratedValues>
                        </field>
                        <field>
                            <name>AGT1CAWUPEN</name>
                            <description>AGT1 Compare Match A Interrupt Deep Sleep/Software Standby Mode Returns Enable</description>
                            <lsb>29</lsb>
                            <msb>29</msb>
                            <access>read-write</access>
                            <enumeratedValues>
                                <enumeratedValue>
                                    <name>0</name>
                                    <description>Deep Sleep/Software Standby Mode returns by AGT1 compare match A interrupt is disabled</description>
                                    <value>#0</value>
                                </enumeratedValue>
                                <enumeratedValue>
                                    <name>1</name>
                                    <description>Deep Sleep/Software Standby Mode returns by AGT1 compare match A interrupt is enabled</description>
                                    <value>#1</value>
                                </enumeratedValue>
                            </enumeratedValues>
                        </field>
                        <field>
                            <name>AGT1CBWUPEN</name>
                            <description>AGT1 Compare Match B Interrupt Deep Sleep/Software Standby Mode Returns Enable</description>
                            <lsb>30</lsb>
                            <msb>30</msb>
                            <access>read-write</access>
                            <enumeratedValues>
                                <enumeratedValue>
                                    <name>0</name>
                                    <description>Deep Sleep/Software Standby Mode returns by AGT1 compare match B interrupt is disabled</description>
                                    <value>#0</value>
                                </enumeratedValue>
                                <enumeratedValue>
                                    <name>1</name>
                                    <description>Deep Sleep/Software Standby Mode returns by AGT1 compare match B interrupt is enabled</description>
                                    <value>#1</value>
                                </enumeratedValue>
                            </enumeratedValues>
                        </field>
                        <field>
                            <name>IIC0WUPEN</name>
                            <description>IIC0 Address Match Interrupt Deep Sleep/Software Standby Mode Returns Enable</description>
                            <lsb>31</lsb>
                            <msb>31</msb>
                            <access>read-write</access>
                            <enumeratedValues>
                                <enumeratedValue>
                                    <name>0</name>
                                    <description>Deep Sleep/Software Standby Mode returns by IIC0 address match A interrupt is disabled</description>
                                    <value>#0</value>
                                </enumeratedValue>
                                <enumeratedValue>
                                    <name>1</name>
                                    <description>Deep Sleep/Software Standby Mode returns by IIC0 address match A interrupt is enabled</description>
                                    <value>#1</value>
                                </enumeratedValue>
                            </enumeratedValues>
                        </field>
                    </fields>
                </register>
                <register>
                    <name>WUPEN1</name>
                    <description>Wake Up interrupt enable register 1</description>
                    <addressOffset>0x1A4</addressOffset>
                    <size>32</size>
                    <access>read-write</access>
                    <resetValue>0x00000000</resetValue>
                    <resetMask>0xffffffff</resetMask>
                    <fields>
                        <field>
                            <name>COMPHS0WUPEN</name>
                            <description>Comparator-HS0 Interrupt Deep Sleep/Software Standby Mode returns Enable bit</description>
                            <lsb>3</lsb>
                            <msb>3</msb>
                            <access>read-write</access>
                            <enumeratedValues>
                                <enumeratedValue>
                                    <name>0</name>
                                    <description>Deep Sleep/Software Standby returns by Comparator-HS0 interrupt is disabled.</description>
                                    <value>#0</value>
                                </enumeratedValue>
                                <enumeratedValue>
                                    <name>1</name>
                                    <description>Deep Sleep/Software Standby returns by ULPT0 Underflow interrupt is enabled.</description>
                                    <value>#1</value>
                                </enumeratedValue>
                            </enumeratedValues>
                        </field>
                        <field>
                            <name>ULP0UWUPEN</name>
                            <description>ULPT0 Underflow Interrupt Deep Sleep/Software Standby Mode returns Enable bit</description>
                            <lsb>8</lsb>
                            <msb>8</msb>
                            <access>read-write</access>
                            <enumeratedValues>
                                <enumeratedValue>
                                    <name>0</name>
                                    <description>Deep Sleep/Software Standby returns by ULPT0 interrupt is disabled.</description>
                                    <value>#0</value>
                                </enumeratedValue>
                                <enumeratedValue>
                                    <name>1</name>
                                    <description>Deep Sleep/Software Standby returns by ULPT0 Underflow interrupt is enabled.</description>
                                    <value>#1</value>
                                </enumeratedValue>
                            </enumeratedValues>
                        </field>
                        <field>
                            <name>ULP0AWUPEN</name>
                            <description>ULPT0 Compare Match A Interrupt Deep Sleep/Software Standby Mode returns Enable bit</description>
                            <lsb>9</lsb>
                            <msb>9</msb>
                            <access>read-write</access>
                            <enumeratedValues>
                                <enumeratedValue>
                                    <name>0</name>
                                    <description>Deep Sleep/Software Standby returns by ULPT0 Compare match A interrupt is disabled.</description>
                                    <value>#0</value>
                                </enumeratedValue>
                                <enumeratedValue>
                                    <name>1</name>
                                    <description>Deep Sleep/Software Standby returns by ULPT0 Compare match A interrupt is enabled.</description>
                                    <value>#1</value>
                                </enumeratedValue>
                            </enumeratedValues>
                        </field>
                        <field>
                            <name>ULP0BWUPEN</name>
                            <description>ULPT0 Compare Match B Interrupt Deep Sleep/Software Standby Mode returns Enable bit</description>
                            <lsb>10</lsb>
                            <msb>10</msb>
                            <access>read-write</access>
                            <enumeratedValues>
                                <enumeratedValue>
                                    <name>0</name>
                                    <description>Deep Sleep/Software Standby returns by ULPT0 Compare match B interrupt is disabled.</description>
                                    <value>#0</value>
                                </enumeratedValue>
                                <enumeratedValue>
                                    <name>1</name>
                                    <description>Deep Sleep/Software Standby returns by ULPT0 Compare match B interrupt is enabled.</description>
                                    <value>#1</value>
                                </enumeratedValue>
                            </enumeratedValues>
                        </field>
                        <field>
                            <name>ULP1UWUPEN</name>
                            <description>ULPT1 Underflow Interrupt Deep Sleep/Software Standby Mode returns Enable bit</description>
                            <lsb>12</lsb>
                            <msb>12</msb>
                            <access>read-write</access>
                            <enumeratedValues>
                                <enumeratedValue>
                                    <name>0</name>
                                    <description>Deep Sleep/Software Standby returns by ULPT1 Underflow interrupt is disabled.</description>
                                    <value>#0</value>
                                </enumeratedValue>
                                <enumeratedValue>
                                    <name>1</name>
                                    <description>Deep Sleep/Software Standby returns by ULPT1 Underflow interrupt is enabled</description>
                                    <value>#1</value>
                                </enumeratedValue>
                            </enumeratedValues>
                        </field>
                        <field>
                            <name>ULP1AWUPEN</name>
                            <description>ULPT1 Compare Match A Interrupt Deep Sleep/Software Standby Mode returns Enable bit</description>
                            <lsb>13</lsb>
                            <msb>13</msb>
                            <access>read-write</access>
                            <enumeratedValues>
                                <enumeratedValue>
                                    <name>0</name>
                                    <description>Deep Sleep/Software Standby returns by ULPT1 Compare match A interrupt is disabled.</description>
                                    <value>#0</value>
                                </enumeratedValue>
                                <enumeratedValue>
                                    <name>1</name>
                                    <description>Deep Sleep/Software Standby returns by ULPT1 Compare match A interrupt is enabled.</description>
                                    <value>#1</value>
                                </enumeratedValue>
                            </enumeratedValues>
                        </field>
                        <field>
                            <name>ULP1BWUPEN</name>
                            <description>ULPT1 Compare Match B Interrupt Deep Sleep/Software Standby Mode returns Enable bit</description>
                            <lsb>14</lsb>
                            <msb>14</msb>
                            <access>read-write</access>
                            <enumeratedValues>
                                <enumeratedValue>
                                    <name>0</name>
                                    <description>Deep Sleep/Software Standby returns by ULPT1 Compare match B interrupt is disabled.</description>
                                    <value>#0</value>
                                </enumeratedValue>
                                <enumeratedValue>
                                    <name>1</name>
                                    <description>Deep Sleep/Software Standby returns by ULPT1 Compare match B interrupt is enabled.</description>
                                    <value>#1</value>
                                </enumeratedValue>
                            </enumeratedValues>
                        </field>
                    </fields>
                </register>
                <register>
                    <dim>96</dim>
                    <dimIncrement>0x4</dimIncrement>
                    <dimIndex>0-95</dimIndex>
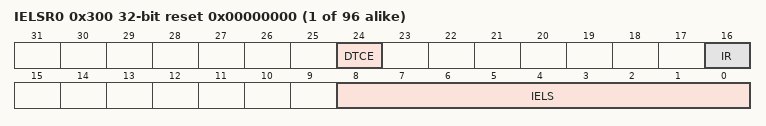
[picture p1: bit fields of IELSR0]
                    <name>IELSR%s</name>
                    <description>ICU Event Link Setting Register %s</description>
                    <addressOffset>0x300</addressOffset>
                    <size>32</size>
                    <access>read-write</access>
                    <resetValue>0x00000000</resetValue>
                    <resetMask>0xffffffff</resetMask>
                    <fields>
                        <field>
                            <name>IELS</name>
                            <description>ICU Event Link Select</description>
                            <lsb>0</lsb>
                            <msb>8</msb>
                            <access>read-write</access>
                            <enumeratedValues>
                                <enumeratedValue>
                                    <name>0x00</name>
                                    <description>Disable interrupts to the associated NVIC or DTC module</description>
                                    <value>0x00</value>
                                </enumeratedValue>
                                <enumeratedValue>
                                    <name>Others</name>
                                    <description>Event signal number to be linked. </description>
                                    <isDefault>true</isDefault>
                                </enumeratedValue>
                            </enumeratedValues>
                        </field>
                        <field>
                            <name>IR</name>
                            <description>Interrupt Status Flag</description>
                            <lsb>16</lsb>
                            <msb>16</msb>
                            <access>read-write</access>
                            <enumeratedValues>
                                <enumeratedValue>
                                    <name>0</name>
                                    <description>No interrupt request generated.</description>
                                    <value>#0</value>
                                </enumeratedValue>
                                <enumeratedValue>
                                    <name>1</name>
                                    <description>An interrupt request is generated.</description>
                                    <value>#1</value>
                                </enumeratedValue>
                            </enumeratedValues>
                        </field>
                        <field>
                            <name>DTCE</name>
                            <description>DTC Activation Enable</description>
                            <lsb>24</lsb>
                            <msb>24</msb>
                            <access>read-write</access>
                            <enumeratedValues>
                                <enumeratedValue>
                                    <name>0</name>
                                    <description>DTC activation is disabled.</description>
                                    <value>#0</value>
                                </enumeratedValue>
                                <enumeratedValue>
                                    <name>1</name>
                                    <description>DTC activation is enabled.</description>
                                    <value>#1</value>
                                </enumeratedValue>
                            </enumeratedValues>
                        </field>
                    </fields>
                </register>
            </registers>
        </peripheral>
        <peripheral>
            <name>CPU_CTRL_NS</name>
            <description>CPU Control Registers</description>
            <baseAddress>0x5000F000</baseAddress>
            <addressBlock>
                <offset>0x30</offset>
                <size>1</size>
                <usage>registers</usage>
            </addressBlock>
            <addressBlock>
                <offset>0x500</offset>
                <size>1</size>
                <usage>registers</usage>
            </addressBlock>
            <addressBlock>
                <offset>0x840</offset>
                <size>2</size>
                <usage>registers</usage>
            </addressBlock>
            <registers>
                <register>
                    <name>CPULCKUPCR</name>
                    <description>CPU Lockup Control Register</description>
                    <addressOffset>0x030</addressOffset>
                    <size>8</size>
                    <access>read-write</access>
                    <resetValue>0x00</resetValue>
                    <resetMask>0xff</resetMask>
                    <fields>
                        <field>
                            <name>OAD</name>
                            <description>Operation after detection of CPU lockup</description>
                            <lsb>0</lsb>
                            <msb>0</msb>
                            <access>read-write</access>
                            <enumeratedValues>
                                <enumeratedValue>
                                    <name>0</name>
                                    <description>Non-maskable Interrupt</description>
                                    <value>#0</value>
                                </enumeratedValue>
                                <enumeratedValue>
                                    <name>1</name>
                                    <description>CPU Lockup reset</description>
                                    <value>#1</value>
                                </enumeratedValue>
                            </enumeratedValues>
                        </field>
                    </fields>
                </register>
                <register>
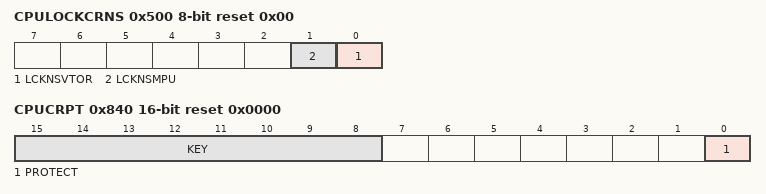
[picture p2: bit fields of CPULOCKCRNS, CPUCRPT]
                    <name>CPULOCKCRNS</name>
                    <description>CPU Non-secure Function Lock Control Register</description>
                    <addressOffset>0x500</addressOffset>
                    <size>8</size>
                    <access>read-write</access>
                    <resetValue>0x00</resetValue>
                    <resetMask>0xff</resetMask>
                    <fields>
                        <field>
                            <name>LCKNSVTOR</name>
                            <lsb>0</lsb>
                            <msb>0</msb>
                            <access>read-write</access>
                        </field>
                        <field>
                            <name>LCKNSMPU</name>
                            <description>Disable writes to registers that are associated with the Non-secure MPU region from software or from a debug agent connected to the processor:</description>
                            <lsb>1</lsb>
                            <msb>1</msb>
                            <access>read-write</access>
                        </field>
                    </fields>
                </register>
                <register>
                    <name>CPUCRPT</name>
                    <description>CPU Control Register Protection Register</description>
                    <addressOffset>0x840</addressOffset>
                    <size>16</size>
                    <access>read-write</access>
                    <resetValue>0x0000</resetValue>
                    <resetMask>0xffff</resetMask>
                    <fields>
                        <field>
                            <name>PROTECT</name>
                            <description>Protection of register</description>
                            <lsb>0</lsb>
                            <msb>0</msb>
                            <access>read-write</access>
                            <enumeratedValues>
                                <enumeratedValue>
                                    <name>0</name>
                                    <description>Writing to CPULCKUPCR register is permitted.</description>
                                    <value>#0</value>
                                </enumeratedValue>
                                <enumeratedValue>
                                    <name>1</name>
                                    <description>Writing to CPULCKUPCR register is not permitted. Read access is permitted.</description>
                                    <value>#1</value>
                                </enumeratedValue>
                            </enumeratedValues>
                        </field>
                        <field>
                            <name>KEY</name>
                            <description>The KEY[7:0] bits enable or disable writing to the PROTECT bit.</description>
                            <lsb>8</lsb>
                            <msb>15</msb>
                            <access>write-only</access>
                        </field>
                    </fields>
                </register>
            </registers>
        </peripheral>
        <peripheral>
            <name>OCD_CPU_NS</name>
            <description>On-Chip Debug</description>
            <baseAddress>0x50011000</baseAddress>
            <addressBlock>
                <offset>0x04</offset>
                <size>4</size>
                <usage>registers</usage>
            </addressBlock>
            <addressBlock>
                <offset>0x100</offset>
                <size>4</size>
                <usage>registers</usage>
            </addressBlock>
            <addressBlock>
                <offset>0x120</offset>
                <size>4</size>
                <usage>registers</usage>
            </addressBlock>
            <addressBlock>
                <offset>0x130</offset>
                <size>4</size>
                <usage>registers</usage>
            </addressBlock>
            <addressBlock>
                <offset>0x140</offset>
                <size>4</size>
                <usage>registers</usage>
            </addressBlock>
            <addressBlock>
                <offset>0x150</offset>
                <size>4</size>
                <usage>registers</usage>
            </addressBlock>
            <registers>
                <register>
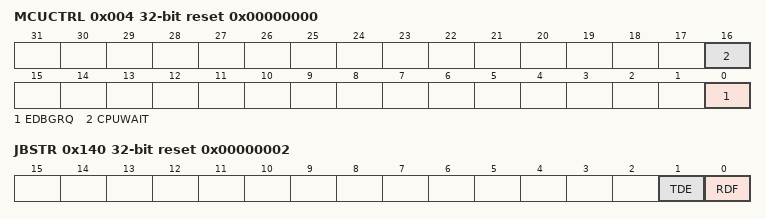
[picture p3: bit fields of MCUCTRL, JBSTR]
                    <name>MCUCTRL</name>
                    <description>MCU Control Register</description>
                    <addressOffset>0x004</addressOffset>
                    <size>32</size>
                    <access>read-write</access>
                    <resetValue>0x00000000</resetValue>
                    <resetMask>0xffffffff</resetMask>
                    <fields>
                        <field>
                            <name>EDBGRQ</name>
                            <description>External Debug Request. Writing 1 to the bit causes a CPU Halt or Debug Monitor exception request.</description>
                            <lsb>0</lsb>
                            <msb>0</msb>
                            <access>read-write</access>
                            <enumeratedValues>
                                <enumeratedValue>
                                    <name>0</name>
                                    <description>Debug event is not requested</description>
                                    <value>#0</value>
                                </enumeratedValue>
                                <enumeratedValue>
                                    <name>1</name>
                                    <description>Debug event is requested</description>
                                    <value>#1</value>
                                </enumeratedValue>
                            </enumeratedValues>
                        </field>
                        <field>
                            <name>CPUWAIT</name>
                            <lsb>16</lsb>
                            <msb>16</msb>
                            <access>read-write</access>
                            <enumeratedValues>
                                <enumeratedValue>
                                    <name>0</name>
                                    <description>Deassert CPUWAIT CPU starts boot-up sequence and instruction execution out of Reset. </description>
                                    <value>#0</value>
                                </enumeratedValue>
                                <enumeratedValue>
                                    <name>1</name>
                                    <description>Assert CPUWAIT CPU is forced into a quiescent state out of Reset. </description>
                                    <value>#1</value>
                                </enumeratedValue>
                            </enumeratedValues>
                        </field>
                    </fields>
                </register>
                <register>
                    <name>JBMDR</name>
                    <description>JTAG Boot Mode Entry Register</description>
                    <addressOffset>0x100</addressOffset>
                    <size>32</size>
                    <access>read-write</access>
                    <resetValue>0x00000000</resetValue>
                    <resetMask>0xffffffff</resetMask>
                    <fields>
                        <field>
                            <name>KEY</name>
                            <description>Mode entry key</description>
                            <lsb>0</lsb>
                            <msb>7</msb>
                            <access>read-write</access>
                        </field>
                    </fields>
                </register>
                <register>
                    <name>JBRDR</name>
                    <description>JTAG Boot Receive Data Register</description>
                    <addressOffset>0x120</addressOffset>
                    <size>32</size>
                    <access>read-write</access>
                    <resetValue>0x00000000</resetValue>
                    <resetMask>0xffffffff</resetMask>
                    <fields>
                        <field>
                            <name>RDAT</name>
                            <description>Received data register</description>
                            <lsb>0</lsb>
                            <msb>31</msb>
                            <access>read-write</access>
                        </field>
                    </fields>
                </register>
                <register>
                    <name>JBTDR</name>
                    <description>JTAG Boot Transmit Data Register</description>
                    <addressOffset>0x130</addressOffset>
                    <size>32</size>
                    <access>read-write</access>
                    <resetValue>0x00000000</resetValue>
                    <resetMask>0xffffffff</resetMask>
                    <fields>
                        <field>
                            <name>TDAT</name>
                            <description>Transmitted data register</description>
                            <lsb>0</lsb>
                            <msb>31</msb>
                            <access>read-write</access>
                        </field>
                    </fields>
                </register>
                <register>
                    <name>JBSTR</name>
                    <description>JTAG Boot Status Register</description>
                    <addressOffset>0x140</addressOffset>
                    <size>32</size>
                    <access>read-write</access>
                    <resetValue>0x00000002</resetValue>
                    <resetMask>0xffffffff</resetMask>
                    <fields>
                        <field>
                            <name>RDF</name>
                            <description>Receive buffer full</description>
                            <lsb>0</lsb>
                            <msb>0</msb>
                            <access>read-write</access>
                            <enumeratedValues>
                                <enumeratedValue>
                                    <name>0</name>
                                    <description>No receiving data</description>
                                    <value>#0</value>
                                </enumeratedValue>
                                <enumeratedValue>
                                    <name>1</name>
                                    <description>There is receiving data</description>
                                    <value>#1</value>
                                </enumeratedValue>
                            </enumeratedValues>
                        </field>
                        <field>
                            <name>TDE</name>
                            <description>Transmit data empty</description>
                            <lsb>1</lsb>
                            <msb>1</msb>
                            <access>read-write</access>
                            <enumeratedValues>
                                <enumeratedValue>
                                    <name>0</name>
                                    <description>There is data transmission</description>
                                    <value>#0</value>
                                </enumeratedValue>
                                <enumeratedValue>
                                    <name>1</name>
                                    <description>No data transmission</description>
                                    <value>#1</value>
                                </enumeratedValue>
                            </enumeratedValues>
                        </field>
                    </fields>
                </register>
                <register>
                    <name>JBICR</name>
                    <description>JTAG Boot Interrupt Control Register</description>
                    <addressOffset>0x150</addressOffset>
                    <size>32</size>
                    <access>read-write</access>
                    <resetValue>0x00000000</resetValue>
                    <resetMask>0xffffffff</resetMask>
                    <fields>
                        <field>
                            <name>RDFIE</name>
                            <description>Receive buffer full interrupt enabled</description>
                            <lsb>0</lsb>
                            <msb>0</msb>
                            <access>read-write</access>
                            <enumeratedValues>
                                <enumeratedValue>
                                    <name>0</name>
                                    <description>Interrupt request disabled by RDF = 1</description>
                                    <value>#0</value>
                                </enumeratedValue>
                                <enumeratedValue>
                                    <name>1</name>
                                    <description>Enable interrupt request by RDF = 1</description>
                                    <value>#1</value>
                                </enumeratedValue>
                            </enumeratedValues>
                        </field>
                    </fields>
                </register>
            </registers>
        </peripheral>
        <peripheral>
            <name>CPU_DBG_NS</name>
            <description>Debug Function</description>
            <baseAddress>0x5001B000</baseAddress>
            <addressBlock>
                <offset>0x00</offset>
                <size>4</size>
                <usage>registers</usage>
            </addressBlock>
            <addressBlock>
                <offset>0x10</offset>
                <size>4</size>
                <usage>registers</usage>
            </addressBlock>
            <addressBlock>
                <offset>0x20</offset>
                <size>4</size>
                <usage>registers</usage>
            </addressBlock>
            <addressBlock>
                <offset>0x30</offset>
                <size>4</size>
                <usage>registers</usage>
            </addressBlock>
            <addressBlock>
                <offset>0x300</offset>
                <size>4</size>
                <usage>registers</usage>
            </addressBlock>
            <addressBlock>
                <offset>0x310</offset>
                <size>4</size>
                <usage>registers</usage>
            </addressBlock>
            <registers>
                <register>
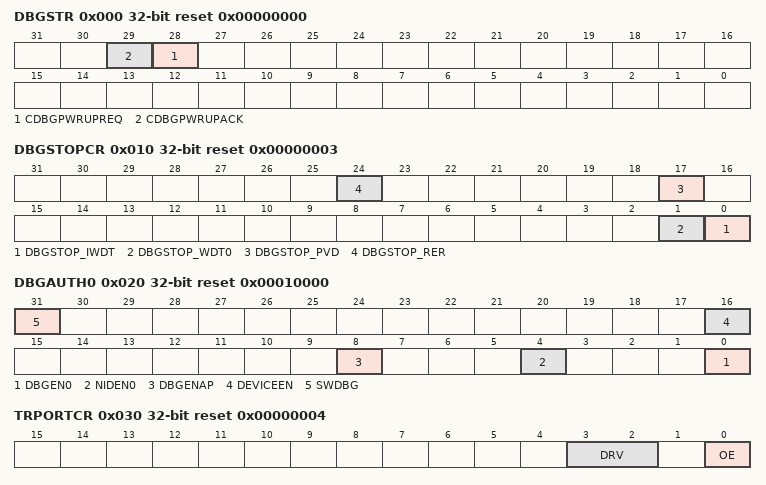
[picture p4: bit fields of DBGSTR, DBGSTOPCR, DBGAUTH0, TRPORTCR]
                    <name>DBGSTR</name>
                    <description>Debug Status Register</description>
                    <addressOffset>0x000</addressOffset>
                    <size>32</size>
                    <access>read-only</access>
                    <resetValue>0x00000000</resetValue>
                    <resetMask>0xcfffffff</resetMask>
                    <fields>
                        <field>
                            <name>CDBGPWRUPREQ</name>
                            <description>Debug power-up request</description>
                            <lsb>28</lsb>
                            <msb>28</msb>
                            <access>read-only</access>
                            <enumeratedValues>
                                <enumeratedValue>
                                    <name>0</name>
                                    <description>OCD is not requesting debug power-up</description>
                                    <value>#0</value>
                                </enumeratedValue>
                                <enumeratedValue>
                                    <name>1</name>
                                    <description>OCD is requesting debug power-up</description>
                                    <value>#1</value>
                                </enumeratedValue>
                            </enumeratedValues>
                        </field>
                        <field>
                            <name>CDBGPWRUPACK</name>
                            <description>Debug power-up acknowledge</description>
                            <lsb>29</lsb>
                            <msb>29</msb>
                            <access>read-only</access>
                            <enumeratedValues>
                                <enumeratedValue>
                                    <name>0</name>
                                    <description>Debug power-up request is not acknowledged</description>
                                    <value>#0</value>
                                </enumeratedValue>
                                <enumeratedValue>
                                    <name>1</name>
                                    <description>Debug power-up request is acknowledged</description>
                                    <value>#1</value>
                                </enumeratedValue>
                            </enumeratedValues>
                        </field>
                    </fields>
                </register>
                <register>
                    <name>DBGSTOPCR</name>
                    <description>Debug Stop Control Register</description>
                    <addressOffset>0x010</addressOffset>
                    <size>32</size>
                    <access>read-write</access>
                    <resetValue>0x00000003</resetValue>
                    <resetMask>0xffffffff</resetMask>
                    <fields>
                        <field>
                            <name>DBGSTOP_IWDT</name>
                            <description>Mask bit for IWDT reset/interrupt in the OCD run mode</description>
                            <lsb>0</lsb>
                            <msb>0</msb>
                            <access>read-write</access>
                            <enumeratedValues>
                                <enumeratedValue>
                                    <name>0</name>
                                    <description>Enable IWDT reset/interrupt</description>
                                    <value>#0</value>
                                </enumeratedValue>
                                <enumeratedValue>
                                    <name>1</name>
                                    <description>Mask IWDT reset/interrupt and stop IWDT counter</description>
                                    <value>#1</value>
                                </enumeratedValue>
                            </enumeratedValues>
                        </field>
                        <field>
                            <name>DBGSTOP_WDT0</name>
                            <description>Mask bit for WDT reset/interrupt in the OCD run mode</description>
                            <lsb>1</lsb>
                            <msb>1</msb>
                            <access>read-write</access>
                            <enumeratedValues>
                                <enumeratedValue>
                                    <name>0</name>
                                    <description>Enable WDT reset/interrupt</description>
                                    <value>#0</value>
                                </enumeratedValue>
                                <enumeratedValue>
                                    <name>1</name>
                                    <description>Mask WDT reset/interrupt and stop WDT counter</description>
                                    <value>#1</value>
                                </enumeratedValue>
                            </enumeratedValues>
                        </field>
                        <field>
                            <name>DBGSTOP_PVD</name>
                            <description>Mask bit for PVDn (n = 1, 2) reset/interrupt</description>
                            <lsb>17</lsb>
                            <msb>17</msb>
                            <access>read-write</access>
                            <enumeratedValues>
                                <enumeratedValue>
                                    <name>0</name>
                                    <description>Enable PVDn (n = 1, 2) reset/interrupt</description>
                                    <value>#0</value>
                                </enumeratedValue>
                                <enumeratedValue>
                                    <name>1</name>
                                    <description>Mask PVDn (n = 1, 2) reset/interrupt</description>
                                    <value>#1</value>
                                </enumeratedValue>
                            </enumeratedValues>
                        </field>
                        <field>
                            <name>DBGSTOP_RER</name>
                            <lsb>24</lsb>
                            <msb>24</msb>
                            <access>read-write</access>
                            <enumeratedValues>
                                <enumeratedValue>
                                    <name>0</name>
                                    <description>Enable SRAM parity error reset/interrupt</description>
                                    <value>#0</value>
                                </enumeratedValue>
                                <enumeratedValue>
                                    <name>1</name>
                                    <description>Mask SRAM parity error reset/interrupt</description>
                                    <value>#1</value>
                                </enumeratedValue>
                            </enumeratedValues>
                        </field>
                    </fields>
                </register>
                <register>
                    <name>DBGAUTH0</name>
                    <description>Debug Authentication Control Register 0</description>
                    <addressOffset>0x020</addressOffset>
                    <size>32</size>
                    <access>read-write</access>
                    <resetValue>0x00010000</resetValue>
                    <resetMask>0x7fffffff</resetMask>
                    <fields>
                        <field>
                            <name>DBGEN0</name>
                            <description>CPU invasive debug enable</description>
                            <lsb>0</lsb>
                            <msb>0</msb>
                            <access>read-write</access>
                            <enumeratedValues>
                                <enumeratedValue>
                                    <name>0</name>
                                    <description>Disabled</description>
                                    <value>#0</value>
                                </enumeratedValue>
                                <enumeratedValue>
                                    <name>1</name>
                                    <description>Enabled</description>
                                    <value>#1</value>
                                </enumeratedValue>
                            </enumeratedValues>
                        </field>
                        <field>
                            <name>NIDEN0</name>
                            <description>CPU non-invasive debug enable</description>
                            <lsb>4</lsb>
                            <msb>4</msb>
                            <access>read-write</access>
                            <enumeratedValues>
                                <enumeratedValue>
                                    <name>0</name>
                                    <description>Disabled</description>
                                    <value>#0</value>
                                </enumeratedValue>
                                <enumeratedValue>
                                    <name>1</name>
                                    <description>Enabled</description>
                                    <value>#1</value>
                                </enumeratedValue>
                            </enumeratedValues>
                        </field>
                        <field>
                            <name>DBGENAP</name>
                            <description>CPU AHB-AP (AP0) debug enable</description>
                            <lsb>8</lsb>
                            <msb>8</msb>
                            <access>read-write</access>
                            <enumeratedValues>
                                <enumeratedValue>
                                    <name>0</name>
                                    <description>Disabled</description>
                                    <value>#0</value>
                                </enumeratedValue>
                                <enumeratedValue>
                                    <name>1</name>
                                    <description>Enabled</description>
                                    <value>#1</value>
                                </enumeratedValue>
                            </enumeratedValues>
                        </field>
                        <field>
                            <name>DEVICEEN</name>
                            <description>APB-AP (AP1) authentication</description>
                            <lsb>16</lsb>
                            <msb>16</msb>
                            <access>read-write</access>
                            <enumeratedValues>
                                <enumeratedValue>
                                    <name>0</name>
                                    <description>Disabled</description>
                                    <value>#0</value>
                                </enumeratedValue>
                                <enumeratedValue>
                                    <name>1</name>
                                    <description>Enabled</description>
                                    <value>#1</value>
                                </enumeratedValue>
                            </enumeratedValues>
                        </field>
                        <field>
                            <name>SWDBG</name>
                            <description>Software control of debug function</description>
                            <lsb>31</lsb>
                            <msb>31</msb>
                            <access>read-write</access>
                            <enumeratedValues>
                                <enumeratedValue>
                                    <name>0</name>
                                    <description>Disabled</description>
                                    <value>#0</value>
                                </enumeratedValue>
                                <enumeratedValue>
                                    <name>1</name>
                                    <description>Enabled</description>
                                    <value>#1</value>
                                </enumeratedValue>
                            </enumeratedValues>
                        </field>
                    </fields>
                </register>
                <register>
                    <name>TRPORTCR</name>
                    <description>Trace Port Control Register</description>
                    <addressOffset>0x030</addressOffset>
                    <size>32</size>
                    <access>read-write</access>
                    <resetValue>0x00000004</resetValue>
                    <resetMask>0xffffffff</resetMask>
                    <fields>
                        <field>
                            <name>OE</name>
                            <description>Data Out Enable bit indicates whether Trace Clock, Trace Data, and SWO outputs are enabled.</description>
                            <lsb>0</lsb>
                            <msb>0</msb>
                            <access>read-write</access>
                            <enumeratedValues>
                                <enumeratedValue>
                                    <name>0</name>
                                    <description>Output disabled</description>
                                    <value>#0</value>
                                </enumeratedValue>
                                <enumeratedValue>
                                    <name>1</name>
                                    <description>Output enabled</description>
                                    <value>#1</value>
                                </enumeratedValue>
                            </enumeratedValues>
                        </field>
                        <field>
                            <name>DRV</name>
                            <description>Port Drive Capability Control indicates trace port buffer speed:</description>
                            <lsb>2</lsb>
                            <msb>3</msb>
                            <access>read-write</access>
                            <enumeratedValues>
                                <enumeratedValue>
                                    <name>00</name>
                                    <description>Low-drive</description>
                                    <value>#00</value>
                                </enumeratedValue>
                                <enumeratedValue>
                                    <name>01</name>
                                    <description>Middle-drive</description>
                                    <value>#01</value>
                                </enumeratedValue>
                                <enumeratedValue>
                                    <name>10</name>
                                    <description>High-speed high-drive</description>
                                    <value>#10</value>
                                </enumeratedValue>
                                <enumeratedValue>
                                    <name>11</name>
                                    <description>High-drive</description>
                                    <value>#11</value>
                                </enumeratedValue>
                            </enumeratedValues>
                        </field>
                    </fields>
                </register>
                <register>
                    <name>DBGMOCOEN</name>
                    <description>MOCO Enable Request Register for Debug</description>
                    <addressOffset>0x300</addressOffset>
                    <size>32</size>
                    <access>read-write</access>
                    <resetValue>0x00000000</resetValue>
                    <resetMask>0xffffffff</resetMask>
                    <fields>
                        <field>
                            <name>MOCOEN</name>
                            <description>MOCO enable request</description>
                            <lsb>0</lsb>
                            <msb>0</msb>
                            <access>read-write</access>
                            <enumeratedValues>
                                <enumeratedValue>
                                    <name>0</name>
                                    <description>No request MOCO enable</description>
                                    <value>#0</value>
                                </enumeratedValue>
                                <enumeratedValue>
                                    <name>1</name>
                                    <description>Request MOCO enable</description>
                                    <value>#1</value>
                                </enumeratedValue>
                            </enumeratedValues>
                        </field>
                    </fields>
                </register>
                <register>
                    <name>DBGFCLKSEL</name>
                    <description>Flash Sequencer Clock Select Register for Debug</description>
                    <addressOffset>0x310</addressOffset>
                    <size>32</size>
                    <access>read-write</access>
                    <resetValue>0x00000000</resetValue>
                    <resetMask>0xffffffff</resetMask>
                    <fields>
                        <field>
                            <name>FCLKSEL</name>
                            <description>Flash sequencer clock select</description>
                            <lsb>0</lsb>
                            <msb>0</msb>
                            <access>read-write</access>
                            <enumeratedValues>
                                <enumeratedValue>
                                    <name>0</name>
                                    <description>FCLK</description>
                                    <value>#0</value>
                                </enumeratedValue>
                                <enumeratedValue>
                                    <name>1</name>
                                    <description>MOCO</description>
                                    <value>#1</value>
                                </enumeratedValue>
                            </enumeratedValues>
                        </field>
                    </fields>
                </register>
            </registers>
        </peripheral>
        <peripheral>
            <name>FCACHE_NS</name>
            <description>Flash Cache</description>
            <baseAddress>0x5001C100</baseAddress>
            <addressBlock>
                <offset>0x00</offset>
                <size>2</size>
                <usage>registers</usage>
            </addressBlock>
            <addressBlock>
                <offset>0x04</offset>
                <size>2</size>
                <usage>registers</usage>
            </addressBlock>
            <addressBlock>
                <offset>0x1C</offset>
                <size>1</size>
                <usage>registers</usage>
            </addressBlock>
            <addressBlock>
                <offset>0x40</offset>
                <size>2</size>
                <usage>registers</usage>
            </addressBlock>
            <registers>
                <register>
                    <name>FCACHEE</name>
                    <description>Flash Cache Enable Register</description>
                    <addressOffset>0x000</addressOffset>
                    <size>16</size>
                    <access>read-write</access>
                    <resetValue>0x0000</resetValue>
                    <resetMask>0xffff</resetMask>
                    <fields>
                        <field>
                            <name>FCACHEEN</name>
                            <description>Flash Cache Enable</description>
                            <lsb>0</lsb>
                            <msb>0</msb>
                            <access>read-write</access>
                            <enumeratedValues>
                                <enumeratedValue>
                                    <name>0</name>
                                    <description>FCACHE is disabled</description>
                                    <value>#0</value>
                                </enumeratedValue>
                                <enumeratedValue>
                                    <name>1</name>
                                    <description>FCACHE is enabled</description>
                                    <value>#1</value>
                                </enumeratedValue>
                            </enumeratedValues>
                        </field>
                    </fields>
                </register>
                <register>
                    <name>FCACHEIV</name>
                    <description>Flash Cache Invalidate Register</description>
                    <addressOffset>0x004</addressOffset>
                    <size>16</size>
                    <access>read-write</access>
                    <resetValue>0x0000</resetValue>
                    <resetMask>0xffff</resetMask>
                    <fields>
                        <field>
                            <name>FCACHEIV</name>
                            <description>Flash Cache Invalidate</description>
                            <lsb>0</lsb>
                            <msb>0</msb>
                            <access>read-write</access>
                            <enumeratedValues>
                                <enumeratedValue>
                                    <name>0</name>
                                    <description>Read: Do not invalidate. Write: The setting is ignored. </description>
                                    <value>#0</value>
                                </enumeratedValue>
                                <enumeratedValue>
                                    <name>1</name>
                                    <description>Invalidate FCACHE is invalidated. </description>
                                    <value>#1</value>
                                </enumeratedValue>
                            </enumeratedValues>
                        </field>
                    </fields>
                </register>
                <register>
                    <name>FLWT</name>
                    <description>Flash Wait Cycle Register</description>
                    <addressOffset>0x01C</addressOffset>
                    <size>8</size>
                    <access>read-write</access>
                    <resetValue>0x00</resetValue>
                    <resetMask>0xff</resetMask>
                    <fields>
                        <field>
                            <name>FLWT</name>
                            <description>Flash Wait Cycle</description>
                            <lsb>0</lsb>
                            <msb>2</msb>
                            <access>read-write</access>
                        </field>
                    </fields>
                </register>
                <register>
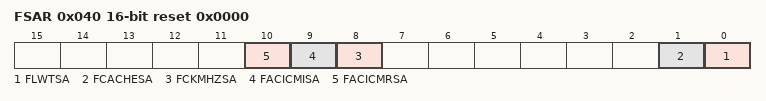
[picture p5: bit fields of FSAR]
                    <name>FSAR</name>
                    <description>Flash Security Attribution Register</description>
                    <addressOffset>0x040</addressOffset>
                    <size>16</size>
                    <access>read-write</access>
                    <resetValue>0x0000</resetValue>
                    <resetMask>0xffff</resetMask>
                    <fields>
                        <field>
                            <name>FLWTSA</name>
                            <description>FLWT Security Attribution</description>
                            <lsb>0</lsb>
                            <msb>0</msb>
                            <access>read-write</access>
                            <enumeratedValues>
                                <enumeratedValue>
                                    <name>0</name>
                                    <description>Secure</description>
                                    <value>#0</value>
                                </enumeratedValue>
                                <enumeratedValue>
                                    <name>1</name>
                                    <description>Non-secure</description>
                                    <value>#1</value>
                                </enumeratedValue>
                            </enumeratedValues>
                        </field>
                        <field>
                            <name>FCACHESA</name>
                            <description>FCHACHEEN Security Attribution</description>
                            <lsb>1</lsb>
                            <msb>1</msb>
                            <access>read-write</access>
                            <enumeratedValues>
                                <enumeratedValue>
                                    <name>0</name>
                                    <description>Secure</description>
                                    <value>#0</value>
                                </enumeratedValue>
                                <enumeratedValue>
                                    <name>1</name>
                                    <description>Non-secure</description>
                                    <value>#1</value>
                                </enumeratedValue>
                            </enumeratedValues>
                        </field>
                        <field>
                            <name>FCKMHZSA</name>
                            <description>FCKMHZ Security Attribution</description>
                            <lsb>8</lsb>
                            <msb>8</msb>
                            <access>read-write</access>
                            <enumeratedValues>
                                <enumeratedValue>
                                    <name>0</name>
                                    <description>Secure</description>
                                    <value>#0</value>
                                </enumeratedValue>
                                <enumeratedValue>
                                    <name>1</name>
                                    <description>Non-secure</description>
                                    <value>#1</value>
                                </enumeratedValue>
                            </enumeratedValues>
                        </field>
                        <field>
                            <name>FACICMISA</name>
                            <description>FACI command Issuing Security Attribution</description>
                            <lsb>9</lsb>
                            <msb>9</msb>
                            <access>read-write</access>
                            <enumeratedValues>
                                <enumeratedValue>
                                    <name>0</name>
                                    <description>Secure</description>
                                    <value>#0</value>
                                </enumeratedValue>
                                <enumeratedValue>
                                    <name>1</name>
                                    <description>Non-secure</description>
                                    <value>#1</value>
                                </enumeratedValue>
                            </enumeratedValues>
                        </field>
                        <field>
                            <name>FACICMRSA</name>
                            <description>FACI command Registers Security Attribution</description>
                            <lsb>10</lsb>
                            <msb>10</msb>
                            <access>read-write</access>
                            <enumeratedValues>
                                <enumeratedValue>
                                    <name>0</name>
                                    <description>Secure</description>
                                    <value>#0</value>
                                </enumeratedValue>
                                <enumeratedValue>
                                    <name>1</name>
                                    <description>Non-secure</description>
                                    <value>#1</value>
                                </enumeratedValue>
                            </enumeratedValues>
                        </field>
                    </fields>
                </register>
            </registers>
        </peripheral>
        <peripheral>
            <name>SYSC_NS</name>
            <description>System Control</description>
            <baseAddress>0x5001E000</baseAddress>
            <addressBlock>
                <offset>0x0C</offset>
                <size>1</size>
                <usage>registers</usage>
            </addressBlock>
            <addressBlock>
                <offset>0x20</offset>
                <size>5</size>
                <usage>registers</usage>
            </addressBlock>
            <addressBlock>
                <offset>0x26</offset>
                <size>1</size>
                <usage>registers</usage>
            </addressBlock>
            <addressBlock>
                <offset>0x28</offset>
                <size>3</size>
                <usage>registers</usage>
            </addressBlock>
            <addressBlock>
                <offset>0x30</offset>
                <size>1</size>
                <usage>registers</usage>
            </addressBlock>
            <addressBlock>
                <offset>0x32</offset>
                <size>1</size>
                <usage>registers</usage>
            </addressBlock>
            <addressBlock>
                <offset>0x36</offset>
                <size>7</size>
                <usage>registers</usage>
            </addressBlock>
            <addressBlock>
                <offset>0x3E</offset>
                <size>4</size>
                <usage>registers</usage>
            </addressBlock>
            <addressBlock>
                <offset>0x43</offset>
                <size>1</size>
                <usage>registers</usage>
            </addressBlock>
            <addressBlock>
                <offset>0x48</offset>
                <size>3</size>
                <usage>registers</usage>
            </addressBlock>
            <addressBlock>
                <offset>0x4C</offset>
                <size>4</size>
                <usage>registers</usage>
            </addressBlock>
            <addressBlock>
                <offset>0x52</offset>
                <size>6</size>
                <usage>registers</usage>
            </addressBlock>
            <addressBlock>
                <offset>0x5E</offset>
                <size>2</size>
                <usage>registers</usage>
            </addressBlock>
            <addressBlock>
                <offset>0x61</offset>
                <size>2</size>
                <usage>registers</usage>
            </addressBlock>
            <addressBlock>
                <offset>0x6C</offset>
                <size>3</size>
                <usage>registers</usage>
            </addressBlock>
            <addressBlock>
                <offset>0x74</offset>
                <size>3</size>
                <usage>registers</usage>
            </addressBlock>
            <addressBlock>
                <offset>0x7C</offset>
                <size>2</size>
                <usage>registers</usage>
            </addressBlock>
            <addressBlock>
                <offset>0xA0</offset>
                <size>1</size>
                <usage>registers</usage>
            </addressBlock>
            <addressBlock>
                <offset>0xA2</offset>
                <size>1</size>
                <usage>registers</usage>
            </addressBlock>
            <addressBlock>
                <offset>0xC0</offset>
                <size>4</size>
                <usage>registers</usage>
            </addressBlock>
            <addressBlock>
                <offset>0xCC</offset>
                <size>1</size>
                <usage>registers</usage>
            </addressBlock>
            <addressBlock>
                <offset>0xE0</offset>
                <size>5</size>
                <usage>registers</usage>
            </addressBlock>
            <addressBlock>
                <offset>0x110</offset>
                <size>1</size>
                <usage>registers</usage>
            </addressBlock>
            <addressBlock>
                <offset>0x140</offset>
                <size>3</size>
                <usage>registers</usage>
            </addressBlock>
            <addressBlock>
                <offset>0x3B8</offset>
                <size>2</size>
                <usage>registers</usage>
            </addressBlock>
            <addressBlock>
                <offset>0x3C0</offset>
                <size>20</size>
                <usage>registers</usage>
            </addressBlock>
            <addressBlock>
                <offset>0x3D8</offset>
                <size>4</size>
                <usage>registers</usage>
            </addressBlock>
            <addressBlock>
                <offset>0x3E0</offset>
                <size>8</size>
                <usage>registers</usage>
            </addressBlock>
            <addressBlock>
                <offset>0x3FE</offset>
                <size>3</size>
                <usage>registers</usage>
            </addressBlock>
            <addressBlock>
                <offset>0x402</offset>
                <size>1</size>
                <usage>registers</usage>
            </addressBlock>
            <addressBlock>
                <offset>0xA00</offset>
                <size>1</size>
                <usage>registers</usage>
            </addressBlock>
            <addressBlock>
                <offset>0xA04</offset>
                <size>1</size>
                <usage>registers</usage>
            </addressBlock>
            <addressBlock>
                <offset>0xA08</offset>
                <size>1</size>
                <usage>registers</usage>
            </addressBlock>
            <addressBlock>
                <offset>0xA0C</offset>
                <size>1</size>
                <usage>registers</usage>
            </addressBlock>
            <addressBlock>
                <offset>0xA10</offset>
                <size>1</size>
                <usage>registers</usage>
            </addressBlock>
            <addressBlock>
                <offset>0xA14</offset>
                <size>1</size>
                <usage>registers</usage>
            </addressBlock>
            <addressBlock>
                <offset>0xA18</offset>
                <size>1</size>
                <usage>registers</usage>
            </addressBlock>
            <addressBlock>
                <offset>0xA1C</offset>
                <size>1</size>
                <usage>registers</usage>
            </addressBlock>
            <addressBlock>
                <offset>0xA20</offset>
                <size>1</size>
                <usage>registers</usage>
            </addressBlock>
            <addressBlock>
                <offset>0xA24</offset>
                <size>1</size>
                <usage>registers</usage>
            </addressBlock>
            <addressBlock>
                <offset>0xA28</offset>
                <size>1</size>
                <usage>registers</usage>
            </addressBlock>
            <addressBlock>
                <offset>0xA2C</offset>
                <size>1</size>
                <usage>registers</usage>
            </addressBlock>
            <addressBlock>
                <offset>0xA30</offset>
                <size>1</size>
                <usage>registers</usage>
            </addressBlock>
            <addressBlock>
                <offset>0xA38</offset>
                <size>1</size>
                <usage>registers</usage>
            </addressBlock>
            <addressBlock>
                <offset>0xA40</offset>
                <size>1</size>
                <usage>registers</usage>
            </addressBlock>
            <addressBlock>
                <offset>0xA44</offset>
                <size>1</size>
                <usage>registers</usage>
            </addressBlock>
            <addressBlock>
                <offset>0xA50</offset>
                <size>1</size>
                <usage>registers</usage>
            </addressBlock>
            <addressBlock>
                <offset>0xA54</offset>
                <size>1</size>
                <usage>registers</usage>
            </addressBlock>
            <addressBlock>
                <offset>0xA58</offset>
                <size>8</size>
                <usage>registers</usage>
            </addressBlock>
            <addressBlock>
                <offset>0xA70</offset>
                <size>8</size>
                <usage>registers</usage>
            </addressBlock>
            <addressBlock>
                <offset>0xA84</offset>
                <size>1</size>
                <usage>registers</usage>
            </addressBlock>
            <addressBlock>
                <offset>0xA88</offset>
                <size>1</size>
                <usage>registers</usage>
            </addressBlock>
            <addressBlock>
                <offset>0xA90</offset>
                <size>1</size>
                <usage>registers</usage>
            </addressBlock>
            <addressBlock>
                <offset>0xA98</offset>
                <size>1</size>
                <usage>registers</usage>
            </addressBlock>
            <addressBlock>
                <offset>0xAB0</offset>
                <size>1</size>
                <usage>registers</usage>
            </addressBlock>
            <addressBlock>
                <offset>0xB04</offset>
                <size>1</size>
                <usage>registers</usage>
            </addressBlock>
            <addressBlock>
                <offset>0xB08</offset>
                <size>1</size>
                <usage>registers</usage>
            </addressBlock>
            <addressBlock>
                <offset>0xB0C</offset>
                <size>1</size>
                <usage>registers</usage>
            </addressBlock>
            <addressBlock>
                <offset>0xB20</offset>
                <size>8</size>
                <usage>registers</usage>
            </addressBlock>
            <addressBlock>
                <offset>0xC00</offset>
                <size>2</size>
                <usage>registers</usage>
            </addressBlock>
            <addressBlock>
                <offset>0xC40</offset>
                <size>1</size>
                <usage>registers</usage>
            </addressBlock>
            <addressBlock>
                <offset>0xC45</offset>
                <size>2</size>
                <usage>registers</usage>
            </addressBlock>
            <addressBlock>
                <offset>0xC48</offset>
                <size>3</size>
                <usage>registers</usage>
            </addressBlock>
            <addressBlock>
                <offset>0xC4C</offset>
                <size>3</size>
                <usage>registers</usage>
            </addressBlock>
            <addressBlock>
                <offset>0xD00</offset>
                <size>128</size>
                <usage>registers</usage>
            </addressBlock>
            <registers>
                <register>
                    <name>SBYCR</name>
                    <description>Standby Control Register</description>
                    <addressOffset>0x00C</addressOffset>
                    <size>8</size>
                    <access>read-write</access>
                    <resetValue>0x40</resetValue>
                    <resetMask>0xff</resetMask>
                    <fields>
                        <field>
                            <name>OPE</name>
                            <description>Output Port Enable</description>
                            <lsb>6</lsb>
                            <msb>6</msb>
                            <access>read-write</access>
                            <enumeratedValues>
                                <enumeratedValue>
                                    <name>0</name>
                                    <description>In Software Standby mode or Deep Software Standby mode, set the address bus and other bus control signal to the high-impedance state. </description>
                                    <value>#0</value>
                                </enumeratedValue>
                                <enumeratedValue>
                                    <name>1</name>
                                    <description>In Software Standby mode or Deep Software Standby mode, address bus and other bus control signal retain the output state. </description>
                                    <value>#1</value>
                                </enumeratedValue>
                            </enumeratedValues>
                        </field>
                    </fields>
                </register>
                <register>
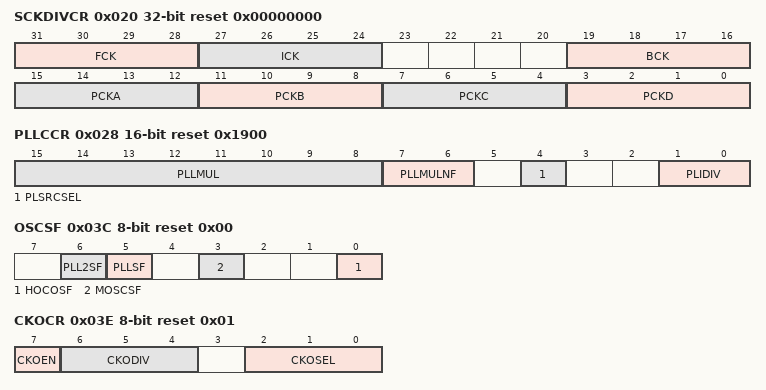
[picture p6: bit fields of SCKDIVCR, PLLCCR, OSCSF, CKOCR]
                    <name>SCKDIVCR</name>
                    <description>System Clock Division Control Register</description>
                    <addressOffset>0x020</addressOffset>
                    <size>32</size>
                    <access>read-write</access>
                    <resetValue>0x00000000</resetValue>
                    <resetMask>0xffffffff</resetMask>
                    <fields>
                        <field>
                            <name>PCKD</name>
                            <description>Peripheral Module Clock D (PCLKD) Select</description>
                            <lsb>0</lsb>
                            <msb>3</msb>
                            <access>read-write</access>
                            <enumeratedValues>
                                <enumeratedValue>
                                    <name>0000</name>
                                    <description>x 1/1</description>
                                    <value>#0000</value>
                                </enumeratedValue>
                                <enumeratedValue>
                                    <name>0001</name>
                                    <description>x 1/2</description>
                                    <value>#0001</value>
                                </enumeratedValue>
                                <enumeratedValue>
                                    <name>0010</name>
                                    <description>x 1/4</description>
                                    <value>#0010</value>
                                </enumeratedValue>
                                <enumeratedValue>
                                    <name>0011</name>
                                    <description>x 1/8</description>
                                    <value>#0011</value>
                                </enumeratedValue>
                                <enumeratedValue>
                                    <name>0100</name>
                                    <description>x 1/16</description>
                                    <value>#0100</value>
                                </enumeratedValue>
                                <enumeratedValue>
                                    <name>0101</name>
                                    <description>x 1/32</description>
                                    <value>#0101</value>
                                </enumeratedValue>
                                <enumeratedValue>
                                    <name>0110</name>
                                    <description>x 1/64</description>
                                    <value>#0110</value>
                                </enumeratedValue>
                                <enumeratedValue>
                                    <name>1000</name>
                                    <description>x 1/3</description>
                                    <value>#1000</value>
                                </enumeratedValue>
                                <enumeratedValue>
                                    <name>1001</name>
                                    <description>x 1/6</description>
                                    <value>#1001</value>
                                </enumeratedValue>
                                <enumeratedValue>
                                    <name>1010</name>
                                    <description>x 1/12</description>
                                    <value>#1010</value>
                                </enumeratedValue>
                                <enumeratedValue>
                                    <name>Others</name>
                                    <description>Setting prohibited.</description>
                                    <isDefault>true</isDefault>
                                </enumeratedValue>
                            </enumeratedValues>
                        </field>
                        <field>
                            <name>PCKC</name>
                            <description>Peripheral Module Clock C (PCLKC) Select</description>
                            <lsb>4</lsb>
                            <msb>7</msb>
                            <access>read-write</access>
                            <enumeratedValues>
                                <enumeratedValue>
                                    <name>0000</name>
                                    <description>x 1/1</description>
                                    <value>#0000</value>
                                </enumeratedValue>
                                <enumeratedValue>
                                    <name>0001</name>
                                    <description>x 1/2</description>
                                    <value>#0001</value>
                                </enumeratedValue>
                                <enumeratedValue>
                                    <name>0010</name>
                                    <description>x 1/4</description>
                                    <value>#0010</value>
                                </enumeratedValue>
                                <enumeratedValue>
                                    <name>0011</name>
                                    <description>x 1/8</description>
                                    <value>#0011</value>
                                </enumeratedValue>
                                <enumeratedValue>
                                    <name>0100</name>
                                    <description>x 1/16</description>
                                    <value>#0100</value>
                                </enumeratedValue>
                                <enumeratedValue>
                                    <name>0101</name>
                                    <description>x 1/32</description>
                                    <value>#0101</value>
                                </enumeratedValue>
                                <enumeratedValue>
                                    <name>0110</name>
                                    <description>x 1/64</description>
                                    <value>#0110</value>
                                </enumeratedValue>
                                <enumeratedValue>
                                    <name>1000</name>
                                    <description>x 1/3</description>
                                    <value>#1000</value>
                                </enumeratedValue>
                                <enumeratedValue>
                                    <name>1001</name>
                                    <description>x 1/6</description>
                                    <value>#1001</value>
                                </enumeratedValue>
                                <enumeratedValue>
                                    <name>1010</name>
                                    <description>x 1/12</description>
                                    <value>#1010</value>
                                </enumeratedValue>
                                <enumeratedValue>
                                    <name>Others</name>
                                    <description>Setting prohibited.</description>
                                    <isDefault>true</isDefault>
                                </enumeratedValue>
                            </enumeratedValues>
                        </field>
                        <field>
                            <name>PCKB</name>
                            <description>Peripheral Module Clock B (PCLKB) Select</description>
                            <lsb>8</lsb>
                            <msb>11</msb>
                            <access>read-write</access>
                            <enumeratedValues>
                                <enumeratedValue>
                                    <name>0000</name>
                                    <description>x 1/1</description>
                                    <value>#0000</value>
                                </enumeratedValue>
                                <enumeratedValue>
                                    <name>0001</name>
                                    <description>x 1/2</description>
                                    <value>#0001</value>
                                </enumeratedValue>
                                <enumeratedValue>
                                    <name>0010</name>
                                    <description>x 1/4</description>
                                    <value>#0010</value>
                                </enumeratedValue>
                                <enumeratedValue>
                                    <name>0011</name>
                                    <description>x 1/8</description>
                                    <value>#0011</value>
                                </enumeratedValue>
                                <enumeratedValue>
                                    <name>0100</name>
                                    <description>x 1/16</description>
                                    <value>#0100</value>
                                </enumeratedValue>
                                <enumeratedValue>
                                    <name>0101</name>
                                    <description>x 1/32</description>
                                    <value>#0101</value>
                                </enumeratedValue>
                                <enumeratedValue>
                                    <name>0110</name>
                                    <description>x 1/64</description>
                                    <value>#0110</value>
                                </enumeratedValue>
                                <enumeratedValue>
                                    <name>1000</name>
                                    <description>x 1/3</description>
                                    <value>#1000</value>
                                </enumeratedValue>
                                <enumeratedValue>
                                    <name>1001</name>
                                    <description>x 1/6</description>
                                    <value>#1001</value>
                                </enumeratedValue>
                                <enumeratedValue>
                                    <name>1010</name>
                                    <description>x 1/12</description>
                                    <value>#1010</value>
                                </enumeratedValue>
                                <enumeratedValue>
                                    <name>Others</name>
                                    <description>Setting prohibited.</description>
                                    <isDefault>true</isDefault>
                                </enumeratedValue>
                            </enumeratedValues>
                        </field>
                        <field>
                            <name>PCKA</name>
                            <description>Peripheral Module Clock A (PCLKA) Select</description>
                            <lsb>12</lsb>
                            <msb>15</msb>
                            <access>read-write</access>
                            <enumeratedValues>
                                <enumeratedValue>
                                    <name>0000</name>
                                    <description>x 1/1</description>
                                    <value>#0000</value>
                                </enumeratedValue>
                                <enumeratedValue>
                                    <name>0001</name>
                                    <description>x 1/2</description>
                                    <value>#0001</value>
                                </enumeratedValue>
                                <enumeratedValue>
                                    <name>0010</name>
                                    <description>x 1/4</description>
                                    <value>#0010</value>
                                </enumeratedValue>
                                <enumeratedValue>
                                    <name>0011</name>
                                    <description>x 1/8</description>
                                    <value>#0011</value>
                                </enumeratedValue>
                                <enumeratedValue>
                                    <name>0100</name>
                                    <description>x 1/16</description>
                                    <value>#0100</value>
                                </enumeratedValue>
                                <enumeratedValue>
                                    <name>0101</name>
                                    <description>x 1/32</description>
                                    <value>#0101</value>
                                </enumeratedValue>
                                <enumeratedValue>
                                    <name>0110</name>
                                    <description>x 1/64</description>
                                    <value>#0110</value>
                                </enumeratedValue>
                                <enumeratedValue>
                                    <name>1000</name>
                                    <description>x 1/3</description>
                                    <value>#1000</value>
                                </enumeratedValue>
                                <enumeratedValue>
                                    <name>1001</name>
                                    <description>x 1/6</description>
                                    <value>#1001</value>
                                </enumeratedValue>
                                <enumeratedValue>
                                    <name>1010</name>
                                    <description>x 1/12</description>
                                    <value>#1010</value>
                                </enumeratedValue>
                                <enumeratedValue>
                                    <name>Others</name>
                                    <description>Setting prohibited.</description>
                                    <isDefault>true</isDefault>
                                </enumeratedValue>
                            </enumeratedValues>
                        </field>
                        <field>
                            <name>BCK</name>
                            <description>External Bus Clock (BCLK) Select</description>
                            <lsb>16</lsb>
                            <msb>19</msb>
                            <access>read-write</access>
                            <enumeratedValues>
                                <enumeratedValue>
                                    <name>0000</name>
                                    <description>x 1/1</description>
                                    <value>#0000</value>
                                </enumeratedValue>
                                <enumeratedValue>
                                    <name>0001</name>
                                    <description>x 1/2</description>
                                    <value>#0001</value>
                                </enumeratedValue>
                                <enumeratedValue>
                                    <name>0010</name>
                                    <description>x 1/4</description>
                                    <value>#0010</value>
                                </enumeratedValue>
                                <enumeratedValue>
                                    <name>0011</name>
                                    <description>x 1/8</description>
                                    <value>#0011</value>
                                </enumeratedValue>
                                <enumeratedValue>
                                    <name>0100</name>
                                    <description>x 1/16</description>
                                    <value>#0100</value>
                                </enumeratedValue>
                                <enumeratedValue>
                                    <name>0101</name>
                                    <description>x 1/32</description>
                                    <value>#0101</value>
                                </enumeratedValue>
                                <enumeratedValue>
                                    <name>0110</name>
                                    <description>x 1/64</description>
                                    <value>#0110</value>
                                </enumeratedValue>
                                <enumeratedValue>
                                    <name>1000</name>
                                    <description>x 1/3</description>
                                    <value>#1000</value>
                                </enumeratedValue>
                                <enumeratedValue>
                                    <name>1001</name>
                                    <description>x 1/6</description>
                                    <value>#1001</value>
                                </enumeratedValue>
                                <enumeratedValue>
                                    <name>1010</name>
                                    <description>x 1/12</description>
                                    <value>#1010</value>
                                </enumeratedValue>
                                <enumeratedValue>
                                    <name>Others</name>
                                    <description>Settings prohibited</description>
                                    <isDefault>true</isDefault>
                                </enumeratedValue>
                            </enumeratedValues>
                        </field>
                        <field>
                            <name>ICK</name>
                            <description>System Clock (ICLK) Select</description>
                            <lsb>24</lsb>
                            <msb>27</msb>
                            <access>read-write</access>
                            <enumeratedValues>
                                <enumeratedValue>
                                    <name>0000</name>
                                    <description>x 1/1</description>
                                    <value>#0000</value>
                                </enumeratedValue>
                                <enumeratedValue>
                                    <name>0001</name>
                                    <description>x 1/2</description>
                                    <value>#0001</value>
                                </enumeratedValue>
                                <enumeratedValue>
                                    <name>0010</name>
                                    <description>x 1/4</description>
                                    <value>#0010</value>
                                </enumeratedValue>
                                <enumeratedValue>
                                    <name>0011</name>
                                    <description>x 1/8</description>
                                    <value>#0011</value>
                                </enumeratedValue>
                                <enumeratedValue>
                                    <name>0100</name>
                                    <description>x 1/16</description>
                                    <value>#0100</value>
                                </enumeratedValue>
                                <enumeratedValue>
                                    <name>0101</name>
                                    <description>x 1/32</description>
                                    <value>#0101</value>
                                </enumeratedValue>
                                <enumeratedValue>
                                    <name>0110</name>
                                    <description>x 1/64</description>
                                    <value>#0110</value>
                                </enumeratedValue>
                                <enumeratedValue>
                                    <name>1000</name>
                                    <description>x 1/3</description>
                                    <value>#1000</value>
                                </enumeratedValue>
                                <enumeratedValue>
                                    <name>1001</name>
                                    <description>x 1/6</description>
                                    <value>#1001</value>
                                </enumeratedValue>
                                <enumeratedValue>
                                    <name>1010</name>
                                    <description>x 1/12</description>
                                    <value>#1010</value>
                                </enumeratedValue>
                                <enumeratedValue>
                                    <name>Others</name>
                                    <description>Setting prohibited.</description>
                                    <isDefault>true</isDefault>
                                </enumeratedValue>
                            </enumeratedValues>
                        </field>
                        <field>
                            <name>FCK</name>
                            <description>FlashIF Clock (FCLK) Select</description>
                            <lsb>28</lsb>
                            <msb>31</msb>
                            <access>read-write</access>
                            <enumeratedValues>
                                <enumeratedValue>
                                    <name>0000</name>
                                    <description>x 1/1</description>
                                    <value>#0000</value>
                                </enumeratedValue>
                                <enumeratedValue>
                                    <name>0001</name>
                                    <description>x 1/2</description>
                                    <value>#0001</value>
                                </enumeratedValue>
                                <enumeratedValue>
                                    <name>0010</name>
                                    <description>x 1/4</description>
                                    <value>#0010</value>
                                </enumeratedValue>
                                <enumeratedValue>
                                    <name>0011</name>
                                    <description>x 1/8</description>
                                    <value>#0011</value>
                                </enumeratedValue>
                                <enumeratedValue>
                                    <name>0100</name>
                                    <description>x 1/16</description>
                                    <value>#0100</value>
                                </enumeratedValue>
                                <enumeratedValue>
                                    <name>0101</name>
                                    <description>x 1/32</description>
                                    <value>#0101</value>
                                </enumeratedValue>
                                <enumeratedValue>
                                    <name>0110</name>
                                    <description>x 1/64</description>
                                    <value>#0110</value>
                                </enumeratedValue>
                                <enumeratedValue>
                                    <name>1000</name>
                                    <description>x 1/3</description>
                                    <value>#1000</value>
                                </enumeratedValue>
                                <enumeratedValue>
                                    <name>1001</name>
                                    <description>x 1/6</description>
                                    <value>#1001</value>
                                </enumeratedValue>
                                <enumeratedValue>
                                    <name>1010</name>
                                    <description>x 1/12</description>
                                    <value>#1010</value>
                                </enumeratedValue>
                                <enumeratedValue>
                                    <name>Others</name>
                                    <description>Setting prohibited.</description>
                                    <isDefault>true</isDefault>
                                </enumeratedValue>
                            </enumeratedValues>
                        </field>
                    </fields>
                </register>
                <register>
                    <name>SCKDIVCR2</name>
                    <description>System Clock Division Control Register 2</description>
                    <addressOffset>0x24</addressOffset>
                    <size>8</size>
                    <access>read-write</access>
                    <resetValue>0x00</resetValue>
                    <resetMask>0xff</resetMask>
                    <fields>
                        <field>
                            <name>CPUCK</name>
                            <description>CPU Clock (CPUCLK) Select</description>
                            <lsb>0</lsb>
                            <msb>3</msb>
                            <access>read-write</access>
                            <enumeratedValues>
                                <enumeratedValue>
                                    <name>0000</name>
                                    <description>x 1/1</description>
                                    <value>#0000</value>
                                </enumeratedValue>
                                <enumeratedValue>
                                    <name>0001</name>
                                    <description>x 1/2</description>
                                    <value>#0001</value>
                                </enumeratedValue>
                                <enumeratedValue>
                                    <name>0010</name>
                                    <description>x 1/4</description>
                                    <value>#0010</value>
                                </enumeratedValue>
                                <enumeratedValue>
                                    <name>0011</name>
                                    <description>x 1/8</description>
                                    <value>#0011</value>
                                </enumeratedValue>
                                <enumeratedValue>
                                    <name>0100</name>
                                    <description>x 1/16</description>
                                    <value>#0100</value>
                                </enumeratedValue>
                                <enumeratedValue>
                                    <name>0101</name>
                                    <description>x 1/32</description>
                                    <value>#0101</value>
                                </enumeratedValue>
                                <enumeratedValue>
                                    <name>0110</name>
                                    <description>x 1/64</description>
                                    <value>#0110</value>
                                </enumeratedValue>
                                <enumeratedValue>
                                    <name>1000</name>
                                    <description>x 1/3</description>
                                    <value>#1000</value>
                                </enumeratedValue>
                                <enumeratedValue>
                                    <name>1001</name>
                                    <description>x 1/6</description>
                                    <value>#1001</value>
                                </enumeratedValue>
                                <enumeratedValue>
                                    <name>1010</name>
                                    <description>x 1/12</description>
                                    <value>#1010</value>
                                </enumeratedValue>
                                <enumeratedValue>
                                    <name>Others</name>
                                    <description>Setting prohibited.</description>
                                    <isDefault>true</isDefault>
                                </enumeratedValue>
                            </enumeratedValues>
                        </field>
                    </fields>
                </register>
                <register>
                    <name>SCKSCR</name>
                    <description>System Clock Source Control Register</description>
                    <addressOffset>0x026</addressOffset>
                    <size>8</size>
                    <access>read-write</access>
                    <resetValue>0x01</resetValue>
                    <resetMask>0xff</resetMask>
                    <fields>
                        <field>
                            <name>CKSEL</name>
                            <description>Clock Source Select</description>
                            <lsb>0</lsb>
                            <msb>2</msb>
                            <access>read-write</access>
                            <enumeratedValues>
                                <enumeratedValue>
                                    <name>000</name>
                                    <description>HOCO</description>
                                    <value>#000</value>
                                </enumeratedValue>
                                <enumeratedValue>
                                    <name>001</name>
                                    <description>MOCO (Value after reset)</description>
                                    <value>#001</value>
                                </enumeratedValue>
                                <enumeratedValue>
                                    <name>010</name>
                                    <description>Setting prohibited</description>
                                    <value>#010</value>
                                </enumeratedValue>
                                <enumeratedValue>
                                    <name>011</name>
                                    <description>Main clock oscillator (MOSC)</description>
                                    <value>#011</value>
                                </enumeratedValue>
                                <enumeratedValue>
                                    <name>100</name>
                                    <description>Sub-clock oscillator (SOSC)</description>
                                    <value>#100</value>
                                </enumeratedValue>
                                <enumeratedValue>
                                    <name>101</name>
                                    <description>PLL1 output clock P (PLL1P)</description>
                                    <value>#101</value>
                                </enumeratedValue>
                                <enumeratedValue>
                                    <name>110</name>
                                    <description>Setting prohibited</description>
                                    <value>#110</value>
                                </enumeratedValue>
                                <enumeratedValue>
                                    <name>111</name>
                                    <description>Setting prohibited</description>
                                    <value>#111</value>
                                </enumeratedValue>
                            </enumeratedValues>
                        </field>
                    </fields>
                </register>
                <register>
                    <name>PLLCCR</name>
                    <description>PLL Clock Control Register</description>
                    <addressOffset>0x028</addressOffset>
                    <size>16</size>
                    <access>read-write</access>
                    <resetValue>0x1900</resetValue>
                    <resetMask>0xffff</resetMask>
                    <fields>
                        <field>
                            <name>PLIDIV</name>
                            <description>PLL1 Input Frequency Division Ratio Select</description>
                            <lsb>0</lsb>
                            <msb>1</msb>
                            <access>read-write</access>
                            <enumeratedValues>
                                <enumeratedValue>
                                    <name>00</name>
                                    <description>1/1</description>
                                    <value>#00</value>
                                </enumeratedValue>
                                <enumeratedValue>
                                    <name>01</name>
                                    <description>1/2</description>
                                    <value>#01</value>
                                </enumeratedValue>
                                <enumeratedValue>
                                    <name>10</name>
                                    <description>1/3</description>
                                    <value>#10</value>
                                </enumeratedValue>
                                <enumeratedValue>
                                    <name>11</name>
                                    <description>1/4</description>
                                    <value>#11</value>
                                </enumeratedValue>
                            </enumeratedValues>
                        </field>
                        <field>
                            <name>PLSRCSEL</name>
                            <description>PLL1 Clock Source Select</description>
                            <lsb>4</lsb>
                            <msb>4</msb>
                            <access>read-write</access>
                            <enumeratedValues>
                                <enumeratedValue>
                                    <name>0</name>
                                    <description>Main clock oscillator</description>
                                    <value>#0</value>
                                </enumeratedValue>
                                <enumeratedValue>
                                    <name>1</name>
                                    <description>HOCO</description>
                                    <value>#1</value>
                                </enumeratedValue>
                            </enumeratedValues>
                        </field>
                        <field>
                            <name>PLLMULNF</name>
                            <description>PLL1 Frequency Multiplication Fractional Factor Select</description>
                            <lsb>6</lsb>
                            <msb>7</msb>
                            <access>read-write</access>
                            <enumeratedValues>
                                <enumeratedValue>
                                    <name>00</name>
                                    <description>0.00 (Value after reset)</description>
                                    <value>#00</value>
                                </enumeratedValue>
                                <enumeratedValue>
                                    <name>01</name>
                                    <description>0.33 (1/3)</description>
                                    <value>#01</value>
                                </enumeratedValue>
                                <enumeratedValue>
                                    <name>10</name>
                                    <description>0.66 (2/3)</description>
                                    <value>#10</value>
                                </enumeratedValue>
                                <enumeratedValue>
                                    <name>11</name>
                                    <description>0.50 (1/2)</description>
                                    <value>#11</value>
                                </enumeratedValue>
                            </enumeratedValues>
                        </field>
                        <field>
                            <name>PLLMUL</name>
                            <description>PLL1 Frequency Multiplication Factor Select</description>
                            <lsb>8</lsb>
                            <msb>15</msb>
                            <access>read-write</access>
                            <writeConstraint>
                                <range>
                                    <minimum>0x13</minimum>
                                    <maximum>0x3B</maximum>
                                </range>
                            </writeConstraint>
                        </field>
                    </fields>
                </register>
                <register>
                    <name>PLLCR</name>
                    <description>PLL Control Register</description>
                    <addressOffset>0x02A</addressOffset>
                    <size>8</size>
                    <access>read-write</access>
                    <resetValue>0x01</resetValue>
                    <resetMask>0xff</resetMask>
                    <fields>
                        <field>
                            <name>PLLSTP</name>
                            <description>PLL1 Stop Control</description>
                            <lsb>0</lsb>
                            <msb>0</msb>
                            <access>read-write</access>
                            <enumeratedValues>
                                <enumeratedValue>
                                    <name>0</name>
                                    <description>PLL1 is operating</description>
                                    <value>#0</value>
                                </enumeratedValue>
                                <enumeratedValue>
                                    <name>1</name>
                                    <description>PLL1 is stopped</description>
                                    <value>#1</value>
                                </enumeratedValue>
                            </enumeratedValues>
                        </field>
                    </fields>
                </register>
                <register>
                    <name>BCKCR</name>
                    <description>External Bus Clock Control Register</description>
                    <addressOffset>0x030</addressOffset>
                    <size>8</size>
                    <access>read-write</access>
                    <resetValue>0x00</resetValue>
                    <resetMask>0xff</resetMask>
                    <fields>
                        <field>
                            <name>BCLKDIV</name>
                            <description>BCLK Pin Output Select</description>
                            <lsb>0</lsb>
                            <msb>0</msb>
                            <access>read-write</access>
                            <enumeratedValues>
                                <enumeratedValue>
                                    <name>0</name>
                                    <description>BCLK</description>
                                    <value>#0</value>
                                </enumeratedValue>
                                <enumeratedValue>
                                    <name>1</name>
                                    <description>BCLK/2</description>
                                    <value>#1</value>
                                </enumeratedValue>
                            </enumeratedValues>
                        </field>
                    </fields>
                </register>
                <register>
                    <name>MOSCCR</name>
                    <description>Main Clock Oscillator Control Register</description>
                    <addressOffset>0x032</addressOffset>
                    <size>8</size>
                    <access>read-write</access>
                    <resetValue>0x01</resetValue>
                    <resetMask>0xff</resetMask>
                    <fields>
                        <field>
                            <name>MOSTP</name>
                            <description>Main Clock Oscillator Stop</description>
                            <lsb>0</lsb>
                            <msb>0</msb>
                            <access>read-write</access>
                            <enumeratedValues>
                                <enumeratedValue>
                                    <name>0</name>
                                    <description>Operate the main clock oscillator</description>
                                    <value>#0</value>
                                </enumeratedValue>
                                <enumeratedValue>
                                    <name>1</name>
                                    <description>Stop the main clock oscillator</description>
                                    <value>#1</value>
                                </enumeratedValue>
                            </enumeratedValues>
                        </field>
                    </fields>
                </register>
                <register>
                    <name>HOCOCR</name>
                    <description>High-Speed On-Chip Oscillator Control Register</description>
                    <addressOffset>0x036</addressOffset>
                    <size>8</size>
                    <access>read-write</access>
                    <resetValue>0x00</resetValue>
                    <resetMask>0xfe</resetMask>
                    <fields>
                        <field>
                            <name>HCSTP</name>
                            <description>HOCO Stop</description>
                            <lsb>0</lsb>
                            <msb>0</msb>
                            <access>read-write</access>
                            <enumeratedValues>
                                <enumeratedValue>
                                    <name>0</name>
                                    <description>Operate the HOCO clock </description>
                                    <value>#0</value>
                                </enumeratedValue>
                                <enumeratedValue>
                                    <name>1</name>
                                    <description>Stop the HOCO clock</description>
                                    <value>#1</value>
                                </enumeratedValue>
                            </enumeratedValues>
                        </field>
                    </fields>
                </register>
                <register>
                    <name>HOCOCR2</name>
                    <description>High-Speed On-Chip Oscillator Control Register2</description>
                    <addressOffset>0x037</addressOffset>
                    <size>8</size>
                    <access>read-write</access>
                    <resetValue>0x00</resetValue>
                    <resetMask>0xf8</resetMask>
                    <fields>
                        <field>
                            <name>HCFRQ0</name>
                            <description>HOCO Frequency Setting 0</description>
                            <lsb>0</lsb>
                            <msb>2</msb>
                            <access>read-write</access>
                            <enumeratedValues>
                                <enumeratedValue>
                                    <name>000</name>
                                    <description>16MHz</description>
                                    <value>#000</value>
                                </enumeratedValue>
                                <enumeratedValue>
                                    <name>001</name>
                                    <description>18MHz</description>
                                    <value>#001</value>
                                </enumeratedValue>
                                <enumeratedValue>
                                    <name>010</name>
                                    <description>20MHz</description>
                                    <value>#010</value>
                                </enumeratedValue>
                                <enumeratedValue>
                                    <name>100</name>
                                    <description>32MHz</description>
                                    <value>#100</value>
                                </enumeratedValue>
                                <enumeratedValue>
                                    <name>111</name>
                                    <description>48MHz</description>
                                    <value>#111</value>
                                </enumeratedValue>
                            </enumeratedValues>
                        </field>
                    </fields>
                </register>
                <register>
                    <name>MOCOCR</name>
                    <description>Middle-Speed On-Chip Oscillator Control Register</description>
                    <addressOffset>0x038</addressOffset>
                    <size>8</size>
                    <access>read-write</access>
                    <resetValue>0x00</resetValue>
                    <resetMask>0xff</resetMask>
                    <fields>
                        <field>
                            <name>MCSTP</name>
                            <description>MOCO Stop</description>
                            <lsb>0</lsb>
                            <msb>0</msb>
                            <access>read-write</access>
                            <enumeratedValues>
                                <enumeratedValue>
                                    <name>0</name>
                                    <description>MOCO clock is operating</description>
                                    <value>#0</value>
                                </enumeratedValue>
                                <enumeratedValue>
                                    <name>1</name>
                                    <description>MOCO clock is stopped</description>
                                    <value>#1</value>
                                </enumeratedValue>
                            </enumeratedValues>
                        </field>
                    </fields>
                </register>
                <register>
                    <name>FLLCR1</name>
                    <description>FLL Control Register1</description>
                    <addressOffset>0x039</addressOffset>
                    <size>8</size>
                    <access>read-write</access>
                    <resetValue>0x00</resetValue>
                    <resetMask>0xff</resetMask>
                    <fields>
                        <field>
                            <name>FLLEN</name>
                            <description>FLL Enable</description>
                            <lsb>0</lsb>
                            <msb>0</msb>
                            <access>read-write</access>
                            <enumeratedValues>
                                <enumeratedValue>
                                    <name>0</name>
                                    <description>FLL function is disabled</description>
                                    <value>#0</value>
                                </enumeratedValue>
                                <enumeratedValue>
                                    <name>1</name>
                                    <description>FLL function is enabled.</description>
                                    <value>#1</value>
                                </enumeratedValue>
                            </enumeratedValues>
                        </field>
                    </fields>
                </register>
                <register>
                    <name>FLLCR2</name>
                    <description>FLL Control Register2</description>
                    <addressOffset>0x03A</addressOffset>
                    <size>16</size>
                    <access>read-write</access>
                    <resetValue>0x0000</resetValue>
                    <resetMask>0xffff</resetMask>
                    <fields>
                        <field>
                            <name>FLLCNTL</name>
                            <description>FLL Multiplication Control</description>
                            <lsb>0</lsb>
                            <msb>10</msb>
                            <access>read-write</access>
                        </field>
                    </fields>
                </register>
                <register>
                    <name>OSCSF</name>
                    <description>Oscillation Stabilization Flag Register</description>
                    <addressOffset>0x03C</addressOffset>
                    <size>8</size>
                    <access>read-only</access>
                    <resetValue>0x00</resetValue>
                    <resetMask>0xfe</resetMask>
                    <fields>
                        <field>
                            <name>HOCOSF</name>
                            <description>HOCO Clock Oscillation Stabilization Flag</description>
                            <lsb>0</lsb>
                            <msb>0</msb>
                            <access>read-only</access>
                            <enumeratedValues>
                                <enumeratedValue>
                                    <name>0</name>
                                    <description>The HOCO clock is stopped or is not yet stable</description>
                                    <value>#0</value>
                                </enumeratedValue>
                                <enumeratedValue>
                                    <name>1</name>
                                    <description>The HOCO clock is stable, so is available for use as the system clock source</description>
                                    <value>#1</value>
                                </enumeratedValue>
                            </enumeratedValues>
                        </field>
                        <field>
                            <name>MOSCSF</name>
                            <description>Main Clock Oscillation Stabilization Flag</description>
                            <lsb>3</lsb>
                            <msb>3</msb>
                            <access>read-only</access>
                            <enumeratedValues>
                                <enumeratedValue>
                                    <name>0</name>
                                    <description>The main clock oscillator is stopped or is not yet stable</description>
                                    <value>#0</value>
                                </enumeratedValue>
                                <enumeratedValue>
                                    <name>1</name>
                                    <description>The main clock oscillator is stable, so is available for use as the system clock source</description>
                                    <value>#1</value>
                                </enumeratedValue>
                            </enumeratedValues>
                        </field>
                        <field>
                            <name>PLLSF</name>
                            <description>PLL1 Clock Oscillation Stabilization Flag</description>
                            <lsb>5</lsb>
                            <msb>5</msb>
                            <access>read-only</access>
                            <enumeratedValues>
                                <enumeratedValue>
                                    <name>0</name>
                                    <description>The PLL1 clock is stopped or is not yet stable.</description>
                                    <value>#0</value>
                                </enumeratedValue>
                                <enumeratedValue>
                                    <name>1</name>
                                    <description>The PLL1 clock is stable, so is available for use as the system clock source</description>
                                    <value>#1</value>
                                </enumeratedValue>
                            </enumeratedValues>
                        </field>
                        <field>
                            <name>PLL2SF</name>
                            <description>PLL2 Clock Oscillation Stabilization Flag</description>
                            <lsb>6</lsb>
                            <msb>6</msb>
                            <access>read-only</access>
                            <enumeratedValues>
                                <enumeratedValue>
                                    <name>0</name>
                                    <description>The PLL2 clock is stopped or is not yet stable.</description>
                                    <value>#0</value>
                                </enumeratedValue>
                                <enumeratedValue>
                                    <name>1</name>
                                    <description>The PLL2 clock is stable</description>
                                    <value>#1</value>
                                </enumeratedValue>
                            </enumeratedValues>
                        </field>
                    </fields>
                </register>
                <register>
                    <name>CKOCR</name>
                    <description>Clock Out Control Register</description>
                    <addressOffset>0x03E</addressOffset>
                    <size>8</size>
                    <access>read-write</access>
                    <resetValue>0x01</resetValue>
                    <resetMask>0xff</resetMask>
                    <fields>
                        <field>
                            <name>CKOSEL</name>
                            <description>Clock Out Source Select</description>
                            <lsb>0</lsb>
                            <msb>2</msb>
                            <access>read-write</access>
                            <enumeratedValues>
                                <enumeratedValue>
                                    <name>000</name>
                                    <description>HOCO</description>
                                    <value>#000</value>
                                </enumeratedValue>
                                <enumeratedValue>
                                    <name>001</name>
                                    <description>MOCO (Value after reset)</description>
                                    <value>#001</value>
                                </enumeratedValue>
                                <enumeratedValue>
                                    <name>010</name>
                                    <description>LOCO</description>
                                    <value>#010</value>
                                </enumeratedValue>
                                <enumeratedValue>
                                    <name>011</name>
                                    <description>MOSC</description>
                                    <value>#011</value>
                                </enumeratedValue>
                                <enumeratedValue>
                                    <name>100</name>
                                    <description>SOSC</description>
                                    <value>#100</value>
                                </enumeratedValue>
                                <enumeratedValue>
                                    <name>Others</name>
                                    <description>Setting prohibited</description>
                                    <isDefault>true</isDefault>
                                </enumeratedValue>
                            </enumeratedValues>
                        </field>
                        <field>
                            <name>CKODIV</name>
                            <description>Clock Output Frequency Division Ratio</description>
                            <lsb>4</lsb>
                            <msb>6</msb>
                            <access>read-write</access>
                            <enumeratedValues>
                                <enumeratedValue>
                                    <name>000</name>
                                    <description>x 1/1</description>
                                    <value>#000</value>
                                </enumeratedValue>
                                <enumeratedValue>
                                    <name>001</name>
                                    <description>x 1/2</description>
                                    <value>#001</value>
                                </enumeratedValue>
                                <enumeratedValue>
                                    <name>010</name>
                                    <description>x 1/4</description>
                                    <value>#010</value>
                                </enumeratedValue>
                                <enumeratedValue>
                                    <name>011</name>
                                    <description>x 1/8</description>
                                    <value>#011</value>
                                </enumeratedValue>
                                <enumeratedValue>
                                    <name>100</name>
                                    <description>x 1/16</description>
                                    <value>#100</value>
                                </enumeratedValue>
                                <enumeratedValue>
                                    <name>101</name>
                                    <description>x 1/32</description>
                                    <value>#101</value>
                                </enumeratedValue>
                                <enumeratedValue>
                                    <name>110</name>
                                    <description>x 1/64</description>
                                    <value>#110</value>
                                </enumeratedValue>
                                <enumeratedValue>
                                    <name>111</name>
                                    <description>x 1/128</description>
                                    <value>#111</value>
                                </enumeratedValue>
                            </enumeratedValues>
                        </field>
                        <field>
                            <name>CKOEN</name>
                            <description>Clock Out Enable</description>
                            <lsb>7</lsb>
                            <msb>7</msb>
                            <access>read-write</access>
                            <enumeratedValues>
                                <enumeratedValue>
                                    <name>0</name>
                                    <description>Disable clock out</description>
                                    <value>#0</value>
                                </enumeratedValue>
                                <enumeratedValue>
                                    <name>1</name>
                                    <description>Enable clock out</description>
                                    <value>#1</value>
                                </enumeratedValue>
                            </enumeratedValues>
                        </field>
                    </fields>
                </register>
                <register>
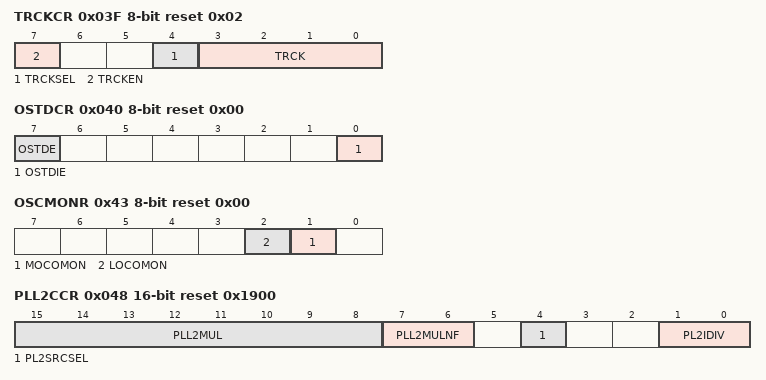
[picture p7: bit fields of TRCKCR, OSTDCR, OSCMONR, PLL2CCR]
                    <name>TRCKCR</name>
                    <description>Trace Clock Control Register</description>
                    <addressOffset>0x03F</addressOffset>
                    <size>8</size>
                    <access>read-write</access>
                    <resetValue>0x02</resetValue>
                    <resetMask>0xff</resetMask>
                    <fields>
                        <field>
                            <name>TRCK</name>
                            <description>Trace Clock operating frequency select</description>
                            <lsb>0</lsb>
                            <msb>3</msb>
                            <access>read-write</access>
                            <enumeratedValues>
                                <enumeratedValue>
                                    <name>0000</name>
                                    <description>1/1</description>
                                    <value>#0000</value>
                                </enumeratedValue>
                                <enumeratedValue>
                                    <name>0001</name>
                                    <description>1/2</description>
                                    <value>#0001</value>
                                </enumeratedValue>
                                <enumeratedValue>
                                    <name>0010</name>
                                    <description>1/4 (Value after reset)</description>
                                    <value>#0010</value>
                                </enumeratedValue>
                                <enumeratedValue>
                                    <name>0011</name>
                                    <description>1/8</description>
                                    <value>#0011</value>
                                </enumeratedValue>
                                <enumeratedValue>
                                    <name>0100</name>
                                    <description>1/16</description>
                                    <value>#0100</value>
                                </enumeratedValue>
                                <enumeratedValue>
                                    <name>0101</name>
                                    <description>1/32</description>
                                    <value>#0101</value>
                                </enumeratedValue>
                                <enumeratedValue>
                                    <name>0110</name>
                                    <description>1/64</description>
                                    <value>#0110</value>
                                </enumeratedValue>
                                <enumeratedValue>
                                    <name>0111</name>
                                    <description>1/128</description>
                                    <value>#0111</value>
                                </enumeratedValue>
                                <enumeratedValue>
                                    <name>1000</name>
                                    <description>1/256</description>
                                    <value>#1000</value>
                                </enumeratedValue>
                                <enumeratedValue>
                                    <name>1001</name>
                                    <description>1/3</description>
                                    <value>#1001</value>
                                </enumeratedValue>
                                <enumeratedValue>
                                    <name>1010</name>
                                    <description>1/6</description>
                                    <value>#1010</value>
                                </enumeratedValue>
                                <enumeratedValue>
                                    <name>1011</name>
                                    <description>1/12</description>
                                    <value>#1011</value>
                                </enumeratedValue>
                                <enumeratedValue>
                                    <name>Others</name>
                                    <description>Setting prohibited</description>
                                    <isDefault>true</isDefault>
                                </enumeratedValue>
                            </enumeratedValues>
                        </field>
                        <field>
                            <name>TRCKSEL</name>
                            <description>Trace Clock source select</description>
                            <lsb>4</lsb>
                            <msb>4</msb>
                            <access>read-write</access>
                            <enumeratedValues>
                                <enumeratedValue>
                                    <name>0</name>
                                    <description>System clock source (Value after reset) </description>
                                    <value>#0</value>
                                </enumeratedValue>
                                <enumeratedValue>
                                    <name>1</name>
                                    <description>HOCO (oscillation in debug mode)</description>
                                    <value>#1</value>
                                </enumeratedValue>
                            </enumeratedValues>
                        </field>
                        <field>
                            <name>TRCKEN</name>
                            <description>Trace Clock operating Enable</description>
                            <lsb>7</lsb>
                            <msb>7</msb>
                            <access>read-write</access>
                            <enumeratedValues>
                                <enumeratedValue>
                                    <name>0</name>
                                    <description>Stop</description>
                                    <value>#0</value>
                                </enumeratedValue>
                                <enumeratedValue>
                                    <name>1</name>
                                    <description>Operation enable</description>
                                    <value>#1</value>
                                </enumeratedValue>
                            </enumeratedValues>
                        </field>
                    </fields>
                </register>
                <register>
                    <name>OSTDCR</name>
                    <description>Oscillation Stop Detection Control Register</description>
                    <addressOffset>0x040</addressOffset>
                    <size>8</size>
                    <access>read-write</access>
                    <resetValue>0x00</resetValue>
                    <resetMask>0xff</resetMask>
                    <fields>
                        <field>
                            <name>OSTDIE</name>
                            <description>Oscillation Stop Detection Interrupt Enable</description>
                            <lsb>0</lsb>
                            <msb>0</msb>
                            <access>read-write</access>
                            <enumeratedValues>
                                <enumeratedValue>
                                    <name>0</name>
                                    <description>Disable oscillation stop detection interrupt (do not notify the POEG)</description>
                                    <value>#0</value>
                                </enumeratedValue>
                                <enumeratedValue>
                                    <name>1</name>
                                    <description>Enable oscillation stop detection interrupt (notify the POEG)</description>
                                    <value>#1</value>
                                </enumeratedValue>
                            </enumeratedValues>
                        </field>
                        <field>
                            <name>OSTDE</name>
                            <description>Oscillation Stop Detection Function Enable</description>
                            <lsb>7</lsb>
                            <msb>7</msb>
                            <access>read-write</access>
                            <enumeratedValues>
                                <enumeratedValue>
                                    <name>0</name>
                                    <description>Disable oscillation stop detection function</description>
                                    <value>#0</value>
                                </enumeratedValue>
                                <enumeratedValue>
                                    <name>1</name>
                                    <description>Enable oscillation stop detection function</description>
                                    <value>#1</value>
                                </enumeratedValue>
                            </enumeratedValues>
                        </field>
                    </fields>
                </register>
                <register>
                    <name>OSTDSR</name>
                    <description>Oscillation Stop Detection Status Register</description>
                    <addressOffset>0x041</addressOffset>
                    <size>8</size>
                    <access>read-write</access>
                    <resetValue>0x00</resetValue>
                    <resetMask>0xff</resetMask>
                    <fields>
                        <field>
                            <name>OSTDF</name>
                            <description>Oscillation Stop Detection Flag</description>
                            <lsb>0</lsb>
                            <msb>0</msb>
                            <access>read-write</access>
                            <enumeratedValues>
                                <enumeratedValue>
                                    <name>0</name>
                                    <description>Main clock oscillation stop not detected</description>
                                    <value>#0</value>
                                </enumeratedValue>
                                <enumeratedValue>
                                    <name>1</name>
                                    <description>Main clock oscillation stop detected</description>
                                    <value>#1</value>
                                </enumeratedValue>
                            </enumeratedValues>
                        </field>
                    </fields>
                </register>
                <register>
                    <name>OSCMONR</name>
                    <description>Oscillator Monitor Register</description>
                    <addressOffset>0x43</addressOffset>
                    <size>8</size>
                    <access>read-write</access>
                    <resetValue>0x00</resetValue>
                    <resetMask>0xff</resetMask>
                    <fields>
                        <field>
                            <name>MOCOMON</name>
                            <description>MOCO operation monitor</description>
                            <lsb>1</lsb>
                            <msb>1</msb>
                            <access>read-only</access>
                            <enumeratedValues>
                                <enumeratedValue>
                                    <name>0</name>
                                    <description>MOCO is set to operate.</description>
                                    <value>#0</value>
                                </enumeratedValue>
                                <enumeratedValue>
                                    <name>1</name>
                                    <description>MOCO is set to stop.</description>
                                    <value>#1</value>
                                </enumeratedValue>
                            </enumeratedValues>
                        </field>
                        <field>
                            <name>LOCOMON</name>
                            <description>LOCO operation monitor</description>
                            <lsb>2</lsb>
                            <msb>2</msb>
                            <access>read-only</access>
                            <enumeratedValues>
                                <enumeratedValue>
                                    <name>0</name>
                                    <description>LOCO is set to operate.</description>
                                    <value>#0</value>
                                </enumeratedValue>
                                <enumeratedValue>
                                    <name>1</name>
                                    <description>LOCO is set to stop.</description>
                                    <value>#1</value>
                                </enumeratedValue>
                            </enumeratedValues>
                        </field>
                    </fields>
                </register>
                <register>
                    <name>PLL2CCR</name>
                    <description>PLL2 Clock Control Register</description>
                    <addressOffset>0x048</addressOffset>
                    <size>16</size>
                    <access>read-write</access>
                    <resetValue>0x1900</resetValue>
                    <resetMask>0xffff</resetMask>
                    <fields>
                        <field>
                            <name>PL2IDIV</name>
                            <description>PLL2 Input Frequency Division Ratio Select</description>
                            <lsb>0</lsb>
                            <msb>1</msb>
                            <access>read-write</access>
                            <enumeratedValues>
                                <enumeratedValue>
                                    <name>00</name>
                                    <description>1/1 (Value after reset)</description>
                                    <value>#00</value>
                                </enumeratedValue>
                                <enumeratedValue>
                                    <name>01</name>
                                    <description>1/2</description>
                                    <value>#01</value>
                                </enumeratedValue>
                                <enumeratedValue>
                                    <name>10</name>
                                    <description>1/3</description>
                                    <value>#10</value>
                                </enumeratedValue>
                                <enumeratedValue>
                                    <name>11</name>
                                    <description>1/4</description>
                                    <value>#11</value>
                                </enumeratedValue>
                            </enumeratedValues>
                        </field>
                        <field>
                            <name>PL2SRCSEL</name>
                            <description>PLL2 Clock Source Select</description>
                            <lsb>4</lsb>
                            <msb>4</msb>
                            <access>read-write</access>
                            <enumeratedValues>
                                <enumeratedValue>
                                    <name>0</name>
                                    <description>Main clock oscillator</description>
                                    <value>#0</value>
                                </enumeratedValue>
                                <enumeratedValue>
                                    <name>1</name>
                                    <description>HOCO</description>
                                    <value>#1</value>
                                </enumeratedValue>
                            </enumeratedValues>
                        </field>
                        <field>
                            <name>PLL2MULNF</name>
                            <description>PLL2 Frequency Multiplication Fractional Factor Select</description>
                            <lsb>6</lsb>
                            <msb>7</msb>
                            <access>read-write</access>
                            <enumeratedValues>
                                <enumeratedValue>
                                    <name>00</name>
                                    <description>0.00 (Value after reset)</description>
                                    <value>#00</value>
                                </enumeratedValue>
                                <enumeratedValue>
                                    <name>01</name>
                                    <description>0.33 (1/3)</description>
                                    <value>#01</value>
                                </enumeratedValue>
                                <enumeratedValue>
                                    <name>10</name>
                                    <description>0.66 (2/3)</description>
                                    <value>#10</value>
                                </enumeratedValue>
                                <enumeratedValue>
                                    <name>11</name>
                                    <description>0.50 (1/2)</description>
                                    <value>#11</value>
                                </enumeratedValue>
                            </enumeratedValues>
                        </field>
                        <field>
                            <name>PLL2MUL</name>
                            <description>PLL2 Frequency Multiplication Factor Select</description>
                            <lsb>8</lsb>
                            <msb>15</msb>
                            <access>read-write</access>
                        </field>
                    </fields>
                </register>
                <register>
                    <name>PLL2CR</name>
                    <description>PLL2 Control Register</description>
                    <addressOffset>0x04A</addressOffset>
                    <size>8</size>
                    <access>read-write</access>
                    <resetValue>0x01</resetValue>
                    <resetMask>0xff</resetMask>
                    <fields>
                        <field>
                            <name>PLL2STP</name>
                            <description>PLL2 Stop Control</description>
                            <lsb>0</lsb>
                            <msb>0</msb>
                            <access>read-write</access>
                            <enumeratedValues>
                                <enumeratedValue>
                                    <name>0</name>
                                    <description>PLL2 is operating</description>
                                    <value>#0</value>
                                </enumeratedValue>
                                <enumeratedValue>
                                    <name>1</name>
                                    <description>PLL2 is stopped</description>
                                    <value>#1</value>
                                </enumeratedValue>
                            </enumeratedValues>
                        </field>
                    </fields>
                </register>
                <register>
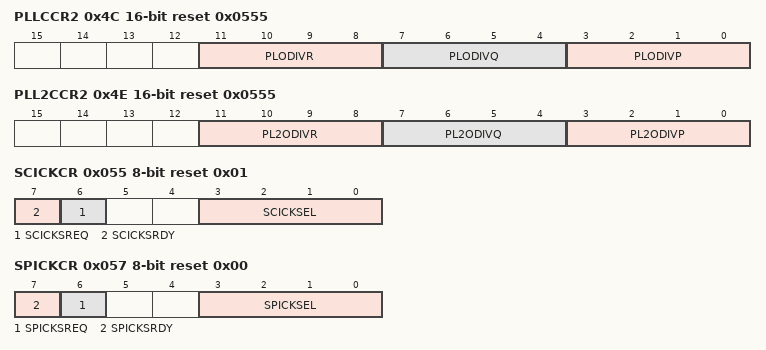
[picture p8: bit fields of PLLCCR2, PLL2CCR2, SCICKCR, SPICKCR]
                    <name>PLLCCR2</name>
                    <description>PLL Clock Control Register 2</description>
                    <addressOffset>0x4C</addressOffset>
                    <size>16</size>
                    <access>read-write</access>
                    <resetValue>0x0555</resetValue>
                    <resetMask>0xffff</resetMask>
                    <fields>
                        <field>
                            <name>PLODIVP</name>
                            <description>PLL1 Output Frequency Division Ratio Select for output clock P</description>
                            <lsb>0</lsb>
                            <msb>3</msb>
                            <access>read-write</access>
                            <enumeratedValues>
                                <enumeratedValue>
                                    <name>0001</name>
                                    <description>× 1/2</description>
                                    <value>#0001</value>
                                </enumeratedValue>
                                <enumeratedValue>
                                    <name>0011</name>
                                    <description>× 1/4</description>
                                    <value>#0011</value>
                                </enumeratedValue>
                                <enumeratedValue>
                                    <name>0101</name>
                                    <description>× 1/6 (Value after reset)</description>
                                    <value>#0101</value>
                                </enumeratedValue>
                                <enumeratedValue>
                                    <name>0111</name>
                                    <description>× 1/8</description>
                                    <value>#0111</value>
                                </enumeratedValue>
                                <enumeratedValue>
                                    <name>1111</name>
                                    <description>× 1/16</description>
                                    <value>#1111</value>
                                </enumeratedValue>
                                <enumeratedValue>
                                    <name>Others</name>
                                    <description>Setting prohibited.</description>
                                    <isDefault>true</isDefault>
                                </enumeratedValue>
                            </enumeratedValues>
                        </field>
                        <field>
                            <name>PLODIVQ</name>
                            <description>PLL1 Output Frequency Division Ratio Select for output clock Q</description>
                            <lsb>4</lsb>
                            <msb>7</msb>
                            <access>read-write</access>
                            <enumeratedValues>
                                <enumeratedValue>
                                    <name>0001</name>
                                    <description>× 1/2</description>
                                    <value>#0001</value>
                                </enumeratedValue>
                                <enumeratedValue>
                                    <name>0010</name>
                                    <description>× 1/3</description>
                                    <value>#0010</value>
                                </enumeratedValue>
                                <enumeratedValue>
                                    <name>0011</name>
                                    <description>× 1/4</description>
                                    <value>#0011</value>
                                </enumeratedValue>
                                <enumeratedValue>
                                    <name>0100</name>
                                    <description>× 1/5</description>
                                    <value>#0100</value>
                                </enumeratedValue>
                                <enumeratedValue>
                                    <name>0101</name>
                                    <description>× 1/6 (Value after reset)</description>
                                    <value>#0101</value>
                                </enumeratedValue>
                                <enumeratedValue>
                                    <name>0111</name>
                                    <description>× 1/8</description>
                                    <value>#0111</value>
                                </enumeratedValue>
                                <enumeratedValue>
                                    <name>1000</name>
                                    <description>× 1/9</description>
                                    <value>#1000</value>
                                </enumeratedValue>
                                <enumeratedValue>
                                    <name>Others</name>
                                    <description>Setting prohibited.</description>
                                    <isDefault>true</isDefault>
                                </enumeratedValue>
                            </enumeratedValues>
                        </field>
                        <field>
                            <name>PLODIVR</name>
                            <description>PLL1 Output Frequency Division Ratio Select for output clock R</description>
                            <lsb>8</lsb>
                            <msb>11</msb>
                            <access>read-write</access>
                            <enumeratedValues>
                                <enumeratedValue>
                                    <name>0001</name>
                                    <description>× 1/2</description>
                                    <value>#0001</value>
                                </enumeratedValue>
                                <enumeratedValue>
                                    <name>0010</name>
                                    <description>× 1/3</description>
                                    <value>#0010</value>
                                </enumeratedValue>
                                <enumeratedValue>
                                    <name>0011</name>
                                    <description>× 1/4</description>
                                    <value>#0011</value>
                                </enumeratedValue>
                                <enumeratedValue>
                                    <name>0100</name>
                                    <description>× 1/5</description>
                                    <value>#0100</value>
                                </enumeratedValue>
                                <enumeratedValue>
                                    <name>0101</name>
                                    <description>× 1/6 (Value after reset)</description>
                                    <value>#0101</value>
                                </enumeratedValue>
                                <enumeratedValue>
                                    <name>0111</name>
                                    <description>× 1/8</description>
                                    <value>#0111</value>
                                </enumeratedValue>
                                <enumeratedValue>
                                    <name>1000</name>
                                    <description>× 1/9</description>
                                    <value>#1000</value>
                                </enumeratedValue>
                                <enumeratedValue>
                                    <name>Others</name>
                                    <description>Setting prohibited.</description>
                                    <isDefault>true</isDefault>
                                </enumeratedValue>
                            </enumeratedValues>
                        </field>
                    </fields>
                </register>
                <register>
                    <name>PLL2CCR2</name>
                    <description>PLL2 Clock Control Register 2</description>
                    <addressOffset>0x4E</addressOffset>
                    <size>16</size>
                    <access>read-write</access>
                    <resetValue>0x0555</resetValue>
                    <resetMask>0xffff</resetMask>
                    <fields>
                        <field>
                            <name>PL2ODIVP</name>
                            <description>PLL2 Output Frequency Division Ratio Select for output clock P</description>
                            <lsb>0</lsb>
                            <msb>3</msb>
                            <access>read-write</access>
                            <enumeratedValues>
                                <enumeratedValue>
                                    <name>0001</name>
                                    <description>× 1/2</description>
                                    <value>#0001</value>
                                </enumeratedValue>
                                <enumeratedValue>
                                    <name>0011</name>
                                    <description>× 1/4</description>
                                    <value>#0011</value>
                                </enumeratedValue>
                                <enumeratedValue>
                                    <name>0101</name>
                                    <description>× 1/6 (Value after reset)</description>
                                    <value>#0101</value>
                                </enumeratedValue>
                                <enumeratedValue>
                                    <name>0111</name>
                                    <description>× 1/8</description>
                                    <value>#0111</value>
                                </enumeratedValue>
                                <enumeratedValue>
                                    <name>1111</name>
                                    <description>× 1/16</description>
                                    <value>#1111</value>
                                </enumeratedValue>
                                <enumeratedValue>
                                    <name>Others</name>
                                    <description>Setting prohibited.</description>
                                    <isDefault>true</isDefault>
                                </enumeratedValue>
                            </enumeratedValues>
                        </field>
                        <field>
                            <name>PL2ODIVQ</name>
                            <description>PLL2 Output Frequency Division Ratio Select for output clock Q</description>
                            <lsb>4</lsb>
                            <msb>7</msb>
                            <access>read-write</access>
                            <enumeratedValues>
                                <enumeratedValue>
                                    <name>0001</name>
                                    <description>× 1/2</description>
                                    <value>#0001</value>
                                </enumeratedValue>
                                <enumeratedValue>
                                    <name>0010</name>
                                    <description>× 1/3</description>
                                    <value>#0010</value>
                                </enumeratedValue>
                                <enumeratedValue>
                                    <name>0011</name>
                                    <description>× 1/4</description>
                                    <value>#0011</value>
                                </enumeratedValue>
                                <enumeratedValue>
                                    <name>0100</name>
                                    <description>× 1/5</description>
                                    <value>#0100</value>
                                </enumeratedValue>
                                <enumeratedValue>
                                    <name>0101</name>
                                    <description>× 1/6 (Value after reset)</description>
                                    <value>#0101</value>
                                </enumeratedValue>
                                <enumeratedValue>
                                    <name>0111</name>
                                    <description>× 1/8</description>
                                    <value>#0111</value>
                                </enumeratedValue>
                                <enumeratedValue>
                                    <name>1000</name>
                                    <description>× 1/9</description>
                                    <value>#1000</value>
                                </enumeratedValue>
                                <enumeratedValue>
                                    <name>Others</name>
                                    <description>Setting prohibited.</description>
                                    <isDefault>true</isDefault>
                                </enumeratedValue>
                            </enumeratedValues>
                        </field>
                        <field>
                            <name>PL2ODIVR</name>
                            <description>PLL2 Output Frequency Division Ratio Select for output clock R</description>
                            <lsb>8</lsb>
                            <msb>11</msb>
                            <access>read-write</access>
                            <enumeratedValues>
                                <enumeratedValue>
                                    <name>0001</name>
                                    <description>× 1/2</description>
                                    <value>#0001</value>
                                </enumeratedValue>
                                <enumeratedValue>
                                    <name>0010</name>
                                    <description>× 1/3</description>
                                    <value>#0010</value>
                                </enumeratedValue>
                                <enumeratedValue>
                                    <name>0011</name>
                                    <description>× 1/4</description>
                                    <value>#0011</value>
                                </enumeratedValue>
                                <enumeratedValue>
                                    <name>0100</name>
                                    <description>× 1/5</description>
                                    <value>#0100</value>
                                </enumeratedValue>
                                <enumeratedValue>
                                    <name>0101</name>
                                    <description>× 1/6 (Value after reset)</description>
                                    <value>#0101</value>
                                </enumeratedValue>
                                <enumeratedValue>
                                    <name>0111</name>
                                    <description>× 1/8</description>
                                    <value>#0111</value>
                                </enumeratedValue>
                                <enumeratedValue>
                                    <name>1000</name>
                                    <description>× 1/9</description>
                                    <value>#1000</value>
                                </enumeratedValue>
                                <enumeratedValue>
                                    <name>Others</name>
                                    <description>Setting prohibited.</description>
                                    <isDefault>true</isDefault>
                                </enumeratedValue>
                            </enumeratedValues>
                        </field>
                    </fields>
                </register>
                <register>
                    <name>EBCKOCR</name>
                    <description>External Bus Clock Output Control Register</description>
                    <addressOffset>0x052</addressOffset>
                    <size>8</size>
                    <access>read-write</access>
                    <resetValue>0x00</resetValue>
                    <resetMask>0xff</resetMask>
                    <fields>
                        <field>
                            <name>EBCKOEN</name>
                            <description>EBCLK Pin Output Control</description>
                            <lsb>0</lsb>
                            <msb>0</msb>
                            <access>read-write</access>
                            <enumeratedValues>
                                <enumeratedValue>
                                    <name>0</name>
                                    <description>EBCLK pin output is disabled (fixed high)</description>
                                    <value>#0</value>
                                </enumeratedValue>
                                <enumeratedValue>
                                    <name>1</name>
                                    <description>EBCLK pin output is enabled.</description>
                                    <value>#1</value>
                                </enumeratedValue>
                            </enumeratedValues>
                        </field>
                    </fields>
                </register>
                <register>
                    <name>SDCKOCR</name>
                    <description>SDRAM Clock Output Control Register</description>
                    <addressOffset>0x053</addressOffset>
                    <size>8</size>
                    <access>read-write</access>
                    <resetValue>0x00</resetValue>
                    <resetMask>0xff</resetMask>
                    <fields>
                        <field>
                            <name>SDCKOEN</name>
                            <description>SDCLK Pin Output Control</description>
                            <lsb>0</lsb>
                            <msb>0</msb>
                            <access>read-write</access>
                            <enumeratedValues>
                                <enumeratedValue>
                                    <name>0</name>
                                    <description>SDCLK pin output is disabled. (Fixed high)</description>
                                    <value>#0</value>
                                </enumeratedValue>
                                <enumeratedValue>
                                    <name>1</name>
                                    <description>SDCLK pin output is enabled.</description>
                                    <value>#1</value>
                                </enumeratedValue>
                            </enumeratedValues>
                        </field>
                    </fields>
                </register>
                <register>
                    <name>SCICKDIVCR</name>
                    <description>SCI clock Division control register</description>
                    <addressOffset>0x054</addressOffset>
                    <size>8</size>
                    <access>read-write</access>
                    <resetValue>0x00</resetValue>
                    <resetMask>0xff</resetMask>
                    <fields>
                        <field>
                            <name>SCICKDIV</name>
                            <description>SCI clock (SCICLK) Division Select</description>
                            <lsb>0</lsb>
                            <msb>2</msb>
                            <access>read-write</access>
                            <enumeratedValues>
                                <enumeratedValue>
                                    <name>000</name>
                                    <description>1/1 (Value after reset)</description>
                                    <value>#000</value>
                                </enumeratedValue>
                                <enumeratedValue>
                                    <name>001</name>
                                    <description>1/2</description>
                                    <value>#001</value>
                                </enumeratedValue>
                                <enumeratedValue>
                                    <name>010</name>
                                    <description>1/4</description>
                                    <value>#010</value>
                                </enumeratedValue>
                                <enumeratedValue>
                                    <name>011</name>
                                    <description>1/6</description>
                                    <value>#011</value>
                                </enumeratedValue>
                                <enumeratedValue>
                                    <name>100</name>
                                    <description>1/8</description>
                                    <value>#100</value>
                                </enumeratedValue>
                                <enumeratedValue>
                                    <name>101</name>
                                    <description>1/3</description>
                                    <value>#101</value>
                                </enumeratedValue>
                                <enumeratedValue>
                                    <name>110</name>
                                    <description>1/5</description>
                                    <value>#110</value>
                                </enumeratedValue>
                                <enumeratedValue>
                                    <name>Others</name>
                                    <description>Setting prohibited.</description>
                                    <isDefault>true</isDefault>
                                </enumeratedValue>
                            </enumeratedValues>
                        </field>
                    </fields>
                </register>
                <register>
                    <name>SCICKCR</name>
                    <description>SCI clock control register</description>
                    <addressOffset>0x055</addressOffset>
                    <size>8</size>
                    <access>read-write</access>
                    <resetValue>0x01</resetValue>
                    <resetMask>0xff</resetMask>
                    <fields>
                        <field>
                            <name>SCICKSEL</name>
                            <description>SCI clock (SCICLK) Source Select</description>
                            <lsb>0</lsb>
                            <msb>3</msb>
                            <access>read-write</access>
                            <enumeratedValues>
                                <enumeratedValue>
                                    <name>0000</name>
                                    <description>HOCO</description>
                                    <value>#0000</value>
                                </enumeratedValue>
                                <enumeratedValue>
                                    <name>0001</name>
                                    <description>MOCO (Value after reset)</description>
                                    <value>#0001</value>
                                </enumeratedValue>
                                <enumeratedValue>
                                    <name>0010</name>
                                    <description>LOCO</description>
                                    <value>#0010</value>
                                </enumeratedValue>
                                <enumeratedValue>
                                    <name>0011</name>
                                    <description>Main clock oscillator</description>
                                    <value>#0011</value>
                                </enumeratedValue>
                                <enumeratedValue>
                                    <name>0100</name>
                                    <description>Sub-clock oscillator</description>
                                    <value>#0100</value>
                                </enumeratedValue>
                                <enumeratedValue>
                                    <name>0101</name>
                                    <description>PLL1P</description>
                                    <value>#0101</value>
                                </enumeratedValue>
                                <enumeratedValue>
                                    <name>0110</name>
                                    <description>PLL2P</description>
                                    <value>#0110</value>
                                </enumeratedValue>
                                <enumeratedValue>
                                    <name>0111</name>
                                    <description>PLL1Q</description>
                                    <value>#0111</value>
                                </enumeratedValue>
                                <enumeratedValue>
                                    <name>1000</name>
                                    <description>PLL1R</description>
                                    <value>#1000</value>
                                </enumeratedValue>
                                <enumeratedValue>
                                    <name>1001</name>
                                    <description>PLL2Q</description>
                                    <value>#1001</value>
                                </enumeratedValue>
                                <enumeratedValue>
                                    <name>1010</name>
                                    <description>PLL2R</description>
                                    <value>#1010</value>
                                </enumeratedValue>
                                <enumeratedValue>
                                    <name>Others</name>
                                    <description>Setting prohibited.</description>
                                    <isDefault>true</isDefault>
                                </enumeratedValue>
                            </enumeratedValues>
                        </field>
                        <field>
                            <name>SCICKSREQ</name>
                            <description>SCI clock (SCICLK) Switching Request</description>
                            <lsb>6</lsb>
                            <msb>6</msb>
                            <access>read-write</access>
                            <enumeratedValues>
                                <enumeratedValue>
                                    <name>0</name>
                                    <description>No request</description>
                                    <value>#0</value>
                                </enumeratedValue>
                                <enumeratedValue>
                                    <name>1</name>
                                    <description>Request switching</description>
                                    <value>#1</value>
                                </enumeratedValue>
                            </enumeratedValues>
                        </field>
                        <field>
                            <name>SCICKSRDY</name>
                            <description>SCI clock (SCICLK) Switching Ready state flag</description>
                            <lsb>7</lsb>
                            <msb>7</msb>
                            <access>read-only</access>
                            <enumeratedValues>
                                <enumeratedValue>
                                    <name>0</name>
                                    <description>Impossible to Switch</description>
                                    <value>#0</value>
                                </enumeratedValue>
                                <enumeratedValue>
                                    <name>1</name>
                                    <description>Possible to Switch</description>
                                    <value>#1</value>
                                </enumeratedValue>
                            </enumeratedValues>
                        </field>
                    </fields>
                </register>
                <register>
                    <name>SPICKDIVCR</name>
                    <description>SPI clock Division control register</description>
                    <addressOffset>0x056</addressOffset>
                    <size>8</size>
                    <access>read-write</access>
                    <resetValue>0x00</resetValue>
                    <resetMask>0xff</resetMask>
                    <fields>
                        <field>
                            <name>SPICKDIV</name>
                            <description>SPI clock (SPICLK) Division Select</description>
                            <lsb>0</lsb>
                            <msb>2</msb>
                            <access>read-write</access>
                            <enumeratedValues>
                                <enumeratedValue>
                                    <name>000</name>
                                    <description>1/1 (Value after reset)</description>
                                    <value>#000</value>
                                </enumeratedValue>
                                <enumeratedValue>
                                    <name>001</name>
                                    <description>1/2</description>
                                    <value>#001</value>
                                </enumeratedValue>
                                <enumeratedValue>
                                    <name>010</name>
                                    <description>1/4</description>
                                    <value>#010</value>
                                </enumeratedValue>
                                <enumeratedValue>
                                    <name>011</name>
                                    <description>1/6</description>
                                    <value>#011</value>
                                </enumeratedValue>
                                <enumeratedValue>
                                    <name>100</name>
                                    <description>1/8</description>
                                    <value>#100</value>
                                </enumeratedValue>
                                <enumeratedValue>
                                    <name>101</name>
                                    <description>1/3</description>
                                    <value>#101</value>
                                </enumeratedValue>
                                <enumeratedValue>
                                    <name>110</name>
                                    <description>1/5</description>
                                    <value>#110</value>
                                </enumeratedValue>
                                <enumeratedValue>
                                    <name>Others</name>
                                    <description>Setting prohibited.</description>
                                    <isDefault>true</isDefault>
                                </enumeratedValue>
                            </enumeratedValues>
                        </field>
                    </fields>
                </register>
                <register>
                    <name>SPICKCR</name>
                    <description>SPI clock control register</description>
                    <addressOffset>0x057</addressOffset>
                    <size>8</size>
                    <access>read-write</access>
                    <resetValue>0x00</resetValue>
                    <resetMask>0xff</resetMask>
                    <fields>
                        <field>
                            <name>SPICKSEL</name>
                            <description>SPI clock (SPICLK) Source Select</description>
                            <lsb>0</lsb>
                            <msb>3</msb>
                            <access>read-write</access>
                            <enumeratedValues>
                                <enumeratedValue>
                                    <name>0000</name>
                                    <description>HOCO</description>
                                    <value>#0000</value>
                                </enumeratedValue>
                                <enumeratedValue>
                                    <name>0001</name>
                                    <description>MOCO (Value after reset)</description>
                                    <value>#0001</value>
                                </enumeratedValue>
                                <enumeratedValue>
                                    <name>0010</name>
                                    <description>LOCO</description>
                                    <value>#0010</value>
                                </enumeratedValue>
                                <enumeratedValue>
                                    <name>0011</name>
                                    <description>Main clock oscillator</description>
                                    <value>#0011</value>
                                </enumeratedValue>
                                <enumeratedValue>
                                    <name>0100</name>
                                    <description>Sub-clock oscillator</description>
                                    <value>#0100</value>
                                </enumeratedValue>
                                <enumeratedValue>
                                    <name>0101</name>
                                    <description>PLL1P</description>
                                    <value>#0101</value>
                                </enumeratedValue>
                                <enumeratedValue>
                                    <name>0110</name>
                                    <description>PLL2P</description>
                                    <value>#0110</value>
                                </enumeratedValue>
                                <enumeratedValue>
                                    <name>0111</name>
                                    <description>PLL1Q</description>
                                    <value>#0111</value>
                                </enumeratedValue>
                                <enumeratedValue>
                                    <name>1000</name>
                                    <description>PLL1R</description>
                                    <value>#1000</value>
                                </enumeratedValue>
                                <enumeratedValue>
                                    <name>1001</name>
                                    <description>PLL2Q</description>
                                    <value>#1001</value>
                                </enumeratedValue>
                                <enumeratedValue>
                                    <name>1010</name>
                                    <description>PLL2R</description>
                                    <value>#1010</value>
                                </enumeratedValue>
                                <enumeratedValue>
                                    <name>Others</name>
                                    <description>Setting prohibited.</description>
                                    <isDefault>true</isDefault>
                                </enumeratedValue>
                            </enumeratedValues>
                        </field>
                        <field>
                            <name>SPICKSREQ</name>
                            <description>SPI clock (SPICLK) Switching Request</description>
                            <lsb>6</lsb>
                            <msb>6</msb>
                            <access>read-write</access>
                            <enumeratedValues>
                                <enumeratedValue>
                                    <name>0</name>
                                    <description>No request</description>
                                    <value>#0</value>
                                </enumeratedValue>
                                <enumeratedValue>
                                    <name>1</name>
                                    <description>Request switching</description>
                                    <value>#1</value>
                                </enumeratedValue>
                            </enumeratedValues>
                        </field>
                        <field>
                            <name>SPICKSRDY</name>
                            <description>SPI clock (SPICLK) Switching Ready state flag</description>
                            <lsb>7</lsb>
                            <msb>7</msb>
                            <access>read-only</access>
                            <enumeratedValues>
                                <enumeratedValue>
                                    <name>0</name>
                                    <description>Impossible to Switch</description>
                                    <value>#0</value>
                                </enumeratedValue>
                                <enumeratedValue>
                                    <name>1</name>
                                    <description>Possible to Switch</description>
                                    <value>#1</value>
                                </enumeratedValue>
                            </enumeratedValues>
                        </field>
                    </fields>
                </register>
                <register>
                    <name>LCDCKDIVCR</name>
                    <description>LCD clock Division control register</description>
                    <addressOffset>0x05E</addressOffset>
                    <size>8</size>
                    <access>read-write</access>
                    <resetValue>0x00</resetValue>
                    <resetMask>0xff</resetMask>
                    <fields>
                        <field>
                            <name>LCDCKDIV</name>
                            <description>LCD clock (LCDCLK) Division Select</description>
                            <lsb>0</lsb>
                            <msb>2</msb>
                            <access>read-write</access>
                            <enumeratedValues>
                                <enumeratedValue>
                                    <name>000</name>
                                    <description>1/1</description>
                                    <value>#000</value>
                                </enumeratedValue>
                                <enumeratedValue>
                                    <name>001</name>
                                    <description>1/2</description>
                                    <value>#001</value>
                                </enumeratedValue>
                                <enumeratedValue>
                                    <name>010</name>
                                    <description>1/4</description>
                                    <value>#010</value>
                                </enumeratedValue>
                                <enumeratedValue>
                                    <name>011</name>
                                    <description>1/6</description>
                                    <value>#011</value>
                                </enumeratedValue>
                                <enumeratedValue>
                                    <name>100</name>
                                    <description>1/8</description>
                                    <value>#100</value>
                                </enumeratedValue>
                                <enumeratedValue>
                                    <name>101</name>
                                    <description>1/3</description>
                                    <value>#101</value>
                                </enumeratedValue>
                                <enumeratedValue>
                                    <name>110</name>
                                    <description>1/5</description>
                                    <value>#110</value>
                                </enumeratedValue>
                                <enumeratedValue>
                                    <name>Others</name>
                                    <description>Setting prohibited.</description>
                                    <isDefault>true</isDefault>
                                </enumeratedValue>
                            </enumeratedValues>
                        </field>
                    </fields>
                </register>
                <register>
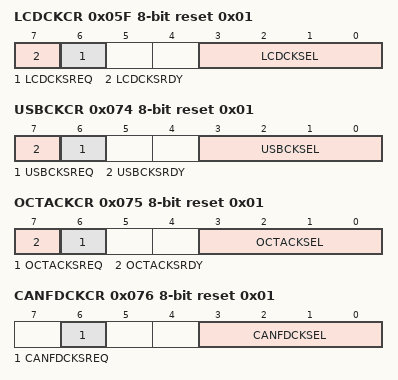
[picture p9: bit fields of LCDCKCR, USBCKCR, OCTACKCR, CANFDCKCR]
                    <name>LCDCKCR</name>
                    <description>LCD clock control register</description>
                    <addressOffset>0x05F</addressOffset>
                    <size>8</size>
                    <access>read-write</access>
                    <resetValue>0x01</resetValue>
                    <resetMask>0xff</resetMask>
                    <fields>
                        <field>
                            <name>LCDCKSEL</name>
                            <description>LCD clock (LCDCLK) Source Select</description>
                            <lsb>0</lsb>
                            <msb>3</msb>
                            <access>read-write</access>
                            <enumeratedValues>
                                <enumeratedValue>
                                    <name>0001</name>
                                    <description>MOCO (Value after reset)</description>
                                    <value>#0001</value>
                                </enumeratedValue>
                                <enumeratedValue>
                                    <name>0101</name>
                                    <description>PLL1P</description>
                                    <value>#0101</value>
                                </enumeratedValue>
                                <enumeratedValue>
                                    <name>0110</name>
                                    <description>PLL2P</description>
                                    <value>#0110</value>
                                </enumeratedValue>
                                <enumeratedValue>
                                    <name>0111</name>
                                    <description>PLL1Q</description>
                                    <value>#0111</value>
                                </enumeratedValue>
                                <enumeratedValue>
                                    <name>1000</name>
                                    <description>PLL1R</description>
                                    <value>#1000</value>
                                </enumeratedValue>
                                <enumeratedValue>
                                    <name>1001</name>
                                    <description>PLL2Q</description>
                                    <value>#1001</value>
                                </enumeratedValue>
                                <enumeratedValue>
                                    <name>1010</name>
                                    <description>PLL2R</description>
                                    <value>#1010</value>
                                </enumeratedValue>
                                <enumeratedValue>
                                    <name>Others</name>
                                    <description>Setting prohibited.</description>
                                    <isDefault>true</isDefault>
                                </enumeratedValue>
                            </enumeratedValues>
                        </field>
                        <field>
                            <name>LCDCKSREQ</name>
                            <description>LCD clock (LCDCLK) Switching Request</description>
                            <lsb>6</lsb>
                            <msb>6</msb>
                            <access>read-write</access>
                            <enumeratedValues>
                                <enumeratedValue>
                                    <name>0</name>
                                    <description>No request</description>
                                    <value>#0</value>
                                </enumeratedValue>
                                <enumeratedValue>
                                    <name>1</name>
                                    <description>Request switching</description>
                                    <value>#1</value>
                                </enumeratedValue>
                            </enumeratedValues>
                        </field>
                        <field>
                            <name>LCDCKSRDY</name>
                            <description>LCD clock (LCDCLK) Switching Ready state flag</description>
                            <lsb>7</lsb>
                            <msb>7</msb>
                            <access>read-only</access>
                            <enumeratedValues>
                                <enumeratedValue>
                                    <name>0</name>
                                    <description>Impossible to Switch</description>
                                    <value>#0</value>
                                </enumeratedValue>
                                <enumeratedValue>
                                    <name>1</name>
                                    <description>Possible to Switch</description>
                                    <value>#1</value>
                                </enumeratedValue>
                            </enumeratedValues>
                        </field>
                    </fields>
                </register>
                <register>
                    <name>MOCOUTCR</name>
                    <description>MOCO User Trimming Control Register</description>
                    <addressOffset>0x061</addressOffset>
                    <size>8</size>
                    <access>read-write</access>
                    <resetValue>0x00</resetValue>
                    <resetMask>0xff</resetMask>
                    <fields>
                        <field>
                            <name>MOCOUTRM</name>
                            <description>MOCO User Trimming</description>
                            <lsb>0</lsb>
                            <msb>7</msb>
                            <access>read-write</access>
                        </field>
                    </fields>
                </register>
                <register>
                    <name>HOCOUTCR</name>
                    <description>HOCO User Trimming Control Register</description>
                    <addressOffset>0x062</addressOffset>
                    <size>8</size>
                    <access>read-write</access>
                    <resetValue>0x00</resetValue>
                    <resetMask>0xff</resetMask>
                    <fields>
                        <field>
                            <name>HOCOUTRM</name>
                            <description>HOCO User Trimming</description>
                            <lsb>0</lsb>
                            <msb>7</msb>
                            <access>read-write</access>
                        </field>
                    </fields>
                </register>
                <register>
                    <name>USBCKDIVCR</name>
                    <description>USB Clock Division Control Register</description>
                    <addressOffset>0x06C</addressOffset>
                    <size>8</size>
                    <access>read-write</access>
                    <resetValue>0x00</resetValue>
                    <resetMask>0xff</resetMask>
                    <fields>
                        <field>
                            <name>USBCKDIV</name>
                            <description>USB Clock (USBCLK) Division Select</description>
                            <lsb>0</lsb>
                            <msb>2</msb>
                            <access>read-write</access>
                            <enumeratedValues>
                                <enumeratedValue>
                                    <name>000</name>
                                    <description>1/1</description>
                                    <value>#000</value>
                                </enumeratedValue>
                                <enumeratedValue>
                                    <name>001</name>
                                    <description>1/2</description>
                                    <value>#001</value>
                                </enumeratedValue>
                                <enumeratedValue>
                                    <name>010</name>
                                    <description>1/4</description>
                                    <value>#010</value>
                                </enumeratedValue>
                                <enumeratedValue>
                                    <name>011</name>
                                    <description>1/6</description>
                                    <value>#011</value>
                                </enumeratedValue>
                                <enumeratedValue>
                                    <name>100</name>
                                    <description>1/8</description>
                                    <value>#100</value>
                                </enumeratedValue>
                                <enumeratedValue>
                                    <name>101</name>
                                    <description>1/3</description>
                                    <value>#101</value>
                                </enumeratedValue>
                                <enumeratedValue>
                                    <name>110</name>
                                    <description>1/5</description>
                                    <value>#110</value>
                                </enumeratedValue>
                                <enumeratedValue>
                                    <name>Others</name>
                                    <description>Setting prohibited.</description>
                                    <isDefault>true</isDefault>
                                </enumeratedValue>
                            </enumeratedValues>
                        </field>
                    </fields>
                </register>
                <register>
                    <name>OCTACKDIVCR</name>
                    <description>Octal-SPI Clock Division Control Register</description>
                    <addressOffset>0x06D</addressOffset>
                    <size>8</size>
                    <access>read-write</access>
                    <resetValue>0x00</resetValue>
                    <resetMask>0xff</resetMask>
                    <fields>
                        <field>
                            <name>OCTACKDIV</name>
                            <description>Octal-SPI Clock (OCTACLK) Division Select</description>
                            <lsb>0</lsb>
                            <msb>2</msb>
                            <access>read-write</access>
                            <enumeratedValues>
                                <enumeratedValue>
                                    <name>000</name>
                                    <description>1/1 (Value after reset)</description>
                                    <value>#000</value>
                                </enumeratedValue>
                                <enumeratedValue>
                                    <name>001</name>
                                    <description>1/2</description>
                                    <value>#001</value>
                                </enumeratedValue>
                                <enumeratedValue>
                                    <name>010</name>
                                    <description>1/4</description>
                                    <value>#010</value>
                                </enumeratedValue>
                                <enumeratedValue>
                                    <name>011</name>
                                    <description>1/6</description>
                                    <value>#011</value>
                                </enumeratedValue>
                                <enumeratedValue>
                                    <name>100</name>
                                    <description>1/8</description>
                                    <value>#100</value>
                                </enumeratedValue>
                                <enumeratedValue>
                                    <name>101</name>
                                    <description>1/3</description>
                                    <value>#101</value>
                                </enumeratedValue>
                                <enumeratedValue>
                                    <name>110</name>
                                    <description>1/5</description>
                                    <value>#110</value>
                                </enumeratedValue>
                                <enumeratedValue>
                                    <name>Others</name>
                                    <description>Setting prohibited.</description>
                                    <isDefault>true</isDefault>
                                </enumeratedValue>
                            </enumeratedValues>
                        </field>
                    </fields>
                </register>
                <register>
                    <name>CANFDCKDIVCR</name>
                    <description>CANFD Core Clock Division Control Register</description>
                    <addressOffset>0x06E</addressOffset>
                    <size>8</size>
                    <access>read-write</access>
                    <resetValue>0x00</resetValue>
                    <resetMask>0xff</resetMask>
                    <fields>
                        <field>
                            <name>CANFDCKDIV</name>
                            <description>CANFD core clock (CANFDCLK) Division Select</description>
                            <lsb>0</lsb>
                            <msb>2</msb>
                            <access>read-write</access>
                            <enumeratedValues>
                                <enumeratedValue>
                                    <name>000</name>
                                    <description>1/1 (Value after reset)</description>
                                    <value>#000</value>
                                </enumeratedValue>
                                <enumeratedValue>
                                    <name>001</name>
                                    <description>1/2</description>
                                    <value>#001</value>
                                </enumeratedValue>
                                <enumeratedValue>
                                    <name>010</name>
                                    <description>1/4</description>
                                    <value>#010</value>
                                </enumeratedValue>
                                <enumeratedValue>
                                    <name>011</name>
                                    <description>1/6</description>
                                    <value>#011</value>
                                </enumeratedValue>
                                <enumeratedValue>
                                    <name>100</name>
                                    <description>1/8</description>
                                    <value>#100</value>
                                </enumeratedValue>
                                <enumeratedValue>
                                    <name>101</name>
                                    <description>1/3</description>
                                    <value>#101</value>
                                </enumeratedValue>
                                <enumeratedValue>
                                    <name>110</name>
                                    <description>1/5</description>
                                    <value>#110</value>
                                </enumeratedValue>
                                <enumeratedValue>
                                    <name>Others</name>
                                    <description>Setting prohibited</description>
                                    <isDefault>true</isDefault>
                                </enumeratedValue>
                            </enumeratedValues>
                        </field>
                    </fields>
                </register>
                <register>
                    <name>USBCKCR</name>
                    <description>USB Clock Control Register</description>
                    <addressOffset>0x074</addressOffset>
                    <size>8</size>
                    <access>read-write</access>
                    <resetValue>0x01</resetValue>
                    <resetMask>0xff</resetMask>
                    <fields>
                        <field>
                            <name>USBCKSEL</name>
                            <description>USB Clock (USBCLK) Source Select</description>
                            <lsb>0</lsb>
                            <msb>3</msb>
                            <access>read-write</access>
                            <enumeratedValues>
                                <enumeratedValue>
                                    <name>0000</name>
                                    <description>HOCO</description>
                                    <value>#0000</value>
                                </enumeratedValue>
                                <enumeratedValue>
                                    <name>0001</name>
                                    <description>MOCO (Value after reset)</description>
                                    <value>#0001</value>
                                </enumeratedValue>
                                <enumeratedValue>
                                    <name>0011</name>
                                    <description>Main clock oscillator</description>
                                    <value>#0011</value>
                                </enumeratedValue>
                                <enumeratedValue>
                                    <name>0101</name>
                                    <description>PLL1P</description>
                                    <value>#0101</value>
                                </enumeratedValue>
                                <enumeratedValue>
                                    <name>0110</name>
                                    <description>PLL2P</description>
                                    <value>#0110</value>
                                </enumeratedValue>
                                <enumeratedValue>
                                    <name>0111</name>
                                    <description>PLL1Q</description>
                                    <value>#0111</value>
                                </enumeratedValue>
                                <enumeratedValue>
                                    <name>1000</name>
                                    <description>PLL1R</description>
                                    <value>#1000</value>
                                </enumeratedValue>
                                <enumeratedValue>
                                    <name>1001</name>
                                    <description>PLL2Q</description>
                                    <value>#1001</value>
                                </enumeratedValue>
                                <enumeratedValue>
                                    <name>1010</name>
                                    <description>PLL2R</description>
                                    <value>#1010</value>
                                </enumeratedValue>
                                <enumeratedValue>
                                    <name>Others</name>
                                    <description>Setting prohibited.</description>
                                    <isDefault>true</isDefault>
                                </enumeratedValue>
                            </enumeratedValues>
                        </field>
                        <field>
                            <name>USBCKSREQ</name>
                            <description>USB Clock (USBCLK) Switching Request</description>
                            <lsb>6</lsb>
                            <msb>6</msb>
                            <access>read-write</access>
                            <enumeratedValues>
                                <enumeratedValue>
                                    <name>0</name>
                                    <description>No request</description>
                                    <value>#0</value>
                                </enumeratedValue>
                                <enumeratedValue>
                                    <name>1</name>
                                    <description>Request switching.</description>
                                    <value>#1</value>
                                </enumeratedValue>
                            </enumeratedValues>
                        </field>
                        <field>
                            <name>USBCKSRDY</name>
                            <description>USB Clock (USBCLK) Switching Ready state flag</description>
                            <lsb>7</lsb>
                            <msb>7</msb>
                            <access>read-only</access>
                            <enumeratedValues>
                                <enumeratedValue>
                                    <name>0</name>
                                    <description>Impossible to Switch</description>
                                    <value>#0</value>
                                </enumeratedValue>
                                <enumeratedValue>
                                    <name>1</name>
                                    <description>Possible to Switch</description>
                                    <value>#1</value>
                                </enumeratedValue>
                            </enumeratedValues>
                        </field>
                    </fields>
                </register>
                <register>
                    <name>OCTACKCR</name>
                    <description>Octal-SPI Clock Control Register</description>
                    <addressOffset>0x075</addressOffset>
                    <size>8</size>
                    <access>read-write</access>
                    <resetValue>0x01</resetValue>
                    <resetMask>0xff</resetMask>
                    <fields>
                        <field>
                            <name>OCTACKSEL</name>
                            <description>Octal-SPI Clock (OCTACLK) Source Select</description>
                            <lsb>0</lsb>
                            <msb>3</msb>
                            <access>read-write</access>
                            <enumeratedValues>
                                <enumeratedValue>
                                    <name>0000</name>
                                    <description>HOCO</description>
                                    <value>#0000</value>
                                </enumeratedValue>
                                <enumeratedValue>
                                    <name>0001</name>
                                    <description>MOCO (Value after reset)</description>
                                    <value>#0001</value>
                                </enumeratedValue>
                                <enumeratedValue>
                                    <name>0010</name>
                                    <description>LOCO</description>
                                    <value>#0010</value>
                                </enumeratedValue>
                                <enumeratedValue>
                                    <name>0011</name>
                                    <description>Main clock oscillator</description>
                                    <value>#0011</value>
                                </enumeratedValue>
                                <enumeratedValue>
                                    <name>0100</name>
                                    <description>Sub-clock oscillator</description>
                                    <value>#0100</value>
                                </enumeratedValue>
                                <enumeratedValue>
                                    <name>0101</name>
                                    <description>PLL1P</description>
                                    <value>#0101</value>
                                </enumeratedValue>
                                <enumeratedValue>
                                    <name>0110</name>
                                    <description>PLL2P</description>
                                    <value>#0110</value>
                                </enumeratedValue>
                                <enumeratedValue>
                                    <name>0111</name>
                                    <description>PLL1Q</description>
                                    <value>#0111</value>
                                </enumeratedValue>
                                <enumeratedValue>
                                    <name>1000</name>
                                    <description>PLL1R</description>
                                    <value>#1000</value>
                                </enumeratedValue>
                                <enumeratedValue>
                                    <name>1001</name>
                                    <description>PLL2Q</description>
                                    <value>#1001</value>
                                </enumeratedValue>
                                <enumeratedValue>
                                    <name>1010</name>
                                    <description>PLL2R</description>
                                    <value>#1010</value>
                                </enumeratedValue>
                                <enumeratedValue>
                                    <name>Others</name>
                                    <description>Setting prohibited.</description>
                                    <isDefault>true</isDefault>
                                </enumeratedValue>
                            </enumeratedValues>
                        </field>
                        <field>
                            <name>OCTACKSREQ</name>
                            <description>Octal-SPI Clock (OCTACLK) Switching Request</description>
                            <lsb>6</lsb>
                            <msb>6</msb>
                            <access>read-write</access>
                            <enumeratedValues>
                                <enumeratedValue>
                                    <name>0</name>
                                    <description>No request</description>
                                    <value>#0</value>
                                </enumeratedValue>
                                <enumeratedValue>
                                    <name>1</name>
                                    <description>Request switching.</description>
                                    <value>#1</value>
                                </enumeratedValue>
                            </enumeratedValues>
                        </field>
                        <field>
                            <name>OCTACKSRDY</name>
                            <description>Octal-SPI Clock (OCTACLK) Switching Ready state flag</description>
                            <lsb>7</lsb>
                            <msb>7</msb>
                            <access>read-only</access>
                            <enumeratedValues>
                                <enumeratedValue>
                                    <name>0</name>
                                    <description>Impossible to Switch</description>
                                    <value>#0</value>
                                </enumeratedValue>
                                <enumeratedValue>
                                    <name>1</name>
                                    <description>Possible to Switch</description>
                                    <value>#1</value>
                                </enumeratedValue>
                            </enumeratedValues>
                        </field>
                    </fields>
                </register>
                <register>
                    <name>CANFDCKCR</name>
                    <description>CANFD Core Clock Control Register</description>
                    <addressOffset>0x076</addressOffset>
                    <size>8</size>
                    <access>read-write</access>
                    <resetValue>0x01</resetValue>
                    <resetMask>0xff</resetMask>
                    <fields>
                        <field>
                            <name>CANFDCKSEL</name>
                            <description>CANFD Core Clock (CANFDCLK) Source Select</description>
                            <lsb>0</lsb>
                            <msb>3</msb>
                            <access>read-write</access>
                            <enumeratedValues>
                                <enumeratedValue>
                                    <name>0000</name>
                                    <description>HOCO</description>
                                    <value>#0000</value>
                                </enumeratedValue>
                                <enumeratedValue>
                                    <name>0001</name>
                                    <description>MOCO (Value after reset)</description>
                                    <value>#0001</value>
                                </enumeratedValue>
                                <enumeratedValue>
                                    <name>0010</name>
                                    <description>LOCO</description>
                                    <value>#0010</value>
                                </enumeratedValue>
                                <enumeratedValue>
                                    <name>0011</name>
                                    <description>Main clock oscillator</description>
                                    <value>#0011</value>
                                </enumeratedValue>
                                <enumeratedValue>
                                    <name>0100</name>
                                    <description>Sub-clock oscillator</description>
                                    <value>#0100</value>
                                </enumeratedValue>
                                <enumeratedValue>
                                    <name>0101</name>
                                    <description>PLL1P</description>
                                    <value>#0101</value>
                                </enumeratedValue>
                                <enumeratedValue>
                                    <name>0110</name>
                                    <description>PLL2P</description>
                                    <value>#0110</value>
                                </enumeratedValue>
                                <enumeratedValue>
                                    <name>0111</name>
                                    <description>PLL1Q</description>
                                    <value>#0111</value>
                                </enumeratedValue>
                                <enumeratedValue>
                                    <name>1000</name>
                                    <description>PLL1R</description>
                                    <value>#1000</value>
                                </enumeratedValue>
                                <enumeratedValue>
                                    <name>1001</name>
                                    <description>PLL2Q</description>
                                    <value>#1001</value>
                                </enumeratedValue>
                                <enumeratedValue>
                                    <name>1010</name>
                                    <description>PLL2R</description>
                                    <value>#1010</value>
                                </enumeratedValue>
                                <enumeratedValue>
                                    <name>Others</name>
                                    <description>Setting prohibited.</description>
                                    <isDefault>true</isDefault>
                                </enumeratedValue>
                            </enumeratedValues>
                        </field>
                        <field>
                            <name>CANFDCKSREQ</name>
                            <description>CANFD Core Clock (CANFDCLK) Switching Request</description>
                            <lsb>6</lsb>
                            <msb>6</msb>
                            <access>read-write</access>
                            <enumeratedValues>
                                <enumeratedValue>
                                    <name>0</name>
                                    <description>No request</description>
                                    <value>#0</value>
                                </enumeratedValue>
                                <enumeratedValue>
                                    <name>1</name>
                                    <description>Request switching</description>
                                    <value>#1</value>
                                </enumeratedValue>
                            </enumeratedValues>
                        </field>
                    </fields>
                </register>
                <register>
                    <name>MOSCSCR</name>
                    <description>Main Clock Oscillator Standby Control Register</description>
                    <addressOffset>0x07C</addressOffset>
                    <size>8</size>
                    <access>read-write</access>
                    <resetValue>0x00</resetValue>
                    <resetMask>0xff</resetMask>
                    <fields>
                        <field>
                            <name>MOSCSOKP</name>
                            <description>Main Clock Oscillator Standby Oscillation Keep select</description>
                            <lsb>0</lsb>
                            <msb>0</msb>
                            <access>read-write</access>
                            <enumeratedValues>
                                <enumeratedValue>
                                    <name>0</name>
                                    <description>Disable</description>
                                    <value>#0</value>
                                </enumeratedValue>
                                <enumeratedValue>
                                    <name>1</name>
                                    <description>Enable</description>
                                    <value>#1</value>
                                </enumeratedValue>
                            </enumeratedValues>
                        </field>
                    </fields>
                </register>
                <register>
                    <name>HOCOSCR</name>
                    <description>High-Speed On-Chip Oscillator Standby Control Register</description>
                    <addressOffset>0x07D</addressOffset>
                    <size>8</size>
                    <access>read-write</access>
                    <resetValue>0x00</resetValue>
                    <resetMask>0xff</resetMask>
                    <fields>
                        <field>
                            <name>HOCOSOKP</name>
                            <description>HOCO Standby Oscillation Keep select.</description>
                            <lsb>0</lsb>
                            <msb>0</msb>
                            <access>read-write</access>
                            <enumeratedValues>
                                <enumeratedValue>
                                    <name>0</name>
                                    <description>Disable</description>
                                    <value>#0</value>
                                </enumeratedValue>
                                <enumeratedValue>
                                    <name>1</name>
                                    <description>Enable</description>
                                    <value>#1</value>
                                </enumeratedValue>
                            </enumeratedValues>
                        </field>
                    </fields>
                </register>
                <register>
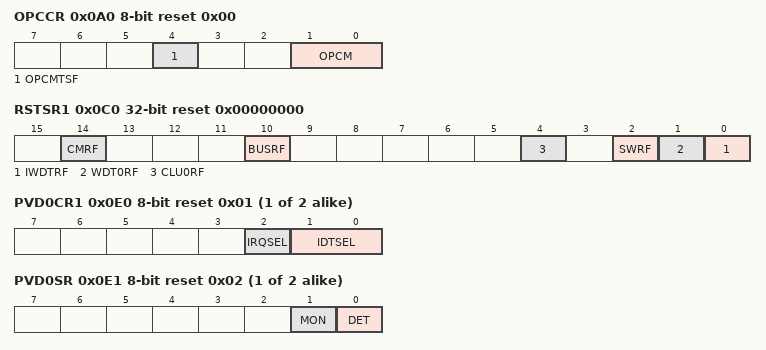
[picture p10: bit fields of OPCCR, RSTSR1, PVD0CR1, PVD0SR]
                    <name>OPCCR</name>
                    <description>Operating Power Control Register</description>
                    <addressOffset>0x0A0</addressOffset>
                    <size>8</size>
                    <access>read-write</access>
                    <resetValue>0x00</resetValue>
                    <resetMask>0xff</resetMask>
                    <fields>
                        <field>
                            <name>OPCM</name>
                            <description>Operating Power Control Mode Select</description>
                            <lsb>0</lsb>
                            <msb>1</msb>
                            <access>read-write</access>
                            <enumeratedValues>
                                <enumeratedValue>
                                    <name>00</name>
                                    <description>High-speed mode</description>
                                    <value>#00</value>
                                </enumeratedValue>
                                <enumeratedValue>
                                    <name>01</name>
                                    <description>Setting prohibited</description>
                                    <value>#01</value>
                                </enumeratedValue>
                                <enumeratedValue>
                                    <name>10</name>
                                    <description>Setting prohibited</description>
                                    <value>#10</value>
                                </enumeratedValue>
                                <enumeratedValue>
                                    <name>11</name>
                                    <description>Low-speed mode</description>
                                    <value>#11</value>
                                </enumeratedValue>
                            </enumeratedValues>
                        </field>
                        <field>
                            <name>OPCMTSF</name>
                            <description>Operating Power Control Mode Transition Status Flag</description>
                            <lsb>4</lsb>
                            <msb>4</msb>
                            <access>read-only</access>
                            <enumeratedValues>
                                <enumeratedValue>
                                    <name>0</name>
                                    <description>Transition completed</description>
                                    <value>#0</value>
                                </enumeratedValue>
                                <enumeratedValue>
                                    <name>1</name>
                                    <description>During transition</description>
                                    <value>#1</value>
                                </enumeratedValue>
                            </enumeratedValues>
                        </field>
                    </fields>
                </register>
                <register>
                    <name>MOSCWTCR</name>
                    <description>Main Clock Oscillator Wait Control Register</description>
                    <addressOffset>0x0A2</addressOffset>
                    <size>8</size>
                    <access>read-write</access>
                    <resetValue>0x05</resetValue>
                    <resetMask>0xff</resetMask>
                    <fields>
                        <field>
                            <name>MSTS</name>
                            <description>Main Clock Oscillator Wait Time Setting</description>
                            <lsb>0</lsb>
                            <msb>3</msb>
                            <access>read-write</access>
                            <enumeratedValues>
                                <enumeratedValue>
                                    <name>0x0</name>
                                    <description>Wait time = 3 cycles (11.4 us)</description>
                                    <value>0x0</value>
                                </enumeratedValue>
                                <enumeratedValue>
                                    <name>0x1</name>
                                    <description>Wait time = 35 cycles (133.5 us)</description>
                                    <value>0x1</value>
                                </enumeratedValue>
                                <enumeratedValue>
                                    <name>0x2</name>
                                    <description>Wait time = 67 cycles (255.6 us)</description>
                                    <value>0x2</value>
                                </enumeratedValue>
                                <enumeratedValue>
                                    <name>0x3</name>
                                    <description>Wait time = 131 cycles (499.7 us)</description>
                                    <value>0x3</value>
                                </enumeratedValue>
                                <enumeratedValue>
                                    <name>0x4</name>
                                    <description>Wait time = 259 cycles (988.0 us)</description>
                                    <value>0x4</value>
                                </enumeratedValue>
                                <enumeratedValue>
                                    <name>0x5</name>
                                    <description>Wait time = 547 cycles (2086.6 us)</description>
                                    <value>0x5</value>
                                </enumeratedValue>
                                <enumeratedValue>
                                    <name>0x6</name>
                                    <description>Wait time = 1059 cycles (4039.8 us)</description>
                                    <value>0x6</value>
                                </enumeratedValue>
                                <enumeratedValue>
                                    <name>0x7</name>
                                    <description>Wait time = 2147 cycles (8190.2 us)</description>
                                    <value>0x7</value>
                                </enumeratedValue>
                                <enumeratedValue>
                                    <name>0x8</name>
                                    <description>Wait time = 4291 cycles (16368.9 us)</description>
                                    <value>0x8</value>
                                </enumeratedValue>
                                <enumeratedValue>
                                    <name>0x9</name>
                                    <description>Wait time = 8163 cycles (31139.4 us)</description>
                                    <value>0x9</value>
                                </enumeratedValue>
                                <enumeratedValue>
                                    <name>Others</name>
                                    <description>Setting prohibited</description>
                                    <isDefault>true</isDefault>
                                </enumeratedValue>
                            </enumeratedValues>
                        </field>
                    </fields>
                </register>
                <register>
                    <name>RSTSR1</name>
                    <description>Reset Status Register 1</description>
                    <addressOffset>0x0C0</addressOffset>
                    <size>32</size>
                    <access>read-write</access>
                    <resetValue>0x00000000</resetValue>
                    <resetMask>0xffffbbe8</resetMask>
                    <fields>
                        <field>
                            <name>IWDTRF</name>
                            <description>Independent Watchdog Timer Reset Detect Flag</description>
                            <lsb>0</lsb>
                            <msb>0</msb>
                            <access>read-write</access>
                            <enumeratedValues>
                                <enumeratedValue>
                                    <name>0</name>
                                    <description>Independent watchdog timer reset not detected</description>
                                    <value>#0</value>
                                </enumeratedValue>
                                <enumeratedValue>
                                    <name>1</name>
                                    <description>Independent watchdog timer reset detected</description>
                                    <value>#1</value>
                                </enumeratedValue>
                            </enumeratedValues>
                        </field>
                        <field>
                            <name>WDT0RF</name>
                            <description>Watchdog Timer Reset Detect Flag</description>
                            <lsb>1</lsb>
                            <msb>1</msb>
                            <access>read-write</access>
                            <enumeratedValues>
                                <enumeratedValue>
                                    <name>0</name>
                                    <description>Watchdog timer reset not detected</description>
                                    <value>#0</value>
                                </enumeratedValue>
                                <enumeratedValue>
                                    <name>1</name>
                                    <description>Watchdog timer reset detected</description>
                                    <value>#1</value>
                                </enumeratedValue>
                            </enumeratedValues>
                        </field>
                        <field>
                            <name>SWRF</name>
                            <description>Software Reset Detect Flag</description>
                            <lsb>2</lsb>
                            <msb>2</msb>
                            <access>read-write</access>
                            <enumeratedValues>
                                <enumeratedValue>
                                    <name>0</name>
                                    <description>Software reset not detected</description>
                                    <value>#0</value>
                                </enumeratedValue>
                                <enumeratedValue>
                                    <name>1</name>
                                    <description>Software reset detected</description>
                                    <value>#1</value>
                                </enumeratedValue>
                            </enumeratedValues>
                        </field>
                        <field>
                            <name>CLU0RF</name>
                            <description>CPU Lockup Reset Detect Flag</description>
                            <lsb>4</lsb>
                            <msb>4</msb>
                            <access>read-write</access>
                            <enumeratedValues>
                                <enumeratedValue>
                                    <name>0</name>
                                    <description>CPU Lockup reset not detected</description>
                                    <value>#0</value>
                                </enumeratedValue>
                                <enumeratedValue>
                                    <name>1</name>
                                    <description>CPU Lockup reset detected</description>
                                    <value>#1</value>
                                </enumeratedValue>
                            </enumeratedValues>
                        </field>
                        <field>
                            <name>BUSRF</name>
                            <description>Bus Error Reset Detect Flag</description>
                            <lsb>10</lsb>
                            <msb>10</msb>
                            <access>read-write</access>
                            <enumeratedValues>
                                <enumeratedValue>
                                    <name>0</name>
                                    <description>Bus error reset not detected</description>
                                    <value>#0</value>
                                </enumeratedValue>
                                <enumeratedValue>
                                    <name>1</name>
                                    <description>Bus error reset detected</description>
                                    <value>#1</value>
                                </enumeratedValue>
                            </enumeratedValues>
                        </field>
                        <field>
                            <name>CMRF</name>
                            <description>Common Memory Error Reset Detect Flag</description>
                            <lsb>14</lsb>
                            <msb>14</msb>
                            <access>read-write</access>
                            <enumeratedValues>
                                <enumeratedValue>
                                    <name>0</name>
                                    <description>Common memory error reset not detected</description>
                                    <value>#0</value>
                                </enumeratedValue>
                                <enumeratedValue>
                                    <name>1</name>
                                    <description>Common memory error reset detected</description>
                                    <value>#1</value>
                                </enumeratedValue>
                            </enumeratedValues>
                        </field>
                    </fields>
                </register>
                <register>
                    <name>SYRACCR</name>
                    <description>System Register Access Control Register</description>
                    <addressOffset>0xCC</addressOffset>
                    <size>8</size>
                    <access>read-only</access>
                    <resetValue>0x00</resetValue>
                    <resetMask>0xff</resetMask>
                    <fields>
                        <field>
                            <name>BUSY</name>
                            <description>Access Ready monitor</description>
                            <lsb>0</lsb>
                            <msb>0</msb>
                            <access>read-only</access>
                            <enumeratedValues>
                                <enumeratedValue>
                                    <name>0</name>
                                    <description>Ready to read/write access</description>
                                    <value>#0</value>
                                </enumeratedValue>
                                <enumeratedValue>
                                    <name>1</name>
                                    <description>Writing in progress</description>
                                    <value>#1</value>
                                </enumeratedValue>
                            </enumeratedValues>
                        </field>
                    </fields>
                </register>
                <register>
                    <dim>2</dim>
                    <dimIncrement>0x2</dimIncrement>
                    <dimIndex>1-2</dimIndex>
                    <name>PVD%sCR1</name>
                    <description>Voltage Monitor %s Circuit Control Register 1</description>
                    <addressOffset>0x0E0</addressOffset>
                    <size>8</size>
                    <access>read-write</access>
                    <resetValue>0x01</resetValue>
                    <resetMask>0xff</resetMask>
                    <fields>
                        <field>
                            <name>IDTSEL</name>
                            <description>Voltage Monitor m Interrupt Generation Condition Select</description>
                            <lsb>0</lsb>
                            <msb>1</msb>
                            <access>read-write</access>
                        </field>
                        <field>
                            <name>IRQSEL</name>
                            <description>Voltage Monitor m Interrupt Type Select</description>
                            <lsb>2</lsb>
                            <msb>2</msb>
                            <access>read-write</access>
                            <enumeratedValues>
                                <enumeratedValue>
                                    <name>0</name>
                                    <description>Non-maskable interrupt</description>
                                    <value>#0</value>
                                </enumeratedValue>
                                <enumeratedValue>
                                    <name>1</name>
                                    <description>Maskable interrupt</description>
                                    <value>#1</value>
                                </enumeratedValue>
                            </enumeratedValues>
                        </field>
                    </fields>
                </register>
                <register>
                    <dim>2</dim>
                    <dimIncrement>0x2</dimIncrement>
                    <dimIndex>1-2</dimIndex>
                    <name>PVD%sSR</name>
                    <description>Voltage Monitor %s Circuit Status Register</description>
                    <addressOffset>0x0E1</addressOffset>
                    <size>8</size>
                    <access>read-write</access>
                    <resetValue>0x02</resetValue>
                    <resetMask>0xff</resetMask>
                    <fields>
                        <field>
                            <name>DET</name>
                            <description>Voltage Monitor m Voltage Change Detection Flag</description>
                            <lsb>0</lsb>
                            <msb>0</msb>
                            <access>read-write</access>
                        </field>
                        <field>
                            <name>MON</name>
                            <description>Voltage Monitor 1 Signal Monitor Flag</description>
                            <lsb>1</lsb>
                            <msb>1</msb>
                            <access>read-write</access>
                        </field>
                    </fields>
                </register>
                <register>
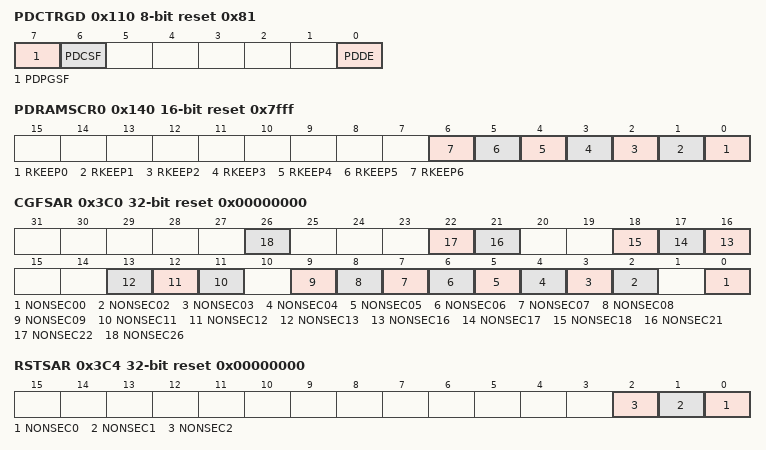
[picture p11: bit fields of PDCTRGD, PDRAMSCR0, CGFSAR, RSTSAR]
                    <name>PDCTRGD</name>
                    <description>Graphics Power Domain Control Register</description>
                    <addressOffset>0x110</addressOffset>
                    <size>8</size>
                    <access>read-write</access>
                    <resetValue>0x81</resetValue>
                    <resetMask>0xff</resetMask>
                    <fields>
                        <field>
                            <name>PDDE</name>
                            <description>Power control enable</description>
                            <lsb>0</lsb>
                            <msb>0</msb>
                            <access>read-write</access>
                            <enumeratedValues>
                                <enumeratedValue>
                                    <name>0</name>
                                    <description>Power on the target domain </description>
                                    <value>#0</value>
                                </enumeratedValue>
                                <enumeratedValue>
                                    <name>1</name>
                                    <description>Power off the target domain </description>
                                    <value>#1</value>
                                </enumeratedValue>
                            </enumeratedValues>
                        </field>
                        <field>
                            <name>PDCSF</name>
                            <description>Power control status flag</description>
                            <lsb>6</lsb>
                            <msb>6</msb>
                            <access>read-only</access>
                            <enumeratedValues>
                                <enumeratedValue>
                                    <name>0</name>
                                    <description>Power gating control is not executed (idle)</description>
                                    <value>#0</value>
                                </enumeratedValue>
                                <enumeratedValue>
                                    <name>1</name>
                                    <description>Power gating control is in progress</description>
                                    <value>#1</value>
                                </enumeratedValue>
                            </enumeratedValues>
                        </field>
                        <field>
                            <name>PDPGSF</name>
                            <description>Power gating status flag</description>
                            <lsb>7</lsb>
                            <msb>7</msb>
                            <access>read-only</access>
                            <enumeratedValues>
                                <enumeratedValue>
                                    <name>0</name>
                                    <description>Target domain is power on (not gating) </description>
                                    <value>#0</value>
                                </enumeratedValue>
                                <enumeratedValue>
                                    <name>1</name>
                                    <description>Target domain is power off (during Gating) </description>
                                    <value>#1</value>
                                </enumeratedValue>
                            </enumeratedValues>
                        </field>
                    </fields>
                </register>
                <register>
                    <name>PDRAMSCR0</name>
                    <description>SRAM Power Domain Standby Control Register 0</description>
                    <addressOffset>0x140</addressOffset>
                    <size>16</size>
                    <access>read-write</access>
                    <resetValue>0x7fff</resetValue>
                    <resetMask>0xffff</resetMask>
                    <fields>
                        <field>
                            <name>RKEEP0</name>
                            <description>Unnecessary Circuit Retention</description>
                            <lsb>0</lsb>
                            <msb>0</msb>
                            <access>read-write</access>
                            <enumeratedValues>
                                <enumeratedValue>
                                    <name>0</name>
                                    <description>When entering the Software Standby mode, the contents of unnecessary circuit are not kept.</description>
                                    <value>#0</value>
                                </enumeratedValue>
                                <enumeratedValue>
                                    <name>1</name>
                                    <description>When entering the Software Standby mode, the contents of unnecessary circuit are kept.</description>
                                    <value>#1</value>
                                </enumeratedValue>
                            </enumeratedValues>
                        </field>
                        <field>
                            <name>RKEEP1</name>
                            <description>Unnecessary Circuit Retention</description>
                            <lsb>1</lsb>
                            <msb>1</msb>
                            <access>read-write</access>
                            <enumeratedValues>
                                <enumeratedValue>
                                    <name>0</name>
                                    <description>When entering the Software Standby mode, the contents of unnecessary circuit are not kept.</description>
                                    <value>#0</value>
                                </enumeratedValue>
                                <enumeratedValue>
                                    <name>1</name>
                                    <description>When entering the Software Standby mode, the contents of unnecessary circuit are kept.</description>
                                    <value>#1</value>
                                </enumeratedValue>
                            </enumeratedValues>
                        </field>
                        <field>
                            <name>RKEEP2</name>
                            <description>RAM Retention</description>
                            <lsb>2</lsb>
                            <msb>2</msb>
                            <access>read-write</access>
                            <enumeratedValues>
                                <enumeratedValue>
                                    <name>0</name>
                                    <description>When entering the Software Standby mode, the contents of the target RAM are not kept.</description>
                                    <value>#0</value>
                                </enumeratedValue>
                                <enumeratedValue>
                                    <name>1</name>
                                    <description>When entering the Software Standby mode, the contents of the target RAM are kept.</description>
                                    <value>#1</value>
                                </enumeratedValue>
                            </enumeratedValues>
                        </field>
                        <field>
                            <name>RKEEP3</name>
                            <description>RAM Retention</description>
                            <lsb>3</lsb>
                            <msb>3</msb>
                            <access>read-write</access>
                            <enumeratedValues>
                                <enumeratedValue>
                                    <name>0</name>
                                    <description>When entering the Software Standby mode, the contents of the target RAM are not kept.</description>
                                    <value>#0</value>
                                </enumeratedValue>
                                <enumeratedValue>
                                    <name>1</name>
                                    <description>When entering the Software Standby mode, the contents of the target RAM are kept.</description>
                                    <value>#1</value>
                                </enumeratedValue>
                            </enumeratedValues>
                        </field>
                        <field>
                            <name>RKEEP4</name>
                            <description>RAM Retention</description>
                            <lsb>4</lsb>
                            <msb>4</msb>
                            <access>read-write</access>
                            <enumeratedValues>
                                <enumeratedValue>
                                    <name>0</name>
                                    <description>When entering the Software Standby mode, the contents of the target RAM are not kept.</description>
                                    <value>#0</value>
                                </enumeratedValue>
                                <enumeratedValue>
                                    <name>1</name>
                                    <description>When entering the Software Standby mode, the contents of the target RAM are kept.</description>
                                    <value>#1</value>
                                </enumeratedValue>
                            </enumeratedValues>
                        </field>
                        <field>
                            <name>RKEEP5</name>
                            <description>RAM Retention</description>
                            <lsb>5</lsb>
                            <msb>5</msb>
                            <access>read-write</access>
                            <enumeratedValues>
                                <enumeratedValue>
                                    <name>0</name>
                                    <description>When entering the Software Standby mode, the contents of the target RAM are not kept.</description>
                                    <value>#0</value>
                                </enumeratedValue>
                                <enumeratedValue>
                                    <name>1</name>
                                    <description>When entering the Software Standby mode, the contents of the target RAM are kept.</description>
                                    <value>#1</value>
                                </enumeratedValue>
                            </enumeratedValues>
                        </field>
                        <field>
                            <name>RKEEP6</name>
                            <description>RAM Retention</description>
                            <lsb>6</lsb>
                            <msb>6</msb>
                            <access>read-write</access>
                            <enumeratedValues>
                                <enumeratedValue>
                                    <name>0</name>
                                    <description>When entering the Software Standby mode, the contents of the target RAM are not kept.</description>
                                    <value>#0</value>
                                </enumeratedValue>
                                <enumeratedValue>
                                    <name>1</name>
                                    <description>When entering the Software Standby mode, the contents of the target RAM are kept.</description>
                                    <value>#1</value>
                                </enumeratedValue>
                            </enumeratedValues>
                        </field>
                    </fields>
                </register>
                <register>
                    <name>PDRAMSCR1</name>
                    <description>SRAM Power Domain Standby Control Register 1</description>
                    <addressOffset>0x142</addressOffset>
                    <size>8</size>
                    <access>read-write</access>
                    <resetValue>0x03</resetValue>
                    <resetMask>0xff</resetMask>
                    <fields>
                        <field>
                            <name>RKEEP0</name>
                            <description>RAM Retention</description>
                            <lsb>0</lsb>
                            <msb>0</msb>
                            <access>read-write</access>
                            <enumeratedValues>
                                <enumeratedValue>
                                    <name>0</name>
                                    <description>When entering the CPU Deep Sleep and Software Standby mode, the contents of the target RAM are not kept.</description>
                                    <value>#0</value>
                                </enumeratedValue>
                                <enumeratedValue>
                                    <name>1</name>
                                    <description>When entering the CPU Deep Sleep and Software Standby mode, the contents of the target RAM are kept.</description>
                                    <value>#1</value>
                                </enumeratedValue>
                            </enumeratedValues>
                        </field>
                    </fields>
                </register>
                <register>
                    <name>VBRPABARNS</name>
                    <description>VBATT Backup Register Privilege Attribute Boundary Address Register for Non-secure Region</description>
                    <addressOffset>0x3B8</addressOffset>
                    <size>16</size>
                    <access>read-write</access>
                    <resetValue>0x0000</resetValue>
                    <resetMask>0xffff</resetMask>
                    <fields>
                        <field>
                            <name>PABANS</name>
                            <description>Boundary address between privileged and unprivileged.</description>
                            <lsb>0</lsb>
                            <msb>15</msb>
                            <access>read-write</access>
                        </field>
                    </fields>
                </register>
                <register>
                    <name>CGFSAR</name>
                    <description>Clock Generation Function Security Attribute Register</description>
                    <addressOffset>0x3C0</addressOffset>
                    <size>32</size>
                    <access>read-write</access>
                    <resetValue>0x00000000</resetValue>
                    <resetMask>0xffffffff</resetMask>
                    <fields>
                        <field>
                            <name>NONSEC00</name>
                            <description>Non Secure Attribute bit 00</description>
                            <lsb>0</lsb>
                            <msb>0</msb>
                            <access>read-write</access>
                            <enumeratedValues>
                                <enumeratedValue>
                                    <name>0</name>
                                    <description>Secure</description>
                                    <value>#0</value>
                                </enumeratedValue>
                                <enumeratedValue>
                                    <name>1</name>
                                    <description>Non Secure</description>
                                    <value>#1</value>
                                </enumeratedValue>
                            </enumeratedValues>
                        </field>
                        <field>
                            <name>NONSEC02</name>
                            <description>Non Secure Attribute bit 02</description>
                            <lsb>2</lsb>
                            <msb>2</msb>
                            <access>read-write</access>
                            <enumeratedValues>
                                <enumeratedValue>
                                    <name>0</name>
                                    <description>Secure</description>
                                    <value>#0</value>
                                </enumeratedValue>
                                <enumeratedValue>
                                    <name>1</name>
                                    <description>Non Secure</description>
                                    <value>#1</value>
                                </enumeratedValue>
                            </enumeratedValues>
                        </field>
                        <field>
                            <name>NONSEC03</name>
                            <description>Non Secure Attribute bit 03</description>
                            <lsb>3</lsb>
                            <msb>3</msb>
                            <access>read-write</access>
                            <enumeratedValues>
                                <enumeratedValue>
                                    <name>0</name>
                                    <description>Secure</description>
                                    <value>#0</value>
                                </enumeratedValue>
                                <enumeratedValue>
                                    <name>1</name>
                                    <description>Non Secure</description>
                                    <value>#1</value>
                                </enumeratedValue>
                            </enumeratedValues>
                        </field>
                        <field>
                            <name>NONSEC04</name>
                            <description>Non Secure Attribute bit 04</description>
                            <lsb>4</lsb>
                            <msb>4</msb>
                            <access>read-write</access>
                            <enumeratedValues>
                                <enumeratedValue>
                                    <name>0</name>
                                    <description>Secure</description>
                                    <value>#0</value>
                                </enumeratedValue>
                                <enumeratedValue>
                                    <name>1</name>
                                    <description>Non Secure</description>
                                    <value>#1</value>
                                </enumeratedValue>
                            </enumeratedValues>
                        </field>
                        <field>
                            <name>NONSEC05</name>
                            <description>Non Secure Attribute bit 05</description>
                            <lsb>5</lsb>
                            <msb>5</msb>
                            <access>read-write</access>
                            <enumeratedValues>
                                <enumeratedValue>
                                    <name>0</name>
                                    <description>Secure</description>
                                    <value>#0</value>
                                </enumeratedValue>
                                <enumeratedValue>
                                    <name>1</name>
                                    <description>Non Secure</description>
                                    <value>#1</value>
                                </enumeratedValue>
                            </enumeratedValues>
                        </field>
                        <field>
                            <name>NONSEC06</name>
                            <description>Non Secure Attribute bit 06</description>
                            <lsb>6</lsb>
                            <msb>6</msb>
                            <access>read-write</access>
                            <enumeratedValues>
                                <enumeratedValue>
                                    <name>0</name>
                                    <description>Secure</description>
                                    <value>#0</value>
                                </enumeratedValue>
                                <enumeratedValue>
                                    <name>1</name>
                                    <description>Non Secure</description>
                                    <value>#1</value>
                                </enumeratedValue>
                            </enumeratedValues>
                        </field>
                        <field>
                            <name>NONSEC07</name>
                            <description>Non Secure Attribute bit 07</description>
                            <lsb>7</lsb>
                            <msb>7</msb>
                            <access>read-write</access>
                            <enumeratedValues>
                                <enumeratedValue>
                                    <name>0</name>
                                    <description>Secure</description>
                                    <value>#0</value>
                                </enumeratedValue>
                                <enumeratedValue>
                                    <name>1</name>
                                    <description>Non Secure</description>
                                    <value>#1</value>
                                </enumeratedValue>
                            </enumeratedValues>
                        </field>
                        <field>
                            <name>NONSEC08</name>
                            <description>Non Secure Attribute bit 08</description>
                            <lsb>8</lsb>
                            <msb>8</msb>
                            <access>read-write</access>
                            <enumeratedValues>
                                <enumeratedValue>
                                    <name>0</name>
                                    <description>Secure</description>
                                    <value>#0</value>
                                </enumeratedValue>
                                <enumeratedValue>
                                    <name>1</name>
                                    <description>Non Secure</description>
                                    <value>#1</value>
                                </enumeratedValue>
                            </enumeratedValues>
                        </field>
                        <field>
                            <name>NONSEC09</name>
                            <description>Non Secure Attribute bit 09</description>
                            <lsb>9</lsb>
                            <msb>9</msb>
                            <access>read-write</access>
                            <enumeratedValues>
                                <enumeratedValue>
                                    <name>0</name>
                                    <description>Secure</description>
                                    <value>#0</value>
                                </enumeratedValue>
                                <enumeratedValue>
                                    <name>1</name>
                                    <description>Non Secure</description>
                                    <value>#1</value>
                                </enumeratedValue>
                            </enumeratedValues>
                        </field>
                        <field>
                            <name>NONSEC11</name>
                            <description>Non Secure Attribute bit 11</description>
                            <lsb>11</lsb>
                            <msb>11</msb>
                            <access>read-write</access>
                            <enumeratedValues>
                                <enumeratedValue>
                                    <name>0</name>
                                    <description>Secure</description>
                                    <value>#0</value>
                                </enumeratedValue>
                                <enumeratedValue>
                                    <name>1</name>
                                    <description>Non Secure</description>
                                    <value>#1</value>
                                </enumeratedValue>
                            </enumeratedValues>
                        </field>
                        <field>
                            <name>NONSEC12</name>
                            <description>Non Secure Attribute bit 12</description>
                            <lsb>12</lsb>
                            <msb>12</msb>
                            <access>read-write</access>
                            <enumeratedValues>
                                <enumeratedValue>
                                    <name>0</name>
                                    <description>Secure</description>
                                    <value>#0</value>
                                </enumeratedValue>
                                <enumeratedValue>
                                    <name>1</name>
                                    <description>Non Secure</description>
                                    <value>#1</value>
                                </enumeratedValue>
                            </enumeratedValues>
                        </field>
                        <field>
                            <name>NONSEC13</name>
                            <description>Non Secure Attribute bit 13</description>
                            <lsb>13</lsb>
                            <msb>13</msb>
                            <access>read-write</access>
                            <enumeratedValues>
                                <enumeratedValue>
                                    <name>0</name>
                                    <description>Secure</description>
                                    <value>#0</value>
                                </enumeratedValue>
                                <enumeratedValue>
                                    <name>1</name>
                                    <description>Non Secure</description>
                                    <value>#1</value>
                                </enumeratedValue>
                            </enumeratedValues>
                        </field>
                        <field>
                            <name>NONSEC16</name>
                            <description>Non Secure Attribute bit 16</description>
                            <lsb>16</lsb>
                            <msb>16</msb>
                            <access>read-write</access>
                            <enumeratedValues>
                                <enumeratedValue>
                                    <name>0</name>
                                    <description>Secure</description>
                                    <value>#0</value>
                                </enumeratedValue>
                                <enumeratedValue>
                                    <name>1</name>
                                    <description>Non Secure</description>
                                    <value>#1</value>
                                </enumeratedValue>
                            </enumeratedValues>
                        </field>
                        <field>
                            <name>NONSEC17</name>
                            <description>Non Secure Attribute bit 17</description>
                            <lsb>17</lsb>
                            <msb>17</msb>
                            <access>read-write</access>
                            <enumeratedValues>
                                <enumeratedValue>
                                    <name>0</name>
                                    <description>Secure</description>
                                    <value>#0</value>
                                </enumeratedValue>
                                <enumeratedValue>
                                    <name>1</name>
                                    <description>Non Secure</description>
                                    <value>#1</value>
                                </enumeratedValue>
                            </enumeratedValues>
                        </field>
                        <field>
                            <name>NONSEC18</name>
                            <description>Non Secure Attribute bit 18</description>
                            <lsb>18</lsb>
                            <msb>18</msb>
                            <access>read-write</access>
                            <enumeratedValues>
                                <enumeratedValue>
                                    <name>0</name>
                                    <description>Secure</description>
                                    <value>#0</value>
                                </enumeratedValue>
                                <enumeratedValue>
                                    <name>1</name>
                                    <description>Non Secure</description>
                                    <value>#1</value>
                                </enumeratedValue>
                            </enumeratedValues>
                        </field>
                        <field>
                            <name>NONSEC21</name>
                            <description>Non Secure Attribute bit 21</description>
                            <lsb>21</lsb>
                            <msb>21</msb>
                            <access>read-write</access>
                            <enumeratedValues>
                                <enumeratedValue>
                                    <name>0</name>
                                    <description>Secure</description>
                                    <value>#0</value>
                                </enumeratedValue>
                                <enumeratedValue>
                                    <name>1</name>
                                    <description>Non Secure</description>
                                    <value>#1</value>
                                </enumeratedValue>
                            </enumeratedValues>
                        </field>
                        <field>
                            <name>NONSEC22</name>
                            <description>Non Secure Attribute bit 22</description>
                            <lsb>22</lsb>
                            <msb>22</msb>
                            <access>read-write</access>
                            <enumeratedValues>
                                <enumeratedValue>
                                    <name>0</name>
                                    <description>Secure</description>
                                    <value>#0</value>
                                </enumeratedValue>
                                <enumeratedValue>
                                    <name>1</name>
                                    <description>Non Secure</description>
                                    <value>#1</value>
                                </enumeratedValue>
                            </enumeratedValues>
                        </field>
                        <field>
                            <name>NONSEC26</name>
                            <description>Non Secure Attribute bit 26</description>
                            <lsb>26</lsb>
                            <msb>26</msb>
                            <access>read-write</access>
                            <enumeratedValues>
                                <enumeratedValue>
                                    <name>0</name>
                                    <description>Secure</description>
                                    <value>#0</value>
                                </enumeratedValue>
                                <enumeratedValue>
                                    <name>1</name>
                                    <description>Non Secure</description>
                                    <value>#1</value>
                                </enumeratedValue>
                            </enumeratedValues>
                        </field>
                    </fields>
                </register>
                <register>
                    <name>RSTSAR</name>
                    <description>Reset Security Attribution Register</description>
                    <addressOffset>0x3C4</addressOffset>
                    <size>32</size>
                    <access>read-write</access>
                    <resetValue>0x00000000</resetValue>
                    <resetMask>0xffffffff</resetMask>
                    <fields>
                        <field>
                            <name>NONSEC0</name>
                            <description>Non-secure Attribute bit 0</description>
                            <lsb>0</lsb>
                            <msb>0</msb>
                            <access>read-write</access>
                            <enumeratedValues>
                                <enumeratedValue>
                                    <name>0</name>
                                    <description>Secure</description>
                                    <value>#0</value>
                                </enumeratedValue>
                                <enumeratedValue>
                                    <name>1</name>
                                    <description>Non-secure</description>
                                    <value>#1</value>
                                </enumeratedValue>
                            </enumeratedValues>
                        </field>
                        <field>
                            <name>NONSEC1</name>
                            <description>Non-secure Attribute bit 1</description>
                            <lsb>1</lsb>
                            <msb>1</msb>
                            <access>read-write</access>
                            <enumeratedValues>
                                <enumeratedValue>
                                    <name>0</name>
                                    <description>Secure</description>
                                    <value>#0</value>
                                </enumeratedValue>
                                <enumeratedValue>
                                    <name>1</name>
                                    <description>Non-secure</description>
                                    <value>#1</value>
                                </enumeratedValue>
                            </enumeratedValues>
                        </field>
                        <field>
                            <name>NONSEC2</name>
                            <description>Non-secure Attribute bit 2</description>
                            <lsb>2</lsb>
                            <msb>2</msb>
                            <access>read-write</access>
                            <enumeratedValues>
                                <enumeratedValue>
                                    <name>0</name>
                                    <description>Secure</description>
                                    <value>#0</value>
                                </enumeratedValue>
                                <enumeratedValue>
                                    <name>1</name>
                                    <description>Non-secure</description>
                                    <value>#1</value>
                                </enumeratedValue>
                            </enumeratedValues>
                        </field>
                    </fields>
                </register>
                <register>
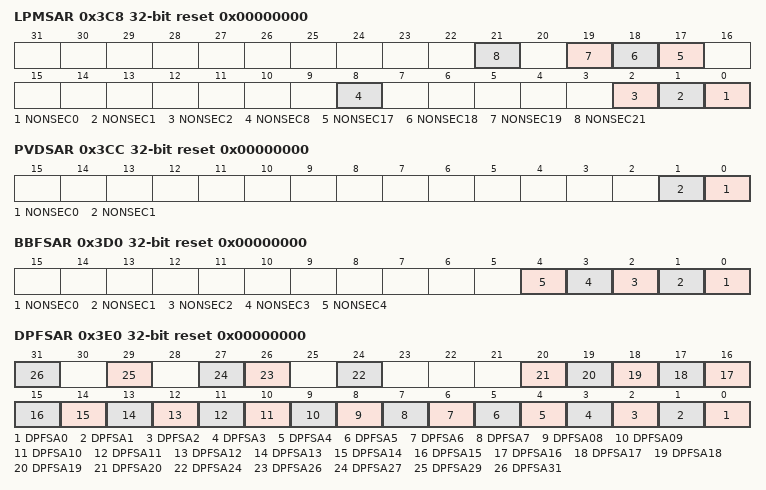
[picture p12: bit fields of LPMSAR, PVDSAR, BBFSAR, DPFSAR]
                    <name>LPMSAR</name>
                    <description>Low Power Mode Security Attribution Register</description>
                    <addressOffset>0x3C8</addressOffset>
                    <size>32</size>
                    <access>read-write</access>
                    <resetValue>0x00000000</resetValue>
                    <resetMask>0xffffffff</resetMask>
                    <fields>
                        <field>
                            <name>NONSEC0</name>
                            <description>Non-secure Attribute bit 0</description>
                            <lsb>0</lsb>
                            <msb>0</msb>
                            <access>read-write</access>
                            <enumeratedValues>
                                <enumeratedValue>
                                    <name>0</name>
                                    <description>Secure</description>
                                    <value>#0</value>
                                </enumeratedValue>
                                <enumeratedValue>
                                    <name>1</name>
                                    <description>Non-secure</description>
                                    <value>#1</value>
                                </enumeratedValue>
                            </enumeratedValues>
                        </field>
                        <field>
                            <name>NONSEC1</name>
                            <description>Non-secure Attribute bit 1</description>
                            <lsb>1</lsb>
                            <msb>1</msb>
                            <access>read-write</access>
                            <enumeratedValues>
                                <enumeratedValue>
                                    <name>0</name>
                                    <description>Secure</description>
                                    <value>#0</value>
                                </enumeratedValue>
                                <enumeratedValue>
                                    <name>1</name>
                                    <description>Non-secure</description>
                                    <value>#1</value>
                                </enumeratedValue>
                            </enumeratedValues>
                        </field>
                        <field>
                            <name>NONSEC2</name>
                            <description>Non-secure Attribute bit 2</description>
                            <lsb>2</lsb>
                            <msb>2</msb>
                            <access>read-write</access>
                            <enumeratedValues>
                                <enumeratedValue>
                                    <name>0</name>
                                    <description>Secure</description>
                                    <value>#0</value>
                                </enumeratedValue>
                                <enumeratedValue>
                                    <name>1</name>
                                    <description>Non-secure</description>
                                    <value>#1</value>
                                </enumeratedValue>
                            </enumeratedValues>
                        </field>
                        <field>
                            <name>NONSEC8</name>
                            <description>Non-secure Attribute bit 8</description>
                            <lsb>8</lsb>
                            <msb>8</msb>
                            <access>read-write</access>
                            <enumeratedValues>
                                <enumeratedValue>
                                    <name>0</name>
                                    <description>Secure</description>
                                    <value>#0</value>
                                </enumeratedValue>
                                <enumeratedValue>
                                    <name>1</name>
                                    <description>Non-secure</description>
                                    <value>#1</value>
                                </enumeratedValue>
                            </enumeratedValues>
                        </field>
                        <field>
                            <name>NONSEC17</name>
                            <description>Non-secure Attribute bit 17</description>
                            <lsb>17</lsb>
                            <msb>17</msb>
                            <access>read-write</access>
                            <enumeratedValues>
                                <enumeratedValue>
                                    <name>0</name>
                                    <description>Secure</description>
                                    <value>#0</value>
                                </enumeratedValue>
                                <enumeratedValue>
                                    <name>1</name>
                                    <description>Non-secure</description>
                                    <value>#1</value>
                                </enumeratedValue>
                            </enumeratedValues>
                        </field>
                        <field>
                            <name>NONSEC18</name>
                            <description>Non-secure Attribute bit 18</description>
                            <lsb>18</lsb>
                            <msb>18</msb>
                            <access>read-write</access>
                            <enumeratedValues>
                                <enumeratedValue>
                                    <name>0</name>
                                    <description>Secure</description>
                                    <value>#0</value>
                                </enumeratedValue>
                                <enumeratedValue>
                                    <name>1</name>
                                    <description>Non-secure</description>
                                    <value>#1</value>
                                </enumeratedValue>
                            </enumeratedValues>
                        </field>
                        <field>
                            <name>NONSEC19</name>
                            <description>Non-secure Attribute bit 19</description>
                            <lsb>19</lsb>
                            <msb>19</msb>
                            <access>read-write</access>
                            <enumeratedValues>
                                <enumeratedValue>
                                    <name>0</name>
                                    <description>Secure</description>
                                    <value>#0</value>
                                </enumeratedValue>
                                <enumeratedValue>
                                    <name>1</name>
                                    <description>Non-secure</description>
                                    <value>#1</value>
                                </enumeratedValue>
                            </enumeratedValues>
                        </field>
                        <field>
                            <name>NONSEC21</name>
                            <description>Non-secure Attribute bit 21</description>
                            <lsb>21</lsb>
                            <msb>21</msb>
                            <access>read-write</access>
                            <enumeratedValues>
                                <enumeratedValue>
                                    <name>0</name>
                                    <description>Secure</description>
                                    <value>#0</value>
                                </enumeratedValue>
                                <enumeratedValue>
                                    <name>1</name>
                                    <description>Non-secure</description>
                                    <value>#1</value>
                                </enumeratedValue>
                            </enumeratedValues>
                        </field>
                    </fields>
                </register>
                <register>
                    <name>PVDSAR</name>
                    <description>Programable Voltage Detection Security Attribution Register</description>
                    <addressOffset>0x3CC</addressOffset>
                    <size>32</size>
                    <access>read-write</access>
                    <resetValue>0x00000000</resetValue>
                    <resetMask>0xffffffff</resetMask>
                    <fields>
                        <field>
                            <name>NONSEC0</name>
                            <description>Non Secure Attribute bit 0</description>
                            <lsb>0</lsb>
                            <msb>0</msb>
                            <access>read-write</access>
                            <enumeratedValues>
                                <enumeratedValue>
                                    <name>0</name>
                                    <description>Secure</description>
                                    <value>#0</value>
                                </enumeratedValue>
                                <enumeratedValue>
                                    <name>1</name>
                                    <description>Non Secure</description>
                                    <value>#1</value>
                                </enumeratedValue>
                            </enumeratedValues>
                        </field>
                        <field>
                            <name>NONSEC1</name>
                            <description>Non Secure Attribute bit 1</description>
                            <lsb>1</lsb>
                            <msb>1</msb>
                            <access>read-write</access>
                            <enumeratedValues>
                                <enumeratedValue>
                                    <name>0</name>
                                    <description>Secure</description>
                                    <value>#0</value>
                                </enumeratedValue>
                                <enumeratedValue>
                                    <name>1</name>
                                    <description>Non Secure</description>
                                    <value>#1</value>
                                </enumeratedValue>
                            </enumeratedValues>
                        </field>
                    </fields>
                </register>
                <register>
                    <name>BBFSAR</name>
                    <description>Battery Backup Function Security Attribute Register</description>
                    <addressOffset>0x3D0</addressOffset>
                    <size>32</size>
                    <access>read-write</access>
                    <resetValue>0x00000000</resetValue>
                    <resetMask>0xffffffff</resetMask>
                    <fields>
                        <field>
                            <name>NONSEC0</name>
                            <description>Non Secure Attribute bit 0</description>
                            <lsb>0</lsb>
                            <msb>0</msb>
                            <access>read-write</access>
                            <enumeratedValues>
                                <enumeratedValue>
                                    <name>0</name>
                                    <description>Secure</description>
                                    <value>#0</value>
                                </enumeratedValue>
                                <enumeratedValue>
                                    <name>1</name>
                                    <description>Non Secure</description>
                                    <value>#1</value>
                                </enumeratedValue>
                            </enumeratedValues>
                        </field>
                        <field>
                            <name>NONSEC1</name>
                            <description>Non Secure Attribute bit 1</description>
                            <lsb>1</lsb>
                            <msb>1</msb>
                            <access>read-write</access>
                            <enumeratedValues>
                                <enumeratedValue>
                                    <name>0</name>
                                    <description>Secure</description>
                                    <value>#0</value>
                                </enumeratedValue>
                                <enumeratedValue>
                                    <name>1</name>
                                    <description>Non Secure</description>
                                    <value>#1</value>
                                </enumeratedValue>
                            </enumeratedValues>
                        </field>
                        <field>
                            <name>NONSEC2</name>
                            <description>Non Secure Attribute bit 2</description>
                            <lsb>2</lsb>
                            <msb>2</msb>
                            <access>read-write</access>
                            <enumeratedValues>
                                <enumeratedValue>
                                    <name>0</name>
                                    <description>Secure</description>
                                    <value>#0</value>
                                </enumeratedValue>
                                <enumeratedValue>
                                    <name>1</name>
                                    <description>Non Secure</description>
                                    <value>#1</value>
                                </enumeratedValue>
                            </enumeratedValues>
                        </field>
                        <field>
                            <name>NONSEC3</name>
                            <description>Non Secure Attribute bit 3</description>
                            <lsb>3</lsb>
                            <msb>3</msb>
                            <access>read-write</access>
                            <enumeratedValues>
                                <enumeratedValue>
                                    <name>0</name>
                                    <description>Secure</description>
                                    <value>#0</value>
                                </enumeratedValue>
                                <enumeratedValue>
                                    <name>1</name>
                                    <description>Non Secure</description>
                                    <value>#1</value>
                                </enumeratedValue>
                            </enumeratedValues>
                        </field>
                        <field>
                            <name>NONSEC4</name>
                            <description>Non Secure Attribute bit 4</description>
                            <lsb>4</lsb>
                            <msb>4</msb>
                            <access>read-write</access>
                            <enumeratedValues>
                                <enumeratedValue>
                                    <name>0</name>
                                    <description>Secure</description>
                                    <value>#0</value>
                                </enumeratedValue>
                                <enumeratedValue>
                                    <name>1</name>
                                    <description>Non Secure</description>
                                    <value>#1</value>
                                </enumeratedValue>
                            </enumeratedValues>
                        </field>
                    </fields>
                </register>
                <register>
                    <name>PGCSAR</name>
                    <description>Power Gating Control Security Attribution Register</description>
                    <addressOffset>0x3D8</addressOffset>
                    <size>32</size>
                    <access>read-write</access>
                    <resetValue>0x00000000</resetValue>
                    <resetMask>0xffffffff</resetMask>
                    <fields>
                        <field>
                            <name>NONSEC1</name>
                            <description>Non-secure Attribute bit 1</description>
                            <lsb>1</lsb>
                            <msb>1</msb>
                            <access>read-write</access>
                            <enumeratedValues>
                                <enumeratedValue>
                                    <name>0</name>
                                    <description>Secure</description>
                                    <value>#0</value>
                                </enumeratedValue>
                                <enumeratedValue>
                                    <name>1</name>
                                    <description>Non-secure</description>
                                    <value>#1</value>
                                </enumeratedValue>
                            </enumeratedValues>
                        </field>
                    </fields>
                </register>
                <register>
                    <name>DPFSAR</name>
                    <description>Deep Software Standby Interrupt Factor Security Attribution Register</description>
                    <addressOffset>0x3E0</addressOffset>
                    <size>32</size>
                    <access>read-write</access>
                    <resetValue>0x00000000</resetValue>
                    <resetMask>0xffffffff</resetMask>
                    <fields>
                        <field>
                            <name>DPFSA0</name>
                            <description>Deep Software Standby Interrupt Factor Security Attribute bit n (n = 0 to 7)</description>
                            <lsb>0</lsb>
                            <msb>0</msb>
                            <access>read-write</access>
                            <enumeratedValues>
                                <enumeratedValue>
                                    <name>0</name>
                                    <description>Secure</description>
                                    <value>#0</value>
                                </enumeratedValue>
                                <enumeratedValue>
                                    <name>1</name>
                                    <description>Non-secure</description>
                                    <value>#1</value>
                                </enumeratedValue>
                            </enumeratedValues>
                        </field>
                        <field>
                            <name>DPFSA1</name>
                            <description>Deep Software Standby Interrupt Factor Security Attribute bit n (n = 0 to 7)</description>
                            <lsb>1</lsb>
                            <msb>1</msb>
                            <access>read-write</access>
                            <enumeratedValues>
                                <enumeratedValue>
                                    <name>0</name>
                                    <description>Secure</description>
                                    <value>#0</value>
                                </enumeratedValue>
                                <enumeratedValue>
                                    <name>1</name>
                                    <description>Non-secure</description>
                                    <value>#1</value>
                                </enumeratedValue>
                            </enumeratedValues>
                        </field>
                        <field>
                            <name>DPFSA2</name>
                            <description>Deep Software Standby Interrupt Factor Security Attribute bit n (n = 0 to 7)</description>
                            <lsb>2</lsb>
                            <msb>2</msb>
                            <access>read-write</access>
                            <enumeratedValues>
                                <enumeratedValue>
                                    <name>0</name>
                                    <description>Secure</description>
                                    <value>#0</value>
                                </enumeratedValue>
                                <enumeratedValue>
                                    <name>1</name>
                                    <description>Non-secure</description>
                                    <value>#1</value>
                                </enumeratedValue>
                            </enumeratedValues>
                        </field>
                        <field>
                            <name>DPFSA3</name>
                            <description>Deep Software Standby Interrupt Factor Security Attribute bit n (n = 0 to 7)</description>
                            <lsb>3</lsb>
                            <msb>3</msb>
                            <access>read-write</access>
                            <enumeratedValues>
                                <enumeratedValue>
                                    <name>0</name>
                                    <description>Secure</description>
                                    <value>#0</value>
                                </enumeratedValue>
                                <enumeratedValue>
                                    <name>1</name>
                                    <description>Non-secure</description>
                                    <value>#1</value>
                                </enumeratedValue>
                            </enumeratedValues>
                        </field>
                        <field>
                            <name>DPFSA4</name>
                            <description>Deep Software Standby Interrupt Factor Security Attribute bit n (n = 0 to 7)</description>
                            <lsb>4</lsb>
                            <msb>4</msb>
                            <access>read-write</access>
                            <enumeratedValues>
                                <enumeratedValue>
                                    <name>0</name>
                                    <description>Secure</description>
                                    <value>#0</value>
                                </enumeratedValue>
                                <enumeratedValue>
                                    <name>1</name>
                                    <description>Non-secure</description>
                                    <value>#1</value>
                                </enumeratedValue>
                            </enumeratedValues>
                        </field>
                        <field>
                            <name>DPFSA5</name>
                            <description>Deep Software Standby Interrupt Factor Security Attribute bit n (n = 0 to 7)</description>
                            <lsb>5</lsb>
                            <msb>5</msb>
                            <access>read-write</access>
                            <enumeratedValues>
                                <enumeratedValue>
                                    <name>0</name>
                                    <description>Secure</description>
                                    <value>#0</value>
                                </enumeratedValue>
                                <enumeratedValue>
                                    <name>1</name>
                                    <description>Non-secure</description>
                                    <value>#1</value>
                                </enumeratedValue>
                            </enumeratedValues>
                        </field>
                        <field>
                            <name>DPFSA6</name>
                            <description>Deep Software Standby Interrupt Factor Security Attribute bit n (n = 0 to 7)</description>
                            <lsb>6</lsb>
                            <msb>6</msb>
                            <access>read-write</access>
                            <enumeratedValues>
                                <enumeratedValue>
                                    <name>0</name>
                                    <description>Secure</description>
                                    <value>#0</value>
                                </enumeratedValue>
                                <enumeratedValue>
                                    <name>1</name>
                                    <description>Non-secure</description>
                                    <value>#1</value>
                                </enumeratedValue>
                            </enumeratedValues>
                        </field>
                        <field>
                            <name>DPFSA7</name>
                            <description>Deep Software Standby Interrupt Factor Security Attribute bit n (n = 0 to 7)</description>
                            <lsb>7</lsb>
                            <msb>7</msb>
                            <access>read-write</access>
                            <enumeratedValues>
                                <enumeratedValue>
                                    <name>0</name>
                                    <description>Secure</description>
                                    <value>#0</value>
                                </enumeratedValue>
                                <enumeratedValue>
                                    <name>1</name>
                                    <description>Non-secure</description>
                                    <value>#1</value>
                                </enumeratedValue>
                            </enumeratedValues>
                        </field>
                        <field>
                            <name>DPFSA08</name>
                            <description>Deep Software Standby Interrupt Factor Security Attribute bit n (n = 8 to 15)</description>
                            <lsb>8</lsb>
                            <msb>8</msb>
                            <access>read-write</access>
                            <enumeratedValues>
                                <enumeratedValue>
                                    <name>0</name>
                                    <description>Secure</description>
                                    <value>#0</value>
                                </enumeratedValue>
                                <enumeratedValue>
                                    <name>1</name>
                                    <description>Non-secure</description>
                                    <value>#1</value>
                                </enumeratedValue>
                            </enumeratedValues>
                        </field>
                        <field>
                            <name>DPFSA09</name>
                            <description>Deep Software Standby Interrupt Factor Security Attribute bit n (n = 8 to 15)</description>
                            <lsb>9</lsb>
                            <msb>9</msb>
                            <access>read-write</access>
                            <enumeratedValues>
                                <enumeratedValue>
                                    <name>0</name>
                                    <description>Secure</description>
                                    <value>#0</value>
                                </enumeratedValue>
                                <enumeratedValue>
                                    <name>1</name>
                                    <description>Non-secure</description>
                                    <value>#1</value>
                                </enumeratedValue>
                            </enumeratedValues>
                        </field>
                        <field>
                            <name>DPFSA10</name>
                            <description>Deep Software Standby Interrupt Factor Security Attribute bit n (n = 8 to 15)</description>
                            <lsb>10</lsb>
                            <msb>10</msb>
                            <access>read-write</access>
                            <enumeratedValues>
                                <enumeratedValue>
                                    <name>0</name>
                                    <description>Secure</description>
                                    <value>#0</value>
                                </enumeratedValue>
                                <enumeratedValue>
                                    <name>1</name>
                                    <description>Non-secure</description>
                                    <value>#1</value>
                                </enumeratedValue>
                            </enumeratedValues>
                        </field>
                        <field>
                            <name>DPFSA11</name>
                            <description>Deep Software Standby Interrupt Factor Security Attribute bit n (n = 8 to 15)</description>
                            <lsb>11</lsb>
                            <msb>11</msb>
                            <access>read-write</access>
                            <enumeratedValues>
                                <enumeratedValue>
                                    <name>0</name>
                                    <description>Secure</description>
                                    <value>#0</value>
                                </enumeratedValue>
                                <enumeratedValue>
                                    <name>1</name>
                                    <description>Non-secure</description>
                                    <value>#1</value>
                                </enumeratedValue>
                            </enumeratedValues>
                        </field>
                        <field>
                            <name>DPFSA12</name>
                            <description>Deep Software Standby Interrupt Factor Security Attribute bit n (n = 8 to 15)</description>
                            <lsb>12</lsb>
                            <msb>12</msb>
                            <access>read-write</access>
                            <enumeratedValues>
                                <enumeratedValue>
                                    <name>0</name>
                                    <description>Secure</description>
                                    <value>#0</value>
                                </enumeratedValue>
                                <enumeratedValue>
                                    <name>1</name>
                                    <description>Non-secure</description>
                                    <value>#1</value>
                                </enumeratedValue>
                            </enumeratedValues>
                        </field>
                        <field>
                            <name>DPFSA13</name>
                            <description>Deep Software Standby Interrupt Factor Security Attribute bit n (n = 8 to 15)</description>
                            <lsb>13</lsb>
                            <msb>13</msb>
                            <access>read-write</access>
                            <enumeratedValues>
                                <enumeratedValue>
                                    <name>0</name>
                                    <description>Secure</description>
                                    <value>#0</value>
                                </enumeratedValue>
                                <enumeratedValue>
                                    <name>1</name>
                                    <description>Non-secure</description>
                                    <value>#1</value>
                                </enumeratedValue>
                            </enumeratedValues>
                        </field>
                        <field>
                            <name>DPFSA14</name>
                            <description>Deep Software Standby Interrupt Factor Security Attribute bit n (n = 8 to 15)</description>
                            <lsb>14</lsb>
                            <msb>14</msb>
                            <access>read-write</access>
                            <enumeratedValues>
                                <enumeratedValue>
                                    <name>0</name>
                                    <description>Secure</description>
                                    <value>#0</value>
                                </enumeratedValue>
                                <enumeratedValue>
                                    <name>1</name>
                                    <description>Non-secure</description>
                                    <value>#1</value>
                                </enumeratedValue>
                            </enumeratedValues>
                        </field>
                        <field>
                            <name>DPFSA15</name>
                            <description>Deep Software Standby Interrupt Factor Security Attribute bit n (n = 8 to 15)</description>
                            <lsb>15</lsb>
                            <msb>15</msb>
                            <access>read-write</access>
                            <enumeratedValues>
                                <enumeratedValue>
                                    <name>0</name>
                                    <description>Secure</description>
                                    <value>#0</value>
                                </enumeratedValue>
                                <enumeratedValue>
                                    <name>1</name>
                                    <description>Non-secure</description>
                                    <value>#1</value>
                                </enumeratedValue>
                            </enumeratedValues>
                        </field>
                        <field>
                            <name>DPFSA16</name>
                            <description>Deep Software Standby Interrupt Factor Security Attribute bit 16</description>
                            <lsb>16</lsb>
                            <msb>16</msb>
                            <access>read-write</access>
                            <enumeratedValues>
                                <enumeratedValue>
                                    <name>0</name>
                                    <description>Secure</description>
                                    <value>#0</value>
                                </enumeratedValue>
                                <enumeratedValue>
                                    <name>1</name>
                                    <description>Non-secure</description>
                                    <value>#1</value>
                                </enumeratedValue>
                            </enumeratedValues>
                        </field>
                        <field>
                            <name>DPFSA17</name>
                            <description>Deep Software Standby Interrupt Factor Security Attribute bit 17</description>
                            <lsb>17</lsb>
                            <msb>17</msb>
                            <access>read-write</access>
                            <enumeratedValues>
                                <enumeratedValue>
                                    <name>0</name>
                                    <description>Secure</description>
                                    <value>#0</value>
                                </enumeratedValue>
                                <enumeratedValue>
                                    <name>1</name>
                                    <description>Non-secure</description>
                                    <value>#1</value>
                                </enumeratedValue>
                            </enumeratedValues>
                        </field>
                        <field>
                            <name>DPFSA18</name>
                            <description>Deep Software Standby Interrupt Factor Security Attribute bit 18</description>
                            <lsb>18</lsb>
                            <msb>18</msb>
                            <access>read-write</access>
                            <enumeratedValues>
                                <enumeratedValue>
                                    <name>0</name>
                                    <description>Secure</description>
                                    <value>#0</value>
                                </enumeratedValue>
                                <enumeratedValue>
                                    <name>1</name>
                                    <description>Non-secure</description>
                                    <value>#1</value>
                                </enumeratedValue>
                            </enumeratedValues>
                        </field>
                        <field>
                            <name>DPFSA19</name>
                            <description>Deep Software Standby Interrupt Factor Security Attribute bit 19</description>
                            <lsb>19</lsb>
                            <msb>19</msb>
                            <access>read-write</access>
                            <enumeratedValues>
                                <enumeratedValue>
                                    <name>0</name>
                                    <description>Secure</description>
                                    <value>#0</value>
                                </enumeratedValue>
                                <enumeratedValue>
                                    <name>1</name>
                                    <description>Non-secure</description>
                                    <value>#1</value>
                                </enumeratedValue>
                            </enumeratedValues>
                        </field>
                        <field>
                            <name>DPFSA20</name>
                            <description>Deep Software Standby Interrupt Factor Security Attribute bit 20</description>
                            <lsb>20</lsb>
                            <msb>20</msb>
                            <access>read-write</access>
                            <enumeratedValues>
                                <enumeratedValue>
                                    <name>0</name>
                                    <description>Secure</description>
                                    <value>#0</value>
                                </enumeratedValue>
                                <enumeratedValue>
                                    <name>1</name>
                                    <description>Non-secure</description>
                                    <value>#1</value>
                                </enumeratedValue>
                            </enumeratedValues>
                        </field>
                        <field>
                            <name>DPFSA24</name>
                            <description>Deep Software Standby Interrupt Factor Security Attribute bit 24</description>
                            <lsb>24</lsb>
                            <msb>24</msb>
                            <access>read-write</access>
                            <enumeratedValues>
                                <enumeratedValue>
                                    <name>0</name>
                                    <description>Secure</description>
                                    <value>#0</value>
                                </enumeratedValue>
                                <enumeratedValue>
                                    <name>1</name>
                                    <description>Non-secure</description>
                                    <value>#1</value>
                                </enumeratedValue>
                            </enumeratedValues>
                        </field>
                        <field>
                            <name>DPFSA26</name>
                            <description>Deep Software Standby Interrupt Factor Security Attribute bit 26</description>
                            <lsb>26</lsb>
                            <msb>26</msb>
                            <access>read-write</access>
                            <enumeratedValues>
                                <enumeratedValue>
                                    <name>0</name>
                                    <description>Secure</description>
                                    <value>#0</value>
                                </enumeratedValue>
                                <enumeratedValue>
                                    <name>1</name>
                                    <description>Non-secure</description>
                                    <value>#1</value>
                                </enumeratedValue>
                            </enumeratedValues>
                        </field>
                        <field>
                            <name>DPFSA27</name>
                            <description>Deep Software Standby Interrupt Factor Security Attribute bit 27</description>
                            <lsb>27</lsb>
                            <msb>27</msb>
                            <access>read-write</access>
                            <enumeratedValues>
                                <enumeratedValue>
                                    <name>0</name>
                                    <description>Secure</description>
                                    <value>#0</value>
                                </enumeratedValue>
                                <enumeratedValue>
                                    <name>1</name>
                                    <description>Non-secure</description>
                                    <value>#1</value>
                                </enumeratedValue>
                            </enumeratedValues>
                        </field>
                        <field>
                            <name>DPFSA29</name>
                            <description>Deep Software Standby Interrupt Factor Security Attribute bit 29</description>
                            <lsb>29</lsb>
                            <msb>29</msb>
                            <access>read-write</access>
                            <enumeratedValues>
                                <enumeratedValue>
                                    <name>0</name>
                                    <description>Secure</description>
                                    <value>#0</value>
                                </enumeratedValue>
                                <enumeratedValue>
                                    <name>1</name>
                                    <description>Non-secure</description>
                                    <value>#1</value>
                                </enumeratedValue>
                            </enumeratedValues>
                        </field>
                        <field>
                            <name>DPFSA31</name>
                            <description>Deep Software Standby Interrupt Factor Security Attribute bit 31</description>
                            <lsb>31</lsb>
                            <msb>31</msb>
                            <access>read-write</access>
                            <enumeratedValues>
                                <enumeratedValue>
                                    <name>0</name>
                                    <description>Secure</description>
                                    <value>#0</value>
                                </enumeratedValue>
                                <enumeratedValue>
                                    <name>1</name>
                                    <description>Non-secure</description>
                                    <value>#1</value>
                                </enumeratedValue>
                            </enumeratedValues>
                        </field>
                    </fields>
                </register>
                <register>
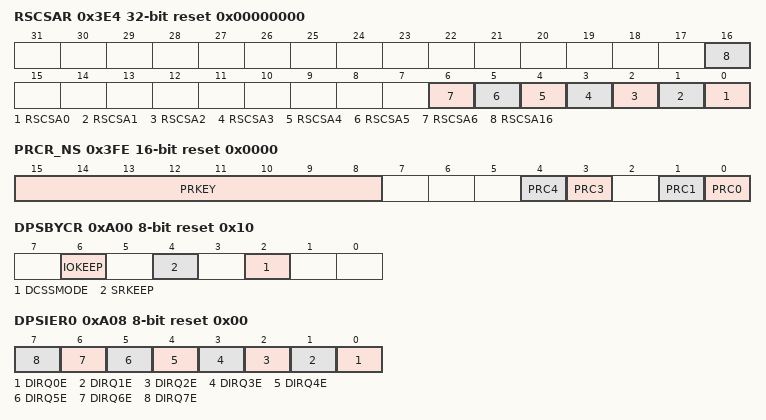
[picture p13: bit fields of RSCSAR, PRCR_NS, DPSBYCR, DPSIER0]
                    <name>RSCSAR</name>
                    <description>RAM Standby Control Security Attribution Register</description>
                    <addressOffset>0x3E4</addressOffset>
                    <size>32</size>
                    <access>read-write</access>
                    <resetValue>0x00000000</resetValue>
                    <resetMask>0xffffffff</resetMask>
                    <fields>
                        <field>
                            <name>RSCSA0</name>
                            <description>Unnecessary Circuit Control Security Attribution bit n (n = 0 to 1)</description>
                            <lsb>0</lsb>
                            <msb>0</msb>
                            <access>read-write</access>
                            <enumeratedValues>
                                <enumeratedValue>
                                    <name>0</name>
                                    <description>Secure</description>
                                    <value>#0</value>
                                </enumeratedValue>
                                <enumeratedValue>
                                    <name>1</name>
                                    <description>Non-secure</description>
                                    <value>#1</value>
                                </enumeratedValue>
                            </enumeratedValues>
                        </field>
                        <field>
                            <name>RSCSA1</name>
                            <description>Unnecessary Circuit Control Security Attribution bit n (n = 0 to 1)</description>
                            <lsb>1</lsb>
                            <msb>1</msb>
                            <access>read-write</access>
                            <enumeratedValues>
                                <enumeratedValue>
                                    <name>0</name>
                                    <description>Secure</description>
                                    <value>#0</value>
                                </enumeratedValue>
                                <enumeratedValue>
                                    <name>1</name>
                                    <description>Non-secure</description>
                                    <value>#1</value>
                                </enumeratedValue>
                            </enumeratedValues>
                        </field>
                        <field>
                            <name>RSCSA2</name>
                            <description>RAM Standby Control Security Attribute bit n (n = 2 to 6)</description>
                            <lsb>2</lsb>
                            <msb>2</msb>
                            <access>read-write</access>
                            <enumeratedValues>
                                <enumeratedValue>
                                    <name>0</name>
                                    <description>Secure</description>
                                    <value>#0</value>
                                </enumeratedValue>
                                <enumeratedValue>
                                    <name>1</name>
                                    <description>Non-secure</description>
                                    <value>#1</value>
                                </enumeratedValue>
                            </enumeratedValues>
                        </field>
                        <field>
                            <name>RSCSA3</name>
                            <description>RAM Standby Control Security Attribute bit n (n = 2 to 6)</description>
                            <lsb>3</lsb>
                            <msb>3</msb>
                            <access>read-write</access>
                            <enumeratedValues>
                                <enumeratedValue>
                                    <name>0</name>
                                    <description>Secure</description>
                                    <value>#0</value>
                                </enumeratedValue>
                                <enumeratedValue>
                                    <name>1</name>
                                    <description>Non-secure</description>
                                    <value>#1</value>
                                </enumeratedValue>
                            </enumeratedValues>
                        </field>
                        <field>
                            <name>RSCSA4</name>
                            <description>RAM Standby Control Security Attribute bit n (n = 2 to 6)</description>
                            <lsb>4</lsb>
                            <msb>4</msb>
                            <access>read-write</access>
                            <enumeratedValues>
                                <enumeratedValue>
                                    <name>0</name>
                                    <description>Secure</description>
                                    <value>#0</value>
                                </enumeratedValue>
                                <enumeratedValue>
                                    <name>1</name>
                                    <description>Non-secure</description>
                                    <value>#1</value>
                                </enumeratedValue>
                            </enumeratedValues>
                        </field>
                        <field>
                            <name>RSCSA5</name>
                            <description>RAM Standby Control Security Attribute bit n (n = 2 to 6)</description>
                            <lsb>5</lsb>
                            <msb>5</msb>
                            <access>read-write</access>
                            <enumeratedValues>
                                <enumeratedValue>
                                    <name>0</name>
                                    <description>Secure</description>
                                    <value>#0</value>
                                </enumeratedValue>
                                <enumeratedValue>
                                    <name>1</name>
                                    <description>Non-secure</description>
                                    <value>#1</value>
                                </enumeratedValue>
                            </enumeratedValues>
                        </field>
                        <field>
                            <name>RSCSA6</name>
                            <description>RAM Standby Control Security Attribute bit n (n = 2 to 6)</description>
                            <lsb>6</lsb>
                            <msb>6</msb>
                            <access>read-write</access>
                            <enumeratedValues>
                                <enumeratedValue>
                                    <name>0</name>
                                    <description>Secure</description>
                                    <value>#0</value>
                                </enumeratedValue>
                                <enumeratedValue>
                                    <name>1</name>
                                    <description>Non-secure</description>
                                    <value>#1</value>
                                </enumeratedValue>
                            </enumeratedValues>
                        </field>
                        <field>
                            <name>RSCSA16</name>
                            <description>RAM Standby Control Security Attribute bit n (n = 16)</description>
                            <lsb>16</lsb>
                            <msb>16</msb>
                            <access>read-write</access>
                            <enumeratedValues>
                                <enumeratedValue>
                                    <name>0</name>
                                    <description>Secure</description>
                                    <value>#0</value>
                                </enumeratedValue>
                                <enumeratedValue>
                                    <name>1</name>
                                    <description>Non-secure</description>
                                    <value>#1</value>
                                </enumeratedValue>
                            </enumeratedValues>
                        </field>
                    </fields>
                </register>
                <register>
                    <name>PRCR_NS</name>
                    <description>Protect Register for Non-secure (PRCR_NS)</description>
                    <addressOffset>0x3FE</addressOffset>
                    <size>16</size>
                    <access>read-write</access>
                    <resetValue>0x0000</resetValue>
                    <resetMask>0xffff</resetMask>
                    <fields>
                        <field>
                            <name>PRC0</name>
                            <description>Enable writing to the registers related to the clock generation circuit</description>
                            <lsb>0</lsb>
                            <msb>0</msb>
                            <access>read-write</access>
                            <enumeratedValues>
                                <enumeratedValue>
                                    <name>0</name>
                                    <description>Disable writes</description>
                                    <value>#0</value>
                                </enumeratedValue>
                                <enumeratedValue>
                                    <name>1</name>
                                    <description>Enable writes</description>
                                    <value>#1</value>
                                </enumeratedValue>
                            </enumeratedValues>
                        </field>
                        <field>
                            <name>PRC1</name>
                            <description>Enable writing to the registers related to the low power modes, and the battery backup function</description>
                            <lsb>1</lsb>
                            <msb>1</msb>
                            <access>read-write</access>
                            <enumeratedValues>
                                <enumeratedValue>
                                    <name>0</name>
                                    <description>Disable writes</description>
                                    <value>#0</value>
                                </enumeratedValue>
                                <enumeratedValue>
                                    <name>1</name>
                                    <description>Enable writes</description>
                                    <value>#1</value>
                                </enumeratedValue>
                            </enumeratedValues>
                        </field>
                        <field>
                            <name>PRC3</name>
                            <description>Enable writing to the registers related to the PVD</description>
                            <lsb>3</lsb>
                            <msb>3</msb>
                            <access>read-write</access>
                            <enumeratedValues>
                                <enumeratedValue>
                                    <name>0</name>
                                    <description>Disable writes</description>
                                    <value>#0</value>
                                </enumeratedValue>
                                <enumeratedValue>
                                    <name>1</name>
                                    <description>Enable writes</description>
                                    <value>#1</value>
                                </enumeratedValue>
                            </enumeratedValues>
                        </field>
                        <field>
                            <name>PRC4</name>
                            <lsb>4</lsb>
                            <msb>4</msb>
                            <access>read-write</access>
                            <enumeratedValues>
                                <enumeratedValue>
                                    <name>0</name>
                                    <description>Disable writes</description>
                                    <value>#0</value>
                                </enumeratedValue>
                                <enumeratedValue>
                                    <name>1</name>
                                    <description>Enable writes</description>
                                    <value>#1</value>
                                </enumeratedValue>
                            </enumeratedValues>
                        </field>
                        <field>
                            <name>PRKEY</name>
                            <description>0xA5: Enables writing to the PRCR_NS register.</description>
                            <lsb>8</lsb>
                            <msb>15</msb>
                            <access>write-only</access>
                        </field>
                    </fields>
                </register>
                <register>
                    <name>LOCOCR</name>
                    <description>Low-Speed On-Chip Oscillator Control Register</description>
                    <addressOffset>0x400</addressOffset>
                    <size>8</size>
                    <access>read-write</access>
                    <resetValue>0x00</resetValue>
                    <resetMask>0xff</resetMask>
                    <fields>
                        <field>
                            <name>LCSTP</name>
                            <description>LOCO Stop</description>
                            <lsb>0</lsb>
                            <msb>0</msb>
                            <access>read-write</access>
                            <enumeratedValues>
                                <enumeratedValue>
                                    <name>0</name>
                                    <description>Operate the LOCO clock</description>
                                    <value>#0</value>
                                </enumeratedValue>
                                <enumeratedValue>
                                    <name>1</name>
                                    <description>Stop the LOCO clock</description>
                                    <value>#1</value>
                                </enumeratedValue>
                            </enumeratedValues>
                        </field>
                    </fields>
                </register>
                <register>
                    <name>LOCOUTCR</name>
                    <description>LOCO User Trimming Control Register</description>
                    <addressOffset>0x402</addressOffset>
                    <size>8</size>
                    <access>read-write</access>
                    <resetValue>0x00</resetValue>
                    <resetMask>0xff</resetMask>
                    <fields>
                        <field>
                            <name>LOCOUTRM</name>
                            <description>LOCO User Trimming</description>
                            <lsb>0</lsb>
                            <msb>7</msb>
                            <access>read-write</access>
                        </field>
                    </fields>
                </register>
                <register>
                    <name>DPSBYCR</name>
                    <description>Deep Software Standby Control Register</description>
                    <addressOffset>0xA00</addressOffset>
                    <size>8</size>
                    <access>read-write</access>
                    <resetValue>0x10</resetValue>
                    <resetMask>0xff</resetMask>
                    <fields>
                        <field>
                            <name>DCSSMODE</name>
                            <lsb>2</lsb>
                            <msb>2</msb>
                            <access>read-write</access>
                            <enumeratedValues>
                                <enumeratedValue>
                                    <name>0</name>
                                    <description>When the Deep Software Standby mode is canceled, the time required to recover is the standard time.</description>
                                    <value>#0</value>
                                </enumeratedValue>
                                <enumeratedValue>
                                    <name>1</name>
                                    <description>When the Deep Software Standby mode is canceled, the time required to recover is shortened.</description>
                                    <value>#1</value>
                                </enumeratedValue>
                            </enumeratedValues>
                        </field>
                        <field>
                            <name>SRKEEP</name>
                            <description>Standby SRAM Retention</description>
                            <lsb>4</lsb>
                            <msb>4</msb>
                            <access>read-write</access>
                            <enumeratedValues>
                                <enumeratedValue>
                                    <name>0</name>
                                    <description>When entering the Software Standby mode or the Deep Software Standby mode 1, the contents of Standby SRAM are not kept.</description>
                                    <value>#0</value>
                                </enumeratedValue>
                                <enumeratedValue>
                                    <name>1</name>
                                    <description>When entering the Software Standby mode or the Deep Software Standby mode 1, the contents of Standby SRAM are kept.</description>
                                    <value>#1</value>
                                </enumeratedValue>
                            </enumeratedValues>
                        </field>
                        <field>
                            <name>IOKEEP</name>
                            <description>I/O Port Rentention</description>
                            <lsb>6</lsb>
                            <msb>6</msb>
                            <access>read-write</access>
                            <enumeratedValues>
                                <enumeratedValue>
                                    <name>0</name>
                                    <description>When the Deep Software Standby mode is canceled, the I/O ports are in the reset state.</description>
                                    <value>#0</value>
                                </enumeratedValue>
                                <enumeratedValue>
                                    <name>1</name>
                                    <description>When the Deep Software Standby mode is canceled, the I/O ports are in the same state as in the Deep Software Standby mode.</description>
                                    <value>#1</value>
                                </enumeratedValue>
                            </enumeratedValues>
                        </field>
                    </fields>
                </register>
                <register>
                    <name>DPSWCR</name>
                    <description>Deep Software Standby Wait Control Register</description>
                    <addressOffset>0xA04</addressOffset>
                    <size>8</size>
                    <access>read-write</access>
                    <resetValue>0x0b</resetValue>
                    <resetMask>0xff</resetMask>
                    <fields>
                        <field>
                            <name>WTSTS</name>
                            <description>Deep Software Wait Standby Time Setting Bit</description>
                            <lsb>0</lsb>
                            <msb>7</msb>
                            <access>read-write</access>
                            <enumeratedValues>
                                <enumeratedValue>
                                    <name>0x0B</name>
                                    <description>Wait cycle for fast recovery</description>
                                    <value>0x0b</value>
                                </enumeratedValue>
                                <enumeratedValue>
                                    <name>0x9A</name>
                                    <description>Wait cycle for slow recovery</description>
                                    <value>0x9a</value>
                                </enumeratedValue>
                                <enumeratedValue>
                                    <name>Others</name>
                                    <description>Setting prohibited</description>
                                    <isDefault>true</isDefault>
                                </enumeratedValue>
                            </enumeratedValues>
                        </field>
                    </fields>
                </register>
                <register>
                    <name>DPSIER0</name>
                    <description>Deep Software Standby Interrupt Enable Register 0</description>
                    <addressOffset>0xA08</addressOffset>
                    <size>8</size>
                    <access>read-write</access>
                    <resetValue>0x00</resetValue>
                    <resetMask>0xff</resetMask>
                    <fields>
                        <field>
                            <name>DIRQ0E</name>
                            <description>IRQ0-DS Pin Enable</description>
                            <lsb>0</lsb>
                            <msb>0</msb>
                            <access>read-write</access>
                            <enumeratedValues>
                                <enumeratedValue>
                                    <name>0</name>
                                    <description>Canceling Deep Software Standby mode is disabled</description>
                                    <value>#0</value>
                                </enumeratedValue>
                                <enumeratedValue>
                                    <name>1</name>
                                    <description>Canceling Deep Software Standby mode is enabled</description>
                                    <value>#1</value>
                                </enumeratedValue>
                            </enumeratedValues>
                        </field>
                        <field>
                            <name>DIRQ1E</name>
                            <description>IRQ1-DS Pin Enable</description>
                            <lsb>1</lsb>
                            <msb>1</msb>
                            <access>read-write</access>
                            <enumeratedValues>
                                <enumeratedValue>
                                    <name>0</name>
                                    <description>Canceling Deep Software Standby mode is disabled</description>
                                    <value>#0</value>
                                </enumeratedValue>
                                <enumeratedValue>
                                    <name>1</name>
                                    <description>Canceling Deep Software Standby mode is enabled</description>
                                    <value>#1</value>
                                </enumeratedValue>
                            </enumeratedValues>
                        </field>
                        <field>
                            <name>DIRQ2E</name>
                            <description>IRQ2-DS Pin Enable</description>
                            <lsb>2</lsb>
                            <msb>2</msb>
                            <access>read-write</access>
                            <enumeratedValues>
                                <enumeratedValue>
                                    <name>0</name>
                                    <description>Canceling Deep Software Standby mode is disabled</description>
                                    <value>#0</value>
                                </enumeratedValue>
                                <enumeratedValue>
                                    <name>1</name>
                                    <description>Canceling Deep Software Standby mode is enabled</description>
                                    <value>#1</value>
                                </enumeratedValue>
                            </enumeratedValues>
                        </field>
                        <field>
                            <name>DIRQ3E</name>
                            <description>IRQ3-DS Pin Enable</description>
                            <lsb>3</lsb>
                            <msb>3</msb>
                            <access>read-write</access>
                            <enumeratedValues>
                                <enumeratedValue>
                                    <name>0</name>
                                    <description>Canceling Deep Software Standby mode is disabled</description>
                                    <value>#0</value>
                                </enumeratedValue>
                                <enumeratedValue>
                                    <name>1</name>
                                    <description>Canceling Deep Software Standby mode is enabled</description>
                                    <value>#1</value>
                                </enumeratedValue>
                            </enumeratedValues>
                        </field>
                        <field>
                            <name>DIRQ4E</name>
                            <description>IRQ4-DS Pin Enable</description>
                            <lsb>4</lsb>
                            <msb>4</msb>
                            <access>read-write</access>
                            <enumeratedValues>
                                <enumeratedValue>
                                    <name>0</name>
                                    <description>Canceling Deep Software Standby mode is disabled</description>
                                    <value>#0</value>
                                </enumeratedValue>
                                <enumeratedValue>
                                    <name>1</name>
                                    <description>Canceling Deep Software Standby mode is enabled</description>
                                    <value>#1</value>
                                </enumeratedValue>
                            </enumeratedValues>
                        </field>
                        <field>
                            <name>DIRQ5E</name>
                            <description>IRQ5-DS Pin Enable</description>
                            <lsb>5</lsb>
                            <msb>5</msb>
                            <access>read-write</access>
                            <enumeratedValues>
                                <enumeratedValue>
                                    <name>0</name>
                                    <description>Canceling Deep Software Standby mode is disabled</description>
                                    <value>#0</value>
                                </enumeratedValue>
                                <enumeratedValue>
                                    <name>1</name>
                                    <description>Canceling Deep Software Standby mode is enabled</description>
                                    <value>#1</value>
                                </enumeratedValue>
                            </enumeratedValues>
                        </field>
                        <field>
                            <name>DIRQ6E</name>
                            <description>IRQ6-DS Pin Enable</description>
                            <lsb>6</lsb>
                            <msb>6</msb>
                            <access>read-write</access>
                            <enumeratedValues>
                                <enumeratedValue>
                                    <name>0</name>
                                    <description>Canceling Deep Software Standby mode is disabled</description>
                                    <value>#0</value>
                                </enumeratedValue>
                                <enumeratedValue>
                                    <name>1</name>
                                    <description>Canceling Deep Software Standby mode is enabled</description>
                                    <value>#1</value>
                                </enumeratedValue>
                            </enumeratedValues>
                        </field>
                        <field>
                            <name>DIRQ7E</name>
                            <description>IRQ7-DS Pin Enable</description>
                            <lsb>7</lsb>
                            <msb>7</msb>
                            <access>read-write</access>
                            <enumeratedValues>
                                <enumeratedValue>
                                    <name>0</name>
                                    <description>Canceling Deep Software Standby mode is disabled</description>
                                    <value>#0</value>
                                </enumeratedValue>
                                <enumeratedValue>
                                    <name>1</name>
                                    <description>Canceling Deep Software Standby mode is enabled</description>
                                    <value>#1</value>
                                </enumeratedValue>
                            </enumeratedValues>
                        </field>
                    </fields>
                </register>
                <register>
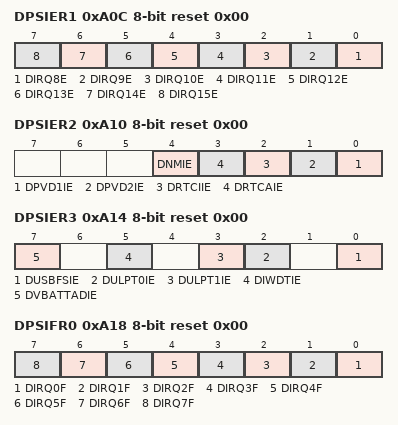
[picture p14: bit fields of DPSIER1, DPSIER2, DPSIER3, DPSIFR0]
                    <name>DPSIER1</name>
                    <description>Deep Software Standby Interrupt Enable Register 1</description>
                    <addressOffset>0xA0C</addressOffset>
                    <size>8</size>
                    <access>read-write</access>
                    <resetValue>0x00</resetValue>
                    <resetMask>0xff</resetMask>
                    <fields>
                        <field>
                            <name>DIRQ8E</name>
                            <description>IRQ8-DS Pin Enable</description>
                            <lsb>0</lsb>
                            <msb>0</msb>
                            <access>read-write</access>
                            <enumeratedValues>
                                <enumeratedValue>
                                    <name>0</name>
                                    <description>Canceling Deep Software Standby mode is disabled</description>
                                    <value>#0</value>
                                </enumeratedValue>
                                <enumeratedValue>
                                    <name>1</name>
                                    <description>Canceling Deep Software Standby mode is enabled</description>
                                    <value>#1</value>
                                </enumeratedValue>
                            </enumeratedValues>
                        </field>
                        <field>
                            <name>DIRQ9E</name>
                            <description>IRQ9-DS Pin Enable</description>
                            <lsb>1</lsb>
                            <msb>1</msb>
                            <access>read-write</access>
                            <enumeratedValues>
                                <enumeratedValue>
                                    <name>0</name>
                                    <description>Canceling Deep Software Standby mode is disabled</description>
                                    <value>#0</value>
                                </enumeratedValue>
                                <enumeratedValue>
                                    <name>1</name>
                                    <description>Canceling Deep Software Standby mode is enabled</description>
                                    <value>#1</value>
                                </enumeratedValue>
                            </enumeratedValues>
                        </field>
                        <field>
                            <name>DIRQ10E</name>
                            <description>IRQ10-DS Pin Enable</description>
                            <lsb>2</lsb>
                            <msb>2</msb>
                            <access>read-write</access>
                            <enumeratedValues>
                                <enumeratedValue>
                                    <name>0</name>
                                    <description>Canceling Deep Software Standby mode is disabled</description>
                                    <value>#0</value>
                                </enumeratedValue>
                                <enumeratedValue>
                                    <name>1</name>
                                    <description>Canceling Deep Software Standby mode is enabled</description>
                                    <value>#1</value>
                                </enumeratedValue>
                            </enumeratedValues>
                        </field>
                        <field>
                            <name>DIRQ11E</name>
                            <description>IRQ11-DS Pin Enable</description>
                            <lsb>3</lsb>
                            <msb>3</msb>
                            <access>read-write</access>
                            <enumeratedValues>
                                <enumeratedValue>
                                    <name>0</name>
                                    <description>Canceling Deep Software Standby mode is disabled</description>
                                    <value>#0</value>
                                </enumeratedValue>
                                <enumeratedValue>
                                    <name>1</name>
                                    <description>Canceling Deep Software Standby mode is enabled</description>
                                    <value>#1</value>
                                </enumeratedValue>
                            </enumeratedValues>
                        </field>
                        <field>
                            <name>DIRQ12E</name>
                            <description>IRQ12-DS Pin Enable</description>
                            <lsb>4</lsb>
                            <msb>4</msb>
                            <access>read-write</access>
                            <enumeratedValues>
                                <enumeratedValue>
                                    <name>0</name>
                                    <description>Canceling Deep Software Standby mode is disabled</description>
                                    <value>#0</value>
                                </enumeratedValue>
                                <enumeratedValue>
                                    <name>1</name>
                                    <description>Canceling Deep Software Standby mode is enabled</description>
                                    <value>#1</value>
                                </enumeratedValue>
                            </enumeratedValues>
                        </field>
                        <field>
                            <name>DIRQ13E</name>
                            <description>IRQ13-DS Pin Enable</description>
                            <lsb>5</lsb>
                            <msb>5</msb>
                            <access>read-write</access>
                            <enumeratedValues>
                                <enumeratedValue>
                                    <name>0</name>
                                    <description>Canceling Deep Software Standby mode is disabled</description>
                                    <value>#0</value>
                                </enumeratedValue>
                                <enumeratedValue>
                                    <name>1</name>
                                    <description>Canceling Deep Software Standby mode is enabled</description>
                                    <value>#1</value>
                                </enumeratedValue>
                            </enumeratedValues>
                        </field>
                        <field>
                            <name>DIRQ14E</name>
                            <description>IRQ14-DS Pin Enable</description>
                            <lsb>6</lsb>
                            <msb>6</msb>
                            <access>read-write</access>
                            <enumeratedValues>
                                <enumeratedValue>
                                    <name>0</name>
                                    <description>Canceling Deep Software Standby mode is disabled</description>
                                    <value>#0</value>
                                </enumeratedValue>
                                <enumeratedValue>
                                    <name>1</name>
                                    <description>Canceling Deep Software Standby mode is enabled</description>
                                    <value>#1</value>
                                </enumeratedValue>
                            </enumeratedValues>
                        </field>
                        <field>
                            <name>DIRQ15E</name>
                            <description>IRQ15-DS Pin Enable</description>
                            <lsb>7</lsb>
                            <msb>7</msb>
                            <access>read-write</access>
                            <enumeratedValues>
                                <enumeratedValue>
                                    <name>0</name>
                                    <description>Canceling Deep Software Standby mode is disabled</description>
                                    <value>#0</value>
                                </enumeratedValue>
                                <enumeratedValue>
                                    <name>1</name>
                                    <description>Canceling Deep Software Standby mode is enabled</description>
                                    <value>#1</value>
                                </enumeratedValue>
                            </enumeratedValues>
                        </field>
                    </fields>
                </register>
                <register>
                    <name>DPSIER2</name>
                    <description>Deep Software Standby Interrupt Enable Register 2</description>
                    <addressOffset>0xA10</addressOffset>
                    <size>8</size>
                    <access>read-write</access>
                    <resetValue>0x00</resetValue>
                    <resetMask>0xff</resetMask>
                    <fields>
                        <field>
                            <name>DPVD1IE</name>
                            <description>PVD1 Deep Software Standby Cancel Signal Enable</description>
                            <lsb>0</lsb>
                            <msb>0</msb>
                            <access>read-write</access>
                            <enumeratedValues>
                                <enumeratedValue>
                                    <name>0</name>
                                    <description>Canceling Deep Software Standby mode is disabled</description>
                                    <value>#0</value>
                                </enumeratedValue>
                                <enumeratedValue>
                                    <name>1</name>
                                    <description>Canceling Deep Software Standby mode is enabled</description>
                                    <value>#1</value>
                                </enumeratedValue>
                            </enumeratedValues>
                        </field>
                        <field>
                            <name>DPVD2IE</name>
                            <description>PVD2 Deep Software Standby Cancel Signal Enable</description>
                            <lsb>1</lsb>
                            <msb>1</msb>
                            <access>read-write</access>
                            <enumeratedValues>
                                <enumeratedValue>
                                    <name>0</name>
                                    <description>Canceling Deep Software Standby mode is disabled</description>
                                    <value>#0</value>
                                </enumeratedValue>
                                <enumeratedValue>
                                    <name>1</name>
                                    <description>Canceling Deep Software Standby mode is enabled</description>
                                    <value>#1</value>
                                </enumeratedValue>
                            </enumeratedValues>
                        </field>
                        <field>
                            <name>DRTCIIE</name>
                            <description>RTC Interval interrupt Deep Software Standby Cancel Signal Enable</description>
                            <lsb>2</lsb>
                            <msb>2</msb>
                            <access>read-write</access>
                            <enumeratedValues>
                                <enumeratedValue>
                                    <name>0</name>
                                    <description>Canceling Deep Software Standby mode is disabled</description>
                                    <value>#0</value>
                                </enumeratedValue>
                                <enumeratedValue>
                                    <name>1</name>
                                    <description>Canceling Deep Software Standby mode is enabled</description>
                                    <value>#1</value>
                                </enumeratedValue>
                            </enumeratedValues>
                        </field>
                        <field>
                            <name>DRTCAIE</name>
                            <description>RTC Alarm interrupt Deep Software Standby Cancel Signal Enable</description>
                            <lsb>3</lsb>
                            <msb>3</msb>
                            <access>read-write</access>
                            <enumeratedValues>
                                <enumeratedValue>
                                    <name>0</name>
                                    <description>Canceling Deep Software Standby mode is disabled</description>
                                    <value>#0</value>
                                </enumeratedValue>
                                <enumeratedValue>
                                    <name>1</name>
                                    <description>Canceling Deep Software Standby mode is enabled</description>
                                    <value>#1</value>
                                </enumeratedValue>
                            </enumeratedValues>
                        </field>
                        <field>
                            <name>DNMIE</name>
                            <description>NMI Pin Deep Software Standby Cancel Signal Enable</description>
                            <lsb>4</lsb>
                            <msb>4</msb>
                            <access>read-write</access>
                            <enumeratedValues>
                                <enumeratedValue>
                                    <name>0</name>
                                    <description>Canceling Deep Software Standby mode is disabled</description>
                                    <value>#0</value>
                                </enumeratedValue>
                                <enumeratedValue>
                                    <name>1</name>
                                    <description>Canceling Deep Software Standby mode is enabled</description>
                                    <value>#1</value>
                                </enumeratedValue>
                            </enumeratedValues>
                        </field>
                    </fields>
                </register>
                <register>
                    <name>DPSIER3</name>
                    <description>Deep Software Standby Interrupt Enable Register 3</description>
                    <addressOffset>0xA14</addressOffset>
                    <size>8</size>
                    <access>read-write</access>
                    <resetValue>0x00</resetValue>
                    <resetMask>0xff</resetMask>
                    <fields>
                        <field>
                            <name>DUSBFSIE</name>
                            <description>USBFS Suspend/Resume Deep Software Standby Cancel Signal Enable</description>
                            <lsb>0</lsb>
                            <msb>0</msb>
                            <access>read-write</access>
                            <enumeratedValues>
                                <enumeratedValue>
                                    <name>0</name>
                                    <description>Canceling Deep Software Standby mode is disabled</description>
                                    <value>#0</value>
                                </enumeratedValue>
                                <enumeratedValue>
                                    <name>1</name>
                                    <description>Canceling Deep Software Standby mode is enabled</description>
                                    <value>#1</value>
                                </enumeratedValue>
                            </enumeratedValues>
                        </field>
                        <field>
                            <name>DULPT0IE</name>
                            <description>ULPT0 Overflow Deep Software Standby Cancel Signal Enable</description>
                            <lsb>2</lsb>
                            <msb>2</msb>
                            <access>read-write</access>
                            <enumeratedValues>
                                <enumeratedValue>
                                    <name>0</name>
                                    <description>Canceling Deep Software Standby mode is disabled</description>
                                    <value>#0</value>
                                </enumeratedValue>
                                <enumeratedValue>
                                    <name>1</name>
                                    <description>Canceling Deep Software Standby mode is enabled</description>
                                    <value>#1</value>
                                </enumeratedValue>
                            </enumeratedValues>
                        </field>
                        <field>
                            <name>DULPT1IE</name>
                            <description>ULPT1 Overflow Deep Software Standby Cancel Signal Enable</description>
                            <lsb>3</lsb>
                            <msb>3</msb>
                            <access>read-write</access>
                            <enumeratedValues>
                                <enumeratedValue>
                                    <name>0</name>
                                    <description>Canceling Deep Software Standby mode is disabled</description>
                                    <value>#0</value>
                                </enumeratedValue>
                                <enumeratedValue>
                                    <name>1</name>
                                    <description>Canceling Deep Software Standby mode is enabled</description>
                                    <value>#1</value>
                                </enumeratedValue>
                            </enumeratedValues>
                        </field>
                        <field>
                            <name>DIWDTIE</name>
                            <description>IWDT Underflow Deep Software Standby Cancel Signal Enable</description>
                            <lsb>5</lsb>
                            <msb>5</msb>
                            <access>read-write</access>
                            <enumeratedValues>
                                <enumeratedValue>
                                    <name>0</name>
                                    <description>Canceling Deep Software Standby mode is disabled</description>
                                    <value>#0</value>
                                </enumeratedValue>
                                <enumeratedValue>
                                    <name>1</name>
                                    <description>Canceling Deep Software Standby mode is enabled</description>
                                    <value>#1</value>
                                </enumeratedValue>
                            </enumeratedValues>
                        </field>
                        <field>
                            <name>DVBATTADIE</name>
                            <description>VBATT Tamper Detection Deep Software Standby Cancel Signal Enable</description>
                            <lsb>7</lsb>
                            <msb>7</msb>
                            <access>read-write</access>
                            <enumeratedValues>
                                <enumeratedValue>
                                    <name>0</name>
                                    <description>Canceling Deep Software Standby mode is disabled</description>
                                    <value>#0</value>
                                </enumeratedValue>
                                <enumeratedValue>
                                    <name>1</name>
                                    <description>Canceling Deep Software Standby mode is enabled</description>
                                    <value>#1</value>
                                </enumeratedValue>
                            </enumeratedValues>
                        </field>
                    </fields>
                </register>
                <register>
                    <name>DPSIFR0</name>
                    <description>Deep Software Standby Interrupt Flag Register 0</description>
                    <addressOffset>0xA18</addressOffset>
                    <size>8</size>
                    <access>read-write</access>
                    <resetValue>0x00</resetValue>
                    <resetMask>0xff</resetMask>
                    <fields>
                        <field>
                            <name>DIRQ0F</name>
                            <description>IRQ0-DS Pin Deep Software Standby Cancel Flag</description>
                            <lsb>0</lsb>
                            <msb>0</msb>
                            <access>read-write</access>
                            <enumeratedValues>
                                <enumeratedValue>
                                    <name>0</name>
                                    <description>The cancel request is not generated</description>
                                    <value>#0</value>
                                </enumeratedValue>
                                <enumeratedValue>
                                    <name>1</name>
                                    <description>The cancel request is generated</description>
                                    <value>#1</value>
                                </enumeratedValue>
                            </enumeratedValues>
                        </field>
                        <field>
                            <name>DIRQ1F</name>
                            <description>IRQ1-DS Pin Deep Software Standby Cancel Flag</description>
                            <lsb>1</lsb>
                            <msb>1</msb>
                            <access>read-write</access>
                            <enumeratedValues>
                                <enumeratedValue>
                                    <name>0</name>
                                    <description>The cancel request is not generated</description>
                                    <value>#0</value>
                                </enumeratedValue>
                                <enumeratedValue>
                                    <name>1</name>
                                    <description>The cancel request is generated</description>
                                    <value>#1</value>
                                </enumeratedValue>
                            </enumeratedValues>
                        </field>
                        <field>
                            <name>DIRQ2F</name>
                            <description>IRQ2-DS Pin Deep Software Standby Cancel Flag</description>
                            <lsb>2</lsb>
                            <msb>2</msb>
                            <access>read-write</access>
                            <enumeratedValues>
                                <enumeratedValue>
                                    <name>0</name>
                                    <description>The cancel request is not generated</description>
                                    <value>#0</value>
                                </enumeratedValue>
                                <enumeratedValue>
                                    <name>1</name>
                                    <description>The cancel request is generated</description>
                                    <value>#1</value>
                                </enumeratedValue>
                            </enumeratedValues>
                        </field>
                        <field>
                            <name>DIRQ3F</name>
                            <description>IRQ3-DS Pin Deep Software Standby Cancel Flag</description>
                            <lsb>3</lsb>
                            <msb>3</msb>
                            <access>read-write</access>
                            <enumeratedValues>
                                <enumeratedValue>
                                    <name>0</name>
                                    <description>The cancel request is not generated</description>
                                    <value>#0</value>
                                </enumeratedValue>
                                <enumeratedValue>
                                    <name>1</name>
                                    <description>The cancel request is generated</description>
                                    <value>#1</value>
                                </enumeratedValue>
                            </enumeratedValues>
                        </field>
                        <field>
                            <name>DIRQ4F</name>
                            <description>IRQ4-DS Pin Deep Software Standby Cancel Flag</description>
                            <lsb>4</lsb>
                            <msb>4</msb>
                            <access>read-write</access>
                            <enumeratedValues>
                                <enumeratedValue>
                                    <name>0</name>
                                    <description>The cancel request is not generated</description>
                                    <value>#0</value>
                                </enumeratedValue>
                                <enumeratedValue>
                                    <name>1</name>
                                    <description>The cancel request is generated</description>
                                    <value>#1</value>
                                </enumeratedValue>
                            </enumeratedValues>
                        </field>
                        <field>
                            <name>DIRQ5F</name>
                            <description>IRQ5-DS Pin Deep Software Standby Cancel Flag</description>
                            <lsb>5</lsb>
                            <msb>5</msb>
                            <access>read-write</access>
                            <enumeratedValues>
                                <enumeratedValue>
                                    <name>0</name>
                                    <description>The cancel request is not generated</description>
                                    <value>#0</value>
                                </enumeratedValue>
                                <enumeratedValue>
                                    <name>1</name>
                                    <description>The cancel request is generated</description>
                                    <value>#1</value>
                                </enumeratedValue>
                            </enumeratedValues>
                        </field>
                        <field>
                            <name>DIRQ6F</name>
                            <description>IRQ6-DS Pin Deep Software Standby Cancel Flag</description>
                            <lsb>6</lsb>
                            <msb>6</msb>
                            <access>read-write</access>
                            <enumeratedValues>
                                <enumeratedValue>
                                    <name>0</name>
                                    <description>The cancel request is not generated</description>
                                    <value>#0</value>
                                </enumeratedValue>
                                <enumeratedValue>
                                    <name>1</name>
                                    <description>The cancel request is generated</description>
                                    <value>#1</value>
                                </enumeratedValue>
                            </enumeratedValues>
                        </field>
                        <field>
                            <name>DIRQ7F</name>
                            <description>IRQ7-DS Pin Deep Software Standby Cancel Flag</description>
                            <lsb>7</lsb>
                            <msb>7</msb>
                            <access>read-write</access>
                            <enumeratedValues>
                                <enumeratedValue>
                                    <name>0</name>
                                    <description>The cancel request is not generated</description>
                                    <value>#0</value>
                                </enumeratedValue>
                                <enumeratedValue>
                                    <name>1</name>
                                    <description>The cancel request is generated</description>
                                    <value>#1</value>
                                </enumeratedValue>
                            </enumeratedValues>
                        </field>
                    </fields>
                </register>
                <register>
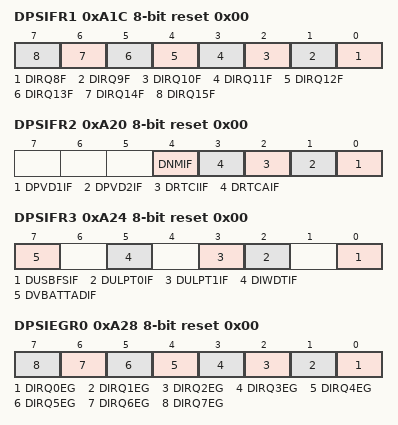
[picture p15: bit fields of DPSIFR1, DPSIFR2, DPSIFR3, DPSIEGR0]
                    <name>DPSIFR1</name>
                    <description>Deep Software Standby Interrupt Flag Register 1</description>
                    <addressOffset>0xA1C</addressOffset>
                    <size>8</size>
                    <access>read-write</access>
                    <resetValue>0x00</resetValue>
                    <resetMask>0xff</resetMask>
                    <fields>
                        <field>
                            <name>DIRQ8F</name>
                            <description>IRQ8-DS Pin Deep Software Standby Cancel Flag</description>
                            <lsb>0</lsb>
                            <msb>0</msb>
                            <access>read-write</access>
                            <enumeratedValues>
                                <enumeratedValue>
                                    <name>0</name>
                                    <description>The cancel request is not generated</description>
                                    <value>#0</value>
                                </enumeratedValue>
                                <enumeratedValue>
                                    <name>1</name>
                                    <description>The cancel request is generated</description>
                                    <value>#1</value>
                                </enumeratedValue>
                            </enumeratedValues>
                        </field>
                        <field>
                            <name>DIRQ9F</name>
                            <description>IRQ9-DS Pin Deep Software Standby Cancel Flag</description>
                            <lsb>1</lsb>
                            <msb>1</msb>
                            <access>read-write</access>
                            <enumeratedValues>
                                <enumeratedValue>
                                    <name>0</name>
                                    <description>The cancel request is not generated</description>
                                    <value>#0</value>
                                </enumeratedValue>
                                <enumeratedValue>
                                    <name>1</name>
                                    <description>The cancel request is generated</description>
                                    <value>#1</value>
                                </enumeratedValue>
                            </enumeratedValues>
                        </field>
                        <field>
                            <name>DIRQ10F</name>
                            <description>IRQ10-DS Pin Deep Software Standby Cancel Flag</description>
                            <lsb>2</lsb>
                            <msb>2</msb>
                            <access>read-write</access>
                            <enumeratedValues>
                                <enumeratedValue>
                                    <name>0</name>
                                    <description>The cancel request is not generated</description>
                                    <value>#0</value>
                                </enumeratedValue>
                                <enumeratedValue>
                                    <name>1</name>
                                    <description>The cancel request is generated</description>
                                    <value>#1</value>
                                </enumeratedValue>
                            </enumeratedValues>
                        </field>
                        <field>
                            <name>DIRQ11F</name>
                            <description>IRQ11-DS Pin Deep Software Standby Cancel Flag</description>
                            <lsb>3</lsb>
                            <msb>3</msb>
                            <access>read-write</access>
                            <enumeratedValues>
                                <enumeratedValue>
                                    <name>0</name>
                                    <description>The cancel request is not generated</description>
                                    <value>#0</value>
                                </enumeratedValue>
                                <enumeratedValue>
                                    <name>1</name>
                                    <description>The cancel request is generated</description>
                                    <value>#1</value>
                                </enumeratedValue>
                            </enumeratedValues>
                        </field>
                        <field>
                            <name>DIRQ12F</name>
                            <description>IRQ12-DS Pin Deep Software Standby Cancel Flag</description>
                            <lsb>4</lsb>
                            <msb>4</msb>
                            <access>read-write</access>
                            <enumeratedValues>
                                <enumeratedValue>
                                    <name>0</name>
                                    <description>The cancel request is not generated</description>
                                    <value>#0</value>
                                </enumeratedValue>
                                <enumeratedValue>
                                    <name>1</name>
                                    <description>The cancel request is generated</description>
                                    <value>#1</value>
                                </enumeratedValue>
                            </enumeratedValues>
                        </field>
                        <field>
                            <name>DIRQ13F</name>
                            <description>IRQ13-DS Pin Deep Software Standby Cancel Flag</description>
                            <lsb>5</lsb>
                            <msb>5</msb>
                            <access>read-write</access>
                            <enumeratedValues>
                                <enumeratedValue>
                                    <name>0</name>
                                    <description>The cancel request is not generated</description>
                                    <value>#0</value>
                                </enumeratedValue>
                                <enumeratedValue>
                                    <name>1</name>
                                    <description>The cancel request is generated</description>
                                    <value>#1</value>
                                </enumeratedValue>
                            </enumeratedValues>
                        </field>
                        <field>
                            <name>DIRQ14F</name>
                            <description>IRQ14-DS Pin Deep Software Standby Cancel Flag</description>
                            <lsb>6</lsb>
                            <msb>6</msb>
                            <access>read-write</access>
                            <enumeratedValues>
                                <enumeratedValue>
                                    <name>0</name>
                                    <description>The cancel request is not generated</description>
                                    <value>#0</value>
                                </enumeratedValue>
                                <enumeratedValue>
                                    <name>1</name>
                                    <description>The cancel request is generated</description>
                                    <value>#1</value>
                                </enumeratedValue>
                            </enumeratedValues>
                        </field>
                        <field>
                            <name>DIRQ15F</name>
                            <description>IRQ15-DS Pin Deep Software Standby Cancel Flag</description>
                            <lsb>7</lsb>
                            <msb>7</msb>
                            <access>read-write</access>
                            <enumeratedValues>
                                <enumeratedValue>
                                    <name>0</name>
                                    <description>The cancel request is not generated</description>
                                    <value>#0</value>
                                </enumeratedValue>
                                <enumeratedValue>
                                    <name>1</name>
                                    <description>The cancel request is generated</description>
                                    <value>#1</value>
                                </enumeratedValue>
                            </enumeratedValues>
                        </field>
                    </fields>
                </register>
                <register>
                    <name>DPSIFR2</name>
                    <description>Deep Software Standby Interrupt Flag Register 2</description>
                    <addressOffset>0xA20</addressOffset>
                    <size>8</size>
                    <access>read-write</access>
                    <resetValue>0x00</resetValue>
                    <resetMask>0xff</resetMask>
                    <fields>
                        <field>
                            <name>DPVD1IF</name>
                            <description>PVD1 Deep Software Standby Cancel Flag</description>
                            <lsb>0</lsb>
                            <msb>0</msb>
                            <access>read-write</access>
                            <enumeratedValues>
                                <enumeratedValue>
                                    <name>0</name>
                                    <description>The cancel request is not generated</description>
                                    <value>#0</value>
                                </enumeratedValue>
                                <enumeratedValue>
                                    <name>1</name>
                                    <description>The cancel request is generated</description>
                                    <value>#1</value>
                                </enumeratedValue>
                            </enumeratedValues>
                        </field>
                        <field>
                            <name>DPVD2IF</name>
                            <description>PVD2 Deep Software Standby Cancel Flag</description>
                            <lsb>1</lsb>
                            <msb>1</msb>
                            <access>read-write</access>
                            <enumeratedValues>
                                <enumeratedValue>
                                    <name>0</name>
                                    <description>The cancel request is not generated</description>
                                    <value>#0</value>
                                </enumeratedValue>
                                <enumeratedValue>
                                    <name>1</name>
                                    <description>The cancel request is generated</description>
                                    <value>#1</value>
                                </enumeratedValue>
                            </enumeratedValues>
                        </field>
                        <field>
                            <name>DRTCIIF</name>
                            <description>RTC Interval Interrupt Deep Software Standby Cancel Flag</description>
                            <lsb>2</lsb>
                            <msb>2</msb>
                            <access>read-write</access>
                            <enumeratedValues>
                                <enumeratedValue>
                                    <name>0</name>
                                    <description>The cancel request is not generated</description>
                                    <value>#0</value>
                                </enumeratedValue>
                                <enumeratedValue>
                                    <name>1</name>
                                    <description>The cancel request is generated</description>
                                    <value>#1</value>
                                </enumeratedValue>
                            </enumeratedValues>
                        </field>
                        <field>
                            <name>DRTCAIF</name>
                            <description>RTC Alarm Interrupt Deep Software Standby Cancel Flag</description>
                            <lsb>3</lsb>
                            <msb>3</msb>
                            <access>read-write</access>
                            <enumeratedValues>
                                <enumeratedValue>
                                    <name>0</name>
                                    <description>The cancel request is not generated</description>
                                    <value>#0</value>
                                </enumeratedValue>
                                <enumeratedValue>
                                    <name>1</name>
                                    <description>The cancel request is generated</description>
                                    <value>#1</value>
                                </enumeratedValue>
                            </enumeratedValues>
                        </field>
                        <field>
                            <name>DNMIF</name>
                            <description>NMI Pin Deep Software Standby Cancel Flag</description>
                            <lsb>4</lsb>
                            <msb>4</msb>
                            <access>read-write</access>
                            <enumeratedValues>
                                <enumeratedValue>
                                    <name>0</name>
                                    <description>The cancel request is not generated</description>
                                    <value>#0</value>
                                </enumeratedValue>
                                <enumeratedValue>
                                    <name>1</name>
                                    <description>The cancel request is generated</description>
                                    <value>#1</value>
                                </enumeratedValue>
                            </enumeratedValues>
                        </field>
                    </fields>
                </register>
                <register>
                    <name>DPSIFR3</name>
                    <description>Deep Software Standby Interrupt Flag Register 3</description>
                    <addressOffset>0xA24</addressOffset>
                    <size>8</size>
                    <access>read-write</access>
                    <resetValue>0x00</resetValue>
                    <resetMask>0xff</resetMask>
                    <fields>
                        <field>
                            <name>DUSBFSIF</name>
                            <description>USBFS Suspend/Resume Deep Software Standby Cancel Flag</description>
                            <lsb>0</lsb>
                            <msb>0</msb>
                            <access>read-write</access>
                            <enumeratedValues>
                                <enumeratedValue>
                                    <name>0</name>
                                    <description>The cancel request is not generated</description>
                                    <value>#0</value>
                                </enumeratedValue>
                                <enumeratedValue>
                                    <name>1</name>
                                    <description>The cancel request is generated</description>
                                    <value>#1</value>
                                </enumeratedValue>
                            </enumeratedValues>
                        </field>
                        <field>
                            <name>DULPT0IF</name>
                            <description>ULPT0 Overflow Deep Software Standby Cancel Flag</description>
                            <lsb>2</lsb>
                            <msb>2</msb>
                            <access>read-write</access>
                            <enumeratedValues>
                                <enumeratedValue>
                                    <name>0</name>
                                    <description>The cancel request is not generated</description>
                                    <value>#0</value>
                                </enumeratedValue>
                                <enumeratedValue>
                                    <name>1</name>
                                    <description>The cancel request is generated</description>
                                    <value>#1</value>
                                </enumeratedValue>
                            </enumeratedValues>
                        </field>
                        <field>
                            <name>DULPT1IF</name>
                            <description>ULPT1 Overflow Deep Software Standby Cancel Flag</description>
                            <lsb>3</lsb>
                            <msb>3</msb>
                            <access>read-write</access>
                            <enumeratedValues>
                                <enumeratedValue>
                                    <name>0</name>
                                    <description>The cancel request is not generated</description>
                                    <value>#0</value>
                                </enumeratedValue>
                                <enumeratedValue>
                                    <name>1</name>
                                    <description>The cancel request is generated</description>
                                    <value>#1</value>
                                </enumeratedValue>
                            </enumeratedValues>
                        </field>
                        <field>
                            <name>DIWDTIF</name>
                            <description>IWDT Underflow Deep Software Standby Cancel Flag</description>
                            <lsb>5</lsb>
                            <msb>5</msb>
                            <access>read-write</access>
                            <enumeratedValues>
                                <enumeratedValue>
                                    <name>0</name>
                                    <description>The cancel request is not generated</description>
                                    <value>#0</value>
                                </enumeratedValue>
                                <enumeratedValue>
                                    <name>1</name>
                                    <description>The cancel request is generated</description>
                                    <value>#1</value>
                                </enumeratedValue>
                            </enumeratedValues>
                        </field>
                        <field>
                            <name>DVBATTADIF</name>
                            <description>VBATT Tamper Detection Deep Software Standby Cancel Flag</description>
                            <lsb>7</lsb>
                            <msb>7</msb>
                            <access>read-write</access>
                            <enumeratedValues>
                                <enumeratedValue>
                                    <name>0</name>
                                    <description>The cancel request is not generated</description>
                                    <value>#0</value>
                                </enumeratedValue>
                                <enumeratedValue>
                                    <name>1</name>
                                    <description>The cancel request is generated</description>
                                    <value>#1</value>
                                </enumeratedValue>
                            </enumeratedValues>
                        </field>
                    </fields>
                </register>
                <register>
                    <name>DPSIEGR0</name>
                    <description>Deep Software Standby Interrupt Edge Register 0</description>
                    <addressOffset>0xA28</addressOffset>
                    <size>8</size>
                    <access>read-write</access>
                    <resetValue>0x00</resetValue>
                    <resetMask>0xff</resetMask>
                    <fields>
                        <field>
                            <name>DIRQ0EG</name>
                            <description>IRQ0-DS Pin Edge Select</description>
                            <lsb>0</lsb>
                            <msb>0</msb>
                            <access>read-write</access>
                            <enumeratedValues>
                                <enumeratedValue>
                                    <name>0</name>
                                    <description>A cancel request is generated at a falling edge</description>
                                    <value>#0</value>
                                </enumeratedValue>
                                <enumeratedValue>
                                    <name>1</name>
                                    <description>A cancel request is generated at a rising edge</description>
                                    <value>#1</value>
                                </enumeratedValue>
                            </enumeratedValues>
                        </field>
                        <field>
                            <name>DIRQ1EG</name>
                            <description>IRQ1-DS Pin Edge Select</description>
                            <lsb>1</lsb>
                            <msb>1</msb>
                            <access>read-write</access>
                            <enumeratedValues>
                                <enumeratedValue>
                                    <name>0</name>
                                    <description>A cancel request is generated at a falling edge</description>
                                    <value>#0</value>
                                </enumeratedValue>
                                <enumeratedValue>
                                    <name>1</name>
                                    <description>A cancel request is generated at a rising edge</description>
                                    <value>#1</value>
                                </enumeratedValue>
                            </enumeratedValues>
                        </field>
                        <field>
                            <name>DIRQ2EG</name>
                            <description>IRQ2-DS Pin Edge Select</description>
                            <lsb>2</lsb>
                            <msb>2</msb>
                            <access>read-write</access>
                            <enumeratedValues>
                                <enumeratedValue>
                                    <name>0</name>
                                    <description>A cancel request is generated at a falling edge</description>
                                    <value>#0</value>
                                </enumeratedValue>
                                <enumeratedValue>
                                    <name>1</name>
                                    <description>A cancel request is generated at a rising edge</description>
                                    <value>#1</value>
                                </enumeratedValue>
                            </enumeratedValues>
                        </field>
                        <field>
                            <name>DIRQ3EG</name>
                            <description>IRQ3-DS Pin Edge Select</description>
                            <lsb>3</lsb>
                            <msb>3</msb>
                            <access>read-write</access>
                            <enumeratedValues>
                                <enumeratedValue>
                                    <name>0</name>
                                    <description>A cancel request is generated at a falling edge</description>
                                    <value>#0</value>
                                </enumeratedValue>
                                <enumeratedValue>
                                    <name>1</name>
                                    <description>A cancel request is generated at a rising edge</description>
                                    <value>#1</value>
                                </enumeratedValue>
                            </enumeratedValues>
                        </field>
                        <field>
                            <name>DIRQ4EG</name>
                            <description>IRQ4-DS Pin Edge Select</description>
                            <lsb>4</lsb>
                            <msb>4</msb>
                            <access>read-write</access>
                            <enumeratedValues>
                                <enumeratedValue>
                                    <name>0</name>
                                    <description>A cancel request is generated at a falling edge</description>
                                    <value>#0</value>
                                </enumeratedValue>
                                <enumeratedValue>
                                    <name>1</name>
                                    <description>A cancel request is generated at a rising edge</description>
                                    <value>#1</value>
                                </enumeratedValue>
                            </enumeratedValues>
                        </field>
                        <field>
                            <name>DIRQ5EG</name>
                            <description>IRQ5-DS Pin Edge Select</description>
                            <lsb>5</lsb>
                            <msb>5</msb>
                            <access>read-write</access>
                            <enumeratedValues>
                                <enumeratedValue>
                                    <name>0</name>
                                    <description>A cancel request is generated at a falling edge</description>
                                    <value>#0</value>
                                </enumeratedValue>
                                <enumeratedValue>
                                    <name>1</name>
                                    <description>A cancel request is generated at a rising edge</description>
                                    <value>#1</value>
                                </enumeratedValue>
                            </enumeratedValues>
                        </field>
                        <field>
                            <name>DIRQ6EG</name>
                            <description>IRQ6-DS Pin Edge Select</description>
                            <lsb>6</lsb>
                            <msb>6</msb>
                            <access>read-write</access>
                            <enumeratedValues>
                                <enumeratedValue>
                                    <name>0</name>
                                    <description>A cancel request is generated at a falling edge</description>
                                    <value>#0</value>
                                </enumeratedValue>
                                <enumeratedValue>
                                    <name>1</name>
                                    <description>A cancel request is generated at a rising edge</description>
                                    <value>#1</value>
                                </enumeratedValue>
                            </enumeratedValues>
                        </field>
                        <field>
                            <name>DIRQ7EG</name>
                            <description>IRQ7-DS Pin Edge Select</description>
                            <lsb>7</lsb>
                            <msb>7</msb>
                            <access>read-write</access>
                            <enumeratedValues>
                                <enumeratedValue>
                                    <name>0</name>
                                    <description>A cancel request is generated at a falling edge</description>
                                    <value>#0</value>
                                </enumeratedValue>
                                <enumeratedValue>
                                    <name>1</name>
                                    <description>A cancel request is generated at a rising edge</description>
                                    <value>#1</value>
                                </enumeratedValue>
                            </enumeratedValues>
                        </field>
                    </fields>
                </register>
                <register>
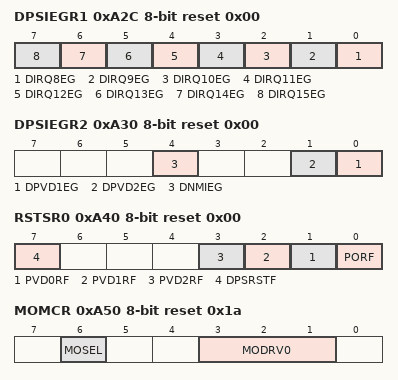
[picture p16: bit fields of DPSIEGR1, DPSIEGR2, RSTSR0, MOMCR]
                    <name>DPSIEGR1</name>
                    <description>Deep Software Standby Interrupt Edge Register 1</description>
                    <addressOffset>0xA2C</addressOffset>
                    <size>8</size>
                    <access>read-write</access>
                    <resetValue>0x00</resetValue>
                    <resetMask>0xff</resetMask>
                    <fields>
                        <field>
                            <name>DIRQ8EG</name>
                            <description>IRQ8-DS Pin Edge Select</description>
                            <lsb>0</lsb>
                            <msb>0</msb>
                            <access>read-write</access>
                            <enumeratedValues>
                                <enumeratedValue>
                                    <name>0</name>
                                    <description>A cancel request is generated at a falling edge.</description>
                                    <value>#0</value>
                                </enumeratedValue>
                                <enumeratedValue>
                                    <name>1</name>
                                    <description>A cancel request is generated at a rising edge.</description>
                                    <value>#1</value>
                                </enumeratedValue>
                            </enumeratedValues>
                        </field>
                        <field>
                            <name>DIRQ9EG</name>
                            <description>IRQ9-DS Pin Edge Select</description>
                            <lsb>1</lsb>
                            <msb>1</msb>
                            <access>read-write</access>
                            <enumeratedValues>
                                <enumeratedValue>
                                    <name>0</name>
                                    <description>A cancel request is generated at a falling edge.</description>
                                    <value>#0</value>
                                </enumeratedValue>
                                <enumeratedValue>
                                    <name>1</name>
                                    <description>A cancel request is generated at a rising edge.</description>
                                    <value>#1</value>
                                </enumeratedValue>
                            </enumeratedValues>
                        </field>
                        <field>
                            <name>DIRQ10EG</name>
                            <description>IRQ10-DS Pin Edge Select</description>
                            <lsb>2</lsb>
                            <msb>2</msb>
                            <access>read-write</access>
                            <enumeratedValues>
                                <enumeratedValue>
                                    <name>0</name>
                                    <description>A cancel request is generated at a falling edge.</description>
                                    <value>#0</value>
                                </enumeratedValue>
                                <enumeratedValue>
                                    <name>1</name>
                                    <description>A cancel request is generated at a rising edge</description>
                                    <value>#1</value>
                                </enumeratedValue>
                            </enumeratedValues>
                        </field>
                        <field>
                            <name>DIRQ11EG</name>
                            <description>IRQ11-DS Pin Edge Select</description>
                            <lsb>3</lsb>
                            <msb>3</msb>
                            <access>read-write</access>
                            <enumeratedValues>
                                <enumeratedValue>
                                    <name>0</name>
                                    <description>A cancel request is generated at a falling edge.</description>
                                    <value>#0</value>
                                </enumeratedValue>
                                <enumeratedValue>
                                    <name>1</name>
                                    <description>A cancel request is generated at a rising edge.</description>
                                    <value>#1</value>
                                </enumeratedValue>
                            </enumeratedValues>
                        </field>
                        <field>
                            <name>DIRQ12EG</name>
                            <description>IRQ12-DS Pin Edge Select</description>
                            <lsb>4</lsb>
                            <msb>4</msb>
                            <access>read-write</access>
                            <enumeratedValues>
                                <enumeratedValue>
                                    <name>0</name>
                                    <description>A cancel request is generated at a falling edge.</description>
                                    <value>#0</value>
                                </enumeratedValue>
                                <enumeratedValue>
                                    <name>1</name>
                                    <description>A cancel request is generated at a rising edge.</description>
                                    <value>#1</value>
                                </enumeratedValue>
                            </enumeratedValues>
                        </field>
                        <field>
                            <name>DIRQ13EG</name>
                            <description>IRQ13-DS Pin Edge Select</description>
                            <lsb>5</lsb>
                            <msb>5</msb>
                            <access>read-write</access>
                            <enumeratedValues>
                                <enumeratedValue>
                                    <name>0</name>
                                    <description>A cancel request is generated at a falling edge.</description>
                                    <value>#0</value>
                                </enumeratedValue>
                                <enumeratedValue>
                                    <name>1</name>
                                    <description>A cancel request is generated at a rising edge.</description>
                                    <value>#1</value>
                                </enumeratedValue>
                            </enumeratedValues>
                        </field>
                        <field>
                            <name>DIRQ14EG</name>
                            <description>IRQ14-DS Pin Edge Select</description>
                            <lsb>6</lsb>
                            <msb>6</msb>
                            <access>read-write</access>
                            <enumeratedValues>
                                <enumeratedValue>
                                    <name>0</name>
                                    <description>A cancel request is generated at a falling edge.</description>
                                    <value>#0</value>
                                </enumeratedValue>
                                <enumeratedValue>
                                    <name>1</name>
                                    <description>A cancel request is generated at a rising edge.</description>
                                    <value>#1</value>
                                </enumeratedValue>
                            </enumeratedValues>
                        </field>
                        <field>
                            <name>DIRQ15EG</name>
                            <description>IRQ15-DS Pin Edge Select</description>
                            <lsb>7</lsb>
                            <msb>7</msb>
                            <access>read-write</access>
                            <enumeratedValues>
                                <enumeratedValue>
                                    <name>0</name>
                                    <description>A cancel request is generated at a falling edge.</description>
                                    <value>#0</value>
                                </enumeratedValue>
                                <enumeratedValue>
                                    <name>1</name>
                                    <description>A cancel request is generated at a rising edge.</description>
                                    <value>#1</value>
                                </enumeratedValue>
                            </enumeratedValues>
                        </field>
                    </fields>
                </register>
                <register>
                    <name>DPSIEGR2</name>
                    <description>Deep Software Standby Interrupt Edge Register 2</description>
                    <addressOffset>0xA30</addressOffset>
                    <size>8</size>
                    <access>read-write</access>
                    <resetValue>0x00</resetValue>
                    <resetMask>0xff</resetMask>
                    <fields>
                        <field>
                            <name>DPVD1EG</name>
                            <description>PVD1 Edge Select</description>
                            <lsb>0</lsb>
                            <msb>0</msb>
                            <access>read-write</access>
                            <enumeratedValues>
                                <enumeratedValue>
                                    <name>0</name>
                                    <description>A cancel request is generated when VCC &lt; Vdet1 (fall) is detected</description>
                                    <value>#0</value>
                                </enumeratedValue>
                                <enumeratedValue>
                                    <name>1</name>
                                    <description>A cancel request is generated when VCC ≥ Vdet1 (rise) is detected</description>
                                    <value>#1</value>
                                </enumeratedValue>
                            </enumeratedValues>
                        </field>
                        <field>
                            <name>DPVD2EG</name>
                            <description>PVD2 Edge Select</description>
                            <lsb>1</lsb>
                            <msb>1</msb>
                            <access>read-write</access>
                            <enumeratedValues>
                                <enumeratedValue>
                                    <name>0</name>
                                    <description>A cancel request is generated when VCC &lt; Vdet2 (fall) is detected</description>
                                    <value>#0</value>
                                </enumeratedValue>
                                <enumeratedValue>
                                    <name>1</name>
                                    <description>A cancel request is generated when VCC ≥ Vdet2 (rise) is detected</description>
                                    <value>#1</value>
                                </enumeratedValue>
                            </enumeratedValues>
                        </field>
                        <field>
                            <name>DNMIEG</name>
                            <description>NMI Pin Edge Select</description>
                            <lsb>4</lsb>
                            <msb>4</msb>
                            <access>read-write</access>
                            <enumeratedValues>
                                <enumeratedValue>
                                    <name>0</name>
                                    <description>A cancel request is generated at a falling edge</description>
                                    <value>#0</value>
                                </enumeratedValue>
                                <enumeratedValue>
                                    <name>1</name>
                                    <description>A cancel request is generated at a rising edge</description>
                                    <value>#1</value>
                                </enumeratedValue>
                            </enumeratedValues>
                        </field>
                    </fields>
                </register>
                <register>
                    <name>SYOCDCR</name>
                    <description>System Control OCD Control Register</description>
                    <addressOffset>0xA38</addressOffset>
                    <size>8</size>
                    <access>read-write</access>
                    <resetValue>0x80</resetValue>
                    <resetMask>0xfe</resetMask>
                    <fields>
                        <field>
                            <name>DBGEN</name>
                            <description>Debugger Enable bit</description>
                            <lsb>7</lsb>
                            <msb>7</msb>
                            <access>read-write</access>
                            <enumeratedValues>
                                <enumeratedValue>
                                    <name>0</name>
                                    <description>On-chip debugger is disabled</description>
                                    <value>#0</value>
                                </enumeratedValue>
                                <enumeratedValue>
                                    <name>1</name>
                                    <description>On-chip debugger is enabled</description>
                                    <value>#1</value>
                                </enumeratedValue>
                            </enumeratedValues>
                        </field>
                    </fields>
                </register>
                <register>
                    <name>RSTSR0</name>
                    <description>Reset Status Register 0</description>
                    <addressOffset>0xA40</addressOffset>
                    <size>8</size>
                    <access>read-write</access>
                    <resetValue>0x00</resetValue>
                    <resetMask>0x70</resetMask>
                    <fields>
                        <field>
                            <name>PORF</name>
                            <description>Power-On Reset Detect Flag</description>
                            <lsb>0</lsb>
                            <msb>0</msb>
                            <access>read-write</access>
                            <enumeratedValues>
                                <enumeratedValue>
                                    <name>0</name>
                                    <description>Power-on reset not detected</description>
                                    <value>#0</value>
                                </enumeratedValue>
                                <enumeratedValue>
                                    <name>1</name>
                                    <description>Power-on reset detected</description>
                                    <value>#1</value>
                                </enumeratedValue>
                            </enumeratedValues>
                        </field>
                        <field>
                            <name>PVD0RF</name>
                            <description>Voltage Monitor 0 Reset Detect Flag</description>
                            <lsb>1</lsb>
                            <msb>1</msb>
                            <access>read-write</access>
                            <enumeratedValues>
                                <enumeratedValue>
                                    <name>0</name>
                                    <description>Voltage monitor 0 reset not detected</description>
                                    <value>#0</value>
                                </enumeratedValue>
                                <enumeratedValue>
                                    <name>1</name>
                                    <description>Voltage monitor 0 reset detected</description>
                                    <value>#1</value>
                                </enumeratedValue>
                            </enumeratedValues>
                        </field>
                        <field>
                            <name>PVD1RF</name>
                            <description>Voltage Monitor 1 Reset Detect Flag</description>
                            <lsb>2</lsb>
                            <msb>2</msb>
                            <access>read-write</access>
                            <enumeratedValues>
                                <enumeratedValue>
                                    <name>0</name>
                                    <description>Voltage monitor 1 reset not detected</description>
                                    <value>#0</value>
                                </enumeratedValue>
                                <enumeratedValue>
                                    <name>1</name>
                                    <description>Voltage monitor 1 reset detected</description>
                                    <value>#1</value>
                                </enumeratedValue>
                            </enumeratedValues>
                        </field>
                        <field>
                            <name>PVD2RF</name>
                            <description>Voltage Monitor 2 Reset Detect Flag</description>
                            <lsb>3</lsb>
                            <msb>3</msb>
                            <access>read-write</access>
                            <enumeratedValues>
                                <enumeratedValue>
                                    <name>0</name>
                                    <description>Voltage monitor 2 reset not detected</description>
                                    <value>#0</value>
                                </enumeratedValue>
                                <enumeratedValue>
                                    <name>1</name>
                                    <description>Voltage monitor 2 reset detected</description>
                                    <value>#1</value>
                                </enumeratedValue>
                            </enumeratedValues>
                        </field>
                        <field>
                            <name>DPSRSTF</name>
                            <description>Deep Software Standby Reset Flag</description>
                            <lsb>7</lsb>
                            <msb>7</msb>
                            <access>read-write</access>
                            <enumeratedValues>
                                <enumeratedValue>
                                    <name>0</name>
                                    <description>Deep Software Standby mode cancellation not requested by an interrupt or a reset.</description>
                                    <value>#0</value>
                                </enumeratedValue>
                                <enumeratedValue>
                                    <name>1</name>
                                    <description>Deep Software Standby mode cancellation requested by an interrupt or a reset.</description>
                                    <value>#1</value>
                                </enumeratedValue>
                            </enumeratedValues>
                        </field>
                    </fields>
                </register>
                <register>
                    <name>RSTSR2</name>
                    <description>Reset Status Register 2</description>
                    <addressOffset>0xA44</addressOffset>
                    <size>8</size>
                    <access>read-write</access>
                    <resetValue>0x00</resetValue>
                    <resetMask>0xfe</resetMask>
                    <fields>
                        <field>
                            <name>CWSF</name>
                            <description>Cold/Warm Start Determination Flag</description>
                            <lsb>0</lsb>
                            <msb>0</msb>
                            <access>read-write</access>
                            <enumeratedValues>
                                <enumeratedValue>
                                    <name>0</name>
                                    <description>Cold start</description>
                                    <value>#0</value>
                                </enumeratedValue>
                                <enumeratedValue>
                                    <name>1</name>
                                    <description>Warm start</description>
                                    <value>#1</value>
                                </enumeratedValue>
                            </enumeratedValues>
                        </field>
                    </fields>
                </register>
                <register>
                    <name>MOMCR</name>
                    <description>Main Clock Oscillator Mode Oscillation Control Register</description>
                    <addressOffset>0xA50</addressOffset>
                    <size>8</size>
                    <access>read-write</access>
                    <resetValue>0x1a</resetValue>
                    <resetMask>0xff</resetMask>
                    <fields>
                        <field>
                            <name>MODRV0</name>
                            <description>Main Clock Oscillator Drive Capability 0 Switching</description>
                            <lsb>1</lsb>
                            <msb>3</msb>
                            <access>read-write</access>
                            <enumeratedValues>
                                <enumeratedValue>
                                    <name>000</name>
                                    <description>8 MHz</description>
                                    <value>#000</value>
                                </enumeratedValue>
                                <enumeratedValue>
                                    <name>011</name>
                                    <description>8 MHz to 24 MHz</description>
                                    <value>#011</value>
                                </enumeratedValue>
                                <enumeratedValue>
                                    <name>101</name>
                                    <description>8 MHz to 48 MHz</description>
                                    <value>#101</value>
                                </enumeratedValue>
                                <enumeratedValue>
                                    <name>Others</name>
                                    <description>Setting prohibited</description>
                                    <isDefault>true</isDefault>
                                </enumeratedValue>
                            </enumeratedValues>
                        </field>
                        <field>
                            <name>MOSEL</name>
                            <description>Main Clock Oscillator Switching</description>
                            <lsb>6</lsb>
                            <msb>6</msb>
                            <access>read-write</access>
                            <enumeratedValues>
                                <enumeratedValue>
                                    <name>0</name>
                                    <description>Resonator</description>
                                    <value>#0</value>
                                </enumeratedValue>
                                <enumeratedValue>
                                    <name>1</name>
                                    <description>External clock input</description>
                                    <value>#1</value>
                                </enumeratedValue>
                            </enumeratedValues>
                        </field>
                    </fields>
                </register>
                <register>
                    <name>FWEPROR</name>
                    <description>Flash P/E Protect Register</description>
                    <addressOffset>0xA54</addressOffset>
                    <size>8</size>
                    <access>read-write</access>
                    <resetValue>0x02</resetValue>
                    <resetMask>0xff</resetMask>
                    <fields>
                        <field>
                            <name>FLWE</name>
                            <description>Flash Programming and Erasure</description>
                            <lsb>0</lsb>
                            <msb>1</msb>
                            <access>read-write</access>
                            <enumeratedValues>
                                <enumeratedValue>
                                    <name>00</name>
                                    <description>Prohibits Program, Block Erase, Multi Block Erase, Blank Check, and Configuration set command processing.</description>
                                    <value>#00</value>
                                </enumeratedValue>
                                <enumeratedValue>
                                    <name>01</name>
                                    <description>Permits Program, Block Erase, Multi Block Erase, Blank Check, and Configuration set command processing.</description>
                                    <value>#01</value>
                                </enumeratedValue>
                                <enumeratedValue>
                                    <name>10</name>
                                    <description>Prohibits Program, Block Erase, Multi Block Erase, Blank Check, and Configuration set command processing.</description>
                                    <value>#10</value>
                                </enumeratedValue>
                                <enumeratedValue>
                                    <name>11</name>
                                    <description>Prohibits Program, Block Erase, Multi Block Erase, Blank Check, and Configuration set command processing.</description>
                                    <value>#11</value>
                                </enumeratedValue>
                            </enumeratedValues>
                        </field>
                    </fields>
                </register>
                <register>
                    <dim>2</dim>
                    <dimIncrement>0x4</dimIncrement>
                    <dimIndex>1-2</dimIndex>
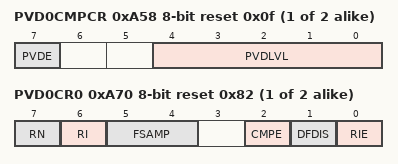
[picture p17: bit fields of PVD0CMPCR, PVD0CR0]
                    <name>PVD%sCMPCR</name>
                    <description>Voltage Monitor %s Comparator Control Register</description>
                    <addressOffset>0xA58</addressOffset>
                    <size>8</size>
                    <access>read-write</access>
                    <resetValue>0x0f</resetValue>
                    <resetMask>0xff</resetMask>
                    <fields>
                        <field>
                            <name>PVDLVL</name>
                            <description>Detection Voltage m Level Select</description>
                            <lsb>0</lsb>
                            <msb>4</msb>
                            <access>read-write</access>
                            <enumeratedValues>
                                <enumeratedValue>
                                    <name>0x03</name>
                                    <description>3.86 V (Vdetm_3)</description>
                                    <value>0x03</value>
                                </enumeratedValue>
                                <enumeratedValue>
                                    <name>0x04</name>
                                    <description>3.14 V (Vdetm_4)</description>
                                    <value>0x04</value>
                                </enumeratedValue>
                                <enumeratedValue>
                                    <name>0x05</name>
                                    <description>3.10 V (Vdetm_5)</description>
                                    <value>0x05</value>
                                </enumeratedValue>
                                <enumeratedValue>
                                    <name>0x06</name>
                                    <description>3.08 V (Vdetm_6)</description>
                                    <value>0x06</value>
                                </enumeratedValue>
                                <enumeratedValue>
                                    <name>0x07</name>
                                    <description>2.85 V (Vdetm_7)</description>
                                    <value>0x07</value>
                                </enumeratedValue>
                                <enumeratedValue>
                                    <name>0x08</name>
                                    <description>2.83 V (Vdetm_8)</description>
                                    <value>0x08</value>
                                </enumeratedValue>
                                <enumeratedValue>
                                    <name>0x09</name>
                                    <description>2.80 V (Vdetm_9)</description>
                                    <value>0x09</value>
                                </enumeratedValue>
                                <enumeratedValue>
                                    <name>0x0A</name>
                                    <description>2.62V (Vdetm_10)</description>
                                    <value>0x0a</value>
                                </enumeratedValue>
                                <enumeratedValue>
                                    <name>0x0B</name>
                                    <description>2.33V (Vdetm_11)</description>
                                    <value>0x0b</value>
                                </enumeratedValue>
                                <enumeratedValue>
                                    <name>0x0C</name>
                                    <description>1.90V (Vdetm_12)</description>
                                    <value>0x0c</value>
                                </enumeratedValue>
                                <enumeratedValue>
                                    <name>0x0D</name>
                                    <description>1.86V (Vdetm_13)</description>
                                    <value>0x0d</value>
                                </enumeratedValue>
                                <enumeratedValue>
                                    <name>0x0E</name>
                                    <description>1.74V (Vdetm_14)</description>
                                    <value>0x0e</value>
                                </enumeratedValue>
                                <enumeratedValue>
                                    <name>0x0F</name>
                                    <description>1.71V (Vdetm_15)</description>
                                    <value>0x0f</value>
                                </enumeratedValue>
                                <enumeratedValue>
                                    <name>Others</name>
                                    <description>Setting prohibited</description>
                                    <isDefault>true</isDefault>
                                </enumeratedValue>
                            </enumeratedValues>
                        </field>
                        <field>
                            <name>PVDE</name>
                            <description>Voltage Detection m Enable</description>
                            <lsb>7</lsb>
                            <msb>7</msb>
                            <access>read-write</access>
                            <enumeratedValues>
                                <enumeratedValue>
                                    <name>0</name>
                                    <description>Voltage detection m circuit disabled</description>
                                    <value>#0</value>
                                </enumeratedValue>
                                <enumeratedValue>
                                    <name>1</name>
                                    <description>Voltage detection m circuit enabled</description>
                                    <value>#1</value>
                                </enumeratedValue>
                            </enumeratedValues>
                        </field>
                    </fields>
                </register>
                <register>
                    <dim>2</dim>
                    <dimIncrement>0x4</dimIncrement>
                    <dimIndex>1-2</dimIndex>
                    <name>PVD%sCR0</name>
                    <description>Voltage Monitor %s Circuit Control Register 0</description>
                    <addressOffset>0xA70</addressOffset>
                    <size>8</size>
                    <access>read-write</access>
                    <resetValue>0x82</resetValue>
                    <resetMask>0xf7</resetMask>
                    <fields>
                        <field>
                            <name>RIE</name>
                            <description>Voltage Monitor m Interrupt/Reset Enable</description>
                            <lsb>0</lsb>
                            <msb>0</msb>
                            <access>read-write</access>
                            <enumeratedValues>
                                <enumeratedValue>
                                    <name>0</name>
                                    <description>Disable</description>
                                    <value>#0</value>
                                </enumeratedValue>
                                <enumeratedValue>
                                    <name>1</name>
                                    <description>Enable</description>
                                    <value>#1</value>
                                </enumeratedValue>
                            </enumeratedValues>
                        </field>
                        <field>
                            <name>DFDIS</name>
                            <description>Voltage monitor m Digital Filter Disabled Mode Select</description>
                            <lsb>1</lsb>
                            <msb>1</msb>
                            <access>read-write</access>
                            <enumeratedValues>
                                <enumeratedValue>
                                    <name>0</name>
                                    <description>Enable the digital filter</description>
                                    <value>#0</value>
                                </enumeratedValue>
                                <enumeratedValue>
                                    <name>1</name>
                                    <description>Disable the digital filter</description>
                                    <value>#1</value>
                                </enumeratedValue>
                            </enumeratedValues>
                        </field>
                        <field>
                            <name>CMPE</name>
                            <description>Voltage Monitor m Circuit Comparison Result Output Enable</description>
                            <lsb>2</lsb>
                            <msb>2</msb>
                            <access>read-write</access>
                            <enumeratedValues>
                                <enumeratedValue>
                                    <name>0</name>
                                    <description>Voltage monitor m circuit comparison result output disabled</description>
                                    <value>#0</value>
                                </enumeratedValue>
                                <enumeratedValue>
                                    <name>1</name>
                                    <description>Voltage monitor m circuit comparison result output enabled</description>
                                    <value>#1</value>
                                </enumeratedValue>
                            </enumeratedValues>
                        </field>
                        <field>
                            <name>FSAMP</name>
                            <description>Sampling Clock Select</description>
                            <lsb>4</lsb>
                            <msb>5</msb>
                            <access>read-write</access>
                            <enumeratedValues>
                                <enumeratedValue>
                                    <name>00</name>
                                    <description>1/2 LOCO frequency</description>
                                    <value>#00</value>
                                </enumeratedValue>
                                <enumeratedValue>
                                    <name>01</name>
                                    <description>1/4 LOCO frequency</description>
                                    <value>#01</value>
                                </enumeratedValue>
                                <enumeratedValue>
                                    <name>10</name>
                                    <description>1/8 LOCO frequency</description>
                                    <value>#10</value>
                                </enumeratedValue>
                                <enumeratedValue>
                                    <name>11</name>
                                    <description>1/16 LOCO frequency</description>
                                    <value>#11</value>
                                </enumeratedValue>
                            </enumeratedValues>
                        </field>
                        <field>
                            <name>RI</name>
                            <description>Voltage Monitor m Circuit Mode Select</description>
                            <lsb>6</lsb>
                            <msb>6</msb>
                            <access>read-write</access>
                        </field>
                        <field>
                            <name>RN</name>
                            <description>Voltage Monitor m Reset Negate Select</description>
                            <lsb>7</lsb>
                            <msb>7</msb>
                            <access>read-write</access>
                        </field>
                    </fields>
                </register>
                <register>
                    <name>VBATTMNSELR</name>
                    <description>Battery Backup Voltage Monitor Function Select Register</description>
                    <addressOffset>0xA84</addressOffset>
                    <size>8</size>
                    <access>read-write</access>
                    <resetValue>0x00</resetValue>
                    <resetMask>0xff</resetMask>
                    <fields>
                        <field>
                            <name>VBTMNSEL</name>
                            <description>VBATT Voltage Monitor Function Select Bit</description>
                            <lsb>0</lsb>
                            <msb>0</msb>
                            <access>read-write</access>
                            <enumeratedValues>
                                <enumeratedValue>
                                    <name>0</name>
                                    <description>Disables VBATT voltage monitor function</description>
                                    <value>#0</value>
                                </enumeratedValue>
                                <enumeratedValue>
                                    <name>1</name>
                                    <description>Enables VBATT voltage monitor function</description>
                                    <value>#1</value>
                                </enumeratedValue>
                            </enumeratedValues>
                        </field>
                    </fields>
                </register>
                <register>
                    <name>VBTBPCR1</name>
                    <description>VBATT Battery Power Supply Control Register 1</description>
                    <addressOffset>0xA88</addressOffset>
                    <size>8</size>
                    <access>read-write</access>
                    <resetValue>0x00</resetValue>
                    <resetMask>0xff</resetMask>
                    <fields>
                        <field>
                            <name>BPWSWSTP</name>
                            <description>Battery Power Supply Switch Stop</description>
                            <lsb>0</lsb>
                            <msb>0</msb>
                            <access>read-write</access>
                            <enumeratedValues>
                                <enumeratedValue>
                                    <name>0</name>
                                    <description>Battery power supply switch enable</description>
                                    <value>#0</value>
                                </enumeratedValue>
                                <enumeratedValue>
                                    <name>1</name>
                                    <description>Battery power supply switch stop</description>
                                    <value>#1</value>
                                </enumeratedValue>
                            </enumeratedValues>
                        </field>
                    </fields>
                </register>
                <register>
                    <name>LPSCR</name>
                    <description>Low Power State Control Register</description>
                    <addressOffset>0xA90</addressOffset>
                    <size>8</size>
                    <access>read-write</access>
                    <resetValue>0x04</resetValue>
                    <resetMask>0xff</resetMask>
                    <fields>
                        <field>
                            <name>LPMD</name>
                            <description>Low power mode setting bit</description>
                            <lsb>0</lsb>
                            <msb>3</msb>
                            <access>read-write</access>
                            <enumeratedValues>
                                <enumeratedValue>
                                    <name>0x0</name>
                                    <description>System Active</description>
                                    <value>0x0</value>
                                </enumeratedValue>
                                <enumeratedValue>
                                    <name>0x4</name>
                                    <description>Software Standby mode</description>
                                    <value>0x4</value>
                                </enumeratedValue>
                                <enumeratedValue>
                                    <name>0x8</name>
                                    <description>Deep Software Standby mode 1</description>
                                    <value>0x8</value>
                                </enumeratedValue>
                                <enumeratedValue>
                                    <name>0x9</name>
                                    <description>Deep Software Standby mode 2</description>
                                    <value>0x9</value>
                                </enumeratedValue>
                                <enumeratedValue>
                                    <name>0xA</name>
                                    <description>Deep Software Standby mode 3</description>
                                    <value>0xa</value>
                                </enumeratedValue>
                                <enumeratedValue>
                                    <name>Others</name>
                                    <description>Setting prohibited</description>
                                    <isDefault>true</isDefault>
                                </enumeratedValue>
                            </enumeratedValues>
                        </field>
                    </fields>
                </register>
                <register>
                    <name>SSCR1</name>
                    <description>Software Standby Control Register 1</description>
                    <addressOffset>0xA98</addressOffset>
                    <size>8</size>
                    <access>read-write</access>
                    <resetValue>0x00</resetValue>
                    <resetMask>0xff</resetMask>
                    <fields>
                        <field>
                            <name>SS1FR</name>
                            <description>Software Standby Fast Return</description>
                            <lsb>0</lsb>
                            <msb>0</msb>
                            <access>read-write</access>
                            <enumeratedValues>
                                <enumeratedValue>
                                    <name>0</name>
                                    <description>When returning from Software Standby mode, fast return function is disabled</description>
                                    <value>#0</value>
                                </enumeratedValue>
                                <enumeratedValue>
                                    <name>1</name>
                                    <description>When returning from Software Standby mode, fast return function is enabled</description>
                                    <value>#1</value>
                                </enumeratedValue>
                            </enumeratedValues>
                        </field>
                    </fields>
                </register>
                <register>
                    <name>LVOCR</name>
                    <description>Low Voltage Operation Control register</description>
                    <addressOffset>0xAB0</addressOffset>
                    <size>8</size>
                    <access>read-write</access>
                    <resetValue>0x03</resetValue>
                    <resetMask>0xff</resetMask>
                    <fields>
                        <field>
                            <name>LVO0E</name>
                            <description>Low Voltage Operation 0 Enable</description>
                            <lsb>0</lsb>
                            <msb>0</msb>
                            <access>read-write</access>
                            <enumeratedValues>
                                <enumeratedValue>
                                    <name>0</name>
                                    <description>Disable</description>
                                    <value>#0</value>
                                </enumeratedValue>
                                <enumeratedValue>
                                    <name>1</name>
                                    <description>Enable</description>
                                    <value>#1</value>
                                </enumeratedValue>
                            </enumeratedValues>
                        </field>
                        <field>
                            <name>LVO1E</name>
                            <description>Low Voltage Operation 1 Enable</description>
                            <lsb>1</lsb>
                            <msb>1</msb>
                            <access>read-write</access>
                            <enumeratedValues>
                                <enumeratedValue>
                                    <name>0</name>
                                    <description>Disable</description>
                                    <value>#0</value>
                                </enumeratedValue>
                                <enumeratedValue>
                                    <name>1</name>
                                    <description>Enable</description>
                                    <value>#1</value>
                                </enumeratedValue>
                            </enumeratedValues>
                        </field>
                    </fields>
                </register>
                <register>
                    <name>PLL1LDOCR</name>
                    <description>PLL1-LDO Control Register</description>
                    <addressOffset>0xB04</addressOffset>
                    <size>8</size>
                    <access>read-write</access>
                    <resetValue>0x00</resetValue>
                    <resetMask>0xfb</resetMask>
                    <fields>
                        <field>
                            <name>LDOSTP</name>
                            <description>LDO Stop</description>
                            <lsb>0</lsb>
                            <msb>0</msb>
                            <access>read-write</access>
                            <enumeratedValues>
                                <enumeratedValue>
                                    <name>0</name>
                                    <description>PLL1-LDO is enabled</description>
                                    <value>#0</value>
                                </enumeratedValue>
                                <enumeratedValue>
                                    <name>1</name>
                                    <description>PLL1-LDO is stopped</description>
                                    <value>#1</value>
                                </enumeratedValue>
                            </enumeratedValues>
                        </field>
                        <field>
                            <name>SKEEP</name>
                            <description>STBY Keep</description>
                            <lsb>1</lsb>
                            <msb>1</msb>
                            <access>read-write</access>
                            <enumeratedValues>
                                <enumeratedValue>
                                    <name>0</name>
                                    <description>PLL1-LDO is stopped during Software Standby mode.</description>
                                    <value>#0</value>
                                </enumeratedValue>
                                <enumeratedValue>
                                    <name>1</name>
                                    <description>PLL1-LDO state before Software Standby mode is retained during Software Standby mode.</description>
                                    <value>#1</value>
                                </enumeratedValue>
                            </enumeratedValues>
                        </field>
                    </fields>
                </register>
                <register>
                    <name>PLL2LDOCR</name>
                    <description>PLL2-LDO Control Register</description>
                    <addressOffset>0xB08</addressOffset>
                    <size>8</size>
                    <access>read-write</access>
                    <resetValue>0x00</resetValue>
                    <resetMask>0xfb</resetMask>
                    <fields>
                        <field>
                            <name>LDOSTP</name>
                            <description>LDO Stop</description>
                            <lsb>0</lsb>
                            <msb>0</msb>
                            <access>read-write</access>
                            <enumeratedValues>
                                <enumeratedValue>
                                    <name>0</name>
                                    <description>PLL2-LDO is enabled</description>
                                    <value>#0</value>
                                </enumeratedValue>
                                <enumeratedValue>
                                    <name>1</name>
                                    <description>PLL2-LDO is stopped</description>
                                    <value>#1</value>
                                </enumeratedValue>
                            </enumeratedValues>
                        </field>
                        <field>
                            <name>SKEEP</name>
                            <description>STBY Keep</description>
                            <lsb>1</lsb>
                            <msb>1</msb>
                            <access>read-write</access>
                            <enumeratedValues>
                                <enumeratedValue>
                                    <name>0</name>
                                    <description>PLL2-LDO is stopped during Software Standby mode.</description>
                                    <value>#0</value>
                                </enumeratedValue>
                                <enumeratedValue>
                                    <name>1</name>
                                    <description>PLL2-LDO state before Software Standby mode is retained during Software Standby mode.</description>
                                    <value>#1</value>
                                </enumeratedValue>
                            </enumeratedValues>
                        </field>
                    </fields>
                </register>
                <register>
                    <name>HOCOLDOCR</name>
                    <description>HOCO-LDO Control Register</description>
                    <addressOffset>0xB0C</addressOffset>
                    <size>8</size>
                    <access>read-write</access>
                    <resetValue>0x00</resetValue>
                    <resetMask>0xfb</resetMask>
                    <fields>
                        <field>
                            <name>LDOSTP</name>
                            <description>LDO Stop</description>
                            <lsb>0</lsb>
                            <msb>0</msb>
                            <access>read-write</access>
                            <enumeratedValues>
                                <enumeratedValue>
                                    <name>0</name>
                                    <description>HOCO-LDO is enabled</description>
                                    <value>#0</value>
                                </enumeratedValue>
                                <enumeratedValue>
                                    <name>1</name>
                                    <description>HOCO-LDO is stopped</description>
                                    <value>#1</value>
                                </enumeratedValue>
                            </enumeratedValues>
                        </field>
                        <field>
                            <name>SKEEP</name>
                            <description>STBY Keep</description>
                            <lsb>1</lsb>
                            <msb>1</msb>
                            <access>read-write</access>
                            <enumeratedValues>
                                <enumeratedValue>
                                    <name>0</name>
                                    <description>HOCO-LDO is stopped during Software Standby mode.</description>
                                    <value>#0</value>
                                </enumeratedValue>
                                <enumeratedValue>
                                    <name>1</name>
                                    <description>HOCO-LDO state before Software Standby mode is retained during Software Standby mode.</description>
                                    <value>#1</value>
                                </enumeratedValue>
                            </enumeratedValues>
                        </field>
                    </fields>
                </register>
                <register>
                    <dim>2</dim>
                    <dimIncrement>0x4</dimIncrement>
                    <dimIndex>1-2</dimIndex>
                    <name>PVD%sFCR</name>
                    <description>Voltage Monitor %s Function Control Register</description>
                    <addressOffset>0xB20</addressOffset>
                    <size>8</size>
                    <access>read-write</access>
                    <resetValue>0x00</resetValue>
                    <resetMask>0xff</resetMask>
                    <fields>
                        <field>
                            <name>RHSEL</name>
                            <description>Rise Hysteresis Select</description>
                            <lsb>0</lsb>
                            <msb>0</msb>
                            <access>read-write</access>
                            <enumeratedValues>
                                <enumeratedValue>
                                    <name>0</name>
                                    <description>Hysteresis level for VCC-fall detection is selected.</description>
                                    <value>#0</value>
                                </enumeratedValue>
                                <enumeratedValue>
                                    <name>1</name>
                                    <description>Hysteresis level for VCC-rise detection is selected.</description>
                                    <value>#1</value>
                                </enumeratedValue>
                            </enumeratedValues>
                        </field>
                    </fields>
                </register>
                <register>
                    <name>SOSCCR</name>
                    <description>Sub-Clock Oscillator Control Register</description>
                    <addressOffset>0xC00</addressOffset>
                    <size>8</size>
                    <access>read-write</access>
                    <resetValue>0x01</resetValue>
                    <resetMask>0xff</resetMask>
                    <fields>
                        <field>
                            <name>SOSTP</name>
                            <description>Sub-Clock Oscillator Stop</description>
                            <lsb>0</lsb>
                            <msb>0</msb>
                            <access>read-write</access>
                            <enumeratedValues>
                                <enumeratedValue>
                                    <name>0</name>
                                    <description>Operate the sub-clock oscillator</description>
                                    <value>#0</value>
                                </enumeratedValue>
                                <enumeratedValue>
                                    <name>1</name>
                                    <description>Stop the sub-clock oscillator</description>
                                    <value>#1</value>
                                </enumeratedValue>
                            </enumeratedValues>
                        </field>
                    </fields>
                </register>
                <register>
                    <name>SOMCR</name>
                    <description>Sub-Clock Oscillator Mode Control Register</description>
                    <addressOffset>0xC01</addressOffset>
                    <size>8</size>
                    <access>read-write</access>
                    <resetValue>0x00</resetValue>
                    <resetMask>0xff</resetMask>
                    <fields>
                        <field>
                            <name>SODRV</name>
                            <description>Sub-Clock Oscillator Drive Capability Switching</description>
                            <lsb>0</lsb>
                            <msb>1</msb>
                            <access>read-write</access>
                            <enumeratedValues>
                                <enumeratedValue>
                                    <name>00</name>
                                    <description>Standard (12.5pf)</description>
                                    <value>#00</value>
                                </enumeratedValue>
                                <enumeratedValue>
                                    <name>01</name>
                                    <description>Lowpower mode 1 (9pf)</description>
                                    <value>#01</value>
                                </enumeratedValue>
                                <enumeratedValue>
                                    <name>10</name>
                                    <description>Lowpower mode 2 (7pf)</description>
                                    <value>#10</value>
                                </enumeratedValue>
                                <enumeratedValue>
                                    <name>11</name>
                                    <description>Lowpower mode 3 (4pf)</description>
                                    <value>#11</value>
                                </enumeratedValue>
                            </enumeratedValues>
                        </field>
                        <field>
                            <name>SOSEL</name>
                            <description>Sub-Clock Oscillator Switching</description>
                            <lsb>6</lsb>
                            <msb>6</msb>
                            <access>read-write</access>
                            <enumeratedValues>
                                <enumeratedValue>
                                    <name>0</name>
                                    <description>Resonator</description>
                                    <value>#0</value>
                                </enumeratedValue>
                                <enumeratedValue>
                                    <name>1</name>
                                    <description>External clock input</description>
                                    <value>#1</value>
                                </enumeratedValue>
                            </enumeratedValues>
                        </field>
                    </fields>
                </register>
                <register>
                    <name>VBTBER</name>
                    <description>VBATT Backup Enable Register</description>
                    <addressOffset>0xC40</addressOffset>
                    <size>8</size>
                    <access>read-write</access>
                    <resetValue>0x08</resetValue>
                    <resetMask>0xff</resetMask>
                    <fields>
                        <field>
                            <name>VBAE</name>
                            <description>VBATT backup register access enable bit</description>
                            <lsb>3</lsb>
                            <msb>3</msb>
                            <access>read-write</access>
                            <enumeratedValues>
                                <enumeratedValue>
                                    <name>0</name>
                                    <description>Disable to access VBTBKR[n]</description>
                                    <value>#0</value>
                                </enumeratedValue>
                                <enumeratedValue>
                                    <name>1</name>
                                    <description>Enable to access VBTBKR[n]</description>
                                    <value>#1</value>
                                </enumeratedValue>
                            </enumeratedValues>
                        </field>
                    </fields>
                </register>
                <register>
                    <name>VBTBPCR2</name>
                    <description>VBATT Battery Power Supply Control Register 2</description>
                    <addressOffset>0xC45</addressOffset>
                    <size>8</size>
                    <access>read-write</access>
                    <resetValue>0x06</resetValue>
                    <resetMask>0xff</resetMask>
                    <fields>
                        <field>
                            <name>VDETLVL</name>
                            <description>VDETBAT Level Select</description>
                            <lsb>0</lsb>
                            <msb>2</msb>
                            <access>read-write</access>
                            <enumeratedValues>
                                <enumeratedValue>
                                    <name>000</name>
                                    <description>2.80 V</description>
                                    <value>#000</value>
                                </enumeratedValue>
                                <enumeratedValue>
                                    <name>001</name>
                                    <description>2.53 V</description>
                                    <value>#001</value>
                                </enumeratedValue>
                                <enumeratedValue>
                                    <name>010</name>
                                    <description>2.10 V</description>
                                    <value>#010</value>
                                </enumeratedValue>
                                <enumeratedValue>
                                    <name>011</name>
                                    <description>1.95 V</description>
                                    <value>#011</value>
                                </enumeratedValue>
                                <enumeratedValue>
                                    <name>100</name>
                                    <description>1.85 V</description>
                                    <value>#100</value>
                                </enumeratedValue>
                                <enumeratedValue>
                                    <name>101</name>
                                    <description>1.75 V</description>
                                    <value>#101</value>
                                </enumeratedValue>
                                <enumeratedValue>
                                    <name>110</name>
                                    <description>setting prohibited</description>
                                    <value>#110</value>
                                </enumeratedValue>
                                <enumeratedValue>
                                    <name>111</name>
                                    <description>setting prohibited</description>
                                    <value>#111</value>
                                </enumeratedValue>
                            </enumeratedValues>
                        </field>
                        <field>
                            <name>VDETE</name>
                            <description>Voltage drop detection enable</description>
                            <lsb>4</lsb>
                            <msb>4</msb>
                            <access>read-write</access>
                            <enumeratedValues>
                                <enumeratedValue>
                                    <name>0</name>
                                    <description>VCC Voltage drop detection disable </description>
                                    <value>#0</value>
                                </enumeratedValue>
                                <enumeratedValue>
                                    <name>1</name>
                                    <description>VCC Voltage drop detection enable</description>
                                    <value>#1</value>
                                </enumeratedValue>
                            </enumeratedValues>
                        </field>
                    </fields>
                </register>
                <register>
                    <name>VBTBPSR</name>
                    <description>VBATT Battery Power Supply Status Register</description>
                    <addressOffset>0xC46</addressOffset>
                    <size>8</size>
                    <access>read-write</access>
                    <resetValue>0x00</resetValue>
                    <resetMask>0xce</resetMask>
                    <fields>
                        <field>
                            <name>VBPORF</name>
                            <description>VBATT_POR Flag</description>
                            <lsb>0</lsb>
                            <msb>0</msb>
                            <access>read-write</access>
                            <enumeratedValues>
                                <enumeratedValue>
                                    <name>0</name>
                                    <description>VBATT_R voltage drop is not detected</description>
                                    <value>#0</value>
                                </enumeratedValue>
                                <enumeratedValue>
                                    <name>1</name>
                                    <description>VBATT_R voltage drop is detected</description>
                                    <value>#1</value>
                                </enumeratedValue>
                            </enumeratedValues>
                        </field>
                        <field>
                            <name>VBPORM</name>
                            <description>VBATT_POR Monitor</description>
                            <lsb>4</lsb>
                            <msb>4</msb>
                            <access>read-only</access>
                            <enumeratedValues>
                                <enumeratedValue>
                                    <name>0</name>
                                    <description>VBATT_R voltage &lt; VPDR (BATR)</description>
                                    <value>#0</value>
                                </enumeratedValue>
                                <enumeratedValue>
                                    <name>1</name>
                                    <description>VBATT_R voltage &gt; VPDR (BATR)</description>
                                    <value>#1</value>
                                </enumeratedValue>
                            </enumeratedValues>
                        </field>
                        <field>
                            <name>BPWSWM</name>
                            <description>Battery Power Supply Switch Status Monitor</description>
                            <lsb>5</lsb>
                            <msb>5</msb>
                            <access>read-only</access>
                            <enumeratedValues>
                                <enumeratedValue>
                                    <name>0</name>
                                    <description>VCC voltage &lt; VDETBATT_m</description>
                                    <value>#0</value>
                                </enumeratedValue>
                                <enumeratedValue>
                                    <name>1</name>
                                    <description>VCC voltage &gt; VDETBATT_m</description>
                                    <value>#1</value>
                                </enumeratedValue>
                            </enumeratedValues>
                        </field>
                    </fields>
                </register>
                <register>
                    <name>VBTADSR</name>
                    <description>VBATT Tamper detection Status Register</description>
                    <addressOffset>0xC48</addressOffset>
                    <size>8</size>
                    <access>read-write</access>
                    <resetValue>0x00</resetValue>
                    <resetMask>0xff</resetMask>
                    <fields>
                        <field>
                            <name>VBTADF0</name>
                            <description>VBATT Tamper Detection flag 0</description>
                            <lsb>0</lsb>
                            <msb>0</msb>
                            <access>read-write</access>
                            <enumeratedValues>
                                <enumeratedValue>
                                    <name>0</name>
                                    <description>RTCIC0 input edge is not detected</description>
                                    <value>#0</value>
                                </enumeratedValue>
                                <enumeratedValue>
                                    <name>1</name>
                                    <description>RTCIC0 input edge is detected</description>
                                    <value>#1</value>
                                </enumeratedValue>
                            </enumeratedValues>
                        </field>
                        <field>
                            <name>VBTADF1</name>
                            <description>VBATT Tamper Detection flag 1</description>
                            <lsb>1</lsb>
                            <msb>1</msb>
                            <access>read-write</access>
                            <enumeratedValues>
                                <enumeratedValue>
                                    <name>0</name>
                                    <description>RTCIC1 input edge is not detected</description>
                                    <value>#0</value>
                                </enumeratedValue>
                                <enumeratedValue>
                                    <name>1</name>
                                    <description>RTCIC1 input edge is detected</description>
                                    <value>#1</value>
                                </enumeratedValue>
                            </enumeratedValues>
                        </field>
                        <field>
                            <name>VBTADF2</name>
                            <description>VBATT Tamper Detection flag 2</description>
                            <lsb>2</lsb>
                            <msb>2</msb>
                            <access>read-write</access>
                            <enumeratedValues>
                                <enumeratedValue>
                                    <name>0</name>
                                    <description>RTCIC2 input edge is not detected</description>
                                    <value>#0</value>
                                </enumeratedValue>
                                <enumeratedValue>
                                    <name>1</name>
                                    <description>RTCIC2 input edge is detected</description>
                                    <value>#1</value>
                                </enumeratedValue>
                            </enumeratedValues>
                        </field>
                    </fields>
                </register>
                <register>
                    <name>VBTADCR1</name>
                    <description>VBATT Tamper detection Control Register 1</description>
                    <addressOffset>0xC49</addressOffset>
                    <size>8</size>
                    <access>read-write</access>
                    <resetValue>0x00</resetValue>
                    <resetMask>0xff</resetMask>
                    <fields>
                        <field>
                            <name>VBTADIE0</name>
                            <description>VBATT Tamper Detection Interrupt Enable 0</description>
                            <lsb>0</lsb>
                            <msb>0</msb>
                            <access>read-write</access>
                            <enumeratedValues>
                                <enumeratedValue>
                                    <name>0</name>
                                    <description>Interrupt by VBTADF0 flag is disable</description>
                                    <value>#0</value>
                                </enumeratedValue>
                                <enumeratedValue>
                                    <name>1</name>
                                    <description>Interrupt by VBTADF0 flag is enable</description>
                                    <value>#1</value>
                                </enumeratedValue>
                            </enumeratedValues>
                        </field>
                        <field>
                            <name>VBTADIE1</name>
                            <description>VBATT Tamper Detection Interrupt Enable 1</description>
                            <lsb>1</lsb>
                            <msb>1</msb>
                            <access>read-write</access>
                            <enumeratedValues>
                                <enumeratedValue>
                                    <name>0</name>
                                    <description>Interrupt by VBTADF1 flag is disable</description>
                                    <value>#0</value>
                                </enumeratedValue>
                                <enumeratedValue>
                                    <name>1</name>
                                    <description>Interrupt by VBTADF1 flag is enable</description>
                                    <value>#1</value>
                                </enumeratedValue>
                            </enumeratedValues>
                        </field>
                        <field>
                            <name>VBTADIE2</name>
                            <description>VBATT Tamper Detection Interrupt Enable 2</description>
                            <lsb>2</lsb>
                            <msb>2</msb>
                            <access>read-write</access>
                            <enumeratedValues>
                                <enumeratedValue>
                                    <name>0</name>
                                    <description>Interrupt by VBTADF2 flag is disable</description>
                                    <value>#0</value>
                                </enumeratedValue>
                                <enumeratedValue>
                                    <name>1</name>
                                    <description>Interrupt by VBTADF2 flag is enable</description>
                                    <value>#1</value>
                                </enumeratedValue>
                            </enumeratedValues>
                        </field>
                        <field>
                            <name>VBTADCE0</name>
                            <description>VBATT Tamper Detection Backup Register Clear Enable 0</description>
                            <lsb>4</lsb>
                            <msb>4</msb>
                            <access>read-write</access>
                            <enumeratedValues>
                                <enumeratedValue>
                                    <name>0</name>
                                    <description>Clear Backup Register by VBTADF0 flag is disable</description>
                                    <value>#0</value>
                                </enumeratedValue>
                                <enumeratedValue>
                                    <name>1</name>
                                    <description>Clear Backup Register by VBTADF0 flag is enable</description>
                                    <value>#1</value>
                                </enumeratedValue>
                            </enumeratedValues>
                        </field>
                        <field>
                            <name>VBTADCE1</name>
                            <description>VBATT Tamper Detection Backup Register Clear Enable 1</description>
                            <lsb>5</lsb>
                            <msb>5</msb>
                            <access>read-write</access>
                            <enumeratedValues>
                                <enumeratedValue>
                                    <name>0</name>
                                    <description>Clear Backup Register by VBTADF1 flag is disable</description>
                                    <value>#0</value>
                                </enumeratedValue>
                                <enumeratedValue>
                                    <name>1</name>
                                    <description>Clear Backup Register by VBTADF1 flag is enable</description>
                                    <value>#1</value>
                                </enumeratedValue>
                            </enumeratedValues>
                        </field>
                        <field>
                            <name>VBTADCE2</name>
                            <description>VBATT Tamper Detection Backup Register Clear Enable 2</description>
                            <lsb>6</lsb>
                            <msb>6</msb>
                            <access>read-write</access>
                            <enumeratedValues>
                                <enumeratedValue>
                                    <name>0</name>
                                    <description>Clear Backup Register by VBTADF2 flag is disable</description>
                                    <value>#0</value>
                                </enumeratedValue>
                                <enumeratedValue>
                                    <name>1</name>
                                    <description>Clear Backup Register by VBTADF2 flag is enable</description>
                                    <value>#1</value>
                                </enumeratedValue>
                            </enumeratedValues>
                        </field>
                    </fields>
                </register>
                <register>
                    <name>VBTADCR2</name>
                    <description>VBATT Tamper detection Control Register 2</description>
                    <addressOffset>0xC4A</addressOffset>
                    <size>8</size>
                    <access>read-write</access>
                    <resetValue>0x00</resetValue>
                    <resetMask>0xff</resetMask>
                    <fields>
                        <field>
                            <name>VBRTCES0</name>
                            <description>VBATT RTC Time Capture Event Source Select 0</description>
                            <lsb>0</lsb>
                            <msb>0</msb>
                            <access>read-write</access>
                            <enumeratedValues>
                                <enumeratedValue>
                                    <name>0</name>
                                    <description>RTCIC0</description>
                                    <value>#0</value>
                                </enumeratedValue>
                                <enumeratedValue>
                                    <name>1</name>
                                    <description>VBTADF0</description>
                                    <value>#1</value>
                                </enumeratedValue>
                            </enumeratedValues>
                        </field>
                        <field>
                            <name>VBRTCES1</name>
                            <description>VBATT RTC Time Capture Event Source Select 1</description>
                            <lsb>1</lsb>
                            <msb>1</msb>
                            <access>read-write</access>
                            <enumeratedValues>
                                <enumeratedValue>
                                    <name>0</name>
                                    <description>RTCIC1</description>
                                    <value>#0</value>
                                </enumeratedValue>
                                <enumeratedValue>
                                    <name>1</name>
                                    <description>VBTADF1</description>
                                    <value>#1</value>
                                </enumeratedValue>
                            </enumeratedValues>
                        </field>
                        <field>
                            <name>VBRTCES2</name>
                            <description>VBATT RTC Time Capture Event Source Select 2</description>
                            <lsb>2</lsb>
                            <msb>2</msb>
                            <access>read-write</access>
                            <enumeratedValues>
                                <enumeratedValue>
                                    <name>0</name>
                                    <description>RTCIC2</description>
                                    <value>#0</value>
                                </enumeratedValue>
                                <enumeratedValue>
                                    <name>1</name>
                                    <description>VBTADF2</description>
                                    <value>#1</value>
                                </enumeratedValue>
                            </enumeratedValues>
                        </field>
                    </fields>
                </register>
                <register>
                    <name>VBTICTLR</name>
                    <description>VBATT Input Control Register</description>
                    <addressOffset>0xC4C</addressOffset>
                    <size>8</size>
                    <access>read-write</access>
                    <resetValue>0x00</resetValue>
                    <resetMask>0xff</resetMask>
                    <fields>
                        <field>
                            <name>VCH0INEN</name>
                            <description>VBATT CH0 Input Enable</description>
                            <lsb>0</lsb>
                            <msb>0</msb>
                            <access>read-write</access>
                            <enumeratedValues>
                                <enumeratedValue>
                                    <name>0</name>
                                    <description>RTCIC0 input disable</description>
                                    <value>#0</value>
                                </enumeratedValue>
                                <enumeratedValue>
                                    <name>1</name>
                                    <description>RTCIC0 input enable</description>
                                    <value>#1</value>
                                </enumeratedValue>
                            </enumeratedValues>
                        </field>
                        <field>
                            <name>VCH1INEN</name>
                            <description>VBATT CH1 Input Enable</description>
                            <lsb>1</lsb>
                            <msb>1</msb>
                            <access>read-write</access>
                            <enumeratedValues>
                                <enumeratedValue>
                                    <name>0</name>
                                    <description>RTCIC1 input disable</description>
                                    <value>#0</value>
                                </enumeratedValue>
                                <enumeratedValue>
                                    <name>1</name>
                                    <description>RTCIC1 input enable</description>
                                    <value>#1</value>
                                </enumeratedValue>
                            </enumeratedValues>
                        </field>
                        <field>
                            <name>VCH2INEN</name>
                            <description>VBATT CH2 Input Enable</description>
                            <lsb>2</lsb>
                            <msb>2</msb>
                            <access>read-write</access>
                            <enumeratedValues>
                                <enumeratedValue>
                                    <name>0</name>
                                    <description>RTCIC2 input disable</description>
                                    <value>#0</value>
                                </enumeratedValue>
                                <enumeratedValue>
                                    <name>1</name>
                                    <description>RTCIC2 input enable</description>
                                    <value>#1</value>
                                </enumeratedValue>
                            </enumeratedValues>
                        </field>
                    </fields>
                </register>
                <register>
                    <name>VBTICTLR2</name>
                    <description>VBATT Input Control Register 2</description>
                    <addressOffset>0xC4D</addressOffset>
                    <size>8</size>
                    <access>read-write</access>
                    <resetValue>0x70</resetValue>
                    <resetMask>0xff</resetMask>
                    <fields>
                        <field>
                            <name>VCH0NCE</name>
                            <description>VBATT CH0 Input Noise Canceler Enable</description>
                            <lsb>0</lsb>
                            <msb>0</msb>
                            <access>read-write</access>
                            <enumeratedValues>
                                <enumeratedValue>
                                    <name>0</name>
                                    <description>RTCIC0 pin input noise canceler disable</description>
                                    <value>#0</value>
                                </enumeratedValue>
                                <enumeratedValue>
                                    <name>1</name>
                                    <description>RTCIC0 pin input noise canceler enable</description>
                                    <value>#1</value>
                                </enumeratedValue>
                            </enumeratedValues>
                        </field>
                        <field>
                            <name>VCH1NCE</name>
                            <description>VBATT CH1 Input Noise Canceler Enable</description>
                            <lsb>1</lsb>
                            <msb>1</msb>
                            <access>read-write</access>
                            <enumeratedValues>
                                <enumeratedValue>
                                    <name>0</name>
                                    <description>RTCIC1 pin input noise canceler disable</description>
                                    <value>#0</value>
                                </enumeratedValue>
                                <enumeratedValue>
                                    <name>1</name>
                                    <description>RTCIC1 pin input noise canceler enable</description>
                                    <value>#1</value>
                                </enumeratedValue>
                            </enumeratedValues>
                        </field>
                        <field>
                            <name>VCH2NCE</name>
                            <description>VBATT CH2 Input Noise Canceler Enable</description>
                            <lsb>2</lsb>
                            <msb>2</msb>
                            <access>read-write</access>
                            <enumeratedValues>
                                <enumeratedValue>
                                    <name>0</name>
                                    <description>RTCIC2 pin input noise canceler disable</description>
                                    <value>#0</value>
                                </enumeratedValue>
                                <enumeratedValue>
                                    <name>1</name>
                                    <description>RTCIC2 pin input noise canceler enable</description>
                                    <value>#1</value>
                                </enumeratedValue>
                            </enumeratedValues>
                        </field>
                        <field>
                            <name>VCH0EG</name>
                            <description>VBATT CH0 Input Edge Select</description>
                            <lsb>4</lsb>
                            <msb>4</msb>
                            <access>read-write</access>
                            <enumeratedValues>
                                <enumeratedValue>
                                    <name>0</name>
                                    <description>RTCIC0 pin input event is detected on falling edge</description>
                                    <value>#0</value>
                                </enumeratedValue>
                                <enumeratedValue>
                                    <name>1</name>
                                    <description>RTCIC0 pin input event is detected on rising edge</description>
                                    <value>#1</value>
                                </enumeratedValue>
                            </enumeratedValues>
                        </field>
                        <field>
                            <name>VCH1EG</name>
                            <description>VBATT CH1 Input Edge Select</description>
                            <lsb>5</lsb>
                            <msb>5</msb>
                            <access>read-write</access>
                            <enumeratedValues>
                                <enumeratedValue>
                                    <name>0</name>
                                    <description>RTCIC1 pin input event is detected on falling edge</description>
                                    <value>#0</value>
                                </enumeratedValue>
                                <enumeratedValue>
                                    <name>1</name>
                                    <description>RTCIC1 pin input event is detected on rising edge</description>
                                    <value>#1</value>
                                </enumeratedValue>
                            </enumeratedValues>
                        </field>
                        <field>
                            <name>VCH2EG</name>
                            <description>VBATT CH2 Input Edge Select</description>
                            <lsb>6</lsb>
                            <msb>6</msb>
                            <access>read-write</access>
                            <enumeratedValues>
                                <enumeratedValue>
                                    <name>0</name>
                                    <description>RTCIC2 pin input event is detected on falling edge</description>
                                    <value>#0</value>
                                </enumeratedValue>
                                <enumeratedValue>
                                    <name>1</name>
                                    <description>RTCIC2 pin input event is detected on rising edge</description>
                                    <value>#1</value>
                                </enumeratedValue>
                            </enumeratedValues>
                        </field>
                    </fields>
                </register>
                <register>
                    <name>VBTIMONR</name>
                    <description>VBATT Input Monitor Register</description>
                    <addressOffset>0xC4E</addressOffset>
                    <size>8</size>
                    <access>read-only</access>
                    <resetValue>0x00</resetValue>
                    <resetMask>0xf8</resetMask>
                    <fields>
                        <field>
                            <name>VCH0MON</name>
                            <description>VBATT CH0 Input monitor</description>
                            <lsb>0</lsb>
                            <msb>0</msb>
                            <access>read-only</access>
                            <enumeratedValues>
                                <enumeratedValue>
                                    <name>0</name>
                                    <description>RTCIC0 pin input is low level</description>
                                    <value>#0</value>
                                </enumeratedValue>
                                <enumeratedValue>
                                    <name>1</name>
                                    <description>RTCIC0 pin input is high level.</description>
                                    <value>#1</value>
                                </enumeratedValue>
                            </enumeratedValues>
                        </field>
                        <field>
                            <name>VCH1MON</name>
                            <description>VBATT CH1 Input monitor</description>
                            <lsb>1</lsb>
                            <msb>1</msb>
                            <access>read-only</access>
                            <enumeratedValues>
                                <enumeratedValue>
                                    <name>0</name>
                                    <description>RTCIC1 pin input is low level</description>
                                    <value>#0</value>
                                </enumeratedValue>
                                <enumeratedValue>
                                    <name>1</name>
                                    <description>RTCIC1 pin input is high level</description>
                                    <value>#1</value>
                                </enumeratedValue>
                            </enumeratedValues>
                        </field>
                        <field>
                            <name>VCH2MON</name>
                            <description>VBATT CH2 Input monitor</description>
                            <lsb>2</lsb>
                            <msb>2</msb>
                            <access>read-only</access>
                            <enumeratedValues>
                                <enumeratedValue>
                                    <name>0</name>
                                    <description>RTCIC2 pin input is low level</description>
                                    <value>#0</value>
                                </enumeratedValue>
                                <enumeratedValue>
                                    <name>1</name>
                                    <description>RTCIC2 pin input is high level.</description>
                                    <value>#1</value>
                                </enumeratedValue>
                            </enumeratedValues>
                        </field>
                    </fields>
                </register>
                <register>
                    <dim>128</dim>
                    <dimIncrement>0x001</dimIncrement>
                    <name>VBTBKR[%s]</name>
                    <description>VBATT Backup Register</description>
                    <addressOffset>0xD00</addressOffset>
                    <size>8</size>
                    <access>read-write</access>
                    <resetValue>0x00</resetValue>
                    <resetMask>0xff</resetMask>
                </register>
            </registers>
        </peripheral>
        <peripheral>
            <name>TSD_NS</name>
            <description>Temperature Sensor Calibration Data</description>
            <baseAddress>0x5011B000</baseAddress>
            <addressBlock>
                <offset>0x17C</offset>
                <size>4</size>
                <usage>registers</usage>
            </addressBlock>
            <registers>
                <register>
                    <name>TSCDR</name>
                    <description>Temperature Sensor Calibration Data Register</description>
                    <addressOffset>0x017C</addressOffset>
                    <size>32</size>
                    <access>read-only</access>
                    <resetValue>0x00000000</resetValue>
                    <resetMask>0xffff0000</resetMask>
                    <fields>
                        <field>
                            <name>TSCDR</name>
                            <description>Temperature Sensor Calibration Data</description>
                            <lsb>0</lsb>
                            <msb>15</msb>
                            <access>read-only</access>
                        </field>
                    </fields>
                </register>
            </registers>
        </peripheral>
        <peripheral>
            <name>FLAD_NS</name>
            <description>Data Flash</description>
            <baseAddress>0x5011C000</baseAddress>
            <addressBlock>
                <offset>0x40</offset>
                <size>1</size>
                <usage>registers</usage>
            </addressBlock>
            <registers>
                <register>
                    <name>FCKMHZ</name>
                    <description>Data Flash Access Frequency Register</description>
                    <addressOffset>0x40</addressOffset>
                    <size>8</size>
                    <access>read-write</access>
                    <resetValue>0x3c</resetValue>
                    <resetMask>0xff</resetMask>
                    <fields>
                        <field>
                            <name>FCKMHZ</name>
                            <description>Data Flash Access Frequency Register</description>
                            <lsb>0</lsb>
                            <msb>7</msb>
                            <access>read-write</access>
                        </field>
                    </fields>
                </register>
            </registers>
        </peripheral>
        <peripheral>
            <name>FACI_NS</name>
            <description>Flash Application Command Interface</description>
            <baseAddress>0x5011E000</baseAddress>
            <addressBlock>
                <offset>0x10</offset>
                <size>1</size>
                <usage>registers</usage>
            </addressBlock>
            <addressBlock>
                <offset>0x14</offset>
                <size>1</size>
                <usage>registers</usage>
            </addressBlock>
            <addressBlock>
                <offset>0x18</offset>
                <size>1</size>
                <usage>registers</usage>
            </addressBlock>
            <addressBlock>
                <offset>0x30</offset>
                <size>8</size>
                <usage>registers</usage>
            </addressBlock>
            <addressBlock>
                <offset>0x78</offset>
                <size>2</size>
                <usage>registers</usage>
            </addressBlock>
            <addressBlock>
                <offset>0x80</offset>
                <size>6</size>
                <usage>registers</usage>
            </addressBlock>
            <addressBlock>
                <offset>0x8C</offset>
                <size>2</size>
                <usage>registers</usage>
            </addressBlock>
            <addressBlock>
                <offset>0xA0</offset>
                <size>2</size>
                <usage>registers</usage>
            </addressBlock>
            <addressBlock>
                <offset>0xD0</offset>
                <size>1</size>
                <usage>registers</usage>
            </addressBlock>
            <addressBlock>
                <offset>0xD4</offset>
                <size>1</size>
                <usage>registers</usage>
            </addressBlock>
            <addressBlock>
                <offset>0xD8</offset>
                <size>10</size>
                <usage>registers</usage>
            </addressBlock>
            <addressBlock>
                <offset>0xE4</offset>
                <size>2</size>
                <usage>registers</usage>
            </addressBlock>
            <registers>
                <register>
                    <name>FASTAT</name>
                    <description>Flash Access Status Register</description>
                    <addressOffset>0x10</addressOffset>
                    <size>8</size>
                    <access>read-write</access>
                    <resetValue>0x00</resetValue>
                    <resetMask>0xff</resetMask>
                    <fields>
                        <field>
                            <name>DFAE</name>
                            <description>Data Flash Memory Access Violation Flag</description>
                            <lsb>3</lsb>
                            <msb>3</msb>
                            <access>read-write</access>
                            <enumeratedValues>
                                <enumeratedValue>
                                    <name>0</name>
                                    <description>No data flash memory access violation has occurred</description>
                                    <value>#0</value>
                                </enumeratedValue>
                                <enumeratedValue>
                                    <name>1</name>
                                    <description>A data flash memory access violation has occurred.</description>
                                    <value>#1</value>
                                </enumeratedValue>
                            </enumeratedValues>
                        </field>
                        <field>
                            <name>CMDLK</name>
                            <description>Command Lock Flag</description>
                            <lsb>4</lsb>
                            <msb>4</msb>
                            <access>read-only</access>
                            <enumeratedValues>
                                <enumeratedValue>
                                    <name>0</name>
                                    <description>The flash sequencer is not in the command-locked state</description>
                                    <value>#0</value>
                                </enumeratedValue>
                                <enumeratedValue>
                                    <name>1</name>
                                    <description>The flash sequencer is in the command-locked state.</description>
                                    <value>#1</value>
                                </enumeratedValue>
                            </enumeratedValues>
                        </field>
                        <field>
                            <name>CFAE</name>
                            <description>Code Flash Memory Access Violation Flag</description>
                            <lsb>7</lsb>
                            <msb>7</msb>
                            <access>read-write</access>
                            <enumeratedValues>
                                <enumeratedValue>
                                    <name>0</name>
                                    <description>No code flash memory access violation has occurred</description>
                                    <value>#0</value>
                                </enumeratedValue>
                                <enumeratedValue>
                                    <name>1</name>
                                    <description>A code flash memory access violation has occurred.</description>
                                    <value>#1</value>
                                </enumeratedValue>
                            </enumeratedValues>
                        </field>
                    </fields>
                </register>
                <register>
                    <name>FAEINT</name>
                    <description>Flash Access Error Interrupt Enable Register</description>
                    <addressOffset>0x14</addressOffset>
                    <size>8</size>
                    <access>read-write</access>
                    <resetValue>0x98</resetValue>
                    <resetMask>0xff</resetMask>
                    <fields>
                        <field>
                            <name>DFAEIE</name>
                            <description>Data Flash Memory Access Violation Interrupt Enable</description>
                            <lsb>3</lsb>
                            <msb>3</msb>
                            <access>read-write</access>
                            <enumeratedValues>
                                <enumeratedValue>
                                    <name>0</name>
                                    <description>Generation of an FIFERR interrupt request is disabled when FASTAT.DFAE is set to 1</description>
                                    <value>#0</value>
                                </enumeratedValue>
                                <enumeratedValue>
                                    <name>1</name>
                                    <description>Generation of an FIFERR interrupt request is enabled when FASTAT.DFAE is set to 1.</description>
                                    <value>#1</value>
                                </enumeratedValue>
                            </enumeratedValues>
                        </field>
                        <field>
                            <name>CMDLKIE</name>
                            <description>Command Lock Interrupt Enable</description>
                            <lsb>4</lsb>
                            <msb>4</msb>
                            <access>read-write</access>
                            <enumeratedValues>
                                <enumeratedValue>
                                    <name>0</name>
                                    <description>Generation of an FIFERR interrupt request is disabled when FASTAT.CMDLK is set to 1</description>
                                    <value>#0</value>
                                </enumeratedValue>
                                <enumeratedValue>
                                    <name>1</name>
                                    <description>Generation of an FIFERR interrupt request is enabled when FASTAT.CMDLK is set to 1.</description>
                                    <value>#1</value>
                                </enumeratedValue>
                            </enumeratedValues>
                        </field>
                        <field>
                            <name>CFAEIE</name>
                            <description>Code Flash Memory Access Violation Interrupt Enable</description>
                            <lsb>7</lsb>
                            <msb>7</msb>
                            <access>read-write</access>
                            <enumeratedValues>
                                <enumeratedValue>
                                    <name>0</name>
                                    <description>Generation of an FIFERR interrupt request is disabled when FASTAT.CFAE is set to 1</description>
                                    <value>#0</value>
                                </enumeratedValue>
                                <enumeratedValue>
                                    <name>1</name>
                                    <description>Generation of an FIFERR interrupt request is enabled when FASTAT.CFAE is set to 1.</description>
                                    <value>#1</value>
                                </enumeratedValue>
                            </enumeratedValues>
                        </field>
                    </fields>
                </register>
                <register>
                    <name>FRDYIE</name>
                    <description>Flash Ready Interrupt Enable Register</description>
                    <addressOffset>0x18</addressOffset>
                    <size>8</size>
                    <access>read-write</access>
                    <resetValue>0x00</resetValue>
                    <resetMask>0xff</resetMask>
                    <fields>
                        <field>
                            <name>FRDYIE</name>
                            <description>Flash Ready Interrupt Enable</description>
                            <lsb>0</lsb>
                            <msb>0</msb>
                            <access>read-write</access>
                            <enumeratedValues>
                                <enumeratedValue>
                                    <name>0</name>
                                    <description>Generation of an FRDY interrupt request is disabled</description>
                                    <value>#0</value>
                                </enumeratedValue>
                                <enumeratedValue>
                                    <name>1</name>
                                    <description>Generation of an FRDY interrupt request is enabled.</description>
                                    <value>#1</value>
                                </enumeratedValue>
                            </enumeratedValues>
                        </field>
                    </fields>
                </register>
                <register>
                    <name>FSADDR</name>
                    <description>FACI Command Start Address Register</description>
                    <addressOffset>0x30</addressOffset>
                    <size>32</size>
                    <access>read-write</access>
                    <resetValue>0x00000000</resetValue>
                    <resetMask>0xffffffff</resetMask>
                    <fields>
                        <field>
                            <name>FSADDR</name>
                            <description>Start Address for FACI Command Processing</description>
                            <lsb>0</lsb>
                            <msb>31</msb>
                            <access>read-write</access>
                        </field>
                    </fields>
                </register>
                <register>
                    <name>FEADDR</name>
                    <description>FACI Command End Address Register</description>
                    <addressOffset>0x34</addressOffset>
                    <size>32</size>
                    <access>read-write</access>
                    <resetValue>0x00000000</resetValue>
                    <resetMask>0xffffffff</resetMask>
                    <fields>
                        <field>
                            <name>FEADDR</name>
                            <description>End Address for FACI Command Processing</description>
                            <lsb>0</lsb>
                            <msb>31</msb>
                            <access>read-write</access>
                        </field>
                    </fields>
                </register>
                <register>
                    <name>FBPROT0</name>
                    <description>Flash Block Protection Register</description>
                    <addressOffset>0x78</addressOffset>
                    <size>16</size>
                    <access>read-write</access>
                    <resetValue>0x0000</resetValue>
                    <resetMask>0xffff</resetMask>
                    <fields>
                        <field>
                            <name>BPCN0</name>
                            <description>Block Protection for Non-secure Cancel</description>
                            <lsb>0</lsb>
                            <msb>0</msb>
                            <access>read-write</access>
                            <enumeratedValues>
                                <enumeratedValue>
                                    <name>0</name>
                                    <description>Block protection is enabled</description>
                                    <value>#0</value>
                                </enumeratedValue>
                                <enumeratedValue>
                                    <name>1</name>
                                    <description>Block protection is disabled. </description>
                                    <value>#1</value>
                                </enumeratedValue>
                            </enumeratedValues>
                        </field>
                        <field>
                            <name>KEY</name>
                            <description>Key Code</description>
                            <lsb>8</lsb>
                            <msb>15</msb>
                            <access>write-only</access>
                        </field>
                    </fields>
                </register>
                <register>
                    <name>FSTATR</name>
                    <description>Flash Status Register</description>
                    <addressOffset>0x80</addressOffset>
                    <size>32</size>
                    <access>read-only</access>
                    <resetValue>0x00008000</resetValue>
                    <resetMask>0xffffffff</resetMask>
                    <fields>
                        <field>
                            <name>FLWEERR</name>
                            <description>Flash Write/Erase Protect Error Flag</description>
                            <lsb>6</lsb>
                            <msb>6</msb>
                            <access>read-only</access>
                            <enumeratedValues>
                                <enumeratedValue>
                                    <name>0</name>
                                    <description>An error has not occurred</description>
                                    <value>#0</value>
                                </enumeratedValue>
                                <enumeratedValue>
                                    <name>1</name>
                                    <description>An error has occurred.</description>
                                    <value>#1</value>
                                </enumeratedValue>
                            </enumeratedValues>
                        </field>
                        <field>
                            <name>PRGSPD</name>
                            <description>Programming Suspend Status Flag</description>
                            <lsb>8</lsb>
                            <msb>8</msb>
                            <access>read-only</access>
                            <enumeratedValues>
                                <enumeratedValue>
                                    <name>0</name>
                                    <description>The flash sequencer is not in the programming suspension processing state or programming suspended state</description>
                                    <value>#0</value>
                                </enumeratedValue>
                                <enumeratedValue>
                                    <name>1</name>
                                    <description>The flash sequencer is in the programming suspension processing state or programming suspended state.</description>
                                    <value>#1</value>
                                </enumeratedValue>
                            </enumeratedValues>
                        </field>
                        <field>
                            <name>ERSSPD</name>
                            <description>Erasure Suspend Status Flag</description>
                            <lsb>9</lsb>
                            <msb>9</msb>
                            <access>read-only</access>
                            <enumeratedValues>
                                <enumeratedValue>
                                    <name>0</name>
                                    <description>The flash sequencer is not in the erasure suspension processing state or the erasure suspended state</description>
                                    <value>#0</value>
                                </enumeratedValue>
                                <enumeratedValue>
                                    <name>1</name>
                                    <description>The flash sequencer is in the erasure suspension processing state or the erasure suspended state.</description>
                                    <value>#1</value>
                                </enumeratedValue>
                            </enumeratedValues>
                        </field>
                        <field>
                            <name>DBFULL</name>
                            <description>Data Buffer Full Flag</description>
                            <lsb>10</lsb>
                            <msb>10</msb>
                            <access>read-only</access>
                            <enumeratedValues>
                                <enumeratedValue>
                                    <name>0</name>
                                    <description>The data buffer is empty</description>
                                    <value>#0</value>
                                </enumeratedValue>
                                <enumeratedValue>
                                    <name>1</name>
                                    <description>The data buffer is full.</description>
                                    <value>#1</value>
                                </enumeratedValue>
                            </enumeratedValues>
                        </field>
                        <field>
                            <name>SUSRDY</name>
                            <description>Suspend Ready Flag</description>
                            <lsb>11</lsb>
                            <msb>11</msb>
                            <access>read-only</access>
                            <enumeratedValues>
                                <enumeratedValue>
                                    <name>0</name>
                                    <description>The flash sequencer cannot receive P/E suspend commands</description>
                                    <value>#0</value>
                                </enumeratedValue>
                                <enumeratedValue>
                                    <name>1</name>
                                    <description>The flash sequencer can receive P/E suspend commands.</description>
                                    <value>#1</value>
                                </enumeratedValue>
                            </enumeratedValues>
                        </field>
                        <field>
                            <name>PRGERR</name>
                            <description>Programming Error Flag</description>
                            <lsb>12</lsb>
                            <msb>12</msb>
                            <access>read-only</access>
                            <enumeratedValues>
                                <enumeratedValue>
                                    <name>0</name>
                                    <description>Programming has completed successfully</description>
                                    <value>#0</value>
                                </enumeratedValue>
                                <enumeratedValue>
                                    <name>1</name>
                                    <description>An error has occurred during programming.</description>
                                    <value>#1</value>
                                </enumeratedValue>
                            </enumeratedValues>
                        </field>
                        <field>
                            <name>ERSERR</name>
                            <description>Erasure Error Flag</description>
                            <lsb>13</lsb>
                            <msb>13</msb>
                            <access>read-only</access>
                            <enumeratedValues>
                                <enumeratedValue>
                                    <name>0</name>
                                    <description>Erasure has completed successfully</description>
                                    <value>#0</value>
                                </enumeratedValue>
                                <enumeratedValue>
                                    <name>1</name>
                                    <description>An error has occurred during erasure.</description>
                                    <value>#1</value>
                                </enumeratedValue>
                            </enumeratedValues>
                        </field>
                        <field>
                            <name>ILGLERR</name>
                            <description>Illegal Command Error Flag</description>
                            <lsb>14</lsb>
                            <msb>14</msb>
                            <access>read-only</access>
                            <enumeratedValues>
                                <enumeratedValue>
                                    <name>0</name>
                                    <description>The flash sequencer has not detected an illegal FACI command or illegal flash memory access</description>
                                    <value>#0</value>
                                </enumeratedValue>
                                <enumeratedValue>
                                    <name>1</name>
                                    <description>The flash sequencer has detected an illegal FACI command or illegal flash memory access.</description>
                                    <value>#1</value>
                                </enumeratedValue>
                            </enumeratedValues>
                        </field>
                        <field>
                            <name>FRDY</name>
                            <description>Flash Ready Flag</description>
                            <lsb>15</lsb>
                            <msb>15</msb>
                            <access>read-only</access>
                            <enumeratedValues>
                                <enumeratedValue>
                                    <name>0</name>
                                    <description>Program, Block Erase, Multi Block Erase, P/E suspend, P/E resume, Forced Stop, Blank Check, Configuration set, Increment counter, Refresh counter, or Read counter command processing is in progress.</description>
                                    <value>#0</value>
                                </enumeratedValue>
                                <enumeratedValue>
                                    <name>1</name>
                                    <description>None of the above is in progress.</description>
                                    <value>#1</value>
                                </enumeratedValue>
                            </enumeratedValues>
                        </field>
                        <field>
                            <name>TZFERR</name>
                            <description>TrustZone Filter Error</description>
                            <lsb>19</lsb>
                            <msb>19</msb>
                            <access>read-only</access>
                            <enumeratedValues>
                                <enumeratedValue>
                                    <name>0</name>
                                    <description>A TrustZone filter error has not been detected.</description>
                                    <value>#0</value>
                                </enumeratedValue>
                                <enumeratedValue>
                                    <name>1</name>
                                    <description>A TrustZone filter error has been detected.</description>
                                    <value>#1</value>
                                </enumeratedValue>
                            </enumeratedValues>
                        </field>
                        <field>
                            <name>OTERR</name>
                            <description>Other Error</description>
                            <lsb>20</lsb>
                            <msb>20</msb>
                            <access>read-only</access>
                            <enumeratedValues>
                                <enumeratedValue>
                                    <name>0</name>
                                    <description>An error has not been detected.</description>
                                    <value>#0</value>
                                </enumeratedValue>
                                <enumeratedValue>
                                    <name>1</name>
                                    <description>An error has been detected.</description>
                                    <value>#1</value>
                                </enumeratedValue>
                            </enumeratedValues>
                        </field>
                        <field>
                            <name>SECERR</name>
                            <description>Security Error</description>
                            <lsb>21</lsb>
                            <msb>21</msb>
                            <access>read-only</access>
                            <enumeratedValues>
                                <enumeratedValue>
                                    <name>0</name>
                                    <description>A write protection error against MSUASMON.FSPR bit has not been detected.</description>
                                    <value>#0</value>
                                </enumeratedValue>
                                <enumeratedValue>
                                    <name>1</name>
                                    <description>A write protection error against MSUASMON.FSPR bit has been detected.</description>
                                    <value>#1</value>
                                </enumeratedValue>
                            </enumeratedValues>
                        </field>
                        <field>
                            <name>FESETERR</name>
                            <description>FENTRY Setting Error</description>
                            <lsb>22</lsb>
                            <msb>22</msb>
                            <access>read-only</access>
                            <enumeratedValues>
                                <enumeratedValue>
                                    <name>0</name>
                                    <description>A setting error in the FENTRYR register has not been detected.</description>
                                    <value>#0</value>
                                </enumeratedValue>
                                <enumeratedValue>
                                    <name>1</name>
                                    <description>A setting error in the FENTRYR register has been detected.</description>
                                    <value>#1</value>
                                </enumeratedValue>
                            </enumeratedValues>
                        </field>
                        <field>
                            <name>ILGCOMERR</name>
                            <description>Illegal Command Error</description>
                            <lsb>23</lsb>
                            <msb>23</msb>
                            <access>read-only</access>
                            <enumeratedValues>
                                <enumeratedValue>
                                    <name>0</name>
                                    <description>An illegal FACI command error has not been detected.</description>
                                    <value>#0</value>
                                </enumeratedValue>
                                <enumeratedValue>
                                    <name>1</name>
                                    <description>An illegal FACI command error has been detected.</description>
                                    <value>#1</value>
                                </enumeratedValue>
                            </enumeratedValues>
                        </field>
                    </fields>
                </register>
                <register>
                    <name>FENTRYR</name>
                    <description>Flash P/E Mode Entry Register</description>
                    <addressOffset>0x84</addressOffset>
                    <size>16</size>
                    <access>read-write</access>
                    <resetValue>0x0000</resetValue>
                    <resetMask>0xffff</resetMask>
                    <fields>
                        <field>
                            <name>FENTRYC</name>
                            <description>Code Flash P/E Mode Entry</description>
                            <lsb>0</lsb>
                            <msb>0</msb>
                            <access>read-write</access>
                            <enumeratedValues>
                                <enumeratedValue>
                                    <name>0</name>
                                    <description>Code flash is in read mode</description>
                                    <value>#0</value>
                                </enumeratedValue>
                                <enumeratedValue>
                                    <name>1</name>
                                    <description>Code flash is in P/E mode.</description>
                                    <value>#1</value>
                                </enumeratedValue>
                            </enumeratedValues>
                        </field>
                        <field>
                            <name>FENTRYD</name>
                            <description>Data Flash P/E Mode Entry</description>
                            <lsb>7</lsb>
                            <msb>7</msb>
                            <access>read-write</access>
                            <enumeratedValues>
                                <enumeratedValue>
                                    <name>0</name>
                                    <description>Data flash is in read mode</description>
                                    <value>#0</value>
                                </enumeratedValue>
                                <enumeratedValue>
                                    <name>1</name>
                                    <description>Data flash is in P/E mode.</description>
                                    <value>#1</value>
                                </enumeratedValue>
                            </enumeratedValues>
                        </field>
                        <field>
                            <name>KEY</name>
                            <description>Key Code</description>
                            <lsb>8</lsb>
                            <msb>15</msb>
                            <access>write-only</access>
                        </field>
                    </fields>
                </register>
                <register>
                    <name>FSUINITR</name>
                    <description>Flash Sequencer Setup Initialization Register</description>
                    <addressOffset>0x8C</addressOffset>
                    <size>16</size>
                    <access>read-write</access>
                    <resetValue>0x0000</resetValue>
                    <resetMask>0xffff</resetMask>
                    <fields>
                        <field>
                            <name>SUINIT</name>
                            <description>Set-Up Initialization</description>
                            <lsb>0</lsb>
                            <msb>0</msb>
                            <access>read-write</access>
                            <enumeratedValues>
                                <enumeratedValue>
                                    <name>0</name>
                                    <description>The FSADDR, FEADDR, FBPROT0, FBPROT1, FENTRYR, FBCCNT, FCPSR, and FCNTSELR flash sequencer setup registers keep their current values</description>
                                    <value>#0</value>
                                </enumeratedValue>
                                <enumeratedValue>
                                    <name>1</name>
                                    <description>The FSADDR, FEADDR, FBPROT0, FBRPOT1, FENTRYR, FBCCNT, FCPSR, and FCNTSELR flash sequencer setup registers are initialized.</description>
                                    <value>#1</value>
                                </enumeratedValue>
                            </enumeratedValues>
                        </field>
                        <field>
                            <name>KEY</name>
                            <description>Key Code</description>
                            <lsb>8</lsb>
                            <msb>15</msb>
                            <access>write-only</access>
                        </field>
                    </fields>
                </register>
                <register>
                    <name>FCMDR</name>
                    <description>FACI Command Register</description>
                    <addressOffset>0xA0</addressOffset>
                    <size>16</size>
                    <access>read-only</access>
                    <resetValue>0x0000</resetValue>
                    <resetMask>0xffff</resetMask>
                    <fields>
                        <field>
                            <name>PCMDR</name>
                            <description>Pre-command Flag</description>
                            <lsb>0</lsb>
                            <msb>7</msb>
                            <access>read-only</access>
                        </field>
                        <field>
                            <name>CMDR</name>
                            <description>Command Flag</description>
                            <lsb>8</lsb>
                            <msb>15</msb>
                            <access>read-only</access>
                        </field>
                    </fields>
                </register>
                <register>
                    <name>FBCCNT</name>
                    <description>Blank Check Control Register</description>
                    <addressOffset>0xD0</addressOffset>
                    <size>8</size>
                    <access>read-write</access>
                    <resetValue>0x00</resetValue>
                    <resetMask>0xff</resetMask>
                    <fields>
                        <field>
                            <name>BCDIR</name>
                            <description>Blank Check Direction</description>
                            <lsb>0</lsb>
                            <msb>0</msb>
                            <access>read-write</access>
                            <enumeratedValues>
                                <enumeratedValue>
                                    <name>0</name>
                                    <description>Blank checking is executed from the lower addresses to the higher addresses (incremental mode)</description>
                                    <value>#0</value>
                                </enumeratedValue>
                                <enumeratedValue>
                                    <name>1</name>
                                    <description>Blank checking is executed from the higher addresses to the lower addresses (decremental mode).</description>
                                    <value>#1</value>
                                </enumeratedValue>
                            </enumeratedValues>
                        </field>
                    </fields>
                </register>
                <register>
                    <name>FBCSTAT</name>
                    <description>Blank Check Status Register</description>
                    <addressOffset>0xD4</addressOffset>
                    <size>8</size>
                    <access>read-only</access>
                    <resetValue>0x00</resetValue>
                    <resetMask>0xff</resetMask>
                    <fields>
                        <field>
                            <name>BCST</name>
                            <description>Blank Check Status Flag</description>
                            <lsb>0</lsb>
                            <msb>0</msb>
                            <access>read-only</access>
                            <enumeratedValues>
                                <enumeratedValue>
                                    <name>0</name>
                                    <description>The target area is in the non-programmed state, that is, the area has been erased but has not yet been reprogrammed</description>
                                    <value>#0</value>
                                </enumeratedValue>
                                <enumeratedValue>
                                    <name>1</name>
                                    <description>The target area has been programmed with 0s or 1s.</description>
                                    <value>#1</value>
                                </enumeratedValue>
                            </enumeratedValues>
                        </field>
                    </fields>
                </register>
                <register>
                    <name>FPSADDR</name>
                    <description>Data Flash Programming Start Address Register</description>
                    <addressOffset>0xD8</addressOffset>
                    <size>32</size>
                    <access>read-only</access>
                    <resetValue>0x00000000</resetValue>
                    <resetMask>0xffffffff</resetMask>
                    <fields>
                        <field>
                            <name>PSADR</name>
                            <description>Programmed Area Start Address</description>
                            <lsb>0</lsb>
                            <msb>16</msb>
                            <access>read-only</access>
                        </field>
                    </fields>
                </register>
                <register>
                    <name>FSUASMON</name>
                    <description>Flash Startup Area Select Monitor Register</description>
                    <addressOffset>0xDC</addressOffset>
                    <size>32</size>
                    <access>read-only</access>
                    <resetValue>0x00000000</resetValue>
                    <resetMask>0x7fff7fff</resetMask>
                    <fields>
                        <field>
                            <name>FSPR</name>
                            <description>Protection Programming Flag to set Boot Flag and Startup Area Control</description>
                            <lsb>15</lsb>
                            <msb>15</msb>
                            <access>read-only</access>
                            <enumeratedValues>
                                <enumeratedValue>
                                    <name>0</name>
                                    <description>Protected state</description>
                                    <value>#0</value>
                                </enumeratedValue>
                                <enumeratedValue>
                                    <name>1</name>
                                    <description>Non-protected state.</description>
                                    <value>#1</value>
                                </enumeratedValue>
                            </enumeratedValues>
                        </field>
                        <field>
                            <name>BTFLG</name>
                            <description>Flag of Startup Area Select for Boot Swap</description>
                            <lsb>31</lsb>
                            <msb>31</msb>
                            <access>read-only</access>
                            <enumeratedValues>
                                <enumeratedValue>
                                    <name>0</name>
                                    <description>The startup area is the alternate block (block 1)</description>
                                    <value>#0</value>
                                </enumeratedValue>
                                <enumeratedValue>
                                    <name>1</name>
                                    <description>The startup area is the default block (block 0).</description>
                                    <value>#1</value>
                                </enumeratedValue>
                            </enumeratedValues>
                        </field>
                    </fields>
                </register>
                <register>
                    <name>FCPSR</name>
                    <description>Flash Sequencer Processing Switching Register</description>
                    <addressOffset>0xE0</addressOffset>
                    <size>16</size>
                    <access>read-write</access>
                    <resetValue>0x0000</resetValue>
                    <resetMask>0xffff</resetMask>
                    <fields>
                        <field>
                            <name>ESUSPMD</name>
                            <description>Erasure Suspend Mode</description>
                            <lsb>0</lsb>
                            <msb>0</msb>
                            <access>read-write</access>
                            <enumeratedValues>
                                <enumeratedValue>
                                    <name>0</name>
                                    <description>Suspension priority mode</description>
                                    <value>#0</value>
                                </enumeratedValue>
                                <enumeratedValue>
                                    <name>1</name>
                                    <description>Erasure priority mode.</description>
                                    <value>#1</value>
                                </enumeratedValue>
                            </enumeratedValues>
                        </field>
                    </fields>
                </register>
                <register>
                    <name>FPCKAR</name>
                    <description>Flash Sequencer Processing Clock Notification Register</description>
                    <addressOffset>0xE4</addressOffset>
                    <size>16</size>
                    <access>read-write</access>
                    <resetValue>0x003c</resetValue>
                    <resetMask>0xffff</resetMask>
                    <fields>
                        <field>
                            <name>PCKA</name>
                            <description>Flash Sequencer Operating Clock Notification</description>
                            <lsb>0</lsb>
                            <msb>7</msb>
                            <access>read-write</access>
                        </field>
                        <field>
                            <name>KEY</name>
                            <description>Key Code</description>
                            <lsb>8</lsb>
                            <msb>15</msb>
                            <access>write-only</access>
                        </field>
                    </fields>
                </register>
            </registers>
        </peripheral>
        <peripheral>
            <name>ELC_NS</name>
            <description>Event Link Controller</description>
            <baseAddress>0x50201000</baseAddress>
            <addressBlock>
                <offset>0x00</offset>
                <size>1</size>
                <usage>registers</usage>
            </addressBlock>
            <addressBlock>
                <offset>0x04</offset>
                <size>8</size>
                <usage>registers</usage>
            </addressBlock>
            <addressBlock>
                <offset>0x20</offset>
                <size>72</size>
                <usage>registers</usage>
            </addressBlock>
            <addressBlock>
                <offset>0x98</offset>
                <size>2</size>
                <usage>registers</usage>
            </addressBlock>
            <addressBlock>
                <offset>0xE0</offset>
                <size>8</size>
                <usage>registers</usage>
            </addressBlock>
            <addressBlock>
                <offset>0xF0</offset>
                <size>8</size>
                <usage>registers</usage>
            </addressBlock>
            <registers>
                <register>
                    <name>ELCR</name>
                    <description>Event Link Controller Register</description>
                    <addressOffset>0x00</addressOffset>
                    <size>8</size>
                    <access>read-write</access>
                    <resetValue>0x00</resetValue>
                    <resetMask>0xff</resetMask>
                    <fields>
                        <field>
                            <name>ELCON</name>
                            <description>All Event Link Enable</description>
                            <lsb>7</lsb>
                            <msb>7</msb>
                            <access>read-write</access>
                            <enumeratedValues>
                                <enumeratedValue>
                                    <name>0</name>
                                    <description>ELC function is disabled.</description>
                                    <value>#0</value>
                                </enumeratedValue>
                                <enumeratedValue>
                                    <name>1</name>
                                    <description>ELC function is enabled.</description>
                                    <value>#1</value>
                                </enumeratedValue>
                            </enumeratedValues>
                        </field>
                    </fields>
                </register>
                <register>
                    <dim>2</dim>
                    <dimIncrement>0x04</dimIncrement>
                    <dimIndex>0-1</dimIndex>
                    <name>ELSEGR%s</name>
                    <description>Event Link Software Event Generation Register %s</description>
                    <addressOffset>0x04</addressOffset>
                    <size>8</size>
                    <access>read-write</access>
                    <resetValue>0x80</resetValue>
                    <resetMask>0xff</resetMask>
                    <fields>
                        <field>
                            <name>SEG</name>
                            <description>Software Event Generation</description>
                            <lsb>0</lsb>
                            <msb>0</msb>
                            <access>write-only</access>
                            <enumeratedValues>
                                <enumeratedValue>
                                    <name>0</name>
                                    <description>Normal operation</description>
                                    <value>#0</value>
                                </enumeratedValue>
                                <enumeratedValue>
                                    <name>1</name>
                                    <description>Software event is generated.</description>
                                    <value>#1</value>
                                </enumeratedValue>
                            </enumeratedValues>
                        </field>
                        <field>
                            <name>WE</name>
                            <description>SEG Bit Write Enable</description>
                            <lsb>6</lsb>
                            <msb>6</msb>
                            <access>read-write</access>
                            <enumeratedValues>
                                <enumeratedValue>
                                    <name>0</name>
                                    <description>Write to SEG bit disabled.</description>
                                    <value>#0</value>
                                </enumeratedValue>
                                <enumeratedValue>
                                    <name>1</name>
                                    <description>Write to SEG bit enabled.</description>
                                    <value>#1</value>
                                </enumeratedValue>
                            </enumeratedValues>
                        </field>
                        <field>
                            <name>WI</name>
                            <description>ELSEGR Register Write Disable</description>
                            <lsb>7</lsb>
                            <msb>7</msb>
                            <access>write-only</access>
                            <enumeratedValues>
                                <enumeratedValue>
                                    <name>0</name>
                                    <description>Write to ELSEGR register enabled.</description>
                                    <value>#0</value>
                                </enumeratedValue>
                                <enumeratedValue>
                                    <name>1</name>
                                    <description>Write to ELSEGR register disabled.</description>
                                    <value>#1</value>
                                </enumeratedValue>
                            </enumeratedValues>
                        </field>
                    </fields>
                </register>
                <register>
                    <dim>18</dim>
                    <dimIncrement>0x04</dimIncrement>
                    <dimIndex>0-17</dimIndex>
                    <name>ELSR%s</name>
                    <description>Event Link Setting Registern</description>
                    <addressOffset>0x20</addressOffset>
                    <size>16</size>
                    <access>read-write</access>
                    <resetValue>0x0000</resetValue>
                    <resetMask>0xffff</resetMask>
                    <fields>
                        <field>
                            <name>ELS</name>
                            <description>Event Link Select</description>
                            <lsb>0</lsb>
                            <msb>8</msb>
                            <access>read-write</access>
                        </field>
                    </fields>
                </register>
                <register>
                    <name>ELSR30</name>
                    <description>Event Link Setting Register30</description>
                    <addressOffset>0x98</addressOffset>
                    <size>16</size>
                    <access>read-write</access>
                    <resetValue>0x0000</resetValue>
                    <resetMask>0xffff</resetMask>
                    <fields>
                        <field>
                            <name>ELS</name>
                            <description>Event Link Select</description>
                            <lsb>0</lsb>
                            <msb>8</msb>
                            <access>read-write</access>
                        </field>
                    </fields>
                </register>
                <register>
                    <name>ELCSARA</name>
                    <description>Event Link Controller Security Attribution Register A</description>
                    <addressOffset>0xE0</addressOffset>
                    <size>32</size>
                    <access>read-write</access>
                    <resetValue>0x00000000</resetValue>
                    <resetMask>0xffffffff</resetMask>
                    <fields>
                        <field>
                            <name>ELCR</name>
                            <description>Event Link Controller Register Security Attribution</description>
                            <lsb>0</lsb>
                            <msb>0</msb>
                            <access>read-write</access>
                            <enumeratedValues>
                                <enumeratedValue>
                                    <name>0</name>
                                    <description>Secure</description>
                                    <value>#0</value>
                                </enumeratedValue>
                                <enumeratedValue>
                                    <name>1</name>
                                    <description>Non-secure</description>
                                    <value>#1</value>
                                </enumeratedValue>
                            </enumeratedValues>
                        </field>
                        <field>
                            <name>ELSEGR0</name>
                            <description>Event Link Software Event Generation Register 0 Security Attribution</description>
                            <lsb>1</lsb>
                            <msb>1</msb>
                            <access>read-write</access>
                            <enumeratedValues>
                                <enumeratedValue>
                                    <name>0</name>
                                    <description>Secure</description>
                                    <value>#0</value>
                                </enumeratedValue>
                                <enumeratedValue>
                                    <name>1</name>
                                    <description>Non-secure</description>
                                    <value>#1</value>
                                </enumeratedValue>
                            </enumeratedValues>
                        </field>
                        <field>
                            <name>ELSEGR1</name>
                            <description>Event Link Software Event Generation Register 1 Security Attribution</description>
                            <lsb>2</lsb>
                            <msb>2</msb>
                            <access>read-write</access>
                            <enumeratedValues>
                                <enumeratedValue>
                                    <name>0</name>
                                    <description>Secure</description>
                                    <value>#0</value>
                                </enumeratedValue>
                                <enumeratedValue>
                                    <name>1</name>
                                    <description>Non-secure</description>
                                    <value>#1</value>
                                </enumeratedValue>
                            </enumeratedValues>
                        </field>
                    </fields>
                </register>
                <register>
                    <name>ELCSARB</name>
                    <description>Event Link Controller Security Attribution Register B</description>
                    <addressOffset>0xE4</addressOffset>
                    <size>32</size>
                    <access>read-write</access>
                    <resetValue>0x00000000</resetValue>
                    <resetMask>0xffffffff</resetMask>
                    <fields>
                        <field>
                            <name>ELSR</name>
                            <description>Event Link Setting Register n Security Attribution</description>
                            <lsb>0</lsb>
                            <msb>17</msb>
                            <access>read-write</access>
                            <enumeratedValues>
                                <enumeratedValue>
                                    <name>0</name>
                                    <description>Secure</description>
                                    <value>#0</value>
                                </enumeratedValue>
                                <enumeratedValue>
                                    <name>1</name>
                                    <description>Non-secure</description>
                                    <value>#1</value>
                                </enumeratedValue>
                            </enumeratedValues>
                        </field>
                    </fields>
                </register>
                <register>
                    <name>ELCPARA</name>
                    <description>Event Link Controller Privilege Attribution Register A</description>
                    <addressOffset>0xF0</addressOffset>
                    <size>32</size>
                    <access>read-write</access>
                    <resetValue>0xffffffff</resetValue>
                    <resetMask>0xffffffff</resetMask>
                    <fields>
                        <field>
                            <name>ELCR</name>
                            <description>Event Link Controller Register Privilege Attribution</description>
                            <lsb>0</lsb>
                            <msb>0</msb>
                            <access>read-write</access>
                            <enumeratedValues>
                                <enumeratedValue>
                                    <name>0</name>
                                    <description>Privileged</description>
                                    <value>#0</value>
                                </enumeratedValue>
                                <enumeratedValue>
                                    <name>1</name>
                                    <description>Unprivileged</description>
                                    <value>#1</value>
                                </enumeratedValue>
                            </enumeratedValues>
                        </field>
                        <field>
                            <name>ELSEGR0</name>
                            <description>Event Link Software Event Generation Register 0 Privilege Attribution</description>
                            <lsb>1</lsb>
                            <msb>1</msb>
                            <access>read-write</access>
                            <enumeratedValues>
                                <enumeratedValue>
                                    <name>0</name>
                                    <description>Privileged</description>
                                    <value>#0</value>
                                </enumeratedValue>
                                <enumeratedValue>
                                    <name>1</name>
                                    <description>Unprivileged</description>
                                    <value>#1</value>
                                </enumeratedValue>
                            </enumeratedValues>
                        </field>
                        <field>
                            <name>ELSEGR1</name>
                            <description>Event Link Software Event Generation Register 1 Privilege Attribution</description>
                            <lsb>2</lsb>
                            <msb>2</msb>
                            <access>read-write</access>
                            <enumeratedValues>
                                <enumeratedValue>
                                    <name>0</name>
                                    <description>Privileged</description>
                                    <value>#0</value>
                                </enumeratedValue>
                                <enumeratedValue>
                                    <name>1</name>
                                    <description>Unprivileged</description>
                                    <value>#1</value>
                                </enumeratedValue>
                            </enumeratedValues>
                        </field>
                    </fields>
                </register>
                <register>
                    <name>ELCPARB</name>
                    <description>Event Link Controller Privilege Attribution Register B</description>
                    <addressOffset>0xF4</addressOffset>
                    <size>32</size>
                    <access>read-write</access>
                    <resetValue>0xffffffff</resetValue>
                    <resetMask>0xffffffff</resetMask>
                    <fields>
                        <field>
                            <name>ELSR</name>
                            <description>Event Link Setting Register n Privilege Attribution</description>
                            <lsb>0</lsb>
                            <msb>17</msb>
                            <access>read-write</access>
                            <enumeratedValues>
                                <enumeratedValue>
                                    <name>0</name>
                                    <description>Privileged</description>
                                    <value>#0</value>
                                </enumeratedValue>
                                <enumeratedValue>
                                    <name>1</name>
                                    <description>Unprivileged</description>
                                    <value>#1</value>
                                </enumeratedValue>
                            </enumeratedValues>
                        </field>
                    </fields>
                </register>
            </registers>
        </peripheral>
        <peripheral>
            <name>RTC_NS</name>
            <description>Realtime Clock</description>
            <baseAddress>0x50202000</baseAddress>
            <addressBlock>
                <offset>0x00</offset>
                <size>1</size>
                <usage>registers</usage>
            </addressBlock>
            <addressBlock>
                <offset>0x02</offset>
                <size>8</size>
                <usage>registers</usage>
            </addressBlock>
            <addressBlock>
                <offset>0x0A</offset>
                <size>1</size>
                <usage>registers</usage>
            </addressBlock>
            <addressBlock>
                <offset>0x0C</offset>
                <size>1</size>
                <usage>registers</usage>
            </addressBlock>
            <addressBlock>
                <offset>0x0E</offset>
                <size>10</size>
                <usage>registers</usage>
            </addressBlock>
            <addressBlock>
                <offset>0x18</offset>
                <size>8</size>
                <usage>registers</usage>
            </addressBlock>
            <addressBlock>
                <offset>0x22</offset>
                <size>1</size>
                <usage>registers</usage>
            </addressBlock>
            <addressBlock>
                <offset>0x24</offset>
                <size>1</size>
                <usage>registers</usage>
            </addressBlock>
            <addressBlock>
                <offset>0x28</offset>
                <size>1</size>
                <usage>registers</usage>
            </addressBlock>
            <addressBlock>
                <offset>0x2A</offset>
                <size>5</size>
                <usage>registers</usage>
            </addressBlock>
            <addressBlock>
                <offset>0x40</offset>
                <size>6</size>
                <usage>registers</usage>
            </addressBlock>
            <addressBlock>
                <offset>0x52</offset>
                <size>58</size>
                <usage>registers</usage>
            </addressBlock>
            <registers>
                <register>
                    <name>R64CNT</name>
                    <description>64-Hz Counter</description>
                    <addressOffset>0x00</addressOffset>
                    <size>8</size>
                    <access>read-only</access>
                    <resetValue>0x00</resetValue>
                    <resetMask>0x80</resetMask>
                    <fields>
                        <field>
                            <name>F64HZ</name>
                            <description>64-Hz Flag</description>
                            <lsb>0</lsb>
                            <msb>0</msb>
                            <access>read-only</access>
                        </field>
                        <field>
                            <name>F32HZ</name>
                            <description>32-Hz Flag</description>
                            <lsb>1</lsb>
                            <msb>1</msb>
                            <access>read-only</access>
                        </field>
                        <field>
                            <name>F16HZ</name>
                            <description>16-Hz Flag</description>
                            <lsb>2</lsb>
                            <msb>2</msb>
                            <access>read-only</access>
                        </field>
                        <field>
                            <name>F8HZ</name>
                            <description>8-Hz Flag</description>
                            <lsb>3</lsb>
                            <msb>3</msb>
                            <access>read-only</access>
                        </field>
                        <field>
                            <name>F4HZ</name>
                            <description>4-Hz Flag</description>
                            <lsb>4</lsb>
                            <msb>4</msb>
                            <access>read-only</access>
                        </field>
                        <field>
                            <name>F2HZ</name>
                            <description>2-Hz Flag</description>
                            <lsb>5</lsb>
                            <msb>5</msb>
                            <access>read-only</access>
                        </field>
                        <field>
                            <name>F1HZ</name>
                            <description>1-Hz Flag</description>
                            <lsb>6</lsb>
                            <msb>6</msb>
                            <access>read-only</access>
                        </field>
                    </fields>
                </register>
                <register>
                    <dim>4</dim>
                    <dimIncrement>0x02</dimIncrement>
                    <dimIndex>0-3</dimIndex>
                    <name>BCNT%s</name>
                    <description>Binary Counter %s</description>
                    <addressOffset>0x02</addressOffset>
                    <size>8</size>
                    <access>read-write</access>
                    <resetValue>0x00</resetValue>
                    <resetMask>0x00</resetMask>
                    <fields>
                        <field>
                            <name>BCNT</name>
                            <description>Binary Counter</description>
                            <lsb>0</lsb>
                            <msb>7</msb>
                            <access>read-write</access>
                        </field>
                    </fields>
                </register>
                <register>
                    <name>RSECCNT</name>
                    <description>Second Counter (in Calendar Count Mode)</description>
                    <addressOffset>0x02</addressOffset>
                    <size>8</size>
                    <access>read-write</access>
                    <resetValue>0x00</resetValue>
                    <resetMask>0x00</resetMask>
                    <fields>
                        <field>
                            <name>SEC1</name>
                            <description>1-Second Count</description>
                            <lsb>0</lsb>
                            <msb>3</msb>
                            <access>read-write</access>
                        </field>
                        <field>
                            <name>SEC10</name>
                            <description>10-Second Count</description>
                            <lsb>4</lsb>
                            <msb>6</msb>
                            <access>read-write</access>
                        </field>
                    </fields>
                </register>
                <register>
                    <name>RMINCNT</name>
                    <description>Minute Counter (in Calendar Count Mode)</description>
                    <addressOffset>0x04</addressOffset>
                    <size>8</size>
                    <access>read-write</access>
                    <resetValue>0x00</resetValue>
                    <resetMask>0x00</resetMask>
                    <fields>
                        <field>
                            <name>MIN1</name>
                            <description>1-Minute Count</description>
                            <lsb>0</lsb>
                            <msb>3</msb>
                            <access>read-write</access>
                        </field>
                        <field>
                            <name>MIN10</name>
                            <description>10-Minute Count</description>
                            <lsb>4</lsb>
                            <msb>6</msb>
                            <access>read-write</access>
                        </field>
                    </fields>
                </register>
                <register>
                    <name>RHRCNT</name>
                    <description>Hour Counter (in Calendar Count Mode)</description>
                    <addressOffset>0x06</addressOffset>
                    <size>8</size>
                    <access>read-write</access>
                    <resetValue>0x00</resetValue>
                    <resetMask>0x00</resetMask>
                    <fields>
                        <field>
                            <name>HR1</name>
                            <description>1-Hour Count</description>
                            <lsb>0</lsb>
                            <msb>3</msb>
                            <access>read-write</access>
                        </field>
                        <field>
                            <name>HR10</name>
                            <description>10-Hour Count</description>
                            <lsb>4</lsb>
                            <msb>5</msb>
                            <access>read-write</access>
                        </field>
                        <field>
                            <name>PM</name>
                            <description>AM/PM select for time counter setting.</description>
                            <lsb>6</lsb>
                            <msb>6</msb>
                            <access>read-write</access>
                            <enumeratedValues>
                                <enumeratedValue>
                                    <name>0</name>
                                    <description>AM</description>
                                    <value>#0</value>
                                </enumeratedValue>
                                <enumeratedValue>
                                    <name>1</name>
                                    <description>PM</description>
                                    <value>#1</value>
                                </enumeratedValue>
                            </enumeratedValues>
                        </field>
                    </fields>
                </register>
                <register>
                    <name>RWKCNT</name>
                    <description>Day-of-Week Counter (in Calendar Count Mode)</description>
                    <addressOffset>0x08</addressOffset>
                    <size>8</size>
                    <access>read-write</access>
                    <resetValue>0x00</resetValue>
                    <resetMask>0x00</resetMask>
                    <fields>
                        <field>
                            <name>DAYW</name>
                            <description>Day-of-Week Counting</description>
                            <lsb>0</lsb>
                            <msb>2</msb>
                            <access>read-write</access>
                            <enumeratedValues>
                                <enumeratedValue>
                                    <name>000</name>
                                    <description>Sunday</description>
                                    <value>#000</value>
                                </enumeratedValue>
                                <enumeratedValue>
                                    <name>001</name>
                                    <description>Monday</description>
                                    <value>#001</value>
                                </enumeratedValue>
                                <enumeratedValue>
                                    <name>010</name>
                                    <description>Tuesday</description>
                                    <value>#010</value>
                                </enumeratedValue>
                                <enumeratedValue>
                                    <name>011</name>
                                    <description>Wednesday</description>
                                    <value>#011</value>
                                </enumeratedValue>
                                <enumeratedValue>
                                    <name>100</name>
                                    <description>Thursday</description>
                                    <value>#100</value>
                                </enumeratedValue>
                                <enumeratedValue>
                                    <name>101</name>
                                    <description>Friday</description>
                                    <value>#101</value>
                                </enumeratedValue>
                                <enumeratedValue>
                                    <name>110</name>
                                    <description>Saturday</description>
                                    <value>#110</value>
                                </enumeratedValue>
                                <enumeratedValue>
                                    <name>111</name>
                                    <description>Setting prohibited</description>
                                    <value>#111</value>
                                </enumeratedValue>
                            </enumeratedValues>
                        </field>
                    </fields>
                </register>
                <register>
                    <name>RDAYCNT</name>
                    <description>Day Counter</description>
                    <addressOffset>0x0A</addressOffset>
                    <size>8</size>
                    <access>read-write</access>
                    <resetValue>0x00</resetValue>
                    <resetMask>0xc0</resetMask>
                    <fields>
                        <field>
                            <name>DATE1</name>
                            <description>1-Day Count</description>
                            <lsb>0</lsb>
                            <msb>3</msb>
                            <access>read-write</access>
                        </field>
                        <field>
                            <name>DATE10</name>
                            <description>10-Day Count</description>
                            <lsb>4</lsb>
                            <msb>5</msb>
                            <access>read-write</access>
                        </field>
                    </fields>
                </register>
                <register>
                    <name>RMONCNT</name>
                    <description>Month Counter</description>
                    <addressOffset>0x0C</addressOffset>
                    <size>8</size>
                    <access>read-write</access>
                    <resetValue>0x00</resetValue>
                    <resetMask>0xe0</resetMask>
                    <fields>
                        <field>
                            <name>MON1</name>
                            <description>1-Month Count</description>
                            <lsb>0</lsb>
                            <msb>3</msb>
                            <access>read-write</access>
                        </field>
                        <field>
                            <name>MON10</name>
                            <description>10-Month Count</description>
                            <lsb>4</lsb>
                            <msb>4</msb>
                            <access>read-write</access>
                        </field>
                    </fields>
                </register>
                <register>
                    <name>RYRCNT</name>
                    <description>Year Counter</description>
                    <addressOffset>0x0E</addressOffset>
                    <size>16</size>
                    <access>read-write</access>
                    <resetValue>0x0000</resetValue>
                    <resetMask>0xff00</resetMask>
                    <fields>
                        <field>
                            <name>YR1</name>
                            <description>1-Year Count</description>
                            <lsb>0</lsb>
                            <msb>3</msb>
                            <access>read-write</access>
                        </field>
                        <field>
                            <name>YR10</name>
                            <description>10-Year Count</description>
                            <lsb>4</lsb>
                            <msb>7</msb>
                            <access>read-write</access>
                        </field>
                    </fields>
                </register>
                <register>
                    <dim>4</dim>
                    <dimIncrement>0x02</dimIncrement>
                    <dimIndex>0-3</dimIndex>
                    <name>BCNT%sAR</name>
                    <description>Binary Counter %s Alarm Register</description>
                    <addressOffset>0x10</addressOffset>
                    <size>8</size>
                    <access>read-write</access>
                    <resetValue>0x00</resetValue>
                    <resetMask>0x00</resetMask>
                    <fields>
                        <field>
                            <name>BCNTAR</name>
                            <description>Alarm register associated with the 32-bit binary counter</description>
                            <lsb>0</lsb>
                            <msb>7</msb>
                            <access>read-write</access>
                        </field>
                    </fields>
                </register>
                <register>
                    <name>RSECAR</name>
                    <description>Second Alarm Register (in Calendar Count Mode)</description>
                    <addressOffset>0x10</addressOffset>
                    <size>8</size>
                    <access>read-write</access>
                    <resetValue>0x00</resetValue>
                    <resetMask>0x00</resetMask>
                    <fields>
                        <field>
                            <name>SEC1</name>
                            <description>1 Second</description>
                            <lsb>0</lsb>
                            <msb>3</msb>
                            <access>read-write</access>
                        </field>
                        <field>
                            <name>SEC10</name>
                            <description>10 Seconds</description>
                            <lsb>4</lsb>
                            <msb>6</msb>
                            <access>read-write</access>
                        </field>
                        <field>
                            <name>ENB</name>
                            <description>ENB</description>
                            <lsb>7</lsb>
                            <msb>7</msb>
                            <access>read-write</access>
                            <enumeratedValues>
                                <enumeratedValue>
                                    <name>0</name>
                                    <description>Do not compare register value with RSECCNT counter value</description>
                                    <value>#0</value>
                                </enumeratedValue>
                                <enumeratedValue>
                                    <name>1</name>
                                    <description>Compare register value with RSECCNT counter value</description>
                                    <value>#1</value>
                                </enumeratedValue>
                            </enumeratedValues>
                        </field>
                    </fields>
                </register>
                <register>
                    <name>RMINAR</name>
                    <description>Minute Alarm Register (in Calendar Count Mode)</description>
                    <addressOffset>0x12</addressOffset>
                    <size>8</size>
                    <access>read-write</access>
                    <resetValue>0x00</resetValue>
                    <resetMask>0x00</resetMask>
                    <fields>
                        <field>
                            <name>MIN1</name>
                            <description>1 Minute</description>
                            <lsb>0</lsb>
                            <msb>3</msb>
                            <access>read-write</access>
                        </field>
                        <field>
                            <name>MIN10</name>
                            <description>10 Minutes</description>
                            <lsb>4</lsb>
                            <msb>6</msb>
                            <access>read-write</access>
                        </field>
                        <field>
                            <name>ENB</name>
                            <description>ENB</description>
                            <lsb>7</lsb>
                            <msb>7</msb>
                            <access>read-write</access>
                            <enumeratedValues>
                                <enumeratedValue>
                                    <name>0</name>
                                    <description>Do not compare register value with RMINCNT counter value</description>
                                    <value>#0</value>
                                </enumeratedValue>
                                <enumeratedValue>
                                    <name>1</name>
                                    <description>Compare register value with RMINCNT counter value</description>
                                    <value>#1</value>
                                </enumeratedValue>
                            </enumeratedValues>
                        </field>
                    </fields>
                </register>
                <register>
                    <name>RHRAR</name>
                    <description>Hour Alarm Register (in Calendar Count Mode)</description>
                    <addressOffset>0x14</addressOffset>
                    <size>8</size>
                    <access>read-write</access>
                    <resetValue>0x00</resetValue>
                    <resetMask>0x00</resetMask>
                    <fields>
                        <field>
                            <name>HR1</name>
                            <description>1 Hour</description>
                            <lsb>0</lsb>
                            <msb>3</msb>
                            <access>read-write</access>
                        </field>
                        <field>
                            <name>HR10</name>
                            <description>10 Hours</description>
                            <lsb>4</lsb>
                            <msb>5</msb>
                            <access>read-write</access>
                        </field>
                        <field>
                            <name>PM</name>
                            <description>AM/PM select for alarm setting.</description>
                            <lsb>6</lsb>
                            <msb>6</msb>
                            <access>read-write</access>
                            <enumeratedValues>
                                <enumeratedValue>
                                    <name>0</name>
                                    <description>AM</description>
                                    <value>#0</value>
                                </enumeratedValue>
                                <enumeratedValue>
                                    <name>1</name>
                                    <description>PM</description>
                                    <value>#1</value>
                                </enumeratedValue>
                            </enumeratedValues>
                        </field>
                        <field>
                            <name>ENB</name>
                            <description>ENB</description>
                            <lsb>7</lsb>
                            <msb>7</msb>
                            <access>read-write</access>
                            <enumeratedValues>
                                <enumeratedValue>
                                    <name>0</name>
                                    <description>Do not compare register value with RHRCNT counter value</description>
                                    <value>#0</value>
                                </enumeratedValue>
                                <enumeratedValue>
                                    <name>1</name>
                                    <description>Compare register value with RHRCNT counter value</description>
                                    <value>#1</value>
                                </enumeratedValue>
                            </enumeratedValues>
                        </field>
                    </fields>
                </register>
                <register>
                    <name>RWKAR</name>
                    <description>Day-of-Week Alarm Register (in Calendar Count Mode)</description>
                    <addressOffset>0x16</addressOffset>
                    <size>8</size>
                    <access>read-write</access>
                    <resetValue>0x00</resetValue>
                    <resetMask>0x00</resetMask>
                    <fields>
                        <field>
                            <name>DAYW</name>
                            <description>Day-of-Week Setting</description>
                            <lsb>0</lsb>
                            <msb>2</msb>
                            <access>read-write</access>
                            <enumeratedValues>
                                <enumeratedValue>
                                    <name>000</name>
                                    <description>Sunday</description>
                                    <value>#000</value>
                                </enumeratedValue>
                                <enumeratedValue>
                                    <name>001</name>
                                    <description>Monday</description>
                                    <value>#001</value>
                                </enumeratedValue>
                                <enumeratedValue>
                                    <name>010</name>
                                    <description>Tuesday</description>
                                    <value>#010</value>
                                </enumeratedValue>
                                <enumeratedValue>
                                    <name>011</name>
                                    <description>Wednesday</description>
                                    <value>#011</value>
                                </enumeratedValue>
                                <enumeratedValue>
                                    <name>100</name>
                                    <description>Thursday</description>
                                    <value>#100</value>
                                </enumeratedValue>
                                <enumeratedValue>
                                    <name>101</name>
                                    <description>Friday</description>
                                    <value>#101</value>
                                </enumeratedValue>
                                <enumeratedValue>
                                    <name>110</name>
                                    <description>Saturday</description>
                                    <value>#110</value>
                                </enumeratedValue>
                                <enumeratedValue>
                                    <name>111</name>
                                    <description>Setting prohibited</description>
                                    <value>#111</value>
                                </enumeratedValue>
                            </enumeratedValues>
                        </field>
                        <field>
                            <name>ENB</name>
                            <description>ENB</description>
                            <lsb>7</lsb>
                            <msb>7</msb>
                            <access>read-write</access>
                            <enumeratedValues>
                                <enumeratedValue>
                                    <name>0</name>
                                    <description>Do not compare register value with RWKCNT counter value</description>
                                    <value>#0</value>
                                </enumeratedValue>
                                <enumeratedValue>
                                    <name>1</name>
                                    <description>Compare register value with RWKCNT counter value</description>
                                    <value>#1</value>
                                </enumeratedValue>
                            </enumeratedValues>
                        </field>
                    </fields>
                </register>
                <register>
                    <dim>4</dim>
                    <dimIncrement>0x02</dimIncrement>
                    <dimIndex>0-3</dimIndex>
                    <name>BCNT%sAER</name>
                    <description>Binary Counter %s Alarm Enable Register</description>
                    <addressOffset>0x18</addressOffset>
                    <size>8</size>
                    <access>read-write</access>
                    <resetValue>0x00</resetValue>
                    <resetMask>0x00</resetMask>
                    <fields>
                        <field>
                            <name>ENB</name>
                            <description>Setting the alarm enable associated with the 32-bit binary counter</description>
                            <lsb>0</lsb>
                            <msb>7</msb>
                            <access>read-write</access>
                        </field>
                    </fields>
                </register>
                <register>
                    <name>RDAYAR</name>
                    <description>Date Alarm Register (in Calendar Count Mode)</description>
                    <addressOffset>0x18</addressOffset>
                    <size>8</size>
                    <access>read-write</access>
                    <resetValue>0x00</resetValue>
                    <resetMask>0x00</resetMask>
                    <fields>
                        <field>
                            <name>DATE1</name>
                            <description>1 Day</description>
                            <lsb>0</lsb>
                            <msb>3</msb>
                            <access>read-write</access>
                        </field>
                        <field>
                            <name>DATE10</name>
                            <description>10 Days</description>
                            <lsb>4</lsb>
                            <msb>5</msb>
                            <access>read-write</access>
                        </field>
                        <field>
                            <name>ENB</name>
                            <description>ENB</description>
                            <lsb>7</lsb>
                            <msb>7</msb>
                            <access>read-write</access>
                            <enumeratedValues>
                                <enumeratedValue>
                                    <name>0</name>
                                    <description>Do not compare register value with RDAYCNT counter value</description>
                                    <value>#0</value>
                                </enumeratedValue>
                                <enumeratedValue>
                                    <name>1</name>
                                    <description>Compare register value with RDAYCNT counter value</description>
                                    <value>#1</value>
                                </enumeratedValue>
                            </enumeratedValues>
                        </field>
                    </fields>
                </register>
                <register>
                    <name>RMONAR</name>
                    <description>Month Alarm Register (in Calendar Count Mode)</description>
                    <addressOffset>0x1A</addressOffset>
                    <size>8</size>
                    <access>read-write</access>
                    <resetValue>0x00</resetValue>
                    <resetMask>0x00</resetMask>
                    <fields>
                        <field>
                            <name>MON1</name>
                            <description>1 Month</description>
                            <lsb>0</lsb>
                            <msb>3</msb>
                            <access>read-write</access>
                        </field>
                        <field>
                            <name>MON10</name>
                            <description>10 Months</description>
                            <lsb>4</lsb>
                            <msb>4</msb>
                            <access>read-write</access>
                        </field>
                        <field>
                            <name>ENB</name>
                            <description>ENB</description>
                            <lsb>7</lsb>
                            <msb>7</msb>
                            <access>read-write</access>
                            <enumeratedValues>
                                <enumeratedValue>
                                    <name>0</name>
                                    <description>Do not compare register value with RMONCNT counter value</description>
                                    <value>#0</value>
                                </enumeratedValue>
                                <enumeratedValue>
                                    <name>1</name>
                                    <description>Compare register value with RMONCNT counter value</description>
                                    <value>#1</value>
                                </enumeratedValue>
                            </enumeratedValues>
                        </field>
                    </fields>
                </register>
                <register>
                    <name>RYRAR</name>
                    <description>Year Alarm Register (in Calendar Count Mode)</description>
                    <addressOffset>0x1C</addressOffset>
                    <size>16</size>
                    <access>read-write</access>
                    <resetValue>0x0000</resetValue>
                    <resetMask>0xff00</resetMask>
                    <fields>
                        <field>
                            <name>YR1</name>
                            <description>1 Year</description>
                            <lsb>0</lsb>
                            <msb>3</msb>
                            <access>read-write</access>
                        </field>
                        <field>
                            <name>YR10</name>
                            <description>10 Years</description>
                            <lsb>4</lsb>
                            <msb>7</msb>
                            <access>read-write</access>
                        </field>
                    </fields>
                </register>
                <register>
                    <name>RYRAREN</name>
                    <description>Year Alarm Enable Register (in Calendar Count Mode)</description>
                    <addressOffset>0x1E</addressOffset>
                    <size>8</size>
                    <access>read-write</access>
                    <resetValue>0x00</resetValue>
                    <resetMask>0x00</resetMask>
                    <fields>
                        <field>
                            <name>ENB</name>
                            <description>ENB</description>
                            <lsb>7</lsb>
                            <msb>7</msb>
                            <access>read-write</access>
                            <enumeratedValues>
                                <enumeratedValue>
                                    <name>0</name>
                                    <description>Do not compare register value with the RYRCNT counter value</description>
                                    <value>#0</value>
                                </enumeratedValue>
                                <enumeratedValue>
                                    <name>1</name>
                                    <description>Compare register value with the RYRCNT counter value</description>
                                    <value>#1</value>
                                </enumeratedValue>
                            </enumeratedValues>
                        </field>
                    </fields>
                </register>
                <register>
                    <name>RCR1</name>
                    <description>RTC Control Register 1</description>
                    <addressOffset>0x22</addressOffset>
                    <size>8</size>
                    <access>read-write</access>
                    <resetValue>0x00</resetValue>
                    <resetMask>0x0a</resetMask>
                    <fields>
                        <field>
                            <name>AIE</name>
                            <description>Alarm Interrupt Enable</description>
                            <lsb>0</lsb>
                            <msb>0</msb>
                            <access>read-write</access>
                            <enumeratedValues>
                                <enumeratedValue>
                                    <name>0</name>
                                    <description>Disable alarm interrupt requests</description>
                                    <value>#0</value>
                                </enumeratedValue>
                                <enumeratedValue>
                                    <name>1</name>
                                    <description>Enable alarm interrupt requests</description>
                                    <value>#1</value>
                                </enumeratedValue>
                            </enumeratedValues>
                        </field>
                        <field>
                            <name>CIE</name>
                            <description>Carry Interrupt Enable</description>
                            <lsb>1</lsb>
                            <msb>1</msb>
                            <access>read-write</access>
                            <enumeratedValues>
                                <enumeratedValue>
                                    <name>0</name>
                                    <description>Disable carry interrupt requests</description>
                                    <value>#0</value>
                                </enumeratedValue>
                                <enumeratedValue>
                                    <name>1</name>
                                    <description>Enable carry interrupt requests</description>
                                    <value>#1</value>
                                </enumeratedValue>
                            </enumeratedValues>
                        </field>
                        <field>
                            <name>PIE</name>
                            <description>Periodic Interrupt Enable</description>
                            <lsb>2</lsb>
                            <msb>2</msb>
                            <access>read-write</access>
                            <enumeratedValues>
                                <enumeratedValue>
                                    <name>0</name>
                                    <description>Disable periodic interrupt requests</description>
                                    <value>#0</value>
                                </enumeratedValue>
                                <enumeratedValue>
                                    <name>1</name>
                                    <description>Enable periodic interrupt requests</description>
                                    <value>#1</value>
                                </enumeratedValue>
                            </enumeratedValues>
                        </field>
                        <field>
                            <name>RTCOS</name>
                            <description>RTCOUT Output Select</description>
                            <lsb>3</lsb>
                            <msb>3</msb>
                            <access>read-write</access>
                            <enumeratedValues>
                                <enumeratedValue>
                                    <name>0</name>
                                    <description>Outputs 1 Hz on RTCOUT</description>
                                    <value>#0</value>
                                </enumeratedValue>
                                <enumeratedValue>
                                    <name>1</name>
                                    <description>Outputs 64 Hz RTCOUT</description>
                                    <value>#1</value>
                                </enumeratedValue>
                            </enumeratedValues>
                        </field>
                        <field>
                            <name>PES</name>
                            <description>Periodic Interrupt Select</description>
                            <lsb>4</lsb>
                            <msb>7</msb>
                            <access>read-write</access>
                            <enumeratedValues>
                                <enumeratedValue>
                                    <name>0x6</name>
                                    <description>Generate periodic interrupt every 1/256 second</description>
                                    <value>0x6</value>
                                </enumeratedValue>
                                <enumeratedValue>
                                    <name>0x7</name>
                                    <description>Generate periodic interrupt every 1/128 second</description>
                                    <value>0x7</value>
                                </enumeratedValue>
                                <enumeratedValue>
                                    <name>0x8</name>
                                    <description>Generate periodic interrupt every 1/64 second</description>
                                    <value>0x8</value>
                                </enumeratedValue>
                                <enumeratedValue>
                                    <name>0x9</name>
                                    <description>Generate periodic interrupt every 1/32 second</description>
                                    <value>0x9</value>
                                </enumeratedValue>
                                <enumeratedValue>
                                    <name>0xA</name>
                                    <description>Generate periodic interrupt every 1/16 second</description>
                                    <value>0xa</value>
                                </enumeratedValue>
                                <enumeratedValue>
                                    <name>0xB</name>
                                    <description>Generate periodic interrupt every 1/8 second</description>
                                    <value>0xb</value>
                                </enumeratedValue>
                                <enumeratedValue>
                                    <name>0xC</name>
                                    <description>Generate periodic interrupt every 1/4 second</description>
                                    <value>0xc</value>
                                </enumeratedValue>
                                <enumeratedValue>
                                    <name>0xD</name>
                                    <description>Generate periodic interrupt every 1/2 second</description>
                                    <value>0xd</value>
                                </enumeratedValue>
                                <enumeratedValue>
                                    <name>0xE</name>
                                    <description>Generate periodic interrupt every 1 second</description>
                                    <value>0xe</value>
                                </enumeratedValue>
                                <enumeratedValue>
                                    <name>0xF</name>
                                    <description>Generate periodic interrupt every 2 seconds</description>
                                    <value>0xf</value>
                                </enumeratedValue>
                                <enumeratedValue>
                                    <name>Others</name>
                                    <description>Do not generate periodic interrupts</description>
                                    <isDefault>true</isDefault>
                                </enumeratedValue>
                            </enumeratedValues>
                        </field>
                    </fields>
                </register>
                <register>
                    <name>RCR2</name>
                    <description>RTC Control Register 2 (in Calendar Count Mode)</description>
                    <addressOffset>0x24</addressOffset>
                    <size>8</size>
                    <access>read-write</access>
                    <resetValue>0x00</resetValue>
                    <resetMask>0x0e</resetMask>
                    <fields>
                        <field>
                            <name>START</name>
                            <description>Start</description>
                            <lsb>0</lsb>
                            <msb>0</msb>
                            <access>read-write</access>
                            <enumeratedValues>
                                <enumeratedValue>
                                    <name>0</name>
                                    <description>Stop prescaler and time counter</description>
                                    <value>#0</value>
                                </enumeratedValue>
                                <enumeratedValue>
                                    <name>1</name>
                                    <description>Operate prescaler and time counter normally</description>
                                    <value>#1</value>
                                </enumeratedValue>
                            </enumeratedValues>
                        </field>
                        <field>
                            <name>RESET</name>
                            <description>RTC Software Reset</description>
                            <lsb>1</lsb>
                            <msb>1</msb>
                            <access>read-write</access>
                            <enumeratedValues>
                                <enumeratedValue>
                                    <name>0</name>
                                    <description>In writing: Invalid (writing 0 has no effect). In reading: Normal time operation in progress, or an RTC software reset has completed. </description>
                                    <value>#0</value>
                                </enumeratedValue>
                                <enumeratedValue>
                                    <name>1</name>
                                    <description>In writing: Initialize the prescaler and target registers for RTC software reset. In reading: RTC software reset in progress. </description>
                                    <value>#1</value>
                                </enumeratedValue>
                            </enumeratedValues>
                        </field>
                        <field>
                            <name>ADJ30</name>
                            <description>30-Second Adjustment</description>
                            <lsb>2</lsb>
                            <msb>2</msb>
                            <access>read-write</access>
                            <enumeratedValues>
                                <enumeratedValue>
                                    <name>0</name>
                                    <description>In writing: Invalid (writing 0 has no effect). In reading: Normal time operation in progress, or 30-second adjustment has completed. </description>
                                    <value>#0</value>
                                </enumeratedValue>
                                <enumeratedValue>
                                    <name>1</name>
                                    <description>In writing: Execute 30-second adjustment. In reading: 30-second adjustment in progress. </description>
                                    <value>#1</value>
                                </enumeratedValue>
                            </enumeratedValues>
                        </field>
                        <field>
                            <name>RTCOE</name>
                            <description>RTCOUT Output Enable</description>
                            <lsb>3</lsb>
                            <msb>3</msb>
                            <access>read-write</access>
                            <enumeratedValues>
                                <enumeratedValue>
                                    <name>0</name>
                                    <description>Disable RTCOUT output</description>
                                    <value>#0</value>
                                </enumeratedValue>
                                <enumeratedValue>
                                    <name>1</name>
                                    <description>Enable RTCOUT output</description>
                                    <value>#1</value>
                                </enumeratedValue>
                            </enumeratedValues>
                        </field>
                        <field>
                            <name>AADJE</name>
                            <description>Automatic Adjustment Enable</description>
                            <lsb>4</lsb>
                            <msb>4</msb>
                            <access>read-write</access>
                            <enumeratedValues>
                                <enumeratedValue>
                                    <name>0</name>
                                    <description>Disable automatic adjustment</description>
                                    <value>#0</value>
                                </enumeratedValue>
                                <enumeratedValue>
                                    <name>1</name>
                                    <description>Enable automatic adjustment</description>
                                    <value>#1</value>
                                </enumeratedValue>
                            </enumeratedValues>
                        </field>
                        <field>
                            <name>AADJP</name>
                            <description>Automatic Adjustment Period Select</description>
                            <lsb>5</lsb>
                            <msb>5</msb>
                            <access>read-write</access>
                            <enumeratedValues>
                                <enumeratedValue>
                                    <name>0</name>
                                    <description>The RADJ.ADJ[5:0] setting from the count value of the prescaler every minute.</description>
                                    <value>#0</value>
                                </enumeratedValue>
                                <enumeratedValue>
                                    <name>1</name>
                                    <description>The RADJ.ADJ[5:0] setting value is adjusted from the count value of the prescaler every 10 seconds.</description>
                                    <value>#1</value>
                                </enumeratedValue>
                            </enumeratedValues>
                        </field>
                        <field>
                            <name>HR24</name>
                            <description>Hours Mode</description>
                            <lsb>6</lsb>
                            <msb>6</msb>
                            <access>read-write</access>
                            <enumeratedValues>
                                <enumeratedValue>
                                    <name>0</name>
                                    <description>Operate RTC in 12-hour mode</description>
                                    <value>#0</value>
                                </enumeratedValue>
                                <enumeratedValue>
                                    <name>1</name>
                                    <description>Operate RTC in 24-hour mode</description>
                                    <value>#1</value>
                                </enumeratedValue>
                            </enumeratedValues>
                        </field>
                        <field>
                            <name>CNTMD</name>
                            <description>Count Mode Select</description>
                            <lsb>7</lsb>
                            <msb>7</msb>
                            <access>read-write</access>
                            <enumeratedValues>
                                <enumeratedValue>
                                    <name>0</name>
                                    <description>Calendar count mode</description>
                                    <value>#0</value>
                                </enumeratedValue>
                                <enumeratedValue>
                                    <name>1</name>
                                    <description>Binary count mode</description>
                                    <value>#1</value>
                                </enumeratedValue>
                            </enumeratedValues>
                        </field>
                    </fields>
                </register>
                <register>
                    <name>RCR2_BCNT</name>
                    <description>RTC Control Register 2 (in Binary Count Mode)</description>
                    <alternateRegister>RCR2</alternateRegister>
                    <addressOffset>0x24</addressOffset>
                    <size>8</size>
                    <access>read-write</access>
                    <resetValue>0x00</resetValue>
                    <resetMask>0x0e</resetMask>
                    <fields>
                        <field>
                            <name>START</name>
                            <description>Start</description>
                            <lsb>0</lsb>
                            <msb>0</msb>
                            <access>read-write</access>
                            <enumeratedValues>
                                <enumeratedValue>
                                    <name>0</name>
                                    <description>Stop the 32-bit binary counter, 64-Hz counter, and prescaler</description>
                                    <value>#0</value>
                                </enumeratedValue>
                                <enumeratedValue>
                                    <name>1</name>
                                    <description>Operate the 32-bit binary counter, 64-Hz counter, and prescaler normally</description>
                                    <value>#1</value>
                                </enumeratedValue>
                            </enumeratedValues>
                        </field>
                        <field>
                            <name>RESET</name>
                            <description>RTC Software Reset</description>
                            <lsb>1</lsb>
                            <msb>1</msb>
                            <access>read-write</access>
                            <enumeratedValues>
                                <enumeratedValue>
                                    <name>0</name>
                                    <description>In writing: Invalid (writing 0 has no effect). In reading: Normal time operation in progress, or an RTC software reset has completed. </description>
                                    <value>#0</value>
                                </enumeratedValue>
                                <enumeratedValue>
                                    <name>1</name>
                                    <description>In writing: Initialize the prescaler and target registers for RTC software reset. In reading: RTC software reset in progress. </description>
                                    <value>#1</value>
                                </enumeratedValue>
                            </enumeratedValues>
                        </field>
                        <field>
                            <name>RTCOE</name>
                            <description>RTCOUT Output Enable</description>
                            <lsb>3</lsb>
                            <msb>3</msb>
                            <access>read-write</access>
                            <enumeratedValues>
                                <enumeratedValue>
                                    <name>0</name>
                                    <description>Disable RTCOUT output</description>
                                    <value>#0</value>
                                </enumeratedValue>
                                <enumeratedValue>
                                    <name>1</name>
                                    <description>Enable RTCOUT output</description>
                                    <value>#1</value>
                                </enumeratedValue>
                            </enumeratedValues>
                        </field>
                        <field>
                            <name>AADJE</name>
                            <description>Automatic Adjustment Enable</description>
                            <lsb>4</lsb>
                            <msb>4</msb>
                            <access>read-write</access>
                            <enumeratedValues>
                                <enumeratedValue>
                                    <name>0</name>
                                    <description>Disable automatic adjustment</description>
                                    <value>#0</value>
                                </enumeratedValue>
                                <enumeratedValue>
                                    <name>1</name>
                                    <description>Enable automatic adjustment</description>
                                    <value>#1</value>
                                </enumeratedValue>
                            </enumeratedValues>
                        </field>
                        <field>
                            <name>AADJP</name>
                            <description>Automatic Adjustment Period Select</description>
                            <lsb>5</lsb>
                            <msb>5</msb>
                            <access>read-write</access>
                            <enumeratedValues>
                                <enumeratedValue>
                                    <name>0</name>
                                    <description>Add or subtract RADJ.ADJ [5:0] bits from prescaler count value every 32 seconds</description>
                                    <value>#0</value>
                                </enumeratedValue>
                                <enumeratedValue>
                                    <name>1</name>
                                    <description>Add or subtract RADJ.ADJ [5:0] bits from prescaler count value every 8 seconds.</description>
                                    <value>#1</value>
                                </enumeratedValue>
                            </enumeratedValues>
                        </field>
                        <field>
                            <name>CNTMD</name>
                            <description>Count Mode Select</description>
                            <lsb>7</lsb>
                            <msb>7</msb>
                            <access>read-write</access>
                            <enumeratedValues>
                                <enumeratedValue>
                                    <name>0</name>
                                    <description>Calendar count mode</description>
                                    <value>#0</value>
                                </enumeratedValue>
                                <enumeratedValue>
                                    <name>1</name>
                                    <description>Binary count mode</description>
                                    <value>#1</value>
                                </enumeratedValue>
                            </enumeratedValues>
                        </field>
                    </fields>
                </register>
                <register>
                    <name>RCR4</name>
                    <description>RTC Control Register 4</description>
                    <addressOffset>0x28</addressOffset>
                    <size>8</size>
                    <access>read-write</access>
                    <resetValue>0x00</resetValue>
                    <resetMask>0xfe</resetMask>
                    <fields>
                        <field>
                            <name>RCKSEL</name>
                            <description>Count Source Select</description>
                            <lsb>0</lsb>
                            <msb>0</msb>
                            <access>read-write</access>
                            <enumeratedValues>
                                <enumeratedValue>
                                    <name>0</name>
                                    <description>Sub-clock oscillator is selected</description>
                                    <value>#0</value>
                                </enumeratedValue>
                                <enumeratedValue>
                                    <name>1</name>
                                    <description>LOCO is selected</description>
                                    <value>#1</value>
                                </enumeratedValue>
                            </enumeratedValues>
                        </field>
                    </fields>
                </register>
                <register>
                    <name>RFRH</name>
                    <description>Frequency Register H</description>
                    <addressOffset>0x2A</addressOffset>
                    <size>16</size>
                    <access>read-write</access>
                    <resetValue>0x0000</resetValue>
                    <resetMask>0xfffe</resetMask>
                    <fields>
                        <field>
                            <name>RFC16</name>
                            <description>Write 0 before writing to the RFRL register after a cold start.</description>
                            <lsb>0</lsb>
                            <msb>0</msb>
                            <access>read-write</access>
                        </field>
                    </fields>
                </register>
                <register>
                    <name>RFRL</name>
                    <description>Frequency Register L</description>
                    <addressOffset>0x2C</addressOffset>
                    <size>16</size>
                    <access>read-write</access>
                    <resetValue>0x0000</resetValue>
                    <resetMask>0x0000</resetMask>
                    <fields>
                        <field>
                            <name>RFC</name>
                            <description>Frequency Comparison Value</description>
                            <lsb>0</lsb>
                            <msb>15</msb>
                            <access>read-write</access>
                        </field>
                    </fields>
                </register>
                <register>
                    <name>RADJ</name>
                    <description>Time Error Adjustment Register</description>
                    <addressOffset>0x2E</addressOffset>
                    <size>8</size>
                    <access>read-write</access>
                    <resetValue>0x00</resetValue>
                    <resetMask>0x00</resetMask>
                    <fields>
                        <field>
                            <name>ADJ</name>
                            <description>Adjustment Value</description>
                            <lsb>0</lsb>
                            <msb>5</msb>
                            <access>read-write</access>
                        </field>
                        <field>
                            <name>PMADJ</name>
                            <description>Plus-Minus</description>
                            <lsb>6</lsb>
                            <msb>7</msb>
                            <access>read-write</access>
                            <enumeratedValues>
                                <enumeratedValue>
                                    <name>00</name>
                                    <description>Do not perform adjustment.</description>
                                    <value>#00</value>
                                </enumeratedValue>
                                <enumeratedValue>
                                    <name>01</name>
                                    <description>Adjustment is performed by the addition to the prescaler</description>
                                    <value>#01</value>
                                </enumeratedValue>
                                <enumeratedValue>
                                    <name>10</name>
                                    <description>Adjustment is performed by the subtraction from the prescaler</description>
                                    <value>#10</value>
                                </enumeratedValue>
                                <enumeratedValue>
                                    <name>11</name>
                                    <description>Setting prohibited.</description>
                                    <value>#11</value>
                                </enumeratedValue>
                            </enumeratedValues>
                        </field>
                    </fields>
                </register>
                <register>
                    <dim>3</dim>
                    <dimIncrement>0x02</dimIncrement>
                    <dimIndex>0-2</dimIndex>
                    <name>RTCCR%s</name>
                    <description>Time Capture Control Register %s</description>
                    <addressOffset>0x40</addressOffset>
                    <size>8</size>
                    <access>read-write</access>
                    <resetValue>0x00</resetValue>
                    <resetMask>0x48</resetMask>
                    <fields>
                        <field>
                            <name>TCCT</name>
                            <description>Time Capture Control</description>
                            <lsb>0</lsb>
                            <msb>1</msb>
                            <access>read-write</access>
                            <enumeratedValues>
                                <enumeratedValue>
                                    <name>00</name>
                                    <description>Do not detect events</description>
                                    <value>#00</value>
                                </enumeratedValue>
                                <enumeratedValue>
                                    <name>01</name>
                                    <description>Detect rising edge</description>
                                    <value>#01</value>
                                </enumeratedValue>
                                <enumeratedValue>
                                    <name>10</name>
                                    <description>Detect falling edge</description>
                                    <value>#10</value>
                                </enumeratedValue>
                                <enumeratedValue>
                                    <name>11</name>
                                    <description>Detect both edges</description>
                                    <value>#11</value>
                                </enumeratedValue>
                            </enumeratedValues>
                        </field>
                        <field>
                            <name>TCST</name>
                            <description>Time Capture Status</description>
                            <lsb>2</lsb>
                            <msb>2</msb>
                            <access>read-write</access>
                            <enumeratedValues>
                                <enumeratedValue>
                                    <name>0</name>
                                    <description>No event detected</description>
                                    <value>#0</value>
                                </enumeratedValue>
                                <enumeratedValue>
                                    <name>1</name>
                                    <description>Event detected</description>
                                    <value>#1</value>
                                </enumeratedValue>
                            </enumeratedValues>
                        </field>
                        <field>
                            <name>TCNF</name>
                            <description>Time Capture Noise Filter Control</description>
                            <lsb>4</lsb>
                            <msb>5</msb>
                            <access>read-write</access>
                            <enumeratedValues>
                                <enumeratedValue>
                                    <name>00</name>
                                    <description>Turn noise filter off</description>
                                    <value>#00</value>
                                </enumeratedValue>
                                <enumeratedValue>
                                    <name>01</name>
                                    <description>Setting prohibited</description>
                                    <value>#01</value>
                                </enumeratedValue>
                                <enumeratedValue>
                                    <name>10</name>
                                    <description>Turn noise filter on (count source)</description>
                                    <value>#10</value>
                                </enumeratedValue>
                                <enumeratedValue>
                                    <name>11</name>
                                    <description>Turn noise filter on (count source by divided by 32)</description>
                                    <value>#11</value>
                                </enumeratedValue>
                            </enumeratedValues>
                        </field>
                        <field>
                            <name>TCEN</name>
                            <description>Time Capture Event Input Pin Enable</description>
                            <lsb>7</lsb>
                            <msb>7</msb>
                            <access>read-write</access>
                            <enumeratedValues>
                                <enumeratedValue>
                                    <name>0</name>
                                    <description>Disable the RTCICn pin as the time capture event input pin</description>
                                    <value>#0</value>
                                </enumeratedValue>
                                <enumeratedValue>
                                    <name>1</name>
                                    <description>Enable the RTCICn pin as the time capture event input pin</description>
                                    <value>#1</value>
                                </enumeratedValue>
                            </enumeratedValues>
                        </field>
                    </fields>
                </register>
                <register>
                    <dim>3</dim>
                    <dimIncrement>0x10</dimIncrement>
                    <dimIndex>0-2</dimIndex>
                    <name>BCNT0CP%s</name>
                    <description>BCNT0 Capture Register %s</description>
                    <addressOffset>0x52</addressOffset>
                    <size>8</size>
                    <access>read-only</access>
                    <resetValue>0x00</resetValue>
                    <resetMask>0x00</resetMask>
                </register>
                <register>
                    <dim>3</dim>
                    <dimIncrement>0x10</dimIncrement>
                    <dimIndex>0-2</dimIndex>
                    <name>RSECCP%s</name>
                    <description>Second Capture Register %s</description>
                    <alternateRegister>BCNT0CP%s</alternateRegister>
                    <addressOffset>0x52</addressOffset>
                    <size>8</size>
                    <access>read-only</access>
                    <resetValue>0x00</resetValue>
                    <resetMask>0x00</resetMask>
                    <fields>
                        <field>
                            <name>SEC1</name>
                            <description>1-Second Capture</description>
                            <lsb>0</lsb>
                            <msb>3</msb>
                            <access>read-only</access>
                        </field>
                        <field>
                            <name>SEC10</name>
                            <description>10-Second Capture</description>
                            <lsb>4</lsb>
                            <msb>6</msb>
                            <access>read-only</access>
                        </field>
                    </fields>
                </register>
                <register>
                    <dim>3</dim>
                    <dimIncrement>0x10</dimIncrement>
                    <dimIndex>0-2</dimIndex>
                    <name>BCNT1CP%s</name>
                    <description>BCNT1 Capture Register %s</description>
                    <addressOffset>0x54</addressOffset>
                    <size>8</size>
                    <access>read-only</access>
                    <resetValue>0x00</resetValue>
                    <resetMask>0x00</resetMask>
                </register>
                <register>
                    <dim>3</dim>
                    <dimIncrement>0x10</dimIncrement>
                    <dimIndex>0-2</dimIndex>
                    <name>RMINCP%s</name>
                    <description>Minute Capture Register %s</description>
                    <alternateRegister>BCNT1CP%s</alternateRegister>
                    <addressOffset>0x54</addressOffset>
                    <size>8</size>
                    <access>read-only</access>
                    <resetValue>0x00</resetValue>
                    <resetMask>0x00</resetMask>
                    <fields>
                        <field>
                            <name>MIN1</name>
                            <description>1-Minute Capture</description>
                            <lsb>0</lsb>
                            <msb>3</msb>
                            <access>read-only</access>
                        </field>
                        <field>
                            <name>MIN10</name>
                            <description>10-Minute Capture</description>
                            <lsb>4</lsb>
                            <msb>6</msb>
                            <access>read-only</access>
                        </field>
                    </fields>
                </register>
                <register>
                    <dim>3</dim>
                    <dimIncrement>0x10</dimIncrement>
                    <dimIndex>0-2</dimIndex>
                    <name>BCNT2CP%s</name>
                    <description>BCNT2 Capture Register %s</description>
                    <addressOffset>0x56</addressOffset>
                    <size>8</size>
                    <access>read-only</access>
                    <resetValue>0x00</resetValue>
                    <resetMask>0x00</resetMask>
                </register>
                <register>
                    <dim>3</dim>
                    <dimIncrement>0x10</dimIncrement>
                    <dimIndex>0-2</dimIndex>
                    <name>RHRCP%s</name>
                    <description>Hour Capture Register %s</description>
                    <alternateRegister>BCNT2CP%s</alternateRegister>
                    <addressOffset>0x56</addressOffset>
                    <size>8</size>
                    <access>read-only</access>
                    <resetValue>0x00</resetValue>
                    <resetMask>0x00</resetMask>
                    <fields>
                        <field>
                            <name>HR1</name>
                            <description>1-Hour Capture</description>
                            <lsb>0</lsb>
                            <msb>3</msb>
                            <access>read-only</access>
                        </field>
                        <field>
                            <name>HR10</name>
                            <description>10-Hour Capture</description>
                            <lsb>4</lsb>
                            <msb>5</msb>
                            <access>read-only</access>
                        </field>
                        <field>
                            <name>PM</name>
                            <description>PM</description>
                            <lsb>6</lsb>
                            <msb>6</msb>
                            <access>read-only</access>
                            <enumeratedValues>
                                <enumeratedValue>
                                    <name>0</name>
                                    <description>AM</description>
                                    <value>#0</value>
                                </enumeratedValue>
                                <enumeratedValue>
                                    <name>1</name>
                                    <description>PM</description>
                                    <value>#1</value>
                                </enumeratedValue>
                            </enumeratedValues>
                        </field>
                    </fields>
                </register>
                <register>
                    <dim>3</dim>
                    <dimIncrement>0x10</dimIncrement>
                    <dimIndex>0-2</dimIndex>
                    <name>BCNT3CP%s</name>
                    <description>BCNT3 Capture Register %s</description>
                    <addressOffset>0x5A</addressOffset>
                    <size>8</size>
                    <access>read-only</access>
                    <resetValue>0x00</resetValue>
                    <resetMask>0x00</resetMask>
                </register>
                <register>
                    <dim>3</dim>
                    <dimIncrement>0x10</dimIncrement>
                    <dimIndex>0-2</dimIndex>
                    <name>RDAYCP%s</name>
                    <description>Date Capture Register %s</description>
                    <alternateRegister>BCNT3CP%s</alternateRegister>
                    <addressOffset>0x5A</addressOffset>
                    <size>8</size>
                    <access>read-only</access>
                    <resetValue>0x00</resetValue>
                    <resetMask>0x00</resetMask>
                    <fields>
                        <field>
                            <name>DATE1</name>
                            <description>1-Day Capture</description>
                            <lsb>0</lsb>
                            <msb>3</msb>
                            <access>read-only</access>
                        </field>
                        <field>
                            <name>DATE10</name>
                            <description>10-Day Capture</description>
                            <lsb>4</lsb>
                            <msb>5</msb>
                            <access>read-only</access>
                        </field>
                    </fields>
                </register>
                <register>
                    <dim>3</dim>
                    <dimIncrement>0x10</dimIncrement>
                    <dimIndex>0-2</dimIndex>
                    <name>RMONCP%s</name>
                    <description>Month Capture Register %s</description>
                    <addressOffset>0x5C</addressOffset>
                    <size>8</size>
                    <access>read-only</access>
                    <resetValue>0x00</resetValue>
                    <resetMask>0xe0</resetMask>
                    <fields>
                        <field>
                            <name>MON1</name>
                            <description>1-Month Capture</description>
                            <lsb>0</lsb>
                            <msb>3</msb>
                            <access>read-only</access>
                        </field>
                        <field>
                            <name>MON10</name>
                            <description>10-Month Capture</description>
                            <lsb>4</lsb>
                            <msb>4</msb>
                            <access>read-only</access>
                        </field>
                    </fields>
                </register>
            </registers>
        </peripheral>
        <peripheral>
            <name>IWDT_NS</name>
            <description>Independent Watchdog Timer</description>
            <baseAddress>0x50202200</baseAddress>
            <addressBlock>
                <offset>0x00</offset>
                <size>1</size>
                <usage>registers</usage>
            </addressBlock>
            <addressBlock>
                <offset>0x02</offset>
                <size>5</size>
                <usage>registers</usage>
            </addressBlock>
            <addressBlock>
                <offset>0x08</offset>
                <size>1</size>
                <usage>registers</usage>
            </addressBlock>
            <registers>
                <register>
                    <name>IWDTRR</name>
                    <description>IWDT Refresh Register</description>
                    <addressOffset>0x0</addressOffset>
                    <size>8</size>
                    <access>read-write</access>
                    <resetValue>0xff</resetValue>
                    <resetMask>0xff</resetMask>
                    <fields>
                        <field>
                            <name>REFRESH</name>
                            <description>Refresh Register</description>
                            <lsb>0</lsb>
                            <msb>7</msb>
                            <access>read-write</access>
                        </field>
                    </fields>
                </register>
                <register>
                    <name>IWDTCR</name>
                    <description>IWDT Control Register</description>
                    <addressOffset>0x2</addressOffset>
                    <size>16</size>
                    <access>read-write</access>
                    <resetValue>0x33f3</resetValue>
                    <resetMask>0xffff</resetMask>
                    <fields>
                        <field>
                            <name>TOPS</name>
                            <description>Timeout Period Select</description>
                            <lsb>0</lsb>
                            <msb>1</msb>
                            <access>read-write</access>
                            <enumeratedValues>
                                <enumeratedValue>
                                    <name>00</name>
                                    <description>128 cycles (0x007F)</description>
                                    <value>#00</value>
                                </enumeratedValue>
                                <enumeratedValue>
                                    <name>01</name>
                                    <description>512 cycles (0x01FF)</description>
                                    <value>#01</value>
                                </enumeratedValue>
                                <enumeratedValue>
                                    <name>10</name>
                                    <description>1024 cycles (0x03FF)</description>
                                    <value>#10</value>
                                </enumeratedValue>
                                <enumeratedValue>
                                    <name>11</name>
                                    <description>2048 cycles (0x07FF)</description>
                                    <value>#11</value>
                                </enumeratedValue>
                            </enumeratedValues>
                        </field>
                        <field>
                            <name>CKS</name>
                            <description>Clock Division Ratio Select</description>
                            <lsb>4</lsb>
                            <msb>7</msb>
                            <access>read-write</access>
                        </field>
                        <field>
                            <name>RPES</name>
                            <description>Window End Position Select</description>
                            <lsb>8</lsb>
                            <msb>9</msb>
                            <access>read-write</access>
                            <enumeratedValues>
                                <enumeratedValue>
                                    <name>00</name>
                                    <description>75%</description>
                                    <value>#00</value>
                                </enumeratedValue>
                                <enumeratedValue>
                                    <name>01</name>
                                    <description>50%</description>
                                    <value>#01</value>
                                </enumeratedValue>
                                <enumeratedValue>
                                    <name>10</name>
                                    <description>25%</description>
                                    <value>#10</value>
                                </enumeratedValue>
                                <enumeratedValue>
                                    <name>11</name>
                                    <description>0% (No window end position setting)</description>
                                    <value>#11</value>
                                </enumeratedValue>
                            </enumeratedValues>
                        </field>
                        <field>
                            <name>RPSS</name>
                            <description>Window Start Position Select</description>
                            <lsb>12</lsb>
                            <msb>13</msb>
                            <access>read-write</access>
                            <enumeratedValues>
                                <enumeratedValue>
                                    <name>00</name>
                                    <description>25%</description>
                                    <value>#00</value>
                                </enumeratedValue>
                                <enumeratedValue>
                                    <name>01</name>
                                    <description>50%</description>
                                    <value>#01</value>
                                </enumeratedValue>
                                <enumeratedValue>
                                    <name>10</name>
                                    <description>75%</description>
                                    <value>#10</value>
                                </enumeratedValue>
                                <enumeratedValue>
                                    <name>11</name>
                                    <description>100% (No window start position setting)</description>
                                    <value>#11</value>
                                </enumeratedValue>
                            </enumeratedValues>
                        </field>
                    </fields>
                </register>
                <register>
                    <name>IWDTSR</name>
                    <description>IWDT Status Register</description>
                    <addressOffset>0x4</addressOffset>
                    <size>16</size>
                    <access>read-write</access>
                    <resetValue>0x0000</resetValue>
                    <resetMask>0xffff</resetMask>
                    <fields>
                        <field>
                            <name>CNTVAL</name>
                            <description>Down-Counter Value</description>
                            <lsb>0</lsb>
                            <msb>13</msb>
                            <access>read-only</access>
                        </field>
                        <field>
                            <name>UNDFF</name>
                            <description>Underflow Flag</description>
                            <lsb>14</lsb>
                            <msb>14</msb>
                            <access>read-write</access>
                            <enumeratedValues>
                                <enumeratedValue>
                                    <name>0</name>
                                    <description>No underflow occurred.</description>
                                    <value>#0</value>
                                </enumeratedValue>
                                <enumeratedValue>
                                    <name>1</name>
                                    <description>Underflow occurred.</description>
                                    <value>#1</value>
                                </enumeratedValue>
                            </enumeratedValues>
                        </field>
                        <field>
                            <name>REFEF</name>
                            <description>Refresh Error Flag</description>
                            <lsb>15</lsb>
                            <msb>15</msb>
                            <access>read-write</access>
                            <enumeratedValues>
                                <enumeratedValue>
                                    <name>0</name>
                                    <description>No refresh error occurred.</description>
                                    <value>#0</value>
                                </enumeratedValue>
                                <enumeratedValue>
                                    <name>1</name>
                                    <description>Refresh error occurred.</description>
                                    <value>#1</value>
                                </enumeratedValue>
                            </enumeratedValues>
                        </field>
                    </fields>
                </register>
                <register>
                    <name>IWDTRCR</name>
                    <description>IWDT Reset Control Register</description>
                    <addressOffset>0x6</addressOffset>
                    <size>8</size>
                    <access>read-write</access>
                    <resetValue>0x80</resetValue>
                    <resetMask>0xff</resetMask>
                    <fields>
                        <field>
                            <name>RSTIRQS</name>
                            <description>Reset Interrupt Request Select</description>
                            <lsb>7</lsb>
                            <msb>7</msb>
                            <access>read-write</access>
                            <enumeratedValues>
                                <enumeratedValue>
                                    <name>0</name>
                                    <description>Enable non-maskable interrupt requests or interrupt request output.</description>
                                    <value>#0</value>
                                </enumeratedValue>
                                <enumeratedValue>
                                    <name>1</name>
                                    <description>Enable reset output.</description>
                                    <value>#1</value>
                                </enumeratedValue>
                            </enumeratedValues>
                        </field>
                    </fields>
                </register>
                <register>
                    <name>IWDTCSTPR</name>
                    <description>IWDT Count Stop Control Register</description>
                    <addressOffset>0x8</addressOffset>
                    <size>8</size>
                    <access>read-write</access>
                    <resetValue>0xc0</resetValue>
                    <resetMask>0xff</resetMask>
                    <fields>
                        <field>
                            <name>SLCSTP</name>
                            <description>CPU Sleep-Mode Count Stop Select</description>
                            <lsb>7</lsb>
                            <msb>7</msb>
                            <access>read-write</access>
                            <enumeratedValues>
                                <enumeratedValue>
                                    <name>0</name>
                                    <description>Disable count stop.</description>
                                    <value>#0</value>
                                </enumeratedValue>
                                <enumeratedValue>
                                    <name>1</name>
                                    <description>Stop the counter when the CPU enters CPU Sleep mode, CPU Deep Sleep mode, Software Standby mode, or Deep Software Standby mode 1.</description>
                                    <value>#1</value>
                                </enumeratedValue>
                            </enumeratedValues>
                        </field>
                    </fields>
                </register>
            </registers>
        </peripheral>
        <peripheral>
            <name>CAC_NS</name>
            <description>Clock Frequency Accuracy Measurement Circuit</description>
            <baseAddress>0x50202400</baseAddress>
            <addressBlock>
                <offset>0x00</offset>
                <size>5</size>
                <usage>registers</usage>
            </addressBlock>
            <addressBlock>
                <offset>0x06</offset>
                <size>6</size>
                <usage>registers</usage>
            </addressBlock>
            <registers>
                <register>
                    <name>CACR0</name>
                    <description>CAC Control Register 0</description>
                    <addressOffset>0x00</addressOffset>
                    <size>8</size>
                    <access>read-write</access>
                    <resetValue>0x00</resetValue>
                    <resetMask>0xff</resetMask>
                    <fields>
                        <field>
                            <name>CFME</name>
                            <description>Clock Frequency Measurement Enable</description>
                            <lsb>0</lsb>
                            <msb>0</msb>
                            <access>read-write</access>
                            <enumeratedValues>
                                <enumeratedValue>
                                    <name>0</name>
                                    <description>Disable</description>
                                    <value>#0</value>
                                </enumeratedValue>
                                <enumeratedValue>
                                    <name>1</name>
                                    <description>Enable</description>
                                    <value>#1</value>
                                </enumeratedValue>
                            </enumeratedValues>
                        </field>
                    </fields>
                </register>
                <register>
                    <name>CACR1</name>
                    <description>CAC Control Register 1</description>
                    <addressOffset>0x01</addressOffset>
                    <size>8</size>
                    <access>read-write</access>
                    <resetValue>0x00</resetValue>
                    <resetMask>0xff</resetMask>
                    <fields>
                        <field>
                            <name>CACREFE</name>
                            <description>CACREF Pin Input Enable</description>
                            <lsb>0</lsb>
                            <msb>0</msb>
                            <access>read-write</access>
                            <enumeratedValues>
                                <enumeratedValue>
                                    <name>0</name>
                                    <description>Disable</description>
                                    <value>#0</value>
                                </enumeratedValue>
                                <enumeratedValue>
                                    <name>1</name>
                                    <description>Enable</description>
                                    <value>#1</value>
                                </enumeratedValue>
                            </enumeratedValues>
                        </field>
                        <field>
                            <name>FMCS</name>
                            <description>Measurement Target Clock Select</description>
                            <lsb>1</lsb>
                            <msb>3</msb>
                            <access>read-write</access>
                            <enumeratedValues>
                                <enumeratedValue>
                                    <name>000</name>
                                    <description>Main clock oscillator (CACMCLK)</description>
                                    <value>#000</value>
                                </enumeratedValue>
                                <enumeratedValue>
                                    <name>001</name>
                                    <description>Sub-clock oscillator (CACSCLK)</description>
                                    <value>#001</value>
                                </enumeratedValue>
                                <enumeratedValue>
                                    <name>010</name>
                                    <description>HOCO clock (CACHCLK)</description>
                                    <value>#010</value>
                                </enumeratedValue>
                                <enumeratedValue>
                                    <name>011</name>
                                    <description>MOCO clock (CACMOCLK)</description>
                                    <value>#011</value>
                                </enumeratedValue>
                                <enumeratedValue>
                                    <name>100</name>
                                    <description>LOCO clock (CACLCLK)</description>
                                    <value>#100</value>
                                </enumeratedValue>
                                <enumeratedValue>
                                    <name>101</name>
                                    <description>Peripheral module clock B (PCLKB)</description>
                                    <value>#101</value>
                                </enumeratedValue>
                                <enumeratedValue>
                                    <name>110</name>
                                    <description>Setting prohibited</description>
                                    <value>#110</value>
                                </enumeratedValue>
                                <enumeratedValue>
                                    <name>111</name>
                                    <description>Setting prohibited</description>
                                    <value>#111</value>
                                </enumeratedValue>
                            </enumeratedValues>
                        </field>
                        <field>
                            <name>TCSS</name>
                            <description>Timer Count Clock Source Select</description>
                            <lsb>4</lsb>
                            <msb>5</msb>
                            <access>read-write</access>
                            <enumeratedValues>
                                <enumeratedValue>
                                    <name>00</name>
                                    <description>No division</description>
                                    <value>#00</value>
                                </enumeratedValue>
                                <enumeratedValue>
                                    <name>01</name>
                                    <description>x 1/4 clock</description>
                                    <value>#01</value>
                                </enumeratedValue>
                                <enumeratedValue>
                                    <name>10</name>
                                    <description>x 1/8 clock</description>
                                    <value>#10</value>
                                </enumeratedValue>
                                <enumeratedValue>
                                    <name>11</name>
                                    <description>x 1/32 clock</description>
                                    <value>#11</value>
                                </enumeratedValue>
                            </enumeratedValues>
                        </field>
                        <field>
                            <name>EDGES</name>
                            <description>Valid Edge Select</description>
                            <lsb>6</lsb>
                            <msb>7</msb>
                            <access>read-write</access>
                            <enumeratedValues>
                                <enumeratedValue>
                                    <name>00</name>
                                    <description>Rising edge</description>
                                    <value>#00</value>
                                </enumeratedValue>
                                <enumeratedValue>
                                    <name>01</name>
                                    <description>Falling edge</description>
                                    <value>#01</value>
                                </enumeratedValue>
                                <enumeratedValue>
                                    <name>10</name>
                                    <description>Both rising and falling edges</description>
                                    <value>#10</value>
                                </enumeratedValue>
                                <enumeratedValue>
                                    <name>11</name>
                                    <description>Setting prohibited</description>
                                    <value>#11</value>
                                </enumeratedValue>
                            </enumeratedValues>
                        </field>
                    </fields>
                </register>
                <register>
                    <name>CACR2</name>
                    <description>CAC Control Register 2</description>
                    <addressOffset>0x02</addressOffset>
                    <size>8</size>
                    <access>read-write</access>
                    <resetValue>0x00</resetValue>
                    <resetMask>0xff</resetMask>
                    <fields>
                        <field>
                            <name>RPS</name>
                            <description>Reference Signal Select</description>
                            <lsb>0</lsb>
                            <msb>0</msb>
                            <access>read-write</access>
                            <enumeratedValues>
                                <enumeratedValue>
                                    <name>0</name>
                                    <description>CACREF pin input</description>
                                    <value>#0</value>
                                </enumeratedValue>
                                <enumeratedValue>
                                    <name>1</name>
                                    <description>Internal clock (internally generated signal)</description>
                                    <value>#1</value>
                                </enumeratedValue>
                            </enumeratedValues>
                        </field>
                        <field>
                            <name>RSCS</name>
                            <description>Measurement Reference Clock Select</description>
                            <lsb>1</lsb>
                            <msb>3</msb>
                            <access>read-write</access>
                            <enumeratedValues>
                                <enumeratedValue>
                                    <name>000</name>
                                    <description>Main clock oscillator (CACMCLK)</description>
                                    <value>#000</value>
                                </enumeratedValue>
                                <enumeratedValue>
                                    <name>001</name>
                                    <description>Sub-clock oscillator (CACSCLK)</description>
                                    <value>#001</value>
                                </enumeratedValue>
                                <enumeratedValue>
                                    <name>010</name>
                                    <description>HOCO clock (CACHCLK)</description>
                                    <value>#010</value>
                                </enumeratedValue>
                                <enumeratedValue>
                                    <name>011</name>
                                    <description>MOCO clock (CACMOCLK)</description>
                                    <value>#011</value>
                                </enumeratedValue>
                                <enumeratedValue>
                                    <name>100</name>
                                    <description>LOCO clock (CACLCLK)</description>
                                    <value>#100</value>
                                </enumeratedValue>
                                <enumeratedValue>
                                    <name>101</name>
                                    <description>Peripheral module clock B (PCLKB)</description>
                                    <value>#101</value>
                                </enumeratedValue>
                                <enumeratedValue>
                                    <name>110</name>
                                    <description>Setting prohibited</description>
                                    <value>#110</value>
                                </enumeratedValue>
                                <enumeratedValue>
                                    <name>111</name>
                                    <description>Setting prohibited</description>
                                    <value>#111</value>
                                </enumeratedValue>
                            </enumeratedValues>
                        </field>
                        <field>
                            <name>RCDS</name>
                            <description>Measurement Reference Clock Frequency Division Ratio Select</description>
                            <lsb>4</lsb>
                            <msb>5</msb>
                            <access>read-write</access>
                            <enumeratedValues>
                                <enumeratedValue>
                                    <name>00</name>
                                    <description>x 1/32 clock</description>
                                    <value>#00</value>
                                </enumeratedValue>
                                <enumeratedValue>
                                    <name>01</name>
                                    <description>x 1/128 clock</description>
                                    <value>#01</value>
                                </enumeratedValue>
                                <enumeratedValue>
                                    <name>10</name>
                                    <description>x 1/1024 clock</description>
                                    <value>#10</value>
                                </enumeratedValue>
                                <enumeratedValue>
                                    <name>11</name>
                                    <description>x 1/8192 clock</description>
                                    <value>#11</value>
                                </enumeratedValue>
                            </enumeratedValues>
                        </field>
                        <field>
                            <name>DFS</name>
                            <description>Digital Filter Select</description>
                            <lsb>6</lsb>
                            <msb>7</msb>
                            <access>read-write</access>
                            <enumeratedValues>
                                <enumeratedValue>
                                    <name>00</name>
                                    <description>Disable digital filtering</description>
                                    <value>#00</value>
                                </enumeratedValue>
                                <enumeratedValue>
                                    <name>01</name>
                                    <description>Use sampling clock for the digital filter as the frequency measuring clock</description>
                                    <value>#01</value>
                                </enumeratedValue>
                                <enumeratedValue>
                                    <name>10</name>
                                    <description>Use sampling clock for the digital filter as the frequency measuring clock divided by 4</description>
                                    <value>#10</value>
                                </enumeratedValue>
                                <enumeratedValue>
                                    <name>11</name>
                                    <description>Use sampling clock for the digital filter as the frequency measuring clock divided by 16.</description>
                                    <value>#11</value>
                                </enumeratedValue>
                            </enumeratedValues>
                        </field>
                    </fields>
                </register>
                <register>
                    <name>CAICR</name>
                    <description>CAC Interrupt Control Register</description>
                    <addressOffset>0x03</addressOffset>
                    <size>8</size>
                    <access>read-write</access>
                    <resetValue>0x00</resetValue>
                    <resetMask>0xff</resetMask>
                    <fields>
                        <field>
                            <name>FERRIE</name>
                            <description>Frequency Error Interrupt Request Enable</description>
                            <lsb>0</lsb>
                            <msb>0</msb>
                            <access>read-write</access>
                            <enumeratedValues>
                                <enumeratedValue>
                                    <name>0</name>
                                    <description>Disable</description>
                                    <value>#0</value>
                                </enumeratedValue>
                                <enumeratedValue>
                                    <name>1</name>
                                    <description>Enable</description>
                                    <value>#1</value>
                                </enumeratedValue>
                            </enumeratedValues>
                        </field>
                        <field>
                            <name>MENDIE</name>
                            <description>Measurement End Interrupt Request Enable</description>
                            <lsb>1</lsb>
                            <msb>1</msb>
                            <access>read-write</access>
                            <enumeratedValues>
                                <enumeratedValue>
                                    <name>0</name>
                                    <description>Disable</description>
                                    <value>#0</value>
                                </enumeratedValue>
                                <enumeratedValue>
                                    <name>1</name>
                                    <description>Enable</description>
                                    <value>#1</value>
                                </enumeratedValue>
                            </enumeratedValues>
                        </field>
                        <field>
                            <name>OVFIE</name>
                            <description>Overflow Interrupt Request Enable</description>
                            <lsb>2</lsb>
                            <msb>2</msb>
                            <access>read-write</access>
                            <enumeratedValues>
                                <enumeratedValue>
                                    <name>0</name>
                                    <description>Disable</description>
                                    <value>#0</value>
                                </enumeratedValue>
                                <enumeratedValue>
                                    <name>1</name>
                                    <description>Enable</description>
                                    <value>#1</value>
                                </enumeratedValue>
                            </enumeratedValues>
                        </field>
                        <field>
                            <name>FERRFCL</name>
                            <description>FERRF Clear</description>
                            <lsb>4</lsb>
                            <msb>4</msb>
                            <access>write-only</access>
                            <enumeratedValues>
                                <enumeratedValue>
                                    <name>0</name>
                                    <description>No effect</description>
                                    <value>#0</value>
                                </enumeratedValue>
                                <enumeratedValue>
                                    <name>1</name>
                                    <description>The CASTR.FERRF flag is cleared</description>
                                    <value>#1</value>
                                </enumeratedValue>
                            </enumeratedValues>
                        </field>
                        <field>
                            <name>MENDFCL</name>
                            <description>MENDF Clear</description>
                            <lsb>5</lsb>
                            <msb>5</msb>
                            <access>write-only</access>
                            <enumeratedValues>
                                <enumeratedValue>
                                    <name>0</name>
                                    <description>No effect</description>
                                    <value>#0</value>
                                </enumeratedValue>
                                <enumeratedValue>
                                    <name>1</name>
                                    <description>The CASTR.MENDF flag is cleared</description>
                                    <value>#1</value>
                                </enumeratedValue>
                            </enumeratedValues>
                        </field>
                        <field>
                            <name>OVFFCL</name>
                            <description>OVFF Clear</description>
                            <lsb>6</lsb>
                            <msb>6</msb>
                            <access>write-only</access>
                            <enumeratedValues>
                                <enumeratedValue>
                                    <name>0</name>
                                    <description>No effect</description>
                                    <value>#0</value>
                                </enumeratedValue>
                                <enumeratedValue>
                                    <name>1</name>
                                    <description>The CASTR.OVFF flag is cleared. </description>
                                    <value>#1</value>
                                </enumeratedValue>
                            </enumeratedValues>
                        </field>
                    </fields>
                </register>
                <register>
                    <name>CASTR</name>
                    <description>CAC Status Register</description>
                    <addressOffset>0x04</addressOffset>
                    <size>8</size>
                    <access>read-only</access>
                    <resetValue>0x00</resetValue>
                    <resetMask>0xff</resetMask>
                    <fields>
                        <field>
                            <name>FERRF</name>
                            <description>Frequency Error Flag</description>
                            <lsb>0</lsb>
                            <msb>0</msb>
                            <access>read-only</access>
                            <enumeratedValues>
                                <enumeratedValue>
                                    <name>0</name>
                                    <description>Clock frequency is within the allowable range</description>
                                    <value>#0</value>
                                </enumeratedValue>
                                <enumeratedValue>
                                    <name>1</name>
                                    <description>Clock frequency has deviated beyond the allowable range (frequency error).</description>
                                    <value>#1</value>
                                </enumeratedValue>
                            </enumeratedValues>
                        </field>
                        <field>
                            <name>MENDF</name>
                            <description>Measurement End Flag</description>
                            <lsb>1</lsb>
                            <msb>1</msb>
                            <access>read-only</access>
                            <enumeratedValues>
                                <enumeratedValue>
                                    <name>0</name>
                                    <description>Measurement is in progress</description>
                                    <value>#0</value>
                                </enumeratedValue>
                                <enumeratedValue>
                                    <name>1</name>
                                    <description>Measurement ended</description>
                                    <value>#1</value>
                                </enumeratedValue>
                            </enumeratedValues>
                        </field>
                        <field>
                            <name>OVFF</name>
                            <description>Overflow Flag</description>
                            <lsb>2</lsb>
                            <msb>2</msb>
                            <access>read-only</access>
                            <enumeratedValues>
                                <enumeratedValue>
                                    <name>0</name>
                                    <description>Counter has not overflowed</description>
                                    <value>#0</value>
                                </enumeratedValue>
                                <enumeratedValue>
                                    <name>1</name>
                                    <description>Counter overflowed</description>
                                    <value>#1</value>
                                </enumeratedValue>
                            </enumeratedValues>
                        </field>
                    </fields>
                </register>
                <register>
                    <name>CAULVR</name>
                    <description>CAC Upper-Limit Value Setting Register</description>
                    <addressOffset>0x06</addressOffset>
                    <size>16</size>
                    <access>read-write</access>
                    <resetValue>0x0000</resetValue>
                    <resetMask>0xffff</resetMask>
                </register>
                <register>
                    <name>CALLVR</name>
                    <description>CAC Lower-Limit Value Setting Register</description>
                    <addressOffset>0x08</addressOffset>
                    <size>16</size>
                    <access>read-write</access>
                    <resetValue>0x0000</resetValue>
                    <resetMask>0xffff</resetMask>
                </register>
                <register>
                    <name>CACNTBR</name>
                    <description>CAC Counter Buffer Register</description>
                    <addressOffset>0x0A</addressOffset>
                    <size>16</size>
                    <access>read-only</access>
                    <resetValue>0x0000</resetValue>
                    <resetMask>0xffff</resetMask>
                </register>
            </registers>
        </peripheral>
        <peripheral>
            <name>WDT0_NS</name>
            <description>Watchdog Timer 0</description>
            <baseAddress>0x50202600</baseAddress>
            <addressBlock>
                <offset>0x00</offset>
                <size>1</size>
                <usage>registers</usage>
            </addressBlock>
            <addressBlock>
                <offset>0x02</offset>
                <size>5</size>
                <usage>registers</usage>
            </addressBlock>
            <addressBlock>
                <offset>0x08</offset>
                <size>1</size>
                <usage>registers</usage>
            </addressBlock>
            <registers>
                <register>
                    <name>WDTRR</name>
                    <description>WDT Refresh Register</description>
                    <addressOffset>0x00</addressOffset>
                    <size>8</size>
                    <access>read-write</access>
                    <resetValue>0xff</resetValue>
                    <resetMask>0xff</resetMask>
                </register>
                <register>
                    <name>WDTCR</name>
                    <description>WDT Control Register</description>
                    <addressOffset>0x02</addressOffset>
                    <size>16</size>
                    <access>read-write</access>
                    <resetValue>0x33f3</resetValue>
                    <resetMask>0xffff</resetMask>
                    <fields>
                        <field>
                            <name>TOPS</name>
                            <description>Timeout Period Select</description>
                            <lsb>0</lsb>
                            <msb>1</msb>
                            <access>read-write</access>
                            <enumeratedValues>
                                <enumeratedValue>
                                    <name>00</name>
                                    <description>1024 cycles (0x03FF)</description>
                                    <value>#00</value>
                                </enumeratedValue>
                                <enumeratedValue>
                                    <name>01</name>
                                    <description>4096 cycles (0x0FFF)</description>
                                    <value>#01</value>
                                </enumeratedValue>
                                <enumeratedValue>
                                    <name>10</name>
                                    <description>8192 cycles (0x1FFF)</description>
                                    <value>#10</value>
                                </enumeratedValue>
                                <enumeratedValue>
                                    <name>11</name>
                                    <description>16384 cycles (0x3FFF)</description>
                                    <value>#11</value>
                                </enumeratedValue>
                            </enumeratedValues>
                        </field>
                        <field>
                            <name>CKS</name>
                            <description>Clock Division Ratio Select</description>
                            <lsb>4</lsb>
                            <msb>7</msb>
                            <access>read-write</access>
                            <enumeratedValues>
                                <enumeratedValue>
                                    <name>0001</name>
                                    <description>PCLKB/4</description>
                                    <value>#0001</value>
                                </enumeratedValue>
                                <enumeratedValue>
                                    <name>0100</name>
                                    <description>PCLKB/64</description>
                                    <value>#0100</value>
                                </enumeratedValue>
                                <enumeratedValue>
                                    <name>1111</name>
                                    <description>PCLKB/128</description>
                                    <value>#1111</value>
                                </enumeratedValue>
                                <enumeratedValue>
                                    <name>0110</name>
                                    <description>PCLKB/512</description>
                                    <value>#0110</value>
                                </enumeratedValue>
                                <enumeratedValue>
                                    <name>0111</name>
                                    <description>PCLKB/2048</description>
                                    <value>#0111</value>
                                </enumeratedValue>
                                <enumeratedValue>
                                    <name>1000</name>
                                    <description>PCLKB/8192</description>
                                    <value>#1000</value>
                                </enumeratedValue>
                                <enumeratedValue>
                                    <name>Others</name>
                                    <description>Setting prohibited</description>
                                    <isDefault>true</isDefault>
                                </enumeratedValue>
                            </enumeratedValues>
                        </field>
                        <field>
                            <name>RPES</name>
                            <description>Window End Position Select</description>
                            <lsb>8</lsb>
                            <msb>9</msb>
                            <access>read-write</access>
                            <enumeratedValues>
                                <enumeratedValue>
                                    <name>00</name>
                                    <description>75%</description>
                                    <value>#00</value>
                                </enumeratedValue>
                                <enumeratedValue>
                                    <name>01</name>
                                    <description>50%</description>
                                    <value>#01</value>
                                </enumeratedValue>
                                <enumeratedValue>
                                    <name>10</name>
                                    <description>25%</description>
                                    <value>#10</value>
                                </enumeratedValue>
                                <enumeratedValue>
                                    <name>11</name>
                                    <description>0% (do not specify window end position).</description>
                                    <value>#11</value>
                                </enumeratedValue>
                            </enumeratedValues>
                        </field>
                        <field>
                            <name>RPSS</name>
                            <description>Window Start Position Select</description>
                            <lsb>12</lsb>
                            <msb>13</msb>
                            <access>read-write</access>
                            <enumeratedValues>
                                <enumeratedValue>
                                    <name>00</name>
                                    <description>25%</description>
                                    <value>#00</value>
                                </enumeratedValue>
                                <enumeratedValue>
                                    <name>01</name>
                                    <description>50%</description>
                                    <value>#01</value>
                                </enumeratedValue>
                                <enumeratedValue>
                                    <name>10</name>
                                    <description>75%</description>
                                    <value>#10</value>
                                </enumeratedValue>
                                <enumeratedValue>
                                    <name>11</name>
                                    <description>100% (do not specify window start position).</description>
                                    <value>#11</value>
                                </enumeratedValue>
                            </enumeratedValues>
                        </field>
                    </fields>
                </register>
                <register>
                    <name>WDTSR</name>
                    <description>WDT Status Register</description>
                    <addressOffset>0x04</addressOffset>
                    <size>16</size>
                    <access>read-write</access>
                    <resetValue>0x0000</resetValue>
                    <resetMask>0xffff</resetMask>
                    <fields>
                        <field>
                            <name>CNTVAL</name>
                            <description>Down-Counter Value</description>
                            <lsb>0</lsb>
                            <msb>13</msb>
                            <access>read-only</access>
                        </field>
                        <field>
                            <name>UNDFF</name>
                            <description>Underflow Flag</description>
                            <lsb>14</lsb>
                            <msb>14</msb>
                            <access>read-write</access>
                            <enumeratedValues>
                                <enumeratedValue>
                                    <name>0</name>
                                    <description>No underflow occurred</description>
                                    <value>#0</value>
                                </enumeratedValue>
                                <enumeratedValue>
                                    <name>1</name>
                                    <description>Underflow occurred</description>
                                    <value>#1</value>
                                </enumeratedValue>
                            </enumeratedValues>
                        </field>
                        <field>
                            <name>REFEF</name>
                            <description>Refresh Error Flag</description>
                            <lsb>15</lsb>
                            <msb>15</msb>
                            <access>read-write</access>
                            <enumeratedValues>
                                <enumeratedValue>
                                    <name>0</name>
                                    <description>No refresh error occurred</description>
                                    <value>#0</value>
                                </enumeratedValue>
                                <enumeratedValue>
                                    <name>1</name>
                                    <description>Refresh error occurred</description>
                                    <value>#1</value>
                                </enumeratedValue>
                            </enumeratedValues>
                        </field>
                    </fields>
                </register>
                <register>
                    <name>WDTRCR</name>
                    <description>WDT Reset Control Register</description>
                    <addressOffset>0x06</addressOffset>
                    <size>8</size>
                    <access>read-write</access>
                    <resetValue>0x80</resetValue>
                    <resetMask>0xff</resetMask>
                    <fields>
                        <field>
                            <name>RSTIRQS</name>
                            <description>WDT Behavior Selection</description>
                            <lsb>7</lsb>
                            <msb>7</msb>
                            <access>read-write</access>
                            <enumeratedValues>
                                <enumeratedValue>
                                    <name>0</name>
                                    <description>Interrupt</description>
                                    <value>#0</value>
                                </enumeratedValue>
                                <enumeratedValue>
                                    <name>1</name>
                                    <description>Reset</description>
                                    <value>#1</value>
                                </enumeratedValue>
                            </enumeratedValues>
                        </field>
                    </fields>
                </register>
                <register>
                    <name>WDTCSTPR</name>
                    <description>WDT Count Stop Control Register</description>
                    <addressOffset>0x08</addressOffset>
                    <size>8</size>
                    <access>read-write</access>
                    <resetValue>0x80</resetValue>
                    <resetMask>0xff</resetMask>
                    <fields>
                        <field>
                            <name>SLCSTP</name>
                            <description>CPU Sleep-Mode Count Stop Control Register</description>
                            <lsb>7</lsb>
                            <msb>7</msb>
                            <access>read-write</access>
                            <enumeratedValues>
                                <enumeratedValue>
                                    <name>0</name>
                                    <description>Disable count stop</description>
                                    <value>#0</value>
                                </enumeratedValue>
                                <enumeratedValue>
                                    <name>1</name>
                                    <description>Stop count on transition to CPU Sleep mode or CPU Deep Sleep mode</description>
                                    <value>#1</value>
                                </enumeratedValue>
                            </enumeratedValues>
                        </field>
                    </fields>
                </register>
            </registers>
        </peripheral>
        <peripheral>
            <name>MSTP_NS</name>
            <description>Module Stop Control</description>
            <baseAddress>0x50203000</baseAddress>
            <addressBlock>
                <offset>0x00</offset>
                <size>20</size>
                <usage>registers</usage>
            </addressBlock>
            <registers>
                <register>
                    <name>MSTPCRA</name>
                    <description>Module Stop Control Register A</description>
                    <addressOffset>0x000</addressOffset>
                    <size>32</size>
                    <access>read-write</access>
                    <resetValue>0xffbf7ffc</resetValue>
                    <resetMask>0xffffffff</resetMask>
                    <fields>
                        <field>
                            <name>MSTPA0</name>
                            <description>SRAM0 Module Stop</description>
                            <lsb>0</lsb>
                            <msb>0</msb>
                            <access>read-write</access>
                            <enumeratedValues>
                                <enumeratedValue>
                                    <name>0</name>
                                    <description>Cancel the module-stop state</description>
                                    <value>#0</value>
                                </enumeratedValue>
                                <enumeratedValue>
                                    <name>1</name>
                                    <description>Enter the module-stop state</description>
                                    <value>#1</value>
                                </enumeratedValue>
                            </enumeratedValues>
                        </field>
                        <field>
                            <name>MSTPA1</name>
                            <description>SRAM1 Module Stop</description>
                            <lsb>1</lsb>
                            <msb>1</msb>
                            <access>read-write</access>
                            <enumeratedValues>
                                <enumeratedValue>
                                    <name>0</name>
                                    <description>Cancel the module-stop state</description>
                                    <value>#0</value>
                                </enumeratedValue>
                                <enumeratedValue>
                                    <name>1</name>
                                    <description>Enter the module-stop state</description>
                                    <value>#1</value>
                                </enumeratedValue>
                            </enumeratedValues>
                        </field>
                        <field>
                            <name>MSTPA15</name>
                            <description>Standby SRAM Module Stop</description>
                            <lsb>15</lsb>
                            <msb>15</msb>
                            <access>read-write</access>
                            <enumeratedValues>
                                <enumeratedValue>
                                    <name>0</name>
                                    <description>Cancel the module-stop state</description>
                                    <value>#0</value>
                                </enumeratedValue>
                                <enumeratedValue>
                                    <name>1</name>
                                    <description>Enter the module-stop state</description>
                                    <value>#1</value>
                                </enumeratedValue>
                            </enumeratedValues>
                        </field>
                        <field>
                            <name>MSTPA22</name>
                            <description>DMA Controller and Data Transfer Controller Module Stop</description>
                            <lsb>22</lsb>
                            <msb>22</msb>
                            <access>read-write</access>
                            <enumeratedValues>
                                <enumeratedValue>
                                    <name>0</name>
                                    <description>Cancel the module-stop state</description>
                                    <value>#0</value>
                                </enumeratedValue>
                                <enumeratedValue>
                                    <name>1</name>
                                    <description>Enter the module-stop state</description>
                                    <value>#1</value>
                                </enumeratedValue>
                            </enumeratedValues>
                        </field>
                    </fields>
                </register>
                <register>
                    <name>MSTPCRB</name>
                    <description>Module Stop Control Register B</description>
                    <addressOffset>0x004</addressOffset>
                    <size>32</size>
                    <access>read-write</access>
                    <resetValue>0xffffffff</resetValue>
                    <resetMask>0xffffffff</resetMask>
                    <fields>
                        <field>
                            <name>MSTPB8</name>
                            <description>I2C Bus Interface 1 Module Stop</description>
                            <lsb>8</lsb>
                            <msb>8</msb>
                            <access>read-write</access>
                            <enumeratedValues>
                                <enumeratedValue>
                                    <name>0</name>
                                    <description>Cancel the module-stop state</description>
                                    <value>#0</value>
                                </enumeratedValue>
                                <enumeratedValue>
                                    <name>1</name>
                                    <description>Enter the module-stop state</description>
                                    <value>#1</value>
                                </enumeratedValue>
                            </enumeratedValues>
                        </field>
                        <field>
                            <name>MSTPB9</name>
                            <description>I2C Bus Interface 0 Module Stop</description>
                            <lsb>9</lsb>
                            <msb>9</msb>
                            <access>read-write</access>
                            <enumeratedValues>
                                <enumeratedValue>
                                    <name>0</name>
                                    <description>Cancel the module-stop state</description>
                                    <value>#0</value>
                                </enumeratedValue>
                                <enumeratedValue>
                                    <name>1</name>
                                    <description>Enter the module-stop state</description>
                                    <value>#1</value>
                                </enumeratedValue>
                            </enumeratedValues>
                        </field>
                        <field>
                            <name>MSTPB11</name>
                            <description>Universal Serial Bus 2.0 FS Interface Module Stop</description>
                            <lsb>11</lsb>
                            <msb>11</msb>
                            <access>read-write</access>
                            <enumeratedValues>
                                <enumeratedValue>
                                    <name>0</name>
                                    <description>Cancel the module-stop state</description>
                                    <value>#0</value>
                                </enumeratedValue>
                                <enumeratedValue>
                                    <name>1</name>
                                    <description>Enter the module-stop state</description>
                                    <value>#1</value>
                                </enumeratedValue>
                            </enumeratedValues>
                        </field>
                        <field>
                            <name>MSTPB16</name>
                            <description>Octal Serial Peripheral Interface Module Stop</description>
                            <lsb>16</lsb>
                            <msb>16</msb>
                            <access>read-write</access>
                            <enumeratedValues>
                                <enumeratedValue>
                                    <name>0</name>
                                    <description>Cancel the module-stop state</description>
                                    <value>#0</value>
                                </enumeratedValue>
                                <enumeratedValue>
                                    <name>1</name>
                                    <description>Enter the module-stop state</description>
                                    <value>#1</value>
                                </enumeratedValue>
                            </enumeratedValues>
                        </field>
                        <field>
                            <name>MSTPB18</name>
                            <description>Serial Peripheral Interface 1 Module Stop</description>
                            <lsb>18</lsb>
                            <msb>18</msb>
                            <access>read-write</access>
                            <enumeratedValues>
                                <enumeratedValue>
                                    <name>0</name>
                                    <description>Cancel the module-stop state</description>
                                    <value>#0</value>
                                </enumeratedValue>
                                <enumeratedValue>
                                    <name>1</name>
                                    <description>Enter the module-stop state</description>
                                    <value>#1</value>
                                </enumeratedValue>
                            </enumeratedValues>
                        </field>
                        <field>
                            <name>MSTPB19</name>
                            <description>Serial Peripheral Interface 0 Module Stop</description>
                            <lsb>19</lsb>
                            <msb>19</msb>
                            <access>read-write</access>
                            <enumeratedValues>
                                <enumeratedValue>
                                    <name>0</name>
                                    <description>Cancel the module-stop state</description>
                                    <value>#0</value>
                                </enumeratedValue>
                                <enumeratedValue>
                                    <name>1</name>
                                    <description>Enter the module-stop state</description>
                                    <value>#1</value>
                                </enumeratedValue>
                            </enumeratedValues>
                        </field>
                        <field>
                            <name>MSTPB22</name>
                            <description>Serial Communication Interface 9 Module Stop</description>
                            <lsb>22</lsb>
                            <msb>22</msb>
                            <access>read-write</access>
                            <enumeratedValues>
                                <enumeratedValue>
                                    <name>0</name>
                                    <description>Cancel the module-stop state</description>
                                    <value>#0</value>
                                </enumeratedValue>
                                <enumeratedValue>
                                    <name>1</name>
                                    <description>Enter the module-stop state</description>
                                    <value>#1</value>
                                </enumeratedValue>
                            </enumeratedValues>
                        </field>
                        <field>
                            <name>MSTPB27</name>
                            <description>Serial Communication Interface 4 Module Stop</description>
                            <lsb>27</lsb>
                            <msb>27</msb>
                            <access>read-write</access>
                            <enumeratedValues>
                                <enumeratedValue>
                                    <name>0</name>
                                    <description>Cancel the module-stop state</description>
                                    <value>#0</value>
                                </enumeratedValue>
                                <enumeratedValue>
                                    <name>1</name>
                                    <description>Enter the module-stop state</description>
                                    <value>#1</value>
                                </enumeratedValue>
                            </enumeratedValues>
                        </field>
                        <field>
                            <name>MSTPB28</name>
                            <description>Serial Communication Interface 3 Module Stop</description>
                            <lsb>28</lsb>
                            <msb>28</msb>
                            <access>read-write</access>
                            <enumeratedValues>
                                <enumeratedValue>
                                    <name>0</name>
                                    <description>Cancel the module-stop state</description>
                                    <value>#0</value>
                                </enumeratedValue>
                                <enumeratedValue>
                                    <name>1</name>
                                    <description>Enter the module-stop state</description>
                                    <value>#1</value>
                                </enumeratedValue>
                            </enumeratedValues>
                        </field>
                        <field>
                            <name>MSTPB29</name>
                            <description>Serial Communication Interface 2 Module Stop</description>
                            <lsb>29</lsb>
                            <msb>29</msb>
                            <access>read-write</access>
                            <enumeratedValues>
                                <enumeratedValue>
                                    <name>0</name>
                                    <description>Cancel the module-stop state</description>
                                    <value>#0</value>
                                </enumeratedValue>
                                <enumeratedValue>
                                    <name>1</name>
                                    <description>Enter the module-stop state</description>
                                    <value>#1</value>
                                </enumeratedValue>
                            </enumeratedValues>
                        </field>
                        <field>
                            <name>MSTPB30</name>
                            <description>Serial Communication Interface 1 Module Stop</description>
                            <lsb>30</lsb>
                            <msb>30</msb>
                            <access>read-write</access>
                            <enumeratedValues>
                                <enumeratedValue>
                                    <name>0</name>
                                    <description>Cancel the module-stop state</description>
                                    <value>#0</value>
                                </enumeratedValue>
                                <enumeratedValue>
                                    <name>1</name>
                                    <description>Enter the module-stop state</description>
                                    <value>#1</value>
                                </enumeratedValue>
                            </enumeratedValues>
                        </field>
                        <field>
                            <name>MSTPB31</name>
                            <description>Serial Communication Interface 0 Module Stop</description>
                            <lsb>31</lsb>
                            <msb>31</msb>
                            <access>read-write</access>
                            <enumeratedValues>
                                <enumeratedValue>
                                    <name>0</name>
                                    <description>Cancel the module-stop state</description>
                                    <value>#0</value>
                                </enumeratedValue>
                                <enumeratedValue>
                                    <name>1</name>
                                    <description>Enter the module-stop state</description>
                                    <value>#1</value>
                                </enumeratedValue>
                            </enumeratedValues>
                        </field>
                    </fields>
                </register>
                <register>
                    <name>MSTPCRC</name>
                    <description>Module Stop Control Register C</description>
                    <addressOffset>0x008</addressOffset>
                    <size>32</size>
                    <access>read-write</access>
                    <resetValue>0xffffffff</resetValue>
                    <resetMask>0xffffffff</resetMask>
                    <fields>
                        <field>
                            <name>MSTPC0</name>
                            <description>Clock Frequency Accuracy Measurement Circuit Module Stop</description>
                            <lsb>0</lsb>
                            <msb>0</msb>
                            <access>read-write</access>
                            <enumeratedValues>
                                <enumeratedValue>
                                    <name>0</name>
                                    <description>Cancel the module-stop state</description>
                                    <value>#0</value>
                                </enumeratedValue>
                                <enumeratedValue>
                                    <name>1</name>
                                    <description>Enter the module-stop state</description>
                                    <value>#1</value>
                                </enumeratedValue>
                            </enumeratedValues>
                        </field>
                        <field>
                            <name>MSTPC1</name>
                            <description>Cyclic Redundancy Check Calculator Module Stop</description>
                            <lsb>1</lsb>
                            <msb>1</msb>
                            <access>read-write</access>
                            <enumeratedValues>
                                <enumeratedValue>
                                    <name>0</name>
                                    <description>Cancel the module-stop state</description>
                                    <value>#0</value>
                                </enumeratedValue>
                                <enumeratedValue>
                                    <name>1</name>
                                    <description>Enter the module-stop state</description>
                                    <value>#1</value>
                                </enumeratedValue>
                            </enumeratedValues>
                        </field>
                        <field>
                            <name>MSTPC4</name>
                            <description>Graphics LCD Controller Module Stop</description>
                            <lsb>4</lsb>
                            <msb>4</msb>
                            <access>read-write</access>
                            <enumeratedValues>
                                <enumeratedValue>
                                    <name>0</name>
                                    <description>Cancel the module-stop state</description>
                                    <value>#0</value>
                                </enumeratedValue>
                                <enumeratedValue>
                                    <name>1</name>
                                    <description>Enter the module-stop state</description>
                                    <value>#1</value>
                                </enumeratedValue>
                            </enumeratedValues>
                        </field>
                        <field>
                            <name>MSTPC6</name>
                            <description>2D Drawing Engine Module Stop</description>
                            <lsb>6</lsb>
                            <msb>6</msb>
                            <access>read-write</access>
                            <enumeratedValues>
                                <enumeratedValue>
                                    <name>0</name>
                                    <description>Cancel the module-stop state</description>
                                    <value>#0</value>
                                </enumeratedValue>
                                <enumeratedValue>
                                    <name>1</name>
                                    <description>Enter the module-stop state</description>
                                    <value>#1</value>
                                </enumeratedValue>
                            </enumeratedValues>
                        </field>
                        <field>
                            <name>MSTPC7</name>
                            <description>Serial Sound Interface Enhanced 1 Module Stop</description>
                            <lsb>7</lsb>
                            <msb>7</msb>
                            <access>read-write</access>
                            <enumeratedValues>
                                <enumeratedValue>
                                    <name>0</name>
                                    <description>Cancel the module-stop state</description>
                                    <value>#0</value>
                                </enumeratedValue>
                                <enumeratedValue>
                                    <name>1</name>
                                    <description>Enter the module-stop state</description>
                                    <value>#1</value>
                                </enumeratedValue>
                            </enumeratedValues>
                        </field>
                        <field>
                            <name>MSTPC8</name>
                            <description>Serial Sound Interface Enhanced 0 Module Stop</description>
                            <lsb>8</lsb>
                            <msb>8</msb>
                            <access>read-write</access>
                            <enumeratedValues>
                                <enumeratedValue>
                                    <name>0</name>
                                    <description>Cancel the module-stop state</description>
                                    <value>#0</value>
                                </enumeratedValue>
                                <enumeratedValue>
                                    <name>1</name>
                                    <description>Enter the module-stop state</description>
                                    <value>#1</value>
                                </enumeratedValue>
                            </enumeratedValues>
                        </field>
                        <field>
                            <name>MSTPC13</name>
                            <description>Data Operation Circuit Module Stop</description>
                            <lsb>13</lsb>
                            <msb>13</msb>
                            <access>read-write</access>
                            <enumeratedValues>
                                <enumeratedValue>
                                    <name>0</name>
                                    <description>Cancel the module-stop state</description>
                                    <value>#0</value>
                                </enumeratedValue>
                                <enumeratedValue>
                                    <name>1</name>
                                    <description>Enter the module-stop state</description>
                                    <value>#1</value>
                                </enumeratedValue>
                            </enumeratedValues>
                        </field>
                        <field>
                            <name>MSTPC14</name>
                            <description>Event Link Controller Module Stop</description>
                            <lsb>14</lsb>
                            <msb>14</msb>
                            <access>read-write</access>
                            <enumeratedValues>
                                <enumeratedValue>
                                    <name>0</name>
                                    <description>Cancel the module-stop state</description>
                                    <value>#0</value>
                                </enumeratedValue>
                                <enumeratedValue>
                                    <name>1</name>
                                    <description>Enter the module-stop state</description>
                                    <value>#1</value>
                                </enumeratedValue>
                            </enumeratedValues>
                        </field>
                        <field>
                            <name>MSTPC26</name>
                            <description>Controller Area Network with Flexible Data-Rate 1 Module Stop</description>
                            <lsb>26</lsb>
                            <msb>26</msb>
                            <access>read-write</access>
                            <enumeratedValues>
                                <enumeratedValue>
                                    <name>0</name>
                                    <description>Cancel the module-stop state</description>
                                    <value>#0</value>
                                </enumeratedValue>
                                <enumeratedValue>
                                    <name>1</name>
                                    <description>Enter the module-stop state</description>
                                    <value>#1</value>
                                </enumeratedValue>
                            </enumeratedValues>
                        </field>
                        <field>
                            <name>MSTPC27</name>
                            <description>Controller Area Network with Flexible Data-Rate 0 Module Stop</description>
                            <lsb>27</lsb>
                            <msb>27</msb>
                            <access>read-write</access>
                            <enumeratedValues>
                                <enumeratedValue>
                                    <name>0</name>
                                    <description>Cancel the module-stop state</description>
                                    <value>#0</value>
                                </enumeratedValue>
                                <enumeratedValue>
                                    <name>1</name>
                                    <description>Enter the module-stop state</description>
                                    <value>#1</value>
                                </enumeratedValue>
                            </enumeratedValues>
                        </field>
                        <field>
                            <name>MSTPC31</name>
                            <description>Renesas Secure IP Module Stop</description>
                            <lsb>31</lsb>
                            <msb>31</msb>
                            <access>read-write</access>
                            <enumeratedValues>
                                <enumeratedValue>
                                    <name>0</name>
                                    <description>Cancel the module-stop state</description>
                                    <value>#0</value>
                                </enumeratedValue>
                                <enumeratedValue>
                                    <name>1</name>
                                    <description>Enter the module-stop state</description>
                                    <value>#1</value>
                                </enumeratedValue>
                            </enumeratedValues>
                        </field>
                    </fields>
                </register>
                <register>
                    <name>MSTPCRD</name>
                    <description>Module Stop Control Register D</description>
                    <addressOffset>0x00C</addressOffset>
                    <size>32</size>
                    <access>read-write</access>
                    <resetValue>0xffffffff</resetValue>
                    <resetMask>0xffffffff</resetMask>
                    <fields>
                        <field>
                            <name>MSTPD4</name>
                            <description>Low Power Asynchronous General Purpose Timer 1 Module Stop</description>
                            <lsb>4</lsb>
                            <msb>4</msb>
                            <access>read-write</access>
                            <enumeratedValues>
                                <enumeratedValue>
                                    <name>0</name>
                                    <description>Cancel the module-stop state</description>
                                    <value>#0</value>
                                </enumeratedValue>
                                <enumeratedValue>
                                    <name>1</name>
                                    <description>Enter the module-stop state</description>
                                    <value>#1</value>
                                </enumeratedValue>
                            </enumeratedValues>
                        </field>
                        <field>
                            <name>MSTPD5</name>
                            <description>Low Power Asynchronous General Purpose Timer 0 Module Stop</description>
                            <lsb>5</lsb>
                            <msb>5</msb>
                            <access>read-write</access>
                            <enumeratedValues>
                                <enumeratedValue>
                                    <name>0</name>
                                    <description>Cancel the module-stop state</description>
                                    <value>#0</value>
                                </enumeratedValue>
                                <enumeratedValue>
                                    <name>1</name>
                                    <description>Enter the module-stop state</description>
                                    <value>#1</value>
                                </enumeratedValue>
                            </enumeratedValues>
                        </field>
                        <field>
                            <name>MSTPD11</name>
                            <description>Port Output Enable for GPT Group D Module Stop</description>
                            <lsb>11</lsb>
                            <msb>11</msb>
                            <access>read-write</access>
                            <enumeratedValues>
                                <enumeratedValue>
                                    <name>0</name>
                                    <description>Cancel the module-stop state</description>
                                    <value>#0</value>
                                </enumeratedValue>
                                <enumeratedValue>
                                    <name>1</name>
                                    <description>Enter the module-stop state</description>
                                    <value>#1</value>
                                </enumeratedValue>
                            </enumeratedValues>
                        </field>
                        <field>
                            <name>MSTPD12</name>
                            <description>Port Output Enable for GPT Group C Module Stop</description>
                            <lsb>12</lsb>
                            <msb>12</msb>
                            <access>read-write</access>
                            <enumeratedValues>
                                <enumeratedValue>
                                    <name>0</name>
                                    <description>Cancel the module-stop state</description>
                                    <value>#0</value>
                                </enumeratedValue>
                                <enumeratedValue>
                                    <name>1</name>
                                    <description>Enter the module-stop state</description>
                                    <value>#1</value>
                                </enumeratedValue>
                            </enumeratedValues>
                        </field>
                        <field>
                            <name>MSTPD13</name>
                            <description>Port Output Enable for GPT Group B Module Stop</description>
                            <lsb>13</lsb>
                            <msb>13</msb>
                            <access>read-write</access>
                            <enumeratedValues>
                                <enumeratedValue>
                                    <name>0</name>
                                    <description>Cancel the module-stop state</description>
                                    <value>#0</value>
                                </enumeratedValue>
                                <enumeratedValue>
                                    <name>1</name>
                                    <description>Enter the module-stop state</description>
                                    <value>#1</value>
                                </enumeratedValue>
                            </enumeratedValues>
                        </field>
                        <field>
                            <name>MSTPD14</name>
                            <description>Port Output Enable for GPT Group A Module Stop</description>
                            <lsb>14</lsb>
                            <msb>14</msb>
                            <access>read-write</access>
                            <enumeratedValues>
                                <enumeratedValue>
                                    <name>0</name>
                                    <description>Cancel the module-stop state</description>
                                    <value>#0</value>
                                </enumeratedValue>
                                <enumeratedValue>
                                    <name>1</name>
                                    <description>Enter the module-stop state</description>
                                    <value>#1</value>
                                </enumeratedValue>
                            </enumeratedValues>
                        </field>
                        <field>
                            <name>MSTPD15</name>
                            <description>12-bit A/D Converter 1 Module Stop</description>
                            <lsb>15</lsb>
                            <msb>15</msb>
                            <access>read-write</access>
                            <enumeratedValues>
                                <enumeratedValue>
                                    <name>0</name>
                                    <description>Cancel the module-stop state</description>
                                    <value>#0</value>
                                </enumeratedValue>
                                <enumeratedValue>
                                    <name>1</name>
                                    <description>Enter the module-stop state</description>
                                    <value>#1</value>
                                </enumeratedValue>
                            </enumeratedValues>
                        </field>
                        <field>
                            <name>MSTPD16</name>
                            <description>12-bit A/D Converter 0 Module Stop</description>
                            <lsb>16</lsb>
                            <msb>16</msb>
                            <access>read-write</access>
                            <enumeratedValues>
                                <enumeratedValue>
                                    <name>0</name>
                                    <description>Cancel the module-stop state</description>
                                    <value>#0</value>
                                </enumeratedValue>
                                <enumeratedValue>
                                    <name>1</name>
                                    <description>Enter the module-stop state</description>
                                    <value>#1</value>
                                </enumeratedValue>
                            </enumeratedValues>
                        </field>
                        <field>
                            <name>MSTPD20</name>
                            <description>12-bit D/A Converter Module Stop</description>
                            <lsb>20</lsb>
                            <msb>20</msb>
                            <access>read-write</access>
                            <enumeratedValues>
                                <enumeratedValue>
                                    <name>0</name>
                                    <description>Cancel the module-stop state</description>
                                    <value>#0</value>
                                </enumeratedValue>
                                <enumeratedValue>
                                    <name>1</name>
                                    <description>Enter the module-stop state</description>
                                    <value>#1</value>
                                </enumeratedValue>
                            </enumeratedValues>
                        </field>
                        <field>
                            <name>MSTPD22</name>
                            <description>Temperature Sensor Module Stop</description>
                            <lsb>22</lsb>
                            <msb>22</msb>
                            <access>read-write</access>
                            <enumeratedValues>
                                <enumeratedValue>
                                    <name>0</name>
                                    <description>Cancel the module-stop state</description>
                                    <value>#0</value>
                                </enumeratedValue>
                                <enumeratedValue>
                                    <name>1</name>
                                    <description>Enter the module-stop state</description>
                                    <value>#1</value>
                                </enumeratedValue>
                            </enumeratedValues>
                        </field>
                        <field>
                            <name>MSTPD27</name>
                            <description>High-Speed Analog Comparator 1 Module Stop</description>
                            <lsb>27</lsb>
                            <msb>27</msb>
                            <access>read-write</access>
                            <enumeratedValues>
                                <enumeratedValue>
                                    <name>0</name>
                                    <description>Cancel the module-stop state</description>
                                    <value>#0</value>
                                </enumeratedValue>
                                <enumeratedValue>
                                    <name>1</name>
                                    <description>Enter the module-stop state</description>
                                    <value>#1</value>
                                </enumeratedValue>
                            </enumeratedValues>
                        </field>
                        <field>
                            <name>MSTPD28</name>
                            <description>High-Speed Analog Comparator 0 Module Stop</description>
                            <lsb>28</lsb>
                            <msb>28</msb>
                            <access>read-write</access>
                            <enumeratedValues>
                                <enumeratedValue>
                                    <name>0</name>
                                    <description>Cancel the module-stop state</description>
                                    <value>#0</value>
                                </enumeratedValue>
                                <enumeratedValue>
                                    <name>1</name>
                                    <description>Enter the module-stop state</description>
                                    <value>#1</value>
                                </enumeratedValue>
                            </enumeratedValues>
                        </field>
                    </fields>
                </register>
                <register>
                    <name>MSTPCRE</name>
                    <description>Module Stop Control Register E</description>
                    <addressOffset>0x010</addressOffset>
                    <size>32</size>
                    <access>read-write</access>
                    <resetValue>0xffffffff</resetValue>
                    <resetMask>0xffffffff</resetMask>
                    <fields>
                        <field>
                            <name>MSTPE8</name>
                            <description>Ultra-Low Power Timer 1 Module Stop</description>
                            <lsb>8</lsb>
                            <msb>8</msb>
                            <access>read-write</access>
                            <enumeratedValues>
                                <enumeratedValue>
                                    <name>0</name>
                                    <description>Cancel the module-stop state</description>
                                    <value>#0</value>
                                </enumeratedValue>
                                <enumeratedValue>
                                    <name>1</name>
                                    <description>Enter the module-stop state</description>
                                    <value>#1</value>
                                </enumeratedValue>
                            </enumeratedValues>
                        </field>
                        <field>
                            <name>MSTPE9</name>
                            <description>Ultra-Low Power Timer 0 Module Stop</description>
                            <lsb>9</lsb>
                            <msb>9</msb>
                            <access>read-write</access>
                            <enumeratedValues>
                                <enumeratedValue>
                                    <name>0</name>
                                    <description>Cancel the module-stop state</description>
                                    <value>#0</value>
                                </enumeratedValue>
                                <enumeratedValue>
                                    <name>1</name>
                                    <description>Enter the module-stop state</description>
                                    <value>#1</value>
                                </enumeratedValue>
                            </enumeratedValues>
                        </field>
                        <field>
                            <name>MSTPE18</name>
                            <description>General PWM Timer 13 Module</description>
                            <lsb>18</lsb>
                            <msb>18</msb>
                            <access>read-write</access>
                            <enumeratedValues>
                                <enumeratedValue>
                                    <name>0</name>
                                    <description>Cancel the module-stop state</description>
                                    <value>#0</value>
                                </enumeratedValue>
                                <enumeratedValue>
                                    <name>1</name>
                                    <description>Enter the module-stop state</description>
                                    <value>#1</value>
                                </enumeratedValue>
                            </enumeratedValues>
                        </field>
                        <field>
                            <name>MSTPE19</name>
                            <description>General PWM Timer 12 Module</description>
                            <lsb>19</lsb>
                            <msb>19</msb>
                            <access>read-write</access>
                            <enumeratedValues>
                                <enumeratedValue>
                                    <name>0</name>
                                    <description>Cancel the module-stop state</description>
                                    <value>#0</value>
                                </enumeratedValue>
                                <enumeratedValue>
                                    <name>1</name>
                                    <description>Enter the module-stop state</description>
                                    <value>#1</value>
                                </enumeratedValue>
                            </enumeratedValues>
                        </field>
                        <field>
                            <name>MSTPE20</name>
                            <description>General PWM Timer 11 Module</description>
                            <lsb>20</lsb>
                            <msb>20</msb>
                            <access>read-write</access>
                            <enumeratedValues>
                                <enumeratedValue>
                                    <name>0</name>
                                    <description>Cancel the module-stop state</description>
                                    <value>#0</value>
                                </enumeratedValue>
                                <enumeratedValue>
                                    <name>1</name>
                                    <description>Enter the module-stop state</description>
                                    <value>#1</value>
                                </enumeratedValue>
                            </enumeratedValues>
                        </field>
                        <field>
                            <name>MSTPE21</name>
                            <description>General PWM Timer 10 Module</description>
                            <lsb>21</lsb>
                            <msb>21</msb>
                            <access>read-write</access>
                            <enumeratedValues>
                                <enumeratedValue>
                                    <name>0</name>
                                    <description>Cancel the module-stop state</description>
                                    <value>#0</value>
                                </enumeratedValue>
                                <enumeratedValue>
                                    <name>1</name>
                                    <description>Enter the module-stop state</description>
                                    <value>#1</value>
                                </enumeratedValue>
                            </enumeratedValues>
                        </field>
                        <field>
                            <name>MSTPE26</name>
                            <description>General PWM Timer 5 Module</description>
                            <lsb>26</lsb>
                            <msb>26</msb>
                            <access>read-write</access>
                            <enumeratedValues>
                                <enumeratedValue>
                                    <name>0</name>
                                    <description>Cancel the module-stop state</description>
                                    <value>#0</value>
                                </enumeratedValue>
                                <enumeratedValue>
                                    <name>1</name>
                                    <description>Enter the module-stop state</description>
                                    <value>#1</value>
                                </enumeratedValue>
                            </enumeratedValues>
                        </field>
                        <field>
                            <name>MSTPE27</name>
                            <description>General PWM Timer 4 Module</description>
                            <lsb>27</lsb>
                            <msb>27</msb>
                            <access>read-write</access>
                            <enumeratedValues>
                                <enumeratedValue>
                                    <name>0</name>
                                    <description>Cancel the module-stop state</description>
                                    <value>#0</value>
                                </enumeratedValue>
                                <enumeratedValue>
                                    <name>1</name>
                                    <description>Enter the module-stop state</description>
                                    <value>#1</value>
                                </enumeratedValue>
                            </enumeratedValues>
                        </field>
                        <field>
                            <name>MSTPE28</name>
                            <description>General PWM Timer 3 Module</description>
                            <lsb>28</lsb>
                            <msb>28</msb>
                            <access>read-write</access>
                            <enumeratedValues>
                                <enumeratedValue>
                                    <name>0</name>
                                    <description>Cancel the module-stop state</description>
                                    <value>#0</value>
                                </enumeratedValue>
                                <enumeratedValue>
                                    <name>1</name>
                                    <description>Enter the module-stop state</description>
                                    <value>#1</value>
                                </enumeratedValue>
                            </enumeratedValues>
                        </field>
                        <field>
                            <name>MSTPE29</name>
                            <description>General PWM Timer 2 Module</description>
                            <lsb>29</lsb>
                            <msb>29</msb>
                            <access>read-write</access>
                            <enumeratedValues>
                                <enumeratedValue>
                                    <name>0</name>
                                    <description>Cancel the module-stop state</description>
                                    <value>#0</value>
                                </enumeratedValue>
                                <enumeratedValue>
                                    <name>1</name>
                                    <description>Enter the module-stop state</description>
                                    <value>#1</value>
                                </enumeratedValue>
                            </enumeratedValues>
                        </field>
                        <field>
                            <name>MSTPE30</name>
                            <description>General PWM Timer 1 Module</description>
                            <lsb>30</lsb>
                            <msb>30</msb>
                            <access>read-write</access>
                            <enumeratedValues>
                                <enumeratedValue>
                                    <name>0</name>
                                    <description>Cancel the module-stop state</description>
                                    <value>#0</value>
                                </enumeratedValue>
                                <enumeratedValue>
                                    <name>1</name>
                                    <description>Enter the module-stop state</description>
                                    <value>#1</value>
                                </enumeratedValue>
                            </enumeratedValues>
                        </field>
                        <field>
                            <name>MSTPE31</name>
                            <description>General PWM Timer 0 Module</description>
                            <lsb>31</lsb>
                            <msb>31</msb>
                            <access>read-write</access>
                            <enumeratedValues>
                                <enumeratedValue>
                                    <name>0</name>
                                    <description>Cancel the module-stop state</description>
                                    <value>#0</value>
                                </enumeratedValue>
                                <enumeratedValue>
                                    <name>1</name>
                                    <description>Enter the module-stop state</description>
                                    <value>#1</value>
                                </enumeratedValue>
                            </enumeratedValues>
                        </field>
                    </fields>
                </register>
            </registers>
        </peripheral>
        <peripheral>
            <name>PSCU_NS</name>
            <description>Peripheral Security Control Unit</description>
            <baseAddress>0x50204000</baseAddress>
            <addressBlock>
                <offset>0x04</offset>
                <size>20</size>
                <usage>registers</usage>
            </addressBlock>
            <addressBlock>
                <offset>0x1C</offset>
                <size>32</size>
                <usage>registers</usage>
            </addressBlock>
            <registers>
                <register>
                    <name>PSARB</name>
                    <description>Peripheral Security Attribution Register B</description>
                    <addressOffset>0x04</addressOffset>
                    <size>32</size>
                    <access>read-write</access>
                    <resetValue>0x00000000</resetValue>
                    <resetMask>0xffffffff</resetMask>
                    <fields>
                        <field>
                            <name>PSARB8</name>
                            <description>I2C Bus Interface 1 Security Attribution</description>
                            <lsb>8</lsb>
                            <msb>8</msb>
                            <access>read-write</access>
                            <enumeratedValues>
                                <enumeratedValue>
                                    <name>0</name>
                                    <description>Secure</description>
                                    <value>#0</value>
                                </enumeratedValue>
                                <enumeratedValue>
                                    <name>1</name>
                                    <description>Non-secure</description>
                                    <value>#1</value>
                                </enumeratedValue>
                            </enumeratedValues>
                        </field>
                        <field>
                            <name>PSARB9</name>
                            <description>I2C Bus Interface 0 Security Attribution</description>
                            <lsb>9</lsb>
                            <msb>9</msb>
                            <access>read-write</access>
                            <enumeratedValues>
                                <enumeratedValue>
                                    <name>0</name>
                                    <description>Secure</description>
                                    <value>#0</value>
                                </enumeratedValue>
                                <enumeratedValue>
                                    <name>1</name>
                                    <description>Non-secure</description>
                                    <value>#1</value>
                                </enumeratedValue>
                            </enumeratedValues>
                        </field>
                        <field>
                            <name>PSARB11</name>
                            <description>Universal Serial Bus 2.0 FS Interface 0 Security Attribution</description>
                            <lsb>11</lsb>
                            <msb>11</msb>
                            <access>read-write</access>
                            <enumeratedValues>
                                <enumeratedValue>
                                    <name>0</name>
                                    <description>Secure</description>
                                    <value>#0</value>
                                </enumeratedValue>
                                <enumeratedValue>
                                    <name>1</name>
                                    <description>Non-secure</description>
                                    <value>#1</value>
                                </enumeratedValue>
                            </enumeratedValues>
                        </field>
                        <field>
                            <name>PSARB16</name>
                            <description>Octa Memory Controller Security Attribution</description>
                            <lsb>16</lsb>
                            <msb>16</msb>
                            <access>read-write</access>
                            <enumeratedValues>
                                <enumeratedValue>
                                    <name>0</name>
                                    <description>Secure</description>
                                    <value>#0</value>
                                </enumeratedValue>
                                <enumeratedValue>
                                    <name>1</name>
                                    <description>Non-secure</description>
                                    <value>#1</value>
                                </enumeratedValue>
                            </enumeratedValues>
                        </field>
                        <field>
                            <name>PSARB18</name>
                            <description>Serial Peripheral Interface 1 Security Attribution</description>
                            <lsb>18</lsb>
                            <msb>18</msb>
                            <access>read-write</access>
                            <enumeratedValues>
                                <enumeratedValue>
                                    <name>0</name>
                                    <description>Secure</description>
                                    <value>#0</value>
                                </enumeratedValue>
                                <enumeratedValue>
                                    <name>1</name>
                                    <description>Non-secure</description>
                                    <value>#1</value>
                                </enumeratedValue>
                            </enumeratedValues>
                        </field>
                        <field>
                            <name>PSARB19</name>
                            <description>Serial Peripheral Interface 0 Security Attribution</description>
                            <lsb>19</lsb>
                            <msb>19</msb>
                            <access>read-write</access>
                            <enumeratedValues>
                                <enumeratedValue>
                                    <name>0</name>
                                    <description>Secure</description>
                                    <value>#0</value>
                                </enumeratedValue>
                                <enumeratedValue>
                                    <name>1</name>
                                    <description>Non-secure</description>
                                    <value>#1</value>
                                </enumeratedValue>
                            </enumeratedValues>
                        </field>
                        <field>
                            <name>PSARB22</name>
                            <description>Serial Communication Interface 9 Security Attribution</description>
                            <lsb>22</lsb>
                            <msb>22</msb>
                            <access>read-write</access>
                            <enumeratedValues>
                                <enumeratedValue>
                                    <name>0</name>
                                    <description>Secure</description>
                                    <value>#0</value>
                                </enumeratedValue>
                                <enumeratedValue>
                                    <name>1</name>
                                    <description>Non-secure</description>
                                    <value>#1</value>
                                </enumeratedValue>
                            </enumeratedValues>
                        </field>
                        <field>
                            <name>PSARB27</name>
                            <description>Serial Communication Interface 4 Security Attribution</description>
                            <lsb>27</lsb>
                            <msb>27</msb>
                            <access>read-write</access>
                            <enumeratedValues>
                                <enumeratedValue>
                                    <name>0</name>
                                    <description>Secure</description>
                                    <value>#0</value>
                                </enumeratedValue>
                                <enumeratedValue>
                                    <name>1</name>
                                    <description>Non-secure</description>
                                    <value>#1</value>
                                </enumeratedValue>
                            </enumeratedValues>
                        </field>
                        <field>
                            <name>PSARB28</name>
                            <description>Serial Communication Interface 3 Security Attribution</description>
                            <lsb>28</lsb>
                            <msb>28</msb>
                            <access>read-write</access>
                            <enumeratedValues>
                                <enumeratedValue>
                                    <name>0</name>
                                    <description>Secure</description>
                                    <value>#0</value>
                                </enumeratedValue>
                                <enumeratedValue>
                                    <name>1</name>
                                    <description>Non-secure</description>
                                    <value>#1</value>
                                </enumeratedValue>
                            </enumeratedValues>
                        </field>
                        <field>
                            <name>PSARB29</name>
                            <description>Serial Communication Interface 2 Security Attribution</description>
                            <lsb>29</lsb>
                            <msb>29</msb>
                            <access>read-write</access>
                            <enumeratedValues>
                                <enumeratedValue>
                                    <name>0</name>
                                    <description>Secure</description>
                                    <value>#0</value>
                                </enumeratedValue>
                                <enumeratedValue>
                                    <name>1</name>
                                    <description>Non-secure</description>
                                    <value>#1</value>
                                </enumeratedValue>
                            </enumeratedValues>
                        </field>
                        <field>
                            <name>PSARB30</name>
                            <description>Serial Communication Interface 1 Security Attribution</description>
                            <lsb>30</lsb>
                            <msb>30</msb>
                            <access>read-write</access>
                            <enumeratedValues>
                                <enumeratedValue>
                                    <name>0</name>
                                    <description>Secure</description>
                                    <value>#0</value>
                                </enumeratedValue>
                                <enumeratedValue>
                                    <name>1</name>
                                    <description>Non-secure</description>
                                    <value>#1</value>
                                </enumeratedValue>
                            </enumeratedValues>
                        </field>
                        <field>
                            <name>PSARB31</name>
                            <description>Serial Communication Interface 0 Security Attribution</description>
                            <lsb>31</lsb>
                            <msb>31</msb>
                            <access>read-write</access>
                            <enumeratedValues>
                                <enumeratedValue>
                                    <name>0</name>
                                    <description>Secure</description>
                                    <value>#0</value>
                                </enumeratedValue>
                                <enumeratedValue>
                                    <name>1</name>
                                    <description>Non-secure</description>
                                    <value>#1</value>
                                </enumeratedValue>
                            </enumeratedValues>
                        </field>
                    </fields>
                </register>
                <register>
                    <name>PSARC</name>
                    <description>Peripheral Security Attribution Register C</description>
                    <addressOffset>0x08</addressOffset>
                    <size>32</size>
                    <access>read-write</access>
                    <resetValue>0x00000000</resetValue>
                    <resetMask>0xffffffff</resetMask>
                    <fields>
                        <field>
                            <name>PSARC0</name>
                            <description>Clock Frequency Accuracy Measurement Circuit Security Attribution register specifies the security attribution for each module and the corresponding bit in Module Stop Control Register.</description>
                            <lsb>0</lsb>
                            <msb>0</msb>
                            <access>read-write</access>
                            <enumeratedValues>
                                <enumeratedValue>
                                    <name>0</name>
                                    <description>Secure</description>
                                    <value>#0</value>
                                </enumeratedValue>
                                <enumeratedValue>
                                    <name>1</name>
                                    <description>Non-secure</description>
                                    <value>#1</value>
                                </enumeratedValue>
                            </enumeratedValues>
                        </field>
                        <field>
                            <name>PSARC1</name>
                            <description>Cyclic Redundancy Check Calculator Security Attribution</description>
                            <lsb>1</lsb>
                            <msb>1</msb>
                            <access>read-write</access>
                            <enumeratedValues>
                                <enumeratedValue>
                                    <name>0</name>
                                    <description>Secure</description>
                                    <value>#0</value>
                                </enumeratedValue>
                                <enumeratedValue>
                                    <name>1</name>
                                    <description>Non-secure</description>
                                    <value>#1</value>
                                </enumeratedValue>
                            </enumeratedValues>
                        </field>
                        <field>
                            <name>PSARC7</name>
                            <description>Serial Sound Interface Enhanced (channel 1) Security Attribution</description>
                            <lsb>7</lsb>
                            <msb>7</msb>
                            <access>read-write</access>
                            <enumeratedValues>
                                <enumeratedValue>
                                    <name>0</name>
                                    <description>Secure</description>
                                    <value>#0</value>
                                </enumeratedValue>
                                <enumeratedValue>
                                    <name>1</name>
                                    <description>Non-secure</description>
                                    <value>#1</value>
                                </enumeratedValue>
                            </enumeratedValues>
                        </field>
                        <field>
                            <name>PSARC8</name>
                            <description>Serial Sound Interface Enhanced (channel 0) Security Attribution</description>
                            <lsb>8</lsb>
                            <msb>8</msb>
                            <access>read-write</access>
                            <enumeratedValues>
                                <enumeratedValue>
                                    <name>0</name>
                                    <description>Secure</description>
                                    <value>#0</value>
                                </enumeratedValue>
                                <enumeratedValue>
                                    <name>1</name>
                                    <description>Non-secure</description>
                                    <value>#1</value>
                                </enumeratedValue>
                            </enumeratedValues>
                        </field>
                        <field>
                            <name>PSARC13</name>
                            <description>Data Operation Circuit Security Attribution</description>
                            <lsb>13</lsb>
                            <msb>13</msb>
                            <access>read-write</access>
                            <enumeratedValues>
                                <enumeratedValue>
                                    <name>0</name>
                                    <description>Secure</description>
                                    <value>#0</value>
                                </enumeratedValue>
                                <enumeratedValue>
                                    <name>1</name>
                                    <description>Non-secure</description>
                                    <value>#1</value>
                                </enumeratedValue>
                            </enumeratedValues>
                        </field>
                        <field>
                            <name>PSARC15</name>
                            <description>Graphic (GLCDC, DRW) Security Attribution</description>
                            <lsb>15</lsb>
                            <msb>15</msb>
                            <access>read-write</access>
                            <enumeratedValues>
                                <enumeratedValue>
                                    <name>0</name>
                                    <description>Secure</description>
                                    <value>#0</value>
                                </enumeratedValue>
                                <enumeratedValue>
                                    <name>1</name>
                                    <description>Non-secure</description>
                                    <value>#1</value>
                                </enumeratedValue>
                            </enumeratedValues>
                        </field>
                        <field>
                            <name>PSARC26</name>
                            <description>Controller Area Network with Flexible Data-Rate 1 Security Attribution</description>
                            <lsb>26</lsb>
                            <msb>26</msb>
                            <access>read-write</access>
                            <enumeratedValues>
                                <enumeratedValue>
                                    <name>0</name>
                                    <description>Secure</description>
                                    <value>#0</value>
                                </enumeratedValue>
                                <enumeratedValue>
                                    <name>1</name>
                                    <description>Non-secure</description>
                                    <value>#1</value>
                                </enumeratedValue>
                            </enumeratedValues>
                        </field>
                        <field>
                            <name>PSARC27</name>
                            <description>Controller Area Network with Flexible Data-Rate 0 Security Attribution</description>
                            <lsb>27</lsb>
                            <msb>27</msb>
                            <access>read-write</access>
                            <enumeratedValues>
                                <enumeratedValue>
                                    <name>0</name>
                                    <description>Secure</description>
                                    <value>#0</value>
                                </enumeratedValue>
                                <enumeratedValue>
                                    <name>1</name>
                                    <description>Non-secure</description>
                                    <value>#1</value>
                                </enumeratedValue>
                            </enumeratedValues>
                        </field>
                        <field>
                            <name>PSARC31</name>
                            <description>RSIP-E51A Security Attribution</description>
                            <lsb>31</lsb>
                            <msb>31</msb>
                            <access>read-write</access>
                            <enumeratedValues>
                                <enumeratedValue>
                                    <name>0</name>
                                    <description>Secure</description>
                                    <value>#0</value>
                                </enumeratedValue>
                                <enumeratedValue>
                                    <name>1</name>
                                    <description>Non-secure</description>
                                    <value>#1</value>
                                </enumeratedValue>
                            </enumeratedValues>
                        </field>
                    </fields>
                </register>
                <register>
                    <name>PSARD</name>
                    <description>Peripheral Security Attribution Register D</description>
                    <addressOffset>0x0C</addressOffset>
                    <size>32</size>
                    <access>read-write</access>
                    <resetValue>0x00000000</resetValue>
                    <resetMask>0xffffffff</resetMask>
                    <fields>
                        <field>
                            <name>PSARD4</name>
                            <description>Asynchronous General Purpose Timer 1 Security Attribution</description>
                            <lsb>4</lsb>
                            <msb>4</msb>
                            <access>read-write</access>
                            <enumeratedValues>
                                <enumeratedValue>
                                    <name>0</name>
                                    <description>Secure</description>
                                    <value>#0</value>
                                </enumeratedValue>
                                <enumeratedValue>
                                    <name>1</name>
                                    <description>Non-secure</description>
                                    <value>#1</value>
                                </enumeratedValue>
                            </enumeratedValues>
                        </field>
                        <field>
                            <name>PSARD5</name>
                            <description>Asynchronous General Purpose Timer 0 Security Attribution</description>
                            <lsb>5</lsb>
                            <msb>5</msb>
                            <access>read-write</access>
                            <enumeratedValues>
                                <enumeratedValue>
                                    <name>0</name>
                                    <description>Secure</description>
                                    <value>#0</value>
                                </enumeratedValue>
                                <enumeratedValue>
                                    <name>1</name>
                                    <description>Non-secure</description>
                                    <value>#1</value>
                                </enumeratedValue>
                            </enumeratedValues>
                        </field>
                        <field>
                            <name>PSARD11</name>
                            <description>Port Output Enable for GPT Group 3 Security Attribution</description>
                            <lsb>11</lsb>
                            <msb>11</msb>
                            <access>read-write</access>
                            <enumeratedValues>
                                <enumeratedValue>
                                    <name>0</name>
                                    <description>Secure</description>
                                    <value>#0</value>
                                </enumeratedValue>
                                <enumeratedValue>
                                    <name>1</name>
                                    <description>Non-secure</description>
                                    <value>#1</value>
                                </enumeratedValue>
                            </enumeratedValues>
                        </field>
                        <field>
                            <name>PSARD12</name>
                            <description>Port Output Enable for GPT Group 2 Security Attribution</description>
                            <lsb>12</lsb>
                            <msb>12</msb>
                            <access>read-write</access>
                            <enumeratedValues>
                                <enumeratedValue>
                                    <name>0</name>
                                    <description>Secure</description>
                                    <value>#0</value>
                                </enumeratedValue>
                                <enumeratedValue>
                                    <name>1</name>
                                    <description>Non-secure</description>
                                    <value>#1</value>
                                </enumeratedValue>
                            </enumeratedValues>
                        </field>
                        <field>
                            <name>PSARD13</name>
                            <description>Port Output Enable for GPT Group 1 Security Attribution</description>
                            <lsb>13</lsb>
                            <msb>13</msb>
                            <access>read-write</access>
                            <enumeratedValues>
                                <enumeratedValue>
                                    <name>0</name>
                                    <description>Secure</description>
                                    <value>#0</value>
                                </enumeratedValue>
                                <enumeratedValue>
                                    <name>1</name>
                                    <description>Non-secure</description>
                                    <value>#1</value>
                                </enumeratedValue>
                            </enumeratedValues>
                        </field>
                        <field>
                            <name>PSARD14</name>
                            <description>Port Output Enable for GPT Group 0 Security Attribution</description>
                            <lsb>14</lsb>
                            <msb>14</msb>
                            <access>read-write</access>
                            <enumeratedValues>
                                <enumeratedValue>
                                    <name>0</name>
                                    <description>Secure</description>
                                    <value>#0</value>
                                </enumeratedValue>
                                <enumeratedValue>
                                    <name>1</name>
                                    <description>Non-secure</description>
                                    <value>#1</value>
                                </enumeratedValue>
                            </enumeratedValues>
                        </field>
                        <field>
                            <name>PSARD15</name>
                            <description>12-Bit A/D 1 Converter Security Attribution</description>
                            <lsb>15</lsb>
                            <msb>15</msb>
                            <access>read-write</access>
                            <enumeratedValues>
                                <enumeratedValue>
                                    <name>0</name>
                                    <description>Secure</description>
                                    <value>#0</value>
                                </enumeratedValue>
                                <enumeratedValue>
                                    <name>1</name>
                                    <description>Non-secure</description>
                                    <value>#1</value>
                                </enumeratedValue>
                            </enumeratedValues>
                        </field>
                        <field>
                            <name>PSARD16</name>
                            <description>12-Bit A/D 0 Converter Security Attribution</description>
                            <lsb>16</lsb>
                            <msb>16</msb>
                            <access>read-write</access>
                            <enumeratedValues>
                                <enumeratedValue>
                                    <name>0</name>
                                    <description>Secure</description>
                                    <value>#0</value>
                                </enumeratedValue>
                                <enumeratedValue>
                                    <name>1</name>
                                    <description>Non-secure</description>
                                    <value>#1</value>
                                </enumeratedValue>
                            </enumeratedValues>
                        </field>
                        <field>
                            <name>PSARD20</name>
                            <description>12-Bit D/A Converter Security Attribution</description>
                            <lsb>20</lsb>
                            <msb>20</msb>
                            <access>read-write</access>
                            <enumeratedValues>
                                <enumeratedValue>
                                    <name>0</name>
                                    <description>Secure</description>
                                    <value>#0</value>
                                </enumeratedValue>
                                <enumeratedValue>
                                    <name>1</name>
                                    <description>Non-secure</description>
                                    <value>#1</value>
                                </enumeratedValue>
                            </enumeratedValues>
                        </field>
                        <field>
                            <name>PSARD22</name>
                            <description>Temperature Sensor Security Attribution</description>
                            <lsb>22</lsb>
                            <msb>22</msb>
                            <access>read-write</access>
                            <enumeratedValues>
                                <enumeratedValue>
                                    <name>0</name>
                                    <description>Secure</description>
                                    <value>#0</value>
                                </enumeratedValue>
                                <enumeratedValue>
                                    <name>1</name>
                                    <description>Non-secure</description>
                                    <value>#1</value>
                                </enumeratedValue>
                            </enumeratedValues>
                        </field>
                        <field>
                            <name>PSARD27</name>
                            <description>High Speed Analog Comparator 1 Security Attribution</description>
                            <lsb>27</lsb>
                            <msb>27</msb>
                            <access>read-write</access>
                            <enumeratedValues>
                                <enumeratedValue>
                                    <name>0</name>
                                    <description>Secure</description>
                                    <value>#0</value>
                                </enumeratedValue>
                                <enumeratedValue>
                                    <name>1</name>
                                    <description>Non-secure</description>
                                    <value>#1</value>
                                </enumeratedValue>
                            </enumeratedValues>
                        </field>
                        <field>
                            <name>PSARD28</name>
                            <description>High Speed Analog Comparator 0 Security Attribution</description>
                            <lsb>28</lsb>
                            <msb>28</msb>
                            <access>read-write</access>
                            <enumeratedValues>
                                <enumeratedValue>
                                    <name>0</name>
                                    <description>Secure</description>
                                    <value>#0</value>
                                </enumeratedValue>
                                <enumeratedValue>
                                    <name>1</name>
                                    <description>Non-secure</description>
                                    <value>#1</value>
                                </enumeratedValue>
                            </enumeratedValues>
                        </field>
                    </fields>
                </register>
                <register>
                    <name>PSARE</name>
                    <description>Peripheral Security Attribution Register E</description>
                    <addressOffset>0x10</addressOffset>
                    <size>32</size>
                    <access>read-write</access>
                    <resetValue>0x00000000</resetValue>
                    <resetMask>0xffffffff</resetMask>
                    <fields>
                        <field>
                            <name>PSARE1</name>
                            <description>WDT Security Attribution</description>
                            <lsb>1</lsb>
                            <msb>1</msb>
                            <access>read-write</access>
                            <enumeratedValues>
                                <enumeratedValue>
                                    <name>0</name>
                                    <description>Secure</description>
                                    <value>#0</value>
                                </enumeratedValue>
                                <enumeratedValue>
                                    <name>1</name>
                                    <description>Non-secure</description>
                                    <value>#1</value>
                                </enumeratedValue>
                            </enumeratedValues>
                        </field>
                        <field>
                            <name>PSARE2</name>
                            <description>IWDT Security Attribution</description>
                            <lsb>2</lsb>
                            <msb>2</msb>
                            <access>read-write</access>
                            <enumeratedValues>
                                <enumeratedValue>
                                    <name>0</name>
                                    <description>Secure</description>
                                    <value>#0</value>
                                </enumeratedValue>
                                <enumeratedValue>
                                    <name>1</name>
                                    <description>Non-secure</description>
                                    <value>#1</value>
                                </enumeratedValue>
                            </enumeratedValues>
                        </field>
                        <field>
                            <name>PSARE3</name>
                            <description>Real Time Clock Security Attribution</description>
                            <lsb>3</lsb>
                            <msb>3</msb>
                            <access>read-write</access>
                            <enumeratedValues>
                                <enumeratedValue>
                                    <name>0</name>
                                    <description>Secure</description>
                                    <value>#0</value>
                                </enumeratedValue>
                                <enumeratedValue>
                                    <name>1</name>
                                    <description>Non-secure</description>
                                    <value>#1</value>
                                </enumeratedValue>
                            </enumeratedValues>
                        </field>
                        <field>
                            <name>PSARE8</name>
                            <description>ULPT1 Security Attribution</description>
                            <lsb>8</lsb>
                            <msb>8</msb>
                            <access>read-write</access>
                            <enumeratedValues>
                                <enumeratedValue>
                                    <name>0</name>
                                    <description>Secure</description>
                                    <value>#0</value>
                                </enumeratedValue>
                                <enumeratedValue>
                                    <name>1</name>
                                    <description>Non-secure</description>
                                    <value>#1</value>
                                </enumeratedValue>
                            </enumeratedValues>
                        </field>
                        <field>
                            <name>PSARE9</name>
                            <description>ULPT0 Security Attribution</description>
                            <lsb>9</lsb>
                            <msb>9</msb>
                            <access>read-write</access>
                            <enumeratedValues>
                                <enumeratedValue>
                                    <name>0</name>
                                    <description>Secure</description>
                                    <value>#0</value>
                                </enumeratedValue>
                                <enumeratedValue>
                                    <name>1</name>
                                    <description>Non-secure</description>
                                    <value>#1</value>
                                </enumeratedValue>
                            </enumeratedValues>
                        </field>
                        <field>
                            <name>PSARE18</name>
                            <description>General PWM Timer Channel 13 Security Attribution</description>
                            <lsb>18</lsb>
                            <msb>18</msb>
                            <access>read-write</access>
                            <enumeratedValues>
                                <enumeratedValue>
                                    <name>0</name>
                                    <description>Secure</description>
                                    <value>#0</value>
                                </enumeratedValue>
                                <enumeratedValue>
                                    <name>1</name>
                                    <description>Non-secure</description>
                                    <value>#1</value>
                                </enumeratedValue>
                            </enumeratedValues>
                        </field>
                        <field>
                            <name>PSARE19</name>
                            <description>General PWM Timer Channel 12 Security Attribution</description>
                            <lsb>19</lsb>
                            <msb>19</msb>
                            <access>read-write</access>
                            <enumeratedValues>
                                <enumeratedValue>
                                    <name>0</name>
                                    <description>Secure</description>
                                    <value>#0</value>
                                </enumeratedValue>
                                <enumeratedValue>
                                    <name>1</name>
                                    <description>Non-secure</description>
                                    <value>#1</value>
                                </enumeratedValue>
                            </enumeratedValues>
                        </field>
                        <field>
                            <name>PSARE20</name>
                            <description>General PWM Timer Channel 11 Security Attribution</description>
                            <lsb>20</lsb>
                            <msb>20</msb>
                            <access>read-write</access>
                            <enumeratedValues>
                                <enumeratedValue>
                                    <name>0</name>
                                    <description>Secure</description>
                                    <value>#0</value>
                                </enumeratedValue>
                                <enumeratedValue>
                                    <name>1</name>
                                    <description>Non-secure</description>
                                    <value>#1</value>
                                </enumeratedValue>
                            </enumeratedValues>
                        </field>
                        <field>
                            <name>PSARE21</name>
                            <description>General PWM Timer Channel 10 Security Attribution</description>
                            <lsb>21</lsb>
                            <msb>21</msb>
                            <access>read-write</access>
                            <enumeratedValues>
                                <enumeratedValue>
                                    <name>0</name>
                                    <description>Secure</description>
                                    <value>#0</value>
                                </enumeratedValue>
                                <enumeratedValue>
                                    <name>1</name>
                                    <description>Non-secure</description>
                                    <value>#1</value>
                                </enumeratedValue>
                            </enumeratedValues>
                        </field>
                        <field>
                            <name>PSARE26</name>
                            <description>General PWM Timer Channel 5 Security Attribution</description>
                            <lsb>26</lsb>
                            <msb>26</msb>
                            <access>read-write</access>
                            <enumeratedValues>
                                <enumeratedValue>
                                    <name>0</name>
                                    <description>Secure</description>
                                    <value>#0</value>
                                </enumeratedValue>
                                <enumeratedValue>
                                    <name>1</name>
                                    <description>Non-secure</description>
                                    <value>#1</value>
                                </enumeratedValue>
                            </enumeratedValues>
                        </field>
                        <field>
                            <name>PSARE27</name>
                            <description>General PWM Timer Channel 4 Security Attribution</description>
                            <lsb>27</lsb>
                            <msb>27</msb>
                            <access>read-write</access>
                            <enumeratedValues>
                                <enumeratedValue>
                                    <name>0</name>
                                    <description>Secure</description>
                                    <value>#0</value>
                                </enumeratedValue>
                                <enumeratedValue>
                                    <name>1</name>
                                    <description>Non-secure</description>
                                    <value>#1</value>
                                </enumeratedValue>
                            </enumeratedValues>
                        </field>
                        <field>
                            <name>PSARE28</name>
                            <description>General PWM Timer Channel 3 Security Attribution</description>
                            <lsb>28</lsb>
                            <msb>28</msb>
                            <access>read-write</access>
                            <enumeratedValues>
                                <enumeratedValue>
                                    <name>0</name>
                                    <description>Secure</description>
                                    <value>#0</value>
                                </enumeratedValue>
                                <enumeratedValue>
                                    <name>1</name>
                                    <description>Non-secure</description>
                                    <value>#1</value>
                                </enumeratedValue>
                            </enumeratedValues>
                        </field>
                        <field>
                            <name>PSARE29</name>
                            <description>General PWM Timer Channel 2 Security Attribution</description>
                            <lsb>29</lsb>
                            <msb>29</msb>
                            <access>read-write</access>
                            <enumeratedValues>
                                <enumeratedValue>
                                    <name>0</name>
                                    <description>Secure</description>
                                    <value>#0</value>
                                </enumeratedValue>
                                <enumeratedValue>
                                    <name>1</name>
                                    <description>Non-secure</description>
                                    <value>#1</value>
                                </enumeratedValue>
                            </enumeratedValues>
                        </field>
                        <field>
                            <name>PSARE30</name>
                            <description>General PWM Timer Channel 1 Security Attribution</description>
                            <lsb>30</lsb>
                            <msb>30</msb>
                            <access>read-write</access>
                            <enumeratedValues>
                                <enumeratedValue>
                                    <name>0</name>
                                    <description>Secure</description>
                                    <value>#0</value>
                                </enumeratedValue>
                                <enumeratedValue>
                                    <name>1</name>
                                    <description>Non-secure</description>
                                    <value>#1</value>
                                </enumeratedValue>
                            </enumeratedValues>
                        </field>
                        <field>
                            <name>PSARE31</name>
                            <description>General PWM Timer Channel 0 Security Attribution</description>
                            <lsb>31</lsb>
                            <msb>31</msb>
                            <access>read-write</access>
                            <enumeratedValues>
                                <enumeratedValue>
                                    <name>0</name>
                                    <description>Secure</description>
                                    <value>#0</value>
                                </enumeratedValue>
                                <enumeratedValue>
                                    <name>1</name>
                                    <description>Non-secure</description>
                                    <value>#1</value>
                                </enumeratedValue>
                            </enumeratedValues>
                        </field>
                    </fields>
                </register>
                <register>
                    <name>MSSAR</name>
                    <description>Module Stop Security Attribution Register</description>
                    <addressOffset>0x14</addressOffset>
                    <size>32</size>
                    <access>read-write</access>
                    <resetValue>0x00000000</resetValue>
                    <resetMask>0xffffffff</resetMask>
                    <fields>
                        <field>
                            <name>MSSAR0</name>
                            <description>SRAM0 Clock Stop Security Attribution</description>
                            <lsb>0</lsb>
                            <msb>0</msb>
                            <access>read-write</access>
                            <enumeratedValues>
                                <enumeratedValue>
                                    <name>0</name>
                                    <description>Secure</description>
                                    <value>#0</value>
                                </enumeratedValue>
                                <enumeratedValue>
                                    <name>1</name>
                                    <description>Non-secure</description>
                                    <value>#1</value>
                                </enumeratedValue>
                            </enumeratedValues>
                        </field>
                        <field>
                            <name>MSSAR1</name>
                            <description>SRAM1 Clock Stop Security Attribution</description>
                            <lsb>1</lsb>
                            <msb>1</msb>
                            <access>read-write</access>
                            <enumeratedValues>
                                <enumeratedValue>
                                    <name>0</name>
                                    <description>Secure</description>
                                    <value>#0</value>
                                </enumeratedValue>
                                <enumeratedValue>
                                    <name>1</name>
                                    <description>Non-secure</description>
                                    <value>#1</value>
                                </enumeratedValue>
                            </enumeratedValues>
                        </field>
                        <field>
                            <name>MSSAR15</name>
                            <description>Standby RAM Clock Stop Security Attribution</description>
                            <lsb>15</lsb>
                            <msb>15</msb>
                            <access>read-write</access>
                            <enumeratedValues>
                                <enumeratedValue>
                                    <name>0</name>
                                    <description>Secure</description>
                                    <value>#0</value>
                                </enumeratedValue>
                                <enumeratedValue>
                                    <name>1</name>
                                    <description>Non-secure</description>
                                    <value>#1</value>
                                </enumeratedValue>
                            </enumeratedValues>
                        </field>
                        <field>
                            <name>MSSAR22</name>
                            <description>DMAC/DTC Clock Stop Security Attribution</description>
                            <lsb>22</lsb>
                            <msb>22</msb>
                            <access>read-write</access>
                            <enumeratedValues>
                                <enumeratedValue>
                                    <name>0</name>
                                    <description>Secure</description>
                                    <value>#0</value>
                                </enumeratedValue>
                                <enumeratedValue>
                                    <name>1</name>
                                    <description>Non-secure</description>
                                    <value>#1</value>
                                </enumeratedValue>
                            </enumeratedValues>
                        </field>
                        <field>
                            <name>MSSAR31</name>
                            <description>ELC Clock Stop Security Attribution</description>
                            <lsb>31</lsb>
                            <msb>31</msb>
                            <access>read-write</access>
                            <enumeratedValues>
                                <enumeratedValue>
                                    <name>0</name>
                                    <description>Secure</description>
                                    <value>#0</value>
                                </enumeratedValue>
                                <enumeratedValue>
                                    <name>1</name>
                                    <description>Non-secure</description>
                                    <value>#1</value>
                                </enumeratedValue>
                            </enumeratedValues>
                        </field>
                    </fields>
                </register>
                <register>
                    <name>PPARB</name>
                    <description>Peripheral Privilege Attribution Register B</description>
                    <addressOffset>0x1C</addressOffset>
                    <size>32</size>
                    <access>read-write</access>
                    <resetValue>0xffffffff</resetValue>
                    <resetMask>0xffffffff</resetMask>
                    <fields>
                        <field>
                            <name>PPARB8</name>
                            <description>I2C Bus Interface 1 Privilege Attribution</description>
                            <lsb>8</lsb>
                            <msb>8</msb>
                            <access>read-write</access>
                            <enumeratedValues>
                                <enumeratedValue>
                                    <name>0</name>
                                    <description>Privileged</description>
                                    <value>#0</value>
                                </enumeratedValue>
                                <enumeratedValue>
                                    <name>1</name>
                                    <description>UnPrivileged</description>
                                    <value>#1</value>
                                </enumeratedValue>
                            </enumeratedValues>
                        </field>
                        <field>
                            <name>PPARB9</name>
                            <description>I2C Bus Interface 0 Privilege Attribution</description>
                            <lsb>9</lsb>
                            <msb>9</msb>
                            <access>read-write</access>
                            <enumeratedValues>
                                <enumeratedValue>
                                    <name>0</name>
                                    <description>Privileged</description>
                                    <value>#0</value>
                                </enumeratedValue>
                                <enumeratedValue>
                                    <name>1</name>
                                    <description>UnPrivileged</description>
                                    <value>#1</value>
                                </enumeratedValue>
                            </enumeratedValues>
                        </field>
                        <field>
                            <name>PPARB11</name>
                            <description>Universal Serial Bus 2.0 FS Interface 0 Privilege Attribution</description>
                            <lsb>11</lsb>
                            <msb>11</msb>
                            <access>read-write</access>
                            <enumeratedValues>
                                <enumeratedValue>
                                    <name>0</name>
                                    <description>Privileged</description>
                                    <value>#0</value>
                                </enumeratedValue>
                                <enumeratedValue>
                                    <name>1</name>
                                    <description>UnPrivileged</description>
                                    <value>#1</value>
                                </enumeratedValue>
                            </enumeratedValues>
                        </field>
                        <field>
                            <name>PPARB16</name>
                            <description>Octa Memory Controller Privilege Attribution</description>
                            <lsb>16</lsb>
                            <msb>16</msb>
                            <access>read-write</access>
                            <enumeratedValues>
                                <enumeratedValue>
                                    <name>0</name>
                                    <description>Privileged</description>
                                    <value>#0</value>
                                </enumeratedValue>
                                <enumeratedValue>
                                    <name>1</name>
                                    <description>UnPrivileged</description>
                                    <value>#1</value>
                                </enumeratedValue>
                            </enumeratedValues>
                        </field>
                        <field>
                            <name>PPARB18</name>
                            <description>Serial Peripheral Interface 1 Privilege Attribution</description>
                            <lsb>18</lsb>
                            <msb>18</msb>
                            <access>read-write</access>
                            <enumeratedValues>
                                <enumeratedValue>
                                    <name>0</name>
                                    <description>Privileged</description>
                                    <value>#0</value>
                                </enumeratedValue>
                                <enumeratedValue>
                                    <name>1</name>
                                    <description>UnPrivileged</description>
                                    <value>#1</value>
                                </enumeratedValue>
                            </enumeratedValues>
                        </field>
                        <field>
                            <name>PPARB19</name>
                            <description>Serial Peripheral Interface 0 Privilege Attribution</description>
                            <lsb>19</lsb>
                            <msb>19</msb>
                            <access>read-write</access>
                            <enumeratedValues>
                                <enumeratedValue>
                                    <name>0</name>
                                    <description>Privileged</description>
                                    <value>#0</value>
                                </enumeratedValue>
                                <enumeratedValue>
                                    <name>1</name>
                                    <description>UnPrivileged</description>
                                    <value>#1</value>
                                </enumeratedValue>
                            </enumeratedValues>
                        </field>
                        <field>
                            <name>PPARB22</name>
                            <description>Serial Communication Interface 9 Privilege Attribution</description>
                            <lsb>22</lsb>
                            <msb>22</msb>
                            <access>read-write</access>
                            <enumeratedValues>
                                <enumeratedValue>
                                    <name>0</name>
                                    <description>Privileged</description>
                                    <value>#0</value>
                                </enumeratedValue>
                                <enumeratedValue>
                                    <name>1</name>
                                    <description>UnPrivileged</description>
                                    <value>#1</value>
                                </enumeratedValue>
                            </enumeratedValues>
                        </field>
                        <field>
                            <name>PPARB27</name>
                            <description>Serial Communication Interface 4 Privilege Attribution</description>
                            <lsb>27</lsb>
                            <msb>27</msb>
                            <access>read-write</access>
                            <enumeratedValues>
                                <enumeratedValue>
                                    <name>0</name>
                                    <description>Privileged</description>
                                    <value>#0</value>
                                </enumeratedValue>
                                <enumeratedValue>
                                    <name>1</name>
                                    <description>UnPrivileged</description>
                                    <value>#1</value>
                                </enumeratedValue>
                            </enumeratedValues>
                        </field>
                        <field>
                            <name>PPARB28</name>
                            <description>Serial Communication Interface 3 Privilege Attribution</description>
                            <lsb>28</lsb>
                            <msb>28</msb>
                            <access>read-write</access>
                            <enumeratedValues>
                                <enumeratedValue>
                                    <name>0</name>
                                    <description>Privileged</description>
                                    <value>#0</value>
                                </enumeratedValue>
                                <enumeratedValue>
                                    <name>1</name>
                                    <description>UnPrivileged</description>
                                    <value>#1</value>
                                </enumeratedValue>
                            </enumeratedValues>
                        </field>
                        <field>
                            <name>PPARB29</name>
                            <description>Serial Communication Interface 2 Privilege Attribution</description>
                            <lsb>29</lsb>
                            <msb>29</msb>
                            <access>read-write</access>
                            <enumeratedValues>
                                <enumeratedValue>
                                    <name>0</name>
                                    <description>Privileged</description>
                                    <value>#0</value>
                                </enumeratedValue>
                                <enumeratedValue>
                                    <name>1</name>
                                    <description>UnPrivileged</description>
                                    <value>#1</value>
                                </enumeratedValue>
                            </enumeratedValues>
                        </field>
                        <field>
                            <name>PPARB30</name>
                            <description>Serial Communication Interface 1 Privilege Attribution</description>
                            <lsb>30</lsb>
                            <msb>30</msb>
                            <access>read-write</access>
                            <enumeratedValues>
                                <enumeratedValue>
                                    <name>0</name>
                                    <description>Privileged</description>
                                    <value>#0</value>
                                </enumeratedValue>
                                <enumeratedValue>
                                    <name>1</name>
                                    <description>UnPrivileged</description>
                                    <value>#1</value>
                                </enumeratedValue>
                            </enumeratedValues>
                        </field>
                        <field>
                            <name>PPARB31</name>
                            <description>Serial Communication Interface 0 Privilege Attribution</description>
                            <lsb>31</lsb>
                            <msb>31</msb>
                            <access>read-write</access>
                            <enumeratedValues>
                                <enumeratedValue>
                                    <name>0</name>
                                    <description>Privileged</description>
                                    <value>#0</value>
                                </enumeratedValue>
                                <enumeratedValue>
                                    <name>1</name>
                                    <description>UnPrivileged</description>
                                    <value>#1</value>
                                </enumeratedValue>
                            </enumeratedValues>
                        </field>
                    </fields>
                </register>
                <register>
                    <name>PPARC</name>
                    <description>Peripheral Privilege Attribution Register C</description>
                    <addressOffset>0x20</addressOffset>
                    <size>32</size>
                    <access>read-write</access>
                    <resetValue>0xffffffff</resetValue>
                    <resetMask>0xffffffff</resetMask>
                    <fields>
                        <field>
                            <name>PPARC0</name>
                            <description>Clock Frequency Accuracy Measurement Circuit Privilege Attribution</description>
                            <lsb>0</lsb>
                            <msb>0</msb>
                            <access>read-write</access>
                            <enumeratedValues>
                                <enumeratedValue>
                                    <name>0</name>
                                    <description>Privileged</description>
                                    <value>#0</value>
                                </enumeratedValue>
                                <enumeratedValue>
                                    <name>1</name>
                                    <description>UnPrivileged</description>
                                    <value>#1</value>
                                </enumeratedValue>
                            </enumeratedValues>
                        </field>
                        <field>
                            <name>PPARC1</name>
                            <description>Cyclic Redundancy Check Calculator Privilege Attribution</description>
                            <lsb>1</lsb>
                            <msb>1</msb>
                            <access>read-write</access>
                            <enumeratedValues>
                                <enumeratedValue>
                                    <name>0</name>
                                    <description>Privileged</description>
                                    <value>#0</value>
                                </enumeratedValue>
                                <enumeratedValue>
                                    <name>1</name>
                                    <description>UnPrivileged</description>
                                    <value>#1</value>
                                </enumeratedValue>
                            </enumeratedValues>
                        </field>
                        <field>
                            <name>PPARC7</name>
                            <description>Serial Sound Interface Enhanced (Channel 1) Privilege Attribution</description>
                            <lsb>7</lsb>
                            <msb>7</msb>
                            <access>read-write</access>
                            <enumeratedValues>
                                <enumeratedValue>
                                    <name>0</name>
                                    <description>Privileged</description>
                                    <value>#0</value>
                                </enumeratedValue>
                                <enumeratedValue>
                                    <name>1</name>
                                    <description>UnPrivileged</description>
                                    <value>#1</value>
                                </enumeratedValue>
                            </enumeratedValues>
                        </field>
                        <field>
                            <name>PPARC8</name>
                            <description>Serial Sound Interface Enhanced (Channel 0) Privilege Attribution</description>
                            <lsb>8</lsb>
                            <msb>8</msb>
                            <access>read-write</access>
                            <enumeratedValues>
                                <enumeratedValue>
                                    <name>0</name>
                                    <description>Privileged</description>
                                    <value>#0</value>
                                </enumeratedValue>
                                <enumeratedValue>
                                    <name>1</name>
                                    <description>UnPrivileged</description>
                                    <value>#1</value>
                                </enumeratedValue>
                            </enumeratedValues>
                        </field>
                        <field>
                            <name>PPARC13</name>
                            <description>Data Operation Circuit Privilege Attribution</description>
                            <lsb>13</lsb>
                            <msb>13</msb>
                            <access>read-write</access>
                            <enumeratedValues>
                                <enumeratedValue>
                                    <name>0</name>
                                    <description>Privileged</description>
                                    <value>#0</value>
                                </enumeratedValue>
                                <enumeratedValue>
                                    <name>1</name>
                                    <description>UnPrivileged</description>
                                    <value>#1</value>
                                </enumeratedValue>
                            </enumeratedValues>
                        </field>
                        <field>
                            <name>PPARC15</name>
                            <description>Graphic (GLCDC, DRW) Privilege Attribution</description>
                            <lsb>15</lsb>
                            <msb>15</msb>
                            <access>read-write</access>
                            <enumeratedValues>
                                <enumeratedValue>
                                    <name>0</name>
                                    <description>Privileged</description>
                                    <value>#0</value>
                                </enumeratedValue>
                                <enumeratedValue>
                                    <name>1</name>
                                    <description>UnPrivileged</description>
                                    <value>#1</value>
                                </enumeratedValue>
                            </enumeratedValues>
                        </field>
                        <field>
                            <name>PPARC26</name>
                            <description>Controller Area Network with Flexible Data-Rate 1 Privilege Attribution</description>
                            <lsb>26</lsb>
                            <msb>26</msb>
                            <access>read-write</access>
                            <enumeratedValues>
                                <enumeratedValue>
                                    <name>0</name>
                                    <description>Privileged</description>
                                    <value>#0</value>
                                </enumeratedValue>
                                <enumeratedValue>
                                    <name>1</name>
                                    <description>UnPrivileged</description>
                                    <value>#1</value>
                                </enumeratedValue>
                            </enumeratedValues>
                        </field>
                        <field>
                            <name>PPARC27</name>
                            <description>Controller Area Network with Flexible Data-Rate 0 Privilege Attribution</description>
                            <lsb>27</lsb>
                            <msb>27</msb>
                            <access>read-write</access>
                            <enumeratedValues>
                                <enumeratedValue>
                                    <name>0</name>
                                    <description>Privileged</description>
                                    <value>#0</value>
                                </enumeratedValue>
                                <enumeratedValue>
                                    <name>1</name>
                                    <description>UnPrivileged</description>
                                    <value>#1</value>
                                </enumeratedValue>
                            </enumeratedValues>
                        </field>
                        <field>
                            <name>PPARC31</name>
                            <description>RSIP-E51A Privilege Attribution</description>
                            <lsb>31</lsb>
                            <msb>31</msb>
                            <access>read-write</access>
                            <enumeratedValues>
                                <enumeratedValue>
                                    <name>0</name>
                                    <description>Privileged</description>
                                    <value>#0</value>
                                </enumeratedValue>
                                <enumeratedValue>
                                    <name>1</name>
                                    <description>UnPrivileged</description>
                                    <value>#1</value>
                                </enumeratedValue>
                            </enumeratedValues>
                        </field>
                    </fields>
                </register>
                <register>
                    <name>PPARD</name>
                    <description>Peripheral Privilege Attribution Register D</description>
                    <addressOffset>0x24</addressOffset>
                    <size>32</size>
                    <access>read-write</access>
                    <resetValue>0xffffffff</resetValue>
                    <resetMask>0xffffffff</resetMask>
                    <fields>
                        <field>
                            <name>PPARD4</name>
                            <description>Asynchronous General Purpose Timer 1 Privilege Attribution</description>
                            <lsb>4</lsb>
                            <msb>4</msb>
                            <access>read-write</access>
                            <enumeratedValues>
                                <enumeratedValue>
                                    <name>0</name>
                                    <description>Privileged</description>
                                    <value>#0</value>
                                </enumeratedValue>
                                <enumeratedValue>
                                    <name>1</name>
                                    <description>UnPrivileged</description>
                                    <value>#1</value>
                                </enumeratedValue>
                            </enumeratedValues>
                        </field>
                        <field>
                            <name>PPARD5</name>
                            <description>Asynchronous General Purpose Timer 0 Privilege Attribution</description>
                            <lsb>5</lsb>
                            <msb>5</msb>
                            <access>read-write</access>
                            <enumeratedValues>
                                <enumeratedValue>
                                    <name>0</name>
                                    <description>Privileged</description>
                                    <value>#0</value>
                                </enumeratedValue>
                                <enumeratedValue>
                                    <name>1</name>
                                    <description>UnPrivileged</description>
                                    <value>#1</value>
                                </enumeratedValue>
                            </enumeratedValues>
                        </field>
                        <field>
                            <name>PPARD11</name>
                            <description>Port Output Enable for GPT Group 3 Privilege Attribution</description>
                            <lsb>11</lsb>
                            <msb>11</msb>
                            <access>read-write</access>
                            <enumeratedValues>
                                <enumeratedValue>
                                    <name>0</name>
                                    <description>Privileged</description>
                                    <value>#0</value>
                                </enumeratedValue>
                                <enumeratedValue>
                                    <name>1</name>
                                    <description>UnPrivileged</description>
                                    <value>#1</value>
                                </enumeratedValue>
                            </enumeratedValues>
                        </field>
                        <field>
                            <name>PPARD12</name>
                            <description>Port Output Enable for GPT Group 2 Privilege Attribution</description>
                            <lsb>12</lsb>
                            <msb>12</msb>
                            <access>read-write</access>
                            <enumeratedValues>
                                <enumeratedValue>
                                    <name>0</name>
                                    <description>Privileged</description>
                                    <value>#0</value>
                                </enumeratedValue>
                                <enumeratedValue>
                                    <name>1</name>
                                    <description>UnPrivileged</description>
                                    <value>#1</value>
                                </enumeratedValue>
                            </enumeratedValues>
                        </field>
                        <field>
                            <name>PPARD13</name>
                            <description>Port Output Enable for GPT Group 1 Privilege Attribution</description>
                            <lsb>13</lsb>
                            <msb>13</msb>
                            <access>read-write</access>
                            <enumeratedValues>
                                <enumeratedValue>
                                    <name>0</name>
                                    <description>Privileged</description>
                                    <value>#0</value>
                                </enumeratedValue>
                                <enumeratedValue>
                                    <name>1</name>
                                    <description>UnPrivileged</description>
                                    <value>#1</value>
                                </enumeratedValue>
                            </enumeratedValues>
                        </field>
                        <field>
                            <name>PPARD14</name>
                            <description>Port Output Enable for GPT Group 0 Privilege Attribution</description>
                            <lsb>14</lsb>
                            <msb>14</msb>
                            <access>read-write</access>
                            <enumeratedValues>
                                <enumeratedValue>
                                    <name>0</name>
                                    <description>Privileged</description>
                                    <value>#0</value>
                                </enumeratedValue>
                                <enumeratedValue>
                                    <name>1</name>
                                    <description>UnPrivileged</description>
                                    <value>#1</value>
                                </enumeratedValue>
                            </enumeratedValues>
                        </field>
                        <field>
                            <name>PPARD15</name>
                            <description>12-Bit A/D 1 Converter Privilege Attribution</description>
                            <lsb>15</lsb>
                            <msb>15</msb>
                            <access>read-write</access>
                            <enumeratedValues>
                                <enumeratedValue>
                                    <name>0</name>
                                    <description>Privileged</description>
                                    <value>#0</value>
                                </enumeratedValue>
                                <enumeratedValue>
                                    <name>1</name>
                                    <description>UnPrivileged</description>
                                    <value>#1</value>
                                </enumeratedValue>
                            </enumeratedValues>
                        </field>
                        <field>
                            <name>PPARD16</name>
                            <description>12-Bit A/D 0 Converter Privilege Attribution</description>
                            <lsb>16</lsb>
                            <msb>16</msb>
                            <access>read-write</access>
                            <enumeratedValues>
                                <enumeratedValue>
                                    <name>0</name>
                                    <description>Privileged</description>
                                    <value>#0</value>
                                </enumeratedValue>
                                <enumeratedValue>
                                    <name>1</name>
                                    <description>UnPrivileged</description>
                                    <value>#1</value>
                                </enumeratedValue>
                            </enumeratedValues>
                        </field>
                        <field>
                            <name>PPARD20</name>
                            <description>12-Bit D/A Converter Privilege Attribution</description>
                            <lsb>20</lsb>
                            <msb>20</msb>
                            <access>read-write</access>
                            <enumeratedValues>
                                <enumeratedValue>
                                    <name>0</name>
                                    <description>Privileged</description>
                                    <value>#0</value>
                                </enumeratedValue>
                                <enumeratedValue>
                                    <name>1</name>
                                    <description>UnPrivileged</description>
                                    <value>#1</value>
                                </enumeratedValue>
                            </enumeratedValues>
                        </field>
                        <field>
                            <name>PPARD22</name>
                            <description>Temperature Sensor Privilege Attribution</description>
                            <lsb>22</lsb>
                            <msb>22</msb>
                            <access>read-write</access>
                            <enumeratedValues>
                                <enumeratedValue>
                                    <name>0</name>
                                    <description>Privileged</description>
                                    <value>#0</value>
                                </enumeratedValue>
                                <enumeratedValue>
                                    <name>1</name>
                                    <description>UnPrivileged</description>
                                    <value>#1</value>
                                </enumeratedValue>
                            </enumeratedValues>
                        </field>
                        <field>
                            <name>PPARD27</name>
                            <description>High speed analog Comparator 1 Privilege Attribution</description>
                            <lsb>27</lsb>
                            <msb>27</msb>
                            <access>read-write</access>
                            <enumeratedValues>
                                <enumeratedValue>
                                    <name>0</name>
                                    <description>Privileged</description>
                                    <value>#0</value>
                                </enumeratedValue>
                                <enumeratedValue>
                                    <name>1</name>
                                    <description>UnPrivileged</description>
                                    <value>#1</value>
                                </enumeratedValue>
                            </enumeratedValues>
                        </field>
                        <field>
                            <name>PPARD28</name>
                            <description>High speed analog Comparator 0 Privilege Attribution</description>
                            <lsb>28</lsb>
                            <msb>28</msb>
                            <access>read-write</access>
                            <enumeratedValues>
                                <enumeratedValue>
                                    <name>0</name>
                                    <description>Privileged</description>
                                    <value>#0</value>
                                </enumeratedValue>
                                <enumeratedValue>
                                    <name>1</name>
                                    <description>UnPrivileged</description>
                                    <value>#1</value>
                                </enumeratedValue>
                            </enumeratedValues>
                        </field>
                    </fields>
                </register>
                <register>
                    <name>PPARE</name>
                    <description>Peripheral Privilege Attribution Register E</description>
                    <addressOffset>0x28</addressOffset>
                    <size>32</size>
                    <access>read-write</access>
                    <resetValue>0xffffffff</resetValue>
                    <resetMask>0xffffffff</resetMask>
                    <fields>
                        <field>
                            <name>PPARE1</name>
                            <description>WDT Privilege Attribution</description>
                            <lsb>1</lsb>
                            <msb>1</msb>
                            <access>read-write</access>
                            <enumeratedValues>
                                <enumeratedValue>
                                    <name>0</name>
                                    <description>Privileged</description>
                                    <value>#0</value>
                                </enumeratedValue>
                                <enumeratedValue>
                                    <name>1</name>
                                    <description>UnPrivileged</description>
                                    <value>#1</value>
                                </enumeratedValue>
                            </enumeratedValues>
                        </field>
                        <field>
                            <name>PPARE2</name>
                            <description>IWDT Privilege Attribution</description>
                            <lsb>2</lsb>
                            <msb>2</msb>
                            <access>read-write</access>
                            <enumeratedValues>
                                <enumeratedValue>
                                    <name>0</name>
                                    <description>Privileged</description>
                                    <value>#0</value>
                                </enumeratedValue>
                                <enumeratedValue>
                                    <name>1</name>
                                    <description>UnPrivileged</description>
                                    <value>#1</value>
                                </enumeratedValue>
                            </enumeratedValues>
                        </field>
                        <field>
                            <name>PPARE3</name>
                            <description>Real Time Clock Privilege Attribution</description>
                            <lsb>3</lsb>
                            <msb>3</msb>
                            <access>read-write</access>
                            <enumeratedValues>
                                <enumeratedValue>
                                    <name>0</name>
                                    <description>Privileged</description>
                                    <value>#0</value>
                                </enumeratedValue>
                                <enumeratedValue>
                                    <name>1</name>
                                    <description>UnPrivileged</description>
                                    <value>#1</value>
                                </enumeratedValue>
                            </enumeratedValues>
                        </field>
                        <field>
                            <name>PPARE8</name>
                            <description>ULPT1 Privilege Attribution</description>
                            <lsb>8</lsb>
                            <msb>8</msb>
                            <access>read-write</access>
                            <enumeratedValues>
                                <enumeratedValue>
                                    <name>0</name>
                                    <description>Privileged</description>
                                    <value>#0</value>
                                </enumeratedValue>
                                <enumeratedValue>
                                    <name>1</name>
                                    <description>UnPrivileged</description>
                                    <value>#1</value>
                                </enumeratedValue>
                            </enumeratedValues>
                        </field>
                        <field>
                            <name>PPARE9</name>
                            <description>ULPT0 Privilege Attribution</description>
                            <lsb>9</lsb>
                            <msb>9</msb>
                            <access>read-write</access>
                            <enumeratedValues>
                                <enumeratedValue>
                                    <name>0</name>
                                    <description>Privileged</description>
                                    <value>#0</value>
                                </enumeratedValue>
                                <enumeratedValue>
                                    <name>1</name>
                                    <description>UnPrivileged</description>
                                    <value>#1</value>
                                </enumeratedValue>
                            </enumeratedValues>
                        </field>
                        <field>
                            <name>PPARE18</name>
                            <description>General PWM Timer Channel 13 Privilege Attribution</description>
                            <lsb>18</lsb>
                            <msb>18</msb>
                            <access>read-write</access>
                            <enumeratedValues>
                                <enumeratedValue>
                                    <name>0</name>
                                    <description>Privileged</description>
                                    <value>#0</value>
                                </enumeratedValue>
                                <enumeratedValue>
                                    <name>1</name>
                                    <description>UnPrivileged</description>
                                    <value>#1</value>
                                </enumeratedValue>
                            </enumeratedValues>
                        </field>
                        <field>
                            <name>PPARE19</name>
                            <description>General PWM Timer Channel 12 Privilege Attribution</description>
                            <lsb>19</lsb>
                            <msb>19</msb>
                            <access>read-write</access>
                            <enumeratedValues>
                                <enumeratedValue>
                                    <name>0</name>
                                    <description>Privileged</description>
                                    <value>#0</value>
                                </enumeratedValue>
                                <enumeratedValue>
                                    <name>1</name>
                                    <description>UnPrivileged</description>
                                    <value>#1</value>
                                </enumeratedValue>
                            </enumeratedValues>
                        </field>
                        <field>
                            <name>PPARE20</name>
                            <description>General PWM Timer Channel 11 Privilege Attribution</description>
                            <lsb>20</lsb>
                            <msb>20</msb>
                            <access>read-write</access>
                            <enumeratedValues>
                                <enumeratedValue>
                                    <name>0</name>
                                    <description>Privileged</description>
                                    <value>#0</value>
                                </enumeratedValue>
                                <enumeratedValue>
                                    <name>1</name>
                                    <description>UnPrivileged</description>
                                    <value>#1</value>
                                </enumeratedValue>
                            </enumeratedValues>
                        </field>
                        <field>
                            <name>PPARE21</name>
                            <description>General PWM Timer Channel 10 Privilege Attribution</description>
                            <lsb>21</lsb>
                            <msb>21</msb>
                            <access>read-write</access>
                            <enumeratedValues>
                                <enumeratedValue>
                                    <name>0</name>
                                    <description>Privileged</description>
                                    <value>#0</value>
                                </enumeratedValue>
                                <enumeratedValue>
                                    <name>1</name>
                                    <description>UnPrivileged</description>
                                    <value>#1</value>
                                </enumeratedValue>
                            </enumeratedValues>
                        </field>
                        <field>
                            <name>PPARE26</name>
                            <description>General PWM Timer Channel 5 Privilege Attribution</description>
                            <lsb>26</lsb>
                            <msb>26</msb>
                            <access>read-write</access>
                            <enumeratedValues>
                                <enumeratedValue>
                                    <name>0</name>
                                    <description>Privileged</description>
                                    <value>#0</value>
                                </enumeratedValue>
                                <enumeratedValue>
                                    <name>1</name>
                                    <description>UnPrivileged</description>
                                    <value>#1</value>
                                </enumeratedValue>
                            </enumeratedValues>
                        </field>
                        <field>
                            <name>PPARE27</name>
                            <description>General PWM Timer Channel 4 Privilege Attribution</description>
                            <lsb>27</lsb>
                            <msb>27</msb>
                            <access>read-write</access>
                            <enumeratedValues>
                                <enumeratedValue>
                                    <name>0</name>
                                    <description>Privileged</description>
                                    <value>#0</value>
                                </enumeratedValue>
                                <enumeratedValue>
                                    <name>1</name>
                                    <description>UnPrivileged</description>
                                    <value>#1</value>
                                </enumeratedValue>
                            </enumeratedValues>
                        </field>
                        <field>
                            <name>PPARE28</name>
                            <description>General PWM Timer Channel 3 Privilege Attribution</description>
                            <lsb>28</lsb>
                            <msb>28</msb>
                            <access>read-write</access>
                            <enumeratedValues>
                                <enumeratedValue>
                                    <name>0</name>
                                    <description>Privileged</description>
                                    <value>#0</value>
                                </enumeratedValue>
                                <enumeratedValue>
                                    <name>1</name>
                                    <description>UnPrivileged</description>
                                    <value>#1</value>
                                </enumeratedValue>
                            </enumeratedValues>
                        </field>
                        <field>
                            <name>PPARE29</name>
                            <description>General PWM Timer Channel 2 Privilege Attribution</description>
                            <lsb>29</lsb>
                            <msb>29</msb>
                            <access>read-write</access>
                            <enumeratedValues>
                                <enumeratedValue>
                                    <name>0</name>
                                    <description>Privileged</description>
                                    <value>#0</value>
                                </enumeratedValue>
                                <enumeratedValue>
                                    <name>1</name>
                                    <description>UnPrivileged</description>
                                    <value>#1</value>
                                </enumeratedValue>
                            </enumeratedValues>
                        </field>
                        <field>
                            <name>PPARE30</name>
                            <description>General PWM Timer Channel 1 Privilege Attribution</description>
                            <lsb>30</lsb>
                            <msb>30</msb>
                            <access>read-write</access>
                            <enumeratedValues>
                                <enumeratedValue>
                                    <name>0</name>
                                    <description>Privileged</description>
                                    <value>#0</value>
                                </enumeratedValue>
                                <enumeratedValue>
                                    <name>1</name>
                                    <description>UnPrivileged</description>
                                    <value>#1</value>
                                </enumeratedValue>
                            </enumeratedValues>
                        </field>
                        <field>
                            <name>PPARE31</name>
                            <description>General PWM Timer Channel 0 Privilege Attribution</description>
                            <lsb>31</lsb>
                            <msb>31</msb>
                            <access>read-write</access>
                            <enumeratedValues>
                                <enumeratedValue>
                                    <name>0</name>
                                    <description>Privileged</description>
                                    <value>#0</value>
                                </enumeratedValue>
                                <enumeratedValue>
                                    <name>1</name>
                                    <description>UnPrivileged</description>
                                    <value>#1</value>
                                </enumeratedValue>
                            </enumeratedValues>
                        </field>
                    </fields>
                </register>
                <register>
                    <name>MSPAR</name>
                    <description>Module Stop Privilege Attribution Register</description>
                    <addressOffset>0x2C</addressOffset>
                    <size>32</size>
                    <access>read-write</access>
                    <resetValue>0xffffffff</resetValue>
                    <resetMask>0xffffffff</resetMask>
                    <fields>
                        <field>
                            <name>MSPAR31</name>
                            <description>ELC Clock Stop Privilege Attribution</description>
                            <lsb>31</lsb>
                            <msb>31</msb>
                            <access>read-write</access>
                            <enumeratedValues>
                                <enumeratedValue>
                                    <name>0</name>
                                    <description>Privileged</description>
                                    <value>#0</value>
                                </enumeratedValue>
                                <enumeratedValue>
                                    <name>1</name>
                                    <description>UnPrivileged</description>
                                    <value>#1</value>
                                </enumeratedValue>
                            </enumeratedValues>
                        </field>
                    </fields>
                </register>
                <register>
                    <name>CFSAMONA</name>
                    <description>Code Flash Security Attribution Monitor Register A</description>
                    <addressOffset>0x30</addressOffset>
                    <size>32</size>
                    <access>read-only</access>
                    <resetValue>0x00000000</resetValue>
                    <resetMask>0xff007fff</resetMask>
                    <fields>
                        <field>
                            <name>CFS2</name>
                            <description>Code Flash Secure Area</description>
                            <lsb>15</lsb>
                            <msb>23</msb>
                            <access>read-only</access>
                        </field>
                    </fields>
                </register>
                <register>
                    <name>DFSAMON</name>
                    <description>Data Flash Security Attribution Monitor Register</description>
                    <addressOffset>0x34</addressOffset>
                    <size>32</size>
                    <access>read-only</access>
                    <resetValue>0x00000000</resetValue>
                    <resetMask>0xffff03ff</resetMask>
                    <fields>
                        <field>
                            <name>DFS</name>
                            <description>Data Flash Secure Area</description>
                            <lsb>10</lsb>
                            <msb>15</msb>
                            <access>read-only</access>
                        </field>
                    </fields>
                </register>
                <register>
                    <name>DLMMON</name>
                    <description>Device Lifecycle Management State Monitor Register</description>
                    <addressOffset>0x38</addressOffset>
                    <size>32</size>
                    <access>read-only</access>
                    <resetValue>0x00000000</resetValue>
                    <resetMask>0xfffffff0</resetMask>
                    <fields>
                        <field>
                            <name>DLMMON</name>
                            <description>Device Lifecycle Management State Monitor</description>
                            <lsb>0</lsb>
                            <msb>3</msb>
                            <access>read-only</access>
                            <enumeratedValues>
                                <enumeratedValue>
                                    <name>0x0</name>
                                    <description>Reserved</description>
                                    <value>0x0</value>
                                </enumeratedValue>
                                <enumeratedValue>
                                    <name>0x1</name>
                                    <description>Reserved</description>
                                    <value>0x1</value>
                                </enumeratedValue>
                                <enumeratedValue>
                                    <name>0x2</name>
                                    <description>Reserved</description>
                                    <value>0x2</value>
                                </enumeratedValue>
                                <enumeratedValue>
                                    <name>0x3</name>
                                    <description>Reserved</description>
                                    <value>0x3</value>
                                </enumeratedValue>
                                <enumeratedValue>
                                    <name>0x4</name>
                                    <description>OEM</description>
                                    <value>0x4</value>
                                </enumeratedValue>
                                <enumeratedValue>
                                    <name>0x5</name>
                                    <description>Reserved</description>
                                    <value>0x5</value>
                                </enumeratedValue>
                                <enumeratedValue>
                                    <name>0x6</name>
                                    <description>LCK_BOOT</description>
                                    <value>0x6</value>
                                </enumeratedValue>
                                <enumeratedValue>
                                    <name>0x7</name>
                                    <description>RMA_REQ</description>
                                    <value>0x7</value>
                                </enumeratedValue>
                                <enumeratedValue>
                                    <name>0x8</name>
                                    <description>RMA_ACK</description>
                                    <value>0x8</value>
                                </enumeratedValue>
                                <enumeratedValue>
                                    <name>0x9</name>
                                    <description>RMA_RET</description>
                                    <value>0x9</value>
                                </enumeratedValue>
                                <enumeratedValue>
                                    <name>Others</name>
                                    <description>Reserved</description>
                                    <isDefault>true</isDefault>
                                </enumeratedValue>
                            </enumeratedValues>
                        </field>
                    </fields>
                </register>
            </registers>
        </peripheral>
        <peripheral>
            <name>POEG_NS</name>
            <description>Port Output Enable Module for GPT</description>
            <baseAddress>0x50212000</baseAddress>
            <addressBlock>
                <offset>0x00</offset>
                <size>4</size>
                <usage>registers</usage>
            </addressBlock>
            <addressBlock>
                <offset>0x100</offset>
                <size>4</size>
                <usage>registers</usage>
            </addressBlock>
            <addressBlock>
                <offset>0x200</offset>
                <size>4</size>
                <usage>registers</usage>
            </addressBlock>
            <addressBlock>
                <offset>0x300</offset>
                <size>4</size>
                <usage>registers</usage>
            </addressBlock>
            <registers>
                <register>
                    <name>POEGGA</name>
                    <description>POEG Group A Setting Register</description>
                    <addressOffset>0x000</addressOffset>
                    <size>32</size>
                    <access>read-write</access>
                    <resetValue>0x00000000</resetValue>
                    <resetMask>0xffffffff</resetMask>
                    <fields>
                        <field>
                            <name>PIDF</name>
                            <description>Port Input Detection Flag</description>
                            <lsb>0</lsb>
                            <msb>0</msb>
                            <access>read-write</access>
                            <enumeratedValues>
                                <enumeratedValue>
                                    <name>0</name>
                                    <description>No output-disable request from the GTETRGn pin occurred</description>
                                    <value>#0</value>
                                </enumeratedValue>
                                <enumeratedValue>
                                    <name>1</name>
                                    <description>Output-disable request from the GTETRGn pin occurred.</description>
                                    <value>#1</value>
                                </enumeratedValue>
                            </enumeratedValues>
                        </field>
                        <field>
                            <name>IOCF</name>
                            <description>Detection Flag for GPT or ACMPHS Output-Disable Request</description>
                            <lsb>1</lsb>
                            <msb>1</msb>
                            <access>read-write</access>
                            <enumeratedValues>
                                <enumeratedValue>
                                    <name>0</name>
                                    <description>No output-disable request from GPT or comparator interrupt occurred.</description>
                                    <value>#0</value>
                                </enumeratedValue>
                                <enumeratedValue>
                                    <name>1</name>
                                    <description>Output-disable request from GPT or comparator interrupt occurred.</description>
                                    <value>#1</value>
                                </enumeratedValue>
                            </enumeratedValues>
                        </field>
                        <field>
                            <name>OSTPF</name>
                            <description>Oscillation Stop Detection Flag</description>
                            <lsb>2</lsb>
                            <msb>2</msb>
                            <access>read-write</access>
                            <enumeratedValues>
                                <enumeratedValue>
                                    <name>0</name>
                                    <description>No output-disable request from oscillation stop detection occurred</description>
                                    <value>#0</value>
                                </enumeratedValue>
                                <enumeratedValue>
                                    <name>1</name>
                                    <description>Output-disable request from oscillation stop detection occurred</description>
                                    <value>#1</value>
                                </enumeratedValue>
                            </enumeratedValues>
                        </field>
                        <field>
                            <name>SSF</name>
                            <description>Software Stop Flag</description>
                            <lsb>3</lsb>
                            <msb>3</msb>
                            <access>read-write</access>
                            <enumeratedValues>
                                <enumeratedValue>
                                    <name>0</name>
                                    <description>No output-disable request from software occurred</description>
                                    <value>#0</value>
                                </enumeratedValue>
                                <enumeratedValue>
                                    <name>1</name>
                                    <description>Output-disable request from software occurred</description>
                                    <value>#1</value>
                                </enumeratedValue>
                            </enumeratedValues>
                        </field>
                        <field>
                            <name>PIDE</name>
                            <description>Port Input Detection Enable</description>
                            <lsb>4</lsb>
                            <msb>4</msb>
                            <access>read-write</access>
                            <enumeratedValues>
                                <enumeratedValue>
                                    <name>0</name>
                                    <description>Disable output-disable requests from the GTETRGn pins</description>
                                    <value>#0</value>
                                </enumeratedValue>
                                <enumeratedValue>
                                    <name>1</name>
                                    <description>Enable output-disable requests from the GTETRGn pins</description>
                                    <value>#1</value>
                                </enumeratedValue>
                            </enumeratedValues>
                        </field>
                        <field>
                            <name>IOCE</name>
                            <description>Enable for GPT Output-Disable Request</description>
                            <lsb>5</lsb>
                            <msb>5</msb>
                            <access>read-write</access>
                            <enumeratedValues>
                                <enumeratedValue>
                                    <name>0</name>
                                    <description>Disable output-disable requests from GPT</description>
                                    <value>#0</value>
                                </enumeratedValue>
                                <enumeratedValue>
                                    <name>1</name>
                                    <description>Enable output-disable requests from GPT</description>
                                    <value>#1</value>
                                </enumeratedValue>
                            </enumeratedValues>
                        </field>
                        <field>
                            <name>OSTPE</name>
                            <description>Oscillation Stop Detection Enable</description>
                            <lsb>6</lsb>
                            <msb>6</msb>
                            <access>read-write</access>
                            <enumeratedValues>
                                <enumeratedValue>
                                    <name>0</name>
                                    <description>Disable output-disable requests from oscillation stop detection</description>
                                    <value>#0</value>
                                </enumeratedValue>
                                <enumeratedValue>
                                    <name>1</name>
                                    <description>Enable output-disable requests from oscillation stop detection</description>
                                    <value>#1</value>
                                </enumeratedValue>
                            </enumeratedValues>
                        </field>
                        <field>
                            <name>CDRE0</name>
                            <lsb>8</lsb>
                            <msb>8</msb>
                            <access>read-write</access>
                            <enumeratedValues>
                                <enumeratedValue>
                                    <name>0</name>
                                    <description>Disable output-disable request from ACMPHS0</description>
                                    <value>#0</value>
                                </enumeratedValue>
                                <enumeratedValue>
                                    <name>1</name>
                                    <description>Enable output-disable request from ACMPHS0</description>
                                    <value>#1</value>
                                </enumeratedValue>
                            </enumeratedValues>
                        </field>
                        <field>
                            <name>CDRE1</name>
                            <lsb>9</lsb>
                            <msb>9</msb>
                            <access>read-write</access>
                            <enumeratedValues>
                                <enumeratedValue>
                                    <name>0</name>
                                    <description>Disable output-disable request from ACMPHS1</description>
                                    <value>#0</value>
                                </enumeratedValue>
                                <enumeratedValue>
                                    <name>1</name>
                                    <description>Enable output-disable request from ACMPHS1</description>
                                    <value>#1</value>
                                </enumeratedValue>
                            </enumeratedValues>
                        </field>
                        <field>
                            <name>ST</name>
                            <description>GTETRGn Input Status Flag</description>
                            <lsb>16</lsb>
                            <msb>16</msb>
                            <access>read-only</access>
                            <enumeratedValues>
                                <enumeratedValue>
                                    <name>0</name>
                                    <description>GTETRGn input after filtering was 0</description>
                                    <value>#0</value>
                                </enumeratedValue>
                                <enumeratedValue>
                                    <name>1</name>
                                    <description>GTETRGn input after filtering was 1</description>
                                    <value>#1</value>
                                </enumeratedValue>
                            </enumeratedValues>
                        </field>
                        <field>
                            <name>INV</name>
                            <description>GTETRGn Input Reverse</description>
                            <lsb>28</lsb>
                            <msb>28</msb>
                            <access>read-write</access>
                            <enumeratedValues>
                                <enumeratedValue>
                                    <name>0</name>
                                    <description>Input GTETRGn as-is</description>
                                    <value>#0</value>
                                </enumeratedValue>
                                <enumeratedValue>
                                    <name>1</name>
                                    <description>Input GTETRGn in reverse</description>
                                    <value>#1</value>
                                </enumeratedValue>
                            </enumeratedValues>
                        </field>
                        <field>
                            <name>NFEN</name>
                            <description>Noise Filter Enable</description>
                            <lsb>29</lsb>
                            <msb>29</msb>
                            <access>read-write</access>
                            <enumeratedValues>
                                <enumeratedValue>
                                    <name>0</name>
                                    <description>Disable noise filtering</description>
                                    <value>#0</value>
                                </enumeratedValue>
                                <enumeratedValue>
                                    <name>1</name>
                                    <description>Enable noise filtering</description>
                                    <value>#1</value>
                                </enumeratedValue>
                            </enumeratedValues>
                        </field>
                        <field>
                            <name>NFCS</name>
                            <description>Noise Filter Clock Select</description>
                            <lsb>30</lsb>
                            <msb>31</msb>
                            <access>read-write</access>
                            <enumeratedValues>
                                <enumeratedValue>
                                    <name>00</name>
                                    <description>Sample GTETRGn pin input level three times every PCLKB</description>
                                    <value>#00</value>
                                </enumeratedValue>
                                <enumeratedValue>
                                    <name>01</name>
                                    <description>Sample GTETRGn pin input level three times every PCLKB/8</description>
                                    <value>#01</value>
                                </enumeratedValue>
                                <enumeratedValue>
                                    <name>10</name>
                                    <description>Sample GTETRGn pin input level three times every PCLKB/32</description>
                                    <value>#10</value>
                                </enumeratedValue>
                                <enumeratedValue>
                                    <name>11</name>
                                    <description>Sample GTETRGn pin input level three times every PCLKB/128</description>
                                    <value>#11</value>
                                </enumeratedValue>
                            </enumeratedValues>
                        </field>
                    </fields>
                </register>
                <register>
                    <name>POEGGB</name>
                    <description>POEG Group B Setting Register</description>
                    <addressOffset>0x100</addressOffset>
                    <size>32</size>
                    <access>read-write</access>
                    <resetValue>0x00000000</resetValue>
                    <resetMask>0xffffffff</resetMask>
                    <fields>
                        <field>
                            <name>PIDF</name>
                            <description>Port Input Detection Flag</description>
                            <lsb>0</lsb>
                            <msb>0</msb>
                            <access>read-write</access>
                            <enumeratedValues>
                                <enumeratedValue>
                                    <name>0</name>
                                    <description>No output-disable request from the GTETRGn pin occurred</description>
                                    <value>#0</value>
                                </enumeratedValue>
                                <enumeratedValue>
                                    <name>1</name>
                                    <description>Output-disable request from the GTETRGn pin occurred.</description>
                                    <value>#1</value>
                                </enumeratedValue>
                            </enumeratedValues>
                        </field>
                        <field>
                            <name>IOCF</name>
                            <description>Detection Flag for GPT or ACMPHS Output-Disable Request</description>
                            <lsb>1</lsb>
                            <msb>1</msb>
                            <access>read-write</access>
                            <enumeratedValues>
                                <enumeratedValue>
                                    <name>0</name>
                                    <description>No output-disable request from GPT or comparator interrupt occurred.</description>
                                    <value>#0</value>
                                </enumeratedValue>
                                <enumeratedValue>
                                    <name>1</name>
                                    <description>Output-disable request from GPT or comparator interrupt occurred.</description>
                                    <value>#1</value>
                                </enumeratedValue>
                            </enumeratedValues>
                        </field>
                        <field>
                            <name>OSTPF</name>
                            <description>Oscillation Stop Detection Flag</description>
                            <lsb>2</lsb>
                            <msb>2</msb>
                            <access>read-write</access>
                            <enumeratedValues>
                                <enumeratedValue>
                                    <name>0</name>
                                    <description>No output-disable request from oscillation stop detection occurred</description>
                                    <value>#0</value>
                                </enumeratedValue>
                                <enumeratedValue>
                                    <name>1</name>
                                    <description>Output-disable request from oscillation stop detection occurred</description>
                                    <value>#1</value>
                                </enumeratedValue>
                            </enumeratedValues>
                        </field>
                        <field>
                            <name>SSF</name>
                            <description>Software Stop Flag</description>
                            <lsb>3</lsb>
                            <msb>3</msb>
                            <access>read-write</access>
                            <enumeratedValues>
                                <enumeratedValue>
                                    <name>0</name>
                                    <description>No output-disable request from software occurred</description>
                                    <value>#0</value>
                                </enumeratedValue>
                                <enumeratedValue>
                                    <name>1</name>
                                    <description>Output-disable request from software occurred</description>
                                    <value>#1</value>
                                </enumeratedValue>
                            </enumeratedValues>
                        </field>
                        <field>
                            <name>PIDE</name>
                            <description>Port Input Detection Enable</description>
                            <lsb>4</lsb>
                            <msb>4</msb>
                            <access>read-write</access>
                            <enumeratedValues>
                                <enumeratedValue>
                                    <name>0</name>
                                    <description>Disable output-disable requests from the GTETRGn pins</description>
                                    <value>#0</value>
                                </enumeratedValue>
                                <enumeratedValue>
                                    <name>1</name>
                                    <description>Enable output-disable requests from the GTETRGn pins</description>
                                    <value>#1</value>
                                </enumeratedValue>
                            </enumeratedValues>
                        </field>
                        <field>
                            <name>IOCE</name>
                            <description>Enable for GPT Output-Disable Request</description>
                            <lsb>5</lsb>
                            <msb>5</msb>
                            <access>read-write</access>
                            <enumeratedValues>
                                <enumeratedValue>
                                    <name>0</name>
                                    <description>Disable output-disable requests from GPT</description>
                                    <value>#0</value>
                                </enumeratedValue>
                                <enumeratedValue>
                                    <name>1</name>
                                    <description>Enable output-disable requests from GPT</description>
                                    <value>#1</value>
                                </enumeratedValue>
                            </enumeratedValues>
                        </field>
                        <field>
                            <name>OSTPE</name>
                            <description>Oscillation Stop Detection Enable</description>
                            <lsb>6</lsb>
                            <msb>6</msb>
                            <access>read-write</access>
                            <enumeratedValues>
                                <enumeratedValue>
                                    <name>0</name>
                                    <description>Disable output-disable requests from oscillation stop detection</description>
                                    <value>#0</value>
                                </enumeratedValue>
                                <enumeratedValue>
                                    <name>1</name>
                                    <description>Enable output-disable requests from oscillation stop detection</description>
                                    <value>#1</value>
                                </enumeratedValue>
                            </enumeratedValues>
                        </field>
                        <field>
                            <name>CDRE0</name>
                            <lsb>8</lsb>
                            <msb>8</msb>
                            <access>read-write</access>
                            <enumeratedValues>
                                <enumeratedValue>
                                    <name>0</name>
                                    <description>Disable output-disable request from ACMPHS0</description>
                                    <value>#0</value>
                                </enumeratedValue>
                                <enumeratedValue>
                                    <name>1</name>
                                    <description>Enable output-disable request from ACMPHS0</description>
                                    <value>#1</value>
                                </enumeratedValue>
                            </enumeratedValues>
                        </field>
                        <field>
                            <name>CDRE1</name>
                            <lsb>9</lsb>
                            <msb>9</msb>
                            <access>read-write</access>
                            <enumeratedValues>
                                <enumeratedValue>
                                    <name>0</name>
                                    <description>Disable output-disable request from ACMPHS1</description>
                                    <value>#0</value>
                                </enumeratedValue>
                                <enumeratedValue>
                                    <name>1</name>
                                    <description>Enable output-disable request from ACMPHS1</description>
                                    <value>#1</value>
                                </enumeratedValue>
                            </enumeratedValues>
                        </field>
                        <field>
                            <name>ST</name>
                            <description>GTETRGn Input Status Flag</description>
                            <lsb>16</lsb>
                            <msb>16</msb>
                            <access>read-only</access>
                            <enumeratedValues>
                                <enumeratedValue>
                                    <name>0</name>
                                    <description>GTETRGn input after filtering was 0</description>
                                    <value>#0</value>
                                </enumeratedValue>
                                <enumeratedValue>
                                    <name>1</name>
                                    <description>GTETRGn input after filtering was 1</description>
                                    <value>#1</value>
                                </enumeratedValue>
                            </enumeratedValues>
                        </field>
                        <field>
                            <name>INV</name>
                            <description>GTETRGn Input Reverse</description>
                            <lsb>28</lsb>
                            <msb>28</msb>
                            <access>read-write</access>
                            <enumeratedValues>
                                <enumeratedValue>
                                    <name>0</name>
                                    <description>Input GTETRGn as-is</description>
                                    <value>#0</value>
                                </enumeratedValue>
                                <enumeratedValue>
                                    <name>1</name>
                                    <description>Input GTETRGn in reverse</description>
                                    <value>#1</value>
                                </enumeratedValue>
                            </enumeratedValues>
                        </field>
                        <field>
                            <name>NFEN</name>
                            <description>Noise Filter Enable</description>
                            <lsb>29</lsb>
                            <msb>29</msb>
                            <access>read-write</access>
                            <enumeratedValues>
                                <enumeratedValue>
                                    <name>0</name>
                                    <description>Disable noise filtering</description>
                                    <value>#0</value>
                                </enumeratedValue>
                                <enumeratedValue>
                                    <name>1</name>
                                    <description>Enable noise filtering</description>
                                    <value>#1</value>
                                </enumeratedValue>
                            </enumeratedValues>
                        </field>
                        <field>
                            <name>NFCS</name>
                            <description>Noise Filter Clock Select</description>
                            <lsb>30</lsb>
                            <msb>31</msb>
                            <access>read-write</access>
                            <enumeratedValues>
                                <enumeratedValue>
                                    <name>00</name>
                                    <description>Sample GTETRGn pin input level three times every PCLKB</description>
                                    <value>#00</value>
                                </enumeratedValue>
                                <enumeratedValue>
                                    <name>01</name>
                                    <description>Sample GTETRGn pin input level three times every PCLKB/8</description>
                                    <value>#01</value>
                                </enumeratedValue>
                                <enumeratedValue>
                                    <name>10</name>
                                    <description>Sample GTETRGn pin input level three times every PCLKB/32</description>
                                    <value>#10</value>
                                </enumeratedValue>
                                <enumeratedValue>
                                    <name>11</name>
                                    <description>Sample GTETRGn pin input level three times every PCLKB/128</description>
                                    <value>#11</value>
                                </enumeratedValue>
                            </enumeratedValues>
                        </field>
                    </fields>
                </register>
                <register>
                    <name>POEGGC</name>
                    <description>POEG Group C Setting Register</description>
                    <addressOffset>0x200</addressOffset>
                    <size>32</size>
                    <access>read-write</access>
                    <resetValue>0x00000000</resetValue>
                    <resetMask>0xffffffff</resetMask>
                    <fields>
                        <field>
                            <name>PIDF</name>
                            <description>Port Input Detection Flag</description>
                            <lsb>0</lsb>
                            <msb>0</msb>
                            <access>read-write</access>
                            <enumeratedValues>
                                <enumeratedValue>
                                    <name>0</name>
                                    <description>No output-disable request from the GTETRGn pin occurred</description>
                                    <value>#0</value>
                                </enumeratedValue>
                                <enumeratedValue>
                                    <name>1</name>
                                    <description>Output-disable request from the GTETRGn pin occurred.</description>
                                    <value>#1</value>
                                </enumeratedValue>
                            </enumeratedValues>
                        </field>
                        <field>
                            <name>IOCF</name>
                            <description>Detection Flag for GPT or ACMPHS Output-Disable Request</description>
                            <lsb>1</lsb>
                            <msb>1</msb>
                            <access>read-write</access>
                            <enumeratedValues>
                                <enumeratedValue>
                                    <name>0</name>
                                    <description>No output-disable request from GPT or comparator interrupt occurred.</description>
                                    <value>#0</value>
                                </enumeratedValue>
                                <enumeratedValue>
                                    <name>1</name>
                                    <description>Output-disable request from GPT or comparator interrupt occurred.</description>
                                    <value>#1</value>
                                </enumeratedValue>
                            </enumeratedValues>
                        </field>
                        <field>
                            <name>OSTPF</name>
                            <description>Oscillation Stop Detection Flag</description>
                            <lsb>2</lsb>
                            <msb>2</msb>
                            <access>read-write</access>
                            <enumeratedValues>
                                <enumeratedValue>
                                    <name>0</name>
                                    <description>No output-disable request from oscillation stop detection occurred</description>
                                    <value>#0</value>
                                </enumeratedValue>
                                <enumeratedValue>
                                    <name>1</name>
                                    <description>Output-disable request from oscillation stop detection occurred</description>
                                    <value>#1</value>
                                </enumeratedValue>
                            </enumeratedValues>
                        </field>
                        <field>
                            <name>SSF</name>
                            <description>Software Stop Flag</description>
                            <lsb>3</lsb>
                            <msb>3</msb>
                            <access>read-write</access>
                            <enumeratedValues>
                                <enumeratedValue>
                                    <name>0</name>
                                    <description>No output-disable request from software occurred</description>
                                    <value>#0</value>
                                </enumeratedValue>
                                <enumeratedValue>
                                    <name>1</name>
                                    <description>Output-disable request from software occurred</description>
                                    <value>#1</value>
                                </enumeratedValue>
                            </enumeratedValues>
                        </field>
                        <field>
                            <name>PIDE</name>
                            <description>Port Input Detection Enable</description>
                            <lsb>4</lsb>
                            <msb>4</msb>
                            <access>read-write</access>
                            <enumeratedValues>
                                <enumeratedValue>
                                    <name>0</name>
                                    <description>Disable output-disable requests from the GTETRGn pins</description>
                                    <value>#0</value>
                                </enumeratedValue>
                                <enumeratedValue>
                                    <name>1</name>
                                    <description>Enable output-disable requests from the GTETRGn pins</description>
                                    <value>#1</value>
                                </enumeratedValue>
                            </enumeratedValues>
                        </field>
                        <field>
                            <name>IOCE</name>
                            <description>Enable for GPT Output-Disable Request</description>
                            <lsb>5</lsb>
                            <msb>5</msb>
                            <access>read-write</access>
                            <enumeratedValues>
                                <enumeratedValue>
                                    <name>0</name>
                                    <description>Disable output-disable requests from GPT</description>
                                    <value>#0</value>
                                </enumeratedValue>
                                <enumeratedValue>
                                    <name>1</name>
                                    <description>Enable output-disable requests from GPT</description>
                                    <value>#1</value>
                                </enumeratedValue>
                            </enumeratedValues>
                        </field>
                        <field>
                            <name>OSTPE</name>
                            <description>Oscillation Stop Detection Enable</description>
                            <lsb>6</lsb>
                            <msb>6</msb>
                            <access>read-write</access>
                            <enumeratedValues>
                                <enumeratedValue>
                                    <name>0</name>
                                    <description>Disable output-disable requests from oscillation stop detection</description>
                                    <value>#0</value>
                                </enumeratedValue>
                                <enumeratedValue>
                                    <name>1</name>
                                    <description>Enable output-disable requests from oscillation stop detection</description>
                                    <value>#1</value>
                                </enumeratedValue>
                            </enumeratedValues>
                        </field>
                        <field>
                            <name>CDRE0</name>
                            <lsb>8</lsb>
                            <msb>8</msb>
                            <access>read-write</access>
                            <enumeratedValues>
                                <enumeratedValue>
                                    <name>0</name>
                                    <description>Disable output-disable request from ACMPHS0</description>
                                    <value>#0</value>
                                </enumeratedValue>
                                <enumeratedValue>
                                    <name>1</name>
                                    <description>Enable output-disable request from ACMPHS0</description>
                                    <value>#1</value>
                                </enumeratedValue>
                            </enumeratedValues>
                        </field>
                        <field>
                            <name>CDRE1</name>
                            <lsb>9</lsb>
                            <msb>9</msb>
                            <access>read-write</access>
                            <enumeratedValues>
                                <enumeratedValue>
                                    <name>0</name>
                                    <description>Disable output-disable request from ACMPHS1</description>
                                    <value>#0</value>
                                </enumeratedValue>
                                <enumeratedValue>
                                    <name>1</name>
                                    <description>Enable output-disable request from ACMPHS1</description>
                                    <value>#1</value>
                                </enumeratedValue>
                            </enumeratedValues>
                        </field>
                        <field>
                            <name>ST</name>
                            <description>GTETRGn Input Status Flag</description>
                            <lsb>16</lsb>
                            <msb>16</msb>
                            <access>read-only</access>
                            <enumeratedValues>
                                <enumeratedValue>
                                    <name>0</name>
                                    <description>GTETRGn input after filtering was 0</description>
                                    <value>#0</value>
                                </enumeratedValue>
                                <enumeratedValue>
                                    <name>1</name>
                                    <description>GTETRGn input after filtering was 1</description>
                                    <value>#1</value>
                                </enumeratedValue>
                            </enumeratedValues>
                        </field>
                        <field>
                            <name>INV</name>
                            <description>GTETRGn Input Reverse</description>
                            <lsb>28</lsb>
                            <msb>28</msb>
                            <access>read-write</access>
                            <enumeratedValues>
                                <enumeratedValue>
                                    <name>0</name>
                                    <description>Input GTETRGn as-is</description>
                                    <value>#0</value>
                                </enumeratedValue>
                                <enumeratedValue>
                                    <name>1</name>
                                    <description>Input GTETRGn in reverse</description>
                                    <value>#1</value>
                                </enumeratedValue>
                            </enumeratedValues>
                        </field>
                        <field>
                            <name>NFEN</name>
                            <description>Noise Filter Enable</description>
                            <lsb>29</lsb>
                            <msb>29</msb>
                            <access>read-write</access>
                            <enumeratedValues>
                                <enumeratedValue>
                                    <name>0</name>
                                    <description>Disable noise filtering</description>
                                    <value>#0</value>
                                </enumeratedValue>
                                <enumeratedValue>
                                    <name>1</name>
                                    <description>Enable noise filtering</description>
                                    <value>#1</value>
                                </enumeratedValue>
                            </enumeratedValues>
                        </field>
                        <field>
                            <name>NFCS</name>
                            <description>Noise Filter Clock Select</description>
                            <lsb>30</lsb>
                            <msb>31</msb>
                            <access>read-write</access>
                            <enumeratedValues>
                                <enumeratedValue>
                                    <name>00</name>
                                    <description>Sample GTETRGn pin input level three times every PCLKB</description>
                                    <value>#00</value>
                                </enumeratedValue>
                                <enumeratedValue>
                                    <name>01</name>
                                    <description>Sample GTETRGn pin input level three times every PCLKB/8</description>
                                    <value>#01</value>
                                </enumeratedValue>
                                <enumeratedValue>
                                    <name>10</name>
                                    <description>Sample GTETRGn pin input level three times every PCLKB/32</description>
                                    <value>#10</value>
                                </enumeratedValue>
                                <enumeratedValue>
                                    <name>11</name>
                                    <description>Sample GTETRGn pin input level three times every PCLKB/128</description>
                                    <value>#11</value>
                                </enumeratedValue>
                            </enumeratedValues>
                        </field>
                    </fields>
                </register>
                <register>
                    <name>POEGGD</name>
                    <description>POEG Group D Setting Register</description>
                    <addressOffset>0x300</addressOffset>
                    <size>32</size>
                    <access>read-write</access>
                    <resetValue>0x00000000</resetValue>
                    <resetMask>0xffffffff</resetMask>
                    <fields>
                        <field>
                            <name>PIDF</name>
                            <description>Port Input Detection Flag</description>
                            <lsb>0</lsb>
                            <msb>0</msb>
                            <access>read-write</access>
                            <enumeratedValues>
                                <enumeratedValue>
                                    <name>0</name>
                                    <description>No output-disable request from the GTETRGn pin occurred</description>
                                    <value>#0</value>
                                </enumeratedValue>
                                <enumeratedValue>
                                    <name>1</name>
                                    <description>Output-disable request from the GTETRGn pin occurred.</description>
                                    <value>#1</value>
                                </enumeratedValue>
                            </enumeratedValues>
                        </field>
                        <field>
                            <name>IOCF</name>
                            <description>Detection Flag for GPT or ACMPHS Output-Disable Request</description>
                            <lsb>1</lsb>
                            <msb>1</msb>
                            <access>read-write</access>
                            <enumeratedValues>
                                <enumeratedValue>
                                    <name>0</name>
                                    <description>No output-disable request from GPT or comparator interrupt occurred.</description>
                                    <value>#0</value>
                                </enumeratedValue>
                                <enumeratedValue>
                                    <name>1</name>
                                    <description>Output-disable request from GPT or comparator interrupt occurred.</description>
                                    <value>#1</value>
                                </enumeratedValue>
                            </enumeratedValues>
                        </field>
                        <field>
                            <name>OSTPF</name>
                            <description>Oscillation Stop Detection Flag</description>
                            <lsb>2</lsb>
                            <msb>2</msb>
                            <access>read-write</access>
                            <enumeratedValues>
                                <enumeratedValue>
                                    <name>0</name>
                                    <description>No output-disable request from oscillation stop detection occurred</description>
                                    <value>#0</value>
                                </enumeratedValue>
                                <enumeratedValue>
                                    <name>1</name>
                                    <description>Output-disable request from oscillation stop detection occurred</description>
                                    <value>#1</value>
                                </enumeratedValue>
                            </enumeratedValues>
                        </field>
                        <field>
                            <name>SSF</name>
                            <description>Software Stop Flag</description>
                            <lsb>3</lsb>
                            <msb>3</msb>
                            <access>read-write</access>
                            <enumeratedValues>
                                <enumeratedValue>
                                    <name>0</name>
                                    <description>No output-disable request from software occurred</description>
                                    <value>#0</value>
                                </enumeratedValue>
                                <enumeratedValue>
                                    <name>1</name>
                                    <description>Output-disable request from software occurred</description>
                                    <value>#1</value>
                                </enumeratedValue>
                            </enumeratedValues>
                        </field>
                        <field>
                            <name>PIDE</name>
                            <description>Port Input Detection Enable</description>
                            <lsb>4</lsb>
                            <msb>4</msb>
                            <access>read-write</access>
                            <enumeratedValues>
                                <enumeratedValue>
                                    <name>0</name>
                                    <description>Disable output-disable requests from the GTETRGn pins</description>
                                    <value>#0</value>
                                </enumeratedValue>
                                <enumeratedValue>
                                    <name>1</name>
                                    <description>Enable output-disable requests from the GTETRGn pins</description>
                                    <value>#1</value>
                                </enumeratedValue>
                            </enumeratedValues>
                        </field>
                        <field>
                            <name>IOCE</name>
                            <description>Enable for GPT Output-Disable Request</description>
                            <lsb>5</lsb>
                            <msb>5</msb>
                            <access>read-write</access>
                            <enumeratedValues>
                                <enumeratedValue>
                                    <name>0</name>
                                    <description>Disable output-disable requests from GPT</description>
                                    <value>#0</value>
                                </enumeratedValue>
                                <enumeratedValue>
                                    <name>1</name>
                                    <description>Enable output-disable requests from GPT</description>
                                    <value>#1</value>
                                </enumeratedValue>
                            </enumeratedValues>
                        </field>
                        <field>
                            <name>OSTPE</name>
                            <description>Oscillation Stop Detection Enable</description>
                            <lsb>6</lsb>
                            <msb>6</msb>
                            <access>read-write</access>
                            <enumeratedValues>
                                <enumeratedValue>
                                    <name>0</name>
                                    <description>Disable output-disable requests from oscillation stop detection</description>
                                    <value>#0</value>
                                </enumeratedValue>
                                <enumeratedValue>
                                    <name>1</name>
                                    <description>Enable output-disable requests from oscillation stop detection</description>
                                    <value>#1</value>
                                </enumeratedValue>
                            </enumeratedValues>
                        </field>
                        <field>
                            <name>CDRE0</name>
                            <lsb>8</lsb>
                            <msb>8</msb>
                            <access>read-write</access>
                            <enumeratedValues>
                                <enumeratedValue>
                                    <name>0</name>
                                    <description>Disable output-disable request from ACMPHS0</description>
                                    <value>#0</value>
                                </enumeratedValue>
                                <enumeratedValue>
                                    <name>1</name>
                                    <description>Enable output-disable request from ACMPHS0</description>
                                    <value>#1</value>
                                </enumeratedValue>
                            </enumeratedValues>
                        </field>
                        <field>
                            <name>CDRE1</name>
                            <lsb>9</lsb>
                            <msb>9</msb>
                            <access>read-write</access>
                            <enumeratedValues>
                                <enumeratedValue>
                                    <name>0</name>
                                    <description>Disable output-disable request from ACMPHS1</description>
                                    <value>#0</value>
                                </enumeratedValue>
                                <enumeratedValue>
                                    <name>1</name>
                                    <description>Enable output-disable request from ACMPHS1</description>
                                    <value>#1</value>
                                </enumeratedValue>
                            </enumeratedValues>
                        </field>
                        <field>
                            <name>ST</name>
                            <description>GTETRGn Input Status Flag</description>
                            <lsb>16</lsb>
                            <msb>16</msb>
                            <access>read-only</access>
                            <enumeratedValues>
                                <enumeratedValue>
                                    <name>0</name>
                                    <description>GTETRGn input after filtering was 0</description>
                                    <value>#0</value>
                                </enumeratedValue>
                                <enumeratedValue>
                                    <name>1</name>
                                    <description>GTETRGn input after filtering was 1</description>
                                    <value>#1</value>
                                </enumeratedValue>
                            </enumeratedValues>
                        </field>
                        <field>
                            <name>INV</name>
                            <description>GTETRGn Input Reverse</description>
                            <lsb>28</lsb>
                            <msb>28</msb>
                            <access>read-write</access>
                            <enumeratedValues>
                                <enumeratedValue>
                                    <name>0</name>
                                    <description>Input GTETRGn as-is</description>
                                    <value>#0</value>
                                </enumeratedValue>
                                <enumeratedValue>
                                    <name>1</name>
                                    <description>Input GTETRGn in reverse</description>
                                    <value>#1</value>
                                </enumeratedValue>
                            </enumeratedValues>
                        </field>
                        <field>
                            <name>NFEN</name>
                            <description>Noise Filter Enable</description>
                            <lsb>29</lsb>
                            <msb>29</msb>
                            <access>read-write</access>
                            <enumeratedValues>
                                <enumeratedValue>
                                    <name>0</name>
                                    <description>Disable noise filtering</description>
                                    <value>#0</value>
                                </enumeratedValue>
                                <enumeratedValue>
                                    <name>1</name>
                                    <description>Enable noise filtering</description>
                                    <value>#1</value>
                                </enumeratedValue>
                            </enumeratedValues>
                        </field>
                        <field>
                            <name>NFCS</name>
                            <description>Noise Filter Clock Select</description>
                            <lsb>30</lsb>
                            <msb>31</msb>
                            <access>read-write</access>
                            <enumeratedValues>
                                <enumeratedValue>
                                    <name>00</name>
                                    <description>Sample GTETRGn pin input level three times every PCLKB</description>
                                    <value>#00</value>
                                </enumeratedValue>
                                <enumeratedValue>
                                    <name>01</name>
                                    <description>Sample GTETRGn pin input level three times every PCLKB/8</description>
                                    <value>#01</value>
                                </enumeratedValue>
                                <enumeratedValue>
                                    <name>10</name>
                                    <description>Sample GTETRGn pin input level three times every PCLKB/32</description>
                                    <value>#10</value>
                                </enumeratedValue>
                                <enumeratedValue>
                                    <name>11</name>
                                    <description>Sample GTETRGn pin input level three times every PCLKB/128</description>
                                    <value>#11</value>
                                </enumeratedValue>
                            </enumeratedValues>
                        </field>
                    </fields>
                </register>
            </registers>
        </peripheral>
        <peripheral>
            <name>ULPT0_NS</name>
            <description>Ultra-Low Power Timer 0</description>
            <baseAddress>0x50220000</baseAddress>
            <addressBlock>
                <offset>0x00</offset>
                <size>19</size>
                <usage>registers</usage>
            </addressBlock>
            <registers>
                <register>
                    <name>ULPTCNT</name>
                    <description>ULPT Counter Register</description>
                    <addressOffset>0x00</addressOffset>
                    <size>32</size>
                    <access>read-write</access>
                    <resetValue>0xffffffff</resetValue>
                    <resetMask>0xffffffff</resetMask>
                    <fields>
                        <field>
                            <name>ULPTCNT</name>
                            <description>Setting range : 0x00000000 to 0xFFFFFFFF</description>
                            <lsb>0</lsb>
                            <msb>31</msb>
                            <access>read-write</access>
                        </field>
                    </fields>
                </register>
                <register>
                    <name>ULPTCMA</name>
                    <description>ULPT Compare Match A Register</description>
                    <addressOffset>0x04</addressOffset>
                    <size>32</size>
                    <access>read-write</access>
                    <resetValue>0xffffffff</resetValue>
                    <resetMask>0xffffffff</resetMask>
                    <fields>
                        <field>
                            <name>ULPTCMA</name>
                            <description>32-bit Compare Match A Data</description>
                            <lsb>0</lsb>
                            <msb>31</msb>
                            <access>read-write</access>
                        </field>
                    </fields>
                </register>
                <register>
                    <name>ULPTCMB</name>
                    <description>ULPT Compare Match B Register</description>
                    <addressOffset>0x08</addressOffset>
                    <size>32</size>
                    <access>read-write</access>
                    <resetValue>0xffffffff</resetValue>
                    <resetMask>0xffffffff</resetMask>
                    <fields>
                        <field>
                            <name>ULPTCMB</name>
                            <description>32-bit Compare Match B Data</description>
                            <lsb>0</lsb>
                            <msb>31</msb>
                            <access>read-write</access>
                        </field>
                    </fields>
                </register>
                <register>
                    <name>ULPTCR</name>
                    <description>ULPT Control Register</description>
                    <addressOffset>0x0C</addressOffset>
                    <size>8</size>
                    <access>read-write</access>
                    <resetValue>0x00</resetValue>
                    <resetMask>0xff</resetMask>
                    <fields>
                        <field>
                            <name>TSTART</name>
                            <description>Counter Start</description>
                            <lsb>0</lsb>
                            <msb>0</msb>
                            <access>read-write</access>
                            <enumeratedValues>
                                <enumeratedValue>
                                    <name>0</name>
                                    <description>Stop the counter.</description>
                                    <value>#0</value>
                                </enumeratedValue>
                                <enumeratedValue>
                                    <name>1</name>
                                    <description>Start the counter.</description>
                                    <value>#1</value>
                                </enumeratedValue>
                            </enumeratedValues>
                        </field>
                        <field>
                            <name>TCSTF</name>
                            <description>Counter Status Flag</description>
                            <lsb>1</lsb>
                            <msb>1</msb>
                            <access>read-only</access>
                            <enumeratedValues>
                                <enumeratedValue>
                                    <name>0</name>
                                    <description>Counter stopped</description>
                                    <value>#0</value>
                                </enumeratedValue>
                                <enumeratedValue>
                                    <name>1</name>
                                    <description>Counter running</description>
                                    <value>#1</value>
                                </enumeratedValue>
                            </enumeratedValues>
                        </field>
                        <field>
                            <name>TSTOP</name>
                            <description>Counter Forcible Stop</description>
                            <lsb>2</lsb>
                            <msb>2</msb>
                            <access>write-only</access>
                            <enumeratedValues>
                                <enumeratedValue>
                                    <name>0</name>
                                    <description>Writing is invalid.</description>
                                    <value>#0</value>
                                </enumeratedValue>
                                <enumeratedValue>
                                    <name>1</name>
                                    <description>Stop the counter forcibly.</description>
                                    <value>#1</value>
                                </enumeratedValue>
                            </enumeratedValues>
                        </field>
                        <field>
                            <name>TUNDF</name>
                            <description>Underflow Flag</description>
                            <lsb>5</lsb>
                            <msb>5</msb>
                            <access>read-write</access>
                            <enumeratedValues>
                                <enumeratedValue>
                                    <name>0</name>
                                    <description>No underflow occurred (counter ≠ 0x00000000).</description>
                                    <value>#0</value>
                                </enumeratedValue>
                                <enumeratedValue>
                                    <name>1</name>
                                    <description>Underflow occurred (counter = 0x00000000).</description>
                                    <value>#1</value>
                                </enumeratedValue>
                            </enumeratedValues>
                        </field>
                        <field>
                            <name>TCMAF</name>
                            <description>Compare Match A Flag</description>
                            <lsb>6</lsb>
                            <msb>6</msb>
                            <access>read-write</access>
                            <enumeratedValues>
                                <enumeratedValue>
                                    <name>0</name>
                                    <description>Not matched (counter ≠ ULPTCMA[31:0])</description>
                                    <value>#0</value>
                                </enumeratedValue>
                                <enumeratedValue>
                                    <name>1</name>
                                    <description>Matched (counter = ULPTCMA[31:0])</description>
                                    <value>#1</value>
                                </enumeratedValue>
                            </enumeratedValues>
                        </field>
                        <field>
                            <name>TCMBF</name>
                            <description>Compare Match B Flag</description>
                            <lsb>7</lsb>
                            <msb>7</msb>
                            <access>read-write</access>
                            <enumeratedValues>
                                <enumeratedValue>
                                    <name>0</name>
                                    <description>Not matched (counter ≠ ULPTCMB[31:0])</description>
                                    <value>#0</value>
                                </enumeratedValue>
                                <enumeratedValue>
                                    <name>1</name>
                                    <description>Matched (counter = ULPTCMB[31:0])</description>
                                    <value>#1</value>
                                </enumeratedValue>
                            </enumeratedValues>
                        </field>
                    </fields>
                </register>
                <register>
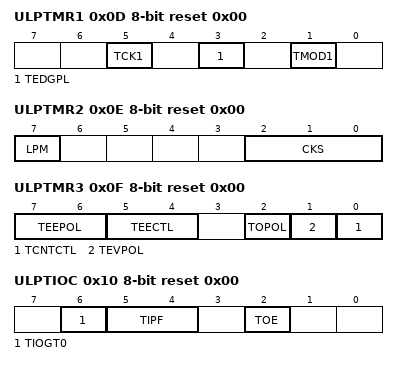
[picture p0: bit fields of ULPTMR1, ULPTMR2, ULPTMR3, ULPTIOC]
                    <name>ULPTMR1</name>
                    <description>ULPT Mode Register 1</description>
                    <addressOffset>0x0D</addressOffset>
                    <size>8</size>
                    <access>read-write</access>
                    <resetValue>0x00</resetValue>
                    <resetMask>0xff</resetMask>
                    <fields>
                        <field>
                            <name>TMOD1</name>
                            <description>Operating Mode</description>
                            <lsb>1</lsb>
                            <msb>1</msb>
                            <access>read-write</access>
                            <enumeratedValues>
                                <enumeratedValue>
                                    <name>0</name>
                                    <description>Timer mode</description>
                                    <value>#0</value>
                                </enumeratedValue>
                                <enumeratedValue>
                                    <name>1</name>
                                    <description>Event counter mode</description>
                                    <value>#1</value>
                                </enumeratedValue>
                            </enumeratedValues>
                        </field>
                        <field>
                            <name>TEDGPL</name>
                            <description>ULPTEVIn Edge Polarity</description>
                            <lsb>3</lsb>
                            <msb>3</msb>
                            <access>read-write</access>
                            <enumeratedValues>
                                <enumeratedValue>
                                    <name>0</name>
                                    <description>Either edge (rising)</description>
                                    <value>#0</value>
                                </enumeratedValue>
                                <enumeratedValue>
                                    <name>1</name>
                                    <description>Both edges</description>
                                    <value>#1</value>
                                </enumeratedValue>
                            </enumeratedValues>
                        </field>
                        <field>
                            <name>TCK1</name>
                            <description>Count Source</description>
                            <lsb>5</lsb>
                            <msb>5</msb>
                            <access>read-write</access>
                            <enumeratedValues>
                                <enumeratedValue>
                                    <name>0</name>
                                    <description>Divided clock specified by the ULPTMR2.CKS[2:0] bits (ULPTLCLK)</description>
                                    <value>#0</value>
                                </enumeratedValue>
                                <enumeratedValue>
                                    <name>1</name>
                                    <description>Divided clock specified by the ULPTMR2.CKS[2:0] bits (ULPTSCLK)</description>
                                    <value>#1</value>
                                </enumeratedValue>
                            </enumeratedValues>
                        </field>
                    </fields>
                </register>
                <register>
                    <name>ULPTMR2</name>
                    <description>ULPT Mode Register 2</description>
                    <addressOffset>0x0E</addressOffset>
                    <size>8</size>
                    <access>read-write</access>
                    <resetValue>0x00</resetValue>
                    <resetMask>0xff</resetMask>
                    <fields>
                        <field>
                            <name>CKS</name>
                            <description>ULPTLCLK/ULPTSCLK Count Source Clock Division Ratio</description>
                            <lsb>0</lsb>
                            <msb>2</msb>
                            <access>read-write</access>
                            <enumeratedValues>
                                <enumeratedValue>
                                    <name>000</name>
                                    <description>1/1</description>
                                    <value>#000</value>
                                </enumeratedValue>
                                <enumeratedValue>
                                    <name>001</name>
                                    <description>1/2</description>
                                    <value>#001</value>
                                </enumeratedValue>
                                <enumeratedValue>
                                    <name>010</name>
                                    <description>1/4</description>
                                    <value>#010</value>
                                </enumeratedValue>
                                <enumeratedValue>
                                    <name>011</name>
                                    <description>1/8</description>
                                    <value>#011</value>
                                </enumeratedValue>
                                <enumeratedValue>
                                    <name>100</name>
                                    <description>1/16</description>
                                    <value>#100</value>
                                </enumeratedValue>
                                <enumeratedValue>
                                    <name>101</name>
                                    <description>1/32</description>
                                    <value>#101</value>
                                </enumeratedValue>
                                <enumeratedValue>
                                    <name>110</name>
                                    <description>1/64</description>
                                    <value>#110</value>
                                </enumeratedValue>
                                <enumeratedValue>
                                    <name>111</name>
                                    <description>1/128</description>
                                    <value>#111</value>
                                </enumeratedValue>
                            </enumeratedValues>
                        </field>
                        <field>
                            <name>LPM</name>
                            <description>Low Power Mode</description>
                            <lsb>7</lsb>
                            <msb>7</msb>
                            <access>read-write</access>
                            <enumeratedValues>
                                <enumeratedValue>
                                    <name>0</name>
                                    <description>Normal mode</description>
                                    <value>#0</value>
                                </enumeratedValue>
                                <enumeratedValue>
                                    <name>1</name>
                                    <description>Low power mode</description>
                                    <value>#1</value>
                                </enumeratedValue>
                            </enumeratedValues>
                        </field>
                    </fields>
                </register>
                <register>
                    <name>ULPTMR3</name>
                    <description>ULPT Mode Register 3</description>
                    <addressOffset>0x0F</addressOffset>
                    <size>8</size>
                    <access>read-write</access>
                    <resetValue>0x00</resetValue>
                    <resetMask>0xff</resetMask>
                    <fields>
                        <field>
                            <name>TCNTCTL</name>
                            <description>Count Function Select</description>
                            <lsb>0</lsb>
                            <msb>0</msb>
                            <access>read-write</access>
                            <enumeratedValues>
                                <enumeratedValue>
                                    <name>0</name>
                                    <description>Continuous mode</description>
                                    <value>#0</value>
                                </enumeratedValue>
                                <enumeratedValue>
                                    <name>1</name>
                                    <description>One-shot mode</description>
                                    <value>#1</value>
                                </enumeratedValue>
                            </enumeratedValues>
                        </field>
                        <field>
                            <name>TEVPOL</name>
                            <description>ULPTEVIn Polarity Switch</description>
                            <lsb>1</lsb>
                            <msb>1</msb>
                            <access>read-write</access>
                            <enumeratedValues>
                                <enumeratedValue>
                                    <name>0</name>
                                    <description>External event input (ULPTEVIn pin)</description>
                                    <value>#0</value>
                                </enumeratedValue>
                                <enumeratedValue>
                                    <name>1</name>
                                    <description>External event input (ULPTEVIn pin) in reverse</description>
                                    <value>#1</value>
                                </enumeratedValue>
                            </enumeratedValues>
                        </field>
                        <field>
                            <name>TOPOL</name>
                            <description>ULPTOn Polarity Select</description>
                            <lsb>2</lsb>
                            <msb>2</msb>
                            <access>read-write</access>
                            <enumeratedValues>
                                <enumeratedValue>
                                    <name>0</name>
                                    <description>Start the ULPTOn output with low level.</description>
                                    <value>#0</value>
                                </enumeratedValue>
                                <enumeratedValue>
                                    <name>1</name>
                                    <description>Start the ULPTOn output with high level.</description>
                                    <value>#1</value>
                                </enumeratedValue>
                            </enumeratedValues>
                        </field>
                        <field>
                            <name>TEECTL</name>
                            <description>ULPTEEn Function Select</description>
                            <lsb>4</lsb>
                            <msb>5</msb>
                            <access>read-write</access>
                            <enumeratedValues>
                                <enumeratedValue>
                                    <name>00</name>
                                    <description>Count enable mode</description>
                                    <value>#00</value>
                                </enumeratedValue>
                                <enumeratedValue>
                                    <name>10</name>
                                    <description>Count start mode</description>
                                    <value>#10</value>
                                </enumeratedValue>
                                <enumeratedValue>
                                    <name>11</name>
                                    <description>Count restart mode</description>
                                    <value>#11</value>
                                </enumeratedValue>
                            </enumeratedValues>
                        </field>
                        <field>
                            <name>TEEPOL</name>
                            <description>ULPTEEn Edge Polarity Select</description>
                            <lsb>6</lsb>
                            <msb>7</msb>
                            <access>read-write</access>
                            <enumeratedValues>
                                <enumeratedValue>
                                    <name>00</name>
                                    <description>Rising edge</description>
                                    <value>#00</value>
                                </enumeratedValue>
                                <enumeratedValue>
                                    <name>01</name>
                                    <description>Falling edge</description>
                                    <value>#01</value>
                                </enumeratedValue>
                                <enumeratedValue>
                                    <name>10</name>
                                    <description>Both edges</description>
                                    <value>#10</value>
                                </enumeratedValue>
                            </enumeratedValues>
                        </field>
                    </fields>
                </register>
                <register>
                    <name>ULPTIOC</name>
                    <description>ULPT I/O Control Register</description>
                    <addressOffset>0x10</addressOffset>
                    <size>8</size>
                    <access>read-write</access>
                    <resetValue>0x00</resetValue>
                    <resetMask>0xff</resetMask>
                    <fields>
                        <field>
                            <name>TOE</name>
                            <description>ULPTOn Output Enable</description>
                            <lsb>2</lsb>
                            <msb>2</msb>
                            <access>read-write</access>
                            <enumeratedValues>
                                <enumeratedValue>
                                    <name>0</name>
                                    <description>Disable the ULPTOn output.</description>
                                    <value>#0</value>
                                </enumeratedValue>
                                <enumeratedValue>
                                    <name>1</name>
                                    <description>Enable the ULPTOn output.</description>
                                    <value>#1</value>
                                </enumeratedValue>
                            </enumeratedValues>
                        </field>
                        <field>
                            <name>TIPF</name>
                            <description>ULPTEVIn Input Filter</description>
                            <lsb>4</lsb>
                            <msb>5</msb>
                            <access>read-write</access>
                            <enumeratedValues>
                                <enumeratedValue>
                                    <name>00</name>
                                    <description>No filter</description>
                                    <value>#00</value>
                                </enumeratedValue>
                                <enumeratedValue>
                                    <name>01</name>
                                    <description>Filter sampling at PCLKB</description>
                                    <value>#01</value>
                                </enumeratedValue>
                                <enumeratedValue>
                                    <name>10</name>
                                    <description>Filter sampling at PCLKB/8</description>
                                    <value>#10</value>
                                </enumeratedValue>
                                <enumeratedValue>
                                    <name>11</name>
                                    <description>Filter sampling at PCLKB/32</description>
                                    <value>#11</value>
                                </enumeratedValue>
                            </enumeratedValues>
                        </field>
                        <field>
                            <name>TIOGT0</name>
                            <description>ULPTEVIn Count Control</description>
                            <lsb>6</lsb>
                            <msb>6</msb>
                            <access>read-write</access>
                            <enumeratedValues>
                                <enumeratedValue>
                                    <name>0</name>
                                    <description>Always count external events.</description>
                                    <value>#0</value>
                                </enumeratedValue>
                                <enumeratedValue>
                                    <name>1</name>
                                    <description>Count external events while the ULPTEVIn pin is valid.</description>
                                    <value>#1</value>
                                </enumeratedValue>
                            </enumeratedValues>
                        </field>
                    </fields>
                </register>
                <register>
                    <name>ULPTISR</name>
                    <description>ULPT Event Pin Select Register</description>
                    <addressOffset>0x11</addressOffset>
                    <size>8</size>
                    <access>read-write</access>
                    <resetValue>0x00</resetValue>
                    <resetMask>0xff</resetMask>
                    <fields>
                        <field>
                            <name>RCCPSEL2</name>
                            <description>ULPTEEn Polarity Select</description>
                            <lsb>2</lsb>
                            <msb>2</msb>
                            <access>read-write</access>
                            <enumeratedValues>
                                <enumeratedValue>
                                    <name>0</name>
                                    <description>Count external events when low level.</description>
                                    <value>#0</value>
                                </enumeratedValue>
                                <enumeratedValue>
                                    <name>1</name>
                                    <description>Count external events when high level.</description>
                                    <value>#1</value>
                                </enumeratedValue>
                            </enumeratedValues>
                        </field>
                    </fields>
                </register>
                <register>
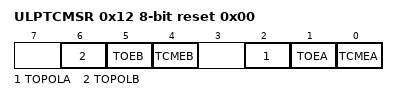
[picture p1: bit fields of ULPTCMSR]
                    <name>ULPTCMSR</name>
                    <description>ULPT Compare Match Function Select Register</description>
                    <addressOffset>0x12</addressOffset>
                    <size>8</size>
                    <access>read-write</access>
                    <resetValue>0x00</resetValue>
                    <resetMask>0xff</resetMask>
                    <fields>
                        <field>
                            <name>TCMEA</name>
                            <description>Compare Match A Register Enable</description>
                            <lsb>0</lsb>
                            <msb>0</msb>
                            <access>read-write</access>
                            <enumeratedValues>
                                <enumeratedValue>
                                    <name>0</name>
                                    <description>Disable compare match A register.</description>
                                    <value>#0</value>
                                </enumeratedValue>
                                <enumeratedValue>
                                    <name>1</name>
                                    <description>Enable compare match A register.</description>
                                    <value>#1</value>
                                </enumeratedValue>
                            </enumeratedValues>
                        </field>
                        <field>
                            <name>TOEA</name>
                            <description>ULPTOAn Output Enable</description>
                            <lsb>1</lsb>
                            <msb>1</msb>
                            <access>read-write</access>
                            <enumeratedValues>
                                <enumeratedValue>
                                    <name>0</name>
                                    <description>Disable the ULPTOAn output.</description>
                                    <value>#0</value>
                                </enumeratedValue>
                                <enumeratedValue>
                                    <name>1</name>
                                    <description>Enable the ULPTOAn output.</description>
                                    <value>#1</value>
                                </enumeratedValue>
                            </enumeratedValues>
                        </field>
                        <field>
                            <name>TOPOLA</name>
                            <description>ULPTOAn Polarity Select</description>
                            <lsb>2</lsb>
                            <msb>2</msb>
                            <access>read-write</access>
                            <enumeratedValues>
                                <enumeratedValue>
                                    <name>0</name>
                                    <description>Start the ULPTOAn output with low.</description>
                                    <value>#0</value>
                                </enumeratedValue>
                                <enumeratedValue>
                                    <name>1</name>
                                    <description>Start the ULPTOAn output with high.</description>
                                    <value>#1</value>
                                </enumeratedValue>
                            </enumeratedValues>
                        </field>
                        <field>
                            <name>TCMEB</name>
                            <description>Compare Match B Register Enable</description>
                            <lsb>4</lsb>
                            <msb>4</msb>
                            <access>read-write</access>
                            <enumeratedValues>
                                <enumeratedValue>
                                    <name>0</name>
                                    <description>Disable compare match B register.</description>
                                    <value>#0</value>
                                </enumeratedValue>
                                <enumeratedValue>
                                    <name>1</name>
                                    <description>Enable compare match B register.</description>
                                    <value>#1</value>
                                </enumeratedValue>
                            </enumeratedValues>
                        </field>
                        <field>
                            <name>TOEB</name>
                            <description>ULPTOBn Output Enable</description>
                            <lsb>5</lsb>
                            <msb>5</msb>
                            <access>read-write</access>
                            <enumeratedValues>
                                <enumeratedValue>
                                    <name>0</name>
                                    <description>Disable the ULPTOBn output.</description>
                                    <value>#0</value>
                                </enumeratedValue>
                                <enumeratedValue>
                                    <name>1</name>
                                    <description>Enable the ULPTOBn output.</description>
                                    <value>#1</value>
                                </enumeratedValue>
                            </enumeratedValues>
                        </field>
                        <field>
                            <name>TOPOLB</name>
                            <description>ULPTOBn Polarity Select</description>
                            <lsb>6</lsb>
                            <msb>6</msb>
                            <access>read-write</access>
                            <enumeratedValues>
                                <enumeratedValue>
                                    <name>0</name>
                                    <description>Start the ULPTOBn output with low.</description>
                                    <value>#0</value>
                                </enumeratedValue>
                                <enumeratedValue>
                                    <name>1</name>
                                    <description>Start the ULPTOBn output with high.</description>
                                    <value>#1</value>
                                </enumeratedValue>
                            </enumeratedValues>
                        </field>
                    </fields>
                </register>
            </registers>
        </peripheral>
        <peripheral derivedFrom="ULPT0_NS">
            <name>ULPT1_NS</name>
            <description>Ultra-Low Power Timer 1</description>
            <baseAddress>0x50220100</baseAddress>
        </peripheral>
        <peripheral>
            <name>AGT0_NS</name>
            <description>Low Power Asynchronous General Purpose Timer 0</description>
            <baseAddress>0x50221000</baseAddress>
            <addressBlock>
                <offset>0x00</offset>
                <size>6</size>
                <usage>registers</usage>
            </addressBlock>
            <addressBlock>
                <offset>0x08</offset>
                <size>3</size>
                <usage>registers</usage>
            </addressBlock>
            <addressBlock>
                <offset>0x0C</offset>
                <size>4</size>
                <usage>registers</usage>
            </addressBlock>
            <registers>
                <register>
                    <name>AGT</name>
                    <description>AGT Counter Register</description>
                    <addressOffset>0x00</addressOffset>
                    <size>16</size>
                    <access>read-write</access>
                    <resetValue>0xffff</resetValue>
                    <resetMask>0xffff</resetMask>
                </register>
                <register>
                    <name>AGTCMA</name>
                    <description>AGT Compare Match A Register</description>
                    <addressOffset>0x02</addressOffset>
                    <size>16</size>
                    <access>read-write</access>
                    <resetValue>0xffff</resetValue>
                    <resetMask>0xffff</resetMask>
                </register>
                <register>
                    <name>AGTCMB</name>
                    <description>AGT Compare Match B Register</description>
                    <addressOffset>0x04</addressOffset>
                    <size>16</size>
                    <access>read-write</access>
                    <resetValue>0xffff</resetValue>
                    <resetMask>0xffff</resetMask>
                </register>
                <register>
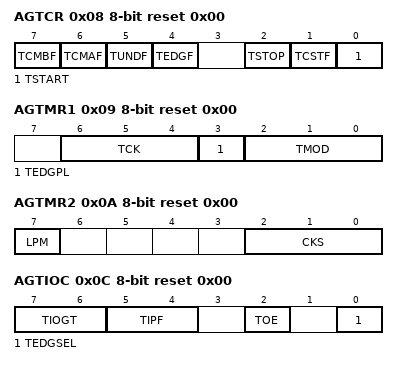
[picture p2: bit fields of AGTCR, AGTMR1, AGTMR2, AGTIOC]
                    <name>AGTCR</name>
                    <description>AGT Control Register</description>
                    <addressOffset>0x08</addressOffset>
                    <size>8</size>
                    <access>read-write</access>
                    <resetValue>0x00</resetValue>
                    <resetMask>0xff</resetMask>
                    <fields>
                        <field>
                            <name>TSTART</name>
                            <description>AGT Count Start</description>
                            <lsb>0</lsb>
                            <msb>0</msb>
                            <access>read-write</access>
                            <enumeratedValues>
                                <enumeratedValue>
                                    <name>0</name>
                                    <description>Count stops</description>
                                    <value>#0</value>
                                </enumeratedValue>
                                <enumeratedValue>
                                    <name>1</name>
                                    <description>Count starts</description>
                                    <value>#1</value>
                                </enumeratedValue>
                            </enumeratedValues>
                        </field>
                        <field>
                            <name>TCSTF</name>
                            <description>AGT Count Status Flag</description>
                            <lsb>1</lsb>
                            <msb>1</msb>
                            <access>read-only</access>
                            <enumeratedValues>
                                <enumeratedValue>
                                    <name>0</name>
                                    <description>Count stopped</description>
                                    <value>#0</value>
                                </enumeratedValue>
                                <enumeratedValue>
                                    <name>1</name>
                                    <description>Count in progress</description>
                                    <value>#1</value>
                                </enumeratedValue>
                            </enumeratedValues>
                        </field>
                        <field>
                            <name>TSTOP</name>
                            <description>AGT Count Forced Stop</description>
                            <lsb>2</lsb>
                            <msb>2</msb>
                            <access>write-only</access>
                            <enumeratedValues>
                                <enumeratedValue>
                                    <name>0</name>
                                    <description>Writing is invalid</description>
                                    <value>#0</value>
                                </enumeratedValue>
                                <enumeratedValue>
                                    <name>1</name>
                                    <description>The count is forcibly stopped</description>
                                    <value>#1</value>
                                </enumeratedValue>
                            </enumeratedValues>
                        </field>
                        <field>
                            <name>TEDGF</name>
                            <description>Active Edge Judgment Flag</description>
                            <lsb>4</lsb>
                            <msb>4</msb>
                            <access>read-write</access>
                            <enumeratedValues>
                                <enumeratedValue>
                                    <name>0</name>
                                    <description>No active edge received</description>
                                    <value>#0</value>
                                </enumeratedValue>
                                <enumeratedValue>
                                    <name>1</name>
                                    <description>Active edge received</description>
                                    <value>#1</value>
                                </enumeratedValue>
                            </enumeratedValues>
                        </field>
                        <field>
                            <name>TUNDF</name>
                            <description>Underflow Flag</description>
                            <lsb>5</lsb>
                            <msb>5</msb>
                            <access>read-write</access>
                            <enumeratedValues>
                                <enumeratedValue>
                                    <name>0</name>
                                    <description>No underflow</description>
                                    <value>#0</value>
                                </enumeratedValue>
                                <enumeratedValue>
                                    <name>1</name>
                                    <description>Underflow</description>
                                    <value>#1</value>
                                </enumeratedValue>
                            </enumeratedValues>
                        </field>
                        <field>
                            <name>TCMAF</name>
                            <description>Compare Match A Flag</description>
                            <lsb>6</lsb>
                            <msb>6</msb>
                            <access>read-write</access>
                            <enumeratedValues>
                                <enumeratedValue>
                                    <name>0</name>
                                    <description>No match</description>
                                    <value>#0</value>
                                </enumeratedValue>
                                <enumeratedValue>
                                    <name>1</name>
                                    <description>Match</description>
                                    <value>#1</value>
                                </enumeratedValue>
                            </enumeratedValues>
                        </field>
                        <field>
                            <name>TCMBF</name>
                            <description>Compare Match B Flag</description>
                            <lsb>7</lsb>
                            <msb>7</msb>
                            <access>read-write</access>
                            <enumeratedValues>
                                <enumeratedValue>
                                    <name>0</name>
                                    <description>No match</description>
                                    <value>#0</value>
                                </enumeratedValue>
                                <enumeratedValue>
                                    <name>1</name>
                                    <description>Match</description>
                                    <value>#1</value>
                                </enumeratedValue>
                            </enumeratedValues>
                        </field>
                    </fields>
                </register>
                <register>
                    <name>AGTMR1</name>
                    <description>AGT Mode Register 1</description>
                    <addressOffset>0x09</addressOffset>
                    <size>8</size>
                    <access>read-write</access>
                    <resetValue>0x00</resetValue>
                    <resetMask>0xff</resetMask>
                    <fields>
                        <field>
                            <name>TMOD</name>
                            <description>Operating Mode</description>
                            <lsb>0</lsb>
                            <msb>2</msb>
                            <access>read-write</access>
                            <enumeratedValues>
                                <enumeratedValue>
                                    <name>000</name>
                                    <description>Timer mode</description>
                                    <value>#000</value>
                                </enumeratedValue>
                                <enumeratedValue>
                                    <name>001</name>
                                    <description>Pulse output mode</description>
                                    <value>#001</value>
                                </enumeratedValue>
                                <enumeratedValue>
                                    <name>010</name>
                                    <description>Event counter mode</description>
                                    <value>#010</value>
                                </enumeratedValue>
                                <enumeratedValue>
                                    <name>011</name>
                                    <description>Pulse width measurement mode</description>
                                    <value>#011</value>
                                </enumeratedValue>
                                <enumeratedValue>
                                    <name>100</name>
                                    <description>Pulse period measurement mode</description>
                                    <value>#100</value>
                                </enumeratedValue>
                                <enumeratedValue>
                                    <name>Others</name>
                                    <description>Setting prohibited</description>
                                    <isDefault>true</isDefault>
                                </enumeratedValue>
                            </enumeratedValues>
                        </field>
                        <field>
                            <name>TEDGPL</name>
                            <description>Edge Polarity</description>
                            <lsb>3</lsb>
                            <msb>3</msb>
                            <access>read-write</access>
                            <enumeratedValues>
                                <enumeratedValue>
                                    <name>0</name>
                                    <description>Single-edge</description>
                                    <value>#0</value>
                                </enumeratedValue>
                                <enumeratedValue>
                                    <name>1</name>
                                    <description>Both-edge</description>
                                    <value>#1</value>
                                </enumeratedValue>
                            </enumeratedValues>
                        </field>
                        <field>
                            <name>TCK</name>
                            <description>Count Source</description>
                            <lsb>4</lsb>
                            <msb>6</msb>
                            <access>read-write</access>
                            <enumeratedValues>
                                <enumeratedValue>
                                    <name>000</name>
                                    <description>PCLKB</description>
                                    <value>#000</value>
                                </enumeratedValue>
                                <enumeratedValue>
                                    <name>001</name>
                                    <description>PCLKB/8</description>
                                    <value>#001</value>
                                </enumeratedValue>
                                <enumeratedValue>
                                    <name>011</name>
                                    <description>PCLKB/2</description>
                                    <value>#011</value>
                                </enumeratedValue>
                                <enumeratedValue>
                                    <name>100</name>
                                    <description>Divided clock AGTLCLK specified by CKS[2:0] bits in the AGTMR2 register</description>
                                    <value>#100</value>
                                </enumeratedValue>
                                <enumeratedValue>
                                    <name>101</name>
                                    <description>Underflow event signal from AGT0</description>
                                    <value>#101</value>
                                </enumeratedValue>
                                <enumeratedValue>
                                    <name>110</name>
                                    <description>Divided clock AGTSCLK specified by CKS[2:0] bits in the AGTMR2 register</description>
                                    <value>#110</value>
                                </enumeratedValue>
                                <enumeratedValue>
                                    <name>Others</name>
                                    <description>Setting prohibited</description>
                                    <isDefault>true</isDefault>
                                </enumeratedValue>
                            </enumeratedValues>
                        </field>
                    </fields>
                </register>
                <register>
                    <name>AGTMR2</name>
                    <description>AGT Mode Register 2</description>
                    <addressOffset>0x0A</addressOffset>
                    <size>8</size>
                    <access>read-write</access>
                    <resetValue>0x00</resetValue>
                    <resetMask>0xff</resetMask>
                    <fields>
                        <field>
                            <name>CKS</name>
                            <description>AGTLCLK or AGTSCLK Count Source Clock Frequency Division Ratio</description>
                            <lsb>0</lsb>
                            <msb>2</msb>
                            <access>read-write</access>
                            <enumeratedValues>
                                <enumeratedValue>
                                    <name>000</name>
                                    <description>1/1</description>
                                    <value>#000</value>
                                </enumeratedValue>
                                <enumeratedValue>
                                    <name>001</name>
                                    <description>1/2</description>
                                    <value>#001</value>
                                </enumeratedValue>
                                <enumeratedValue>
                                    <name>010</name>
                                    <description>1/4</description>
                                    <value>#010</value>
                                </enumeratedValue>
                                <enumeratedValue>
                                    <name>011</name>
                                    <description>1/8</description>
                                    <value>#011</value>
                                </enumeratedValue>
                                <enumeratedValue>
                                    <name>100</name>
                                    <description>1/16</description>
                                    <value>#100</value>
                                </enumeratedValue>
                                <enumeratedValue>
                                    <name>101</name>
                                    <description>1/32</description>
                                    <value>#101</value>
                                </enumeratedValue>
                                <enumeratedValue>
                                    <name>110</name>
                                    <description>1/64</description>
                                    <value>#110</value>
                                </enumeratedValue>
                                <enumeratedValue>
                                    <name>111</name>
                                    <description>1/128</description>
                                    <value>#111</value>
                                </enumeratedValue>
                            </enumeratedValues>
                        </field>
                        <field>
                            <name>LPM</name>
                            <description>Low Power Mode</description>
                            <lsb>7</lsb>
                            <msb>7</msb>
                            <access>read-write</access>
                            <enumeratedValues>
                                <enumeratedValue>
                                    <name>0</name>
                                    <description>Normal mode</description>
                                    <value>#0</value>
                                </enumeratedValue>
                                <enumeratedValue>
                                    <name>1</name>
                                    <description>Low power mode</description>
                                    <value>#1</value>
                                </enumeratedValue>
                            </enumeratedValues>
                        </field>
                    </fields>
                </register>
                <register>
                    <name>AGTIOC</name>
                    <description>AGT I/O Control Register</description>
                    <addressOffset>0x0C</addressOffset>
                    <size>8</size>
                    <access>read-write</access>
                    <resetValue>0x00</resetValue>
                    <resetMask>0xff</resetMask>
                    <fields>
                        <field>
                            <name>TEDGSEL</name>
                            <description>I/O Polarity Switch</description>
                            <lsb>0</lsb>
                            <msb>0</msb>
                            <access>read-write</access>
                        </field>
                        <field>
                            <name>TOE</name>
                            <description>AGTOn pin Output Enable</description>
                            <lsb>2</lsb>
                            <msb>2</msb>
                            <access>read-write</access>
                            <enumeratedValues>
                                <enumeratedValue>
                                    <name>0</name>
                                    <description>AGTOn pin output disabled</description>
                                    <value>#0</value>
                                </enumeratedValue>
                                <enumeratedValue>
                                    <name>1</name>
                                    <description>AGTOn pin output enabled</description>
                                    <value>#1</value>
                                </enumeratedValue>
                            </enumeratedValues>
                        </field>
                        <field>
                            <name>TIPF</name>
                            <description>Input Filter</description>
                            <lsb>4</lsb>
                            <msb>5</msb>
                            <access>read-write</access>
                            <enumeratedValues>
                                <enumeratedValue>
                                    <name>00</name>
                                    <description>No filter</description>
                                    <value>#00</value>
                                </enumeratedValue>
                                <enumeratedValue>
                                    <name>01</name>
                                    <description>Filter sampled at PCLKB</description>
                                    <value>#01</value>
                                </enumeratedValue>
                                <enumeratedValue>
                                    <name>10</name>
                                    <description>Filter sampled at PCLKB/8</description>
                                    <value>#10</value>
                                </enumeratedValue>
                                <enumeratedValue>
                                    <name>11</name>
                                    <description>Filter sampled at PCLKB/32</description>
                                    <value>#11</value>
                                </enumeratedValue>
                            </enumeratedValues>
                        </field>
                        <field>
                            <name>TIOGT</name>
                            <description>Count Control</description>
                            <lsb>6</lsb>
                            <msb>7</msb>
                            <access>read-write</access>
                            <enumeratedValues>
                                <enumeratedValue>
                                    <name>00</name>
                                    <description>Event is always counted</description>
                                    <value>#00</value>
                                </enumeratedValue>
                                <enumeratedValue>
                                    <name>01</name>
                                    <description>Event is counted during polarity period specified for AGTEEn pin</description>
                                    <value>#01</value>
                                </enumeratedValue>
                                <enumeratedValue>
                                    <name>Others</name>
                                    <description>Setting prohibited</description>
                                    <isDefault>true</isDefault>
                                </enumeratedValue>
                            </enumeratedValues>
                        </field>
                    </fields>
                </register>
                <register>
                    <name>AGTISR</name>
                    <description>AGT Event Pin Select Register</description>
                    <addressOffset>0x0D</addressOffset>
                    <size>8</size>
                    <access>read-write</access>
                    <resetValue>0x00</resetValue>
                    <resetMask>0xff</resetMask>
                    <fields>
                        <field>
                            <name>EEPS</name>
                            <description>AGTEEn Polarity Selection</description>
                            <lsb>2</lsb>
                            <msb>2</msb>
                            <access>read-write</access>
                            <enumeratedValues>
                                <enumeratedValue>
                                    <name>0</name>
                                    <description>An event is counted during the low-level period</description>
                                    <value>#0</value>
                                </enumeratedValue>
                                <enumeratedValue>
                                    <name>1</name>
                                    <description>An event is counted during the high-level period</description>
                                    <value>#1</value>
                                </enumeratedValue>
                            </enumeratedValues>
                        </field>
                    </fields>
                </register>
                <register>
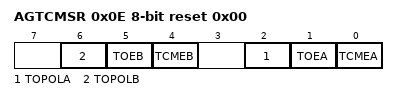
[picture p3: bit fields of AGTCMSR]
                    <name>AGTCMSR</name>
                    <description>AGT Compare Match Function Select Register</description>
                    <addressOffset>0x0E</addressOffset>
                    <size>8</size>
                    <access>read-write</access>
                    <resetValue>0x00</resetValue>
                    <resetMask>0xff</resetMask>
                    <fields>
                        <field>
                            <name>TCMEA</name>
                            <description>AGT Compare Match A Register Enable</description>
                            <lsb>0</lsb>
                            <msb>0</msb>
                            <access>read-write</access>
                            <enumeratedValues>
                                <enumeratedValue>
                                    <name>0</name>
                                    <description>AGT Compare match A register disabled</description>
                                    <value>#0</value>
                                </enumeratedValue>
                                <enumeratedValue>
                                    <name>1</name>
                                    <description>AGT Compare match A register enabled</description>
                                    <value>#1</value>
                                </enumeratedValue>
                            </enumeratedValues>
                        </field>
                        <field>
                            <name>TOEA</name>
                            <description>AGTOAn Pin Output Enable</description>
                            <lsb>1</lsb>
                            <msb>1</msb>
                            <access>read-write</access>
                            <enumeratedValues>
                                <enumeratedValue>
                                    <name>0</name>
                                    <description>AGTOAn pin output disabled</description>
                                    <value>#0</value>
                                </enumeratedValue>
                                <enumeratedValue>
                                    <name>1</name>
                                    <description>AGTOAn pin output enabled</description>
                                    <value>#1</value>
                                </enumeratedValue>
                            </enumeratedValues>
                        </field>
                        <field>
                            <name>TOPOLA</name>
                            <description>AGTOAn Pin Polarity Select</description>
                            <lsb>2</lsb>
                            <msb>2</msb>
                            <access>read-write</access>
                            <enumeratedValues>
                                <enumeratedValue>
                                    <name>0</name>
                                    <description>AGTOAn pin output is started on low. i.e. normal output</description>
                                    <value>#0</value>
                                </enumeratedValue>
                                <enumeratedValue>
                                    <name>1</name>
                                    <description>AGTOAn pin output is started on high. i.e. inverted output</description>
                                    <value>#1</value>
                                </enumeratedValue>
                            </enumeratedValues>
                        </field>
                        <field>
                            <name>TCMEB</name>
                            <description>AGT Compare Match B Register Enable</description>
                            <lsb>4</lsb>
                            <msb>4</msb>
                            <access>read-write</access>
                            <enumeratedValues>
                                <enumeratedValue>
                                    <name>0</name>
                                    <description>Compare match B register disabled</description>
                                    <value>#0</value>
                                </enumeratedValue>
                                <enumeratedValue>
                                    <name>1</name>
                                    <description>Compare match B register enabled</description>
                                    <value>#1</value>
                                </enumeratedValue>
                            </enumeratedValues>
                        </field>
                        <field>
                            <name>TOEB</name>
                            <description>AGTOBn Pin Output Enable</description>
                            <lsb>5</lsb>
                            <msb>5</msb>
                            <access>read-write</access>
                            <enumeratedValues>
                                <enumeratedValue>
                                    <name>0</name>
                                    <description>AGTOBn pin output disabled</description>
                                    <value>#0</value>
                                </enumeratedValue>
                                <enumeratedValue>
                                    <name>1</name>
                                    <description>AGTOBn pin output enabled</description>
                                    <value>#1</value>
                                </enumeratedValue>
                            </enumeratedValues>
                        </field>
                        <field>
                            <name>TOPOLB</name>
                            <description>AGTOBn Pin Polarity Select</description>
                            <lsb>6</lsb>
                            <msb>6</msb>
                            <access>read-write</access>
                            <enumeratedValues>
                                <enumeratedValue>
                                    <name>0</name>
                                    <description>AGTOBn pin output is started on low. i.e. normal output</description>
                                    <value>#0</value>
                                </enumeratedValue>
                                <enumeratedValue>
                                    <name>1</name>
                                    <description>AGTOBn pin output is started on high. i.e. inverted output</description>
                                    <value>#1</value>
                                </enumeratedValue>
                            </enumeratedValues>
                        </field>
                    </fields>
                </register>
                <register>
                    <name>AGTIOSEL</name>
                    <description>AGT Pin Select Register</description>
                    <addressOffset>0x0F</addressOffset>
                    <size>8</size>
                    <access>read-write</access>
                    <resetValue>0x00</resetValue>
                    <resetMask>0xff</resetMask>
                    <fields>
                        <field>
                            <name>TIES</name>
                            <description>AGTIOn Pin Input Enable</description>
                            <lsb>4</lsb>
                            <msb>4</msb>
                            <access>read-write</access>
                            <enumeratedValues>
                                <enumeratedValue>
                                    <name>0</name>
                                    <description>External event input is disabled during Software Standby mode</description>
                                    <value>#0</value>
                                </enumeratedValue>
                                <enumeratedValue>
                                    <name>1</name>
                                    <description>External event input is enabled during Software Standby mode</description>
                                    <value>#1</value>
                                </enumeratedValue>
                            </enumeratedValues>
                        </field>
                    </fields>
                </register>
            </registers>
        </peripheral>
        <peripheral derivedFrom="AGT0_NS">
            <name>AGT1_NS</name>
            <description>Low Power Asynchronous General Purpose Timer 1</description>
            <baseAddress>0x50221100</baseAddress>
        </peripheral>
        <peripheral>
            <name>TSN_NS</name>
            <description>Temperature Sensor</description>
            <baseAddress>0x50235000</baseAddress>
            <addressBlock>
                <offset>0x00</offset>
                <size>1</size>
                <usage>registers</usage>
            </addressBlock>
            <registers>
                <register>
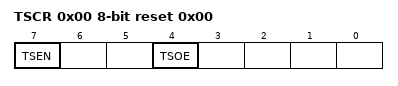
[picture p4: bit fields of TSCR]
                    <name>TSCR</name>
                    <description>Temperature Sensor Control Register</description>
                    <addressOffset>0x00</addressOffset>
                    <size>8</size>
                    <access>read-write</access>
                    <resetValue>0x00</resetValue>
                    <resetMask>0xff</resetMask>
                    <fields>
                        <field>
                            <name>TSOE</name>
                            <description>Temperature Sensor Output Enable</description>
                            <lsb>4</lsb>
                            <msb>4</msb>
                            <access>read-write</access>
                            <enumeratedValues>
                                <enumeratedValue>
                                    <name>0</name>
                                    <description>Disable output from the temperature sensor to the ADC12</description>
                                    <value>#0</value>
                                </enumeratedValue>
                                <enumeratedValue>
                                    <name>1</name>
                                    <description>Enable output from the temperature sensor to the ADC12</description>
                                    <value>#1</value>
                                </enumeratedValue>
                            </enumeratedValues>
                        </field>
                        <field>
                            <name>TSEN</name>
                            <description>Temperature Sensor Enable</description>
                            <lsb>7</lsb>
                            <msb>7</msb>
                            <access>read-write</access>
                            <enumeratedValues>
                                <enumeratedValue>
                                    <name>0</name>
                                    <description>Stop the temperature sensor</description>
                                    <value>#0</value>
                                </enumeratedValue>
                                <enumeratedValue>
                                    <name>1</name>
                                    <description>Start the temperature sensor.</description>
                                    <value>#1</value>
                                </enumeratedValue>
                            </enumeratedValues>
                        </field>
                    </fields>
                </register>
            </registers>
        </peripheral>
        <peripheral>
            <name>ACMPHS0_NS</name>
            <description>High-Speed Analog Comparator 0</description>
            <baseAddress>0x50236000</baseAddress>
            <addressBlock>
                <offset>0x00</offset>
                <size>1</size>
                <usage>registers</usage>
            </addressBlock>
            <addressBlock>
                <offset>0x04</offset>
                <size>1</size>
                <usage>registers</usage>
            </addressBlock>
            <addressBlock>
                <offset>0x08</offset>
                <size>1</size>
                <usage>registers</usage>
            </addressBlock>
            <addressBlock>
                <offset>0x0C</offset>
                <size>1</size>
                <usage>registers</usage>
            </addressBlock>
            <addressBlock>
                <offset>0x10</offset>
                <size>1</size>
                <usage>registers</usage>
            </addressBlock>
            <addressBlock>
                <offset>0x40</offset>
                <size>1</size>
                <usage>registers</usage>
            </addressBlock>
            <addressBlock>
                <offset>0x44</offset>
                <size>1</size>
                <usage>registers</usage>
            </addressBlock>
            <registers>
                <register>
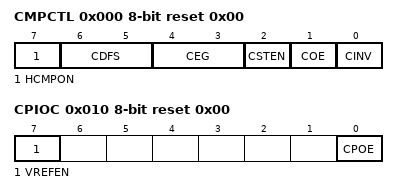
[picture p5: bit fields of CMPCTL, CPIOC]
                    <name>CMPCTL</name>
                    <description>Comparator Control Register</description>
                    <addressOffset>0x000</addressOffset>
                    <size>8</size>
                    <access>read-write</access>
                    <resetValue>0x00</resetValue>
                    <resetMask>0xff</resetMask>
                    <fields>
                        <field>
                            <name>CINV</name>
                            <description>Comparator Output Polarity Selection</description>
                            <lsb>0</lsb>
                            <msb>0</msb>
                            <access>read-write</access>
                            <enumeratedValues>
                                <enumeratedValue>
                                    <name>0</name>
                                    <description>Do not invert comparator output</description>
                                    <value>#0</value>
                                </enumeratedValue>
                                <enumeratedValue>
                                    <name>1</name>
                                    <description>Invert comparator output</description>
                                    <value>#1</value>
                                </enumeratedValue>
                            </enumeratedValues>
                        </field>
                        <field>
                            <name>COE</name>
                            <description>Comparator Output Enable</description>
                            <lsb>1</lsb>
                            <msb>1</msb>
                            <access>read-write</access>
                            <enumeratedValues>
                                <enumeratedValue>
                                    <name>0</name>
                                    <description>Disable comparator output (output signal is low level)</description>
                                    <value>#0</value>
                                </enumeratedValue>
                                <enumeratedValue>
                                    <name>1</name>
                                    <description>Enable comparator output</description>
                                    <value>#1</value>
                                </enumeratedValue>
                            </enumeratedValues>
                        </field>
                        <field>
                            <name>CSTEN</name>
                            <description>Interrupt Select</description>
                            <lsb>2</lsb>
                            <msb>2</msb>
                            <access>read-write</access>
                            <enumeratedValues>
                                <enumeratedValue>
                                    <name>0</name>
                                    <description>Output through the edge selector</description>
                                    <value>#0</value>
                                </enumeratedValue>
                                <enumeratedValue>
                                    <name>1</name>
                                    <description>Output directly</description>
                                    <value>#1</value>
                                </enumeratedValue>
                            </enumeratedValues>
                        </field>
                        <field>
                            <name>CEG</name>
                            <description>Selection of Valid Edge (Edge Selector)</description>
                            <lsb>3</lsb>
                            <msb>4</msb>
                            <access>read-write</access>
                            <enumeratedValues>
                                <enumeratedValue>
                                    <name>00</name>
                                    <description>Do not detect edge</description>
                                    <value>#00</value>
                                </enumeratedValue>
                                <enumeratedValue>
                                    <name>01</name>
                                    <description>Detect rising edge</description>
                                    <value>#01</value>
                                </enumeratedValue>
                                <enumeratedValue>
                                    <name>10</name>
                                    <description>Detect falling edge</description>
                                    <value>#10</value>
                                </enumeratedValue>
                                <enumeratedValue>
                                    <name>11</name>
                                    <description>Detect both edges</description>
                                    <value>#11</value>
                                </enumeratedValue>
                            </enumeratedValues>
                        </field>
                        <field>
                            <name>CDFS</name>
                            <description>Noise Filter Selection</description>
                            <lsb>5</lsb>
                            <msb>6</msb>
                            <access>read-write</access>
                            <enumeratedValues>
                                <enumeratedValue>
                                    <name>00</name>
                                    <description>Do not use noise filter</description>
                                    <value>#00</value>
                                </enumeratedValue>
                                <enumeratedValue>
                                    <name>01</name>
                                    <description>Use noise filter sampling frequency of PCLKB/23</description>
                                    <value>#01</value>
                                </enumeratedValue>
                                <enumeratedValue>
                                    <name>10</name>
                                    <description>Use noise filter sampling frequency of PCLKB/24</description>
                                    <value>#10</value>
                                </enumeratedValue>
                                <enumeratedValue>
                                    <name>11</name>
                                    <description>Use noise filter sampling frequency of PCLKB/25</description>
                                    <value>#11</value>
                                </enumeratedValue>
                            </enumeratedValues>
                        </field>
                        <field>
                            <name>HCMPON</name>
                            <description>Comparator Operation Control</description>
                            <lsb>7</lsb>
                            <msb>7</msb>
                            <access>read-write</access>
                            <enumeratedValues>
                                <enumeratedValue>
                                    <name>0</name>
                                    <description>Stop operation (comparator outputs a low-level signal)</description>
                                    <value>#0</value>
                                </enumeratedValue>
                                <enumeratedValue>
                                    <name>1</name>
                                    <description>Enable operation (enables input to the comparator pins)</description>
                                    <value>#1</value>
                                </enumeratedValue>
                            </enumeratedValues>
                        </field>
                    </fields>
                </register>
                <register>
                    <name>CMPSEL0</name>
                    <description>Comparator Input Select Register</description>
                    <addressOffset>0x004</addressOffset>
                    <size>8</size>
                    <access>read-write</access>
                    <resetValue>0x00</resetValue>
                    <resetMask>0xff</resetMask>
                    <fields>
                        <field>
                            <name>CMPSEL</name>
                            <description>Comparator Input Selection</description>
                            <lsb>0</lsb>
                            <msb>3</msb>
                            <access>read-write</access>
                            <enumeratedValues>
                                <enumeratedValue>
                                    <name>0x00</name>
                                    <description>Do not input</description>
                                    <value>0x00</value>
                                </enumeratedValue>
                                <enumeratedValue>
                                    <name>0x01</name>
                                    <description>Select IVCMP0</description>
                                    <value>0x01</value>
                                </enumeratedValue>
                                <enumeratedValue>
                                    <name>0x04</name>
                                    <description>Select IVCMP2</description>
                                    <value>0x04</value>
                                </enumeratedValue>
                                <enumeratedValue>
                                    <name>0x08</name>
                                    <description>Select IVCMP3</description>
                                    <value>0x08</value>
                                </enumeratedValue>
                                <enumeratedValue>
                                    <name>Others</name>
                                    <description>Setting prohibited</description>
                                    <isDefault>true</isDefault>
                                </enumeratedValue>
                            </enumeratedValues>
                        </field>
                    </fields>
                </register>
                <register>
                    <name>CMPSEL1</name>
                    <description>Comparator Reference Voltage Select Register</description>
                    <addressOffset>0x008</addressOffset>
                    <size>8</size>
                    <access>read-write</access>
                    <resetValue>0x00</resetValue>
                    <resetMask>0xff</resetMask>
                    <fields>
                        <field>
                            <name>CRVS</name>
                            <description>Reference Voltage Selection</description>
                            <lsb>0</lsb>
                            <msb>3</msb>
                            <access>read-write</access>
                            <enumeratedValues>
                                <enumeratedValue>
                                    <name>0x00</name>
                                    <description>Do not input</description>
                                    <value>0x00</value>
                                </enumeratedValue>
                                <enumeratedValue>
                                    <name>0x01</name>
                                    <description>Select IVREF0</description>
                                    <value>0x01</value>
                                </enumeratedValue>
                                <enumeratedValue>
                                    <name>0x02</name>
                                    <description>Select IVREF1</description>
                                    <value>0x02</value>
                                </enumeratedValue>
                                <enumeratedValue>
                                    <name>0x04</name>
                                    <description>Select IVREF2</description>
                                    <value>0x04</value>
                                </enumeratedValue>
                                <enumeratedValue>
                                    <name>0x08</name>
                                    <description>Select IVREF3</description>
                                    <value>0x08</value>
                                </enumeratedValue>
                                <enumeratedValue>
                                    <name>Others</name>
                                    <description>Setting prohibited</description>
                                    <isDefault>true</isDefault>
                                </enumeratedValue>
                            </enumeratedValues>
                        </field>
                    </fields>
                </register>
                <register>
                    <name>CMPMON</name>
                    <description>Comparator Output Monitor Register</description>
                    <addressOffset>0x00C</addressOffset>
                    <size>8</size>
                    <access>read-only</access>
                    <resetValue>0x00</resetValue>
                    <resetMask>0xff</resetMask>
                    <fields>
                        <field>
                            <name>COMPMON</name>
                            <description>Comparator Output Monitor</description>
                            <lsb>0</lsb>
                            <msb>0</msb>
                            <access>read-only</access>
                            <enumeratedValues>
                                <enumeratedValue>
                                    <name>0</name>
                                    <description>Comparator output is low</description>
                                    <value>#0</value>
                                </enumeratedValue>
                                <enumeratedValue>
                                    <name>1</name>
                                    <description>Comparator output is high</description>
                                    <value>#1</value>
                                </enumeratedValue>
                            </enumeratedValues>
                        </field>
                    </fields>
                </register>
                <register>
                    <name>CPIOC</name>
                    <description>Comparator Output Control Register</description>
                    <addressOffset>0x010</addressOffset>
                    <size>8</size>
                    <access>read-write</access>
                    <resetValue>0x00</resetValue>
                    <resetMask>0xff</resetMask>
                    <fields>
                        <field>
                            <name>CPOE</name>
                            <description>External Pin Output Enable</description>
                            <lsb>0</lsb>
                            <msb>0</msb>
                            <access>read-write</access>
                            <enumeratedValues>
                                <enumeratedValue>
                                    <name>0</name>
                                    <description>Output to the comparator external pin is disabled (the output signal is fixed to low)</description>
                                    <value>#0</value>
                                </enumeratedValue>
                                <enumeratedValue>
                                    <name>1</name>
                                    <description>Output to the comparator external pin is enabled</description>
                                    <value>#1</value>
                                </enumeratedValue>
                            </enumeratedValues>
                        </field>
                        <field>
                            <name>VREFEN</name>
                            <lsb>7</lsb>
                            <msb>7</msb>
                            <access>read-write</access>
                            <enumeratedValues>
                                <enumeratedValue>
                                    <name>0</name>
                                    <description>Disable internal Vref</description>
                                    <value>#0</value>
                                </enumeratedValue>
                                <enumeratedValue>
                                    <name>1</name>
                                    <description>Enable internal Vref</description>
                                    <value>#1</value>
                                </enumeratedValue>
                            </enumeratedValues>
                        </field>
                    </fields>
                </register>
                <register>
                    <name>CPINTCTL</name>
                    <description>Comparator Interrupt Control Register</description>
                    <addressOffset>0x040</addressOffset>
                    <size>8</size>
                    <access>read-write</access>
                    <resetValue>0x00</resetValue>
                    <resetMask>0xff</resetMask>
                    <fields>
                        <field>
                            <name>MSKE</name>
                            <description>Comparator Interrupt Periodic Mask Enable</description>
                            <lsb>0</lsb>
                            <msb>0</msb>
                            <access>read-write</access>
                            <enumeratedValues>
                                <enumeratedValue>
                                    <name>0</name>
                                    <description>Disable interrupt masking (Default)</description>
                                    <value>#0</value>
                                </enumeratedValue>
                                <enumeratedValue>
                                    <name>1</name>
                                    <description>Enable interrupt masking by GPT output signal selected by CPMSKCTL.MSKSEL[2:0]</description>
                                    <value>#1</value>
                                </enumeratedValue>
                            </enumeratedValues>
                        </field>
                    </fields>
                </register>
                <register>
                    <name>CPMSKCTL</name>
                    <description>Comparator Interrupt Mask Control Register</description>
                    <addressOffset>0x044</addressOffset>
                    <size>8</size>
                    <access>read-write</access>
                    <resetValue>0x00</resetValue>
                    <resetMask>0xff</resetMask>
                    <fields>
                        <field>
                            <name>MSKSEL</name>
                            <description>Comparator Interrupt Periodic Mask Selection</description>
                            <lsb>0</lsb>
                            <msb>2</msb>
                            <access>read-write</access>
                            <enumeratedValues>
                                <enumeratedValue>
                                    <name>000</name>
                                    <description>Enable interrupt masking by GTIOC0A output signal</description>
                                    <value>#000</value>
                                </enumeratedValue>
                                <enumeratedValue>
                                    <name>001</name>
                                    <description>Enable interrupt masking by GTIOC1A output signal</description>
                                    <value>#001</value>
                                </enumeratedValue>
                                <enumeratedValue>
                                    <name>010</name>
                                    <description>Enable interrupt masking by GTIOC2A output signal</description>
                                    <value>#010</value>
                                </enumeratedValue>
                                <enumeratedValue>
                                    <name>011</name>
                                    <description>Enable interrupt masking by GTIOC3A output signal</description>
                                    <value>#011</value>
                                </enumeratedValue>
                                <enumeratedValue>
                                    <name>100</name>
                                    <description>Enable interrupt masking by GTIOC4A output signal</description>
                                    <value>#100</value>
                                </enumeratedValue>
                                <enumeratedValue>
                                    <name>101</name>
                                    <description>Enable interrupt masking by GTIOC5A output signal</description>
                                    <value>#101</value>
                                </enumeratedValue>
                                <enumeratedValue>
                                    <name>Others</name>
                                    <description>Setting prohibited.</description>
                                    <isDefault>true</isDefault>
                                </enumeratedValue>
                            </enumeratedValues>
                        </field>
                    </fields>
                </register>
            </registers>
        </peripheral>
        <peripheral derivedFrom="ACMPHS0_NS">
            <name>ACMPHS1_NS</name>
            <description>High-Speed Analog Comparator 1</description>
            <baseAddress>0x50236100</baseAddress>
        </peripheral>
        <peripheral>
            <name>USBFS_NS</name>
            <description>USB 2.0 FS Module</description>
            <baseAddress>0x50250000</baseAddress>
            <addressBlock>
                <offset>0x00</offset>
                <size>2</size>
                <usage>registers</usage>
            </addressBlock>
            <addressBlock>
                <offset>0x04</offset>
                <size>2</size>
                <usage>registers</usage>
            </addressBlock>
            <addressBlock>
                <offset>0x08</offset>
                <size>2</size>
                <usage>registers</usage>
            </addressBlock>
            <addressBlock>
                <offset>0x14</offset>
                <size>2</size>
                <usage>registers</usage>
            </addressBlock>
            <addressBlock>
                <offset>0x18</offset>
                <size>12</size>
                <usage>registers</usage>
            </addressBlock>
            <addressBlock>
                <offset>0x28</offset>
                <size>12</size>
                <usage>registers</usage>
            </addressBlock>
            <addressBlock>
                <offset>0x36</offset>
                <size>8</size>
                <usage>registers</usage>
            </addressBlock>
            <addressBlock>
                <offset>0x40</offset>
                <size>4</size>
                <usage>registers</usage>
            </addressBlock>
            <addressBlock>
                <offset>0x46</offset>
                <size>12</size>
                <usage>registers</usage>
            </addressBlock>
            <addressBlock>
                <offset>0x54</offset>
                <size>14</size>
                <usage>registers</usage>
            </addressBlock>
            <addressBlock>
                <offset>0x64</offset>
                <size>2</size>
                <usage>registers</usage>
            </addressBlock>
            <addressBlock>
                <offset>0x68</offset>
                <size>2</size>
                <usage>registers</usage>
            </addressBlock>
            <addressBlock>
                <offset>0x6C</offset>
                <size>22</size>
                <usage>registers</usage>
            </addressBlock>
            <addressBlock>
                <offset>0x90</offset>
                <size>22</size>
                <usage>registers</usage>
            </addressBlock>
            <addressBlock>
                <offset>0xD0</offset>
                <size>12</size>
                <usage>registers</usage>
            </addressBlock>
            <addressBlock>
                <offset>0x400</offset>
                <size>8</size>
                <usage>registers</usage>
            </addressBlock>
            <registers>
                <register>
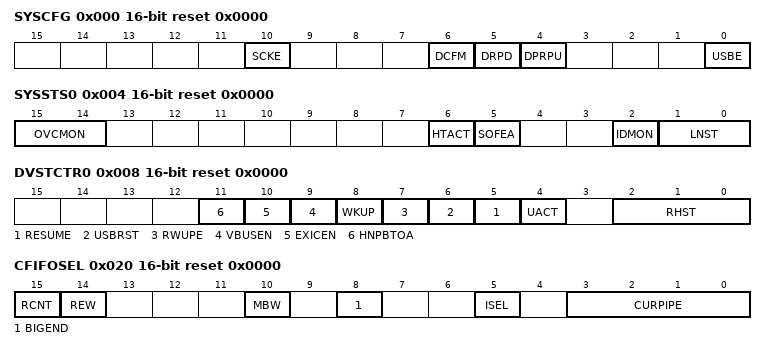
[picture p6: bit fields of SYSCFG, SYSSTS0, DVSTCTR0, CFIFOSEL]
                    <name>SYSCFG</name>
                    <description>System Configuration Control Register</description>
                    <addressOffset>0x000</addressOffset>
                    <size>16</size>
                    <access>read-write</access>
                    <resetValue>0x0000</resetValue>
                    <resetMask>0xffff</resetMask>
                    <fields>
                        <field>
                            <name>USBE</name>
                            <description>USBFS Operation Enable</description>
                            <lsb>0</lsb>
                            <msb>0</msb>
                            <access>read-write</access>
                            <enumeratedValues>
                                <enumeratedValue>
                                    <name>0</name>
                                    <description>Disable</description>
                                    <value>#0</value>
                                </enumeratedValue>
                                <enumeratedValue>
                                    <name>1</name>
                                    <description>Enable</description>
                                    <value>#1</value>
                                </enumeratedValue>
                            </enumeratedValues>
                        </field>
                        <field>
                            <name>DPRPU</name>
                            <description>D+ Line Resistor Control</description>
                            <lsb>4</lsb>
                            <msb>4</msb>
                            <access>read-write</access>
                            <enumeratedValues>
                                <enumeratedValue>
                                    <name>0</name>
                                    <description>Disable line pull-up</description>
                                    <value>#0</value>
                                </enumeratedValue>
                                <enumeratedValue>
                                    <name>1</name>
                                    <description>Enable line pull-up</description>
                                    <value>#1</value>
                                </enumeratedValue>
                            </enumeratedValues>
                        </field>
                        <field>
                            <name>DRPD</name>
                            <description>D+/D– Line Resistor Control</description>
                            <lsb>5</lsb>
                            <msb>5</msb>
                            <access>read-write</access>
                            <enumeratedValues>
                                <enumeratedValue>
                                    <name>0</name>
                                    <description>Disable line pull-down</description>
                                    <value>#0</value>
                                </enumeratedValue>
                                <enumeratedValue>
                                    <name>1</name>
                                    <description>Enable line pull-down</description>
                                    <value>#1</value>
                                </enumeratedValue>
                            </enumeratedValues>
                        </field>
                        <field>
                            <name>DCFM</name>
                            <description>Controller Function Select</description>
                            <lsb>6</lsb>
                            <msb>6</msb>
                            <access>read-write</access>
                            <enumeratedValues>
                                <enumeratedValue>
                                    <name>0</name>
                                    <description>Select device controller</description>
                                    <value>#0</value>
                                </enumeratedValue>
                                <enumeratedValue>
                                    <name>1</name>
                                    <description>Select host controller</description>
                                    <value>#1</value>
                                </enumeratedValue>
                            </enumeratedValues>
                        </field>
                        <field>
                            <name>SCKE</name>
                            <description>USB Clock Enable</description>
                            <lsb>10</lsb>
                            <msb>10</msb>
                            <access>read-write</access>
                            <enumeratedValues>
                                <enumeratedValue>
                                    <name>0</name>
                                    <description>Stop clock supply to the USBFS</description>
                                    <value>#0</value>
                                </enumeratedValue>
                                <enumeratedValue>
                                    <name>1</name>
                                    <description>Enable clock supply to the USBFS</description>
                                    <value>#1</value>
                                </enumeratedValue>
                            </enumeratedValues>
                        </field>
                    </fields>
                </register>
                <register>
                    <name>SYSSTS0</name>
                    <description>System Configuration Status Register 0</description>
                    <addressOffset>0x004</addressOffset>
                    <size>16</size>
                    <access>read-only</access>
                    <resetValue>0x0000</resetValue>
                    <resetMask>0x3ffb</resetMask>
                    <fields>
                        <field>
                            <name>LNST</name>
                            <description>USB Data Line Status Monitor</description>
                            <lsb>0</lsb>
                            <msb>1</msb>
                            <access>read-only</access>
                        </field>
                        <field>
                            <name>IDMON</name>
                            <description>External ID0 Input Pin Monitor</description>
                            <lsb>2</lsb>
                            <msb>2</msb>
                            <access>read-only</access>
                            <enumeratedValues>
                                <enumeratedValue>
                                    <name>0</name>
                                    <description>USB_ID pin is low</description>
                                    <value>#0</value>
                                </enumeratedValue>
                                <enumeratedValue>
                                    <name>1</name>
                                    <description>USB_ID pin is high</description>
                                    <value>#1</value>
                                </enumeratedValue>
                            </enumeratedValues>
                        </field>
                        <field>
                            <name>SOFEA</name>
                            <description>Active Monitor When the Host Controller Is Selected</description>
                            <lsb>5</lsb>
                            <msb>5</msb>
                            <access>read-only</access>
                            <enumeratedValues>
                                <enumeratedValue>
                                    <name>0</name>
                                    <description>SOF output stopped</description>
                                    <value>#0</value>
                                </enumeratedValue>
                                <enumeratedValue>
                                    <name>1</name>
                                    <description>SOF output operating</description>
                                    <value>#1</value>
                                </enumeratedValue>
                            </enumeratedValues>
                        </field>
                        <field>
                            <name>HTACT</name>
                            <description>USB Host Sequencer Status Monitor</description>
                            <lsb>6</lsb>
                            <msb>6</msb>
                            <access>read-only</access>
                            <enumeratedValues>
                                <enumeratedValue>
                                    <name>0</name>
                                    <description>Host sequencer completely stopped</description>
                                    <value>#0</value>
                                </enumeratedValue>
                                <enumeratedValue>
                                    <name>1</name>
                                    <description>Host sequencer not completely stopped</description>
                                    <value>#1</value>
                                </enumeratedValue>
                            </enumeratedValues>
                        </field>
                        <field>
                            <name>OVCMON</name>
                            <description>External USB_OVRCURA, USB_OVRCURA-DS, USB_OVRCURB or USB_OVRCURB-DS Input Pin Monitor</description>
                            <lsb>14</lsb>
                            <msb>15</msb>
                            <access>read-only</access>
                        </field>
                    </fields>
                </register>
                <register>
                    <name>DVSTCTR0</name>
                    <description>Device State Control Register 0</description>
                    <addressOffset>0x008</addressOffset>
                    <size>16</size>
                    <access>read-write</access>
                    <resetValue>0x0000</resetValue>
                    <resetMask>0xffff</resetMask>
                    <fields>
                        <field>
                            <name>RHST</name>
                            <description>USB Bus Reset Status</description>
                            <lsb>0</lsb>
                            <msb>2</msb>
                            <access>read-only</access>
                            <enumeratedValues>
                                <enumeratedValue>
                                    <name>000</name>
                                    <description>In host controller mode: Communication speed indeterminate (powered state or no connection) In device controller mode: Communication speed indeterminate </description>
                                    <value>#000</value>
                                </enumeratedValue>
                                <enumeratedValue>
                                    <name>001</name>
                                    <description>In host controller mode: Low-speed connection In device controller mode: USB bus reset in progress </description>
                                    <value>#001</value>
                                </enumeratedValue>
                                <enumeratedValue>
                                    <name>010</name>
                                    <description>In host controller mode: Full-speed connection In device controller mode: USB bus reset in progress or full-speed connection </description>
                                    <value>#010</value>
                                </enumeratedValue>
                                <enumeratedValue>
                                    <name>011</name>
                                    <description>Setting prohibited</description>
                                    <value>#011</value>
                                </enumeratedValue>
                                <enumeratedValue>
                                    <name>Others</name>
                                    <description>In host controller mode: USB bus reset in progress In device controller mode: Setting prohibited </description>
                                    <isDefault>true</isDefault>
                                </enumeratedValue>
                            </enumeratedValues>
                        </field>
                        <field>
                            <name>UACT</name>
                            <description>USB Bus Enable</description>
                            <lsb>4</lsb>
                            <msb>4</msb>
                            <access>read-write</access>
                            <enumeratedValues>
                                <enumeratedValue>
                                    <name>0</name>
                                    <description>Disable downstream port (disable SOF transmission)</description>
                                    <value>#0</value>
                                </enumeratedValue>
                                <enumeratedValue>
                                    <name>1</name>
                                    <description>Enable downstream port (enable SOF transmission)</description>
                                    <value>#1</value>
                                </enumeratedValue>
                            </enumeratedValues>
                        </field>
                        <field>
                            <name>RESUME</name>
                            <description>Resume Output</description>
                            <lsb>5</lsb>
                            <msb>5</msb>
                            <access>read-write</access>
                            <enumeratedValues>
                                <enumeratedValue>
                                    <name>0</name>
                                    <description>Do not output resume signal</description>
                                    <value>#0</value>
                                </enumeratedValue>
                                <enumeratedValue>
                                    <name>1</name>
                                    <description>Output resume signal</description>
                                    <value>#1</value>
                                </enumeratedValue>
                            </enumeratedValues>
                        </field>
                        <field>
                            <name>USBRST</name>
                            <description>USB Bus Reset Output</description>
                            <lsb>6</lsb>
                            <msb>6</msb>
                            <access>read-write</access>
                            <enumeratedValues>
                                <enumeratedValue>
                                    <name>0</name>
                                    <description>Do not output USB bus reset signal</description>
                                    <value>#0</value>
                                </enumeratedValue>
                                <enumeratedValue>
                                    <name>1</name>
                                    <description>Output USB bus reset signal</description>
                                    <value>#1</value>
                                </enumeratedValue>
                            </enumeratedValues>
                        </field>
                        <field>
                            <name>RWUPE</name>
                            <description>Wakeup Detection Enable</description>
                            <lsb>7</lsb>
                            <msb>7</msb>
                            <access>read-write</access>
                            <enumeratedValues>
                                <enumeratedValue>
                                    <name>0</name>
                                    <description>Disable downstream port remote wakeup</description>
                                    <value>#0</value>
                                </enumeratedValue>
                                <enumeratedValue>
                                    <name>1</name>
                                    <description>Enable downstream port remote wakeup</description>
                                    <value>#1</value>
                                </enumeratedValue>
                            </enumeratedValues>
                        </field>
                        <field>
                            <name>WKUP</name>
                            <description>Wakeup Output</description>
                            <lsb>8</lsb>
                            <msb>8</msb>
                            <access>read-write</access>
                            <enumeratedValues>
                                <enumeratedValue>
                                    <name>0</name>
                                    <description>Do not output remote wakeup signal</description>
                                    <value>#0</value>
                                </enumeratedValue>
                                <enumeratedValue>
                                    <name>1</name>
                                    <description>Output remote wakeup signal</description>
                                    <value>#1</value>
                                </enumeratedValue>
                            </enumeratedValues>
                        </field>
                        <field>
                            <name>VBUSEN</name>
                            <description>USB_VBUSEN Output Pin Control</description>
                            <lsb>9</lsb>
                            <msb>9</msb>
                            <access>read-write</access>
                            <enumeratedValues>
                                <enumeratedValue>
                                    <name>0</name>
                                    <description>Output low on external USB_VBUSEN pin</description>
                                    <value>#0</value>
                                </enumeratedValue>
                                <enumeratedValue>
                                    <name>1</name>
                                    <description>Output high on external USB_VBUSEN pin</description>
                                    <value>#1</value>
                                </enumeratedValue>
                            </enumeratedValues>
                        </field>
                        <field>
                            <name>EXICEN</name>
                            <description>USB_EXICEN Output Pin Control</description>
                            <lsb>10</lsb>
                            <msb>10</msb>
                            <access>read-write</access>
                            <enumeratedValues>
                                <enumeratedValue>
                                    <name>0</name>
                                    <description>Output low on external USB_EXICEN pin</description>
                                    <value>#0</value>
                                </enumeratedValue>
                                <enumeratedValue>
                                    <name>1</name>
                                    <description>Output high on external USB_EXICEN pin</description>
                                    <value>#1</value>
                                </enumeratedValue>
                            </enumeratedValues>
                        </field>
                        <field>
                            <name>HNPBTOA</name>
                            <description>Host Negotiation Protocol (HNP) Control</description>
                            <lsb>11</lsb>
                            <msb>11</msb>
                            <access>read-write</access>
                        </field>
                    </fields>
                </register>
                <register>
                    <name>CFIFO</name>
                    <description>CFIFO Port Register</description>
                    <addressOffset>0x014</addressOffset>
                    <size>16</size>
                    <access>read-write</access>
                    <resetValue>0x0000</resetValue>
                    <resetMask>0xffff</resetMask>
                    <fields>
                        <field>
                            <name>FIFOPORT</name>
                            <description>FIFO Port</description>
                            <lsb>0</lsb>
                            <msb>15</msb>
                            <access>read-write</access>
                        </field>
                    </fields>
                </register>
                <register>
                    <name>CFIFOL</name>
                    <description>CFIFO Port Register</description>
                    <alternateRegister>CFIFO</alternateRegister>
                    <addressOffset>0x014</addressOffset>
                    <size>8</size>
                    <access>read-write</access>
                    <resetValue>0x00</resetValue>
                    <resetMask>0xff</resetMask>
                    <fields>
                        <field>
                            <name>FIFOPORT</name>
                            <description>FIFO Port</description>
                            <lsb>0</lsb>
                            <msb>7</msb>
                            <access>read-write</access>
                        </field>
                    </fields>
                </register>
                <register>
                    <dim>2</dim>
                    <dimIncrement>0x4</dimIncrement>
                    <dimIndex>0-1</dimIndex>
                    <name>D%sFIFO</name>
                    <description>D%sFIFO Port Register</description>
                    <addressOffset>0x018</addressOffset>
                    <size>16</size>
                    <access>read-write</access>
                    <resetValue>0x0000</resetValue>
                    <resetMask>0xffff</resetMask>
                    <fields>
                        <field>
                            <name>FIFOPORT</name>
                            <description>FIFO Port</description>
                            <lsb>0</lsb>
                            <msb>15</msb>
                            <access>read-write</access>
                        </field>
                    </fields>
                </register>
                <register>
                    <dim>2</dim>
                    <dimIncrement>0x4</dimIncrement>
                    <dimIndex>0-1</dimIndex>
                    <name>D%sFIFOL</name>
                    <description>D%sFIFO Port Register</description>
                    <alternateRegister>D%sFIFO</alternateRegister>
                    <addressOffset>0x018</addressOffset>
                    <size>8</size>
                    <access>read-write</access>
                    <resetValue>0x00</resetValue>
                    <resetMask>0xff</resetMask>
                    <fields>
                        <field>
                            <name>FIFOPORT</name>
                            <description>FIFO Port</description>
                            <lsb>0</lsb>
                            <msb>7</msb>
                            <access>read-write</access>
                        </field>
                    </fields>
                </register>
                <register>
                    <name>CFIFOSEL</name>
                    <description>CFIFO Port Select Register</description>
                    <addressOffset>0x020</addressOffset>
                    <size>16</size>
                    <access>read-write</access>
                    <resetValue>0x0000</resetValue>
                    <resetMask>0xffff</resetMask>
                    <fields>
                        <field>
                            <name>CURPIPE</name>
                            <description>CFIFO Port Access Pipe Specification</description>
                            <lsb>0</lsb>
                            <msb>3</msb>
                            <access>read-write</access>
                            <enumeratedValues>
                                <enumeratedValue>
                                    <name>0x0</name>
                                    <description>Default Control Pipe</description>
                                    <value>0x0</value>
                                </enumeratedValue>
                                <enumeratedValue>
                                    <name>0x1</name>
                                    <description>Pipe 1</description>
                                    <value>0x1</value>
                                </enumeratedValue>
                                <enumeratedValue>
                                    <name>0x2</name>
                                    <description>Pipe 2</description>
                                    <value>0x2</value>
                                </enumeratedValue>
                                <enumeratedValue>
                                    <name>0x3</name>
                                    <description>Pipe 3</description>
                                    <value>0x3</value>
                                </enumeratedValue>
                                <enumeratedValue>
                                    <name>0x4</name>
                                    <description>Pipe 4</description>
                                    <value>0x4</value>
                                </enumeratedValue>
                                <enumeratedValue>
                                    <name>0x5</name>
                                    <description>Pipe 5</description>
                                    <value>0x5</value>
                                </enumeratedValue>
                                <enumeratedValue>
                                    <name>0x6</name>
                                    <description>Pipe 6</description>
                                    <value>0x6</value>
                                </enumeratedValue>
                                <enumeratedValue>
                                    <name>0x7</name>
                                    <description>Pipe 7</description>
                                    <value>0x7</value>
                                </enumeratedValue>
                                <enumeratedValue>
                                    <name>0x8</name>
                                    <description>Pipe 8</description>
                                    <value>0x8</value>
                                </enumeratedValue>
                                <enumeratedValue>
                                    <name>0x9</name>
                                    <description>Pipe 9</description>
                                    <value>0x9</value>
                                </enumeratedValue>
                                <enumeratedValue>
                                    <name>Others</name>
                                    <description>Setting prohibited</description>
                                    <isDefault>true</isDefault>
                                </enumeratedValue>
                            </enumeratedValues>
                        </field>
                        <field>
                            <name>ISEL</name>
                            <description>CFIFO Port Access Direction When DCP Is Selected</description>
                            <lsb>5</lsb>
                            <msb>5</msb>
                            <access>read-write</access>
                            <enumeratedValues>
                                <enumeratedValue>
                                    <name>0</name>
                                    <description>Select reading from the FIFO buffer</description>
                                    <value>#0</value>
                                </enumeratedValue>
                                <enumeratedValue>
                                    <name>1</name>
                                    <description>Select writing to the FIFO buffer</description>
                                    <value>#1</value>
                                </enumeratedValue>
                            </enumeratedValues>
                        </field>
                        <field>
                            <name>BIGEND</name>
                            <description>CFIFO Port Endian Control</description>
                            <lsb>8</lsb>
                            <msb>8</msb>
                            <access>read-write</access>
                            <enumeratedValues>
                                <enumeratedValue>
                                    <name>0</name>
                                    <description>Little endian</description>
                                    <value>#0</value>
                                </enumeratedValue>
                                <enumeratedValue>
                                    <name>1</name>
                                    <description>Big endian</description>
                                    <value>#1</value>
                                </enumeratedValue>
                            </enumeratedValues>
                        </field>
                        <field>
                            <name>MBW</name>
                            <description>CFIFO Port Access Bit Width</description>
                            <lsb>10</lsb>
                            <msb>10</msb>
                            <access>read-write</access>
                            <enumeratedValues>
                                <enumeratedValue>
                                    <name>0</name>
                                    <description>8-bit width</description>
                                    <value>#0</value>
                                </enumeratedValue>
                                <enumeratedValue>
                                    <name>1</name>
                                    <description>16-bit width</description>
                                    <value>#1</value>
                                </enumeratedValue>
                            </enumeratedValues>
                        </field>
                        <field>
                            <name>REW</name>
                            <description>Buffer Pointer Rewind</description>
                            <lsb>14</lsb>
                            <msb>14</msb>
                            <access>write-only</access>
                            <enumeratedValues>
                                <enumeratedValue>
                                    <name>0</name>
                                    <description>Do not rewind buffer pointer</description>
                                    <value>#0</value>
                                </enumeratedValue>
                                <enumeratedValue>
                                    <name>1</name>
                                    <description>Rewind buffer pointer</description>
                                    <value>#1</value>
                                </enumeratedValue>
                            </enumeratedValues>
                        </field>
                        <field>
                            <name>RCNT</name>
                            <description>Read Count Mode</description>
                            <lsb>15</lsb>
                            <msb>15</msb>
                            <access>read-write</access>
                            <enumeratedValues>
                                <enumeratedValue>
                                    <name>0</name>
                                    <description>The DTLN[8:0] bits (CFIFOCTR.DTLN[8:0], D0FIFOCTR.DTLN[8:0], D1FIFOCTR.DTLN[8:0]) are cleared when all receive data is read from the CFIFO. In double buffer mode, the DTLN[8:0] value is cleared when all data is read from only a single plane.</description>
                                    <value>#0</value>
                                </enumeratedValue>
                                <enumeratedValue>
                                    <name>1</name>
                                    <description>The DTLN[8:0] bits are decremented each time the receive data is read from the CFIFO.</description>
                                    <value>#1</value>
                                </enumeratedValue>
                            </enumeratedValues>
                        </field>
                    </fields>
                </register>
                <register>
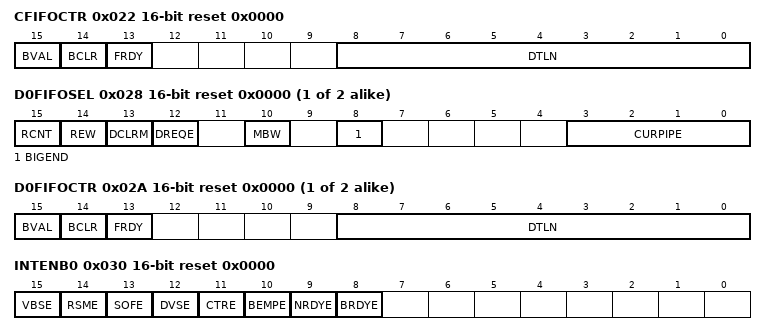
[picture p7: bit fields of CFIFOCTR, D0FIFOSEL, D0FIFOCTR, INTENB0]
                    <name>CFIFOCTR</name>
                    <description>CFIFO Port Control Register</description>
                    <addressOffset>0x022</addressOffset>
                    <size>16</size>
                    <access>read-write</access>
                    <resetValue>0x0000</resetValue>
                    <resetMask>0xffff</resetMask>
                    <fields>
                        <field>
                            <name>DTLN</name>
                            <description>Receive Data Length</description>
                            <lsb>0</lsb>
                            <msb>8</msb>
                            <access>read-only</access>
                        </field>
                        <field>
                            <name>FRDY</name>
                            <description>FIFO Port Ready</description>
                            <lsb>13</lsb>
                            <msb>13</msb>
                            <access>read-only</access>
                            <enumeratedValues>
                                <enumeratedValue>
                                    <name>0</name>
                                    <description>FIFO port access disabled</description>
                                    <value>#0</value>
                                </enumeratedValue>
                                <enumeratedValue>
                                    <name>1</name>
                                    <description>FIFO port access enabled</description>
                                    <value>#1</value>
                                </enumeratedValue>
                            </enumeratedValues>
                        </field>
                        <field>
                            <name>BCLR</name>
                            <description>CPU Buffer Clear</description>
                            <lsb>14</lsb>
                            <msb>14</msb>
                            <access>write-only</access>
                            <enumeratedValues>
                                <enumeratedValue>
                                    <name>0</name>
                                    <description>No operation</description>
                                    <value>#0</value>
                                </enumeratedValue>
                                <enumeratedValue>
                                    <name>1</name>
                                    <description>Clear FIFO buffer on the CPU side</description>
                                    <value>#1</value>
                                </enumeratedValue>
                            </enumeratedValues>
                        </field>
                        <field>
                            <name>BVAL</name>
                            <description>Buffer Memory Valid Flag</description>
                            <lsb>15</lsb>
                            <msb>15</msb>
                            <access>read-write</access>
                            <enumeratedValues>
                                <enumeratedValue>
                                    <name>0</name>
                                    <description>Invalid (writing 0 has no effect)</description>
                                    <value>#0</value>
                                </enumeratedValue>
                                <enumeratedValue>
                                    <name>1</name>
                                    <description>Writing ended</description>
                                    <value>#1</value>
                                </enumeratedValue>
                            </enumeratedValues>
                        </field>
                    </fields>
                </register>
                <register>
                    <dim>2</dim>
                    <dimIncrement>0x4</dimIncrement>
                    <dimIndex>0-1</dimIndex>
                    <name>D%sFIFOSEL</name>
                    <description>D%sFIFO Port Select Register</description>
                    <addressOffset>0x028</addressOffset>
                    <size>16</size>
                    <access>read-write</access>
                    <resetValue>0x0000</resetValue>
                    <resetMask>0xffff</resetMask>
                    <fields>
                        <field>
                            <name>CURPIPE</name>
                            <description>FIFO Port Access Pipe Specification</description>
                            <lsb>0</lsb>
                            <msb>3</msb>
                            <access>read-write</access>
                            <enumeratedValues>
                                <enumeratedValue>
                                    <name>0x0</name>
                                    <description>Default Control Pipe</description>
                                    <value>0x0</value>
                                </enumeratedValue>
                                <enumeratedValue>
                                    <name>0x1</name>
                                    <description>Pipe 1</description>
                                    <value>0x1</value>
                                </enumeratedValue>
                                <enumeratedValue>
                                    <name>0x2</name>
                                    <description>Pipe 2</description>
                                    <value>0x2</value>
                                </enumeratedValue>
                                <enumeratedValue>
                                    <name>0x3</name>
                                    <description>Pipe 3</description>
                                    <value>0x3</value>
                                </enumeratedValue>
                                <enumeratedValue>
                                    <name>0x4</name>
                                    <description>Pipe 4</description>
                                    <value>0x4</value>
                                </enumeratedValue>
                                <enumeratedValue>
                                    <name>0x5</name>
                                    <description>Pipe 5</description>
                                    <value>0x5</value>
                                </enumeratedValue>
                                <enumeratedValue>
                                    <name>0x6</name>
                                    <description>Pipe 6</description>
                                    <value>0x6</value>
                                </enumeratedValue>
                                <enumeratedValue>
                                    <name>0x7</name>
                                    <description>Pipe 7</description>
                                    <value>0x7</value>
                                </enumeratedValue>
                                <enumeratedValue>
                                    <name>0x8</name>
                                    <description>Pipe 8</description>
                                    <value>0x8</value>
                                </enumeratedValue>
                                <enumeratedValue>
                                    <name>0x9</name>
                                    <description>Pipe 9</description>
                                    <value>0x9</value>
                                </enumeratedValue>
                                <enumeratedValue>
                                    <name>Others</name>
                                    <description>Setting prohibited</description>
                                    <isDefault>true</isDefault>
                                </enumeratedValue>
                            </enumeratedValues>
                        </field>
                        <field>
                            <name>BIGEND</name>
                            <description>FIFO Port Endian Control</description>
                            <lsb>8</lsb>
                            <msb>8</msb>
                            <access>read-write</access>
                            <enumeratedValues>
                                <enumeratedValue>
                                    <name>0</name>
                                    <description>Little endian</description>
                                    <value>#0</value>
                                </enumeratedValue>
                                <enumeratedValue>
                                    <name>1</name>
                                    <description>Big endian</description>
                                    <value>#1</value>
                                </enumeratedValue>
                            </enumeratedValues>
                        </field>
                        <field>
                            <name>MBW</name>
                            <description>FIFO Port Access Bit Width</description>
                            <lsb>10</lsb>
                            <msb>10</msb>
                            <access>read-write</access>
                            <enumeratedValues>
                                <enumeratedValue>
                                    <name>0</name>
                                    <description>8-bit width</description>
                                    <value>#0</value>
                                </enumeratedValue>
                                <enumeratedValue>
                                    <name>1</name>
                                    <description>16-bit width</description>
                                    <value>#1</value>
                                </enumeratedValue>
                            </enumeratedValues>
                        </field>
                        <field>
                            <name>DREQE</name>
                            <description>DMA/DTC Transfer Request Enable</description>
                            <lsb>12</lsb>
                            <msb>12</msb>
                            <access>read-write</access>
                            <enumeratedValues>
                                <enumeratedValue>
                                    <name>0</name>
                                    <description>Disable DMA/DTC transfer request</description>
                                    <value>#0</value>
                                </enumeratedValue>
                                <enumeratedValue>
                                    <name>1</name>
                                    <description>Enable DMA/DTC transfer request</description>
                                    <value>#1</value>
                                </enumeratedValue>
                            </enumeratedValues>
                        </field>
                        <field>
                            <name>DCLRM</name>
                            <description>Auto Buffer Memory Clear Mode Accessed after Specified Pipe Data is Read</description>
                            <lsb>13</lsb>
                            <msb>13</msb>
                            <access>read-write</access>
                            <enumeratedValues>
                                <enumeratedValue>
                                    <name>0</name>
                                    <description>Disable auto buffer clear mode</description>
                                    <value>#0</value>
                                </enumeratedValue>
                                <enumeratedValue>
                                    <name>1</name>
                                    <description>Enable auto buffer clear mode</description>
                                    <value>#1</value>
                                </enumeratedValue>
                            </enumeratedValues>
                        </field>
                        <field>
                            <name>REW</name>
                            <description>Buffer Pointer Rewind</description>
                            <lsb>14</lsb>
                            <msb>14</msb>
                            <access>write-only</access>
                            <enumeratedValues>
                                <enumeratedValue>
                                    <name>0</name>
                                    <description>Do not rewind buffer pointer</description>
                                    <value>#0</value>
                                </enumeratedValue>
                                <enumeratedValue>
                                    <name>1</name>
                                    <description>Rewind buffer pointer</description>
                                    <value>#1</value>
                                </enumeratedValue>
                            </enumeratedValues>
                        </field>
                        <field>
                            <name>RCNT</name>
                            <description>Read Count Mode</description>
                            <lsb>15</lsb>
                            <msb>15</msb>
                            <access>read-write</access>
                            <enumeratedValues>
                                <enumeratedValue>
                                    <name>0</name>
                                    <description>Clear DTLN[8:0] bits in (CFIFOCTR.DTLN[8:0], D0FIFOCTR.DTLN[8:0], D1FIFOCTR.DTLN[8:0]) when all receive data is read from DnFIFO (after read of a single plane in double buffer mode)</description>
                                    <value>#0</value>
                                </enumeratedValue>
                                <enumeratedValue>
                                    <name>1</name>
                                    <description>Decrement DTLN[8:0] bits each time receive data is read from DnFIFO</description>
                                    <value>#1</value>
                                </enumeratedValue>
                            </enumeratedValues>
                        </field>
                    </fields>
                </register>
                <register>
                    <dim>2</dim>
                    <dimIncrement>0x4</dimIncrement>
                    <dimIndex>0-1</dimIndex>
                    <name>D%sFIFOCTR</name>
                    <description>D%sFIFO Port Control Register</description>
                    <addressOffset>0x02A</addressOffset>
                    <size>16</size>
                    <access>read-write</access>
                    <resetValue>0x0000</resetValue>
                    <resetMask>0xffff</resetMask>
                    <fields>
                        <field>
                            <name>DTLN</name>
                            <description>Receive Data Length</description>
                            <lsb>0</lsb>
                            <msb>8</msb>
                            <access>read-only</access>
                        </field>
                        <field>
                            <name>FRDY</name>
                            <description>FIFO Port Ready</description>
                            <lsb>13</lsb>
                            <msb>13</msb>
                            <access>read-only</access>
                            <enumeratedValues>
                                <enumeratedValue>
                                    <name>0</name>
                                    <description>FIFO port access disabled</description>
                                    <value>#0</value>
                                </enumeratedValue>
                                <enumeratedValue>
                                    <name>1</name>
                                    <description>FIFO port access enabled</description>
                                    <value>#1</value>
                                </enumeratedValue>
                            </enumeratedValues>
                        </field>
                        <field>
                            <name>BCLR</name>
                            <description>CPU Buffer Clear</description>
                            <lsb>14</lsb>
                            <msb>14</msb>
                            <access>read-write</access>
                            <enumeratedValues>
                                <enumeratedValue>
                                    <name>0</name>
                                    <description>No operation</description>
                                    <value>#0</value>
                                </enumeratedValue>
                                <enumeratedValue>
                                    <name>1</name>
                                    <description>Clear FIFO buffer on the CPU side</description>
                                    <value>#1</value>
                                </enumeratedValue>
                            </enumeratedValues>
                        </field>
                        <field>
                            <name>BVAL</name>
                            <description>Buffer Memory Valid Flag</description>
                            <lsb>15</lsb>
                            <msb>15</msb>
                            <access>read-write</access>
                            <enumeratedValues>
                                <enumeratedValue>
                                    <name>0</name>
                                    <description>Invalid (writing 0 has no effect)</description>
                                    <value>#0</value>
                                </enumeratedValue>
                                <enumeratedValue>
                                    <name>1</name>
                                    <description>Writing ended</description>
                                    <value>#1</value>
                                </enumeratedValue>
                            </enumeratedValues>
                        </field>
                    </fields>
                </register>
                <register>
                    <name>INTENB0</name>
                    <description>Interrupt Enable Register 0</description>
                    <addressOffset>0x030</addressOffset>
                    <size>16</size>
                    <access>read-write</access>
                    <resetValue>0x0000</resetValue>
                    <resetMask>0xffff</resetMask>
                    <fields>
                        <field>
                            <name>BRDYE</name>
                            <description>Buffer Ready Interrupt Enable</description>
                            <lsb>8</lsb>
                            <msb>8</msb>
                            <access>read-write</access>
                            <enumeratedValues>
                                <enumeratedValue>
                                    <name>0</name>
                                    <description>Disable interrupt request</description>
                                    <value>#0</value>
                                </enumeratedValue>
                                <enumeratedValue>
                                    <name>1</name>
                                    <description>Enable interrupt request</description>
                                    <value>#1</value>
                                </enumeratedValue>
                            </enumeratedValues>
                        </field>
                        <field>
                            <name>NRDYE</name>
                            <description>Buffer Not Ready Response Interrupt Enable</description>
                            <lsb>9</lsb>
                            <msb>9</msb>
                            <access>read-write</access>
                            <enumeratedValues>
                                <enumeratedValue>
                                    <name>0</name>
                                    <description>Disable interrupt request</description>
                                    <value>#0</value>
                                </enumeratedValue>
                                <enumeratedValue>
                                    <name>1</name>
                                    <description>Enable interrupt request</description>
                                    <value>#1</value>
                                </enumeratedValue>
                            </enumeratedValues>
                        </field>
                        <field>
                            <name>BEMPE</name>
                            <description>Buffer Empty Interrupt Enable</description>
                            <lsb>10</lsb>
                            <msb>10</msb>
                            <access>read-write</access>
                            <enumeratedValues>
                                <enumeratedValue>
                                    <name>0</name>
                                    <description>Disable interrupt request</description>
                                    <value>#0</value>
                                </enumeratedValue>
                                <enumeratedValue>
                                    <name>1</name>
                                    <description>Enable interrupt request</description>
                                    <value>#1</value>
                                </enumeratedValue>
                            </enumeratedValues>
                        </field>
                        <field>
                            <name>CTRE</name>
                            <description>Control Transfer Stage Transition Interrupt Enable</description>
                            <lsb>11</lsb>
                            <msb>11</msb>
                            <access>read-write</access>
                            <enumeratedValues>
                                <enumeratedValue>
                                    <name>0</name>
                                    <description>Disable interrupt request</description>
                                    <value>#0</value>
                                </enumeratedValue>
                                <enumeratedValue>
                                    <name>1</name>
                                    <description>Enable interrupt request</description>
                                    <value>#1</value>
                                </enumeratedValue>
                            </enumeratedValues>
                        </field>
                        <field>
                            <name>DVSE</name>
                            <description>Device State Transition Interrupt Enable</description>
                            <lsb>12</lsb>
                            <msb>12</msb>
                            <access>read-write</access>
                            <enumeratedValues>
                                <enumeratedValue>
                                    <name>0</name>
                                    <description>Disable interrupt request</description>
                                    <value>#0</value>
                                </enumeratedValue>
                                <enumeratedValue>
                                    <name>1</name>
                                    <description>Enable interrupt request</description>
                                    <value>#1</value>
                                </enumeratedValue>
                            </enumeratedValues>
                        </field>
                        <field>
                            <name>SOFE</name>
                            <description>Frame Number Update Interrupt Enable</description>
                            <lsb>13</lsb>
                            <msb>13</msb>
                            <access>read-write</access>
                            <enumeratedValues>
                                <enumeratedValue>
                                    <name>0</name>
                                    <description>Disable interrupt request</description>
                                    <value>#0</value>
                                </enumeratedValue>
                                <enumeratedValue>
                                    <name>1</name>
                                    <description>Enable interrupt request</description>
                                    <value>#1</value>
                                </enumeratedValue>
                            </enumeratedValues>
                        </field>
                        <field>
                            <name>RSME</name>
                            <description>Resume Interrupt Enable</description>
                            <lsb>14</lsb>
                            <msb>14</msb>
                            <access>read-write</access>
                            <enumeratedValues>
                                <enumeratedValue>
                                    <name>0</name>
                                    <description>Disable interrupt request</description>
                                    <value>#0</value>
                                </enumeratedValue>
                                <enumeratedValue>
                                    <name>1</name>
                                    <description>Enable interrupt request</description>
                                    <value>#1</value>
                                </enumeratedValue>
                            </enumeratedValues>
                        </field>
                        <field>
                            <name>VBSE</name>
                            <description>VBUS Interrupt Enable</description>
                            <lsb>15</lsb>
                            <msb>15</msb>
                            <access>read-write</access>
                            <enumeratedValues>
                                <enumeratedValue>
                                    <name>0</name>
                                    <description>Disable interrupt request</description>
                                    <value>#0</value>
                                </enumeratedValue>
                                <enumeratedValue>
                                    <name>1</name>
                                    <description>Enable interrupt request</description>
                                    <value>#1</value>
                                </enumeratedValue>
                            </enumeratedValues>
                        </field>
                    </fields>
                </register>
                <register>
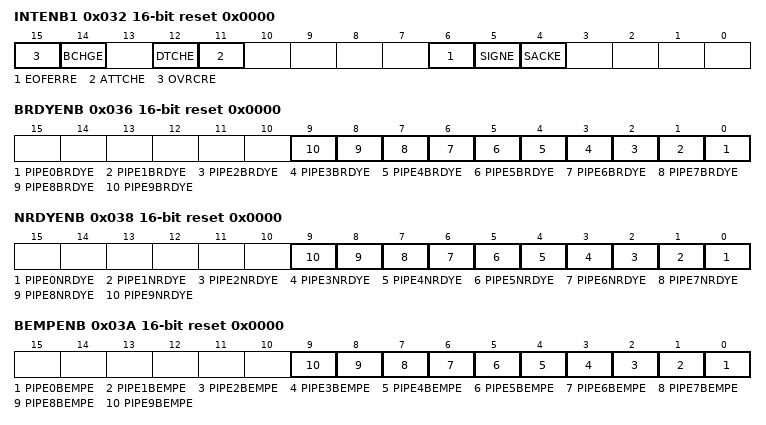
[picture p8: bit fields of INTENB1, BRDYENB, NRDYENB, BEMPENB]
                    <name>INTENB1</name>
                    <description>Interrupt Enable Register 1</description>
                    <addressOffset>0x032</addressOffset>
                    <size>16</size>
                    <access>read-write</access>
                    <resetValue>0x0000</resetValue>
                    <resetMask>0xffff</resetMask>
                    <fields>
                        <field>
                            <name>SACKE</name>
                            <description>Setup Transaction Normal Response Interrupt Enable</description>
                            <lsb>4</lsb>
                            <msb>4</msb>
                            <access>read-write</access>
                            <enumeratedValues>
                                <enumeratedValue>
                                    <name>0</name>
                                    <description>Disable interrupt request</description>
                                    <value>#0</value>
                                </enumeratedValue>
                                <enumeratedValue>
                                    <name>1</name>
                                    <description>Enable interrupt request</description>
                                    <value>#1</value>
                                </enumeratedValue>
                            </enumeratedValues>
                        </field>
                        <field>
                            <name>SIGNE</name>
                            <description>Setup Transaction Error Interrupt Enable</description>
                            <lsb>5</lsb>
                            <msb>5</msb>
                            <access>read-write</access>
                            <enumeratedValues>
                                <enumeratedValue>
                                    <name>0</name>
                                    <description>Disable interrupt request</description>
                                    <value>#0</value>
                                </enumeratedValue>
                                <enumeratedValue>
                                    <name>1</name>
                                    <description>Enable interrupt request</description>
                                    <value>#1</value>
                                </enumeratedValue>
                            </enumeratedValues>
                        </field>
                        <field>
                            <name>EOFERRE</name>
                            <description>EOF Error Detection Interrupt Enable</description>
                            <lsb>6</lsb>
                            <msb>6</msb>
                            <access>read-write</access>
                            <enumeratedValues>
                                <enumeratedValue>
                                    <name>0</name>
                                    <description>Disable interrupt request</description>
                                    <value>#0</value>
                                </enumeratedValue>
                                <enumeratedValue>
                                    <name>1</name>
                                    <description>Enable interrupt request</description>
                                    <value>#1</value>
                                </enumeratedValue>
                            </enumeratedValues>
                        </field>
                        <field>
                            <name>ATTCHE</name>
                            <description>Connection Detection Interrupt Enable</description>
                            <lsb>11</lsb>
                            <msb>11</msb>
                            <access>read-write</access>
                            <enumeratedValues>
                                <enumeratedValue>
                                    <name>0</name>
                                    <description>Disable interrupt request</description>
                                    <value>#0</value>
                                </enumeratedValue>
                                <enumeratedValue>
                                    <name>1</name>
                                    <description>Enable interrupt request</description>
                                    <value>#1</value>
                                </enumeratedValue>
                            </enumeratedValues>
                        </field>
                        <field>
                            <name>DTCHE</name>
                            <description>Disconnection Detection Interrupt Enable</description>
                            <lsb>12</lsb>
                            <msb>12</msb>
                            <access>read-write</access>
                            <enumeratedValues>
                                <enumeratedValue>
                                    <name>0</name>
                                    <description>Disable interrupt request</description>
                                    <value>#0</value>
                                </enumeratedValue>
                                <enumeratedValue>
                                    <name>1</name>
                                    <description>Enable interrupt request</description>
                                    <value>#1</value>
                                </enumeratedValue>
                            </enumeratedValues>
                        </field>
                        <field>
                            <name>BCHGE</name>
                            <description>USB Bus Change Interrupt Enable</description>
                            <lsb>14</lsb>
                            <msb>14</msb>
                            <access>read-write</access>
                            <enumeratedValues>
                                <enumeratedValue>
                                    <name>0</name>
                                    <description>Disable interrupt request</description>
                                    <value>#0</value>
                                </enumeratedValue>
                                <enumeratedValue>
                                    <name>1</name>
                                    <description>Enable interrupt request</description>
                                    <value>#1</value>
                                </enumeratedValue>
                            </enumeratedValues>
                        </field>
                        <field>
                            <name>OVRCRE</name>
                            <description>Overcurrent Input Change Interrupt Enable</description>
                            <lsb>15</lsb>
                            <msb>15</msb>
                            <access>read-write</access>
                            <enumeratedValues>
                                <enumeratedValue>
                                    <name>0</name>
                                    <description>Disable interrupt request</description>
                                    <value>#0</value>
                                </enumeratedValue>
                                <enumeratedValue>
                                    <name>1</name>
                                    <description>Enable interrupt request</description>
                                    <value>#1</value>
                                </enumeratedValue>
                            </enumeratedValues>
                        </field>
                    </fields>
                </register>
                <register>
                    <name>BRDYENB</name>
                    <description>BRDY Interrupt Enable Register</description>
                    <addressOffset>0x036</addressOffset>
                    <size>16</size>
                    <access>read-write</access>
                    <resetValue>0x0000</resetValue>
                    <resetMask>0xffff</resetMask>
                    <fields>
                        <field>
                            <name>PIPE0BRDYE</name>
                            <description>BRDY Interrupt Enable for Pipe 0</description>
                            <lsb>0</lsb>
                            <msb>0</msb>
                            <access>read-write</access>
                            <enumeratedValues>
                                <enumeratedValue>
                                    <name>0</name>
                                    <description>Disable interrupt request</description>
                                    <value>#0</value>
                                </enumeratedValue>
                                <enumeratedValue>
                                    <name>1</name>
                                    <description>Enable interrupt request</description>
                                    <value>#1</value>
                                </enumeratedValue>
                            </enumeratedValues>
                        </field>
                        <field>
                            <name>PIPE1BRDYE</name>
                            <description>BRDY Interrupt Enable for Pipe 1</description>
                            <lsb>1</lsb>
                            <msb>1</msb>
                            <access>read-write</access>
                            <enumeratedValues>
                                <enumeratedValue>
                                    <name>0</name>
                                    <description>Disable interrupt request</description>
                                    <value>#0</value>
                                </enumeratedValue>
                                <enumeratedValue>
                                    <name>1</name>
                                    <description>Enable interrupt request</description>
                                    <value>#1</value>
                                </enumeratedValue>
                            </enumeratedValues>
                        </field>
                        <field>
                            <name>PIPE2BRDYE</name>
                            <description>BRDY Interrupt Enable for Pipe 2</description>
                            <lsb>2</lsb>
                            <msb>2</msb>
                            <access>read-write</access>
                            <enumeratedValues>
                                <enumeratedValue>
                                    <name>0</name>
                                    <description>Disable interrupt request</description>
                                    <value>#0</value>
                                </enumeratedValue>
                                <enumeratedValue>
                                    <name>1</name>
                                    <description>Enable interrupt request</description>
                                    <value>#1</value>
                                </enumeratedValue>
                            </enumeratedValues>
                        </field>
                        <field>
                            <name>PIPE3BRDYE</name>
                            <description>BRDY Interrupt Enable for Pipe 3</description>
                            <lsb>3</lsb>
                            <msb>3</msb>
                            <access>read-write</access>
                            <enumeratedValues>
                                <enumeratedValue>
                                    <name>0</name>
                                    <description>Disable interrupt request</description>
                                    <value>#0</value>
                                </enumeratedValue>
                                <enumeratedValue>
                                    <name>1</name>
                                    <description>Enable interrupt request</description>
                                    <value>#1</value>
                                </enumeratedValue>
                            </enumeratedValues>
                        </field>
                        <field>
                            <name>PIPE4BRDYE</name>
                            <description>BRDY Interrupt Enable for Pipe 4</description>
                            <lsb>4</lsb>
                            <msb>4</msb>
                            <access>read-write</access>
                            <enumeratedValues>
                                <enumeratedValue>
                                    <name>0</name>
                                    <description>Disable interrupt request</description>
                                    <value>#0</value>
                                </enumeratedValue>
                                <enumeratedValue>
                                    <name>1</name>
                                    <description>Enable interrupt request</description>
                                    <value>#1</value>
                                </enumeratedValue>
                            </enumeratedValues>
                        </field>
                        <field>
                            <name>PIPE5BRDYE</name>
                            <description>BRDY Interrupt Enable for Pipe 5</description>
                            <lsb>5</lsb>
                            <msb>5</msb>
                            <access>read-write</access>
                            <enumeratedValues>
                                <enumeratedValue>
                                    <name>0</name>
                                    <description>Disable interrupt request</description>
                                    <value>#0</value>
                                </enumeratedValue>
                                <enumeratedValue>
                                    <name>1</name>
                                    <description>Enable interrupt request</description>
                                    <value>#1</value>
                                </enumeratedValue>
                            </enumeratedValues>
                        </field>
                        <field>
                            <name>PIPE6BRDYE</name>
                            <description>BRDY Interrupt Enable for Pipe 6</description>
                            <lsb>6</lsb>
                            <msb>6</msb>
                            <access>read-write</access>
                            <enumeratedValues>
                                <enumeratedValue>
                                    <name>0</name>
                                    <description>Disable interrupt request</description>
                                    <value>#0</value>
                                </enumeratedValue>
                                <enumeratedValue>
                                    <name>1</name>
                                    <description>Enable interrupt request</description>
                                    <value>#1</value>
                                </enumeratedValue>
                            </enumeratedValues>
                        </field>
                        <field>
                            <name>PIPE7BRDYE</name>
                            <description>BRDY Interrupt Enable for Pipe 7</description>
                            <lsb>7</lsb>
                            <msb>7</msb>
                            <access>read-write</access>
                            <enumeratedValues>
                                <enumeratedValue>
                                    <name>0</name>
                                    <description>Disable interrupt request</description>
                                    <value>#0</value>
                                </enumeratedValue>
                                <enumeratedValue>
                                    <name>1</name>
                                    <description>Enable interrupt request</description>
                                    <value>#1</value>
                                </enumeratedValue>
                            </enumeratedValues>
                        </field>
                        <field>
                            <name>PIPE8BRDYE</name>
                            <description>BRDY Interrupt Enable for Pipe 8</description>
                            <lsb>8</lsb>
                            <msb>8</msb>
                            <access>read-write</access>
                            <enumeratedValues>
                                <enumeratedValue>
                                    <name>0</name>
                                    <description>Disable interrupt request</description>
                                    <value>#0</value>
                                </enumeratedValue>
                                <enumeratedValue>
                                    <name>1</name>
                                    <description>Enable interrupt request</description>
                                    <value>#1</value>
                                </enumeratedValue>
                            </enumeratedValues>
                        </field>
                        <field>
                            <name>PIPE9BRDYE</name>
                            <description>BRDY Interrupt Enable for Pipe 9</description>
                            <lsb>9</lsb>
                            <msb>9</msb>
                            <access>read-write</access>
                            <enumeratedValues>
                                <enumeratedValue>
                                    <name>0</name>
                                    <description>Disable interrupt request</description>
                                    <value>#0</value>
                                </enumeratedValue>
                                <enumeratedValue>
                                    <name>1</name>
                                    <description>Enable interrupt request</description>
                                    <value>#1</value>
                                </enumeratedValue>
                            </enumeratedValues>
                        </field>
                    </fields>
                </register>
                <register>
                    <name>NRDYENB</name>
                    <description>NRDY Interrupt Enable Register</description>
                    <addressOffset>0x038</addressOffset>
                    <size>16</size>
                    <access>read-write</access>
                    <resetValue>0x0000</resetValue>
                    <resetMask>0xffff</resetMask>
                    <fields>
                        <field>
                            <name>PIPE0NRDYE</name>
                            <description>NRDY Interrupt Enable for Pipe 0</description>
                            <lsb>0</lsb>
                            <msb>0</msb>
                            <access>read-write</access>
                            <enumeratedValues>
                                <enumeratedValue>
                                    <name>0</name>
                                    <description>Disable interrupt request</description>
                                    <value>#0</value>
                                </enumeratedValue>
                                <enumeratedValue>
                                    <name>1</name>
                                    <description>Enable interrupt request</description>
                                    <value>#1</value>
                                </enumeratedValue>
                            </enumeratedValues>
                        </field>
                        <field>
                            <name>PIPE1NRDYE</name>
                            <description>NRDY Interrupt Enable for Pipe 1</description>
                            <lsb>1</lsb>
                            <msb>1</msb>
                            <access>read-write</access>
                            <enumeratedValues>
                                <enumeratedValue>
                                    <name>0</name>
                                    <description>Disable interrupt request</description>
                                    <value>#0</value>
                                </enumeratedValue>
                                <enumeratedValue>
                                    <name>1</name>
                                    <description>Enable interrupt request</description>
                                    <value>#1</value>
                                </enumeratedValue>
                            </enumeratedValues>
                        </field>
                        <field>
                            <name>PIPE2NRDYE</name>
                            <description>NRDY Interrupt Enable for Pipe 2</description>
                            <lsb>2</lsb>
                            <msb>2</msb>
                            <access>read-write</access>
                            <enumeratedValues>
                                <enumeratedValue>
                                    <name>0</name>
                                    <description>Disable interrupt request</description>
                                    <value>#0</value>
                                </enumeratedValue>
                                <enumeratedValue>
                                    <name>1</name>
                                    <description>Enable interrupt request</description>
                                    <value>#1</value>
                                </enumeratedValue>
                            </enumeratedValues>
                        </field>
                        <field>
                            <name>PIPE3NRDYE</name>
                            <description>NRDY Interrupt Enable for Pipe 3</description>
                            <lsb>3</lsb>
                            <msb>3</msb>
                            <access>read-write</access>
                            <enumeratedValues>
                                <enumeratedValue>
                                    <name>0</name>
                                    <description>Disable interrupt request</description>
                                    <value>#0</value>
                                </enumeratedValue>
                                <enumeratedValue>
                                    <name>1</name>
                                    <description>Enable interrupt request</description>
                                    <value>#1</value>
                                </enumeratedValue>
                            </enumeratedValues>
                        </field>
                        <field>
                            <name>PIPE4NRDYE</name>
                            <description>NRDY Interrupt Enable for Pipe 4</description>
                            <lsb>4</lsb>
                            <msb>4</msb>
                            <access>read-write</access>
                            <enumeratedValues>
                                <enumeratedValue>
                                    <name>0</name>
                                    <description>Disable interrupt request</description>
                                    <value>#0</value>
                                </enumeratedValue>
                                <enumeratedValue>
                                    <name>1</name>
                                    <description>Enable interrupt request</description>
                                    <value>#1</value>
                                </enumeratedValue>
                            </enumeratedValues>
                        </field>
                        <field>
                            <name>PIPE5NRDYE</name>
                            <description>NRDY Interrupt Enable for Pipe 5</description>
                            <lsb>5</lsb>
                            <msb>5</msb>
                            <access>read-write</access>
                            <enumeratedValues>
                                <enumeratedValue>
                                    <name>0</name>
                                    <description>Disable interrupt request</description>
                                    <value>#0</value>
                                </enumeratedValue>
                                <enumeratedValue>
                                    <name>1</name>
                                    <description>Enable interrupt request</description>
                                    <value>#1</value>
                                </enumeratedValue>
                            </enumeratedValues>
                        </field>
                        <field>
                            <name>PIPE6NRDYE</name>
                            <description>NRDY Interrupt Enable for Pipe 6</description>
                            <lsb>6</lsb>
                            <msb>6</msb>
                            <access>read-write</access>
                            <enumeratedValues>
                                <enumeratedValue>
                                    <name>0</name>
                                    <description>Disable interrupt request</description>
                                    <value>#0</value>
                                </enumeratedValue>
                                <enumeratedValue>
                                    <name>1</name>
                                    <description>Enable interrupt request</description>
                                    <value>#1</value>
                                </enumeratedValue>
                            </enumeratedValues>
                        </field>
                        <field>
                            <name>PIPE7NRDYE</name>
                            <description>NRDY Interrupt Enable for Pipe 7</description>
                            <lsb>7</lsb>
                            <msb>7</msb>
                            <access>read-write</access>
                            <enumeratedValues>
                                <enumeratedValue>
                                    <name>0</name>
                                    <description>Disable interrupt request</description>
                                    <value>#0</value>
                                </enumeratedValue>
                                <enumeratedValue>
                                    <name>1</name>
                                    <description>Enable interrupt request</description>
                                    <value>#1</value>
                                </enumeratedValue>
                            </enumeratedValues>
                        </field>
                        <field>
                            <name>PIPE8NRDYE</name>
                            <description>NRDY Interrupt Enable for Pipe 8</description>
                            <lsb>8</lsb>
                            <msb>8</msb>
                            <access>read-write</access>
                            <enumeratedValues>
                                <enumeratedValue>
                                    <name>0</name>
                                    <description>Disable interrupt request</description>
                                    <value>#0</value>
                                </enumeratedValue>
                                <enumeratedValue>
                                    <name>1</name>
                                    <description>Enable interrupt request</description>
                                    <value>#1</value>
                                </enumeratedValue>
                            </enumeratedValues>
                        </field>
                        <field>
                            <name>PIPE9NRDYE</name>
                            <description>NRDY Interrupt Enable for Pipe 9</description>
                            <lsb>9</lsb>
                            <msb>9</msb>
                            <access>read-write</access>
                            <enumeratedValues>
                                <enumeratedValue>
                                    <name>0</name>
                                    <description>Disable interrupt request</description>
                                    <value>#0</value>
                                </enumeratedValue>
                                <enumeratedValue>
                                    <name>1</name>
                                    <description>Enable interrupt request</description>
                                    <value>#1</value>
                                </enumeratedValue>
                            </enumeratedValues>
                        </field>
                    </fields>
                </register>
                <register>
                    <name>BEMPENB</name>
                    <description>BEMP Interrupt Enable Register</description>
                    <addressOffset>0x03A</addressOffset>
                    <size>16</size>
                    <access>read-write</access>
                    <resetValue>0x0000</resetValue>
                    <resetMask>0xffff</resetMask>
                    <fields>
                        <field>
                            <name>PIPE0BEMPE</name>
                            <description>BEMP Interrupt Enable for Pipe 0</description>
                            <lsb>0</lsb>
                            <msb>0</msb>
                            <access>read-write</access>
                            <enumeratedValues>
                                <enumeratedValue>
                                    <name>0</name>
                                    <description>Disable interrupt request</description>
                                    <value>#0</value>
                                </enumeratedValue>
                                <enumeratedValue>
                                    <name>1</name>
                                    <description>Enable interrupt request</description>
                                    <value>#1</value>
                                </enumeratedValue>
                            </enumeratedValues>
                        </field>
                        <field>
                            <name>PIPE1BEMPE</name>
                            <description>BEMP Interrupt Enable for Pipe 1</description>
                            <lsb>1</lsb>
                            <msb>1</msb>
                            <access>read-write</access>
                            <enumeratedValues>
                                <enumeratedValue>
                                    <name>0</name>
                                    <description>Disable interrupt request</description>
                                    <value>#0</value>
                                </enumeratedValue>
                                <enumeratedValue>
                                    <name>1</name>
                                    <description>Enable interrupt request</description>
                                    <value>#1</value>
                                </enumeratedValue>
                            </enumeratedValues>
                        </field>
                        <field>
                            <name>PIPE2BEMPE</name>
                            <description>BEMP Interrupt Enable for Pipe 2</description>
                            <lsb>2</lsb>
                            <msb>2</msb>
                            <access>read-write</access>
                            <enumeratedValues>
                                <enumeratedValue>
                                    <name>0</name>
                                    <description>Disable interrupt request</description>
                                    <value>#0</value>
                                </enumeratedValue>
                                <enumeratedValue>
                                    <name>1</name>
                                    <description>Enable interrupt request</description>
                                    <value>#1</value>
                                </enumeratedValue>
                            </enumeratedValues>
                        </field>
                        <field>
                            <name>PIPE3BEMPE</name>
                            <description>BEMP Interrupt Enable for Pipe 3</description>
                            <lsb>3</lsb>
                            <msb>3</msb>
                            <access>read-write</access>
                            <enumeratedValues>
                                <enumeratedValue>
                                    <name>0</name>
                                    <description>Disable interrupt request</description>
                                    <value>#0</value>
                                </enumeratedValue>
                                <enumeratedValue>
                                    <name>1</name>
                                    <description>Enable interrupt request</description>
                                    <value>#1</value>
                                </enumeratedValue>
                            </enumeratedValues>
                        </field>
                        <field>
                            <name>PIPE4BEMPE</name>
                            <description>BEMP Interrupt Enable for Pipe 4</description>
                            <lsb>4</lsb>
                            <msb>4</msb>
                            <access>read-write</access>
                            <enumeratedValues>
                                <enumeratedValue>
                                    <name>0</name>
                                    <description>Disable interrupt request</description>
                                    <value>#0</value>
                                </enumeratedValue>
                                <enumeratedValue>
                                    <name>1</name>
                                    <description>Enable interrupt request</description>
                                    <value>#1</value>
                                </enumeratedValue>
                            </enumeratedValues>
                        </field>
                        <field>
                            <name>PIPE5BEMPE</name>
                            <description>BEMP Interrupt Enable for Pipe 5</description>
                            <lsb>5</lsb>
                            <msb>5</msb>
                            <access>read-write</access>
                            <enumeratedValues>
                                <enumeratedValue>
                                    <name>0</name>
                                    <description>Disable interrupt request</description>
                                    <value>#0</value>
                                </enumeratedValue>
                                <enumeratedValue>
                                    <name>1</name>
                                    <description>Enable interrupt request</description>
                                    <value>#1</value>
                                </enumeratedValue>
                            </enumeratedValues>
                        </field>
                        <field>
                            <name>PIPE6BEMPE</name>
                            <description>BEMP Interrupt Enable for Pipe 6</description>
                            <lsb>6</lsb>
                            <msb>6</msb>
                            <access>read-write</access>
                            <enumeratedValues>
                                <enumeratedValue>
                                    <name>0</name>
                                    <description>Disable interrupt request</description>
                                    <value>#0</value>
                                </enumeratedValue>
                                <enumeratedValue>
                                    <name>1</name>
                                    <description>Enable interrupt request</description>
                                    <value>#1</value>
                                </enumeratedValue>
                            </enumeratedValues>
                        </field>
                        <field>
                            <name>PIPE7BEMPE</name>
                            <description>BEMP Interrupt Enable for Pipe 7</description>
                            <lsb>7</lsb>
                            <msb>7</msb>
                            <access>read-write</access>
                            <enumeratedValues>
                                <enumeratedValue>
                                    <name>0</name>
                                    <description>Disable interrupt request</description>
                                    <value>#0</value>
                                </enumeratedValue>
                                <enumeratedValue>
                                    <name>1</name>
                                    <description>Enable interrupt request</description>
                                    <value>#1</value>
                                </enumeratedValue>
                            </enumeratedValues>
                        </field>
                        <field>
                            <name>PIPE8BEMPE</name>
                            <description>BEMP Interrupt Enable for Pipe 8</description>
                            <lsb>8</lsb>
                            <msb>8</msb>
                            <access>read-write</access>
                            <enumeratedValues>
                                <enumeratedValue>
                                    <name>0</name>
                                    <description>Disable interrupt request</description>
                                    <value>#0</value>
                                </enumeratedValue>
                                <enumeratedValue>
                                    <name>1</name>
                                    <description>Enable interrupt request</description>
                                    <value>#1</value>
                                </enumeratedValue>
                            </enumeratedValues>
                        </field>
                        <field>
                            <name>PIPE9BEMPE</name>
                            <description>BEMP Interrupt Enable for Pipe 9</description>
                            <lsb>9</lsb>
                            <msb>9</msb>
                            <access>read-write</access>
                            <enumeratedValues>
                                <enumeratedValue>
                                    <name>0</name>
                                    <description>Disable interrupt request</description>
                                    <value>#0</value>
                                </enumeratedValue>
                                <enumeratedValue>
                                    <name>1</name>
                                    <description>Enable interrupt request</description>
                                    <value>#1</value>
                                </enumeratedValue>
                            </enumeratedValues>
                        </field>
                    </fields>
                </register>
                <register>
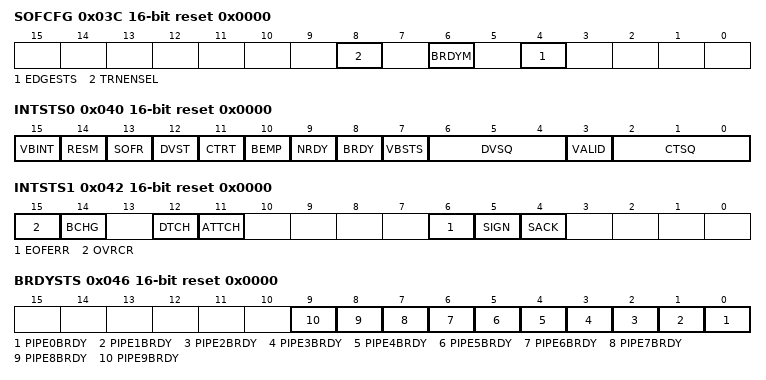
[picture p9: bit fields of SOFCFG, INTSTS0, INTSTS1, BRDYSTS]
                    <name>SOFCFG</name>
                    <description>SOF Output Configuration Register</description>
                    <addressOffset>0x03C</addressOffset>
                    <size>16</size>
                    <access>read-write</access>
                    <resetValue>0x0000</resetValue>
                    <resetMask>0xffff</resetMask>
                    <fields>
                        <field>
                            <name>EDGESTS</name>
                            <description>Edge Interrupt Output Status Monitor</description>
                            <lsb>4</lsb>
                            <msb>4</msb>
                            <access>read-only</access>
                        </field>
                        <field>
                            <name>BRDYM</name>
                            <description>BRDY Interrupt Status Clear Timing</description>
                            <lsb>6</lsb>
                            <msb>6</msb>
                            <access>read-write</access>
                            <enumeratedValues>
                                <enumeratedValue>
                                    <name>0</name>
                                    <description>Clear BRDY flag by software</description>
                                    <value>#0</value>
                                </enumeratedValue>
                                <enumeratedValue>
                                    <name>1</name>
                                    <description>Clear BRDY flag by the USBFS through a data read from the FIFO buffer or data write to the FIFO buffer</description>
                                    <value>#1</value>
                                </enumeratedValue>
                            </enumeratedValues>
                        </field>
                        <field>
                            <name>TRNENSEL</name>
                            <description>Transaction-Enabled Time Select</description>
                            <lsb>8</lsb>
                            <msb>8</msb>
                            <access>read-write</access>
                            <enumeratedValues>
                                <enumeratedValue>
                                    <name>0</name>
                                    <description>Not low-speed communication</description>
                                    <value>#0</value>
                                </enumeratedValue>
                                <enumeratedValue>
                                    <name>1</name>
                                    <description>Low-speed communication</description>
                                    <value>#1</value>
                                </enumeratedValue>
                            </enumeratedValues>
                        </field>
                    </fields>
                </register>
                <register>
                    <name>INTSTS0</name>
                    <description>Interrupt Status Register 0</description>
                    <addressOffset>0x040</addressOffset>
                    <size>16</size>
                    <access>read-write</access>
                    <resetValue>0x0000</resetValue>
                    <resetMask>0xef6f</resetMask>
                    <fields>
                        <field>
                            <name>CTSQ</name>
                            <description>Control Transfer Stage</description>
                            <lsb>0</lsb>
                            <msb>2</msb>
                            <access>read-only</access>
                            <enumeratedValues>
                                <enumeratedValue>
                                    <name>000</name>
                                    <description>Idle or setup stage</description>
                                    <value>#000</value>
                                </enumeratedValue>
                                <enumeratedValue>
                                    <name>001</name>
                                    <description>Control read data stage</description>
                                    <value>#001</value>
                                </enumeratedValue>
                                <enumeratedValue>
                                    <name>010</name>
                                    <description>Control read status stage</description>
                                    <value>#010</value>
                                </enumeratedValue>
                                <enumeratedValue>
                                    <name>011</name>
                                    <description>Control write data stage</description>
                                    <value>#011</value>
                                </enumeratedValue>
                                <enumeratedValue>
                                    <name>100</name>
                                    <description>Control write status stage</description>
                                    <value>#100</value>
                                </enumeratedValue>
                                <enumeratedValue>
                                    <name>101</name>
                                    <description>Control write (no data) status stage</description>
                                    <value>#101</value>
                                </enumeratedValue>
                                <enumeratedValue>
                                    <name>110</name>
                                    <description>Control transfer sequence error</description>
                                    <value>#110</value>
                                </enumeratedValue>
                            </enumeratedValues>
                        </field>
                        <field>
                            <name>VALID</name>
                            <description>USB Request Reception</description>
                            <lsb>3</lsb>
                            <msb>3</msb>
                            <access>read-write</access>
                            <enumeratedValues>
                                <enumeratedValue>
                                    <name>0</name>
                                    <description>Setup packet not received</description>
                                    <value>#0</value>
                                </enumeratedValue>
                                <enumeratedValue>
                                    <name>1</name>
                                    <description>Setup packet received</description>
                                    <value>#1</value>
                                </enumeratedValue>
                            </enumeratedValues>
                        </field>
                        <field>
                            <name>DVSQ</name>
                            <description>Device State</description>
                            <lsb>4</lsb>
                            <msb>6</msb>
                            <access>read-only</access>
                            <enumeratedValues>
                                <enumeratedValue>
                                    <name>000</name>
                                    <description>Powered state</description>
                                    <value>#000</value>
                                </enumeratedValue>
                                <enumeratedValue>
                                    <name>001</name>
                                    <description>Default state</description>
                                    <value>#001</value>
                                </enumeratedValue>
                                <enumeratedValue>
                                    <name>010</name>
                                    <description>Address state</description>
                                    <value>#010</value>
                                </enumeratedValue>
                                <enumeratedValue>
                                    <name>011</name>
                                    <description>Configured state</description>
                                    <value>#011</value>
                                </enumeratedValue>
                                <enumeratedValue>
                                    <name>Others</name>
                                    <description>Suspend state</description>
                                    <isDefault>true</isDefault>
                                </enumeratedValue>
                            </enumeratedValues>
                        </field>
                        <field>
                            <name>VBSTS</name>
                            <description>VBUS Input Status</description>
                            <lsb>7</lsb>
                            <msb>7</msb>
                            <access>read-only</access>
                            <enumeratedValues>
                                <enumeratedValue>
                                    <name>0</name>
                                    <description>USB_VBUS pin is low</description>
                                    <value>#0</value>
                                </enumeratedValue>
                                <enumeratedValue>
                                    <name>1</name>
                                    <description>USB_VBUS pin is high</description>
                                    <value>#1</value>
                                </enumeratedValue>
                            </enumeratedValues>
                        </field>
                        <field>
                            <name>BRDY</name>
                            <description>Buffer Ready Interrupt Status</description>
                            <lsb>8</lsb>
                            <msb>8</msb>
                            <access>read-only</access>
                            <enumeratedValues>
                                <enumeratedValue>
                                    <name>0</name>
                                    <description>No BRDY interrupt occurred</description>
                                    <value>#0</value>
                                </enumeratedValue>
                                <enumeratedValue>
                                    <name>1</name>
                                    <description>BRDY interrupt occurred</description>
                                    <value>#1</value>
                                </enumeratedValue>
                            </enumeratedValues>
                        </field>
                        <field>
                            <name>NRDY</name>
                            <description>Buffer Not Ready Interrupt Status</description>
                            <lsb>9</lsb>
                            <msb>9</msb>
                            <access>read-only</access>
                            <enumeratedValues>
                                <enumeratedValue>
                                    <name>0</name>
                                    <description>No NRDY interrupt occurred</description>
                                    <value>#0</value>
                                </enumeratedValue>
                                <enumeratedValue>
                                    <name>1</name>
                                    <description>NRDY interrupt occurred</description>
                                    <value>#1</value>
                                </enumeratedValue>
                            </enumeratedValues>
                        </field>
                        <field>
                            <name>BEMP</name>
                            <description>Buffer Empty Interrupt Status</description>
                            <lsb>10</lsb>
                            <msb>10</msb>
                            <access>read-only</access>
                            <enumeratedValues>
                                <enumeratedValue>
                                    <name>0</name>
                                    <description>No BEMP interrupt occurred</description>
                                    <value>#0</value>
                                </enumeratedValue>
                                <enumeratedValue>
                                    <name>1</name>
                                    <description>BEMP interrupt occurred</description>
                                    <value>#1</value>
                                </enumeratedValue>
                            </enumeratedValues>
                        </field>
                        <field>
                            <name>CTRT</name>
                            <description>Control Transfer Stage Transition Interrupt Status</description>
                            <lsb>11</lsb>
                            <msb>11</msb>
                            <access>read-write</access>
                            <enumeratedValues>
                                <enumeratedValue>
                                    <name>0</name>
                                    <description>No control transfer stage transition interrupt occurred</description>
                                    <value>#0</value>
                                </enumeratedValue>
                                <enumeratedValue>
                                    <name>1</name>
                                    <description>Control transfer stage transition interrupt occurred</description>
                                    <value>#1</value>
                                </enumeratedValue>
                            </enumeratedValues>
                        </field>
                        <field>
                            <name>DVST</name>
                            <description>Device State Transition Interrupt Status</description>
                            <lsb>12</lsb>
                            <msb>12</msb>
                            <access>read-write</access>
                            <enumeratedValues>
                                <enumeratedValue>
                                    <name>0</name>
                                    <description>No device state transition interrupt occurred</description>
                                    <value>#0</value>
                                </enumeratedValue>
                                <enumeratedValue>
                                    <name>1</name>
                                    <description>Device state transition interrupt occurred</description>
                                    <value>#1</value>
                                </enumeratedValue>
                            </enumeratedValues>
                        </field>
                        <field>
                            <name>SOFR</name>
                            <description>Frame Number Refresh Interrupt Status</description>
                            <lsb>13</lsb>
                            <msb>13</msb>
                            <access>read-write</access>
                            <enumeratedValues>
                                <enumeratedValue>
                                    <name>0</name>
                                    <description>No SOF interrupt occurred</description>
                                    <value>#0</value>
                                </enumeratedValue>
                                <enumeratedValue>
                                    <name>1</name>
                                    <description>SOF interrupt occurred</description>
                                    <value>#1</value>
                                </enumeratedValue>
                            </enumeratedValues>
                        </field>
                        <field>
                            <name>RESM</name>
                            <description>Resume Interrupt Status</description>
                            <lsb>14</lsb>
                            <msb>14</msb>
                            <access>read-write</access>
                            <enumeratedValues>
                                <enumeratedValue>
                                    <name>0</name>
                                    <description>No resume interrupt occurred</description>
                                    <value>#0</value>
                                </enumeratedValue>
                                <enumeratedValue>
                                    <name>1</name>
                                    <description>Resume interrupt occurred</description>
                                    <value>#1</value>
                                </enumeratedValue>
                            </enumeratedValues>
                        </field>
                        <field>
                            <name>VBINT</name>
                            <description>VBUS Interrupt Status</description>
                            <lsb>15</lsb>
                            <msb>15</msb>
                            <access>read-write</access>
                            <enumeratedValues>
                                <enumeratedValue>
                                    <name>0</name>
                                    <description>No VBUS interrupt occurred</description>
                                    <value>#0</value>
                                </enumeratedValue>
                                <enumeratedValue>
                                    <name>1</name>
                                    <description>VBUS interrupt occurred</description>
                                    <value>#1</value>
                                </enumeratedValue>
                            </enumeratedValues>
                        </field>
                    </fields>
                </register>
                <register>
                    <name>INTSTS1</name>
                    <description>Interrupt Status Register 1</description>
                    <addressOffset>0x042</addressOffset>
                    <size>16</size>
                    <access>read-write</access>
                    <resetValue>0x0000</resetValue>
                    <resetMask>0xffff</resetMask>
                    <fields>
                        <field>
                            <name>SACK</name>
                            <description>Setup Transaction Normal Response Interrupt Status</description>
                            <lsb>4</lsb>
                            <msb>4</msb>
                            <access>read-write</access>
                            <enumeratedValues>
                                <enumeratedValue>
                                    <name>0</name>
                                    <description>No SACK interrupt occurred</description>
                                    <value>#0</value>
                                </enumeratedValue>
                                <enumeratedValue>
                                    <name>1</name>
                                    <description>SACK interrupt occurred</description>
                                    <value>#1</value>
                                </enumeratedValue>
                            </enumeratedValues>
                        </field>
                        <field>
                            <name>SIGN</name>
                            <description>Setup Transaction Error Interrupt Status</description>
                            <lsb>5</lsb>
                            <msb>5</msb>
                            <access>read-write</access>
                            <enumeratedValues>
                                <enumeratedValue>
                                    <name>0</name>
                                    <description>No SIGN interrupt occurred</description>
                                    <value>#0</value>
                                </enumeratedValue>
                                <enumeratedValue>
                                    <name>1</name>
                                    <description>SIGN interrupt occurred</description>
                                    <value>#1</value>
                                </enumeratedValue>
                            </enumeratedValues>
                        </field>
                        <field>
                            <name>EOFERR</name>
                            <description>EOF Error Detection Interrupt Status</description>
                            <lsb>6</lsb>
                            <msb>6</msb>
                            <access>read-write</access>
                            <enumeratedValues>
                                <enumeratedValue>
                                    <name>0</name>
                                    <description>No EOFERR interrupt occurred</description>
                                    <value>#0</value>
                                </enumeratedValue>
                                <enumeratedValue>
                                    <name>1</name>
                                    <description>EOFERR interrupt occurred</description>
                                    <value>#1</value>
                                </enumeratedValue>
                            </enumeratedValues>
                        </field>
                        <field>
                            <name>ATTCH</name>
                            <description>ATTCH Interrupt Status</description>
                            <lsb>11</lsb>
                            <msb>11</msb>
                            <access>read-write</access>
                            <enumeratedValues>
                                <enumeratedValue>
                                    <name>0</name>
                                    <description>No ATTCH interrupt occurred</description>
                                    <value>#0</value>
                                </enumeratedValue>
                                <enumeratedValue>
                                    <name>1</name>
                                    <description>ATTCH interrupt occurred</description>
                                    <value>#1</value>
                                </enumeratedValue>
                            </enumeratedValues>
                        </field>
                        <field>
                            <name>DTCH</name>
                            <description>USB Disconnection Detection Interrupt Status</description>
                            <lsb>12</lsb>
                            <msb>12</msb>
                            <access>read-write</access>
                            <enumeratedValues>
                                <enumeratedValue>
                                    <name>0</name>
                                    <description>No DTCH interrupt occurred</description>
                                    <value>#0</value>
                                </enumeratedValue>
                                <enumeratedValue>
                                    <name>1</name>
                                    <description>DTCH interrupt occurred</description>
                                    <value>#1</value>
                                </enumeratedValue>
                            </enumeratedValues>
                        </field>
                        <field>
                            <name>BCHG</name>
                            <description>USB Bus Change Interrupt Status</description>
                            <lsb>14</lsb>
                            <msb>14</msb>
                            <access>read-write</access>
                            <enumeratedValues>
                                <enumeratedValue>
                                    <name>0</name>
                                    <description>No BCHG interrupt occurred</description>
                                    <value>#0</value>
                                </enumeratedValue>
                                <enumeratedValue>
                                    <name>1</name>
                                    <description>BCHG interrupt occurred</description>
                                    <value>#1</value>
                                </enumeratedValue>
                            </enumeratedValues>
                        </field>
                        <field>
                            <name>OVRCR</name>
                            <description>Overcurrent Input Change Interrupt Status</description>
                            <lsb>15</lsb>
                            <msb>15</msb>
                            <access>read-write</access>
                            <enumeratedValues>
                                <enumeratedValue>
                                    <name>0</name>
                                    <description>No OVRCR interrupt occurred</description>
                                    <value>#0</value>
                                </enumeratedValue>
                                <enumeratedValue>
                                    <name>1</name>
                                    <description>OVRCR interrupt occurred</description>
                                    <value>#1</value>
                                </enumeratedValue>
                            </enumeratedValues>
                        </field>
                    </fields>
                </register>
                <register>
                    <name>BRDYSTS</name>
                    <description>BRDY Interrupt Status Register</description>
                    <addressOffset>0x046</addressOffset>
                    <size>16</size>
                    <access>read-write</access>
                    <resetValue>0x0000</resetValue>
                    <resetMask>0xffff</resetMask>
                    <fields>
                        <field>
                            <name>PIPE0BRDY</name>
                            <description>BRDY Interrupt Status for Pipe 0</description>
                            <lsb>0</lsb>
                            <msb>0</msb>
                            <access>read-write</access>
                            <enumeratedValues>
                                <enumeratedValue>
                                    <name>0</name>
                                    <description>No BRDY interrupt occurred</description>
                                    <value>#0</value>
                                </enumeratedValue>
                                <enumeratedValue>
                                    <name>1</name>
                                    <description>BRDY interrupt occurred</description>
                                    <value>#1</value>
                                </enumeratedValue>
                            </enumeratedValues>
                        </field>
                        <field>
                            <name>PIPE1BRDY</name>
                            <description>BRDY Interrupt Status for Pipe 1</description>
                            <lsb>1</lsb>
                            <msb>1</msb>
                            <access>read-write</access>
                            <enumeratedValues>
                                <enumeratedValue>
                                    <name>0</name>
                                    <description>No BRDY interrupt occurred</description>
                                    <value>#0</value>
                                </enumeratedValue>
                                <enumeratedValue>
                                    <name>1</name>
                                    <description>BRDY interrupt occurred</description>
                                    <value>#1</value>
                                </enumeratedValue>
                            </enumeratedValues>
                        </field>
                        <field>
                            <name>PIPE2BRDY</name>
                            <description>BRDY Interrupt Status for Pipe 2</description>
                            <lsb>2</lsb>
                            <msb>2</msb>
                            <access>read-write</access>
                            <enumeratedValues>
                                <enumeratedValue>
                                    <name>0</name>
                                    <description>No BRDY interrupt occurred</description>
                                    <value>#0</value>
                                </enumeratedValue>
                                <enumeratedValue>
                                    <name>1</name>
                                    <description>BRDY interrupt occurred</description>
                                    <value>#1</value>
                                </enumeratedValue>
                            </enumeratedValues>
                        </field>
                        <field>
                            <name>PIPE3BRDY</name>
                            <description>BRDY Interrupt Status for Pipe 3</description>
                            <lsb>3</lsb>
                            <msb>3</msb>
                            <access>read-write</access>
                            <enumeratedValues>
                                <enumeratedValue>
                                    <name>0</name>
                                    <description>No BRDY interrupt occurred</description>
                                    <value>#0</value>
                                </enumeratedValue>
                                <enumeratedValue>
                                    <name>1</name>
                                    <description>BRDY interrupt occurred</description>
                                    <value>#1</value>
                                </enumeratedValue>
                            </enumeratedValues>
                        </field>
                        <field>
                            <name>PIPE4BRDY</name>
                            <description>BRDY Interrupt Status for Pipe 4</description>
                            <lsb>4</lsb>
                            <msb>4</msb>
                            <access>read-write</access>
                            <enumeratedValues>
                                <enumeratedValue>
                                    <name>0</name>
                                    <description>No BRDY interrupt occurred</description>
                                    <value>#0</value>
                                </enumeratedValue>
                                <enumeratedValue>
                                    <name>1</name>
                                    <description>BRDY interrupt occurred</description>
                                    <value>#1</value>
                                </enumeratedValue>
                            </enumeratedValues>
                        </field>
                        <field>
                            <name>PIPE5BRDY</name>
                            <description>BRDY Interrupt Status for Pipe 5</description>
                            <lsb>5</lsb>
                            <msb>5</msb>
                            <access>read-write</access>
                            <enumeratedValues>
                                <enumeratedValue>
                                    <name>0</name>
                                    <description>No BRDY interrupt occurred</description>
                                    <value>#0</value>
                                </enumeratedValue>
                                <enumeratedValue>
                                    <name>1</name>
                                    <description>BRDY interrupt occurred</description>
                                    <value>#1</value>
                                </enumeratedValue>
                            </enumeratedValues>
                        </field>
                        <field>
                            <name>PIPE6BRDY</name>
                            <description>BRDY Interrupt Status for Pipe 6</description>
                            <lsb>6</lsb>
                            <msb>6</msb>
                            <access>read-write</access>
                            <enumeratedValues>
                                <enumeratedValue>
                                    <name>0</name>
                                    <description>No BRDY interrupt occurred</description>
                                    <value>#0</value>
                                </enumeratedValue>
                                <enumeratedValue>
                                    <name>1</name>
                                    <description>BRDY interrupt occurred</description>
                                    <value>#1</value>
                                </enumeratedValue>
                            </enumeratedValues>
                        </field>
                        <field>
                            <name>PIPE7BRDY</name>
                            <description>BRDY Interrupt Status for Pipe 7</description>
                            <lsb>7</lsb>
                            <msb>7</msb>
                            <access>read-write</access>
                            <enumeratedValues>
                                <enumeratedValue>
                                    <name>0</name>
                                    <description>No BRDY interrupt occurred</description>
                                    <value>#0</value>
                                </enumeratedValue>
                                <enumeratedValue>
                                    <name>1</name>
                                    <description>BRDY interrupt occurred</description>
                                    <value>#1</value>
                                </enumeratedValue>
                            </enumeratedValues>
                        </field>
                        <field>
                            <name>PIPE8BRDY</name>
                            <description>BRDY Interrupt Status for Pipe 8</description>
                            <lsb>8</lsb>
                            <msb>8</msb>
                            <access>read-write</access>
                            <enumeratedValues>
                                <enumeratedValue>
                                    <name>0</name>
                                    <description>No BRDY interrupt occurred</description>
                                    <value>#0</value>
                                </enumeratedValue>
                                <enumeratedValue>
                                    <name>1</name>
                                    <description>BRDY interrupt occurred</description>
                                    <value>#1</value>
                                </enumeratedValue>
                            </enumeratedValues>
                        </field>
                        <field>
                            <name>PIPE9BRDY</name>
                            <description>BRDY Interrupt Status for Pipe 9</description>
                            <lsb>9</lsb>
                            <msb>9</msb>
                            <access>read-write</access>
                            <enumeratedValues>
                                <enumeratedValue>
                                    <name>0</name>
                                    <description>No BRDY interrupt occurred</description>
                                    <value>#0</value>
                                </enumeratedValue>
                                <enumeratedValue>
                                    <name>1</name>
                                    <description>BRDY interrupt occurred</description>
                                    <value>#1</value>
                                </enumeratedValue>
                            </enumeratedValues>
                        </field>
                    </fields>
                </register>
                <register>
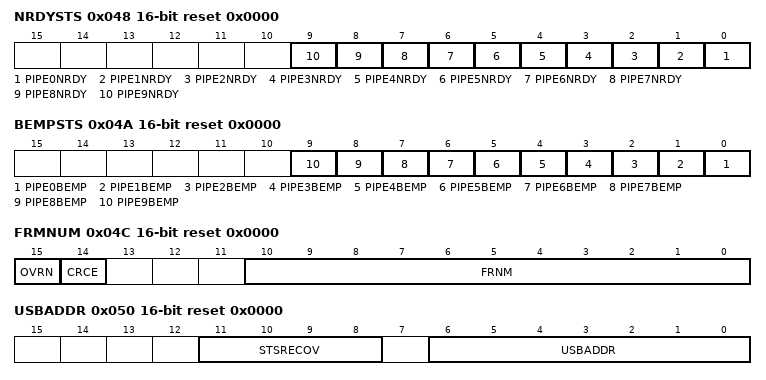
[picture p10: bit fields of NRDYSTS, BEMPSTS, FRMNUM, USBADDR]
                    <name>NRDYSTS</name>
                    <description>NRDY Interrupt Status Register</description>
                    <addressOffset>0x048</addressOffset>
                    <size>16</size>
                    <access>read-write</access>
                    <resetValue>0x0000</resetValue>
                    <resetMask>0xffff</resetMask>
                    <fields>
                        <field>
                            <name>PIPE0NRDY</name>
                            <description>NRDY Interrupt Status for Pipe 0</description>
                            <lsb>0</lsb>
                            <msb>0</msb>
                            <access>read-write</access>
                            <enumeratedValues>
                                <enumeratedValue>
                                    <name>0</name>
                                    <description>No NRDY interrupt occurred</description>
                                    <value>#0</value>
                                </enumeratedValue>
                                <enumeratedValue>
                                    <name>1</name>
                                    <description>NRDY interrupt occurred</description>
                                    <value>#1</value>
                                </enumeratedValue>
                            </enumeratedValues>
                        </field>
                        <field>
                            <name>PIPE1NRDY</name>
                            <description>NRDY Interrupt Status for Pipe 1</description>
                            <lsb>1</lsb>
                            <msb>1</msb>
                            <access>read-write</access>
                            <enumeratedValues>
                                <enumeratedValue>
                                    <name>0</name>
                                    <description>No NRDY interrupt occurred</description>
                                    <value>#0</value>
                                </enumeratedValue>
                                <enumeratedValue>
                                    <name>1</name>
                                    <description>NRDY interrupt occurred</description>
                                    <value>#1</value>
                                </enumeratedValue>
                            </enumeratedValues>
                        </field>
                        <field>
                            <name>PIPE2NRDY</name>
                            <description>NRDY Interrupt Status for Pipe 2</description>
                            <lsb>2</lsb>
                            <msb>2</msb>
                            <access>read-write</access>
                            <enumeratedValues>
                                <enumeratedValue>
                                    <name>0</name>
                                    <description>No NRDY interrupt occurred</description>
                                    <value>#0</value>
                                </enumeratedValue>
                                <enumeratedValue>
                                    <name>1</name>
                                    <description>NRDY interrupt occurred</description>
                                    <value>#1</value>
                                </enumeratedValue>
                            </enumeratedValues>
                        </field>
                        <field>
                            <name>PIPE3NRDY</name>
                            <description>NRDY Interrupt Status for Pipe 3</description>
                            <lsb>3</lsb>
                            <msb>3</msb>
                            <access>read-write</access>
                            <enumeratedValues>
                                <enumeratedValue>
                                    <name>0</name>
                                    <description>No NRDY interrupt occurred</description>
                                    <value>#0</value>
                                </enumeratedValue>
                                <enumeratedValue>
                                    <name>1</name>
                                    <description>NRDY interrupt occurred</description>
                                    <value>#1</value>
                                </enumeratedValue>
                            </enumeratedValues>
                        </field>
                        <field>
                            <name>PIPE4NRDY</name>
                            <description>NRDY Interrupt Status for Pipe 4</description>
                            <lsb>4</lsb>
                            <msb>4</msb>
                            <access>read-write</access>
                            <enumeratedValues>
                                <enumeratedValue>
                                    <name>0</name>
                                    <description>No NRDY interrupt occurred</description>
                                    <value>#0</value>
                                </enumeratedValue>
                                <enumeratedValue>
                                    <name>1</name>
                                    <description>NRDY interrupt occurred</description>
                                    <value>#1</value>
                                </enumeratedValue>
                            </enumeratedValues>
                        </field>
                        <field>
                            <name>PIPE5NRDY</name>
                            <description>NRDY Interrupt Status for Pipe 5</description>
                            <lsb>5</lsb>
                            <msb>5</msb>
                            <access>read-write</access>
                            <enumeratedValues>
                                <enumeratedValue>
                                    <name>0</name>
                                    <description>No NRDY interrupt occurred</description>
                                    <value>#0</value>
                                </enumeratedValue>
                                <enumeratedValue>
                                    <name>1</name>
                                    <description>NRDY interrupt occurred</description>
                                    <value>#1</value>
                                </enumeratedValue>
                            </enumeratedValues>
                        </field>
                        <field>
                            <name>PIPE6NRDY</name>
                            <description>NRDY Interrupt Status for Pipe 6</description>
                            <lsb>6</lsb>
                            <msb>6</msb>
                            <access>read-write</access>
                            <enumeratedValues>
                                <enumeratedValue>
                                    <name>0</name>
                                    <description>No NRDY interrupt occurred</description>
                                    <value>#0</value>
                                </enumeratedValue>
                                <enumeratedValue>
                                    <name>1</name>
                                    <description>NRDY interrupt occurred</description>
                                    <value>#1</value>
                                </enumeratedValue>
                            </enumeratedValues>
                        </field>
                        <field>
                            <name>PIPE7NRDY</name>
                            <description>NRDY Interrupt Status for Pipe 7</description>
                            <lsb>7</lsb>
                            <msb>7</msb>
                            <access>read-write</access>
                            <enumeratedValues>
                                <enumeratedValue>
                                    <name>0</name>
                                    <description>No NRDY interrupt occurred</description>
                                    <value>#0</value>
                                </enumeratedValue>
                                <enumeratedValue>
                                    <name>1</name>
                                    <description>NRDY interrupt occurred</description>
                                    <value>#1</value>
                                </enumeratedValue>
                            </enumeratedValues>
                        </field>
                        <field>
                            <name>PIPE8NRDY</name>
                            <description>NRDY Interrupt Status for Pipe 8</description>
                            <lsb>8</lsb>
                            <msb>8</msb>
                            <access>read-write</access>
                            <enumeratedValues>
                                <enumeratedValue>
                                    <name>0</name>
                                    <description>No NRDY interrupt occurred</description>
                                    <value>#0</value>
                                </enumeratedValue>
                                <enumeratedValue>
                                    <name>1</name>
                                    <description>NRDY interrupt occurred</description>
                                    <value>#1</value>
                                </enumeratedValue>
                            </enumeratedValues>
                        </field>
                        <field>
                            <name>PIPE9NRDY</name>
                            <description>NRDY Interrupt Status for Pipe 9</description>
                            <lsb>9</lsb>
                            <msb>9</msb>
                            <access>read-write</access>
                            <enumeratedValues>
                                <enumeratedValue>
                                    <name>0</name>
                                    <description>No NRDY interrupt occurred</description>
                                    <value>#0</value>
                                </enumeratedValue>
                                <enumeratedValue>
                                    <name>1</name>
                                    <description>NRDY interrupt occurred</description>
                                    <value>#1</value>
                                </enumeratedValue>
                            </enumeratedValues>
                        </field>
                    </fields>
                </register>
                <register>
                    <name>BEMPSTS</name>
                    <description>BEMP Interrupt Status Register</description>
                    <addressOffset>0x04A</addressOffset>
                    <size>16</size>
                    <access>read-write</access>
                    <resetValue>0x0000</resetValue>
                    <resetMask>0xffff</resetMask>
                    <fields>
                        <field>
                            <name>PIPE0BEMP</name>
                            <description>BEMP Interrupt Status for Pipe 0</description>
                            <lsb>0</lsb>
                            <msb>0</msb>
                            <access>read-write</access>
                            <enumeratedValues>
                                <enumeratedValue>
                                    <name>0</name>
                                    <description>No BEMP interrupt occurred</description>
                                    <value>#0</value>
                                </enumeratedValue>
                                <enumeratedValue>
                                    <name>1</name>
                                    <description>BEMP interrupt occurred</description>
                                    <value>#1</value>
                                </enumeratedValue>
                            </enumeratedValues>
                        </field>
                        <field>
                            <name>PIPE1BEMP</name>
                            <description>BEMP Interrupt Status for Pipe 1</description>
                            <lsb>1</lsb>
                            <msb>1</msb>
                            <access>read-write</access>
                            <enumeratedValues>
                                <enumeratedValue>
                                    <name>0</name>
                                    <description>No BEMP interrupt occurred</description>
                                    <value>#0</value>
                                </enumeratedValue>
                                <enumeratedValue>
                                    <name>1</name>
                                    <description>BEMP interrupt occurred</description>
                                    <value>#1</value>
                                </enumeratedValue>
                            </enumeratedValues>
                        </field>
                        <field>
                            <name>PIPE2BEMP</name>
                            <description>BEMP Interrupt Status for Pipe 2</description>
                            <lsb>2</lsb>
                            <msb>2</msb>
                            <access>read-write</access>
                            <enumeratedValues>
                                <enumeratedValue>
                                    <name>0</name>
                                    <description>No BEMP interrupt occurred</description>
                                    <value>#0</value>
                                </enumeratedValue>
                                <enumeratedValue>
                                    <name>1</name>
                                    <description>BEMP interrupt occurred</description>
                                    <value>#1</value>
                                </enumeratedValue>
                            </enumeratedValues>
                        </field>
                        <field>
                            <name>PIPE3BEMP</name>
                            <description>BEMP Interrupt Status for Pipe 3</description>
                            <lsb>3</lsb>
                            <msb>3</msb>
                            <access>read-write</access>
                            <enumeratedValues>
                                <enumeratedValue>
                                    <name>0</name>
                                    <description>No BEMP interrupt occurred</description>
                                    <value>#0</value>
                                </enumeratedValue>
                                <enumeratedValue>
                                    <name>1</name>
                                    <description>BEMP interrupt occurred</description>
                                    <value>#1</value>
                                </enumeratedValue>
                            </enumeratedValues>
                        </field>
                        <field>
                            <name>PIPE4BEMP</name>
                            <description>BEMP Interrupt Status for Pipe 4</description>
                            <lsb>4</lsb>
                            <msb>4</msb>
                            <access>read-write</access>
                            <enumeratedValues>
                                <enumeratedValue>
                                    <name>0</name>
                                    <description>No BEMP interrupt occurred</description>
                                    <value>#0</value>
                                </enumeratedValue>
                                <enumeratedValue>
                                    <name>1</name>
                                    <description>BEMP interrupt occurred</description>
                                    <value>#1</value>
                                </enumeratedValue>
                            </enumeratedValues>
                        </field>
                        <field>
                            <name>PIPE5BEMP</name>
                            <description>BEMP Interrupt Status for Pipe 5</description>
                            <lsb>5</lsb>
                            <msb>5</msb>
                            <access>read-write</access>
                            <enumeratedValues>
                                <enumeratedValue>
                                    <name>0</name>
                                    <description>No BEMP interrupt occurred</description>
                                    <value>#0</value>
                                </enumeratedValue>
                                <enumeratedValue>
                                    <name>1</name>
                                    <description>BEMP interrupt occurred</description>
                                    <value>#1</value>
                                </enumeratedValue>
                            </enumeratedValues>
                        </field>
                        <field>
                            <name>PIPE6BEMP</name>
                            <description>BEMP Interrupt Status for Pipe 6</description>
                            <lsb>6</lsb>
                            <msb>6</msb>
                            <access>read-write</access>
                            <enumeratedValues>
                                <enumeratedValue>
                                    <name>0</name>
                                    <description>No BEMP interrupt occurred</description>
                                    <value>#0</value>
                                </enumeratedValue>
                                <enumeratedValue>
                                    <name>1</name>
                                    <description>BEMP interrupt occurred</description>
                                    <value>#1</value>
                                </enumeratedValue>
                            </enumeratedValues>
                        </field>
                        <field>
                            <name>PIPE7BEMP</name>
                            <description>BEMP Interrupt Status for Pipe 7</description>
                            <lsb>7</lsb>
                            <msb>7</msb>
                            <access>read-write</access>
                            <enumeratedValues>
                                <enumeratedValue>
                                    <name>0</name>
                                    <description>No BEMP interrupt occurred</description>
                                    <value>#0</value>
                                </enumeratedValue>
                                <enumeratedValue>
                                    <name>1</name>
                                    <description>BEMP interrupt occurred</description>
                                    <value>#1</value>
                                </enumeratedValue>
                            </enumeratedValues>
                        </field>
                        <field>
                            <name>PIPE8BEMP</name>
                            <description>BEMP Interrupt Status for Pipe 8</description>
                            <lsb>8</lsb>
                            <msb>8</msb>
                            <access>read-write</access>
                            <enumeratedValues>
                                <enumeratedValue>
                                    <name>0</name>
                                    <description>No BEMP interrupt occurred</description>
                                    <value>#0</value>
                                </enumeratedValue>
                                <enumeratedValue>
                                    <name>1</name>
                                    <description>BEMP interrupt occurred</description>
                                    <value>#1</value>
                                </enumeratedValue>
                            </enumeratedValues>
                        </field>
                        <field>
                            <name>PIPE9BEMP</name>
                            <description>BEMP Interrupt Status for Pipe 9</description>
                            <lsb>9</lsb>
                            <msb>9</msb>
                            <access>read-write</access>
                            <enumeratedValues>
                                <enumeratedValue>
                                    <name>0</name>
                                    <description>No BEMP interrupt occurred</description>
                                    <value>#0</value>
                                </enumeratedValue>
                                <enumeratedValue>
                                    <name>1</name>
                                    <description>BEMP interrupt occurred</description>
                                    <value>#1</value>
                                </enumeratedValue>
                            </enumeratedValues>
                        </field>
                    </fields>
                </register>
                <register>
                    <name>FRMNUM</name>
                    <description>Frame Number Register</description>
                    <addressOffset>0x04C</addressOffset>
                    <size>16</size>
                    <access>read-write</access>
                    <resetValue>0x0000</resetValue>
                    <resetMask>0xffff</resetMask>
                    <fields>
                        <field>
                            <name>FRNM</name>
                            <description>Frame Number</description>
                            <lsb>0</lsb>
                            <msb>10</msb>
                            <access>read-only</access>
                        </field>
                        <field>
                            <name>CRCE</name>
                            <description>Receive Data Error</description>
                            <lsb>14</lsb>
                            <msb>14</msb>
                            <access>read-write</access>
                            <enumeratedValues>
                                <enumeratedValue>
                                    <name>0</name>
                                    <description>No error occurred</description>
                                    <value>#0</value>
                                </enumeratedValue>
                                <enumeratedValue>
                                    <name>1</name>
                                    <description>Error occurred</description>
                                    <value>#1</value>
                                </enumeratedValue>
                            </enumeratedValues>
                        </field>
                        <field>
                            <name>OVRN</name>
                            <description>Overrun/Underrun Detection Status</description>
                            <lsb>15</lsb>
                            <msb>15</msb>
                            <access>read-write</access>
                            <enumeratedValues>
                                <enumeratedValue>
                                    <name>0</name>
                                    <description>No error occurred</description>
                                    <value>#0</value>
                                </enumeratedValue>
                                <enumeratedValue>
                                    <name>1</name>
                                    <description>Error occurred</description>
                                    <value>#1</value>
                                </enumeratedValue>
                            </enumeratedValues>
                        </field>
                    </fields>
                </register>
                <register>
                    <name>DVCHGR</name>
                    <description>Device State Change Register</description>
                    <addressOffset>0x04E</addressOffset>
                    <size>16</size>
                    <access>read-write</access>
                    <resetValue>0x0000</resetValue>
                    <resetMask>0xffff</resetMask>
                    <fields>
                        <field>
                            <name>DVCHG</name>
                            <description>Device State Change</description>
                            <lsb>15</lsb>
                            <msb>15</msb>
                            <access>read-write</access>
                            <enumeratedValues>
                                <enumeratedValue>
                                    <name>0</name>
                                    <description>Disable writes to the USBADDR.STSRECOV[3:0] and USBADDR.USBADDR[6:0] bits</description>
                                    <value>#0</value>
                                </enumeratedValue>
                                <enumeratedValue>
                                    <name>1</name>
                                    <description>Enable writes to the USBADDR.STSRECOV[3:0] and USBADDR.USBADDR[6:0] bits</description>
                                    <value>#1</value>
                                </enumeratedValue>
                            </enumeratedValues>
                        </field>
                    </fields>
                </register>
                <register>
                    <name>USBADDR</name>
                    <description>USB Address Register</description>
                    <addressOffset>0x050</addressOffset>
                    <size>16</size>
                    <access>read-write</access>
                    <resetValue>0x0000</resetValue>
                    <resetMask>0xffff</resetMask>
                    <fields>
                        <field>
                            <name>USBADDR</name>
                            <description>USB Address</description>
                            <lsb>0</lsb>
                            <msb>6</msb>
                            <access>read-write</access>
                        </field>
                        <field>
                            <name>STSRECOV</name>
                            <description>Status Recovery</description>
                            <lsb>8</lsb>
                            <msb>11</msb>
                            <access>read-write</access>
                            <enumeratedValues>
                                <enumeratedValue>
                                    <name>0x4</name>
                                    <description>Recovery in device controller mode: Setting prohibited Recovery in host controller mode: Return to the low-speed state (bits DVSTCTR0.RHST[2:0] = 001b) </description>
                                    <value>0x4</value>
                                </enumeratedValue>
                                <enumeratedValue>
                                    <name>0x8</name>
                                    <description>Recovery in device controller mode: Setting prohibited Recovery in host controller mode: Return to the full-speed state (bits DVSTCTR0.RHST[2:0] = 010b) </description>
                                    <value>0x8</value>
                                </enumeratedValue>
                                <enumeratedValue>
                                    <name>0x9</name>
                                    <description>Recovery in device controller mode: Return to the full-speed state (bits DVSTCTR0.RHST[2:0] = 010b), bits INTSTS0.DVSQ[2:0] = 001b (default state) Recovery in host controller mode: Setting prohibited </description>
                                    <value>0x9</value>
                                </enumeratedValue>
                                <enumeratedValue>
                                    <name>0xA</name>
                                    <description>Recovery in device controller mode: Return to the full-speed state (bits DVSTCTR0.RHST[2:0] = 010b), bits INTSTS0.DVSQ[2:0] = 010b (address state) Recovery in host controller mode: Setting prohibited </description>
                                    <value>0xa</value>
                                </enumeratedValue>
                                <enumeratedValue>
                                    <name>0xB</name>
                                    <description>Recovery in device controller mode: Return to the full-speed state (bits DVSTCTR0.RHST[2:0] = 010b), bits INTSTS0.DVSQ[2:0] = 011b (configured state) Recovery in host controller mode: Setting prohibited </description>
                                    <value>0xb</value>
                                </enumeratedValue>
                                <enumeratedValue>
                                    <name>Others</name>
                                    <description>Setting prohibited</description>
                                    <isDefault>true</isDefault>
                                </enumeratedValue>
                            </enumeratedValues>
                        </field>
                    </fields>
                </register>
                <register>
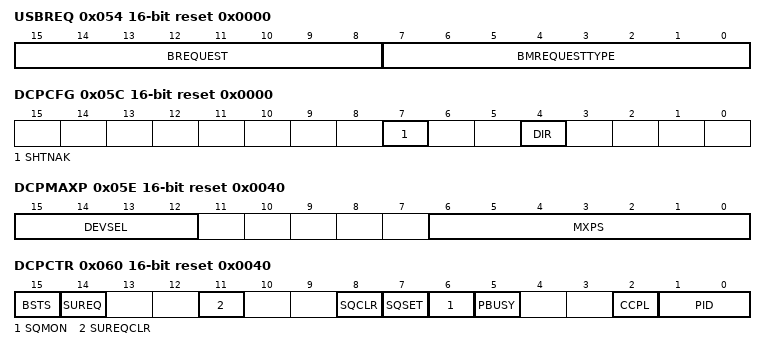
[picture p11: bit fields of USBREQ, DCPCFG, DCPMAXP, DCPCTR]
                    <name>USBREQ</name>
                    <description>USB Request Type Register</description>
                    <addressOffset>0x054</addressOffset>
                    <size>16</size>
                    <access>read-write</access>
                    <resetValue>0x0000</resetValue>
                    <resetMask>0xffff</resetMask>
                    <fields>
                        <field>
                            <name>BMREQUESTTYPE</name>
                            <description>Request Type</description>
                            <lsb>0</lsb>
                            <msb>7</msb>
                            <access>read-write</access>
                        </field>
                        <field>
                            <name>BREQUEST</name>
                            <description>Request</description>
                            <lsb>8</lsb>
                            <msb>15</msb>
                            <access>read-write</access>
                        </field>
                    </fields>
                </register>
                <register>
                    <name>USBVAL</name>
                    <description>USB Request Value Register</description>
                    <addressOffset>0x056</addressOffset>
                    <size>16</size>
                    <access>read-write</access>
                    <resetValue>0x0000</resetValue>
                    <resetMask>0xffff</resetMask>
                    <fields>
                        <field>
                            <name>WVALUE</name>
                            <description>Value</description>
                            <lsb>0</lsb>
                            <msb>15</msb>
                            <access>read-write</access>
                        </field>
                    </fields>
                </register>
                <register>
                    <name>USBINDX</name>
                    <description>USB Request Index Register</description>
                    <addressOffset>0x058</addressOffset>
                    <size>16</size>
                    <access>read-write</access>
                    <resetValue>0x0000</resetValue>
                    <resetMask>0xffff</resetMask>
                    <fields>
                        <field>
                            <name>WINDEX</name>
                            <description>Index</description>
                            <lsb>0</lsb>
                            <msb>15</msb>
                            <access>read-write</access>
                        </field>
                    </fields>
                </register>
                <register>
                    <name>USBLENG</name>
                    <description>USB Request Length Register</description>
                    <addressOffset>0x05A</addressOffset>
                    <size>16</size>
                    <access>read-write</access>
                    <resetValue>0x0000</resetValue>
                    <resetMask>0xffff</resetMask>
                    <fields>
                        <field>
                            <name>WLENTUH</name>
                            <description>Length</description>
                            <lsb>0</lsb>
                            <msb>15</msb>
                            <access>read-write</access>
                        </field>
                    </fields>
                </register>
                <register>
                    <name>DCPCFG</name>
                    <description>DCP Configuration Register</description>
                    <addressOffset>0x05C</addressOffset>
                    <size>16</size>
                    <access>read-write</access>
                    <resetValue>0x0000</resetValue>
                    <resetMask>0xffff</resetMask>
                    <fields>
                        <field>
                            <name>DIR</name>
                            <description>Transfer Direction</description>
                            <lsb>4</lsb>
                            <msb>4</msb>
                            <access>read-write</access>
                            <enumeratedValues>
                                <enumeratedValue>
                                    <name>0</name>
                                    <description>Data receiving direction</description>
                                    <value>#0</value>
                                </enumeratedValue>
                                <enumeratedValue>
                                    <name>1</name>
                                    <description>Data transmitting direction</description>
                                    <value>#1</value>
                                </enumeratedValue>
                            </enumeratedValues>
                        </field>
                        <field>
                            <name>SHTNAK</name>
                            <description>Pipe Disabled at End of Transfer</description>
                            <lsb>7</lsb>
                            <msb>7</msb>
                            <access>read-write</access>
                            <enumeratedValues>
                                <enumeratedValue>
                                    <name>0</name>
                                    <description>Keep pipe open after transfer ends</description>
                                    <value>#0</value>
                                </enumeratedValue>
                                <enumeratedValue>
                                    <name>1</name>
                                    <description>Disable pipe after transfer ends</description>
                                    <value>#1</value>
                                </enumeratedValue>
                            </enumeratedValues>
                        </field>
                    </fields>
                </register>
                <register>
                    <name>DCPMAXP</name>
                    <description>DCP Maximum Packet Size Register</description>
                    <addressOffset>0x05E</addressOffset>
                    <size>16</size>
                    <access>read-write</access>
                    <resetValue>0x0040</resetValue>
                    <resetMask>0xffff</resetMask>
                    <fields>
                        <field>
                            <name>MXPS</name>
                            <description>Maximum Packet Size</description>
                            <lsb>0</lsb>
                            <msb>6</msb>
                            <access>read-write</access>
                        </field>
                        <field>
                            <name>DEVSEL</name>
                            <description>Device Select</description>
                            <lsb>12</lsb>
                            <msb>15</msb>
                            <access>read-write</access>
                            <enumeratedValues>
                                <enumeratedValue>
                                    <name>0x0</name>
                                    <description>Address 0000b</description>
                                    <value>0x0</value>
                                </enumeratedValue>
                                <enumeratedValue>
                                    <name>0x1</name>
                                    <description>Address 0001b</description>
                                    <value>0x1</value>
                                </enumeratedValue>
                                <enumeratedValue>
                                    <name>0x2</name>
                                    <description>Address 0010b</description>
                                    <value>0x2</value>
                                </enumeratedValue>
                                <enumeratedValue>
                                    <name>0x3</name>
                                    <description>Address 0011b</description>
                                    <value>0x3</value>
                                </enumeratedValue>
                                <enumeratedValue>
                                    <name>0x4</name>
                                    <description>Address 0100b</description>
                                    <value>0x4</value>
                                </enumeratedValue>
                                <enumeratedValue>
                                    <name>0x5</name>
                                    <description>Address 0101b</description>
                                    <value>0x5</value>
                                </enumeratedValue>
                                <enumeratedValue>
                                    <name>Others</name>
                                    <description>Setting prohibited</description>
                                    <isDefault>true</isDefault>
                                </enumeratedValue>
                            </enumeratedValues>
                        </field>
                    </fields>
                </register>
                <register>
                    <name>DCPCTR</name>
                    <description>DCP Control Register</description>
                    <addressOffset>0x060</addressOffset>
                    <size>16</size>
                    <access>read-write</access>
                    <resetValue>0x0040</resetValue>
                    <resetMask>0xffff</resetMask>
                    <fields>
                        <field>
                            <name>PID</name>
                            <description>Response PID</description>
                            <lsb>0</lsb>
                            <msb>1</msb>
                            <access>read-write</access>
                            <enumeratedValues>
                                <enumeratedValue>
                                    <name>00</name>
                                    <description>NAK response</description>
                                    <value>#00</value>
                                </enumeratedValue>
                                <enumeratedValue>
                                    <name>01</name>
                                    <description>BUF response (depends on the buffer state)</description>
                                    <value>#01</value>
                                </enumeratedValue>
                                <enumeratedValue>
                                    <name>10</name>
                                    <description>STALL response</description>
                                    <value>#10</value>
                                </enumeratedValue>
                                <enumeratedValue>
                                    <name>11</name>
                                    <description>STALL response</description>
                                    <value>#11</value>
                                </enumeratedValue>
                            </enumeratedValues>
                        </field>
                        <field>
                            <name>CCPL</name>
                            <description>Control Transfer End Enable</description>
                            <lsb>2</lsb>
                            <msb>2</msb>
                            <access>read-write</access>
                            <enumeratedValues>
                                <enumeratedValue>
                                    <name>0</name>
                                    <description>Disable control transfer completion</description>
                                    <value>#0</value>
                                </enumeratedValue>
                                <enumeratedValue>
                                    <name>1</name>
                                    <description>Enable control transfer completion</description>
                                    <value>#1</value>
                                </enumeratedValue>
                            </enumeratedValues>
                        </field>
                        <field>
                            <name>PBUSY</name>
                            <description>Pipe Busy</description>
                            <lsb>5</lsb>
                            <msb>5</msb>
                            <access>read-only</access>
                            <enumeratedValues>
                                <enumeratedValue>
                                    <name>0</name>
                                    <description>DCP not used for the USB bus</description>
                                    <value>#0</value>
                                </enumeratedValue>
                                <enumeratedValue>
                                    <name>1</name>
                                    <description>DCP in use for the USB bus</description>
                                    <value>#1</value>
                                </enumeratedValue>
                            </enumeratedValues>
                        </field>
                        <field>
                            <name>SQMON</name>
                            <description>Sequence Toggle Bit Monitor</description>
                            <lsb>6</lsb>
                            <msb>6</msb>
                            <access>read-only</access>
                            <enumeratedValues>
                                <enumeratedValue>
                                    <name>0</name>
                                    <description>DATA0</description>
                                    <value>#0</value>
                                </enumeratedValue>
                                <enumeratedValue>
                                    <name>1</name>
                                    <description>DATA1</description>
                                    <value>#1</value>
                                </enumeratedValue>
                            </enumeratedValues>
                        </field>
                        <field>
                            <name>SQSET</name>
                            <description>Sequence Toggle Bit Set</description>
                            <lsb>7</lsb>
                            <msb>7</msb>
                            <access>read-write</access>
                            <enumeratedValues>
                                <enumeratedValue>
                                    <name>0</name>
                                    <description>Invalid (writing 0 has no effect)</description>
                                    <value>#0</value>
                                </enumeratedValue>
                                <enumeratedValue>
                                    <name>1</name>
                                    <description>Set the expected value for the next transaction to DATA1</description>
                                    <value>#1</value>
                                </enumeratedValue>
                            </enumeratedValues>
                        </field>
                        <field>
                            <name>SQCLR</name>
                            <description>Sequence Toggle Bit Clear</description>
                            <lsb>8</lsb>
                            <msb>8</msb>
                            <access>read-write</access>
                            <enumeratedValues>
                                <enumeratedValue>
                                    <name>0</name>
                                    <description>Invalid (writing 0 has no effect)</description>
                                    <value>#0</value>
                                </enumeratedValue>
                                <enumeratedValue>
                                    <name>1</name>
                                    <description>Clear the expected value for the next transaction to DATA0</description>
                                    <value>#1</value>
                                </enumeratedValue>
                            </enumeratedValues>
                        </field>
                        <field>
                            <name>SUREQCLR</name>
                            <description>SUREQ Bit Clear</description>
                            <lsb>11</lsb>
                            <msb>11</msb>
                            <access>read-write</access>
                            <enumeratedValues>
                                <enumeratedValue>
                                    <name>0</name>
                                    <description>Invalid (writing 0 has no effect)</description>
                                    <value>#0</value>
                                </enumeratedValue>
                                <enumeratedValue>
                                    <name>1</name>
                                    <description>Clear SUREQ to 0</description>
                                    <value>#1</value>
                                </enumeratedValue>
                            </enumeratedValues>
                        </field>
                        <field>
                            <name>SUREQ</name>
                            <description>Setup Token Transmission</description>
                            <lsb>14</lsb>
                            <msb>14</msb>
                            <access>read-write</access>
                            <enumeratedValues>
                                <enumeratedValue>
                                    <name>0</name>
                                    <description>Invalid (writing 0 has no effect)</description>
                                    <value>#0</value>
                                </enumeratedValue>
                                <enumeratedValue>
                                    <name>1</name>
                                    <description>Transmit setup packet</description>
                                    <value>#1</value>
                                </enumeratedValue>
                            </enumeratedValues>
                        </field>
                        <field>
                            <name>BSTS</name>
                            <description>Buffer Status</description>
                            <lsb>15</lsb>
                            <msb>15</msb>
                            <access>read-only</access>
                            <enumeratedValues>
                                <enumeratedValue>
                                    <name>0</name>
                                    <description>Buffer access disabled</description>
                                    <value>#0</value>
                                </enumeratedValue>
                                <enumeratedValue>
                                    <name>1</name>
                                    <description>Buffer access enabled</description>
                                    <value>#1</value>
                                </enumeratedValue>
                            </enumeratedValues>
                        </field>
                    </fields>
                </register>
                <register>
                    <name>PIPESEL</name>
                    <description>Pipe Window Select Register</description>
                    <addressOffset>0x064</addressOffset>
                    <size>16</size>
                    <access>read-write</access>
                    <resetValue>0x0000</resetValue>
                    <resetMask>0xffff</resetMask>
                    <fields>
                        <field>
                            <name>PIPESEL</name>
                            <description>Pipe Window Select</description>
                            <lsb>0</lsb>
                            <msb>3</msb>
                            <access>read-write</access>
                            <enumeratedValues>
                                <enumeratedValue>
                                    <name>0x0</name>
                                    <description>No pipe selected</description>
                                    <value>0x0</value>
                                </enumeratedValue>
                                <enumeratedValue>
                                    <name>0x1</name>
                                    <description>Pipe 1</description>
                                    <value>0x1</value>
                                </enumeratedValue>
                                <enumeratedValue>
                                    <name>0x2</name>
                                    <description>Pipe 2</description>
                                    <value>0x2</value>
                                </enumeratedValue>
                                <enumeratedValue>
                                    <name>0x3</name>
                                    <description>Pipe 3</description>
                                    <value>0x3</value>
                                </enumeratedValue>
                                <enumeratedValue>
                                    <name>0x4</name>
                                    <description>Pipe 4</description>
                                    <value>0x4</value>
                                </enumeratedValue>
                                <enumeratedValue>
                                    <name>0x5</name>
                                    <description>Pipe 5</description>
                                    <value>0x5</value>
                                </enumeratedValue>
                                <enumeratedValue>
                                    <name>0x6</name>
                                    <description>Pipe 6</description>
                                    <value>0x6</value>
                                </enumeratedValue>
                                <enumeratedValue>
                                    <name>0x7</name>
                                    <description>Pipe 7</description>
                                    <value>0x7</value>
                                </enumeratedValue>
                                <enumeratedValue>
                                    <name>0x8</name>
                                    <description>Pipe 8</description>
                                    <value>0x8</value>
                                </enumeratedValue>
                                <enumeratedValue>
                                    <name>0x9</name>
                                    <description>Pipe 9</description>
                                    <value>0x9</value>
                                </enumeratedValue>
                                <enumeratedValue>
                                    <name>Others</name>
                                    <description>Setting prohibited</description>
                                    <isDefault>true</isDefault>
                                </enumeratedValue>
                            </enumeratedValues>
                        </field>
                    </fields>
                </register>
                <register>
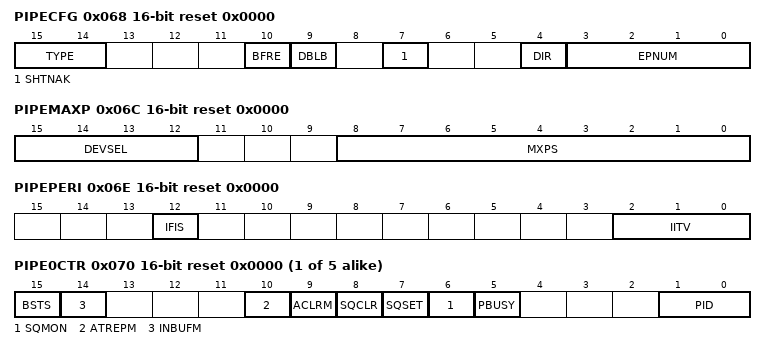
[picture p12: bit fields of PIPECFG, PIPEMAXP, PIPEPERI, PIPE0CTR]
                    <name>PIPECFG</name>
                    <description>Pipe Configuration Register</description>
                    <addressOffset>0x068</addressOffset>
                    <size>16</size>
                    <access>read-write</access>
                    <resetValue>0x0000</resetValue>
                    <resetMask>0xffff</resetMask>
                    <fields>
                        <field>
                            <name>EPNUM</name>
                            <description>Endpoint Number</description>
                            <lsb>0</lsb>
                            <msb>3</msb>
                            <access>read-write</access>
                        </field>
                        <field>
                            <name>DIR</name>
                            <description>Transfer Direction</description>
                            <lsb>4</lsb>
                            <msb>4</msb>
                            <access>read-write</access>
                            <enumeratedValues>
                                <enumeratedValue>
                                    <name>0</name>
                                    <description>Receiving direction</description>
                                    <value>#0</value>
                                </enumeratedValue>
                                <enumeratedValue>
                                    <name>1</name>
                                    <description>Transmitting direction</description>
                                    <value>#1</value>
                                </enumeratedValue>
                            </enumeratedValues>
                        </field>
                        <field>
                            <name>SHTNAK</name>
                            <description>Pipe Disabled at End of Transfer</description>
                            <lsb>7</lsb>
                            <msb>7</msb>
                            <access>read-write</access>
                            <enumeratedValues>
                                <enumeratedValue>
                                    <name>0</name>
                                    <description>Continue pipe operation after transfer ends</description>
                                    <value>#0</value>
                                </enumeratedValue>
                                <enumeratedValue>
                                    <name>1</name>
                                    <description>Disable pipe after transfer ends</description>
                                    <value>#1</value>
                                </enumeratedValue>
                            </enumeratedValues>
                        </field>
                        <field>
                            <name>DBLB</name>
                            <description>Double Buffer Mode</description>
                            <lsb>9</lsb>
                            <msb>9</msb>
                            <access>read-write</access>
                            <enumeratedValues>
                                <enumeratedValue>
                                    <name>0</name>
                                    <description>Single buffer</description>
                                    <value>#0</value>
                                </enumeratedValue>
                                <enumeratedValue>
                                    <name>1</name>
                                    <description>Double buffer</description>
                                    <value>#1</value>
                                </enumeratedValue>
                            </enumeratedValues>
                        </field>
                        <field>
                            <name>BFRE</name>
                            <description>BRDY Interrupt Operation Specification</description>
                            <lsb>10</lsb>
                            <msb>10</msb>
                            <access>read-write</access>
                            <enumeratedValues>
                                <enumeratedValue>
                                    <name>0</name>
                                    <description>Generate BRDY interrupt on transmitting or receiving data</description>
                                    <value>#0</value>
                                </enumeratedValue>
                                <enumeratedValue>
                                    <name>1</name>
                                    <description>Generate BRDY interrupt on completion of reading data</description>
                                    <value>#1</value>
                                </enumeratedValue>
                            </enumeratedValues>
                        </field>
                        <field>
                            <name>TYPE</name>
                            <description>Transfer Type</description>
                            <lsb>14</lsb>
                            <msb>15</msb>
                            <access>read-write</access>
                            <enumeratedValues>
                                <enumeratedValue>
                                    <name>00</name>
                                    <description>Pipe not used</description>
                                    <value>#00</value>
                                </enumeratedValue>
                                <enumeratedValue>
                                    <name>01</name>
                                    <description>Pipes 1 and 2: Bulk transfer Pipes 3 to 5: Bulk transfer Pipes 6 to 9: Setting prohibited </description>
                                    <value>#01</value>
                                </enumeratedValue>
                                <enumeratedValue>
                                    <name>10</name>
                                    <description>Pipes 1 and 2: Setting prohibited Pipes 3 to 5: Setting prohibited Pipes 6 to 9: Interrupt transfer </description>
                                    <value>#10</value>
                                </enumeratedValue>
                                <enumeratedValue>
                                    <name>11</name>
                                    <description>Pipes 1 and 2: Isochronous transfer Pipes 3 to 5: Setting prohibited Pipes 6 to 9: Setting prohibited </description>
                                    <value>#11</value>
                                </enumeratedValue>
                            </enumeratedValues>
                        </field>
                    </fields>
                </register>
                <register>
                    <name>PIPEMAXP</name>
                    <description>Pipe Maximum Packet Size Register</description>
                    <addressOffset>0x06C</addressOffset>
                    <size>16</size>
                    <access>read-write</access>
                    <resetValue>0x0000</resetValue>
                    <resetMask>0xffbf</resetMask>
                    <fields>
                        <field>
                            <name>MXPS</name>
                            <description>Maximum Packet Size</description>
                            <lsb>0</lsb>
                            <msb>8</msb>
                            <access>read-write</access>
                        </field>
                        <field>
                            <name>DEVSEL</name>
                            <description>Device Select</description>
                            <lsb>12</lsb>
                            <msb>15</msb>
                            <access>read-write</access>
                            <enumeratedValues>
                                <enumeratedValue>
                                    <name>0x0</name>
                                    <description>Address 0000b</description>
                                    <value>0x0</value>
                                </enumeratedValue>
                                <enumeratedValue>
                                    <name>0x1</name>
                                    <description>Address 0001b</description>
                                    <value>0x1</value>
                                </enumeratedValue>
                                <enumeratedValue>
                                    <name>0x2</name>
                                    <description>Address 0010b</description>
                                    <value>0x2</value>
                                </enumeratedValue>
                                <enumeratedValue>
                                    <name>0x3</name>
                                    <description>Address 0011b</description>
                                    <value>0x3</value>
                                </enumeratedValue>
                                <enumeratedValue>
                                    <name>0x4</name>
                                    <description>Address 0100b</description>
                                    <value>0x4</value>
                                </enumeratedValue>
                                <enumeratedValue>
                                    <name>0x5</name>
                                    <description>Address 0101b</description>
                                    <value>0x5</value>
                                </enumeratedValue>
                                <enumeratedValue>
                                    <name>Others</name>
                                    <description>Setting prohibited</description>
                                    <isDefault>true</isDefault>
                                </enumeratedValue>
                            </enumeratedValues>
                        </field>
                    </fields>
                </register>
                <register>
                    <name>PIPEPERI</name>
                    <description>Pipe Cycle Control Register</description>
                    <addressOffset>0x06E</addressOffset>
                    <size>16</size>
                    <access>read-write</access>
                    <resetValue>0x0000</resetValue>
                    <resetMask>0xffff</resetMask>
                    <fields>
                        <field>
                            <name>IITV</name>
                            <description>Interval Error Detection Interval</description>
                            <lsb>0</lsb>
                            <msb>2</msb>
                            <access>read-write</access>
                        </field>
                        <field>
                            <name>IFIS</name>
                            <description>Isochronous IN Buffer Flush</description>
                            <lsb>12</lsb>
                            <msb>12</msb>
                            <access>read-write</access>
                            <enumeratedValues>
                                <enumeratedValue>
                                    <name>0</name>
                                    <description>Do not flush buffer</description>
                                    <value>#0</value>
                                </enumeratedValue>
                                <enumeratedValue>
                                    <name>1</name>
                                    <description>Flush buffer</description>
                                    <value>#1</value>
                                </enumeratedValue>
                            </enumeratedValues>
                        </field>
                    </fields>
                </register>
                <register>
                    <dim>5</dim>
                    <dimIncrement>0x2</dimIncrement>
                    <dimIndex>1-5</dimIndex>
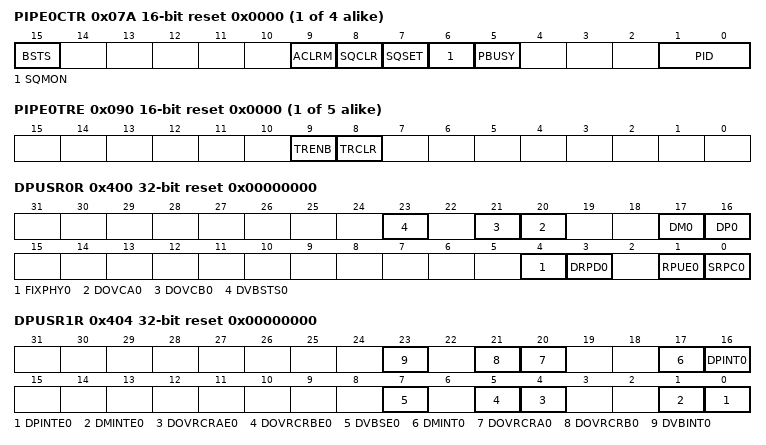
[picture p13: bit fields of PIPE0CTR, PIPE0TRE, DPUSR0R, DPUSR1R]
                    <name>PIPE%sCTR</name>
                    <description>PIPE%s Control Registers</description>
                    <addressOffset>0x070</addressOffset>
                    <size>16</size>
                    <access>read-write</access>
                    <resetValue>0x0000</resetValue>
                    <resetMask>0xffff</resetMask>
                    <fields>
                        <field>
                            <name>PID</name>
                            <description>Response PID</description>
                            <lsb>0</lsb>
                            <msb>1</msb>
                            <access>read-write</access>
                            <enumeratedValues>
                                <enumeratedValue>
                                    <name>00</name>
                                    <description>NAK response</description>
                                    <value>#00</value>
                                </enumeratedValue>
                                <enumeratedValue>
                                    <name>01</name>
                                    <description>BUF response (depends buffer state)</description>
                                    <value>#01</value>
                                </enumeratedValue>
                                <enumeratedValue>
                                    <name>10</name>
                                    <description>STALL response</description>
                                    <value>#10</value>
                                </enumeratedValue>
                                <enumeratedValue>
                                    <name>11</name>
                                    <description>STALL response</description>
                                    <value>#11</value>
                                </enumeratedValue>
                            </enumeratedValues>
                        </field>
                        <field>
                            <name>PBUSY</name>
                            <description>Pipe Busy</description>
                            <lsb>5</lsb>
                            <msb>5</msb>
                            <access>read-only</access>
                            <enumeratedValues>
                                <enumeratedValue>
                                    <name>0</name>
                                    <description>Pipe n not in use for the transaction</description>
                                    <value>#0</value>
                                </enumeratedValue>
                                <enumeratedValue>
                                    <name>1</name>
                                    <description>Pipe n in use for the transaction</description>
                                    <value>#1</value>
                                </enumeratedValue>
                            </enumeratedValues>
                        </field>
                        <field>
                            <name>SQMON</name>
                            <description>Sequence Toggle Bit Confirmation</description>
                            <lsb>6</lsb>
                            <msb>6</msb>
                            <access>read-only</access>
                            <enumeratedValues>
                                <enumeratedValue>
                                    <name>0</name>
                                    <description>DATA0</description>
                                    <value>#0</value>
                                </enumeratedValue>
                                <enumeratedValue>
                                    <name>1</name>
                                    <description>DATA1</description>
                                    <value>#1</value>
                                </enumeratedValue>
                            </enumeratedValues>
                        </field>
                        <field>
                            <name>SQSET</name>
                            <description>Sequence Toggle Bit Set</description>
                            <lsb>7</lsb>
                            <msb>7</msb>
                            <access>read-write</access>
                            <enumeratedValues>
                                <enumeratedValue>
                                    <name>0</name>
                                    <description>Invalid (writing 0 has no effect)</description>
                                    <value>#0</value>
                                </enumeratedValue>
                                <enumeratedValue>
                                    <name>1</name>
                                    <description>Set the expected value for the next transaction to DATA1</description>
                                    <value>#1</value>
                                </enumeratedValue>
                            </enumeratedValues>
                        </field>
                        <field>
                            <name>SQCLR</name>
                            <description>Sequence Toggle Bit Clear</description>
                            <lsb>8</lsb>
                            <msb>8</msb>
                            <access>read-write</access>
                            <enumeratedValues>
                                <enumeratedValue>
                                    <name>0</name>
                                    <description>Invalid (writing 0 has no effect)</description>
                                    <value>#0</value>
                                </enumeratedValue>
                                <enumeratedValue>
                                    <name>1</name>
                                    <description>Clear the expected value for the next transaction to DATA0</description>
                                    <value>#1</value>
                                </enumeratedValue>
                            </enumeratedValues>
                        </field>
                        <field>
                            <name>ACLRM</name>
                            <description>Auto Buffer Clear Mode</description>
                            <lsb>9</lsb>
                            <msb>9</msb>
                            <access>read-write</access>
                            <enumeratedValues>
                                <enumeratedValue>
                                    <name>0</name>
                                    <description>Disable</description>
                                    <value>#0</value>
                                </enumeratedValue>
                                <enumeratedValue>
                                    <name>1</name>
                                    <description>Enable (initialize all buffers)</description>
                                    <value>#1</value>
                                </enumeratedValue>
                            </enumeratedValues>
                        </field>
                        <field>
                            <name>ATREPM</name>
                            <description>Auto Response Mode</description>
                            <lsb>10</lsb>
                            <msb>10</msb>
                            <access>read-write</access>
                            <enumeratedValues>
                                <enumeratedValue>
                                    <name>0</name>
                                    <description>Disable auto response mode</description>
                                    <value>#0</value>
                                </enumeratedValue>
                                <enumeratedValue>
                                    <name>1</name>
                                    <description>Enable auto response mode</description>
                                    <value>#1</value>
                                </enumeratedValue>
                            </enumeratedValues>
                        </field>
                        <field>
                            <name>INBUFM</name>
                            <description>Transmit Buffer Monitor</description>
                            <lsb>14</lsb>
                            <msb>14</msb>
                            <access>read-only</access>
                            <enumeratedValues>
                                <enumeratedValue>
                                    <name>0</name>
                                    <description>No data to be transmitted is in the FIFO buffer</description>
                                    <value>#0</value>
                                </enumeratedValue>
                                <enumeratedValue>
                                    <name>1</name>
                                    <description>Data to be transmitted is in the FIFO buffer</description>
                                    <value>#1</value>
                                </enumeratedValue>
                            </enumeratedValues>
                        </field>
                        <field>
                            <name>BSTS</name>
                            <description>Buffer Status</description>
                            <lsb>15</lsb>
                            <msb>15</msb>
                            <access>read-only</access>
                            <enumeratedValues>
                                <enumeratedValue>
                                    <name>0</name>
                                    <description>Buffer access by the CPU disabled</description>
                                    <value>#0</value>
                                </enumeratedValue>
                                <enumeratedValue>
                                    <name>1</name>
                                    <description>Buffer access by the CPU enabled</description>
                                    <value>#1</value>
                                </enumeratedValue>
                            </enumeratedValues>
                        </field>
                    </fields>
                </register>
                <register>
                    <dim>4</dim>
                    <dimIncrement>0x2</dimIncrement>
                    <dimIndex>6-9</dimIndex>
                    <name>PIPE%sCTR</name>
                    <description>PIPE%s Control Registers</description>
                    <addressOffset>0x07A</addressOffset>
                    <size>16</size>
                    <access>read-write</access>
                    <resetValue>0x0000</resetValue>
                    <resetMask>0xffff</resetMask>
                    <fields>
                        <field>
                            <name>PID</name>
                            <description>Response PID</description>
                            <lsb>0</lsb>
                            <msb>1</msb>
                            <access>read-write</access>
                            <enumeratedValues>
                                <enumeratedValue>
                                    <name>00</name>
                                    <description>NAK response</description>
                                    <value>#00</value>
                                </enumeratedValue>
                                <enumeratedValue>
                                    <name>01</name>
                                    <description>BUF response (depends buffer state)</description>
                                    <value>#01</value>
                                </enumeratedValue>
                                <enumeratedValue>
                                    <name>10</name>
                                    <description>STALL response</description>
                                    <value>#10</value>
                                </enumeratedValue>
                                <enumeratedValue>
                                    <name>11</name>
                                    <description>STALL response</description>
                                    <value>#11</value>
                                </enumeratedValue>
                            </enumeratedValues>
                        </field>
                        <field>
                            <name>PBUSY</name>
                            <description>Pipe Busy</description>
                            <lsb>5</lsb>
                            <msb>5</msb>
                            <access>read-only</access>
                            <enumeratedValues>
                                <enumeratedValue>
                                    <name>0</name>
                                    <description>Pipe n not in use for the transaction</description>
                                    <value>#0</value>
                                </enumeratedValue>
                                <enumeratedValue>
                                    <name>1</name>
                                    <description>Pipe n in use for the transaction</description>
                                    <value>#1</value>
                                </enumeratedValue>
                            </enumeratedValues>
                        </field>
                        <field>
                            <name>SQMON</name>
                            <description>Sequence Toggle Bit Confirmation</description>
                            <lsb>6</lsb>
                            <msb>6</msb>
                            <access>read-only</access>
                            <enumeratedValues>
                                <enumeratedValue>
                                    <name>0</name>
                                    <description>DATA0</description>
                                    <value>#0</value>
                                </enumeratedValue>
                                <enumeratedValue>
                                    <name>1</name>
                                    <description>DATA1</description>
                                    <value>#1</value>
                                </enumeratedValue>
                            </enumeratedValues>
                        </field>
                        <field>
                            <name>SQSET</name>
                            <description>Sequence Toggle Bit Set</description>
                            <lsb>7</lsb>
                            <msb>7</msb>
                            <access>write-only</access>
                            <enumeratedValues>
                                <enumeratedValue>
                                    <name>0</name>
                                    <description>Invalid (writing 0 has no effect)</description>
                                    <value>#0</value>
                                </enumeratedValue>
                                <enumeratedValue>
                                    <name>1</name>
                                    <description>Set the expected value for the next transaction to DATA0</description>
                                    <value>#1</value>
                                </enumeratedValue>
                            </enumeratedValues>
                        </field>
                        <field>
                            <name>SQCLR</name>
                            <description>Sequence Toggle Bit Clear</description>
                            <lsb>8</lsb>
                            <msb>8</msb>
                            <access>write-only</access>
                            <enumeratedValues>
                                <enumeratedValue>
                                    <name>0</name>
                                    <description>Invalid (writing 0 has no effect)</description>
                                    <value>#0</value>
                                </enumeratedValue>
                                <enumeratedValue>
                                    <name>1</name>
                                    <description>Clear the expected value for the next transaction to DATA0</description>
                                    <value>#1</value>
                                </enumeratedValue>
                            </enumeratedValues>
                        </field>
                        <field>
                            <name>ACLRM</name>
                            <description>Auto Buffer Clear Mode</description>
                            <lsb>9</lsb>
                            <msb>9</msb>
                            <access>read-write</access>
                            <enumeratedValues>
                                <enumeratedValue>
                                    <name>0</name>
                                    <description>Disable</description>
                                    <value>#0</value>
                                </enumeratedValue>
                                <enumeratedValue>
                                    <name>1</name>
                                    <description>Enable (all buffers initialized)</description>
                                    <value>#1</value>
                                </enumeratedValue>
                            </enumeratedValues>
                        </field>
                        <field>
                            <name>BSTS</name>
                            <description>Buffer Status</description>
                            <lsb>15</lsb>
                            <msb>15</msb>
                            <access>read-only</access>
                            <enumeratedValues>
                                <enumeratedValue>
                                    <name>0</name>
                                    <description>Buffer access disabled</description>
                                    <value>#0</value>
                                </enumeratedValue>
                                <enumeratedValue>
                                    <name>1</name>
                                    <description>Buffer access enabled</description>
                                    <value>#1</value>
                                </enumeratedValue>
                            </enumeratedValues>
                        </field>
                    </fields>
                </register>
                <register>
                    <dim>5</dim>
                    <dimIncrement>0x4</dimIncrement>
                    <dimIndex>1-5</dimIndex>
                    <name>PIPE%sTRE</name>
                    <description>PIPE%s Transaction Counter Enable Register</description>
                    <addressOffset>0x090</addressOffset>
                    <size>16</size>
                    <access>read-write</access>
                    <resetValue>0x0000</resetValue>
                    <resetMask>0xffff</resetMask>
                    <fields>
                        <field>
                            <name>TRCLR</name>
                            <description>Transaction Counter Clear</description>
                            <lsb>8</lsb>
                            <msb>8</msb>
                            <access>read-write</access>
                            <enumeratedValues>
                                <enumeratedValue>
                                    <name>0</name>
                                    <description>Invalid (writing 0 has no effect)</description>
                                    <value>#0</value>
                                </enumeratedValue>
                                <enumeratedValue>
                                    <name>1</name>
                                    <description>Clear counter value</description>
                                    <value>#1</value>
                                </enumeratedValue>
                            </enumeratedValues>
                        </field>
                        <field>
                            <name>TRENB</name>
                            <description>Transaction Counter Enable</description>
                            <lsb>9</lsb>
                            <msb>9</msb>
                            <access>read-write</access>
                            <enumeratedValues>
                                <enumeratedValue>
                                    <name>0</name>
                                    <description>Disable transaction counter</description>
                                    <value>#0</value>
                                </enumeratedValue>
                                <enumeratedValue>
                                    <name>1</name>
                                    <description>Enable transaction counter</description>
                                    <value>#1</value>
                                </enumeratedValue>
                            </enumeratedValues>
                        </field>
                    </fields>
                </register>
                <register>
                    <dim>5</dim>
                    <dimIncrement>0x4</dimIncrement>
                    <dimIndex>1-5</dimIndex>
                    <name>PIPE%sTRN</name>
                    <description>PIPE%s Transaction Counter Register</description>
                    <addressOffset>0x092</addressOffset>
                    <size>16</size>
                    <access>read-write</access>
                    <resetValue>0x0000</resetValue>
                    <resetMask>0xffff</resetMask>
                    <fields>
                        <field>
                            <name>TRNCNT</name>
                            <description>Transaction Counter</description>
                            <lsb>0</lsb>
                            <msb>15</msb>
                            <access>read-write</access>
                        </field>
                    </fields>
                </register>
                <register>
                    <dim>6</dim>
                    <dimIncrement>0x2</dimIncrement>
                    <dimIndex>0-5</dimIndex>
                    <name>DEVADD%s</name>
                    <description>Device Address %s Configuration Register</description>
                    <addressOffset>0x0D0</addressOffset>
                    <size>16</size>
                    <access>read-write</access>
                    <resetValue>0x0000</resetValue>
                    <resetMask>0xffff</resetMask>
                    <fields>
                        <field>
                            <name>USBSPD</name>
                            <description>Transfer Speed of Communication Target Device</description>
                            <lsb>6</lsb>
                            <msb>7</msb>
                            <access>read-write</access>
                            <enumeratedValues>
                                <enumeratedValue>
                                    <name>00</name>
                                    <description>Do not use DEVADDn</description>
                                    <value>#00</value>
                                </enumeratedValue>
                                <enumeratedValue>
                                    <name>01</name>
                                    <description>Low-speed</description>
                                    <value>#01</value>
                                </enumeratedValue>
                                <enumeratedValue>
                                    <name>10</name>
                                    <description>Full-speed</description>
                                    <value>#10</value>
                                </enumeratedValue>
                                <enumeratedValue>
                                    <name>11</name>
                                    <description>Setting prohibited</description>
                                    <value>#11</value>
                                </enumeratedValue>
                            </enumeratedValues>
                        </field>
                    </fields>
                </register>
                <register>
                    <name>DPUSR0R</name>
                    <description>Deep Software Standby USB Transceiver Control/Pin Monitor Register</description>
                    <addressOffset>0x400</addressOffset>
                    <size>32</size>
                    <access>read-write</access>
                    <resetValue>0x00000000</resetValue>
                    <resetMask>0xff4cffff</resetMask>
                    <fields>
                        <field>
                            <name>SRPC0</name>
                            <description>USB Single-ended Receiver Control</description>
                            <lsb>0</lsb>
                            <msb>0</msb>
                            <access>read-write</access>
                            <enumeratedValues>
                                <enumeratedValue>
                                    <name>0</name>
                                    <description>Disable input through DP and DM inputs</description>
                                    <value>#0</value>
                                </enumeratedValue>
                                <enumeratedValue>
                                    <name>1</name>
                                    <description>Enable input through DP and DM inputs</description>
                                    <value>#1</value>
                                </enumeratedValue>
                            </enumeratedValues>
                        </field>
                        <field>
                            <name>RPUE0</name>
                            <description>DP Pull-Up Resistor Control</description>
                            <lsb>1</lsb>
                            <msb>1</msb>
                            <access>read-write</access>
                            <enumeratedValues>
                                <enumeratedValue>
                                    <name>0</name>
                                    <description>Disable DP pull-up resistor</description>
                                    <value>#0</value>
                                </enumeratedValue>
                                <enumeratedValue>
                                    <name>1</name>
                                    <description>Enable DP pull-up resistor</description>
                                    <value>#1</value>
                                </enumeratedValue>
                            </enumeratedValues>
                        </field>
                        <field>
                            <name>DRPD0</name>
                            <description>D+/D- Pull-Down Resistor Control</description>
                            <lsb>3</lsb>
                            <msb>3</msb>
                            <access>read-write</access>
                            <enumeratedValues>
                                <enumeratedValue>
                                    <name>0</name>
                                    <description>Disable DP/DM pull-down resistor</description>
                                    <value>#0</value>
                                </enumeratedValue>
                                <enumeratedValue>
                                    <name>1</name>
                                    <description>Enable DP/DM pull-down resistor</description>
                                    <value>#1</value>
                                </enumeratedValue>
                            </enumeratedValues>
                        </field>
                        <field>
                            <name>FIXPHY0</name>
                            <description>USB Transceiver Output Fix</description>
                            <lsb>4</lsb>
                            <msb>4</msb>
                            <access>read-write</access>
                            <enumeratedValues>
                                <enumeratedValue>
                                    <name>0</name>
                                    <description>Fix outputs in Normal mode and on return from Deep Software Standby mode 1</description>
                                    <value>#0</value>
                                </enumeratedValue>
                                <enumeratedValue>
                                    <name>1</name>
                                    <description>Fix outputs on transition to Deep Software Standby mode 1</description>
                                    <value>#1</value>
                                </enumeratedValue>
                            </enumeratedValues>
                        </field>
                        <field>
                            <name>DP0</name>
                            <description>USB D+ Input</description>
                            <lsb>16</lsb>
                            <msb>16</msb>
                            <access>read-only</access>
                        </field>
                        <field>
                            <name>DM0</name>
                            <description>USB D- Input</description>
                            <lsb>17</lsb>
                            <msb>17</msb>
                            <access>read-only</access>
                        </field>
                        <field>
                            <name>DOVCA0</name>
                            <description>USB OVRCURA-DS Input</description>
                            <lsb>20</lsb>
                            <msb>20</msb>
                            <access>read-only</access>
                        </field>
                        <field>
                            <name>DOVCB0</name>
                            <description>USB OVRCURB-DS Input</description>
                            <lsb>21</lsb>
                            <msb>21</msb>
                            <access>read-only</access>
                        </field>
                        <field>
                            <name>DVBSTS0</name>
                            <description>USB VBUS Input</description>
                            <lsb>23</lsb>
                            <msb>23</msb>
                            <access>read-only</access>
                        </field>
                    </fields>
                </register>
                <register>
                    <name>DPUSR1R</name>
                    <description>Deep Software Standby USB Suspend/Resume Interrupt Register</description>
                    <addressOffset>0x404</addressOffset>
                    <size>32</size>
                    <access>read-write</access>
                    <resetValue>0x00000000</resetValue>
                    <resetMask>0xffffffff</resetMask>
                    <fields>
                        <field>
                            <name>DPINTE0</name>
                            <description>USB DP Interrupt Enable/Clear</description>
                            <lsb>0</lsb>
                            <msb>0</msb>
                            <access>read-write</access>
                            <enumeratedValues>
                                <enumeratedValue>
                                    <name>0</name>
                                    <description>Disable recovery from Deep Software Standby mode 1 by DP input</description>
                                    <value>#0</value>
                                </enumeratedValue>
                                <enumeratedValue>
                                    <name>1</name>
                                    <description>Enable recovery from Deep Software Standby mode 1 by DP input</description>
                                    <value>#1</value>
                                </enumeratedValue>
                            </enumeratedValues>
                        </field>
                        <field>
                            <name>DMINTE0</name>
                            <description>USB DM Interrupt Enable/Clear</description>
                            <lsb>1</lsb>
                            <msb>1</msb>
                            <access>read-write</access>
                            <enumeratedValues>
                                <enumeratedValue>
                                    <name>0</name>
                                    <description>Disable recovery from Deep Software Standby mode 1 by DM input</description>
                                    <value>#0</value>
                                </enumeratedValue>
                                <enumeratedValue>
                                    <name>1</name>
                                    <description>Enable recovery from Deep Software Standby mode by DM input</description>
                                    <value>#1</value>
                                </enumeratedValue>
                            </enumeratedValues>
                        </field>
                        <field>
                            <name>DOVRCRAE0</name>
                            <description>USB OVRCURA-DS Interrupt Enable/Clear</description>
                            <lsb>4</lsb>
                            <msb>4</msb>
                            <access>read-write</access>
                            <enumeratedValues>
                                <enumeratedValue>
                                    <name>0</name>
                                    <description>Disable recovery from Deep Software Standby mode 1 by OVRCURA-DS input</description>
                                    <value>#0</value>
                                </enumeratedValue>
                                <enumeratedValue>
                                    <name>1</name>
                                    <description>Enable recovery from Deep Software Standby mode 1 by OVRCURA-DS input</description>
                                    <value>#1</value>
                                </enumeratedValue>
                            </enumeratedValues>
                        </field>
                        <field>
                            <name>DOVRCRBE0</name>
                            <description>USB OVRCURB-DS Interrupt Enable/Clear</description>
                            <lsb>5</lsb>
                            <msb>5</msb>
                            <access>read-write</access>
                            <enumeratedValues>
                                <enumeratedValue>
                                    <name>0</name>
                                    <description>Disable recovery from Deep Software Standby mode 1 by OVRCURB-DS input</description>
                                    <value>#0</value>
                                </enumeratedValue>
                                <enumeratedValue>
                                    <name>1</name>
                                    <description>Enable recovery from Deep Software Standby mode 1 by OVRCURB-DS input</description>
                                    <value>#1</value>
                                </enumeratedValue>
                            </enumeratedValues>
                        </field>
                        <field>
                            <name>DVBSE0</name>
                            <description>USB VBUS Interrupt Enable/Clear</description>
                            <lsb>7</lsb>
                            <msb>7</msb>
                            <access>read-write</access>
                            <enumeratedValues>
                                <enumeratedValue>
                                    <name>0</name>
                                    <description>Disable recovery from Deep Software Standby mode 1 by VBUS input</description>
                                    <value>#0</value>
                                </enumeratedValue>
                                <enumeratedValue>
                                    <name>1</name>
                                    <description>Enable recovery from Deep Software Standby mode 1 by VBUS input</description>
                                    <value>#1</value>
                                </enumeratedValue>
                            </enumeratedValues>
                        </field>
                        <field>
                            <name>DPINT0</name>
                            <description>USB DP Interrupt Source Recovery</description>
                            <lsb>16</lsb>
                            <msb>16</msb>
                            <access>read-only</access>
                            <enumeratedValues>
                                <enumeratedValue>
                                    <name>0</name>
                                    <description>System has not recovered from Deep Software Standby mode 1</description>
                                    <value>#0</value>
                                </enumeratedValue>
                                <enumeratedValue>
                                    <name>1</name>
                                    <description>System recovered from Deep Software Standby mode 1 because of DP</description>
                                    <value>#1</value>
                                </enumeratedValue>
                            </enumeratedValues>
                        </field>
                        <field>
                            <name>DMINT0</name>
                            <description>USB DM Interrupt Source Recovery</description>
                            <lsb>17</lsb>
                            <msb>17</msb>
                            <access>read-only</access>
                            <enumeratedValues>
                                <enumeratedValue>
                                    <name>0</name>
                                    <description>System has not recovered from Deep Software Standby mode 1</description>
                                    <value>#0</value>
                                </enumeratedValue>
                                <enumeratedValue>
                                    <name>1</name>
                                    <description>System recovered from Deep Software Standby mode 1 because of DM input</description>
                                    <value>#1</value>
                                </enumeratedValue>
                            </enumeratedValues>
                        </field>
                        <field>
                            <name>DOVRCRA0</name>
                            <description>USB OVRCURA-DS Interrupt Source Recovery</description>
                            <lsb>20</lsb>
                            <msb>20</msb>
                            <access>read-only</access>
                            <enumeratedValues>
                                <enumeratedValue>
                                    <name>0</name>
                                    <description>System has not recovered from Deep Software Standby mode 1</description>
                                    <value>#0</value>
                                </enumeratedValue>
                                <enumeratedValue>
                                    <name>1</name>
                                    <description>System recovered from Deep Software Standby mode 1 because of OVRCURA-DS input</description>
                                    <value>#1</value>
                                </enumeratedValue>
                            </enumeratedValues>
                        </field>
                        <field>
                            <name>DOVRCRB0</name>
                            <description>USB OVRCURB-DS Interrupt Source Recovery</description>
                            <lsb>21</lsb>
                            <msb>21</msb>
                            <access>read-only</access>
                            <enumeratedValues>
                                <enumeratedValue>
                                    <name>0</name>
                                    <description>System has not recovered from Deep Software Standby mode 1</description>
                                    <value>#0</value>
                                </enumeratedValue>
                                <enumeratedValue>
                                    <name>1</name>
                                    <description>System recovered from Deep Software Standby mode 1 because of OVRCURB-DS input</description>
                                    <value>#1</value>
                                </enumeratedValue>
                            </enumeratedValues>
                        </field>
                        <field>
                            <name>DVBINT0</name>
                            <description>USB VBUS Interrupt Source Recovery</description>
                            <lsb>23</lsb>
                            <msb>23</msb>
                            <access>read-only</access>
                            <enumeratedValues>
                                <enumeratedValue>
                                    <name>0</name>
                                    <description>System has not recovered from Deep Software Standby mode 1</description>
                                    <value>#0</value>
                                </enumeratedValue>
                                <enumeratedValue>
                                    <name>1</name>
                                    <description>System recovered from Deep Software Standby mode 1 because of VBUS input</description>
                                    <value>#1</value>
                                </enumeratedValue>
                            </enumeratedValues>
                        </field>
                    </fields>
                </register>
            </registers>
        </peripheral>
        <peripheral>
            <name>SSIE0_NS</name>
            <description>Serial Sound Interface Enhanced 0</description>
            <baseAddress>0x5025D000</baseAddress>
            <addressBlock>
                <offset>0x00</offset>
                <size>8</size>
                <usage>registers</usage>
            </addressBlock>
            <addressBlock>
                <offset>0x10</offset>
                <size>24</size>
                <usage>registers</usage>
            </addressBlock>
            <registers>
                <register>
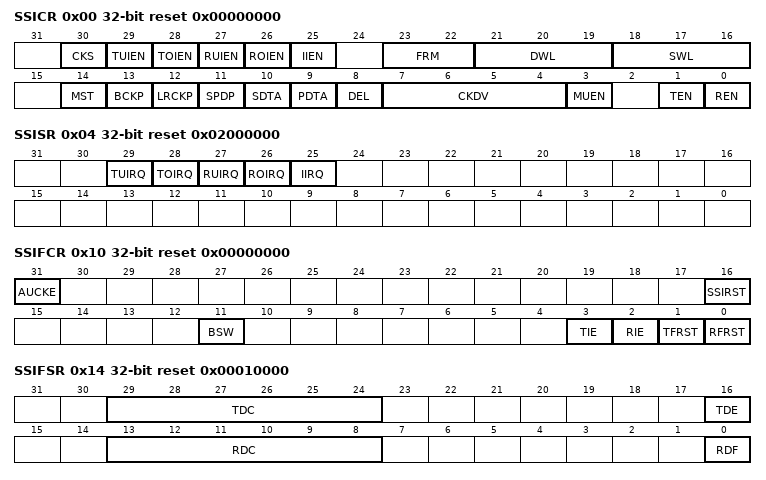
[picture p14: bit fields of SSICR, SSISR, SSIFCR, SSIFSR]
                    <name>SSICR</name>
                    <description>Control Register</description>
                    <addressOffset>0x00</addressOffset>
                    <size>32</size>
                    <access>read-write</access>
                    <resetValue>0x00000000</resetValue>
                    <resetMask>0xffffffff</resetMask>
                    <fields>
                        <field>
                            <name>REN</name>
                            <description>Reception Enable</description>
                            <lsb>0</lsb>
                            <msb>0</msb>
                            <access>read-write</access>
                            <enumeratedValues>
                                <enumeratedValue>
                                    <name>0</name>
                                    <description>Disables reception</description>
                                    <value>#0</value>
                                </enumeratedValue>
                                <enumeratedValue>
                                    <name>1</name>
                                    <description>Enables reception (starts reception)</description>
                                    <value>#1</value>
                                </enumeratedValue>
                            </enumeratedValues>
                        </field>
                        <field>
                            <name>TEN</name>
                            <description>Transmission Enable</description>
                            <lsb>1</lsb>
                            <msb>1</msb>
                            <access>read-write</access>
                            <enumeratedValues>
                                <enumeratedValue>
                                    <name>0</name>
                                    <description>Disables transmission</description>
                                    <value>#0</value>
                                </enumeratedValue>
                                <enumeratedValue>
                                    <name>1</name>
                                    <description>Enables transmission (starts transmission)</description>
                                    <value>#1</value>
                                </enumeratedValue>
                            </enumeratedValues>
                        </field>
                        <field>
                            <name>MUEN</name>
                            <description>Mute Enable</description>
                            <lsb>3</lsb>
                            <msb>3</msb>
                            <access>read-write</access>
                            <enumeratedValues>
                                <enumeratedValue>
                                    <name>0</name>
                                    <description>Disables muting on the next frame boundary</description>
                                    <value>#0</value>
                                </enumeratedValue>
                                <enumeratedValue>
                                    <name>1</name>
                                    <description>Enables muting on the next frame boundary</description>
                                    <value>#1</value>
                                </enumeratedValue>
                            </enumeratedValues>
                        </field>
                        <field>
                            <name>CKDV</name>
                            <description>Selects Bit Clock Division Ratio</description>
                            <lsb>4</lsb>
                            <msb>7</msb>
                            <access>read-write</access>
                            <enumeratedValues>
                                <enumeratedValue>
                                    <name>0x0</name>
                                    <description>AUDIO_MCK</description>
                                    <value>0x0</value>
                                </enumeratedValue>
                                <enumeratedValue>
                                    <name>0x1</name>
                                    <description>AUDIO_MCK/2</description>
                                    <value>0x1</value>
                                </enumeratedValue>
                                <enumeratedValue>
                                    <name>0x2</name>
                                    <description>AUDIO_MCK/4</description>
                                    <value>0x2</value>
                                </enumeratedValue>
                                <enumeratedValue>
                                    <name>0x3</name>
                                    <description>AUDIO_MCK/8</description>
                                    <value>0x3</value>
                                </enumeratedValue>
                                <enumeratedValue>
                                    <name>0x4</name>
                                    <description>AUDIO_MCK/16</description>
                                    <value>0x4</value>
                                </enumeratedValue>
                                <enumeratedValue>
                                    <name>0x5</name>
                                    <description>AUDIO_MCK/32</description>
                                    <value>0x5</value>
                                </enumeratedValue>
                                <enumeratedValue>
                                    <name>0x6</name>
                                    <description>AUDIO_MCK/64</description>
                                    <value>0x6</value>
                                </enumeratedValue>
                                <enumeratedValue>
                                    <name>0x7</name>
                                    <description>AUDIO_MCK/128</description>
                                    <value>0x7</value>
                                </enumeratedValue>
                                <enumeratedValue>
                                    <name>0x8</name>
                                    <description>AUDIO_MCK/6</description>
                                    <value>0x8</value>
                                </enumeratedValue>
                                <enumeratedValue>
                                    <name>0x9</name>
                                    <description>AUDIO_MCK/12</description>
                                    <value>0x9</value>
                                </enumeratedValue>
                                <enumeratedValue>
                                    <name>0xA</name>
                                    <description>AUDIO_MCK/24</description>
                                    <value>0xa</value>
                                </enumeratedValue>
                                <enumeratedValue>
                                    <name>0xB</name>
                                    <description>AUDIO_MCK/48</description>
                                    <value>0xb</value>
                                </enumeratedValue>
                                <enumeratedValue>
                                    <name>0xC</name>
                                    <description>AUDIO_MCK/96</description>
                                    <value>0xc</value>
                                </enumeratedValue>
                                <enumeratedValue>
                                    <name>Others</name>
                                    <description>Setting prohibited</description>
                                    <isDefault>true</isDefault>
                                </enumeratedValue>
                            </enumeratedValues>
                        </field>
                        <field>
                            <name>DEL</name>
                            <description>Selects Serial Data Delay</description>
                            <lsb>8</lsb>
                            <msb>8</msb>
                            <access>read-write</access>
                            <enumeratedValues>
                                <enumeratedValue>
                                    <name>0</name>
                                    <description>Delay of 1 cycle of SSIBCKn (n = 0, 1) between SSILRCKn/SSIFSn (n = 0, 1) and SSITXD0/SSIRXD0/SSIDATA1</description>
                                    <value>#0</value>
                                </enumeratedValue>
                                <enumeratedValue>
                                    <name>1</name>
                                    <description>No delay between SSILRCKn/SSIFSn (n = 0, 1) and SSITXD0/SSIRXD0/SSIDATA1</description>
                                    <value>#1</value>
                                </enumeratedValue>
                            </enumeratedValues>
                        </field>
                        <field>
                            <name>PDTA</name>
                            <description>Selects Placement Data Alignment</description>
                            <lsb>9</lsb>
                            <msb>9</msb>
                            <access>read-write</access>
                            <enumeratedValues>
                                <enumeratedValue>
                                    <name>0</name>
                                    <description>Left-justifies placement data (SSIFTDR, SSIFRDR)</description>
                                    <value>#0</value>
                                </enumeratedValue>
                                <enumeratedValue>
                                    <name>1</name>
                                    <description>Right-justifies placement data (SSIFTDR, SSIFRDR)</description>
                                    <value>#1</value>
                                </enumeratedValue>
                            </enumeratedValues>
                        </field>
                        <field>
                            <name>SDTA</name>
                            <description>Selects Serial Data Alignment</description>
                            <lsb>10</lsb>
                            <msb>10</msb>
                            <access>read-write</access>
                            <enumeratedValues>
                                <enumeratedValue>
                                    <name>0</name>
                                    <description>Transmits and receives serial data first and then padding bits</description>
                                    <value>#0</value>
                                </enumeratedValue>
                                <enumeratedValue>
                                    <name>1</name>
                                    <description>Transmit and receives padding bits first and then serial data</description>
                                    <value>#1</value>
                                </enumeratedValue>
                            </enumeratedValues>
                        </field>
                        <field>
                            <name>SPDP</name>
                            <description>Selects Serial Padding Polarity</description>
                            <lsb>11</lsb>
                            <msb>11</msb>
                            <access>read-write</access>
                            <enumeratedValues>
                                <enumeratedValue>
                                    <name>0</name>
                                    <description>Padding data is at a low level</description>
                                    <value>#0</value>
                                </enumeratedValue>
                                <enumeratedValue>
                                    <name>1</name>
                                    <description>Padding data is at a high level</description>
                                    <value>#1</value>
                                </enumeratedValue>
                            </enumeratedValues>
                        </field>
                        <field>
                            <name>LRCKP</name>
                            <description>Selects the Initial Value and Polarity of LR Clock/Frame Synchronization Signal</description>
                            <lsb>12</lsb>
                            <msb>12</msb>
                            <access>read-write</access>
                            <enumeratedValues>
                                <enumeratedValue>
                                    <name>0</name>
                                    <description>The initial value is at a high level. The start trigger for a frame is synchronized with a falling edge of SSILRCKn/SSIFSn (n = 0, 1). </description>
                                    <value>#0</value>
                                </enumeratedValue>
                                <enumeratedValue>
                                    <name>1</name>
                                    <description>The initial value is at a low level. The start trigger for a frame is synchronized with a rising edge of SSILRCKn/SSIFSn (n = 0, 1). </description>
                                    <value>#1</value>
                                </enumeratedValue>
                            </enumeratedValues>
                        </field>
                        <field>
                            <name>BCKP</name>
                            <description>Selects Bit Clock Polarity</description>
                            <lsb>13</lsb>
                            <msb>13</msb>
                            <access>read-write</access>
                            <enumeratedValues>
                                <enumeratedValue>
                                    <name>0</name>
                                    <description>SSILRCKn/SSIFSn (n = 0, 1) and SSITXD0/SSIRXD0/SSIDATA1 change at a falling edge (SSILRCKn/SSIFSn (n = 0, 1) and SSIRXD0/SSIDATA1 are sampled at a rising edge of SSIBCKn (n = 0, 1)).</description>
                                    <value>#0</value>
                                </enumeratedValue>
                                <enumeratedValue>
                                    <name>1</name>
                                    <description>SSILRCKn/SSIFSn (n = 0, 1) and SSITXD0/SSIRXD0/SSIDATA1 change at a rising edge (SSILRCKn/SSIFSn (n = 0, 1) and SSIRXD0/SSIDATA1 are sampled at a falling edge of SSIBCKn (n = 0, 1)).</description>
                                    <value>#1</value>
                                </enumeratedValue>
                            </enumeratedValues>
                        </field>
                        <field>
                            <name>MST</name>
                            <description>Master Enable</description>
                            <lsb>14</lsb>
                            <msb>14</msb>
                            <access>read-write</access>
                            <enumeratedValues>
                                <enumeratedValue>
                                    <name>0</name>
                                    <description>Slave-mode communication</description>
                                    <value>#0</value>
                                </enumeratedValue>
                                <enumeratedValue>
                                    <name>1</name>
                                    <description>Master-mode communication</description>
                                    <value>#1</value>
                                </enumeratedValue>
                            </enumeratedValues>
                        </field>
                        <field>
                            <name>SWL</name>
                            <description>Selects System Word Length</description>
                            <lsb>16</lsb>
                            <msb>18</msb>
                            <access>read-write</access>
                            <enumeratedValues>
                                <enumeratedValue>
                                    <name>000</name>
                                    <description>8 bits</description>
                                    <value>#000</value>
                                </enumeratedValue>
                                <enumeratedValue>
                                    <name>001</name>
                                    <description>16 bits</description>
                                    <value>#001</value>
                                </enumeratedValue>
                                <enumeratedValue>
                                    <name>010</name>
                                    <description>24 bits</description>
                                    <value>#010</value>
                                </enumeratedValue>
                                <enumeratedValue>
                                    <name>011</name>
                                    <description>32 bits</description>
                                    <value>#011</value>
                                </enumeratedValue>
                                <enumeratedValue>
                                    <name>100</name>
                                    <description>48 bits</description>
                                    <value>#100</value>
                                </enumeratedValue>
                                <enumeratedValue>
                                    <name>101</name>
                                    <description>64 bits</description>
                                    <value>#101</value>
                                </enumeratedValue>
                                <enumeratedValue>
                                    <name>110</name>
                                    <description>128 bits</description>
                                    <value>#110</value>
                                </enumeratedValue>
                                <enumeratedValue>
                                    <name>111</name>
                                    <description>256 bits</description>
                                    <value>#111</value>
                                </enumeratedValue>
                            </enumeratedValues>
                        </field>
                        <field>
                            <name>DWL</name>
                            <description>Selects Data Word Length</description>
                            <lsb>19</lsb>
                            <msb>21</msb>
                            <access>read-write</access>
                            <enumeratedValues>
                                <enumeratedValue>
                                    <name>000</name>
                                    <description>8 bits</description>
                                    <value>#000</value>
                                </enumeratedValue>
                                <enumeratedValue>
                                    <name>001</name>
                                    <description>16 bits</description>
                                    <value>#001</value>
                                </enumeratedValue>
                                <enumeratedValue>
                                    <name>010</name>
                                    <description>18 bits</description>
                                    <value>#010</value>
                                </enumeratedValue>
                                <enumeratedValue>
                                    <name>011</name>
                                    <description>20 bits</description>
                                    <value>#011</value>
                                </enumeratedValue>
                                <enumeratedValue>
                                    <name>100</name>
                                    <description>22 bits</description>
                                    <value>#100</value>
                                </enumeratedValue>
                                <enumeratedValue>
                                    <name>101</name>
                                    <description>24 bits</description>
                                    <value>#101</value>
                                </enumeratedValue>
                                <enumeratedValue>
                                    <name>110</name>
                                    <description>32 bits</description>
                                    <value>#110</value>
                                </enumeratedValue>
                                <enumeratedValue>
                                    <name>111</name>
                                    <description>Setting prohibited</description>
                                    <value>#111</value>
                                </enumeratedValue>
                            </enumeratedValues>
                        </field>
                        <field>
                            <name>FRM</name>
                            <description>Selects Frame Word Number</description>
                            <lsb>22</lsb>
                            <msb>23</msb>
                            <access>read-write</access>
                        </field>
                        <field>
                            <name>IIEN</name>
                            <description>Idle Mode Interrupt Output Enable</description>
                            <lsb>25</lsb>
                            <msb>25</msb>
                            <access>read-write</access>
                            <enumeratedValues>
                                <enumeratedValue>
                                    <name>0</name>
                                    <description>Disables idle mode interrupt output</description>
                                    <value>#0</value>
                                </enumeratedValue>
                                <enumeratedValue>
                                    <name>1</name>
                                    <description>Enables idle mode interrupt output</description>
                                    <value>#1</value>
                                </enumeratedValue>
                            </enumeratedValues>
                        </field>
                        <field>
                            <name>ROIEN</name>
                            <description>Receive Overflow Interrupt Output Enable</description>
                            <lsb>26</lsb>
                            <msb>26</msb>
                            <access>read-write</access>
                            <enumeratedValues>
                                <enumeratedValue>
                                    <name>0</name>
                                    <description>Disables receive overflow interrupt output</description>
                                    <value>#0</value>
                                </enumeratedValue>
                                <enumeratedValue>
                                    <name>1</name>
                                    <description>Enables receive overflow interrupt output</description>
                                    <value>#1</value>
                                </enumeratedValue>
                            </enumeratedValues>
                        </field>
                        <field>
                            <name>RUIEN</name>
                            <description>Receive Underflow Interrupt Output Enable</description>
                            <lsb>27</lsb>
                            <msb>27</msb>
                            <access>read-write</access>
                            <enumeratedValues>
                                <enumeratedValue>
                                    <name>0</name>
                                    <description>Disables receive underflow interrupt output</description>
                                    <value>#0</value>
                                </enumeratedValue>
                                <enumeratedValue>
                                    <name>1</name>
                                    <description>Enables receive underflow interrupt output</description>
                                    <value>#1</value>
                                </enumeratedValue>
                            </enumeratedValues>
                        </field>
                        <field>
                            <name>TOIEN</name>
                            <description>Transmit Overflow Interrupt Output Enable</description>
                            <lsb>28</lsb>
                            <msb>28</msb>
                            <access>read-write</access>
                            <enumeratedValues>
                                <enumeratedValue>
                                    <name>0</name>
                                    <description>Disables transmit overflow interrupt output</description>
                                    <value>#0</value>
                                </enumeratedValue>
                                <enumeratedValue>
                                    <name>1</name>
                                    <description>Enables transmit overflow interrupt output</description>
                                    <value>#1</value>
                                </enumeratedValue>
                            </enumeratedValues>
                        </field>
                        <field>
                            <name>TUIEN</name>
                            <description>Transmit Underflow Interrupt Output Enable</description>
                            <lsb>29</lsb>
                            <msb>29</msb>
                            <access>read-write</access>
                            <enumeratedValues>
                                <enumeratedValue>
                                    <name>0</name>
                                    <description>Disables transmit underflow interrupt output</description>
                                    <value>#0</value>
                                </enumeratedValue>
                                <enumeratedValue>
                                    <name>1</name>
                                    <description>Enables transmit underflow interrupt output</description>
                                    <value>#1</value>
                                </enumeratedValue>
                            </enumeratedValues>
                        </field>
                        <field>
                            <name>CKS</name>
                            <description>Selects an Audio Clock for Master-mode Communication</description>
                            <lsb>30</lsb>
                            <msb>30</msb>
                            <access>read-write</access>
                            <enumeratedValues>
                                <enumeratedValue>
                                    <name>0</name>
                                    <description>Selects the AUDIO_CLK input</description>
                                    <value>#0</value>
                                </enumeratedValue>
                                <enumeratedValue>
                                    <name>1</name>
                                    <description>Selects the GTIOC2A (GPT output)</description>
                                    <value>#1</value>
                                </enumeratedValue>
                            </enumeratedValues>
                        </field>
                    </fields>
                </register>
                <register>
                    <name>SSISR</name>
                    <description>Status Register</description>
                    <addressOffset>0x04</addressOffset>
                    <size>32</size>
                    <access>read-write</access>
                    <resetValue>0x02000000</resetValue>
                    <resetMask>0xffffffff</resetMask>
                    <fields>
                        <field>
                            <name>IIRQ</name>
                            <description>Idle Mode Status Flag</description>
                            <lsb>25</lsb>
                            <msb>25</msb>
                            <access>read-only</access>
                            <enumeratedValues>
                                <enumeratedValue>
                                    <name>0</name>
                                    <description>In the communication state</description>
                                    <value>#0</value>
                                </enumeratedValue>
                                <enumeratedValue>
                                    <name>1</name>
                                    <description>In the idle state</description>
                                    <value>#1</value>
                                </enumeratedValue>
                            </enumeratedValues>
                        </field>
                        <field>
                            <name>ROIRQ</name>
                            <description>Receive Overflow Error Status Flag</description>
                            <lsb>26</lsb>
                            <msb>26</msb>
                            <access>read-write</access>
                            <enumeratedValues>
                                <enumeratedValue>
                                    <name>0</name>
                                    <description>No receive overflow error is generated.</description>
                                    <value>#0</value>
                                </enumeratedValue>
                                <enumeratedValue>
                                    <name>1</name>
                                    <description>A receive overflow error is generated.</description>
                                    <value>#1</value>
                                </enumeratedValue>
                            </enumeratedValues>
                        </field>
                        <field>
                            <name>RUIRQ</name>
                            <description>Receive Underflow Error Status Flag</description>
                            <lsb>27</lsb>
                            <msb>27</msb>
                            <access>read-write</access>
                            <enumeratedValues>
                                <enumeratedValue>
                                    <name>0</name>
                                    <description>No receive underflow error is generated.</description>
                                    <value>#0</value>
                                </enumeratedValue>
                                <enumeratedValue>
                                    <name>1</name>
                                    <description>A receive underflow error is generated.</description>
                                    <value>#1</value>
                                </enumeratedValue>
                            </enumeratedValues>
                        </field>
                        <field>
                            <name>TOIRQ</name>
                            <description>Transmit Overflow Error Status Flag</description>
                            <lsb>28</lsb>
                            <msb>28</msb>
                            <access>read-write</access>
                            <enumeratedValues>
                                <enumeratedValue>
                                    <name>0</name>
                                    <description>No transmit overflow error is generated.</description>
                                    <value>#0</value>
                                </enumeratedValue>
                                <enumeratedValue>
                                    <name>1</name>
                                    <description>A transmit overflow error is generated.</description>
                                    <value>#1</value>
                                </enumeratedValue>
                            </enumeratedValues>
                        </field>
                        <field>
                            <name>TUIRQ</name>
                            <description>Transmit Underflow Error Status flag</description>
                            <lsb>29</lsb>
                            <msb>29</msb>
                            <access>read-write</access>
                            <enumeratedValues>
                                <enumeratedValue>
                                    <name>0</name>
                                    <description>No transmit underflow error is generated.</description>
                                    <value>#0</value>
                                </enumeratedValue>
                                <enumeratedValue>
                                    <name>1</name>
                                    <description>A transmit underflow error is generated.</description>
                                    <value>#1</value>
                                </enumeratedValue>
                            </enumeratedValues>
                        </field>
                    </fields>
                </register>
                <register>
                    <name>SSIFCR</name>
                    <description>FIFO Control Register</description>
                    <addressOffset>0x10</addressOffset>
                    <size>32</size>
                    <access>read-write</access>
                    <resetValue>0x00000000</resetValue>
                    <resetMask>0xffffffff</resetMask>
                    <fields>
                        <field>
                            <name>RFRST</name>
                            <description>Receive FIFO Data Register Reset</description>
                            <lsb>0</lsb>
                            <msb>0</msb>
                            <access>read-write</access>
                            <enumeratedValues>
                                <enumeratedValue>
                                    <name>0</name>
                                    <description>Clears a receive data FIFO reset condition</description>
                                    <value>#0</value>
                                </enumeratedValue>
                                <enumeratedValue>
                                    <name>1</name>
                                    <description>Sets a receive data FIFO reset condition</description>
                                    <value>#1</value>
                                </enumeratedValue>
                            </enumeratedValues>
                        </field>
                        <field>
                            <name>TFRST</name>
                            <description>Transmit FIFO Data Register Reset</description>
                            <lsb>1</lsb>
                            <msb>1</msb>
                            <access>read-write</access>
                            <enumeratedValues>
                                <enumeratedValue>
                                    <name>0</name>
                                    <description>Clears a transmit data FIFO reset condition</description>
                                    <value>#0</value>
                                </enumeratedValue>
                                <enumeratedValue>
                                    <name>1</name>
                                    <description>Sets a transmit data FIFO reset condition</description>
                                    <value>#1</value>
                                </enumeratedValue>
                            </enumeratedValues>
                        </field>
                        <field>
                            <name>RIE</name>
                            <description>Receive Data Full Interrupt Output Enable</description>
                            <lsb>2</lsb>
                            <msb>2</msb>
                            <access>read-write</access>
                            <enumeratedValues>
                                <enumeratedValue>
                                    <name>0</name>
                                    <description>Disables receive data full interrupts</description>
                                    <value>#0</value>
                                </enumeratedValue>
                                <enumeratedValue>
                                    <name>1</name>
                                    <description>Enables receive data full interrupts</description>
                                    <value>#1</value>
                                </enumeratedValue>
                            </enumeratedValues>
                        </field>
                        <field>
                            <name>TIE</name>
                            <description>Transmit Data Empty Interrupt Output Enable</description>
                            <lsb>3</lsb>
                            <msb>3</msb>
                            <access>read-write</access>
                            <enumeratedValues>
                                <enumeratedValue>
                                    <name>0</name>
                                    <description>Disables transmit data empty interrupts</description>
                                    <value>#0</value>
                                </enumeratedValue>
                                <enumeratedValue>
                                    <name>1</name>
                                    <description>Enables transmit data empty interrupts</description>
                                    <value>#1</value>
                                </enumeratedValue>
                            </enumeratedValues>
                        </field>
                        <field>
                            <name>BSW</name>
                            <description>Byte Swap Enable</description>
                            <lsb>11</lsb>
                            <msb>11</msb>
                            <access>read-write</access>
                            <enumeratedValues>
                                <enumeratedValue>
                                    <name>0</name>
                                    <description>Disables byte swap</description>
                                    <value>#0</value>
                                </enumeratedValue>
                                <enumeratedValue>
                                    <name>1</name>
                                    <description>Enables byte swap</description>
                                    <value>#1</value>
                                </enumeratedValue>
                            </enumeratedValues>
                        </field>
                        <field>
                            <name>SSIRST</name>
                            <description>Software Reset</description>
                            <lsb>16</lsb>
                            <msb>16</msb>
                            <access>read-write</access>
                            <enumeratedValues>
                                <enumeratedValue>
                                    <name>0</name>
                                    <description>Clears a software reset condition</description>
                                    <value>#0</value>
                                </enumeratedValue>
                                <enumeratedValue>
                                    <name>1</name>
                                    <description>Sets a software reset condition</description>
                                    <value>#1</value>
                                </enumeratedValue>
                            </enumeratedValues>
                        </field>
                        <field>
                            <name>AUCKE</name>
                            <description>AUDIO_MCK Enable in Mastermode Communication</description>
                            <lsb>31</lsb>
                            <msb>31</msb>
                            <access>read-write</access>
                            <enumeratedValues>
                                <enumeratedValue>
                                    <name>0</name>
                                    <description>Disables supply of AUDIO_MCK</description>
                                    <value>#0</value>
                                </enumeratedValue>
                                <enumeratedValue>
                                    <name>1</name>
                                    <description>Enables supply of AUDIO_MCK</description>
                                    <value>#1</value>
                                </enumeratedValue>
                            </enumeratedValues>
                        </field>
                    </fields>
                </register>
                <register>
                    <name>SSIFSR</name>
                    <description>FIFO Status Register</description>
                    <addressOffset>0x14</addressOffset>
                    <size>32</size>
                    <access>read-write</access>
                    <resetValue>0x00010000</resetValue>
                    <resetMask>0xffffffff</resetMask>
                    <fields>
                        <field>
                            <name>RDF</name>
                            <description>Receive Data Full Flag</description>
                            <lsb>0</lsb>
                            <msb>0</msb>
                            <access>read-write</access>
                            <enumeratedValues>
                                <enumeratedValue>
                                    <name>0</name>
                                    <description>The size of received data in SSIFRDR is not more than the value of SSISCR.RDFS.</description>
                                    <value>#0</value>
                                </enumeratedValue>
                                <enumeratedValue>
                                    <name>1</name>
                                    <description>The size of received data in SSIFRDR is not less than the value of SSISCR.RDFS plus one.</description>
                                    <value>#1</value>
                                </enumeratedValue>
                            </enumeratedValues>
                        </field>
                        <field>
                            <name>RDC</name>
                            <description>Receive Data Count</description>
                            <lsb>8</lsb>
                            <msb>13</msb>
                            <access>read-only</access>
                        </field>
                        <field>
                            <name>TDE</name>
                            <description>Transmit Data Empty Flag</description>
                            <lsb>16</lsb>
                            <msb>16</msb>
                            <access>read-write</access>
                            <enumeratedValues>
                                <enumeratedValue>
                                    <name>0</name>
                                    <description>The free space of SSIFTDR is not more than the value of SSISCR.TDES.</description>
                                    <value>#0</value>
                                </enumeratedValue>
                                <enumeratedValue>
                                    <name>1</name>
                                    <description>The free space of SSIFTDR is not less than the value of SSISCR.TDES plus one.</description>
                                    <value>#1</value>
                                </enumeratedValue>
                            </enumeratedValues>
                        </field>
                        <field>
                            <name>TDC</name>
                            <description>Transmit Data Count</description>
                            <lsb>24</lsb>
                            <msb>29</msb>
                            <access>read-only</access>
                        </field>
                    </fields>
                </register>
                <register>
                    <name>SSIFTDR</name>
                    <description>Transmit FIFO Data Register</description>
                    <addressOffset>0x18</addressOffset>
                    <size>32</size>
                    <access>write-only</access>
                    <resetValue>0x00000000</resetValue>
                    <resetMask>0xffffffff</resetMask>
                    <fields>
                        <field>
                            <name>SSIFTDR</name>
                            <description>Transmit FIFO Data</description>
                            <lsb>0</lsb>
                            <msb>31</msb>
                            <access>write-only</access>
                        </field>
                    </fields>
                </register>
                <register>
                    <name>SSIFRDR</name>
                    <description>Receive FIFO Data Register</description>
                    <addressOffset>0x1C</addressOffset>
                    <size>32</size>
                    <access>read-only</access>
                    <resetValue>0x00000000</resetValue>
                    <resetMask>0xffffffff</resetMask>
                    <fields>
                        <field>
                            <name>SSIFRDR</name>
                            <description>Receive FIFO Data</description>
                            <lsb>0</lsb>
                            <msb>31</msb>
                            <access>read-only</access>
                        </field>
                    </fields>
                </register>
                <register>
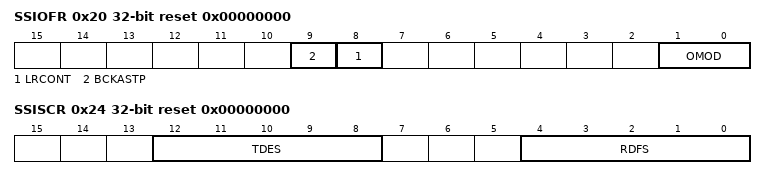
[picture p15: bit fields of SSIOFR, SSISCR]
                    <name>SSIOFR</name>
                    <description>Audio Format Register</description>
                    <addressOffset>0x20</addressOffset>
                    <size>32</size>
                    <access>read-write</access>
                    <resetValue>0x00000000</resetValue>
                    <resetMask>0xffffffff</resetMask>
                    <fields>
                        <field>
                            <name>OMOD</name>
                            <description>Audio Format Select</description>
                            <lsb>0</lsb>
                            <msb>1</msb>
                            <access>read-write</access>
                            <enumeratedValues>
                                <enumeratedValue>
                                    <name>00</name>
                                    <description>I2S format</description>
                                    <value>#00</value>
                                </enumeratedValue>
                                <enumeratedValue>
                                    <name>01</name>
                                    <description>TDM format</description>
                                    <value>#01</value>
                                </enumeratedValue>
                                <enumeratedValue>
                                    <name>10</name>
                                    <description>Monaural format</description>
                                    <value>#10</value>
                                </enumeratedValue>
                                <enumeratedValue>
                                    <name>11</name>
                                    <description>Setting prohibited</description>
                                    <value>#11</value>
                                </enumeratedValue>
                            </enumeratedValues>
                        </field>
                        <field>
                            <name>LRCONT</name>
                            <description>Whether to Enable LRCK/FS Continuation</description>
                            <lsb>8</lsb>
                            <msb>8</msb>
                            <access>read-write</access>
                            <enumeratedValues>
                                <enumeratedValue>
                                    <name>0</name>
                                    <description>Disables LRCK/FS continuation</description>
                                    <value>#0</value>
                                </enumeratedValue>
                                <enumeratedValue>
                                    <name>1</name>
                                    <description>Enables LRCK/FS continuation</description>
                                    <value>#1</value>
                                </enumeratedValue>
                            </enumeratedValues>
                        </field>
                        <field>
                            <name>BCKASTP</name>
                            <description>Whether to Enable Stopping BCK Output When SSIE is in Idle Status</description>
                            <lsb>9</lsb>
                            <msb>9</msb>
                            <access>read-write</access>
                            <enumeratedValues>
                                <enumeratedValue>
                                    <name>0</name>
                                    <description>Always outputs BCK to the SSIBCKn (n = 0, 1) pin</description>
                                    <value>#0</value>
                                </enumeratedValue>
                                <enumeratedValue>
                                    <name>1</name>
                                    <description>Automatically controls output of BCK to the SSIBCKn (n = 0, 1) pin</description>
                                    <value>#1</value>
                                </enumeratedValue>
                            </enumeratedValues>
                        </field>
                    </fields>
                </register>
                <register>
                    <name>SSISCR</name>
                    <description>Status Control Register</description>
                    <addressOffset>0x24</addressOffset>
                    <size>32</size>
                    <access>read-write</access>
                    <resetValue>0x00000000</resetValue>
                    <resetMask>0xffffffff</resetMask>
                    <fields>
                        <field>
                            <name>RDFS</name>
                            <description>RDF Setting Condition Select</description>
                            <lsb>0</lsb>
                            <msb>4</msb>
                            <access>read-write</access>
                        </field>
                        <field>
                            <name>TDES</name>
                            <description>TDE Setting Condition Select</description>
                            <lsb>8</lsb>
                            <msb>12</msb>
                            <access>read-write</access>
                        </field>
                    </fields>
                </register>
            </registers>
        </peripheral>
        <peripheral derivedFrom="SSIE0_NS">
            <name>SSIE1_NS</name>
            <description>Serial Sound Interface Enhanced 1</description>
            <baseAddress>0x5025D100</baseAddress>
        </peripheral>
        <peripheral>
            <name>IIC0_NS</name>
            <description>Inter-Integrated Circuit 0</description>
            <baseAddress>0x5025E000</baseAddress>
            <addressBlock>
                <offset>0x00</offset>
                <size>20</size>
                <usage>registers</usage>
            </addressBlock>
            <registers>
                <register>
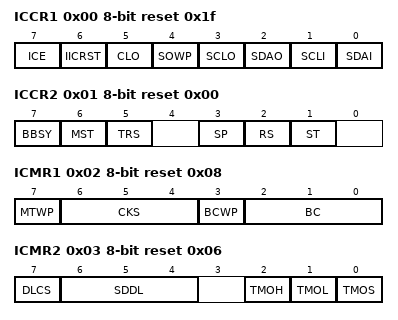
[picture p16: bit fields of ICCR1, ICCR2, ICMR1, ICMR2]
                    <name>ICCR1</name>
                    <description>I2C Bus Control Register 1</description>
                    <addressOffset>0x00</addressOffset>
                    <size>8</size>
                    <access>read-write</access>
                    <resetValue>0x1f</resetValue>
                    <resetMask>0xff</resetMask>
                    <fields>
                        <field>
                            <name>SDAI</name>
                            <description>SDA Line Monitor</description>
                            <lsb>0</lsb>
                            <msb>0</msb>
                            <access>read-only</access>
                            <enumeratedValues>
                                <enumeratedValue>
                                    <name>0</name>
                                    <description>SDAn line is low</description>
                                    <value>#0</value>
                                </enumeratedValue>
                                <enumeratedValue>
                                    <name>1</name>
                                    <description>SDAn line is high</description>
                                    <value>#1</value>
                                </enumeratedValue>
                            </enumeratedValues>
                        </field>
                        <field>
                            <name>SCLI</name>
                            <description>SCL Line Monitor</description>
                            <lsb>1</lsb>
                            <msb>1</msb>
                            <access>read-only</access>
                            <enumeratedValues>
                                <enumeratedValue>
                                    <name>0</name>
                                    <description>SCLn line is low</description>
                                    <value>#0</value>
                                </enumeratedValue>
                                <enumeratedValue>
                                    <name>1</name>
                                    <description>SCLn line is high</description>
                                    <value>#1</value>
                                </enumeratedValue>
                            </enumeratedValues>
                        </field>
                        <field>
                            <name>SDAO</name>
                            <description>SDA Output Control/Monitor</description>
                            <lsb>2</lsb>
                            <msb>2</msb>
                            <access>read-write</access>
                            <enumeratedValues>
                                <enumeratedValue>
                                    <name>0</name>
                                    <description>Read: IIC drives SDAn pin low Write: IIC drives SDAn pin low </description>
                                    <value>#0</value>
                                </enumeratedValue>
                                <enumeratedValue>
                                    <name>1</name>
                                    <description>Read: IIC releases SDAn pin Write: IIC releases SDAn pin </description>
                                    <value>#1</value>
                                </enumeratedValue>
                            </enumeratedValues>
                        </field>
                        <field>
                            <name>SCLO</name>
                            <description>SCL Output Control/Monitor</description>
                            <lsb>3</lsb>
                            <msb>3</msb>
                            <access>read-write</access>
                            <enumeratedValues>
                                <enumeratedValue>
                                    <name>0</name>
                                    <description>Read: IIC drives SCLn pin low Write: IIC drives SCLn pin low </description>
                                    <value>#0</value>
                                </enumeratedValue>
                                <enumeratedValue>
                                    <name>1</name>
                                    <description>Read: IIC releases SCLn pin Write: IIC releases SCLn pin </description>
                                    <value>#1</value>
                                </enumeratedValue>
                            </enumeratedValues>
                        </field>
                        <field>
                            <name>SOWP</name>
                            <description>SCLO/SDAO Write Protect</description>
                            <lsb>4</lsb>
                            <msb>4</msb>
                            <access>write-only</access>
                            <enumeratedValues>
                                <enumeratedValue>
                                    <name>0</name>
                                    <description>Write enable SCLO and SDAO bits</description>
                                    <value>#0</value>
                                </enumeratedValue>
                                <enumeratedValue>
                                    <name>1</name>
                                    <description>Write protect SCLO and SDAO bits</description>
                                    <value>#1</value>
                                </enumeratedValue>
                            </enumeratedValues>
                        </field>
                        <field>
                            <name>CLO</name>
                            <description>Extra SCL Clock Cycle Output</description>
                            <lsb>5</lsb>
                            <msb>5</msb>
                            <access>read-write</access>
                            <enumeratedValues>
                                <enumeratedValue>
                                    <name>0</name>
                                    <description>Do not output extra SCL clock cycle (default)</description>
                                    <value>#0</value>
                                </enumeratedValue>
                                <enumeratedValue>
                                    <name>1</name>
                                    <description>Output extra SCL clock cycle</description>
                                    <value>#1</value>
                                </enumeratedValue>
                            </enumeratedValues>
                        </field>
                        <field>
                            <name>IICRST</name>
                            <description>I2C Bus Interface Internal Reset</description>
                            <lsb>6</lsb>
                            <msb>6</msb>
                            <access>read-write</access>
                            <enumeratedValues>
                                <enumeratedValue>
                                    <name>0</name>
                                    <description>Release IIC reset or internal reset</description>
                                    <value>#0</value>
                                </enumeratedValue>
                                <enumeratedValue>
                                    <name>1</name>
                                    <description>Initiate IIC reset or internal reset</description>
                                    <value>#1</value>
                                </enumeratedValue>
                            </enumeratedValues>
                        </field>
                        <field>
                            <name>ICE</name>
                            <description>I2C Bus Interface Enable</description>
                            <lsb>7</lsb>
                            <msb>7</msb>
                            <access>read-write</access>
                            <enumeratedValues>
                                <enumeratedValue>
                                    <name>0</name>
                                    <description>Disable (SCLn and SDAn pins in inactive state)</description>
                                    <value>#0</value>
                                </enumeratedValue>
                                <enumeratedValue>
                                    <name>1</name>
                                    <description>Enable (SCLn and SDAn pins in active state)</description>
                                    <value>#1</value>
                                </enumeratedValue>
                            </enumeratedValues>
                        </field>
                    </fields>
                </register>
                <register>
                    <name>ICCR2</name>
                    <description>I2C Bus Control Register 2</description>
                    <addressOffset>0x01</addressOffset>
                    <size>8</size>
                    <access>read-write</access>
                    <resetValue>0x00</resetValue>
                    <resetMask>0xff</resetMask>
                    <fields>
                        <field>
                            <name>ST</name>
                            <description>Start Condition Issuance Request</description>
                            <lsb>1</lsb>
                            <msb>1</msb>
                            <access>read-write</access>
                            <enumeratedValues>
                                <enumeratedValue>
                                    <name>0</name>
                                    <description>Do not issue a start condition request</description>
                                    <value>#0</value>
                                </enumeratedValue>
                                <enumeratedValue>
                                    <name>1</name>
                                    <description>Issue a start condition request</description>
                                    <value>#1</value>
                                </enumeratedValue>
                            </enumeratedValues>
                        </field>
                        <field>
                            <name>RS</name>
                            <description>Restart Condition Issuance Request</description>
                            <lsb>2</lsb>
                            <msb>2</msb>
                            <access>read-write</access>
                            <enumeratedValues>
                                <enumeratedValue>
                                    <name>0</name>
                                    <description>Do not issue a restart condition request</description>
                                    <value>#0</value>
                                </enumeratedValue>
                                <enumeratedValue>
                                    <name>1</name>
                                    <description>Issue a restart condition request</description>
                                    <value>#1</value>
                                </enumeratedValue>
                            </enumeratedValues>
                        </field>
                        <field>
                            <name>SP</name>
                            <description>Stop Condition Issuance Request</description>
                            <lsb>3</lsb>
                            <msb>3</msb>
                            <access>read-write</access>
                            <enumeratedValues>
                                <enumeratedValue>
                                    <name>0</name>
                                    <description>Do not issue a stop condition request</description>
                                    <value>#0</value>
                                </enumeratedValue>
                                <enumeratedValue>
                                    <name>1</name>
                                    <description>Issue a stop condition request</description>
                                    <value>#1</value>
                                </enumeratedValue>
                            </enumeratedValues>
                        </field>
                        <field>
                            <name>TRS</name>
                            <description>Transmit/Receive Mode</description>
                            <lsb>5</lsb>
                            <msb>5</msb>
                            <access>read-write</access>
                            <enumeratedValues>
                                <enumeratedValue>
                                    <name>0</name>
                                    <description>Receive mode</description>
                                    <value>#0</value>
                                </enumeratedValue>
                                <enumeratedValue>
                                    <name>1</name>
                                    <description>Transmit mode</description>
                                    <value>#1</value>
                                </enumeratedValue>
                            </enumeratedValues>
                        </field>
                        <field>
                            <name>MST</name>
                            <description>Master/Slave Mode</description>
                            <lsb>6</lsb>
                            <msb>6</msb>
                            <access>read-write</access>
                            <enumeratedValues>
                                <enumeratedValue>
                                    <name>0</name>
                                    <description>Slave mode</description>
                                    <value>#0</value>
                                </enumeratedValue>
                                <enumeratedValue>
                                    <name>1</name>
                                    <description>Master mode</description>
                                    <value>#1</value>
                                </enumeratedValue>
                            </enumeratedValues>
                        </field>
                        <field>
                            <name>BBSY</name>
                            <description>Bus Busy Detection Flag</description>
                            <lsb>7</lsb>
                            <msb>7</msb>
                            <access>read-only</access>
                            <enumeratedValues>
                                <enumeratedValue>
                                    <name>0</name>
                                    <description>I2C bus released (bus free state)</description>
                                    <value>#0</value>
                                </enumeratedValue>
                                <enumeratedValue>
                                    <name>1</name>
                                    <description>I2C bus occupied (bus busy state)</description>
                                    <value>#1</value>
                                </enumeratedValue>
                            </enumeratedValues>
                        </field>
                    </fields>
                </register>
                <register>
                    <name>ICMR1</name>
                    <description>I2C Bus Mode Register 1</description>
                    <addressOffset>0x02</addressOffset>
                    <size>8</size>
                    <access>read-write</access>
                    <resetValue>0x08</resetValue>
                    <resetMask>0xff</resetMask>
                    <fields>
                        <field>
                            <name>BC</name>
                            <description>Bit Counter</description>
                            <lsb>0</lsb>
                            <msb>2</msb>
                            <access>read-write</access>
                            <enumeratedValues>
                                <enumeratedValue>
                                    <name>000</name>
                                    <description>9 bits</description>
                                    <value>#000</value>
                                </enumeratedValue>
                                <enumeratedValue>
                                    <name>001</name>
                                    <description>2 bits</description>
                                    <value>#001</value>
                                </enumeratedValue>
                                <enumeratedValue>
                                    <name>010</name>
                                    <description>3 bits</description>
                                    <value>#010</value>
                                </enumeratedValue>
                                <enumeratedValue>
                                    <name>011</name>
                                    <description>4 bits</description>
                                    <value>#011</value>
                                </enumeratedValue>
                                <enumeratedValue>
                                    <name>100</name>
                                    <description>5 bits</description>
                                    <value>#100</value>
                                </enumeratedValue>
                                <enumeratedValue>
                                    <name>101</name>
                                    <description>6 bits</description>
                                    <value>#101</value>
                                </enumeratedValue>
                                <enumeratedValue>
                                    <name>110</name>
                                    <description>7 bits</description>
                                    <value>#110</value>
                                </enumeratedValue>
                                <enumeratedValue>
                                    <name>111</name>
                                    <description>8 bits</description>
                                    <value>#111</value>
                                </enumeratedValue>
                            </enumeratedValues>
                        </field>
                        <field>
                            <name>BCWP</name>
                            <description>BC Write Protect</description>
                            <lsb>3</lsb>
                            <msb>3</msb>
                            <access>write-only</access>
                            <enumeratedValues>
                                <enumeratedValue>
                                    <name>0</name>
                                    <description>Write enable BC[2:0] bits</description>
                                    <value>#0</value>
                                </enumeratedValue>
                                <enumeratedValue>
                                    <name>1</name>
                                    <description>Write protect BC[2:0] bits</description>
                                    <value>#1</value>
                                </enumeratedValue>
                            </enumeratedValues>
                        </field>
                        <field>
                            <name>CKS</name>
                            <description>Internal Reference Clock Select</description>
                            <lsb>4</lsb>
                            <msb>6</msb>
                            <access>read-write</access>
                        </field>
                        <field>
                            <name>MTWP</name>
                            <description>MST/TRS Write Protect</description>
                            <lsb>7</lsb>
                            <msb>7</msb>
                            <access>read-write</access>
                            <enumeratedValues>
                                <enumeratedValue>
                                    <name>0</name>
                                    <description>Write protect MST and TRS bits in ICCR2</description>
                                    <value>#0</value>
                                </enumeratedValue>
                                <enumeratedValue>
                                    <name>1</name>
                                    <description>Write enable MST and TRS bits in ICCR2</description>
                                    <value>#1</value>
                                </enumeratedValue>
                            </enumeratedValues>
                        </field>
                    </fields>
                </register>
                <register>
                    <name>ICMR2</name>
                    <description>I2C Bus Mode Register 2</description>
                    <addressOffset>0x03</addressOffset>
                    <size>8</size>
                    <access>read-write</access>
                    <resetValue>0x06</resetValue>
                    <resetMask>0xff</resetMask>
                    <fields>
                        <field>
                            <name>TMOS</name>
                            <description>Timeout Detection Time Select</description>
                            <lsb>0</lsb>
                            <msb>0</msb>
                            <access>read-write</access>
                            <enumeratedValues>
                                <enumeratedValue>
                                    <name>0</name>
                                    <description>Select long mode</description>
                                    <value>#0</value>
                                </enumeratedValue>
                                <enumeratedValue>
                                    <name>1</name>
                                    <description>Select short mode</description>
                                    <value>#1</value>
                                </enumeratedValue>
                            </enumeratedValues>
                        </field>
                        <field>
                            <name>TMOL</name>
                            <description>Timeout L Count Control</description>
                            <lsb>1</lsb>
                            <msb>1</msb>
                            <access>read-write</access>
                            <enumeratedValues>
                                <enumeratedValue>
                                    <name>0</name>
                                    <description>Disable count while SCLn line is low</description>
                                    <value>#0</value>
                                </enumeratedValue>
                                <enumeratedValue>
                                    <name>1</name>
                                    <description>Enable count while SCLn line is low</description>
                                    <value>#1</value>
                                </enumeratedValue>
                            </enumeratedValues>
                        </field>
                        <field>
                            <name>TMOH</name>
                            <description>Timeout H Count Control</description>
                            <lsb>2</lsb>
                            <msb>2</msb>
                            <access>read-write</access>
                            <enumeratedValues>
                                <enumeratedValue>
                                    <name>0</name>
                                    <description>Disable count while SCLn line is high</description>
                                    <value>#0</value>
                                </enumeratedValue>
                                <enumeratedValue>
                                    <name>1</name>
                                    <description>Enable count while SCLn line is high</description>
                                    <value>#1</value>
                                </enumeratedValue>
                            </enumeratedValues>
                        </field>
                        <field>
                            <name>SDDL</name>
                            <description>SDA Output Delay Counter</description>
                            <lsb>4</lsb>
                            <msb>6</msb>
                            <access>read-write</access>
                            <enumeratedValues>
                                <enumeratedValue>
                                    <name>000</name>
                                    <description>No output delay</description>
                                    <value>#000</value>
                                </enumeratedValue>
                                <enumeratedValue>
                                    <name>001</name>
                                    <description>1 IIC-phi cycle (When ICMR2.DLCS = 0 (IIC-phi)) 1 or 2 IIC-phi cycles (When ICMR2.DLCS = 1 (IIC-phi/2)) </description>
                                    <value>#001</value>
                                </enumeratedValue>
                                <enumeratedValue>
                                    <name>010</name>
                                    <description>2 IIC-phi cycles (When ICMR2.DLCS = 0 (IIC-phi)) 3 or 4 IIC-phi cycles (When ICMR2.DLCS = 1 (IIC-phi/2)) </description>
                                    <value>#010</value>
                                </enumeratedValue>
                                <enumeratedValue>
                                    <name>011</name>
                                    <description>3 IIC-phi cycles (When ICMR2.DLCS = 0 (IIC-phi)) 5 or 6 IIC-phi cycles (When ICMR2.DLCS = 1 (IIC-phi/2)) </description>
                                    <value>#011</value>
                                </enumeratedValue>
                                <enumeratedValue>
                                    <name>100</name>
                                    <description>4 IIC-phi cycles (When ICMR2.DLCS = 0 (IIC-phi)) 7 or 8 IIC-phi cycles (When ICMR2.DLCS = 1 (IIC-phi/2)) </description>
                                    <value>#100</value>
                                </enumeratedValue>
                                <enumeratedValue>
                                    <name>101</name>
                                    <description>5 IIC-phi cycles (When ICMR2.DLCS = 0 (IIC-phi)) 9 or 10 IIC-phi cycles (When ICMR2.DLCS = 1 (IIC-phi/2)) </description>
                                    <value>#101</value>
                                </enumeratedValue>
                                <enumeratedValue>
                                    <name>110</name>
                                    <description>6 IIC-phi cycles (When ICMR2.DLCS = 0 (IIC-phi)) 11 or 12 IIC-phi cycles (When ICMR2.DLCS = 1 (IIC-phi/2)) </description>
                                    <value>#110</value>
                                </enumeratedValue>
                                <enumeratedValue>
                                    <name>111</name>
                                    <description>7 IIC-phi cycles (When ICMR2.DLCS = 0 (IIC-phi)) 13 or 14 IIC-phi cycles (When ICMR2.DLCS = 1 (IIC-phi/2)) </description>
                                    <value>#111</value>
                                </enumeratedValue>
                            </enumeratedValues>
                        </field>
                        <field>
                            <name>DLCS</name>
                            <description>SDA Output Delay Clock Source Select</description>
                            <lsb>7</lsb>
                            <msb>7</msb>
                            <access>read-write</access>
                            <enumeratedValues>
                                <enumeratedValue>
                                    <name>0</name>
                                    <description>Select internal reference clock (IIC-phi) as the clock source for SDA output delay counter</description>
                                    <value>#0</value>
                                </enumeratedValue>
                                <enumeratedValue>
                                    <name>1</name>
                                    <description>Select internal reference clock divided by 2 (IIC-phi/2) as the clock source for SDA output delay counter</description>
                                    <value>#1</value>
                                </enumeratedValue>
                            </enumeratedValues>
                        </field>
                    </fields>
                </register>
                <register>
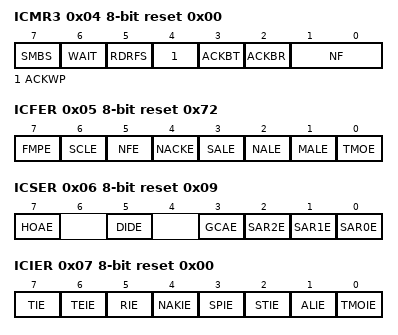
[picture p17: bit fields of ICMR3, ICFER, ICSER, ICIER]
                    <name>ICMR3</name>
                    <description>I2C Bus Mode Register 3</description>
                    <addressOffset>0x04</addressOffset>
                    <size>8</size>
                    <access>read-write</access>
                    <resetValue>0x00</resetValue>
                    <resetMask>0xff</resetMask>
                    <fields>
                        <field>
                            <name>NF</name>
                            <description>Noise Filter Stage Select</description>
                            <lsb>0</lsb>
                            <msb>1</msb>
                            <access>read-write</access>
                            <enumeratedValues>
                                <enumeratedValue>
                                    <name>00</name>
                                    <description>Filter out noise of up to 1 IIC-phi cycle (single-stage filter)</description>
                                    <value>#00</value>
                                </enumeratedValue>
                                <enumeratedValue>
                                    <name>01</name>
                                    <description>Filter out noise of up to 2 IIC-phi cycles (2-stage filter)</description>
                                    <value>#01</value>
                                </enumeratedValue>
                                <enumeratedValue>
                                    <name>10</name>
                                    <description>Filter out noise of up to 3 IIC-phi cycles (3-stage filter)</description>
                                    <value>#10</value>
                                </enumeratedValue>
                                <enumeratedValue>
                                    <name>11</name>
                                    <description>Filter out noise of up to 4 IIC-phi cycles (4-stage filter)</description>
                                    <value>#11</value>
                                </enumeratedValue>
                            </enumeratedValues>
                        </field>
                        <field>
                            <name>ACKBR</name>
                            <description>Receive Acknowledge</description>
                            <lsb>2</lsb>
                            <msb>2</msb>
                            <access>read-only</access>
                            <enumeratedValues>
                                <enumeratedValue>
                                    <name>0</name>
                                    <description>0 received as the acknowledge bit (ACK reception)</description>
                                    <value>#0</value>
                                </enumeratedValue>
                                <enumeratedValue>
                                    <name>1</name>
                                    <description>1 received as the acknowledge bit (NACK reception)</description>
                                    <value>#1</value>
                                </enumeratedValue>
                            </enumeratedValues>
                        </field>
                        <field>
                            <name>ACKBT</name>
                            <description>Transmit Acknowledge</description>
                            <lsb>3</lsb>
                            <msb>3</msb>
                            <access>read-write</access>
                            <enumeratedValues>
                                <enumeratedValue>
                                    <name>0</name>
                                    <description>Send 0 as the acknowledge bit (ACK transmission)</description>
                                    <value>#0</value>
                                </enumeratedValue>
                                <enumeratedValue>
                                    <name>1</name>
                                    <description>Send 1 as the acknowledge bit (NACK transmission)</description>
                                    <value>#1</value>
                                </enumeratedValue>
                            </enumeratedValues>
                        </field>
                        <field>
                            <name>ACKWP</name>
                            <description>ACKBT Write Protect</description>
                            <lsb>4</lsb>
                            <msb>4</msb>
                            <access>read-write</access>
                            <enumeratedValues>
                                <enumeratedValue>
                                    <name>0</name>
                                    <description>Write protect ACKBT bit</description>
                                    <value>#0</value>
                                </enumeratedValue>
                                <enumeratedValue>
                                    <name>1</name>
                                    <description>Write enable ACKBT bit</description>
                                    <value>#1</value>
                                </enumeratedValue>
                            </enumeratedValues>
                        </field>
                        <field>
                            <name>RDRFS</name>
                            <description>RDRF Flag Set Timing Select</description>
                            <lsb>5</lsb>
                            <msb>5</msb>
                            <access>read-write</access>
                            <enumeratedValues>
                                <enumeratedValue>
                                    <name>0</name>
                                    <description>Set the RDRF flag on the rising edge of the 9th SCL clock cycle. The SCLn line is not held low on the falling edge of the 8th clock cycle.</description>
                                    <value>#0</value>
                                </enumeratedValue>
                                <enumeratedValue>
                                    <name>1</name>
                                    <description>Set the RDRF flag on the rising edge of the 8th SCL clock cycle. The SCLn line is held low on the falling edge of the 8th clock cycle.</description>
                                    <value>#1</value>
                                </enumeratedValue>
                            </enumeratedValues>
                        </field>
                        <field>
                            <name>WAIT</name>
                            <description>Low-hold is released by reading ICDRR.</description>
                            <lsb>6</lsb>
                            <msb>6</msb>
                            <access>read-write</access>
                            <enumeratedValues>
                                <enumeratedValue>
                                    <name>0</name>
                                    <description>No wait (The SCLn line is not held low during the period between the 9th clock cycle and the 1st clock cycle.)</description>
                                    <value>#0</value>
                                </enumeratedValue>
                                <enumeratedValue>
                                    <name>1</name>
                                    <description>Wait (The SCLn line is held low during the period between the 9th clock cycle and the 1st clock cycle.)</description>
                                    <value>#1</value>
                                </enumeratedValue>
                            </enumeratedValues>
                        </field>
                        <field>
                            <name>SMBS</name>
                            <description>SMBus/I2C Bus Select</description>
                            <lsb>7</lsb>
                            <msb>7</msb>
                            <access>read-write</access>
                            <enumeratedValues>
                                <enumeratedValue>
                                    <name>0</name>
                                    <description>Select I2C Bus</description>
                                    <value>#0</value>
                                </enumeratedValue>
                                <enumeratedValue>
                                    <name>1</name>
                                    <description>Select SMBus</description>
                                    <value>#1</value>
                                </enumeratedValue>
                            </enumeratedValues>
                        </field>
                    </fields>
                </register>
                <register>
                    <name>ICFER</name>
                    <description>I2C Bus Function Enable Register</description>
                    <addressOffset>0x05</addressOffset>
                    <size>8</size>
                    <access>read-write</access>
                    <resetValue>0x72</resetValue>
                    <resetMask>0xff</resetMask>
                    <fields>
                        <field>
                            <name>TMOE</name>
                            <description>Timeout Function Enable</description>
                            <lsb>0</lsb>
                            <msb>0</msb>
                            <access>read-write</access>
                            <enumeratedValues>
                                <enumeratedValue>
                                    <name>0</name>
                                    <description>Disable</description>
                                    <value>#0</value>
                                </enumeratedValue>
                                <enumeratedValue>
                                    <name>1</name>
                                    <description>Enable</description>
                                    <value>#1</value>
                                </enumeratedValue>
                            </enumeratedValues>
                        </field>
                        <field>
                            <name>MALE</name>
                            <description>Master Arbitration-Lost Detection Enable</description>
                            <lsb>1</lsb>
                            <msb>1</msb>
                            <access>read-write</access>
                            <enumeratedValues>
                                <enumeratedValue>
                                    <name>0</name>
                                    <description>Disable the arbitration-lost detection function and disable automatic clearing of the MST and TRS bits in ICCR2 when arbitration is lost</description>
                                    <value>#0</value>
                                </enumeratedValue>
                                <enumeratedValue>
                                    <name>1</name>
                                    <description>Enable the arbitration-lost detection function and enable automatic clearing of the MST and TRS bits in ICCR2 when arbitration is lost</description>
                                    <value>#1</value>
                                </enumeratedValue>
                            </enumeratedValues>
                        </field>
                        <field>
                            <name>NALE</name>
                            <description>NACK Transmission Arbitration-Lost Detection Enable</description>
                            <lsb>2</lsb>
                            <msb>2</msb>
                            <access>read-write</access>
                            <enumeratedValues>
                                <enumeratedValue>
                                    <name>0</name>
                                    <description>Disable</description>
                                    <value>#0</value>
                                </enumeratedValue>
                                <enumeratedValue>
                                    <name>1</name>
                                    <description>Enable</description>
                                    <value>#1</value>
                                </enumeratedValue>
                            </enumeratedValues>
                        </field>
                        <field>
                            <name>SALE</name>
                            <description>Slave Arbitration-Lost Detection Enable</description>
                            <lsb>3</lsb>
                            <msb>3</msb>
                            <access>read-write</access>
                            <enumeratedValues>
                                <enumeratedValue>
                                    <name>0</name>
                                    <description>Disable</description>
                                    <value>#0</value>
                                </enumeratedValue>
                                <enumeratedValue>
                                    <name>1</name>
                                    <description>Enable</description>
                                    <value>#1</value>
                                </enumeratedValue>
                            </enumeratedValues>
                        </field>
                        <field>
                            <name>NACKE</name>
                            <description>NACK Reception Transfer Suspension Enable</description>
                            <lsb>4</lsb>
                            <msb>4</msb>
                            <access>read-write</access>
                            <enumeratedValues>
                                <enumeratedValue>
                                    <name>0</name>
                                    <description>Do not suspend transfer operation during NACK reception (disable transfer suspension)</description>
                                    <value>#0</value>
                                </enumeratedValue>
                                <enumeratedValue>
                                    <name>1</name>
                                    <description>Suspend transfer operation during NACK reception (enable transfer suspension)</description>
                                    <value>#1</value>
                                </enumeratedValue>
                            </enumeratedValues>
                        </field>
                        <field>
                            <name>NFE</name>
                            <description>Digital Noise Filter Circuit Enable</description>
                            <lsb>5</lsb>
                            <msb>5</msb>
                            <access>read-write</access>
                            <enumeratedValues>
                                <enumeratedValue>
                                    <name>0</name>
                                    <description>Do not use the digital noise filter circuit</description>
                                    <value>#0</value>
                                </enumeratedValue>
                                <enumeratedValue>
                                    <name>1</name>
                                    <description>Use the digital noise filter circuit</description>
                                    <value>#1</value>
                                </enumeratedValue>
                            </enumeratedValues>
                        </field>
                        <field>
                            <name>SCLE</name>
                            <description>SCL Synchronous Circuit Enable</description>
                            <lsb>6</lsb>
                            <msb>6</msb>
                            <access>read-write</access>
                            <enumeratedValues>
                                <enumeratedValue>
                                    <name>0</name>
                                    <description>Do not use the SCL synchronous circuit</description>
                                    <value>#0</value>
                                </enumeratedValue>
                                <enumeratedValue>
                                    <name>1</name>
                                    <description>Use the SCL synchronous circuit</description>
                                    <value>#1</value>
                                </enumeratedValue>
                            </enumeratedValues>
                        </field>
                        <field>
                            <name>FMPE</name>
                            <description>Fast-Mode Plus Enable</description>
                            <lsb>7</lsb>
                            <msb>7</msb>
                            <access>read-write</access>
                            <enumeratedValues>
                                <enumeratedValue>
                                    <name>0</name>
                                    <description>Do not use the Fm+ slope control circuit for the SCLn and SDAn pins</description>
                                    <value>#0</value>
                                </enumeratedValue>
                                <enumeratedValue>
                                    <name>1</name>
                                    <description>Use the Fm+ slope control circuit for the SCLn and SDAn pins.</description>
                                    <value>#1</value>
                                </enumeratedValue>
                            </enumeratedValues>
                        </field>
                    </fields>
                </register>
                <register>
                    <name>ICSER</name>
                    <description>I2C Bus Status Enable Register</description>
                    <addressOffset>0x06</addressOffset>
                    <size>8</size>
                    <access>read-write</access>
                    <resetValue>0x09</resetValue>
                    <resetMask>0xff</resetMask>
                    <fields>
                        <field>
                            <name>SAR0E</name>
                            <description>Slave Address Register 0 Enable</description>
                            <lsb>0</lsb>
                            <msb>0</msb>
                            <access>read-write</access>
                            <enumeratedValues>
                                <enumeratedValue>
                                    <name>0</name>
                                    <description>Disable slave address in SARL0 and SARU0</description>
                                    <value>#0</value>
                                </enumeratedValue>
                                <enumeratedValue>
                                    <name>1</name>
                                    <description>Enable slave address in SARL0 and SARU0</description>
                                    <value>#1</value>
                                </enumeratedValue>
                            </enumeratedValues>
                        </field>
                        <field>
                            <name>SAR1E</name>
                            <description>Slave Address Register 1 Enable</description>
                            <lsb>1</lsb>
                            <msb>1</msb>
                            <access>read-write</access>
                            <enumeratedValues>
                                <enumeratedValue>
                                    <name>0</name>
                                    <description>Disable slave address in SARL1 and SARU1</description>
                                    <value>#0</value>
                                </enumeratedValue>
                                <enumeratedValue>
                                    <name>1</name>
                                    <description>Enable slave address in SARL1 and SARU1</description>
                                    <value>#1</value>
                                </enumeratedValue>
                            </enumeratedValues>
                        </field>
                        <field>
                            <name>SAR2E</name>
                            <description>Slave Address Register 2 Enable</description>
                            <lsb>2</lsb>
                            <msb>2</msb>
                            <access>read-write</access>
                            <enumeratedValues>
                                <enumeratedValue>
                                    <name>0</name>
                                    <description>Disable slave address in SARL2 and SARU2</description>
                                    <value>#0</value>
                                </enumeratedValue>
                                <enumeratedValue>
                                    <name>1</name>
                                    <description>Enable slave address in SARL2 and SARU2</description>
                                    <value>#1</value>
                                </enumeratedValue>
                            </enumeratedValues>
                        </field>
                        <field>
                            <name>GCAE</name>
                            <description>General Call Address Enable</description>
                            <lsb>3</lsb>
                            <msb>3</msb>
                            <access>read-write</access>
                            <enumeratedValues>
                                <enumeratedValue>
                                    <name>0</name>
                                    <description>Disable general call address detection</description>
                                    <value>#0</value>
                                </enumeratedValue>
                                <enumeratedValue>
                                    <name>1</name>
                                    <description>Enable general call address detection</description>
                                    <value>#1</value>
                                </enumeratedValue>
                            </enumeratedValues>
                        </field>
                        <field>
                            <name>DIDE</name>
                            <description>Device-ID Address Detection Enable</description>
                            <lsb>5</lsb>
                            <msb>5</msb>
                            <access>read-write</access>
                            <enumeratedValues>
                                <enumeratedValue>
                                    <name>0</name>
                                    <description>Disable device-ID address detection</description>
                                    <value>#0</value>
                                </enumeratedValue>
                                <enumeratedValue>
                                    <name>1</name>
                                    <description>Enable device-ID address detection</description>
                                    <value>#1</value>
                                </enumeratedValue>
                            </enumeratedValues>
                        </field>
                        <field>
                            <name>HOAE</name>
                            <description>Host Address Enable</description>
                            <lsb>7</lsb>
                            <msb>7</msb>
                            <access>read-write</access>
                            <enumeratedValues>
                                <enumeratedValue>
                                    <name>0</name>
                                    <description>Disable host address detection</description>
                                    <value>#0</value>
                                </enumeratedValue>
                                <enumeratedValue>
                                    <name>1</name>
                                    <description>Enable host address detection</description>
                                    <value>#1</value>
                                </enumeratedValue>
                            </enumeratedValues>
                        </field>
                    </fields>
                </register>
                <register>
                    <name>ICIER</name>
                    <description>I2C Bus Interrupt Enable Register</description>
                    <addressOffset>0x07</addressOffset>
                    <size>8</size>
                    <access>read-write</access>
                    <resetValue>0x00</resetValue>
                    <resetMask>0xff</resetMask>
                    <fields>
                        <field>
                            <name>TMOIE</name>
                            <description>Timeout Interrupt Request Enable</description>
                            <lsb>0</lsb>
                            <msb>0</msb>
                            <access>read-write</access>
                            <enumeratedValues>
                                <enumeratedValue>
                                    <name>0</name>
                                    <description>Disable timeout interrupt (TMOI) request</description>
                                    <value>#0</value>
                                </enumeratedValue>
                                <enumeratedValue>
                                    <name>1</name>
                                    <description>Enable timeout interrupt (TMOI) request</description>
                                    <value>#1</value>
                                </enumeratedValue>
                            </enumeratedValues>
                        </field>
                        <field>
                            <name>ALIE</name>
                            <description>Arbitration-Lost Interrupt Request Enable</description>
                            <lsb>1</lsb>
                            <msb>1</msb>
                            <access>read-write</access>
                            <enumeratedValues>
                                <enumeratedValue>
                                    <name>0</name>
                                    <description>Disable arbitration-lost interrupt (ALI) request</description>
                                    <value>#0</value>
                                </enumeratedValue>
                                <enumeratedValue>
                                    <name>1</name>
                                    <description>Enable arbitration-lost interrupt (ALI) request</description>
                                    <value>#1</value>
                                </enumeratedValue>
                            </enumeratedValues>
                        </field>
                        <field>
                            <name>STIE</name>
                            <description>Start Condition Detection Interrupt Request Enable</description>
                            <lsb>2</lsb>
                            <msb>2</msb>
                            <access>read-write</access>
                            <enumeratedValues>
                                <enumeratedValue>
                                    <name>0</name>
                                    <description>Disable start condition detection interrupt (STI) request</description>
                                    <value>#0</value>
                                </enumeratedValue>
                                <enumeratedValue>
                                    <name>1</name>
                                    <description>Enable start condition detection interrupt (STI) request</description>
                                    <value>#1</value>
                                </enumeratedValue>
                            </enumeratedValues>
                        </field>
                        <field>
                            <name>SPIE</name>
                            <description>Stop Condition Detection Interrupt Request Enable</description>
                            <lsb>3</lsb>
                            <msb>3</msb>
                            <access>read-write</access>
                            <enumeratedValues>
                                <enumeratedValue>
                                    <name>0</name>
                                    <description>Disable stop condition detection interrupt (SPI) request</description>
                                    <value>#0</value>
                                </enumeratedValue>
                                <enumeratedValue>
                                    <name>1</name>
                                    <description>Enable stop condition detection interrupt (SPI) request</description>
                                    <value>#1</value>
                                </enumeratedValue>
                            </enumeratedValues>
                        </field>
                        <field>
                            <name>NAKIE</name>
                            <description>NACK Reception Interrupt Request Enable</description>
                            <lsb>4</lsb>
                            <msb>4</msb>
                            <access>read-write</access>
                            <enumeratedValues>
                                <enumeratedValue>
                                    <name>0</name>
                                    <description>Disable NACK reception interrupt (NAKI) request</description>
                                    <value>#0</value>
                                </enumeratedValue>
                                <enumeratedValue>
                                    <name>1</name>
                                    <description>Enable NACK reception interrupt (NAKI) request</description>
                                    <value>#1</value>
                                </enumeratedValue>
                            </enumeratedValues>
                        </field>
                        <field>
                            <name>RIE</name>
                            <description>Receive Data Full Interrupt Request Enable</description>
                            <lsb>5</lsb>
                            <msb>5</msb>
                            <access>read-write</access>
                            <enumeratedValues>
                                <enumeratedValue>
                                    <name>0</name>
                                    <description>Disable receive data full interrupt (IICn_RXI) request</description>
                                    <value>#0</value>
                                </enumeratedValue>
                                <enumeratedValue>
                                    <name>1</name>
                                    <description>Enable receive data full interrupt (IICn_RXI) request</description>
                                    <value>#1</value>
                                </enumeratedValue>
                            </enumeratedValues>
                        </field>
                        <field>
                            <name>TEIE</name>
                            <description>Transmit End Interrupt Request Enable</description>
                            <lsb>6</lsb>
                            <msb>6</msb>
                            <access>read-write</access>
                            <enumeratedValues>
                                <enumeratedValue>
                                    <name>0</name>
                                    <description>Disable transmit end interrupt (IICn_TEI) request</description>
                                    <value>#0</value>
                                </enumeratedValue>
                                <enumeratedValue>
                                    <name>1</name>
                                    <description>Enable transmit end interrupt (IICn_TEI) request</description>
                                    <value>#1</value>
                                </enumeratedValue>
                            </enumeratedValues>
                        </field>
                        <field>
                            <name>TIE</name>
                            <description>Transmit Data Empty Interrupt Request Enable</description>
                            <lsb>7</lsb>
                            <msb>7</msb>
                            <access>read-write</access>
                            <enumeratedValues>
                                <enumeratedValue>
                                    <name>0</name>
                                    <description>Disable transmit data empty interrupt (IICn_TXI) request</description>
                                    <value>#0</value>
                                </enumeratedValue>
                                <enumeratedValue>
                                    <name>1</name>
                                    <description>Enable transmit data empty interrupt (IICn_TXI) request</description>
                                    <value>#1</value>
                                </enumeratedValue>
                            </enumeratedValues>
                        </field>
                    </fields>
                </register>
                <register>
                    <name>ICSR1</name>
                    <description>I2C Bus Status Register 1</description>
                    <addressOffset>0x08</addressOffset>
                    <size>8</size>
                    <access>read-write</access>
                    <resetValue>0x00</resetValue>
                    <resetMask>0xff</resetMask>
                    <fields>
                        <field>
                            <name>AAS0</name>
                            <description>Slave Address 0 Detection Flag</description>
                            <lsb>0</lsb>
                            <msb>0</msb>
                            <access>read-write</access>
                            <enumeratedValues>
                                <enumeratedValue>
                                    <name>0</name>
                                    <description>Slave address 0 not detected</description>
                                    <value>#0</value>
                                </enumeratedValue>
                                <enumeratedValue>
                                    <name>1</name>
                                    <description>Slave address 0 detected</description>
                                    <value>#1</value>
                                </enumeratedValue>
                            </enumeratedValues>
                        </field>
                        <field>
                            <name>AAS1</name>
                            <description>Slave Address 1 Detection Flag</description>
                            <lsb>1</lsb>
                            <msb>1</msb>
                            <access>read-write</access>
                            <enumeratedValues>
                                <enumeratedValue>
                                    <name>0</name>
                                    <description>Slave address 1 not detected</description>
                                    <value>#0</value>
                                </enumeratedValue>
                                <enumeratedValue>
                                    <name>1</name>
                                    <description>Slave address 1 detected</description>
                                    <value>#1</value>
                                </enumeratedValue>
                            </enumeratedValues>
                        </field>
                        <field>
                            <name>AAS2</name>
                            <description>Slave Address 2 Detection Flag</description>
                            <lsb>2</lsb>
                            <msb>2</msb>
                            <access>read-write</access>
                            <enumeratedValues>
                                <enumeratedValue>
                                    <name>0</name>
                                    <description>Slave address 2 not detected</description>
                                    <value>#0</value>
                                </enumeratedValue>
                                <enumeratedValue>
                                    <name>1</name>
                                    <description>Slave address 2 detected</description>
                                    <value>#1</value>
                                </enumeratedValue>
                            </enumeratedValues>
                        </field>
                        <field>
                            <name>GCA</name>
                            <description>General Call Address Detection Flag</description>
                            <lsb>3</lsb>
                            <msb>3</msb>
                            <access>read-write</access>
                            <enumeratedValues>
                                <enumeratedValue>
                                    <name>0</name>
                                    <description>General call address not detected</description>
                                    <value>#0</value>
                                </enumeratedValue>
                                <enumeratedValue>
                                    <name>1</name>
                                    <description>General call address detected</description>
                                    <value>#1</value>
                                </enumeratedValue>
                            </enumeratedValues>
                        </field>
                        <field>
                            <name>DID</name>
                            <description>Device-ID Address Detection Flag</description>
                            <lsb>5</lsb>
                            <msb>5</msb>
                            <access>read-write</access>
                            <enumeratedValues>
                                <enumeratedValue>
                                    <name>0</name>
                                    <description>Device-ID command not detected</description>
                                    <value>#0</value>
                                </enumeratedValue>
                                <enumeratedValue>
                                    <name>1</name>
                                    <description>Device-ID command detected</description>
                                    <value>#1</value>
                                </enumeratedValue>
                            </enumeratedValues>
                        </field>
                        <field>
                            <name>HOA</name>
                            <description>Host Address Detection Flag</description>
                            <lsb>7</lsb>
                            <msb>7</msb>
                            <access>read-write</access>
                            <enumeratedValues>
                                <enumeratedValue>
                                    <name>0</name>
                                    <description>Host address not detected</description>
                                    <value>#0</value>
                                </enumeratedValue>
                                <enumeratedValue>
                                    <name>1</name>
                                    <description>Host address detected</description>
                                    <value>#1</value>
                                </enumeratedValue>
                            </enumeratedValues>
                        </field>
                    </fields>
                </register>
                <register>
                    <name>ICSR2</name>
                    <description>I2C Bus Status Register 2</description>
                    <addressOffset>0x09</addressOffset>
                    <size>8</size>
                    <access>read-write</access>
                    <resetValue>0x00</resetValue>
                    <resetMask>0xff</resetMask>
                    <fields>
                        <field>
                            <name>TMOF</name>
                            <description>Timeout Detection Flag</description>
                            <lsb>0</lsb>
                            <msb>0</msb>
                            <access>read-write</access>
                            <enumeratedValues>
                                <enumeratedValue>
                                    <name>0</name>
                                    <description>Timeout not detected</description>
                                    <value>#0</value>
                                </enumeratedValue>
                                <enumeratedValue>
                                    <name>1</name>
                                    <description>Timeout detected</description>
                                    <value>#1</value>
                                </enumeratedValue>
                            </enumeratedValues>
                        </field>
                        <field>
                            <name>AL</name>
                            <description>Arbitration-Lost Flag</description>
                            <lsb>1</lsb>
                            <msb>1</msb>
                            <access>read-write</access>
                            <enumeratedValues>
                                <enumeratedValue>
                                    <name>0</name>
                                    <description>Arbitration not lost</description>
                                    <value>#0</value>
                                </enumeratedValue>
                                <enumeratedValue>
                                    <name>1</name>
                                    <description>Arbitration lost</description>
                                    <value>#1</value>
                                </enumeratedValue>
                            </enumeratedValues>
                        </field>
                        <field>
                            <name>START</name>
                            <description>Start Condition Detection Flag</description>
                            <lsb>2</lsb>
                            <msb>2</msb>
                            <access>read-write</access>
                            <enumeratedValues>
                                <enumeratedValue>
                                    <name>0</name>
                                    <description>Start condition not detected</description>
                                    <value>#0</value>
                                </enumeratedValue>
                                <enumeratedValue>
                                    <name>1</name>
                                    <description>Start condition detected</description>
                                    <value>#1</value>
                                </enumeratedValue>
                            </enumeratedValues>
                        </field>
                        <field>
                            <name>STOP</name>
                            <description>Stop Condition Detection Flag</description>
                            <lsb>3</lsb>
                            <msb>3</msb>
                            <access>read-write</access>
                            <enumeratedValues>
                                <enumeratedValue>
                                    <name>0</name>
                                    <description>Stop condition not detected</description>
                                    <value>#0</value>
                                </enumeratedValue>
                                <enumeratedValue>
                                    <name>1</name>
                                    <description>Stop condition detected</description>
                                    <value>#1</value>
                                </enumeratedValue>
                            </enumeratedValues>
                        </field>
                        <field>
                            <name>NACKF</name>
                            <description>NACK Detection Flag</description>
                            <lsb>4</lsb>
                            <msb>4</msb>
                            <access>read-write</access>
                            <enumeratedValues>
                                <enumeratedValue>
                                    <name>0</name>
                                    <description>NACK not detected</description>
                                    <value>#0</value>
                                </enumeratedValue>
                                <enumeratedValue>
                                    <name>1</name>
                                    <description>NACK detected</description>
                                    <value>#1</value>
                                </enumeratedValue>
                            </enumeratedValues>
                        </field>
                        <field>
                            <name>RDRF</name>
                            <description>Receive Data Full Flag</description>
                            <lsb>5</lsb>
                            <msb>5</msb>
                            <access>read-write</access>
                            <enumeratedValues>
                                <enumeratedValue>
                                    <name>0</name>
                                    <description>ICDRR contains no receive data</description>
                                    <value>#0</value>
                                </enumeratedValue>
                                <enumeratedValue>
                                    <name>1</name>
                                    <description>ICDRR contains receive data</description>
                                    <value>#1</value>
                                </enumeratedValue>
                            </enumeratedValues>
                        </field>
                        <field>
                            <name>TEND</name>
                            <description>Transmit End Flag</description>
                            <lsb>6</lsb>
                            <msb>6</msb>
                            <access>read-write</access>
                            <enumeratedValues>
                                <enumeratedValue>
                                    <name>0</name>
                                    <description>Data being transmitted</description>
                                    <value>#0</value>
                                </enumeratedValue>
                                <enumeratedValue>
                                    <name>1</name>
                                    <description>Data transmit complete</description>
                                    <value>#1</value>
                                </enumeratedValue>
                            </enumeratedValues>
                        </field>
                        <field>
                            <name>TDRE</name>
                            <description>Transmit Data Empty Flag</description>
                            <lsb>7</lsb>
                            <msb>7</msb>
                            <access>read-only</access>
                            <enumeratedValues>
                                <enumeratedValue>
                                    <name>0</name>
                                    <description>ICDRT contains transmit data</description>
                                    <value>#0</value>
                                </enumeratedValue>
                                <enumeratedValue>
                                    <name>1</name>
                                    <description>ICDRT contains no transmit data</description>
                                    <value>#1</value>
                                </enumeratedValue>
                            </enumeratedValues>
                        </field>
                    </fields>
                </register>
                <register>
                    <dim>3</dim>
                    <dimIncrement>0x02</dimIncrement>
                    <dimIndex>0-2</dimIndex>
                    <name>SARL%s</name>
                    <description>Slave Address Register Ly</description>
                    <addressOffset>0x0A</addressOffset>
                    <size>8</size>
                    <access>read-write</access>
                    <resetValue>0x00</resetValue>
                    <resetMask>0xff</resetMask>
                    <fields>
                        <field>
                            <name>SVA0</name>
                            <description>10-bit Address LSB</description>
                            <lsb>0</lsb>
                            <msb>0</msb>
                            <access>read-write</access>
                        </field>
                        <field>
                            <name>SVA</name>
                            <description>7-bit Address/10-bit Address Lower Bits</description>
                            <lsb>1</lsb>
                            <msb>7</msb>
                            <access>read-write</access>
                        </field>
                    </fields>
                </register>
                <register>
                    <dim>3</dim>
                    <dimIncrement>0x02</dimIncrement>
                    <dimIndex>0-2</dimIndex>
                    <name>SARU%s</name>
                    <description>Slave Address Register Uy</description>
                    <addressOffset>0x0B</addressOffset>
                    <size>8</size>
                    <access>read-write</access>
                    <resetValue>0x00</resetValue>
                    <resetMask>0xff</resetMask>
                    <fields>
                        <field>
                            <name>FS</name>
                            <description>7-bit/10-bit Address Format Select</description>
                            <lsb>0</lsb>
                            <msb>0</msb>
                            <access>read-write</access>
                            <enumeratedValues>
                                <enumeratedValue>
                                    <name>0</name>
                                    <description>Select 7-bit address format</description>
                                    <value>#0</value>
                                </enumeratedValue>
                                <enumeratedValue>
                                    <name>1</name>
                                    <description>Select 10-bit address format</description>
                                    <value>#1</value>
                                </enumeratedValue>
                            </enumeratedValues>
                        </field>
                        <field>
                            <name>SVA</name>
                            <description>10-bit Address Upper Bits</description>
                            <lsb>1</lsb>
                            <msb>2</msb>
                            <access>read-write</access>
                        </field>
                    </fields>
                </register>
                <register>
                    <name>ICBRL</name>
                    <description>I2C Bus Bit Rate Low-Level Register</description>
                    <addressOffset>0x10</addressOffset>
                    <size>8</size>
                    <access>read-write</access>
                    <resetValue>0xff</resetValue>
                    <resetMask>0xff</resetMask>
                    <fields>
                        <field>
                            <name>BRL</name>
                            <description>Bit Rate Low-Level Period</description>
                            <lsb>0</lsb>
                            <msb>4</msb>
                            <access>read-write</access>
                        </field>
                    </fields>
                </register>
                <register>
                    <name>ICBRH</name>
                    <description>I2C Bus Bit Rate High-Level Register</description>
                    <addressOffset>0x11</addressOffset>
                    <size>8</size>
                    <access>read-write</access>
                    <resetValue>0xff</resetValue>
                    <resetMask>0xff</resetMask>
                    <fields>
                        <field>
                            <name>BRH</name>
                            <description>Bit Rate High-Level Period</description>
                            <lsb>0</lsb>
                            <msb>4</msb>
                            <access>read-write</access>
                        </field>
                    </fields>
                </register>
                <register>
                    <name>ICDRT</name>
                    <description>I2C Bus Transmit Data Register</description>
                    <addressOffset>0x12</addressOffset>
                    <size>8</size>
                    <access>read-write</access>
                    <resetValue>0xff</resetValue>
                    <resetMask>0xff</resetMask>
                </register>
                <register>
                    <name>ICDRR</name>
                    <description>I2C Bus Receive Data Register</description>
                    <addressOffset>0x13</addressOffset>
                    <size>8</size>
                    <access>read-only</access>
                    <resetValue>0x00</resetValue>
                    <resetMask>0xff</resetMask>
                </register>
            </registers>
        </peripheral>
        <peripheral>
            <name>IIC0WU_NS</name>
            <description>Inter-Integrated Circuit 0 Wake-up Unit</description>
            <baseAddress>0x5025E014</baseAddress>
            <addressBlock>
                <offset>0x02</offset>
                <size>2</size>
                <usage>registers</usage>
            </addressBlock>
            <registers>
                <register>
                    <name>ICWUR</name>
                    <description>I2C Bus Wakeup Unit Register</description>
                    <addressOffset>0x02</addressOffset>
                    <size>8</size>
                    <access>read-write</access>
                    <resetValue>0x10</resetValue>
                    <resetMask>0xff</resetMask>
                    <fields>
                        <field>
                            <name>WUAFA</name>
                            <description>Wakeup Analog Filter Additional Selection</description>
                            <lsb>0</lsb>
                            <msb>0</msb>
                            <access>read-write</access>
                            <enumeratedValues>
                                <enumeratedValue>
                                    <name>0</name>
                                    <description>Do not add the wakeup analog filter</description>
                                    <value>#0</value>
                                </enumeratedValue>
                                <enumeratedValue>
                                    <name>1</name>
                                    <description>Add the wakeup analog filter</description>
                                    <value>#1</value>
                                </enumeratedValue>
                            </enumeratedValues>
                        </field>
                        <field>
                            <name>WUACK</name>
                            <description>ACK Bit for Wakeup Mode</description>
                            <lsb>4</lsb>
                            <msb>4</msb>
                            <access>read-write</access>
                        </field>
                        <field>
                            <name>WUF</name>
                            <description>Wakeup Event Occurrence Flag</description>
                            <lsb>5</lsb>
                            <msb>5</msb>
                            <access>read-write</access>
                            <enumeratedValues>
                                <enumeratedValue>
                                    <name>0</name>
                                    <description>Slave address not matching during wakeup</description>
                                    <value>#0</value>
                                </enumeratedValue>
                                <enumeratedValue>
                                    <name>1</name>
                                    <description>Slave address matching during wakeup</description>
                                    <value>#1</value>
                                </enumeratedValue>
                            </enumeratedValues>
                        </field>
                        <field>
                            <name>WUIE</name>
                            <description>Wakeup Interrupt Request Enable</description>
                            <lsb>6</lsb>
                            <msb>6</msb>
                            <access>read-write</access>
                            <enumeratedValues>
                                <enumeratedValue>
                                    <name>0</name>
                                    <description>Disable wakeup interrupt request (IIC0_WUI)</description>
                                    <value>#0</value>
                                </enumeratedValue>
                                <enumeratedValue>
                                    <name>1</name>
                                    <description>Enable wakeup interrupt request (IIC0_WUI)</description>
                                    <value>#1</value>
                                </enumeratedValue>
                            </enumeratedValues>
                        </field>
                        <field>
                            <name>WUE</name>
                            <description>Wakeup Function Enable</description>
                            <lsb>7</lsb>
                            <msb>7</msb>
                            <access>read-write</access>
                            <enumeratedValues>
                                <enumeratedValue>
                                    <name>0</name>
                                    <description>Disable wakeup function</description>
                                    <value>#0</value>
                                </enumeratedValue>
                                <enumeratedValue>
                                    <name>1</name>
                                    <description>Enable wakeup function</description>
                                    <value>#1</value>
                                </enumeratedValue>
                            </enumeratedValues>
                        </field>
                    </fields>
                </register>
                <register>
                    <name>ICWUR2</name>
                    <description>I2C Bus Wakeup Unit Register 2</description>
                    <addressOffset>0x03</addressOffset>
                    <size>8</size>
                    <access>read-write</access>
                    <resetValue>0xfd</resetValue>
                    <resetMask>0xff</resetMask>
                    <fields>
                        <field>
                            <name>WUSEN</name>
                            <description>Wakeup Function Synchronous Enable</description>
                            <lsb>0</lsb>
                            <msb>0</msb>
                            <access>read-write</access>
                            <enumeratedValues>
                                <enumeratedValue>
                                    <name>0</name>
                                    <description>IIC asynchronous circuit enable</description>
                                    <value>#0</value>
                                </enumeratedValue>
                                <enumeratedValue>
                                    <name>1</name>
                                    <description>IIC synchronous circuit enable</description>
                                    <value>#1</value>
                                </enumeratedValue>
                            </enumeratedValues>
                        </field>
                        <field>
                            <name>WUASYF</name>
                            <description>Wakeup Function Asynchronous Operation Status Flag</description>
                            <lsb>1</lsb>
                            <msb>1</msb>
                            <access>read-only</access>
                            <enumeratedValues>
                                <enumeratedValue>
                                    <name>0</name>
                                    <description>IIC synchronous circuit enable condition</description>
                                    <value>#0</value>
                                </enumeratedValue>
                                <enumeratedValue>
                                    <name>1</name>
                                    <description>IIC asynchronous circuit enable condition</description>
                                    <value>#1</value>
                                </enumeratedValue>
                            </enumeratedValues>
                        </field>
                        <field>
                            <name>WUSYF</name>
                            <description>Wakeup Function Synchronous Operation Status Flag</description>
                            <lsb>2</lsb>
                            <msb>2</msb>
                            <access>read-only</access>
                            <enumeratedValues>
                                <enumeratedValue>
                                    <name>0</name>
                                    <description>IIC asynchronous circuit enable condition</description>
                                    <value>#0</value>
                                </enumeratedValue>
                                <enumeratedValue>
                                    <name>1</name>
                                    <description>IIC synchronous circuit enable condition</description>
                                    <value>#1</value>
                                </enumeratedValue>
                            </enumeratedValues>
                        </field>
                    </fields>
                </register>
            </registers>
        </peripheral>
        <peripheral derivedFrom="IIC0_NS">
            <name>IIC1_NS</name>
            <description>Inter-Integrated Circuit 1</description>
            <baseAddress>0x5025E100</baseAddress>
        </peripheral>
        <peripheral>
            <name>OSPI0_B_NS</name>
            <description>Octa Serial Peripheral Interface 0</description>
            <baseAddress>0x50268000</baseAddress>
            <addressBlock>
                <offset>0x00</offset>
                <size>56</size>
                <usage>registers</usage>
            </addressBlock>
            <addressBlock>
                <offset>0x50</offset>
                <size>8</size>
                <usage>registers</usage>
            </addressBlock>
            <addressBlock>
                <offset>0x60</offset>
                <size>28</size>
                <usage>registers</usage>
            </addressBlock>
            <addressBlock>
                <offset>0x80</offset>
                <size>76</size>
                <usage>registers</usage>
            </addressBlock>
            <addressBlock>
                <offset>0x100</offset>
                <size>12</size>
                <usage>registers</usage>
            </addressBlock>
            <addressBlock>
                <offset>0x130</offset>
                <size>108</size>
                <usage>registers</usage>
            </addressBlock>
            <registers>
                <register>
                    <name>WRAPCFG</name>
                    <description>OSPI Wrapper Configuration Register</description>
                    <addressOffset>0x000</addressOffset>
                    <size>32</size>
                    <access>read-write</access>
                    <resetValue>0x00000000</resetValue>
                    <resetMask>0xffffffff</resetMask>
                    <fields>
                        <field>
                            <name>DSSFTCS0</name>
                            <description>OM_DQS shift for slave0</description>
                            <lsb>8</lsb>
                            <msb>12</msb>
                            <access>read-write</access>
                        </field>
                        <field>
                            <name>DSSFTCS1</name>
                            <description>OM_DQS shift for slave1</description>
                            <lsb>24</lsb>
                            <msb>28</msb>
                            <access>read-write</access>
                        </field>
                    </fields>
                </register>
                <register>
                    <name>COMCFG</name>
                    <description>OSPI Common Configuration Register</description>
                    <addressOffset>0x004</addressOffset>
                    <size>32</size>
                    <access>read-write</access>
                    <resetValue>0x00000000</resetValue>
                    <resetMask>0xffffffff</resetMask>
                    <fields>
                        <field>
                            <name>ARBMD</name>
                            <description>Channel arbitration mode</description>
                            <lsb>0</lsb>
                            <msb>1</msb>
                            <access>read-write</access>
                            <enumeratedValues>
                                <enumeratedValue>
                                    <name>00</name>
                                    <description>Round-Robbin (ch0-ch1-ch0-ch1…)</description>
                                    <value>#00</value>
                                </enumeratedValue>
                                <enumeratedValue>
                                    <name>01</name>
                                    <description>Always ch0 win</description>
                                    <value>#01</value>
                                </enumeratedValue>
                                <enumeratedValue>
                                    <name>10</name>
                                    <description>Always ch1 win</description>
                                    <value>#10</value>
                                </enumeratedValue>
                                <enumeratedValue>
                                    <name>11</name>
                                    <description>Reserved</description>
                                    <value>#11</value>
                                </enumeratedValue>
                            </enumeratedValues>
                        </field>
                        <field>
                            <name>OEASTEX</name>
                            <description>Output Enable Asserting extension</description>
                            <lsb>16</lsb>
                            <msb>16</msb>
                            <access>read-write</access>
                            <enumeratedValues>
                                <enumeratedValue>
                                    <name>0</name>
                                    <description>No extend 1 cycle Output enable</description>
                                    <value>#0</value>
                                </enumeratedValue>
                                <enumeratedValue>
                                    <name>1</name>
                                    <description>Extend 1 cycle Output enable</description>
                                    <value>#1</value>
                                </enumeratedValue>
                            </enumeratedValues>
                        </field>
                        <field>
                            <name>OENEGEX</name>
                            <description>Output Enable Negating extension</description>
                            <lsb>17</lsb>
                            <msb>17</msb>
                            <access>read-write</access>
                            <enumeratedValues>
                                <enumeratedValue>
                                    <name>0</name>
                                    <description>No extend 1 cycle Output enable</description>
                                    <value>#0</value>
                                </enumeratedValue>
                                <enumeratedValue>
                                    <name>1</name>
                                    <description>Extend 1 cycle Output enable</description>
                                    <value>#1</value>
                                </enumeratedValue>
                            </enumeratedValues>
                        </field>
                    </fields>
                </register>
                <register>
                    <dim>2</dim>
                    <dimIncrement>0x004</dimIncrement>
                    <dimIndex>0-1</dimIndex>
                    <name>BMCFGCH%s</name>
                    <description>OSPI Bridge Map Configuration Register chn (n = 0, 1)</description>
                    <addressOffset>0x008</addressOffset>
                    <size>32</size>
                    <access>read-write</access>
                    <resetValue>0x00000000</resetValue>
                    <resetMask>0xffffffff</resetMask>
                    <fields>
                        <field>
                            <name>WRMD</name>
                            <description>System bus Write Response mode</description>
                            <lsb>0</lsb>
                            <msb>0</msb>
                            <access>read-write</access>
                            <enumeratedValues>
                                <enumeratedValue>
                                    <name>0</name>
                                    <description>Return response after storing to Internal Write Buffer</description>
                                    <value>#0</value>
                                </enumeratedValue>
                                <enumeratedValue>
                                    <name>1</name>
                                    <description>Return response after issuing write transaction to xSPI bus</description>
                                    <value>#1</value>
                                </enumeratedValue>
                            </enumeratedValues>
                        </field>
                        <field>
                            <name>MWRCOMB</name>
                            <description>Memory Write Combination mode</description>
                            <lsb>7</lsb>
                            <msb>7</msb>
                            <access>read-write</access>
                            <enumeratedValues>
                                <enumeratedValue>
                                    <name>0</name>
                                    <description>Disable combination mode</description>
                                    <value>#0</value>
                                </enumeratedValue>
                                <enumeratedValue>
                                    <name>1</name>
                                    <description>Enable combination mode</description>
                                    <value>#1</value>
                                </enumeratedValue>
                            </enumeratedValues>
                        </field>
                        <field>
                            <name>MWRSIZE</name>
                            <description>Memory Write Size</description>
                            <lsb>8</lsb>
                            <msb>15</msb>
                            <access>read-write</access>
                        </field>
                        <field>
                            <name>PREEN</name>
                            <description>Prefetch enable</description>
                            <lsb>16</lsb>
                            <msb>16</msb>
                            <access>read-write</access>
                            <enumeratedValues>
                                <enumeratedValue>
                                    <name>0</name>
                                    <description>Disable prefetch function</description>
                                    <value>#0</value>
                                </enumeratedValue>
                                <enumeratedValue>
                                    <name>1</name>
                                    <description>Enable prefetch function</description>
                                    <value>#1</value>
                                </enumeratedValue>
                            </enumeratedValues>
                        </field>
                        <field>
                            <name>CMBTIM</name>
                            <description>Combination timer</description>
                            <lsb>24</lsb>
                            <msb>31</msb>
                            <access>read-write</access>
                        </field>
                    </fields>
                </register>
                <register>
                    <dim>2</dim>
                    <dimIncrement>0x010</dimIncrement>
                    <dimIndex>0-1</dimIndex>
                    <name>CMCFG0CS%s</name>
                    <description>OSPI Command Map Configuration Register 0 CSn</description>
                    <addressOffset>0x010</addressOffset>
                    <size>32</size>
                    <access>read-write</access>
                    <resetValue>0x00000000</resetValue>
                    <resetMask>0xffffffff</resetMask>
                    <fields>
                        <field>
                            <name>FFMT</name>
                            <description>Frame format</description>
                            <lsb>0</lsb>
                            <msb>1</msb>
                            <access>read-write</access>
                            <enumeratedValues>
                                <enumeratedValue>
                                    <name>00</name>
                                    <description>Normal format: Command 1 byte, Address ADDSIZE, Data up to system bus transaction. </description>
                                    <value>#00</value>
                                </enumeratedValue>
                                <enumeratedValue>
                                    <name>01</name>
                                    <description>8D-8D-8D profile 1.0 format: Command 2 bytes, Address ADDSIZE, Data up to system bus transaction </description>
                                    <value>#01</value>
                                </enumeratedValue>
                                <enumeratedValue>
                                    <name>10</name>
                                    <description>8D-8D-8D profile 2.0 Command Modifier format: Command &amp; Modifier 6 bytes, Data up to system bus transaction </description>
                                    <value>#10</value>
                                </enumeratedValue>
                                <enumeratedValue>
                                    <name>11</name>
                                    <description>8D-8D-8D profile 2.0 Commands with Extended Command Modifier format: Command &amp; Modifier 6 bytes, Data up to system bus transaction </description>
                                    <value>#11</value>
                                </enumeratedValue>
                            </enumeratedValues>
                        </field>
                        <field>
                            <name>ADDSIZE</name>
                            <description>Address size</description>
                            <lsb>2</lsb>
                            <msb>3</msb>
                            <access>read-write</access>
                            <enumeratedValues>
                                <enumeratedValue>
                                    <name>00</name>
                                    <description>1 byte (256-byte address space)</description>
                                    <value>#00</value>
                                </enumeratedValue>
                                <enumeratedValue>
                                    <name>01</name>
                                    <description>2 bytes (64 KB address space)</description>
                                    <value>#01</value>
                                </enumeratedValue>
                                <enumeratedValue>
                                    <name>10</name>
                                    <description>3 bytes (16 MB address space)</description>
                                    <value>#10</value>
                                </enumeratedValue>
                                <enumeratedValue>
                                    <name>11</name>
                                    <description>4 bytes (4 GB address space)</description>
                                    <value>#11</value>
                                </enumeratedValue>
                            </enumeratedValues>
                        </field>
                        <field>
                            <name>WPBSTMD</name>
                            <description>Wrapping burst mode</description>
                            <lsb>4</lsb>
                            <msb>4</msb>
                            <access>read-write</access>
                            <enumeratedValues>
                                <enumeratedValue>
                                    <name>0</name>
                                    <description>Separate xSPI transfer at the wrapping address boundary</description>
                                    <value>#0</value>
                                </enumeratedValue>
                                <enumeratedValue>
                                    <name>1</name>
                                    <description>Not separate xSPI transfer at the wrapping address boundary</description>
                                    <value>#1</value>
                                </enumeratedValue>
                            </enumeratedValues>
                        </field>
                        <field>
                            <name>ARYAMD</name>
                            <description>Array address mode</description>
                            <lsb>5</lsb>
                            <msb>5</msb>
                            <access>read-write</access>
                            <enumeratedValues>
                                <enumeratedValue>
                                    <name>0</name>
                                    <description>Normal address mode</description>
                                    <value>#0</value>
                                </enumeratedValue>
                                <enumeratedValue>
                                    <name>1</name>
                                    <description>Array address mode </description>
                                    <value>#1</value>
                                </enumeratedValue>
                            </enumeratedValues>
                        </field>
                        <field>
                            <name>ADDRPEN</name>
                            <description>Address Replace Enable</description>
                            <lsb>16</lsb>
                            <msb>23</msb>
                            <access>read-write</access>
                            <enumeratedValues>
                                <enumeratedValue>
                                    <name>0</name>
                                    <description>No replacement (xSPI frame address field is same as System bus address)</description>
                                    <value>#0</value>
                                </enumeratedValue>
                                <enumeratedValue>
                                    <name>1</name>
                                    <description>Replacement</description>
                                    <value>#1</value>
                                </enumeratedValue>
                            </enumeratedValues>
                        </field>
                        <field>
                            <name>ADDRPCD</name>
                            <description>Address Replace Code</description>
                            <lsb>24</lsb>
                            <msb>31</msb>
                            <access>read-write</access>
                        </field>
                    </fields>
                </register>
                <register>
                    <dim>2</dim>
                    <dimIncrement>0x010</dimIncrement>
                    <dimIndex>0-1</dimIndex>
                    <name>CMCFG1CS%s</name>
                    <description>OSPI Command Map Configuration Register 1 CSn</description>
                    <addressOffset>0x014</addressOffset>
                    <size>32</size>
                    <access>read-write</access>
                    <resetValue>0x00080000</resetValue>
                    <resetMask>0xffffffff</resetMask>
                    <fields>
                        <field>
                            <name>RDCMD</name>
                            <description>Read command</description>
                            <lsb>0</lsb>
                            <msb>15</msb>
                            <access>read-write</access>
                        </field>
                        <field>
                            <name>RDLATE</name>
                            <description>Read latency cycle</description>
                            <lsb>16</lsb>
                            <msb>20</msb>
                            <access>read-write</access>
                        </field>
                    </fields>
                </register>
                <register>
                    <dim>2</dim>
                    <dimIncrement>0x010</dimIncrement>
                    <dimIndex>0-1</dimIndex>
                    <name>CMCFG2CS%s</name>
                    <description>OSPI Command Map Configuration Register 2 CSn</description>
                    <addressOffset>0x018</addressOffset>
                    <size>32</size>
                    <access>read-write</access>
                    <resetValue>0x00080000</resetValue>
                    <resetMask>0xffffffff</resetMask>
                    <fields>
                        <field>
                            <name>WRCMD</name>
                            <description>Write command</description>
                            <lsb>0</lsb>
                            <msb>15</msb>
                            <access>read-write</access>
                        </field>
                        <field>
                            <name>WRLATE</name>
                            <description>Write latency cycle</description>
                            <lsb>16</lsb>
                            <msb>20</msb>
                            <access>read-write</access>
                        </field>
                    </fields>
                </register>
                <register>
                    <dim>2</dim>
                    <dimIncrement>0x004</dimIncrement>
                    <dimIndex>0-1</dimIndex>
                    <name>LIOCFGCS%s</name>
                    <description>OSPI Link I/O Configuration Register CSn</description>
                    <addressOffset>0x050</addressOffset>
                    <size>32</size>
                    <access>read-write</access>
                    <resetValue>0x00070000</resetValue>
                    <resetMask>0xffffffff</resetMask>
                    <fields>
                        <field>
                            <name>PRTMD</name>
                            <description>Protocol mode</description>
                            <lsb>0</lsb>
                            <msb>9</msb>
                            <access>read-write</access>
                            <enumeratedValues>
                                <enumeratedValue>
                                    <name>0x000</name>
                                    <description>1S-1S-1S</description>
                                    <value>0x000</value>
                                </enumeratedValue>
                                <enumeratedValue>
                                    <name>0x3B2</name>
                                    <description>4S-4D-4D</description>
                                    <value>0x3b2</value>
                                </enumeratedValue>
                                <enumeratedValue>
                                    <name>0x3FF</name>
                                    <description>8D-8D-8D</description>
                                    <value>0x3ff</value>
                                </enumeratedValue>
                                <enumeratedValue>
                                    <name>0x048</name>
                                    <description>1S-2S-2S</description>
                                    <value>0x048</value>
                                </enumeratedValue>
                                <enumeratedValue>
                                    <name>0x049</name>
                                    <description>2S-2S-2S</description>
                                    <value>0x049</value>
                                </enumeratedValue>
                                <enumeratedValue>
                                    <name>0x090</name>
                                    <description>1S-4S-4S</description>
                                    <value>0x090</value>
                                </enumeratedValue>
                                <enumeratedValue>
                                    <name>0x092</name>
                                    <description>4S-4S-4S</description>
                                    <value>0x092</value>
                                </enumeratedValue>
                                <enumeratedValue>
                                    <name>Others</name>
                                    <description>Setting prohibited</description>
                                    <isDefault>true</isDefault>
                                </enumeratedValue>
                            </enumeratedValues>
                        </field>
                        <field>
                            <name>LATEMD</name>
                            <description>Latency mode</description>
                            <lsb>10</lsb>
                            <msb>10</msb>
                            <access>read-write</access>
                        </field>
                        <field>
                            <name>WRMSKMD</name>
                            <description>Write mask mode</description>
                            <lsb>11</lsb>
                            <msb>11</msb>
                            <access>read-write</access>
                            <enumeratedValues>
                                <enumeratedValue>
                                    <name>0</name>
                                    <description>Write mask disable</description>
                                    <value>#0</value>
                                </enumeratedValue>
                                <enumeratedValue>
                                    <name>1</name>
                                    <description>Write mask enable</description>
                                    <value>#1</value>
                                </enumeratedValue>
                            </enumeratedValues>
                        </field>
                        <field>
                            <name>CSMIN</name>
                            <description>CS minimum idle term</description>
                            <lsb>16</lsb>
                            <msb>19</msb>
                            <access>read-write</access>
                        </field>
                        <field>
                            <name>CSASTEX</name>
                            <description>CS asserting extension</description>
                            <lsb>20</lsb>
                            <msb>20</msb>
                            <access>read-write</access>
                            <enumeratedValues>
                                <enumeratedValue>
                                    <name>0</name>
                                    <description>No extension</description>
                                    <value>#0</value>
                                </enumeratedValue>
                                <enumeratedValue>
                                    <name>1</name>
                                    <description>Extend 1 cycle</description>
                                    <value>#1</value>
                                </enumeratedValue>
                            </enumeratedValues>
                        </field>
                        <field>
                            <name>CSNEGEX</name>
                            <description>CS negating extension</description>
                            <lsb>21</lsb>
                            <msb>21</msb>
                            <access>read-write</access>
                            <enumeratedValues>
                                <enumeratedValue>
                                    <name>0</name>
                                    <description>No extension</description>
                                    <value>#0</value>
                                </enumeratedValue>
                                <enumeratedValue>
                                    <name>1</name>
                                    <description>Extend 1 cycle</description>
                                    <value>#1</value>
                                </enumeratedValue>
                            </enumeratedValues>
                        </field>
                        <field>
                            <name>SDRDRV</name>
                            <description>SDR driving timing</description>
                            <lsb>22</lsb>
                            <msb>22</msb>
                            <access>read-write</access>
                            <enumeratedValues>
                                <enumeratedValue>
                                    <name>0</name>
                                    <description>Drive at 1/2 cycle before CK rising-edge</description>
                                    <value>#0</value>
                                </enumeratedValue>
                                <enumeratedValue>
                                    <name>1</name>
                                    <description>Drive at CK rising-edge</description>
                                    <value>#1</value>
                                </enumeratedValue>
                            </enumeratedValues>
                        </field>
                        <field>
                            <name>SDRSMPMD</name>
                            <description>SDR Sampling mode</description>
                            <lsb>23</lsb>
                            <msb>23</msb>
                            <access>read-write</access>
                            <enumeratedValues>
                                <enumeratedValue>
                                    <name>0</name>
                                    <description>Samples data input at falling-edge</description>
                                    <value>#0</value>
                                </enumeratedValue>
                                <enumeratedValue>
                                    <name>1</name>
                                    <description>Samples data input at rising-edge</description>
                                    <value>#1</value>
                                </enumeratedValue>
                            </enumeratedValues>
                        </field>
                        <field>
                            <name>SDRSMPSFT</name>
                            <description>SDR Sampling window shift</description>
                            <lsb>24</lsb>
                            <msb>27</msb>
                            <access>read-write</access>
                        </field>
                        <field>
                            <name>DDRSMPEX</name>
                            <description>DDR sampling window extend</description>
                            <lsb>28</lsb>
                            <msb>31</msb>
                            <access>read-write</access>
                        </field>
                    </fields>
                </register>
                <register>
                    <name>BMCTL0</name>
                    <description>OSPI Bridge Map Control Register 0</description>
                    <addressOffset>0x060</addressOffset>
                    <size>32</size>
                    <access>read-write</access>
                    <resetValue>0x000000ff</resetValue>
                    <resetMask>0xffffffff</resetMask>
                    <fields>
                        <field>
                            <name>CH0CS0ACC</name>
                            <description>System bus ch0 to slave0 memory area access enable</description>
                            <lsb>0</lsb>
                            <msb>1</msb>
                            <access>read-write</access>
                            <enumeratedValues>
                                <enumeratedValue>
                                    <name>00</name>
                                    <description>Read/Write disable</description>
                                    <value>#00</value>
                                </enumeratedValue>
                                <enumeratedValue>
                                    <name>01</name>
                                    <description>Read enable, Write disable</description>
                                    <value>#01</value>
                                </enumeratedValue>
                                <enumeratedValue>
                                    <name>10</name>
                                    <description>Read disable, Write enable</description>
                                    <value>#10</value>
                                </enumeratedValue>
                                <enumeratedValue>
                                    <name>11</name>
                                    <description>Read/Write enable</description>
                                    <value>#11</value>
                                </enumeratedValue>
                            </enumeratedValues>
                        </field>
                        <field>
                            <name>CH0CS1ACC</name>
                            <description>System bus ch0 to slave1 memory area access enable</description>
                            <lsb>2</lsb>
                            <msb>3</msb>
                            <access>read-write</access>
                            <enumeratedValues>
                                <enumeratedValue>
                                    <name>00</name>
                                    <description>Read/Write disable</description>
                                    <value>#00</value>
                                </enumeratedValue>
                                <enumeratedValue>
                                    <name>01</name>
                                    <description>Read enable, Write disable</description>
                                    <value>#01</value>
                                </enumeratedValue>
                                <enumeratedValue>
                                    <name>10</name>
                                    <description>Read disable, Write enable</description>
                                    <value>#10</value>
                                </enumeratedValue>
                                <enumeratedValue>
                                    <name>11</name>
                                    <description>Read/Write enable</description>
                                    <value>#11</value>
                                </enumeratedValue>
                            </enumeratedValues>
                        </field>
                        <field>
                            <name>CH1CS0ACC</name>
                            <description>System bus ch1 to slave0 memory area access enable</description>
                            <lsb>4</lsb>
                            <msb>5</msb>
                            <access>read-write</access>
                            <enumeratedValues>
                                <enumeratedValue>
                                    <name>00</name>
                                    <description>Read/Write disable</description>
                                    <value>#00</value>
                                </enumeratedValue>
                                <enumeratedValue>
                                    <name>01</name>
                                    <description>Read enable, Write disable</description>
                                    <value>#01</value>
                                </enumeratedValue>
                                <enumeratedValue>
                                    <name>10</name>
                                    <description>Read disable, Write enable</description>
                                    <value>#10</value>
                                </enumeratedValue>
                                <enumeratedValue>
                                    <name>11</name>
                                    <description>Read/Write enable</description>
                                    <value>#11</value>
                                </enumeratedValue>
                            </enumeratedValues>
                        </field>
                        <field>
                            <name>CH1CS1ACC</name>
                            <description>System bus ch1 to slave1 memory area access enable</description>
                            <lsb>6</lsb>
                            <msb>7</msb>
                            <access>read-write</access>
                            <enumeratedValues>
                                <enumeratedValue>
                                    <name>00</name>
                                    <description>Read/Write disable</description>
                                    <value>#00</value>
                                </enumeratedValue>
                                <enumeratedValue>
                                    <name>01</name>
                                    <description>Read enable, Write disable</description>
                                    <value>#01</value>
                                </enumeratedValue>
                                <enumeratedValue>
                                    <name>10</name>
                                    <description>Read disable, Write enable</description>
                                    <value>#10</value>
                                </enumeratedValue>
                                <enumeratedValue>
                                    <name>11</name>
                                    <description>Read/Write enable</description>
                                    <value>#11</value>
                                </enumeratedValue>
                            </enumeratedValues>
                        </field>
                    </fields>
                </register>
                <register>
                    <name>BMCTL1</name>
                    <description>OSPI Bridge Map Control Register 1</description>
                    <addressOffset>0x064</addressOffset>
                    <size>32</size>
                    <access>write-only</access>
                    <resetValue>0x00000000</resetValue>
                    <resetMask>0xffffffff</resetMask>
                    <fields>
                        <field>
                            <name>MWRPUSHCH0</name>
                            <description>Memory Write Data Push for ch0</description>
                            <lsb>8</lsb>
                            <msb>8</msb>
                            <access>write-only</access>
                            <enumeratedValues>
                                <enumeratedValue>
                                    <name>0</name>
                                    <description>No command</description>
                                    <value>#0</value>
                                </enumeratedValue>
                                <enumeratedValue>
                                    <name>1</name>
                                    <description>Push request</description>
                                    <value>#1</value>
                                </enumeratedValue>
                            </enumeratedValues>
                        </field>
                        <field>
                            <name>MWRPUSHCH1</name>
                            <description>Memory Write Data Push for ch1</description>
                            <lsb>9</lsb>
                            <msb>9</msb>
                            <access>write-only</access>
                        </field>
                        <field>
                            <name>PBUFCLRCH0</name>
                            <description>Prefetch Buffer clear for ch0</description>
                            <lsb>10</lsb>
                            <msb>10</msb>
                            <access>write-only</access>
                            <enumeratedValues>
                                <enumeratedValue>
                                    <name>0</name>
                                    <description>No command</description>
                                    <value>#0</value>
                                </enumeratedValue>
                                <enumeratedValue>
                                    <name>1</name>
                                    <description>Clear request</description>
                                    <value>#1</value>
                                </enumeratedValue>
                            </enumeratedValues>
                        </field>
                        <field>
                            <name>PBUFCLRCH1</name>
                            <description>Prefetch Buffer clear for ch1</description>
                            <lsb>11</lsb>
                            <msb>11</msb>
                            <access>write-only</access>
                        </field>
                    </fields>
                </register>
                <register>
                    <dim>2</dim>
                    <dimIncrement>0x004</dimIncrement>
                    <dimIndex>0-1</dimIndex>
                    <name>CMCTLCH%s</name>
                    <description>OSPI Command Map Control register chn (n = 0, 1)</description>
                    <addressOffset>0x0068</addressOffset>
                    <size>32</size>
                    <access>read-write</access>
                    <resetValue>0x00000000</resetValue>
                    <resetMask>0xffffffff</resetMask>
                    <fields>
                        <field>
                            <name>XIPENCODE</name>
                            <description>XiP mode enter code</description>
                            <lsb>0</lsb>
                            <msb>7</msb>
                            <access>read-write</access>
                        </field>
                        <field>
                            <name>XIPEXCODE</name>
                            <description>XiP mode exit code</description>
                            <lsb>8</lsb>
                            <msb>15</msb>
                            <access>read-write</access>
                        </field>
                        <field>
                            <name>XIPEN</name>
                            <description>XiP mode enable</description>
                            <lsb>16</lsb>
                            <msb>16</msb>
                            <access>read-write</access>
                            <enumeratedValues>
                                <enumeratedValue>
                                    <name>0</name>
                                    <description>Disable XiP mode</description>
                                    <value>#0</value>
                                </enumeratedValue>
                                <enumeratedValue>
                                    <name>1</name>
                                    <description>Enable XiP mode</description>
                                    <value>#1</value>
                                </enumeratedValue>
                            </enumeratedValues>
                        </field>
                    </fields>
                </register>
                <register>
                    <name>CDCTL0</name>
                    <description>OSPI Command Manual Control Register 0</description>
                    <addressOffset>0x070</addressOffset>
                    <size>32</size>
                    <access>read-write</access>
                    <resetValue>0x00000000</resetValue>
                    <resetMask>0xffffffff</resetMask>
                    <fields>
                        <field>
                            <name>TRREQ</name>
                            <description>Transaction request</description>
                            <lsb>0</lsb>
                            <msb>0</msb>
                            <access>read-write</access>
                            <enumeratedValues>
                                <enumeratedValue>
                                    <name>0</name>
                                    <description>No transaction</description>
                                    <value>#0</value>
                                </enumeratedValue>
                                <enumeratedValue>
                                    <name>1</name>
                                    <description>Request transaction</description>
                                    <value>#1</value>
                                </enumeratedValue>
                            </enumeratedValues>
                        </field>
                        <field>
                            <name>PERMD</name>
                            <description>Periodic mode</description>
                            <lsb>1</lsb>
                            <msb>1</msb>
                            <access>read-write</access>
                            <enumeratedValues>
                                <enumeratedValue>
                                    <name>0</name>
                                    <description>Direct manual-command mode</description>
                                    <value>#0</value>
                                </enumeratedValue>
                                <enumeratedValue>
                                    <name>1</name>
                                    <description>Periodic manual-command mode</description>
                                    <value>#1</value>
                                </enumeratedValue>
                            </enumeratedValues>
                        </field>
                        <field>
                            <name>CSSEL</name>
                            <description>Chip select</description>
                            <lsb>3</lsb>
                            <msb>3</msb>
                            <access>read-write</access>
                            <enumeratedValues>
                                <enumeratedValue>
                                    <name>0</name>
                                    <description>CS0</description>
                                    <value>#0</value>
                                </enumeratedValue>
                                <enumeratedValue>
                                    <name>1</name>
                                    <description>CS1</description>
                                    <value>#1</value>
                                </enumeratedValue>
                            </enumeratedValues>
                        </field>
                        <field>
                            <name>TRNUM</name>
                            <description>Transaction number</description>
                            <lsb>4</lsb>
                            <msb>5</msb>
                            <access>read-write</access>
                            <enumeratedValues>
                                <enumeratedValue>
                                    <name>00</name>
                                    <description>Issue 1 command (using command buffer 0)</description>
                                    <value>#00</value>
                                </enumeratedValue>
                                <enumeratedValue>
                                    <name>01</name>
                                    <description>Issue 2 commands (using command buffer 0-1)</description>
                                    <value>#01</value>
                                </enumeratedValue>
                                <enumeratedValue>
                                    <name>10</name>
                                    <description>Issue 3 commands (using command buffer 0-2)</description>
                                    <value>#10</value>
                                </enumeratedValue>
                                <enumeratedValue>
                                    <name>11</name>
                                    <description>Issue 4 commands (using command buffer 0-3)</description>
                                    <value>#11</value>
                                </enumeratedValue>
                            </enumeratedValues>
                        </field>
                        <field>
                            <name>PERITV</name>
                            <description>Periodic transaction interval</description>
                            <lsb>16</lsb>
                            <msb>20</msb>
                            <access>read-write</access>
                        </field>
                        <field>
                            <name>PERREP</name>
                            <description>Periodic transaction repeat</description>
                            <lsb>24</lsb>
                            <msb>27</msb>
                            <access>read-write</access>
                        </field>
                    </fields>
                </register>
                <register>
                    <name>CDCTL1</name>
                    <description>OSPI Command Manual Control Register 1</description>
                    <addressOffset>0x074</addressOffset>
                    <size>32</size>
                    <access>read-write</access>
                    <resetValue>0x00000000</resetValue>
                    <resetMask>0xffffffff</resetMask>
                    <fields>
                        <field>
                            <name>PEREXP</name>
                            <description>Periodic transaction expected value</description>
                            <lsb>0</lsb>
                            <msb>31</msb>
                            <access>read-write</access>
                        </field>
                    </fields>
                </register>
                <register>
                    <name>CDCTL2</name>
                    <description>OSPI Command Manual Control Register 2</description>
                    <addressOffset>0x078</addressOffset>
                    <size>32</size>
                    <access>read-write</access>
                    <resetValue>0x00000000</resetValue>
                    <resetMask>0xffffffff</resetMask>
                    <fields>
                        <field>
                            <name>PERMSK</name>
                            <description>Periodic transaction masked value</description>
                            <lsb>0</lsb>
                            <msb>31</msb>
                            <access>read-write</access>
                        </field>
                    </fields>
                </register>
                <register>
                    <dim>4</dim>
                    <dimIncrement>0x010</dimIncrement>
                    <dimIndex>0-3</dimIndex>
                    <name>CDTBUF%s</name>
                    <description>OSPI Command Manual Type Buf %s</description>
                    <addressOffset>0x080</addressOffset>
                    <size>32</size>
                    <access>read-write</access>
                    <resetValue>0x00000000</resetValue>
                    <resetMask>0xffffffff</resetMask>
                    <fields>
                        <field>
                            <name>CMDSIZE</name>
                            <description>Command Size</description>
                            <lsb>0</lsb>
                            <msb>1</msb>
                            <access>read-write</access>
                            <enumeratedValues>
                                <enumeratedValue>
                                    <name>00</name>
                                    <description>0 bytes (No command phase)</description>
                                    <value>#00</value>
                                </enumeratedValue>
                                <enumeratedValue>
                                    <name>01</name>
                                    <description>1 byte</description>
                                    <value>#01</value>
                                </enumeratedValue>
                                <enumeratedValue>
                                    <name>10</name>
                                    <description>2 bytes</description>
                                    <value>#10</value>
                                </enumeratedValue>
                                <enumeratedValue>
                                    <name>Others</name>
                                    <description>Setting prohibited</description>
                                    <isDefault>true</isDefault>
                                </enumeratedValue>
                            </enumeratedValues>
                        </field>
                        <field>
                            <name>ADDSIZE</name>
                            <description>Address size</description>
                            <lsb>2</lsb>
                            <msb>4</msb>
                            <access>read-write</access>
                            <enumeratedValues>
                                <enumeratedValue>
                                    <name>000</name>
                                    <description>0 bytes (No address phase) </description>
                                    <value>#000</value>
                                </enumeratedValue>
                                <enumeratedValue>
                                    <name>001</name>
                                    <description>1 byte </description>
                                    <value>#001</value>
                                </enumeratedValue>
                                <enumeratedValue>
                                    <name>010</name>
                                    <description>2 bytes </description>
                                    <value>#010</value>
                                </enumeratedValue>
                                <enumeratedValue>
                                    <name>011</name>
                                    <description>3 bytes </description>
                                    <value>#011</value>
                                </enumeratedValue>
                                <enumeratedValue>
                                    <name>100</name>
                                    <description>4 bytes </description>
                                    <value>#100</value>
                                </enumeratedValue>
                                <enumeratedValue>
                                    <name>Others</name>
                                    <description>Setting prohibited </description>
                                    <isDefault>true</isDefault>
                                </enumeratedValue>
                            </enumeratedValues>
                        </field>
                        <field>
                            <name>DATASIZE</name>
                            <description>Write/Read Data Size</description>
                            <lsb>5</lsb>
                            <msb>8</msb>
                            <access>read-write</access>
                        </field>
                        <field>
                            <name>LATE</name>
                            <description>Latency cycle</description>
                            <lsb>9</lsb>
                            <msb>13</msb>
                            <access>read-write</access>
                        </field>
                        <field>
                            <name>TRTYPE</name>
                            <description>Transaction Type</description>
                            <lsb>15</lsb>
                            <msb>15</msb>
                            <access>read-write</access>
                            <enumeratedValues>
                                <enumeratedValue>
                                    <name>0</name>
                                    <description>Read transaction (Readout data from slave device)</description>
                                    <value>#0</value>
                                </enumeratedValue>
                                <enumeratedValue>
                                    <name>1</name>
                                    <description>Not read transaction</description>
                                    <value>#1</value>
                                </enumeratedValue>
                            </enumeratedValues>
                        </field>
                        <field>
                            <name>CMD</name>
                            <description>Command (1-2 bytes)</description>
                            <lsb>16</lsb>
                            <msb>31</msb>
                            <access>read-write</access>
                        </field>
                    </fields>
                </register>
                <register>
                    <dim>4</dim>
                    <dimIncrement>0x10</dimIncrement>
                    <dimIndex>0-3</dimIndex>
                    <name>CDABUF%s</name>
                    <description>OSPI Command Manual Address Buf %s</description>
                    <addressOffset>0x084</addressOffset>
                    <size>32</size>
                    <access>read-write</access>
                    <resetValue>0x00000000</resetValue>
                    <resetMask>0xffffffff</resetMask>
                    <fields>
                        <field>
                            <name>ADD</name>
                            <description>Address</description>
                            <lsb>0</lsb>
                            <msb>31</msb>
                            <access>read-write</access>
                        </field>
                    </fields>
                </register>
                <register>
                    <dim>4</dim>
                    <dimIncrement>0x10</dimIncrement>
                    <dimIndex>0-3</dimIndex>
                    <name>CDD0BUF%s</name>
                    <description>OSPI Command Manual Data 0 Buf %s</description>
                    <addressOffset>0x088</addressOffset>
                    <size>32</size>
                    <access>read-write</access>
                    <resetValue>0x00000000</resetValue>
                    <resetMask>0xffffffff</resetMask>
                    <fields>
                        <field>
                            <name>DATA</name>
                            <description>Write/Read Data</description>
                            <lsb>0</lsb>
                            <msb>31</msb>
                            <access>read-write</access>
                        </field>
                    </fields>
                </register>
                <register>
                    <dim>4</dim>
                    <dimIncrement>0x10</dimIncrement>
                    <dimIndex>0-3</dimIndex>
                    <name>CDD1BUF%s</name>
                    <description>OSPI Command Manual Data 1 Buf %s</description>
                    <addressOffset>0x08C</addressOffset>
                    <size>32</size>
                    <access>read-write</access>
                    <resetValue>0x00000000</resetValue>
                    <resetMask>0xffffffff</resetMask>
                    <fields>
                        <field>
                            <name>DATA</name>
                            <description>Write/Read Data</description>
                            <lsb>0</lsb>
                            <msb>31</msb>
                            <access>read-write</access>
                        </field>
                    </fields>
                </register>
                <register>
                    <name>LPCTL0</name>
                    <description>OSPI Link Pattern Control Register 0</description>
                    <addressOffset>0x100</addressOffset>
                    <size>32</size>
                    <access>read-write</access>
                    <resetValue>0x00000000</resetValue>
                    <resetMask>0xffffffff</resetMask>
                    <fields>
                        <field>
                            <name>PATREQ</name>
                            <description>Pattern request</description>
                            <lsb>0</lsb>
                            <msb>0</msb>
                            <access>read-write</access>
                            <enumeratedValues>
                                <enumeratedValue>
                                    <name>0</name>
                                    <description>No request XiP Disable pattern</description>
                                    <value>#0</value>
                                </enumeratedValue>
                                <enumeratedValue>
                                    <name>1</name>
                                    <description>Request XiP Disable pattern</description>
                                    <value>#1</value>
                                </enumeratedValue>
                            </enumeratedValues>
                        </field>
                        <field>
                            <name>CSSEL</name>
                            <description>Chip select</description>
                            <lsb>3</lsb>
                            <msb>3</msb>
                            <access>read-write</access>
                            <enumeratedValues>
                                <enumeratedValue>
                                    <name>0</name>
                                    <description>slave0 (CS0)</description>
                                    <value>#0</value>
                                </enumeratedValue>
                                <enumeratedValue>
                                    <name>1</name>
                                    <description>slave1 (CS1)</description>
                                    <value>#1</value>
                                </enumeratedValue>
                            </enumeratedValues>
                        </field>
                        <field>
                            <name>XDPIN</name>
                            <description>XiP Disable pattern pin</description>
                            <lsb>4</lsb>
                            <msb>5</msb>
                            <access>read-write</access>
                            <enumeratedValues>
                                <enumeratedValue>
                                    <name>00</name>
                                    <description>1 pin</description>
                                    <value>#00</value>
                                </enumeratedValue>
                                <enumeratedValue>
                                    <name>01</name>
                                    <description>2 pins</description>
                                    <value>#01</value>
                                </enumeratedValue>
                                <enumeratedValue>
                                    <name>10</name>
                                    <description>4 pins</description>
                                    <value>#10</value>
                                </enumeratedValue>
                                <enumeratedValue>
                                    <name>11</name>
                                    <description>8 pins</description>
                                    <value>#11</value>
                                </enumeratedValue>
                            </enumeratedValues>
                        </field>
                        <field>
                            <name>XD1LEN</name>
                            <description>XiP Disable pattern 1st phase length</description>
                            <lsb>16</lsb>
                            <msb>20</msb>
                            <access>read-write</access>
                        </field>
                        <field>
                            <name>XD1VAL</name>
                            <description>XiP Disable pattern 1st phase value</description>
                            <lsb>23</lsb>
                            <msb>23</msb>
                            <access>read-write</access>
                            <enumeratedValues>
                                <enumeratedValue>
                                    <name>0</name>
                                    <description>Low drive</description>
                                    <value>#0</value>
                                </enumeratedValue>
                                <enumeratedValue>
                                    <name>1</name>
                                    <description>High drive</description>
                                    <value>#1</value>
                                </enumeratedValue>
                            </enumeratedValues>
                        </field>
                        <field>
                            <name>XD2LEN</name>
                            <description>XiP Disable pattern 2nd phase length</description>
                            <lsb>24</lsb>
                            <msb>28</msb>
                            <access>read-write</access>
                        </field>
                        <field>
                            <name>XD2VAL</name>
                            <description>XiP Disable pattern 2nd phase value</description>
                            <lsb>31</lsb>
                            <msb>31</msb>
                            <access>read-write</access>
                            <enumeratedValues>
                                <enumeratedValue>
                                    <name>0</name>
                                    <description>Low drive</description>
                                    <value>#0</value>
                                </enumeratedValue>
                                <enumeratedValue>
                                    <name>1</name>
                                    <description>High drive</description>
                                    <value>#1</value>
                                </enumeratedValue>
                            </enumeratedValues>
                        </field>
                    </fields>
                </register>
                <register>
                    <name>LPCTL1</name>
                    <description>OSPI Link Pattern Control Register 1</description>
                    <addressOffset>0x104</addressOffset>
                    <size>32</size>
                    <access>read-write</access>
                    <resetValue>0x00000000</resetValue>
                    <resetMask>0xffffffff</resetMask>
                    <fields>
                        <field>
                            <name>PATREQ</name>
                            <description>Pattern request</description>
                            <lsb>0</lsb>
                            <msb>1</msb>
                            <access>read-write</access>
                            <enumeratedValues>
                                <enumeratedValue>
                                    <name>00</name>
                                    <description>No request </description>
                                    <value>#00</value>
                                </enumeratedValue>
                                <enumeratedValue>
                                    <name>01</name>
                                    <description>Request Reset pattern</description>
                                    <value>#01</value>
                                </enumeratedValue>
                                <enumeratedValue>
                                    <name>10</name>
                                    <description>Request CS only pattern</description>
                                    <value>#10</value>
                                </enumeratedValue>
                                <enumeratedValue>
                                    <name>11</name>
                                    <description>Setting prohibited</description>
                                    <value>#11</value>
                                </enumeratedValue>
                            </enumeratedValues>
                        </field>
                        <field>
                            <name>CSSEL</name>
                            <description>Chip select</description>
                            <lsb>3</lsb>
                            <msb>3</msb>
                            <access>read-write</access>
                            <enumeratedValues>
                                <enumeratedValue>
                                    <name>0</name>
                                    <description>slave0 (CS0)</description>
                                    <value>#0</value>
                                </enumeratedValue>
                                <enumeratedValue>
                                    <name>1</name>
                                    <description>slave1 (CS1)</description>
                                    <value>#1</value>
                                </enumeratedValue>
                            </enumeratedValues>
                        </field>
                        <field>
                            <name>RSTREP</name>
                            <description>Reset pattern repeat</description>
                            <lsb>4</lsb>
                            <msb>5</msb>
                            <access>read-write</access>
                            <enumeratedValues>
                                <enumeratedValue>
                                    <name>00</name>
                                    <description>4 times (Specified on Reset Signaling Protocol)</description>
                                    <value>#00</value>
                                </enumeratedValue>
                                <enumeratedValue>
                                    <name>01</name>
                                    <description>5 times</description>
                                    <value>#01</value>
                                </enumeratedValue>
                                <enumeratedValue>
                                    <name>10</name>
                                    <description>6 times</description>
                                    <value>#10</value>
                                </enumeratedValue>
                                <enumeratedValue>
                                    <name>11</name>
                                    <description>7 times</description>
                                    <value>#11</value>
                                </enumeratedValue>
                            </enumeratedValues>
                        </field>
                        <field>
                            <name>RSTWID</name>
                            <description>Reset pattern width</description>
                            <lsb>8</lsb>
                            <msb>10</msb>
                            <access>read-write</access>
                        </field>
                        <field>
                            <name>RSTSU</name>
                            <description>Reset pattern data output setup time</description>
                            <lsb>12</lsb>
                            <msb>14</msb>
                            <access>read-write</access>
                        </field>
                    </fields>
                </register>
                <register>
                    <name>LIOCTL</name>
                    <description>OSPI Link I/O Control Register</description>
                    <addressOffset>0x108</addressOffset>
                    <size>32</size>
                    <access>read-write</access>
                    <resetValue>0x00030003</resetValue>
                    <resetMask>0xffffffff</resetMask>
                    <fields>
                        <field>
                            <name>WPCS1</name>
                            <description>WP drive for slave1</description>
                            <lsb>1</lsb>
                            <msb>1</msb>
                            <access>read-write</access>
                            <enumeratedValues>
                                <enumeratedValue>
                                    <name>0</name>
                                    <description>Drive Low level</description>
                                    <value>#0</value>
                                </enumeratedValue>
                                <enumeratedValue>
                                    <name>1</name>
                                    <description>Drive High level</description>
                                    <value>#1</value>
                                </enumeratedValue>
                            </enumeratedValues>
                        </field>
                        <field>
                            <name>RSTCS0</name>
                            <description>Reset drive</description>
                            <lsb>16</lsb>
                            <msb>16</msb>
                            <access>read-write</access>
                            <enumeratedValues>
                                <enumeratedValue>
                                    <name>0</name>
                                    <description>Drive Low level</description>
                                    <value>#0</value>
                                </enumeratedValue>
                                <enumeratedValue>
                                    <name>1</name>
                                    <description>Drive High level</description>
                                    <value>#1</value>
                                </enumeratedValue>
                            </enumeratedValues>
                        </field>
                    </fields>
                </register>
                <register>
                    <dim>2</dim>
                    <dimIncrement>0x020</dimIncrement>
                    <dimIndex>0-1</dimIndex>
                    <name>CCCTL0CS%s</name>
                    <description>OSPI Command Calibration Control Register 0 CSn</description>
                    <addressOffset>0x130</addressOffset>
                    <size>32</size>
                    <access>read-write</access>
                    <resetValue>0x1f000000</resetValue>
                    <resetMask>0xffffffff</resetMask>
                    <fields>
                        <field>
                            <name>CAEN</name>
                            <description>Automatic Calibration Enable</description>
                            <lsb>0</lsb>
                            <msb>0</msb>
                            <access>read-write</access>
                            <enumeratedValues>
                                <enumeratedValue>
                                    <name>0</name>
                                    <description>Disable automatic calibration</description>
                                    <value>#0</value>
                                </enumeratedValue>
                                <enumeratedValue>
                                    <name>1</name>
                                    <description>Enable automatic calibration</description>
                                    <value>#1</value>
                                </enumeratedValue>
                            </enumeratedValues>
                        </field>
                        <field>
                            <name>CANOWR</name>
                            <description>Calibration no write mode</description>
                            <lsb>1</lsb>
                            <msb>1</msb>
                            <access>read-write</access>
                            <enumeratedValues>
                                <enumeratedValue>
                                    <name>0</name>
                                    <description>Calibration sequence with write command</description>
                                    <value>#0</value>
                                </enumeratedValue>
                                <enumeratedValue>
                                    <name>1</name>
                                    <description>Calibration sequence without write command</description>
                                    <value>#1</value>
                                </enumeratedValue>
                            </enumeratedValues>
                        </field>
                        <field>
                            <name>CAITV</name>
                            <description>Calibration interval</description>
                            <lsb>8</lsb>
                            <msb>12</msb>
                            <access>read-write</access>
                        </field>
                        <field>
                            <name>CASFTSTA</name>
                            <description>Calibration OM_DQS shift start value</description>
                            <lsb>16</lsb>
                            <msb>20</msb>
                            <access>read-write</access>
                        </field>
                        <field>
                            <name>CASFTEND</name>
                            <description>Calibration OM_DQS shift end value</description>
                            <lsb>24</lsb>
                            <msb>28</msb>
                            <access>read-write</access>
                        </field>
                    </fields>
                </register>
                <register>
                    <dim>2</dim>
                    <dimIncrement>0x020</dimIncrement>
                    <dimIndex>0-1</dimIndex>
                    <name>CCCTL1CS%s</name>
                    <description>OSPI Command Calibration Control Register 1 CSn</description>
                    <addressOffset>0x134</addressOffset>
                    <size>32</size>
                    <access>read-write</access>
                    <resetValue>0x00000000</resetValue>
                    <resetMask>0xffffffff</resetMask>
                    <fields>
                        <field>
                            <name>CACMDSIZE</name>
                            <description>Command Size</description>
                            <lsb>0</lsb>
                            <msb>1</msb>
                            <access>read-write</access>
                            <enumeratedValues>
                                <enumeratedValue>
                                    <name>00</name>
                                    <description>0 bytes (No command phase) </description>
                                    <value>#00</value>
                                </enumeratedValue>
                                <enumeratedValue>
                                    <name>01</name>
                                    <description>1 byte</description>
                                    <value>#01</value>
                                </enumeratedValue>
                                <enumeratedValue>
                                    <name>10</name>
                                    <description>2 bytes</description>
                                    <value>#10</value>
                                </enumeratedValue>
                                <enumeratedValue>
                                    <name>11</name>
                                    <description>Setting prohibited</description>
                                    <value>#11</value>
                                </enumeratedValue>
                            </enumeratedValues>
                        </field>
                        <field>
                            <name>CAADDSIZE</name>
                            <description>Address size</description>
                            <lsb>2</lsb>
                            <msb>4</msb>
                            <access>read-write</access>
                            <enumeratedValues>
                                <enumeratedValue>
                                    <name>000</name>
                                    <description>0 bytes (No address phase) </description>
                                    <value>#000</value>
                                </enumeratedValue>
                                <enumeratedValue>
                                    <name>001</name>
                                    <description>1 byte</description>
                                    <value>#001</value>
                                </enumeratedValue>
                                <enumeratedValue>
                                    <name>010</name>
                                    <description>2 bytes</description>
                                    <value>#010</value>
                                </enumeratedValue>
                                <enumeratedValue>
                                    <name>011</name>
                                    <description>3 bytes</description>
                                    <value>#011</value>
                                </enumeratedValue>
                                <enumeratedValue>
                                    <name>100</name>
                                    <description>4 bytes</description>
                                    <value>#100</value>
                                </enumeratedValue>
                                <enumeratedValue>
                                    <name>Others</name>
                                    <description>Setting prohibited</description>
                                    <isDefault>true</isDefault>
                                </enumeratedValue>
                            </enumeratedValues>
                        </field>
                        <field>
                            <name>CADATASIZE</name>
                            <description>Write/Read Data Size</description>
                            <lsb>5</lsb>
                            <msb>8</msb>
                            <access>read-write</access>
                        </field>
                        <field>
                            <name>CAWRLATE</name>
                            <description>Write Latency cycle</description>
                            <lsb>16</lsb>
                            <msb>20</msb>
                            <access>read-write</access>
                        </field>
                        <field>
                            <name>CARDLATE</name>
                            <description>Read Latency cycle</description>
                            <lsb>24</lsb>
                            <msb>28</msb>
                            <access>read-write</access>
                        </field>
                    </fields>
                </register>
                <register>
                    <dim>2</dim>
                    <dimIncrement>0x020</dimIncrement>
                    <dimIndex>0-1</dimIndex>
                    <name>CCCTL2CS%s</name>
                    <description>OSPI Command Calibration Control Register 2 CSn</description>
                    <addressOffset>0x138</addressOffset>
                    <size>32</size>
                    <access>read-write</access>
                    <resetValue>0x00000000</resetValue>
                    <resetMask>0xffffffff</resetMask>
                    <fields>
                        <field>
                            <name>CAWRCMD</name>
                            <description>Calibration pattern write command</description>
                            <lsb>0</lsb>
                            <msb>15</msb>
                            <access>read-write</access>
                        </field>
                        <field>
                            <name>CARDCMD</name>
                            <description>Calibration pattern read command</description>
                            <lsb>16</lsb>
                            <msb>31</msb>
                            <access>read-write</access>
                        </field>
                    </fields>
                </register>
                <register>
                    <dim>2</dim>
                    <dimIncrement>0x020</dimIncrement>
                    <dimIndex>0-1</dimIndex>
                    <name>CCCTL3CS%s</name>
                    <description>OSPI Command Calibration Control Register 3 CSn</description>
                    <addressOffset>0x13C</addressOffset>
                    <size>32</size>
                    <access>read-write</access>
                    <resetValue>0x00000000</resetValue>
                    <resetMask>0xffffffff</resetMask>
                    <fields>
                        <field>
                            <name>CAADD</name>
                            <description>Calibration pattern address</description>
                            <lsb>0</lsb>
                            <msb>31</msb>
                            <access>read-write</access>
                        </field>
                    </fields>
                </register>
                <register>
                    <dim>2</dim>
                    <dimIncrement>0x020</dimIncrement>
                    <dimIndex>0-1</dimIndex>
                    <name>CCCTL4CS%s</name>
                    <description>OSPI Command Calibration Control Register 4 CSn</description>
                    <addressOffset>0x140</addressOffset>
                    <size>32</size>
                    <access>read-write</access>
                    <resetValue>0x00000000</resetValue>
                    <resetMask>0xffffffff</resetMask>
                    <fields>
                        <field>
                            <name>CADATA</name>
                            <description>Calibration pattern data</description>
                            <lsb>0</lsb>
                            <msb>31</msb>
                            <access>read-write</access>
                        </field>
                    </fields>
                </register>
                <register>
                    <dim>2</dim>
                    <dimIncrement>0x020</dimIncrement>
                    <dimIndex>0-1</dimIndex>
                    <name>CCCTL5CS%s</name>
                    <description>OSPI Command Calibration Control Register 5 CSn</description>
                    <addressOffset>0x144</addressOffset>
                    <size>32</size>
                    <access>read-write</access>
                    <resetValue>0x00000000</resetValue>
                    <resetMask>0xffffffff</resetMask>
                    <fields>
                        <field>
                            <name>CADATA</name>
                            <description>Calibration pattern data</description>
                            <lsb>0</lsb>
                            <msb>31</msb>
                            <access>read-write</access>
                        </field>
                    </fields>
                </register>
                <register>
                    <dim>2</dim>
                    <dimIncrement>0x020</dimIncrement>
                    <dimIndex>0-1</dimIndex>
                    <name>CCCTL6CS%s</name>
                    <description>OSPI Command Calibration Control Register 6 CSn</description>
                    <addressOffset>0x148</addressOffset>
                    <size>32</size>
                    <access>read-write</access>
                    <resetValue>0x00000000</resetValue>
                    <resetMask>0xffffffff</resetMask>
                    <fields>
                        <field>
                            <name>CADATA</name>
                            <description>Calibration pattern data</description>
                            <lsb>0</lsb>
                            <msb>31</msb>
                            <access>read-write</access>
                        </field>
                    </fields>
                </register>
                <register>
                    <dim>2</dim>
                    <dimIncrement>0x020</dimIncrement>
                    <dimIndex>0-1</dimIndex>
                    <name>CCCTL7CS%s</name>
                    <description>OSPI Command Calibration Control Register 7 CSn</description>
                    <addressOffset>0x14C</addressOffset>
                    <size>32</size>
                    <access>read-write</access>
                    <resetValue>0x00000000</resetValue>
                    <resetMask>0xffffffff</resetMask>
                    <fields>
                        <field>
                            <name>CADATA</name>
                            <description>Calibration pattern data</description>
                            <lsb>0</lsb>
                            <msb>31</msb>
                            <access>read-write</access>
                        </field>
                    </fields>
                </register>
                <register>
                    <name>COMSTT</name>
                    <description>OSPI Common Status Register</description>
                    <addressOffset>0x184</addressOffset>
                    <size>32</size>
                    <access>read-only</access>
                    <resetValue>0x00000000</resetValue>
                    <resetMask>0xffffffff</resetMask>
                    <fields>
                        <field>
                            <name>MEMACCCH0</name>
                            <description>Memory access ongoing from ch0</description>
                            <lsb>0</lsb>
                            <msb>0</msb>
                            <access>read-only</access>
                            <enumeratedValues>
                                <enumeratedValue>
                                    <name>0</name>
                                    <description>System bus bridge ch0 is not accessing to memory.</description>
                                    <value>#0</value>
                                </enumeratedValue>
                                <enumeratedValue>
                                    <name>1</name>
                                    <description>System bus bridge ch0 is accessing to memory. </description>
                                    <value>#1</value>
                                </enumeratedValue>
                            </enumeratedValues>
                        </field>
                        <field>
                            <name>MEMACCCH1</name>
                            <description>Memory access ongoing from ch1</description>
                            <lsb>1</lsb>
                            <msb>1</msb>
                            <access>read-only</access>
                        </field>
                        <field>
                            <name>PBUFNECH0</name>
                            <description>Prefetch Buffer Not Empty for ch0</description>
                            <lsb>4</lsb>
                            <msb>4</msb>
                            <access>read-only</access>
                            <enumeratedValues>
                                <enumeratedValue>
                                    <name>0</name>
                                    <description>Empty</description>
                                    <value>#0</value>
                                </enumeratedValue>
                                <enumeratedValue>
                                    <name>1</name>
                                    <description>Not empty</description>
                                    <value>#1</value>
                                </enumeratedValue>
                            </enumeratedValues>
                        </field>
                        <field>
                            <name>PBUFNECH1</name>
                            <description>Prefetch Buffer Not Empty for ch1</description>
                            <lsb>5</lsb>
                            <msb>5</msb>
                            <access>read-only</access>
                        </field>
                        <field>
                            <name>WRBUFNECH0</name>
                            <description>Write Buffer Not Empty for ch0</description>
                            <lsb>6</lsb>
                            <msb>6</msb>
                            <access>read-only</access>
                            <enumeratedValues>
                                <enumeratedValue>
                                    <name>0</name>
                                    <description>Empty</description>
                                    <value>#0</value>
                                </enumeratedValue>
                                <enumeratedValue>
                                    <name>1</name>
                                    <description>Not empty </description>
                                    <value>#1</value>
                                </enumeratedValue>
                            </enumeratedValues>
                        </field>
                        <field>
                            <name>WRBUFNECH1</name>
                            <description>Write Buffer Not Empty for ch1</description>
                            <lsb>7</lsb>
                            <msb>7</msb>
                            <access>read-only</access>
                        </field>
                        <field>
                            <name>ECSCS1</name>
                            <description>ECS monitor for slave1</description>
                            <lsb>20</lsb>
                            <msb>20</msb>
                            <access>read-only</access>
                            <enumeratedValues>
                                <enumeratedValue>
                                    <name>0</name>
                                    <description>Low level</description>
                                    <value>#0</value>
                                </enumeratedValue>
                                <enumeratedValue>
                                    <name>1</name>
                                    <description>High level</description>
                                    <value>#1</value>
                                </enumeratedValue>
                            </enumeratedValues>
                        </field>
                        <field>
                            <name>INTCS1</name>
                            <description>INT monitor for slave1</description>
                            <lsb>21</lsb>
                            <msb>21</msb>
                            <access>read-only</access>
                            <enumeratedValues>
                                <enumeratedValue>
                                    <name>0</name>
                                    <description>Low level</description>
                                    <value>#0</value>
                                </enumeratedValue>
                                <enumeratedValue>
                                    <name>1</name>
                                    <description>High level</description>
                                    <value>#1</value>
                                </enumeratedValue>
                            </enumeratedValues>
                        </field>
                        <field>
                            <name>RSTOCS1</name>
                            <description>RSTO monitor for slave1</description>
                            <lsb>22</lsb>
                            <msb>22</msb>
                            <access>read-only</access>
                            <enumeratedValues>
                                <enumeratedValue>
                                    <name>0</name>
                                    <description>Low level</description>
                                    <value>#0</value>
                                </enumeratedValue>
                                <enumeratedValue>
                                    <name>1</name>
                                    <description>High level</description>
                                    <value>#1</value>
                                </enumeratedValue>
                            </enumeratedValues>
                        </field>
                    </fields>
                </register>
                <register>
                    <dim>2</dim>
                    <dimIncrement>0x004</dimIncrement>
                    <dimIndex>0-1</dimIndex>
                    <name>CASTTCS%s</name>
                    <description>OSPI Calibration Status Register CSn</description>
                    <addressOffset>0x188</addressOffset>
                    <size>32</size>
                    <access>read-only</access>
                    <resetValue>0x00000000</resetValue>
                    <resetMask>0xffffffff</resetMask>
                    <fields>
                        <field>
                            <name>CASUC</name>
                            <description>Calibration Success</description>
                            <lsb>0</lsb>
                            <msb>31</msb>
                            <access>read-only</access>
                        </field>
                    </fields>
                </register>
                <register>
                    <name>INTS</name>
                    <description>OSPI Interrupt Status Register</description>
                    <addressOffset>0x190</addressOffset>
                    <size>32</size>
                    <access>read-only</access>
                    <resetValue>0x00000000</resetValue>
                    <resetMask>0xffffffff</resetMask>
                    <fields>
                        <field>
                            <name>CMDCMP</name>
                            <description>Command Completed</description>
                            <lsb>0</lsb>
                            <msb>0</msb>
                            <access>read-only</access>
                            <enumeratedValues>
                                <enumeratedValue>
                                    <name>0</name>
                                    <description>No detection</description>
                                    <value>#0</value>
                                </enumeratedValue>
                                <enumeratedValue>
                                    <name>1</name>
                                    <description>Detection</description>
                                    <value>#1</value>
                                </enumeratedValue>
                            </enumeratedValues>
                        </field>
                        <field>
                            <name>PATCMP</name>
                            <description>Pattern Completed</description>
                            <lsb>1</lsb>
                            <msb>1</msb>
                            <access>read-only</access>
                            <enumeratedValues>
                                <enumeratedValue>
                                    <name>0</name>
                                    <description>No detection</description>
                                    <value>#0</value>
                                </enumeratedValue>
                                <enumeratedValue>
                                    <name>1</name>
                                    <description>Detection</description>
                                    <value>#1</value>
                                </enumeratedValue>
                            </enumeratedValues>
                        </field>
                        <field>
                            <name>PERTO</name>
                            <description>Periodic transaction timeout</description>
                            <lsb>3</lsb>
                            <msb>3</msb>
                            <access>read-only</access>
                            <enumeratedValues>
                                <enumeratedValue>
                                    <name>0</name>
                                    <description>No detection</description>
                                    <value>#0</value>
                                </enumeratedValue>
                                <enumeratedValue>
                                    <name>1</name>
                                    <description>Detection</description>
                                    <value>#1</value>
                                </enumeratedValue>
                            </enumeratedValues>
                        </field>
                        <field>
                            <name>DSTOCS0</name>
                            <description>OM_DQS timeout for slave0</description>
                            <lsb>4</lsb>
                            <msb>4</msb>
                            <access>read-only</access>
                            <enumeratedValues>
                                <enumeratedValue>
                                    <name>0</name>
                                    <description>No detection</description>
                                    <value>#0</value>
                                </enumeratedValue>
                                <enumeratedValue>
                                    <name>1</name>
                                    <description>Detection</description>
                                    <value>#1</value>
                                </enumeratedValue>
                            </enumeratedValues>
                        </field>
                        <field>
                            <name>DSTOCS1</name>
                            <description>OM_DQS timeout for slave1</description>
                            <lsb>5</lsb>
                            <msb>5</msb>
                            <access>read-only</access>
                            <enumeratedValues>
                                <enumeratedValue>
                                    <name>0</name>
                                    <description>No detection</description>
                                    <value>#0</value>
                                </enumeratedValue>
                                <enumeratedValue>
                                    <name>1</name>
                                    <description>Detection</description>
                                    <value>#1</value>
                                </enumeratedValue>
                            </enumeratedValues>
                        </field>
                        <field>
                            <name>ECSCS1</name>
                            <description>ECC error detection for slave1</description>
                            <lsb>9</lsb>
                            <msb>9</msb>
                            <access>read-only</access>
                            <enumeratedValues>
                                <enumeratedValue>
                                    <name>0</name>
                                    <description>No detection</description>
                                    <value>#0</value>
                                </enumeratedValue>
                                <enumeratedValue>
                                    <name>1</name>
                                    <description>Detection</description>
                                    <value>#1</value>
                                </enumeratedValue>
                            </enumeratedValues>
                        </field>
                        <field>
                            <name>INTCS1</name>
                            <description>Interrupt detection for slave1</description>
                            <lsb>13</lsb>
                            <msb>13</msb>
                            <access>read-only</access>
                            <enumeratedValues>
                                <enumeratedValue>
                                    <name>0</name>
                                    <description>No detection</description>
                                    <value>#0</value>
                                </enumeratedValue>
                                <enumeratedValue>
                                    <name>1</name>
                                    <description>Detection</description>
                                    <value>#1</value>
                                </enumeratedValue>
                            </enumeratedValues>
                        </field>
                        <field>
                            <name>BUSERRCH0</name>
                            <description>System bus error for ch0</description>
                            <lsb>20</lsb>
                            <msb>20</msb>
                            <access>read-only</access>
                        </field>
                        <field>
                            <name>BUSERRCH1</name>
                            <description>System bus error for ch1</description>
                            <lsb>21</lsb>
                            <msb>21</msb>
                            <access>read-only</access>
                        </field>
                        <field>
                            <name>CAFAILCS0</name>
                            <description>Calibration failed for slave0</description>
                            <lsb>28</lsb>
                            <msb>28</msb>
                            <access>read-only</access>
                            <enumeratedValues>
                                <enumeratedValue>
                                    <name>0</name>
                                    <description>No detection</description>
                                    <value>#0</value>
                                </enumeratedValue>
                                <enumeratedValue>
                                    <name>1</name>
                                    <description>Detection</description>
                                    <value>#1</value>
                                </enumeratedValue>
                            </enumeratedValues>
                        </field>
                        <field>
                            <name>CAFAILCS1</name>
                            <description>Calibration failed for slave1</description>
                            <lsb>29</lsb>
                            <msb>29</msb>
                            <access>read-only</access>
                            <enumeratedValues>
                                <enumeratedValue>
                                    <name>0</name>
                                    <description>No detection</description>
                                    <value>#0</value>
                                </enumeratedValue>
                                <enumeratedValue>
                                    <name>1</name>
                                    <description>Detection</description>
                                    <value>#1</value>
                                </enumeratedValue>
                            </enumeratedValues>
                        </field>
                        <field>
                            <name>CASUCCS0</name>
                            <description>Calibration success for slave0</description>
                            <lsb>30</lsb>
                            <msb>30</msb>
                            <access>read-only</access>
                            <enumeratedValues>
                                <enumeratedValue>
                                    <name>0</name>
                                    <description>No detection</description>
                                    <value>#0</value>
                                </enumeratedValue>
                                <enumeratedValue>
                                    <name>1</name>
                                    <description>Detection</description>
                                    <value>#1</value>
                                </enumeratedValue>
                            </enumeratedValues>
                        </field>
                        <field>
                            <name>CASUCCS1</name>
                            <description>Calibration success for slave1</description>
                            <lsb>31</lsb>
                            <msb>31</msb>
                            <access>read-only</access>
                            <enumeratedValues>
                                <enumeratedValue>
                                    <name>0</name>
                                    <description>No detection</description>
                                    <value>#0</value>
                                </enumeratedValue>
                                <enumeratedValue>
                                    <name>1</name>
                                    <description>Detection</description>
                                    <value>#1</value>
                                </enumeratedValue>
                            </enumeratedValues>
                        </field>
                    </fields>
                </register>
                <register>
                    <name>INTC</name>
                    <description>OSPI Interrupt Clear Register</description>
                    <addressOffset>0x194</addressOffset>
                    <size>32</size>
                    <access>write-only</access>
                    <resetValue>0x00000000</resetValue>
                    <resetMask>0xffffffff</resetMask>
                    <fields>
                        <field>
                            <name>CMDCMPC</name>
                            <description>Command Completed interrupt clear</description>
                            <lsb>0</lsb>
                            <msb>0</msb>
                            <access>write-only</access>
                            <enumeratedValues>
                                <enumeratedValue>
                                    <name>0</name>
                                    <description>No change interrupt status</description>
                                    <value>#0</value>
                                </enumeratedValue>
                                <enumeratedValue>
                                    <name>1</name>
                                    <description>Clear interrupt status</description>
                                    <value>#1</value>
                                </enumeratedValue>
                            </enumeratedValues>
                        </field>
                        <field>
                            <name>PATCMPC</name>
                            <description>Pattern Completed interrupt clear</description>
                            <lsb>1</lsb>
                            <msb>1</msb>
                            <access>write-only</access>
                            <enumeratedValues>
                                <enumeratedValue>
                                    <name>0</name>
                                    <description>No change interrupt status</description>
                                    <value>#0</value>
                                </enumeratedValue>
                                <enumeratedValue>
                                    <name>1</name>
                                    <description>Clear interrupt status</description>
                                    <value>#1</value>
                                </enumeratedValue>
                            </enumeratedValues>
                        </field>
                        <field>
                            <name>PERTOC</name>
                            <description>Periodic transaction timeout interrupt clear</description>
                            <lsb>3</lsb>
                            <msb>3</msb>
                            <access>write-only</access>
                            <enumeratedValues>
                                <enumeratedValue>
                                    <name>0</name>
                                    <description>No change interrupt status</description>
                                    <value>#0</value>
                                </enumeratedValue>
                                <enumeratedValue>
                                    <name>1</name>
                                    <description>Clear interrupt status</description>
                                    <value>#1</value>
                                </enumeratedValue>
                            </enumeratedValues>
                        </field>
                        <field>
                            <name>DSTOCS0C</name>
                            <description>OM_DQS timeout for slave0 interrupt clear</description>
                            <lsb>4</lsb>
                            <msb>4</msb>
                            <access>write-only</access>
                            <enumeratedValues>
                                <enumeratedValue>
                                    <name>0</name>
                                    <description>No change interrupt status</description>
                                    <value>#0</value>
                                </enumeratedValue>
                                <enumeratedValue>
                                    <name>1</name>
                                    <description>Clear interrupt status</description>
                                    <value>#1</value>
                                </enumeratedValue>
                            </enumeratedValues>
                        </field>
                        <field>
                            <name>DSTOCS1C</name>
                            <description>OM_DQS timeout for slave1 interrupt clear</description>
                            <lsb>5</lsb>
                            <msb>5</msb>
                            <access>write-only</access>
                            <enumeratedValues>
                                <enumeratedValue>
                                    <name>0</name>
                                    <description>No change interrupt status</description>
                                    <value>#0</value>
                                </enumeratedValue>
                                <enumeratedValue>
                                    <name>1</name>
                                    <description>Clear interrupt status</description>
                                    <value>#1</value>
                                </enumeratedValue>
                            </enumeratedValues>
                        </field>
                        <field>
                            <name>ECSCS1C</name>
                            <description>ECC error detection for slave1 interrupt clear</description>
                            <lsb>9</lsb>
                            <msb>9</msb>
                            <access>write-only</access>
                            <enumeratedValues>
                                <enumeratedValue>
                                    <name>0</name>
                                    <description>No change interrupt status</description>
                                    <value>#0</value>
                                </enumeratedValue>
                                <enumeratedValue>
                                    <name>1</name>
                                    <description>Clear interrupt status</description>
                                    <value>#1</value>
                                </enumeratedValue>
                            </enumeratedValues>
                        </field>
                        <field>
                            <name>INTCS1C</name>
                            <description>Interrupt detection for slave1 interrupt clear</description>
                            <lsb>13</lsb>
                            <msb>13</msb>
                            <access>write-only</access>
                            <enumeratedValues>
                                <enumeratedValue>
                                    <name>0</name>
                                    <description>No change interrupt status</description>
                                    <value>#0</value>
                                </enumeratedValue>
                                <enumeratedValue>
                                    <name>1</name>
                                    <description>Clear interrupt status</description>
                                    <value>#1</value>
                                </enumeratedValue>
                            </enumeratedValues>
                        </field>
                        <field>
                            <name>BUSERRCH0C</name>
                            <description>System bus error for ch0 interrupt clear</description>
                            <lsb>20</lsb>
                            <msb>20</msb>
                            <access>write-only</access>
                            <enumeratedValues>
                                <enumeratedValue>
                                    <name>0</name>
                                    <description>No change interrupt status</description>
                                    <value>#0</value>
                                </enumeratedValue>
                                <enumeratedValue>
                                    <name>1</name>
                                    <description>Clear interrupt status</description>
                                    <value>#1</value>
                                </enumeratedValue>
                            </enumeratedValues>
                        </field>
                        <field>
                            <name>BUSERRCH1C</name>
                            <description>System bus error for ch1 interrupt clear</description>
                            <lsb>21</lsb>
                            <msb>21</msb>
                            <access>write-only</access>
                            <enumeratedValues>
                                <enumeratedValue>
                                    <name>0</name>
                                    <description>No change interrupt status</description>
                                    <value>#0</value>
                                </enumeratedValue>
                                <enumeratedValue>
                                    <name>1</name>
                                    <description>Clear interrupt status</description>
                                    <value>#1</value>
                                </enumeratedValue>
                            </enumeratedValues>
                        </field>
                        <field>
                            <name>CAFAILCS0C</name>
                            <description>Calibration failed for slave0 interrupt clear</description>
                            <lsb>28</lsb>
                            <msb>28</msb>
                            <access>write-only</access>
                            <enumeratedValues>
                                <enumeratedValue>
                                    <name>0</name>
                                    <description>No change interrupt status</description>
                                    <value>#0</value>
                                </enumeratedValue>
                                <enumeratedValue>
                                    <name>1</name>
                                    <description>Clear interrupt status</description>
                                    <value>#1</value>
                                </enumeratedValue>
                            </enumeratedValues>
                        </field>
                        <field>
                            <name>CAFAILCS1C</name>
                            <description>Calibration failed for slave1 interrupt clear</description>
                            <lsb>29</lsb>
                            <msb>29</msb>
                            <access>write-only</access>
                            <enumeratedValues>
                                <enumeratedValue>
                                    <name>0</name>
                                    <description>No change interrupt status</description>
                                    <value>#0</value>
                                </enumeratedValue>
                                <enumeratedValue>
                                    <name>1</name>
                                    <description>Clear interrupt status</description>
                                    <value>#1</value>
                                </enumeratedValue>
                            </enumeratedValues>
                        </field>
                        <field>
                            <name>CASUCCS0C</name>
                            <description>Calibration success for slave0 interrupt clear</description>
                            <lsb>30</lsb>
                            <msb>30</msb>
                            <access>write-only</access>
                            <enumeratedValues>
                                <enumeratedValue>
                                    <name>0</name>
                                    <description>No change interrupt status</description>
                                    <value>#0</value>
                                </enumeratedValue>
                                <enumeratedValue>
                                    <name>1</name>
                                    <description>Clear interrupt status</description>
                                    <value>#1</value>
                                </enumeratedValue>
                            </enumeratedValues>
                        </field>
                        <field>
                            <name>CASUCCS1C</name>
                            <description>Calibration success for slave1 interrupt clear</description>
                            <lsb>31</lsb>
                            <msb>31</msb>
                            <access>write-only</access>
                            <enumeratedValues>
                                <enumeratedValue>
                                    <name>0</name>
                                    <description>No change interrupt status</description>
                                    <value>#0</value>
                                </enumeratedValue>
                                <enumeratedValue>
                                    <name>1</name>
                                    <description>Clear interrupt status</description>
                                    <value>#1</value>
                                </enumeratedValue>
                            </enumeratedValues>
                        </field>
                    </fields>
                </register>
                <register>
                    <name>INTE</name>
                    <description>OSPI Interrupt Enable Register</description>
                    <addressOffset>0x198</addressOffset>
                    <size>32</size>
                    <access>read-write</access>
                    <resetValue>0x00000000</resetValue>
                    <resetMask>0xffffffff</resetMask>
                    <fields>
                        <field>
                            <name>CMDCMPE</name>
                            <description>Command Completed interrupt enable</description>
                            <lsb>0</lsb>
                            <msb>0</msb>
                            <access>read-write</access>
                            <enumeratedValues>
                                <enumeratedValue>
                                    <name>0</name>
                                    <description>Disabled</description>
                                    <value>#0</value>
                                </enumeratedValue>
                                <enumeratedValue>
                                    <name>1</name>
                                    <description>Enabled</description>
                                    <value>#1</value>
                                </enumeratedValue>
                            </enumeratedValues>
                        </field>
                        <field>
                            <name>PATCMPE</name>
                            <description>Pattern Completed interrupt enable</description>
                            <lsb>1</lsb>
                            <msb>1</msb>
                            <access>read-write</access>
                            <enumeratedValues>
                                <enumeratedValue>
                                    <name>0</name>
                                    <description>Disabled</description>
                                    <value>#0</value>
                                </enumeratedValue>
                                <enumeratedValue>
                                    <name>1</name>
                                    <description>Enabled</description>
                                    <value>#1</value>
                                </enumeratedValue>
                            </enumeratedValues>
                        </field>
                        <field>
                            <name>PERTOE</name>
                            <description>Periodic transaction timeout interrupt enable</description>
                            <lsb>3</lsb>
                            <msb>3</msb>
                            <access>read-write</access>
                            <enumeratedValues>
                                <enumeratedValue>
                                    <name>0</name>
                                    <description>Disabled</description>
                                    <value>#0</value>
                                </enumeratedValue>
                                <enumeratedValue>
                                    <name>1</name>
                                    <description>Enabled</description>
                                    <value>#1</value>
                                </enumeratedValue>
                            </enumeratedValues>
                        </field>
                        <field>
                            <name>DSTOCS0E</name>
                            <description>OM_DQS timeout for slave0 interrupt enable</description>
                            <lsb>4</lsb>
                            <msb>4</msb>
                            <access>read-write</access>
                            <enumeratedValues>
                                <enumeratedValue>
                                    <name>0</name>
                                    <description>Disabled</description>
                                    <value>#0</value>
                                </enumeratedValue>
                                <enumeratedValue>
                                    <name>1</name>
                                    <description>Enabled</description>
                                    <value>#1</value>
                                </enumeratedValue>
                            </enumeratedValues>
                        </field>
                        <field>
                            <name>DSTOCS1E</name>
                            <description>OM_DQS timeout for slave1 interrupt enable</description>
                            <lsb>5</lsb>
                            <msb>5</msb>
                            <access>read-write</access>
                            <enumeratedValues>
                                <enumeratedValue>
                                    <name>0</name>
                                    <description>Disabled</description>
                                    <value>#0</value>
                                </enumeratedValue>
                                <enumeratedValue>
                                    <name>1</name>
                                    <description>Enabled</description>
                                    <value>#1</value>
                                </enumeratedValue>
                            </enumeratedValues>
                        </field>
                        <field>
                            <name>ECSCS1E</name>
                            <description>ECC error detection for slave1 interrupt enable</description>
                            <lsb>9</lsb>
                            <msb>9</msb>
                            <access>read-write</access>
                            <enumeratedValues>
                                <enumeratedValue>
                                    <name>0</name>
                                    <description>Disabled</description>
                                    <value>#0</value>
                                </enumeratedValue>
                                <enumeratedValue>
                                    <name>1</name>
                                    <description>Enabled</description>
                                    <value>#1</value>
                                </enumeratedValue>
                            </enumeratedValues>
                        </field>
                        <field>
                            <name>INTCS1E</name>
                            <description>Interrupt detection for slave1 interrupt enable</description>
                            <lsb>13</lsb>
                            <msb>13</msb>
                            <access>read-write</access>
                            <enumeratedValues>
                                <enumeratedValue>
                                    <name>0</name>
                                    <description>Disabled</description>
                                    <value>#0</value>
                                </enumeratedValue>
                                <enumeratedValue>
                                    <name>1</name>
                                    <description>Enabled</description>
                                    <value>#1</value>
                                </enumeratedValue>
                            </enumeratedValues>
                        </field>
                        <field>
                            <name>BUSERRCH0E</name>
                            <description>System bus error for ch0 interrupt enable</description>
                            <lsb>20</lsb>
                            <msb>20</msb>
                            <access>read-write</access>
                            <enumeratedValues>
                                <enumeratedValue>
                                    <name>0</name>
                                    <description>Disabled</description>
                                    <value>#0</value>
                                </enumeratedValue>
                                <enumeratedValue>
                                    <name>1</name>
                                    <description>Enabled</description>
                                    <value>#1</value>
                                </enumeratedValue>
                            </enumeratedValues>
                        </field>
                        <field>
                            <name>BUSERRCH1E</name>
                            <description>System bus error for ch1 interrupt enable</description>
                            <lsb>21</lsb>
                            <msb>21</msb>
                            <access>read-write</access>
                            <enumeratedValues>
                                <enumeratedValue>
                                    <name>0</name>
                                    <description>Disabled</description>
                                    <value>#0</value>
                                </enumeratedValue>
                                <enumeratedValue>
                                    <name>1</name>
                                    <description>Enabled</description>
                                    <value>#1</value>
                                </enumeratedValue>
                            </enumeratedValues>
                        </field>
                        <field>
                            <name>CAFAILCS0E</name>
                            <description>Calibration failed for slave0 interrupt enable</description>
                            <lsb>28</lsb>
                            <msb>28</msb>
                            <access>read-write</access>
                            <enumeratedValues>
                                <enumeratedValue>
                                    <name>0</name>
                                    <description>Disabled</description>
                                    <value>#0</value>
                                </enumeratedValue>
                                <enumeratedValue>
                                    <name>1</name>
                                    <description>Enabled</description>
                                    <value>#1</value>
                                </enumeratedValue>
                            </enumeratedValues>
                        </field>
                        <field>
                            <name>CAFAILCS1E</name>
                            <description>Calibration failed for slave1 interrupt enable</description>
                            <lsb>29</lsb>
                            <msb>29</msb>
                            <access>read-write</access>
                            <enumeratedValues>
                                <enumeratedValue>
                                    <name>0</name>
                                    <description>Disabled</description>
                                    <value>#0</value>
                                </enumeratedValue>
                                <enumeratedValue>
                                    <name>1</name>
                                    <description>Enabled</description>
                                    <value>#1</value>
                                </enumeratedValue>
                            </enumeratedValues>
                        </field>
                        <field>
                            <name>CASUCCS0E</name>
                            <description>Calibration success for slave0 interrupt enable</description>
                            <lsb>30</lsb>
                            <msb>30</msb>
                            <access>read-write</access>
                            <enumeratedValues>
                                <enumeratedValue>
                                    <name>0</name>
                                    <description>Disabled</description>
                                    <value>#0</value>
                                </enumeratedValue>
                                <enumeratedValue>
                                    <name>1</name>
                                    <description>Enabled</description>
                                    <value>#1</value>
                                </enumeratedValue>
                            </enumeratedValues>
                        </field>
                        <field>
                            <name>CASUCCS1E</name>
                            <description>Calibration success for slave1 interrupt enable</description>
                            <lsb>31</lsb>
                            <msb>31</msb>
                            <access>read-write</access>
                            <enumeratedValues>
                                <enumeratedValue>
                                    <name>0</name>
                                    <description>Disabled</description>
                                    <value>#0</value>
                                </enumeratedValue>
                                <enumeratedValue>
                                    <name>1</name>
                                    <description>Enabled</description>
                                    <value>#1</value>
                                </enumeratedValue>
                            </enumeratedValues>
                        </field>
                    </fields>
                </register>
            </registers>
        </peripheral>
        <peripheral>
            <name>CRC_NS</name>
            <description>CRC Calculator</description>
            <baseAddress>0x50310000</baseAddress>
            <addressBlock>
                <offset>0x00</offset>
                <size>2</size>
                <usage>registers</usage>
            </addressBlock>
            <addressBlock>
                <offset>0x04</offset>
                <size>4</size>
                <usage>registers</usage>
            </addressBlock>
            <addressBlock>
                <offset>0x08</offset>
                <size>4</size>
                <usage>registers</usage>
            </addressBlock>
            <addressBlock>
                <offset>0x0C</offset>
                <size>2</size>
                <usage>registers</usage>
            </addressBlock>
            <registers>
                <register>
                    <name>CRCCR0</name>
                    <description>CRC Control Register 0</description>
                    <addressOffset>0x00</addressOffset>
                    <size>8</size>
                    <access>read-write</access>
                    <resetValue>0x00</resetValue>
                    <resetMask>0xff</resetMask>
                    <fields>
                        <field>
                            <name>GPS</name>
                            <description>CRC Generating Polynomial Switching</description>
                            <lsb>0</lsb>
                            <msb>2</msb>
                            <access>read-write</access>
                            <enumeratedValues>
                                <enumeratedValue>
                                    <name>001</name>
                                    <description>8-bit CRC-8 (X8 + X2 + X + 1)</description>
                                    <value>#001</value>
                                </enumeratedValue>
                                <enumeratedValue>
                                    <name>010</name>
                                    <description>16-bit CRC-16 (X16 + X15 + X2 + 1)</description>
                                    <value>#010</value>
                                </enumeratedValue>
                                <enumeratedValue>
                                    <name>011</name>
                                    <description>16-bit CRC-CCITT (X16 + X12 + X5 + 1)</description>
                                    <value>#011</value>
                                </enumeratedValue>
                                <enumeratedValue>
                                    <name>100</name>
                                    <description>32-bit CRC-32 (X32 + X26 + X23 + X22 + X16 + X12 + X11 +X10 + X8 + X7 + X5 + X4 + X2 + X + 1)</description>
                                    <value>#100</value>
                                </enumeratedValue>
                                <enumeratedValue>
                                    <name>101</name>
                                    <description>32-bit CRC-32C (X32 + X28 + X27 + X26 + X25 + X23 + X22 + X20 + X19 + X18 + X14 + X13 + X11 + X10 + X9 + X8 + X6 + 1)</description>
                                    <value>#101</value>
                                </enumeratedValue>
                                <enumeratedValue>
                                    <name>Others</name>
                                    <description>No calculation is executed</description>
                                    <isDefault>true</isDefault>
                                </enumeratedValue>
                            </enumeratedValues>
                        </field>
                        <field>
                            <name>LMS</name>
                            <description>CRC Calculation Switching</description>
                            <lsb>6</lsb>
                            <msb>6</msb>
                            <access>read-write</access>
                            <enumeratedValues>
                                <enumeratedValue>
                                    <name>0</name>
                                    <description>Generate CRC code for LSB-first communication</description>
                                    <value>#0</value>
                                </enumeratedValue>
                                <enumeratedValue>
                                    <name>1</name>
                                    <description>Generate CRC code for MSB-first communication</description>
                                    <value>#1</value>
                                </enumeratedValue>
                            </enumeratedValues>
                        </field>
                        <field>
                            <name>DORCLR</name>
                            <description>CRCDOR/CRCDOR_HA/CRCDOR_BY Register Clear</description>
                            <lsb>7</lsb>
                            <msb>7</msb>
                            <access>write-only</access>
                            <enumeratedValues>
                                <enumeratedValue>
                                    <name>0</name>
                                    <description>No effect</description>
                                    <value>#0</value>
                                </enumeratedValue>
                                <enumeratedValue>
                                    <name>1</name>
                                    <description>Clear the CRCDOR/CRCDOR_HA/CRCDOR_BY register</description>
                                    <value>#1</value>
                                </enumeratedValue>
                            </enumeratedValues>
                        </field>
                    </fields>
                </register>
                <register>
                    <name>CRCCR1</name>
                    <description>CRC Control Register 1</description>
                    <addressOffset>0x01</addressOffset>
                    <size>8</size>
                    <access>read-write</access>
                    <resetValue>0x00</resetValue>
                    <resetMask>0xff</resetMask>
                    <fields>
                        <field>
                            <name>CRCSWR</name>
                            <description>Snoop-On-Write/Read Switch</description>
                            <lsb>6</lsb>
                            <msb>6</msb>
                            <access>read-write</access>
                            <enumeratedValues>
                                <enumeratedValue>
                                    <name>0</name>
                                    <description>Snoop-on-read</description>
                                    <value>#0</value>
                                </enumeratedValue>
                                <enumeratedValue>
                                    <name>1</name>
                                    <description>Snoop-on-write</description>
                                    <value>#1</value>
                                </enumeratedValue>
                            </enumeratedValues>
                        </field>
                        <field>
                            <name>CRCSEN</name>
                            <description>Snoop Enable</description>
                            <lsb>7</lsb>
                            <msb>7</msb>
                            <access>read-write</access>
                            <enumeratedValues>
                                <enumeratedValue>
                                    <name>0</name>
                                    <description>Disabled</description>
                                    <value>#0</value>
                                </enumeratedValue>
                                <enumeratedValue>
                                    <name>1</name>
                                    <description>Enabled</description>
                                    <value>#1</value>
                                </enumeratedValue>
                            </enumeratedValues>
                        </field>
                    </fields>
                </register>
                <register>
                    <name>CRCDIR</name>
                    <description>CRC Data Input Register</description>
                    <addressOffset>0x04</addressOffset>
                    <size>32</size>
                    <access>read-write</access>
                    <resetValue>0x00000000</resetValue>
                    <resetMask>0xffffffff</resetMask>
                </register>
                <register>
                    <name>CRCDIR_BY</name>
                    <description>CRC Data Input Register</description>
                    <alternateRegister>CRCDIR</alternateRegister>
                    <addressOffset>0x04</addressOffset>
                    <size>8</size>
                    <access>read-write</access>
                    <resetValue>0x00</resetValue>
                    <resetMask>0xff</resetMask>
                </register>
                <register>
                    <name>CRCDOR</name>
                    <description>CRC Data Output Register</description>
                    <addressOffset>0x08</addressOffset>
                    <size>32</size>
                    <access>read-write</access>
                    <resetValue>0x00000000</resetValue>
                    <resetMask>0xffffffff</resetMask>
                </register>
                <register>
                    <name>CRCDOR_HA</name>
                    <description>CRC Data Output Register</description>
                    <alternateRegister>CRCDOR</alternateRegister>
                    <addressOffset>0x08</addressOffset>
                    <size>16</size>
                    <access>read-write</access>
                    <resetValue>0x0000</resetValue>
                    <resetMask>0xffff</resetMask>
                </register>
                <register>
                    <name>CRCDOR_BY</name>
                    <description>CRC Data Output Register</description>
                    <alternateRegister>CRCDOR</alternateRegister>
                    <addressOffset>0x08</addressOffset>
                    <size>8</size>
                    <access>read-write</access>
                    <resetValue>0x00</resetValue>
                    <resetMask>0xff</resetMask>
                </register>
                <register>
                    <name>CRCSAR</name>
                    <description>Snoop Address Register</description>
                    <addressOffset>0x0C</addressOffset>
                    <size>16</size>
                    <access>read-write</access>
                    <resetValue>0x0000</resetValue>
                    <resetMask>0xffff</resetMask>
                    <fields>
                        <field>
                            <name>CRCSA</name>
                            <description>Register Snoop Address</description>
                            <lsb>0</lsb>
                            <msb>13</msb>
                            <access>read-write</access>
                        </field>
                    </fields>
                </register>
            </registers>
        </peripheral>
        <peripheral>
            <name>DOC_B_NS</name>
            <description>Data Operation Circuit</description>
            <baseAddress>0x50311000</baseAddress>
            <addressBlock>
                <offset>0x00</offset>
                <size>1</size>
                <usage>registers</usage>
            </addressBlock>
            <addressBlock>
                <offset>0x04</offset>
                <size>1</size>
                <usage>registers</usage>
            </addressBlock>
            <addressBlock>
                <offset>0x08</offset>
                <size>1</size>
                <usage>registers</usage>
            </addressBlock>
            <addressBlock>
                <offset>0x0C</offset>
                <size>12</size>
                <usage>registers</usage>
            </addressBlock>
            <registers>
                <register>
                    <name>DOCR</name>
                    <description>DOC Control Register</description>
                    <addressOffset>0x00</addressOffset>
                    <size>8</size>
                    <access>read-write</access>
                    <resetValue>0x00</resetValue>
                    <resetMask>0xff</resetMask>
                    <fields>
                        <field>
                            <name>OMS</name>
                            <description>Operating Mode Select</description>
                            <lsb>0</lsb>
                            <msb>1</msb>
                            <access>read-write</access>
                            <enumeratedValues>
                                <enumeratedValue>
                                    <name>00</name>
                                    <description>Data comparison mode</description>
                                    <value>#00</value>
                                </enumeratedValue>
                                <enumeratedValue>
                                    <name>01</name>
                                    <description>Data addition mode</description>
                                    <value>#01</value>
                                </enumeratedValue>
                                <enumeratedValue>
                                    <name>10</name>
                                    <description>Data subtraction mode</description>
                                    <value>#10</value>
                                </enumeratedValue>
                                <enumeratedValue>
                                    <name>11</name>
                                    <description>Setting prohibited</description>
                                    <value>#11</value>
                                </enumeratedValue>
                            </enumeratedValues>
                        </field>
                        <field>
                            <name>DOBW</name>
                            <description>Data Operation Bit Width Select</description>
                            <lsb>3</lsb>
                            <msb>3</msb>
                            <access>read-write</access>
                            <enumeratedValues>
                                <enumeratedValue>
                                    <name>0</name>
                                    <description>16-bit</description>
                                    <value>#0</value>
                                </enumeratedValue>
                                <enumeratedValue>
                                    <name>1</name>
                                    <description>32-bit</description>
                                    <value>#1</value>
                                </enumeratedValue>
                            </enumeratedValues>
                        </field>
                        <field>
                            <name>DCSEL</name>
                            <description>Detection Condition Select</description>
                            <lsb>4</lsb>
                            <msb>6</msb>
                            <access>read-write</access>
                            <enumeratedValues>
                                <enumeratedValue>
                                    <name>000</name>
                                    <description>Mismatch (DODSR0 ≠ DODIR)</description>
                                    <value>#000</value>
                                </enumeratedValue>
                                <enumeratedValue>
                                    <name>001</name>
                                    <description>Match (DODSR0 = DODIR)</description>
                                    <value>#001</value>
                                </enumeratedValue>
                                <enumeratedValue>
                                    <name>010</name>
                                    <description>Lower (DODSR0 &gt; DODIR)</description>
                                    <value>#010</value>
                                </enumeratedValue>
                                <enumeratedValue>
                                    <name>011</name>
                                    <description>Upper (DODSR0 &lt; DODIR)</description>
                                    <value>#011</value>
                                </enumeratedValue>
                                <enumeratedValue>
                                    <name>100</name>
                                    <description>Inside window (DODSR0 &lt; DODIR &lt; DODSR1)</description>
                                    <value>#100</value>
                                </enumeratedValue>
                                <enumeratedValue>
                                    <name>101</name>
                                    <description>Outside window (DODIR &lt; DODSR0, DODSR1 &lt; DODIR)</description>
                                    <value>#101</value>
                                </enumeratedValue>
                                <enumeratedValue>
                                    <name>Others</name>
                                    <description>Setting prohibited</description>
                                    <isDefault>true</isDefault>
                                </enumeratedValue>
                            </enumeratedValues>
                        </field>
                    </fields>
                </register>
                <register>
                    <name>DOSR</name>
                    <description>DOC Flag Status Register</description>
                    <addressOffset>0x04</addressOffset>
                    <size>8</size>
                    <access>read-only</access>
                    <resetValue>0x00</resetValue>
                    <resetMask>0xff</resetMask>
                    <fields>
                        <field>
                            <name>DOPCF</name>
                            <description>Data Operation Circuit Flag</description>
                            <lsb>0</lsb>
                            <msb>0</msb>
                            <access>read-only</access>
                        </field>
                    </fields>
                </register>
                <register>
                    <name>DOSCR</name>
                    <description>DOC Flag Status Clear Register</description>
                    <addressOffset>0x08</addressOffset>
                    <size>8</size>
                    <access>write-only</access>
                    <resetValue>0x00</resetValue>
                    <resetMask>0xff</resetMask>
                    <fields>
                        <field>
                            <name>DOPCFCL</name>
                            <description>DOPCF Clear</description>
                            <lsb>0</lsb>
                            <msb>0</msb>
                            <access>write-only</access>
                            <enumeratedValues>
                                <enumeratedValue>
                                    <name>0</name>
                                    <description>Maintains the DOPCF flag state.</description>
                                    <value>#0</value>
                                </enumeratedValue>
                                <enumeratedValue>
                                    <name>1</name>
                                    <description>Clears the DOPCF flag.</description>
                                    <value>#1</value>
                                </enumeratedValue>
                            </enumeratedValues>
                        </field>
                    </fields>
                </register>
                <register>
                    <name>DODIR</name>
                    <description>DOC Data Input Register</description>
                    <addressOffset>0x0C</addressOffset>
                    <size>32</size>
                    <access>read-write</access>
                    <resetValue>0x00000000</resetValue>
                    <resetMask>0xffffffff</resetMask>
                </register>
                <register>
                    <name>DODSR0</name>
                    <description>DOC Data Setting Register 0</description>
                    <addressOffset>0x10</addressOffset>
                    <size>32</size>
                    <access>read-write</access>
                    <resetValue>0x00000000</resetValue>
                    <resetMask>0xffffffff</resetMask>
                </register>
                <register>
                    <name>DODSR1</name>
                    <description>DOC Data Setting Register 1</description>
                    <addressOffset>0x14</addressOffset>
                    <size>32</size>
                    <access>read-write</access>
                    <resetValue>0x00000000</resetValue>
                    <resetMask>0xffffffff</resetMask>
                </register>
            </registers>
        </peripheral>
        <peripheral>
            <name>GPT320_NS</name>
            <description>General PWM 32-bit Timer 0</description>
            <baseAddress>0x50322000</baseAddress>
            <addressBlock>
                <offset>0x00</offset>
                <size>68</size>
                <usage>registers</usage>
            </addressBlock>
            <addressBlock>
                <offset>0x48</offset>
                <size>36</size>
                <usage>registers</usage>
            </addressBlock>
            <addressBlock>
                <offset>0x70</offset>
                <size>32</size>
                <usage>registers</usage>
            </addressBlock>
            <addressBlock>
                <offset>0xA4</offset>
                <size>4</size>
                <usage>registers</usage>
            </addressBlock>
            <addressBlock>
                <offset>0xB8</offset>
                <size>8</size>
                <usage>registers</usage>
            </addressBlock>
            <addressBlock>
                <offset>0xD0</offset>
                <size>8</size>
                <usage>registers</usage>
            </addressBlock>
            <registers>
                <register>
                    <name>GTWP</name>
                    <description>General PWM Timer Write-Protection Register</description>
                    <addressOffset>0x00</addressOffset>
                    <size>32</size>
                    <access>read-write</access>
                    <resetValue>0x00000000</resetValue>
                    <resetMask>0xffffffff</resetMask>
                    <fields>
                        <field>
                            <name>WP</name>
                            <description>Register Write Disable</description>
                            <lsb>0</lsb>
                            <msb>0</msb>
                            <access>read-write</access>
                            <enumeratedValues>
                                <enumeratedValue>
                                    <name>0</name>
                                    <description>Write to the register enabled</description>
                                    <value>#0</value>
                                </enumeratedValue>
                                <enumeratedValue>
                                    <name>1</name>
                                    <description>Write to the register disabled</description>
                                    <value>#1</value>
                                </enumeratedValue>
                            </enumeratedValues>
                        </field>
                        <field>
                            <name>STRWP</name>
                            <description>GTSTR.CSTRT Bit Write Disable</description>
                            <lsb>1</lsb>
                            <msb>1</msb>
                            <access>read-write</access>
                            <enumeratedValues>
                                <enumeratedValue>
                                    <name>0</name>
                                    <description>Write to the bit is enabled</description>
                                    <value>#0</value>
                                </enumeratedValue>
                                <enumeratedValue>
                                    <name>1</name>
                                    <description>Write to the bit is disabled</description>
                                    <value>#1</value>
                                </enumeratedValue>
                            </enumeratedValues>
                        </field>
                        <field>
                            <name>STPWP</name>
                            <description>GTSTP.CSTOP Bit Write Disable</description>
                            <lsb>2</lsb>
                            <msb>2</msb>
                            <access>read-write</access>
                            <enumeratedValues>
                                <enumeratedValue>
                                    <name>0</name>
                                    <description>Write to the bit is enabled</description>
                                    <value>#0</value>
                                </enumeratedValue>
                                <enumeratedValue>
                                    <name>1</name>
                                    <description>Write to the bit is disabled</description>
                                    <value>#1</value>
                                </enumeratedValue>
                            </enumeratedValues>
                        </field>
                        <field>
                            <name>CLRWP</name>
                            <description>GTCLR.CCLR Bit Write Disable</description>
                            <lsb>3</lsb>
                            <msb>3</msb>
                            <access>read-write</access>
                            <enumeratedValues>
                                <enumeratedValue>
                                    <name>0</name>
                                    <description>Write to the bit is enabled</description>
                                    <value>#0</value>
                                </enumeratedValue>
                                <enumeratedValue>
                                    <name>1</name>
                                    <description>Write to the bit is disabled</description>
                                    <value>#1</value>
                                </enumeratedValue>
                            </enumeratedValues>
                        </field>
                        <field>
                            <name>CMNWP</name>
                            <description>Common Register Write Disabled</description>
                            <lsb>4</lsb>
                            <msb>4</msb>
                            <access>read-write</access>
                            <enumeratedValues>
                                <enumeratedValue>
                                    <name>0</name>
                                    <description>Write to the register is enabled</description>
                                    <value>#0</value>
                                </enumeratedValue>
                                <enumeratedValue>
                                    <name>1</name>
                                    <description>Write to the register is disabled</description>
                                    <value>#1</value>
                                </enumeratedValue>
                            </enumeratedValues>
                        </field>
                        <field>
                            <name>PRKEY</name>
                            <description>GTWP Key Code</description>
                            <lsb>8</lsb>
                            <msb>15</msb>
                            <access>write-only</access>
                        </field>
                    </fields>
                </register>
                <register>
                    <name>GTSTR</name>
                    <description>General PWM Timer Software Start Register</description>
                    <addressOffset>0x04</addressOffset>
                    <size>32</size>
                    <access>read-write</access>
                    <resetValue>0x00000000</resetValue>
                    <resetMask>0xffffffff</resetMask>
                    <fields>
                        <field>
                            <name>CSTRT0</name>
                            <description>Channel n GTCNT Count Start (n : the same as bit position value)</description>
                            <lsb>0</lsb>
                            <msb>0</msb>
                            <access>read-write</access>
                            <enumeratedValues>
                                <enumeratedValue>
                                    <name>0</name>
                                    <description>GTCNT counter not start</description>
                                    <value>#0</value>
                                </enumeratedValue>
                                <enumeratedValue>
                                    <name>1</name>
                                    <description>GTCNT counter start</description>
                                    <value>#1</value>
                                </enumeratedValue>
                            </enumeratedValues>
                        </field>
                        <field>
                            <name>CSTRT1</name>
                            <description>Channel n GTCNT Count Start (n : the same as bit position value)</description>
                            <lsb>1</lsb>
                            <msb>1</msb>
                            <access>read-write</access>
                            <enumeratedValues>
                                <enumeratedValue>
                                    <name>0</name>
                                    <description>GTCNT counter not start</description>
                                    <value>#0</value>
                                </enumeratedValue>
                                <enumeratedValue>
                                    <name>1</name>
                                    <description>GTCNT counter start</description>
                                    <value>#1</value>
                                </enumeratedValue>
                            </enumeratedValues>
                        </field>
                        <field>
                            <name>CSTRT2</name>
                            <description>Channel n GTCNT Count Start (n : the same as bit position value)</description>
                            <lsb>2</lsb>
                            <msb>2</msb>
                            <access>read-write</access>
                            <enumeratedValues>
                                <enumeratedValue>
                                    <name>0</name>
                                    <description>GTCNT counter not start</description>
                                    <value>#0</value>
                                </enumeratedValue>
                                <enumeratedValue>
                                    <name>1</name>
                                    <description>GTCNT counter start</description>
                                    <value>#1</value>
                                </enumeratedValue>
                            </enumeratedValues>
                        </field>
                        <field>
                            <name>CSTRT3</name>
                            <description>Channel n GTCNT Count Start (n : the same as bit position value)</description>
                            <lsb>3</lsb>
                            <msb>3</msb>
                            <access>read-write</access>
                            <enumeratedValues>
                                <enumeratedValue>
                                    <name>0</name>
                                    <description>GTCNT counter not start</description>
                                    <value>#0</value>
                                </enumeratedValue>
                                <enumeratedValue>
                                    <name>1</name>
                                    <description>GTCNT counter start</description>
                                    <value>#1</value>
                                </enumeratedValue>
                            </enumeratedValues>
                        </field>
                        <field>
                            <name>CSTRT4</name>
                            <description>Channel n GTCNT Count Start (n : the same as bit position value)</description>
                            <lsb>4</lsb>
                            <msb>4</msb>
                            <access>read-write</access>
                            <enumeratedValues>
                                <enumeratedValue>
                                    <name>0</name>
                                    <description>GTCNT counter not start</description>
                                    <value>#0</value>
                                </enumeratedValue>
                                <enumeratedValue>
                                    <name>1</name>
                                    <description>GTCNT counter start</description>
                                    <value>#1</value>
                                </enumeratedValue>
                            </enumeratedValues>
                        </field>
                        <field>
                            <name>CSTRT5</name>
                            <description>Channel n GTCNT Count Start (n : the same as bit position value)</description>
                            <lsb>5</lsb>
                            <msb>5</msb>
                            <access>read-write</access>
                            <enumeratedValues>
                                <enumeratedValue>
                                    <name>0</name>
                                    <description>GTCNT counter not start</description>
                                    <value>#0</value>
                                </enumeratedValue>
                                <enumeratedValue>
                                    <name>1</name>
                                    <description>GTCNT counter start</description>
                                    <value>#1</value>
                                </enumeratedValue>
                            </enumeratedValues>
                        </field>
                        <field>
                            <name>CSTRT6</name>
                            <description>Channel n GTCNT Count Start (n : the same as bit position value)</description>
                            <lsb>6</lsb>
                            <msb>6</msb>
                            <access>read-write</access>
                            <enumeratedValues>
                                <enumeratedValue>
                                    <name>0</name>
                                    <description>GTCNT counter not start</description>
                                    <value>#0</value>
                                </enumeratedValue>
                                <enumeratedValue>
                                    <name>1</name>
                                    <description>GTCNT counter start</description>
                                    <value>#1</value>
                                </enumeratedValue>
                            </enumeratedValues>
                        </field>
                        <field>
                            <name>CSTRT7</name>
                            <description>Channel n GTCNT Count Start (n : the same as bit position value)</description>
                            <lsb>7</lsb>
                            <msb>7</msb>
                            <access>read-write</access>
                            <enumeratedValues>
                                <enumeratedValue>
                                    <name>0</name>
                                    <description>GTCNT counter not start</description>
                                    <value>#0</value>
                                </enumeratedValue>
                                <enumeratedValue>
                                    <name>1</name>
                                    <description>GTCNT counter start</description>
                                    <value>#1</value>
                                </enumeratedValue>
                            </enumeratedValues>
                        </field>
                        <field>
                            <name>CSTRT8</name>
                            <description>Channel n GTCNT Count Start (n : the same as bit position value)</description>
                            <lsb>8</lsb>
                            <msb>8</msb>
                            <access>read-write</access>
                            <enumeratedValues>
                                <enumeratedValue>
                                    <name>0</name>
                                    <description>GTCNT counter not start</description>
                                    <value>#0</value>
                                </enumeratedValue>
                                <enumeratedValue>
                                    <name>1</name>
                                    <description>GTCNT counter start</description>
                                    <value>#1</value>
                                </enumeratedValue>
                            </enumeratedValues>
                        </field>
                        <field>
                            <name>CSTRT9</name>
                            <description>Channel n GTCNT Count Start (n : the same as bit position value)</description>
                            <lsb>9</lsb>
                            <msb>9</msb>
                            <access>read-write</access>
                            <enumeratedValues>
                                <enumeratedValue>
                                    <name>0</name>
                                    <description>GTCNT counter not start</description>
                                    <value>#0</value>
                                </enumeratedValue>
                                <enumeratedValue>
                                    <name>1</name>
                                    <description>GTCNT counter start</description>
                                    <value>#1</value>
                                </enumeratedValue>
                            </enumeratedValues>
                        </field>
                    </fields>
                </register>
                <register>
                    <name>GTSTP</name>
                    <description>General PWM Timer Software Stop Register</description>
                    <addressOffset>0x08</addressOffset>
                    <size>32</size>
                    <access>read-write</access>
                    <resetValue>0xffffffff</resetValue>
                    <resetMask>0xffffffff</resetMask>
                    <fields>
                        <field>
                            <name>CSTOP0</name>
                            <description>Channel n GTCNT Count Stop (n : the same as bit position value)</description>
                            <lsb>0</lsb>
                            <msb>0</msb>
                            <access>read-write</access>
                            <enumeratedValues>
                                <enumeratedValue>
                                    <name>0</name>
                                    <description>GTCNT counter not stop</description>
                                    <value>#0</value>
                                </enumeratedValue>
                                <enumeratedValue>
                                    <name>1</name>
                                    <description>GTCNT counter stop</description>
                                    <value>#1</value>
                                </enumeratedValue>
                            </enumeratedValues>
                        </field>
                        <field>
                            <name>CSTOP1</name>
                            <description>Channel n GTCNT Count Stop (n : the same as bit position value)</description>
                            <lsb>1</lsb>
                            <msb>1</msb>
                            <access>read-write</access>
                            <enumeratedValues>
                                <enumeratedValue>
                                    <name>0</name>
                                    <description>GTCNT counter not stop</description>
                                    <value>#0</value>
                                </enumeratedValue>
                                <enumeratedValue>
                                    <name>1</name>
                                    <description>GTCNT counter stop</description>
                                    <value>#1</value>
                                </enumeratedValue>
                            </enumeratedValues>
                        </field>
                        <field>
                            <name>CSTOP2</name>
                            <description>Channel n GTCNT Count Stop (n : the same as bit position value)</description>
                            <lsb>2</lsb>
                            <msb>2</msb>
                            <access>read-write</access>
                            <enumeratedValues>
                                <enumeratedValue>
                                    <name>0</name>
                                    <description>GTCNT counter not stop</description>
                                    <value>#0</value>
                                </enumeratedValue>
                                <enumeratedValue>
                                    <name>1</name>
                                    <description>GTCNT counter stop</description>
                                    <value>#1</value>
                                </enumeratedValue>
                            </enumeratedValues>
                        </field>
                        <field>
                            <name>CSTOP3</name>
                            <description>Channel n GTCNT Count Stop (n : the same as bit position value)</description>
                            <lsb>3</lsb>
                            <msb>3</msb>
                            <access>read-write</access>
                            <enumeratedValues>
                                <enumeratedValue>
                                    <name>0</name>
                                    <description>GTCNT counter not stop</description>
                                    <value>#0</value>
                                </enumeratedValue>
                                <enumeratedValue>
                                    <name>1</name>
                                    <description>GTCNT counter stop</description>
                                    <value>#1</value>
                                </enumeratedValue>
                            </enumeratedValues>
                        </field>
                        <field>
                            <name>CSTOP4</name>
                            <description>Channel n GTCNT Count Stop (n : the same as bit position value)</description>
                            <lsb>4</lsb>
                            <msb>4</msb>
                            <access>read-write</access>
                            <enumeratedValues>
                                <enumeratedValue>
                                    <name>0</name>
                                    <description>GTCNT counter not stop</description>
                                    <value>#0</value>
                                </enumeratedValue>
                                <enumeratedValue>
                                    <name>1</name>
                                    <description>GTCNT counter stop</description>
                                    <value>#1</value>
                                </enumeratedValue>
                            </enumeratedValues>
                        </field>
                        <field>
                            <name>CSTOP5</name>
                            <description>Channel n GTCNT Count Stop (n : the same as bit position value)</description>
                            <lsb>5</lsb>
                            <msb>5</msb>
                            <access>read-write</access>
                            <enumeratedValues>
                                <enumeratedValue>
                                    <name>0</name>
                                    <description>GTCNT counter not stop</description>
                                    <value>#0</value>
                                </enumeratedValue>
                                <enumeratedValue>
                                    <name>1</name>
                                    <description>GTCNT counter stop</description>
                                    <value>#1</value>
                                </enumeratedValue>
                            </enumeratedValues>
                        </field>
                        <field>
                            <name>CSTOP6</name>
                            <description>Channel n GTCNT Count Stop (n : the same as bit position value)</description>
                            <lsb>6</lsb>
                            <msb>6</msb>
                            <access>read-write</access>
                            <enumeratedValues>
                                <enumeratedValue>
                                    <name>0</name>
                                    <description>GTCNT counter not stop</description>
                                    <value>#0</value>
                                </enumeratedValue>
                                <enumeratedValue>
                                    <name>1</name>
                                    <description>GTCNT counter stop</description>
                                    <value>#1</value>
                                </enumeratedValue>
                            </enumeratedValues>
                        </field>
                        <field>
                            <name>CSTOP7</name>
                            <description>Channel n GTCNT Count Stop (n : the same as bit position value)</description>
                            <lsb>7</lsb>
                            <msb>7</msb>
                            <access>read-write</access>
                            <enumeratedValues>
                                <enumeratedValue>
                                    <name>0</name>
                                    <description>GTCNT counter not stop</description>
                                    <value>#0</value>
                                </enumeratedValue>
                                <enumeratedValue>
                                    <name>1</name>
                                    <description>GTCNT counter stop</description>
                                    <value>#1</value>
                                </enumeratedValue>
                            </enumeratedValues>
                        </field>
                        <field>
                            <name>CSTOP8</name>
                            <description>Channel n GTCNT Count Stop (n : the same as bit position value)</description>
                            <lsb>8</lsb>
                            <msb>8</msb>
                            <access>read-write</access>
                            <enumeratedValues>
                                <enumeratedValue>
                                    <name>0</name>
                                    <description>GTCNT counter not stop</description>
                                    <value>#0</value>
                                </enumeratedValue>
                                <enumeratedValue>
                                    <name>1</name>
                                    <description>GTCNT counter stop</description>
                                    <value>#1</value>
                                </enumeratedValue>
                            </enumeratedValues>
                        </field>
                        <field>
                            <name>CSTOP9</name>
                            <description>Channel n GTCNT Count Stop (n : the same as bit position value)</description>
                            <lsb>9</lsb>
                            <msb>9</msb>
                            <access>read-write</access>
                            <enumeratedValues>
                                <enumeratedValue>
                                    <name>0</name>
                                    <description>GTCNT counter not stop</description>
                                    <value>#0</value>
                                </enumeratedValue>
                                <enumeratedValue>
                                    <name>1</name>
                                    <description>GTCNT counter stop</description>
                                    <value>#1</value>
                                </enumeratedValue>
                            </enumeratedValues>
                        </field>
                    </fields>
                </register>
                <register>
                    <name>GTCLR</name>
                    <description>General PWM Timer Software Clear Register</description>
                    <addressOffset>0x0C</addressOffset>
                    <size>32</size>
                    <access>write-only</access>
                    <resetValue>0x00000000</resetValue>
                    <resetMask>0xffffffff</resetMask>
                    <fields>
                        <field>
                            <name>CCLR0</name>
                            <description>Channel n GTCNT Count Clear (n : the same as bit position value)</description>
                            <lsb>0</lsb>
                            <msb>0</msb>
                            <access>write-only</access>
                            <enumeratedValues>
                                <enumeratedValue>
                                    <name>0</name>
                                    <description>GTCNT counter is not cleared</description>
                                    <value>#0</value>
                                </enumeratedValue>
                                <enumeratedValue>
                                    <name>1</name>
                                    <description>GTCNT counter is cleared</description>
                                    <value>#1</value>
                                </enumeratedValue>
                            </enumeratedValues>
                        </field>
                        <field>
                            <name>CCLR1</name>
                            <description>Channel n GTCNT Count Clear (n : the same as bit position value)</description>
                            <lsb>1</lsb>
                            <msb>1</msb>
                            <access>write-only</access>
                            <enumeratedValues>
                                <enumeratedValue>
                                    <name>0</name>
                                    <description>GTCNT counter is not cleared</description>
                                    <value>#0</value>
                                </enumeratedValue>
                                <enumeratedValue>
                                    <name>1</name>
                                    <description>GTCNT counter is cleared</description>
                                    <value>#1</value>
                                </enumeratedValue>
                            </enumeratedValues>
                        </field>
                        <field>
                            <name>CCLR2</name>
                            <description>Channel n GTCNT Count Clear (n : the same as bit position value)</description>
                            <lsb>2</lsb>
                            <msb>2</msb>
                            <access>write-only</access>
                            <enumeratedValues>
                                <enumeratedValue>
                                    <name>0</name>
                                    <description>GTCNT counter is not cleared</description>
                                    <value>#0</value>
                                </enumeratedValue>
                                <enumeratedValue>
                                    <name>1</name>
                                    <description>GTCNT counter is cleared</description>
                                    <value>#1</value>
                                </enumeratedValue>
                            </enumeratedValues>
                        </field>
                        <field>
                            <name>CCLR3</name>
                            <description>Channel n GTCNT Count Clear (n : the same as bit position value)</description>
                            <lsb>3</lsb>
                            <msb>3</msb>
                            <access>write-only</access>
                            <enumeratedValues>
                                <enumeratedValue>
                                    <name>0</name>
                                    <description>GTCNT counter is not cleared</description>
                                    <value>#0</value>
                                </enumeratedValue>
                                <enumeratedValue>
                                    <name>1</name>
                                    <description>GTCNT counter is cleared</description>
                                    <value>#1</value>
                                </enumeratedValue>
                            </enumeratedValues>
                        </field>
                        <field>
                            <name>CCLR4</name>
                            <description>Channel n GTCNT Count Clear (n : the same as bit position value)</description>
                            <lsb>4</lsb>
                            <msb>4</msb>
                            <access>write-only</access>
                            <enumeratedValues>
                                <enumeratedValue>
                                    <name>0</name>
                                    <description>GTCNT counter is not cleared</description>
                                    <value>#0</value>
                                </enumeratedValue>
                                <enumeratedValue>
                                    <name>1</name>
                                    <description>GTCNT counter is cleared</description>
                                    <value>#1</value>
                                </enumeratedValue>
                            </enumeratedValues>
                        </field>
                        <field>
                            <name>CCLR5</name>
                            <description>Channel n GTCNT Count Clear (n : the same as bit position value)</description>
                            <lsb>5</lsb>
                            <msb>5</msb>
                            <access>write-only</access>
                            <enumeratedValues>
                                <enumeratedValue>
                                    <name>0</name>
                                    <description>GTCNT counter is not cleared</description>
                                    <value>#0</value>
                                </enumeratedValue>
                                <enumeratedValue>
                                    <name>1</name>
                                    <description>GTCNT counter is cleared</description>
                                    <value>#1</value>
                                </enumeratedValue>
                            </enumeratedValues>
                        </field>
                        <field>
                            <name>CCLR6</name>
                            <description>Channel n GTCNT Count Clear (n : the same as bit position value)</description>
                            <lsb>6</lsb>
                            <msb>6</msb>
                            <access>write-only</access>
                            <enumeratedValues>
                                <enumeratedValue>
                                    <name>0</name>
                                    <description>GTCNT counter is not cleared</description>
                                    <value>#0</value>
                                </enumeratedValue>
                                <enumeratedValue>
                                    <name>1</name>
                                    <description>GTCNT counter is cleared</description>
                                    <value>#1</value>
                                </enumeratedValue>
                            </enumeratedValues>
                        </field>
                        <field>
                            <name>CCLR7</name>
                            <description>Channel n GTCNT Count Clear (n : the same as bit position value)</description>
                            <lsb>7</lsb>
                            <msb>7</msb>
                            <access>write-only</access>
                            <enumeratedValues>
                                <enumeratedValue>
                                    <name>0</name>
                                    <description>GTCNT counter is not cleared</description>
                                    <value>#0</value>
                                </enumeratedValue>
                                <enumeratedValue>
                                    <name>1</name>
                                    <description>GTCNT counter is cleared</description>
                                    <value>#1</value>
                                </enumeratedValue>
                            </enumeratedValues>
                        </field>
                        <field>
                            <name>CCLR8</name>
                            <description>Channel n GTCNT Count Clear (n : the same as bit position value)</description>
                            <lsb>8</lsb>
                            <msb>8</msb>
                            <access>write-only</access>
                            <enumeratedValues>
                                <enumeratedValue>
                                    <name>0</name>
                                    <description>GTCNT counter is not cleared</description>
                                    <value>#0</value>
                                </enumeratedValue>
                                <enumeratedValue>
                                    <name>1</name>
                                    <description>GTCNT counter is cleared</description>
                                    <value>#1</value>
                                </enumeratedValue>
                            </enumeratedValues>
                        </field>
                        <field>
                            <name>CCLR9</name>
                            <description>Channel n GTCNT Count Clear (n : the same as bit position value)</description>
                            <lsb>9</lsb>
                            <msb>9</msb>
                            <access>write-only</access>
                            <enumeratedValues>
                                <enumeratedValue>
                                    <name>0</name>
                                    <description>GTCNT counter is not cleared</description>
                                    <value>#0</value>
                                </enumeratedValue>
                                <enumeratedValue>
                                    <name>1</name>
                                    <description>GTCNT counter is cleared</description>
                                    <value>#1</value>
                                </enumeratedValue>
                            </enumeratedValues>
                        </field>
                    </fields>
                </register>
                <register>
                    <name>GTSSR</name>
                    <description>General PWM Timer Start Source Select Register</description>
                    <addressOffset>0x10</addressOffset>
                    <size>32</size>
                    <access>read-write</access>
                    <resetValue>0x00000000</resetValue>
                    <resetMask>0xffffffff</resetMask>
                    <fields>
                        <field>
                            <name>SSGTRGAR</name>
                            <description>GTETRGA Pin Rising Input Source Counter Start Enable</description>
                            <lsb>0</lsb>
                            <msb>0</msb>
                            <access>read-write</access>
                            <enumeratedValues>
                                <enumeratedValue>
                                    <name>0</name>
                                    <description>Counter start disabled on the rising edge of GTETRGA input</description>
                                    <value>#0</value>
                                </enumeratedValue>
                                <enumeratedValue>
                                    <name>1</name>
                                    <description>Counter start enabled on the rising edge of GTETRGA input</description>
                                    <value>#1</value>
                                </enumeratedValue>
                            </enumeratedValues>
                        </field>
                        <field>
                            <name>SSGTRGAF</name>
                            <description>GTETRGA Pin Falling Input Source Counter Start Enable</description>
                            <lsb>1</lsb>
                            <msb>1</msb>
                            <access>read-write</access>
                            <enumeratedValues>
                                <enumeratedValue>
                                    <name>0</name>
                                    <description>Counter start disabled on the falling edge of GTETRGA input</description>
                                    <value>#0</value>
                                </enumeratedValue>
                                <enumeratedValue>
                                    <name>1</name>
                                    <description>Counter start enabled on the falling edge of GTETRGA input</description>
                                    <value>#1</value>
                                </enumeratedValue>
                            </enumeratedValues>
                        </field>
                        <field>
                            <name>SSGTRGBR</name>
                            <description>GTETRGB Pin Rising Input Source Counter Start Enable</description>
                            <lsb>2</lsb>
                            <msb>2</msb>
                            <access>read-write</access>
                            <enumeratedValues>
                                <enumeratedValue>
                                    <name>0</name>
                                    <description>Counter start disabled on the rising edge of GTETRGB input</description>
                                    <value>#0</value>
                                </enumeratedValue>
                                <enumeratedValue>
                                    <name>1</name>
                                    <description>Counter start enabled on the rising edge of GTETRGB input</description>
                                    <value>#1</value>
                                </enumeratedValue>
                            </enumeratedValues>
                        </field>
                        <field>
                            <name>SSGTRGBF</name>
                            <description>GTETRGB Pin Falling Input Source Counter Start Enable</description>
                            <lsb>3</lsb>
                            <msb>3</msb>
                            <access>read-write</access>
                            <enumeratedValues>
                                <enumeratedValue>
                                    <name>0</name>
                                    <description>Counter start disabled on the falling edge of GTETRGB input</description>
                                    <value>#0</value>
                                </enumeratedValue>
                                <enumeratedValue>
                                    <name>1</name>
                                    <description>Counter start enabled on the falling edge of GTETRGB input</description>
                                    <value>#1</value>
                                </enumeratedValue>
                            </enumeratedValues>
                        </field>
                        <field>
                            <name>SSGTRGCR</name>
                            <description>GTETRGC Pin Rising Input Source Counter Start Enable</description>
                            <lsb>4</lsb>
                            <msb>4</msb>
                            <access>read-write</access>
                            <enumeratedValues>
                                <enumeratedValue>
                                    <name>0</name>
                                    <description>Counter start disabled on the rising edge of GTETRGC input</description>
                                    <value>#0</value>
                                </enumeratedValue>
                                <enumeratedValue>
                                    <name>1</name>
                                    <description>Counter start enabled on the rising edge of GTETRGC input</description>
                                    <value>#1</value>
                                </enumeratedValue>
                            </enumeratedValues>
                        </field>
                        <field>
                            <name>SSGTRGCF</name>
                            <description>GTETRGC Pin Falling Input Source Counter Start Enable</description>
                            <lsb>5</lsb>
                            <msb>5</msb>
                            <access>read-write</access>
                            <enumeratedValues>
                                <enumeratedValue>
                                    <name>0</name>
                                    <description>Counter start disabled on the falling edge of GTETRGC input</description>
                                    <value>#0</value>
                                </enumeratedValue>
                                <enumeratedValue>
                                    <name>1</name>
                                    <description>Counter start enabled on the falling edge of GTETRGC input</description>
                                    <value>#1</value>
                                </enumeratedValue>
                            </enumeratedValues>
                        </field>
                        <field>
                            <name>SSGTRGDR</name>
                            <description>GTETRGD Pin Rising Input Source Counter Start Enable</description>
                            <lsb>6</lsb>
                            <msb>6</msb>
                            <access>read-write</access>
                            <enumeratedValues>
                                <enumeratedValue>
                                    <name>0</name>
                                    <description>Counter start disabled on the rising edge of GTETRGD input</description>
                                    <value>#0</value>
                                </enumeratedValue>
                                <enumeratedValue>
                                    <name>1</name>
                                    <description>Counter start enabled on the rising edge of GTETRGD input</description>
                                    <value>#1</value>
                                </enumeratedValue>
                            </enumeratedValues>
                        </field>
                        <field>
                            <name>SSGTRGDF</name>
                            <description>GTETRGD Pin Falling Input Source Counter Start Enable</description>
                            <lsb>7</lsb>
                            <msb>7</msb>
                            <access>read-write</access>
                            <enumeratedValues>
                                <enumeratedValue>
                                    <name>0</name>
                                    <description>Counter start disabled on the falling edge of GTETRGD input</description>
                                    <value>#0</value>
                                </enumeratedValue>
                                <enumeratedValue>
                                    <name>1</name>
                                    <description>Counter start enabled on the falling edge of GTETRGD input</description>
                                    <value>#1</value>
                                </enumeratedValue>
                            </enumeratedValues>
                        </field>
                        <field>
                            <name>SSCARBL</name>
                            <description>GTIOCnA Pin Rising Input during GTIOCnB Value Low Source Counter Start Enable</description>
                            <lsb>8</lsb>
                            <msb>8</msb>
                            <access>read-write</access>
                            <enumeratedValues>
                                <enumeratedValue>
                                    <name>0</name>
                                    <description>Counter start disabled on the rising edge of GTIOCnA input when GTIOCnB input is 0</description>
                                    <value>#0</value>
                                </enumeratedValue>
                                <enumeratedValue>
                                    <name>1</name>
                                    <description>Counter start enabled on the rising edge of GTIOCnA input when GTIOCnB input is 0</description>
                                    <value>#1</value>
                                </enumeratedValue>
                            </enumeratedValues>
                        </field>
                        <field>
                            <name>SSCARBH</name>
                            <description>GTIOCnA Pin Rising Input during GTIOCnB Value High Source Counter Start Enable</description>
                            <lsb>9</lsb>
                            <msb>9</msb>
                            <access>read-write</access>
                            <enumeratedValues>
                                <enumeratedValue>
                                    <name>0</name>
                                    <description>Counter start disabled on the rising edge of GTIOCnA input when GTIOCnB input is 1</description>
                                    <value>#0</value>
                                </enumeratedValue>
                                <enumeratedValue>
                                    <name>1</name>
                                    <description>Counter start enabled on the rising edge of GTIOCnA input when GTIOCnB input is 1</description>
                                    <value>#1</value>
                                </enumeratedValue>
                            </enumeratedValues>
                        </field>
                        <field>
                            <name>SSCAFBL</name>
                            <description>GTIOCnA Pin Falling Input during GTIOCnB Value Low Source Counter Start Enable</description>
                            <lsb>10</lsb>
                            <msb>10</msb>
                            <access>read-write</access>
                            <enumeratedValues>
                                <enumeratedValue>
                                    <name>0</name>
                                    <description>Counter start disabled on the falling edge of GTIOCnA input when GTIOCnB input is 0</description>
                                    <value>#0</value>
                                </enumeratedValue>
                                <enumeratedValue>
                                    <name>1</name>
                                    <description>Counter start enabled on the falling edge of GTIOCnA input when GTIOCnB input is 0</description>
                                    <value>#1</value>
                                </enumeratedValue>
                            </enumeratedValues>
                        </field>
                        <field>
                            <name>SSCAFBH</name>
                            <description>GTIOCnA Pin Falling Input during GTIOCnB Value High Source Counter Start Enable</description>
                            <lsb>11</lsb>
                            <msb>11</msb>
                            <access>read-write</access>
                            <enumeratedValues>
                                <enumeratedValue>
                                    <name>0</name>
                                    <description>Counter start disabled on the falling edge of GTIOCnA input when GTIOCnB input is 1</description>
                                    <value>#0</value>
                                </enumeratedValue>
                                <enumeratedValue>
                                    <name>1</name>
                                    <description>Counter start enabled on the falling edge of GTIOCnA input when GTIOCnB input is 1</description>
                                    <value>#1</value>
                                </enumeratedValue>
                            </enumeratedValues>
                        </field>
                        <field>
                            <name>SSCBRAL</name>
                            <description>GTIOCnB Pin Rising Input during GTIOCnA Value Low Source Counter Start Enable</description>
                            <lsb>12</lsb>
                            <msb>12</msb>
                            <access>read-write</access>
                            <enumeratedValues>
                                <enumeratedValue>
                                    <name>0</name>
                                    <description>Counter start disabled on the rising edge of GTIOCnB input when GTIOCnA input is 0</description>
                                    <value>#0</value>
                                </enumeratedValue>
                                <enumeratedValue>
                                    <name>1</name>
                                    <description>Counter start enabled on the rising edge of GTIOCnB input when GTIOCnA input is 0</description>
                                    <value>#1</value>
                                </enumeratedValue>
                            </enumeratedValues>
                        </field>
                        <field>
                            <name>SSCBRAH</name>
                            <description>GTIOCnB Pin Rising Input during GTIOCnA Value High Source Counter Start Enable</description>
                            <lsb>13</lsb>
                            <msb>13</msb>
                            <access>read-write</access>
                            <enumeratedValues>
                                <enumeratedValue>
                                    <name>0</name>
                                    <description>Counter start disabled on the rising edge of GTIOCnB input when GTIOCnA input is 1</description>
                                    <value>#0</value>
                                </enumeratedValue>
                                <enumeratedValue>
                                    <name>1</name>
                                    <description>Counter start enabled on the rising edge of GTIOCnB input when GTIOCnA input is 1</description>
                                    <value>#1</value>
                                </enumeratedValue>
                            </enumeratedValues>
                        </field>
                        <field>
                            <name>SSCBFAL</name>
                            <description>GTIOCnB Pin Falling Input during GTIOCnA Value Low Source Counter Start Enable</description>
                            <lsb>14</lsb>
                            <msb>14</msb>
                            <access>read-write</access>
                            <enumeratedValues>
                                <enumeratedValue>
                                    <name>0</name>
                                    <description>Counter start disabled on the falling edge of GTIOCnB input when GTIOCnA input is 0</description>
                                    <value>#0</value>
                                </enumeratedValue>
                                <enumeratedValue>
                                    <name>1</name>
                                    <description>Counter start enabled on the falling edge of GTIOCnB input when GTIOCnA input is 0</description>
                                    <value>#1</value>
                                </enumeratedValue>
                            </enumeratedValues>
                        </field>
                        <field>
                            <name>SSCBFAH</name>
                            <description>GTIOCnB Pin Falling Input during GTIOCnA Value High Source Counter Start Enable</description>
                            <lsb>15</lsb>
                            <msb>15</msb>
                            <access>read-write</access>
                            <enumeratedValues>
                                <enumeratedValue>
                                    <name>0</name>
                                    <description>Counter start disabled on the falling edge of GTIOCnB input when GTIOCnA input is 1</description>
                                    <value>#0</value>
                                </enumeratedValue>
                                <enumeratedValue>
                                    <name>1</name>
                                    <description>Counter start enabled on the falling edge of GTIOCnB input when GTIOCnA input is 1</description>
                                    <value>#1</value>
                                </enumeratedValue>
                            </enumeratedValues>
                        </field>
                        <field>
                            <name>SSELCA</name>
                            <description>ELC_GPTA Event Source Counter Start Enable</description>
                            <lsb>16</lsb>
                            <msb>16</msb>
                            <access>read-write</access>
                            <enumeratedValues>
                                <enumeratedValue>
                                    <name>0</name>
                                    <description>Counter start disabled at the ELC_GPTA input</description>
                                    <value>#0</value>
                                </enumeratedValue>
                                <enumeratedValue>
                                    <name>1</name>
                                    <description>Counter start enabled at the ELC_GPTA input</description>
                                    <value>#1</value>
                                </enumeratedValue>
                            </enumeratedValues>
                        </field>
                        <field>
                            <name>SSELCB</name>
                            <description>ELC_GPTB Event Source Counter Start Enable</description>
                            <lsb>17</lsb>
                            <msb>17</msb>
                            <access>read-write</access>
                            <enumeratedValues>
                                <enumeratedValue>
                                    <name>0</name>
                                    <description>Counter start disabled at the ELC_GPTB input</description>
                                    <value>#0</value>
                                </enumeratedValue>
                                <enumeratedValue>
                                    <name>1</name>
                                    <description>Counter start enabled at the ELC_GPTB input</description>
                                    <value>#1</value>
                                </enumeratedValue>
                            </enumeratedValues>
                        </field>
                        <field>
                            <name>SSELCC</name>
                            <description>ELC_GPTC Event Source Counter Start Enable</description>
                            <lsb>18</lsb>
                            <msb>18</msb>
                            <access>read-write</access>
                            <enumeratedValues>
                                <enumeratedValue>
                                    <name>0</name>
                                    <description>Counter start disabled at the ELC_GPTC input</description>
                                    <value>#0</value>
                                </enumeratedValue>
                                <enumeratedValue>
                                    <name>1</name>
                                    <description>Counter start enabled at the ELC_GPTC input</description>
                                    <value>#1</value>
                                </enumeratedValue>
                            </enumeratedValues>
                        </field>
                        <field>
                            <name>SSELCD</name>
                            <description>ELC_GPTD Event Source Counter Start Enable</description>
                            <lsb>19</lsb>
                            <msb>19</msb>
                            <access>read-write</access>
                            <enumeratedValues>
                                <enumeratedValue>
                                    <name>0</name>
                                    <description>Counter start disabled at the ELC_GPTD input</description>
                                    <value>#0</value>
                                </enumeratedValue>
                                <enumeratedValue>
                                    <name>1</name>
                                    <description>Counter start enabled at the ELC_GPTD input</description>
                                    <value>#1</value>
                                </enumeratedValue>
                            </enumeratedValues>
                        </field>
                        <field>
                            <name>SSELCE</name>
                            <description>ELC_GPTE Event Source Counter Start Enable</description>
                            <lsb>20</lsb>
                            <msb>20</msb>
                            <access>read-write</access>
                            <enumeratedValues>
                                <enumeratedValue>
                                    <name>0</name>
                                    <description>Counter start disabled at the ELC_GPTE input</description>
                                    <value>#0</value>
                                </enumeratedValue>
                                <enumeratedValue>
                                    <name>1</name>
                                    <description>Counter start enabled at the ELC_GPTE input</description>
                                    <value>#1</value>
                                </enumeratedValue>
                            </enumeratedValues>
                        </field>
                        <field>
                            <name>SSELCF</name>
                            <description>ELC_GPTF Event Source Counter Start Enable</description>
                            <lsb>21</lsb>
                            <msb>21</msb>
                            <access>read-write</access>
                            <enumeratedValues>
                                <enumeratedValue>
                                    <name>0</name>
                                    <description>Counter start disabled at the ELC_GPTF input</description>
                                    <value>#0</value>
                                </enumeratedValue>
                                <enumeratedValue>
                                    <name>1</name>
                                    <description>Counter start enabled at the ELC_GPTF input</description>
                                    <value>#1</value>
                                </enumeratedValue>
                            </enumeratedValues>
                        </field>
                        <field>
                            <name>SSELCG</name>
                            <description>ELC_GPTG Event Source Counter Start Enable</description>
                            <lsb>22</lsb>
                            <msb>22</msb>
                            <access>read-write</access>
                            <enumeratedValues>
                                <enumeratedValue>
                                    <name>0</name>
                                    <description>Counter start disabled at the ELC_GPTG input</description>
                                    <value>#0</value>
                                </enumeratedValue>
                                <enumeratedValue>
                                    <name>1</name>
                                    <description>Counter start enabled at the ELC_GPTG input</description>
                                    <value>#1</value>
                                </enumeratedValue>
                            </enumeratedValues>
                        </field>
                        <field>
                            <name>SSELCH</name>
                            <description>ELC_GPTH Event Source Counter Start Enable</description>
                            <lsb>23</lsb>
                            <msb>23</msb>
                            <access>read-write</access>
                            <enumeratedValues>
                                <enumeratedValue>
                                    <name>0</name>
                                    <description>Counter start disabled at the ELC_GPTH input</description>
                                    <value>#0</value>
                                </enumeratedValue>
                                <enumeratedValue>
                                    <name>1</name>
                                    <description>Counter start enabled at the ELC_GPTH input</description>
                                    <value>#1</value>
                                </enumeratedValue>
                            </enumeratedValues>
                        </field>
                        <field>
                            <name>CSTRT</name>
                            <description>Software Source Counter Start Enable</description>
                            <lsb>31</lsb>
                            <msb>31</msb>
                            <access>read-write</access>
                            <enumeratedValues>
                                <enumeratedValue>
                                    <name>0</name>
                                    <description>Counter start disabled by the GTSTR register</description>
                                    <value>#0</value>
                                </enumeratedValue>
                                <enumeratedValue>
                                    <name>1</name>
                                    <description>Counter start enabled by the GTSTR register</description>
                                    <value>#1</value>
                                </enumeratedValue>
                            </enumeratedValues>
                        </field>
                    </fields>
                </register>
                <register>
                    <name>GTPSR</name>
                    <description>General PWM Timer Stop Source Select Register</description>
                    <addressOffset>0x14</addressOffset>
                    <size>32</size>
                    <access>read-write</access>
                    <resetValue>0x00000000</resetValue>
                    <resetMask>0xffffffff</resetMask>
                    <fields>
                        <field>
                            <name>PSGTRGAR</name>
                            <description>GTETRGA Pin Rising Input Source Counter Stop Enable</description>
                            <lsb>0</lsb>
                            <msb>0</msb>
                            <access>read-write</access>
                            <enumeratedValues>
                                <enumeratedValue>
                                    <name>0</name>
                                    <description>Counter stop disabled on the rising edge of GTETRGA input</description>
                                    <value>#0</value>
                                </enumeratedValue>
                                <enumeratedValue>
                                    <name>1</name>
                                    <description>Counter stop enabled on the rising edge of GTETRGA input</description>
                                    <value>#1</value>
                                </enumeratedValue>
                            </enumeratedValues>
                        </field>
                        <field>
                            <name>PSGTRGAF</name>
                            <description>GTETRGA Pin Falling Input Source Counter Stop Enable</description>
                            <lsb>1</lsb>
                            <msb>1</msb>
                            <access>read-write</access>
                            <enumeratedValues>
                                <enumeratedValue>
                                    <name>0</name>
                                    <description>Counter stop disabled on the falling edge of GTETRGA input</description>
                                    <value>#0</value>
                                </enumeratedValue>
                                <enumeratedValue>
                                    <name>1</name>
                                    <description>Counter stop enabled on the falling edge of GTETRGA input</description>
                                    <value>#1</value>
                                </enumeratedValue>
                            </enumeratedValues>
                        </field>
                        <field>
                            <name>PSGTRGBR</name>
                            <description>GTETRGB Pin Rising Input Source Counter Stop Enable</description>
                            <lsb>2</lsb>
                            <msb>2</msb>
                            <access>read-write</access>
                            <enumeratedValues>
                                <enumeratedValue>
                                    <name>0</name>
                                    <description>Counter stop disabled on the rising edge of GTETRGB input</description>
                                    <value>#0</value>
                                </enumeratedValue>
                                <enumeratedValue>
                                    <name>1</name>
                                    <description>Counter stop enabled on the rising edge of GTETRGB input</description>
                                    <value>#1</value>
                                </enumeratedValue>
                            </enumeratedValues>
                        </field>
                        <field>
                            <name>PSGTRGBF</name>
                            <description>GTETRGB Pin Falling Input Source Counter Stop Enable</description>
                            <lsb>3</lsb>
                            <msb>3</msb>
                            <access>read-write</access>
                            <enumeratedValues>
                                <enumeratedValue>
                                    <name>0</name>
                                    <description>Counter stop disabled on the falling edge of GTETRGB input</description>
                                    <value>#0</value>
                                </enumeratedValue>
                                <enumeratedValue>
                                    <name>1</name>
                                    <description>Counter stop enabled on the falling edge of GTETRGB input</description>
                                    <value>#1</value>
                                </enumeratedValue>
                            </enumeratedValues>
                        </field>
                        <field>
                            <name>PSGTRGCR</name>
                            <description>GTETRGC Pin Rising Input Source Counter Stop Enable</description>
                            <lsb>4</lsb>
                            <msb>4</msb>
                            <access>read-write</access>
                            <enumeratedValues>
                                <enumeratedValue>
                                    <name>0</name>
                                    <description>Counter stop disabled on the rising edge of GTETRGC input</description>
                                    <value>#0</value>
                                </enumeratedValue>
                                <enumeratedValue>
                                    <name>1</name>
                                    <description>Counter stop enabled on the rising edge of GTETRGC input</description>
                                    <value>#1</value>
                                </enumeratedValue>
                            </enumeratedValues>
                        </field>
                        <field>
                            <name>PSGTRGCF</name>
                            <description>GTETRGC Pin Falling Input Source Counter Stop Enable</description>
                            <lsb>5</lsb>
                            <msb>5</msb>
                            <access>read-write</access>
                            <enumeratedValues>
                                <enumeratedValue>
                                    <name>0</name>
                                    <description>Counter stop disabled on the falling edge of GTETRGC input</description>
                                    <value>#0</value>
                                </enumeratedValue>
                                <enumeratedValue>
                                    <name>1</name>
                                    <description>Counter stop enabled on the falling edge of GTETRGC input</description>
                                    <value>#1</value>
                                </enumeratedValue>
                            </enumeratedValues>
                        </field>
                        <field>
                            <name>PSGTRGDR</name>
                            <description>GTETRGD Pin Rising Input Source Counter Stop Enable</description>
                            <lsb>6</lsb>
                            <msb>6</msb>
                            <access>read-write</access>
                            <enumeratedValues>
                                <enumeratedValue>
                                    <name>0</name>
                                    <description>Counter stop disabled on the rising edge of GTETRGD input</description>
                                    <value>#0</value>
                                </enumeratedValue>
                                <enumeratedValue>
                                    <name>1</name>
                                    <description>Counter stop enabled on the rising edge of GTETRGD input</description>
                                    <value>#1</value>
                                </enumeratedValue>
                            </enumeratedValues>
                        </field>
                        <field>
                            <name>PSGTRGDF</name>
                            <description>GTETRGD Pin Falling Input Source Counter Stop Enable</description>
                            <lsb>7</lsb>
                            <msb>7</msb>
                            <access>read-write</access>
                            <enumeratedValues>
                                <enumeratedValue>
                                    <name>0</name>
                                    <description>Counter stop disabled on the falling edge of GTETRGD input</description>
                                    <value>#0</value>
                                </enumeratedValue>
                                <enumeratedValue>
                                    <name>1</name>
                                    <description>Counter stop enabled on the falling edge of GTETRGD input</description>
                                    <value>#1</value>
                                </enumeratedValue>
                            </enumeratedValues>
                        </field>
                        <field>
                            <name>PSCARBL</name>
                            <description>GTIOCnA Pin Rising Input during GTIOCnB Value Low Source Counter Stop Enable</description>
                            <lsb>8</lsb>
                            <msb>8</msb>
                            <access>read-write</access>
                            <enumeratedValues>
                                <enumeratedValue>
                                    <name>0</name>
                                    <description>Counter stop disabled on the rising edge of GTIOCnA input when GTIOCnB input is 0</description>
                                    <value>#0</value>
                                </enumeratedValue>
                                <enumeratedValue>
                                    <name>1</name>
                                    <description>Counter stop enabled on the rising edge of GTIOCnA input when GTIOCnB input is 0</description>
                                    <value>#1</value>
                                </enumeratedValue>
                            </enumeratedValues>
                        </field>
                        <field>
                            <name>PSCARBH</name>
                            <description>GTIOCnA Pin Rising Input during GTIOCnB Value High Source Counter Stop Enable</description>
                            <lsb>9</lsb>
                            <msb>9</msb>
                            <access>read-write</access>
                            <enumeratedValues>
                                <enumeratedValue>
                                    <name>0</name>
                                    <description>Counter stop disabled on the rising edge of GTIOCnA input when GTIOCnB input is 1</description>
                                    <value>#0</value>
                                </enumeratedValue>
                                <enumeratedValue>
                                    <name>1</name>
                                    <description>Counter stop enabled on the rising edge of GTIOCnA input when GTIOCnB input is 1</description>
                                    <value>#1</value>
                                </enumeratedValue>
                            </enumeratedValues>
                        </field>
                        <field>
                            <name>PSCAFBL</name>
                            <description>GTIOCnA Pin Falling Input during GTIOCnB Value Low Source Counter Stop Enable</description>
                            <lsb>10</lsb>
                            <msb>10</msb>
                            <access>read-write</access>
                            <enumeratedValues>
                                <enumeratedValue>
                                    <name>0</name>
                                    <description>Counter stop disabled on the falling edge of GTIOCnA input when GTIOCnB input is 0</description>
                                    <value>#0</value>
                                </enumeratedValue>
                                <enumeratedValue>
                                    <name>1</name>
                                    <description>Counter stop enabled on the falling edge of GTIOCnA input when GTIOCnB input is 0</description>
                                    <value>#1</value>
                                </enumeratedValue>
                            </enumeratedValues>
                        </field>
                        <field>
                            <name>PSCAFBH</name>
                            <description>GTIOCnA Pin Falling Input during GTIOCnB Value High Source Counter Stop Enable</description>
                            <lsb>11</lsb>
                            <msb>11</msb>
                            <access>read-write</access>
                            <enumeratedValues>
                                <enumeratedValue>
                                    <name>0</name>
                                    <description>Counter stop disabled on the falling edge of GTIOCnA input when GTIOCnB input is 1</description>
                                    <value>#0</value>
                                </enumeratedValue>
                                <enumeratedValue>
                                    <name>1</name>
                                    <description>Counter stop enabled on the falling edge of GTIOCnA input when GTIOCnB input is 1</description>
                                    <value>#1</value>
                                </enumeratedValue>
                            </enumeratedValues>
                        </field>
                        <field>
                            <name>PSCBRAL</name>
                            <description>GTIOCnB Pin Rising Input during GTIOCnA Value Low Source Counter Stop Enable</description>
                            <lsb>12</lsb>
                            <msb>12</msb>
                            <access>read-write</access>
                            <enumeratedValues>
                                <enumeratedValue>
                                    <name>0</name>
                                    <description>Counter stop disabled on the rising edge of GTIOCnB input when GTIOCnA input is 0</description>
                                    <value>#0</value>
                                </enumeratedValue>
                                <enumeratedValue>
                                    <name>1</name>
                                    <description>Counter stop enabled on the rising edge of GTIOCnB input when GTIOCnA input is 0</description>
                                    <value>#1</value>
                                </enumeratedValue>
                            </enumeratedValues>
                        </field>
                        <field>
                            <name>PSCBRAH</name>
                            <description>GTIOCnB Pin Rising Input during GTIOCnA Value High Source Counter Stop Enable</description>
                            <lsb>13</lsb>
                            <msb>13</msb>
                            <access>read-write</access>
                            <enumeratedValues>
                                <enumeratedValue>
                                    <name>0</name>
                                    <description>Counter stop disabled on the rising edge of GTIOCnB input when GTIOCnA input is 1</description>
                                    <value>#0</value>
                                </enumeratedValue>
                                <enumeratedValue>
                                    <name>1</name>
                                    <description>Counter stop enabled on the rising edge of GTIOCnB input when GTIOCnA input is 1</description>
                                    <value>#1</value>
                                </enumeratedValue>
                            </enumeratedValues>
                        </field>
                        <field>
                            <name>PSCBFAL</name>
                            <description>GTIOCnB Pin Falling Input during GTIOCnA Value Low Source Counter Stop Enable</description>
                            <lsb>14</lsb>
                            <msb>14</msb>
                            <access>read-write</access>
                            <enumeratedValues>
                                <enumeratedValue>
                                    <name>0</name>
                                    <description>Counter stop disabled on the falling edge of GTIOCnB input when GTIOCnA input is 0</description>
                                    <value>#0</value>
                                </enumeratedValue>
                                <enumeratedValue>
                                    <name>1</name>
                                    <description>Counter stop enabled on the falling edge of GTIOCnB input when GTIOCnA input is 0</description>
                                    <value>#1</value>
                                </enumeratedValue>
                            </enumeratedValues>
                        </field>
                        <field>
                            <name>PSCBFAH</name>
                            <description>GTIOCnB Pin Falling Input during GTIOCnA Value High Source Counter Stop Enable</description>
                            <lsb>15</lsb>
                            <msb>15</msb>
                            <access>read-write</access>
                            <enumeratedValues>
                                <enumeratedValue>
                                    <name>0</name>
                                    <description>Counter stop disabled on the falling edge of GTIOCnB input when GTIOCnA input is 1</description>
                                    <value>#0</value>
                                </enumeratedValue>
                                <enumeratedValue>
                                    <name>1</name>
                                    <description>Counter stop enabled on the falling edge of GTIOCnB input when GTIOCnA input is 1</description>
                                    <value>#1</value>
                                </enumeratedValue>
                            </enumeratedValues>
                        </field>
                        <field>
                            <name>PSELCA</name>
                            <description>ELC_GPTA Event Source Counter Stop Enable</description>
                            <lsb>16</lsb>
                            <msb>16</msb>
                            <access>read-write</access>
                            <enumeratedValues>
                                <enumeratedValue>
                                    <name>0</name>
                                    <description>Counter stop disabled at the ELC_GPTA input</description>
                                    <value>#0</value>
                                </enumeratedValue>
                                <enumeratedValue>
                                    <name>1</name>
                                    <description>Counter stop enabled at the ELC_GPTA input</description>
                                    <value>#1</value>
                                </enumeratedValue>
                            </enumeratedValues>
                        </field>
                        <field>
                            <name>PSELCB</name>
                            <description>ELC_GPTB Event Source Counter Stop Enable</description>
                            <lsb>17</lsb>
                            <msb>17</msb>
                            <access>read-write</access>
                            <enumeratedValues>
                                <enumeratedValue>
                                    <name>0</name>
                                    <description>Counter stop disabled at the ELC_GPTB input</description>
                                    <value>#0</value>
                                </enumeratedValue>
                                <enumeratedValue>
                                    <name>1</name>
                                    <description>Counter stop enabled at the ELC_GPTB input</description>
                                    <value>#1</value>
                                </enumeratedValue>
                            </enumeratedValues>
                        </field>
                        <field>
                            <name>PSELCC</name>
                            <description>ELC_GPTC Event Source Counter Stop Enable</description>
                            <lsb>18</lsb>
                            <msb>18</msb>
                            <access>read-write</access>
                            <enumeratedValues>
                                <enumeratedValue>
                                    <name>0</name>
                                    <description>Counter stop disabled at the ELC_GPTC input</description>
                                    <value>#0</value>
                                </enumeratedValue>
                                <enumeratedValue>
                                    <name>1</name>
                                    <description>Counter stop enabled at the ELC_GPTC input</description>
                                    <value>#1</value>
                                </enumeratedValue>
                            </enumeratedValues>
                        </field>
                        <field>
                            <name>PSELCD</name>
                            <description>ELC_GPTD Event Source Counter Stop Enable</description>
                            <lsb>19</lsb>
                            <msb>19</msb>
                            <access>read-write</access>
                            <enumeratedValues>
                                <enumeratedValue>
                                    <name>0</name>
                                    <description>Counter stop disabled at the ELC_GPTD input</description>
                                    <value>#0</value>
                                </enumeratedValue>
                                <enumeratedValue>
                                    <name>1</name>
                                    <description>Counter stop enabled at the ELC_GPTD input</description>
                                    <value>#1</value>
                                </enumeratedValue>
                            </enumeratedValues>
                        </field>
                        <field>
                            <name>PSELCE</name>
                            <description>ELC_GPTE Event Source Counter Stop Enable</description>
                            <lsb>20</lsb>
                            <msb>20</msb>
                            <access>read-write</access>
                            <enumeratedValues>
                                <enumeratedValue>
                                    <name>0</name>
                                    <description>Counter stop disabled at the ELC_GPTE input</description>
                                    <value>#0</value>
                                </enumeratedValue>
                                <enumeratedValue>
                                    <name>1</name>
                                    <description>Counter stop enabled at the ELC_GPTE input</description>
                                    <value>#1</value>
                                </enumeratedValue>
                            </enumeratedValues>
                        </field>
                        <field>
                            <name>PSELCF</name>
                            <description>ELC_GPTF Event Source Counter Stop Enable</description>
                            <lsb>21</lsb>
                            <msb>21</msb>
                            <access>read-write</access>
                            <enumeratedValues>
                                <enumeratedValue>
                                    <name>0</name>
                                    <description>Counter stop disabled at the ELC_GPTF input</description>
                                    <value>#0</value>
                                </enumeratedValue>
                                <enumeratedValue>
                                    <name>1</name>
                                    <description>Counter stop enabled at the ELC_GPTF input</description>
                                    <value>#1</value>
                                </enumeratedValue>
                            </enumeratedValues>
                        </field>
                        <field>
                            <name>PSELCG</name>
                            <description>ELC_GPTG Event Source Counter Stop Enable</description>
                            <lsb>22</lsb>
                            <msb>22</msb>
                            <access>read-write</access>
                            <enumeratedValues>
                                <enumeratedValue>
                                    <name>0</name>
                                    <description>Counter stop disabled at the ELC_GPTG input</description>
                                    <value>#0</value>
                                </enumeratedValue>
                                <enumeratedValue>
                                    <name>1</name>
                                    <description>Counter stop enabled at the ELC_GPTG input</description>
                                    <value>#1</value>
                                </enumeratedValue>
                            </enumeratedValues>
                        </field>
                        <field>
                            <name>PSELCH</name>
                            <description>ELC_GPTH Event Source Counter Stop Enable</description>
                            <lsb>23</lsb>
                            <msb>23</msb>
                            <access>read-write</access>
                            <enumeratedValues>
                                <enumeratedValue>
                                    <name>0</name>
                                    <description>Counter stop disabled at the ELC_GPTH input</description>
                                    <value>#0</value>
                                </enumeratedValue>
                                <enumeratedValue>
                                    <name>1</name>
                                    <description>Counter stop enabled at the ELC_GPTH input</description>
                                    <value>#1</value>
                                </enumeratedValue>
                            </enumeratedValues>
                        </field>
                        <field>
                            <name>CSTOP</name>
                            <description>Software Source Counter Stop Enable</description>
                            <lsb>31</lsb>
                            <msb>31</msb>
                            <access>read-write</access>
                            <enumeratedValues>
                                <enumeratedValue>
                                    <name>0</name>
                                    <description>Counter stop disabled by the GTSTP register</description>
                                    <value>#0</value>
                                </enumeratedValue>
                                <enumeratedValue>
                                    <name>1</name>
                                    <description>Counter stop enabled by the GTSTP register</description>
                                    <value>#1</value>
                                </enumeratedValue>
                            </enumeratedValues>
                        </field>
                    </fields>
                </register>
                <register>
                    <name>GTCSR</name>
                    <description>General PWM Timer Clear Source Select Register</description>
                    <addressOffset>0x18</addressOffset>
                    <size>32</size>
                    <access>read-write</access>
                    <resetValue>0x00000000</resetValue>
                    <resetMask>0xffffffff</resetMask>
                    <fields>
                        <field>
                            <name>CSGTRGAR</name>
                            <description>GTETRGA Pin Rising Input Source Counter Clear Enable</description>
                            <lsb>0</lsb>
                            <msb>0</msb>
                            <access>read-write</access>
                            <enumeratedValues>
                                <enumeratedValue>
                                    <name>0</name>
                                    <description>Counter clear disabled on the rising edge of GTETRGA input</description>
                                    <value>#0</value>
                                </enumeratedValue>
                                <enumeratedValue>
                                    <name>1</name>
                                    <description>Counter clear enabled on the rising edge of GTETRGA input</description>
                                    <value>#1</value>
                                </enumeratedValue>
                            </enumeratedValues>
                        </field>
                        <field>
                            <name>CSGTRGAF</name>
                            <description>GTETRGA Pin Falling Input Source Counter Clear Enable</description>
                            <lsb>1</lsb>
                            <msb>1</msb>
                            <access>read-write</access>
                            <enumeratedValues>
                                <enumeratedValue>
                                    <name>0</name>
                                    <description>Counter clear disabled on the falling edge of GTETRGA input</description>
                                    <value>#0</value>
                                </enumeratedValue>
                                <enumeratedValue>
                                    <name>1</name>
                                    <description>Counter clear enabled on the falling edge of GTETRGA input</description>
                                    <value>#1</value>
                                </enumeratedValue>
                            </enumeratedValues>
                        </field>
                        <field>
                            <name>CSGTRGBR</name>
                            <description>GTETRGB Pin Rising Input Source Counter Clear Enable</description>
                            <lsb>2</lsb>
                            <msb>2</msb>
                            <access>read-write</access>
                            <enumeratedValues>
                                <enumeratedValue>
                                    <name>0</name>
                                    <description>Disable counter clear on the rising edge of GTETRGB input</description>
                                    <value>#0</value>
                                </enumeratedValue>
                                <enumeratedValue>
                                    <name>1</name>
                                    <description>Enable counter clear on the rising edge of GTETRGB input</description>
                                    <value>#1</value>
                                </enumeratedValue>
                            </enumeratedValues>
                        </field>
                        <field>
                            <name>CSGTRGBF</name>
                            <description>GTETRGB Pin Falling Input Source Counter Clear Enable</description>
                            <lsb>3</lsb>
                            <msb>3</msb>
                            <access>read-write</access>
                            <enumeratedValues>
                                <enumeratedValue>
                                    <name>0</name>
                                    <description>Counter clear disabled on the falling edge of GTETRGB input</description>
                                    <value>#0</value>
                                </enumeratedValue>
                                <enumeratedValue>
                                    <name>1</name>
                                    <description>Counter clear enabled on the falling edge of GTETRGB input</description>
                                    <value>#1</value>
                                </enumeratedValue>
                            </enumeratedValues>
                        </field>
                        <field>
                            <name>CSGTRGCR</name>
                            <description>GTETRGC Pin Rising Input Source Counter Clear Enable</description>
                            <lsb>4</lsb>
                            <msb>4</msb>
                            <access>read-write</access>
                            <enumeratedValues>
                                <enumeratedValue>
                                    <name>0</name>
                                    <description>Disable counter clear on the rising edge of GTETRGC input</description>
                                    <value>#0</value>
                                </enumeratedValue>
                                <enumeratedValue>
                                    <name>1</name>
                                    <description>Enable counter clear on the rising edge of GTETRGC input</description>
                                    <value>#1</value>
                                </enumeratedValue>
                            </enumeratedValues>
                        </field>
                        <field>
                            <name>CSGTRGCF</name>
                            <description>GTETRGC Pin Falling Input Source Counter Clear Enable</description>
                            <lsb>5</lsb>
                            <msb>5</msb>
                            <access>read-write</access>
                            <enumeratedValues>
                                <enumeratedValue>
                                    <name>0</name>
                                    <description>Counter clear disabled on the falling edge of GTETRGC input</description>
                                    <value>#0</value>
                                </enumeratedValue>
                                <enumeratedValue>
                                    <name>1</name>
                                    <description>Counter clear enabled on the falling edge of GTETRGC input</description>
                                    <value>#1</value>
                                </enumeratedValue>
                            </enumeratedValues>
                        </field>
                        <field>
                            <name>CSGTRGDR</name>
                            <description>GTETRGD Pin Rising Input Source Counter Clear Enable</description>
                            <lsb>6</lsb>
                            <msb>6</msb>
                            <access>read-write</access>
                            <enumeratedValues>
                                <enumeratedValue>
                                    <name>0</name>
                                    <description>Disable counter clear on the rising edge of GTETRGD input</description>
                                    <value>#0</value>
                                </enumeratedValue>
                                <enumeratedValue>
                                    <name>1</name>
                                    <description>Enable counter clear on the rising edge of GTETRGD input</description>
                                    <value>#1</value>
                                </enumeratedValue>
                            </enumeratedValues>
                        </field>
                        <field>
                            <name>CSGTRGDF</name>
                            <description>GTETRGD Pin Falling Input Source Counter Clear Enable</description>
                            <lsb>7</lsb>
                            <msb>7</msb>
                            <access>read-write</access>
                            <enumeratedValues>
                                <enumeratedValue>
                                    <name>0</name>
                                    <description>Counter clear disabled on the falling edge of GTETRGD input</description>
                                    <value>#0</value>
                                </enumeratedValue>
                                <enumeratedValue>
                                    <name>1</name>
                                    <description>Counter clear enabled on the falling edge of GTETRGD input</description>
                                    <value>#1</value>
                                </enumeratedValue>
                            </enumeratedValues>
                        </field>
                        <field>
                            <name>CSCARBL</name>
                            <description>GTIOCnA Pin Rising Input during GTIOCnB Value Low Source Counter Clear Enable</description>
                            <lsb>8</lsb>
                            <msb>8</msb>
                            <access>read-write</access>
                            <enumeratedValues>
                                <enumeratedValue>
                                    <name>0</name>
                                    <description>Counter clear disabled on the rising edge of GTIOCnA input when GTIOCnB input is 0</description>
                                    <value>#0</value>
                                </enumeratedValue>
                                <enumeratedValue>
                                    <name>1</name>
                                    <description>Counter clear enabled on the rising edge of GTIOCnA input when GTIOCnB input is 0</description>
                                    <value>#1</value>
                                </enumeratedValue>
                            </enumeratedValues>
                        </field>
                        <field>
                            <name>CSCARBH</name>
                            <description>GTIOCnA Pin Rising Input during GTIOCnB Value High Source Counter Clear Enable</description>
                            <lsb>9</lsb>
                            <msb>9</msb>
                            <access>read-write</access>
                            <enumeratedValues>
                                <enumeratedValue>
                                    <name>0</name>
                                    <description>Counter clear disabled on the rising edge of GTIOCnA input when GTIOCnB input is 1</description>
                                    <value>#0</value>
                                </enumeratedValue>
                                <enumeratedValue>
                                    <name>1</name>
                                    <description>Counter clear enabled on the rising edge of GTIOCnA input when GTIOCnB input is 1</description>
                                    <value>#1</value>
                                </enumeratedValue>
                            </enumeratedValues>
                        </field>
                        <field>
                            <name>CSCAFBL</name>
                            <description>GTIOCnA Pin Falling Input during GTIOCnB Value Low Source Counter Clear Enable</description>
                            <lsb>10</lsb>
                            <msb>10</msb>
                            <access>read-write</access>
                            <enumeratedValues>
                                <enumeratedValue>
                                    <name>0</name>
                                    <description>Counter clear disabled on the falling edge of GTIOCnA input when GTIOCnB input is 0</description>
                                    <value>#0</value>
                                </enumeratedValue>
                                <enumeratedValue>
                                    <name>1</name>
                                    <description>Counter clear enabled on the falling edge of GTIOCnA input when GTIOCnB input is 0</description>
                                    <value>#1</value>
                                </enumeratedValue>
                            </enumeratedValues>
                        </field>
                        <field>
                            <name>CSCAFBH</name>
                            <description>GTIOCnA Pin Falling Input during GTIOCnB Value High Source Counter Clear Enable</description>
                            <lsb>11</lsb>
                            <msb>11</msb>
                            <access>read-write</access>
                            <enumeratedValues>
                                <enumeratedValue>
                                    <name>0</name>
                                    <description>Counter clear disabled on the falling edge of GTIOCnA input when GTIOCnB input is 1</description>
                                    <value>#0</value>
                                </enumeratedValue>
                                <enumeratedValue>
                                    <name>1</name>
                                    <description>Counter clear enabled on the falling edge of GTIOCnA input when GTIOCnB input is 1</description>
                                    <value>#1</value>
                                </enumeratedValue>
                            </enumeratedValues>
                        </field>
                        <field>
                            <name>CSCBRAL</name>
                            <description>GTIOCnB Pin Rising Input during GTIOCnA Value Low Source Counter Clear Enable</description>
                            <lsb>12</lsb>
                            <msb>12</msb>
                            <access>read-write</access>
                            <enumeratedValues>
                                <enumeratedValue>
                                    <name>0</name>
                                    <description>Counter clear disabled on the rising edge of GTIOCnB input when GTIOCnA input is 0</description>
                                    <value>#0</value>
                                </enumeratedValue>
                                <enumeratedValue>
                                    <name>1</name>
                                    <description>Counter clear enabled on the rising edge of GTIOCnB input when GTIOCnA input is 0</description>
                                    <value>#1</value>
                                </enumeratedValue>
                            </enumeratedValues>
                        </field>
                        <field>
                            <name>CSCBRAH</name>
                            <description>GTIOCnB Pin Rising Input during GTIOCnA Value High Source Counter Clear Enable</description>
                            <lsb>13</lsb>
                            <msb>13</msb>
                            <access>read-write</access>
                            <enumeratedValues>
                                <enumeratedValue>
                                    <name>0</name>
                                    <description>Counter clear disabled on the rising edge of GTIOCnB input when GTIOCnA input is 1</description>
                                    <value>#0</value>
                                </enumeratedValue>
                                <enumeratedValue>
                                    <name>1</name>
                                    <description>Counter clear enabled on the rising edge of GTIOCnB input when GTIOCnA input is 1</description>
                                    <value>#1</value>
                                </enumeratedValue>
                            </enumeratedValues>
                        </field>
                        <field>
                            <name>CSCBFAL</name>
                            <description>GTIOCnB Pin Falling Input during GTIOCnA Value Low Source Counter Clear Enable</description>
                            <lsb>14</lsb>
                            <msb>14</msb>
                            <access>read-write</access>
                            <enumeratedValues>
                                <enumeratedValue>
                                    <name>0</name>
                                    <description>Counter clear disabled on the falling edge of GTIOCnB input when GTIOCnA input is 0</description>
                                    <value>#0</value>
                                </enumeratedValue>
                                <enumeratedValue>
                                    <name>1</name>
                                    <description>Counter clear enabled on the falling edge of GTIOCnB input when GTIOCnA input is 0</description>
                                    <value>#1</value>
                                </enumeratedValue>
                            </enumeratedValues>
                        </field>
                        <field>
                            <name>CSCBFAH</name>
                            <description>GTIOCnB Pin Falling Input during GTIOCnA Value High Source Counter Clear Enable</description>
                            <lsb>15</lsb>
                            <msb>15</msb>
                            <access>read-write</access>
                            <enumeratedValues>
                                <enumeratedValue>
                                    <name>0</name>
                                    <description>Counter clear disabled on the falling edge of GTIOCnB input when GTIOCnA input is 1</description>
                                    <value>#0</value>
                                </enumeratedValue>
                                <enumeratedValue>
                                    <name>1</name>
                                    <description>Counter clear enabled on the falling edge of GTIOCnB input when GTIOCnA input is 1</description>
                                    <value>#1</value>
                                </enumeratedValue>
                            </enumeratedValues>
                        </field>
                        <field>
                            <name>CSELCA</name>
                            <description>ELC_GPTA Event Source Counter Clear Enable</description>
                            <lsb>16</lsb>
                            <msb>16</msb>
                            <access>read-write</access>
                            <enumeratedValues>
                                <enumeratedValue>
                                    <name>0</name>
                                    <description>Counter clear disabled at the ELC_GPTA input</description>
                                    <value>#0</value>
                                </enumeratedValue>
                                <enumeratedValue>
                                    <name>1</name>
                                    <description>Counter clear enabled at the ELC_GPTA input</description>
                                    <value>#1</value>
                                </enumeratedValue>
                            </enumeratedValues>
                        </field>
                        <field>
                            <name>CSELCB</name>
                            <description>ELC_GPTB Event Source Counter Clear Enable</description>
                            <lsb>17</lsb>
                            <msb>17</msb>
                            <access>read-write</access>
                            <enumeratedValues>
                                <enumeratedValue>
                                    <name>0</name>
                                    <description>Counter clear disabled at the ELC_GPTB input</description>
                                    <value>#0</value>
                                </enumeratedValue>
                                <enumeratedValue>
                                    <name>1</name>
                                    <description>Counter clear enabled at the ELC_GPTB input</description>
                                    <value>#1</value>
                                </enumeratedValue>
                            </enumeratedValues>
                        </field>
                        <field>
                            <name>CSELCC</name>
                            <description>ELC_GPTC Event Source Counter Clear Enable</description>
                            <lsb>18</lsb>
                            <msb>18</msb>
                            <access>read-write</access>
                            <enumeratedValues>
                                <enumeratedValue>
                                    <name>0</name>
                                    <description>Counter clear disabled at the ELC_GPTC input</description>
                                    <value>#0</value>
                                </enumeratedValue>
                                <enumeratedValue>
                                    <name>1</name>
                                    <description>Counter clear enabled at the ELC_GPTC input</description>
                                    <value>#1</value>
                                </enumeratedValue>
                            </enumeratedValues>
                        </field>
                        <field>
                            <name>CSELCD</name>
                            <description>ELC_GPTD Event Source Counter Clear Enable</description>
                            <lsb>19</lsb>
                            <msb>19</msb>
                            <access>read-write</access>
                            <enumeratedValues>
                                <enumeratedValue>
                                    <name>0</name>
                                    <description>Counter clear disabled at the ELC_GPTD input</description>
                                    <value>#0</value>
                                </enumeratedValue>
                                <enumeratedValue>
                                    <name>1</name>
                                    <description>Counter clear enabled at the ELC_GPTD input</description>
                                    <value>#1</value>
                                </enumeratedValue>
                            </enumeratedValues>
                        </field>
                        <field>
                            <name>CSELCE</name>
                            <description>ELC_GPTE Event Source Counter Clear Enable</description>
                            <lsb>20</lsb>
                            <msb>20</msb>
                            <access>read-write</access>
                            <enumeratedValues>
                                <enumeratedValue>
                                    <name>0</name>
                                    <description>Counter clear disabled at the ELC_GPTE input</description>
                                    <value>#0</value>
                                </enumeratedValue>
                                <enumeratedValue>
                                    <name>1</name>
                                    <description>Counter clear enabled at the ELC_GPTE input</description>
                                    <value>#1</value>
                                </enumeratedValue>
                            </enumeratedValues>
                        </field>
                        <field>
                            <name>CSELCF</name>
                            <description>ELC_GPTF Event Source Counter Clear Enable</description>
                            <lsb>21</lsb>
                            <msb>21</msb>
                            <access>read-write</access>
                            <enumeratedValues>
                                <enumeratedValue>
                                    <name>0</name>
                                    <description>Counter clear disabled at the ELC_GPTF input</description>
                                    <value>#0</value>
                                </enumeratedValue>
                                <enumeratedValue>
                                    <name>1</name>
                                    <description>Counter clear enabled at the ELC_GPTF input</description>
                                    <value>#1</value>
                                </enumeratedValue>
                            </enumeratedValues>
                        </field>
                        <field>
                            <name>CSELCG</name>
                            <description>ELC_GPTG Event Source Counter Clear Enable</description>
                            <lsb>22</lsb>
                            <msb>22</msb>
                            <access>read-write</access>
                            <enumeratedValues>
                                <enumeratedValue>
                                    <name>0</name>
                                    <description>Counter clear disabled at the ELC_GPTG input</description>
                                    <value>#0</value>
                                </enumeratedValue>
                                <enumeratedValue>
                                    <name>1</name>
                                    <description>Counter clear enabled at the ELC_GPTG input</description>
                                    <value>#1</value>
                                </enumeratedValue>
                            </enumeratedValues>
                        </field>
                        <field>
                            <name>CSELCH</name>
                            <description>ELC_GPTH Event Source Counter Clear Enable</description>
                            <lsb>23</lsb>
                            <msb>23</msb>
                            <access>read-write</access>
                            <enumeratedValues>
                                <enumeratedValue>
                                    <name>0</name>
                                    <description>Counter clear disabled at the ELC_GPTH input</description>
                                    <value>#0</value>
                                </enumeratedValue>
                                <enumeratedValue>
                                    <name>1</name>
                                    <description>Counter clear enabled at the ELC_GPTH input</description>
                                    <value>#1</value>
                                </enumeratedValue>
                            </enumeratedValues>
                        </field>
                        <field>
                            <name>CCLR</name>
                            <description>Software Source Counter Clear Enable</description>
                            <lsb>31</lsb>
                            <msb>31</msb>
                            <access>read-write</access>
                            <enumeratedValues>
                                <enumeratedValue>
                                    <name>0</name>
                                    <description>Counter clear disabled by the GTCLR register</description>
                                    <value>#0</value>
                                </enumeratedValue>
                                <enumeratedValue>
                                    <name>1</name>
                                    <description>Counter clear enabled by the GTCLR register</description>
                                    <value>#1</value>
                                </enumeratedValue>
                            </enumeratedValues>
                        </field>
                    </fields>
                </register>
                <register>
                    <name>GTUPSR</name>
                    <description>General PWM Timer Up Count Source Select Register</description>
                    <addressOffset>0x1C</addressOffset>
                    <size>32</size>
                    <access>read-write</access>
                    <resetValue>0x00000000</resetValue>
                    <resetMask>0xffffffff</resetMask>
                    <fields>
                        <field>
                            <name>USGTRGAR</name>
                            <description>GTETRGA Pin Rising Input Source Counter Count Up Enable</description>
                            <lsb>0</lsb>
                            <msb>0</msb>
                            <access>read-write</access>
                            <enumeratedValues>
                                <enumeratedValue>
                                    <name>0</name>
                                    <description>Counter count up disabled on the rising edge of GTETRGA input</description>
                                    <value>#0</value>
                                </enumeratedValue>
                                <enumeratedValue>
                                    <name>1</name>
                                    <description>Counter count up enabled on the rising edge of GTETRGA input</description>
                                    <value>#1</value>
                                </enumeratedValue>
                            </enumeratedValues>
                        </field>
                        <field>
                            <name>USGTRGAF</name>
                            <description>GTETRGA Pin Falling Input Source Counter Count Up Enable</description>
                            <lsb>1</lsb>
                            <msb>1</msb>
                            <access>read-write</access>
                            <enumeratedValues>
                                <enumeratedValue>
                                    <name>0</name>
                                    <description>Counter count up disabled on the falling edge of GTETRGA input</description>
                                    <value>#0</value>
                                </enumeratedValue>
                                <enumeratedValue>
                                    <name>1</name>
                                    <description>Counter count up enabled on the falling edge of GTETRGA input</description>
                                    <value>#1</value>
                                </enumeratedValue>
                            </enumeratedValues>
                        </field>
                        <field>
                            <name>USGTRGBR</name>
                            <description>GTETRGB Pin Rising Input Source Counter Count Up Enable</description>
                            <lsb>2</lsb>
                            <msb>2</msb>
                            <access>read-write</access>
                            <enumeratedValues>
                                <enumeratedValue>
                                    <name>0</name>
                                    <description>Counter count up disabled on the rising edge of GTETRGB input</description>
                                    <value>#0</value>
                                </enumeratedValue>
                                <enumeratedValue>
                                    <name>1</name>
                                    <description>Counter count up enabled on the rising edge of GTETRGB input</description>
                                    <value>#1</value>
                                </enumeratedValue>
                            </enumeratedValues>
                        </field>
                        <field>
                            <name>USGTRGBF</name>
                            <description>GTETRGB Pin Falling Input Source Counter Count Up Enable</description>
                            <lsb>3</lsb>
                            <msb>3</msb>
                            <access>read-write</access>
                            <enumeratedValues>
                                <enumeratedValue>
                                    <name>0</name>
                                    <description>Counter count up disabled on the falling edge of GTETRGB input</description>
                                    <value>#0</value>
                                </enumeratedValue>
                                <enumeratedValue>
                                    <name>1</name>
                                    <description>Counter count up enabled on the falling edge of GTETRGB input</description>
                                    <value>#1</value>
                                </enumeratedValue>
                            </enumeratedValues>
                        </field>
                        <field>
                            <name>USGTRGCR</name>
                            <description>GTETRGC Pin Rising Input Source Counter Count Up Enable</description>
                            <lsb>4</lsb>
                            <msb>4</msb>
                            <access>read-write</access>
                            <enumeratedValues>
                                <enumeratedValue>
                                    <name>0</name>
                                    <description>Counter count up disabled on the rising edge of GTETRGC input</description>
                                    <value>#0</value>
                                </enumeratedValue>
                                <enumeratedValue>
                                    <name>1</name>
                                    <description>Counter count up enabled on the rising edge of GTETRGC input</description>
                                    <value>#1</value>
                                </enumeratedValue>
                            </enumeratedValues>
                        </field>
                        <field>
                            <name>USGTRGCF</name>
                            <description>GTETRGC Pin Falling Input Source Counter Count Up Enable</description>
                            <lsb>5</lsb>
                            <msb>5</msb>
                            <access>read-write</access>
                            <enumeratedValues>
                                <enumeratedValue>
                                    <name>0</name>
                                    <description>Counter count up disabled on the falling edge of GTETRGC input</description>
                                    <value>#0</value>
                                </enumeratedValue>
                                <enumeratedValue>
                                    <name>1</name>
                                    <description>Counter count up enabled on the falling edge of GTETRGC input</description>
                                    <value>#1</value>
                                </enumeratedValue>
                            </enumeratedValues>
                        </field>
                        <field>
                            <name>USGTRGDR</name>
                            <description>GTETRGD Pin Rising Input Source Counter Count Up Enable</description>
                            <lsb>6</lsb>
                            <msb>6</msb>
                            <access>read-write</access>
                            <enumeratedValues>
                                <enumeratedValue>
                                    <name>0</name>
                                    <description>Counter count up disabled on the rising edge of GTETRGD input</description>
                                    <value>#0</value>
                                </enumeratedValue>
                                <enumeratedValue>
                                    <name>1</name>
                                    <description>Counter count up enabled on the rising edge of GTETRGD input</description>
                                    <value>#1</value>
                                </enumeratedValue>
                            </enumeratedValues>
                        </field>
                        <field>
                            <name>USGTRGDF</name>
                            <description>GTETRGD Pin Falling Input Source Counter Count Up Enable</description>
                            <lsb>7</lsb>
                            <msb>7</msb>
                            <access>read-write</access>
                            <enumeratedValues>
                                <enumeratedValue>
                                    <name>0</name>
                                    <description>Counter count up disabled on the falling edge of GTETRGD input</description>
                                    <value>#0</value>
                                </enumeratedValue>
                                <enumeratedValue>
                                    <name>1</name>
                                    <description>Counter count up enabled on the falling edge of GTETRGD input</description>
                                    <value>#1</value>
                                </enumeratedValue>
                            </enumeratedValues>
                        </field>
                        <field>
                            <name>USCARBL</name>
                            <description>GTIOCnA Pin Rising Input during GTIOCnB Value Low Source Counter Count Up Enable</description>
                            <lsb>8</lsb>
                            <msb>8</msb>
                            <access>read-write</access>
                            <enumeratedValues>
                                <enumeratedValue>
                                    <name>0</name>
                                    <description>Counter count up disabled on the rising edge of GTIOCnA input when GTIOCnB input is 0</description>
                                    <value>#0</value>
                                </enumeratedValue>
                                <enumeratedValue>
                                    <name>1</name>
                                    <description>Counter count up enabled on the rising edge of GTIOCnA input when GTIOCnB input is 0</description>
                                    <value>#1</value>
                                </enumeratedValue>
                            </enumeratedValues>
                        </field>
                        <field>
                            <name>USCARBH</name>
                            <description>GTIOCnA Pin Rising Input during GTIOCnB Value High Source Counter Count Up Enable</description>
                            <lsb>9</lsb>
                            <msb>9</msb>
                            <access>read-write</access>
                            <enumeratedValues>
                                <enumeratedValue>
                                    <name>0</name>
                                    <description>Counter count up disabled on the rising edge of GTIOCnA input when GTIOCnB input is 1</description>
                                    <value>#0</value>
                                </enumeratedValue>
                                <enumeratedValue>
                                    <name>1</name>
                                    <description>Counter count up enabled on the rising edge of GTIOCnA input when GTIOCnB input is 1</description>
                                    <value>#1</value>
                                </enumeratedValue>
                            </enumeratedValues>
                        </field>
                        <field>
                            <name>USCAFBL</name>
                            <description>GTIOCnA Pin Falling Input during GTIOCnB Value Low Source Counter Count Up Enable</description>
                            <lsb>10</lsb>
                            <msb>10</msb>
                            <access>read-write</access>
                            <enumeratedValues>
                                <enumeratedValue>
                                    <name>0</name>
                                    <description>Counter count up disabled on the falling edge of GTIOCnA input when GTIOCnB input is 0</description>
                                    <value>#0</value>
                                </enumeratedValue>
                                <enumeratedValue>
                                    <name>1</name>
                                    <description>Counter count up enabled on the falling edge of GTIOCnA input when GTIOCnB input is 0</description>
                                    <value>#1</value>
                                </enumeratedValue>
                            </enumeratedValues>
                        </field>
                        <field>
                            <name>USCAFBH</name>
                            <description>GTIOCnA Pin Falling Input during GTIOCnB Value High Source Counter Count Up Enable</description>
                            <lsb>11</lsb>
                            <msb>11</msb>
                            <access>read-write</access>
                            <enumeratedValues>
                                <enumeratedValue>
                                    <name>0</name>
                                    <description>Counter count up disabled on the falling edge of GTIOCnA input when GTIOCnB input is 1</description>
                                    <value>#0</value>
                                </enumeratedValue>
                                <enumeratedValue>
                                    <name>1</name>
                                    <description>Counter count up enabled on the falling edge of GTIOCnA input when GTIOCnB input is 1</description>
                                    <value>#1</value>
                                </enumeratedValue>
                            </enumeratedValues>
                        </field>
                        <field>
                            <name>USCBRAL</name>
                            <description>GTIOCnB Pin Rising Input during GTIOCnA Value Low Source Counter Count Up Enable</description>
                            <lsb>12</lsb>
                            <msb>12</msb>
                            <access>read-write</access>
                            <enumeratedValues>
                                <enumeratedValue>
                                    <name>0</name>
                                    <description>Counter count up disabled on the rising edge of GTIOCnB input when GTIOCnA input is 0</description>
                                    <value>#0</value>
                                </enumeratedValue>
                                <enumeratedValue>
                                    <name>1</name>
                                    <description>Counter count up enabled on the rising edge of GTIOCnB input when GTIOCnA input is 0</description>
                                    <value>#1</value>
                                </enumeratedValue>
                            </enumeratedValues>
                        </field>
                        <field>
                            <name>USCBRAH</name>
                            <description>GTIOCnB Pin Rising Input during GTIOCnA Value High Source Counter Count Up Enable</description>
                            <lsb>13</lsb>
                            <msb>13</msb>
                            <access>read-write</access>
                            <enumeratedValues>
                                <enumeratedValue>
                                    <name>0</name>
                                    <description>Counter count up disabled on the rising edge of GTIOCnB input when GTIOCnA input is 1</description>
                                    <value>#0</value>
                                </enumeratedValue>
                                <enumeratedValue>
                                    <name>1</name>
                                    <description>Counter count up enabled on the rising edge of GTIOCnB input when GTIOCnA input is 1</description>
                                    <value>#1</value>
                                </enumeratedValue>
                            </enumeratedValues>
                        </field>
                        <field>
                            <name>USCBFAL</name>
                            <description>GTIOCnB Pin Falling Input during GTIOCnA Value Low Source Counter Count Up Enable</description>
                            <lsb>14</lsb>
                            <msb>14</msb>
                            <access>read-write</access>
                            <enumeratedValues>
                                <enumeratedValue>
                                    <name>0</name>
                                    <description>Counter count up disabled on the falling edge of GTIOCnB input when GTIOCnA input is 0</description>
                                    <value>#0</value>
                                </enumeratedValue>
                                <enumeratedValue>
                                    <name>1</name>
                                    <description>Counter count up enabled on the falling edge of GTIOCnB input when GTIOCnA input is 0</description>
                                    <value>#1</value>
                                </enumeratedValue>
                            </enumeratedValues>
                        </field>
                        <field>
                            <name>USCBFAH</name>
                            <description>GTIOCnB Pin Falling Input during GTIOCnA Value High Source Counter Count Up Enable</description>
                            <lsb>15</lsb>
                            <msb>15</msb>
                            <access>read-write</access>
                            <enumeratedValues>
                                <enumeratedValue>
                                    <name>0</name>
                                    <description>Counter count up disabled on the falling edge of GTIOCnB input when GTIOCnA input is 1</description>
                                    <value>#0</value>
                                </enumeratedValue>
                                <enumeratedValue>
                                    <name>1</name>
                                    <description>Counter count up enabled on the falling edge of GTIOCnB input when GTIOCnA input is 1</description>
                                    <value>#1</value>
                                </enumeratedValue>
                            </enumeratedValues>
                        </field>
                        <field>
                            <name>USELCA</name>
                            <description>ELC_GPTA Event Source Counter Count Up Enable</description>
                            <lsb>16</lsb>
                            <msb>16</msb>
                            <access>read-write</access>
                            <enumeratedValues>
                                <enumeratedValue>
                                    <name>0</name>
                                    <description>Counter count up disabled at the ELC_GPTA input</description>
                                    <value>#0</value>
                                </enumeratedValue>
                                <enumeratedValue>
                                    <name>1</name>
                                    <description>Counter count up enabled at the ELC_GPTA input</description>
                                    <value>#1</value>
                                </enumeratedValue>
                            </enumeratedValues>
                        </field>
                        <field>
                            <name>USELCB</name>
                            <description>ELC_GPTB Event Source Counter Count Up Enable</description>
                            <lsb>17</lsb>
                            <msb>17</msb>
                            <access>read-write</access>
                            <enumeratedValues>
                                <enumeratedValue>
                                    <name>0</name>
                                    <description>Counter count up disabled at the ELC_GPTB input</description>
                                    <value>#0</value>
                                </enumeratedValue>
                                <enumeratedValue>
                                    <name>1</name>
                                    <description>Counter count up enabled at the ELC_GPTB input</description>
                                    <value>#1</value>
                                </enumeratedValue>
                            </enumeratedValues>
                        </field>
                        <field>
                            <name>USELCC</name>
                            <description>ELC_GPTC Event Source Counter Count Up Enable</description>
                            <lsb>18</lsb>
                            <msb>18</msb>
                            <access>read-write</access>
                            <enumeratedValues>
                                <enumeratedValue>
                                    <name>0</name>
                                    <description>Counter count up disabled at the ELC_GPTC input</description>
                                    <value>#0</value>
                                </enumeratedValue>
                                <enumeratedValue>
                                    <name>1</name>
                                    <description>Counter count up enabled at the ELC_GPTC input</description>
                                    <value>#1</value>
                                </enumeratedValue>
                            </enumeratedValues>
                        </field>
                        <field>
                            <name>USELCD</name>
                            <description>ELC_GPTD Event Source Counter Count Up Enable</description>
                            <lsb>19</lsb>
                            <msb>19</msb>
                            <access>read-write</access>
                            <enumeratedValues>
                                <enumeratedValue>
                                    <name>0</name>
                                    <description>Counter count up disabled at the ELC_GPTD input</description>
                                    <value>#0</value>
                                </enumeratedValue>
                                <enumeratedValue>
                                    <name>1</name>
                                    <description>Counter count up enabled at the ELC_GPTD input</description>
                                    <value>#1</value>
                                </enumeratedValue>
                            </enumeratedValues>
                        </field>
                        <field>
                            <name>USELCE</name>
                            <description>ELC_GPTE Event Source Counter Count Up Enable</description>
                            <lsb>20</lsb>
                            <msb>20</msb>
                            <access>read-write</access>
                            <enumeratedValues>
                                <enumeratedValue>
                                    <name>0</name>
                                    <description>Counter count up disabled at the ELC_GPTE input</description>
                                    <value>#0</value>
                                </enumeratedValue>
                                <enumeratedValue>
                                    <name>1</name>
                                    <description>Counter count up enabled at the ELC_GPTE input</description>
                                    <value>#1</value>
                                </enumeratedValue>
                            </enumeratedValues>
                        </field>
                        <field>
                            <name>USELCF</name>
                            <description>ELC_GPTF Event Source Counter Count Up Enable</description>
                            <lsb>21</lsb>
                            <msb>21</msb>
                            <access>read-write</access>
                            <enumeratedValues>
                                <enumeratedValue>
                                    <name>0</name>
                                    <description>Counter count up disabled at the ELC_GPTF input</description>
                                    <value>#0</value>
                                </enumeratedValue>
                                <enumeratedValue>
                                    <name>1</name>
                                    <description>Counter count up enabled at the ELC_GPTF input</description>
                                    <value>#1</value>
                                </enumeratedValue>
                            </enumeratedValues>
                        </field>
                        <field>
                            <name>USELCG</name>
                            <description>ELC_GPTG Event Source Counter Count Up Enable</description>
                            <lsb>22</lsb>
                            <msb>22</msb>
                            <access>read-write</access>
                            <enumeratedValues>
                                <enumeratedValue>
                                    <name>0</name>
                                    <description>Counter count up disabled at the ELC_GPTG input</description>
                                    <value>#0</value>
                                </enumeratedValue>
                                <enumeratedValue>
                                    <name>1</name>
                                    <description>Counter count up enabled at the ELC_GPTG input</description>
                                    <value>#1</value>
                                </enumeratedValue>
                            </enumeratedValues>
                        </field>
                        <field>
                            <name>USELCH</name>
                            <description>ELC_GPTH Event Source Counter Count Up Enable</description>
                            <lsb>23</lsb>
                            <msb>23</msb>
                            <access>read-write</access>
                            <enumeratedValues>
                                <enumeratedValue>
                                    <name>0</name>
                                    <description>Counter count up disabled at the ELC_GPTH input</description>
                                    <value>#0</value>
                                </enumeratedValue>
                                <enumeratedValue>
                                    <name>1</name>
                                    <description>Counter count up enabled at the ELC_GPTH input</description>
                                    <value>#1</value>
                                </enumeratedValue>
                            </enumeratedValues>
                        </field>
                    </fields>
                </register>
                <register>
                    <name>GTDNSR</name>
                    <description>General PWM Timer Down Count Source Select Register</description>
                    <addressOffset>0x20</addressOffset>
                    <size>32</size>
                    <access>read-write</access>
                    <resetValue>0x00000000</resetValue>
                    <resetMask>0xffffffff</resetMask>
                    <fields>
                        <field>
                            <name>DSGTRGAR</name>
                            <description>GTETRGA Pin Rising Input Source Counter Count Down Enable</description>
                            <lsb>0</lsb>
                            <msb>0</msb>
                            <access>read-write</access>
                            <enumeratedValues>
                                <enumeratedValue>
                                    <name>0</name>
                                    <description>Counter count down disabled on the rising edge of GTETRGA input</description>
                                    <value>#0</value>
                                </enumeratedValue>
                                <enumeratedValue>
                                    <name>1</name>
                                    <description>Counter count down enabled on the rising edge of GTETRGA input</description>
                                    <value>#1</value>
                                </enumeratedValue>
                            </enumeratedValues>
                        </field>
                        <field>
                            <name>DSGTRGAF</name>
                            <description>GTETRGA Pin Falling Input Source Counter Count Down Enable</description>
                            <lsb>1</lsb>
                            <msb>1</msb>
                            <access>read-write</access>
                            <enumeratedValues>
                                <enumeratedValue>
                                    <name>0</name>
                                    <description>Counter count down disabled on the falling edge of GTETRGA input</description>
                                    <value>#0</value>
                                </enumeratedValue>
                                <enumeratedValue>
                                    <name>1</name>
                                    <description>Counter count down enabled on the falling edge of GTETRGA input</description>
                                    <value>#1</value>
                                </enumeratedValue>
                            </enumeratedValues>
                        </field>
                        <field>
                            <name>DSGTRGBR</name>
                            <description>GTETRGB Pin Rising Input Source Counter Count Down Enable</description>
                            <lsb>2</lsb>
                            <msb>2</msb>
                            <access>read-write</access>
                            <enumeratedValues>
                                <enumeratedValue>
                                    <name>0</name>
                                    <description>Counter count down disabled on the rising edge of GTETRGB input</description>
                                    <value>#0</value>
                                </enumeratedValue>
                                <enumeratedValue>
                                    <name>1</name>
                                    <description>Counter count down enabled on the rising edge of GTETRGB input</description>
                                    <value>#1</value>
                                </enumeratedValue>
                            </enumeratedValues>
                        </field>
                        <field>
                            <name>DSGTRGBF</name>
                            <description>GTETRGB Pin Falling Input Source Counter Count Down Enable</description>
                            <lsb>3</lsb>
                            <msb>3</msb>
                            <access>read-write</access>
                            <enumeratedValues>
                                <enumeratedValue>
                                    <name>0</name>
                                    <description>Counter count down disabled on the falling edge of GTETRGB input</description>
                                    <value>#0</value>
                                </enumeratedValue>
                                <enumeratedValue>
                                    <name>1</name>
                                    <description>Counter count down enabled on the falling edge of GTETRGB input</description>
                                    <value>#1</value>
                                </enumeratedValue>
                            </enumeratedValues>
                        </field>
                        <field>
                            <name>DSGTRGCR</name>
                            <description>GTETRGC Pin Rising Input Source Counter Count Down Enable</description>
                            <lsb>4</lsb>
                            <msb>4</msb>
                            <access>read-write</access>
                            <enumeratedValues>
                                <enumeratedValue>
                                    <name>0</name>
                                    <description>Counter count down disabled on the rising edge of GTETRGC input</description>
                                    <value>#0</value>
                                </enumeratedValue>
                                <enumeratedValue>
                                    <name>1</name>
                                    <description>Counter count down enabled on the rising edge of GTETRGC input</description>
                                    <value>#1</value>
                                </enumeratedValue>
                            </enumeratedValues>
                        </field>
                        <field>
                            <name>DSGTRGCF</name>
                            <description>GTETRGC Pin Falling Input Source Counter Count Down Enable</description>
                            <lsb>5</lsb>
                            <msb>5</msb>
                            <access>read-write</access>
                            <enumeratedValues>
                                <enumeratedValue>
                                    <name>0</name>
                                    <description>Counter count down disabled on the falling edge of GTETRGC input</description>
                                    <value>#0</value>
                                </enumeratedValue>
                                <enumeratedValue>
                                    <name>1</name>
                                    <description>Counter count down enabled on the falling edge of GTETRGC input</description>
                                    <value>#1</value>
                                </enumeratedValue>
                            </enumeratedValues>
                        </field>
                        <field>
                            <name>DSGTRGDR</name>
                            <description>GTETRGD Pin Rising Input Source Counter Count Down Enable</description>
                            <lsb>6</lsb>
                            <msb>6</msb>
                            <access>read-write</access>
                            <enumeratedValues>
                                <enumeratedValue>
                                    <name>0</name>
                                    <description>Counter count down disabled on the rising edge of GTETRGD input</description>
                                    <value>#0</value>
                                </enumeratedValue>
                                <enumeratedValue>
                                    <name>1</name>
                                    <description>Counter count down enabled on the rising edge of GTETRGD input</description>
                                    <value>#1</value>
                                </enumeratedValue>
                            </enumeratedValues>
                        </field>
                        <field>
                            <name>DSGTRGDF</name>
                            <description>GTETRGD Pin Falling Input Source Counter Count Down Enable</description>
                            <lsb>7</lsb>
                            <msb>7</msb>
                            <access>read-write</access>
                            <enumeratedValues>
                                <enumeratedValue>
                                    <name>0</name>
                                    <description>Counter count down disabled on the falling edge of GTETRGD input</description>
                                    <value>#0</value>
                                </enumeratedValue>
                                <enumeratedValue>
                                    <name>1</name>
                                    <description>Counter count down enabled on the falling edge of GTETRGD input</description>
                                    <value>#1</value>
                                </enumeratedValue>
                            </enumeratedValues>
                        </field>
                        <field>
                            <name>DSCARBL</name>
                            <description>GTIOCnA Pin Rising Input during GTIOCnB Value Low Source Counter Count Down Enable</description>
                            <lsb>8</lsb>
                            <msb>8</msb>
                            <access>read-write</access>
                            <enumeratedValues>
                                <enumeratedValue>
                                    <name>0</name>
                                    <description>Counter count down disabled on the rising edge of GTIOCnA input when GTIOCnB input is 0</description>
                                    <value>#0</value>
                                </enumeratedValue>
                                <enumeratedValue>
                                    <name>1</name>
                                    <description>Counter count down enabled on the rising edge of GTIOCnA input when GTIOCnB input is 0</description>
                                    <value>#1</value>
                                </enumeratedValue>
                            </enumeratedValues>
                        </field>
                        <field>
                            <name>DSCARBH</name>
                            <description>GTIOCnA Pin Rising Input during GTIOCnB Value High Source Counter Count Down Enable</description>
                            <lsb>9</lsb>
                            <msb>9</msb>
                            <access>read-write</access>
                            <enumeratedValues>
                                <enumeratedValue>
                                    <name>0</name>
                                    <description>Counter count down disabled on the rising edge of GTIOCnA input when GTIOCnB input is 1</description>
                                    <value>#0</value>
                                </enumeratedValue>
                                <enumeratedValue>
                                    <name>1</name>
                                    <description>Counter count down enabled on the rising edge of GTIOCnA input when GTIOCnB input is 1</description>
                                    <value>#1</value>
                                </enumeratedValue>
                            </enumeratedValues>
                        </field>
                        <field>
                            <name>DSCAFBL</name>
                            <description>GTIOCnA Pin Falling Input during GTIOCnB Value Low Source Counter Count Down Enable</description>
                            <lsb>10</lsb>
                            <msb>10</msb>
                            <access>read-write</access>
                            <enumeratedValues>
                                <enumeratedValue>
                                    <name>0</name>
                                    <description>Counter count down disabled on the falling edge of GTIOCnA input when GTIOCnB input is 0</description>
                                    <value>#0</value>
                                </enumeratedValue>
                                <enumeratedValue>
                                    <name>1</name>
                                    <description>Counter count down enabled on the falling edge of GTIOCnA input when GTIOCnB input is 0</description>
                                    <value>#1</value>
                                </enumeratedValue>
                            </enumeratedValues>
                        </field>
                        <field>
                            <name>DSCAFBH</name>
                            <description>GTIOCnA Pin Falling Input during GTIOCnB Value High Source Counter Count Down Enable</description>
                            <lsb>11</lsb>
                            <msb>11</msb>
                            <access>read-write</access>
                            <enumeratedValues>
                                <enumeratedValue>
                                    <name>0</name>
                                    <description>Counter count down disabled on the falling edge of GTIOCnA input when GTIOCnB input is 1</description>
                                    <value>#0</value>
                                </enumeratedValue>
                                <enumeratedValue>
                                    <name>1</name>
                                    <description>Counter count down enabled on the falling edge of GTIOCnA input when GTIOCnB input is 1</description>
                                    <value>#1</value>
                                </enumeratedValue>
                            </enumeratedValues>
                        </field>
                        <field>
                            <name>DSCBRAL</name>
                            <description>GTIOCnB Pin Rising Input during GTIOCnA Value Low Source Counter Count Down Enable</description>
                            <lsb>12</lsb>
                            <msb>12</msb>
                            <access>read-write</access>
                            <enumeratedValues>
                                <enumeratedValue>
                                    <name>0</name>
                                    <description>Counter count down disabled on the rising edge of GTIOCnB input when GTIOCnA input is 0</description>
                                    <value>#0</value>
                                </enumeratedValue>
                                <enumeratedValue>
                                    <name>1</name>
                                    <description>Counter count down enabled on the rising edge of GTIOCnB input when GTIOCnA input is 0</description>
                                    <value>#1</value>
                                </enumeratedValue>
                            </enumeratedValues>
                        </field>
                        <field>
                            <name>DSCBRAH</name>
                            <description>GTIOCnB Pin Rising Input during GTIOCnA Value High Source Counter Count Down Enable</description>
                            <lsb>13</lsb>
                            <msb>13</msb>
                            <access>read-write</access>
                            <enumeratedValues>
                                <enumeratedValue>
                                    <name>0</name>
                                    <description>Counter count down disabled on the rising edge of GTIOCnB input when GTIOCnA input is 1</description>
                                    <value>#0</value>
                                </enumeratedValue>
                                <enumeratedValue>
                                    <name>1</name>
                                    <description>Counter count down enabled on the rising edge of GTIOCnB input when GTIOCnA input is 1</description>
                                    <value>#1</value>
                                </enumeratedValue>
                            </enumeratedValues>
                        </field>
                        <field>
                            <name>DSCBFAL</name>
                            <description>GTIOCnB Pin Falling Input during GTIOCnA Value Low Source Counter Count Down Enable</description>
                            <lsb>14</lsb>
                            <msb>14</msb>
                            <access>read-write</access>
                            <enumeratedValues>
                                <enumeratedValue>
                                    <name>0</name>
                                    <description>Counter count down disabled on the falling edge of GTIOCnB input when GTIOCnA input is 0</description>
                                    <value>#0</value>
                                </enumeratedValue>
                                <enumeratedValue>
                                    <name>1</name>
                                    <description>Counter count down enabled on the falling edge of GTIOCnB input when GTIOCnA input is 0</description>
                                    <value>#1</value>
                                </enumeratedValue>
                            </enumeratedValues>
                        </field>
                        <field>
                            <name>DSCBFAH</name>
                            <description>GTIOCnB Pin Falling Input during GTIOCnA Value High Source Counter Count Down Enable</description>
                            <lsb>15</lsb>
                            <msb>15</msb>
                            <access>read-write</access>
                            <enumeratedValues>
                                <enumeratedValue>
                                    <name>0</name>
                                    <description>Counter count down disabled on the falling edge of GTIOCnB input when GTIOCnA input is 1</description>
                                    <value>#0</value>
                                </enumeratedValue>
                                <enumeratedValue>
                                    <name>1</name>
                                    <description>Counter count down enabled on the falling edge of GTIOCnB input when GTIOCnA input is 1</description>
                                    <value>#1</value>
                                </enumeratedValue>
                            </enumeratedValues>
                        </field>
                        <field>
                            <name>DSELCA</name>
                            <description>ELC_GPTA Event Source Counter Count Down Enable</description>
                            <lsb>16</lsb>
                            <msb>16</msb>
                            <access>read-write</access>
                            <enumeratedValues>
                                <enumeratedValue>
                                    <name>0</name>
                                    <description>Counter count down disabled at the ELC_GPTA input</description>
                                    <value>#0</value>
                                </enumeratedValue>
                                <enumeratedValue>
                                    <name>1</name>
                                    <description>Counter count down enabled at the ELC_GPTA input</description>
                                    <value>#1</value>
                                </enumeratedValue>
                            </enumeratedValues>
                        </field>
                        <field>
                            <name>DSELCB</name>
                            <description>ELC_GPTB Event Source Counter Count Down Enable</description>
                            <lsb>17</lsb>
                            <msb>17</msb>
                            <access>read-write</access>
                            <enumeratedValues>
                                <enumeratedValue>
                                    <name>0</name>
                                    <description>Counter count down disabled at the ELC_GPTB input</description>
                                    <value>#0</value>
                                </enumeratedValue>
                                <enumeratedValue>
                                    <name>1</name>
                                    <description>Counter count down enabled at the ELC_GPTB input</description>
                                    <value>#1</value>
                                </enumeratedValue>
                            </enumeratedValues>
                        </field>
                        <field>
                            <name>DSELCC</name>
                            <description>ELC_GPTC Event Source Counter Count Down Enable</description>
                            <lsb>18</lsb>
                            <msb>18</msb>
                            <access>read-write</access>
                            <enumeratedValues>
                                <enumeratedValue>
                                    <name>0</name>
                                    <description>Counter count down disabled at the ELC_GPTC input</description>
                                    <value>#0</value>
                                </enumeratedValue>
                                <enumeratedValue>
                                    <name>1</name>
                                    <description>Counter count down enabled at the ELC_GPTC input</description>
                                    <value>#1</value>
                                </enumeratedValue>
                            </enumeratedValues>
                        </field>
                        <field>
                            <name>DSELCD</name>
                            <description>ELC_GPTD Event Source Counter Count Down Enable</description>
                            <lsb>19</lsb>
                            <msb>19</msb>
                            <access>read-write</access>
                            <enumeratedValues>
                                <enumeratedValue>
                                    <name>0</name>
                                    <description>Counter count down disabled at the ELC_GPTD input</description>
                                    <value>#0</value>
                                </enumeratedValue>
                                <enumeratedValue>
                                    <name>1</name>
                                    <description>Counter count down enabled at the ELC_GPTD input</description>
                                    <value>#1</value>
                                </enumeratedValue>
                            </enumeratedValues>
                        </field>
                        <field>
                            <name>DSELCE</name>
                            <description>ELC_GPTE Event Source Counter Count Down Enable</description>
                            <lsb>20</lsb>
                            <msb>20</msb>
                            <access>read-write</access>
                            <enumeratedValues>
                                <enumeratedValue>
                                    <name>0</name>
                                    <description>Counter count down disabled at the ELC_GPTE input</description>
                                    <value>#0</value>
                                </enumeratedValue>
                                <enumeratedValue>
                                    <name>1</name>
                                    <description>Counter count down enabled at the ELC_GPTE input</description>
                                    <value>#1</value>
                                </enumeratedValue>
                            </enumeratedValues>
                        </field>
                        <field>
                            <name>DSELCF</name>
                            <description>ELC_GPTF Event Source Counter Count Down Enable</description>
                            <lsb>21</lsb>
                            <msb>21</msb>
                            <access>read-write</access>
                            <enumeratedValues>
                                <enumeratedValue>
                                    <name>0</name>
                                    <description>Counter count down disabled at the ELC_GPTF input</description>
                                    <value>#0</value>
                                </enumeratedValue>
                                <enumeratedValue>
                                    <name>1</name>
                                    <description>Counter count down enabled at the ELC_GPTF input</description>
                                    <value>#1</value>
                                </enumeratedValue>
                            </enumeratedValues>
                        </field>
                        <field>
                            <name>DSELCG</name>
                            <description>ELC_GPTG Event Source Counter Count Down Enable</description>
                            <lsb>22</lsb>
                            <msb>22</msb>
                            <access>read-write</access>
                            <enumeratedValues>
                                <enumeratedValue>
                                    <name>0</name>
                                    <description>Counter count down disabled at the ELC_GPTG input</description>
                                    <value>#0</value>
                                </enumeratedValue>
                                <enumeratedValue>
                                    <name>1</name>
                                    <description>Counter count down enabled at the ELC_GPTG input</description>
                                    <value>#1</value>
                                </enumeratedValue>
                            </enumeratedValues>
                        </field>
                        <field>
                            <name>DSELCH</name>
                            <description>ELC_GPTF Event Source Counter Count Down Enable</description>
                            <lsb>23</lsb>
                            <msb>23</msb>
                            <access>read-write</access>
                            <enumeratedValues>
                                <enumeratedValue>
                                    <name>0</name>
                                    <description>Counter count down disabled at the ELC_GPTF input</description>
                                    <value>#0</value>
                                </enumeratedValue>
                                <enumeratedValue>
                                    <name>1</name>
                                    <description>Counter count down enabled at the ELC_GPTF input</description>
                                    <value>#1</value>
                                </enumeratedValue>
                            </enumeratedValues>
                        </field>
                    </fields>
                </register>
                <register>
                    <name>GTICASR</name>
                    <description>General PWM Timer Input Capture Source Select Register A</description>
                    <addressOffset>0x24</addressOffset>
                    <size>32</size>
                    <access>read-write</access>
                    <resetValue>0x00000000</resetValue>
                    <resetMask>0xffffffff</resetMask>
                    <fields>
                        <field>
                            <name>ASGTRGAR</name>
                            <description>GTETRGA Pin Rising Input Source GTCCRA Input Capture Enable</description>
                            <lsb>0</lsb>
                            <msb>0</msb>
                            <access>read-write</access>
                            <enumeratedValues>
                                <enumeratedValue>
                                    <name>0</name>
                                    <description>GTCCRA input capture disabled on the rising edge of GTETRGA input</description>
                                    <value>#0</value>
                                </enumeratedValue>
                                <enumeratedValue>
                                    <name>1</name>
                                    <description>GTCCRA input capture enabled on the rising edge of GTETRGA input</description>
                                    <value>#1</value>
                                </enumeratedValue>
                            </enumeratedValues>
                        </field>
                        <field>
                            <name>ASGTRGAF</name>
                            <description>GTETRGA Pin Falling Input Source GTCCRA Input Capture Enable</description>
                            <lsb>1</lsb>
                            <msb>1</msb>
                            <access>read-write</access>
                            <enumeratedValues>
                                <enumeratedValue>
                                    <name>0</name>
                                    <description>GTCCRA input capture disabled on the falling edge of GTETRGA input</description>
                                    <value>#0</value>
                                </enumeratedValue>
                                <enumeratedValue>
                                    <name>1</name>
                                    <description>GTCCRA input capture enabled on the falling edge of GTETRGA input</description>
                                    <value>#1</value>
                                </enumeratedValue>
                            </enumeratedValues>
                        </field>
                        <field>
                            <name>ASGTRGBR</name>
                            <description>GTETRGB Pin Rising Input Source GTCCRA Input Capture Enable</description>
                            <lsb>2</lsb>
                            <msb>2</msb>
                            <access>read-write</access>
                            <enumeratedValues>
                                <enumeratedValue>
                                    <name>0</name>
                                    <description>GTCCRA input capture disabled on the rising edge of GTETRGB input</description>
                                    <value>#0</value>
                                </enumeratedValue>
                                <enumeratedValue>
                                    <name>1</name>
                                    <description>GTCCRA input capture enabled on the rising edge of GTETRGB input</description>
                                    <value>#1</value>
                                </enumeratedValue>
                            </enumeratedValues>
                        </field>
                        <field>
                            <name>ASGTRGBF</name>
                            <description>GTETRGB Pin Falling Input Source GTCCRA Input Capture Enable</description>
                            <lsb>3</lsb>
                            <msb>3</msb>
                            <access>read-write</access>
                            <enumeratedValues>
                                <enumeratedValue>
                                    <name>0</name>
                                    <description>GTCCRA input capture disabled on the falling edge of GTETRGB input</description>
                                    <value>#0</value>
                                </enumeratedValue>
                                <enumeratedValue>
                                    <name>1</name>
                                    <description>GTCCRA input capture enabled on the falling edge of GTETRGB input</description>
                                    <value>#1</value>
                                </enumeratedValue>
                            </enumeratedValues>
                        </field>
                        <field>
                            <name>ASGTRGCR</name>
                            <description>GTETRGC Pin Rising Input Source GTCCRA Input Capture Enable</description>
                            <lsb>4</lsb>
                            <msb>4</msb>
                            <access>read-write</access>
                            <enumeratedValues>
                                <enumeratedValue>
                                    <name>0</name>
                                    <description>GTCCRA input capture disabled on the rising edge of GTETRGC input</description>
                                    <value>#0</value>
                                </enumeratedValue>
                                <enumeratedValue>
                                    <name>1</name>
                                    <description>GTCCRA input capture enabled on the rising edge of GTETRGC input</description>
                                    <value>#1</value>
                                </enumeratedValue>
                            </enumeratedValues>
                        </field>
                        <field>
                            <name>ASGTRGCF</name>
                            <description>GTETRGC Pin Falling Input Source GTCCRA Input Capture Enable</description>
                            <lsb>5</lsb>
                            <msb>5</msb>
                            <access>read-write</access>
                            <enumeratedValues>
                                <enumeratedValue>
                                    <name>0</name>
                                    <description>GTCCRA input capture disabled on the falling edge of GTETRGC input</description>
                                    <value>#0</value>
                                </enumeratedValue>
                                <enumeratedValue>
                                    <name>1</name>
                                    <description>GTCCRA input capture enabled on the falling edge of GTETRGC input</description>
                                    <value>#1</value>
                                </enumeratedValue>
                            </enumeratedValues>
                        </field>
                        <field>
                            <name>ASGTRGDR</name>
                            <description>GTETRGD Pin Rising Input Source GTCCRA Input Capture Enable</description>
                            <lsb>6</lsb>
                            <msb>6</msb>
                            <access>read-write</access>
                            <enumeratedValues>
                                <enumeratedValue>
                                    <name>0</name>
                                    <description>GTCCRA input capture disabled on the rising edge of GTETRGD input</description>
                                    <value>#0</value>
                                </enumeratedValue>
                                <enumeratedValue>
                                    <name>1</name>
                                    <description>GTCCRA input capture enabled on the rising edge of GTETRGD input</description>
                                    <value>#1</value>
                                </enumeratedValue>
                            </enumeratedValues>
                        </field>
                        <field>
                            <name>ASGTRGDF</name>
                            <description>GTETRGD Pin Falling Input Source GTCCRA Input Capture Enable</description>
                            <lsb>7</lsb>
                            <msb>7</msb>
                            <access>read-write</access>
                            <enumeratedValues>
                                <enumeratedValue>
                                    <name>0</name>
                                    <description>GTCCRA input capture disabled on the falling edge of GTETRGD input</description>
                                    <value>#0</value>
                                </enumeratedValue>
                                <enumeratedValue>
                                    <name>1</name>
                                    <description>GTCCRA input capture enabled on the falling edge of GTETRGD input</description>
                                    <value>#1</value>
                                </enumeratedValue>
                            </enumeratedValues>
                        </field>
                        <field>
                            <name>ASCARBL</name>
                            <description>GTIOCnA Pin Rising Input during GTIOCnB Value Low Source GTCCRA Input Capture Enable</description>
                            <lsb>8</lsb>
                            <msb>8</msb>
                            <access>read-write</access>
                            <enumeratedValues>
                                <enumeratedValue>
                                    <name>0</name>
                                    <description>GTCCRA input capture disabled on the rising edge of GTIOCnA input when GTIOCnB input is 0</description>
                                    <value>#0</value>
                                </enumeratedValue>
                                <enumeratedValue>
                                    <name>1</name>
                                    <description>GTCCRA input capture enabled on the rising edge of GTIOCnA input when GTIOCnB input is 0</description>
                                    <value>#1</value>
                                </enumeratedValue>
                            </enumeratedValues>
                        </field>
                        <field>
                            <name>ASCARBH</name>
                            <description>GTIOCnA Pin Rising Input during GTIOCnB Value High Source GTCCRA Input Capture Enable</description>
                            <lsb>9</lsb>
                            <msb>9</msb>
                            <access>read-write</access>
                            <enumeratedValues>
                                <enumeratedValue>
                                    <name>0</name>
                                    <description>GTCCRA input capture disabled on the rising edge of GTIOCnA input when GTIOCnB input is 1</description>
                                    <value>#0</value>
                                </enumeratedValue>
                                <enumeratedValue>
                                    <name>1</name>
                                    <description>GTCCRA input capture enabled on the rising edge of GTIOCnA input when GTIOCnB input is 1</description>
                                    <value>#1</value>
                                </enumeratedValue>
                            </enumeratedValues>
                        </field>
                        <field>
                            <name>ASCAFBL</name>
                            <description>GTIOCnA Pin Falling Input during GTIOCnB Value Low Source GTCCRA Input Capture Enable</description>
                            <lsb>10</lsb>
                            <msb>10</msb>
                            <access>read-write</access>
                            <enumeratedValues>
                                <enumeratedValue>
                                    <name>0</name>
                                    <description>GTCCRA input capture disabled on the falling edge of GTIOCnA input when GTIOCnB input is 0</description>
                                    <value>#0</value>
                                </enumeratedValue>
                                <enumeratedValue>
                                    <name>1</name>
                                    <description>GTCCRA input capture enabled on the falling edge of GTIOCnA input when GTIOCnB input is 0</description>
                                    <value>#1</value>
                                </enumeratedValue>
                            </enumeratedValues>
                        </field>
                        <field>
                            <name>ASCAFBH</name>
                            <description>GTIOCnA Pin Falling Input during GTIOCnB Value High Source GTCCRA Input Capture Enable</description>
                            <lsb>11</lsb>
                            <msb>11</msb>
                            <access>read-write</access>
                            <enumeratedValues>
                                <enumeratedValue>
                                    <name>0</name>
                                    <description>GTCCRA input capture disabled on the falling edge of GTIOCnA input when GTIOCnB input is 1</description>
                                    <value>#0</value>
                                </enumeratedValue>
                                <enumeratedValue>
                                    <name>1</name>
                                    <description>GTCCRA input capture enabled on the falling edge of GTIOCnA input when GTIOCnB input is 1</description>
                                    <value>#1</value>
                                </enumeratedValue>
                            </enumeratedValues>
                        </field>
                        <field>
                            <name>ASCBRAL</name>
                            <description>GTIOCnB Pin Rising Input during GTIOCnA Value Low Source GTCCRA Input Capture Enable</description>
                            <lsb>12</lsb>
                            <msb>12</msb>
                            <access>read-write</access>
                            <enumeratedValues>
                                <enumeratedValue>
                                    <name>0</name>
                                    <description>GTCCRA input capture disabled on the rising edge of GTIOCnB input when GTIOCnA input is 0</description>
                                    <value>#0</value>
                                </enumeratedValue>
                                <enumeratedValue>
                                    <name>1</name>
                                    <description>GTCCRA input capture enabled on the rising edge of GTIOCnB input when GTIOCnA input is 0</description>
                                    <value>#1</value>
                                </enumeratedValue>
                            </enumeratedValues>
                        </field>
                        <field>
                            <name>ASCBRAH</name>
                            <description>GTIOCnB Pin Rising Input during GTIOCnA Value High Source GTCCRA Input Capture Enable</description>
                            <lsb>13</lsb>
                            <msb>13</msb>
                            <access>read-write</access>
                            <enumeratedValues>
                                <enumeratedValue>
                                    <name>0</name>
                                    <description>GTCCRA input capture disabled on the rising edge of GTIOCnB input when GTIOCnA input is 1</description>
                                    <value>#0</value>
                                </enumeratedValue>
                                <enumeratedValue>
                                    <name>1</name>
                                    <description>GTCCRA input capture enabled on the rising edge of GTIOCnB input when GTIOCnA input is 1</description>
                                    <value>#1</value>
                                </enumeratedValue>
                            </enumeratedValues>
                        </field>
                        <field>
                            <name>ASCBFAL</name>
                            <description>GTIOCnB Pin Falling Input during GTIOCnA Value Low Source GTCCRA Input Capture Enable</description>
                            <lsb>14</lsb>
                            <msb>14</msb>
                            <access>read-write</access>
                            <enumeratedValues>
                                <enumeratedValue>
                                    <name>0</name>
                                    <description>GTCCRA input capture disabled on the falling edge of GTIOCnB input when GTIOCnA input is 0</description>
                                    <value>#0</value>
                                </enumeratedValue>
                                <enumeratedValue>
                                    <name>1</name>
                                    <description>GTCCRA input capture enabled on the falling edge of GTIOCnB input when GTIOCnA input is 0</description>
                                    <value>#1</value>
                                </enumeratedValue>
                            </enumeratedValues>
                        </field>
                        <field>
                            <name>ASCBFAH</name>
                            <description>GTIOCnB Pin Falling Input during GTIOCnA Value High Source GTCCRA Input Capture Enable</description>
                            <lsb>15</lsb>
                            <msb>15</msb>
                            <access>read-write</access>
                            <enumeratedValues>
                                <enumeratedValue>
                                    <name>0</name>
                                    <description>GTCCRA input capture disabled on the falling edge of GTIOCnB input when GTIOCnA input is 1</description>
                                    <value>#0</value>
                                </enumeratedValue>
                                <enumeratedValue>
                                    <name>1</name>
                                    <description>GTCCRA input capture enabled on the falling edge of GTIOCnB input when GTIOCnA input is 1</description>
                                    <value>#1</value>
                                </enumeratedValue>
                            </enumeratedValues>
                        </field>
                        <field>
                            <name>ASELCA</name>
                            <description>ELC_GPTA Event Source GTCCRA Input Capture Enable</description>
                            <lsb>16</lsb>
                            <msb>16</msb>
                            <access>read-write</access>
                            <enumeratedValues>
                                <enumeratedValue>
                                    <name>0</name>
                                    <description>GTCCRA input capture disabled at the ELC_GPTA input</description>
                                    <value>#0</value>
                                </enumeratedValue>
                                <enumeratedValue>
                                    <name>1</name>
                                    <description>GTCCRA input capture enabled at the ELC_GPTA input</description>
                                    <value>#1</value>
                                </enumeratedValue>
                            </enumeratedValues>
                        </field>
                        <field>
                            <name>ASELCB</name>
                            <description>ELC_GPTB Event Source GTCCRA Input Capture Enable</description>
                            <lsb>17</lsb>
                            <msb>17</msb>
                            <access>read-write</access>
                            <enumeratedValues>
                                <enumeratedValue>
                                    <name>0</name>
                                    <description>GTCCRA input capture disabled at the ELC_GPTB input</description>
                                    <value>#0</value>
                                </enumeratedValue>
                                <enumeratedValue>
                                    <name>1</name>
                                    <description>GTCCRA input capture enabled at the ELC_GPTB input</description>
                                    <value>#1</value>
                                </enumeratedValue>
                            </enumeratedValues>
                        </field>
                        <field>
                            <name>ASELCC</name>
                            <description>ELC_GPTC Event Source GTCCRA Input Capture Enable</description>
                            <lsb>18</lsb>
                            <msb>18</msb>
                            <access>read-write</access>
                            <enumeratedValues>
                                <enumeratedValue>
                                    <name>0</name>
                                    <description>GTCCRA input capture disabled at the ELC_GPTC input</description>
                                    <value>#0</value>
                                </enumeratedValue>
                                <enumeratedValue>
                                    <name>1</name>
                                    <description>GTCCRA input capture enabled at the ELC_GPTC input</description>
                                    <value>#1</value>
                                </enumeratedValue>
                            </enumeratedValues>
                        </field>
                        <field>
                            <name>ASELCD</name>
                            <description>ELC_GPTD Event Source GTCCRA Input Capture Enable</description>
                            <lsb>19</lsb>
                            <msb>19</msb>
                            <access>read-write</access>
                            <enumeratedValues>
                                <enumeratedValue>
                                    <name>0</name>
                                    <description>GTCCRA input capture disabled at the ELC_GPTD input</description>
                                    <value>#0</value>
                                </enumeratedValue>
                                <enumeratedValue>
                                    <name>1</name>
                                    <description>GTCCRA input capture enabled at the ELC_GPTD input</description>
                                    <value>#1</value>
                                </enumeratedValue>
                            </enumeratedValues>
                        </field>
                        <field>
                            <name>ASELCE</name>
                            <description>ELC_GPTE Event Source GTCCRA Input Capture Enable</description>
                            <lsb>20</lsb>
                            <msb>20</msb>
                            <access>read-write</access>
                            <enumeratedValues>
                                <enumeratedValue>
                                    <name>0</name>
                                    <description>GTCCRA input capture disabled at the ELC_GPTE input</description>
                                    <value>#0</value>
                                </enumeratedValue>
                                <enumeratedValue>
                                    <name>1</name>
                                    <description>GTCCRA input capture enabled at the ELC_GPTE input</description>
                                    <value>#1</value>
                                </enumeratedValue>
                            </enumeratedValues>
                        </field>
                        <field>
                            <name>ASELCF</name>
                            <description>ELC_GPTF Event Source GTCCRA Input Capture Enable</description>
                            <lsb>21</lsb>
                            <msb>21</msb>
                            <access>read-write</access>
                            <enumeratedValues>
                                <enumeratedValue>
                                    <name>0</name>
                                    <description>GTCCRA input capture disabled at the ELC_GPTF input</description>
                                    <value>#0</value>
                                </enumeratedValue>
                                <enumeratedValue>
                                    <name>1</name>
                                    <description>GTCCRA input capture enabled at the ELC_GPTF input</description>
                                    <value>#1</value>
                                </enumeratedValue>
                            </enumeratedValues>
                        </field>
                        <field>
                            <name>ASELCG</name>
                            <description>ELC_GPTG Event Source GTCCRA Input Capture Enable</description>
                            <lsb>22</lsb>
                            <msb>22</msb>
                            <access>read-write</access>
                            <enumeratedValues>
                                <enumeratedValue>
                                    <name>0</name>
                                    <description>GTCCRA input capture disabled at the ELC_GPTG input</description>
                                    <value>#0</value>
                                </enumeratedValue>
                                <enumeratedValue>
                                    <name>1</name>
                                    <description>GTCCRA input capture enabled at the ELC_GPTG input</description>
                                    <value>#1</value>
                                </enumeratedValue>
                            </enumeratedValues>
                        </field>
                        <field>
                            <name>ASELCH</name>
                            <description>ELC_GPTH Event Source GTCCRA Input Capture Enable</description>
                            <lsb>23</lsb>
                            <msb>23</msb>
                            <access>read-write</access>
                            <enumeratedValues>
                                <enumeratedValue>
                                    <name>0</name>
                                    <description>GTCCRA input capture disabled at the ELC_GPTH input</description>
                                    <value>#0</value>
                                </enumeratedValue>
                                <enumeratedValue>
                                    <name>1</name>
                                    <description>GTCCRA input capture enabled at the ELC_GPTH input</description>
                                    <value>#1</value>
                                </enumeratedValue>
                            </enumeratedValues>
                        </field>
                    </fields>
                </register>
                <register>
                    <name>GTICBSR</name>
                    <description>General PWM Timer Input Capture Source Select Register B</description>
                    <addressOffset>0x28</addressOffset>
                    <size>32</size>
                    <access>read-write</access>
                    <resetValue>0x00000000</resetValue>
                    <resetMask>0xffffffff</resetMask>
                    <fields>
                        <field>
                            <name>BSGTRGAR</name>
                            <description>GTETRGA Pin Rising Input Source GTCCRB Input Capture Enable</description>
                            <lsb>0</lsb>
                            <msb>0</msb>
                            <access>read-write</access>
                            <enumeratedValues>
                                <enumeratedValue>
                                    <name>0</name>
                                    <description>GTCCRB input capture disabled on the rising edge of GTETRGA input</description>
                                    <value>#0</value>
                                </enumeratedValue>
                                <enumeratedValue>
                                    <name>1</name>
                                    <description>GTCCRB input capture enabled on the rising edge of GTETRGA input</description>
                                    <value>#1</value>
                                </enumeratedValue>
                            </enumeratedValues>
                        </field>
                        <field>
                            <name>BSGTRGAF</name>
                            <description>GTETRGA Pin Falling Input Source GTCCRB Input Capture Enable</description>
                            <lsb>1</lsb>
                            <msb>1</msb>
                            <access>read-write</access>
                            <enumeratedValues>
                                <enumeratedValue>
                                    <name>0</name>
                                    <description>GTCCRB input capture disabled on the falling edge of GTETRGA input</description>
                                    <value>#0</value>
                                </enumeratedValue>
                                <enumeratedValue>
                                    <name>1</name>
                                    <description>GTCCRB input capture enabled on the falling edge of GTETRGA input</description>
                                    <value>#1</value>
                                </enumeratedValue>
                            </enumeratedValues>
                        </field>
                        <field>
                            <name>BSGTRGBR</name>
                            <description>GTETRGB Pin Rising Input Source GTCCRB Input Capture Enable</description>
                            <lsb>2</lsb>
                            <msb>2</msb>
                            <access>read-write</access>
                            <enumeratedValues>
                                <enumeratedValue>
                                    <name>0</name>
                                    <description>GTCCRB input capture disabled on the rising edge of GTETRGB input</description>
                                    <value>#0</value>
                                </enumeratedValue>
                                <enumeratedValue>
                                    <name>1</name>
                                    <description>GTCCRB input capture enabled on the rising edge of GTETRGB input</description>
                                    <value>#1</value>
                                </enumeratedValue>
                            </enumeratedValues>
                        </field>
                        <field>
                            <name>BSGTRGBF</name>
                            <description>GTETRGB Pin Falling Input Source GTCCRB Input Capture Enable</description>
                            <lsb>3</lsb>
                            <msb>3</msb>
                            <access>read-write</access>
                            <enumeratedValues>
                                <enumeratedValue>
                                    <name>0</name>
                                    <description>GTCCRB input capture disabled on the falling edge of GTETRGB input</description>
                                    <value>#0</value>
                                </enumeratedValue>
                                <enumeratedValue>
                                    <name>1</name>
                                    <description>GTCCRB input capture enabled on the falling edge of GTETRGB input</description>
                                    <value>#1</value>
                                </enumeratedValue>
                            </enumeratedValues>
                        </field>
                        <field>
                            <name>BSGTRGCR</name>
                            <description>GTETRGC Pin Rising Input Source GTCCRB Input Capture Enable</description>
                            <lsb>4</lsb>
                            <msb>4</msb>
                            <access>read-write</access>
                            <enumeratedValues>
                                <enumeratedValue>
                                    <name>0</name>
                                    <description>GTCCRB input capture disabled on the rising edge of GTETRGC input</description>
                                    <value>#0</value>
                                </enumeratedValue>
                                <enumeratedValue>
                                    <name>1</name>
                                    <description>GTCCRB input capture enabled on the rising edge of GTETRGC input</description>
                                    <value>#1</value>
                                </enumeratedValue>
                            </enumeratedValues>
                        </field>
                        <field>
                            <name>BSGTRGCF</name>
                            <description>GTETRGC Pin Falling Input Source GTCCRB Input Capture Enable</description>
                            <lsb>5</lsb>
                            <msb>5</msb>
                            <access>read-write</access>
                            <enumeratedValues>
                                <enumeratedValue>
                                    <name>0</name>
                                    <description>GTCCRB input capture disabled on the falling edge of GTETRGC input</description>
                                    <value>#0</value>
                                </enumeratedValue>
                                <enumeratedValue>
                                    <name>1</name>
                                    <description>GTCCRB input capture enabled on the falling edge of GTETRGC input</description>
                                    <value>#1</value>
                                </enumeratedValue>
                            </enumeratedValues>
                        </field>
                        <field>
                            <name>BSGTRGDR</name>
                            <description>GTETRGD Pin Rising Input Source GTCCRB Input Capture Enable</description>
                            <lsb>6</lsb>
                            <msb>6</msb>
                            <access>read-write</access>
                            <enumeratedValues>
                                <enumeratedValue>
                                    <name>0</name>
                                    <description>GTCCRB input capture disabled on the rising edge of GTETRGD input</description>
                                    <value>#0</value>
                                </enumeratedValue>
                                <enumeratedValue>
                                    <name>1</name>
                                    <description>GTCCRB input capture enabled on the rising edge of GTETRGD input</description>
                                    <value>#1</value>
                                </enumeratedValue>
                            </enumeratedValues>
                        </field>
                        <field>
                            <name>BSGTRGDF</name>
                            <description>GTETRGD Pin Falling Input Source GTCCRB Input Capture Enable</description>
                            <lsb>7</lsb>
                            <msb>7</msb>
                            <access>read-write</access>
                            <enumeratedValues>
                                <enumeratedValue>
                                    <name>0</name>
                                    <description>GTCCRB input capture disabled on the falling edge of GTETRGD input</description>
                                    <value>#0</value>
                                </enumeratedValue>
                                <enumeratedValue>
                                    <name>1</name>
                                    <description>GTCCRB input capture enabled on the falling edge of GTETRGD input</description>
                                    <value>#1</value>
                                </enumeratedValue>
                            </enumeratedValues>
                        </field>
                        <field>
                            <name>BSCARBL</name>
                            <description>GTIOCnA Pin Rising Input during GTIOCnB Value Low Source GTCCRB Input Capture Enable</description>
                            <lsb>8</lsb>
                            <msb>8</msb>
                            <access>read-write</access>
                            <enumeratedValues>
                                <enumeratedValue>
                                    <name>0</name>
                                    <description>GTCCRB input capture disabled on the rising edge of GTIOCnA input when GTIOCnB input is 0</description>
                                    <value>#0</value>
                                </enumeratedValue>
                                <enumeratedValue>
                                    <name>1</name>
                                    <description>GTCCRB input capture enabled on the rising edge of GTIOCnA input when GTIOCnB input is 0</description>
                                    <value>#1</value>
                                </enumeratedValue>
                            </enumeratedValues>
                        </field>
                        <field>
                            <name>BSCARBH</name>
                            <description>GTIOCnA Pin Rising Input during GTIOCnB Value High Source GTCCRB Input Capture Enable</description>
                            <lsb>9</lsb>
                            <msb>9</msb>
                            <access>read-write</access>
                            <enumeratedValues>
                                <enumeratedValue>
                                    <name>0</name>
                                    <description>GTCCRB input capture disabled on the rising edge of GTIOCnA input when GTIOCnB input is 1</description>
                                    <value>#0</value>
                                </enumeratedValue>
                                <enumeratedValue>
                                    <name>1</name>
                                    <description>GTCCRB input capture enabled on the rising edge of GTIOCnA input when GTIOCnB input is 1</description>
                                    <value>#1</value>
                                </enumeratedValue>
                            </enumeratedValues>
                        </field>
                        <field>
                            <name>BSCAFBL</name>
                            <description>GTIOCnA Pin Falling Input during GTIOCnB Value Low Source GTCCRB Input Capture Enable</description>
                            <lsb>10</lsb>
                            <msb>10</msb>
                            <access>read-write</access>
                            <enumeratedValues>
                                <enumeratedValue>
                                    <name>0</name>
                                    <description>GTCCRB input capture disabled on the falling edge of GTIOCnA input when GTIOCnB input is 0</description>
                                    <value>#0</value>
                                </enumeratedValue>
                                <enumeratedValue>
                                    <name>1</name>
                                    <description>GTCCRB input capture enabled on the falling edge of GTIOCnA input when GTIOCnB input is 0</description>
                                    <value>#1</value>
                                </enumeratedValue>
                            </enumeratedValues>
                        </field>
                        <field>
                            <name>BSCAFBH</name>
                            <description>GTIOCnA Pin Falling Input during GTIOCnB Value High Source GTCCRB Input Capture Enable</description>
                            <lsb>11</lsb>
                            <msb>11</msb>
                            <access>read-write</access>
                            <enumeratedValues>
                                <enumeratedValue>
                                    <name>0</name>
                                    <description>GTCCRB input capture disabled on the falling edge of GTIOCnA input when GTIOCnB input is 1</description>
                                    <value>#0</value>
                                </enumeratedValue>
                                <enumeratedValue>
                                    <name>1</name>
                                    <description>GTCCRB input capture enabled on the falling edge of GTIOCnA input when GTIOCnB input is 1</description>
                                    <value>#1</value>
                                </enumeratedValue>
                            </enumeratedValues>
                        </field>
                        <field>
                            <name>BSCBRAL</name>
                            <description>GTIOCnB Pin Rising Input during GTIOCnA Value Low Source GTCCRB Input Capture Enable</description>
                            <lsb>12</lsb>
                            <msb>12</msb>
                            <access>read-write</access>
                            <enumeratedValues>
                                <enumeratedValue>
                                    <name>0</name>
                                    <description>GTCCRB input capture disabled on the rising edge of GTIOCnB input when GTIOCnA input is 0</description>
                                    <value>#0</value>
                                </enumeratedValue>
                                <enumeratedValue>
                                    <name>1</name>
                                    <description>GTCCRB input capture enabled on the rising edge of GTIOCnB input when GTIOCnA input is 0</description>
                                    <value>#1</value>
                                </enumeratedValue>
                            </enumeratedValues>
                        </field>
                        <field>
                            <name>BSCBRAH</name>
                            <description>GTIOCnB Pin Rising Input during GTIOCnA Value High Source GTCCRB Input Capture Enable</description>
                            <lsb>13</lsb>
                            <msb>13</msb>
                            <access>read-write</access>
                            <enumeratedValues>
                                <enumeratedValue>
                                    <name>0</name>
                                    <description>GTCCRB input capture disabled on the rising edge of GTIOCnB input when GTIOCnA input is 1</description>
                                    <value>#0</value>
                                </enumeratedValue>
                                <enumeratedValue>
                                    <name>1</name>
                                    <description>GTCCRB input capture enabled on the rising edge of GTIOCnB input when GTIOCnA input is 1</description>
                                    <value>#1</value>
                                </enumeratedValue>
                            </enumeratedValues>
                        </field>
                        <field>
                            <name>BSCBFAL</name>
                            <description>GTIOCnB Pin Falling Input during GTIOCnA Value Low Source GTCCRB Input Capture Enable</description>
                            <lsb>14</lsb>
                            <msb>14</msb>
                            <access>read-write</access>
                            <enumeratedValues>
                                <enumeratedValue>
                                    <name>0</name>
                                    <description>GTCCRB input capture disabled on the falling edge of GTIOCnB input when GTIOCnA input is 0</description>
                                    <value>#0</value>
                                </enumeratedValue>
                                <enumeratedValue>
                                    <name>1</name>
                                    <description>GTCCRB input capture enabled on the falling edge of GTIOCnB input when GTIOCnA input is 0</description>
                                    <value>#1</value>
                                </enumeratedValue>
                            </enumeratedValues>
                        </field>
                        <field>
                            <name>BSCBFAH</name>
                            <description>GTIOCnB Pin Falling Input during GTIOCnA Value High Source GTCCRB Input Capture Enable</description>
                            <lsb>15</lsb>
                            <msb>15</msb>
                            <access>read-write</access>
                            <enumeratedValues>
                                <enumeratedValue>
                                    <name>0</name>
                                    <description>GTCCRB input capture disabled on the falling edge of GTIOCnB input when GTIOCnA input is 1</description>
                                    <value>#0</value>
                                </enumeratedValue>
                                <enumeratedValue>
                                    <name>1</name>
                                    <description>GTCCRB input capture enabled on the falling edge of GTIOCnB input when GTIOCnA input is 1</description>
                                    <value>#1</value>
                                </enumeratedValue>
                            </enumeratedValues>
                        </field>
                        <field>
                            <name>BSELCA</name>
                            <description>ELC_GPTA Event Source GTCCRB Input Capture Enable</description>
                            <lsb>16</lsb>
                            <msb>16</msb>
                            <access>read-write</access>
                            <enumeratedValues>
                                <enumeratedValue>
                                    <name>0</name>
                                    <description>GTCCRB input capture disabled at the ELC_GPTA input</description>
                                    <value>#0</value>
                                </enumeratedValue>
                                <enumeratedValue>
                                    <name>1</name>
                                    <description>GTCCRB input capture enabled at the ELC_GPTA input</description>
                                    <value>#1</value>
                                </enumeratedValue>
                            </enumeratedValues>
                        </field>
                        <field>
                            <name>BSELCB</name>
                            <description>ELC_GPTB Event Source GTCCRB Input Capture Enable</description>
                            <lsb>17</lsb>
                            <msb>17</msb>
                            <access>read-write</access>
                            <enumeratedValues>
                                <enumeratedValue>
                                    <name>0</name>
                                    <description>GTCCRB input capture disabled at the ELC_GPTB input</description>
                                    <value>#0</value>
                                </enumeratedValue>
                                <enumeratedValue>
                                    <name>1</name>
                                    <description>GTCCRB input capture enabled at the ELC_GPTB input</description>
                                    <value>#1</value>
                                </enumeratedValue>
                            </enumeratedValues>
                        </field>
                        <field>
                            <name>BSELCC</name>
                            <description>ELC_GPTC Event Source GTCCRB Input Capture Enable</description>
                            <lsb>18</lsb>
                            <msb>18</msb>
                            <access>read-write</access>
                            <enumeratedValues>
                                <enumeratedValue>
                                    <name>0</name>
                                    <description>GTCCRB input capture disabled at the ELC_GPTC input</description>
                                    <value>#0</value>
                                </enumeratedValue>
                                <enumeratedValue>
                                    <name>1</name>
                                    <description>GTCCRB input capture enabled at the ELC_GPTC input</description>
                                    <value>#1</value>
                                </enumeratedValue>
                            </enumeratedValues>
                        </field>
                        <field>
                            <name>BSELCD</name>
                            <description>ELC_GPTD Event Source GTCCRB Input Capture Enable</description>
                            <lsb>19</lsb>
                            <msb>19</msb>
                            <access>read-write</access>
                            <enumeratedValues>
                                <enumeratedValue>
                                    <name>0</name>
                                    <description>GTCCRB input capture disabled at the ELC_GPTD input</description>
                                    <value>#0</value>
                                </enumeratedValue>
                                <enumeratedValue>
                                    <name>1</name>
                                    <description>GTCCRB input capture enabled at the ELC_GPTD input</description>
                                    <value>#1</value>
                                </enumeratedValue>
                            </enumeratedValues>
                        </field>
                        <field>
                            <name>BSELCE</name>
                            <description>ELC_GPTE Event Source GTCCRB Input Capture Enable</description>
                            <lsb>20</lsb>
                            <msb>20</msb>
                            <access>read-write</access>
                            <enumeratedValues>
                                <enumeratedValue>
                                    <name>0</name>
                                    <description>GTCCRB input capture disabled at the ELC_GPTE input</description>
                                    <value>#0</value>
                                </enumeratedValue>
                                <enumeratedValue>
                                    <name>1</name>
                                    <description>GTCCRB input capture enabled at the ELC_GPTE input</description>
                                    <value>#1</value>
                                </enumeratedValue>
                            </enumeratedValues>
                        </field>
                        <field>
                            <name>BSELCF</name>
                            <description>ELC_GPTF Event Source GTCCRB Input Capture Enable</description>
                            <lsb>21</lsb>
                            <msb>21</msb>
                            <access>read-write</access>
                            <enumeratedValues>
                                <enumeratedValue>
                                    <name>0</name>
                                    <description>GTCCRB input capture disabled at the ELC_GPTF input</description>
                                    <value>#0</value>
                                </enumeratedValue>
                                <enumeratedValue>
                                    <name>1</name>
                                    <description>GTCCRB input capture enabled at the ELC_GPTF input</description>
                                    <value>#1</value>
                                </enumeratedValue>
                            </enumeratedValues>
                        </field>
                        <field>
                            <name>BSELCG</name>
                            <description>ELC_GPTG Event Source GTCCRB Input Capture Enable</description>
                            <lsb>22</lsb>
                            <msb>22</msb>
                            <access>read-write</access>
                            <enumeratedValues>
                                <enumeratedValue>
                                    <name>0</name>
                                    <description>GTCCRB input capture disabled at the ELC_GPTG input</description>
                                    <value>#0</value>
                                </enumeratedValue>
                                <enumeratedValue>
                                    <name>1</name>
                                    <description>GTCCRB input capture enabled at the ELC_GPTG input</description>
                                    <value>#1</value>
                                </enumeratedValue>
                            </enumeratedValues>
                        </field>
                        <field>
                            <name>BSELCH</name>
                            <description>ELC_GPTH Event Source GTCCRB Input Capture Enable</description>
                            <lsb>23</lsb>
                            <msb>23</msb>
                            <access>read-write</access>
                            <enumeratedValues>
                                <enumeratedValue>
                                    <name>0</name>
                                    <description>GTCCRB input capture disabled at the ELC_GPTH input</description>
                                    <value>#0</value>
                                </enumeratedValue>
                                <enumeratedValue>
                                    <name>1</name>
                                    <description>GTCCRB input capture enabled at the ELC_GPTH input</description>
                                    <value>#1</value>
                                </enumeratedValue>
                            </enumeratedValues>
                        </field>
                    </fields>
                </register>
                <register>
                    <name>GTCR</name>
                    <description>General PWM Timer Control Register</description>
                    <addressOffset>0x2C</addressOffset>
                    <size>32</size>
                    <access>read-write</access>
                    <resetValue>0x00000000</resetValue>
                    <resetMask>0xffffffff</resetMask>
                    <fields>
                        <field>
                            <name>CST</name>
                            <description>Count Start</description>
                            <lsb>0</lsb>
                            <msb>0</msb>
                            <access>read-write</access>
                            <enumeratedValues>
                                <enumeratedValue>
                                    <name>0</name>
                                    <description>Count operation is stopped</description>
                                    <value>#0</value>
                                </enumeratedValue>
                                <enumeratedValue>
                                    <name>1</name>
                                    <description>Count operation is performed</description>
                                    <value>#1</value>
                                </enumeratedValue>
                            </enumeratedValues>
                        </field>
                        <field>
                            <name>MD</name>
                            <description>Mode Select</description>
                            <lsb>16</lsb>
                            <msb>18</msb>
                            <access>read-write</access>
                            <enumeratedValues>
                                <enumeratedValue>
                                    <name>000</name>
                                    <description>Saw-wave PWM mode (single buffer or double buffer possible)</description>
                                    <value>#000</value>
                                </enumeratedValue>
                                <enumeratedValue>
                                    <name>001</name>
                                    <description>Saw-wave one-shot pulse mode (fixed buffer operation)</description>
                                    <value>#001</value>
                                </enumeratedValue>
                                <enumeratedValue>
                                    <name>010</name>
                                    <description>Setting prohibited</description>
                                    <value>#010</value>
                                </enumeratedValue>
                                <enumeratedValue>
                                    <name>011</name>
                                    <description>Setting prohibited</description>
                                    <value>#011</value>
                                </enumeratedValue>
                                <enumeratedValue>
                                    <name>100</name>
                                    <description>Triangle-wave PWM mode 1 (32-bit transfer at trough) (single buffer or double buffer is possible)</description>
                                    <value>#100</value>
                                </enumeratedValue>
                                <enumeratedValue>
                                    <name>101</name>
                                    <description>Triangle-wave PWM mode 2 (32-bit transfer at crest and trough) (single buffer or double buffer is possible)</description>
                                    <value>#101</value>
                                </enumeratedValue>
                                <enumeratedValue>
                                    <name>110</name>
                                    <description>Triangle-wave PWM mode 3 (64-bit transfer at trough) (fixed buffer operation)</description>
                                    <value>#110</value>
                                </enumeratedValue>
                                <enumeratedValue>
                                    <name>111</name>
                                    <description>Setting prohibited</description>
                                    <value>#111</value>
                                </enumeratedValue>
                            </enumeratedValues>
                        </field>
                        <field>
                            <name>TPCS</name>
                            <description>Timer Prescaler Select</description>
                            <lsb>23</lsb>
                            <msb>26</msb>
                            <access>read-write</access>
                            <enumeratedValues>
                                <enumeratedValue>
                                    <name>0x0</name>
                                    <description>PCLKD/1 </description>
                                    <value>0x0</value>
                                </enumeratedValue>
                                <enumeratedValue>
                                    <name>0x1</name>
                                    <description>PCLKD/2 </description>
                                    <value>0x1</value>
                                </enumeratedValue>
                                <enumeratedValue>
                                    <name>0x2</name>
                                    <description>PCLKD/4 </description>
                                    <value>0x2</value>
                                </enumeratedValue>
                                <enumeratedValue>
                                    <name>0x3</name>
                                    <description>PCLKD/8 </description>
                                    <value>0x3</value>
                                </enumeratedValue>
                                <enumeratedValue>
                                    <name>0x4</name>
                                    <description>PCLKD/16 </description>
                                    <value>0x4</value>
                                </enumeratedValue>
                                <enumeratedValue>
                                    <name>0x5</name>
                                    <description>PCLKD/32 </description>
                                    <value>0x5</value>
                                </enumeratedValue>
                                <enumeratedValue>
                                    <name>0x6</name>
                                    <description>PCLKD/64 </description>
                                    <value>0x6</value>
                                </enumeratedValue>
                                <enumeratedValue>
                                    <name>0x7</name>
                                    <description>Setting prohibited</description>
                                    <value>0x7</value>
                                </enumeratedValue>
                                <enumeratedValue>
                                    <name>0x8</name>
                                    <description>PCLKD/256 </description>
                                    <value>0x8</value>
                                </enumeratedValue>
                                <enumeratedValue>
                                    <name>0x9</name>
                                    <description>Setting prohibited</description>
                                    <value>0x9</value>
                                </enumeratedValue>
                                <enumeratedValue>
                                    <name>0xA</name>
                                    <description>PCLKD/1024 </description>
                                    <value>0xa</value>
                                </enumeratedValue>
                                <enumeratedValue>
                                    <name>0xB</name>
                                    <description>Setting prohibited</description>
                                    <value>0xb</value>
                                </enumeratedValue>
                                <enumeratedValue>
                                    <name>0xC</name>
                                    <description>GTETRGA (Via the POEG)</description>
                                    <value>0xc</value>
                                </enumeratedValue>
                                <enumeratedValue>
                                    <name>0xD</name>
                                    <description>GTETRGB (Via the POEG)</description>
                                    <value>0xd</value>
                                </enumeratedValue>
                                <enumeratedValue>
                                    <name>0xE</name>
                                    <description>GTETRGC (Via the POEG)</description>
                                    <value>0xe</value>
                                </enumeratedValue>
                                <enumeratedValue>
                                    <name>0xF</name>
                                    <description>GTETRGD (Via the POEG)</description>
                                    <value>0xf</value>
                                </enumeratedValue>
                            </enumeratedValues>
                        </field>
                    </fields>
                </register>
                <register>
                    <name>GTUDDTYC</name>
                    <description>General PWM Timer Count Direction and Duty Setting Register</description>
                    <addressOffset>0x30</addressOffset>
                    <size>32</size>
                    <access>read-write</access>
                    <resetValue>0x00000001</resetValue>
                    <resetMask>0xffffffff</resetMask>
                    <fields>
                        <field>
                            <name>UD</name>
                            <description>Count Direction Setting</description>
                            <lsb>0</lsb>
                            <msb>0</msb>
                            <access>read-write</access>
                            <enumeratedValues>
                                <enumeratedValue>
                                    <name>0</name>
                                    <description>GTCNT counts down</description>
                                    <value>#0</value>
                                </enumeratedValue>
                                <enumeratedValue>
                                    <name>1</name>
                                    <description>GTCNT counts up</description>
                                    <value>#1</value>
                                </enumeratedValue>
                            </enumeratedValues>
                        </field>
                        <field>
                            <name>UDF</name>
                            <description>Forcible Count Direction Setting</description>
                            <lsb>1</lsb>
                            <msb>1</msb>
                            <access>read-write</access>
                            <enumeratedValues>
                                <enumeratedValue>
                                    <name>0</name>
                                    <description>Not forcibly set</description>
                                    <value>#0</value>
                                </enumeratedValue>
                                <enumeratedValue>
                                    <name>1</name>
                                    <description>Forcibly set</description>
                                    <value>#1</value>
                                </enumeratedValue>
                            </enumeratedValues>
                        </field>
                        <field>
                            <name>OADTY</name>
                            <description>GTIOCnA Output Duty Setting</description>
                            <lsb>16</lsb>
                            <msb>17</msb>
                            <access>read-write</access>
                            <enumeratedValues>
                                <enumeratedValue>
                                    <name>00</name>
                                    <description>GTIOCnA pin duty depends on the compare match</description>
                                    <value>#00</value>
                                </enumeratedValue>
                                <enumeratedValue>
                                    <name>01</name>
                                    <description>GTIOCnA pin duty depends on the compare match</description>
                                    <value>#01</value>
                                </enumeratedValue>
                                <enumeratedValue>
                                    <name>10</name>
                                    <description>GTIOCnA pin duty 0%</description>
                                    <value>#10</value>
                                </enumeratedValue>
                                <enumeratedValue>
                                    <name>11</name>
                                    <description>GTIOCnA pin duty 100%</description>
                                    <value>#11</value>
                                </enumeratedValue>
                            </enumeratedValues>
                        </field>
                        <field>
                            <name>OADTYF</name>
                            <description>Forcible GTIOCnA Output Duty Setting</description>
                            <lsb>18</lsb>
                            <msb>18</msb>
                            <access>read-write</access>
                            <enumeratedValues>
                                <enumeratedValue>
                                    <name>0</name>
                                    <description>Not forcibly set</description>
                                    <value>#0</value>
                                </enumeratedValue>
                                <enumeratedValue>
                                    <name>1</name>
                                    <description>Forcibly set</description>
                                    <value>#1</value>
                                </enumeratedValue>
                            </enumeratedValues>
                        </field>
                        <field>
                            <name>OADTYR</name>
                            <description>GTIOCnA Output Value Selecting after Releasing 0%/100% Duty Setting</description>
                            <lsb>19</lsb>
                            <msb>19</msb>
                            <access>read-write</access>
                            <enumeratedValues>
                                <enumeratedValue>
                                    <name>0</name>
                                    <description>The function selected by the GTIOA[3:2] bits is applied to the output value when the duty cycle is set after release from the 0 or 100% duty-cycle setting.</description>
                                    <value>#0</value>
                                </enumeratedValue>
                                <enumeratedValue>
                                    <name>1</name>
                                    <description>The function selected by the GTIOA[3:2] bits is applied to the compare match output value which is masked after release from the 0 or 100% duty-cycle setting.</description>
                                    <value>#1</value>
                                </enumeratedValue>
                            </enumeratedValues>
                        </field>
                        <field>
                            <name>OBDTY</name>
                            <description>GTIOCnB Output Duty Setting</description>
                            <lsb>24</lsb>
                            <msb>25</msb>
                            <access>read-write</access>
                            <enumeratedValues>
                                <enumeratedValue>
                                    <name>00</name>
                                    <description>GTIOCnB pin duty depends on the compare match</description>
                                    <value>#00</value>
                                </enumeratedValue>
                                <enumeratedValue>
                                    <name>01</name>
                                    <description>GTIOCnB pin duty depends on the compare match</description>
                                    <value>#01</value>
                                </enumeratedValue>
                                <enumeratedValue>
                                    <name>10</name>
                                    <description>GTIOCnB pin duty 0%</description>
                                    <value>#10</value>
                                </enumeratedValue>
                                <enumeratedValue>
                                    <name>11</name>
                                    <description>GTIOCnB pin duty 100%</description>
                                    <value>#11</value>
                                </enumeratedValue>
                            </enumeratedValues>
                        </field>
                        <field>
                            <name>OBDTYF</name>
                            <description>Forcible GTIOCnB Output Duty Setting</description>
                            <lsb>26</lsb>
                            <msb>26</msb>
                            <access>read-write</access>
                            <enumeratedValues>
                                <enumeratedValue>
                                    <name>0</name>
                                    <description>Not forcibly set</description>
                                    <value>#0</value>
                                </enumeratedValue>
                                <enumeratedValue>
                                    <name>1</name>
                                    <description>Forcibly set</description>
                                    <value>#1</value>
                                </enumeratedValue>
                            </enumeratedValues>
                        </field>
                        <field>
                            <name>OBDTYR</name>
                            <description>GTIOCnB Output Value Selecting after Releasing 0%/100% Duty Setting</description>
                            <lsb>27</lsb>
                            <msb>27</msb>
                            <access>read-write</access>
                            <enumeratedValues>
                                <enumeratedValue>
                                    <name>0</name>
                                    <description>The function selected by the GTIOB[3:2] bits is applied to the output value when the duty cycle is set after release from the 0 or 100% duty-cycle setting.</description>
                                    <value>#0</value>
                                </enumeratedValue>
                                <enumeratedValue>
                                    <name>1</name>
                                    <description>The function selected by the GTIOB[3:2] bits is applied to the compare match output value which is masked after release from the 0 or 100% duty-cycle setting.</description>
                                    <value>#1</value>
                                </enumeratedValue>
                            </enumeratedValues>
                        </field>
                    </fields>
                </register>
                <register>
                    <name>GTIOR</name>
                    <description>General PWM Timer I/O Control Register</description>
                    <addressOffset>0x34</addressOffset>
                    <size>32</size>
                    <access>read-write</access>
                    <resetValue>0x00000000</resetValue>
                    <resetMask>0xffffffff</resetMask>
                    <fields>
                        <field>
                            <name>GTIOA</name>
                            <description>GTIOCnA Pin Function Select</description>
                            <lsb>0</lsb>
                            <msb>4</msb>
                            <access>read-write</access>
                        </field>
                        <field>
                            <name>OADFLT</name>
                            <description>GTIOCnA Pin Output Value Setting at the Count Stop</description>
                            <lsb>6</lsb>
                            <msb>6</msb>
                            <access>read-write</access>
                            <enumeratedValues>
                                <enumeratedValue>
                                    <name>0</name>
                                    <description>The GTIOCnA pin outputs low when counting stops</description>
                                    <value>#0</value>
                                </enumeratedValue>
                                <enumeratedValue>
                                    <name>1</name>
                                    <description>The GTIOCnA pin outputs high when counting stops</description>
                                    <value>#1</value>
                                </enumeratedValue>
                            </enumeratedValues>
                        </field>
                        <field>
                            <name>OAHLD</name>
                            <description>GTIOCnA Pin Output Setting at the Start/Stop Count</description>
                            <lsb>7</lsb>
                            <msb>7</msb>
                            <access>read-write</access>
                            <enumeratedValues>
                                <enumeratedValue>
                                    <name>0</name>
                                    <description>The GTIOCnA pin output level at the start or stop of counting depends on the register setting</description>
                                    <value>#0</value>
                                </enumeratedValue>
                                <enumeratedValue>
                                    <name>1</name>
                                    <description>The GTIOCnA pin output level is retained at the start or stop of counting</description>
                                    <value>#1</value>
                                </enumeratedValue>
                            </enumeratedValues>
                        </field>
                        <field>
                            <name>OAE</name>
                            <description>GTIOCnA Pin Output Enable</description>
                            <lsb>8</lsb>
                            <msb>8</msb>
                            <access>read-write</access>
                            <enumeratedValues>
                                <enumeratedValue>
                                    <name>0</name>
                                    <description>Output is disabled</description>
                                    <value>#0</value>
                                </enumeratedValue>
                                <enumeratedValue>
                                    <name>1</name>
                                    <description>Output is enabled</description>
                                    <value>#1</value>
                                </enumeratedValue>
                            </enumeratedValues>
                        </field>
                        <field>
                            <name>OADF</name>
                            <description>GTIOCnA Pin Disable Value Setting</description>
                            <lsb>9</lsb>
                            <msb>10</msb>
                            <access>read-write</access>
                            <enumeratedValues>
                                <enumeratedValue>
                                    <name>00</name>
                                    <description>None of the below options are specified</description>
                                    <value>#00</value>
                                </enumeratedValue>
                                <enumeratedValue>
                                    <name>01</name>
                                    <description>GTIOCnA pin is set to Hi-Z in response to controlling the output negation</description>
                                    <value>#01</value>
                                </enumeratedValue>
                                <enumeratedValue>
                                    <name>10</name>
                                    <description>GTIOCnA pin is set to 0 in response to controlling the output negation</description>
                                    <value>#10</value>
                                </enumeratedValue>
                                <enumeratedValue>
                                    <name>11</name>
                                    <description>GTIOCnA pin is set to 1 in response to controlling the output negation</description>
                                    <value>#11</value>
                                </enumeratedValue>
                            </enumeratedValues>
                        </field>
                        <field>
                            <name>NFAEN</name>
                            <description>Noise Filter A Enable</description>
                            <lsb>13</lsb>
                            <msb>13</msb>
                            <access>read-write</access>
                            <enumeratedValues>
                                <enumeratedValue>
                                    <name>0</name>
                                    <description>The noise filter for the GTIOCnA pin is disabled</description>
                                    <value>#0</value>
                                </enumeratedValue>
                                <enumeratedValue>
                                    <name>1</name>
                                    <description>The noise filter for the GTIOCnA pin is enabled</description>
                                    <value>#1</value>
                                </enumeratedValue>
                            </enumeratedValues>
                        </field>
                        <field>
                            <name>NFCSA</name>
                            <description>Noise Filter A Sampling Clock Select</description>
                            <lsb>14</lsb>
                            <msb>15</msb>
                            <access>read-write</access>
                            <enumeratedValues>
                                <enumeratedValue>
                                    <name>00</name>
                                    <description>PCLKD/1</description>
                                    <value>#00</value>
                                </enumeratedValue>
                                <enumeratedValue>
                                    <name>01</name>
                                    <description>PCLKD/4</description>
                                    <value>#01</value>
                                </enumeratedValue>
                                <enumeratedValue>
                                    <name>10</name>
                                    <description>PCLKD/16</description>
                                    <value>#10</value>
                                </enumeratedValue>
                                <enumeratedValue>
                                    <name>11</name>
                                    <description>PCLKD/64</description>
                                    <value>#11</value>
                                </enumeratedValue>
                            </enumeratedValues>
                        </field>
                        <field>
                            <name>GTIOB</name>
                            <description>GTIOCnB Pin Function Select</description>
                            <lsb>16</lsb>
                            <msb>20</msb>
                            <access>read-write</access>
                        </field>
                        <field>
                            <name>OBDFLT</name>
                            <description>GTIOCnB Pin Output Value Setting at the Count Stop</description>
                            <lsb>22</lsb>
                            <msb>22</msb>
                            <access>read-write</access>
                            <enumeratedValues>
                                <enumeratedValue>
                                    <name>0</name>
                                    <description>The GTIOCnB pin outputs low when counting stops</description>
                                    <value>#0</value>
                                </enumeratedValue>
                                <enumeratedValue>
                                    <name>1</name>
                                    <description>The GTIOCnB pin outputs high when counting stops</description>
                                    <value>#1</value>
                                </enumeratedValue>
                            </enumeratedValues>
                        </field>
                        <field>
                            <name>OBHLD</name>
                            <description>GTIOCnB Pin Output Setting at the Start/Stop Count</description>
                            <lsb>23</lsb>
                            <msb>23</msb>
                            <access>read-write</access>
                            <enumeratedValues>
                                <enumeratedValue>
                                    <name>0</name>
                                    <description>The GTIOCnB pin output level at the start/stop of counting depends on the register setting</description>
                                    <value>#0</value>
                                </enumeratedValue>
                                <enumeratedValue>
                                    <name>1</name>
                                    <description>The GTIOCnB pin output level is retained at the start/stop of counting</description>
                                    <value>#1</value>
                                </enumeratedValue>
                            </enumeratedValues>
                        </field>
                        <field>
                            <name>OBE</name>
                            <description>GTIOCnB Pin Output Enable</description>
                            <lsb>24</lsb>
                            <msb>24</msb>
                            <access>read-write</access>
                            <enumeratedValues>
                                <enumeratedValue>
                                    <name>0</name>
                                    <description>Output is disabled</description>
                                    <value>#0</value>
                                </enumeratedValue>
                                <enumeratedValue>
                                    <name>1</name>
                                    <description>Output is enabled</description>
                                    <value>#1</value>
                                </enumeratedValue>
                            </enumeratedValues>
                        </field>
                        <field>
                            <name>OBDF</name>
                            <description>GTIOCnB Pin Disable Value Setting</description>
                            <lsb>25</lsb>
                            <msb>26</msb>
                            <access>read-write</access>
                            <enumeratedValues>
                                <enumeratedValue>
                                    <name>00</name>
                                    <description>None of the below options are specified</description>
                                    <value>#00</value>
                                </enumeratedValue>
                                <enumeratedValue>
                                    <name>01</name>
                                    <description>GTIOCnB pin is set to Hi-Z in response to controlling the output negation</description>
                                    <value>#01</value>
                                </enumeratedValue>
                                <enumeratedValue>
                                    <name>10</name>
                                    <description>GTIOCnB pin is set to 0 in response to controlling the output negation</description>
                                    <value>#10</value>
                                </enumeratedValue>
                                <enumeratedValue>
                                    <name>11</name>
                                    <description>GTIOCnB pin is set to 1 in response to controlling the output negation</description>
                                    <value>#11</value>
                                </enumeratedValue>
                            </enumeratedValues>
                        </field>
                        <field>
                            <name>NFBEN</name>
                            <description>Noise Filter B Enable</description>
                            <lsb>29</lsb>
                            <msb>29</msb>
                            <access>read-write</access>
                            <enumeratedValues>
                                <enumeratedValue>
                                    <name>0</name>
                                    <description>The noise filter for the GTIOCnB pin is disabled</description>
                                    <value>#0</value>
                                </enumeratedValue>
                                <enumeratedValue>
                                    <name>1</name>
                                    <description>The noise filter for the GTIOCnB pin is enabled</description>
                                    <value>#1</value>
                                </enumeratedValue>
                            </enumeratedValues>
                        </field>
                        <field>
                            <name>NFCSB</name>
                            <description>Noise Filter B Sampling Clock Select</description>
                            <lsb>30</lsb>
                            <msb>31</msb>
                            <access>read-write</access>
                            <enumeratedValues>
                                <enumeratedValue>
                                    <name>00</name>
                                    <description>PCLKD/1</description>
                                    <value>#00</value>
                                </enumeratedValue>
                                <enumeratedValue>
                                    <name>01</name>
                                    <description>PCLKD/4</description>
                                    <value>#01</value>
                                </enumeratedValue>
                                <enumeratedValue>
                                    <name>10</name>
                                    <description>PCLKD/16</description>
                                    <value>#10</value>
                                </enumeratedValue>
                                <enumeratedValue>
                                    <name>11</name>
                                    <description>PCLKD/64</description>
                                    <value>#11</value>
                                </enumeratedValue>
                            </enumeratedValues>
                        </field>
                    </fields>
                </register>
                <register>
                    <name>GTINTAD</name>
                    <description>General PWM Timer Interrupt Output Setting Register</description>
                    <addressOffset>0x38</addressOffset>
                    <size>32</size>
                    <access>read-write</access>
                    <resetValue>0x00000000</resetValue>
                    <resetMask>0xffffffff</resetMask>
                    <fields>
                        <field>
                            <name>GRP</name>
                            <description>Output Disable Source Select</description>
                            <lsb>24</lsb>
                            <msb>25</msb>
                            <access>read-write</access>
                            <enumeratedValues>
                                <enumeratedValue>
                                    <name>00</name>
                                    <description>Group A output disable request is selected</description>
                                    <value>#00</value>
                                </enumeratedValue>
                                <enumeratedValue>
                                    <name>01</name>
                                    <description>Group B output disable request is selected</description>
                                    <value>#01</value>
                                </enumeratedValue>
                                <enumeratedValue>
                                    <name>10</name>
                                    <description>Group C output disable request is selected</description>
                                    <value>#10</value>
                                </enumeratedValue>
                                <enumeratedValue>
                                    <name>11</name>
                                    <description>Group D output disable request is selected</description>
                                    <value>#11</value>
                                </enumeratedValue>
                            </enumeratedValues>
                        </field>
                        <field>
                            <name>GRPABH</name>
                            <description>Same Time Output Level High Disable Request Enable</description>
                            <lsb>29</lsb>
                            <msb>29</msb>
                            <access>read-write</access>
                            <enumeratedValues>
                                <enumeratedValue>
                                    <name>0</name>
                                    <description>Same time output level high disable request disabled</description>
                                    <value>#0</value>
                                </enumeratedValue>
                                <enumeratedValue>
                                    <name>1</name>
                                    <description>Same time output level high disable request enabled</description>
                                    <value>#1</value>
                                </enumeratedValue>
                            </enumeratedValues>
                        </field>
                        <field>
                            <name>GRPABL</name>
                            <description>Same Time Output Level Low Disable Request Enable</description>
                            <lsb>30</lsb>
                            <msb>30</msb>
                            <access>read-write</access>
                            <enumeratedValues>
                                <enumeratedValue>
                                    <name>0</name>
                                    <description>Same time output level low disable request disabled</description>
                                    <value>#0</value>
                                </enumeratedValue>
                                <enumeratedValue>
                                    <name>1</name>
                                    <description>Same time output level low disable request enabled</description>
                                    <value>#1</value>
                                </enumeratedValue>
                            </enumeratedValues>
                        </field>
                    </fields>
                </register>
                <register>
                    <name>GTST</name>
                    <description>General PWM Timer Status Register</description>
                    <addressOffset>0x3C</addressOffset>
                    <size>32</size>
                    <access>read-write</access>
                    <resetValue>0x00008000</resetValue>
                    <resetMask>0xffffffff</resetMask>
                    <fields>
                        <field>
                            <name>TCFA</name>
                            <description>Input Capture/Compare Match Flag A</description>
                            <lsb>0</lsb>
                            <msb>0</msb>
                            <access>read-write</access>
                            <enumeratedValues>
                                <enumeratedValue>
                                    <name>0</name>
                                    <description>No input capture/compare match of GTCCRA is generated</description>
                                    <value>#0</value>
                                </enumeratedValue>
                                <enumeratedValue>
                                    <name>1</name>
                                    <description>An input capture/compare match of GTCCRA is generated</description>
                                    <value>#1</value>
                                </enumeratedValue>
                            </enumeratedValues>
                        </field>
                        <field>
                            <name>TCFB</name>
                            <description>Input Capture/Compare Match Flag B</description>
                            <lsb>1</lsb>
                            <msb>1</msb>
                            <access>read-write</access>
                            <enumeratedValues>
                                <enumeratedValue>
                                    <name>0</name>
                                    <description>No input capture/compare match of GTCCRB is generated</description>
                                    <value>#0</value>
                                </enumeratedValue>
                                <enumeratedValue>
                                    <name>1</name>
                                    <description>An input capture/compare match of GTCCRB is generated</description>
                                    <value>#1</value>
                                </enumeratedValue>
                            </enumeratedValues>
                        </field>
                        <field>
                            <name>TCFC</name>
                            <description>Input Compare Match Flag C</description>
                            <lsb>2</lsb>
                            <msb>2</msb>
                            <access>read-write</access>
                            <enumeratedValues>
                                <enumeratedValue>
                                    <name>0</name>
                                    <description>No compare match of GTCCRC is generated</description>
                                    <value>#0</value>
                                </enumeratedValue>
                                <enumeratedValue>
                                    <name>1</name>
                                    <description>A compare match of GTCCRC is generated</description>
                                    <value>#1</value>
                                </enumeratedValue>
                            </enumeratedValues>
                        </field>
                        <field>
                            <name>TCFD</name>
                            <description>Input Compare Match Flag D</description>
                            <lsb>3</lsb>
                            <msb>3</msb>
                            <access>read-write</access>
                            <enumeratedValues>
                                <enumeratedValue>
                                    <name>0</name>
                                    <description>No compare match of GTCCRD is generated</description>
                                    <value>#0</value>
                                </enumeratedValue>
                                <enumeratedValue>
                                    <name>1</name>
                                    <description>A compare match of GTCCRD is generated</description>
                                    <value>#1</value>
                                </enumeratedValue>
                            </enumeratedValues>
                        </field>
                        <field>
                            <name>TCFE</name>
                            <description>Input Compare Match Flag E</description>
                            <lsb>4</lsb>
                            <msb>4</msb>
                            <access>read-write</access>
                            <enumeratedValues>
                                <enumeratedValue>
                                    <name>0</name>
                                    <description>No compare match of GTCCRE is generated</description>
                                    <value>#0</value>
                                </enumeratedValue>
                                <enumeratedValue>
                                    <name>1</name>
                                    <description>A compare match of GTCCRE is generated</description>
                                    <value>#1</value>
                                </enumeratedValue>
                            </enumeratedValues>
                        </field>
                        <field>
                            <name>TCFF</name>
                            <description>Input Compare Match Flag F</description>
                            <lsb>5</lsb>
                            <msb>5</msb>
                            <access>read-write</access>
                            <enumeratedValues>
                                <enumeratedValue>
                                    <name>0</name>
                                    <description>No compare match of GTCCRF is generated</description>
                                    <value>#0</value>
                                </enumeratedValue>
                                <enumeratedValue>
                                    <name>1</name>
                                    <description>A compare match of GTCCRF is generated</description>
                                    <value>#1</value>
                                </enumeratedValue>
                            </enumeratedValues>
                        </field>
                        <field>
                            <name>TCFPO</name>
                            <description>Overflow Flag</description>
                            <lsb>6</lsb>
                            <msb>6</msb>
                            <access>read-write</access>
                            <enumeratedValues>
                                <enumeratedValue>
                                    <name>0</name>
                                    <description>No overflow (crest) occurred</description>
                                    <value>#0</value>
                                </enumeratedValue>
                                <enumeratedValue>
                                    <name>1</name>
                                    <description>An overflow (crest) occurred</description>
                                    <value>#1</value>
                                </enumeratedValue>
                            </enumeratedValues>
                        </field>
                        <field>
                            <name>TCFPU</name>
                            <description>Underflow Flag</description>
                            <lsb>7</lsb>
                            <msb>7</msb>
                            <access>read-write</access>
                            <enumeratedValues>
                                <enumeratedValue>
                                    <name>0</name>
                                    <description>No underflow (trough) occurred</description>
                                    <value>#0</value>
                                </enumeratedValue>
                                <enumeratedValue>
                                    <name>1</name>
                                    <description>An underflow (trough) occurred</description>
                                    <value>#1</value>
                                </enumeratedValue>
                            </enumeratedValues>
                        </field>
                        <field>
                            <name>TUCF</name>
                            <description>Count Direction Flag</description>
                            <lsb>15</lsb>
                            <msb>15</msb>
                            <access>read-only</access>
                            <enumeratedValues>
                                <enumeratedValue>
                                    <name>0</name>
                                    <description>GTCNT counter counts downward</description>
                                    <value>#0</value>
                                </enumeratedValue>
                                <enumeratedValue>
                                    <name>1</name>
                                    <description>GTCNT counter counts upward</description>
                                    <value>#1</value>
                                </enumeratedValue>
                            </enumeratedValues>
                        </field>
                        <field>
                            <name>ADTRAUF</name>
                            <description>GTADTRA Register Compare Match (Up-Counting) A/D Conversion Start Request Flag</description>
                            <lsb>16</lsb>
                            <msb>16</msb>
                            <access>read-write</access>
                            <enumeratedValues>
                                <enumeratedValue>
                                    <name>0</name>
                                    <description>No GTADTRA register compare match has occurred in up-counting.</description>
                                    <value>#0</value>
                                </enumeratedValue>
                                <enumeratedValue>
                                    <name>1</name>
                                    <description>A GTADTRA register compare match has occurred in up-counting.</description>
                                    <value>#1</value>
                                </enumeratedValue>
                            </enumeratedValues>
                        </field>
                        <field>
                            <name>ADTRADF</name>
                            <description>GTADTRA Register Compare Match (Down-Counting) A/D Conversion Start Request Flag</description>
                            <lsb>17</lsb>
                            <msb>17</msb>
                            <access>read-write</access>
                            <enumeratedValues>
                                <enumeratedValue>
                                    <name>0</name>
                                    <description>No GTADTRA register compare match has occurred in down-counting.</description>
                                    <value>#0</value>
                                </enumeratedValue>
                                <enumeratedValue>
                                    <name>1</name>
                                    <description>A GTADTRA register compare match has occurred in down-counting.</description>
                                    <value>#1</value>
                                </enumeratedValue>
                            </enumeratedValues>
                        </field>
                        <field>
                            <name>ADTRBUF</name>
                            <description>GTADTRB Register Compare Match (Up-Counting) A/D Conversion Start Request Flag</description>
                            <lsb>18</lsb>
                            <msb>18</msb>
                            <access>read-write</access>
                            <enumeratedValues>
                                <enumeratedValue>
                                    <name>0</name>
                                    <description>No GTADTRB register compare match has occurred in up-counting.</description>
                                    <value>#0</value>
                                </enumeratedValue>
                                <enumeratedValue>
                                    <name>1</name>
                                    <description>A GTADTRB register compare match has occurred in up-counting.</description>
                                    <value>#1</value>
                                </enumeratedValue>
                            </enumeratedValues>
                        </field>
                        <field>
                            <name>ADTRBDF</name>
                            <description>GTADTRB Register Compare Match (Down-Counting) A/D Conversion Start Request Flag</description>
                            <lsb>19</lsb>
                            <msb>19</msb>
                            <access>read-write</access>
                            <enumeratedValues>
                                <enumeratedValue>
                                    <name>0</name>
                                    <description>No GTADTRB register compare match has occurred in down-counting.</description>
                                    <value>#0</value>
                                </enumeratedValue>
                                <enumeratedValue>
                                    <name>1</name>
                                    <description>A GTADTRB register compare match has occurred in down-counting.</description>
                                    <value>#1</value>
                                </enumeratedValue>
                            </enumeratedValues>
                        </field>
                        <field>
                            <name>ODF</name>
                            <description>Output Disable Flag</description>
                            <lsb>24</lsb>
                            <msb>24</msb>
                            <access>read-only</access>
                            <enumeratedValues>
                                <enumeratedValue>
                                    <name>0</name>
                                    <description>No output disable request is generated</description>
                                    <value>#0</value>
                                </enumeratedValue>
                                <enumeratedValue>
                                    <name>1</name>
                                    <description>An output disable request is generated</description>
                                    <value>#1</value>
                                </enumeratedValue>
                            </enumeratedValues>
                        </field>
                        <field>
                            <name>OABHF</name>
                            <description>Same Time Output Level High Flag</description>
                            <lsb>29</lsb>
                            <msb>29</msb>
                            <access>read-only</access>
                            <enumeratedValues>
                                <enumeratedValue>
                                    <name>0</name>
                                    <description>No simultaneous generation of 1 both for the GTIOCA and GTIOCB pins has occurred.</description>
                                    <value>#0</value>
                                </enumeratedValue>
                                <enumeratedValue>
                                    <name>1</name>
                                    <description>A simultaneous generation of 1 both for the GTIOCA and GTIOCB pins has occurred.</description>
                                    <value>#1</value>
                                </enumeratedValue>
                            </enumeratedValues>
                        </field>
                        <field>
                            <name>OABLF</name>
                            <description>Same Time Output Level Low Flag</description>
                            <lsb>30</lsb>
                            <msb>30</msb>
                            <access>read-only</access>
                            <enumeratedValues>
                                <enumeratedValue>
                                    <name>0</name>
                                    <description>No simultaneous generation of 0 both for the GTIOCA and GTIOCB pins has occurred.</description>
                                    <value>#0</value>
                                </enumeratedValue>
                                <enumeratedValue>
                                    <name>1</name>
                                    <description>A simultaneous generation of 0 both for the GTIOCA and GTIOCB pins has occurred.</description>
                                    <value>#1</value>
                                </enumeratedValue>
                            </enumeratedValues>
                        </field>
                        <field>
                            <name>PCF</name>
                            <description>Period Count Function Finish Flag</description>
                            <lsb>31</lsb>
                            <msb>31</msb>
                            <access>read-write</access>
                            <enumeratedValues>
                                <enumeratedValue>
                                    <name>0</name>
                                    <description>No period count function finish has occurred</description>
                                    <value>#0</value>
                                </enumeratedValue>
                                <enumeratedValue>
                                    <name>1</name>
                                    <description>A period count function finish has occurred</description>
                                    <value>#1</value>
                                </enumeratedValue>
                            </enumeratedValues>
                        </field>
                    </fields>
                </register>
                <register>
                    <name>GTBER</name>
                    <description>General PWM Timer Buffer Enable Register</description>
                    <addressOffset>0x40</addressOffset>
                    <size>32</size>
                    <access>read-write</access>
                    <resetValue>0x00000000</resetValue>
                    <resetMask>0xffffffff</resetMask>
                    <fields>
                        <field>
                            <name>BD0</name>
                            <description>GTCCR Buffer Operation Disable</description>
                            <lsb>0</lsb>
                            <msb>0</msb>
                            <access>read-write</access>
                            <enumeratedValues>
                                <enumeratedValue>
                                    <name>0</name>
                                    <description>Buffer operation is enabled</description>
                                    <value>#0</value>
                                </enumeratedValue>
                                <enumeratedValue>
                                    <name>1</name>
                                    <description>Buffer operation is disabled</description>
                                    <value>#1</value>
                                </enumeratedValue>
                            </enumeratedValues>
                        </field>
                        <field>
                            <name>BD1</name>
                            <description>GTPR Buffer Operation Disable</description>
                            <lsb>1</lsb>
                            <msb>1</msb>
                            <access>read-write</access>
                            <enumeratedValues>
                                <enumeratedValue>
                                    <name>0</name>
                                    <description>Buffer operation is enabled</description>
                                    <value>#0</value>
                                </enumeratedValue>
                                <enumeratedValue>
                                    <name>1</name>
                                    <description>Buffer operation is disabled</description>
                                    <value>#1</value>
                                </enumeratedValue>
                            </enumeratedValues>
                        </field>
                        <field>
                            <name>BD2</name>
                            <description>GTADTRA/GTADTRB Registers Buffer Operation Disable</description>
                            <lsb>2</lsb>
                            <msb>2</msb>
                            <access>read-write</access>
                            <enumeratedValues>
                                <enumeratedValue>
                                    <name>0</name>
                                    <description>Buffer operation is enabled</description>
                                    <value>#0</value>
                                </enumeratedValue>
                                <enumeratedValue>
                                    <name>1</name>
                                    <description>Buffer operation is disabled</description>
                                    <value>#1</value>
                                </enumeratedValue>
                            </enumeratedValues>
                        </field>
                        <field>
                            <name>CCRA</name>
                            <description>GTCCRA Buffer Operation</description>
                            <lsb>16</lsb>
                            <msb>17</msb>
                            <access>read-write</access>
                            <enumeratedValues>
                                <enumeratedValue>
                                    <name>00</name>
                                    <description>No buffer operation</description>
                                    <value>#00</value>
                                </enumeratedValue>
                                <enumeratedValue>
                                    <name>01</name>
                                    <description>Single buffer operation (GTCCRA &lt;----&gt;GTCCRC)</description>
                                    <value>#01</value>
                                </enumeratedValue>
                                <enumeratedValue>
                                    <name>Others</name>
                                    <description>Double buffer operation (GTCCRA &lt;----&gt; GTCCRC &lt;----&gt; GTCCRD)</description>
                                    <isDefault>true</isDefault>
                                </enumeratedValue>
                            </enumeratedValues>
                        </field>
                        <field>
                            <name>CCRB</name>
                            <description>GTCCRB Buffer Operation</description>
                            <lsb>18</lsb>
                            <msb>19</msb>
                            <access>read-write</access>
                            <enumeratedValues>
                                <enumeratedValue>
                                    <name>00</name>
                                    <description>No buffer operation</description>
                                    <value>#00</value>
                                </enumeratedValue>
                                <enumeratedValue>
                                    <name>01</name>
                                    <description>Single buffer operation (GTCCRB &lt;----&gt; GTCCRE)</description>
                                    <value>#01</value>
                                </enumeratedValue>
                                <enumeratedValue>
                                    <name>Others</name>
                                    <description>Double buffer operation (GTCCRB &lt;----&gt; GTCCRE &lt;----&gt; GTCCRF)</description>
                                    <isDefault>true</isDefault>
                                </enumeratedValue>
                            </enumeratedValues>
                        </field>
                        <field>
                            <name>PR</name>
                            <description>GTPR Buffer Operation</description>
                            <lsb>20</lsb>
                            <msb>21</msb>
                            <access>read-write</access>
                            <enumeratedValues>
                                <enumeratedValue>
                                    <name>00</name>
                                    <description>No buffer operation</description>
                                    <value>#00</value>
                                </enumeratedValue>
                                <enumeratedValue>
                                    <name>01</name>
                                    <description>Single buffer operation (GTPBR --&gt; GTPR)</description>
                                    <value>#01</value>
                                </enumeratedValue>
                                <enumeratedValue>
                                    <name>Others</name>
                                    <description>Setting prohibited</description>
                                    <isDefault>true</isDefault>
                                </enumeratedValue>
                            </enumeratedValues>
                        </field>
                        <field>
                            <name>CCRSWT</name>
                            <description>GTCCRA and GTCCRB Forcible Buffer Operation</description>
                            <lsb>22</lsb>
                            <msb>22</msb>
                            <access>write-only</access>
                        </field>
                        <field>
                            <name>ADTTA</name>
                            <description>GTADTRA Register Buffer Transfer Timing Select</description>
                            <lsb>24</lsb>
                            <msb>25</msb>
                            <access>read-write</access>
                            <enumeratedValues>
                                <enumeratedValue>
                                    <name>00</name>
                                    <description>In triangle wave mode, no transfer. In saw-wave mode, no transfer. </description>
                                    <value>#00</value>
                                </enumeratedValue>
                                <enumeratedValue>
                                    <name>01</name>
                                    <description>In triangle wave mode, transfer at crest. In saw-wave mode, transfer at underflow (in down-counting), overflow (in up-counting), or counter clearing. </description>
                                    <value>#01</value>
                                </enumeratedValue>
                                <enumeratedValue>
                                    <name>10</name>
                                    <description>In triangle wave mode, transfer at trough. In saw-wave mode, transfer at underflow (in down-counting), overflow (in up-counting), or counter clearing. </description>
                                    <value>#10</value>
                                </enumeratedValue>
                                <enumeratedValue>
                                    <name>11</name>
                                    <description>In triangle wave, transfer at both crest and trough. In saw-wave mode, transfer at underflow (in down-counting), overflow (in up-counting), or counter clearing. </description>
                                    <value>#11</value>
                                </enumeratedValue>
                            </enumeratedValues>
                        </field>
                        <field>
                            <name>ADTDA</name>
                            <description>GTADTRA Register Double Buffer Operation</description>
                            <lsb>26</lsb>
                            <msb>26</msb>
                            <access>read-write</access>
                            <enumeratedValues>
                                <enumeratedValue>
                                    <name>0</name>
                                    <description>Single buffer operation (GTADTBRA --&gt; GTADTRA)</description>
                                    <value>#0</value>
                                </enumeratedValue>
                                <enumeratedValue>
                                    <name>1</name>
                                    <description>Double buffer operation (GTADTDBRA --&gt; GTADTBRA --&gt; GTADTRA)</description>
                                    <value>#1</value>
                                </enumeratedValue>
                            </enumeratedValues>
                        </field>
                        <field>
                            <name>ADTTB</name>
                            <description>GTADTRB Register Buffer Transfer Timing Select</description>
                            <lsb>28</lsb>
                            <msb>29</msb>
                            <access>read-write</access>
                            <enumeratedValues>
                                <enumeratedValue>
                                    <name>00</name>
                                    <description>In triangle wave mode, no transfer. In saw-wave mode, no transfer. </description>
                                    <value>#00</value>
                                </enumeratedValue>
                                <enumeratedValue>
                                    <name>01</name>
                                    <description>In triangle wave mode, transfer at crest. In saw-wave mode, transfer at underflow (in down-counting), overflow (in up-counting), or counter clearing. </description>
                                    <value>#01</value>
                                </enumeratedValue>
                                <enumeratedValue>
                                    <name>10</name>
                                    <description>In triangle wave mode, transfer at trough. In saw-wave mode, transfer at underflow (in down-counting), overflow (in up-counting), or counter clearing. </description>
                                    <value>#10</value>
                                </enumeratedValue>
                                <enumeratedValue>
                                    <name>11</name>
                                    <description>In triangle wave mode, transfer at both crest and trough. In saw-wave mode, transfer at underflow (in down-counting), overflow (in up-counting), or counter clearing. </description>
                                    <value>#11</value>
                                </enumeratedValue>
                            </enumeratedValues>
                        </field>
                        <field>
                            <name>ADTDB</name>
                            <description>GTADTRB Register Double Buffer Operation</description>
                            <lsb>30</lsb>
                            <msb>30</msb>
                            <access>read-write</access>
                            <enumeratedValues>
                                <enumeratedValue>
                                    <name>0</name>
                                    <description>Single buffer operation (GTADTBRB --&gt; GTADTRB)</description>
                                    <value>#0</value>
                                </enumeratedValue>
                                <enumeratedValue>
                                    <name>1</name>
                                    <description>Double buffer operation (GTADTDBRB --&gt; GTADTBRB --&gt; GTADTRB)</description>
                                    <value>#1</value>
                                </enumeratedValue>
                            </enumeratedValues>
                        </field>
                    </fields>
                </register>
                <register>
                    <name>GTCNT</name>
                    <description>General PWM Timer Counter</description>
                    <addressOffset>0x48</addressOffset>
                    <size>32</size>
                    <access>read-write</access>
                    <resetValue>0x00000000</resetValue>
                    <resetMask>0xffffffff</resetMask>
                </register>
                <register>
                    <name>GTCCRA</name>
                    <description>General PWM Timer Compare Capture Register A</description>
                    <addressOffset>0x4C</addressOffset>
                    <size>32</size>
                    <access>read-write</access>
                    <resetValue>0xffffffff</resetValue>
                    <resetMask>0xffffffff</resetMask>
                </register>
                <register>
                    <name>GTCCRB</name>
                    <description>General PWM Timer Compare Capture Register B</description>
                    <addressOffset>0x50</addressOffset>
                    <size>32</size>
                    <access>read-write</access>
                    <resetValue>0xffffffff</resetValue>
                    <resetMask>0xffffffff</resetMask>
                </register>
                <register>
                    <name>GTCCRC</name>
                    <description>General PWM Timer Compare Capture Register C</description>
                    <addressOffset>0x54</addressOffset>
                    <size>32</size>
                    <access>read-write</access>
                    <resetValue>0xffffffff</resetValue>
                    <resetMask>0xffffffff</resetMask>
                </register>
                <register>
                    <name>GTCCRE</name>
                    <description>General PWM Timer Compare Capture Register E</description>
                    <addressOffset>0x58</addressOffset>
                    <size>32</size>
                    <access>read-write</access>
                    <resetValue>0xffffffff</resetValue>
                    <resetMask>0xffffffff</resetMask>
                </register>
                <register>
                    <name>GTCCRD</name>
                    <description>General PWM Timer Compare Capture Register D</description>
                    <addressOffset>0x5C</addressOffset>
                    <size>32</size>
                    <access>read-write</access>
                    <resetValue>0xffffffff</resetValue>
                    <resetMask>0xffffffff</resetMask>
                </register>
                <register>
                    <name>GTCCRF</name>
                    <description>General PWM Timer Compare Capture Register F</description>
                    <addressOffset>0x60</addressOffset>
                    <size>32</size>
                    <access>read-write</access>
                    <resetValue>0xffffffff</resetValue>
                    <resetMask>0xffffffff</resetMask>
                </register>
                <register>
                    <name>GTPR</name>
                    <description>General PWM Timer Cycle Setting Register</description>
                    <addressOffset>0x64</addressOffset>
                    <size>32</size>
                    <access>read-write</access>
                    <resetValue>0xffffffff</resetValue>
                    <resetMask>0xffffffff</resetMask>
                </register>
                <register>
                    <name>GTPBR</name>
                    <description>General PWM Timer Cycle Setting Buffer Register</description>
                    <addressOffset>0x68</addressOffset>
                    <size>32</size>
                    <access>read-write</access>
                    <resetValue>0xffffffff</resetValue>
                    <resetMask>0xffffffff</resetMask>
                </register>
                <register>
                    <name>GTADTRA</name>
                    <description>A/D Conversion Start Request Timing Register A</description>
                    <addressOffset>0x70</addressOffset>
                    <size>32</size>
                    <access>read-write</access>
                    <resetValue>0xffffffff</resetValue>
                    <resetMask>0xffffffff</resetMask>
                </register>
                <register>
                    <name>GTADTBRA</name>
                    <description>A/D Conversion Start Request Timing Buffer Register A</description>
                    <addressOffset>0x74</addressOffset>
                    <size>32</size>
                    <access>read-write</access>
                    <resetValue>0xffffffff</resetValue>
                    <resetMask>0xffffffff</resetMask>
                </register>
                <register>
                    <name>GTADTDBRA</name>
                    <description>A/D Conversion Start Request Timing Double-Buffer Register A</description>
                    <addressOffset>0x78</addressOffset>
                    <size>32</size>
                    <access>read-write</access>
                    <resetValue>0xffffffff</resetValue>
                    <resetMask>0xffffffff</resetMask>
                </register>
                <register>
                    <name>GTADTRB</name>
                    <description>A/D Conversion Start Request Timing Register B</description>
                    <addressOffset>0x7C</addressOffset>
                    <size>32</size>
                    <access>read-write</access>
                    <resetValue>0xffffffff</resetValue>
                    <resetMask>0xffffffff</resetMask>
                </register>
                <register>
                    <name>GTADTBRB</name>
                    <description>A/D Conversion Start Request Timing Buffer Register B</description>
                    <addressOffset>0x80</addressOffset>
                    <size>32</size>
                    <access>read-write</access>
                    <resetValue>0xffffffff</resetValue>
                    <resetMask>0xffffffff</resetMask>
                </register>
                <register>
                    <name>GTADTDBRB</name>
                    <description>A/D Conversion Start Request Timing Double-Buffer Register B</description>
                    <addressOffset>0x84</addressOffset>
                    <size>32</size>
                    <access>read-write</access>
                    <resetValue>0xffffffff</resetValue>
                    <resetMask>0xffffffff</resetMask>
                </register>
                <register>
                    <name>GTDTCR</name>
                    <description>General PWM Timer Dead Time Control Register</description>
                    <addressOffset>0x88</addressOffset>
                    <size>32</size>
                    <access>read-write</access>
                    <resetValue>0x00000000</resetValue>
                    <resetMask>0xffffffff</resetMask>
                    <fields>
                        <field>
                            <name>TDE</name>
                            <description>Negative-Phase Waveform Setting</description>
                            <lsb>0</lsb>
                            <msb>0</msb>
                            <access>read-write</access>
                            <enumeratedValues>
                                <enumeratedValue>
                                    <name>0</name>
                                    <description>GTCCRB is set without using GTDVU</description>
                                    <value>#0</value>
                                </enumeratedValue>
                                <enumeratedValue>
                                    <name>1</name>
                                    <description>GTDVU is used to set the compare match value for negative-phase waveform with dead time automatically in GTCCRB</description>
                                    <value>#1</value>
                                </enumeratedValue>
                            </enumeratedValues>
                        </field>
                    </fields>
                </register>
                <register>
                    <name>GTDVU</name>
                    <description>General PWM Timer Dead Time Value Register U</description>
                    <addressOffset>0x8C</addressOffset>
                    <size>32</size>
                    <access>read-write</access>
                    <resetValue>0xffffffff</resetValue>
                    <resetMask>0xffffffff</resetMask>
                </register>
                <register>
                    <name>GTADSMR</name>
                    <description>General PWM Timer A/D Conversion Start Request Signal Monitoring Register</description>
                    <addressOffset>0xA4</addressOffset>
                    <size>32</size>
                    <access>read-write</access>
                    <resetValue>0x00000000</resetValue>
                    <resetMask>0xffffffff</resetMask>
                    <fields>
                        <field>
                            <name>ADSMS0</name>
                            <description>A/D Conversion Start Request Signal Monitor 0 Selection</description>
                            <lsb>0</lsb>
                            <msb>1</msb>
                            <access>read-write</access>
                            <enumeratedValues>
                                <enumeratedValue>
                                    <name>00</name>
                                    <description>A/D conversion start request signal generated by the GTADTRA register during up-counting.</description>
                                    <value>#00</value>
                                </enumeratedValue>
                                <enumeratedValue>
                                    <name>01</name>
                                    <description>A/D conversion start request signal generated by the GTADTRA register during down-counting.</description>
                                    <value>#01</value>
                                </enumeratedValue>
                                <enumeratedValue>
                                    <name>10</name>
                                    <description>A/D conversion start request signal generated by the GTADTRB register during up-counting.</description>
                                    <value>#10</value>
                                </enumeratedValue>
                                <enumeratedValue>
                                    <name>11</name>
                                    <description>A/D conversion start request signal generated by the GTADTRB register during down-counting.</description>
                                    <value>#11</value>
                                </enumeratedValue>
                            </enumeratedValues>
                        </field>
                        <field>
                            <name>ADSMEN0</name>
                            <description>A/D Conversion Start Request Signal Monitor 0 Output Enabling</description>
                            <lsb>8</lsb>
                            <msb>8</msb>
                            <access>read-write</access>
                            <enumeratedValues>
                                <enumeratedValue>
                                    <name>0</name>
                                    <description>Output of A/D conversion start request signal monitor 0 is disabled.</description>
                                    <value>#0</value>
                                </enumeratedValue>
                                <enumeratedValue>
                                    <name>1</name>
                                    <description>Output of A/D conversion start request signal monitor 0 is enabled.</description>
                                    <value>#1</value>
                                </enumeratedValue>
                            </enumeratedValues>
                        </field>
                        <field>
                            <name>ADSMS1</name>
                            <description>A/D Conversion Start Request Signal Monitor 1 Selection</description>
                            <lsb>16</lsb>
                            <msb>17</msb>
                            <access>read-write</access>
                            <enumeratedValues>
                                <enumeratedValue>
                                    <name>00</name>
                                    <description>A/D conversion start request signal generated by the GTADTRA register during up-counting.</description>
                                    <value>#00</value>
                                </enumeratedValue>
                                <enumeratedValue>
                                    <name>01</name>
                                    <description>A/D conversion start request signal generated by the GTADTRA register during down-counting.</description>
                                    <value>#01</value>
                                </enumeratedValue>
                                <enumeratedValue>
                                    <name>10</name>
                                    <description>A/D conversion start request signal generated by the GTADTRB register during up-counting.</description>
                                    <value>#10</value>
                                </enumeratedValue>
                                <enumeratedValue>
                                    <name>11</name>
                                    <description>A/D conversion start request signal generated by the GTADTRB register during down-counting.</description>
                                    <value>#11</value>
                                </enumeratedValue>
                            </enumeratedValues>
                        </field>
                        <field>
                            <name>ADSMEN1</name>
                            <description>A/D Conversion Start Request Signal Monitor 1 Output Enabling</description>
                            <lsb>24</lsb>
                            <msb>24</msb>
                            <access>read-write</access>
                            <enumeratedValues>
                                <enumeratedValue>
                                    <name>0</name>
                                    <description>Output of A/D conversion start request signal monitor 1 is disabled.</description>
                                    <value>#0</value>
                                </enumeratedValue>
                                <enumeratedValue>
                                    <name>1</name>
                                    <description>Output of A/D conversion start request signal monitor 1 is enabled.</description>
                                    <value>#1</value>
                                </enumeratedValue>
                            </enumeratedValues>
                        </field>
                    </fields>
                </register>
                <register>
                    <name>GTICLF</name>
                    <description>General PWM Timer Inter Channel Logical Operation Function Setting Register</description>
                    <addressOffset>0xB8</addressOffset>
                    <size>32</size>
                    <access>read-write</access>
                    <resetValue>0x00000000</resetValue>
                    <resetMask>0xffffffff</resetMask>
                    <fields>
                        <field>
                            <name>ICLFA</name>
                            <description>GTIOCnA Output Logical Operation Function Select</description>
                            <lsb>0</lsb>
                            <msb>2</msb>
                            <access>read-write</access>
                            <enumeratedValues>
                                <enumeratedValue>
                                    <name>000</name>
                                    <description>A (no delay)</description>
                                    <value>#000</value>
                                </enumeratedValue>
                                <enumeratedValue>
                                    <name>001</name>
                                    <description>NOT A (no delay)</description>
                                    <value>#001</value>
                                </enumeratedValue>
                                <enumeratedValue>
                                    <name>010</name>
                                    <description>C (1PCLKD delay)</description>
                                    <value>#010</value>
                                </enumeratedValue>
                                <enumeratedValue>
                                    <name>011</name>
                                    <description>NOT C (1PCLKD delay)</description>
                                    <value>#011</value>
                                </enumeratedValue>
                                <enumeratedValue>
                                    <name>100</name>
                                    <description>A AND C (1PCLKD delay)</description>
                                    <value>#100</value>
                                </enumeratedValue>
                                <enumeratedValue>
                                    <name>101</name>
                                    <description>A OR C (1PCLKD delay)</description>
                                    <value>#101</value>
                                </enumeratedValue>
                                <enumeratedValue>
                                    <name>110</name>
                                    <description>A EXOR C (1PCLKD delay)</description>
                                    <value>#110</value>
                                </enumeratedValue>
                                <enumeratedValue>
                                    <name>111</name>
                                    <description>A NOR C (1PCLKD delay)</description>
                                    <value>#111</value>
                                </enumeratedValue>
                            </enumeratedValues>
                        </field>
                        <field>
                            <name>ICLFSELC</name>
                            <description>Inter Channel Signal C Select</description>
                            <lsb>4</lsb>
                            <msb>9</msb>
                            <access>read-write</access>
                            <enumeratedValues>
                                <enumeratedValue>
                                    <name>0x00</name>
                                    <description>GTIOC0A</description>
                                    <value>0x00</value>
                                </enumeratedValue>
                                <enumeratedValue>
                                    <name>0x01</name>
                                    <description>GTIOC0B</description>
                                    <value>0x01</value>
                                </enumeratedValue>
                                <enumeratedValue>
                                    <name>0x02</name>
                                    <description>GTIOC1A</description>
                                    <value>0x02</value>
                                </enumeratedValue>
                                <enumeratedValue>
                                    <name>0x03</name>
                                    <description>GTIOC1B</description>
                                    <value>0x03</value>
                                </enumeratedValue>
                                <enumeratedValue>
                                    <name>0x04</name>
                                    <description>GTIOC2A</description>
                                    <value>0x04</value>
                                </enumeratedValue>
                                <enumeratedValue>
                                    <name>0x05</name>
                                    <description>GTIOC2B</description>
                                    <value>0x05</value>
                                </enumeratedValue>
                                <enumeratedValue>
                                    <name>0x06</name>
                                    <description>GTIOC3A</description>
                                    <value>0x06</value>
                                </enumeratedValue>
                                <enumeratedValue>
                                    <name>0x07</name>
                                    <description>GTIOC3B</description>
                                    <value>0x07</value>
                                </enumeratedValue>
                                <enumeratedValue>
                                    <name>0x08</name>
                                    <description>GTIOC4A</description>
                                    <value>0x08</value>
                                </enumeratedValue>
                                <enumeratedValue>
                                    <name>0x09</name>
                                    <description>GTIOC4B</description>
                                    <value>0x09</value>
                                </enumeratedValue>
                                <enumeratedValue>
                                    <name>0x0A</name>
                                    <description>GTIOC5A</description>
                                    <value>0x0a</value>
                                </enumeratedValue>
                                <enumeratedValue>
                                    <name>0x0B</name>
                                    <description>GTIOC5B</description>
                                    <value>0x0b</value>
                                </enumeratedValue>
                                <enumeratedValue>
                                    <name>0x0C</name>
                                    <description>GTIOC6A</description>
                                    <value>0x0c</value>
                                </enumeratedValue>
                                <enumeratedValue>
                                    <name>0x0D</name>
                                    <description>GTIOC6B</description>
                                    <value>0x0d</value>
                                </enumeratedValue>
                                <enumeratedValue>
                                    <name>0x0E</name>
                                    <description>GTIOC7A</description>
                                    <value>0x0e</value>
                                </enumeratedValue>
                                <enumeratedValue>
                                    <name>0x0F</name>
                                    <description>GTIOC7B</description>
                                    <value>0x0f</value>
                                </enumeratedValue>
                                <enumeratedValue>
                                    <name>0x10</name>
                                    <description>GTIOC8A</description>
                                    <value>0x10</value>
                                </enumeratedValue>
                                <enumeratedValue>
                                    <name>0x11</name>
                                    <description>GTIOC8B</description>
                                    <value>0x11</value>
                                </enumeratedValue>
                                <enumeratedValue>
                                    <name>0x12</name>
                                    <description>GTIOC9A</description>
                                    <value>0x12</value>
                                </enumeratedValue>
                                <enumeratedValue>
                                    <name>0x13</name>
                                    <description>GTIOC9B</description>
                                    <value>0x13</value>
                                </enumeratedValue>
                                <enumeratedValue>
                                    <name>Others</name>
                                    <description>Setting prohibited</description>
                                    <isDefault>true</isDefault>
                                </enumeratedValue>
                            </enumeratedValues>
                        </field>
                        <field>
                            <name>ICLFB</name>
                            <description>GTIOCnB Output Logical Operation Function Select</description>
                            <lsb>16</lsb>
                            <msb>18</msb>
                            <access>read-write</access>
                            <enumeratedValues>
                                <enumeratedValue>
                                    <name>000</name>
                                    <description>B (no delay)</description>
                                    <value>#000</value>
                                </enumeratedValue>
                                <enumeratedValue>
                                    <name>001</name>
                                    <description>NOT B (no delay)</description>
                                    <value>#001</value>
                                </enumeratedValue>
                                <enumeratedValue>
                                    <name>010</name>
                                    <description>D (1PCLKD delay)</description>
                                    <value>#010</value>
                                </enumeratedValue>
                                <enumeratedValue>
                                    <name>011</name>
                                    <description>NOT D (1PCLKD delay)</description>
                                    <value>#011</value>
                                </enumeratedValue>
                                <enumeratedValue>
                                    <name>100</name>
                                    <description>B AND D (1PCLKD delay)</description>
                                    <value>#100</value>
                                </enumeratedValue>
                                <enumeratedValue>
                                    <name>101</name>
                                    <description>B OR D (1PCLKDn delay)</description>
                                    <value>#101</value>
                                </enumeratedValue>
                                <enumeratedValue>
                                    <name>110</name>
                                    <description>B EXOR D (1PCLKD delay)</description>
                                    <value>#110</value>
                                </enumeratedValue>
                                <enumeratedValue>
                                    <name>111</name>
                                    <description>B NOR D (1PCLKD delay)</description>
                                    <value>#111</value>
                                </enumeratedValue>
                            </enumeratedValues>
                        </field>
                        <field>
                            <name>ICLFSELD</name>
                            <description>Inter Channel Signal D Select</description>
                            <lsb>20</lsb>
                            <msb>25</msb>
                            <access>read-write</access>
                            <enumeratedValues>
                                <enumeratedValue>
                                    <name>0x00</name>
                                    <description>GTIOC0A</description>
                                    <value>0x00</value>
                                </enumeratedValue>
                                <enumeratedValue>
                                    <name>0x01</name>
                                    <description>GTIOC0B</description>
                                    <value>0x01</value>
                                </enumeratedValue>
                                <enumeratedValue>
                                    <name>0x02</name>
                                    <description>GTIOC1A</description>
                                    <value>0x02</value>
                                </enumeratedValue>
                                <enumeratedValue>
                                    <name>0x03</name>
                                    <description>GTIOC1B</description>
                                    <value>0x03</value>
                                </enumeratedValue>
                                <enumeratedValue>
                                    <name>0x04</name>
                                    <description>GTIOC2A</description>
                                    <value>0x04</value>
                                </enumeratedValue>
                                <enumeratedValue>
                                    <name>0x05</name>
                                    <description>GTIOC2B</description>
                                    <value>0x05</value>
                                </enumeratedValue>
                                <enumeratedValue>
                                    <name>0x06</name>
                                    <description>GTIOC3A</description>
                                    <value>0x06</value>
                                </enumeratedValue>
                                <enumeratedValue>
                                    <name>0x07</name>
                                    <description>GTIOC3B</description>
                                    <value>0x07</value>
                                </enumeratedValue>
                                <enumeratedValue>
                                    <name>0x08</name>
                                    <description>GTIOC4A</description>
                                    <value>0x08</value>
                                </enumeratedValue>
                                <enumeratedValue>
                                    <name>0x09</name>
                                    <description>GTIOC4B</description>
                                    <value>0x09</value>
                                </enumeratedValue>
                                <enumeratedValue>
                                    <name>0x0A</name>
                                    <description>GTIOC5A</description>
                                    <value>0x0a</value>
                                </enumeratedValue>
                                <enumeratedValue>
                                    <name>0x0B</name>
                                    <description>GTIOC5B</description>
                                    <value>0x0b</value>
                                </enumeratedValue>
                                <enumeratedValue>
                                    <name>0x0C</name>
                                    <description>GTIOC6A</description>
                                    <value>0x0c</value>
                                </enumeratedValue>
                                <enumeratedValue>
                                    <name>0x0D</name>
                                    <description>GTIOC6B</description>
                                    <value>0x0d</value>
                                </enumeratedValue>
                                <enumeratedValue>
                                    <name>0x0E</name>
                                    <description>GTIOC7A</description>
                                    <value>0x0e</value>
                                </enumeratedValue>
                                <enumeratedValue>
                                    <name>0x0F</name>
                                    <description>GTIOC7B</description>
                                    <value>0x0f</value>
                                </enumeratedValue>
                                <enumeratedValue>
                                    <name>0x10</name>
                                    <description>GTIOC8A</description>
                                    <value>0x10</value>
                                </enumeratedValue>
                                <enumeratedValue>
                                    <name>0x11</name>
                                    <description>GTIOC8B</description>
                                    <value>0x11</value>
                                </enumeratedValue>
                                <enumeratedValue>
                                    <name>0x12</name>
                                    <description>GTIOC9A</description>
                                    <value>0x12</value>
                                </enumeratedValue>
                                <enumeratedValue>
                                    <name>0x13</name>
                                    <description>GTIOC9B</description>
                                    <value>0x13</value>
                                </enumeratedValue>
                                <enumeratedValue>
                                    <name>Others</name>
                                    <description>Setting prohibited</description>
                                    <isDefault>true</isDefault>
                                </enumeratedValue>
                            </enumeratedValues>
                        </field>
                    </fields>
                </register>
                <register>
                    <name>GTPC</name>
                    <description>General PWM Timer Period Count Register</description>
                    <addressOffset>0xBC</addressOffset>
                    <size>32</size>
                    <access>read-write</access>
                    <resetValue>0x00000000</resetValue>
                    <resetMask>0xffffffff</resetMask>
                    <fields>
                        <field>
                            <name>PCEN</name>
                            <description>Period Count Function Enable</description>
                            <lsb>0</lsb>
                            <msb>0</msb>
                            <access>read-write</access>
                            <enumeratedValues>
                                <enumeratedValue>
                                    <name>0</name>
                                    <description>Period count function is disabled</description>
                                    <value>#0</value>
                                </enumeratedValue>
                                <enumeratedValue>
                                    <name>1</name>
                                    <description>Period count function is enabled</description>
                                    <value>#1</value>
                                </enumeratedValue>
                            </enumeratedValues>
                        </field>
                        <field>
                            <name>ASTP</name>
                            <description>Automatic Stop Function Enable</description>
                            <lsb>8</lsb>
                            <msb>8</msb>
                            <access>read-write</access>
                            <enumeratedValues>
                                <enumeratedValue>
                                    <name>0</name>
                                    <description>Automatic stop function is disabled</description>
                                    <value>#0</value>
                                </enumeratedValue>
                                <enumeratedValue>
                                    <name>1</name>
                                    <description>Automatic stop function is enabled</description>
                                    <value>#1</value>
                                </enumeratedValue>
                            </enumeratedValues>
                        </field>
                        <field>
                            <name>PCNT</name>
                            <description>Period Counter</description>
                            <lsb>16</lsb>
                            <msb>27</msb>
                            <access>read-write</access>
                        </field>
                    </fields>
                </register>
                <register>
                    <name>GTSECSR</name>
                    <description>General PWM Timer Operation Enable Bit Simultaneous Control Channel Select Register</description>
                    <addressOffset>0xD0</addressOffset>
                    <size>32</size>
                    <access>read-write</access>
                    <resetValue>0x00000000</resetValue>
                    <resetMask>0xffffffff</resetMask>
                    <fields>
                        <field>
                            <name>SECSEL0</name>
                            <description>Channel 0 Operation Enable Bit Simultaneous Control Channel Select</description>
                            <lsb>0</lsb>
                            <msb>0</msb>
                            <access>read-write</access>
                            <enumeratedValues>
                                <enumeratedValue>
                                    <name>0</name>
                                    <description>Disable simultaneous control</description>
                                    <value>#0</value>
                                </enumeratedValue>
                                <enumeratedValue>
                                    <name>1</name>
                                    <description>Enable simultaneous control</description>
                                    <value>#1</value>
                                </enumeratedValue>
                            </enumeratedValues>
                        </field>
                        <field>
                            <name>SECSEL1</name>
                            <description>Channel 1 Operation Enable Bit Simultaneous Control Channel Select</description>
                            <lsb>1</lsb>
                            <msb>1</msb>
                            <access>read-write</access>
                            <enumeratedValues>
                                <enumeratedValue>
                                    <name>0</name>
                                    <description>Disable simultaneous control</description>
                                    <value>#0</value>
                                </enumeratedValue>
                                <enumeratedValue>
                                    <name>1</name>
                                    <description>Enable simultaneous control</description>
                                    <value>#1</value>
                                </enumeratedValue>
                            </enumeratedValues>
                        </field>
                        <field>
                            <name>SECSEL2</name>
                            <description>Channel 2 Operation Enable Bit Simultaneous Control Channel Select</description>
                            <lsb>2</lsb>
                            <msb>2</msb>
                            <access>read-write</access>
                            <enumeratedValues>
                                <enumeratedValue>
                                    <name>0</name>
                                    <description>Disable simultaneous control</description>
                                    <value>#0</value>
                                </enumeratedValue>
                                <enumeratedValue>
                                    <name>1</name>
                                    <description>Enable simultaneous control</description>
                                    <value>#1</value>
                                </enumeratedValue>
                            </enumeratedValues>
                        </field>
                        <field>
                            <name>SECSEL3</name>
                            <description>Channel 3 Operation Enable Bit Simultaneous Control Channel Select</description>
                            <lsb>3</lsb>
                            <msb>3</msb>
                            <access>read-write</access>
                            <enumeratedValues>
                                <enumeratedValue>
                                    <name>0</name>
                                    <description>Disable simultaneous control</description>
                                    <value>#0</value>
                                </enumeratedValue>
                                <enumeratedValue>
                                    <name>1</name>
                                    <description>Enable simultaneous control</description>
                                    <value>#1</value>
                                </enumeratedValue>
                            </enumeratedValues>
                        </field>
                        <field>
                            <name>SECSEL4</name>
                            <description>Channel 4 Operation Enable Bit Simultaneous Control Channel Select</description>
                            <lsb>4</lsb>
                            <msb>4</msb>
                            <access>read-write</access>
                            <enumeratedValues>
                                <enumeratedValue>
                                    <name>0</name>
                                    <description>Disable simultaneous control</description>
                                    <value>#0</value>
                                </enumeratedValue>
                                <enumeratedValue>
                                    <name>1</name>
                                    <description>Enable simultaneous control</description>
                                    <value>#1</value>
                                </enumeratedValue>
                            </enumeratedValues>
                        </field>
                        <field>
                            <name>SECSEL5</name>
                            <description>Channel 5 Operation Enable Bit Simultaneous Control Channel Select</description>
                            <lsb>5</lsb>
                            <msb>5</msb>
                            <access>read-write</access>
                            <enumeratedValues>
                                <enumeratedValue>
                                    <name>0</name>
                                    <description>Disable simultaneous control</description>
                                    <value>#0</value>
                                </enumeratedValue>
                                <enumeratedValue>
                                    <name>1</name>
                                    <description>Enable simultaneous control</description>
                                    <value>#1</value>
                                </enumeratedValue>
                            </enumeratedValues>
                        </field>
                        <field>
                            <name>SECSEL10</name>
                            <description>Channel 10 Operation Enable Bit Simultaneous Control Channel Select</description>
                            <lsb>10</lsb>
                            <msb>10</msb>
                            <access>read-write</access>
                            <enumeratedValues>
                                <enumeratedValue>
                                    <name>0</name>
                                    <description>Disable simultaneous control</description>
                                    <value>#0</value>
                                </enumeratedValue>
                                <enumeratedValue>
                                    <name>1</name>
                                    <description>Enable simultaneous control</description>
                                    <value>#1</value>
                                </enumeratedValue>
                            </enumeratedValues>
                        </field>
                        <field>
                            <name>SECSEL11</name>
                            <description>Channel 11 Operation Enable Bit Simultaneous Control Channel Select</description>
                            <lsb>11</lsb>
                            <msb>11</msb>
                            <access>read-write</access>
                            <enumeratedValues>
                                <enumeratedValue>
                                    <name>0</name>
                                    <description>Disable simultaneous control</description>
                                    <value>#0</value>
                                </enumeratedValue>
                                <enumeratedValue>
                                    <name>1</name>
                                    <description>Enable simultaneous control</description>
                                    <value>#1</value>
                                </enumeratedValue>
                            </enumeratedValues>
                        </field>
                        <field>
                            <name>SECSEL12</name>
                            <description>Channel 12 Operation Enable Bit Simultaneous Control Channel Select</description>
                            <lsb>12</lsb>
                            <msb>12</msb>
                            <access>read-write</access>
                            <enumeratedValues>
                                <enumeratedValue>
                                    <name>0</name>
                                    <description>Disable simultaneous control</description>
                                    <value>#0</value>
                                </enumeratedValue>
                                <enumeratedValue>
                                    <name>1</name>
                                    <description>Enable simultaneous control</description>
                                    <value>#1</value>
                                </enumeratedValue>
                            </enumeratedValues>
                        </field>
                        <field>
                            <name>SECSEL13</name>
                            <description>Channel 13 Operation Enable Bit Simultaneous Control Channel Select</description>
                            <lsb>13</lsb>
                            <msb>13</msb>
                            <access>read-write</access>
                            <enumeratedValues>
                                <enumeratedValue>
                                    <name>0</name>
                                    <description>Disable simultaneous control</description>
                                    <value>#0</value>
                                </enumeratedValue>
                                <enumeratedValue>
                                    <name>1</name>
                                    <description>Enable simultaneous control</description>
                                    <value>#1</value>
                                </enumeratedValue>
                            </enumeratedValues>
                        </field>
                    </fields>
                </register>
                <register>
                    <name>GTSECR</name>
                    <description>General PWM Timer Operation Enable Bit Simultaneous Control Register</description>
                    <addressOffset>0xD4</addressOffset>
                    <size>32</size>
                    <access>read-write</access>
                    <resetValue>0x00000000</resetValue>
                    <resetMask>0xffffffff</resetMask>
                    <fields>
                        <field>
                            <name>SBDCE</name>
                            <description>GTCCR Register Buffer Operation Simultaneous Enable</description>
                            <lsb>0</lsb>
                            <msb>0</msb>
                            <access>read-write</access>
                            <enumeratedValues>
                                <enumeratedValue>
